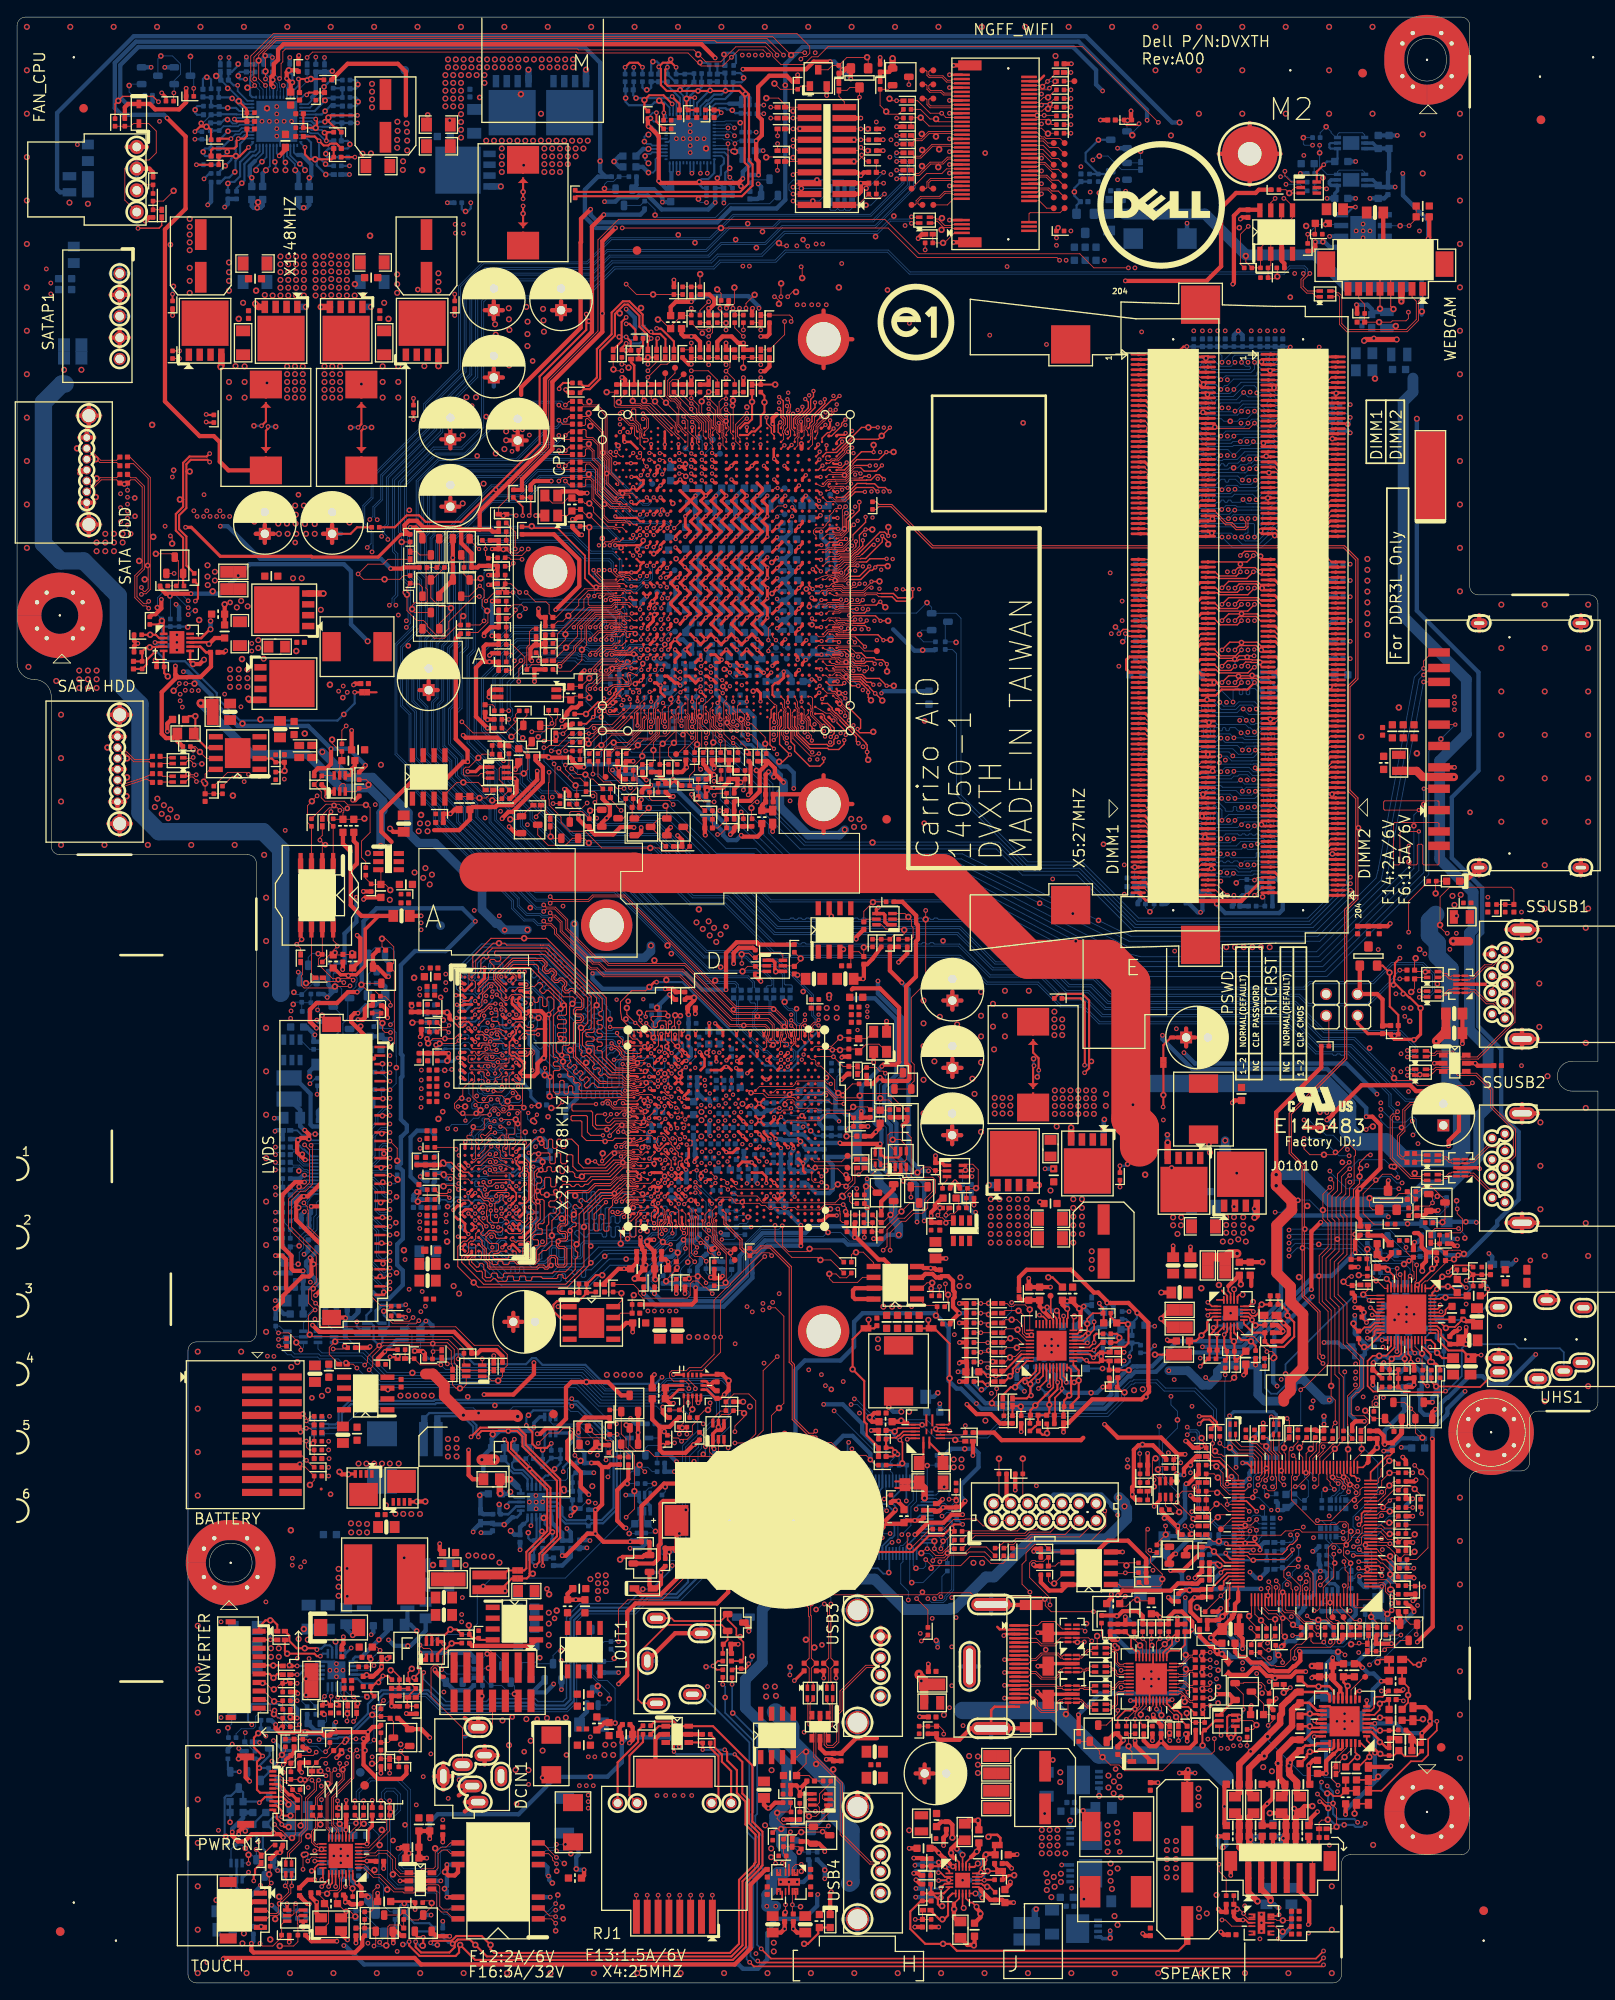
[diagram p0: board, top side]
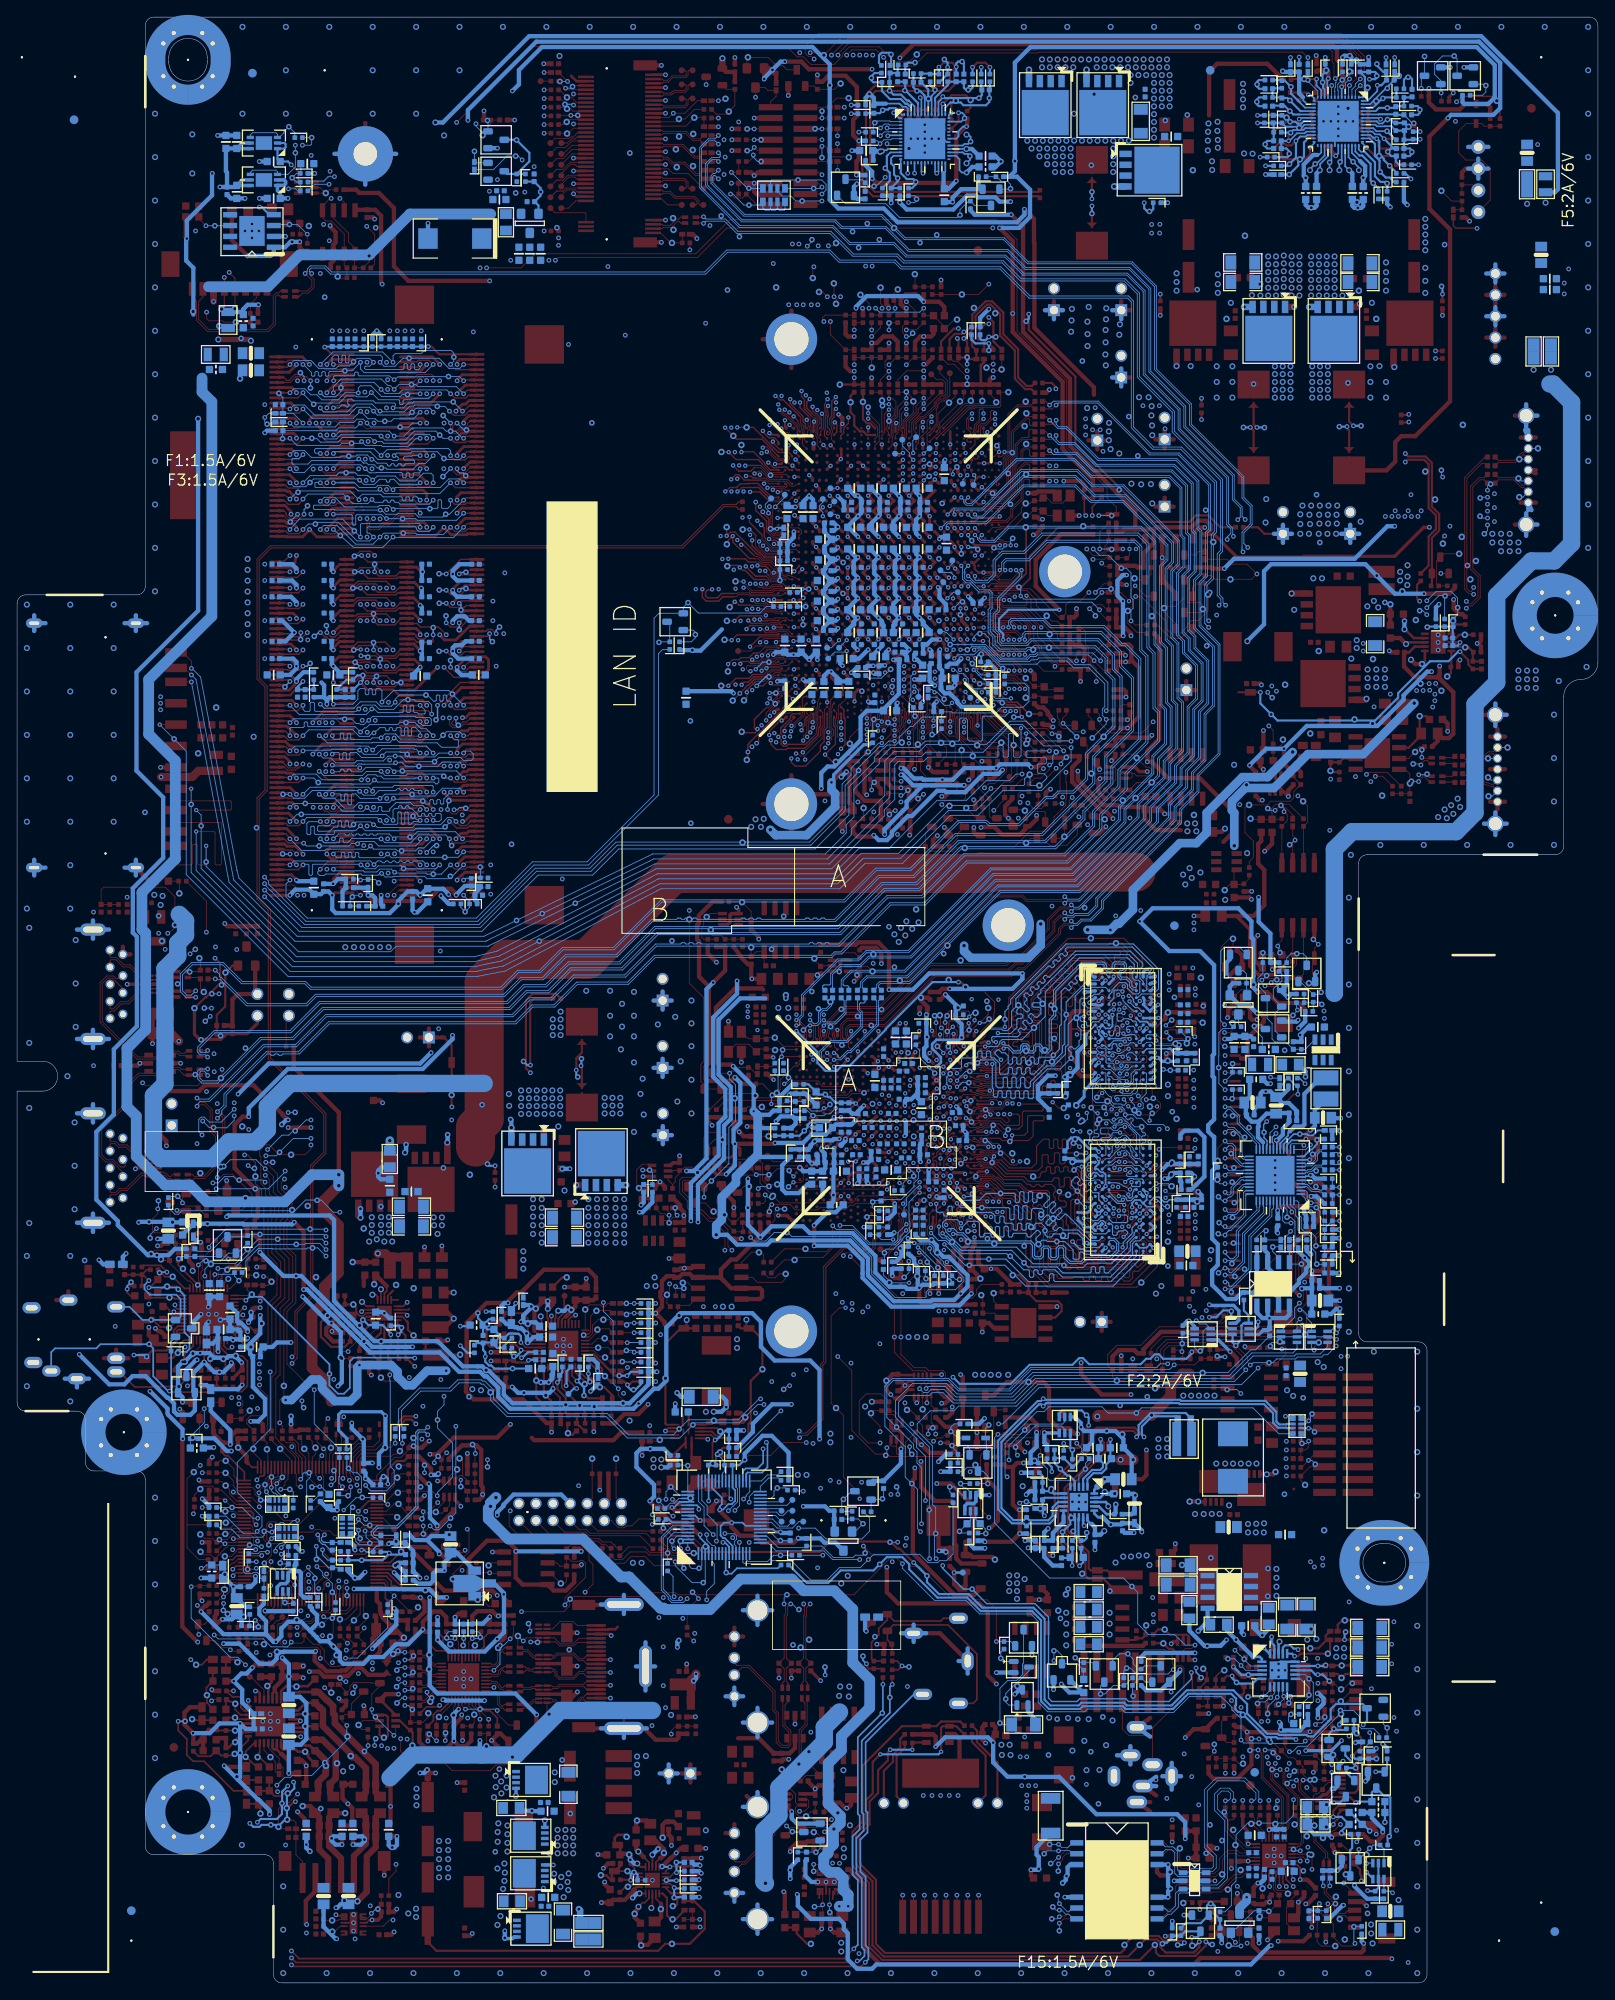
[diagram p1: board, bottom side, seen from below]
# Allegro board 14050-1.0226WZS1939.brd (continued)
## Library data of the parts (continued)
C78 C99 C150 C395 C562 C758-C761 C765-C770 C773 C775-C779 C782 C783 C785 C786 C793-C796 C798-C803 C805-C809 C813-C819 C823-C825 C827 C835 C1491 C1638 C1639 C1698 C1699 C1728 C1736 C1821 C1825 C1829 C1830 C1867 C1960 C4101 C4102 PC1 PC140 PC4803 PC4906 PC4909 PC4910 PC5009 PC5018 PC5204 PC5233 = C402H22: tolerance: 78.10523.5FLDL
C94 C1768 C1807 = C603H36: tolerance: 78.10422.2BL
C95 C105 C227 C315 C852 C1748 C1752 C1833 C1835 C1925 C1927 C6705 = C805H54: tolerance: 78.10623.51L
C104 C112 C144 C146 C154 C155 C283 C292 C296 C450 C592 C1770 C1771 C3367 C6706 PC5001 PC5011 PC5016 PC5247 PC5248 PC5430-PC5432 PC5434 = C805H50: tolerance: 78.10623.51LDL
C110 C192 C193 C208 C260 C1801 PC4602 PC5420 PC5435 = C603H36: tolerance: 78.10522.5BLDL
C126 PC126 = C402H22: tolerance: 78.22034.1FL
C130 = C402H22: tolerance: 78.10422.5FL
C190 PC17 PC18 PC49 PC58 PC4912 PC5012 PC5243 PC5246 PC5427-PC5429 = C603H36: tolerance: 78.10521.2BLDL
C198-C200 C210 = C603H36: tolerance: 78.27324.2BLDL
C222 C239 C243 C263 = C603H36: tolerance: 78.10324.2BL
C223 C224 C228 C229 C865 PC16 PC19 PC60 PC4704 PC4710 PC5411 = C603H36: tolerance: 78.22422.2BLDL
C225 C235 C247 C255 = C603H36: tolerance: 78.68421.5BL
C226 C236 C248 C256 C859 = C603H36: tolerance: 78.10234.1BLDL
C249 C857 C862 = C603H36: tolerance: 78.10424.2BL
C258 C545 C552 C597 PC20 PC51 PC62 PC4302 PC4402-PC4404 PC4703 PC4709 PC4713 PC4806 PC4903 PC4907 PC4908 PC5010 PC5019 PC5234 PC5236 PC5242 PC5403 = C603H35: tolerance: 78.10424.2BLDL
C262 PC9 PC14 = C402H22: tolerance: 78.10324.2FL
C291 C565 C772 C1824 = C805H54: tolerance: 78.22610.51LDL
C326 C330 C356 C1697 C1871 C1876 C1962 C1978 = C402H22: tolerance: 78.18134.1FLDL
C493 C509 C1953 C1956 C6703 = C603H38: tolerance: 78.10610.5BL
C521 C1796 C1797 = C603H36: tolerance: 78.10521.5BL
C524 PC4303 PC4611 PC4626 PC5417 = C402H22: tolerance: 78.22224.2FLDL
C525 C542 C1823 = C402H22: tolerance: 78.10491.4FL
C531 C589 C1756 = C402H22: tolerance: 78.10224.2FL
C548 = C402H22: tolerance: 78.22510.5FL
C752 = C402H22: tolerance: 78.47034.1FL
C753 C1726 C1846 C1958 PC34 PC48 PC5245 = C402H22: tolerance: 78.10423.2FL
C756 C757 C1800 = C402H22: tolerance: 78.12034.1FLDL
C762 = C402H22: tolerance: 78.12134.1FLDL
C812 C822 C1644-C1656 C1673 C1678-C1688 C1934-C1936 C1938 C1947-C1951 PC5205 PC5210-PC5212 = C603H40: tolerance: 78.22610.5BLDL
C836 C6707 C6723 C6725 = C402H20: tolerance: 78.10423.5FL
C839 = C402H22: tolerance: 78.68034.1FL
C872 C1755 = C402H22: tolerance: 78.68321.2FLDL
C1657-C1672 C1689-C1694 C1696 C1703 C1708 C1716 C1741 C1828 C1872-C1875 C1939-C1946 C1952 C1954 C1963-C1965 C1974 C6712 = C402H22: tolerance: 078.22423.05FD
C1700 C1831 = C402H22: tolerance: 78.10520.5FLDL
C1721 C1722 = C402H22: tolerance: 78.15124.2FL
C1773 C1774 = C402H22: tolerance: 78.10034.1FL
C1799 = C402H22: tolerance: 78.15034.1FLDL
C1847 = C402H22: tolerance: 078.82321.02FD
C1848 = C603H38: tolerance: 078.68421.05BD
C1849 = C402H22: tolerance: 78.82321.2FL
C1937 = C402H22: tolerance: 78.18134.1FL
C3131 = C1808H87: tolerance: 078.1013N.014D
C3455 PC4405 PC5217 PC5238 = C402H22: tolerance: 78.10422.5FLDL
C6718-C6720 = C603H36: tolerance: 78.10422.2BLDL
C6724 PC5423 PC5424 = C402H22: tolerance: 78.10322.2FLDL
C6726-C6729 = C402H22: tolerance: 78.4R774.1FLDL
CONVT1 = CI1410M1HRL-NH: tolerance: 20.F2266.010
CPU1 = BGA968M2937H74: tolerance: 071.FUSIN.000U
D1 D31 = SOD323AKH38: tolerance: 83.00355.D1F
D4 D24 = SOT-6H44: tolerance: 75.04223.07C
D7 D20 D34 = SOT23-2D4-312H44: tolerance: 75.00054.I7D
D16 = DO214AAAK-1121H97: tolerance: 83.P6SMB.KAG
D19 = SOT23-2D4-312H48: tolerance: 75.00099.F7D
D21 = SOD523AKH28: tolerance: 83.02015.0AF
D23 = SOT23-2D4-312H44: tolerance: 75.00054.T7D
D32 = D4724AKH44: tolerance: 83.3R010.C8M
D33 = SOD80CH36: tolerance: 83.R5003.C8F
DCIN1 = 2DC3115-000111F: tolerance: 022.10015.0311
DCIN2 = 88314-077N: tolerance: 20.F1498.007
DIMM1 = AS0A621-J4R6-7H-U: tolerance: 62.10024.S21
DIMM2 = AS0A626-J8R6-7H: tolerance: 62.10024.G01
F1 F3 F6 F13 F15 = POLYSW-2114H30: tolerance: 069.50001.0031
F2 F5 F12 F14 = POLYSW-2114H30: tolerance: 069.50003.0001
F16 = FUSE-1608H22: tolerance: 69.43001.441
FANC3 = HF1804H: tolerance: 021.D0086.0104
G5 PG4701-PG4704 PG5401 PG5402 = CON2C-U: tolerance: ZZ.CON2C.XXX
GPU1 = BGA631M23H82: tolerance: 71.SUNM2.M02
H1-H5 = HOLE237R158: tolerance: ZZ.0HOLE.011
H6 H9 = GEN8D5X8R5X4D5-8-F-A: tolerance: ZZ.00PAD.BV1
H7 H11 = GEN315R138-8-F-A-1: tolerance: ZZ.00PAD.BU1
H10 = GEN315R178-8-F-A-1: tolerance: ZZ.00PAD.BR1
HDD1 ODD1 = 15-02070-5A61-A: tolerance: 020.80244.0007
HDMI1 = SKT-HDMI22-150077: tolerance: 062.10012.0121
HDMI2 = LVDFH-02004-TP00: tolerance: 20.F2139.020
HDT1 = ASP-137098-05: tolerance: 20.F1722.020
HS6 = STF256R109H99: tolerance: 34.3NH01.001
L1 = L20125H42: tolerance: 68.00216.121
L2 = L3030-2709H41: tolerance: 68.2R21F.10E
L4 L5 L56 L57 L4102 L4103 = L125100-4P-1H36: tolerance: 68.12105.201
L10 L52 L53 = L603H38: tolerance: 68.00335.141
L15 = L402H22: tolerance: 68.00084.541
L16 L17 L19 = L603H38: tolerance: 68.00230.231
L20 L21 L47-L51 L54 L62 = L402H24: tolerance: 68.00213.031
L31-L34 = L20125H42: tolerance: 68.00216.111
L46 PR4814 PR4815 PR4927 PR4929-PR4933 PR5018-PR5021 PR5032 PR5290 R101 R183 R185 = 0R0805-PAD: tolerance: ZZ.R0805.ZZZ
L55 = L1608-UH38: tolerance: 68.00217.171
L60 = L603H38: tolerance: 68.00335.081
L61 = L8080-6522-1H166: tolerance: 068.33010.1041
L4101 = L402H22: tolerance: 68.00084.I21
LED2 LED3 = LED1608AKH30: tolerance: 83.01608.Q70
LOUT1 = JAC331-0140A8B-9H: tolerance: 22.10277.2M1
LPC1 = HL5507F: tolerance: 21.60964.207
LVDS1 = 50524-0300N-001: tolerance: 020.K0005.0030
MEM1-MEM4 = BGA96D075130H48: tolerance: 72.51G63.R0U
MEMCD1 = 156-5101902601: tolerance: 062.10002.0161
NGFF1 = 2199230-7: tolerance: 62.10043.K51
PC4 PC4911 PC4913 PC5203 = C402H22: tolerance: 78.22034.1FLDL
PC5 = C603H40: tolerance: 78.22422.2BL
PC8 = C402H22: tolerance: 78.33034.1FLDL
PC11 = C402H22: tolerance: 078.39124.02FD
PC13 PC56 PC4610 PC4613 PC4621 PC5415 = C402H22: tolerance: 78.33124.2FLDL
PC15 = C402H22: tolerance: 078.33322.02FD
PC24 PC61 PC63 PC64 PC4701 PC4702 PC4705 PC4707 PC4708 PC4711 PC4801 PC4808 PC4902 PC4904 PC5020-PC5022 PC5209 PC5214 PC5401 PC5402 PC5404 = C1206H71: tolerance: 78.10622.22LDL
PC50 PC52 = C805H58: tolerance: 78.10620.21LDL
PC59 = C603H36: tolerance: 78.10421.2BL
PC65 PC4915 PC4916 PC5017 PC5202 = C603H36: tolerance: 78.15224.2BLDL
PC68 = C402H22: tolerance: 78.27034.1FLDL
PC2127 PC4304 PC5237 = C402H22: tolerance: 78.47124.2FLDL
PC4408 = C805H58: tolerance: 078.10522.021D
PC4426 = C603H36: tolerance: 78.10522.5BL
PC4603 PC4624 PC5419 = C402H22: tolerance: 78.33224.2FLDL
PC4615 PC4617 PC5425 = C402H22: tolerance: 78.68124.2FLDL
PC4623 PC4628 PC5426 = C402H22: tolerance: 78.47321.2FLDL
PC4805 PC4917 PC4918 PC5013 = C402H22: tolerance: 78.18034.1FLDL
PC5014 = C603H36: tolerance: 78.33322.2BLDL
PC5239 = C402H22: tolerance: 78.22124.2FLDL
PC5421 = C603H36: tolerance: 78.22521.5BLDL
PC5422 = C402H22: tolerance: 78.10423.2FLDL
PD4401 = D1608-035030AKH28: tolerance: 83.1R003.N8F
PD4405 = SOD323AKH42: tolerance: 83.04148.D1H
PG3 PG4 = CON2C: tolerance: ZZ.CON2C.XX1
PG4801 PG4901-PG4908 PG5001 PG5211 PG5212 = GAP-CLOSE-PWR-3: tolerance: ZZ.CLOSE.001
PG5205 PG5210 = GAP-CLOSE-PWR: tolerance: ZZ.CON2d.XXX
PL1 PL4701 PL4702 PL5401 = L115100-2H158: tolerance: 68.R3610.10M
PL4301-PL4303 = L402H24: tolerance: 69.80007.021
PL4802 = L686647H119: tolerance: 68.1R51A.10F
PL4903 = L686647-127318H119: tolerance: 68.3R31A.10V
PL4904 PL5202 = L686647H119: tolerance: 68.2R21B.10J
PL5001 = L686647H119: tolerance: 68.R681A.10A
PL5003 = L7066-1830-UH119: tolerance: 68.5R610.10X
PQ4204 = SOT323CBE2D2H44: tolerance: 84.00124.H1K
PQ4205 = SOT323CBE2D2H44: tolerance: 84.00124.K1K
PQ4206 PQ4408 Q1229 = SOT23DGS2D4H44: tolerance: 84.2N702.J31
PQ4406 PQ5006 Q37 Q6701 Q9646 = SOT-363H44: tolerance: 84.2N702.A3F
PQ4409 = SOT23CBE2D4H44: tolerance: 84.T3906.A11
PQ5003 PQ5004 Q1 Q3 Q5 Q47 Q51 Q56 Q64 Q68 Q76 Q103-Q105 Q107 Q1212 Q1249 Q9648 Q9650 = SOT23DGS2D4H48: tolerance: 84.2N702.E31
PQ5005 = SOT-363H44: tolerance: 84.00512.03F
PR1 PR12 PR4455 PR4458 PR4462 PR4631 PR5247-PR5250 PR5261 PR5420 PR5422 PR5464 PR5466 PR5471 PR5476 PR8521 R14 R31 R77 R81 R110 R125 R131 R206 R354 R379 R413 R503 R618 R715 R716 R729 R1154 R1155 R1180 R1184 R1585 R1620-R1622 R1629 R1631 R1710 R1717 R1761 R1763 R1764 R1774 R1810 R1861 R1878 R1920 R1925 R1930 R1931 R1953 R1954 R1980 R1993-R1995 R1999 R2001 R2019 R2021 R2023 R2026 R2067 R2078 R2079 R4230 R6706 R79618 R79647-R79649 R79657 R79658 R79669 R79674 R79691 R79697-R79704 R79709-R79713 R79724 R79725 R80206-R80211 R80213 R80219 R80220 R80223 R80224 R80226 R80227 R80231 R80232 = R402H16: tolerance: 63.R0034.1DL
PR2 PR10 PR14 PR17 PR18 PR23 PR25 PR28-PR30 PR32 PR35 PR37 PR39 PR44 PR101 PR5274 PR5288 R744 R1160 = 0R0402-PAD: tolerance: ZZ.R0402.ZZZ
PR3 PR4 PR7 PR15 PR26 PR31 PR33 PR36 PR38 PR40 PR94 PR96 PR97 PR100 PR102-PR104 PR4210 PR5251 R93 R143 R178 R225 R287 R297 R312 R314 R366 R369 R370 R377 R380 R384 R406 R433 R510 R542 R545 R627 R635 R679 R777 R1179 R1584 R1586 R1604-R1610 R1614-R1616 R1618 R1619 R1628 R1630 R1632 R1650 R1664-R1666 R1704 R1720 R1729 R1730 R1732 R1837 R1863 R1864 R1894 R1917 R1998 R2000 R2002 R79692 R79693 = R402H16: tolerance: 63.10234.1DL
PR5 = R402H16: tolerance: 64.40215.6DL
PR6 = R402H16: tolerance: 64.19115.6DL
PR8 PR9 PR4412 R208 R210 R329 R1776 R1896 = R402H16: tolerance: 64.47025.6DL
PR11 PR24 PR4604 PR4606 PR4633 PR4642 R15 R22 R23 R35 R43 R51 R53 R56 R59 R60 R74 R99 R174 R205 R207 R222 R310 R372-R375 R383 R385 R399 R400 R502 R507 R515 R528 R529 R536 R568 R576 R638 R651 R666 R674 R707 R709 R723 R1165 R1166 R1199 R1203 R1209 R1611-R1613 R1647 R1653 R1654 R1668 R1697 R1698 R1709 R1711-R1714 R1718 R1719 R1739-R1741 R1744-R1748 R1762 R1842 R1857 R1858 R1901-R1904 R1912 R1916 R1981 R1984 R1985 R2017 R2053 R2054 R2080 R79633 R79634 R79639 R79640 R79686 R79708 R80225 = 0R0402-PAD-1: tolerance: ZZ.00PAD.M11
PR13 = R402H16: tolerance: 64.80615.6DL
PR16 = R402H16: tolerance: 64.12115.6DL
PR19 R511 = R402H16: tolerance: 64.12025.6DL
PR20 = R402H16: tolerance: 64.56205.6DL
PR21 = R402H16: tolerance: 64.18715.6DL
PR34 = R402H16: tolerance: 64.82R55.6DL
PR41 = R402H16: tolerance: 64.11025.6DL
PR42 = R402H16: tolerance: 64.26115.6DL
PR43 PR4701 PR4703 PR4812 PR5006 PR5404 PR5475 = R603H22: tolerance: 64.2R205.55L
PR45 = R603H22: tolerance: 64.36515.55L
PR47 PR95 = R402H16: tolerance: 64.1R005.6DL
PR51 = NTC-402H24-U: tolerance: 69.60013.131
PR57 PR62 PR77 PR4450 PR4603 PR4608 PR4615 PR4624 PR4632 PR4917 PR4922 PR5005 PR5206 PR5209 PR5223 PR5282 PR5286 PR5292 PR5295 PR5408 PR5419 PR5429 PR5463 R82 R266 R357 R397 R404 R644 R645 R650 R655 R658 R702 R1760 R1808 R1809 R1823 R1824 R1830 R1832 R1834 R1835 R1841 R79621 R79625 R79705 R79706 R79723 R80216 = R402H16: tolerance: 64.10025.6DL
PR60 = NTC-402H24-U: tolerance: 69.60013.141
PR78 = R402H16: tolerance: 64.69815.6DL
PR79 PR83 PR4612 PR4618 PR4685 PR5283 R5 R220 R284 R570 R571 R584 R585 R1202 R1686 R1735 = R402H14: tolerance: 64.10R05.6DL
PR98 R215 R300 R301 R344-R346 R356 R359 R367 R1182 R1193 R1601 = 0R0603-PAD-1-U: tolerance: ZZ.00PAD.M21
PR99 = R402H16: tolerance: 64.93115.6DL
PR114 PR4806 PR4902 PR4903 PR4911 PR4912 PR5034 PR5294 = R805H24: tolerance: 63.2R231.16L
PR190 PR225 PR4805 PR5431 R12 R41 R42 R124 R134 R137 R138 R152 R154 R159 R160 R163 R165 R175 R184 R213 R221 R281 R289 R294 R307 R308 R313 R316 R317 R334 R341 R350 R351 R364 R381 R382 R481-R483 R514 R517 R523 R524 R530 R531 R533 R582 R636 R637 R668 R675 R680 R682 R683 R717 R764 R774 R1167 R1178 R1183 R1185 R1186 R1188 R1194 R1634 R1635 R1659-R1663 R1670 R1672 R1674 R1679 R1683-R1685 R1687 R1688 R1700-R1703 R1705 R1707 R1716 R1724 R1725 R1728 R1731 R1733 R1734 R1736-R1738 R1749 R1753 R1754 R1757 R1759 R1783 R1785 R1819 R1825 R1826 R1829 R1840 R1845 R1849 R1868 R1870 R1872 R1875-R1877 R1880-R1882 R1885-R1887 R1915 R1926 R1932 R1933 R1935 R1986-R1988 R2010 R2012-R2014 R2055 R2056 R2061 R2062 R2064 R2077 R2091 R6702 R79635 R79637 R79638 R79650-R79654 R79659 R79663 R79664 R79670-R79673 R79676-R79681 R79687-R79690 R79694 R79714 R79727 R80212 R80217 R80218 R80221 R80222 R80230 R80233 = R402H16: tolerance: 63.10334.1DL
PR4214 = R1206H28: tolerance: 63.33232.11L
PR4413 R319 R79628 R79720 R79722 = R402H16: tolerance: 64.10035.6DL
PR4425 PR4426 PR8519 PR8520 = R402H16: tolerance: 63.33234.1DL
PR4427 PR4431 PR4901 PR5273 PR5275 PR5278 PR5281 PR5289 PR5297 R1 R26 R30 R33 R118 R119 R132 R144 R179 R181 R353 R360 R361 R501 R504 R512 R513 R657 R732 R733 R1074 R1079 R1164 R1780 R1781 R1852 R1874 R1914 R2018 R4702 R4706 R6703-R6705 R79662 R79665 R79668 = R402H16: tolerance: 63.10434.1DL
PR4433 R19 R172 R722 R1779 R1919 R79667 = R402H16: tolerance: 63.10534.1DL
PR4451 = R402H16: tolerance: 64.68035.6DL
PR4601 PR4616 PR4621 PR4636 PR4638 PR5413 PR5417 PR5424 R61 R78 R115 R120 R122 R557 R559 R586 R742 R1158 R1162 R1163 R1588 R1633 R1644 R1649 R1657 R1721 R1897 R1989 R2028 R2057-R2060 R2065 R2066 R79661 = R402H16: tolerance: 64.10015.6DL
PR4602 PR5418 = R402H16: tolerance: 64.2R005.6DL
PR4605 PR4629 PR5421 = R402H16: tolerance: 64.61925.6DL
PR4609 PR4614 PR4626 PR5411 = R402H16: tolerance: 64.27425.6DL
PR4610 = R402H16: tolerance: 64.54925.6DL
PR4611 PR4628 PR4643 PR5410 PR5416 = R402H14: tolerance: 63.10134.1DL
PR4613 PR4630 = NTC-402H22-U: tolerance: 69.60037.031
PR4619 PR4640 PR4802 PR5425 = R402H16: tolerance: 64.75025.6DL
PR4620 PR5426 R1126 = R402H16: tolerance: 64.16535.6DL
PR4622 PR4634 PR5407 = R402H16: tolerance: 64.49R95.6DL
PR4623 PR4645 PR5415 R76 = R402H16: tolerance: 64.82015.6DL
PR4625 = R402H16: tolerance: 64.41225.6DL
PR4627 = R402H16: tolerance: 64.28725.6DL
PR4635 PR5412 = R402H16: tolerance: 64.24025.6DL
PR4637 PR4639 PR5414 = NTC-402H22-U: tolerance: 69.60011.081
PR4641 PR5009 = R402H16: tolerance: 64.48725.6DL
PR4644 R79623 R79627 = R402H16: tolerance: 64.30035.6DL
PR4702 PR4704 PR5204 PR5401 = R1206H28: tolerance: 63.2R232.11L
PR4803 R1648 = R402H16: tolerance: 64.11825.6DL
PR4807 R20 R171 R1777 R1778 R1918 R79666 = R402H16: tolerance: 64.47035.6DL
PR4816 PR5268 = R402H16: tolerance: 64.33025.6DL
PR4914 = R402H16: tolerance: 64.66515.6DL
PR4918 PR5469 = R402H16: tolerance: 64.56225.6DL
PR4919 = R402H16: tolerance: 64.68025.6DL
PR4920 PR5468 = R402H16: tolerance: 64.11035.6DL
PR4921 R718 R762 R1658 R1690 R1691 R1727 R1817 R1853 R80215 = R402H16: tolerance: 64.15025.6DL
PR4924 = R402H16: tolerance: 64.24935.6DL
PR4925 = R402H16: tolerance: 64.19135.6DL
PR5002 = R402H16: tolerance: 64.5R105.6DL
PR5003 = R402H16: tolerance: 64.10525.6DL
PR5004 PR5291 PR5296 R276 = 0R0603-PAD: tolerance: ZZ.R0603.ZZZ
PR5007 = R402H16: tolerance: 64.62035.6DL
PR5023 = R402H16: tolerance: 64.40225.6DL
PR5201 R268 R1813 = R402H16: tolerance: 64.20025.6DL
PR5205 = R603H22: tolerance: 63.2R233.15L
PR5269 PR5276 = R3720H40: tolerance: 64.R0105.7FL
PR5270 = R402H16: tolerance: 64.30935.6DL
PR5272 = R402H16: tolerance: 64.49925.6DL
PR5277 = R402H16: tolerance: 64.7R505.6DL
PR5279 = R402H16: tolerance: 64.1R505.6DL
PR5284 = R805H24: tolerance: 64.20R05.16L
PR5285 = R402H16: tolerance: 63.47434.1DL
PR5287 = R402H16: tolerance: 63.33534.1DL
PR5293 = R402H16: tolerance: 64.88715.6DL
PR5298 = R402H16: tolerance: 64.12035.6DL
PR5402 = R402H16: tolerance: 64.34025.6DL
PR5409 = R402H16: tolerance: 64.39025.6DL
PR5423 = NTC-402H24-U: tolerance: 69.60028.041
PR5428 = R402H16: tolerance: 64.36025.6DL
PR5467 = R402H16: tolerance: 64.10235.6DL
PR5470 = R402H16: tolerance: 64.10735.6DL
PR5472 R1205 = R402H16: tolerance: 64.49915.6DL
PR5473 R689 = R402H16: tolerance: 64.64915.6DL
PT1 PT3 PT4 PT5007 = ECAP-100D6D3H355: tolerance: 09.8271N.A4L
PT2 = SE361416H237: tolerance: 79.47612.A0L
PT4701 PT4712 PT4901 PT5405 = SE361414H241: tolerance: 79.47612.3GL
PT4702-PT4704 PT4708 PT4709 PT4801 PT5401-PT5403 = ECAP-100D6D3H375: tolerance: 09.8271V.08L
PT4902 PT4903 = SE331721H237: tolerance: 79.22710.E0L
PU1 PU2 = PPAK-8P-5262H40: tolerance: 84.06552.037
PU3 PU5202 = PPAK-8P-5262H40: tolerance: 84.06508.037
PU4 = SOT23-2D8-312H58: tolerance: 74.02138.03B
PU5 = SOIC8-G3530H63: tolerance: 74.05337.031
PU7 = SOIC8-G3530H63: tolerance: 74.05912.03D
PU4403 PU4405 PU4902-PU4905 = PPAK-8P-3232H36: tolerance: 84.07410.A37
PU4601 PU5407 = LFCSP52J6-G4D8H40: tolerance: 074.81128.0073
PU4702 PU4802 PU5006 PU5207 PU5401 = PPAK-8P-5262H40: tolerance: 84.06520.037
PU4703-PU4706 PU4801 PU5007 PU5402 PU5403 = PPAK-8P-5262H40: tolerance: 084.06510.0037
PU4803 = DFN10G3-G265175H32: tolerance: 74.08237.B73
PU4901 = QFN20-G1D75H32: tolerance: 74.08243.073
PU5001 = QFN20-G1D75H32: tolerance: 74.08207.C73
PU5201 = QFN16J3H24: tolerance: 074.06220.0043
PU5204 PU5205 U110 = SOIC8H69: tolerance: 84.04407.G37
PU5206 = SOIC8-G3530H63: tolerance: 74.05930.B3D
PWRCN1 = 51530-01041-W01: tolerance: 20.K0642.010
Q4 Q7 Q18 Q65 Q95 Q97 Q123 Q1217 Q1226 Q4701 Q6702 = SOT-363H44: tolerance: 75.27002.F7C
Q10 Q22 Q31 Q38 Q45 Q48 Q52 Q100-Q102 Q128 Q1207 Q1208 Q1213 Q1214 Q1241 = SOT23CBE2D4H44: tolerance: 84.T3904.C11
Q12 Q13 Q36 Q63 Q6705 = SOT-363H44: tolerance: 84.M3904.B1F
Q14 = SOT23DGS2D4H35: tolerance: 84.3K329.031
Q24 Q46 Q57 = SOT23-2D4-312H46: tolerance: 75.05125.07D
Q28 Q1209 Q1240 Q1243-Q1245 Q1247 Q1248 = SOT23DGS2D4H44: tolerance: 84.27002.W31
Q43 U2 U6702 = SOIC8H69: tolerance: 84.04468.A37
Q44 Q77 Q1210 Q1211 Q9647 Q9649 = SOT23DGS2D8H50: tolerance: 84.03413.B31
Q50 = SOT-23-10H44: tolerance: 84.03904.L06
Q78 Q79 Q1227 Q1246 = SOT23DGS2D4H44: tolerance: 84.27002.Z31
Q1250 = SOIC8H69: tolerance: 084.04286.0037
Q6703 Q6704 = DFN6F2030-G1619H26: tolerance: 075.02016.007C
R8 = R603H22: tolerance: 63.33133.15L
R10 R378 R775 R1129 R80228 = R402H16: tolerance: 63.82234.1DL
R13 R776 R1195 R80229 = R402H16: tolerance: 64.39225.6DL
R24 R216 R305 R1595 R1784 R2022 R2025 R2029-R2032 R6701 R79655 R79707 = R603H22: tolerance: 63.00000.00L
R27 R79622 = R1206H26: tolerance: 64.R3305.41L
R32 R46 R47 R54 R57 R58 R69 R80 R133 R135 R139 R508 R526 R527 R535 R634 R731 R755 R1699 R1752 R1758 R1782 R1831 R1844 R1860 R1883 R80201 R80202 = R402H16: tolerance: 63.47234.1DL
R37 R79631 = 0R1206-PAD-1: tolerance: ZZ.R1206.ZZ1
R39 R123 R1645 R1646 R1934 = R402H16: tolerance: 63.22034.1DL
R45 R68 R111 R371 R484 R1888 R1889 = R402H14: tolerance: 64.10005.6DL
R65 R1708 R79643-R79646 R79656 = R805H24: tolerance: 63.R0031.16L
R71 R162 R223 R261 R262 R272 R391 R1204 R1669 R1673 R1675 R1676 R1843 R2083 R2084 = R402H16: tolerance: 63.22234.1DL
R73 R368 R639 R643 R656 = R402H16: tolerance: 63.20334.1DL
R107 = R402H16: tolerance: 64.15005.6DL
R113 R322 R407 R1879 = R603H22: tolerance: 64.10045.55L
R121 R1696 = R402H16: tolerance: 64.39R25.6DL
R202 R203 R230 R885 R886 R924 R928 R945 R946 R1905 R1910 R1911 R1921-R1924 = R402H16: tolerance: 64.21015.6DL
R209 R306 R309 R352 R743 R758 R1168-R1171 R1678 R1743 R1755 R1756 R1851 R1884 R79682-R79685 = R402H16: tolerance: 63.33034.1DL
R212 = R402H16: tolerance: 64.68R05.6DL
R267 = R402H16: tolerance: 64.51015.6DL
R299 R320 R870 R899 = R402H16: tolerance: 64.24305.6DL
R302 = R402H16: tolerance: 64.51115.6DL
R347 = R402H16: tolerance: 64.39015.6DL
R355 R365 = R603H22: tolerance: 64.10525.55L
R358 = R402H16: tolerance: 64.56015.6DL
R376 = R603H22: tolerance: 63.10033.15L
R388 R943 R1900 = R402H16: tolerance: 64.84515.6DL
R389 R79726 = R805H24: tolerance: 64.10025.16L
R394 R940 R1603 R1816 = R402H16: tolerance: 64.20015.6DL
R396 R403 R415 R419 = R603H22: tolerance: 64.3R305.55L
R398 R963 R1159 R1892 R1893 R1895 = R402H15: tolerance: 63.10334.L0L
R412 = R402H16: tolerance: 64.24915.6DL
R428 R429 R1891 = R402H16: tolerance: 63.47034.1DL
R495 R1617 R1623 = R402H16: tolerance: 63.30134.1DL
R558 R1161 = R402H16: tolerance: 64.16915.6DL
R617 R79721 = R402H16: tolerance: 63.33334.1DL
R724 R730 R735 R1751 = R603H22: tolerance: 64.16505.55L
R935 = R402H16: tolerance: 64.45315.6DL
R948 R1899 = R402H16: tolerance: 64.47515.6DL
R1200 R1890 R1906-R1909 = R402H16: tolerance: 64.40R25.6DL
R1201 = R402H16: tolerance: 64.12005.6DL
R1206 R1207 = R402H16: tolerance: 64.51R15.6DL
R1210 = R402H16: tolerance: 64.24905.6DL
R1211 = R402H16: tolerance: 64.49905.6DL
R1592 = R603H22: tolerance: 64.36R05.55L
R1593 R1594 R1596 R1598 R2085-R2090 = R402H16: tolerance: 64.47015.6DL
R1671 = R603H22: tolerance: 63.20634.15L
R1677 = R402H16: tolerance: 63.47334.1DL
R1767 R1846 = R603H22: tolerance: 63.15234.15L
R1833 R1838 = R402H16: tolerance: 64.17825.6DL
R1847 = R603H22: tolerance: 64.10035.L0L
R1848 = R603H22: tolerance: 63.10333.15L
R1850 = R603H22: tolerance: 64.56025.55L
R1867 R1869 R1871 R1873 R2004 R2008 R2063 = R402H16: tolerance: 63.20234.1DL
R2003 = R402H16: tolerance: 64.19605.6DL
R2081 = R603H22: tolerance: 64.18005.55L
R2082 = R402H16: tolerance: 64.43015.6DL
R4707 R4708 = R402H16: tolerance: 64.11015.6DL
R79612 = R603H22: tolerance: 64.75R05.55L
R79619 = R805H24: tolerance: 63.1R031.16L
R79630 = R805H24: tolerance: 63.20131.16L
R79675 = R402H16: tolerance: 063.10434.01DV
RJ1 = 23-01120-2A03-A: tolerance: 062.10032.0041
RN7 RN10 = ARES8-CN24-MUH20: tolerance: 66.10336.08L
RN8 RN9 = ARES2H18: tolerance: 66.10336.04L
RN12 = SMD-ARES8-1H26: tolerance: 66.10236.A8L
RN13 RN4301 = ARES8-CN24-UH20: tolerance: 66.33036.A8L
RN16 = ARES2H16: tolerance: 66.22236.04L
RT1-RT3 = NTC-402H22-U: tolerance: 69.60011.121
RV1 = TVS5436-1121H105: tolerance: 069.A0007.0001
SATAP1 = CI2505P1H00-LF-U: tolerance: 021.60197.0105
SPI1 = SOIC8-1H86: tolerance: 72.25640.D01
SPK1 = A1501WV0-6PS-5E: tolerance: 21.D0278.106
SPR1 = SPR10637H367: tolerance: 34.39S07.003
SRCON1 = SKT-SOIC8-092117H235: tolerance: 62.10089.001
SSUSB1 SSUSB2 = SKT-USB11-138165-1: tolerance: 022.10005.0391
TC1 = CT7343H75: tolerance: 77.23371.13L
TC7 TC8 = ECAP-100D6D3H237: tolerance: 09.1071D.A5L
TC21 = ECAP-100D6D3H355: tolerance: 09.8271N.A5L
TOUCH1 = 3703K-Q05N-11L: tolerance: 020.F0146.0005
TP6 TP8 TP9 TP24-TP26 TP28 TP37-TP39 TP62-TP84 TP149 TP150 TP155 TP158 TP159 TP163-TP165 TP174-TP184 TP186-TP190 TP192-TP196 TP198 TP199 TP203 TP204 TP208 TP210-TP215 TP4124-TP4130 = TPAD28: tolerance: ZZ.PAD28.XXX
TR1 TR3 TR4 TR10 TR14 = L125100-4P-1H28: tolerance: 68.01012.20B
TR9 TR12 = L125100-4P-1H37: tolerance: 68.01012.201
TR16-TR19 = L125100-4P-1H28: tolerance: 68.10129.201
U1 U42 U105 = SOT-6-1H50: tolerance: 84.06402.B3D
U3 U5 U31 U116 U117 = DFN10G2510H26: tolerance: 75.01045.073
U6 = QFN48J6-G465H40: tolerance: 71.03661.003
U7 = SOIC8H69: tolerance: 72.25106.001
U9 = QFN40-G3D5H32: tolerance: 74.62882.A73
U10-U12 = SOT-6H58: tolerance: 75.09904.07C
U16 = QFN32J4-G2D85H36: tolerance: 71.08111.U03
U21 = QFN32-G3D55H40: tolerance: 74.03131.013
U25 = SOIC8H69: tolerance: 72.24C64.R01
U26 = QFN48J6-G4D55H40: tolerance: 71.02136.003
U49 = SOIC8H69: tolerance: 72.25010.R01
U52 U54 = SON14J3020-G2610H34: tolerance: 74.22966.093
U55 = QFN20G3D5-G2D15H40: tolerance: 74.24727.A73
U109 = LQFP128H63: tolerance: 071.08739.000G
U118 = QFN40J5-G3D65H32: tolerance: 071.08407.0003
U119 = SOT-89-4541-3PH63: tolerance: 074.01117.0038
U120 = QFN20-G2D1H32: tolerance: 074.00554.0073
U178 = SOIC8H69: tolerance: 074.03702.0021
U4101 = LQFP64H63: tolerance: 071.00948.000G
U6701 = LGA16G3-1H40: tolerance: 074.01010.00B3
UHS1 = 2SJ3082-038111F: tolerance: 022.10002.0881
UR5-UR7 = R402H16: tolerance: 64.33005.6DL
USB3 USB4 = SKT-USB6-135063: tolerance: 022.10005.01E1
WEBCM1 = A1251WR0-8PS-5E: tolerance: 20.F1245.008
X1 = OSC-3225-4P-4H36: tolerance: 82.30026.281
X2 = SMD49-6914-0403H56: tolerance: 82.30001.G11
X4 = OSC-3225-4P-4H36: tolerance: 82.30020.G71
X5 = OSC-3225-4P-4H30: tolerance: 82.30034.641
XF1 XF2 = XFORM12A127097H91: tolerance: 68.68167.30D

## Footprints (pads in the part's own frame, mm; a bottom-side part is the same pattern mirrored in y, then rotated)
0R0402-PAD
  custom 0.14x0.14 smd: 1(0,0.445) 2(0,-0.445)
0R0402-PAD-1
  custom 0.14x0.14 smd: 1(0,0.445) 2(0,-0.445)
0R0603-PAD
  custom 0.216x0.216 smd: 1(0,0.851) 2(0,-0.673)
0R0603-PAD-1-U
  custom 0.216x0.216 smd: 1(0,0.762) 2(0,-0.762)
0R0805-PAD
  rect 1.397x1.562 smd: 1(0,0.965)
  rect 1.397x1.569 smd: 2(0,-0.965)
0R1206-PAD-1
  rect 1.651x2.057 smd: 1(0,1.397) 2(0,-1.397)
2DC3115-000111F
  oval 1.422x2.413 hole 0.711x1.702: 1(-1.1,1.46)
  oval 1.473x2.413 hole 0.762x1.702: 2(2.5,0) 5(4.375,0.7) 7(-4.375,0.7)
  oval 1.524x2.413 hole 0.813x1.702: 3(0,-1.13)
  oval 2.413x1.473 hole 1.702x0.762: 4(1.35,3.375) 6(1.35,-3.375)
2SJ3082-038111F
  round 0.254 hole 1.27 unplated: (0,0) (0,-6)
  oval 1.321x2.134 hole 0.61x1.422: 1(3.8,3.1) 2(-3.7,-4.5) 3(3.7,-6.8) 4(-2.7,-6.6) 5(-2.2,3.1) 6(-3.8,3.1) MS1(-4.6,-1.5) MS2(4.6,-2.5)
15-02070-5A61-A
  round 1.041 hole 0.762: 1(3.81,-0.25) 2(2.54,-0.25) 3(1.27,-0.25) 4(0,-0.25) 5(-1.27,-0.25) 6(-2.54,-0.25) 7(-3.81,-0.25)
  round 1.93 hole 1.524: 8(6.37,0) 9(-6.37,0)
23-01120-2A03-A
  rect 0.813x3.988 smd: 1(-4.445,13.3) 2(-3.175,13.3) 3(-1.905,13.3) 4(-0.635,13.3) 5(0.635,13.3) 6(1.905,13.3) 7(3.175,13.3) 8(4.445,13.3)
  round 1.321 hole 0.914: 9(-6.645,0) 10(-4.355,0) 11(4.355,0) 12(6.645,0)
  rect 8.992x3.404 smd: 13(0,-3.5)
156-5101902601
  round 0.254 hole 1.702 unplated: (-12.65,0) (12.65,0)
  rect 0.991x2.54 smd: 1(-7.57,8.245) 2(-5.07,8.245) 3(-2.57,8.245) 4(-0.07,8.245) 5(2.43,8.245) 6(4.93,8.245) 7(7.43,8.245) 8(9.055,8.245) 9(-10.07,8.245) 10(10.875,8.245) 11(-11.755,8.245)
  oval 1.118x1.93 hole 0.406x1.219: 12(-14.3,3.55) 13(14.3,3.55) 14(-14.3,-8.35) 15(14.3,-8.35)
3703K-Q05N-11L
  rect 0.61x1.549 smd: 1(-2,3.775) 2(-1,3.775) 3(0,3.775) 4(1,3.775) 5(2,3.775)
  rect 1.194x2.007 smd: 6(-3.3,0) 7(3.3,0)
50290-0100N-001
  rect 0.838x3.556 smd: 1A(-6.75,-3.9) 2A(-5.25,-3.9) 3A(-3.75,-3.9) 4A(-2.25,-3.9) 5A(-0.75,-3.9) 6A(0.75,-3.9) 7A(2.25,-3.9) 8A(3.75,-3.9) 9A(5.25,-3.9) 10A(6.75,-3.9)
  rect 0.838x2.642 smd: 1B(-6.75,0) 2B(-5.25,0) 3B(-3.75,0) 4B(-2.25,0) 5B(-0.75,0) 6B(0.75,0) 7B(2.25,0) 8B(3.75,0) 9B(5.25,0) 10B(6.75,0)
50524-0300N-001
  rect 0.305x1.295 smd: 1(-14.5,5.65) 2(-13.5,5.65) 3(-12.5,5.65) 4(-11.5,5.65) 5(-10.5,5.65) 6(-9.5,5.65) 7(-8.5,5.65) 8(-7.5,5.65) 9(-6.5,5.65) 10(-5.5,5.65) 11(-4.5,5.65) 12(-3.5,5.65) 13(-2.5,5.65) 14(-1.5,5.65) 15(-0.5,5.65) 16(0.5,5.65) 17(1.5,5.65) 18(2.5,5.65) 19(3.5,5.65) 20(4.5,5.65) 21(5.5,5.65) 22(6.5,5.65) 23(7.5,5.65) 24(8.5,5.65) 25(9.5,5.65) 26(10.5,5.65) 27(11.5,5.65) 28(12.5,5.65) 29(13.5,5.65) 30(14.5,5.65)
  rect 1.803x2.21 smd: 31(-17.15,0) 32(17.15,0)
51530-01041-W01
  rect 0.305x0.838 smd: 1(-2.25,3.175) 2(-1.75,3.175) 3(-1.25,3.175) 4(-0.75,3.175) 5(-0.25,3.175) 6(0.25,3.175) 7(0.75,3.175) 8(1.25,3.175) 9(1.75,3.175) 10(2.25,3.175)
  rect 0.813x2.007 smd: 11(-3.95,0) 12(3.95,0)
88314-077N
  rect 0.838x3.556 smd: 1(-4.5,-3.225) 2(-3,-3.225) 3(-1.5,-3.225) 4(0,-3.225) 5(1.5,-3.225) 6(3,-3.225) 7(4.5,-3.225)
  rect 0.838x2.642 smd: 8(-4.5,0.675) 9(-3,0.675) 10(-1.5,0.675) 11(0,0.675) 12(1.5,0.675) 13(3,0.675) 14(4.5,0.675)
2199230-7
  round 0.254 hole 1.6 unplated: (-10,0)
  round 0.254 hole 1.118 unplated: (10,0)
  rect 0.305x1.854 smd: 1(9.25,-5.423) 2(9,2.423) 3(8.75,-5.423) 4(8.5,2.423) 5(8.25,-5.423) 6(8,2.423) 7(7.75,-5.423) 16(5.5,2.423) 17(5.25,-5.423) 18(5,2.423) 19(4.75,-5.423) 20(4.5,2.423) 21(4.25,-5.423) 22(4,2.423) 23(3.75,-5.423) 24(3.5,2.423) 25(3.25,-5.423) 26(3,2.423) 27(2.75,-5.423) 28(2.5,2.423) 29(2.25,-5.423) 30(2,2.423) 31(1.75,-5.423) 32(1.5,2.423) 33(1.25,-5.423) 34(1,2.423) 35(0.75,-5.423) 36(0.5,2.423) 37(0.25,-5.423) 38(0,2.423) 39(-0.25,-5.423) 40(-0.5,2.423) 41(-0.75,-5.423) 42(-1,2.423) 43(-1.25,-5.423) 44(-1.5,2.423) 45(-1.75,-5.423) 46(-2,2.423) 47(-2.25,-5.423) 48(-2.5,2.423) 49(-2.75,-5.423) 50(-3,2.423) 51(-3.25,-5.423) 52(-3.5,2.423) 53(-3.75,-5.423) 54(-4,2.423) 55(-4.25,-5.423) 56(-4.5,2.423) 57(-4.75,-5.423) 58(-5,2.423) 59(-5.25,-5.423) 60(-5.5,2.423) 61(-5.75,-5.423) 62(-6,2.423) 63(-6.25,-5.423) 64(-6.5,2.423) 65(-6.75,-5.423) 66(-7,2.423) 67(-7.25,-5.423) 68(-7.5,2.423) 69(-7.75,-5.423) 70(-8,2.423) 71(-8.25,-5.423) 72(-8.5,2.423) 73(-8.75,-5.423) 74(-9,2.423) 75(-9.25,-5.423)
  rect 1.194x2.743 smd: 76(10.35,-4.5) 77(-10.35,-4.5)
A1251WR0-8PS-5E
  rect 0.813x1.6 smd: 1(-4.375,2.9) 2(-3.125,2.9) 3(-1.875,2.9) 4(-0.625,2.9) 5(0.625,2.9) 6(1.875,2.9) 7(3.125,2.9) 8(4.375,2.9)
  rect 2.108x2.997 smd: 9(-6.925,0) 10(6.925,0)
A1501WV0-6PS-5E
  rect 0.711x3.505 smd: 1(3.75,2) 2(2.25,2) 3(0.75,2) 4(-0.75,2) 5(-2.25,2) 6(-3.75,2)
  rect 1.499x2.311 smd: 7(5.8,0) 8(-5.8,0)
A2541WV0-1EX2PA-6T
  round 1.397 hole 0.991: 1(-1.27,0) 2(1.27,0)
AAA-BAT-034-K01
  round 0.254 hole 1.067 unplated: (-7.5,0)
  round 0.254 hole 1.372 unplated: (0,0)
  rect 2.794x3.607 smd: 1(6.2,0)
  rect 2.997x2.591 smd: 2(-15.1,0)
AFTE14P-75
  round 0.356 smd: 1(0,0)
ARES2H16
  rect 0.356x0.66 smd: 1(-0.325,-0.599) 2(0.325,-0.599) 3(0.325,0.599) 4(-0.325,0.599)
ARES2H18
  rect 0.356x0.66 smd: 1(-0.325,-0.599) 2(0.325,-0.599) 3(0.325,0.599) 4(-0.325,0.599)
ARES8-CN24-MUH20
  rect 0.61x0.66 smd: 1(-0.9,-0.486) 4(0.9,-0.486) 5(0.9,0.486) 8(-0.9,0.486)
  rect 0.305x0.66 smd: 2(-0.25,-0.486) 3(0.25,-0.486) 6(0.25,0.486) 7(-0.25,0.486)
ARES8-CN24-UH20
  rect 0.61x0.66 smd: 1(-0.9,-0.486) 4(0.9,-0.486) 5(0.9,0.486) 8(-0.9,0.486)
  rect 0.305x0.66 smd: 2(-0.25,-0.486) 3(0.25,-0.486) 6(0.25,0.486) 7(-0.25,0.486)
AS0A621-J4R6-7H-U
  round 0.254 hole 1.118 unplated: (-33.4,0)
  round 0.254 hole 1.6 unplated: (33.4,0)
  custom 0.114x0.114 smd: 1(31.65,4.1) 2(31.35,-4.1) 3(31.05,4.1) 4(30.751,-4.1) 5(30.45,4.1) 6(30.15,-4.1) 7(29.85,4.1) 8(29.55,-4.1) 9(29.251,4.1) 10(28.95,-4.1) 11(28.65,4.1) 12(28.35,-4.1) 13(28.051,4.1) 14(27.751,-4.1) 15(27.45,4.1) 16(27.15,-4.1) 17(26.851,4.1) 18(26.551,-4.1) 19(26.25,4.1) 20(25.95,-4.1) 21(25.65,4.1) 22(25.35,-4.1) 23(25.051,4.1) 24(24.75,-4.1) 25(24.45,4.1) 26(24.15,-4.1) 27(23.851,4.1) 28(23.55,-4.1) 29(23.25,4.1) 30(22.95,-4.1) 31(22.651,4.1) 32(22.351,-4.1) 33(22.05,4.1) 34(21.75,-4.1) 35(21.451,4.1) 36(21.151,-4.1) 37(20.85,4.1) 38(20.55,-4.1) 39(20.25,4.1) 40(19.95,-4.1) 41(19.65,4.1) 42(19.35,-4.1) 43(19.049,4.1) 44(18.749,-4.1) 45(18.45,4.1) 46(18.15,-4.1) 47(17.85,4.1) 48(17.549,-4.1) 49(17.25,4.1) 50(16.95,-4.1) 51(16.65,4.1) 52(16.349,-4.1) 53(16.049,4.1) 54(15.75,-4.1) 55(15.45,4.1) 56(15.15,-4.1) 57(14.849,4.1) 58(14.549,-4.1) 59(14.25,4.1) 60(13.95,-4.1) 61(13.649,4.1) 62(13.349,-4.1) 63(13.05,4.1) 64(12.75,-4.1) 65(12.45,4.1) 66(12.149,-4.1) 67(11.85,4.1) 68(11.55,-4.1) 69(11.25,4.1) 70(10.95,-4.1) 71(10.649,4.1) 72(10.349,-4.1) 73(7.65,4.1) 74(7.35,-4.1) 75(7.049,4.1) 76(6.749,-4.1) 77(6.45,4.1) 78(6.15,-4.1) 79(5.85,4.1) 80(5.549,-4.1) 81(5.25,4.1) 82(4.95,-4.1) 83(4.65,4.1) 84(4.349,-4.1) 85(4.05,4.1) 86(3.75,-4.1) 87(3.45,4.1) 88(3.15,-4.1) 89(2.849,4.1) 90(2.549,-4.1) 91(2.25,4.1) 92(1.95,-4.1) 93(1.649,4.1) 94(1.349,-4.1) 95(1.05,4.1) 96(0.75,-4.1) 97(0.45,4.1) 98(0.149,-4.1) 99(-0.15,4.1) 100(-0.45,-4.1) 101(-0.75,4.1) 102(-1.051,-4.1) 103(-1.351,4.1) 104(-1.65,-4.1) 105(-1.95,4.1) 106(-2.25,-4.1) 107(-2.551,4.1) 108(-2.851,-4.1) 109(-3.15,4.1) 110(-3.45,-4.1) 111(-3.751,4.1) 112(-4.051,-4.1) 113(-4.35,4.1) 114(-4.65,-4.1) 115(-4.95,4.1) 116(-5.251,-4.1) 117(-5.55,4.1) 118(-5.85,-4.1) 119(-6.15,4.1) 120(-6.451,-4.1) 121(-6.751,4.1) 122(-7.051,-4.1) 123(-7.35,4.1) 124(-7.65,-4.1) 125(-7.951,4.1) 126(-8.251,-4.1) 127(-8.55,4.1) 128(-8.85,-4.1) 129(-9.15,4.1) 130(-9.451,-4.1) 131(-9.75,4.1) 132(-10.05,-4.1) 133(-10.35,4.1) 134(-10.651,-4.1) 135(-10.95,4.1) 136(-11.25,-4.1) 137(-11.55,4.1) 138(-11.85,-4.1) 139(-12.151,4.1) 140(-12.451,-4.1) 141(-12.75,4.1) 142(-13.05,-4.1) 143(-13.351,4.1) 144(-13.651,-4.1) 145(-13.95,4.1) 146(-14.25,-4.1) 147(-14.55,4.1) 148(-14.851,-4.1) 149(-15.15,4.1) 150(-15.45,-4.1) 151(-15.75,4.1) 152(-16.051,-4.1) 153(-16.35,4.1) 154(-16.65,-4.1) 155(-16.95,4.1) 156(-17.25,-4.1) 157(-17.551,4.1) 158(-17.851,-4.1) 159(-18.15,4.1) 160(-18.45,-4.1) 161(-18.751,4.1) 162(-19.051,-4.1) 163(-19.35,4.1) 164(-19.65,-4.1) 165(-19.95,4.1) 166(-20.251,-4.1) 167(-20.55,4.1) 168(-20.85,-4.1) 169(-21.15,4.1) 170(-21.451,-4.1) 171(-21.751,4.1) 172(-22.051,-4.1) 173(-22.35,4.1) 174(-22.65,-4.1) 175(-22.951,4.1) 176(-23.251,-4.1) 177(-23.55,4.1) 178(-23.85,-4.1) 179(-24.151,4.1) 180(-24.451,-4.1) 181(-24.75,4.1) 182(-25.05,-4.1) 183(-25.35,4.1) 184(-25.651,-4.1) 185(-25.95,4.1) 186(-26.25,-4.1) 187(-26.55,4.1) 188(-26.851,-4.1) 189(-27.151,4.1) 190(-27.451,-4.1) 191(-27.75,4.1) 192(-28.05,-4.1) 193(-28.351,4.1) 194(-28.651,-4.1) 195(-28.95,4.1) 196(-29.25,-4.1) 197(-29.55,4.1) 198(-29.851,-4.1) 199(-30.15,4.1) 200(-30.45,-4.1) 201(-30.75,4.1) 202(-31.05,-4.1) 203(-31.349,4.1) 204(-31.649,-4.1)
  rect 4.496x4.597 smd: 205(32.8,12) 206(-32.8,12)
AS0A626-J8R6-7H
  round 0.254 hole 1.067 unplated: (-33.4,0)
  round 0.254 hole 1.6 unplated: (33.4,0)
  custom 0.114x0.114 smd: 1(31.65,4.1) 2(31.35,-4.1) 3(31.05,4.1) 4(30.75,-4.1) 5(30.45,4.1) 6(30.15,-4.1) 7(29.85,4.1) 8(29.55,-4.1) 9(29.25,4.1) 10(28.95,-4.1) 11(28.65,4.1) 12(28.35,-4.1) 13(28.05,4.1) 14(27.75,-4.1) 15(27.45,4.1) 16(27.15,-4.1) 17(26.85,4.1) 18(26.55,-4.1) 19(26.25,4.1) 20(25.95,-4.1) 21(25.65,4.1) 22(25.35,-4.1) 23(25.05,4.1) 24(24.75,-4.1) 25(24.45,4.1) 26(24.15,-4.1) 27(23.85,4.1) 28(23.55,-4.1) 29(23.25,4.1) 30(22.95,-4.1) 31(22.65,4.1) 32(22.35,-4.1) 33(22.05,4.1) 34(21.75,-4.1) 35(21.45,4.1) 36(21.15,-4.1) 37(20.85,4.1) 38(20.55,-4.1) 39(20.25,4.1) 40(19.95,-4.1) 41(19.65,4.1) 42(19.35,-4.1) 43(19.05,4.1) 44(18.75,-4.1) 45(18.45,4.1) 46(18.15,-4.1) 47(17.85,4.1) 48(17.55,-4.1) 49(17.25,4.1) 50(16.95,-4.1) 51(16.65,4.1) 52(16.35,-4.1) 53(16.05,4.1) 54(15.75,-4.1) 55(15.45,4.1) 56(15.15,-4.1) 57(14.85,4.1) 58(14.55,-4.1) 59(14.25,4.1) 60(13.95,-4.1) 61(13.65,4.1) 62(13.35,-4.1) 63(13.05,4.1) 64(12.75,-4.1) 65(12.45,4.1) 66(12.15,-4.1) 67(11.85,4.1) 68(11.55,-4.1) 69(11.25,4.1) 70(10.95,-4.1) 71(10.65,4.1) 72(10.35,-4.1) 73(7.65,4.1) 74(7.35,-4.1) 75(7.05,4.1) 76(6.75,-4.1) 77(6.45,4.1) 78(6.15,-4.1) 79(5.85,4.1) 80(5.55,-4.1) 81(5.25,4.1) 82(4.95,-4.1) 83(4.65,4.1) 84(4.35,-4.1) 85(4.05,4.1) 86(3.75,-4.1) 87(3.45,4.1) 88(3.15,-4.1) 89(2.85,4.1) 90(2.55,-4.1) 91(2.25,4.1) 92(1.95,-4.1) 93(1.65,4.1) 94(1.35,-4.1) 95(1.05,4.1) 96(0.75,-4.1) 97(0.45,4.1) 98(0.15,-4.1) 99(-0.15,4.1) 100(-0.45,-4.1) 101(-0.75,4.1) 102(-1.05,-4.1) 103(-1.35,4.1) 104(-1.65,-4.1) 105(-1.95,4.1) 106(-2.25,-4.1) 107(-2.55,4.1) 108(-2.85,-4.1) 109(-3.15,4.1) 110(-3.45,-4.1) 111(-3.75,4.1) 112(-4.05,-4.1) 113(-4.35,4.1) 114(-4.65,-4.1) 115(-4.95,4.1) 116(-5.25,-4.1) 117(-5.55,4.1) 118(-5.85,-4.1) 119(-6.15,4.1) 120(-6.45,-4.1) 121(-6.75,4.1) 122(-7.05,-4.1) 123(-7.35,4.1) 124(-7.65,-4.1) 125(-7.95,4.1) 126(-8.25,-4.1) 127(-8.55,4.1) 128(-8.85,-4.1) 129(-9.15,4.1) 130(-9.45,-4.1) 131(-9.75,4.1) 132(-10.05,-4.1) 133(-10.35,4.1) 134(-10.65,-4.1) 135(-10.95,4.1) 136(-11.25,-4.1) 137(-11.55,4.1) 138(-11.85,-4.1) 139(-12.15,4.1) 140(-12.45,-4.1) 141(-12.75,4.1) 142(-13.05,-4.1) 143(-13.35,4.1) 144(-13.65,-4.1) 145(-13.95,4.1) 146(-14.25,-4.1) 147(-14.55,4.1) 148(-14.85,-4.1) 149(-15.15,4.1) 150(-15.45,-4.1) 151(-15.75,4.1) 152(-16.05,-4.1) 153(-16.35,4.1) 154(-16.65,-4.1) 155(-16.95,4.1) 156(-17.25,-4.1) 157(-17.55,4.1) 158(-17.85,-4.1) 159(-18.15,4.1) 160(-18.45,-4.1) 161(-18.75,4.1) 162(-19.05,-4.1) 163(-19.35,4.1) 164(-19.65,-4.1) 165(-19.95,4.1) 166(-20.25,-4.1) 167(-20.55,4.1) 168(-20.85,-4.1) 169(-21.15,4.1) 170(-21.45,-4.1) 171(-21.75,4.1) 172(-22.05,-4.1) 173(-22.35,4.1) 174(-22.65,-4.1) 175(-22.95,4.1) 176(-23.25,-4.1) 177(-23.55,4.1) 178(-23.85,-4.1) 179(-24.15,4.1) 180(-24.45,-4.1) 181(-24.75,4.1) 182(-25.05,-4.1) 183(-25.35,4.1) 184(-25.65,-4.1) 185(-25.95,4.1) 186(-26.25,-4.1) 187(-26.55,4.1) 188(-26.85,-4.1) 189(-27.15,4.1) 190(-27.45,-4.1) 191(-27.75,4.1) 192(-28.05,-4.1) 193(-28.35,4.1) 194(-28.65,-4.1) 195(-28.95,4.1) 196(-29.25,-4.1) 197(-29.55,4.1) 198(-29.85,-4.1) 199(-30.15,4.1) 200(-30.45,-4.1) 201(-30.75,4.1) 202(-31.05,-4.1) 203(-31.35,4.1) 204(-31.65,-4.1)
  rect 4.496x4.597 smd: 205(-37.45,12) 206(37.45,12)
ASP-137098-05
  rect 0.737x2.794 smd: 1(-5.715,-2.035) 2(-5.715,2.035) 3(-4.445,-2.035) 4(-4.445,2.035) 5(-3.175,-2.035) 6(-3.175,2.035) 7(-1.905,-2.035) 8(-1.905,2.035) 9(-0.635,-2.035) 10(-0.635,2.035) 11(0.635,-2.035) 12(0.635,2.035) 13(1.905,-2.035) 14(1.905,2.035) 15(3.175,-2.035) 16(3.175,2.035) 17(4.445,-2.035) 18(4.445,2.035) 19(5.715,-2.035) 20(5.715,2.035)
BGA96D075130H48
  round 0.356 smd: A1(-3.2,6) A2(-2.4,6) A3(-1.6,6) A7(1.6,6) A8(2.4,6) A9(3.2,6) B1(-3.2,5.2) B2(-2.4,5.2) B3(-1.6,5.2) B7(1.6,5.2) B8(2.4,5.2) B9(3.2,5.2) C1(-3.2,4.4) C2(-2.4,4.4) C3(-1.6,4.4) C7(1.6,4.4) C8(2.4,4.4) C9(3.2,4.4) D1(-3.2,3.6) D2(-2.4,3.6) D3(-1.6,3.6) D7(1.6,3.6) D8(2.4,3.6) D9(3.2,3.6) E1(-3.2,2.8) E2(-2.4,2.8) E3(-1.6,2.8) E7(1.6,2.8) E8(2.4,2.8) E9(3.2,2.8) F1(-3.2,2) F2(-2.4,2) F3(-1.6,2) F7(1.6,2) F8(2.4,2) F9(3.2,2) G1(-3.2,1.2) G2(-2.4,1.2) G3(-1.6,1.2) G7(1.6,1.2) G8(2.4,1.2) G9(3.2,1.2) H1(-3.2,0.4) H2(-2.4,0.4) H3(-1.6,0.4) H7(1.6,0.4) H8(2.4,0.4) H9(3.2,0.4) J1(-3.2,-0.4) J2(-2.4,-0.4) J3(-1.6,-0.4) J7(1.6,-0.4) J8(2.4,-0.4) J9(3.2,-0.4) K1(-3.2,-1.2) K2(-2.4,-1.2) K3(-1.6,-1.2) K7(1.6,-1.2) K8(2.4,-1.2) K9(3.2,-1.2) L1(-3.2,-2) L2(-2.4,-2) L3(-1.6,-2) L7(1.6,-2) L8(2.4,-2) L9(3.2,-2) M1(-3.2,-2.8) M2(-2.4,-2.8) M3(-1.6,-2.8) M7(1.6,-2.8) M8(2.4,-2.8) M9(3.2,-2.8) N1(-3.2,-3.6) N2(-2.4,-3.6) N3(-1.6,-3.6) N7(1.6,-3.6) N8(2.4,-3.6) N9(3.2,-3.6) P1(-3.2,-4.4) P2(-2.4,-4.4) P3(-1.6,-4.4) P7(1.6,-4.4) P8(2.4,-4.4) P9(3.2,-4.4) R1(-3.2,-5.2) R2(-2.4,-5.2) R3(-1.6,-5.2) R7(1.6,-5.2) R8(2.4,-5.2) R9(3.2,-5.2) T1(-3.2,-6) T2(-2.4,-6) T3(-1.6,-6) T7(1.6,-6) T8(2.4,-6) T9(3.2,-6)
BGA631M23H82
  round 0.406 smd: A3(-10,10.8) A5(-9.2,10.8) A28(9.2,10.8) A30(10,10.8) A32(10.8,10.8) AH1(-10.8,-9.2) AH3(-10,-9.2) AH5(-9.2,-9.2) AH28(9.2,-9.2) AH30(10,-9.2) AH32(10.8,-9.2) AK1(-10.8,-10) AK3(-10,-10) AK5(-9.2,-10) AK28(9.2,-10) AK30(10,-10) AK32(10.8,-10) AM1(-10.8,-10.8) AM3(-10,-10.8) AM5(-9.2,-10.8) AM28(9.2,-10.8) AM30(10,-10.8) AM32(10.8,-10.8) C1(-10.8,10) C3(-10,10) C5(-9.2,10) C28(9.2,10) C30(10,10) C32(10.8,10) E1(-10.8,9.2) E3(-10,9.2) E5(-9.2,9.2) E28(9.2,9.2) E30(10,9.2) E32(10.8,9.2)
  round 0.356 smd: A7(-7.6,10.8) A9(-6,10.8) A11(-4.4,10.8) A13(-2.8,10.8) A15(-1.2,10.8) A17(0.4,10.8) A19(2,10.8) A21(3.6,10.8) A23(5.2,10.8) A25(6.8,10.8) A27(8.4,10.8) AA1(-10.8,-3.6) AA3(-10,-3.6) AA5(-9.2,-3.6) AA6(-8.4,-3.6) AA11(-4.4,-3.4) AA12(-3.4,-3.4) AA13(-2.4,-3.4) AA15(-1.4,-3.4) AA16(-0.4,-3.4) AA17(0.4,-3.4) AA18(1.4,-3.4) AA20(2.4,-3.4) AA21(3.4,-3.4) AA22(4.4,-3.4) AA27(8.4,-3.6) AA29(9.6,-3.6) AA31(10.4,-3.6) AB2(-10.4,-4.4) AB4(-9.6,-4.4) AB6(-8.4,-4.4) AB7(-7.6,-4.2) AB8(-6.8,-4.2) AB9(-6,-4.2) AB10(-5.2,-4.2) AB11(-4.4,-4.4) AB12(-3.4,-4.4) AB13(-2.4,-4.4) AB15(-1.4,-4.4) AB16(-0.4,-4.4) AB17(0.4,-4.4) AB18(1.4,-4.4) AB20(2.4,-4.4) AB21(3.4,-4.4) AB22(4.4,-4.4) AB23(5.2,-4.2) AB24(6,-4.2) AB25(6.8,-4.2) AB26(7.6,-4.2) AB27(8.4,-4.4) AB28(9.2,-4.4) AB30(10,-4.4) AB32(10.8,-4.4) AC1(-10.8,-5.2) AC3(-10,-5.2) AC5(-9.2,-5.2) AC6(-8.4,-5.2) AC7(-7.6,-5.2) AC8(-6.8,-5.2) AC9(-6,-5.2) AC10(-5.2,-5.2) AC11(-4.2,-5.2) AC13(-3,-5.2) AC14(-1.8,-5.2) AC16(-0.6,-5.2) AC17(0.6,-5.2) AC19(1.8,-5.2) AC20(3,-5.2) AC22(4.2,-5.2) AC23(5.2,-5.2) AC24(6,-5.2) AC25(6.8,-5.2) AC26(7.6,-5.2) AC27(8.4,-5.2) AC29(9.6,-5.2) AC31(10.4,-5.2) AD2(-10.4,-6) AD4(-9.6,-6) AD6(-8.4,-6) AD7(-7.6,-6) AD8(-6.8,-6) AD9(-6,-6) AD10(-5.2,-6) AD11(-4.2,-6) AD13(-3,-6) AD14(-1.8,-6) AD16(-0.6,-6) AD17(0.6,-6) AD19(1.8,-6) AD20(3,-6) AD22(4.2,-6) AD23(5.2,-6) AD24(6,-6) AD25(6.8,-6) AD26(7.6,-6) AD27(8.4,-6) AD28(9.2,-6) AD30(10,-6) AD32(10.8,-6) AE1(-10.8,-6.8) AE3(-10,-6.8) AE5(-9.2,-6.8) AE6(-8.4,-6.8) AE7(-7.6,-6.8) AE8(-6.8,-6.8) AE9(-6,-6.8) AE10(-5.2,-6.8) AE11(-4.2,-6.8) AE13(-3,-6.8) AE14(-1.8,-6.8) AE16(-0.6,-6.8) AE17(0.6,-6.8) AE19(1.8,-6.8) AE20(3,-6.8) AE22(4.2,-6.8) AE23(5.2,-6.8) AE24(6,-6.8) AE25(6.8,-6.8) AE26(7.6,-6.8) AE27(8.4,-6.8) AE29(9.6,-6.8) AE31(10.4,-6.8) AF2(-10.4,-7.6) AF4(-9.6,-7.6) AF6(-8.4,-7.6) AF7(-7.6,-7.6) AF8(-6.8,-7.6) AF9(-6,-7.6) AF10(-5.2,-7.6) AF11(-4.2,-7.6) AF13(-3,-7.6) AF14(-1.8,-7.6) AF16(-0.6,-7.6) AF17(0.6,-7.6) AF19(1.8,-7.6) AF20(3,-7.6) AF22(4.2,-7.6) AF23(5.2,-7.6) AF24(6,-7.6) AF25(6.8,-7.6) AF26(7.6,-7.6) AF27(8.4,-7.6) AF28(9.2,-7.6) AF30(10,-7.6) AF32(10.8,-7.6) AG1(-10.8,-8.4) AG3(-10,-8.4) AG5(-9.2,-8.4) AG6(-8.4,-8.4) AG7(-7.6,-8.4) AG8(-6.8,-8.4) AG9(-6,-8.4) AG10(-5.2,-8.4) AG11(-4.4,-8.4) AG12(-3.6,-8.4) AG13(-2.8,-8.4) AG14(-2,-8.4) AG15(-1.2,-8.4) AG16(-0.4,-8.4) AG17(0.4,-8.4) AG18(1.2,-8.4) AG19(2,-8.4) AG20(2.8,-8.4) AG21(3.6,-8.4) AG22(4.4,-8.4) AG23(5.2,-8.4) AG24(6,-8.4) AG25(6.8,-8.4) AG26(7.6,-8.4) AG27(8.4,-8.4) AG29(9.6,-8.4) AG31(10.4,-8.4) AH6(-8.4,-9.2) AH8(-6.8,-9.2) AH10(-5.2,-9.2) AH12(-3.6,-9.2) AH14(-2,-9.2) AH16(-0.4,-9.2) AH18(1.2,-9.2) AH20(2.8,-9.2) AH22(4.4,-9.2) AH24(6,-9.2) AH26(7.6,-9.2) AJ7(-7.6,-9.6) AJ9(-6,-9.6) AJ11(-4.4,-9.6) AJ13(-2.8,-9.6) AJ15(-1.2,-9.6) AJ17(0.4,-9.6) AJ19(2,-9.6) AJ21(3.6,-9.6) AJ23(5.2,-9.6) AJ25(6.8,-9.6) AJ27(8.4,-9.6) AK6(-8.4,-10) AK8(-6.8,-10) AK10(-5.2,-10) AK12(-3.6,-10) AK14(-2,-10) AK16(-0.4,-10) AK18(1.2,-10) AK20(2.8,-10) AK22(4.4,-10) AK24(6,-10) AK26(7.6,-10) AL7(-7.6,-10.4) AL9(-6,-10.4) AL11(-4.4,-10.4) AL13(-2.8,-10.4) AL15(-1.2,-10.4) AL17(0.4,-10.4) AL19(2,-10.4) AL21(3.6,-10.4) AL23(5.2,-10.4) AL25(6.8,-10.4) AL27(8.4,-10.4) AM6(-8.4,-10.8) AM8(-6.8,-10.8) AM10(-5.2,-10.8) AM12(-3.6,-10.8) AM14(-2,-10.8) AM16(-0.4,-10.8) AM18(1.2,-10.8) AM20(2.8,-10.8) AM22(4.4,-10.8) AM24(6,-10.8) AM26(7.6,-10.8) B6(-8.4,10.4) B8(-6.8,10.4) B10(-5.2,10.4) B12(-3.6,10.4) B14(-2,10.4) B16(-0.4,10.4) B18(1.2,10.4) B20(2.8,10.4) B22(4.4,10.4) B24(6,10.4) B26(7.6,10.4) C7(-7.6,10) C9(-6,10) C11(-4.4,10) C13(-2.8,10) C15(-1.2,10) C17(0.4,10) C19(2,10) C21(3.6,10) C23(5.2,10) C25(6.8,10) C27(8.4,10) D6(-8.4,9.6) D8(-6.8,9.6) D10(-5.2,9.6) D12(-3.6,9.6) D14(-2,9.6) D16(-0.4,9.6) D18(1.2,9.6) D20(2.8,9.6) D22(4.4,9.6) D24(6,9.6) D26(7.6,9.6) E7(-7.6,9.2) E9(-6,9.2) E11(-4.4,9.2) E13(-2.8,9.2) E15(-1.2,9.2) E17(0.4,9.2) E19(2,9.2) E21(3.6,9.2) E23(5.2,9.2) E25(6.8,9.2) E27(8.4,9.2) F2(-10.4,8.4) F4(-9.6,8.4) F6(-8.4,8.4) F7(-7.6,8.4) F8(-6.8,8.4) F9(-6,8.4) F10(-5.2,8.4) F11(-4.4,8.4) F12(-3.6,8.4) F13(-2.8,8.4) F14(-2,8.4) F15(-1.2,8.4) F16(-0.4,8.4) F17(0.4,8.4) F18(1.2,8.4) F19(2,8.4) F20(2.8,8.4) F21(3.6,8.4) F22(4.4,8.4) F23(5.2,8.4) F24(6,8.4) F25(6.8,8.4) F26(7.6,8.4) F27(8.4,8.4) F28(9.2,8.4) F30(10,8.4) F32(10.8,8.4) G1(-10.8,7.6) G3(-10,7.6) G5(-9.2,7.6) G6(-8.4,7.6) G7(-7.6,7.6) G8(-6.8,7.6) G9(-6,7.6) G10(-5.2,7.6) G11(-4.2,7.6) G13(-3,7.6) G14(-1.8,7.6) G16(-0.6,7.6) G17(0.6,7.6) G19(1.8,7.6) G20(3,7.6) G22(4.2,7.6) G23(5.2,7.6) G24(6,7.6) G25(6.8,7.6) G26(7.6,7.6) G27(8.4,7.6) G29(9.6,7.6) G31(10.4,7.6) H2(-10.4,6.8) H4(-9.6,6.8) H6(-8.4,6.8) H7(-7.6,6.8) H8(-6.8,6.8) H9(-6,6.8) H10(-5.2,6.8) H11(-4.2,6.8) H13(-3,6.8) H14(-1.8,6.8) H16(-0.6,6.8) H17(0.6,6.8) H19(1.8,6.8) H20(3,6.8) H22(4.2,6.8) H23(5.2,6.8) H24(6,6.8) H25(6.8,6.8) H26(7.6,6.8) H27(8.4,6.8) H28(9.2,6.8) H30(10,6.8) H32(10.8,6.8) J1(-10.8,6) J3(-10,6) J5(-9.2,6) J6(-8.4,6) J7(-7.6,6) J8(-6.8,6) J9(-6,6) J10(-5.2,6) J11(-4.2,6) J13(-3,6) J14(-1.8,6) J16(-0.6,6) J17(0.6,6) J19(1.8,6) J20(3,6) J22(4.2,6) J23(5.2,6) J24(6,6) J25(6.8,6) J26(7.6,6) J27(8.4,6) J29(9.6,6) J31(10.4,6) K2(-10.4,5.2) K4(-9.6,5.2) K6(-8.4,5.2) K7(-7.6,5.2) K8(-6.8,5.2) K9(-6,5.2) K10(-5.2,5.2) K11(-4.2,5.2) K13(-3,5.2) K14(-1.8,5.2) K16(-0.6,5.2) K17(0.6,5.2) K19(1.8,5.2) K20(3,5.2) K22(4.2,5.2) K23(5.2,5.2) K24(6,5.2) K25(6.8,5.2) K26(7.6,5.2) K27(8.4,5.2) K28(9.2,5.2) K30(10,5.2) K32(10.8,5.2) L1(-10.8,4.4) L3(-10,4.4) L5(-9.2,4.4) L6(-8.4,4.4) L7(-7.6,4.2) L8(-6.8,4.2) L9(-6,4.2) L10(-5.2,4.2) L11(-4.4,4.4) L12(-3.4,4.4) L13(-2.4,4.4) L15(-1.4,4.4) L16(-0.4,4.4) L17(0.4,4.4) L18(1.4,4.4) L20(2.4,4.4) L21(3.4,4.4) L22(4.4,4.4) L23(5.2,4.2) L24(6,4.2) L25(6.8,4.2) L26(7.6,4.2) L27(8.4,4.4) L29(9.6,4.4) L31(10.4,4.4) M2(-10.4,3.6) M4(-9.6,3.6) M6(-8.4,3.6) M11(-4.4,3.4) M12(-3.4,3.4) M13(-2.4,3.4) M15(-1.4,3.4) M16(-0.4,3.4) M17(0.4,3.4) M18(1.4,3.4) M20(2.4,3.4) M21(3.4,3.4) M22(4.4,3.4) M27(8.4,3.6) M28(9.2,3.6) M30(10,3.6) M32(10.8,3.6) N1(-10.8,2.8) N3(-10,2.8) N5(-9.2,2.8) N6(-8.4,2.8) N7(-7.6,3) N8(-6.8,3) N9(-6,3) N10(-5.2,3) N11(-4.4,2.4) N12(-3.4,2.4) N13(-2.4,2.4) N15(-1.4,2.4) N16(-0.4,2.4) N17(0.4,2.4) N18(1.4,2.4) N20(2.4,2.4) N21(3.4,2.4) N22(4.4,2.4) N23(5.2,3) N24(6,3) N25(6.8,3) N26(7.6,3) N27(8.4,2.8) N29(9.6,2.8) N31(10.4,2.8) P2(-10.4,2) P4(-9.6,2) P6(-8.4,2) P7(-7.6,1.8) P8(-6.8,1.8) P9(-6,1.8) P10(-5.2,1.8) P23(5.2,1.8) P24(6,1.8) P25(6.8,1.8) P26(7.6,1.8) P27(8.4,2) P28(9.2,2) P30(10,2) P32(10.8,2) R1(-10.8,1.2) R3(-10,1.2) R5(-9.2,1.2) R6(-8.4,1.2) R11(-4.4,1.4) R12(-3.4,1.4) R13(-2.4,1.4) R15(-1.4,1.4) R16(-0.4,1.4) R17(0.4,1.4) R18(1.4,1.4) R20(2.4,1.4) R21(3.4,1.4) R22(4.4,1.4) R27(8.4,1.2) R29(9.6,1.2) R31(10.4,1.2) T2(-10.4,0.4) T4(-9.6,0.4) T6(-8.4,0.4) T7(-7.6,0.6) T8(-6.8,0.6) T9(-6,0.6) T10(-5.2,0.6) T11(-4.4,0.4) T12(-3.4,0.4) T13(-2.4,0.4) T15(-1.4,0.4) T16(-0.4,0.4) T17(0.4,0.4) T18(1.4,0.4) T20(2.4,0.4) T21(3.4,0.4) T22(4.4,0.4) T23(5.2,0.6) T24(6,0.6) T25(6.8,0.6) T26(7.6,0.6) T27(8.4,0.4) T28(9.2,0.4) T30(10,0.4) T32(10.8,0.4) U1(-10.8,-0.4) U3(-10,-0.4) U5(-9.2,-0.4) U6(-8.4,-0.4) U7(-7.6,-0.6) U8(-6.8,-0.6) U9(-6,-0.6) U10(-5.2,-0.6) U11(-4.4,-0.4) U12(-3.4,-0.4) U13(-2.4,-0.4) U15(-1.4,-0.4) U16(-0.4,-0.4) U17(0.4,-0.4) U18(1.4,-0.4) U20(2.4,-0.4) U21(3.4,-0.4) U22(4.4,-0.4) U23(5.2,-0.6) U24(6,-0.6) U25(6.8,-0.6) U26(7.6,-0.6) U27(8.4,-0.4) U29(9.6,-0.4) U31(10.4,-0.4) V2(-10.4,-1.2) V4(-9.6,-1.2) V6(-8.4,-1.2) V11(-4.4,-1.4) V12(-3.4,-1.4) V13(-2.4,-1.4) V15(-1.4,-1.4) V16(-0.4,-1.4) V17(0.4,-1.4) V18(1.4,-1.4) V20(2.4,-1.4) V21(3.4,-1.4) V22(4.4,-1.4) V27(8.4,-1.2) V28(9.2,-1.2) V30(10,-1.2) V32(10.8,-1.2) W1(-10.8,-2) W3(-10,-2) W5(-9.2,-2) W6(-8.4,-2) W7(-7.6,-1.8) W8(-6.8,-1.8) W9(-6,-1.8) W10(-5.2,-1.8) W23(5.2,-1.8) W24(6,-1.8) W25(6.8,-1.8) W26(7.6,-1.8) W27(8.4,-2) W29(9.6,-2) W31(10.4,-2) Y2(-10.4,-2.8) Y4(-9.6,-2.8) Y6(-8.4,-2.8) Y7(-7.6,-3) Y8(-6.8,-3) Y9(-6,-3) Y10(-5.2,-3) Y11(-4.4,-2.4) Y12(-3.4,-2.4) Y13(-2.4,-2.4) Y15(-1.4,-2.4) Y16(-0.4,-2.4) Y17(0.4,-2.4) Y18(1.4,-2.4) Y20(2.4,-2.4) Y21(3.4,-2.4) Y22(4.4,-2.4) Y23(5.2,-3) Y24(6,-3) Y25(6.8,-3) Y26(7.6,-3) Y27(8.4,-2.8) Y28(9.2,-2.8) Y30(10,-2.8) Y32(10.8,-2.8)
BGA968M2937H74
  round 0.4 smd: A2(-12,16.9) A3(-11.1,16.9) A31(11.1,16.9) A32(12,16.9) AB5(-9.7,0) AB6(-8.9,0) AB7(-8.1,0) AB8(-7.3,0) AB9(-6.5,0) AB10(-5.4,0) AB12(-4.2,0) AB13(-3,0) AB15(-1.8,0) AB16(-0.6,0) AB18(0.6,0) AB19(1.8,0) AB21(3,0) AB22(4.2,0) AB24(5.4,0) AB25(6.5,0) AB26(7.3,0) AB27(8.1,0) AB28(8.9,0) AB29(9.7,0) AD5(-9.7,-1.2) AD6(-8.9,-1.2) AD7(-8.1,-1.2) AD8(-7.3,-1.2) AD9(-6.5,-1.2) AD10(-5.4,-1.2) AD12(-4.2,-1.2) AD13(-3,-1.2) AD15(-1.8,-1.2) AD16(-0.6,-1.2) AD18(0.6,-1.2) AD19(1.8,-1.2) AD21(3,-1.2) AD22(4.2,-1.2) AD24(5.4,-1.2) AD25(6.5,-1.2) AD26(7.3,-1.2) AD27(8.1,-1.2) AD28(8.9,-1.2) AD29(9.7,-1.2) AE5(-9.7,-2.4) AE6(-8.9,-2.4) AE7(-8.1,-2.4) AE8(-7.3,-2.4) AE9(-6.5,-2.4) AE10(-5.4,-2.4) AE12(-4.2,-2.4) AE13(-3,-2.4) AE15(-1.8,-2.4) AE16(-0.6,-2.4) AE18(0.6,-2.4) AE19(1.8,-2.4) AE21(3,-2.4) AE22(4.2,-2.4) AE24(5.4,-2.4) AE25(6.5,-2.4) AE26(7.3,-2.4) AE27(8.1,-2.4) AE28(8.9,-2.4) AE29(9.7,-2.4) AG5(-9.7,-3.6) AG6(-8.9,-3.6) AG7(-8.1,-3.6) AG8(-7.3,-3.6) AG9(-6.5,-3.6) AG10(-5.4,-3.6) AG12(-4.2,-3.6) AG13(-3,-3.6) AG15(-1.8,-3.6) AG16(-0.6,-3.6) AG18(0.6,-3.6) AG19(1.8,-3.6) AG21(3,-3.6) AG22(4.2,-3.6) AG24(5.4,-3.6) AG25(6.5,-3.6) AG26(7.3,-3.6) AG27(8.1,-3.6) AG28(8.9,-3.6) AG29(9.7,-3.6) AH5(-9.7,-4.8) AH6(-8.9,-4.8) AH7(-8.1,-4.8) AH8(-7.3,-4.8) AH9(-6.5,-4.8) AH10(-5.4,-4.8) AH12(-4.2,-4.8) AH13(-3,-4.8) AH15(-1.8,-4.8) AH16(-0.6,-4.8) AH18(0.6,-4.8) AH19(1.8,-4.8) AH21(3,-4.8) AH22(4.2,-4.8) AH24(5.4,-4.8) AH25(6.5,-4.8) AH26(7.3,-4.8) AH27(8.1,-4.8) AH28(8.9,-4.8) AH29(9.7,-4.8) AK5(-9.7,-6) AK6(-8.9,-6) AK7(-8.1,-6) AK8(-7.3,-6) AK9(-6.5,-6) AK10(-5.4,-6) AK12(-4.2,-6) AK13(-3,-6) AK15(-1.8,-6) AK16(-0.6,-6) AK18(0.6,-6) AK19(1.8,-6) AK21(3,-6) AK22(4.2,-6) AK24(5.4,-6) AK25(6.5,-6) AK26(7.3,-6) AK27(8.1,-6) AK28(8.9,-6) AK29(9.7,-6) AL5(-9.7,-7.2) AL6(-8.9,-7.2) AL7(-8.1,-7.2) AL8(-7.3,-7.2) AL9(-6.5,-7.2) AL10(-5.4,-7.2) AL12(-4.2,-7.2) AL13(-3,-7.2) AL15(-1.8,-7.2) AL16(-0.6,-7.2) AL18(0.6,-7.2) AL19(1.8,-7.2) AL21(3,-7.2) AL22(4.2,-7.2) AL24(5.4,-7.2) AL25(6.5,-7.2) AL26(7.3,-7.2) AL27(8.1,-7.2) AL28(8.9,-7.2) AL29(9.7,-7.2) AN5(-9.7,-8.4) AN6(-8.9,-8.4) AN7(-8.1,-8.4) AN8(-7.3,-8.4) AN9(-6.5,-8.4) AN10(-5.4,-8.4) AN12(-4.2,-8.4) AN13(-3,-8.4) AN15(-1.8,-8.4) AN16(-0.6,-8.4) AN18(0.6,-8.4) AN19(1.8,-8.4) AN21(3,-8.4) AN22(4.2,-8.4) AN24(5.4,-8.4) AN25(6.5,-8.4) AN26(7.3,-8.4) AN27(8.1,-8.4) AN28(8.9,-8.4) AN29(9.7,-8.4) AP5(-9.7,-9.6) AP6(-8.9,-9.6) AP7(-8.1,-9.6) AP8(-7.3,-9.6) AP9(-6.5,-9.6) AP10(-5.4,-9.6) AP12(-4.2,-9.6) AP13(-3,-9.6) AP15(-1.8,-9.6) AP16(-0.6,-9.6) AP18(0.6,-9.6) AP19(1.8,-9.6) AP21(3,-9.6) AP22(4.2,-9.6) AP24(5.4,-9.6) AP25(6.5,-9.6) AP26(7.3,-9.6) AP27(8.1,-9.6) AP28(8.9,-9.6) AP29(9.7,-9.6) AR5(-9.7,-10.8) AR6(-8.9,-10.8) AR7(-8.1,-10.8) AR8(-7.3,-10.8) AR9(-6,-10.5) AR11(-4.8,-10.5) AR12(-3.6,-10.5) AR14(-2.4,-10.5) AR15(-1.2,-10.5) AR17(0,-10.5) AR19(1.2,-10.5) AR20(2.4,-10.5) AR22(3.6,-10.5) AR23(4.8,-10.5) AR25(6,-10.5) AR26(7.3,-10.8) AR27(8.1,-10.8) AR28(8.9,-10.8) AR29(9.7,-10.8) AT9(-6,-11.3) AT11(-4.8,-11.3) AT12(-3.6,-11.3) AT14(-2.4,-11.3) AT15(-1.2,-11.3) AT17(0,-11.3) AT19(1.2,-11.3) AT20(2.4,-11.3) AT22(3.6,-11.3) AT23(4.8,-11.3) AT25(6,-11.3) AU5(-9.7,-12) AU6(-8.9,-12) AU7(-8.1,-12) AU8(-7.2,-12.1) AU9(-6,-12.1) AU11(-4.8,-12.1) AU12(-3.6,-12.1) AU14(-2.4,-12.1) AU15(-1.2,-12.1) AU17(0,-12.1) AU19(1.2,-12.1) AU20(2.4,-12.1) AU22(3.6,-12.1) AU23(4.8,-12.1) AU25(6,-12.1) AU26(7.2,-12.1) AU27(8.1,-12) AU28(8.9,-12) AU29(9.7,-12) AV5(-9.7,-13.2) AV7(-8.4,-12.9) AV8(-7.2,-12.9) AV9(-6,-12.9) AV11(-4.8,-12.9) AV12(-3.6,-12.9) AV14(-2.4,-12.9) AV15(-1.2,-12.9) AV17(0,-12.9) AV19(1.2,-12.9) AV20(2.4,-12.9) AV22(3.6,-12.9) AV23(4.8,-12.9) AV25(6,-12.9) AV26(7.2,-12.9) AV27(8.4,-12.9) AV29(9.7,-13.2) AW7(-8.4,-13.7) AW8(-7.2,-13.7) AW9(-6,-13.7) AW11(-4.8,-13.7) AW12(-3.6,-13.7) AW14(-2.4,-13.7) AW15(-1.2,-13.7) AW17(0,-13.7) AW19(1.2,-13.7) AW20(2.4,-13.7) AW22(3.6,-13.7) AW23(4.8,-13.7) AW25(6,-13.7) AW26(7.2,-13.7) AW27(8.4,-13.7) B1(-12.9,16) B2(-12,16) B32(12,16) B33(12.9,16) BA1(-12.9,-15.1) BA33(12.9,-15.1) BB1(-12.9,-16) BB2(-12,-16) BB32(12,-16) BB33(12.9,-16) BC2(-12,-16.9) BC3(-11.1,-16.9) BC31(11.1,-16.9) BC32(12,-16.9) C1(-12.9,15.1) C33(12.9,15.1) E7(-8.4,13.7) E8(-7.2,13.7) E9(-6,13.7) E11(-4.8,13.7) E12(-3.6,13.7) E14(-2.4,13.7) E15(-1.2,13.7) E17(0,13.7) E19(1.2,13.7) E20(2.4,13.7) E22(3.6,13.7) E23(4.8,13.7) E25(6,13.7) E26(7.2,13.7) E27(8.4,13.7) F5(-9.7,13.2) F7(-8.4,12.9) F8(-7.2,12.9) F9(-6,12.9) F11(-4.8,12.9) F12(-3.6,12.9) F14(-2.4,12.9) F15(-1.2,12.9) F17(0,12.9) F19(1.2,12.9) F20(2.4,12.9) F22(3.6,12.9) F23(4.8,12.9) F25(6,12.9) F26(7.2,12.9) F27(8.4,12.9) F29(9.7,13.2) G5(-9.7,12) G6(-8.9,12) G7(-8.1,12) G8(-7.2,12.1) G9(-6,12.1) G11(-4.8,12.1) G12(-3.6,12.1) G14(-2.4,12.1) G15(-1.2,12.1) G17(0,12.1) G19(1.2,12.1) G20(2.4,12.1) G22(3.6,12.1) G23(4.8,12.1) G25(6,12.1) G26(7.2,12.1) G27(8.1,12) G28(8.9,12) G29(9.7,12) H9(-6,11.3) H11(-4.8,11.3) H12(-3.6,11.3) H14(-2.4,11.3) H15(-1.2,11.3) H17(0,11.3) H19(1.2,11.3) H20(2.4,11.3) H22(3.6,11.3) H23(4.8,11.3) H25(6,11.3) J5(-9.7,10.8) J6(-8.9,10.8) J7(-8.1,10.8) J8(-7.3,10.8) J9(-6,10.5) J11(-4.8,10.5) J12(-3.6,10.5) J14(-2.4,10.5) J15(-1.2,10.5) J17(0,10.5) J19(1.2,10.5) J20(2.4,10.5) J22(3.6,10.5) J23(4.8,10.5) J25(6,10.5) J26(7.3,10.8) J27(8.1,10.8) J28(8.9,10.8) J29(9.7,10.8) K5(-9.7,9.6) K6(-8.9,9.6) K7(-8.1,9.6) K8(-7.3,9.6) K9(-6.5,9.6) K10(-5.4,9.6) K12(-4.2,9.6) K13(-3,9.6) K15(-1.8,9.6) K16(-0.6,9.6) K18(0.6,9.6) K19(1.8,9.6) K21(3,9.6) K22(4.2,9.6) K24(5.4,9.6) K25(6.5,9.6) K26(7.3,9.6) K27(8.1,9.6) K28(8.9,9.6) K29(9.7,9.6) L5(-9.7,8.4) L6(-8.9,8.4) L7(-8.1,8.4) L8(-7.3,8.4) L9(-6.5,8.4) L10(-5.4,8.4) L12(-4.2,8.4) L13(-3,8.4) L15(-1.8,8.4) L16(-0.6,8.4) L18(0.6,8.4) L19(1.8,8.4) L21(3,8.4) L22(4.2,8.4) L24(5.4,8.4) L25(6.5,8.4) L26(7.3,8.4) L27(8.1,8.4) L28(8.9,8.4) L29(9.7,8.4) N5(-9.7,7.2) N6(-8.9,7.2) N7(-8.1,7.2) N8(-7.3,7.2) N9(-6.5,7.2) N10(-5.4,7.2) N12(-4.2,7.2) N13(-3,7.2) N15(-1.8,7.2) N16(-0.6,7.2) N18(0.6,7.2) N19(1.8,7.2) N21(3,7.2) N22(4.2,7.2) N24(5.4,7.2) N25(6.5,7.2) N26(7.3,7.2) N27(8.1,7.2) N28(8.9,7.2) N29(9.7,7.2) P5(-9.7,6) P6(-8.9,6) P7(-8.1,6) P8(-7.3,6) P9(-6.5,6) P10(-5.4,6) P12(-4.2,6) P13(-3,6) P15(-1.8,6) P16(-0.6,6) P18(0.6,6) P19(1.8,6) P21(3,6) P22(4.2,6) P24(5.4,6) P25(6.5,6) P26(7.3,6) P27(8.1,6) P28(8.9,6) P29(9.7,6) T5(-9.7,4.8) T6(-8.9,4.8) T7(-8.1,4.8) T8(-7.3,4.8) T9(-6.5,4.8) T10(-5.4,4.8) T12(-4.2,4.8) T13(-3,4.8) T15(-1.8,4.8) T16(-0.6,4.8) T18(0.6,4.8) T19(1.8,4.8) T21(3,4.8) T22(4.2,4.8) T24(5.4,4.8) T25(6.5,4.8) T26(7.3,4.8) T27(8.1,4.8) T28(8.9,4.8) T29(9.7,4.8) U5(-9.7,3.6) U6(-8.9,3.6) U7(-8.1,3.6) U8(-7.3,3.6) U9(-6.5,3.6) U10(-5.4,3.6) U12(-4.2,3.6) U13(-3,3.6) U15(-1.8,3.6) U16(-0.6,3.6) U18(0.6,3.6) U19(1.8,3.6) U21(3,3.6) U22(4.2,3.6) U24(5.4,3.6) U25(6.5,3.6) U26(7.3,3.6) U27(8.1,3.6) U28(8.9,3.6) U29(9.7,3.6) W5(-9.7,2.4) W6(-8.9,2.4) W7(-8.1,2.4) W8(-7.3,2.4) W9(-6.5,2.4) W10(-5.4,2.4) W12(-4.2,2.4) W13(-3,2.4) W15(-1.8,2.4) W16(-0.6,2.4) W18(0.6,2.4) W19(1.8,2.4) W21(3,2.4) W22(4.2,2.4) W24(5.4,2.4) W25(6.5,2.4) W26(7.3,2.4) W27(8.1,2.4) W28(8.9,2.4) W29(9.7,2.4) Y5(-9.7,1.2) Y6(-8.9,1.2) Y7(-8.1,1.2) Y8(-7.3,1.2) Y9(-6.5,1.2) Y10(-5.4,1.2) Y12(-4.2,1.2) Y13(-3,1.2) Y15(-1.8,1.2) Y16(-0.6,1.2) Y18(0.6,1.2) Y19(1.8,1.2) Y21(3,1.2) Y22(4.2,1.2) Y24(5.4,1.2) Y25(6.5,1.2) Y26(7.3,1.2) Y27(8.1,1.2) Y28(8.9,1.2) Y29(9.7,1.2)
  round 0.3 smd: A4(-10.4,16.5) A5(-9.6,16.9) A6(-8.8,16.5) A7(-8,16.9) A8(-7.2,16.5) A9(-6.4,16.9) A10(-5.6,16.5) A11(-4.8,16.9) A12(-4,16.5) A13(-3.2,16.9) A14(-2.4,16.5) A15(-1.6,16.9) A16(-0.8,16.5) A17(0,16.9) A18(0.8,16.5) A19(1.6,16.9) A20(2.4,16.5) A21(3.2,16.9) A22(4,16.5) A23(4.8,16.9) A24(5.6,16.5) A25(6.4,16.9) A26(7.2,16.5) A27(8,16.9) A28(8.8,16.5) A29(9.6,16.9) A30(10.4,16.5) AA1(-12.9,0.8) AA2(-12.1,0.8) AA3(-11.3,0.8) AA4(-10.5,0.8) AA30(10.5,0.8) AA31(11.3,0.8) AA32(12.1,0.8) AA33(12.9,0.8) AB1(-12.5,0) AB2(-11.7,0) AB4(-10.5,0) AB30(10.5,0) AB32(11.7,0) AB33(12.5,0) AC1(-12.9,-0.8) AC2(-12.1,-0.8) AC3(-11.3,-0.8) AC4(-10.5,-0.8) AC30(10.5,-0.8) AC31(11.3,-0.8) AC32(12.1,-0.8) AC33(12.9,-0.8) AD1(-12.5,-1.6) AD2(-11.7,-1.6) AD4(-10.5,-1.6) AD30(10.5,-1.6) AD32(11.7,-1.6) AD33(12.5,-1.6) AE1(-12.9,-2.4) AE2(-12.1,-2.4) AE3(-11.3,-2.4) AE4(-10.5,-2.4) AE30(10.5,-2.4) AE31(11.3,-2.4) AE32(12.1,-2.4) AE33(12.9,-2.4) AF1(-12.5,-3.2) AF2(-11.7,-3.2) AF4(-10.5,-3.2) AF30(10.5,-3.2) AF32(11.7,-3.2) AF33(12.5,-3.2) AG1(-12.9,-4) AG2(-12.1,-4) AG3(-11.3,-4) AG4(-10.5,-4) AG30(10.5,-4) AG31(11.3,-4) AG32(12.1,-4) AG33(12.9,-4) AH1(-12.5,-4.8) AH2(-11.7,-4.8) AH4(-10.5,-4.8) AH30(10.5,-4.8) AH32(11.7,-4.8) AH33(12.5,-4.8) AJ1(-12.9,-5.6) AJ2(-12.1,-5.6) AJ3(-11.3,-5.6) AJ4(-10.5,-5.6) AJ30(10.5,-5.6) AJ31(11.3,-5.6) AJ32(12.1,-5.6) AJ33(12.9,-5.6) AK1(-12.5,-6.4) AK2(-11.7,-6.4) AK4(-10.5,-6.4) AK30(10.5,-6.4) AK32(11.7,-6.4) AK33(12.5,-6.4) AL1(-12.9,-7.2) AL2(-12.1,-7.2) AL3(-11.3,-7.2) AL4(-10.5,-7.2) AL30(10.5,-7.2) AL31(11.3,-7.2) AL32(12.1,-7.2) AL33(12.9,-7.2) AM1(-12.5,-8) AM2(-11.7,-8) AM4(-10.5,-8) AM30(10.5,-8) AM32(11.7,-8) AM33(12.5,-8) AN1(-12.9,-8.8) AN2(-12.1,-8.8) AN3(-11.3,-8.8) AN4(-10.5,-8.8) AN30(10.5,-8.8) AN31(11.3,-8.8) AN32(12.1,-8.8) AN33(12.9,-8.8) AP1(-12.5,-9.6) AP2(-11.7,-9.6) AP4(-10.5,-9.6) AP30(10.5,-9.6) AP32(11.7,-9.6) AP33(12.5,-9.6) AR1(-12.9,-10.4) AR2(-12.1,-10.4) AR3(-11.3,-10.4) AR4(-10.5,-10.4) AR30(10.5,-10.4) AR31(11.3,-10.4) AR32(12.1,-10.4) AR33(12.9,-10.4) AT1(-12.5,-11.2) AT2(-11.7,-11.2) AT4(-10.5,-11.2) AT30(10.5,-11.2) AT32(11.7,-11.2) AT33(12.5,-11.2) AU1(-12.9,-12) AU2(-12.1,-12) AU3(-11.3,-12) AU4(-10.5,-12) AU30(10.5,-12) AU31(11.3,-12) AU32(12.1,-12) AU33(12.9,-12) AV1(-12.5,-12.8) AV2(-11.7,-12.8) AV4(-10.5,-12.8) AV30(10.5,-12.8) AV32(11.7,-12.8) AV33(12.5,-12.8) AW1(-12.9,-13.6) AW2(-12.1,-13.6) AW3(-11.3,-13.6) AW4(-10.5,-13.6) AW30(10.5,-13.6) AW31(11.3,-13.6) AW32(12.1,-13.6) AW33(12.9,-13.6) AY1(-12.5,-14.4) AY2(-11.7,-14.4) AY4(-10.4,-14.5) AY5(-9.6,-14.5) AY6(-8.8,-14.5) AY7(-8,-14.5) AY8(-7.2,-14.5) AY9(-6.4,-14.5) AY10(-5.6,-14.5) AY11(-4.8,-14.5) AY12(-4,-14.5) AY13(-3.2,-14.5) AY14(-2.4,-14.5) AY15(-1.6,-14.5) AY16(-0.8,-14.5) AY17(0,-14.5) AY18(0.8,-14.5) AY19(1.6,-14.5) AY20(2.4,-14.5) AY21(3.2,-14.5) AY22(4,-14.5) AY23(4.8,-14.5) AY24(5.6,-14.5) AY25(6.4,-14.5) AY26(7.2,-14.5) AY27(8,-14.5) AY28(8.8,-14.5) AY29(9.6,-14.5) AY30(10.4,-14.5) AY32(11.7,-14.4) AY33(12.5,-14.4) B4(-10.4,15.7) B5(-9.6,16.1) B6(-8.8,15.7) B7(-8,16.1) B8(-7.2,15.7) B9(-6.4,16.1) B10(-5.6,15.7) B11(-4.8,16.1) B12(-4,15.7) B13(-3.2,16.1) B14(-2.4,15.7) B15(-1.6,16.1) B16(-0.8,15.7) B17(0,16.1) B18(0.8,15.7) B19(1.6,16.1) B20(2.4,15.7) B21(3.2,16.1) B22(4,15.7) B23(4.8,16.1) B24(5.6,15.7) B25(6.4,16.1) B26(7.2,15.7) B27(8,16.1) B28(8.8,15.7) B29(9.6,16.1) B30(10.4,15.7) BA3(-11.2,-15.3) BA5(-9.6,-15.3) BA7(-8,-15.3) BA9(-6.4,-15.3) BA11(-4.8,-15.3) BA13(-3.2,-15.3) BA15(-1.6,-15.3) BA17(0,-15.3) BA19(1.6,-15.3) BA21(3.2,-15.3) BA23(4.8,-15.3) BA25(6.4,-15.3) BA27(8,-15.3) BA29(9.6,-15.3) BA31(11.2,-15.3) BB4(-10.4,-15.7) BB5(-9.6,-16.1) BB6(-8.8,-15.7) BB7(-8,-16.1) BB8(-7.2,-15.7) BB9(-6.4,-16.1) BB10(-5.6,-15.7) BB11(-4.8,-16.1) BB12(-4,-15.7) BB13(-3.2,-16.1) BB14(-2.4,-15.7) BB15(-1.6,-16.1) BB16(-0.8,-15.7) BB17(0,-16.1) BB18(0.8,-15.7) BB19(1.6,-16.1) BB20(2.4,-15.7) BB21(3.2,-16.1) BB22(4,-15.7) BB23(4.8,-16.1) BB24(5.6,-15.7) BB25(6.4,-16.1) BB26(7.2,-15.7) BB27(8,-16.1) BB28(8.8,-15.7) BB29(9.6,-16.1) BB30(10.4,-15.7) BC4(-10.4,-16.5) BC5(-9.6,-16.9) BC6(-8.8,-16.5) BC7(-8,-16.9) BC8(-7.2,-16.5) BC9(-6.4,-16.9) BC10(-5.6,-16.5) BC11(-4.8,-16.9) BC12(-4,-16.5) BC13(-3.2,-16.9) BC14(-2.4,-16.5) BC15(-1.6,-16.9) BC16(-0.8,-16.5) BC17(0,-16.9) BC18(0.8,-16.5) BC19(1.6,-16.9) BC20(2.4,-16.5) BC21(3.2,-16.9) BC22(4,-16.5) BC23(4.8,-16.9) BC24(5.6,-16.5) BC25(6.4,-16.9) BC26(7.2,-16.5) BC27(8,-16.9) BC28(8.8,-16.5) BC29(9.6,-16.9) BC30(10.4,-16.5) C3(-11.2,15.3) C5(-9.6,15.3) C7(-8,15.3) C9(-6.4,15.3) C11(-4.8,15.3) C13(-3.2,15.3) C15(-1.6,15.3) C17(0,15.3) C19(1.6,15.3) C21(3.2,15.3) C23(4.8,15.3) C25(6.4,15.3) C27(8,15.3) C29(9.6,15.3) C31(11.2,15.3) D1(-12.5,14.4) D2(-11.7,14.4) D4(-10.4,14.5) D5(-9.6,14.5) D6(-8.8,14.5) D7(-8,14.5) D8(-7.2,14.5) D9(-6.4,14.5) D10(-5.6,14.5) D11(-4.8,14.5) D12(-4,14.5) D13(-3.2,14.5) D14(-2.4,14.5) D15(-1.6,14.5) D16(-0.8,14.5) D17(0,14.5) D18(0.8,14.5) D19(1.6,14.5) D20(2.4,14.5) D21(3.2,14.5) D22(4,14.5) D23(4.8,14.5) D24(5.6,14.5) D25(6.4,14.5) D26(7.2,14.5) D27(8,14.5) D28(8.8,14.5) D29(9.6,14.5) D30(10.4,14.5) D32(11.7,14.4) D33(12.5,14.4) E1(-12.9,13.6) E2(-12.1,13.6) E3(-11.3,13.6) E4(-10.5,13.6) E30(10.5,13.6) E31(11.3,13.6) E32(12.1,13.6) E33(12.9,13.6) F1(-12.5,12.8) F2(-11.7,12.8) F4(-10.5,12.8) F30(10.5,12.8) F32(11.7,12.8) F33(12.5,12.8) G1(-12.9,12) G2(-12.1,12) G3(-11.3,12) G4(-10.5,12) G30(10.5,12) G31(11.3,12) G32(12.1,12) G33(12.9,12) H1(-12.5,11.2) H2(-11.7,11.2) H4(-10.5,11.2) H30(10.5,11.2) H32(11.7,11.2) H33(12.5,11.2) J1(-12.9,10.4) J2(-12.1,10.4) J3(-11.3,10.4) J4(-10.5,10.4) J30(10.5,10.4) J31(11.3,10.4) J32(12.1,10.4) J33(12.9,10.4) K1(-12.5,9.6) K2(-11.7,9.6) K4(-10.5,9.6) K30(10.5,9.6) K32(11.7,9.6) K33(12.5,9.6) L1(-12.9,8.8) L2(-12.1,8.8) L3(-11.3,8.8) L4(-10.5,8.8) L30(10.5,8.8) L31(11.3,8.8) L32(12.1,8.8) L33(12.9,8.8) M1(-12.5,8) M2(-11.7,8) M4(-10.5,8) M30(10.5,8) M32(11.7,8) M33(12.5,8) N1(-12.9,7.2) N2(-12.1,7.2) N3(-11.3,7.2) N4(-10.5,7.2) N30(10.5,7.2) N31(11.3,7.2) N32(12.1,7.2) N33(12.9,7.2) P1(-12.5,6.4) P2(-11.7,6.4) P4(-10.5,6.4) P30(10.5,6.4) P32(11.7,6.4) P33(12.5,6.4) R1(-12.9,5.6) R2(-12.1,5.6) R3(-11.3,5.6) R4(-10.5,5.6) R30(10.5,5.6) R31(11.3,5.6) R32(12.1,5.6) R33(12.9,5.6) T1(-12.5,4.8) T2(-11.7,4.8) T4(-10.5,4.8) T30(10.5,4.8) T32(11.7,4.8) T33(12.5,4.8) U1(-12.9,4) U2(-12.1,4) U3(-11.3,4) U4(-10.5,4) U30(10.5,4) U31(11.3,4) U32(12.1,4) U33(12.9,4) V1(-12.5,3.2) V2(-11.7,3.2) V4(-10.5,3.2) V30(10.5,3.2) V32(11.7,3.2) V33(12.5,3.2) W1(-12.9,2.4) W2(-12.1,2.4) W3(-11.3,2.4) W4(-10.5,2.4) W30(10.5,2.4) W31(11.3,2.4) W32(12.1,2.4) W33(12.9,2.4) Y1(-12.5,1.6) Y2(-11.7,1.6) Y4(-10.5,1.6) Y30(10.5,1.6) Y32(11.7,1.6) Y33(12.5,1.6)
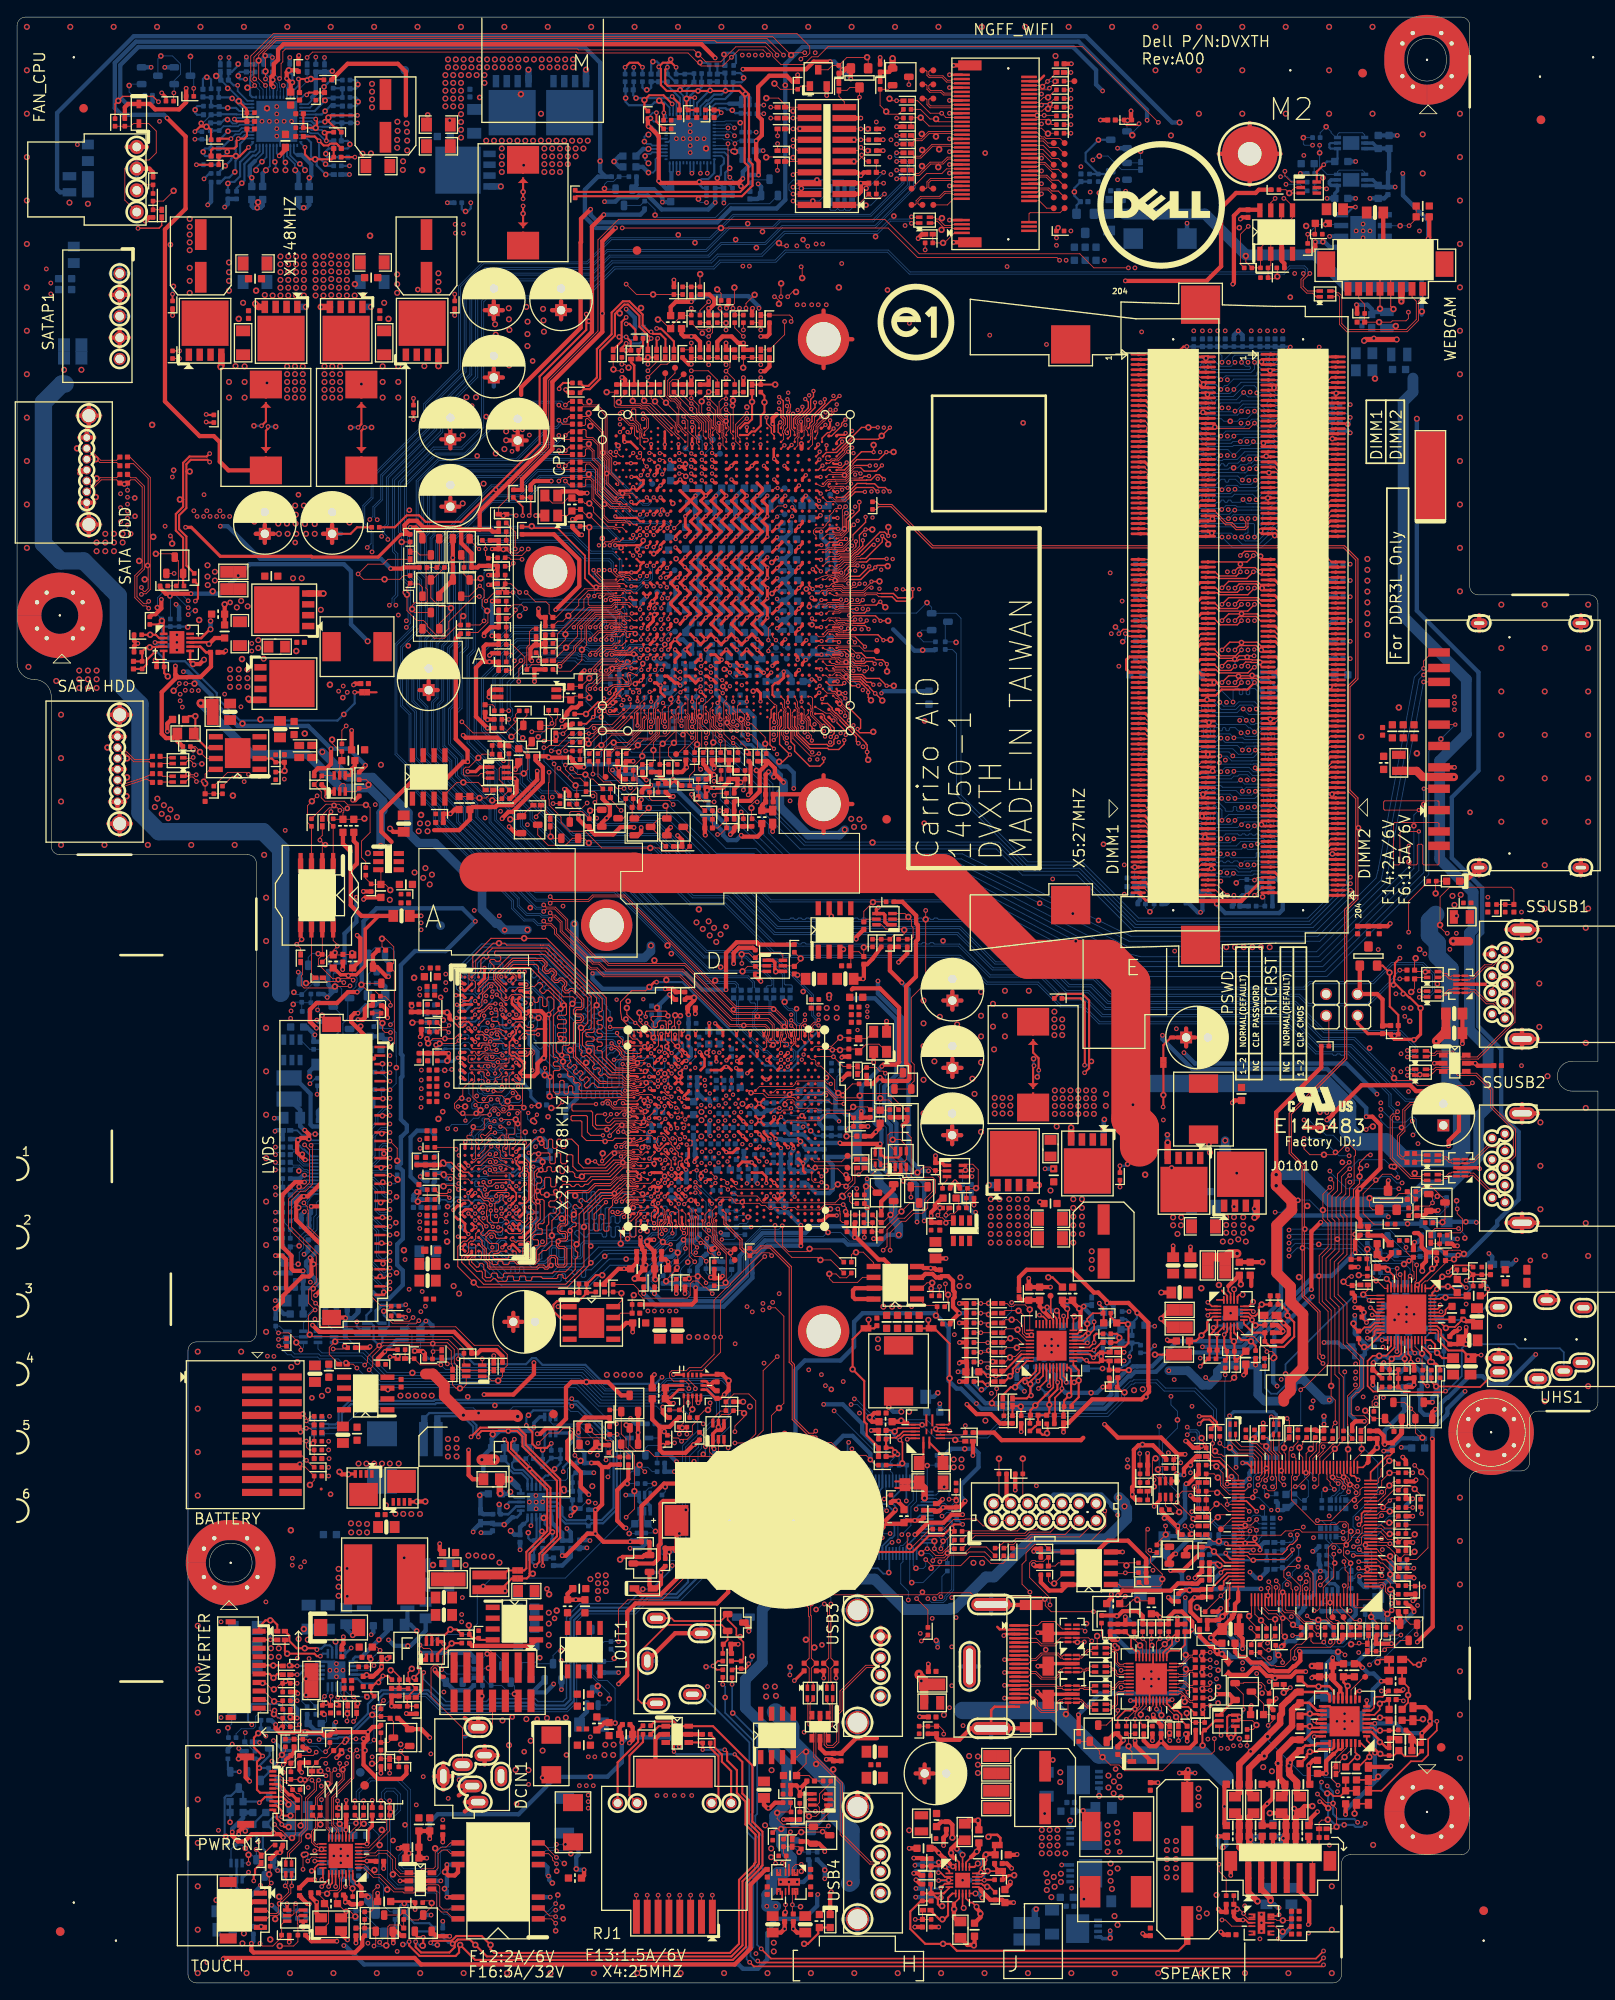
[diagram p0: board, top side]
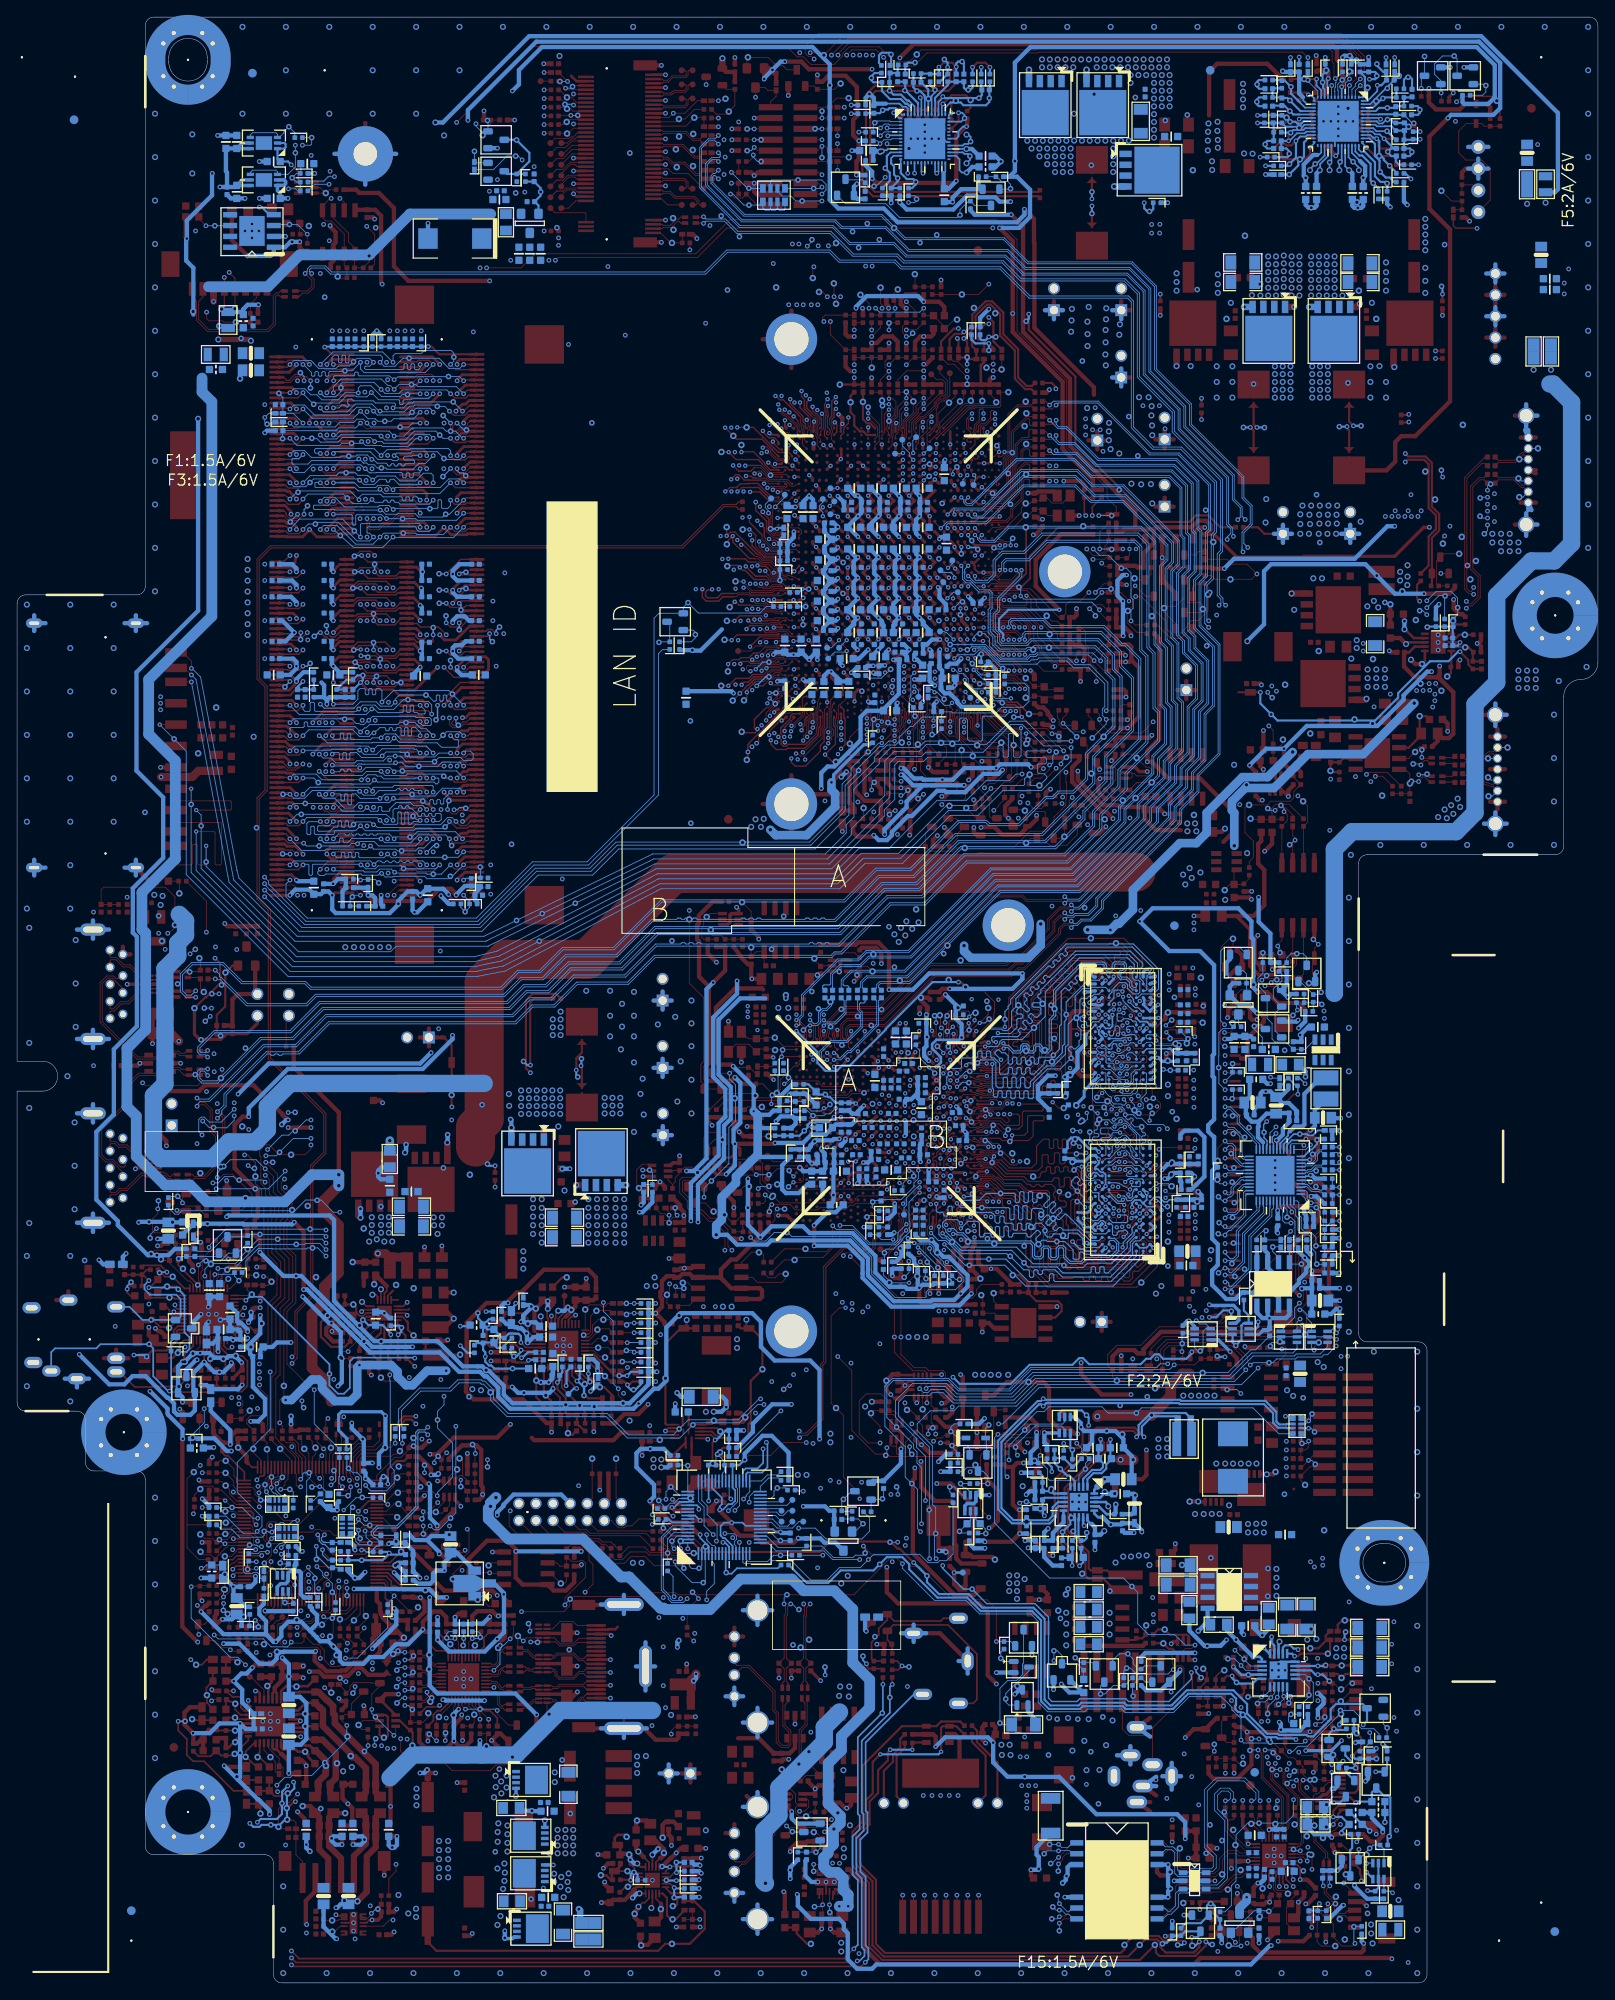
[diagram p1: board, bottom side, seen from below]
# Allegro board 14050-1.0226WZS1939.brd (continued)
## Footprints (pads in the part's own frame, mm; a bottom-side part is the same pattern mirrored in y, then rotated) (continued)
C402H20
  custom 0.152x0.152 smd: 1(0,0.445) 2(0,-0.445)
C402H22
  custom 0.152x0.152 smd: 1(0,0.445) 2(0,-0.445)
C603H35
  custom 0.216x0.216 smd: 1(0,0.762) 2(0,-0.762)
C603H36
  custom 0.216x0.216 smd: 1(0,0.762) 2(0,-0.762)
C603H38
  custom 0.216x0.216 smd: 1(0,0.762) 2(0,-0.762)
C603H40
  custom 0.216x0.216 smd: 1(0,0.762) 2(0,-0.762)
C805H50
  rect 1.397x1.143 smd: 1(0,0.965) 2(0,-0.965)
C805H54
  rect 1.397x1.143 smd: 1(0,0.965) 2(0,-0.965)
C805H58
  rect 1.397x1.143 smd: 1(0,0.965) 2(0,-0.965)
C1206H71
  rect 1.651x1.27 smd: 1(0,1.397) 2(0,-1.397)
C1206H75
  rect 1.651x1.27 smd: 1(0,1.397) 2(0,-1.397)
C1808H87
  rect 2.286x1.27 smd: 1(0,2.032) 2(0,-2.032)
CI1410M1HRL-NH
  rect 0.61x1.549 smd: 1(-4.5,3.325) 2(-3.5,3.325) 3(-2.5,3.325) 4(-1.5,3.325) 5(-0.5,3.325) 6(0.5,3.325) 7(1.5,3.325) 8(2.5,3.325) 9(3.5,3.325) 10(4.5,3.325)
  rect 0.61x1.194 smd: 11(-5.6,0) 12(5.6,0)
CI2505P1H00-LF-U
  round 1.422 hole 1.016: 1(-5,0) 2(-2.5,0) 3(0,0) 4(2.5,0) 5(5,0)
CON2C
  custom 0.171x0.171 smd: 1(0,0.533) 2(0,-0.533)
CON2C-U
  custom 0.171x0.171 smd: 1(0,0.533) 2(0,-0.533)
CT7343H75
  rect 2.413x2.286 smd: 1(0,3.15) 2(0,-3.15)
D1608-035030AKH28
  rect 0.559x0.991 smd: A(0,0.691) K(0,-0.691)
D4724AKH44
  rect 2.007x1.549 smd: A(0,2.221) K(0,-2.221)
DFN6F2030-G1619H26
  rect 0.406x0.838 smd: 1(0.65,1.589) 2(0,1.589) 3(-0.65,1.589) 4(-0.65,-1.589) 5(0,-1.589) 6(0.65,-1.589)
  rect 1.6x1.93 smd: 7(0,0)
DFN10G3-G265175H32
  rect 0.305x0.914 smd: 1(1,1.549) 2(0.5,1.549) 3(0,1.549) 4(-0.5,1.549) 5(-1,1.549) 6(-1,-1.549) 7(-0.5,-1.549) 8(0,-1.549) 9(0.5,-1.549) 10(1,-1.549)
  rect 2.642x1.753 smd: 11(0,0)
DFN10G2510H26
  rect 0.305x0.787 smd: 1(1,0.494) 5(-1,0.494) 6(-1,-0.494) 10(1,-0.494)
  rect 0.254x0.787 smd: 2(0.521,0.494) 4(-0.521,0.494) 7(-0.521,-0.494) 9(0.521,-0.494)
  rect 0.025x0.025 smd: 3(0,0.494)
  rect 0.406x1.753 smd: 8(0,-0.494)
DO214AAAK-1121H97
  rect 2.311x2.032 smd: A(0,2.322) K(0,-2.322)
ECAP-100D6D3H237
  rect 1.397x1.397 hole 0.991: 1(0,-1.27)
  round 1.397 hole 0.991: 2(0,1.27)
ECAP-100D6D3H355
  rect 1.397x1.397 hole 0.991: 1(0,-1.27)
  round 1.397 hole 0.991: 2(0,1.27)
ECAP-100D6D3H375
  rect 1.397x1.397 hole 0.991: 1(0,-1.27)
  round 1.397 hole 0.991: 2(0,1.27)
FUSE-1608H22
  custom 0.216x0.216 smd: 1(0,0.762) 2(0,-0.762)
GAP-CLOSE-PWR
  rect 0.66x0.762 smd: 1(-0.305,0) 2(0.305,0)
GAP-CLOSE-PWR-3
  rect 0.66x0.762 smd: 1(-0.305,0) 2(0.305,0)
GEN8D5X8R5X4D5-8-F-A
  round 0.254 hole 5.004x4.521 unplated: (0,0)
  round 0.864 hole 0.508: 1(3.136,1.664) 2(1.918,2.882) 3(-1.918,2.882) 4(-3.136,1.664) 5(-3.136,-1.664) 6(-1.918,-2.882) 7(1.918,-2.882) 8(3.136,-1.664)
GEN315R138-8-F-A-1
  round 0.254 hole 3.505 unplated: (0,0)
  round 0.864 hole 0.508: 1(2.667,1.54) 2(1.54,2.667) 3(-1.54,2.667) 4(-2.667,1.54) 5(-2.667,-1.54) 6(-1.54,-2.667) 7(1.54,-2.667) 8(2.667,-1.54)
GEN315R178-8-F-A-1
  round 0.254 hole 4.521 unplated: (0,0)
  round 0.864 hole 0.508: 1(2.882,1.664) 2(1.664,2.882) 3(-1.664,2.882) 4(-2.882,1.664) 5(-2.882,-1.664) 6(-1.664,-2.882) 7(1.664,-2.882) 8(2.882,-1.664)
HF1804H
  round 1.651 hole 1.016: 1(-3.81,0) 2(-1.27,0) 3(1.27,0) 4(3.81,0)
HL5507F
  round 0.254 hole 1.016 unplated: (5,0)
  round 1.321 hole 0.914: 1(-6,-1) 2(-6,1) 3(-4,-1) 4(-4,1) 5(-2,-1) 6(-2,1) 7(0,-1) 8(0,1) 9(2,-1) 10(2,1) 11(4,-1) 12(4,1) 13(6,-1) 14(6,1)
HOLE237R158
  round 6.02 hole 4.013: 1(0,0)
JAC331-0140A8B-9H
  oval 1.321x2.235 hole 0.61x1.524: 1(-4.95,2.1) 4(5,2.1) P(3.25,-3.15) Q(-3.9,-2.1)
  oval 2.235x1.422 hole 1.524x0.711: 5(0,3.17)
L402H22
  custom 0.14x0.14 smd: 1(0,0.445) 2(0,-0.445)
L402H24
  custom 0.14x0.14 smd: 1(0,0.445) 2(0,-0.445)
L603H38
  custom 0.216x0.216 smd: 1(0,0.762) 2(0,-0.762)
L1608-UH38
  custom 0.216x0.216 smd: 1(0,0.762) 2(0,-0.762)
L3030-2709H41
  rect 2.946x1.778 smd: 1(0,1.235) 2(0,-1.235)
L7066-1830-UH119
  rect 3.505x2.921 smd: 1(0,2.78) 2(0,-2.78)
L8080-6522-1H166
  rect 7.036x3.327 smd: 1(0,3.108) 2(0,-3.108)
L20125H42
  rect 1.397x1.143 smd: 1(0,0.965) 2(0,-0.965)
L115100-2H158
  rect 3.759x3.251 smd: 1(0,5.022) 2(0,-5.022)
L125100-4P-1H28
  rect 0.762x0.432 smd: 1(0.625,0.341) 2(-0.625,0.341) 3(-0.625,-0.341) 4(0.625,-0.341)
L125100-4P-1H36
  rect 0.762x0.432 smd: 1(0.625,0.341) 2(-0.625,0.341) 3(-0.625,-0.341) 4(0.625,-0.341)
L125100-4P-1H37
  rect 0.762x0.432 smd: 1(0.625,0.341) 2(-0.625,0.341) 3(-0.625,-0.341) 4(0.625,-0.341)
L686647-127318H119
  rect 3.683x2.413 smd: 1(0,2.986) 2(0,-2.986)
L686647H119
  rect 2.159x3.429 smd: 1(-3.111,0) 2(3.111,0)
LED1608AKH30
  custom 0.216x0.216 smd: A(0,0.762) K(0,-0.762)
LFCSP52J6-G4D8H40
  rect 0.203x0.356 smd: 1(2.4,2.812) 13(-2.4,2.812) 27(-2.4,-2.812) 39(2.4,-2.812)
  rect 0.203x0.381 smd: 2(2,2.812) 3(1.6,2.812) 4(1.2,2.812) 5(0.8,2.812) 6(0.4,2.812) 7(0,2.812) 8(-0.4,2.812) 9(-0.8,2.812) 10(-1.2,2.812) 11(-1.6,2.812) 12(-2,2.812) 28(-2,-2.812) 29(-1.6,-2.812) 30(-1.2,-2.812) 31(-0.8,-2.812) 32(-0.4,-2.812) 33(0,-2.812) 34(0.4,-2.812) 35(0.8,-2.812) 36(1.2,-2.812) 37(1.6,-2.812) 38(2,-2.812)
  rect 0.356x0.203 smd: 14(-2.812,2.4) 26(-2.812,-2.4) 40(2.812,-2.4) 52(2.812,2.4)
  rect 0.381x0.203 smd: 15(-2.812,2) 16(-2.812,1.6) 17(-2.812,1.2) 18(-2.812,0.8) 19(-2.812,0.4) 20(-2.812,0) 21(-2.812,-0.4) 22(-2.812,-0.8) 23(-2.812,-1.2) 24(-2.812,-1.6) 25(-2.812,-2) 41(2.812,-2) 42(2.812,-1.6) 43(2.812,-1.2) 44(2.812,-0.8) 45(2.812,-0.4) 46(2.812,0) 47(2.812,0.4) 48(2.812,0.8) 49(2.812,1.2) 50(2.812,1.6) 51(2.812,2)
  rect 4.801x4.801 smd: 53(0,0)
LGA16G3-1H40
  rect 0.305x0.559 smd: 1(1,1.221) 2(0.5,1.221) 3(0,1.221) 4(-0.5,1.221) 5(-1,1.221) 9(-1,-1.221) 10(-0.5,-1.221) 11(0,-1.221) 12(0.5,-1.221) 13(1,-1.221)
  rect 0.559x0.305 smd: 6(-1.221,0.5) 7(-1.221,0) 8(-1.221,-0.5) 14(1.221,-0.5) 15(1.221,0) 16(1.221,0.5)
LQFP64H63
  rect 0.203x1.524 smd: 1(3,4.242) 2(2.6,4.242) 3(2.2,4.242) 4(1.8,4.242) 5(1.4,4.242) 6(0.999,4.242) 7(0.599,4.242) 8(0.199,4.242) 9(-0.199,4.242) 10(-0.599,4.242) 11(-0.999,4.242) 12(-1.4,4.242) 13(-1.8,4.242) 14(-2.2,4.242) 15(-2.6,4.242) 16(-3,4.242) 33(-3,-4.242) 34(-2.6,-4.242) 35(-2.2,-4.242) 36(-1.8,-4.242) 37(-1.4,-4.242) 38(-0.999,-4.242) 39(-0.599,-4.242) 40(-0.199,-4.242) 41(0.199,-4.242) 42(0.599,-4.242) 43(0.999,-4.242) 44(1.4,-4.242) 45(1.8,-4.242) 46(2.2,-4.242) 47(2.6,-4.242) 48(3,-4.242)
  rect 1.524x0.203 smd: 17(-4.242,3) 18(-4.242,2.6) 19(-4.242,2.2) 20(-4.242,1.8) 21(-4.242,1.4) 22(-4.242,0.999) 23(-4.242,0.599) 24(-4.242,0.199) 25(-4.242,-0.199) 26(-4.242,-0.599) 27(-4.242,-0.999) 28(-4.242,-1.4) 29(-4.242,-1.8) 30(-4.242,-2.2) 31(-4.242,-2.6) 32(-4.242,-3) 49(4.242,-3) 50(4.242,-2.6) 51(4.242,-2.2) 52(4.242,-1.8) 53(4.242,-1.4) 54(4.242,-0.999) 55(4.242,-0.599) 56(4.242,-0.199) 57(4.242,0.199) 58(4.242,0.599) 59(4.242,0.999) 60(4.242,1.4) 61(4.242,1.8) 62(4.242,2.2) 63(4.242,2.6) 64(4.242,3)
LQFP128H63
  rect 0.203x1.524 smd: 1(6.2,7.747) 2(5.8,7.747) 3(5.4,7.747) 4(5,7.747) 5(4.6,7.747) 6(4.2,7.747) 7(3.8,7.747) 8(3.4,7.747) 9(3,7.747) 10(2.6,7.747) 11(2.2,7.747) 12(1.8,7.747) 13(1.4,7.747) 14(0.999,7.747) 15(0.599,7.747) 16(0.199,7.747) 17(-0.199,7.747) 18(-0.599,7.747) 19(-0.999,7.747) 20(-1.4,7.747) 21(-1.8,7.747) 22(-2.2,7.747) 23(-2.6,7.747) 24(-3,7.747) 25(-3.4,7.747) 26(-3.8,7.747) 27(-4.2,7.747) 28(-4.6,7.747) 29(-5,7.747) 30(-5.4,7.747) 31(-5.8,7.747) 32(-6.2,7.747) 65(-6.2,-7.747) 66(-5.8,-7.747) 67(-5.4,-7.747) 68(-5,-7.747) 69(-4.6,-7.747) 70(-4.2,-7.747) 71(-3.8,-7.747) 72(-3.4,-7.747) 73(-3,-7.747) 74(-2.6,-7.747) 75(-2.2,-7.747) 76(-1.8,-7.747) 77(-1.4,-7.747) 78(-0.999,-7.747) 79(-0.599,-7.747) 80(-0.199,-7.747) 81(0.199,-7.747) 82(0.599,-7.747) 83(0.999,-7.747) 84(1.4,-7.747) 85(1.8,-7.747) 86(2.2,-7.747) 87(2.6,-7.747) 88(3,-7.747) 89(3.4,-7.747) 90(3.8,-7.747) 91(4.2,-7.747) 92(4.6,-7.747) 93(5,-7.747) 94(5.4,-7.747) 95(5.8,-7.747) 96(6.2,-7.747)
  rect 1.524x0.203 smd: 33(-7.747,6.2) 34(-7.747,5.8) 35(-7.747,5.4) 36(-7.747,5) 37(-7.747,4.6) 38(-7.747,4.2) 39(-7.747,3.8) 40(-7.747,3.4) 41(-7.747,3) 42(-7.747,2.6) 43(-7.747,2.2) 44(-7.747,1.8) 45(-7.747,1.4) 46(-7.747,0.999) 47(-7.747,0.599) 48(-7.747,0.199) 49(-7.747,-0.199) 50(-7.747,-0.599) 51(-7.747,-0.999) 52(-7.747,-1.4) 53(-7.747,-1.8) 54(-7.747,-2.2) 55(-7.747,-2.6) 56(-7.747,-3) 57(-7.747,-3.4) 58(-7.747,-3.8) 59(-7.747,-4.2) 60(-7.747,-4.6) 61(-7.747,-5) 62(-7.747,-5.4) 63(-7.747,-5.8) 64(-7.747,-6.2) 97(7.747,-6.2) 98(7.747,-5.8) 99(7.747,-5.4) 100(7.747,-5) 101(7.747,-4.6) 102(7.747,-4.2) 103(7.747,-3.8) 104(7.747,-3.4) 105(7.747,-3) 106(7.747,-2.6) 107(7.747,-2.2) 108(7.747,-1.8) 109(7.747,-1.4) 110(7.747,-0.999) 111(7.747,-0.599) 112(7.747,-0.199) 113(7.747,0.199) 114(7.747,0.599) 115(7.747,0.999) 116(7.747,1.4) 117(7.747,1.8) 118(7.747,2.2) 119(7.747,2.6) 120(7.747,3) 121(7.747,3.4) 122(7.747,3.8) 123(7.747,4.2) 124(7.747,4.6) 125(7.747,5) 126(7.747,5.4) 127(7.747,5.8) 128(7.747,6.2)
LVDFH-02004-TP00
  rect 0.305x1.295 smd: 1(-4.75,-1.95) 2(-4.25,-1.95) 3(-3.75,-1.95) 4(-3.25,-1.95) 5(-2.75,-1.95) 6(-2.25,-1.95) 7(-1.75,-1.95) 8(-1.25,-1.95) 9(-0.75,-1.95) 10(-0.25,-1.95) 11(0.25,-1.95) 12(0.75,-1.95) 13(1.25,-1.95) 14(1.75,-1.95) 15(2.25,-1.95) 16(2.75,-1.95) 17(3.25,-1.95) 18(3.75,-1.95) 19(4.25,-1.95) 20(4.75,-1.95)
  rect 1.194x2.692 smd: 21(-7.15,0) 22(7.15,0)
  rect 2.261x1.346 smd: 23(3.9,1.975) 24(0,1.975) 25(-3.9,1.975)
NTC-402H22-U
  custom 0.14x0.14 smd: 1(0,0.445) 2(0,-0.445)
NTC-402H24-U
  custom 0.14x0.14 smd: 1(0,0.445) 2(0,-0.445)
OSC-3225-4P-4H30
  rect 1.397x1.067 smd: 1(-1.171,-0.756) 2(1.171,-0.756) 3(1.171,0.756) 4(-1.171,0.756)
OSC-3225-4P-4H36
  rect 1.397x1.067 smd: 1(-1.171,-0.756) 2(1.171,-0.756) 3(1.171,0.756) 4(-1.171,0.756)
POLYSW-2114H30
  rect 1.6x0.965 smd: 1(0,0.94) 2(0,-0.94)
PPAK-8P-3232H36
  rect 0.406x0.914 smd: 1(-0.975,-2.396) 2(-0.325,-2.396) 3(0.325,-2.396) 4(0.975,-2.396)
  rect 3.353x2.692 smd: 5(0,0)
  rect 0.025x0.025 smd: 6(0.65,0.838) 7(0,0.838) 8(-0.65,0.838)
PPAK-8P-5262H40
  rect 0.762x1.448 smd: 1(-1.905,-3.684) 2(-0.635,-3.684) 3(0.635,-3.684) 4(1.905,-3.684)
  rect 5.512x5.309 smd: 5(0,0)
  rect 0.025x0.025 smd: 6(0.635,2.146) 7(-0.635,2.146) 8(-1.905,2.146)
QFN16J3H24
  rect 0.254x1.422 smd: 1(0.525,1.297) 2(-0.175,1.297) 8(-0.525,-1.297) 9(0.175,-1.297)
  rect 1.092x0.203 smd: 3(-1.462,0.8) 4(-1.462,0.4) 5(-1.462,0) 6(-1.462,-0.4) 7(-1.462,-0.8) 10(1.462,-0.8) 11(1.462,-0.4) 12(1.462,0) 13(1.462,0.4) 14(1.462,0.8)
  rect 0.203x0.66 smd: 15(0.165,0) 16(-0.435,0)
QFN20-G1D75H32
  rect 0.203x0.914 smd: 1(0.8,1.551) 2(0.4,1.551) 3(0,1.551) 4(-0.4,1.551) 5(-0.8,1.551) 11(-0.8,-1.551) 12(-0.4,-1.551) 13(0,-1.551) 14(0.4,-1.551) 15(0.8,-1.551)
  rect 0.914x0.203 smd: 6(-1.551,0.8) 7(-1.551,0.4) 8(-1.551,0) 9(-1.551,-0.4) 10(-1.551,-0.8) 16(1.551,-0.8) 17(1.551,-0.4) 18(1.551,0) 19(1.551,0.4) 20(1.551,0.8)
  rect 1.753x1.753 smd: 21(0,0)
QFN20-G2D1H32
  rect 0.305x1.092 smd: 1(0.999,1.956) 5(-0.999,1.956) 11(-0.999,-1.956) 15(0.999,-1.956)
  rect 0.305x1.143 smd: 2(0.5,1.93) 3(0,1.93) 4(-0.5,1.93) 12(-0.5,-1.93) 13(0,-1.93) 14(0.5,-1.93)
  rect 1.092x0.305 smd: 6(-1.956,0.999) 10(-1.956,-0.999) 16(1.956,-0.999) 20(1.956,0.999)
  rect 1.143x0.305 smd: 7(-1.93,0.5) 8(-1.93,0) 9(-1.93,-0.5) 17(1.93,-0.5) 18(1.93,0) 19(1.93,0.5)
  rect 2.108x2.108 smd: 21(0,0)
QFN20G3D5-G2D15H40
  rect 0.305x0.914 smd: 1(1,1.801) 5(-1,1.801) 11(-1,-1.801) 15(1,-1.801)
  rect 0.305x0.965 smd: 2(0.5,1.775) 3(0,1.775) 4(-0.5,1.775) 12(-0.5,-1.775) 13(0,-1.775) 14(0.5,-1.775)
  rect 0.914x0.305 smd: 6(-1.801,1) 10(-1.801,-1) 16(1.801,-1) 20(1.801,1)
  rect 0.965x0.305 smd: 7(-1.775,0.5) 8(-1.775,0) 9(-1.775,-0.5) 17(1.775,-0.5) 18(1.775,0) 19(1.775,0.5)
  rect 2.159x2.159 smd: 21(0,0)
QFN32-G3D55H40
  rect 0.305x0.838 smd: 1(1.75,2.591) 8(-1.75,2.591) 17(-1.75,-2.591) 24(1.75,-2.591)
  rect 0.305x0.94 smd: 2(1.25,2.54) 3(0.751,2.54) 4(0.25,2.54) 5(-0.25,2.54) 6(-0.751,2.54) 7(-1.25,2.54) 18(-1.25,-2.54) 19(-0.751,-2.54) 20(-0.25,-2.54) 21(0.25,-2.54) 22(0.751,-2.54) 23(1.25,-2.54)
  rect 0.838x0.305 smd: 9(-2.591,1.75) 16(-2.591,-1.75) 25(2.591,-1.75) 32(2.591,1.75)
  rect 0.94x0.305 smd: 10(-2.54,1.25) 11(-2.54,0.751) 12(-2.54,0.25) 13(-2.54,-0.25) 14(-2.54,-0.751) 15(-2.54,-1.25) 26(2.54,-1.25) 27(2.54,-0.751) 28(2.54,-0.25) 29(2.54,0.25) 30(2.54,0.751) 31(2.54,1.25)
  rect 3.531x3.531 smd: 33(0,0)
QFN32J4-G2D85H36
  rect 0.203x0.864 smd: 1(1.4,2.085) 2(1,2.085) 3(0.6,2.085) 4(0.2,2.085) 5(-0.2,2.085) 6(-0.6,2.085) 7(-1,2.085) 8(-1.4,2.085) 17(-1.4,-2.085) 18(-1,-2.085) 19(-0.6,-2.085) 20(-0.2,-2.085) 21(0.2,-2.085) 22(0.6,-2.085) 23(1,-2.085) 24(1.4,-2.085)
  rect 0.864x0.203 smd: 9(-2.085,1.4) 10(-2.085,1) 11(-2.085,0.6) 12(-2.085,0.2) 13(-2.085,-0.2) 14(-2.085,-0.6) 15(-2.085,-1) 16(-2.085,-1.4) 25(2.085,-1.4) 26(2.085,-1) 27(2.085,-0.6) 28(2.085,-0.2) 29(2.085,0.2) 30(2.085,0.6) 31(2.085,1) 32(2.085,1.4)
  rect 2.845x2.845 smd: 33(0,0)
QFN40-G3D5H32
  rect 0.203x0.914 smd: 1(1.8,2.553) 10(-1.8,2.553) 21(-1.8,-2.553) 30(1.8,-2.553)
  rect 0.203x0.965 smd: 2(1.4,2.527) 3(1,2.527) 4(0.6,2.527) 5(0.2,2.527) 6(-0.2,2.527) 7(-0.6,2.527) 8(-1,2.527) 9(-1.4,2.527) 22(-1.4,-2.527) 23(-1,-2.527) 24(-0.6,-2.527) 25(-0.2,-2.527) 26(0.2,-2.527) 27(0.6,-2.527) 28(1,-2.527) 29(1.4,-2.527)
  rect 0.914x0.203 smd: 11(-2.553,1.8) 20(-2.553,-1.8) 31(2.553,-1.8) 40(2.553,1.8)
  rect 0.965x0.203 smd: 12(-2.527,1.4) 13(-2.527,1) 14(-2.527,0.6) 15(-2.527,0.2) 16(-2.527,-0.2) 17(-2.527,-0.6) 18(-2.527,-1) 19(-2.527,-1.4) 32(2.527,-1.4) 33(2.527,-1) 34(2.527,-0.6) 35(2.527,-0.2) 36(2.527,0.2) 37(2.527,0.6) 38(2.527,1) 39(2.527,1.4)
  rect 3.505x3.505 smd: 41(0,0)
QFN40J5-G3D65H32
  rect 0.203x0.94 smd: 1(1.8,2.538) 10(-1.8,2.538) 21(-1.8,-2.538) 30(1.8,-2.538)
  rect 0.203x0.965 smd: 2(1.4,2.526) 3(1,2.526) 4(0.6,2.526) 5(0.2,2.526) 6(-0.2,2.526) 7(-0.6,2.526) 8(-1,2.526) 9(-1.4,2.526) 22(-1.4,-2.526) 23(-1,-2.526) 24(-0.6,-2.526) 25(-0.2,-2.526) 26(0.2,-2.526) 27(0.6,-2.526) 28(1,-2.526) 29(1.4,-2.526)
  rect 0.94x0.203 smd: 11(-2.538,1.8) 20(-2.538,-1.8) 31(2.538,-1.8) 40(2.538,1.8)
  rect 0.965x0.203 smd: 12(-2.526,1.4) 13(-2.526,1) 14(-2.526,0.6) 15(-2.526,0.2) 16(-2.526,-0.2) 17(-2.526,-0.6) 18(-2.526,-1) 19(-2.526,-1.4) 32(2.526,-1.4) 33(2.526,-1) 34(2.526,-0.6) 35(2.526,-0.2) 36(2.526,0.2) 37(2.526,0.6) 38(2.526,1) 39(2.526,1.4)
  rect 3.658x3.658 smd: 41(0,0)
QFN48J6-G4D55H40
  rect 0.203x1.016 smd: 1(2.2,3) 2(1.8,3) 3(1.4,3) 4(1,3) 5(0.6,3) 6(0.2,3) 7(-0.2,3) 8(-0.6,3) 9(-1,3) 10(-1.4,3) 11(-1.8,3) 12(-2.2,3) 25(-2.2,-3) 26(-1.8,-3) 27(-1.4,-3) 28(-1,-3) 29(-0.6,-3) 30(-0.2,-3) 31(0.2,-3) 32(0.6,-3) 33(1,-3) 34(1.4,-3) 35(1.8,-3) 36(2.2,-3)
  rect 1.016x0.203 smd: 13(-3,2.2) 14(-3,1.8) 15(-3,1.4) 16(-3,1) 17(-3,0.6) 18(-3,0.2) 19(-3,-0.2) 20(-3,-0.6) 21(-3,-1) 22(-3,-1.4) 23(-3,-1.8) 24(-3,-2.2) 37(3,-2.2) 38(3,-1.8) 39(3,-1.4) 40(3,-1) 41(3,-0.6) 42(3,-0.2) 43(3,0.2) 44(3,0.6) 45(3,1) 46(3,1.4) 47(3,1.8) 48(3,2.2)
  rect 4.547x4.547 smd: 49(0,0)
QFN48J6-G465H40
  rect 0.203x0.965 smd: 1(2.2,3.025) 2(1.8,3.025) 3(1.4,3.025) 4(1,3.025) 5(0.6,3.025) 6(0.2,3.025) 7(-0.2,3.025) 8(-0.6,3.025) 9(-1,3.025) 10(-1.4,3.025) 11(-1.8,3.025) 12(-2.2,3.025) 25(-2.2,-3.025) 26(-1.8,-3.025) 27(-1.4,-3.025) 28(-1,-3.025) 29(-0.6,-3.025) 30(-0.2,-3.025) 31(0.2,-3.025) 32(0.6,-3.025) 33(1,-3.025) 34(1.4,-3.025) 35(1.8,-3.025) 36(2.2,-3.025)
  rect 0.965x0.203 smd: 13(-3.025,2.2) 14(-3.025,1.8) 15(-3.025,1.4) 16(-3.025,1) 17(-3.025,0.6) 18(-3.025,0.2) 19(-3.025,-0.2) 20(-3.025,-0.6) 21(-3.025,-1) 22(-3.025,-1.4) 23(-3.025,-1.8) 24(-3.025,-2.2) 37(3.025,-2.2) 38(3.025,-1.8) 39(3.025,-1.4) 40(3.025,-1) 41(3.025,-0.6) 42(3.025,-0.2) 43(3.025,0.2) 44(3.025,0.6) 45(3.025,1) 46(3.025,1.4) 47(3.025,1.8) 48(3.025,2.2)
  rect 4.648x4.648 smd: 49(0,0)
R402H14
  custom 0.14x0.14 smd: 1(0,0.445) 2(0,-0.445)
R402H15
  custom 0.14x0.14 smd: 1(0,0.445) 2(0,-0.445)
R402H16
  custom 0.14x0.14 smd: 1(0,0.445) 2(0,-0.445)
R603H22
  custom 0.216x0.216 smd: 1(0,0.762) 2(0,-0.762)
R805H24
  rect 1.397x1.143 smd: 1(0,0.965) 2(0,-0.965)
R1206H26
  rect 1.651x1.27 smd: 1(0,1.397) 2(0,-1.397)
R1206H28
  rect 1.651x1.27 smd: 1(0,1.397) 2(0,-1.397)
R3720H40
  rect 4.013x1.041 smd: 1(0,0.867) 2(0,-0.867)
SE331721H237
  rect 1.422x3.556 smd: 1(0,2.574) 2(0,-2.574)
SE361414H241
  rect 1.372x3.607 smd: 1(0,2.499) 2(0,-2.499)
SE361416H237
  rect 1.422x3.556 smd: 1(0,2.574) 2(0,-2.574)
SKT-HDMI22-150077
  rect 0.305x2.007 smd: 1(4.21,3.37) 2(3.71,3.37) 3(3.21,3.37) 4(2.71,3.37) 5(2.21,3.37) 6(1.71,3.37) 7(1.21,3.37) 8(0.71,3.37) 9(0.21,3.37) 10(-0.29,3.37) 11(-0.79,3.37) 12(-1.29,3.37) 13(-1.79,3.37) 14(-2.29,3.37) 15(-2.79,3.37) 16(-3.29,3.37) 17(-3.79,3.37) 18(-4.29,3.37) 19(-4.79,3.37)
  oval 4.928x1.524 hole 4.216x0.813: 20(0,-2.53)
  oval 1.524x4.674 hole 0.813x3.962: 21(-7.25,0) 22(7.25,0)
SKT-SOIC8-092117H235
  rect 0.508x1.702 smd: 1(1.905,4.1) 2(0.635,4.1) 3(-0.635,4.1) 4(-1.905,4.1) 5(-1.905,-4.1) 6(-0.635,-4.1) 7(0.635,-4.1) 8(1.905,-4.1)
SKT-USB6-135063
  round 1.346 hole 0.94: 1(3.5,-2.71) 2(1,-2.71) 3(-1,-2.71) 4(-3.5,-2.71)
  round 2.718 hole 2.311: 5(6.57,0) 6(-6.57,0)
SKT-USB11-138165-1
  round 1.067 hole 0.711: 1(3.5,3.5) 2(1,3.5) 3(-1,3.5) 4(-3.5,3.5) 5(-4,2) 6(-2,2) 7(0,2) 8(2,2) 9(4,2)
  oval 1.422x3.023 hole 0.711x2.311: 10(-6.4,0) 11(6.4,0)
SMD49-6914-0403H56
  rect 1.168x0.559 smd: 1(-3.38,-0.427) 2(3.38,-0.427) 3(3.38,0.427) 4(-3.38,0.427)
SMD-ARES8-1H26
  rect 0.686x1.016 smd: 1(-1.295,-0.787) 4(1.295,-0.787) 5(1.295,0.787) 8(-1.295,0.787)
  rect 0.508x1.016 smd: 2(-0.406,-0.787) 3(0.406,-0.787) 6(0.406,0.787) 7(-0.406,0.787)
SOD80CH36
  rect 0.762x1.168 smd: 1(0,1.067) 2(0,-1.067)
SOD323AKH38
  rect 0.559x1.016 smd: A(0,1.143) K(0,-1.143)
SOD323AKH42
  rect 0.559x1.016 smd: A(0,1.143) K(0,-1.143)
SOD523AKH28
  rect 0.559x1.016 smd: A(0,0.762) K(0,-0.762)
SOIC8-1H86
  rect 0.635x1.651 smd: 1(-1.905,-3.493) 2(-0.635,-3.493) 3(0.635,-3.493) 4(1.905,-3.493) 5(1.905,3.493) 6(0.635,3.493) 7(-0.635,3.493) 8(-1.905,3.493)
SOIC8-G3530H63
  rect 0.635x1.651 smd: 1(-1.905,-2.555) 2(-0.635,-2.555) 3(0.635,-2.555) 4(1.905,-2.555) 5(1.905,2.555) 6(0.635,2.555) 7(-0.635,2.555) 8(-1.905,2.555)
  rect 3.505x2.997 smd: 9(0,0)
SOIC8H69
  rect 0.635x1.651 smd: 1(-1.905,-2.54) 2(-0.635,-2.54) 3(0.635,-2.54) 4(1.905,-2.54) 5(1.905,2.54) 6(0.635,2.54) 7(-0.635,2.54) 8(-1.905,2.54)
SON14J3020-G2610H34
  rect 0.025x0.025 smd: 1(1.2,1.105) 6(-0.8,1.105) 9(-0.8,-1.105) 14(1.2,-1.105)
  custom 0.151x0.151 smd: 2(0.8,1.105) 7(-1.2,1.105) 8(-1.2,-1.105) 13(0.8,-1.105)
  rect 0.203x0.813 smd: 3(0.4,1.105) 4(0,1.105) 5(-0.4,1.105) 10(-0.4,-1.105) 11(0,-1.105) 12(0.4,-1.105)
  rect 2.591x0.889 smd: 15(0,0)
SOT23-2D4-312H44
  custom 0.191x0.191 smd: 1(-0.984,-0.953) 2(0.984,-0.953) 3(0,0.953)
SOT23-2D4-312H46
  custom 0.191x0.191 smd: 1(-0.984,-0.953) 2(0.984,-0.953) 3(0,0.953)
SOT23-2D4-312H48
  custom 0.191x0.191 smd: 1(-0.984,-0.953) 2(0.984,-0.953) 3(0,0.953)
SOT23-2D8-312H58
  custom 0.254x0.254 smd: 1(-1.016,-1.118) 2(1.016,-1.118) 3(0,1.118)
SOT23CBE2D4H44
  custom 0.191x0.191 smd: B(-0.984,-0.953) C(0,0.953) E(0.984,-0.953)
SOT23DGS2D4H35
  custom 0.191x0.191 smd: D(0,0.953) G(-0.984,-0.953) S(0.984,-0.953)
SOT23DGS2D4H44
  custom 0.191x0.191 smd: D(0,0.953) G(-0.984,-0.953) S(0.984,-0.953)
SOT23DGS2D4H48
  custom 0.191x0.191 smd: D(0,0.953) G(-0.984,-0.953) S(0.984,-0.953)
SOT23DGS2D8H50
  custom 0.254x0.254 smd: D(0,1.118) G(-1.016,-1.118) S(1.016,-1.118)
SOT323CBE2D2H44
  custom 0.152x0.152 smd: B(-0.65,-0.902) C(0,0.902) E(0.65,-0.902)
SOT-6-1H50
  rect 0.584x1.219 smd: 1(-0.95,-1.194) 2(0,-1.194) 3(0.95,-1.194) 4(0.95,1.194) 5(0,1.194) 6(-0.95,1.194)
SOT-6H44
  rect 0.584x1.016 smd: 1(-0.953,-1.346) 2(0,-1.346) 3(0.953,-1.346) 4(0.953,1.346) 5(0,1.346) 6(-0.953,1.346)
SOT-6H58
  rect 0.584x1.016 smd: 1(-0.953,-1.346) 2(0,-1.346) 3(0.953,-1.346) 4(0.953,1.346) 5(0,1.346) 6(-0.953,1.346)
SOT-23-10H44
  rect 0.762x1.143 smd: 1(-0.984,-0.953) 2(0.984,-0.953) 3(0,0.953)
SOT-89-4541-3PH63
  rect 0.991x1.499 smd: 1(-1.5,0) 3(1.5,0)
  custom 0.502x0.502 smd: 2(0,0)
SOT-363H44
  rect 0.406x1.016 smd: 1(-0.65,-0.94) 2(0,-0.94) 3(0.65,-0.94) 4(0.65,0.94) 5(0,0.94) 6(-0.65,0.94)
SPR10637H367
  rect 10.287x3.404 smd: 1(-2.146,0)
STF256R109H99
  round 6.502 hole 2.769: 1(0,0)
TPAD28
  round 0.711 smd: 1(0,0)
TVS5436-1121H105
  rect 2.337x2.007 smd: 1(0,2.299) 2(0,-2.299)
unnamed#2
  round 0.254 hole 3.505 unplated: (0,0)
XFORM12A127097H91
  rect 0.635x1.524 smd: 1(-4.445,-4.699) 2(-3.175,-4.699) 3(-1.905,-4.699) 4(1.905,-4.699) 5(3.175,-4.699) 6(4.445,-4.699) 7(4.445,4.699) 8(3.175,4.699) 9(1.905,4.699) 10(-1.905,4.699) 11(-3.175,4.699) 12(-4.445,4.699)

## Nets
0.775V_TRACK_GATE: Q6704.3 Q6704.4 R4707.2
3V_5V_POK: PC96.1 PR190.1 R31.2 R77.2 R1762.1
3V_VA: C483.1 C485.1 C493.1 C495.2 L21.2 U6.23 U6.25
19V_AMP_AVCC: C208.1 R376.2 U21.12
19V_AMP_PVCC: C543.1 C545.1 C551.1 C552.1 L10.2 R376.1 U21.13 U21.14 U21.27 U21.28
+1.5V_GPU_PG: PC151.1 PR225.2 PU7.7
+3VL: PG4904.2
+5VL: PG4901.2 PR4918.1
AGND: C134.2 C140.2 C144.2 C145.1 C146.2 C147.1 C154.2 C155.2 C157.2 C159.2 C160.2 C267.2 C268.2 C450.2 C483.2 C485.2 C493.2 C495.1 C1491.2 LOUT1.5 LOUT1.P Q28.S R215.2 R216.2 R221.2 R268.2 R281.2 R300.2 R301.2 R1182.2 R1193.2 U6.22 U6.28 U6.42 UHS1.5
AVCC33_2136: C292.1 C293.1 C298.1 L17.2 U26.5
AVCC_EC: C4102.1 L4101.2 R79721.1 R79723.1 U4101.52
DVCC33_2136: C283.1 C284.1 C289.1 C290.2 C291.1 L16.2 R54.1 R69.1 R1074.1 U26.18 U26.22
GND: AFTP1.1 BAT2.9B BAT2.10B BT1.2 BTRST1.1 C1.2 C2.2 C3.2 C6.2 C7.2 C9.2 C11.2 C14.1 C15.2 C20.2 C32.2 C33.2 C35.2 C36.2 C37.2 C38.2 C39.2 C40.2 C46.2 C48.2 C50.2 C52.2 C55.2 C57.2 C58.2 C60.2 C61.2 C65.1 C66.2 C67.2 C72.2 C73.1 C74.1 C75.2 C76.1 C77.2 C78.2 C84.2 C87.2 C88.2 C95.2 C99.2 C100.2 C101.2 C103.2 C104.2 C105.1 C106.2 C109.2 C110.2 C112.2 C121.1 C126.1 C127.2 C129.2 C131.2 C132.1 C163.2 C170.2 C186.2 C190.2 C194.2 C197.1 C202.2 C204.2 C207.1 C209.2 C213.2 C214.2 C216.2 C222.2 C225.2 C226.2 C227.2 C235.2 C236.2 C238.2 C239.2 C243.2 C247.2 C248.2 C255.2 C256.2 C258.2 C262.2 C263.2 C283.2 C284.2 C289.2 C290.1 C291.2 C292.2 C293.2 C295.2 C296.2 C297.2 C298.2 C299.1 C315.2 C316.1 C326.2 C330.2 C337.2 C353.2 C356.2 C392.2 C395.2 C474.2 C478.2 C486.2 C489.2 C500.2 C509.2 C514.2 C516.2 C521.2 C525.1 C529.2 C531.1 C540.2 C542.2 C543.2 C545.2 C548.1 C549.1 C550.1 C551.2 C552.2 C557.2 C559.2 C562.2 C565.2 C570.2 C572.2 C574.2 C579.2 C580.2 C582.2 C583.2 C584.2 C585.2 C587.2 C589.2 C591.2 C592.2 C593.2 C595.2 C597.2 C612.2 C616.2 C623.2 C627.2 C714.1 C721.1 C752.2 C753.2 C755.1 C756.2 C757.2 C758.2 C759.2 C760.2 C761.2 C762.2 C765.2 C766.2 C767.2 C768.2 C769.2 C770.2 C771.2 C772.2 C773.2 C774.2 C775.2 C776.2 C777.2 C778.2 C779.2 C780.2 C781.2 C782.2 C783.2 C784.2 C785.2 C786.2 C787.2 C788.2 C789.2 C790.2 C791.2 C792.2 C793.2 C794.2 C795.2 C796.2 C797.2 C798.2 C799.2 C800.2 C801.2 C802.2 C803.2 C804.2 C805.2 C806.2 C807.2 C808.2 C809.2 C810.2 C811.2 C812.2 C813.2 C814.2 C815.2 C816.2 C817.2 C818.2 C819.2 C820.2 C821.2 C822.2 C823.2 C824.2 C825.2 C826.2 C827.2 C828.2 C829.2 C830.2 C835.2 C839.2 C852.2 C853.2 C857.2 C859.2 C862.2 C863.2 C864.2 C865.1 C866.2 C869.2 C871.2 C872.2 C1608.2 C1609.1 C1615.2 C1616.2 C1617.2 C1638.2 C1639.2 C1644.2 C1645.2 C1646.2 C1647.2 C1648.2 C1649.2 C1650.2 C1651.2 C1652.2 C1653.2 C1654.2 C1655.2 C1656.2 C1657.2 C1658.2 C1659.2 C1660.2 C1661.2 C1662.2 C1663.2 C1664.2 C1665.2 C1666.2 C1667.2 C1668.2 C1669.2 C1670.2 C1671.2 C1672.2 C1673.2 C1674.2 C1677.2 C1678.2 C1679.2 C1680.2 C1681.2 C1682.2 C1683.2 C1684.2 C1685.2 C1686.2 C1687.2 C1688.2 C1689.2 C1690.2 C1691.2 C1692.2 C1693.2 C1694.2 C1695.2 C1696.2 C1697.2 C1698.2 C1699.2 C1700.2 C1701.2 C1702.2 C1703.2 C1704.2 C1705.2 C1706.2 C1707.2 C1708.2 C1714.2 C1715.2 C1716.2 C1721.1 C1722.1 C1723.2 C1724.2 C1725.2 C1726.2 C1727.1 C1728.2 C1729.2 C1730.2 C1731.1 C1732.2 C1733.1 C1734.2 C1735.2 C1736.2 C1737.1 C1738.2 C1739.2 C1741.2 C1742.2 C1743.2 C1744.2 C1745.2 C1746.1 C1747.2 C1748.1 C1752.1 C1753.1 C1754.1 C1755.2 C1756.2 C1758.1 C1760.2 C1764.1 C1768.1 C1769.2 C1770.2 C1771.2 C1773.2 C1774.2 C1796.2 C1797.2 C1798.2 C1799.2 C1800.2 C1801.2 C1802.2 C1803.2 C1804.2 C1806.2 C1807.2 C1820.1 C1821.2 C1823.2 C1824.2 C1826.1 C1827.2 C1828.2 C1829.2 C1830.2 C1831.2 C1832.2 C1833.2 C1834.2 C1835.2 C1836.2 C1837.2 C1846.2 C1847.2 C1848.2 C1849.1 C1850.2 C1851.2 C1852.2 C1853.2 C1854.2 C1855.1 C1856.2 C1857.2 C1858.2 C1859.2 C1860.2 C1861.2 C1864.1 C1867.2 C1868.2 C1869.2 C1870.1 C1871.2 C1872.2 C1873.2 C1874.2 C1875.2 C1876.2 C1877.2 C1925.2 C1926.2 C1927.2 C1928.2 C1929.2 C1930.2 C1934.2 C1935.2 C1936.2 C1937.2 C1938.2 C1939.2 C1940.2 C1941.2 C1942.2 C1943.2 C1944.2 C1945.2 C1946.2 C1947.2 C1948.2 C1949.2 C1950.2 C1951.2 C1952.2 C1953.2 C1954.2 C1956.2 C1957.2 C1958.2 C1959.2 C1960.2 C1961.2 C1962.2 C1963.2 C1964.2 C1965.2 C1966.2 C1967.2 C1968.2 C1969.2 C1970.2 C1971.2 C1972.2 C1973.2 C1974.2 C1975.2 C1976.2 C1977.2 C1978.2 C1979.1 C1980.1 C1981.1 C1982.1 C3131.2 C3366.2 C3367.2 C3376.1 C3377.2 C3378.2 C3379.2 C3380.1 C3381.1 C3382.2 C3383.2 C3452.2 C3453.2 C3454.2 C3459.2 C3460.2 C4101.1 C4102.2 C6701.2 C6702.2 C6703.2 C6704.1 C6705.2 C6706.2 C6707.2 C6708.2 C6710.2 C6711.2 C6712.2 C6714.2 C6715.2 C6716.2 C6717.2 C6718.2 C6719.2 C6720.2 C6721.2 C6722.1 C6723.2 C6724.1 C6726.2 C6727.2 C6728.2 C6729.2 CONVT1.10 CONVT1.11 CONVT1.12 CPU1.A8 CPU1.A12 CPU1.A16 CPU1.A20 CPU1.A24 CPU1.A28 CPU1.A32 CPU1.AB1 CPU1.AB2 CPU1.AB4 CPU1.AB10 CPU1.AB13 CPU1.AB16 CPU1.AB19 CPU1.AB22 CPU1.AD4 CPU1.AD9 CPU1.AD12 CPU1.AD15 CPU1.AD18 CPU1.AD21 CPU1.AD24 CPU1.AE10 CPU1.AE13 CPU1.AE16 CPU1.AE19 CPU1.AE22 CPU1.AF1 CPU1.AF4 CPU1.AG9 CPU1.AG12 CPU1.AG15 CPU1.AG18 CPU1.AG21 CPU1.AH4 CPU1.AH10 CPU1.AH13 CPU1.AH16 CPU1.AH19 CPU1.AH22 CPU1.AK1 CPU1.AK4 CPU1.AK12 CPU1.AK15 CPU1.AK18 CPU1.AK21 CPU1.AL10 CPU1.AL16 CPU1.AL19 CPU1.AL22 CPU1.AM4 CPU1.AN9 CPU1.AN10 CPU1.AN15 CPU1.AN18 CPU1.AN21 CPU1.AN25 CPU1.AN28 CPU1.AP1 CPU1.AP2 CPU1.AP4 CPU1.AP7 CPU1.AP22 CPU1.AP27 CPU1.AP30 CPU1.AP33 CPU1.AR6 CPU1.AR25 CPU1.AR28 CPU1.AT4 CPU1.AT19 CPU1.AT22 CPU1.AT30 CPU1.AU5 CPU1.AU8 CPU1.AU11 CPU1.AU14 CPU1.AU20 CPU1.AU23 CPU1.AU27 CPU1.AV4 CPU1.AV7 CPU1.AV9 CPU1.AV12 CPU1.AV15 CPU1.AV25 CPU1.AV30 CPU1.AV33 CPU1.AW22 CPU1.AY4 CPU1.AY6 CPU1.AY8 CPU1.AY10 CPU1.AY12 CPU1.AY14 CPU1.AY16 CPU1.AY20 CPU1.AY22 CPU1.AY24 CPU1.AY26 CPU1.AY28 CPU1.AY30 CPU1.B2 CPU1.B8 CPU1.B12 CPU1.B33 CPU1.BB1 CPU1.BB33 CPU1.BC4 CPU1.BC8 CPU1.BC12 CPU1.BC16 CPU1.BC20 CPU1.BC24 CPU1.BC28 CPU1.BC32 CPU1.C3 CPU1.D4 CPU1.D6 CPU1.D8 CPU1.D10 CPU1.D12 CPU1.D14 CPU1.D16 CPU1.D18 CPU1.D20 CPU1.D22 CPU1.D24 CPU1.D26 CPU1.D28 CPU1.D30 CPU1.F1 CPU1.F2 CPU1.F4 CPU1.F9 CPU1.F19 CPU1.F22 CPU1.F25 CPU1.F30 CPU1.F33 CPU1.G7 CPU1.G17 CPU1.G20 CPU1.G23 CPU1.G26 CPU1.H4 CPU1.H30 CPU1.J5 CPU1.J15 CPU1.J19 CPU1.J22 CPU1.J25 CPU1.J28 CPU1.K1 CPU1.K2 CPU1.K4 CPU1.K10 CPU1.K22 CPU1.K27 CPU1.K30 CPU1.K33 CPU1.L5 CPU1.L12 CPU1.L15 CPU1.L18 CPU1.L21 CPU1.L24 CPU1.L25 CPU1.L28 CPU1.M4 CPU1.M30 CPU1.N10 CPU1.N13 CPU1.N16 CPU1.N19 CPU1.N22 CPU1.N27 CPU1.P1 CPU1.P2 CPU1.P4 CPU1.P5 CPU1.P12 CPU1.P15 CPU1.P18 CPU1.P21 CPU1.P30 CPU1.P33 CPU1.T4 CPU1.T10 CPU1.T13 CPU1.T16 CPU1.T19 CPU1.T22 CPU1.T30 CPU1.U5 CPU1.U12 CPU1.U15 CPU1.U18 CPU1.U21 CPU1.U24 CPU1.V1 CPU1.V2 CPU1.V4 CPU1.W10 CPU1.W13 CPU1.W16 CPU1.W19 CPU1.W22 CPU1.Y4 CPU1.Y5 CPU1.Y12 CPU1.Y15 CPU1.Y18 CPU1.Y21 CPU1.Y24 D4.2 D16.A D19.1 D21.A D24.2 DCIN1.2 DCIN1.4 DCIN1.5 DCIN1.6 DCIN1.7 DCIN2.5 DCIN2.6 DCIN2.7 DCIN2.12 DCIN2.13 DCIN2.14 DIMM1.2 DIMM1.3 DIMM1.8 DIMM1.9 DIMM1.13 DIMM1.14 DIMM1.19 DIMM1.20 DIMM1.25 DIMM1.26 DIMM1.31 DIMM1.32 DIMM1.37 DIMM1.38 DIMM1.43 DIMM1.44 DIMM1.48 DIMM1.49 DIMM1.54 DIMM1.55 DIMM1.60 DIMM1.61 DIMM1.65 DIMM1.66 DIMM1.71 DIMM1.72 DIMM1.127 DIMM1.128 DIMM1.133 DIMM1.134 DIMM1.138 DIMM1.139 DIMM1.144 DIMM1.145 DIMM1.150 DIMM1.151 DIMM1.155 DIMM1.156 DIMM1.161 DIMM1.162 DIMM1.167 DIMM1.168 DIMM1.172 DIMM1.173 DIMM1.178 DIMM1.179 DIMM1.184 DIMM1.185 DIMM1.189 DIMM1.190 DIMM1.195 DIMM1.196 DIMM1.205 DIMM1.206 DIMM2.2 DIMM2.3 DIMM2.8 DIMM2.9 DIMM2.13 DIMM2.14 DIMM2.19 DIMM2.20 DIMM2.25 DIMM2.26 DIMM2.31 DIMM2.32 DIMM2.37 DIMM2.38 DIMM2.43 DIMM2.44 DIMM2.48 DIMM2.49 DIMM2.54 DIMM2.55 DIMM2.60 DIMM2.61 DIMM2.65 DIMM2.66 DIMM2.71 DIMM2.72 DIMM2.127 DIMM2.128 DIMM2.133 DIMM2.134 DIMM2.138 DIMM2.139 DIMM2.144 DIMM2.145 DIMM2.150 DIMM2.151 DIMM2.155 DIMM2.156 DIMM2.161 DIMM2.162 DIMM2.167 DIMM2.168 DIMM2.172 DIMM2.173 DIMM2.178 DIMM2.179 DIMM2.184 DIMM2.185 DIMM2.189 DIMM2.190 DIMM2.195 DIMM2.196 DIMM2.205 DIMM2.206 FANC3.1 GPU1.A3 GPU1.A30 GPU1.AA11 GPU1.AA13 GPU1.AA16 GPU1.AA27 GPU1.AB6 GPU1.AB10 GPU1.AB15 GPU1.AB24 GPU1.AB32 GPU1.AC9 GPU1.AC17 GPU1.AC24 GPU1.AC26 GPU1.AC27 GPU1.AD6 GPU1.AD8 GPU1.AD25 GPU1.AD32 GPU1.AE7 GPU1.AE14 GPU1.AE27 GPU1.AF32 GPU1.AG12 GPU1.AG27 GPU1.AH10 GPU1.AH28 GPU1.AH32 GPU1.B6 GPU1.B8 GPU1.B10 GPU1.B12 GPU1.B14 GPU1.B16 GPU1.B18 GPU1.B20 GPU1.B22 GPU1.B24 GPU1.B26 GPU1.C1 GPU1.C32 GPU1.E28 GPU1.F2 GPU1.F6 GPU1.F8 GPU1.F10 GPU1.F12 GPU1.F14 GPU1.F16 GPU1.F18 GPU1.F20 GPU1.F22 GPU1.F24 GPU1.F26 GPU1.G8 GPU1.G10 GPU1.G27 GPU1.G31 GPU1.H2 GPU1.H6 GPU1.H14 GPU1.H17 GPU1.H20 GPU1.J7 GPU1.J27 GPU1.J31 GPU1.K2 GPU1.K6 GPU1.K11 GPU1.K22 GPU1.K28 GPU1.K32 GPU1.L27 GPU1.M6 GPU1.M12 GPU1.M32 GPU1.N11 GPU1.N13 GPU1.N16 GPU1.N18 GPU1.N21 GPU1.N25 GPU1.N27 GPU1.P6 GPU1.P9 GPU1.P25 GPU1.P32 GPU1.R11 GPU1.R12 GPU1.R15 GPU1.R17 GPU1.R20 GPU1.R27 GPU1.T6 GPU1.T11 GPU1.T13 GPU1.T16 GPU1.T18 GPU1.T21 GPU1.T25 GPU1.T32 GPU1.U9 GPU1.U15 GPU1.U17 GPU1.U20 GPU1.U25 GPU1.U27 GPU1.V11 GPU1.V13 GPU1.V16 GPU1.V18 GPU1.V32 GPU1.W25 GPU1.W26 GPU1.W27 GPU1.Y10 GPU1.Y15 GPU1.Y17 GPU1.Y20 GPU1.Y25 GPU1.Y32 H1.1 H2.1 H3.1 H4.1 H5.1 H6.1 H6.2 H6.3 H6.4 H6.5 H6.6 H6.7 H6.8 H7.1 H7.2 H7.3 H7.4 H7.5 H7.6 H7.7 H7.8 H9.1 H9.2 H9.3 H9.4 H9.5 H9.6 H9.7 H9.8 H10.1 H10.2 H10.3 H10.4 H10.5 H10.6 H10.7 H10.8 H11.1 H11.2 H11.3 H11.4 H11.5 H11.6 H11.7 H11.8 HDD1.1 HDD1.4 HDD1.7 HDD1.8 HDD1.9 HDMI1.2 HDMI1.5 HDMI1.8 HDMI1.11 HDMI1.17 HDMI1.20 HDMI1.21 HDMI1.22 HDMI2.3 HDMI2.9 HDMI2.12 HDMI2.15 HDMI2.18 HDMI2.20 HDMI2.21 HDMI2.22 HDMI2.23 HDMI2.24 HDMI2.25 HDT1.3 HDT1.5 HDT1.7 HDT1.17 HS6.1 LED2.K LED3.K LPC1.12 LPC1.14 LVDS1.7 LVDS1.14 LVDS1.31 LVDS1.32 MEM1.A9 MEM1.B1 MEM1.B3 MEM1.B9 MEM1.D1 MEM1.D8 MEM1.E1 MEM1.E2 MEM1.E8 MEM1.F9 MEM1.G1 MEM1.G8 MEM1.G9 MEM1.J2 MEM1.J8 MEM1.M1 MEM1.M9 MEM1.P1 MEM1.P9 MEM1.T1 MEM1.T9 MEM2.A9 MEM2.B1 MEM2.B3 MEM2.B9 MEM2.D1 MEM2.D8 MEM2.E1 MEM2.E2 MEM2.E8 MEM2.F9 MEM2.G1 MEM2.G8 MEM2.G9 MEM2.J2 MEM2.J8 MEM2.M1 MEM2.M9 MEM2.P1 MEM2.P9 MEM2.T1 MEM2.T9 MEM3.A9 MEM3.B1 MEM3.B3 MEM3.B9 MEM3.D1 MEM3.D8 MEM3.E1 MEM3.E2 MEM3.E8 MEM3.F9 MEM3.G1 MEM3.G8 MEM3.G9 MEM3.J2 MEM3.J8 MEM3.M1 MEM3.M9 MEM3.P1 MEM3.P9 MEM3.T1 MEM3.T9 MEM4.A9 MEM4.B1 MEM4.B3 MEM4.B9 MEM4.D1 MEM4.D8 MEM4.E1 MEM4.E2 MEM4.E8 MEM4.F9 MEM4.G1 MEM4.G8 MEM4.G9 MEM4.J2 MEM4.J8 MEM4.M1 MEM4.M9 MEM4.P1 MEM4.P9 MEM4.T1 MEM4.T9 MEMCD1.3 MEMCD1.6 MEMCD1.12 MEMCD1.13 MEMCD1.14 MEMCD1.15 NGFF1.7 NGFF1.18 NGFF1.23 NGFF1.24 NGFF1.29 NGFF1.30 NGFF1.33 NGFF1.36 NGFF1.39 NGFF1.45 NGFF1.57 NGFF1.63 NGFF1.69 NGFF1.75 NGFF1.76 NGFF1.77 ODD1.1 ODD1.4 ODD1.7 ODD1.8 ODD1.9 PC12.2 PC17.2 PC18.2 PC24.2 PC34.2 PC48.2 PC49.2 PC50.2 PC51.2 PC52.2 PC61.2 PC62.2 PC63.2 PC64.2 PC65.2 PC73.2 PC96.2 PC126.1 PC151.2 PC2127.1 PC4301.2 PC4302.2 PC4303.2 PC4304.2 PC4305.2 PC4401.2 PC4405.2 PC4406.2 PC4407.2 PC4602.2 PC4606.2 PC4607.1 PC4608.2 PC4609.1 PC4614.2 PC4616.2 PC4619.1 PC4622.2 PC4701.2 PC4702.2 PC4703.2 PC4705.2 PC4706.2 PC4707.2 PC4708.2 PC4709.2 PC4711.2 PC4712.2 PC4713.2 PC4801.2 PC4802.2 PC4803.2 PC4804.2 PC4808.2 PC4901.2 PC4902.2 PC4903.2 PC4904.2 PC4905.2 PC4906.2 PC4909.2 PC4910.2 PC4912.2 PC4914.1 PC4915.2 PC4916.2 PC4917.2 PC4918.2 PC5001.2 PC5009.2 PC5011.2 PC5012.2 PC5014.2 PC5016.2 PC5017.2 PC5018.2 PC5019.2 PC5020.2 PC5021.2 PC5022.2 PC5202.2 PC5204.2 PC5205.2 PC5209.2 PC5210.2 PC5211.2 PC5212.2 PC5213.2 PC5214.2 PC5233.1 PC5237.2 PC5240.2 PC5241.2 PC5242.2 PC5243.2 PC5245.2 PC5246.2 PC5247.2 PC5248.2 PC5401.2 PC5402.2 PC5403.2 PC5404.2 PC5405.2 PC5413.2 PC5420.2 PC5421.2 PC5422.1 PC5423.1 PC5424.2 PC5427.2 PC5428.2 PC5429.2 PC5430.2 PC5431.2 PC5432.2 PC5433.2 PC5434.2 PC5435.2 PL4301.2 PL4302.2 PL4303.2 PQ4204.E PQ4206.S PQ4406.1 PQ4406.4 PQ4408.S PQ5003.S PQ5004.S PQ5005.1 PQ5005.4 PR2.2 PR3.2 PR7.2 PR26.2 PR29.1 PR31.2 PR33.2 PR36.2 PR38.2 PR40.2 PR77.2 PR4413.1 PR4433.2 PR4451.2 PR4603.2 PR4605.1 PR4610.1 PR4611.1 PR4613.1 PR4614.2 PR4627.2 PR4629.1 PR4630.1 PR4635.2 PR4802.1 PR4806.2 PR4807.2 PR4816.2 PR4917.2 PR4919.2 PR4920.2 PR4922.2 PR4924.2 PR4925.2 PR5009.2 PR5209.2 PR5223.2 PR5251.2 PR5274.1 PR5285.2 PR5292.1 PR5298.2 PR5402.2 PR5411.1 PR5412.2 PR5416.1 PR5419.2 PR5421.1 PR5423.1 PR5472.2 PSWD1.1 PT1.2 PT2.2 PT3.2 PT4.2 PT4701.2 PT4702.2 PT4703.2 PT4704.2 PT4708.2 PT4709.2 PT4712.2 PT4801.2 PT4901.2 PT4902.2 PT4903.2 PT5007.2 PT5401.2 PT5402.2 PT5403.2 PT5405.2 PU3.1 PU3.2 PU3.3 PU4.1 PU5.2 PU5.9 PU7.1 PU4405.1 PU4405.2 PU4405.3 PU4601.32 PU4601.53 PU4703.1 PU4703.2 PU4703.3 PU4704.1 PU4704.2 PU4704.3 PU4705.1 PU4705.2 PU4705.3 PU4706.1 PU4706.2 PU4706.3 PU4801.1 PU4801.2 PU4801.3 PU4803.11 PU4901.21 PU4903.1 PU4903.2 PU4903.3 PU4905.1 PU4905.2 PU4905.3 PU5001.1 PU5001.3 PU5001.14 PU5001.21 PU5007.1 PU5007.2 PU5007.3 PU5201.2 PU5201.5 PU5201.6 PU5201.14 PU5202.1 PU5202.2 PU5202.3 PU5206.1 PU5402.1 PU5402.2 PU5402.3 PU5403.1 PU5403.2 PU5403.3 PU5407.15 PU5407.17 PU5407.19 PU5407.20 PU5407.23 PU5407.24 PU5407.32 PU5407.53 PWRCN1.4 PWRCN1.11 PWRCN1.12 Q1.S Q3.S Q5.S Q10.E Q12.1 Q12.4 Q13.1 Q13.4 Q18.1 Q18.4 Q22.E Q24.3 Q31.E Q36.1 Q36.4 Q37.1 Q37.4 Q38.E Q45.E Q46.3 Q48.E Q50.2 Q51.S Q52.E Q57.3 Q63.1 Q64.S Q65.1 Q65.4 Q68.S Q76.S Q79.S Q97.1 Q97.4 Q100.E Q101.E Q102.E Q103.S Q104.S Q105.S Q107.S Q128.E Q1208.E Q1209.S Q1212.S Q1213.E Q1214.E Q1217.1 Q1217.4 Q1226.1 Q1226.4 Q1227.S Q1240.S Q1241.E Q1244.S Q1245.S Q1246.S Q1247.S Q1248.S Q1249.S Q4701.4 Q6701.1 Q6701.4 Q6702.1 Q6702.4 Q6705.1 Q6705.4 Q9648.S Q9650.S R1.2 R19.2 R27.2 R30.2 R33.2 R37.1 R73.1 R78.2 R107.2 R115.2 R122.2 R132.2 R144.2 R152.2 R154.2 R163.2 R172.2 R178.1 R181.2 R202.1 R210.2 R215.1 R216.1 R299.1 R300.1 R301.1 R320.1 R360.2 R368.2 R370.2 R394.2 R406.2 R412.1 R433.2 R501.2 R507.1 R511.2 R512.2 R513.2 R523.2 R533.2 R542.1 R545.2 R656.2 R666.2 R709.2 R722.2 R732.2 R762.2 R870.1 R886.1 R899.1 R924.1 R940.2 R946.1 R948.2 R963.2 R1079.2 R1158.1 R1179.1 R1182.1 R1193.1 R1201.1 R1205.2 R1206.2 R1207.2 R1209.2 R1210.1 R1592.2 R1603.2 R1604.2 R1605.2 R1606.2 R1607.2 R1608.2 R1609.2 R1619.2 R1623.1 R1629.2 R1631.2 R1635.2 R1644.1 R1648.2 R1649.2 R1658.1 R1660.2 R1663.2 R1670.2 R1685.2 R1688.2 R1690.1 R1691.1 R1700.1 R1702.2 R1703.2 R1705.2 R1707.2 R1709.2 R1724.2 R1727.2 R1729.2 R1779.2 R1781.2 R1782.2 R1817.2 R1819.2 R1834.2 R1848.2 R1850.2 R1853.2 R1867.2 R1869.2 R1871.2 R1873.2 R1880.2 R1881.2 R1882.2 R1886.2 R1888.2 R1889.2 R1894.2 R1897.2 R1899.2 R1905.1 R1911.1 R1914.2 R1917.1 R1919.2 R1921.1 R1923.1 R1988.1 R1999.2 R2001.2 R2003.2 R2004.2 R2008.2 R2056.2 R2058.2 R2060.2 R2062.2 R2063.2 R2082.2 R2085.2 R2086.2 R2089.2 R2090.2 R4706.2 R79622.2 R79647.1 R79648.1 R79650.2 R79651.2 R79652.2 R79653.2 R79654.2 R79659.2 R79664.1 R79665.1 R79667.2 R79668.2 R79677.2 R79678.1 R79679.1 R79680.1 R79681.1 R79705.2 R79720.2 R79722.2 R80215.2 R80218.2 R80225.2 R80227.1 RJ1.13 RV1.1 SATAP1.2 SATAP1.4 SPI1.4 SPK1.5 SPK1.7 SPK1.8 SPR1.1 SRCON1.4 SSUSB1.4 SSUSB1.7 SSUSB1.10 SSUSB1.11 SSUSB2.4 SSUSB2.7 SSUSB2.10 SSUSB2.11 TC1.2 TC7.2 TC8.2 TC21.2 TOUCH1.2 U3.3 U3.8 U5.3 U5.8 U6.49 U7.4 U9.22 U9.27 U10.2 U11.2 U12.2 U16.33 U21.8 U21.9 U21.10 U21.17 U21.20 U21.21 U21.24 U21.33 U25.1 U25.2 U25.4 U25.7 U26.6 U26.49 U31.3 U31.8 U49.4 U52.11 U52.15 U54.11 U54.15 U55.14 U55.21 U109.4 U109.35 U109.71 U116.3 U116.8 U117.3 U117.8 U118.8 U118.15 U118.35 U118.41 U120.20 U178.4 U4101.10 U4101.21 U4101.45 U4101.53 U6701.5 U6701.10 U6701.12 U6701.13 U6701.15 U6701.16 UHS1.MS1 UHS1.MS2 USB3.4 USB3.5 USB3.6 USB4.4 USB4.5 USB4.6 WEBCM1.6 WEBCM1.8 WEBCM1.9 WEBCM1.10 X1.2 X1.4 X2.2 X2.3 X4.2 X4.4 X5.2 X5.4
GND_AUD: C144.1 C145.2 U6.40
VBAT1: BT1.1 R1683.2 TP189.1
VBAT1_R: D23.1 D33.1 R1683.1 TP188.1
VBAT2: D33.2 R707.2
VBAT_SB_N: C871.1 PU4.2 R1721.2
VBAT_SIO: C1821.1 R707.1 U109.66
VCC: C20.1 C714.2 C1832.1 C1833.1 D31.A F5.1 F13.1 LPC1.8 PC5435.1 PR11.1 PR44.2 PR95.1 PU7.6 R101.2 R183.1 R185.1 R617.1 R1838.2 R1849.1 R2080.1 R6705.1 U1.1 U1.2 U1.5 U1.6 U52.13 U52.14
VCC3: C474.1 C478.1 C509.1 C516.1 C836.2 C1714.1 C1729.1 C1730.1 C1834.1 C1835.1 C1975.1 C1976.1 C3367.1 C3379.1 C3380.2 CPU1.AP19 CPU1.AP21 D1.K D19.2 DIMM1.199 DIMM2.199 F1.1 F6.2 L16.1 L17.1 L21.1 LPC1.4 PR4624.1 PR4632.1 PR5463.1 Q77.S R12.1 R24.1 R32.1 R41.1 R46.1 R47.1 R57.1 R58.1 R71.1 R134.1 R138.1 R143.1 R159.2 R160.1 R162.2 R165.1 R206.1 R213.1 R294.1 R308.2 R316.2 R334.2 R341.2 R350.2 R351.2 R366.1 R377.1 R381.2 R482.1 R508.1 R517.1 R524.1 R530.2 R634.2 R680.2 R689.2 R1126.2 R1129.2 R1183.2 R1593.1 R1594.1 R1596.1 R1598.1 R1634.1 R1650.1 R1657.2 R1659.1 R1661.1 R1662.1 R1673.2 R1674.2 R1684.1 R1687.1 R1699.1 R1701.1 R1716.2 R1749.2 R1757.1 R1776.1 R1829.2 R1837.2 R1845.2 R1846.1 R1860.1 R1868.1 R1870.1 R1872.1 R1926.2 R1986.2 R2025.2 R2026.1 R2055.1 R2061.1 R2077.1 R2087.1 R2088.1 R6701.1 R6703.1 R6704.1 R79655.2 R79672.2 R79676.2 R79694.2 R79714.2 RN7.5(B) RN7.6(B) RN7.7(B) RN7.8(B) U6.11 U25.3 U25.8 U52.8 U52.9 U118.11 U118.37 U119.3 U4101.4
VCC3_CAM: C1.1 C1770.1 C1771.1 F1.2 F3.2 R24.2 R1784.2 WEBCM1.3
VCC5_33_CT1: C1837.1 U52.12
VCC5_33_CT2: C1836.1 U52.10
VCC5_33_EN: C1831.1 R1878.1 U52.3 U52.5
VCC5_DDC_HDMI: C6721.1 D31.K R2083.1 R2084.1
VCC5_PANEL: C2.1 C3.1 C6.1 F2.2 LVDS1.2 LVDS1.3 Q9647.S R481.1 R1163.1 R80233.2
VCC5_USB: C227.1 C249.2 C1769.1 F12.1 F14.1 F15.1 Q43.1 Q43.2 Q43.3 R433.1 R1729.1 R1782.1
VCC_FAN: C48.1 F5.2 FANC3.2 R80.1 R101.1
VCC_VTT: PC5001.1 PC5016.1 PR5018.1 PR5019.1 PU5001.2 PU5001.20
VDD_095_FB_H: Q14.S R110.2 R1612.2
VDD_095_FB_H_CTL: PR83.2 Q14.D R110.1
VDD_095_FB_L: R1861.2 R80227.2
VDDC_CT: C779.1 C780.1 C781.1 GPU1.AA20 GPU1.AA21 GPU1.AB20 GPU1.AB21 L48.2
VDDCR_APU_FB_H: PR4604.2 PR4628.2 R1611.2
VDDCR_APU_FB_L: PR4606.2 PR4611.2 R528.2
VDDCR_CPU_SENSE: CPU1.G12 R1611.1
VDDCR_GFX_FB_H: PR5410.2 PR5420.2 R1953.2
VDDCR_GFX_FB_L: PR5416.2 PR5422.2 R1954.2
VDDCR_GFX_SENSE: CPU1.H11 R1953.1
VDDCR_NB_FB_H: PR4642.2 PR4643.2 R1613.2
VDDCR_NB_FB_L: PC4601.2 PC4605.2 PR4606.1 PU4601.52 R529.2
VDDCR_NB_SENSE: CPU1.J12 R1613.1
VDDGFX_EN: C1930.1 PU5407.9 Q1240.D R1986.1
VDDGFX_EN_1: Q1240.G Q1241.C R1987.1
VDDGFX_EN_2: Q1241.B R1988.2 R1989.2
VDDGFX_PD: CPU1.AD8 TP214.1
VDDGFX_PWROK: PR5466.1 PU5407.2
VDDNB: C326.1 C1653.1 C1654.1 C1655.1 C1656.1 C1665.1 C1666.1 C1667.1 C1668.1 C1669.1 C1670.1 C1671.1 C1672.1 CPU1.AL12 CPU1.AL13 CPU1.AL15 CPU1.AL18 CPU1.AL21 CPU1.AN13 CPU1.AN16 CPU1.AN19 CPU1.AN22 PC5427.1 PG4704.1 PL4702.2 PR4643.1 PT4703.1 PT4704.1 Q6703.1 Q6703.2 R79724.2 U178.3
VDDNB_TRACK_GATE: Q6703.3 Q6703.4 R4708.2
VDDP_SENSE: CPU1.AY18 R1612.1
VSS_MECH: GPU1.A32 GPU1.AM1 GPU1.AM32
VSS_SENSE: CPU1.H12 R528.1 R529.1 R1861.1 R1954.1 R80225.1
0D95V_S0: C94.2 C95.1 C101.1 C1695.1 C1696.1 C1697.1 C1704.1 C1705.1 C1706.1 C1707.1 C1708.1 CPU1.AE5 CPU1.AE6 CPU1.AU17 CPU1.AU19 CPU1.AV17 CPU1.AV19 CPU1.AW17 CPU1.AW19 R178.2 R527.2 R557.2 R558.1 R586.1 R1989.1 U2.1 U2.2 U2.3 U6702.5 U6702.6 U6702.7 U6702.8
0D95V_S0_EN: R174.2 U2.4
0D95V_S5: C1702.1 C1703.1 CPU1.AN12 CPU1.AP12 PC4802.1 PG4801.2 PL4802.2 PR83.1 PT4801.1 R559.2 U2.5 U2.6 U2.7 U2.8
0D95V_VGA_S0: C798.1 C799.1 C800.1 C801.1 C802.1 C803.1 C804.1 C6705.1 C6706.1 C6708.1 C6709.1 GPU1.L23 GPU1.L24 GPU1.L25 GPU1.L26 GPU1.M22 GPU1.N22 GPU1.N23 GPU1.N24 GPU1.R21 GPU1.R22 GPU1.T22 GPU1.U21 GPU1.U22 GPU1.V22 L51.1 L53.1 R1161.2 R1162.2 R79664.2 U6702.1 U6702.2 U6702.3
0P95V_MAIN_APU_M: Q52.B R527.1
1D5V_S3_PG_1: D20.1 R1774.1
1D5V_S5: PR5291.1 PR5296.1 R205.1 R1601.2 R79693.1
1D8V_S0: C315.1 C316.2 C1673.1 C1674.1 CPU1.AP16 CPU1.AP18 PU4601.6 PU5407.6 Q1210.S R495.1 R504.1 R542.2 R1610.2 R1617.1 R1628.2 R1630.2 R1632.2 R1698.1 R1720.2 R1998.2 R2000.2 R2002.2 R2022.2 R2023.1 R2028.1 R2031.2 R2032.2 U105.4
1D8V_S5: C1677.1 C1828.1 C1957.1 CPU1.AP10 CPU1.AR9 PC52.1 PC5205.1 PC5210.1 PC5211.1 PC5212.1 PC5213.1 PC5431.1 PC5432.1 PG5211.1 PG5212.1 PL5202.2 PR5290.1 PR5473.1 PU5.1 PU7.5 PU7.9 R1595.1 R1677.1 U42.1 U42.2 U42.5 U42.6 U105.1 U105.2 U105.5 U105.6
1D8V_VGA_S0: C794.1 C795.1 C796.1 C797.1 C852.1 C853.1 GPU1.AM30 L47.1 L48.1 L49.1 L50.1 L52.1 R388.2 R935.1 R943.2 R1211.2 R1900.2 R1917.2 U42.4
1D35V_S3: C46.1 C55.1 C60.1 C337.1 C353.1 C356.1 C392.1 C1678.1 C1679.1 C1680.1 C1681.1 C1682.1 C1683.1 C1684.1 C1685.1 C1686.1 C1687.1 C1688.1 C1689.1 C1690.1 C1691.1 C1692.1 C1693.1 C1694.1 C1723.1 C1725.1 C1871.1 C1872.1 C1873.1 C1874.1 C1875.1 C1876.1 C1961.1 C1962.1 C1963.1 C1964.1 C1965.1 C1966.1 C1967.1 C1968.1 C1969.1 C1970.1 C1972.1 C1973.1 C1974.1 C1978.1 CPU1.AB24 CPU1.AB27 CPU1.AB30 CPU1.AB33 CPU1.AD25 CPU1.AD28 CPU1.AD30 CPU1.AE24 CPU1.AE27 CPU1.AF30 CPU1.AF33 CPU1.AG25 CPU1.AG28 CPU1.AH24 CPU1.AH27 CPU1.AH30 CPU1.AK25 CPU1.AK28 CPU1.AK30 CPU1.AK33 CPU1.AL27 CPU1.AM30 CPU1.P25 CPU1.P28 CPU1.T24 CPU1.T27 CPU1.U25 CPU1.U28 CPU1.V30 CPU1.V33 CPU1.W24 CPU1.W27 CPU1.Y25 CPU1.Y28 CPU1.Y30 DIMM1.75 DIMM1.76 DIMM1.81 DIMM1.82 DIMM1.87 DIMM1.88 DIMM1.93 DIMM1.94 DIMM1.99 DIMM1.100 DIMM1.105 DIMM1.106 DIMM1.111 DIMM1.112 DIMM1.117 DIMM1.118 DIMM1.123 DIMM1.124 DIMM2.75 DIMM2.76 DIMM2.81 DIMM2.82 DIMM2.87 DIMM2.88 DIMM2.93 DIMM2.94 DIMM2.99 DIMM2.100 DIMM2.105 DIMM2.106 DIMM2.111 DIMM2.112 DIMM2.117 DIMM2.118 DIMM2.123 DIMM2.124 PC5012.1 PG5001.1 PL5001.2 PR5020.1 PR5021.1 PT5007.1 R120.1 R121.2 R1584.1 R1586.1 R1588.1 R1633.1 R1696.2 R2057.1 R2059.1
1D35V_VGA_S0: C186.1 C214.1 C216.1 C486.1 C489.1 C500.1 C514.1 C540.1 C557.1 C612.1 C616.1 C623.1 C627.1 C765.1 C766.1 C767.1 C768.1 C769.1 C770.1 C771.1 C772.1 C773.1 C774.1 C775.1 C776.1 C777.1 C778.1 C1851.1 C1852.1 C1853.1 C1856.1 C1857.1 C1858.1 C1859.1 C6710.1 C6711.1 C6717.1 GPU1.H13 GPU1.H16 GPU1.H19 GPU1.J9 GPU1.J10 GPU1.J23 GPU1.J24 GPU1.K9 GPU1.K10 GPU1.K23 GPU1.K24 GPU1.L11 GPU1.L12 GPU1.L13 GPU1.L20 GPU1.L21 GPU1.L22 MEM1.A1 MEM1.A8 MEM1.B2 MEM1.C1 MEM1.C9 MEM1.D2 MEM1.D9 MEM1.E9 MEM1.F1 MEM1.G7 MEM1.H2 MEM1.H9 MEM1.K2 MEM1.K8 MEM1.N1 MEM1.N9 MEM1.R1 MEM1.R9 MEM2.A1 MEM2.A8 MEM2.B2 MEM2.C1 MEM2.C9 MEM2.D2 MEM2.D9 MEM2.E9 MEM2.F1 MEM2.G7 MEM2.H2 MEM2.H9 MEM2.K2 MEM2.K8 MEM2.N1 MEM2.N9 MEM2.R1 MEM2.R9 MEM3.A1 MEM3.A8 MEM3.B2 MEM3.C1 MEM3.C9 MEM3.D2 MEM3.D9 MEM3.E9 MEM3.F1 MEM3.G7 MEM3.H2 MEM3.H9 MEM3.K2 MEM3.K8 MEM3.N1 MEM3.N9 MEM3.R1 MEM3.R9 MEM4.A1 MEM4.A8 MEM4.B2 MEM4.C1 MEM4.C9 MEM4.D2 MEM4.D9 MEM4.E9 MEM4.F1 MEM4.G7 MEM4.H2 MEM4.H9 MEM4.K2 MEM4.K8 MEM4.N1 MEM4.N9 MEM4.R1 MEM4.R9 PC5430.1 PC5434.1 PR79.2 PU7.3 PU7.4 R203.2 R230.2 R885.2 R928.2 R945.2 R1200.1 R1204.1 R1890.1 R1910.2 R1922.2 R1924.2 R79692.1 TC21.1
1P5_5930_EN: PC5245.1 PU5206.8 R31.1 R1930.2
1P5_5930_FB: PC5244.2 PR5292.2 PR5293.1 PU5206.2
1P5_5930_PG: PR5295.2 PU5206.7
1P5_5930_VCNTL: PC5243.1 PR5294.2 PU5206.6
1P5V_GUP_FB_M: PC68.2 PR77.1 PR78.2 PU7.2
1P5V_GUP_FB_M1: PC68.1 PR78.1 PR79.1
1P5V_LPS_APU: BTRST1.2 C1736.1 C1741.1 CPU1.AR17 R1185.2 R1721.1
1P5V_S3_PG: PR5005.2 PU5001.10 R1774.2
1P8V_PWR_PG: PR5206.2 PU5201.4 R1763.1 R1930.1
3D3V_AUX_EC: L4101.1 PR8519.1 PR8520.1 Q9649.D R79706.1 R79707.2 R80230.2 U4101.11 U4101.22 U4101.38 U4101.44 U4101.56
3D3V_RUN_FFS: C6701.1 C6702.1 C6703.1 R6701.2 U6701.1 U6701.7 U6701.8 U6701.14
3D3V_VGA_S0: C753.1 C782.1 C783.1 C784.1 GPU1.AA17 GPU1.AA18 GPU1.AB17 GPU1.AB18 PR4.1 PR6.1 PR15.1 PR19.1 PR94.1 PR96.1 PR97.1 PR100.1 PR102.1 PR103.1 PR104.1 PR225.1 PR5471.2 Q77.D Q123.2 Q123.5 R302.2 R398.2 R1159.2 R1167.1 R1883.1 R1885.1 R1887.1 R1892.2 R1893.2 R1895.2 R79727.2 RN16.3(B) RN16.4(B) U49.3 U49.7 U49.8
3P3_VGA_1P8_EN: C6723.1 PR5471.1 Q97.5
1117_ADJ: R1592.1 R2081.2 U119.1
62882_COMP_R: PC6.2 PR8.1
62882_FB_VSEN: PC11.1 PR20.2
62882_NTC_R: PR5.2 PR60.1
62883AGND: PC5.1 PC9.2 PC20.1 PC56.2 PC57.1 PC58.2 PC60.2 PR1.1 PR2.1 PR5.1 PR9.2 U9.40 U9.41
+VGA_CORE_PHASE1: PG3.1 PR47.2
A20GATE: CPU1.BC19 R350.1 R80231.2
AC_IN: PQ5004.D PQ5005.2 PR5281.2
AC_IN_KBC#: TP4124.1 U4101.29
AC_OK#: PQ5004.G PR4427.2 R80209.1 U55.5 U4101.37
AC_OK#_ECIO: R80209.2 U109.99
AC_PRES: CPU1.AG3 R582.1
AC_PROTECT: PQ4408.G PR5287.1 PR5289.2 PR5297.2 PR5298.1 U55.3
AD+_2: C260.2 PQ4205.C R1847.2 R1850.1 U110.4
AD+_G_1: PQ5005.5 PQ5005.6 PR5272.2
AD+_G_2: PR5272.1 PR5275.2 PU5204.4
AD+_TO_SYS: PG4907.1 PR5275.1 PR5276.1 PU5204.1 PU5204.2 PU5204.3 R79643.2 R79644.2 R79645.2 R79646.2 R79656.2
AD_IA: PR5288.2 R80216.1 U4101.48
AD_IA_HW1: PQ5006.2 R79637.1 U109.106 U4101.59
AD_IA_HW2: PQ5006.5 R79638.1 U109.107 U4101.60
AD_JK: C260.1 C262.1 C597.1 D16.K DCIN1.1 DCIN2.1 DCIN2.2 DCIN2.3 DCIN2.8 DCIN2.9 DCIN2.10 PQ4205.E PR4214.1 R1847.1 U110.1 U110.2 U110.3
AD_OFF: R2013.1 R80211.1 U4101.36
AD_OFF_ECIO: R80211.2 U109.97
AD_OFF_L: PQ4204.C PQ4205.B
ADAPTOR_PSID: D19.3 R1846.2 R1851.2 R80213.1 U109.119
ADAPTOR_PSID_R: Q47.S R1851.1
AGPIO3: CPU1.AL5 R2008.1 R2010.2
AGPIO8: CPU1.AJ4 R79650.1
AGPIO11: CPU1.AN5 R2063.1 R2064.2
AGPIO13: CPU1.AD5 R79673.1
AGPIO14: CPU1.AL8 TP198.1
AGPIO15: CPU1.AN8 TP199.1
AGPIO24: CPU1.AL9 R79671.1
AGPIO40: CPU1.AG8 R79651.1
AGPIO66: CPU1.AT15 R159.1
AGPIO84: CPU1.BC18 R79714.1
AGPIO88: CPU1.BC11 TP186.1
AGPIO89: CPU1.BB14 R79672.1
AMD_RST#: C752.1 GPU1.AL27 R1160.1
AMP_GND: C192.2 C193.2 C208.2 C531.2 R344.1 R346.1 R347.1 R355.2 R358.2 R365.2 R666.1 U21.4
AMP_SPKR_L: C199.1 R355.1 R356.2
AMP_SPKR_R: C210.1 R365.1 R367.2
APU_ALERT#: CPU1.B17 R1616.2
APU_DBRDY: CPU1.C13 HDT1.14
APU_DBREQ: HDT1.16 R1746.1
APU_DBREQ#: C1739.1 CPU1.A11 R1704.2 R1746.2
APU_DIS_1: C866.1 Q104.G R1185.1
APU_DIS_2: Q104.D Q105.G R1186.1
APU_DIS_3: Q105.D R1981.1
APU_LVDS_BL_ADJ: CPU1.F11 R502.2
APU_M_VREF_SUS: C1608.1 C1609.2 R115.1 R1588.2 R1912.1
APU_M_VREFDQ_SUS: C15.1 C1727.2 C1728.1 C1731.2 C1959.1 C1960.1 C1981.2 C1982.2 DIMM1.1 DIMM2.1 R78.1 R81.1 R1633.2 R1697.1 R2057.2 R2058.1
APU_PROCHOT#: CPU1.A15 PQ4408.D PR24.2 PR4455.1 PR5464.2 R1615.2 R80226.1 U4101.14
APU_PWNBTN_N: CPU1.AE1 R1653.2
APU_PWRGD: C1722.2 CPU1.C19 R495.2 R1720.1 R1744.2 R1904.1
APU_PWRGD_BUF: HDT1.10 R1744.1
APU_S5_MUX_CTRL: CPU1.AH8 R4230.1
APU_S5_MUX_CTRL_D: Q4701.2 Q4701.3 R4702.2
APU_S5_MUX_CTRL_R: PC5429.1 Q4701.5 R4230.2 R79674.2 R79675.2
APU_SATA_LED_N: CPU1.BB15 Q9646.4 R1754.1 R2077.2
APU_SIC: CPU1.B18 R93.2 U109.51
APU_SID: CPU1.C17 R1614.2 U109.50
APU_SPKR: CPU1.BA17 R208.1
APU_SVC: CPU1.D17 R1628.1 R1902.1
APU_SVD: CPU1.D19 R1630.1 R1903.1
APU_SVT: CPU1.C15 R1632.1 R1901.1
APU_TCK: CPU1.D13 HDT1.2 RN12.2(A)
APU_TDI: CPU1.H15 HDT1.6 RN12.1(A)
APU_TDO: CPU1.H14 HDT1.8
APU_TEST0: CPU1.AH6 R1658.2 R1664.2
APU_TEST1: CPU1.AK8 R1665.2 R1690.2
APU_TEST2: CPU1.AE3 R1666.2 R1691.2
APU_TEST4: CPU1.P24 TP176.1
APU_TEST5: CPU1.N24 TP177.1
APU_TEST6: CPU1.AN24 TP178.1
APU_TEST9: CPU1.AB8 TP179.1
APU_TEST10: CPU1.Y9 TP180.1
APU_TEST11: CPU1.B11 R1607.1
APU_TEST14: CPU1.B10 R1604.1
APU_TEST15: CPU1.D11 TP181.1
APU_TEST16: CPU1.A10 R1605.1
APU_TEST17: CPU1.C11 R1606.1
APU_TEST28_H: CPU1.A13 TP182.1
APU_TEST28_L: CPU1.B13 TP183.1
APU_TEST31: CPU1.P26 TP184.1
APU_TEST37: CPU1.A17 R545.1 R1610.1
APU_TEST410: CPU1.AK24 TP37.1
APU_TEST411: CPU1.AL24 TP175.1
APU_TMS: CPU1.G15 HDT1.4 RN12.3(A)
APU_TRST: C1870.2 CPU1.J14 R1743.2 RN12.4(A)
APU_VDD_33_18_SEL: R93.1 R1614.1 R1615.1 R1616.1 R2022.1 R2025.1
APU_VDDIO_AZ: C395.1 C1638.1 C1639.1 CPU1.AR19 R1595.2 R1601.1
APU_VRM_PWRGD: PR4624.2 PU4601.7
AUD_BEEP_C: C130.2 U6.2
AUD_BEEP_R: C130.1 R207.2 R208.2 R210.1
AUD_DMIC_CLK: C121.2 L54.2 WEBCM1.4
AUD_DMIC_CLK_R: R212.1 U6.12
AUD_DMIC_CLK_R_1: L54.1 R212.2
AUD_DMIC_DATA: C132.2 R222.1 WEBCM1.5
AUD_DMIC_DATA_R: R222.2 U6.13
AUD_DVDD: C127.1 C131.1 R205.2 R206.2 R79649.2 U6.7
AUD_GP3: R213.2 U6.3
AUD_LINK_BCLK: C126.2 R79684.1 U6.5
AUD_LINK_RST_N: C61.1 R314.1 R79682.1 U6.6
AUD_LINK_RST_N_2: Q63.4 Q63.6
AUD_LINK_RST_N_R: C170.1 Q31.B R314.2
AUD_LINK_SDIN: CPU1.AR8 R209.1 R79678.2
AUD_LINK_SDIN_1: R209.2 U6.8
AUD_LINK_SDO: C1780.2 Q56.D R618.2 R79685.1
AUD_LINK_SDO_1: C1780.1 Q56.G R617.2
AUD_LINK_SDO_N: Q56.S R618.1 U6.4
AUD_LINK_SYNC: R79683.1 U6.9
AUD_REGREF: C129.1 U6.10
AZ_BCLK_M: CPU1.AU6 R79681.2 R79684.2
AZ_RST_N_M: CPU1.AU9 R79682.2
AZ_SDIN1: CPU1.AP6 R79679.2
AZ_SDIN2: CPU1.AR5 R79680.2
AZ_SDOUT_M: CPU1.AR7 R79685.2
AZ_SYNC_M: CPU1.AT9 R79683.2
BAT_ALERT: BAT2.8B R79648.2
BAT_IN#: R2014.1 R80210.1 RN4301.4(A) U4101.5
BAT_IN#_1: BAT2.6B PC4304.1 PL4301.1 RN4301.5(B)
BAT_IN#_ECIO: R80210.2 U109.98
BATA_SCL_1: BAT2.4B PC4305.1 PL4302.1 RN4301.7(B)
BATA_SDA_1: BAT2.5B PC4301.1 PL4303.1 RN4301.6(B)
BATT_AMBER_LED#: R79710.2 U4101.9
BATT_AMBER_LED#_C: PWRCN1.10 R389.2 R79710.1
BATT_WHITE_LED#: R79711.2 U4101.58
BATT_WHITE_LED#_C: PWRCN1.8 Q38.C Q1214.C R79711.1 R79726.2
BIST_DISABLE: R531.2 R533.1 R536.1 U109.112
BIST_DISABLE_1: Q12.5 R536.2
BIST_EN: Q12.3 Q12.6 Q13.2 R524.2
BIST_EN_INV: Q13.3 Q13.6 R513.1 R517.2 R80232.2 U26.2
BIST_EN_SIO: R1826.1 R80232.1 U109.25
BIST_ENABLE: R515.1 U109.113
BIST_ENABLE_1: Q13.5 R514.2 R515.2 R523.1
BIST_PIN25: Q9650.G R682.2 U109.24
BKLT_ADJ: C33.1 C87.1 R133.2 R79621.2
BKLT_EN: C88.1 Q22.C R138.2 R139.2 R79625.2
BKLT_EN1: Q22.B R135.2
BOARD1: CPU1.BB9 R1661.2 R1663.1
BOARD2: CPU1.AW15 R152.1 R1662.2
BOARD3: CPU1.AU15 R1659.2 R1660.1
BOOT1_PHASE1: PC19.2 PR43.2
BQ24737_CSON_1: PC5236.2 PC5238.1 PG4908.1 PR5277.2
BQ24737_CSOP_1: PC5236.1 PG4906.1 PR5283.2
BQ24737_REGN: PC5233.2 PD4401.A PR5297.1 U55.16
BT+: BAT2.1B BAT2.2B BAT2.3B PC4302.1 PC4303.1 PC4401.1 PC5240.1 PC5241.1 PC5242.1 PG4908.2 PR5269.2 PU5205.5 PU5205.6 PU5205.7 PU5205.8
BT+_R: PG4906.2 PL5003.2 PR5269.1
BUFFER1_M4: Q51.G Q52.C R526.1
BUZZER_SPKR_R: C203.1 R207.1
C_GPP_TXN3: C41.1 CPU1.N3
C_GPP_TXP3: C42.1 CPU1.N4
CAGND: C4.1 C5.2 C8.2 C10.2 C43.2 C3455.2 C3456.2 C3457.2 C3458.2 R37.2 R61.2 R82.2 R79623.2 R79627.2 R79628.2 U120.15 U120.21
CASA0#: GPU1.G19 MEM1.K3 MEM3.K3
CASA1#: GPU1.G16 MEM2.K3 MEM4.K3
CBN: C150.2 U6.21
CBP: C150.1 U6.24
CFG: R1594.2 U118.23
CHG_AGND: PC4403.2 PC4404.2 PC4408.2 PC5232.2 PC5238.2 PC5239.2 PQ5006.1 PQ5006.4 PR4412.2 PR5268.2 PR5274.2 PR5468.2
CHG_ON#: PQ5003.G PR5273.2 R80207.1 U4101.17
CHG_ON#_ECIO: R80207.2 U109.101
CHG_SMB2_CLK: PR4425.2 R715.1 RN4301.2(A) U55.9 U4101.35
CHG_SMB2_DATA: PR4426.2 R716.1 RN4301.3(A) U55.8 U4101.34
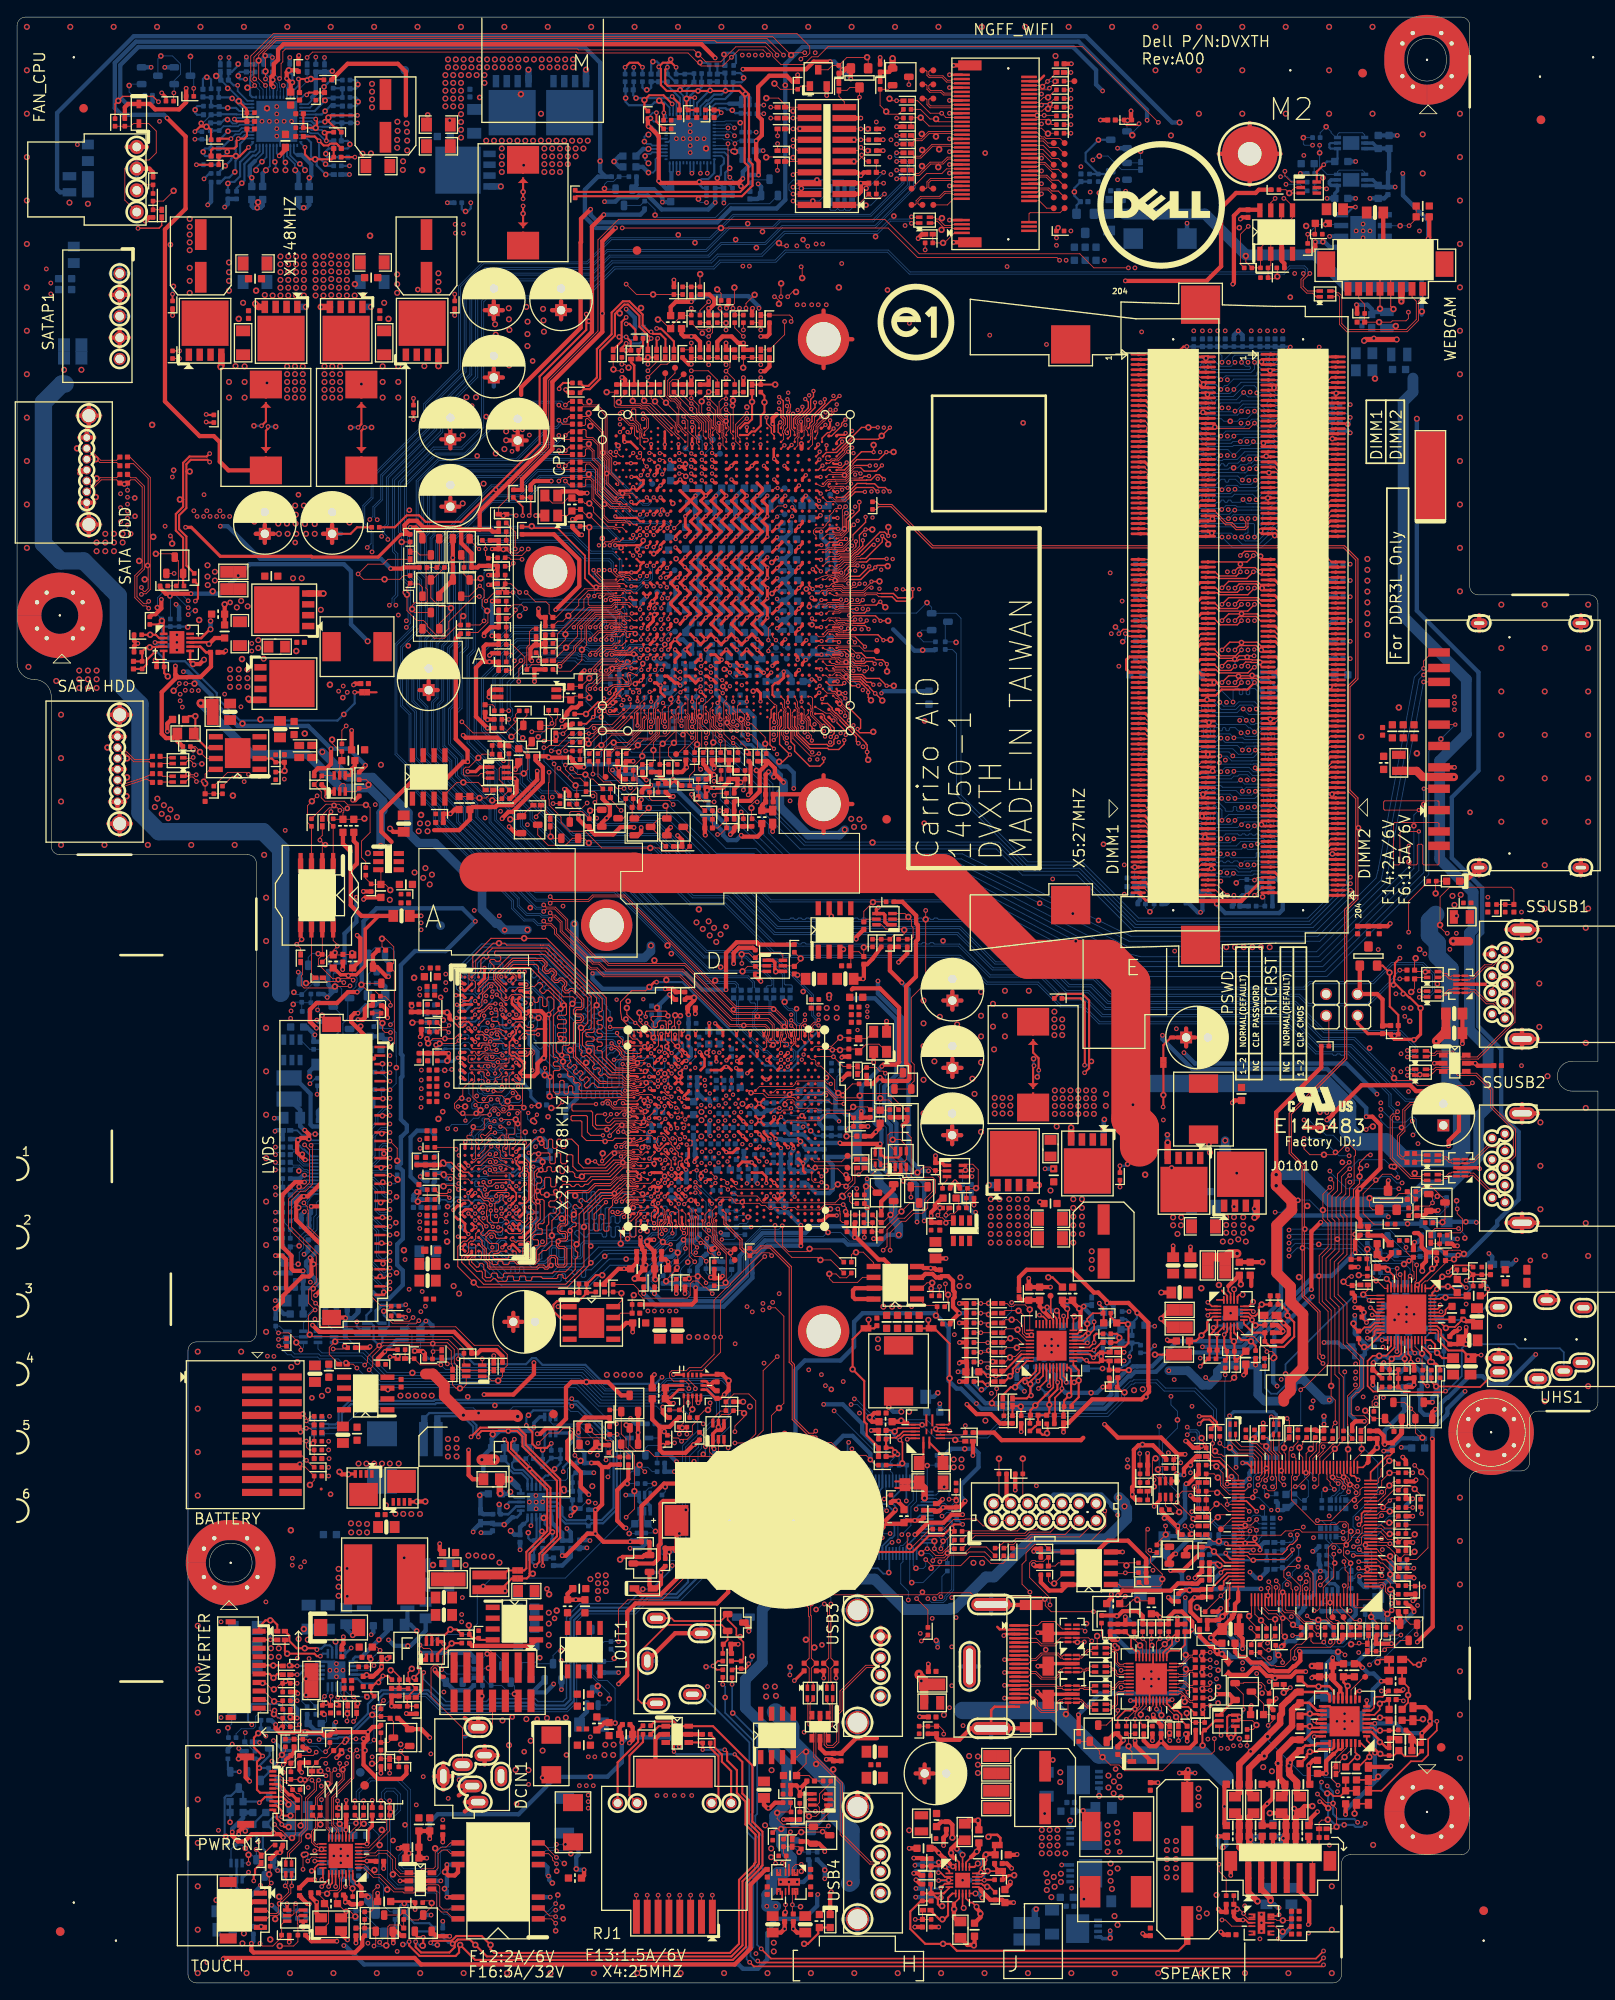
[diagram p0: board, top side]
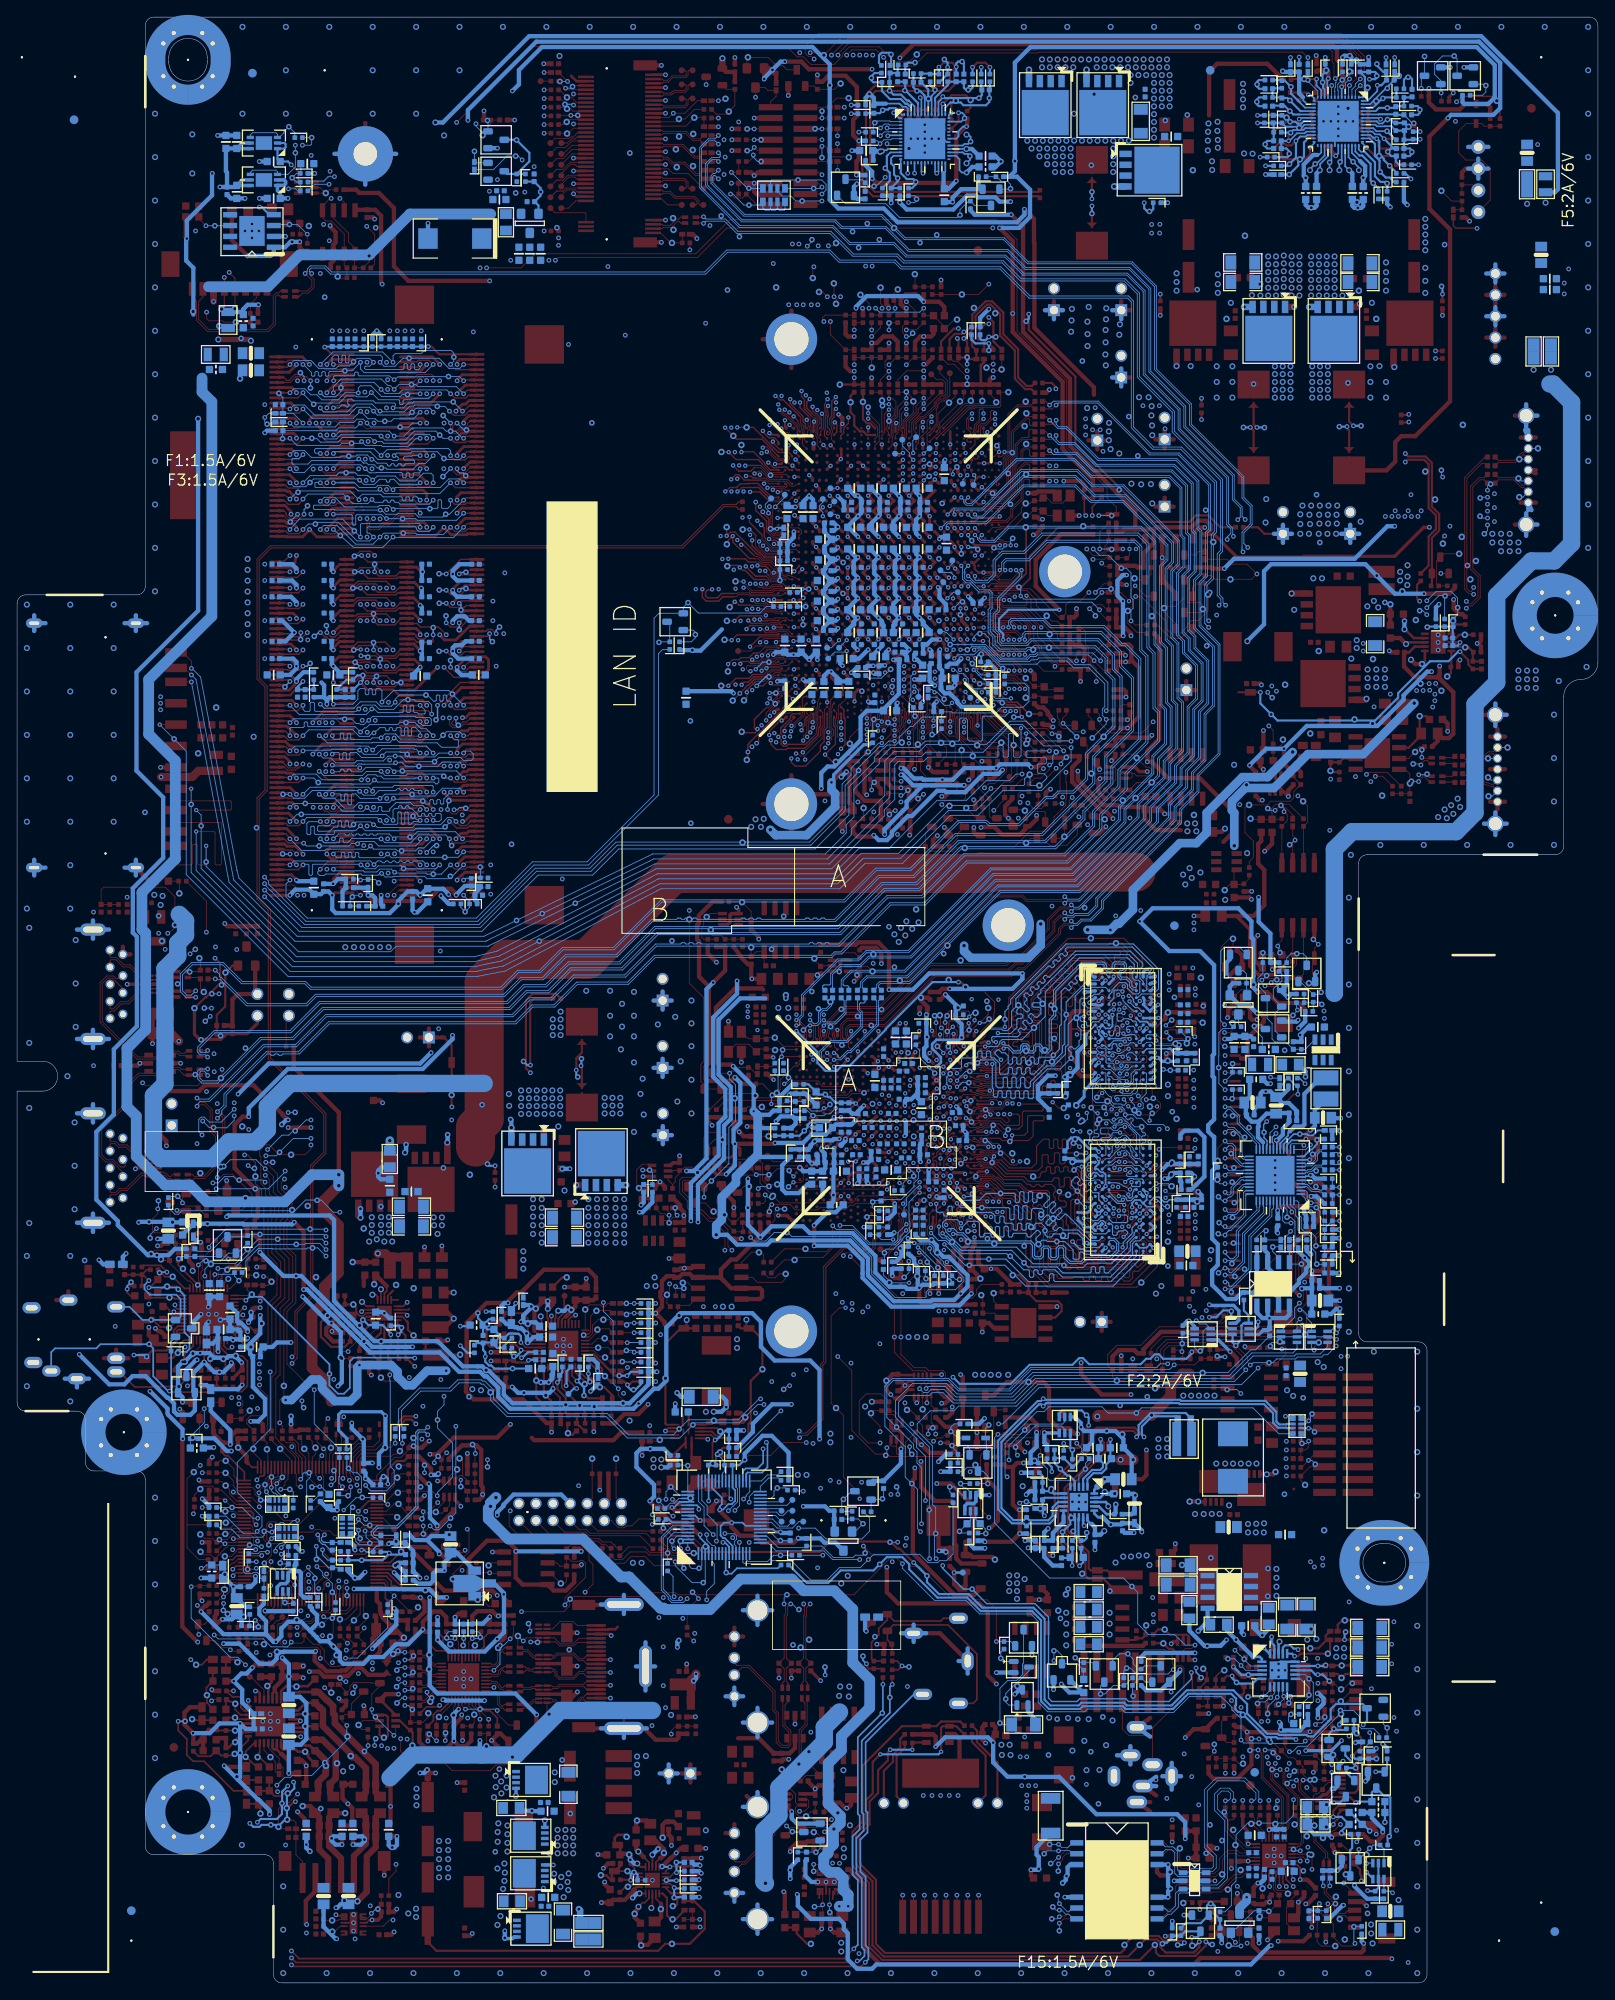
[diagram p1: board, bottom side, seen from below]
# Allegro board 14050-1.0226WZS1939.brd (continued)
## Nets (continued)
CK_48M_SIO: C1733.2 R310.2 R1645.1 R2067.2
CK_GLAN_DN: CPU1.U2 U16.16
CK_GLAN_DP: CPU1.U1 U16.15
CK_M_DDR0_A_DN: CPU1.AE32 DIMM1.103
CK_M_DDR0_A_DP: CPU1.AE33 DIMM1.101
CK_M_DDR0_B_DN: CPU1.AD33 DIMM2.103
CK_M_DDR0_B_DP: CPU1.AD32 DIMM2.101
CK_M_DDR1_A_DN: CPU1.AE31 DIMM1.104
CK_M_DDR1_A_DP: CPU1.AE30 DIMM1.102
CK_M_DDR1_B_DN: CPU1.AC32 DIMM2.104
CK_M_DDR1_B_DP: CPU1.AC33 DIMM2.102
CK_P_33M_EC: R79699.1 U4101.2
CK_P_33M_SIO: C1734.1 R1646.1 R1867.1 R1868.2 R1877.2 R79699.2 U109.44
CK_PCIEX1_WLAN_DN: CPU1.W3 R23.2
CK_PCIEX1_WLAN_DP: CPU1.W4 R22.2
CK_PE_100M_16PORT_DN: CPU1.U3 GPU1.AK32
CK_PE_100M_16PORT_DP: CPU1.U4 GPU1.AK30
CKEA0: GPU1.K20 MEM1.K9 MEM3.K9
CKEA1: GPU1.J17 MEM2.K9 MEM4.K9
CLINK_CLK_LAN: NGFF1.42 TP67.1
CLINK_DATA_LAN: NGFF1.40 TP66.1
CLINK_RST_LAN_N: NGFF1.38 TP65.1
CLK_48M_SIO_C: R310.1 U109.34
CLKA0: GPU1.H26 MEM1.J7 MEM3.J7 R1907.1
CLKA0#: GPU1.H25 MEM1.K7 MEM3.K7 R1906.1
CLKA1: GPU1.G9 MEM2.J7 MEM4.J7 R1909.1
CLKA1#: GPU1.H9 MEM2.K7 MEM4.K7 R1908.1
CLKTESTA: C764.1 GPU1.K8
CLKTESTA_C: C764.2 R1207.1
CLKTESTB: C763.1 GPU1.L7
CLKTESTB_C: C763.2 R1206.1
COMP_OUT1: R4708.1 R79725.1 U178.1 U178.6
COMP_OUT2: R4707.1 U178.7
COMPNB_R: PC4611.1 PR4623.2
CORETYPE: CPU1.K24 TP213.1
CPU_BST1_SW1: PC4704.1 PR4701.2
CPU_BST2_SW2: PC4710.1 PR4703.2
CPU_FAN_CTRL_SIO: R68.1 U109.6
CPU_FAN_TACH_SIO: R74.1 U109.5
CPU_VCORE: C330.1 C1644.1 C1645.1 C1646.1 C1647.1 C1648.1 C1649.1 C1650.1 C1651.1 C1652.1 C1657.1 C1658.1 C1659.1 C1660.1 C1661.1 C1662.1 C1663.1 C1664.1 CPU1.AB7 CPU1.AB9 CPU1.AB12 CPU1.AB15 CPU1.AB18 CPU1.AB21 CPU1.AD6 CPU1.AD10 CPU1.AD13 CPU1.AD16 CPU1.AD19 CPU1.AD22 CPU1.AE7 CPU1.AE12 CPU1.AE15 CPU1.AE18 CPU1.AE21 CPU1.AG6 CPU1.AG10 CPU1.AG13 CPU1.AG16 CPU1.AG19 CPU1.AG22 CPU1.AH7 CPU1.AH12 CPU1.AH15 CPU1.AH18 CPU1.AH21 CPU1.AK6 CPU1.AK9 CPU1.AK10 CPU1.AK13 CPU1.AK16 CPU1.AK19 CPU1.AK22 CPU1.AL7 CPU1.AN6 CPU1.U8 CPU1.W7 CPU1.W12 CPU1.W15 CPU1.W18 CPU1.W21 CPU1.Y8 CPU1.Y10 CPU1.Y13 CPU1.Y16 CPU1.Y19 CPU1.Y22 G5.1 PG4702.1 PL4701.2 PR4628.1 PT4702.1 PT4708.1 PT4709.1
CPVEE: C1491.1 U6.20
CSA0#_0: GPU1.H22 MEM1.L2 MEM3.L2
CSA1#_0: GPU1.G13 MEM2.L2 MEM4.L2
CTF_TRIP: C755.2 Q48.B R391.2
CTFB: Q48.C R354.2 R1920.2
D2_M: D23.2 R1672.1
DC_19V: C258.1 PC5235.2 PR4431.1 PR5270.1 PR5282.1 PR5284.1 PR5285.1 PU5204.5 PU5204.6 PU5204.7 PU5204.8 PU5205.4 R1848.1 R79643.1 R79644.1 R79645.1 R79646.1 R79656.1 U110.5 U110.6 U110.7 U110.8
DC_IN_D: PQ5005.3 PR5282.2
DCBATOUT: C32.1 C6718.1 C6719.1 C6720.1 F16.1 L10.1 PC24.1 PC61.1 PC62.1 PC63.1 PC64.1 PC4405.1 PC4406.1 PC4407.1 PC4701.1 PC4702.1 PC4703.1 PC4705.1 PC4707.1 PC4708.1 PC4709.1 PC4711.1 PC4903.1 PC5019.1 PC5020.1 PC5021.1 PC5022.1 PC5235.1 PC5401.1 PC5402.1 PC5403.1 PC5404.1 PG4905.1 PG5205.1 PG5210.1 PR101.1 PR4458.1 PR4616.1 PR4814.1 PR4815.1 PR4901.1 PR4927.1 PR4929.1 PR4930.1 PR4931.1 PR4932.1 PR4933.1 PR5007.1 PR5276.2 PR5424.1 PT2.1 PT4701.1 PT4712.1 PT5405.1 PU1.5 PU1.6 PU1.7 PU1.8 PU2.5 PU2.6 PU2.7 PU2.8 PU4403.5 PU4403.6 PU4403.7 PU4403.8 PU4702.5 PU4702.6 PU4702.7 PU4702.8 PU4901.11 PU5006.5 PU5006.6 PU5006.7 PU5006.8 PU5205.1 PU5205.2 PU5205.3 PU5207.5 PU5207.6 PU5207.7 PU5207.8 PU5401.5 PU5401.6 PU5401.7 PU5401.8 R20.1 R26.1 R171.1 R179.1 R657.1 R733.1 R1164.1 R1777.1 R1778.1 R1780.1 R1918.1 R4702.1 R79631.1 R79662.2 R79666.1
DCIN_EN: R2087.2 U118.13
DDCBUF: R1598.2 R2089.1 U118.14
DDR3_DRAMRST_N: CPU1.T33 R99.1 R2054.1
DDR3_DRAMRST_N_A_1: C1726.1 DIMM1.30 R99.2
DDR3_DRAMRST_N_B_1: C1958.1 DIMM2.30 R2054.2
DDR_VREF_S3: PR5032.1
DGPU_PWROK: PR6.2 PR14.2 PR5261.1
DGPU_PWROK_0D95V: C6707.1 Q6702.5 R79727.1
DGPU_PWROK_1D5V: PC5433.1 PR5261.2 PU7.8
DIFFNB_R: PC4610.1 PR4622.2
DIMM_APU_VREF: CPU1.T32 R1912.2
DIMM_DQ_APU_VREF_MA: CPU1.B19 R81.2
DIMM_DQ_APU_VREF_MB: CPU1.A19 R1697.2
DIMM_TMPIN2+: C231.2 R397.1 RT1.1 U109.86
DIMM_TMPIN2-: C231.1 R399.2 RT1.2
DIS_EN_0D95_RUN_R: Q6702.2 Q6702.3 R79662.1 R79665.2
DP0_AUXN: C305.1 CPU1.E8 R1074.2
DP0_AUXP: C304.1 CPU1.F8 R1079.1
DP0_HPD: CPU1.G8 R510.2 R512.1 R530.1
DP0_TXN0: C301.1 CPU1.E1
DP0_TXN1: C303.1 CPU1.E4
DP0_TXP0: C300.1 CPU1.E2
DP0_TXP1: C302.1 CPU1.E3
DP_2K_ZVSS: CPU1.A9 R1603.1
DP_150_ZVSS: CPU1.B9 R107.1
DP_AUXN: NGFF1.20 TP73.1
DP_AUXP: NGFF1.22 TP72.1
DP_HPD: NGFF1.31 TP78.1
DP_ML0N: NGFF1.32 TP69.1
DP_ML0P: NGFF1.34 TP68.1
DP_ML1N: NGFF1.26 TP71.1
DP_ML1P: NGFF1.28 TP70.1
DP_ML2N: NGFF1.25 TP76.1
DP_ML2P: NGFF1.27 TP77.1
DP_ML3N: NGFF1.19 TP74.1
DP_ML3P: NGFF1.21 TP75.1
DP_STEREOSYNC: CPU1.E11 R1618.1 R1619.1
DP_STEREOSYNC_PU: R1618.2 R2023.2 R2026.2
DPLL_PVDD: C827.1 C829.1 C830.1 GPU1.AF14 L52.2
DPLL_VDDC: C825.1 C826.1 C828.1 GPU1.AD14 L53.2
DPLVDS_AUXN: C305.2 U26.3
DPLVDS_AUXP: C304.2 U26.4
DPLVDS_BL_EN: R1985.2 R79686.1 U26.44
DPLVDS_EDIDCLK: C1827.1 R32.2 R35.2 U26.46
DPLVDS_EDIDCLK_C: R35.1 U25.6
DPLVDS_EDIDSDA: C7.1 R46.2 R1858.2 U26.45
DPLVDS_EDIDSDA_C: R1858.1 U25.5
DPLVDS_FWCLK: C9.1 R47.2 U26.48
DPLVDS_FWSDA: C11.1 R58.2 U26.47
DPLVDS_HPD: R510.1 U26.1
DPLVDS_ISPCLK: Q7.1 Q95.4 R69.2 U26.13
DPLVDS_ISPDAT: Q4.1 Q95.1 R54.2 U26.14
DPLVDS_PANEL_VCC: R39.2 U26.20
DPLVDS_PIN12: R511.1 U26.12
DPLVDS_PIN16: R507.2 U26.16
DPLVDS_PWMIN: R501.1 R502.1 R503.2 U26.21
DPLVDS_PWMOUT: R1984.2 U26.19
DQMA0: GPU1.E32 MEM3.E7
DQMA1: GPU1.E30 MEM3.D3
DQMA2: GPU1.A21 MEM1.D3
DQMA3: GPU1.C21 MEM1.E7
DQMA4: GPU1.E13 MEM4.E7
DQMA5: GPU1.D12 MEM2.D3
DQMA6: GPU1.E3 MEM2.E7
DQMA7: GPU1.F4 MEM4.D3
DRAM_RST: C839.1 GPU1.L10 R1202.1 R1205.1
DRAM_RST_R: C762.1 R1202.2 R1891.1
DRX0N: C301.2 U26.8
DRX0P: C300.2 U26.7
DRX1N: C303.2 U26.10
DRX1P: C302.2 U26.9
EAPD_DEPOP: R635.1 U6.14
EAPD_DEPOP_1: R634.1 R635.2 R636.1
EAPD_DEPOP_2: Q63.2 R636.2
EC_3P3_CTL: C6724.2 PR8521.2 Q9648.G
EC_3P3_CTL_2: C6725.1 Q9649.G R80229.2
EC_3P3_CTL_3: Q9648.D R80228.1 R80229.1
EC_A20GATE: R80231.1 U109.43
EC_EUP: R674.1 R675.1 U109.127
EC_EUP_EN: C542.1 Q1227.G R674.2 R1199.2
EC_HDMI_PD_N: Q1249.G R2091.2 U109.105
EC_IMS: R79691.2 U109.52
EC_LAN_DISABLE_N: R1194.1 R1840.1 U109.58
EC_PSID: R80213.2 U4101.12
EC_PWREN: PR8521.1 R702.2 R1834.1 U109.57
EC_SCI: R79709.1 U4101.15
EC_SMB2_CLK: PR8519.2 R80220.1 U4101.32
EC_SMB2_DATA: PR8520.2 R80219.1 U4101.33
EC_VCORF: C4101.2 U4101.20
ECIO_APU_PROCHOT#: R80226.2 U109.8
ECIO_IO_SMI_N: R80223.2 U109.9
ECIO_LPC_PME_N: R80224.1 U109.70
EGPIO67: CPU1.AT17 R79653.1
EGPIO70: CPU1.AT12 R79654.1
EGPIO119: CPU1.AW7 TP8.1
EGPIO131: CPU1.BB18 R79670.1
EGPIO132: CPU1.BB16 R79635.1
EGPIO145: CPU1.BB10 R79652.1
EQ: R1593.2 R2085.1 U118.17
EVAL_PE_L: CPU1.AR14 D34.1 D34.2
EVAL_PWREN: CPU1.BC13 PR5476.1
EVAL_PWRGD: CPU1.BC17 Q6705.6 R79694.1
EVAL_PWRGD_0D95: C6716.1 Q6705.5 R79692.2
EVAL_PWRGD_1D5: Q6705.2 Q6705.3 R79693.2
EXT_RST#: R79705.1 R79706.2 U4101.41
F_USB0N: C6729.1 CPU1.AR1 TR10.4
F_USB0P: C6728.1 CPU1.AR2 TR10.1
F_USB1N: C6726.1 CPU1.AR4 TR14.4
F_USB1P: C6727.1 CPU1.AR3 TR14.1
F_USB3N: CPU1.AN4 TR9.4
F_USB3P: CPU1.AN3 TR9.1
F_USB4N: CPU1.AM2 TR1.4
F_USB4P: CPU1.AM1 TR1.1
F_USB5N: CPU1.AL1 TR12.4
F_USB5P: CPU1.AL2 TR12.1
F_USB6N: CPU1.AL4 TR3.1
F_USB6P: CPU1.AL3 TR3.4
F_USB7N: CPU1.AJ2 TR4.1
F_USB7P: CPU1.AK2 TR4.4
FALL_INT2: Q6701.2 Q6701.3 R6703.2
FCH_0.775_S5: C1953.1 C1954.1 C1956.1 C6712.1 C6714.1 C6715.1 CPU1.AP13 CPU1.AR12 Q6703.5 Q6703.6 Q6704.5 Q6704.6
FCH_S5_POWER_COMP: Q4701.1 R4706.1 R79724.1 R79725.2 U178.2 U178.5
FFS_INT1: CPU1.AJ1 R6702.2 R79658.2 U109.110
FFS_INT1_C: R79658.1 U6701.11
FFS_INT2_APU: CPU1.AK5 R79657.2
FFS_INT2_C: Q6701.5 R6704.2 R6706.1 R79657.1 R79668.1 U6701.9
FFS_INT2_Q: Q6701.6 R6705.2 R6706.2 SATAP1.5
FP_RST_N: C1735.1 CPU1.AF2 R1679.1 R1920.1 R2004.1 R2012.2
FWH_ID0: LPC1.6 R1700.2
GFX_SVC: CPU1.B16 R1994.1 R1998.1
GFX_SVD: CPU1.A18 R1995.1 R2000.1
GFX_SVT: CPU1.B15 R1993.1 R2002.1
GFX_VCORE: C1934.1 C1935.1 C1936.1 C1937.1 C1938.1 C1939.1 C1940.1 C1941.1 C1942.1 C1943.1 C1944.1 C1945.1 C1946.1 C1947.1 C1948.1 C1949.1 C1950.1 C1951.1 C1952.1 CPU1.F12 CPU1.F15 CPU1.G11 CPU1.G14 CPU1.J8 CPU1.J9 CPU1.J11 CPU1.K7 CPU1.K12 CPU1.K13 CPU1.K15 CPU1.K16 CPU1.K19 CPU1.L8 CPU1.L13 CPU1.L16 CPU1.L19 CPU1.L22 CPU1.N7 CPU1.N12 CPU1.N15 CPU1.N18 CPU1.N21 CPU1.P8 CPU1.P13 CPU1.P16 CPU1.P19 CPU1.P22 CPU1.T7 CPU1.T12 CPU1.T15 CPU1.T18 CPU1.T21 CPU1.U13 CPU1.U16 CPU1.U19 CPU1.U22 PG5402.1 PL5401.2 PR5410.1 PT5401.1 PT5402.1 PT5403.1
GFX_VRM_PWRGD: PR5463.2 PU5407.7
GP11: R679.1 U109.31
GP24: R297.1 U109.20
GP26: R1188.1 U109.18
GP27: R1864.1 U109.17
GP32: R307.2 U109.14
GP33: R80222.1 U109.13
GP34: R80221.1 U109.12
GP63: R1863.1 U109.3
GPIO17_THERMAL_INT: GPU1.R6 R1884.2 R1887.2 R1896.2
GPIO19_CTF: GPU1.M2 R329.2 R1886.1
GPIO19_CTF_R: D7.3 R329.1 R391.1 R1894.1 R1896.1
GPIO_8_ROMSO: GPU1.P10 R1169.1
GPIO_9_ROMSI: GPU1.P4 R1171.2
GPIO_10_ROMSCK: GPU1.P2 R1170.2
GPIO_22_ROMCS#: GPU1.N8 R1168.1
GPIO_SVC: GPU1.AJ11 TP165.1
GPIO_SVD: GPU1.AK12 TP163.1
GPIO_SVT: GPU1.AL11 TP164.1
GPIO_VGA_03_DATA: Q123.4 R1165.1 RN16.2(A)
GPIO_VGA_03_DATA_R: GPU1.U8 R1165.2
GPIO_VGA_04_CLK: Q123.1 R1166.1 RN16.1(A)
GPIO_VGA_04_CLK_R: GPU1.U7 R1166.2
GPU_CLKA0_T: C1855.2 R1906.2 R1907.2
GPU_CLKA1_T: C207.2 R1908.2 R1909.2
GPU_DMINUS: C524.2 GPU1.T2 R651.2 RT2.2
GPU_DPLUS: C524.1 GPU1.T4 R658.1 RT2.1 U109.85
GPU_GPIO16: GPU1.M4 TP155.1
GPU_SCL: GPU1.R1 TP149.1
GPU_SDA: GPU1.R3 TP150.1
GPU_THERM_SHUTDOWN*: PR18.1 R354.1
GPU_THERMAL_INT: R1884.1 R1885.2 U109.28
GPU_VCC3_CTL: C1864.2 PR5476.2 Q76.G R1126.1
GPU_VCC3_CTL_2: C836.1 Q77.G R1195.2
GPU_VCC3_CTL_3: Q76.D R1129.1 R1195.1
GPU_VREFG: C1846.1 GPU1.AC16 R1210.2 R1211.1
GPU_WAKEB: GPU1.AJ27 R1883.2
GPU_XO_IN: GPU1.AC22 R1880.1
GPU_XO_IN2: GPU1.AB22 R1881.1
H_VID0: GPU1.T8 PR39.1 PR40.1 PR104.2
H_VID1: GPU1.N1 PR37.1 PR38.1 PR103.2
H_VID2: GPU1.P8 PR35.1 PR36.1 PR102.2
H_VID3: GPU1.AK10 PR32.1 PR33.1 PR100.2
H_VID4: GPU1.AM10 PR30.1 PR31.1 PR97.2
H_VID5: GPU1.T9 PR25.1 PR26.1 PR96.2
H_VID6: PR23.1 PR94.2 PR5251.1
HDMI1_CLK_APU: CPU1.F7 R79639.2
HDMI1_CLK_APU_SRC: R79639.1 U118.38
HDMI1_CLK_CON: HDMI1.15 HDMI2.5 R2083.2 U117.1 U117.10 U118.32
HDMI1_DATA_APU: CPU1.E7 R79640.2
HDMI1_DATA_APU_N0: C3371.1 CPU1.A3
HDMI1_DATA_APU_N1: C3372.1 CPU1.A4
HDMI1_DATA_APU_N2: C3373.1 CPU1.C5
HDMI1_DATA_APU_N3: C3374.1 CPU1.B5
HDMI1_DATA_APU_P0: C3368.1 CPU1.A2
HDMI1_DATA_APU_P1: C3370.1 CPU1.B4
HDMI1_DATA_APU_P2: C3369.1 CPU1.D5
HDMI1_DATA_APU_P3: C3375.1 CPU1.A5
HDMI1_DATA_APU_SRC: R79640.1 U118.39
HDMI1_DATA_CON: HDMI1.16 HDMI2.4 R2084.2 U117.2 U117.9 U118.33
HDMI1_DATA_CON_N0: HDMI1.3 HDMI2.17 TR16.2 U116.2 U116.9
HDMI1_DATA_CON_N1: HDMI1.6 HDMI2.14 TR17.2 U116.5 U116.6
HDMI1_DATA_CON_N2: HDMI1.9 HDMI2.11 TR18.2 U31.4 U31.7
HDMI1_DATA_CON_N3: HDMI1.12 HDMI2.8 TR19.2 U31.1 U31.10
HDMI1_DATA_CON_P0: HDMI1.1 HDMI2.19 TR16.3 U116.1 U116.10
HDMI1_DATA_CON_P1: HDMI1.4 HDMI2.16 TR17.3 U116.4 U116.7
HDMI1_DATA_CON_P2: HDMI1.7 HDMI2.13 TR18.3 U31.5 U31.6
HDMI1_DATA_CON_P3: HDMI1.10 HDMI2.10 TR19.3 U31.2 U31.9
HDMI1_DATA_IC_N0: C3371.2 U118.2
HDMI1_DATA_IC_N1: C3372.2 U118.5
HDMI1_DATA_IC_N2: C3373.2 U118.7
HDMI1_DATA_IC_N3: C3374.2 U118.10
HDMI1_DATA_IC_P0: C3368.2 U118.1
HDMI1_DATA_IC_P1: C3370.2 U118.4
HDMI1_DATA_IC_P2: C3369.2 U118.6
HDMI1_DATA_IC_P3: C3375.2 U118.9
HDMI1_DET_APU: CPU1.F5 U118.3
HDMI1_DET_CON: HDMI1.19 HDMI2.1 U117.4 U117.7 U118.28
HDMI_LANE0_IC_DN: TR16.1 U118.29
HDMI_LANE0_IC_DP: TR16.4 U118.30
HDMI_LANE1_IC_DN: TR17.1 U118.26
HDMI_LANE1_IC_DP: TR17.4 U118.27
HDMI_LANE2_IC_DN: TR18.1 U118.24
HDMI_LANE2_IC_DP: TR18.4 U118.25
HDMI_LANE3_IC_DN: TR19.1 U118.21
HDMI_LANE3_IC_DP: TR19.4 U118.22
HDT_C_M1: HDT1.11 R1702.1
HDT_C_M2: HDT1.13 R1703.1
HDT_C_M3: HDT1.15 R1705.1
HDT_PW_M3: Q50.1 R1701.2
HDT_PW_M4: Q50.3 Q1210.G R504.2
HDT_RST0: HDT1.18 R1747.1
HDT_RST1: HDT1.20 R1748.1
HDT_TRST: HDT1.9 R1743.1
HDT_VDDIO_SUS: HDT1.1 HDT1.19 Q1210.D R1698.2 R1704.1 RN12.5(B) RN12.6(B) RN12.7(B) RN12.8(B)
HM_VCCP: G5.2 R1832.1
HM_VCCP_R: C558.2 R1832.2 U109.95
HPOL_CON: C134.1 Q57.1 R220.2 R221.1 R223.2 R225.2 UHS1.1
HPOR_CON: C159.1 Q57.2 R262.2 R281.1 R284.2 R627.2 UHS1.2
HPOUT-JD: R267.1 UHS1.6
HPOUT-L: R220.1 U6.26
HPOUT-R: R284.1 U6.27
HSI_C_DN3: CPU1.P6 R1712.2
HSI_C_DP3: CPU1.P7 R1711.2
HSI_LAN_DN1: C1808.2 CPU1.T5
HSI_LAN_DN1_R: C1808.1 U16.18
HSI_LAN_DP1: C1805.2 CPU1.T6
HSI_LAN_DP1_R: C1805.1 U16.17
HSO_C_BLAN_DN1: C45.1 CPU1.R3
HSO_C_BLAN_DP1: C44.1 CPU1.R4
HSO_C_DN3: C41.2 R1714.2
HSO_C_DP3: C42.2 R1713.2
HSO_C_LAN_DN1: C45.2 U16.14
HSO_C_LAN_DP1: C44.2 U16.13
ICH_RSMRST_N_R: R374.2 U109.82
ILIM_R: PR4619.2 PR4620.1 PR4637.2
ILIMNB_R: PR4639.2 PR4640.2 PR4644.1
IMS: LVDS1.4 R79659.1 R79661.2 R79691.1
INIT_3V: LPC1.2 R1699.2
IO_SMI_N: CPU1.BB13 R313.2 R80223.1 U4101.13
ISEN1: R51.2 U120.17
ISEN2: R53.2 U120.16
ISEN3: R56.2 U120.14
ISEN4: R59.2 U120.13
ISET: R1596.2 R2086.1 U118.34
ISP_CLK1: Q7.3 Q7.6 R1860.2
ISP_DAT1: Q4.3 Q4.6 R57.2
ISW: C10.1 R79630.2 U120.19
ISW_1: Q1250.1 Q1250.2 Q1250.3 R27.1 R79622.1 R79630.1
JACK_PSID: DCIN1.3 DCIN2.4 DCIN2.11 L15.1
JDREF: R268.1 U6.35
JENK#: TP4125.1 U4101.28
JTAG_TCK_VGA: GPU1.L3 R963.1
JTAG_TDI_VGA: GPU1.L5 R1892.1
JTAG_TDO_VGA: GPU1.K4 R1895.1
JTAG_TMS_VGA: GPU1.L1 R398.1
JTAG_TRST#_VGA: GPU1.L6 R1893.1
KBCLK: RN10.3(A) U109.78
KBRST_N: CPU1.AY15 R1845.1 U109.42
KDAT: RN10.4(A) U109.77
LAD0_FWH0: CPU1.BB11 LPC1.5 R79703.2 RN7.4(A) U109.38
LAD0_FWH0_EC: R79703.1 U4101.62
LAD1_FWH1: CPU1.BA11 LPC1.7 R79702.2 RN7.3(A) U109.39
LAD1_FWH1_EC: R79702.1 U4101.63
LAD2_FWH2: CPU1.AY11 LPC1.9 R79701.2 RN7.2(A) U109.40
LAD2_FWH2_EC: R79701.1 U4101.64
LAD3_FWH3: CPU1.BA13 LPC1.11 R79700.2 RN7.1(A) U109.41
LAD3_FWH3_EC: R79700.1 U4101.1
LAN_DISABLE_N: CPU1.AH2 R774.1 R777.2 R1670.1
LAN_DISABLE_N_1: C591.1 Q102.B R774.2 R1180.1
LAN_DISABLE_N_2: Q101.B Q102.C R764.1 R1180.2
LAN_DISABLE_N_3: Q100.C Q101.C R775.2 R776.1
LAN_DISABLE_N_4: C593.1 PC140.2 Q44.G R776.2
LAN_DISABLE_V3: C863.1 Q100.B R1183.1 R1194.2
LAN_LEDACT_R#: RJ1.10 UR5.2
LAN_MDI0_C_DN: RJ1.2 XF1.2
LAN_MDI0_C_DP: RJ1.1 XF1.1
LAN_MDI0_DN: U10.3 U16.2 XF1.11
LAN_MDI0_DP: U10.4 U16.1 XF1.12
LAN_MDI1_C_DN: RJ1.6 XF1.6
LAN_MDI1_C_DP: RJ1.3 XF1.5
LAN_MDI1_DN: U10.1 U16.5 XF1.7
LAN_MDI1_DP: U10.6 U16.4 XF1.8
LAN_MDI2_C_DN: RJ1.5 XF2.5
LAN_MDI2_C_DP: RJ1.4 XF2.6
LAN_MDI2_DN: PR5250.2 U11.3 XF2.8
LAN_MDI2_DN_R: PR5250.1 U16.7
LAN_MDI2_DP: PR5249.2 U11.4 XF2.7
LAN_MDI2_DP_R: PR5249.1 U16.6
LAN_MDI3_C_DN: RJ1.8 XF2.1
LAN_MDI3_C_DP: RJ1.7 XF2.2
LAN_MDI3_DN: PR5248.2 U11.1 XF2.12
LAN_MDI3_DN_R: PR5248.1 U16.10
LAN_MDI3_DP: PR5247.2 U11.6 XF2.11
LAN_MDI3_DP_R: PR5247.1 U16.9
LAN_RSET: R412.2 U16.31
LAN_XTALI: C1800.1 R407.2 U16.28 X4.1
LAN_XTALO: C1799.1 R407.1 U16.29 X4.3
LANCLK_REQ_N: CPU1.BC15 R413.2 R1674.1
LANCLK_REQ_U_N: R413.1 U16.12
LDR: R65.2 U120.1
LDR_1: Q1250.4 R65.1
LDRQ#: CPU1.BA1 R316.1 R79704.2 U109.2
LDRQ#_EC: R79704.1 U4101.61
LDT_RST: C1721.2 CPU1.D15 R1617.2 R1745.2
LDT_RST#_BUF: HDT1.12 R1745.1
LED_5VSB: LED2.A R1767.2
LEDC_ISET: R82.1 U120.12
LFRAMEJ_FW4: CPU1.AV14 LPC1.13 R1871.1 R1872.2 R1875.2 R79698.2 U109.37
LFRAMEJ_FW4_EC: R79698.1 U4101.3
LINE2-VREFO: R261.1 R272.1 U6.29
LINEOUT-JD: LOUT1.Q R266.1
LINEOUT-L: R429.1 U6.19
LINEOUT-R: R428.1 U6.18
LINEOUT_C-L: L62.1 R429.2
LINEOUT_C-R: L20.1 R428.2
LINEOUT_CON-L: C268.1 L62.2 LOUT1.4 Q46.1
LINEOUT_CON-R: C267.1 L20.2 LOUT1.1 Q46.2
LINK_ACTIVITY_N: U12.4 U16.27 UR5.1
LINK_PWR: R79618.2 RJ1.9
LPC_CLK0_R: CPU1.AW14 R1646.2
LPC_CLK1: C66.1 LPC1.1 R123.1 R1869.1 R1870.2 R1876.2
LPC_CLK1_R: CPU1.AY13 R123.2
LPC_PD_N: CPU1.AE9 TP9.1
LPC_PME_N: R568.1 R1843.2 R79709.2 R80224.2
LPC_TPM: CPU1.AW12 TP187.1
LPF: C3455.1 U120.9
LVDS_BL_ADJ: R131.1 R132.1 R133.1 R134.2 R1984.1
LVDS_BL_EN_1: R79686.2 U109.54
LVDS_DET_A*: LVDS1.17 R482.2 U109.116
LVDS_DET_B*: Q103.D R483.2 U109.117
LVDS_DET_B_C*: C869.1 LVDS1.1 Q103.G
LVDS_PU_5: LVDS1.5 R1163.2
LVDS_PU_5_1: Q9647.D R484.1
LVDS_PU_5_2: Q9647.G Q9650.D R80233.1
LVDS_PU_6: LVDS1.6 R484.2
LVDS_PU_24: LVDS1.24 R481.2
LX: D32.A L61.2 Q1250.5 Q1250.6 Q1250.7 Q1250.8 R79619.1
M1_SMB_CLK: NGFF1.60 R14.2
M1_SMB_DATA: NGFF1.58 R1622.2
M_CAS_A_N: CPU1.AK32 DIMM1.115 DIMM2.115
M_DATA_A0: CPU1.A25 DIMM1.5 DIMM2.5
M_DATA_A1: CPU1.C25 DIMM1.7 DIMM2.7
M_DATA_A2: CPU1.C27 DIMM1.15 DIMM2.15
M_DATA_A3: CPU1.D27 DIMM1.17 DIMM2.17
M_DATA_A4: CPU1.B24 DIMM1.4 DIMM2.4
M_DATA_A5: CPU1.B25 DIMM1.6 DIMM2.6
M_DATA_A6: CPU1.B27 DIMM1.16 DIMM2.16
M_DATA_A7: CPU1.A27 DIMM1.18 DIMM2.18
M_DATA_A8: CPU1.A29 DIMM1.21 DIMM2.21
M_DATA_A9: CPU1.C29 DIMM1.23 DIMM2.23
M_DATA_A10: CPU1.B32 DIMM1.33 DIMM2.33
M_DATA_A11: CPU1.D32 DIMM1.35 DIMM2.35
M_DATA_A12: CPU1.B28 DIMM1.22 DIMM2.22
M_DATA_A13: CPU1.B29 DIMM1.24 DIMM2.24
M_DATA_A14: CPU1.A31 DIMM1.34 DIMM2.34
M_DATA_A15: CPU1.C31 DIMM1.36 DIMM2.36
M_DATA_A16: CPU1.E30 DIMM1.39 DIMM2.39
M_DATA_A17: CPU1.E31 DIMM1.41 DIMM2.41
M_DATA_A18: CPU1.G33 DIMM1.51 DIMM2.51
M_DATA_A19: CPU1.G32 DIMM1.53 DIMM2.53
M_DATA_A20: CPU1.C33 DIMM1.40 DIMM2.40
M_DATA_A21: CPU1.D33 DIMM1.42 DIMM2.42
M_DATA_A22: CPU1.G30 DIMM1.50 DIMM2.50
M_DATA_A23: CPU1.G31 DIMM1.52 DIMM2.52
M_DATA_A24: CPU1.J30 DIMM1.57 DIMM2.57
M_DATA_A25: CPU1.J31 DIMM1.59 DIMM2.59
M_DATA_A26: CPU1.L33 DIMM1.67 DIMM2.67
M_DATA_A27: CPU1.L32 DIMM1.69 DIMM2.69
M_DATA_A28: CPU1.H32 DIMM1.56 DIMM2.56
M_DATA_A29: CPU1.H33 DIMM1.58 DIMM2.58
M_DATA_A30: CPU1.L30 DIMM1.68 DIMM2.68
M_DATA_A31: CPU1.L31 DIMM1.70 DIMM2.70
M_DATA_A32: CPU1.AN31 DIMM1.129 DIMM2.129
M_DATA_A33: CPU1.AP32 DIMM1.131 DIMM2.131
M_DATA_A34: CPU1.AT32 DIMM1.141 DIMM2.141
M_DATA_A35: CPU1.AU32 DIMM1.143 DIMM2.143
M_DATA_A36: CPU1.AN33 DIMM1.130 DIMM2.130
M_DATA_A37: CPU1.AN32 DIMM1.132 DIMM2.132
M_DATA_A38: CPU1.AR31 DIMM1.140 DIMM2.140
M_DATA_A39: CPU1.AT33 DIMM1.142 DIMM2.142
M_DATA_A40: CPU1.AU30 DIMM1.147 DIMM2.147
M_DATA_A41: CPU1.AV32 DIMM1.149 DIMM2.149
M_DATA_A42: CPU1.BA33 DIMM1.157 DIMM2.157
M_DATA_A43: CPU1.AY32 DIMM1.159 DIMM2.159
M_DATA_A44: CPU1.AU33 DIMM1.146 DIMM2.146
M_DATA_A45: CPU1.AU31 DIMM1.148 DIMM2.148
M_DATA_A46: CPU1.AW31 DIMM1.158 DIMM2.158
M_DATA_A47: CPU1.AY33 DIMM1.160 DIMM2.160
M_DATA_A48: CPU1.BC31 DIMM1.163 DIMM2.163
M_DATA_A49: CPU1.BB30 DIMM1.165 DIMM2.165
M_DATA_A50: CPU1.BB28 DIMM1.175 DIMM2.175
M_DATA_A51: CPU1.AY27 DIMM1.177 DIMM2.177
M_DATA_A52: CPU1.BB32 DIMM1.164 DIMM2.164
M_DATA_A53: CPU1.BA31 DIMM1.166 DIMM2.166
M_DATA_A54: CPU1.BC29 DIMM1.174 DIMM2.174
M_DATA_A55: CPU1.BB29 DIMM1.176 DIMM2.176
M_DATA_A56: CPU1.BB27 DIMM1.181 DIMM2.181
M_DATA_A57: CPU1.BB26 DIMM1.183 DIMM2.183
M_DATA_A58: CPU1.BB24 DIMM1.191 DIMM2.191
M_DATA_A59: CPU1.AY23 DIMM1.193 DIMM2.193
M_DATA_A60: CPU1.BA27 DIMM1.180 DIMM2.180
M_DATA_A61: CPU1.BC27 DIMM1.182 DIMM2.182
M_DATA_A62: CPU1.BC25 DIMM1.192 DIMM2.192
M_DATA_A63: CPU1.BB25 DIMM1.194 DIMM2.194
M_DQS_A_DN0: CPU1.A26 DIMM1.10 DIMM2.10
M_DQS_A_DN1: CPU1.A30 DIMM1.27 DIMM2.27
M_DQS_A_DN2: CPU1.E32 DIMM1.45 DIMM2.45
M_DQS_A_DN3: CPU1.J32 DIMM1.62 DIMM2.62
M_DQS_A_DN4: CPU1.AR33 DIMM1.135 DIMM2.135
M_DQS_A_DN5: CPU1.AW33 DIMM1.152 DIMM2.152
M_DQS_A_DN6: CPU1.AY29 DIMM1.169 DIMM2.169
M_DQS_A_DN7: CPU1.AY25 DIMM1.186 DIMM2.186
M_DQS_A_DP0: CPU1.B26 DIMM1.12 DIMM2.12
M_DQS_A_DP1: CPU1.B30 DIMM1.29 DIMM2.29
M_DQS_A_DP2: CPU1.F32 DIMM1.47 DIMM2.47
M_DQS_A_DP3: CPU1.K32 DIMM1.64 DIMM2.64
M_DQS_A_DP4: CPU1.AR32 DIMM1.137 DIMM2.137
M_DQS_A_DP5: CPU1.AW32 DIMM1.154 DIMM2.154
M_DQS_A_DP6: CPU1.BA29 DIMM1.171 DIMM2.171
M_DQS_A_DP7: CPU1.BA25 DIMM1.188 DIMM2.188
M_MA_DM0: CPU1.D25 DIMM1.11 DIMM2.11
M_MA_DM1: CPU1.D29 DIMM1.28 DIMM2.28
M_MA_DM2: CPU1.E33 DIMM1.46 DIMM2.46
M_MA_DM3: CPU1.J33 DIMM1.63 DIMM2.63
M_MA_DM4: CPU1.AR30 DIMM1.136 DIMM2.136
M_MA_DM5: CPU1.AW30 DIMM1.153 DIMM2.153
M_MA_DM6: CPU1.BC30 DIMM1.170 DIMM2.170
M_MA_DM7: CPU1.BC26 DIMM1.187 DIMM2.187
M_MAA_A0: CPU1.AG31 DIMM1.98 DIMM2.98
M_MAA_A1: CPU1.AC30 DIMM1.97 DIMM2.97
M_MAA_A2: CPU1.AC31 DIMM1.96 DIMM2.96
M_MAA_A3: CPU1.AB32 DIMM1.95 DIMM2.95
M_MAA_A4: CPU1.AA32 DIMM1.92 DIMM2.92
M_MAA_A5: CPU1.AA33 DIMM1.91 DIMM2.91
M_MAA_A6: CPU1.AA31 DIMM1.90 DIMM2.90
M_MAA_A7: CPU1.Y33 DIMM1.86 DIMM2.86
M_MAA_A8: CPU1.AA30 DIMM1.89 DIMM2.89
M_MAA_A9: CPU1.W32 DIMM1.85 DIMM2.85
M_MAA_A10: CPU1.AG32 DIMM1.107 DIMM2.107
M_MAA_A11: CPU1.Y32 DIMM1.84 DIMM2.84
M_MAA_A12: CPU1.W33 DIMM1.83 DIMM2.83
M_MAA_A13: CPU1.AL31 DIMM1.119 DIMM2.119
M_MAA_A14: CPU1.W30 DIMM1.80 DIMM2.80
M_MAA_A15: CPU1.V32 DIMM1.78 DIMM2.78
M_ODT_A0: CPU1.AL30 DIMM1.116
M_ODT_A1: CPU1.AM32 DIMM1.120
M_ODT_B0: CPU1.AJ32 DIMM2.116
M_ODT_B1: CPU1.AM33 DIMM2.120
M_RAS_A_N: CPU1.AH33 DIMM1.110 DIMM2.110
M_SBS_A0: CPU1.AH32 DIMM1.109 DIMM2.109
M_SBS_A1: CPU1.AG33 DIMM1.108 DIMM2.108
M_SBS_A2: CPU1.W31 DIMM1.79 DIMM2.79
M_SCKE_A0: CPU1.U32 DIMM1.73 DIMM2.73
M_SCKE_A1: CPU1.U33 DIMM1.74 DIMM2.74
M_SCS_A_N0: CPU1.AJ33 DIMM1.114
M_SCS_A_N1: CPU1.AL32 DIMM1.121
M_SCS_B_N0: CPU1.AJ30 DIMM2.114
M_SCS_B_N1: CPU1.AL33 DIMM2.121
M_WE_A_N: CPU1.AJ31 DIMM1.113 DIMM2.113
MAA0: GPU1.K17 MEM1.N3 MEM2.N3 MEM3.N3 MEM4.N3
MAA1: GPU1.J20 MEM1.P7 MEM2.P7 MEM3.P7 MEM4.P7
MAA2: GPU1.H23 MEM1.P3 MEM2.P3 MEM3.P3 MEM4.P3
MAA3: GPU1.G23 MEM1.N2 MEM2.N2 MEM3.N2 MEM4.N2
MAA4: GPU1.G24 MEM1.P8 MEM2.P8 MEM3.P8 MEM4.P8
MAA5: GPU1.H24 MEM1.P2 MEM2.P2 MEM3.P2 MEM4.P2
MAA6: GPU1.J19 MEM1.R8 MEM2.R8 MEM3.R8 MEM4.R8
MAA7: GPU1.K19 MEM1.R2 MEM2.R2 MEM3.R2 MEM4.R2
MAA8: GPU1.J14 MEM1.T8 MEM2.T8 MEM3.T8 MEM4.T8
MAA9: GPU1.K14 MEM1.R3 MEM2.R3 MEM3.R3 MEM4.R3
MAA10: GPU1.J11 MEM1.L7 MEM2.L7 MEM3.L7 MEM4.L7
MAA11: GPU1.J13 MEM1.R7 MEM2.R7 MEM3.R7 MEM4.R7
MAA12: GPU1.H11 MEM1.N7 MEM2.N7 MEM3.N7 MEM4.N7
MAA13: GPU1.G20 MEM1.T3 MEM2.T3 MEM3.T3 MEM4.T3
MAA14: GPU1.G14 MEM1.T7 MEM2.T7 MEM3.T7 MEM4.T7
MAA_BA0: GPU1.J16 MEM1.M2 MEM2.M2 MEM3.M2 MEM4.M2
MAA_BA1: GPU1.L15 MEM1.N8 MEM2.N8 MEM3.N8 MEM4.N8
MAA_BA2: GPU1.G11 MEM1.M3 MEM2.M3 MEM3.M3 MEM4.M3
MCLK: RN10.1(A) U109.80
MCT_R: R79612.2 RV1.2 XF1.3 XF1.4 XF2.3 XF2.4
MCT_R_1: C3131.1 R79612.1
MDA0: GPU1.K27 MEM3.F8
MDA1: GPU1.J29 MEM3.F7
MDA2: GPU1.H30 MEM3.H3
MDA3: GPU1.H32 MEM3.E3
MDA4: GPU1.G29 MEM3.G2
MDA5: GPU1.F28 MEM3.F2
MDA6: GPU1.F32 MEM3.H8
MDA7: GPU1.F30 MEM3.H7
MDA8: GPU1.C30 MEM3.D7
MDA9: GPU1.F27 MEM3.C8
MDA10: GPU1.A28 MEM3.B8
MDA11: GPU1.C28 MEM3.A7
MDA12: GPU1.E27 MEM3.A3
MDA13: GPU1.G26 MEM3.A2
MDA14: GPU1.D26 MEM3.C2
MDA15: GPU1.F25 MEM3.C3
MDA16: GPU1.A25 MEM1.A2
MDA17: GPU1.C25 MEM1.C2
MDA18: GPU1.E25 MEM1.A3
MDA19: GPU1.D24 MEM1.C3
MDA20: GPU1.E23 MEM1.A7
MDA21: GPU1.F23 MEM1.D7
MDA22: GPU1.D22 MEM1.B8
MDA23: GPU1.F21 MEM1.C8
MDA24: GPU1.E21 MEM1.G2
MDA25: GPU1.D20 MEM1.E3
MDA26: GPU1.F19 MEM1.H3
MDA27: GPU1.A19 MEM1.F2
MDA28: GPU1.D18 MEM1.H8
MDA29: GPU1.F17 MEM1.H7
MDA30: GPU1.A17 MEM1.F7
MDA31: GPU1.C17 MEM1.F8
MDA32: GPU1.E17 MEM4.F8
MDA33: GPU1.D16 MEM4.H8
MDA34: GPU1.F15 MEM4.F7
MDA35: GPU1.A15 MEM4.H7
MDA36: GPU1.D14 MEM4.H3
MDA37: GPU1.F13 MEM4.G2
MDA38: GPU1.A13 MEM4.E3
MDA39: GPU1.C13 MEM4.F2
MDA40: GPU1.E11 MEM2.C3
MDA41: GPU1.A11 MEM2.A3
MDA42: GPU1.C11 MEM2.A2
MDA43: GPU1.F11 MEM2.C2
MDA44: GPU1.A9 MEM2.A7
MDA45: GPU1.C9 MEM2.B8
MDA46: GPU1.F9 MEM2.D7
MDA47: GPU1.D8 MEM2.C8
MDA48: GPU1.E7 MEM2.E3
MDA49: GPU1.A7 MEM2.H3
MDA50: GPU1.C7 MEM2.F2
MDA51: GPU1.F7 MEM2.G2
MDA52: GPU1.A5 MEM2.H8
MDA53: GPU1.E5 MEM2.F7
MDA54: GPU1.C3 MEM2.H7
MDA55: GPU1.E1 MEM2.F8
MDA56: GPU1.G7 MEM4.D7
MDA57: GPU1.G6 MEM4.C8
MDA58: GPU1.G1 MEM4.A2
MDA59: GPU1.G3 MEM4.A7
MDA60: GPU1.J6 MEM4.B8
MDA61: GPU1.J1 MEM4.C2
MDA62: GPU1.J3 MEM4.C3
MDA63: GPU1.J5 MEM4.A3
MDAT: RN10.2(A) U109.79
MEM_CALRP0: GPU1.K25 R1201.2
MEM_MA_EVENT_L: CPU1.AG30 DIMM1.198 DIMM2.198 Q1207.E R1584.2
MEM_MA_ZVDDIO: CPU1.AD29 R1696.1
MEM_MB_ZVDDIO: CPU1.AF32 R121.1
MEM_RST: MEM1.T2 MEM2.T2 MEM3.T2 MEM4.T2 R1204.2 R1891.2
MEM_VREFCA_SUS: C65.2 C1746.2 C1979.2 C1980.2 DIMM1.126 DIMM2.126 R120.2 R122.1 R2059.2 R2060.1
MIC2-L: C139.1 U6.47
MIC2-L-1: C139.2 R225.1
MIC2-R: C138.1 U6.48
MIC2-R-1: C138.2 R627.1
MIC2-VREFO-L: R223.1 U6.1
MIC2-VREFO-R: R262.1 U6.30
MIC-CAP: C154.1 U6.36
MINI_POWER_CTRL: R15.1 RN8.4(B) U109.55
MLPS_EN#: GPU1.R5 R1882.1
MODEL_ID_DET: R79722.1 R79723.2 U4101.50
MPCIE_DISABLE_N: R1620.1 RN8.3(B) U109.56
MPV18: C786.1 C790.1 C791.1 GPU1.L8 L50.2
MVREFDA: C760.1 GPU1.K26 R1888.1 R1890.2
MVREFSA: C761.1 GPU1.J26 R1200.2 R1889.1
NB_VRM_PWRGD: PR4632.2 PU4601.8 R79674.1
NGFF_ALERT#: CPU1.BB19 R1717.1 R1749.1
NGFF_ALERT_N: NGFF1.62 R1717.2
NGFF_BT_DISABLE: R1621.1 R1933.1 U109.125
NGFF_CLKREQ0_N: NGFF1.53 R1931.1
NGFF_CLKREQ0_NGFF#: Q1229.S R1931.2 R1932.2
NGFF_CLKREQ1_APU#: CPU1.BB17 Q1229.D
NGFF_CLKREQ1_N: NGFF1.68 R1925.2
NGFF_CLKREQ1_N_TP: R1925.1 TP208.1
NGFF_DETECT_PCIE: CPU1.BA19 R1155.2 R1926.1
NGFF_DETECT_PCIE_C: NGFF1.51 R1155.1 R1709.1
NGFF_DETECT_USB: R1154.2 R1935.2 U109.126
NGFF_DETECT_USB_C: NGFF1.1 R1154.1 R1209.1
NGFF_PCIE0_RXN: NGFF1.43 R1712.1
NGFF_PCIE0_RXP: NGFF1.41 R1711.1
NGFF_PCIE0_TXN: NGFF1.37 R1714.1
NGFF_PCIE0_TXP: NGFF1.35 R1713.1
NGFF_PCIE1_RXN: NGFF1.67 TP82.1
NGFF_PCIE1_RXP: NGFF1.65 TP81.1
NGFF_PCIE1_TXN: NGFF1.61 TP80.1
NGFF_PCIE1_TXP: NGFF1.59 TP79.1
NGFF_PEWAKE0_N: NGFF1.55 NGFF1.70 R1718.2 R1719.1
NGFF_POWER_CTRL_1: Q3.G R15.2
NGFF_POWER_CTRL_V2: C864.1 Q128.B R1716.1
NGFF_REFCLKN0: NGFF1.49 R23.1
NGFF_REFCLKN1: NGFF1.73 TP84.1
NGFF_REFCLKP0: NGFF1.47 R22.1
NGFF_REFCLKP1: NGFF1.71 TP83.1
NGFF_W_DISABLE1_N: NGFF1.56 R1620.2
NGFF_W_DISABLE2_N: NGFF1.54 R1621.2
ODTA0: GPU1.L18 MEM1.K1 MEM3.K1
ODTA1: GPU1.K16 MEM2.K1 MEM4.K1
OSD_BIST_N: R535.1 R744.2
OSD_BIST_N_1: Q12.2 R535.2
OSD_DN: C238.1 CPU1.AL6 R1755.1 R1758.1
OSD_DN_R: PWRCN1.2 R1755.2
OSD_MENU: C585.1 CPU1.AH1 R755.1 R758.1 R80206.1
OSD_MENU_R: PWRCN1.1 R758.2
OSD_MENU_SIO: R80206.2 U109.109
OSD_UP: C582.1 CPU1.AJ3 R742.2 R743.1 R744.1
OSD_UP_R: PWRCN1.3 R743.2
OZ554_ENA: C3458.1 R79625.1 R79627.1 U120.3
OZ554_PWM: C8.1 R79621.1 R79623.1 U120.5
OZ554_VIN: C3457.1 R5.2 U120.4
P_GFX_TXN0: C1811.1 CPU1.M1
P_GFX_TXN1: C1813.1 CPU1.L2
P_GFX_TXN2: C1814.1 CPU1.L3
P_GFX_TXN3: C122.1 CPU1.J2
P_GFX_TXP0: C1809.1 CPU1.M2
P_GFX_TXP1: C1810.1 CPU1.L1
P_GFX_TXP2: C1812.1 CPU1.L4
P_GFX_TXP3: C1815.1 CPU1.J1
P_RX_ZVDD: CPU1.U6 R557.1 R2003.1
P_TX_ZVDD: CPU1.U7 R558.2
PANEL_ON_1: R33.1 R39.1 R41.2 R42.1
PANEL_ON_2: Q10.B R42.2
PANEL_ON_3: C14.2 Q5.D R19.1 R20.2 U1.3
PANEL_ON_4: Q1.G Q5.G Q10.C R26.2 R30.1
PANEL_ON_5: Q1.D R8.1
PANEL_SEL1_CABLE: CONVT1.7 R1730.2 R1734.2
PANEL_SEL1_CABLE_EC: R1730.1 U109.102
PANEL_SEL2_CABLE: CONVT1.8 R287.2 R1731.2
PANEL_SEL2_CABLE_EC: R287.1 U109.103
PANEL_SEL3_CABLE: CONVT1.9 R1732.2 R1733.2
PANEL_SEL3_CABLE_EC: R1732.1 U109.104
PB_IN_N_1: C197.2 R379.2 R385.2 R79669.1 U109.72
PB_IN_N_2: R79669.2 U109.111
PB_IN_SW1: PWRCN1.6 R1756.1 R1760.2
PCB_VER_ID: R79720.1 R79721.2 U4101.49
PCH_AUD_RST_N: R289.1 R637.1 U109.19
PCH_AUD_RST_N_1: Q63.5 R637.2
PCH_CLK48_F: CPU1.BC10 R1645.2
PCH_SATA_LED_1: Q38.B Q1213.C R1759.2
PCH_SATA_LED_R: Q1213.B R1754.2
PCIE_CALR_RX: GPU1.AA22 R1162.1
PCIE_CALR_TX: GPU1.Y22 R1161.1
PCIE_RST#: NGFF1.52 NGFF1.66 RN13.1(A)
PCIE_RST_N: CPU1.AN7 R1678.2
PCIE_RST_N_A: C1738.1 R1678.1
PCIRST1#: R79690.1 RN13.6(B) U109.30
PCIRST3#: R79689.1 RN13.7(B) RN13.8(B) U109.81
PD4405_A: PD4405.A PQ4409.B
PD4405_K: PD4405.K PR4458.2
PD_N: Q1249.D U118.36
PEG_C_RXN0: C1840.1 GPU1.AG31
PEG_C_RXN1: C1842.1 GPU1.AF28
PEG_C_RXN2: C1844.1 GPU1.AF26
PEG_C_RXN3: C1845.1 GPU1.AD26
PEG_C_RXP0: C1838.1 GPU1.AH30
PEG_C_RXP1: C1839.1 GPU1.AG29
PEG_C_RXP2: C1841.1 GPU1.AF27
PEG_C_RXP3: C1843.1 GPU1.AD27
PEG_RXN0: C1840.2 CPU1.P9
PEG_RXN1: C1842.2 CPU1.N5
PEG_RXN2: C1844.2 CPU1.N8
PEG_RXN3: C1845.2 CPU1.L6
PEG_RXP0: C1838.2 CPU1.P10
PEG_RXP1: C1839.2 CPU1.N6
PEG_RXP2: C1841.2 CPU1.N9
PEG_RXP3: C1843.2 CPU1.L7
PEG_TXN0: C1811.2 GPU1.AE31
PEG_TXN1: C1813.2 GPU1.AD28
PEG_TXN2: C1814.2 GPU1.AC31
PEG_TXN3: C122.2 GPU1.AB28
PEG_TXP0: C1809.2 GPU1.AF30
PEG_TXP1: C1810.2 GPU1.AE29
PEG_TXP2: C1812.2 GPU1.AD30
PEG_TXP3: C1815.2 GPU1.AC29
PHASE1_R: PG4.1 PR45.2
PLTRST*_EC: R79697.1 U4101.6
PLTRST*_SIO: C76.2 R351.1 R352.1 U109.46
PLTRST_LAN_N: RN13.2(A) U16.19
PLTRST_N: C77.1 CPU1.BB12 LPC1.3 R352.2 R79697.2
PLTRST_SL_N: D7.1 D7.2 D34.3 R1159.1 R1160.2 RN13.3(A)
PM_DPRSLPVR: PR7.1 PR15.2 PR17.1
PME#_M: CPU1.AD7 R568.2
PORTC_SPK_L: R345.1 U6.43
PORTC_SPK_L_1: R345.2 R356.1
PORTC_SPK_R: R359.1 U6.44
PORTC_SPK_R_1: R359.2 R367.1
PQ4206_D: PQ4206.D PR4214.2
PQ4406_2: PQ4406.2 PR4462.2
PQ4406_3: PQ4406.3 PR4455.2
PQ4406_5: PC4426.1 PQ4406.5 PR4413.2
PQ4406_6: PC4426.2 PQ4406.6 PR4450.1
PQ4409_C: PQ4409.C PR4451.1 PR4462.1
PQ4409_E: PQ4409.E PR4431.2 PR4433.1
PRE: R2088.2 R2090.1 U118.16
PRW_VGA_CORE_RBIAS: PR9.1 U9.3
PS_0: C1847.1 GPU1.AC19 R388.1 R394.1
PS_1: C1849.2 GPU1.AD19 R943.1 R948.1
PS_2: C1850.1 GPU1.AE17 R1899.1 R1900.1
PS_3: C1848.1 GPU1.AE20 R935.2 R940.1
PSI#: PR3.1 PR4.2 PR10.2
PSID_D: L15.2 Q47.D R1852.1
PSID_D_1: Q45.B R1852.2 R1853.1
PSID_G: Q45.C Q47.G R1849.2
PW_CLEAR: CPU1.AE2 PSWD1.2 R184.1
PWR_1D8V_BOOT: PR5205.1 PU5201.10
PWR_1D8V_BOOT_A: PC5217.1 PR5205.2
PWR_1D8V_EN: PC34.1 PR57.2 PR62.2 PR5223.1 PU5201.13 R77.1
PWR_1D8V_FB: PC5203.2 PR5201.2 PR5209.1 PU5201.12
PWR_1D8V_FB_1: PC5203.1 PG5211.2 PR5201.1
PWR_1D8V_LX: PC5217.2 PL5202.1 PR5204.1 PU5201.8 PU5201.9 PU5201.15 PU5201.16
PWR_1D8V_SNB: PC5202.1 PR5204.2
PWR_1D8V_VCC: PC5204.1 PU5201.11
PWR_1D8V_VOUT: PG5212.2 PU5201.7
PWR_3D3V_BOOT2: PR4902.2 PU4901.7
PWR_3D3V_BOOT2_R: PC4907.2 PR4902.1
PWR_3D3V_ENTRIP2: PC4918.1 PR4924.1 PU4901.4
PWR_3D3V_FB: PC4911.2 PG4902.1 PR4914.1
PWR_3D3V_FB2: PC4911.1 PR4914.2 PR4917.1 PU4901.5
PWR_3D3V_LDO3: PC4914.2 PG4904.1 PU4901.15
PWR_3D3V_LGATE2: PU4901.10 PU4903.4
PWR_3D3V_PHASE2: PC4907.1 PL4903.2 PR4911.1 PU4901.9 PU4902.1 PU4902.2 PU4902.3 PU4903.5 PU4903.6 PU4903.7 PU4903.8
PWR_3D3V_SNB: PC4916.1 PR4911.2
PWR_3D3V_UGATE2: PU4901.8 PU4902.4
PWR_5V3V_EMN: PR4918.2 PR4920.1 PU4901.13
PWR_5V3V_ENLDO: PR4901.2 PU4901.12
PWR_5V3V_LDO5: PC4906.1 PG4901.1 PU4901.14
PWR_5V3V_PGOOD: PU4901.6 R1762.2
PWR_5V3V_TON: PR4919.1 PU4901.3
PWR_5V_BOOT1: PR4903.1 PU4901.19
PWR_5V_BOOT1_R: PC4908.1 PR4903.2
PWR_5V_BYP1: PC4912.1 PC4913.1 PG4903.2 PR4921.2 PU4901.20
PWR_5V_ENTRIP1: PC4917.1 PR4925.1 PU4901.2
PWR_5V_FB1: PC4913.2 PR4921.1 PR4922.1 PU4901.1
PWR_5V_LGATE1: PU4901.16 PU4905.4
PWR_5V_PHASE1: PC4908.2 PL4904.1 PR4912.1 PU4901.17 PU4904.1 PU4904.2 PU4904.3 PU4905.5 PU4905.6 PU4905.7 PU4905.8
PWR_5V_SNB: PC4915.1 PR4912.2
PWR_5V_UGATE1: PU4901.18 PU4904.4
PWR_CHG_ACDET: PC5232.1 PR4412.1 PR5270.2 U55.6
PWR_CHG_ACN: PC4402.1 PC4404.1 PG4905.2 U55.1
PWR_CHG_ACP: PC4402.2 PC4403.1 PG4907.2 U55.2
PWR_CHG_AD_OFF: PQ4206.G PR4210.1 R80230.1 U4101.19
PWR_CHG_AD_OFF_R: PQ4204.B PR4210.2
PWR_CHG_BTST: PR5279.1 U55.17
PWR_CHG_BTST_1: PC5234.1 PD4401.K PR5279.2
PWR_CHG_CMPIN: PR5287.2 PR5467.2 PR5468.1 PR5469.2 PR5470.1 U55.4
PWR_CHG_CMPIN_R: PQ5006.6 PR5470.2
PWR_CHG_CMPIN_RR: PQ5006.3 PR5469.1
PWR_CHG_HIDRV: PU4403.4 U55.18
PWR_CHG_ILIM: PQ5003.D PR5268.1 PR5278.2 U55.10
PWR_CHG_IOUT: PC5239.1 PR5288.1 PR5467.1 U55.7
PWR_CHG_LODRV: PC5237.1 PU4405.4 U55.15
PWR_CHG_NC: PR5286.1 U55.11
PWR_CHG_PHASE: PC5234.2 PL5003.1 PU4403.1 PU4403.2 PU4403.3 PU4405.5 PU4405.6 PU4405.7 PU4405.8 U55.19
PWR_CHG_SRN: PR5277.1 U55.12
PWR_CHG_SRP: PR5283.1 U55.13
PWR_CHG_VCC: PC4408.1 PR5284.2 U55.20
PWR_COMP_R: PC4626.1 PR4645.2
PWR_CPU_BST1: PR4701.1 PU4601.28
PWR_CPU_BST2: PR4703.1 PU4601.37
PWR_CPU_COMP: PC4626.2 PC4627.2 PU4601.48
PWR_CPU_COMPNB: PC4611.2 PC4612.2 PU4601.18
PWR_CPU_CSCOMP: PC4603.2 PC4615.2 PC4618.1 PR4601.2 PR4619.1 PR4626.2 PR4637.1 PU4601.45
PWR_CPU_CSCOMPNB: PC4613.1 PC4617.2 PC4624.2 PR4609.2 PR4638.2 PR4639.1 PR4640.1 PU4601.21
PWR_CPU_CSN1: PG4702.2 PR4618.2
PWR_CPU_CSN1NB: PG4704.2 PR4612.2
PWR_CPU_CSP1: PC4628.2 PR4615.1 PU4601.40
PWR_CPU_CSP1NB: PC4623.1 PR4608.1 PU4601.26
PWR_CPU_CSP2: PR4631.1 PU4601.41
PWR_CPU_CSP2NB: PR4633.1 PU4601.25
PWR_CPU_CSREF: PC4606.1 PC4628.1 PR4618.1 PU4601.42
PWR_CPU_CSREFNB: PC4622.1 PC4623.2 PR4612.1 PU4601.24
PWR_CPU_CSSUM: PC4615.1 PC4618.2 PR4620.2 PR4641.1 PU4601.43
PWR_CPU_CSSUMNB: PC4613.2 PC4617.1 PR4625.1 PR4644.2 PU4601.23
PWR_CPU_DIFF: PR4634.1 PR4636.1 PU4601.50
PWR_CPU_DIFFNB: PR4621.1 PR4622.1 PU4601.16
PWR_CPU_DROOP: PC4603.1 PR4601.1 PU4601.46
PWR_CPU_DROOPNB: PC4624.1 PR4638.1 PU4601.20
PWR_CPU_FB: PC4621.2 PC4627.1 PR4636.2 PR4645.1 PU4601.49
PWR_CPU_FBNB: PC4610.2 PC4612.1 PR4621.2 PR4623.1 PU4601.17
PWR_CPU_HG1: PU4601.29 PU5207.4
PWR_CPU_HG2: PU4601.36 PU4702.4
PWR_CPU_ILIM: PR4626.1 PU4601.44
PWR_CPU_ILIMNB: PR4609.1 PU4601.22
PWR_CPU_IOUT: PC4609.2 PR4614.1 PU4601.47
PWR_CPU_IOUTNB: PC4616.1 PR4627.1 PU4601.19
PWR_CPU_LG1: PU4601.31 PU4705.4 PU4706.4
PWR_CPU_LG2: PU4601.34 PU4703.4 PU4704.4
PWR_CPU_PHCONFIG: PR4635.1 PU4601.38
PWR_CPU_ROSC: PR4610.2 PU4601.11
PWR_CPU_SNBNB: PC4712.1 PR4704.2
PWR_CPU_SNBVDD1: PC4706.1 PR4702.2
PWR_CPU_SR: PR4603.1 PU4601.39
PWR_CPU_SW1: PC4704.2 PG4701.1 PL4701.1 PR4702.1 PU4601.30 PU4705.5 PU4705.6 PU4705.7 PU4705.8 PU4706.5 PU4706.6 PU4706.7 PU4706.8 PU5207.1 PU5207.2 PU5207.3
PWR_CPU_SW2: PC4710.2 PG4703.1 PL4702.1 PR4704.1 PU4601.35 PU4702.1 PU4702.2 PU4702.3 PU4703.5 PU4703.6 PU4703.7 PU4703.8 PU4704.5 PU4704.6 PU4704.7 PU4704.8
PWR_CPU_SWN1: PG4701.2 PR4615.2 PR4641.2
PWR_CPU_SWN1NB: PG4703.2 PR4608.2 PR4625.2
PWR_CPU_TEENSE: PC4607.2 PR4605.2 PR4613.2 PU4601.1
PWR_CPU_TSENSENB: PC4619.2 PR4629.2 PR4630.2 PU4601.14
PWR_CPU_VCC: PC4602.1 PR4602.2 PU4601.10
PWR_CPU_VDD: PC4601.1 PR4604.1 PU4601.51
PWR_CPU_VDDNB: PC4605.1 PR4642.1 PU4601.15
PWR_CPU_VRMP: PC4614.1 PR4616.2 PU4601.12
PWR_DCBATOUT_1D8V: PC5209.1 PC5214.1 PG5205.2 PG5210.2 PU5201.1
PWR_DCBATOUT_3V: PC4901.1 PC4902.1 PR4927.2 PR4929.2 PU4902.5 PU4902.6 PU4902.7 PU4902.8
PWR_DCBATOUT_5V: PC4904.1 PC4905.1 PR4930.2 PR4931.2 PR4932.2 PR4933.2 PT4901.1 PU4904.5 PU4904.6 PU4904.7 PU4904.8
PWR_DCBATOUT_VDDP: PC4713.1 PC4801.1 PC4808.1 PR4814.2 PR4815.2 PU4802.5 PU4802.6 PU4802.7 PU4802.8
PWR_DIFF_R: PC4621.1 PR4634.2
PWR_FCH_REF: PC51.1 PR5472.1 PR5473.2 PU5.3
PWR_FCH_S5: PC50.1 PC5428.1 PU5.4 Q4701.6 Q6704.1 Q6704.2
PWR_FCH_VCNTL: PC49.1 PR5475.2 PU5.6
PWR_GFX_BST1: PR5404.1 PU5407.28
PWR_GFX_BST1_SW1: PC5411.1 PR5404.2
PWR_GFX_COMP: PC5416.2 PC5417.2 PU5407.48
PWR_GFX_COMP_FB: PC5417.1 PR5415.2
PWR_GFX_CSCOMP: PC5414.1 PC5419.2 PC5425.2 PR5414.1 PR5417.2 PR5425.1 PR5428.2 PU5407.45
PWR_GFX_CSN1: PG5402.2 PR4685.2
PWR_GFX_CSP1: PC5426.1 PR5408.1 PU5407.40
PWR_GFX_CSP2: PR5429.1 PU5407.41
PWR_GFX_CSREF: PC5413.1 PC5426.2 PR4685.1 PU5407.42
PWR_GFX_CSSUM: PC5414.2 PC5425.1 PR5409.1 PR5426.2 PU5407.43
PWR_GFX_DIFF: PR5407.1 PR5413.1 PU5407.50
PWR_GFX_DIFF_R: PC5415.1 PR5407.2
PWR_GFX_DROOP: PC5419.1 PR5417.1 PU5407.46
PWR_GFX_FB: PC5415.2 PC5416.1 PR5413.2 PR5415.1 PU5407.49
PWR_GFX_HG1: PU5401.4 PU5407.29
PWR_GFX_ILIM: PR5428.1 PU5407.44
PWR_GFX_ILIM_R: PR5414.2 PR5425.2 PR5426.1
PWR_GFX_IOUT: PC5423.2 PR5402.1 PU5407.47
PWR_GFX_LG1: PU5402.4 PU5403.4 PU5407.31
PWR_GFX_PHCONFIG: PR5412.1 PU5407.38
PWR_GFX_ROSC: PR5411.2 PU5407.11
PWR_GFX_SNB1: PC5405.1 PR5401.2
PWR_GFX_SR: PR5419.1 PU5407.39
PWR_GFX_SW1: PC5411.2 PG5401.1 PL5401.1 PR5401.1 PU5401.1 PU5401.2 PU5401.3 PU5402.5 PU5402.6 PU5402.7 PU5402.8 PU5403.5 PU5403.6 PU5403.7 PU5403.8 PU5407.30
PWR_GFX_SWN1: PG5401.2 PR5408.2 PR5409.2
PWR_GFX_TSENSE: PC5422.2 PR5421.2 PR5423.2 PU5407.1
PWR_GFX_VCC: PC5420.1 PR5418.2 PU5407.10
PWR_GFX_VDD: PC5418.1 PR5420.1 PU5407.51
PWR_GFX_VR_HOT: PR5464.1 PU5407.13
PWR_GFX_VRMP: PC5424.1 PR5424.2 PU5407.12
PWR_GFX_VSS: PC5418.2 PR5422.1 PU5407.52
PWR_LED_YELLOW_C: PWRCN1.9 Q1212.D R1751.2 R1761.1
PWR_LED_YELLOW_C2: R724.2 R1751.1
PWR_VDDP_BOOT: PR4812.1 PU4803.10
PWR_VDDP_BOOT_R: PC4806.2 PR4812.2
PWR_VDDP_CS: PR4802.2 PU4803.2
PWR_VDDP_EN: PC48.1 PC4804.1 PU4803.3 R125.1 R1763.2 R1764.1
PWR_VDDP_FB: PC4805.2 PR4803.2 PR4816.1 PU4803.4
PWR_VDDP_FB_R: PC4805.1 PG4801.1 PR4803.1
PWR_VDDP_LGATE: PU4801.4 PU4803.6
PWR_VDDP_PG: PR4805.2 PU4803.1
PWR_VDDP_PHASE: PC4806.1 PC4807.1 PL4802.1 PU4801.5 PU4801.6 PU4801.7 PU4801.8 PU4802.1 PU4802.2 PU4802.3 PU4803.8
PWR_VDDP_RF: PR4807.1 PU4803.5
PWR_VDDP_SNB: PC4807.2 PR4806.1
PWR_VDDP_UGATE: PU4802.4 PU4803.9
PWR_VDDQ_BOOT: PR5006.1 PU5001.18
PWR_VDDQ_BOOT_L: PC5010.1 PR5006.2
PWR_VDDQ_CS: PC5003.2 PR5003.2 PU5001.13
PWR_VDDQ_EN: C1796.1 PU5001.8 R1808.2 R1810.2
PWR_VDDQ_FB: PC5013.2 PR5009.1 PR5023.2 PU5001.6
PWR_VDDQ_LGATE: PU5001.15 PU5007.4
PWR_VDDQ_PHASE: PC5010.2 PL5001.1 PR5034.1 PU5001.16 PU5006.1 PU5006.2 PU5006.3 PU5007.5 PU5007.6 PU5007.7 PU5007.8
PWR_VDDQ_SENSE: PC5013.1 PG5001.2 PR5023.1 PU5001.5
PWR_VDDQ_SNB: PC5017.1 PR5034.2
PWR_VDDQ_TON: PR5007.2 PU5001.9
PWR_VDDQ_UGATE: PU5001.17 PU5006.4
PWR_VDDQ_VDD: PC5003.1 PC5018.1 PR5002.1 PR5003.1 PU5001.11
PWR_VDDQ_VDDP: PC5009.1 PR5004.1 PU5001.12
PWR_VDDQ_VTTIN: PC5011.1 PR5020.2 PR5021.2 PU5001.19
PWR_VDDQ_VTTREF: PC5014.1 PR5032.2 PU5001.4
PWR_VGA_CORE_BOOT1: PR43.1 U9.19
PWR_VGA_CORE_COMP: PC4.2 PC6.1 PC7.2 PC8.1 PR1.2 PR13.2 U9.7
PWR_VGA_CORE_DPRSLPVR: PR17.2 U9.39
PWR_VGA_CORE_FB: PC8.2 PR8.2 PR20.1 PR21.1 U9.8
PWR_VGA_CORE_FB2: PC4.1 PC5.2 U9.9
PWR_VGA_CORE_IMON: PC59.2 PR98.1 PR99.2 U9.18
PWR_VGA_CORE_ISEN1: PR12.2 U9.11
PWR_VGA_CORE_ISEN2: PR11.2 PR12.1 U9.10
PWR_VGA_CORE_ISUM+: PC15.1 PC16.1 PR34.1 PR41.1 PR42.1 PR45.1 U9.15
PWR_VGA_CORE_ISUM-: PC14.1 PR16.2 U9.14
PWR_VGA_CORE_LGATE1A: PU3.4 PU5202.4 U9.23
PWR_VGA_CORE_LGATE1B: TP203.1 U9.24
PWR_VGA_CORE_NTC: PC9.1 PR60.2 U9.5
PWR_VGA_CORE_ON: PC12.1 PR18.2 PR19.2 U9.38
PWR_VGA_CORE_PGOOD: PR14.1 U9.1
PWR_VGA_CORE_PHASE1: PC19.1 PG4.2 PL1.1 PR114.1 PU1.1 PU1.2 PU1.3 PU2.1 PU2.2 PU2.3 PU3.5 PU3.6 PU3.7 PU3.8 PU5202.5 PU5202.6 PU5202.7 PU5202.8 U9.21
PWR_VGA_CORE_PSI#: PR10.1 U9.2
PWR_VGA_CORE_RTN: PC13.2 PC57.2 PC59.1 PR29.2 PR99.1 U9.13
PWR_VGA_CORE_SNB1: PC65.1 PR114.2
PWR_VGA_CORE_UGATE1: PU1.4 PU2.4 U9.20
PWR_VGA_CORE_VCCP: PC17.1 PC18.1 PR44.1 U9.25
PWR_VGA_CORE_VDD: PC58.1 PR95.2 PR98.2 U9.16
PWR_VGA_CORE_VID0: PR39.2 U9.31
PWR_VGA_CORE_VID1: PR37.2 U9.32
PWR_VGA_CORE_VID2: PR35.2 U9.33
PWR_VGA_CORE_VID3: PR32.2 U9.34
PWR_VGA_CORE_VID4: PR30.2 U9.35
PWR_VGA_CORE_VID5: PR25.2 U9.36
PWR_VGA_CORE_VID6: PR23.2 U9.37
PWR_VGA_CORE_VIN: PC60.1 PR101.2 U9.17
PWR_VGA_CORE_VSEN: PC11.2 PC13.1 PC56.1 PR21.2 PR28.2 U9.12
PWR_VGA_CORE_VSUM-: PC15.2 PC16.2 PC20.2 PR16.1 PR41.2 PR47.1 PR51.2
PWR_VGA_CORE_VW: PC7.1 PR13.1 U9.6
PWR_VTT_EN: C1797.1 PU5001.7 R1809.2 R1810.1
PWRBTN_N: C1760.1 R385.1 R1756.2 U4101.47
PWRCN_DET_N: C6722.2 PWRCN1.5 R1669.1 U109.124
PWRGD_3V: C194.1 R368.1 R369.1 R1668.1 R1857.2
PWRGD_3V_B_1: Q37.5 Q37.6 R380.2
PWRGD_3V_D: Q78.S Q1246.D
PWRGD_3V_G: Q1246.G R1668.2
PWRGD_3V_LL: Q37.3 R369.2
PWRGD_PS_L: C525.2 Q1226.2 R656.1 R657.2
PWRGD_PS_L1: Q1226.5 Q1226.6 R1831.2
PWRGD_PS_L2: Q1226.3 R1842.1
PWRGOOD_GPU: GPU1.N10 R1158.2
PWROK3_1: R309.2 U109.29
PWROK3_1_R: R309.1 R366.2 R1857.1
PWROK3_2: R373.1 U109.75
PWROK3_2_R: R373.2 R381.1 R384.1
PX_EN: GPU1.AB16 TP159.1
QSAN_0: GPU1.H27 MEM3.G3
QSAN_1: GPU1.A27 MEM3.B7
QSAN_2: GPU1.C23 MEM1.B7
QSAN_3: GPU1.C19 MEM1.G3
QSAN_4: GPU1.C15 MEM4.G3
QSAN_5: GPU1.E9 MEM2.B7
QSAN_6: GPU1.C5 MEM2.G3
QSAN_7: GPU1.H4 MEM4.B7
QSAP_0: GPU1.H28 MEM3.F3
QSAP_1: GPU1.C27 MEM3.C7
QSAP_2: GPU1.A23 MEM1.C7
QSAP_3: GPU1.E19 MEM1.F3
QSAP_4: GPU1.E15 MEM4.F3
QSAP_5: GPU1.D10 MEM2.C7
QSAP_6: GPU1.D6 MEM2.F3
QSAP_7: GPU1.G5 MEM4.C7
RASA0#: GPU1.G22 MEM1.J3 MEM3.J3
RASA1#: GPU1.G17 MEM2.J3 MEM4.J3
RDY#: TP4126.1 U4101.23
REMOTE1+: C211.2 R404.1 RT3.1 U109.87
REMOTE1-: C211.1 R400.2 RT3.2
REXT: R2082.1 U118.18
RING2: C157.1 Q24.2 R261.2 U6.31 UHS1.3
ROM_CS#: R1167.2 R1168.2 U49.1
ROM_RST#: CPU1.AW11 R1647.1
ROM_SI_D3: R1171.1 U49.5
ROM_SLK_D4: R1170.1 U49.6
ROM_SO_C4: R1169.2 U49.2
RSMRST*_R: Q37.2 R384.2
RSMRST_N: Q1247.G R374.1 R382.2
RSMRST_N_1: Q1247.D Q1248.G R2066.1
RSMRST_N_FCH: C78.1 CPU1.AE4 Q1248.D R1677.2
RSVD_AN30: CPU1.AN30 TP212.1
RSVD_U30: CPU1.U30 TP210.1
RSVD_U31: CPU1.U31 TP211.1
RT: R79628.1 U120.10
RTL_ISOLATE_N: Q36.6 R377.2 R1817.1 U16.20
RTL_ISOLATE_N_1: C1798.1 Q36.5 R406.1 R1816.2
RTL_ISOLATE_N_2: Q36.2 Q36.3 R378.2
RTN1: CONVT1.1 R51.1
RTN2: CONVT1.2 R53.1
RTN3: CONVT1.5 R56.1
RTN4: CONVT1.6 R59.1
RUN_0P95_EN1: Q18.2 Q18.3 R179.2 R181.1
RUN_0P95_EN2: Q18.6 R171.2 R172.1 R175.1
RUN_0P95_EN3: C1768.2 D20.3 Q18.5 R1776.2
RUN_0P95_EN4: C94.1 C857.1 R174.1 R175.2
RUN_EN1: Q65.2 Q65.3 R732.1 R733.2
RUN_EN2: Q65.6 R722.1 R1178.1 R1778.2
RUN_EN_1P8V: C862.1 R1178.2 R1179.2 U105.3
RUNPWR_R6: C865.2 Q65.5 R718.2
S0A3_GPIO: CPU1.AE8 R1724.1 R1813.1 R2021.2
S0A3_GPIO_G: Q1243.G R2021.1
S_LVDS_BL_EN: R135.1 R139.1 R143.2 R144.1 R1985.1
S_TXE0+: LVDS1.18 U26.31
S_TXE0-: LVDS1.19 U26.32
S_TXE1+: LVDS1.15 U26.29
S_TXE1-: LVDS1.16 U26.30
S_TXE2+: LVDS1.12 U26.27
S_TXE2-: LVDS1.13 U26.28
S_TXE3+: LVDS1.8 U26.23
S_TXE3-: LVDS1.9 U26.24
S_TXEC+: LVDS1.10 U26.25
S_TXEC-: LVDS1.11 U26.26
S_TXO0+: LVDS1.29 U26.41
S_TXO0-: LVDS1.30 U26.42
S_TXO1+: LVDS1.27 U26.39
S_TXO1-: LVDS1.28 U26.40
S_TXO2+: LVDS1.25 U26.37
S_TXO2-: LVDS1.26 U26.38
S_TXO3+: LVDS1.20 U26.33
S_TXO3-: LVDS1.21 U26.34
S_TXOC+: LVDS1.22 U26.35
S_TXOC-: LVDS1.23 U26.36
SA0_DIM1: DIMM1.197 R163.1 R165.2
SA0_DIM2: DIMM2.197 R2055.2 R2056.1
SA1_DIM1: DIMM1.201 R1634.2 R1635.1
SA1_DIM2: DIMM2.201 R2061.2 R2062.1
SATA__RXN0_C: C149.2 HDD1.5
SATA__RXN1_C: C118.2 ODD1.5
SATA__RXP0_C: C151.2 HDD1.6
SATA__RXP1_C: C119.2 ODD1.6
SATA__TXN0_C: C142.2 HDD1.3
SATA__TXN1_C: C115.2 ODD1.3
SATA__TXP0_C: C141.2 HDD1.2
SATA__TXP1_C: C114.2 ODD1.2
SATA_CALRN: CPU1.AW2 R586.2
SATA_CALRP: CPU1.AW1 R1644.2
SATA_LED_N_C_1: Q9646.3 Q9646.6 R80201.2
SATAHDR_RX_DN0: CPU1.AV1 L4103.4
SATAHDR_RX_DN0_EMI: C149.1 L4103.3
SATAHDR_RX_DN1: C118.1 CPU1.AW4
SATAHDR_RX_DP0: CPU1.AV2 L4103.1
SATAHDR_RX_DP0_EMI: C151.1 L4103.2
SATAHDR_RX_DP1: C119.1 CPU1.AW3
SATAHDR_TX_DN0: CPU1.AU4 L4102.1
SATAHDR_TX_DN0_EMI: C142.1 L4102.2
SATAHDR_TX_DN1: C115.1 CPU1.AY1
SATAHDR_TX_DP0: CPU1.AU3 L4102.4
SATAHDR_TX_DP0_EMI: C141.1 L4102.3
SATAHDR_TX_DP1: C114.1 CPU1.AY2
SB3V: C579.1 C595.1 C1615.1 C1617.1 C1701.1 C1715.1 C1716.1 C1925.1 CPU1.AP15 CPU1.AR15 F3.1 PC1.1 PC140.1 PR5005.1 PR5206.1 PR5475.1 Q44.S Q1211.S R10.1 R137.2 R184.2 R297.2 R305.2 R307.1 R312.2 R313.1 R364.1 R371.2 R378.1 R380.1 R382.1 R483.1 R514.1 R526.2 R531.1 R582.2 R679.2 R682.1 R683.1 R717.1 R731.1 R742.1 R755.2 R764.2 R775.1 R777.1 R1664.1 R1665.1 R1666.1 R1669.2 R1675.2 R1676.2 R1679.2 R1708.1 R1731.1 R1733.1 R1734.1 R1752.1 R1758.2 R1784.1 R1785.1 R1813.2 R1825.2 R1826.2 R1831.1 R1840.2 R1843.1 R1863.2 R1864.2 R1874.1 R1875.1 R1876.1 R1877.1 R1933.2 R1935.1 R1987.2 R2010.1 R2012.1 R2029.2 R2030.2 R2064.1 R2065.2 R2066.2 R2091.1 R6702.1 R79635.2 R79661.1 R79670.2 R79671.2 R79673.2 R79675.1 R79689.2 R79690.2 R80201.1 R80202.1 RN9.1(A) RN9.2(A) U54.8 U54.9
SB3V_EN: C1700.1 PR5431.2 R1980.2 R1981.2 U54.3 U54.5
SB5_33_CT1: C1929.1 U54.12
SB5_33_CT2: C1928.1 U54.10
SB5V: C103.1 C1926.1 C1927.1 PC4608.1 PC4803.1 PC5421.1 PR57.1 PR4602.1 PR4631.2 PR4633.2 PR5002.2 PR5004.2 PR5294.1 PR5295.1 PR5418.1 PR5429.2 PU4601.33 PU4803.7 PU5407.25 PU5407.26 PU5407.33 R118.2 R119.1 R125.2 R389.1 R724.1 R735.1 R1759.1 R1767.1 R1833.2 R79726.1 RN10.5(B) RN10.6(B) RN10.7(B) RN10.8(B) U54.13 U54.14 U178.8
SCALAR_SIO_PU: R276.2 R289.2 R305.1 R317.2 R1188.2 R1844.1 R2013.2 R2014.2 R79637.2 R79638.2 R80221.2 R80222.2 RN8.1(A) RN8.2(A)
SD_CD_BD: CPU1.BC2 MEMCD1.11
SD_CLK_BD: MEMCD1.5 R1735.2
SD_CLK_CH_C: CPU1.BB4 R1735.1
SD_CMD_BD: MEMCD1.2 R570.2
SD_CMD_CH_C: CPU1.AY5 R570.1 R1650.2
SD_DATA0_BD: MEMCD1.7 R585.2
SD_DATA0_CH_C: CPU1.BC3 R585.1
SD_DATA1_BD: MEMCD1.8 R584.2
SD_DATA1_CH_C: CPU1.BA3 R584.1
SD_DATA2_BD: MEMCD1.9 R1686.2
SD_DATA2_CH_C: CPU1.BC5 R1686.1
SD_DATA3_BD: MEMCD1.1 R571.2
SD_DATA3_CH_C: CPU1.BA5 R571.1
SD_LED_BD: CPU1.BB6 R111.1
SD_LED_BD_A: LED3.A R111.2
SD_PWRCTL_CH: CPU1.BB5 TP190.1
SD_WP_BD: CPU1.BB2 MEMCD1.10
SENSE_B: R266.2 R267.2 U6.33
SER_IRQ: CPU1.BC14 R680.1 U109.36
SIDE_USB3_RX2+: L5.3 SSUSB1.6 U3.2 U3.9
SIDE_USB3_RX2-: L5.2 SSUSB1.5 U3.1 U3.10
SIDE_USB3_RX3+: L57.3 SSUSB2.6 U5.2 U5.9
SIDE_USB3_RX3-: L57.2 SSUSB2.5 U5.1 U5.10
SIDE_USB3_TX2+: L4.3 SSUSB1.9 U3.5 U3.6
SIDE_USB3_TX2-: L4.2 SSUSB1.8 U3.4 U3.7
SIDE_USB3_TX3+: L56.3 SSUSB2.9 U5.5 U5.6
SIDE_USB3_TX3-: L56.2 SSUSB2.8 U5.4 U5.7
SIO_AGND: C558.1 C1816.1 C1817.1 C1818.1 C1825.2 R399.1 R400.1 R651.1 R709.1 R1830.2 R1835.2 R1841.2 U109.83 U109.84
SIO_AMD_SVID_EN: R308.1 U109.26
SIO_ATXPG: R294.2 R1842.2 U109.16
SIO_AVCC3: C562.1 C565.1 L60.1 U109.96
SIO_CE_N: R1823.1 U7.1 U109.27
SIO_CLK_DB: R79688.1 U109.48
SIO_COPEN#: R370.1 U109.65
SIO_DAT_DB: R79687.1 U109.49
SIO_DEBUG_RX: R341.1 TP25.1 U109.122
SIO_DEBUG_TX: R1829.1 TP26.1 U109.121
SIO_EUP_EN#: PR62.1 Q1227.D R668.1 R1199.1 R1764.2 R1980.1
SIO_GREEN: Q9646.2 Q9646.5 R80202.2 U109.23
SIO_GREEN_PWM: R723.1 U109.15
SIO_GREEN_PWM_C_1: Q1212.G Q9646.1 R723.2 R729.1 R1752.2
SIO_HDD_LED: R1753.1 R1757.2 U109.11
SIO_HDD_LED_1: Q1214.B R1753.2
SIO_HOLD#: R644.1 U7.7
SIO_INT#: R80208.1 R80212.1 U4101.39
SIO_INT_C: R80208.2 U109.100
SIO_LVDS_BL_ADJ: R131.2 R312.1 R503.1 U109.10
SIO_MAIN_VCC3: Q107.D R1837.1 U109.89
SIO_MEM_EVENT_L: R683.2 R1585.1 U109.53
SIO_MEM_EVENT_L_B: Q1207.B R1586.2
SIO_MEM_EVENT_L_C: Q1207.C R1585.2
SIO_PCIRSTIN#: R317.1 U109.128
SIO_PSON_N: Q107.G R1844.2 U109.73
SIO_PWNBTN_N: R375.2 R379.1 R1653.1
SIO_SCK: C1823.1 R306.2 R650.1 U7.6
SIO_SCK_R: R306.1 U109.22
SIO_SI: R655.1 U7.5 U109.21
SIO_SMB2_CLK: R715.2 R80220.2 U109.63
SIO_SMB2_DATA: R716.2 R80219.2 U109.62
SIO_SMCLK0: R60.2 R79633.2 RN9.4(B) U109.60
SIO_SMCLK0_D: Q95.3 R60.1
SIO_SMDAT0: R43.2 R79634.2 RN9.3(B) U109.61
SIO_SMDAT0_D: Q95.6 R43.1
SIO_SO: R645.1 U7.2 U109.45
SIO_VCORE: C548.2 C549.2 U109.33
SIO_VIN1: R80215.1 R80216.2 U109.94
SIO_VIN2: TP28.1 U109.93
SIO_VIN3: C1816.2 R1830.1 R1833.1 U109.92
SIO_VIN4: C1817.2 R689.1 R1835.1 U109.91
SIO_VIN5: C1818.2 R1838.1 R1841.1 U109.90
SIO_VREF: C1825.1 R397.2 R404.2 R658.2 U109.88
SIO_WP#: R1824.1 U7.3
SIO_WRST#: C190.1 R353.2 U109.47
SIO_YELLOW: Q68.G R731.2 R1761.2 U109.7
SKEW1: CPU1.AT14 R1687.2 R1688.1
SKEW2: CPU1.BB7 R154.1 R160.2
SKEW3: CPU1.BC7 R1684.2 R1685.1
SLEEVE: C160.1 Q24.1 Q28.D R272.2 U6.32 UHS1.4
SLEEVE_G: Q28.G Q31.C R319.2 R322.1
SLP_S3_N: R718.1 R1184.2 R1809.1 R1878.2 R2017.1 R2053.1 R2078.2 R79712.1 U109.68
SLP_S3_N_1: D20.2 R1184.1
SLP_S3_N_EC: R79712.2 U4101.30
SLP_S3_N_G: Q78.G R2053.2
SLP_S3_N_R: CPU1.AK7 Q1244.G R2078.1
SLP_S3_N_R3: TP215.1 U109.76
SLP_S3_N_R_1: Q1243.S Q1244.D R2019.1
SLP_S3_N_R_2: Q1243.D Q1245.G R2018.1 R2019.2
SLP_S3_N_R_3: Q1245.D R2017.2 R2065.1
SLP_S5_N: CPU1.AH5 Q1217.5 R372.2 R1808.1 R79713.1
SLP_S5_N_C: R372.1 U109.74
SLP_S5_N_EC: R79713.2 U4101.51
SMB0_CLK: CPU1.BA15 DIMM1.202 DIMM2.202 Q7.4 Q123.6 R162.1 U6701.4
SMB0_CVT_CLK: C3456.1 R79633.1 U120.6
SMB0_CVT_DATA: C43.1 R79634.1 U120.7
SMB0_DATA: CPU1.AY17 DIMM1.200 DIMM2.200 Q4.4 Q123.3 R1673.1 U6701.6
SMB1_CLK: CPU1.AG5 R14.1 R1675.1
SMB1_DATA: CPU1.AG4 R1622.1 R1676.1
SMBUS_ISP: C1877.1 Q4.2 Q4.5 Q7.2 Q7.5 R2079.2 R79676.1 R79677.1 U109.115
SMBUS_ISP_G: Q95.2 Q95.5 R2079.1 R2080.2
SMBUS_MS: R334.1 R80217.2 R80218.1 U109.123
SNB: C35.1 R79619.2
SPEED_100*_CON: RJ1.12 UR6.2
SPEED_100_N: U12.6 U16.26 UR6.1
SPEED_1000*_CON: RJ1.11 UR7.2
SPEED_1000_N: U12.1 U16.25 UR7.1
SPI_33_18_PU1: R1736.1 R1738.1 R2030.1 R2031.1
SPI_33_18_PU2: C1758.2 R1737.1 R2029.1 R2032.1 SPI1.8 SRCON1.8
SPI_CLK: CPU1.BC6 R1741.2
SPI_CLK_1: R1741.1 SPI1.6 SRCON1.6
SPI_CS0_N: CPU1.BB8 R1738.2 SPI1.1 SRCON1.1
SPI_DATAIN: CPU1.BA9 R1740.1
SPI_DATAOUT: CPU1.AY7 R1739.2
SPI_MISO_ROM_1: R1740.2 SPI1.2 SRCON1.2
SPI_MOSI_1: R1739.1 SPI1.5 SRCON1.5
SPI_WP#: R1647.2 R1736.2 SPI1.3 SRCON1.3
SPKR_DET: R1203.1 R1825.1 U109.59
SPKR_DET_C: PC2127.2 R1203.2 SPK1.6
SPKR_IN_L: C199.2 C203.2 U21.6
SPKR_IN_R: C210.2 U21.31
SPKR_L+_C: C226.1 L31.2 R396.1 SPK1.1
SPKR_L+_SNB: C222.1 R396.2
SPKR_L-_C: C236.1 L32.2 R403.1 SPK1.2
SPKR_L-_SNB: C239.1 R403.2
SPKR_OUT_L+: C224.2 C225.1 L31.1 U21.16
SPKR_OUT_L-: C228.2 C235.1 L32.1 U21.18
SPKR_OUT_R+: C223.2 C247.1 L33.1 U21.25
SPKR_OUT_R-: C229.2 C255.1 L34.1 U21.23
SPKR_R+_C: C248.1 L33.2 R415.1 SPK1.4
SPKR_R+_SNB: C243.1 R415.2
SPKR_R-_C: C256.1 L34.2 R419.1 SPK1.3
SPKR_R-_SNB: C263.1 R419.2
SPV10: C785.1 C787.1 C789.1 GPU1.H8 L51.2
SPV18: C788.1 C792.1 C793.1 GPU1.H7 L49.2
SST_HOLDJ_1: R576.2 R1737.2 SPI1.7 SRCON1.7
SST_HOLDJ_1_R: CPU1.BA7 R576.1
SSTCMP: R45.1 U120.11
SSTCMP_1: C5.1 R45.2
STATUS: R61.1 U120.8
SUS_LED_GREEN_C: PWRCN1.7 Q68.D R729.2 R730.2
SUS_LED_GREEN_C2: R730.1 R735.2
SUSCLK_32_APU: CPU1.AG7 R1934.2
SUSCLK_32_APU_C: R1710.1 R1873.1 R1874.2 R1934.1
SUSCLK_NGFF: NGFF1.50 R1710.2
SVC_VDD: PU4601.5 R1629.1 R1902.2
SVC_VDD_GFX: PU5407.5 R1994.2 R1999.1
SVD_VDD: PU4601.3 R1631.1 R1903.2
SVD_VDD_GFX: PU5407.3 R1995.2 R2001.1
SVT_VDD: PU4601.4 R1901.2
SVT_VDD_GFX: PU5407.4 R1993.2
SW_ON_N_SIO: R364.2 R375.1 U109.69
SWR_LX: L2.2 U26.17
SWR_V12: C295.1 C296.1 C297.1 C299.2 L2.1 U26.11 U26.15 U26.43
SYNC: TP24.1 U21.11
SYS_3VSB: R371.1 U109.67
SYS_FAN_TACH1_1: FANC3.3 R76.2 R80.2
SYS_FAN_TACH1_2: R73.2 R74.2 R76.1
SYS_PRES: BAT2.7B R79647.2
SYS_PWRGD: CPU1.BC9 Q79.D R124.2 R1657.1 R2028.2
SYS_PWRGD_G: Q78.D Q79.G R717.2
SYS_PWRGD_HV: Q14.G Q1209.D R119.2
SYS_PWRGD_HV_1: Q1208.C Q1209.G R118.1
SYS_PWRGD_HV_2: C67.1 Q1208.B R124.1
SYSTEM_FAN_PWM1_1: D1.A FANC3.4 R68.2 R71.2
T_DP_BLON: CPU1.G5 TP174.1
T_DP_DIGON: CPU1.G6 TP6.1
TCK: TP4130.1 U4101.27
TDI: TP4128.1 U4101.25
TDO: TP4127.1 U4101.24
TEMPIN0: CPU1.E15 TP192.1
TEMPIN1: CPU1.E14 TP193.1
TEMPIN2: CPU1.E12 TP194.1
TEMPINR: CPU1.F14 TP195.1
TEST18_M: CPU1.A14 R1608.1 R1748.2
TEST19_M: CPU1.B14 R1609.1 R1747.2
TESTEN: GPU1.K7 R302.1 R1897.1
TMS: TP4129.1 U4101.26
TP_DET: R1785.2 TOUCH1.1 U109.118
TP_GPU_CLKREQ#: GPU1.N7 TP158.1
TP_NGFF_COEX1: NGFF1.48 TP39.1
TP_NGFF_COEX2: NGFF1.46 TP38.1
TP_NGFF_COEX3: NGFF1.44 TP196.1
TP_NGFF_LED1: NGFF1.6 TP63.1
TP_NGFF_LED2: NGFF1.16 TP64.1
TP_NGFF_MLDIR: NGFF1.17 TP62.1
TPA3131_BSNL: C228.1 U21.19
TPA3131_BSNR: C229.1 U21.22
TPA3131_BSPL: C224.1 U21.15
TPA3131_BSPR: C223.1 U21.26
TPA3131_FAULT#: R383.2 U21.30
TPA3131_GAIN: R358.1 R361.2 U21.3
TPA3131_GVDD: C192.1 R357.2 R361.1 U21.2
TPA3131_LINN: C200.2 U21.5
TPA3131_LINN_1: C200.1 R346.2
TPA3131_MUTE: R360.1 R638.2 U21.7
TPA3131_PLIMIT: C193.1 R347.2 R357.1 U21.1
TPA3131_RINN: C198.2 U21.32
TPA3131_RINN_1: C198.1 R344.2
TPA3131_SD: Q63.3 Q64.G R638.1 R639.2
TPA3131_SD1#: C521.1 Q64.D R383.1 R643.2 U21.29
TSVDD: C758.1 C759.1 GPU1.AD17 L47.2
USB3_TX2_EMI_DN: C91.2 L4.1
USB3_TX2_EMI_DP: C1757.2 L4.4
USB3_TX3_EMI_DN: C113.2 L56.1
USB3_TX3_EMI_DP: C111.2 L56.4
USB30_RXN2: CPU1.Y7 L5.1
USB30_RXN3: CPU1.AB6 L57.1
USB30_RXP2: CPU1.Y6 L5.4
USB30_RXP3: CPU1.AB5 L57.4
USB30_TXN2: C91.1 CPU1.AC2
USB30_TXN3: C113.1 CPU1.AC3
USB30_TXP2: C1757.1 CPU1.AC1
USB30_TXP3: C111.1 CPU1.AC4
USB_COMP_M: CPU1.AP5 R1648.1
USB_EN: C249.1 C1764.2 Q43.4 R1783.2
USB_EN1: Q1217.2 Q1217.3 R1780.2 R1781.1
USB_EN2: Q1217.6 R1777.2 R1779.1 R1783.1
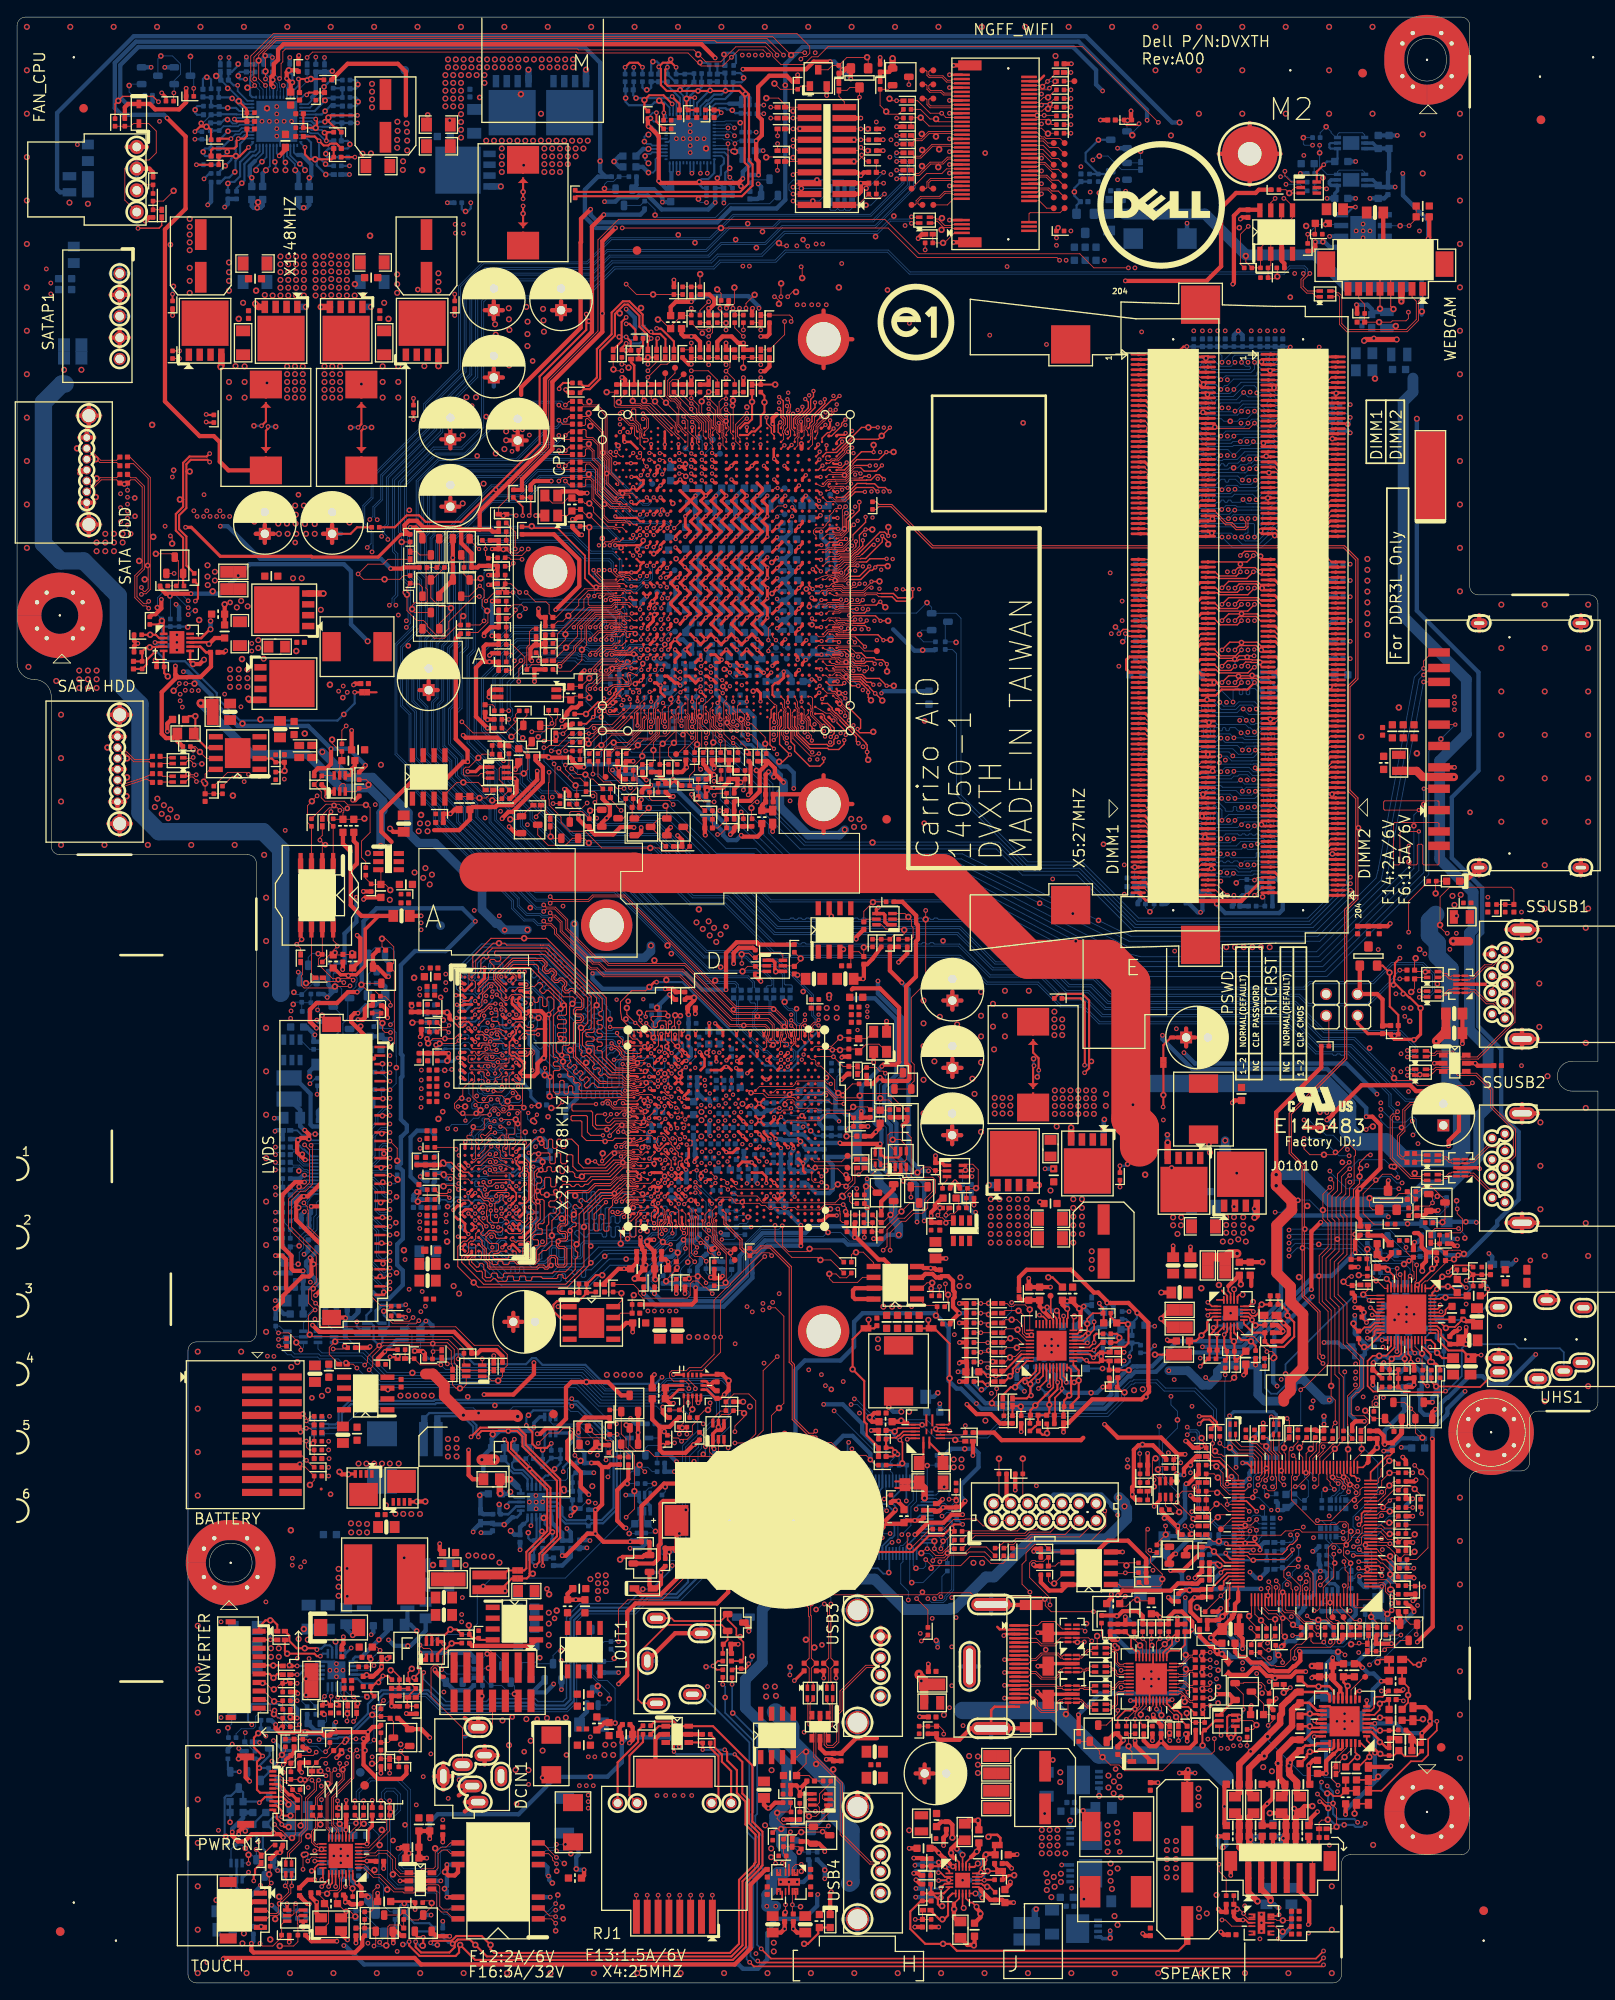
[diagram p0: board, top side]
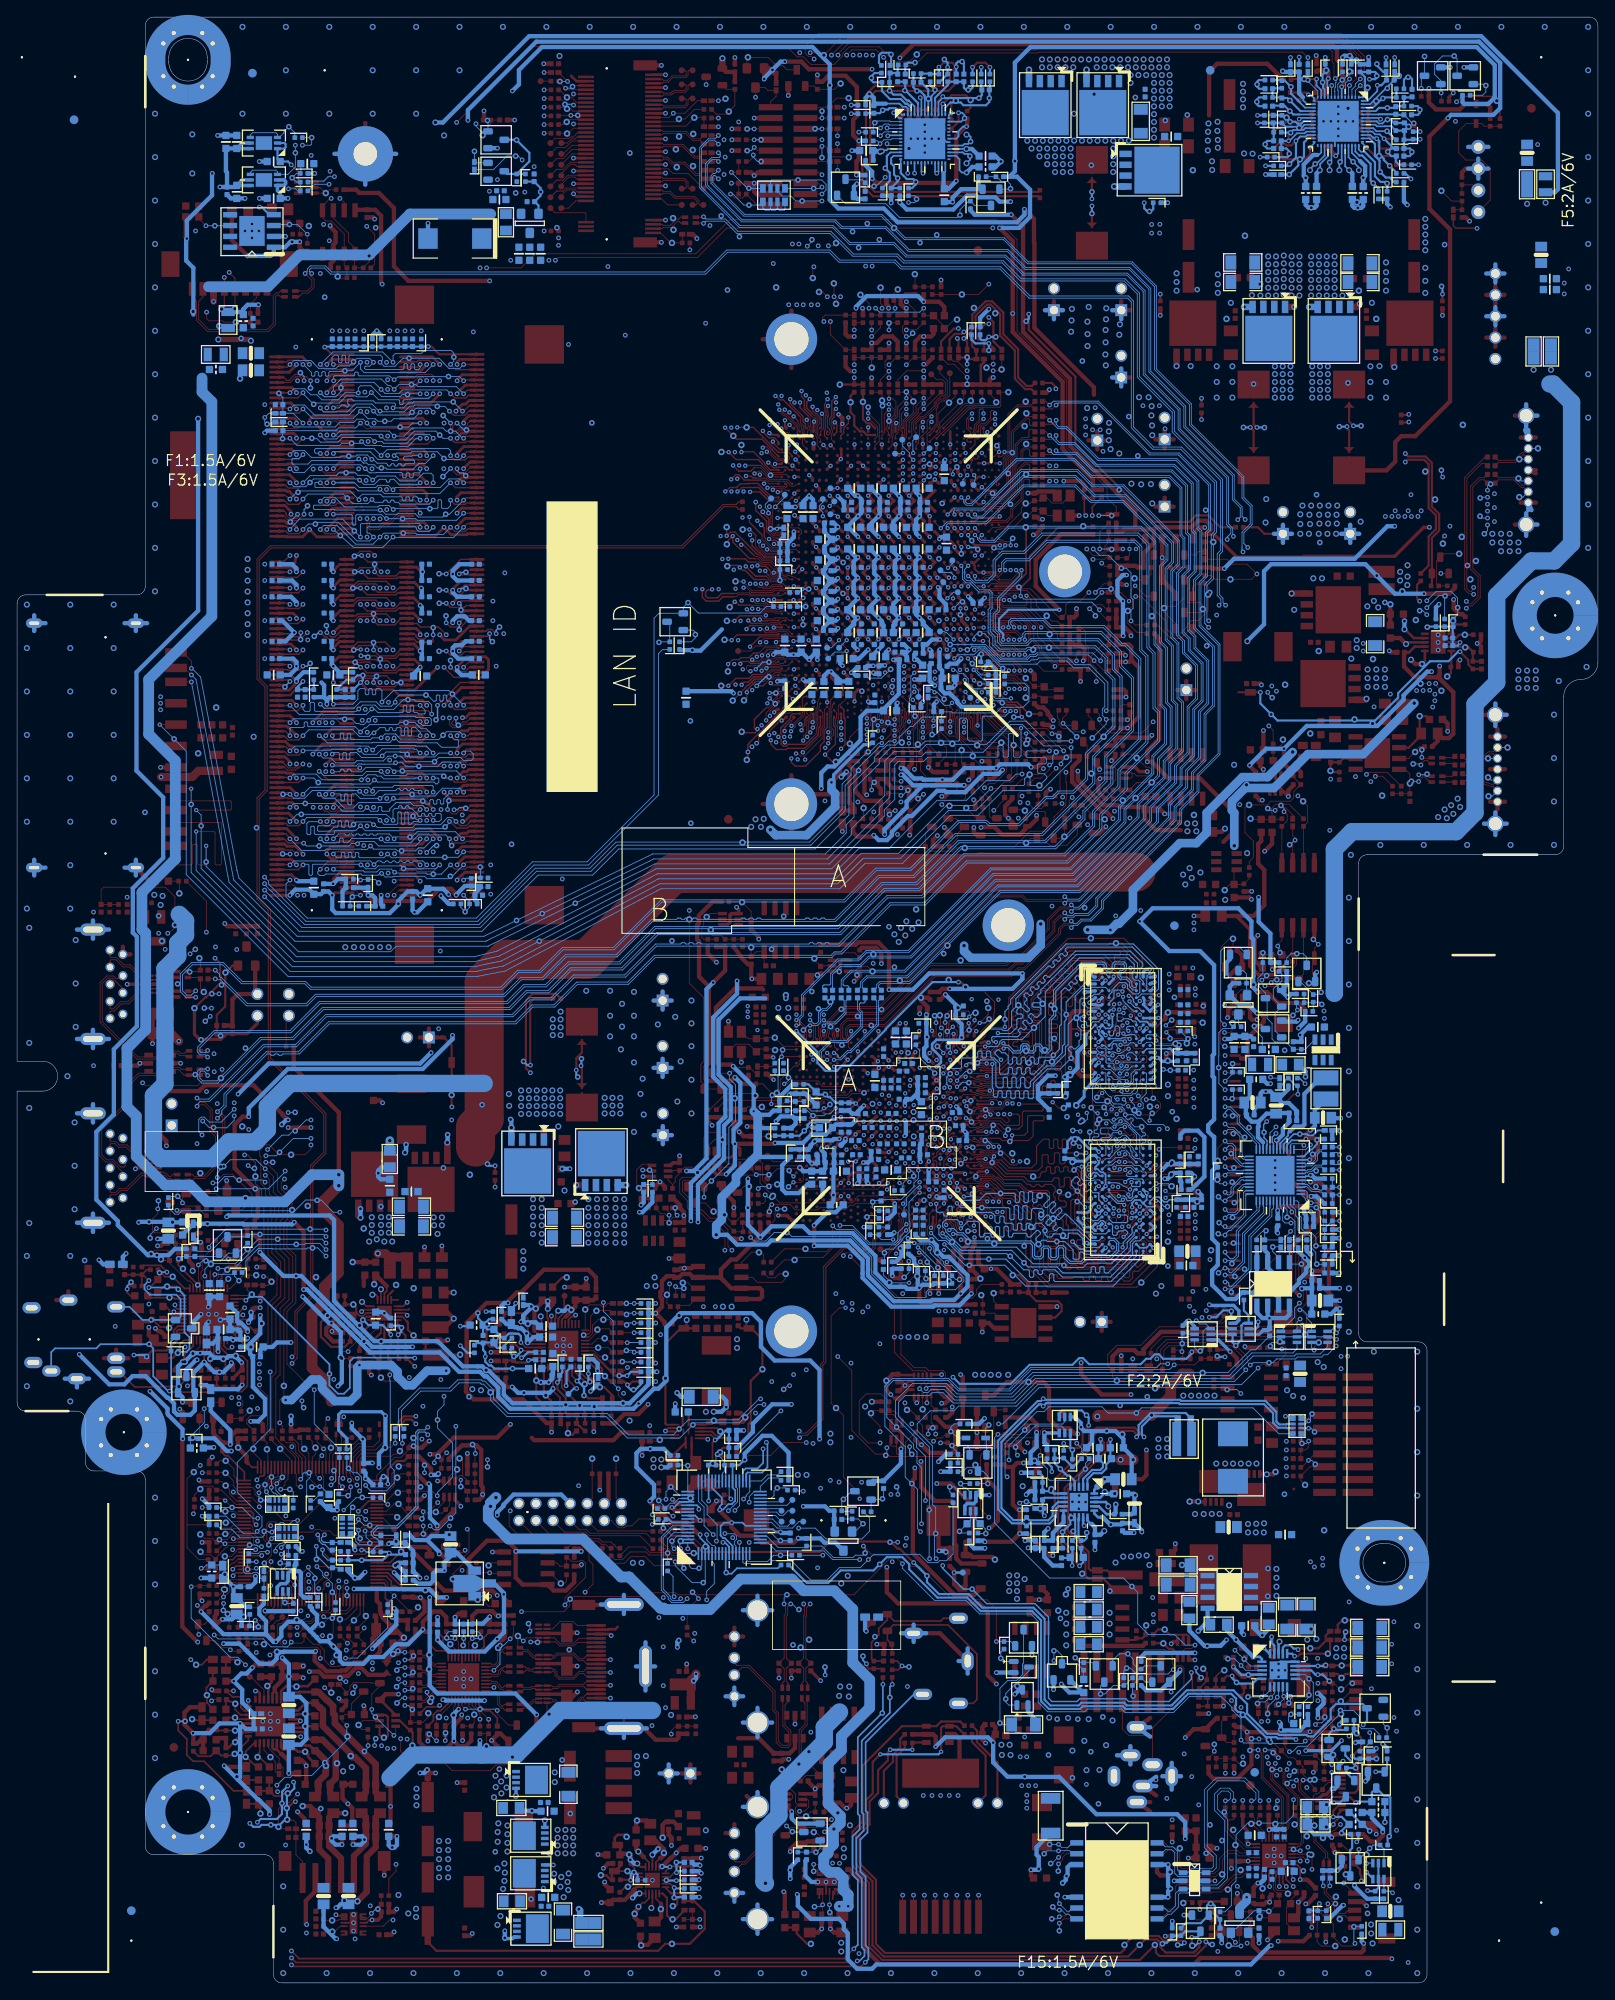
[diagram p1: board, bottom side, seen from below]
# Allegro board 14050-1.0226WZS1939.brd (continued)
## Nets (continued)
USB_PCH_DN3_NN: C1774.1 TOUCH1.4 TR9.3
USB_PCH_DN4_NN: TR1.3 WEBCM1.2
USB_PCH_DN5_NN: NGFF1.5 TR12.3
USB_PCH_DP3_PP: C1773.1 TOUCH1.3 TR9.2
USB_PCH_DP4_PP: TR1.2 WEBCM1.1
USB_PCH_DP5_PP: NGFF1.3 TR12.2
USBCLK_TP: CPU1.AP8 R2067.1
USBOC01*: C589.1 CPU1.AH9 R762.1 R1725.2
USBOC02*: C1756.1 CPU1.AG1 R1727.1 R1728.2
USBP0N_EXT: D24.6 TR10.3 USB3.2
USBP0P_EXT: D24.1 TR10.2 USB3.3
USBP1N_EXT: D24.3 TR14.3 USB4.2
USBP1P_EXT: D24.4 TR14.2 USB4.3
USBP6N_EXT: D4.1 SSUSB1.2 TR3.2
USBP6P_EXT: D4.6 SSUSB1.3 TR3.3
USBP7N_EXT: D4.3 SSUSB2.2 TR4.2
USBP7P_EXT: D4.4 SSUSB2.3 TR4.3
USBSS_CALRN: CPU1.AD2 R1649.1
USBSS_CALRP: CPU1.AD1 R559.1
USBVCC01: C1747.1 C1748.2 C1752.2 C1754.2 C1755.1 D24.5 F12.2 L55.2 R1725.1 TC7.1 USB3.1 USB4.1
USBVCC01_E: C872.1 L55.1
USBVCC23: C104.1 C105.2 C106.1 C1753.2 D4.5 F14.2 R1728.1 SSUSB1.1 SSUSB2.1 TC8.1
USBVCCTP: C592.1 F15.2 TOUCH1.5
V_0P675_S3: C1724.1 C1732.1 C1971.1 C1977.1 DIMM1.203 DIMM1.204 DIMM2.203 DIMM2.204 PR5018.2 PR5019.2
V_1P5_HDMI: C3366.1 C3376.2 C3377.1 C3378.1 C3381.2 C3382.1 C3383.1 R2081.1 R79649.1 U118.12 U118.19 U118.20 U118.31 U118.40 U119.2
V_1P05_LAN: C202.1 C204.1 C213.1 C570.1 C574.1 C580.1 C583.1 C584.1 C1801.1 U16.3 U16.8 U16.22 U16.24 U16.30
V_1P5_PWR: PC5244.1 PC5246.1 PC5248.1 PR5291.2 PR5293.2 PR5296.2 PU5206.3 PU5206.4
V_1P8_VDDIO: PC5247.1 PR5290.2 PU5206.5 PU5206.9
V_3_CARD_BD: C72.1 C73.2 C74.2 C75.1 F6.1 MEMCD1.4 R79655.1
V_3P0_BAT_VREG: C99.1 C100.1 C1737.2 D23.3 PU4.3 R322.2
V_3P3_A: C550.2 C1699.1 C1820.2 C1824.1 C1826.2 C1830.1 C6725.2 L60.2 PC4909.1 PG4902.2 PL4903.1 PR190.2 PR4425.1 PR4426.1 PR4427.1 PR4450.2 PR4805.1 PR5273.1 PR5278.1 PR5281.1 PR5286.2 PR5289.1 PR5431.1 PT4902.1 Q9649.S R276.1 R319.1 R353.1 R639.1 R643.1 R644.2 R645.2 R650.2 R655.2 R668.2 R675.2 R702.1 R1186.2 R1672.2 R1760.1 R1823.2 R1824.2 R2018.2 R79687.2 R79688.2 R79707.1 R80212.2 R80217.1 R80228.2 U7.8 U52.6 U52.7 U54.6 U54.7 U109.1 U109.32 U109.64
V_3P3_LAN: C84.1 C209.1 C572.1 C587.1 C1802.1 C1803.1 C1804.1 C1806.1 C1807.1 C3453.1 C3454.1 Q44.D R1816.1 R1819.1 R79618.1 U10.5 U11.5 U12.5 U16.11 U16.23 U16.32
V_3P3_PCIVAUX: C1742.1 C1743.1 C1744.1 C1745.1 NGFF1.2 NGFF1.4 NGFF1.72 NGFF1.74 Q1211.D Q1229.G R1.1 R1707.1 R1708.2 R1932.1 TC1.1
V_5_CODEC: C146.1 C147.2 C450.1 L19.1 U6.39
V_5_LCD1: L1.1 U1.4
V_5_LCD2: F2.1 L1.2 R8.2
V_5HDD: C109.1 C110.1 C112.1 R183.2 R185.2 SATAP1.1 SATAP1.3
V_5P0_A: C1698.1 C1829.1 D21.K L19.2 PC4910.1 PG4903.1 PL4904.2 PT4903.1 Q43.5 Q43.6 Q43.7 Q43.8 R79708.1 U52.1 U52.2 U52.4 U54.1 U54.2 U54.4
V_5P0_HDMI_CONN: C721.2 HDMI1.18 HDMI2.2 L46.1
V_5P0_HDMI_CONN_L: F13.2 L46.2
V_19_INV: C3459.1 C3460.1 F16.2 L61.1 R5.1 R79631.2
V_VCORE_EN: PU4601.9 Q51.D R508.2
VBYP_2: PU5201.3 R79708.2
VCORE_PWROK: PR5466.2 PU4601.2 R1623.2 R1904.2
VGA_1P8_EN1: Q97.2 Q97.3 R1164.2 R1914.1
VGA_1P8_EN2: Q97.6 R1915.1 R1918.2 R1919.1
VGA_1P8_EN3: R1916.2 U42.3
VGA_1P8_EN4: C859.1 R1915.2 R1916.1
VGA_CORE: C805.1 C806.1 C807.1 C808.1 C809.1 C810.1 C811.1 C812.1 C813.1 C814.1 C815.1 C816.1 C817.1 C818.1 C819.1 C820.1 C821.1 C822.1 C823.1 C824.1 GPU1.AA12 GPU1.AA15 GPU1.M11 GPU1.M13 GPU1.M15 GPU1.M16 GPU1.M17 GPU1.M18 GPU1.M20 GPU1.M21 GPU1.N12 GPU1.N15 GPU1.N17 GPU1.N20 GPU1.R13 GPU1.R16 GPU1.R18 GPU1.T12 GPU1.T15 GPU1.T17 GPU1.T20 GPU1.U11 GPU1.U13 GPU1.U16 GPU1.U18 GPU1.V15 GPU1.V17 GPU1.V20 GPU1.V21 GPU1.Y13 GPU1.Y16 GPU1.Y18 GPU1.Y21 PC73.1 PG3.2 PL1.2 PR28.1 PT1.1 PT3.1 PT4.1
VOUT_INV: C36.1 C37.1 C38.1 C39.1 C40.1 CONVT1.3 CONVT1.4 D32.K U120.18
VR_HOT: PR24.1 PU4601.13
VR_TT#: TP204.1 U9.4
VRAM1_VREFCA: C529.1 MEM3.M8 R885.1 R886.2
VRAM1_VREFDQ: C559.1 MEM3.H1 R924.2 R928.1
VRAM2_VREFCA: C163.1 MEM1.M8 R230.1 R1905.2
VRAM2_VREFDQ: C835.1 C1854.1 MEM1.H1 R202.2 R203.1
VRAM3_VREFCA: C1869.1 MEM4.M8 R1923.2 R1924.1
VRAM3_VREFDQ: C1867.1 C1868.1 MEM4.H1 R1921.2 R1922.1
VRAM4_VREFCA: C1861.1 MEM2.M8 R1910.1 R1911.2
VRAM4_VREFDQ: C1860.1 MEM2.H1 R945.1 R946.2
VRAM_0D95_EN_D: Q6702.6 R79663.1 R79666.2 R79667.1
VRAM_0D95_EN_SW: C6704.2 C6709.2 R79663.2 U6702.4
VRAM_ZQ1: MEM3.L8 R870.2
VRAM_ZQ2: MEM1.L8 R899.2
VRAM_ZQ3: MEM4.L8 R299.2
VRAM_ZQ4: MEM2.L8 R320.2
VREF: C4.2 U120.2
VREF_1: C140.1 U6.41
VREG_PCIAUX_PCH: Q3.D Q128.C R10.2 R13.1
VREG_PCIAUX_PCH_1: C1616.1 PC1.2 Q1211.G R13.2
VRP: C155.1 U6.38
VSUM_RC: PC14.2 PR34.2
VSUM_RR: PR42.2 PR51.1
WAKE_N: R137.1 R1654.1 R1718.1 R1719.2 U16.21
WAKE_N_APU: CPU1.AG2 R1654.2
WEA0#: GPU1.G25 MEM1.L3 MEM3.L3
WEA1#: GPU1.H10 MEM2.L3 MEM4.L3
WEBCAM_DET: PC126.2 R12.2 U109.114 WEBCM1.7
X32K_X1: C57.1 CPU1.AT1 R1671.1 X2.1
X32K_X2: C58.1 CPU1.AT2 R1671.2 X2.4
X48M_X1: C52.1 CPU1.T2 R113.1 X1.3
X48M_X2: C50.1 CPU1.T1 R113.2 X1.1
XRF_TDC2: C3452.1 XF1.9 XF1.10 XF2.9 XF2.10
XTALIN: C756.1 GPU1.AM28 R1879.1 X5.1
XTALOUT: C757.1 GPU1.AK28 R1879.2 X5.3

Pads without a net: BAT2 1A 2A 3A 4A 5A 6A 7A 8A 9A 10A; CPU1 A6 A7 A21 A22 A23 AA1 AA2 AA3 AA4 AB25 AB26 AB28 AB29 AD26 AD27 AE25 AE26 AE28 AE29 AG24 AG26 AG27 AG29 AH25 AH26 AH28 AH29 AK26 AK27 AK29 AL25 AL26 AL28 AL29 AN1 AN2 AN26 AN27 AN29 AP9 AP24 AP25 AP26 AP28 AP29 AR11 AR20 AR22 AR23 AR26 AR27 AR29 AT11 AT20 AT23 AT25 AU1 AU2 AU7 AU12 AU22 AU25 AU26 AU28 AU29 AV5 AV8 AV11 AV20 AV22 AV23 AV26 AV27 AV29 AW8 AW9 AW20 AW23 AW25 AW26 AW27 AY9 AY19 AY21 B1 B6 B7 B20 B21 B22 B23 BA21 BA23 BB20 BB21 BB22 BB23 BC21 BC22 BC23 C1 C7 C9 C21 C23 D1 D2 D7 D9 D21 D23 E9 E17 E19 E20 E22 E23 E25 E26 E27 F17 F20 F23 F26 F27 F29 G1 G2 G3 G4 G9 G19 G22 G25 G27 G28 G29 H1 H2 H9 H17 H19 H20 H22 H23 H25 J3 J4 J6 J7 J17 J20 J23 J26 J27 J29 K5 K6 K8 K9 K18 K21 K25 K26 K28 K29 L9 L10 L26 L27 L29 M32 M33 N1 N2 N25 N26 N28 N29 N30 N31 N32 N33 P27 P29 P32 R1 R2 R30 R31 R32 R33 T8 T9 T25 T26 T28 T29 U9 U10 U26 U27 U29 W1 W2 W5 W6 W8 W9 W25 W26 W28 W29 Y1 Y2 Y26 Y27 Y29; DIMM1 77 122 125; DIMM2 77 122 125; GPU1 AA1 AA3 AA5 AA6 AA29 AA31 AB2 AB4 AB7 AB8 AB9 AB11 AB12 AB13 AB23 AB25 AB26 AB27 AB30 AC1 AC3 AC5 AC6 AC7 AC8 AC10 AC11 AC13 AC14 AC20 AC23 AC25 AD2 AD4 AD7 AD9 AD10 AD11 AD13 AD16 AD20 AD22 AD23 AD24 AE1 AE3 AE5 AE6 AE8 AE9 AE10 AE11 AE13 AE16 AE19 AE22 AE23 AE24 AE25 AE26 AF2 AF4 AF6 AF7 AF8 AF9 AF10 AF11 AF13 AF16 AF17 AF19 AF20 AF22 AF23 AF24 AF25 AG1 AG3 AG5 AG6 AG7 AG8 AG9 AG10 AG11 AG13 AG14 AG15 AG16 AG17 AG18 AG19 AG20 AG21 AG22 AG23 AG24 AG25 AG26 AH1 AH3 AH5 AH6 AH8 AH12 AH14 AH16 AH18 AH20 AH22 AH24 AH26 AJ7 AJ9 AJ13 AJ15 AJ17 AJ19 AJ21 AJ23 AJ25 AK1 AK3 AK5 AK6 AK8 AK14 AK16 AK18 AK20 AK22 AK24 AK26 AL7 AL9 AL13 AL15 AL17 AL19 AL21 AL23 AL25 AM3 AM5 AM6 AM8 AM12 AM14 AM16 AM18 AM20 AM22 AM24 AM26 J8 J22 J25 K13 K30 L9 L16 L17 L29 L31 M27 M28 M30 N3 N5 N6 N9 N26 N29 N31 P7 P23 P24 P26 P27 P28 P30 R29 R31 T7 T10 T23 T24 T26 T27 T28 T30 U1 U3 U5 U6 U10 U12 U23 U24 U26 U29 U31 V2 V4 V6 V12 V27 V28 V30 W1 W3 W5 W6 W7 W8 W9 W10 W23 W24 W29 W31 Y2 Y4 Y6 Y7 Y8 Y9 Y11 Y12 Y23 Y24 Y26 Y27 Y28 Y30; HDMI1 13 14; HDMI2 6 7; LPC1 10; MEM1 J1 J9 L1 L9 M7; MEM2 J1 J9 L1 L9 M7; MEM3 J1 J9 L1 L9 M7; MEM4 J1 J9 L1 L9 M7; NGFF1 64; PU5 5 7 8; PU4601 27; PU5407 8 14 16 18 21 22 27 34 35 36 37; Q6703 7; Q6704 7; RN13 4 5; RN4301 1 8; TOUCH1 6 7; U6 15 16 17 34 37 45 46; U9 26 28 29 30; U12 3; U109 108 120; U117 5 6; U4101 7 8 16 18 31 40 42 43 46 54 55 57; U6701 2 3

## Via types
v1: diameter 0.762, hole 0.381, TOP to BOTTOM, 628 vias
v2: diameter 0.66, hole 0.33, TOP to BOTTOM, 952 vias
v3: diameter 0.559, hole 0.305, TOP to BOTTOM, 2669 vias
v4: diameter 0.508, hole 0.254, TOP to BOTTOM, 1170 vias
v5: diameter 0.711, hole 0.406, TOP to BOTTOM, 970 vias

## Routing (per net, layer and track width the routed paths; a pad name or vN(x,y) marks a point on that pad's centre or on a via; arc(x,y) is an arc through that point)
0.775V_TRACK_GATE: length 7.5
  BOTTOM w0.102: R4707.2 152.5,216.47 v2(153.2,217.17) 153.78,216.59 153.78,216.46 154.32,215.91 Q6704.3 154.53,216.28 154.72,216.48 157.44,216.48 157.71,216.22 Q6704.4
3V_5V_POK: length 245.5
  TOP w0.102: R1762.1 105.95,8.45 PC96.1 ; v3(27.08,141.4) 27.04,141.4 26.8,141.63 24.63,141.63 R31.2 ; PC96.1 PR190.1 ; PC96.1 v3(105.11,7.43)
  L3 w0.127: v3(37.15,82.21) 37.15,77.04 43.62,70.56 61.14,70.56 63.49,72.91 86.21,72.91 87.95,71.17 v3(94.13,71.17)
  L4 w0.127: v3(20.02,160.08) 20.02,159.39 20.7,158.72 20.7,154.06 23.28,151.48 23.28,150.05 26.1,147.23 26.1,142.38 v3(27.08,141.4) 27.29,141.6 31.18,141.6 37.37,135.41 37.37,134.55 37.37,134.24 37.37,134.24 37.37,122.61 38.62,121.36 38.62,118.39 37.64,117.41 37.64,116.71 39.03,115.32 39.03,106.57 39.75,105.86 39.75,85.89 37.56,83.7 37.56,82.62 v3(37.15,82.21) ; v3(105.11,7.43) 105.11,8.38 102.01,11.48 102.01,29.11 96.93,34.19 96.93,39.47 93.57,42.83 93.57,44.38 92.34,45.62 92.34,54.95 91.49,55.8 91.49,60.12 94.24,62.87 94.72,62.87 95.61,63.75 v3(95.61,66.93) 95.61,68.11 94.13,69.6 v3(94.13,71.17)
  BOTTOM w0.102: R77.2 100.43,61.98 100.43,62.14 95.64,66.93 v3(95.61,66.93) ; v3(20.02,160.08) 20.49,160.55 v2(20.86,160.55)
3V_VA: length 10.2
  TOP w0.203: U6.23 159.06,76.43 158.86,76.23 158.86,75.82 158.48,75.44 v3(158.02,75.44) ; v3(159.75,75.21) U6.25
  BOTTOM w0.254: C485.1 160.99,77.67 161.09,77.57 v2(161.2,77.57)
  BOTTOM w0.508: v3(158.02,75.44) 158.16,75.3 L21.2 ; C483.1 159.93,75.39 v3(159.75,75.21) 159.66,75.3 L21.2 ; C485.1 C493.1 159.15,76.45 C495.2 158.86,76.16 L21.2
19V_AMP_AVCC: length 4.2
  TOP w0.305: U21.12 155.6,34.64 v1(155.71,34.74) 155.66,34.74 155.23,35.18 R376.2
  TOP w0.508: C208.1 R376.2
19V_AMP_PVCC: length 31.3
  TOP w0.305: U21.28 155.1,27.49 154.91,27.29 154.6,27.29 ; 154.6,27.29 U21.27 ; 154.6,27.29 154.11,26.8 ; U21.14 154.6,33.89 154.85,34.14 155.1,33.89 U21.13
  TOP w0.508: L10.2 C545.1 153.96,35.43 154.85,34.54 154.85,34.14 ; L10.2 v3(153.96,38.05) ; L10.2 154.21,37.34 R376.1 ; 154.11,26.8 154.09,26.78 154.03,26.78 153.2,25.95 v3(153.2,24.51) 152.81,24.51 152.81,24.51 C552.1
  BOTTOM w0.508: v3(153.2,24.51) C551.1 151.81,27.86 151.15,28.52 151.15,32.73 151.9,33.48 C543.1 v2(153.2,35.86) 153.2,37.29 v3(153.96,38.05)
+1.5V_GPU_PG: length 4.6
  TOP w0.102: v1(72.17,80.47) 71.98,80.28 PR225.2 PC151.1 70.65,78.36 70.14,77.85 PU7.7
+3VL: length 2.5
  TOP w0.305: PG4904.2 115.07,16.18 115.07,16.97 114.71,17.32 113.88,17.32 113.67,17.12 v1(113.67,17.09)
+5VL: length 2.7
  TOP w0.305: PG4901.2 115.4,12.18 PR4918.1 115.53,12.06 116.03,12.57 116.66,12.57 v1(116.68,12.6)
AGND: length 52.3
  TOP w0.203: U6.22 158.99,76.83 158.36,76.2 v3(158.02,76.2) ; U6.28 161.59,73.98 v3(161.48,73.86) ; C140.2 167.57,79.15 167.16,78.73 167.16,78.31 166.86,78.02 166.44,78.02 166.43,78.03 U6.42
  TOP w0.508: v3(165.97,67.13) 165.62,66.78 165.62,66.03 Q28.S ; C268.2 83.54,38.61 C267.2 v3(84.39,39.62) ; UHS1.5 174.82,73.09 ; UHS1.5 173.4,74.11 ; UHS1.5 171.98,73.09 ; v3(168.82,76.58) 168.8,76.58 168.48,76.26 168.26,76.26 168.1,76.1 168.05,76.1 167.67,75.72 C147.1 ; LOUT1.5 77.01,40.91 LOUT1.P ; R281.2 163.25,69.72 v3(163.48,69.95) C157.2 163.42,70.74 C159.2 ; C160.2 v3(158.66,69.95) ; C1491.2 157.19,79 v3(156.55,79)
  BOTTOM w0.508: C485.2 159.24,78.36 159.24,77.43 C495.1 158.82,77.23 158.02,76.43 v3(158.02,76.2) ; 78.61,40.91 LOUT1.P ; LOUT1.P 81.55,40.91 ; LOUT1.P 80.08,39.89 ; LOUT1.P 80.08,41.93 ; v3(163.48,69.95) 162.82,69.95 R300.2 159.14,69.47 v3(158.66,69.95) ; 73.76,36.19 LOUT1.5 ; LOUT1.5 73.76,39.13 ; LOUT1.5 74.83,37.66 ; C450.2 v3(168.56,87.05) ; R1193.2 172.63,84.96 v3(172.25,85.34) ; R301.2 162.1,74.8 C483.2 ; C483.2 161.51,73.9 v3(161.48,73.86) ; C483.2 161.51,76.37 C493.2
  vias: v2(84.62,40.51) v3(80.81,34.67) v3(86.47,3.43) v3(169.58,79.43) v3(173.52,76.81)
AVCC33_2136: length 21.3
  TOP w0.508: v3(33.63,93.69) 32.54,93.69 31.02,92.18 31.02,86.16 32.11,85.06 32.11,83.57 32.37,83.31 v3(33.47,83.31)
  BOTTOM w0.203: U26.5 33.84,93.9 v3(33.63,93.69)
  BOTTOM w0.508: C298.1 33.48,81.27 C292.1 L17.2 ; C298.1 C293.1 v3(33.47,83.31) ; C298.1 34.6,81.28 v2(34.65,81.23)
AVCC_EC: length 18.7
  TOP w0.508: v3(110.95,56.39) 110.9,56.34 110.9,56.26 110.33,55.69 R79723.1 109.82,55.63 v3(108.36,55.63) 108.01,55.27 107.96,55.27 107.87,55.18 C4102.1 107.35,55.31 L4101.2
  BOTTOM w0.203: U4101.52 107.45,56.28 108.11,55.63 v3(108.36,55.63)
  BOTTOM w0.508: R79721.1 109.32,62.48 v2(110.9,62.48) 112.02,62.48 112.52,61.98 112.52,60.34 110.71,58.53 110.7,58.53 110.46,58.29 110.46,56.88 v3(110.95,56.39)
DVCC33_2136: length 72.3
  TOP w0.508: v3(37.63,98.59) 36.15,97.12 36.15,94.16 34.02,92.02 v3(33.56,92.02) 33.36,92.02 32.67,91.33 32.67,89.28 33.64,88.32 33.64,88.31 35.97,85.98 35.97,81.48 v3(34.93,80.44) ; v3(34.58,76.96) 35.36,76.17 51.14,76.17 53.18,74.13 R69.1 53.88,73.66 54.26,74.04 56.06,74.04 56.8,73.3 R54.1
  L3 w0.508: v3(34.58,76.96) 34.45,76.96 34.2,77.22 34.2,79.72 34.91,80.44 v3(34.93,80.44)
  BOTTOM w0.203: U26.18 37.58,98.54 v3(37.63,98.59) ; U26.22 39.18,98.34
  BOTTOM w0.508: 39.71,100.76 38.77,101.7 C291.1 37.57,101.78 C284.1 C290.2 36.14,100.69 36.86,99.96 36.86,99.26 37.52,98.6 37.62,98.6 v3(37.63,98.59) ; 39.71,100.76 40.52,100.76 41.12,101.36 C289.1 41.21,101.64 41.21,102.82 C283.1 40.75,103.63 L16.2 ; 39.71,100.76 39.71,100.2 39.78,100.13 39.78,98.95 39.18,98.34 ; R1074.1 32.04,91.19 32.37,91.52 32.43,91.52 32.94,92.02 v3(33.56,92.02)
GND: length 2441.3
  TOP w0.127: v4(59.52,95.79) 59.16,95.42 59.16,95.02 58.81,94.68 MEM2.M1
  TOP w0.203: v3(132.74,36.43) 132.74,37.01 132.94,37.21 U118.15 ; v3(139.35,78.11) 139.61,78.36 PU5001.3 ; U109.4 v3(157.11,47.58) ; v3(144.68,78.55) 144.46,78.76 PU5001.14 ; GPU1.B26 72.59,107.59 71.54,107.59 v4(71.53,107.58) ; GPU1.B14 71.59,98 71.41,97.82 v4(71.34,97.82) ; GPU1.B22 v4(71.17,104.4) ; v4(71.49,93.3) 71.6,93.2 GPU1.B8 ; U109.71 143.87,56.38 v3(145.07,55.18) ; GPU1.B20 71.02,102.8 v4(70.9,102.93) ; U52.11 v3(145.63,7.04) ; U9.22 v3(122.46,78.03) ; PU5001.1 139.82,79.16 v3(139.35,79.63) ; U118.8 133.74,36.57 v3(132.74,35.57) ; PU5201.14 104.34,63.72 104.22,63.6 v3(104.17,63.6) ; GPU1.H14 75.98,98.2 75.26,97.48 v4(75.08,97.48) ; v4(71.65,96.4) GPU1.B12 ; v3(119.64,78.13) 119.81,77.96 120.08,77.96 120.46,77.58 U9.27 ; U54.11 v3(90.33,11.81) ; U109.35 156.06,59.45 156.17,59.33 156.47,59.33 156.88,58.93 156.88,58.91 v3(156.94,58.85) ; U118.35 132.54,34.04 132.74,34.24 v3(132.74,34.71) ; PU5201.6 108.78,64.92 v3(109.13,64.57) 109.07,64.52 PU5201.5
  TOP w0.229: GPU1.B6 72.59,91.6 72.56,91.63 71.72,91.63 71.52,91.43 v4(71.46,91.43) ; v4(76.27,88.69) 76.27,89.53 GPU1.H2
  TOP w0.25: CPU1.AV33 95.58,152.28 v4(96.03,152.28) ; v4(90.2,149.82) CPU1.AY26 ; CPU1.V4 CPU1.V2 CPU1.V1 70.26,168.2 v4(69.99,168.2) ; CPU1.K30 93.69,174.6 94.02,174.27 94.02,174.27 v4(94.05,174.25) ; v4(71.9,176.2) CPU1.H4 72.9,175.8 CPU1.J5 ; v4(96.96,181.33) 96.96,181.23 96.86,181.13 96.03,181.13 CPU1.B33 ; v4(95.54,147.7) 95.4,147.7 95.39,147.71 CPU1.BC32 ; v4(94.09,153.68) 94.09,153.68 93.97,153.8 CPU1.AT30 ; CPU1.AP30 94.13,155.4 v4(94.13,155.4) ; v4(74.2,149.9) CPU1.AY6 ; v4(71.97,157) CPU1.AM4 ; CPU1.AD4 71.89,163.4 v4(71.89,163.41) ; v4(69.51,161.79) 69.52,161.8 CPU1.AF1 ; v4(93.88,150.95) 93.85,150.95 CPU1.AY30 ; v4(95.98,174.43) 95.67,174.43 CPU1.K33 ; CPU1.D30 93.7,179.8 93.7,179.94 v4(93.75,179.99) ; CPU1.T30 v4(94.1,169.8) ; v4(71.89,173.27) 71.89,173.21 72.1,173 CPU1.M4 72.9,173.4 CPU1.L5 ; CPU1.P5 72.9,171 CPU1.P4 CPU1.P2 CPU1.P1 70.19,171.4 v4(70.01,171.58) ; v4(85.55,147.96) 85.55,148.35 CPU1.BC20 ; CPU1.F9 76.7,177.9 v4(76.4,178.2) ; CPU1.F33 95.59,177.71 v4(96.3,177.71) ; CPU1.AF4 72.02,161.8 v4(71.77,162.05) ; v4(91.9,147.5) 91.8,147.6 91.8,148.46 91.8,148.47 CPU1.BC28 ; CPU1.AP33 v4(96.5,155.4) ; CPU1.Y5 72.93,165.83 72.93,165.43 CPU1.AB4 72.3,165 72.28,165.01 v4(71.9,165.01) 71.35,165.01 71.34,165 CPU1.AB2 71.26,165 71.23,165.03 70.53,165.03 CPU1.AB1 ; v4(71.9,158.58) 71.91,158.6 CPU1.AK4 ; v4(82.31,147.83) 82.2,147.94 CPU1.BC16 ; CPU1.K2 71.3,174.6 70.5,174.6 CPU1.K1 ; CPU1.AY28 v4(91.8,149.9) ; v4(81.97,149.76) 82.2,149.99 CPU1.AY16 ; CPU1.BC12 v4(79,147.6) ; CPU1.AK1 v4(69.6,158.6) ; v4(69.99,177.8) CPU1.F1 ; v4(90.64,179.93) 90.63,179.93 CPU1.D26 ; CPU1.AY20 v4(85.4,149.91) ; CPU1.A24 88.6,182.22 v4(88.42,182.4) ; CPU1.AY24 88.4,150.7 88.4,151.77 88.73,152.1 CPU1.AV25 ; CPU1.BC24 88.6,148.5 88.55,148.45 88.55,147.55 v4(88.6,147.5) ; CPU1.AV30 93.2,152.5 v4(92.99,152.5) ; v4(93.9,178.24) 93.5,177.84 CPU1.F30 ; CPU1.F4 v4(71.83,177.8) CPU1.F2 ; CPU1.AY12 v4(79,149.9) ; CPU1.AH4 71.98,160.2 71.96,160.22 v4(71.94,160.22) ; v4(75.8,147.6) 75.8,147.6 CPU1.BC8 ; v4(96.01,171.4) CPU1.P33 ; v4(72.6,149.96) 72.6,150.04 CPU1.AY4 ; CPU1.AP1 v4(69.6,155.4) ; CPU1.AT4 v4(71.9,153.8) ; CPU1.AY10 v4(77.4,149.9)
  TOP w0.254: CPU1.AY14 80.57,150.5 v4(80,151.06) ; CPU1.A16 82.2,182.42 v4(82.11,182.51) ; GPU1.A3 71.95,90 v4(71.64,89.69) ; CPU1.K2 71.7,174.6 v4(72.1,175) ; v4(71.51,106.11) 72.44,106.11 72.55,106 GPU1.B24 ; MEM1.G8 58.1,112.8 58.73,112.8 MEM1.G9 58.81,113 58.96,113.14 58.96,113.54 MEM1.F9 ; CPU1.AP1 CPU1.AP2 CPU1.AP4 ; GPU1.C1 73,88.63 v4(73.03,88.6) ; GPU1.A30 71.98,110 71.83,110.15 71.66,110.15 71.53,110.02 v4(71.32,110.02) ; GPU1.F2 74.6,89.77 75.01,90.18 75.01,90.57 74.77,90.81 74.68,90.81 v4(74.37,91.12) ; GPU1.B16 72.58,99.58 71.69,99.58 71.69,99.59 v4(71.58,99.59) ; v4(71.51,94.94) 72.46,94.94 GPU1.B10 ; CPU1.A28 91.8,181.54 91.8,182.6 v4(91.72,182.68) ; PU5201.2 108.36,61.62 PC5214.2 ; v4(71.69,101.39) 72.41,101.39 GPU1.B18 ; v4(95.14,182.82) 95.14,182.13 95,181.99 CPU1.A32 ; CPU1.Y5 72.9,166.2 CPU1.Y4 ; CPU1.BC4 v4(72.6,147.12) ; CPU1.A12 v4(79,182.01) ; R80227.1 21.17,163.59 21.17,161.98 v3(20.86,161.67) ; GPU1.K2 77.8,88.89 77.88,88.81 77.88,88.57 78.05,88.4 v4(78.05,88.34)
  TOP w0.305: CPU1.U5 72.9,168.2 CPU1.V4 ; R80225.2 71.85,189.62 72.22,189.25 72.22,187.06 R1603.2 ; v4(77,157.18) 76.5,156.68 CPU1.AN9 76.5,156.28 v4(76.2,155.98) ; v4(77,157.18) 77.6,157.78 CPU1.AL10 ; v4(77,157.18) 77.58,156.6 CPU1.AN10 ; v4(87.69,93.58) 87.69,94.31 GPU1.AB10 GPU1.Y10 ; GPU1.M12 79.28,96.28 v4(79.28,96.06) ; v4(58.41,88.41) 58.81,88.81 MEM2.E1 ; v4(58.41,88.41) 58.81,88.02 MEM2.D1 ; v4(58.41,88.41) 58.01,88.81 MEM2.E2 ; U6701.16 80.64,70.4 81.09,69.94 v3(81.09,69.9) U6701.15 ; NGFF1.45 v3(109.12,215.75) ; v3(43.03,73.86) 43.26,74.09 R533.2 ; v3(137.83,187.45) 138.63,186.65 DIMM1.14 ; v4(57.61,110.88) MEM1.J8 ; v4(58.41,90.02) MEM2.G1 ; CPU1.D10 77.4,179.96 77.4,179.96 v4(77.4,180.04) ; HDMI1.8 v3(115.56,36.32) ; GPU1.H17 76.2,100.58 76.52,100.26 v4(76.52,99.95) ; PWRCN1.4 30.63,23.25 31.11,22.77 v3(31.11,22.72) ; v4(51.48,114.44) 51.53,114.39 52.25,114.39 52.34,114.48 MEM1.E1 MEM1.E2 ; HDMI1.17 HDMI2.3 115.66,40.82 v3(115.48,40.64) ; CPU1.M30 93.81,172.69 v3(93.93,172.69) ; GPU1.AD8 89,93.2 v4(88.6,93.6) 88.2,94 GPU1.AC9 ; v4(75.3,151.8) 75.3,151 CPU1.AY8 ; GPU1.F12 75.16,96.4 v4(75.24,96.32) ; CPU1.D4 CPU1.C3 v4(71.1,180.3) ; v4(56.78,86.06) 57.15,86.42 MEM2.B3 ; CPU1.A8 CPU1.B8 v4(75.8,180.01) CPU1.D8 ; GPU1.P6 81,91.47 v4(81.31,91.16) ; HDMI1.11 HDMI2.9 v3(115.56,37.82) ; CPU1.D16 v4(82.2,180.01) ; v3(115.56,34.82) HDMI2.15 HDMI1.5 ; CPU1.J5 73.3,175.4 CPU1.K4 v4(72.1,175) ; MEM2.P9 52.41,96.01 v4(52.81,95.62) ; NGFF1.29 v3(109.12,211.75) ; v4(78.27,95.15) 77.8,95.62 77.8,95.64 ; v4(51.82,94.53) 51.93,94.42 MEM2.M9 ; CPU1.AV4 72.81,152.2 v4(73.01,152.4) 73.3,152.69 CPU1.AU5 ; U21.24 151.87,28.86 v3(151.81,28.8) ; U21.10 156.6,33.89 156.87,34.15 v3(157.1,34.15) ; GPU1.K32 77.8,111.26 v4(77.93,111.4) ; v4(80.57,93.71) 80.87,94 GPU1.P9 ; MEM2.J2 58.01,92.02 v4(57.62,91.62) ; HDMI1.22 113.99,31.92 114.39,32.32 HDMI2.20 ; CPU1.D12 v4(79,180.06) CPU1.B12 ; MEM2.P1 59.29,96.02 v4(59.52,95.79) ; MEM2.D8 53.23,88.02 v4(53.63,88.42) 53.24,88.82 MEM2.E8 ; GPU1.AH10 92,95 v4(92,95.88) ; v3(76.81,71.17) 77.98,71.17 U6701.5 ; v4(74.52,154.96) 74.9,155.34 CPU1.AP7 ; v4(87,180.01) CPU1.D22 ; CPU1.D24 88.55,179.45 88.55,178.35 v4(88.6,178.3) ; NGFF1.18 119.56,209 v3(119.88,209.32) ; NGFF1.23 v3(109.12,210.25) ; MEM2.F9 52.36,89.62 51.94,90.04 ; v3(38.87,104.29) 39.25,104.29 40.04,103.5 LVDS1.7 ; 51.94,90.04 v4(51.92,90.04) ; 51.94,90.04 51.97,90.04 52.36,90.42 MEM2.G9 52.51,90.52 53.11,90.52 MEM2.G8 ; v3(94.01,171.7) 93.71,171.4 CPU1.P30 ; U21.17 153.6,32.36 v3(155.35,30.61) ; U6701.13 80.03,68.18 v3(79.71,67.87) 79.53,68.05 U6701.12 ; GPU1.U25 83.22,107.18 v4(82.99,107.18) ; HDMI1.2 v3(115.56,33.32) ; NGFF1.69 v3(109.12,221.75) ; NGFF1.57 v3(109.12,218.75) ; MEM1.G1 51.77,112.88 51.76,112.9 v4(51.42,112.9) ; v4(74.2,180.04) CPU1.D6 ; CPU1.D14 v4(80.6,180.01) ; GPU1.N25 80.45,107.25 80.45,108.15 GPU1.N27 ; NGFF1.63 v3(109.12,220.25) ; v4(84.13,93.58) 84.02,93.58 GPU1.U9 ; U21.20 152.05,30.86 v3(151.85,30.66) 151.85,30.61 152.1,30.36 U21.21 ; MEM2.T1 58.79,97.62 58.41,97.24 v4(58.4,97.24) ; LVDS1.14 v3(43.63,96.5) ; Q64.S 142.47,33.1 Q63.1 ; CPU1.AR6 74.1,153.87 v4(73.85,153.62) ; CPU1.A20 v4(85.4,182.01) ; MEM2.A9 52.39,85.62 v4(52.01,86) 52.04,86.03 52.04,86.05 MEM2.B9 ; CPU1.D20 v4(85.4,180.01) ; U10.2 v3(44.81,11.94) ; U6701.10 v3(78.53,67.87) ; U21.8 v3(157.94,33.04) ; GPU1.C32 73,111.11 v4(72.75,111.36) ; C213.2 v3(41.56,21.36) ; CPU1.D18 v4(83.8,180.01) ; C3454.2 v3(38.51,21.36) ; NGFF1.33 v3(109.12,212.75) ; CPU1.T4 v4(72.9,170.2) ; CPU1.H30 v4(94.03,176.2) ; NGFF1.75 v3(109.12,223.25) ; MEM1.E8 57.9,114.59 57.9,115.1 58.01,115.21 MEM1.D8 ; v4(85.97,95.99) 86.36,95.6 GPU1.AA11 ; NGFF1.24 v3(119.88,210.5) ; NGFF1.39 v3(109.12,214.25) ; NGFF1.30 v3(119.88,212) ; NGFF1.36 v3(119.88,213.5) ; NGFF1.7 v3(109.12,206.25) ; GPU1.P25 GPU1.T25
  TOP w0.33: DIMM1.44 138.15,177.65 138.07,177.74 137.59,177.74 137.26,177.4 137.26,177.36 v3(137.07,177.16) ; DIMM2.54 153.55,174.65 153.43,174.52 153.17,174.52 152.31,173.66 v3(152.31,173.61) ; DIMM1.162 138.11,139.85 138.07,139.89 137.59,139.89 137.26,139.56 137.26,139.51 v3(137.07,139.32) ; v3(133.51,178.69) 133.51,178.94 132.7,179.75 DIMM1.37 ; DIMM2.134 153.06,148.25 152.5,147.68 152.5,147.64 v3(152.31,147.45) ; v3(137.83,130.81) 138.27,131.25 138.28,131.25 138.47,131.45 DIMM1.190 ; v3(137.83,137.29) 138.27,136.85 DIMM1.172 ; v3(148.75,135.89) 148.56,136.08 148.56,136.13 148.22,136.46 147.43,136.46 147.34,136.55 DIMM2.173 ; DIMM2.138 153.48,147.05 153.31,146.88 153.21,146.88 152.5,146.16 152.5,146.11 v3(152.31,145.92) ; v3(135.54,189.36) 135.54,189.4 136.39,190.25 DIMM1.2 ; DIMM1.189 132.62,131.75 133.51,130.86 v3(133.51,130.81) ; DIMM1.134 137.69,148.25 137.26,147.81 137.26,147.76 v3(137.07,147.57) 137.26,147.38 137.26,147.34 137.59,147 138.07,147 138.11,147.05 DIMM1.138 ; DIMM2.195 147.18,129.95 147.99,129.15 147.99,128.62 v3(148.01,128.6) ; v3(152.31,133.86) 152.38,133.98 153.45,135.05 DIMM2.178 ; DIMM2.172 153.22,136.85 152.5,136.13 152.5,136.08 v3(152.31,135.89) ; DIMM2.25 150.31,183.35 150.38,183.29 150.76,182.91 150.76,182.52 v3(150.78,182.5) ; v3(133.51,145.92) 133.51,145.97 132.98,146.49 132.3,146.49 132.05,146.75 DIMM1.139 ; v3(132.88,148.03) 132.53,148.03 132.08,148.47 132.03,148.55 DIMM1.133 ; v3(133.51,187.45) 133.51,187.55 132.91,188.15 DIMM1.9 ; DIMM1.26 138.09,183.05 138.07,183.07 137.59,183.07 137.26,182.74 137.26,182.69 v3(137.07,182.5) ; DIMM1.144 137.69,145.25 137.26,145.69 137.26,145.73 v3(137.07,145.92) ; DIMM2.72 153.49,169.25 153.43,169.19 151.6,169.19 150.97,169.82 150.97,169.86 v3(150.78,170.05) 149.92,169.19 147.63,169.19 147.27,169.55 DIMM2.71 ; DIMM1.49 132.24,176.15 132.3,176.09 132.99,176.09 133.32,175.75 133.32,175.7 v3(133.51,175.51) ; DIMM1.151 132.27,143.15 132.48,142.94 132.98,142.94 133.51,142.41 v3(133.51,142.37) ; DIMM2.8 153.17,188.45 152.5,189.12 152.5,189.17 v3(152.31,189.36) ; v3(148.75,170.05) 148.75,170.1 147.5,171.35 DIMM2.65 ; DIMM2.32 153.35,181.25 153.31,181.29 152.62,181.29 152.31,180.97 v3(152.31,180.72) ; DIMM1.155 132.14,141.95 132.37,141.72 132.8,141.72 133.51,141.02 v3(133.51,140.97) ; DIMM2.156 153.62,141.65 153.52,141.54 152.83,141.54 152.5,141.21 152.5,141.16 v3(152.31,140.97) ; v3(133.64,133.86) 133.64,133.9 133.05,134.49 132.77,134.49 132.74,134.52 132.37,134.52 132.14,134.75 DIMM1.179 ; DIMM1.32 138.11,181.25 138.07,181.29 137.59,181.29 137.55,181.25 137.47,181.25 137.07,180.85 v3(137.07,180.72) ; DIMM1.54 137.47,174.65 137.07,174.24 v3(137.07,173.48) ; DIMM2.14 152.85,186.65 152.31,186.1 v3(152.31,186.06) ; v3(137.07,175.51) 137.26,175.7 137.26,175.75 137.95,176.45 DIMM1.48 ; v3(152.31,144.15) 152.5,144.34 152.5,144.38 152.83,144.72 153.08,144.72 153.62,145.25 DIMM2.144 ; DIMM2.185 148.26,132.95 148.75,132.46 v3(148.75,132.08) 148.56,131.89 148.56,131.84 148.22,131.51 147.75,131.51 147.51,131.75 DIMM2.189 ; DIMM1.167 132.28,138.35 132.3,138.37 134.13,138.37 134.84,139.08 134.84,139.13 v3(135.03,139.32) ; v3(133.51,132.33) 133.32,132.52 133.32,132.57 132.94,132.95 DIMM1.185 ; v3(148.88,139.06) 148.88,139.11 147.84,140.15 DIMM2.161 ; v3(147.99,177.16) 147.2,177.95 DIMM2.43 ; v3(152.31,170.05) 152.31,170.35 152.7,170.75 153.39,170.75 153.69,171.05 DIMM2.66 ; DIMM2.31 147.63,181.55 147.75,181.67 149.27,181.67 149.52,181.93 149.55,181.93 149.88,182.26 149.88,182.28 149.99,182.4 149.99,182.47 v3(150.02,182.5) ; v3(133.51,185.93) 133.51,185.97 132.58,186.91 132.49,186.91 132.44,186.95 DIMM1.13 ; v3(150.4,143.76) 150.21,143.95 150.21,144 149.26,144.95 DIMM2.145 ; DIMM1.168 138.29,138.05 138.19,138.15 137.12,138.15 136.3,137.33 v3(136.3,137.29) ; v3(133.51,173.48) 133.54,173.51 133.54,173.86 133.05,174.35 DIMM1.55 ; v3(133.51,129.03) 133.32,129.22 133.32,129.27 132.99,129.6 132.94,129.6 132.6,129.95 132.39,129.95 132.39,129.95 DIMM1.195 ; v3(133.51,143.89) 133.51,144.32 132.88,144.95 DIMM1.145 ; DIMM1.66 138.45,171.05 138.28,170.88 137.38,170.88 137.07,170.56 v3(137.07,170.31) ; v3(137.07,178.69) 137.07,179.01 137.51,179.45 DIMM1.38 ; v3(148.75,186.06) 148.56,186.25 148.56,186.29 147.97,186.88 147.72,186.88 147.65,186.95 DIMM2.13 ; DIMM1.19 132.08,185.15 132.51,184.72 132.86,184.72 133.64,183.94 v3(133.64,183.9) ; v3(151.53,132.05) 151.72,132.24 151.72,132.32 152.4,132.99 153.43,132.99 153.68,133.25 DIMM2.184 ; v3(152.31,177.16) 152.5,177.36 152.5,177.4 152.83,177.74 153.31,177.74 153.39,177.65 DIMM2.44 ; v3(152.31,130.81) 152.5,131 152.5,131.05 152.9,131.45 DIMM2.190 ; v3(137.07,149.48) 137.19,149.61 137.19,149.65 137.59,150.05 138.07,150.05 138.07,150.05 DIMM1.128 ; DIMM2.2 151.63,190.25 150.97,189.59 150.97,189.55 v3(150.78,189.36) ; v3(132.75,182.5) 132.75,182.75 132.14,183.35 DIMM1.25 ; v3(148.88,145.92) 148.88,145.97 148.1,146.75 DIMM2.139 ; v3(132.88,135.89) 132.65,135.89 131.99,136.55 DIMM1.173 ; DIMM2.48 153.12,176.45 152.31,175.64 v3(152.31,175.51) ; DIMM2.196 152.88,129.65 152.5,129.27 152.5,129.22 v3(152.31,129.03) ; v3(144.89,142.16) 145.1,141.95 DIMM2.155 ; v3(148.75,175.51) 148.75,175.64 148.31,176.09 147.54,176.09 147.48,176.15 DIMM2.49 ; DIMM2.150 153.66,143.45 153.07,142.86 v3(153.07,142.62) ; DIMM2.60 153.66,172.85 152.94,172.13 v3(152.94,171.83) ; v3(133.51,170.31) 133.51,170.43 132.59,171.35 DIMM1.65 ; DIMM2.151 148.27,143.15 148.69,142.73 148.69,142.68 v3(148.88,142.49) ; v3(152.31,182.5) 152.31,182.83 152.55,183.07 153.31,183.07 153.33,183.05 DIMM2.26 ; v3(150.4,147.45) 150.21,147.64 150.21,147.68 149.15,148.74 147.52,148.74 147.33,148.55 DIMM2.133 ; v3(148.75,133.86) 148.75,134.37 148.37,134.75 DIMM2.179 ; DIMM2.162 153.04,139.85 152.5,139.3 152.5,139.26 v3(152.31,139.06) ; DIMM1.61 132.97,172.55 133.51,172 v3(133.51,171.96) ; DIMM1.127 132.69,150.35 133.51,149.53 v3(133.51,149.48) ; v3(148.75,149.61) 148.75,149.73 148.13,150.35 DIMM2.127 ; v3(148.75,184.28) 148.75,184.4 148,185.15 DIMM2.19 ; DIMM2.20 152.96,184.85 152.5,184.39 152.5,184.34 v3(152.31,184.15) ; DIMM2.61 147.57,172.55 147.63,172.49 148.14,172.49 148.75,171.88 v3(148.75,171.83) ; DIMM2.38 152.89,179.45 152.5,179.05 152.5,179.01 v3(152.31,178.82) ; DIMM1.3 133.2,189.95 133.51,189.64 v3(133.51,189.36) ; v3(152.31,137.54) 152.5,137.73 152.5,137.78 152.83,138.11 153.31,138.11 153.37,138.05 DIMM2.168 ; v3(137.83,128.91) 138.45,129.65 DIMM1.196 ; DIMM1.71 132.28,169.55 132.39,169.44 134.22,169.44 135.03,170.26 v3(135.03,170.31) 136.09,169.25 DIMM1.72 ; DIMM1.150 138.2,143.45 138.07,143.32 137.59,143.32 137.26,143.65 137.26,143.7 v3(137.07,143.89) ; DIMM2.55 147.8,174.35 148.56,173.59 148.56,173.55 v3(148.75,173.35) ; DIMM2.9 147.72,188.15 148.2,188.15 148.75,187.6 v3(148.75,187.45) ; DIMM1.60 138.47,172.85 137.83,172.21 v3(137.83,171.96) ; v3(137.07,189.36) 137.26,189.17 137.26,189.12 137.7,188.68 138.13,188.68 138.36,188.45 DIMM1.8 ; v3(148.75,178.95) 148.75,179.2 148.24,179.71 147.23,179.71 147.18,179.75 DIMM2.37 ; DIMM1.161 132.35,140.15 132.39,140.11 132.77,140.11 133.32,139.56 133.32,139.51 v3(133.51,139.32) ; v3(133.51,180.72) 133.51,180.77 132.95,181.33 132.39,181.33 132.17,181.55 DIMM1.31 ; DIMM1.178 136.69,135.05 135.73,134.09 135.73,134.05 v3(135.54,133.86) ; DIMM2.128 153.43,150.05 152.83,150.05 152.38,149.59 v3(152.31,149.48) ; v3(132.75,177.16) 132.75,177.19 131.98,177.95 DIMM1.43 ; v3(137.07,140.97) 137.26,141.16 137.26,141.21 137.59,141.54 138.46,141.54 138.56,141.65 DIMM1.156 ; DIMM2.3 148.2,189.95 148.75,189.4 v3(148.75,189.36) ; DIMM1.20 136.57,184.85 135.73,185.69 135.73,185.74 v3(135.54,185.93) ; v3(147.99,137.54) 147.99,137.9 147.54,138.35 DIMM2.167 ; DIMM1.184 137.63,133.25 137.26,133.62 137.26,133.67 v3(137.07,133.86)
  TOP w0.356: v4(87.72,92.05) 87.72,91.92 GPU1.AB6 ; GPU1.AA16 86.62,99.6 86.87,99.34 v4(86.87,99.28) 87.4,98.75 GPU1.AB15 ; CPU1.G20 85.6,177.1 v4(86,177.5) 86.4,177.9 CPU1.F22 ; v4(59.39,112.82) 59.33,112.88 MEM1.G9 ; v4(74.04,99.57) 74.11,99.57 74.13,99.6 GPU1.F16 ; GPU1.Y15 85.4,98.61 v4(84.94,99.06) 84.41,99.6 GPU1.V16 ; v4(84.15,107.04) 84.39,106.8 GPU1.W25 ; MEM2.J8 53.21,92.02 v4(53.61,92.42) ; CPU1.BB33 96.08,149 96.39,148.69 96.39,148.68 v4(96.4,148.67) ; CPU1.L25 89.5,173.6 v4(89.9,174) ; CPU1.AN21 86.64,155.96 v4(86.65,155.96) 86.65,155.95 CPU1.AP22 ; v4(83.6,175.9) 84,175.5 CPU1.J19 ; v4(51.94,105.94) 52.14,105.94 52.4,105.68 MEM1.T1 ; GPU1.T32 82.6,111.36 v4(81.69,112.27) ; v4(79.41,111.37) 79.4,111.36 GPU1.M32 ; MEM1.M1 51.89,108.88 v4(51.86,108.84) ; CPU1.AB10 77.6,164.77 77.31,164.47 v4(77.31,164.41) 77.11,164.41 CPU1.AD9 76.5,163.75 76.95,163.3 v4(77.22,163.3) 77.22,163.03 77.6,162.65 CPU1.AE10 76.5,161.5 CPU1.AG9 76.5,161.3 CPU1.AH10 ; GPU1.J31 v4(77,110.96) ; v4(89.72,153.42) 89.72,152.73 89.09,152.1 CPU1.AV25 ; v4(84.2,174) CPU1.L18 CPU1.N19 v4(84.2,171.6) CPU1.P18 CPU1.T19 v4(84.2,169.2) CPU1.U18 ; CPU1.AP27 91.35,155.15 v4(91.35,154.81) ; v4(87,149.94) CPU1.AY22 87,150.9 CPU1.AW22 ; v4(69.39,148.81) 69.92,148.81 CPU1.BB1 ; GPU1.G31 v4(75.4,111.03) ; CPU1.U24 v4(88.95,169.15) ; GPU1.T13 82.99,97.21 v4(82.99,97.21) 83.06,97.13 83.75,97.13 84.21,97.6 GPU1.V13 ; GPU1.W27 84.88,108.4 84.4,107.92 84.39,107.92 84.31,107.84 v4(84.26,107.84) 84.5,107.6 GPU1.W26 ; MEM1.P9 58.42,107.68 v4(58.4,107.68) ; CPU1.U21 v4(86.6,169.2) CPU1.T22 CPU1.P21 v4(86.6,171.6) CPU1.N22 CPU1.L21 v4(86.6,174) CPU1.K22 87.2,174.9 CPU1.J22 ; CPU1.AR25 88.8,154.5 v4(88.4,154.1) ; GPU1.P32 v4(81,112.29) ; GPU1.J7 77.36,92.04 77.36,92.03 v4(77.39,92) 77.4,92 GPU1.K6 ; GPU1.T6 82.29,91.29 v4(82.29,91.16) ; v4(79.89,108.89) 80.11,108.67 80.11,108.49 GPU1.N27 ; CPU1.J15 81.63,175.5 v4(81.33,175.8) ; CPU1.AK12 v4(79.4,159.73) CPU1.AH13 ; MEM2.T9 52.41,98.37 v4(52.46,98.42) ; v4(88.59,92.04) 88.59,92.01 GPU1.AD6 GPU1.AE7 ; v4(90.59,111.37) 90.6,111.36 GPU1.AF32 ; GPU1.AD32 v4(89,111.51) ; GPU1.Y32 v4(85.8,111.36) ; CPU1.AE16 CPU1.AD15 v4(81.8,164.4) CPU1.AB16 CPU1.Y15 v4(81.8,166.8) CPU1.W16 ; GPU1.V32 v4(84.2,111.36) ; CPU1.U15 v4(81.8,169.2) CPU1.T16 CPU1.P15 v4(81.8,171.6) CPU1.N16 CPU1.L15 v4(81.8,174) ; GPU1.E28 73.82,109.2 v4(74.22,109.61) ; CPU1.W13 v4(79.4,166.8) CPU1.Y12 CPU1.AB13 v4(79.4,164.4) CPU1.AD12 CPU1.AE13 ; v4(59.48,108.87) 59.46,108.88 MEM1.M9 ; v4(59.6,116.79) 59.51,116.88 MEM1.B9 ; CPU1.AK18 v4(84.2,159.73) CPU1.AH19 CPU1.AG18 v4(84.2,162) ; GPU1.AA13 86.65,97.6 v4(86.9,97.85) ; CPU1.AE22 CPU1.AD21 v4(86.6,164.4) CPU1.AB22 CPU1.Y21 v4(86.6,166.8) CPU1.W22 ; v4(75.16,101.15) 75.14,101.15 75.1,101.2 GPU1.F18 ; v4(92,95.88) 91.48,96.4 GPU1.AG12 ; v4(77.37,104.62) 77.79,104.2 GPU1.K22 ; CPU1.AV15 81.4,152.5 v4(81.2,152.5) 80.8,152.9 CPU1.AU14 ; v4(51.36,115.56) 52.14,115.56 MEM1.D1 ; CPU1.T10 77.07,169.27 v4(77.07,168.94) ; CPU1.K27 91.1,174.8 v4(91.5,175.2) ; CPU1.G26 v4(89.8,177.5) ; v4(74.09,92.91) 74.37,93.2 74.6,93.2 GPU1.F8 74.72,93.08 74.77,93.08 74.79,93.06 75.23,93.06 75.25,93.08 75.28,93.08 GPU1.G8 ; C6726.2 C6728.2 v3(94.39,35.66) ; MEM2.B1 59.65,86.42 v4(59.81,86.58) ; v4(85.91,102.65) 85.65,102.65 GPU1.Y20 ; CPU1.Y24 v4(88.95,166.75) ; CPU1.U12 v4(79.4,169.2) CPU1.T13 CPU1.P12 v4(79.4,171.6) CPU1.N13 CPU1.L12 v4(79.4,174) ; v4(74.06,94.64) 74.08,94.64 74.24,94.8 GPU1.F10 GPU1.G10 ; v4(76.54,102.54) 76.54,102.59 76.2,102.93 GPU1.H20 ; v4(54.7,118.75) 54.7,117.56 MEM1.B3 ; v4(87.38,153.29) 87.21,153.29 86.8,153.7 CPU1.AT22 ; MEM1.B1 52.23,116.88 52.13,116.98 52,116.98 v4(51.9,117.08) ; GPU1.F26 74.91,107.91 74.92,107.91 v4(75,107.99) 75.4,108.39 GPU1.G27 ; GPU1.V18 84.99,100.81 v4(84.99,100.79) 85.01,100.79 GPU1.Y17 ; v4(88.59,101.3) 88.59,100.99 GPU1.AC17 ; MEM1.T9 58.43,106.06 v4(58.43,106.09) ; GPU1.AB32 v4(87.4,111.36) ; CPU1.L24 v4(88.95,173.95) ; v4(81.84,107.8) 81.8,107.85 GPU1.R27 ; v4(80,152.5) 79.8,152.5 CPU1.AV12 78.6,152.9 CPU1.AU11 ; v4(74.05,104.65) 74.3,104.4 GPU1.F22 ; v4(74,106.02) 74.58,106.02 GPU1.F24 ; v4(51.92,107.65) 52.03,107.65 52.4,107.28 MEM1.P1 ; CPU1.F25 v4(88.6,178.3) ; CPU1.AN15 v4(80.6,156) ; CPU1.AU23 87.83,152.9 v4(88.25,153.31) ; CPU1.AR28 91.9,154.4 v4(92.3,154.8) ; v4(74.37,91.12) 74.38,91.13 74.38,91.38 GPU1.F6 ; CPU1.AL16 CPU1.AK15 v4(81.8,159.73) CPU1.AH16 CPU1.AG15 v4(81.8,162) ; v4(89.9,157.2) 89.5,156.8 CPU1.AN25 ; GPU1.AA27 v4(86.6,109) ; v4(86.6,162) CPU1.AG21 CPU1.AH22 v4(86.6,159.73) CPU1.AK21 CPU1.AL22 ; MEM1.E8 58.38,114.11 MEM1.F9 ; CPU1.AL19 84.2,158.4 ; v4(90.71,172.64) 90.71,172.59 CPU1.N27 ; v4(91.5,153.6) 91.1,153.2 CPU1.AU27 ; CPU1.G23 v4(87.4,177.5) ; CPU1.AN18 v4(84.23,155.97) ; v4(92.36,157.1) 91.9,156.64 CPU1.AN28 ; CPU1.AG12 v4(79.4,162) ; v4(92.3,174) 91.9,173.6 CPU1.L28 ; GPU1.AC27 87.82,108.02 87.81,108.02 v4(87.8,108.01) 87.82,107.98 87.82,107.98 GPU1.AC26 ; GPU1.AE27 v4(90.2,108.8) ; CPU1.AT19 84.6,153.3 v4(84.8,153.3) 85,153.3 CPU1.AU20 ; v4(92.3,176.4) 91.9,176 CPU1.J28 ; GPU1.K28 78.12,108.88 78.12,108.87 v4(78.19,108.8) 78.59,108.4 GPU1.L27 ; GPU1.U27 83.4,108.32 v4(83.01,107.93) ; MEM1.J2 53.21,111.28 v4(52.81,111.69) ; GPU1.V11 84.86,96.06 85.9,96.06 v4(85.97,95.99) ; C6729.2 v3(95.84,35.66) ; CPU1.J25 v4(88.6,175.9) ; GPU1.H6 76.51,91.29 76.51,91.21 v4(76.54,91.18) ; GPU1.AD25 v4(89.4,107.2) ; 77.8,95.64 GPU1.K11 ; v4(75.08,97.48) 75.06,97.5 74.94,97.5 74.6,97.85 GPU1.F14 ; v4(82.99,107.18) 82.78,107.18 GPU1.T25 ; GPU1.M6 79.4,91.37 v4(79.67,91.11) ; GPU1.J27 77,108.39 77.4,107.99 v4(77.4,107.98) ; GPU1.F20 74.73,102.8 75,102.53 v4(75.09,102.53) ; v4(58.76,118.32) 58.76,117.73 MEM1.A9 ; GPU1.Y25 85.83,106.8 v4(85.46,106.43) ; CPU1.G17 83.2,177.1 v4(83.6,177.5) 84,177.9 CPU1.F19 ; CPU1.AE19 CPU1.AD18 v4(84.2,164.4) CPU1.AB19 CPU1.Y18 v4(84.2,166.8) CPU1.W19 ; CPU1.W10 v4(77.05,167.95) ; v4(92.2,111.38) GPU1.AH32 ; GPU1.AC24 87.9,105.7 v4(87.7,105.7) 87.5,105.7 GPU1.AB24 ; v3(90.97,35.37) C6727.2 ; GPU1.AE14 90.23,97.77 v4(90.23,97.77)
  TOP w0.38: CPU1.AD24 v4(88.95,164.35) ; CPU1.K10 CPU1.L12 CPU1.N10 ; CPU1.AH13 CPU1.AG12 ; CPU1.G7 74.9,176.7 v4(74.6,176.4) ; v4(77.6,151.79) 77.6,151.8 77.3,152.1 CPU1.AV9 76.5,152.6 76.4,152.6 76.1,152.9 CPU1.AU8 ; CPU1.AV7 74.85,152.1 75.15,151.8 v4(75.3,151.8) ; 84.2,158.4 CPU1.AK18
  TOP w0.381: C238.2 31.76,26.33 31.62,26.33 31.41,26.12 31.41,25.79 v3(31.15,25.53) ; C6722.1 32.19,22.01 31.83,22.01 31.12,22.72 v3(31.11,22.72)
  TOP w0.406: Q36.1 v3(33.48,6.49) ; Q6702.1 101.88,123.81 101.56,124.13 101.56,124.94 101.39,125.11 Q6702.4 100.57,125.62 v3(100.79,125.85) ; v3(133.07,55.76) 133.07,55.82 133.75,56.5 Q37.4 ; Q6705.4 88.93,118.35 88.68,118.6 88.68,119.4 88.43,119.65 Q6705.1 ; v3(47.16,37.8) 47.64,37.8 PQ5005.1 ; U117.3 U117.8 120.74,40.89 HDMI2.25 ; v4(71.1,180.3) 71,180.4 CPU1.B2 ; v3(52.74,141.73) 53.67,141.73 54.19,142.26 Q18.1 ; v3(58.28,140.89) 58.21,140.95 Q18.4 ; Q65.4 38.95,141.27 39.15,141.48 v3(39.15,141.99) ; U5.8 U5.3 171.03,95.38 v3(171.15,95.25) ; v3(172.12,116.84) U3.3 U3.8 ; v3(36.23,138.82) 36.81,139.4 Q65.1 ; R1779.2 91.81,22.11 Q1217.4 ; Q37.1 v3(135.8,58.72) ; U116.3 U116.8 121.28,33.78 HDMI2.23 ; Q97.1 108.54,95.65 108.24,95.95 R1914.2 ; PQ5005.4 49.68,39.93 v3(49.93,39.67) ; U31.8 U31.3 120.95,37.36 HDMI2.24 ; Q6701.4 82.73,64.95 82.42,64.64 81.82,64.64 81.42,64.25 Q6701.1 81.42,62.63 v3(81.57,62.48) ; Q1217.1 94.95,20.65 v3(94.34,20.04) ; Q36.4 v3(31.61,9.26) ; v3(111.74,94.35) Q97.4
  TOP w0.508: C1831.2 C1829.2 140.9,8.31 v3(140.57,8.64) ; R545.2 v3(80.93,191.87) ; HDD1.7 11.75,146.69 ; HDD1.7 12.63,145.81 ; HDD1.7 10.87,145.81 ; 94.38,188.94 H1.1 ; H1.1 94.38,195.68 ; H1.1 97.75,192.31 ; R1709.2 v3(102.93,217.17) ; C248.2 151.38,18.63 151.38,19.23 v3(152.18,20.03) ; v3(80.55,134.29) 80.49,134.35 C1734.2 R1867.2 ; PC4803.2 24.24,155.68 v3(24.42,155.85) ; 180.42,79.89 UHS1.MS2 179,80.91 ; v4(66.39,153.54) 65.95,153.09 C57.2 ; ODD1.8 9.72,170.63 ; ODD1.8 7.08,170.63 ; ODD1.8 8.4,171.95 ; ODD1.8 8.4,169.31 ; ODD1.9 9.72,183.37 ; ODD1.9 8.4,184.69 ; ODD1.9 7.08,183.37 ; ODD1.9 8.4,182.05 ; H3.1 97.75,137.93 ; H3.1 94.38,134.56 ; H3.1 93.24,139.06 C1639.2 C1638.2 ; H3.1 94.38,141.3 ; v3(116.81,57.66) R1700.1 ; 10.87,142 HDD1.4 12.63,142 ; PR5285.2 42.24,73.07 v3(43.03,73.86) ; HS6.1 147.86,214 ; HS6.1 144.25,210.39 ; HS6.1 144.25,217.61 ; HS6.1 140.64,214 ; DCIN1.6 50.97,24.18 ; DCIN1.6 48.79,24.18 ; DCIN1.6 49.88,25.74 ; DCIN1.6 49.88,22.62 ; Q46.3 85.63,41.59 v3(85.63,41.15) ; v3(117.03,15.04) 116.97,14.99 PC4914.1 ; v3(108.43,16.08) R433.2 108.43,17.01 108.75,17.32 C872.2 ; X2.2 55.45,151.3 55.22,151.08 v3(55.22,150.45) X2.3 ; SSUSB2.11 177.99,101.74 ; SSUSB2.11 176.12,102.81 ; SSUSB2.11 176.12,100.67 ; v3(37.4,26.36) 37.94,26.9 C582.2 ; R2003.2 60.1,175.26 60.56,175.72 v3(62.52,175.72) ; R2063.2 55.1,147.83 v3(55.05,147.78) 54.77,148.06 C1738.2 ; PC5011.2 v3(137.32,86.11) ; v3(166.3,90.4) 166.23,90.33 Q76.S 164.64,89.78 C1864.1 ; C6719.2 68.74,30.45 68.46,30.18 68.44,30.18 R1850.2 ; U49.4 105.89,83.82 106.08,83.63 v3(106.92,83.63) 106.95,83.59 107.38,83.59 107.55,83.43 C753.2 ; ODD1.1 9.03,173.19 ; ODD1.1 7.27,173.19 ; ODD1.1 8.15,172.31 ; MEMCD1.12 171.1,131.4 ; MEMCD1.12 171.1,129.58 ; MEMCD1.12 169.52,128.91 LED3.K ; v3(151.11,6.83) 151.21,6.93 151.21,9.6 150.09,10.73 SPK1.5 ; D24.2 v3(93.97,30.28) ; C1764.1 92.43,23.53 v3(91.6,22.71) ; C864.2 v3(126.78,217.96) ; CPU1.D28 91.8,180.09 v4(91.78,180.11) ; v3(73.06,138.43) 72.87,138.24 C67.2 ; NGFF1.76 v3(109.59,203.65) ; PR5251.2 PR26.2 PR31.2 ; PR5251.2 111.16,72.58 111.16,71.63 PC12.2 111.16,71.37 111.16,70.42 PR7.2 v3(110.27,70.36) ; PR5251.2 110.4,72.64 v3(110.27,72.52) ; SSUSB1.10 176.12,111.51 ; SSUSB1.10 177.99,110.44 ; SSUSB1.10 176.12,109.37 ; v3(58.28,140.89) 58.45,140.72 58.45,139.31 57.7,138.56 R172.2 ; PC4903.2 116.24,11.56 v3(116.24,11.81) ; C227.2 87.41,20.83 87.79,20.45 v3(87.92,20.45) 88.08,20.45 88.71,21.08 R1781.2 ; v4(96.5,108.28) 96.6,108.37 C756.2 ; PC5001.2 v5(133.9,80.77) ; PU4.1 157.13,115.95 BTRST1.1 159.16,115.7 159.8,115.06 C1736.2 159.86,112.01 C871.2 ; 7.27,180.81 ODD1.7 ; ODD1.7 9.03,180.81 ; ODD1.7 8.15,181.69 ; C721.1 106.65,37.3 v3(106.64,37.31) ; PR4816.2 13.69,156.4 14,156.72 ; C1807.2 C1803.2 44.97,15.88 44.84,15.75 v3(44.58,15.75) ; v3(36.23,138.82) 36.23,138.82 36.23,139.53 35.66,140.1 R722.2 ; 14,156.72 13.69,157.04 PR4802.1 ; 14,156.72 v3(14.13,156.72) ; HDT1.3 98.46,209.3 98.75,209.59 98.75,210.57 ; 7.27,177 ODD1.4 7.28,176.62 ; MEMCD1.3 v3(168.21,142.22) ; v3(48.9,36.65) 48.9,36.5 49.59,35.81 49.94,35.81 ; C1768.1 58.71,142.49 58.33,142.11 v3(58.33,141.96) ; HDD1.8 13.32,135.63 ; HDD1.8 12,136.95 ; HDD1.8 10.68,135.63 ; HDD1.8 12,134.31 ; Q31.E 162.05,64.55 C170.2 162.02,64.26 C550.1 160.24,63.18 v3(160.05,62.99) 159.93,63.12 159.93,64 159.35,64.58 C548.1 C549.1 ; v3(160.69,123.95) 160.38,123.63 C100.2 C99.2 C1737.1 ; R80215.2 140.5,43.43 v3(140.88,43.81) ; C545.2 151.65,35.81 v3(151.52,35.69) ; v3(134.6,75.23) 134.73,75.11 PC5014.2 ; PR77.2 PC5433.2 68.74,81.92 70.37,83.55 v4(71.03,83.55) C787.2 72.51,84.24 C789.2 C785.2 ; v3(39.28,138.38) 39.54,138.38 R732.2 ; 52.39,21.16 DCIN1.5 52.39,20.06 ; R360.2 162.06,34.16 v3(162.21,34.32) ; R2082.2 C3378.2 ; C3378.2 129.68,41.97 C3383.2 C3366.2 ; C3378.2 v3(129.69,42.83) ; v3(48.29,28.7) 47.31,29.69 Q22.E 44.67,30.96 C88.2 ; Q1247.S v3(50.99,166.75) Q1248.S 49.4,162.56 Q1244.S ; Q1208.E 72.66,134.27 73.03,134.65 v3(73.03,135.18) ; v3(38.44,77.77) 38.36,77.85 LVDS1.32 ; v3(25.94,17.4) 25.94,17.73 26.75,18.54 PWRCN1.12 ; C126.1 163.41,86.06 163.43,86.09 163.43,86.56 v3(163.53,86.66) ; PQ4408.S v3(72.67,64.39) 72.68,64.4 72.68,65.76 72.67,65.77 PQ5003.S ; 98.75,210.57 v3(98.74,210.57) HDT1.5 ; 98.75,210.57 C1739.2 ; C755.1 v3(101.13,90.7) 101.13,91.41 102.59,92.87 Q48.E ; v3(54.64,157.61) 54.64,157.86 55.41,158.62 R2004.2 C1735.2 R1690.1 ; C1800.2 34.39,10.07 35.01,9.45 v3(35.06,9.45) 35.06,8.12 X4.4 ; v3(67.06,62.13) 67.79,62.86 PQ5004.S 67.87,62.93 PR5298.2 ; C6721.2 128.81,27.71 v3(129.47,28.37) 128.8,29.04 C3377.2 128.41,29.16 Q1249.S ; v5(43.64,135.05) 44.03,134.67 C95.2 ; C1925.2 89.39,5.89 v3(89.82,6.32) C1928.2 ; v3(131.73,5.78) 131.99,5.52 PC4909.2 ; v4(88.42,182.4) 88.42,183.06 v4(88.87,183.51) ; PC96.2 v3(105.06,6.54) ; C256.2 C236.2 145.77,18.48 145.77,20.43 v3(146.29,20.95) 146.91,21.58 146.91,23.18 C255.2 C235.2 ; C752.2 97.15,106.34 v4(96.47,105.67) ; R1899.2 v3(99.58,100.2) ; 183,129.58 MEMCD1.14 183,131.4 ; C1796.2 143.8,71.37 v3(143.54,71.12) ; v3(132.97,31.36) 132.97,31.05 133.88,30.13 C3380.1 ; C542.2 161.64,43.12 161.86,42.89 Q1227.S 161.64,41.97 161.07,42.54 v3(160.95,42.54) ; R2008.2 55.55,155.57 v3(55.29,155.32) ; v3(110.27,79.5) PR40.2 PR38.2 PR36.2 ; v3(78.9,187.86) C1721.1 R1608.2 R1609.2 ; C6706.2 v3(99,117.47) 99.09,117.56 C6704.1 99.47,119.19 100.11,119.82 R79667.2 ; v3(91.6,22.71) 91.19,23.11 C1769.2 R1782.2 ; v3(91.6,22.71) R1779.2 ; PR4922.2 105.7,12.57 105.44,12.83 v3(104.94,12.83) ; 12.82,214.81 FANC3.1 15.18,214.81 ; 176.12,122.17 SSUSB1.11 ; SSUSB1.11 176.12,124.31 ; SSUSB1.11 174.25,123.24 ; SSUSB1.11 177.99,123.24 ; HDT1.7 98.33,211.84 98.71,211.46 v3(98.74,211.46) 98.74,211.48 99.09,211.84 C1870.1 ; C579.2 v3(42.2,10.49) ; C793.2 C792.2 75.85,84.69 v4(76.19,84.34) 76.19,83.61 C788.2 ; R79668.2 76.12,66.15 75.56,66.71 v3(75.56,67.39) ; C859.2 108.24,91.82 107.41,91 107.41,90.61 106.97,90.17 v3(106.97,89.76) R1917.1 C853.2 ; R2086.2 v3(132.87,28.36) ; C131.2 160.83,85.24 v3(160.27,84.68) 159.7,84.68 C129.2 C127.2 ; v3(43.47,117.73) 43.25,117.73 42.12,118.86 Q103.S 41.64,120.24 C869.2 ; v4(55.15,163.58) 55.66,163.58 55.79,163.7 R1658.1 ; 12,196.43 SATAP1.2 ; SATAP1.2 13.07,197.5 ; SATAP1.2 12,198.57 ; SATAP1.2 10.93,197.5 ; R73.1 15.46,206.57 v3(15.02,206.12) ; v3(120.94,81.41) PC17.2 PC18.2 v3(118.4,82.42) ; C225.2 141.3,23.03 v3(141.3,20.65) 141.3,18.63 C226.2 ; PC5243.2 18.07,147.83 17.58,147.35 v3(17.58,146.43) ; 176.12,87.87 SSUSB2.10 ; SSUSB2.10 176.12,90.01 ; SSUSB2.10 177.99,88.94 ; SSUSB2.10 174.25,88.94 ; C562.2 142.98,42.81 C565.2 142.98,40.73 143.42,40.3 v3(143.42,39.12) ; R1919.2 v3(111.98,91.01) ; C6702.2 81.51,70.32 v3(81.09,69.9) 81.72,69.28 C6701.2 ; R1914.2 v3(107.48,96.77) ; C6703.2 74.33,70.92 v3(74.58,71.17) ; C61.2 68.55,138.49 69.04,138 69.05,138 69.38,137.68 69.38,136.65 v3(68.99,136.27) 68.42,135.7 Q79.S ; R1631.2 88.04,192.91 87.76,192.63 v3(87.03,192.63) ; C6707.2 98.2,122.36 v3(98.2,122.12) ; R1619.2 v3(76.87,199.24) ; v3(169.15,109.89) C104.2 C105.1 ; C315.2 v3(47.28,124.84) ; v3(76.49,135.2) 76.08,134.79 76.04,134.18 Q1209.S ; PR4917.2 105.7,11.56 v3(105.19,12.06) ; v3(99.96,64.64) PC5204.2 PR5209.2 ; C4102.2 107.79,56.07 v3(108.3,56.58) ; C1929.2 v3(90.84,6.32) 91.27,5.89 C1927.2 ; C1855.1 47.3,110.82 v3(47.17,110.7) ; R1691.1 C78.2 61.27,159.77 61.02,160.02 v3(61.02,160.78) ; Q1245.S 47.44,169.51 46.67,170.28 v3(46.01,170.28) ; R1209.2 105.9,204.6 105.44,204.14 v3(105.44,204.09) ; 183,158.17 MEMCD1.15 183,160 ; v3(50.63,5.46) 49.09,5.46 Q101.E ; v3(27.08,9.02) 27.57,9.5 TOUCH1.2 ; v3(60.55,152.27) R1670.2 R79650.2 ; R1207.2 v3(77.15,80.65) ; C6718.2 64.42,45.52 R1848.2 v3(65.39,44.83) C258.2 ; R1886.2 R1882.2 82.31,82.47 v4(82.56,82.71) ; v3(64.2,186.42) 64.56,186.06 PR4611.1 ; 52.39,31 DCIN1.7 53.95,31 ; v3(49.46,51.38) 49.46,50.67 C32.2 ; X5.2 v3(101.75,112.52) ; 10.93,192.5 SATAP1.4 ; SATAP1.4 13.07,192.5 ; SATAP1.4 12,193.57 ; SATAP1.4 12,191.43 ; U7.4 v3(129.37,50.42) ; PR36.2 PR33.2 PR31.2 ; PR36.2 v3(110.27,77.22) ; D4.2 v3(165.86,107.6) ; X4.2 37.91,5.79 v3(38.67,5.03) ; C101.2 R178.1 v3(50.71,136.78) 51.21,137.29 C857.2 ; v3(140.37,33.78) 141.86,33.78 Q64.S ; 99.61,21.86 USB4.5 98.35,22.31 ; v3(143.16,206.38) 143.35,206.57 C103.2 ; C862.2 40.77,127 v3(40.55,126.77) ; C760.2 v3(79.37,113.39) ; R762.2 C589.2 107.6,28.7 107.86,28.45 110.27,28.45 111.6,29.78 HDMI1.22 118.55,29.78 HDMI2.22 ; C574.2 v3(42.9,13.39) ; v3(156.55,79.76) 156.55,80.4 C132.1 ; v3(118.96,48.95) 119.13,48.77 C1823.2 ; R1702.2 v3(101.35,214.38) ; v3(71.66,28.07) 72.04,28.45 C1802.2 72.04,29.91 C1806.2 ; R210.2 167.93,86.49 168.18,86.23 v3(168.56,86.23) ; C1758.1 38.13,118.75 38.11,118.72 v3(38.11,118.57) ; v3(144.43,32.44) 144.43,32.41 144.36,32.33 C521.2 ; HDT1.17 v3(98.74,218.19) ; v3(72.09,142.94) R1685.2 71.22,142.88 R154.2 ; PR31.2 v3(110.29,74.93) ; R144.2 v3(42.58,24.54) ; v3(82.96,191.87) R2001.2 C1722.1 ; C77.2 78.27,142.31 v3(78.36,142.21) 77.82,141.67 R79652.2 R1663.2 ; v3(78.9,189.38) 78.62,189.38 77.88,190.12 R1629.2 ; R1894.2 100.25,87.06 v3(100.24,87.07) ; v3(27.21,23.6) 26.75,24.06 PWRCN1.11 ; v3(63.74,147.7) 64.02,147.98 64.02,148.12 R1644.1 64.36,148.68 64.9,149.22 65.5,149.22 C58.2 ; v3(132.3,61.95) C194.2 R368.2 ; C585.2 32.42,26.99 C238.2 ; R940.2 R1881.2 R1880.2 104.17,100.84 v3(103.67,100.33) ; PC5016.2 v3(135.29,86.23) ; v3(43.35,112.93) 43.26,113.02 43.26,113.87 42.79,114.34 R79659.2 ; v3(87.03,188.57) 87.51,188.57 88.04,189.1 R1623.1 ; C1799.2 38.41,10.07 v3(38.41,9.45) 38.81,9.45 39.05,9.21 R412.1 40.17,9.21 R1819.2 ; PR4613.1 v3(51.21,195.1) ; v3(64.06,139.66) 64.2,139.66 64.61,139.26 R79681.1 ; R1999.2 83.28,196.41 83.01,196.14 v3(83.01,195.94) ; v3(95.66,52.76) 97.11,52.76 BT1.2 ; 12,147.05 HDD1.9 ; HDD1.9 13.32,148.37 ; HDD1.9 10.68,148.37 ; HDD1.9 12,149.69 ; PR4807.2 16.33,154.61 v3(16.15,154.79) ; v3(40.52,127.71) 40.53,127.7 R1179.1 ; R1.2 v3(101,225.27) ; C1850.2 99.98,99.06 v3(100.49,99.57) 101,100.08 C1848.2 ; 171.1,160 MEMCD1.13 171.1,158.17 ; v3(34.2,9.25) 33.97,9.25 33.24,9.97 33.24,10.03 C572.2 ; C1742.2 v3(123.38,224.54) ; HDMI2.25 v3(119.46,40.97) ; C1747.2 C1754.1 95.35,26.16 v3(94.7,26.16) ; C197.1 137.83,56.52 v3(137.32,57.02) ; C3376.1 v3(136.93,28.3) ; v3(70.77,187.83) 70.9,187.83 71.15,187.58 R1604.2 ; Q1246.S 58.99,134.49 58.37,134.49 v3(57.59,135.28) ; v3(135.59,50.19) 135.38,50.19 134.84,49.65 Q107.S ; R1705.2 v3(101.35,216.92) ; v3(142.22,102.97) 142.5,103.25 PC5012.2 ; C1700.2 92.51,16.55 92.77,16.29 Q105.S 93.85,16.29 94.52,15.62 v3(94.52,15.37) ; v3(135.79,42.79) C3381.1 135.8,41.98 C3379.2 ; C852.2 v3(108.71,84.76) ; R107.2 R1604.2 ; R1604.2 R1603.2 R1606.2 R1605.2 R1607.2 ; v3(66.71,174.31) C52.2 65.71,174.31 65.52,174.5 63.75,174.5 X1.2 ; C1702.2 v3(39.15,146.53) ; X1.4 v3(60.69,171.68) ; C593.2 44.93,5.52 44.42,6.03 Q100.E 43.94,5.62 44.03,5.54 v3(44.03,4.67) ; v3(140.88,5.97) 141.21,5.64 C1830.2 ; 51.69,21.94 DCIN1.2 51.69,23.03 ; 74.71,25.27 74.71,28.57 75.22,29.08 U12.2 ; R79665.1 104.17,120.43 v3(103.16,119.42) ; v3(76.78,138.82) 76.77,138.81 76.42,138.81 R1871.2 ; R370.2 137.64,62.61 136.85,63.4 v3(136.75,63.4) ; C552.2 151.67,26.04 151.16,25.53 v3(151.16,25.4) 151.16,23.37 C247.2 ; PR29.1 v3(129.55,73.79) ; R1688.2 83.92,139.7 84.3,140.08 R1660.2 R152.2 83.28,140.53 82.58,139.83 v3(81.57,139.83) C66.2 R1869.2 ; PR3.2 v3(117.51,64.49) ; v3(39.15,141.99) 39.53,142.37 C865.1 ; R1817.2 v3(31.85,4.78) ; R1703.2 v3(101.35,215.65) ; v3(119.46,37.06) 119.52,37.06 119.53,37.07 HDMI2.24 ; R181.2 56.48,143.45 v3(56.93,143) ; PC4906.2 115.83,13.97 v3(116.39,13.41) ; PC4910.2 v3(133.51,23.43) ; v3(104.4,15.75) PC4912.2 ; C863.2 v3(39.66,4.67) ; HDMI2.21 114.05,44.22 HDMI1.21 ; PR4630.1 v3(18.19,195.1) ; R1592.2 133.36,43.18 v3(133.75,42.78) ; HDMI2.23 120.31,33.17 v3(119.43,34.05) ; R1873.2 R1724.2 R79651.2 v4(55.58,167.77) ; v3(39.38,151.86) 39.53,152.02 PC4802.2 ; SPK1.7 v3(142.04,12.58) ; NGFF1.77 v3(109.59,224.35) ; R132.2 44.18,32.36 44.15,32.38 v3(43.82,32.38) C87.2 C33.2 ; v3(64.99,171.25) 65.32,171.25 65.58,171.51 C50.2 ; 10.87,138.19 HDD1.1 ; HDD1.1 11.75,137.31 ; HDD1.1 12.63,138.19 ; PU7.1 v3(63.3,79.12) ; PC5009.2 147.51,76.96 148.12,76.35 148.12,76.28 v3(148.16,76.23) 148.12,76.23 147.96,76.07 PC5018.2 ; v3(95.28,10.67) 95.16,10.54 LED2.K ; Q50.2 v3(94.74,220.83) ; C121.1 v3(156.95,83.76) ; R1649.2 64.99,170.27 65.85,169.42 v3(66.07,169.42) ; v3(105.62,31.14) 105.65,31.11 C714.1 ; R1206.2 v3(78.16,80.65) ; X5.4 v3(100.24,107.71)
  L3 w0.508: 28.14,46.7 H9.4 ; H9.4 28.92,47.49 ; H9.4 28.14,48.27 ; H6.4 166.66,228.92 ; H6.4 165.88,228.14 ; H6.4 167.45,228.14 ; 7.08,170.63 ODD1.8 ; ODD1.8 9.72,170.63 ; ODD1.8 8.4,171.95 ; ODD1.8 8.4,169.31 ; 163.34,221.08 H6.8 ; H6.8 162.55,221.86 ; H6.8 164.12,221.86 ; 10.87,138.19 HDD1.1 ; HDD1.1 11.75,137.31 ; HDD1.1 12.63,138.19 ; H6.5 163.34,228.92 ; H6.5 164.12,228.14 ; H6.5 162.55,228.14 ; 26.92,45.48 H9.3 27.71,46.27 ; 173.43,61.15 H11.3 174.04,60.97 ; 8.4,182.05 ODD1.9 ; ODD1.9 7.08,183.37 ; ODD1.9 8.4,184.69 ; ODD1.9 9.72,183.37 ; 5.75,157.33 H7.3 ; H7.3 6.54,156.54 ; H7.3 7.33,157.33 ; 169.78,159.09 MEMCD1.13 ; MEMCD1.13 172.42,159.09 ; MEMCD1.13 171.1,158.17 ; MEMCD1.13 171.1,160 ; 162.12,222.29 H6.7 161.33,223.08 ; 52.39,29.9 DCIN1.7 52.39,29.36 ; 163.34,16.33 H10.2 162.73,16.51 ; HS6.1 144.25,215.94 ; HS6.1 142.31,214 ; HS6.1 146.19,214 ; HS6.1 144.25,212.06 ; 174.25,101.74 SSUSB2.11 ; SSUSB2.11 176.12,100.67 ; SSUSB2.11 177.99,101.74 ; SSUSB2.11 176.12,102.81 ; H9.8 21.86,51.6 ; H9.8 21.08,50.81 ; H9.8 21.86,50.03 ; 12,191.43 SATAP1.4 ; SATAP1.4 10.93,192.5 ; SATAP1.4 12,193.57 ; SATAP1.4 13.07,192.5 ; 48.79,24.18 DCIN1.6 ; DCIN1.6 50.97,24.18 ; DCIN1.6 49.88,22.62 ; DCIN1.6 49.88,25.74 ; 10.68,135.63 HDD1.8 ; HDD1.8 12,134.31 ; HDD1.8 12,136.95 ; MEMCD1.12 171.1,131.4 ; MEMCD1.12 171.1,129.58 ; MEMCD1.12 172.42,130.49 ; MEMCD1.12 169.78,130.49 ; H7.7 3.46,163.46 ; H7.7 4.25,162.67 ; H7.7 2.67,162.67 ; 174.25,123.24 SSUSB1.11 ; SSUSB1.11 176.12,122.17 ; SSUSB1.11 176.12,124.31 ; SSUSB1.11 177.99,123.24 ; H9.5 28.92,50.81 ; H9.5 28.14,51.6 ; H9.5 28.14,50.03 ; 8.15,172.31 ODD1.1 ; ODD1.1 7.27,173.19 ; ODD1.1 9.03,173.19 ; 51.69,24.12 DCIN1.2 51.69,23.03 ; 7.67,157.67 H7.4 7.67,159.25 ; 10.87,145.81 HDD1.7 11.08,146.48 ; v3(165.34,74.4) 165.34,76.33 164.32,77.34 v3(162.59,77.34) ; 168.67,21.66 H10.5 168.49,22.27 ; ODD1.7 8.15,181.69 ; ODD1.7 9.03,180.81 ; ODD1.7 7.27,180.81 ; v3(156.01,156.97) 155.86,157.12 v3(150.99,157.12) ; 12,196.43 SATAP1.2 ; SATAP1.2 13.07,197.5 ; SATAP1.2 12,198.57 ; SATAP1.2 10.93,197.5 ; 175.78,66.58 H11.5 175.96,65.97 ; 2.67,157.33 H7.2 ; H7.2 4.25,157.33 ; H7.2 3.46,156.54 ; 23.08,52.82 H9.7 22.29,52.03 ; 5.75,162.67 H7.6 ; H7.6 6.54,163.46 ; H7.6 7.33,162.67 ; 165.88,221.86 H6.1 ; H6.1 166.66,221.08 ; H6.1 167.45,221.86 ; 23.08,45.48 H9.2 22.29,46.27 ; 7.67,162.33 H7.5 7.67,160.75 ; 176.12,109.37 SSUSB1.10 ; SSUSB1.10 174.25,110.44 ; SSUSB1.10 176.12,111.51 ; SSUSB1.10 177.99,110.44 ; 183,129.58 MEMCD1.14 ; MEMCD1.14 183,131.4 ; MEMCD1.14 181.68,130.49 ; 168.67,226.92 H6.3 167.88,227.71 ; 161.33,226.92 H6.6 162.12,227.71 ; 167.88,222.29 H6.2 168.67,223.08 ; 166.06,16.51 H10.3 166.66,16.33 ; 181.68,159.09 MEMCD1.15 ; MEMCD1.15 183,160 ; MEMCD1.15 183,158.17 ; H7.8 2.33,162.33 ; H7.8 2.33,160.75 ; H7.8 1.54,161.54 ; 175.96,62.89 H11.4 175.78,63.5 ; H9.1 21.86,48.27 ; H9.1 21.86,46.7 ; H9.1 21.08,47.49 ; 12.63,142 HDD1.4 10.87,142 ; 170.96,60.97 H11.2 170.35,61.15 ; 9.03,177 ODD1.4 7.27,177 ; 168.67,18.34 H10.4 168.49,18.94 ; 2.33,157.67 H7.1 ; H7.1 2.33,159.25 ; H7.1 1.54,158.46 ; 26.92,52.82 H9.6 27.71,52.03 ; SSUSB2.10 177.99,88.94 ; SSUSB2.10 174.25,88.94 ; SSUSB2.10 176.12,87.87 ; SSUSB2.10 176.12,90.01
  L4 w0.254: v3(86.65,93.52) 86.24,93.12 86.24,91.75 87.31,90.68 88.71,90.68 91.28,88.11 101.58,88.11 102.9,86.79 110.6,86.79 118.65,78.74 118.65,76.96 116.44,74.75 116.44,69.17 117.09,68.52 127.73,68.52 129.01,69.8 129.01,73.25 v3(129.55,73.79)
  L4 w0.508: 5.75,157.33 H7.3 5.93,156.72 ; SSUSB2.11 177.99,101.74 ; SSUSB2.11 176.12,102.81 ; SSUSB2.11 176.12,100.67 ; SSUSB2.11 174.25,101.74 ; 168.67,226.92 H6.3 167.88,227.71 ; 144.25,212.06 HS6.1 ; HS6.1 144.25,215.94 ; HS6.1 146.19,214 ; HS6.1 142.31,214 ; 169.78,130.49 MEMCD1.12 ; MEMCD1.12 172.42,130.49 ; MEMCD1.12 171.1,131.4 ; MEMCD1.12 171.1,129.58 ; SSUSB2.10 177.99,88.94 ; SSUSB2.10 174.25,88.94 ; SSUSB2.10 176.12,87.87 ; SSUSB2.10 176.12,90.01 ; 8.15,172.31 ODD1.1 ; ODD1.1 9.03,173.19 ; ODD1.1 7.27,173.19 ; H6.5 164.12,228.14 ; H6.5 163.34,228.92 ; H6.5 162.55,228.14 ; 169.78,159.09 MEMCD1.13 ; MEMCD1.13 171.1,160 ; MEMCD1.13 172.42,159.09 ; MEMCD1.13 171.1,158.17 ; 173.43,61.15 H11.3 174.04,60.97 ; 5.75,162.67 H7.6 5.93,163.28 ; ODD1.8 8.4,171.95 ; ODD1.8 7.08,170.63 ; ODD1.8 9.72,170.63 ; ODD1.9 8.4,184.69 ; ODD1.9 9.72,183.37 ; ODD1.9 7.08,183.37 ; ODD1.9 8.4,182.05 ; H9.4 28.14,48.27 ; H9.4 28.92,47.49 ; H9.4 28.14,46.7 ; 183,129.58 MEMCD1.14 ; MEMCD1.14 183,131.4 ; MEMCD1.14 181.68,130.49 ; 52.39,29.36 DCIN1.7 52.39,29.9 ; DCIN1.6 49.88,25.74 ; DCIN1.6 48.79,24.18 ; DCIN1.6 50.97,24.18 ; DCIN1.6 49.88,22.62 ; v3(163.94,72.9) 163.94,73.08 165.25,74.4 v3(165.34,74.4) ; 168.67,18.34 H10.4 168.49,18.94 ; 176.12,122.17 SSUSB1.11 ; SSUSB1.11 177.99,123.24 ; SSUSB1.11 176.12,124.31 ; SSUSB1.11 174.25,123.24 ; ODD1.7 9.03,180.81 ; ODD1.7 7.27,180.81 ; ODD1.7 8.15,181.69 ; 2.67,157.33 H7.2 ; H7.2 3.46,156.54 ; H7.2 4.25,157.33 ; 175.78,66.58 H11.5 175.96,65.97 ; 163.34,16.33 H10.2 162.73,16.51 ; H7.1 2.33,159.25 ; H7.1 2.33,157.67 ; H7.1 1.54,158.46 ; 175.96,62.89 H11.4 175.78,63.5 ; 176.12,109.37 SSUSB1.10 ; SSUSB1.10 176.12,111.51 ; SSUSB1.10 177.99,110.44 ; SSUSB1.10 174.25,110.44 ; 27.71,46.27 H9.3 26.92,45.48 ; H7.8 2.33,162.33 ; H7.8 2.33,160.75 ; H7.8 1.54,161.54 ; H7.7 4.25,162.67 ; H7.7 2.67,162.67 ; H7.7 3.46,163.46 ; 162.12,222.29 H6.7 161.33,223.08 ; 165.88,221.86 H6.1 ; H6.1 166.66,221.08 ; H6.1 167.45,221.86 ; 21.08,50.81 H9.8 ; H9.8 21.86,51.6 ; H9.8 21.86,50.03 ; SATAP1.4 13.07,192.5 ; SATAP1.4 10.93,192.5 ; SATAP1.4 12,193.57 ; SATAP1.4 12,191.43 ; H9.5 28.92,50.81 ; H9.5 28.14,51.6 ; H9.5 28.14,50.03 ; 163.34,221.08 H6.8 ; H6.8 162.55,221.86 ; H6.8 164.12,221.86 ; SATAP1.2 12,198.57 ; SATAP1.2 10.93,197.5 ; SATAP1.2 13.07,197.5 ; SATAP1.2 12,196.43 ; 7.27,177 ODD1.4 9.03,177 ; 168.67,21.66 H10.5 168.49,22.27 ; 166.06,16.51 H10.3 166.66,16.33 ; H9.1 21.86,48.27 ; H9.1 21.86,46.7 ; H9.1 21.08,47.49 ; 26.92,52.82 H9.6 27.71,52.03 ; H6.4 167.45,228.14 ; H6.4 165.88,228.14 ; H6.4 166.66,228.92 ; MEMCD1.15 183,160 ; MEMCD1.15 183,158.17 ; MEMCD1.15 181.68,159.09 ; 170.96,60.97 H11.2 170.35,61.15 ; 23.08,45.48 H9.2 22.29,46.27 ; 161.33,226.92 H6.6 162.12,227.71 ; 167.88,222.29 H6.2 168.67,223.08 ; 22.29,52.03 H9.7 23.08,52.82 ; 51.69,23.03 DCIN1.2 51.69,21.94
  BOTTOM w0.127: v4(59.52,95.79) 59.53,95.79 59.54,95.79 60,95.32 60,94.53 59.58,94.11 59.13,94.11 MEM2.M1
  BOTTOM w0.203: PU5407.20 78.77,211.93 v3(78.97,211.73) 79.17,211.93 PU5407.19 ; PU5407.17 v3(79.97,211.73) ; PU4601.32 30.79,215.68 v3(30.39,216.08) ; U4101.53 105.45,55.88 105.21,55.65 v3(105.21,55.42) ; v3(33.63,94.51) 33.75,94.39 34.16,94.39 34.24,94.3 U26.6 ; v3(95.66,52.76) 96.22,52.76 96.55,53.08 U4101.21 ; MEM2.B9 52.81,86.03 53.12,86.03 53.13,86.01 53.6,86.01 MEM4.B3 ; MEM4.A9 59.95,85.62 60.18,85.85 60.61,85.85 v3(61.48,86.72) ; R79705.2 104.07,60.54 U4101.45 v3(104.07,56.39) ; PU5407.23 77.57,211.93 v3(77.37,211.73) 77.17,211.93 PU5407.24 ; v3(102.4,51.54) 102.18,51.54 101.67,51.03 U4101.10 ; v3(80.77,211.73) PU5407.15 ; PU5407.32 76.21,215.37 76.61,215.77 v3(77.15,215.77)
  BOTTOM w0.305: MEM2.M9 51.93,94.42 v4(51.82,94.53) ; v4(56.67,117.73) 56.67,117.46 57.21,116.91 MEM3.B3 ; U55.14 60.24,53.6 v3(60.13,53.49) ; v4(51.86,108.84) 51.89,108.88 MEM1.M1 ; v4(51.92,107.65) 52.29,107.28 MEM1.P1 ; v4(51.92,90.04) 51.97,90.04 52.36,90.42 MEM2.G9 ; C776.2 62.07,97.67 62.07,98.45 61.65,98.88 60.81,98.88 59.56,97.62 MEM2.T1 58.79,97.62 58.41,97.24 v4(58.4,97.24) ; v4(52.01,86) 52.01,86.02 MEM2.B9 ; v4(58.41,90.02) 58.81,89.62 MEM4.F9 ; v4(58.41,90.02) 58.01,90.41 MEM4.G8 ; v4(58.41,90.02) MEM2.G1 ; MEM2.P9 52.41,96.01 v4(52.81,95.62) ; MEM1.E8 58.12,114.38 58.71,114.38 MEM3.E1 ; U120.20 38.44,38.53 v3(39.1,39.19) ; v4(59.52,95.79) 59.29,96.02 MEM2.P1 ; v4(51.42,112.9) 51.72,112.9 51.73,112.88 MEM1.G1 MEM3.G8 ; MEM2.E8 53.24,88.82 v4(53.63,88.42) ; MEM4.D8 58.02,88.02 v4(58.41,88.41) 58.01,88.81 MEM2.E2 ; v4(51.48,114.44) 51.74,114.17 51.98,114.17 52.3,113.85 52.3,113.79 MEM3.F9 MEM1.E2 53.1,114.59 53.1,115.11 53.21,115.23 MEM3.D8 ; v4(57.62,91.62) 58.01,92.02 MEM2.J2 ; v4(51.94,105.94) 52.2,105.68 MEM1.T1 ; MEM1.G9 59.33,112.88 v4(59.39,112.82) ; MEM4.E1 52.36,88.82 52.01,88.47 v4(51.86,88.47) 52.3,88.02 MEM4.D1
  BOTTOM w0.356: MEM3.A9 52.04,117.68 51.94,117.78 v4(51.86,117.78) ; MEM3.D1 59.05,115.05 59.15,115.05 v4(59.5,114.69) 59.3,114.48 MEM3.E1 ; MEM1.B1 52.4,116.88 52.3,116.98 52,116.98 v4(51.9,117.08) ; MEM1.P9 58.42,107.68 v4(58.4,107.68) ; v4(59.48,108.87) 59.46,108.88 MEM1.M9 ; 39.15,76.38 39.65,75.88 Q12.4 ; v4(52.46,98.42) 52.41,98.37 MEM2.T9 ; v4(58.43,106.09) 58.43,106.06 MEM1.T9 58.82,105.68 58.84,105.66 58.9,105.66 59,105.56 59.01,105.56 59.42,105.16 59.42,105.08 60.13,104.37 60.13,103.67 C777.2 ; v4(59.6,116.79) 59.51,116.88 MEM1.B9 ; v4(59.81,86.58) 59.7,86.47 58.87,86.47 MEM2.B1 ; v4(52.81,111.69) 53.21,111.28 MEM1.J2 ; MEM2.J8 53.21,92.02 v4(53.61,92.42) ; v4(57.61,110.88) MEM1.J8
  BOTTOM w0.406: Q13.4 47.2,76.81 v3(47.84,77.44) ; Q13.1 44.41,75.24 v3(43.03,73.86) ; v3(45.47,79.35) 45.39,79.27 42.65,79.27 42.02,78.64 42.02,77.52 42.36,77.18 Q12.1 ; PQ4406.4 74.09,55.81 73.82,56.08 73.03,56.08 72.79,56.33 PQ4406.1 v3(71.23,57.07) ; v3(152.52,48.18) 153,48.18 153.26,47.93 Q1226.1 153.31,47.62 153.31,46.96 153.56,46.71 154.17,46.71 154.56,46.32 Q1226.4
  BOTTOM w0.508: 48.79,24.18 DCIN1.6 ; DCIN1.6 49.88,25.74 ; DCIN1.6 50.97,24.18 ; DCIN1.6 49.88,22.62 ; USB3.4 102.09,33.53 ; USB3.4 101.06,32.5 ; USB3.4 100.03,33.53 ; USB3.4 101.06,34.56 ; PC5427.2 v3(156.65,208.79) ; Q104.S 93.73,18.64 94.34,19.25 v3(94.34,20.04) ; HDMI1.20 111.46,39.85 ; HDMI1.20 110.34,37.03 ; HDMI1.20 112.58,37.03 ; HDMI1.20 111.46,34.21 ; C1707.2 90.58,152.91 90.08,153.42 v4(89.72,153.42) 88.93,152.63 C1695.2 C1704.2 ; C1951.2 85.08,174.88 v4(84.2,174) 84.04,173.84 C1945.2 C1937.2 84.04,171.76 v4(84.2,171.6) 85.12,170.68 C1936.2 85.12,170.12 v4(84.2,169.2) ; v3(30.18,99.64) 30.31,99.77 31.06,99.77 R507.1 R511.2 ; 148.75,150.11 149.07,150.43 ; 148.75,150.11 v3(148.75,149.61) ; 148.75,150.11 148.43,150.43 R122.2 C1746.1 C65.1 ; 149.07,150.43 149.07,151.83 149.39,152.15 ; 149.07,150.43 R2060.2 ; PC5237.2 v3(58.86,50.67) ; v5(109.61,60.33) 108.87,60.33 108.62,60.58 R79720.2 ; R1182.1 85.76,41.27 v3(85.63,41.15) ; R501.2 36.23,104.57 37.17,103.63 C291.2 ; C1977.2 138.72,125.48 v3(138.5,125.26) 138.17,125.26 C1971.2 ; C1680.2 90.52,168.08 C1689.2 90.52,167.32 C1681.2 ; C1680.2 89.19,168.91 v4(88.95,169.15) ; C1680.2 90.52,169.74 C356.2 C1694.2 ; 100.03,10.53 USB4.4 ; USB4.4 102.09,10.53 ; USB4.4 101.06,9.5 ; 12,134.31 HDD1.8 ; HDD1.8 12,136.95 ; HDD1.8 13.32,135.63 ; HDD1.8 10.68,135.63 ; PU5.2 v3(153.6,204.34) ; v3(86.65,93.52) 86.46,93.71 PC73.2 ; v4(88.95,164.35) 89.22,164.08 C1678.2 ; v4(92,100.18) 91.88,100.06 C784.2 ; R1923.1 47.69,93.82 v3(47.17,94.34) 47.59,94.76 C1869.2 ; C1797.2 142.15,78.49 v3(142.02,78.36) 141.45,77.79 PR5009.2 ; 183,129.58 MEMCD1.14 ; MEMCD1.14 181.68,130.49 ; MEMCD1.14 183,131.4 ; 8.15,181.69 ODD1.7 8.53,181.68 ; v4(77.22,163.3) 77.05,163.12 77.05,162.06 76.3,161.3 C330.2 ; v3(31.11,22.72) 31.1,22.73 30.81,22.73 30.48,23.06 Q38.E ; v3(54.29,52.68) 54.31,52.65 55.39,52.65 PC5233.1 ; C1828.2 75.87,154.35 75.07,154.35 74.52,154.9 v4(74.52,154.96) ; v3(30.23,81.28) C298.2 C293.2 ; R79678.1 R79680.1 R79679.1 70.45,153.67 R1648.2 71.34,154.36 v4(71.9,153.8) ; v4(85.4,149.91) 85.29,149.8 C1697.2 ; R79654.2 79.22,149.68 v4(79,149.9) ; C290.1 C284.2 35.25,102.02 36.17,102.95 36.96,102.95 C291.2 ; C812.2 79.6,103.52 C768.2 ; PR4919.2 v3(105.19,12.06) ; PR4433.2 PR4451.2 v3(76.92,59.82) ; C768.2 80.36,103.38 C798.2 81.08,103.19 81.08,103.07 81.1,103.05 v4(81.1,102.65) ; C768.2 C765.2 C766.2 ; USB4.6 98.35,9.17 ; USB4.6 100.07,7.46 ; USB4.6 98.35,5.74 ; USB4.6 96.64,7.46 ; v4(85.97,95.99) 85.4,95.99 C818.2 C819.2 ; v4(96.03,152.28) 95.97,152.34 C1708.2 ; 174.25,123.24 SSUSB1.11 ; SSUSB1.11 176.12,124.31 ; SSUSB1.11 176.12,122.17 ; SSUSB1.11 177.99,123.24 ; v3(95.66,52.76) 95.55,52.64 C4101.1 ; R394.2 C1847.2 ; C1847.2 94.05,101.16 94.27,101.38 95.64,101.38 v4(96.2,100.82) ; C1847.2 93.89,100.52 C759.2 C758.2 ; C1652.2 79.79,167.19 v4(79.4,166.8) 79.85,166.35 C1664.2 79.85,164.85 v4(79.4,164.4) 79.85,163.95 C1660.2 79.85,162.45 v4(79.4,162) 79.79,161.61 C1644.2 79.79,160.12 v4(79.4,159.73) 78.96,159.29 C326.2 78.27,158.31 C1656.2 ; v5(82.74,1.14) 82.71,1.17 ; v3(41.44,40.74) 41.69,41 C35.2 ; v3(38.44,77.77) 38.44,77.8 38.64,78 U25.2 ; v3(38.44,77.77) 39.25,77.77 39.91,78.44 U25.1 ; v3(38.44,77.77) 36.53,77.77 36.1,78.21 U25.4 ; v3(38.44,77.77) 38.41,77.75 C1877.2 38.63,76.38 39.15,76.38 ; C20.2 33.92,111.84 34.83,110.92 v3(34.86,110.92) 34.7,110.77 R19.2 C14.1 ; C1682.2 89.19,159.38 v4(88.93,159.64) ; C1682.2 90.65,160.21 C1692.2 90.65,160.85 C1679.2 ; C1682.2 90.65,158.56 C1693.2 ; v3(67.04,51.75) 67,51.79 65.86,51.79 PR5274.1 ; HDMI1.22 116.68,29.78 ; HDMI1.22 113.99,28.66 ; HDMI1.22 111.3,29.78 ; C1953.2 79.18,152.5 v4(80,152.5) ; v3(99.96,64.64) PC5204.2 PR5209.2 ; v3(91.3,11.81) 92.03,11.81 92.74,12.52 92.74,14.29 C866.2 ; v4(79.4,169.2) 79.79,169.59 C1934.2 79.79,171.21 v4(79.4,171.6) 79.34,171.66 C1943.2 C1952.2 79.34,173.94 v4(79.4,174) 79.79,174.39 C1947.2 ; C806.2 79.15,98.24 C807.2 79.34,98.04 C774.2 79.34,96.13 v4(79.28,96.06) ; C1826.1 157.64,46.35 157.11,46.89 v3(157.11,47.58) ; v3(32.9,118.26) 33.08,118.08 Q10.E ; C6715.2 C1956.2 v3(161.53,216.15) ; 15.18,214.81 FANC3.1 12.82,214.81 ; v3(30.23,87.12) R512.2 C9.2 ; 140.64,214 HS6.1 ; HS6.1 147.86,214 ; HS6.1 144.25,210.39 ; C1714.2 88.68,154.38 v4(88.4,154.1) ; v4(96.5,155.4) 96.2,155.7 C1684.2 94.86,155.4 v4(94.13,155.4) 93.55,155.4 C1685.2 93.2,155.7 v4(92.3,154.8) 92.3,154.87 C1683.2 91.35,155.57 v4(91.35,154.81) ; v3(162.59,77.34) 162.85,77.09 R301.1 ; MEMCD1.13 172.42,159.09 ; MEMCD1.13 171.1,158.17 ; MEMCD1.13 171.1,160 ; MEMCD1.13 169.78,159.09 ; C1678.2 90.65,164.91 C1690.2 90.41,165.47 90.41,165.68 89.7,166.39 C1681.2 ; C1678.2 89.82,163.85 90.41,163.27 90.41,163.06 C1691.2 90.65,162.5 C1679.2 ; v3(28.38,28.12) 28.35,28.12 28.28,28.19 C1760.2 ; v4(71.77,162.05) 72.23,161.59 C1696.2 ; v4(88.95,166.75) 89.2,166.5 C1681.2 ; 7.08,183.37 ODD1.9 ; ODD1.9 8.4,184.69 ; ODD1.9 8.4,182.05 ; C1976.2 142.4,126.17 v3(142.4,127.25) ; v4(84.8,153.3) 84.67,153.17 C1741.2 ; R963.2 82.52,83.57 R1897.2 82.61,82.76 v4(82.56,82.71) ; PC4918.2 v3(105.16,10.03) ; C291.2 38.31,104.29 v3(38.87,104.29) 39.25,104.29 39.45,104.09 C283.2 40.23,102.22 C289.2 ; v3(38.03,83.06) 38.64,83.67 U25.7 38.64,85.34 39,85.7 C1827.2 ; C778.2 65.52,103.48 65.52,103.73 ; SSUSB2.11 176.12,102.81 ; SSUSB2.11 176.12,100.67 ; SSUSB2.11 177.99,101.74 ; PR4413.1 73.57,51.41 73.01,50.85 v3(71.74,50.85) ; SSUSB1.10 177.99,110.44 ; SSUSB1.10 176.12,111.51 ; SSUSB1.10 174.25,110.44 ; SSUSB1.10 176.12,109.37 ; C1674.2 84.87,155.33 v4(84.23,155.97) 83.79,156.41 C1669.2 ; v4(77.39,92) 77.25,91.86 C769.2 ; PR4605.1 PC4607.1 v3(26.83,225.32) ; C395.2 86.72,153.9 87.33,153.29 ; 96.64,43.6 USB3.5 ; USB3.5 98.35,45.31 ; USB3.5 100.07,43.6 ; USB3.5 98.35,41.88 ; 174.25,88.94 SSUSB2.10 ; SSUSB2.10 176.12,90.01 ; SSUSB2.10 177.99,88.94 ; SSUSB2.10 176.12,87.87 ; 7.08,170.63 ODD1.8 ; ODD1.8 8.4,171.95 ; ODD1.8 8.4,169.31 ; C1732.2 148.02,128.59 v3(148.01,128.6) 148.01,128.6 147.44,129.16 R2056.2 C1975.2 146.91,127.76 R2062.2 ; MEMCD1.15 183,160 ; MEMCD1.15 181.68,159.09 ; MEMCD1.15 183,158.17 ; C781.2 C779.2 87.29,101.71 C821.2 86.61,101.95 v4(85.91,102.65) ; Q57.3 164.31,76.83 164.31,77.41 v3(163.48,78.23) ; 10.68,148.37 HDD1.9 ; HDD1.9 12,147.05 ; HDD1.9 12,149.69 ; USB3.6 100.07,30.46 ; USB3.6 98.35,28.74 ; USB3.6 96.64,30.46 ; USB3.6 98.35,32.17 ; v3(71.28,195.83) 72.3,194.82 PR5416.1 ; C6.2 40.61,110.74 C2.2 C3.2 42.63,110.74 42.93,110.44 v3(43.69,110.44) ; C1688.2 91.85,173.55 v4(92.3,174) 93,173.3 93,172.87 C1686.2 ; 51.69,24.12 DCIN1.2 51.69,23.03 ; v3(33.61,90.23) 33.27,89.88 C299.1 C295.2 ; TC1.2 v3(136.91,205.88) ; v4(88.93,161.93) 89.19,161.67 C1679.2 ; v4(82.35,87.79) 82.36,87.79 82.56,87.58 82.73,87.58 82.77,87.55 C762.2 ; C1705.2 92.77,152.27 v4(92.99,152.5) ; R1853.2 52.88,34.24 51.13,34.24 Q45.E 48.9,36.47 v3(48.9,36.65) ; C1733.1 77.72,149.58 v4(77.4,149.9) ; C1726.2 155.76,181.61 v3(156.01,181.36) ; Q51.S v3(17.28,224.12) ; R523.2 48.03,77.44 v3(47.84,77.44) ; R924.1 C559.2 65.17,104.08 65.52,103.73 ; U11.2 v3(49.59,11.94) ; v3(175.42,84.58) 174.91,84.07 R1193.1 ; R1210.1 C1846.2 92.44,96.32 v4(92,95.88) 91.42,95.88 C827.2 91.31,96.78 C829.2 ; v3(44.03,4.67) 44.03,5.32 C591.2 ; v4(81.11,100.92) 80.99,100.8 80.99,99.23 v4(81.13,99.09) ; R1988.1 72.49,210.34 Q1241.E 74.52,209.87 75.52,208.86 v3(75.52,208.36) 76.44,208.36 PC5421.2 ; PR4610.1 v3(31.91,225.27) ; R30.2 36.42,116.78 Q5.S 37,116.01 v3(36.29,115.31) 35.9,115.7 R33.2 ; 137.01,51.82 138.46,51.82 139.01,52.36 R709.2 ; 137.01,51.82 136.55,52.27 C3367.2 ; 137.01,51.82 135.62,50.42 135.62,50.22 v3(135.59,50.19) ; 108.75,23.46 TC7.2 ; TC7.2 109.8,24.51 ; TC7.2 108.75,25.57 ; TC7.2 107.69,24.51 ; v3(33.58,85.25) 33.67,85.25 34.07,85.65 C7.2 ; C767.2 73.88,99.42 v4(74.04,99.57) 74.29,99.82 C773.2 ; C1654.2 83.6,158.81 C1671.2 83.79,159.32 v4(84.2,159.73) 85.12,160.65 C1648.2 85.12,161.08 v4(84.2,162) 84.68,162.48 C1659.2 84.68,163.92 v4(84.2,164.4) 84.68,164.88 C1658.2 84.68,166.32 v4(84.2,166.8) 85.12,167.72 C1650.2 ; v4(90.99,91.98) 90.73,92.23 C830.2 ; v4(77.07,168.94) 76.84,169.16 C1646.2 ; C1940.2 C1942.2 88.23,173.23 v4(88.95,173.95) ; v3(63.7,34.32) D19.1 ; v3(117.89,69.22) 117.19,69.91 PR2.2 ; Q128.E v3(128.79,214.66) ; MEMCD1.12 171.1,131.4 ; MEMCD1.12 172.42,130.49 ; MEMCD1.12 171.1,129.58 ; R79677.2 151.42,45.09 151.8,45.47 151.8,47.98 152,48.18 v3(152.52,48.18) 152.52,48.28 152.51,48.29 152.51,48.88 C525.1 R656.2 ; v3(33.63,94.51) 33.49,94.51 33.09,94.11 R1079.2 ; R1635.2 134.46,126.24 134.59,126.37 134.64,126.4 135.4,127.16 v3(135.4,127.2) ; C1655.2 87.79,158.31 C1670.2 87.09,159.24 v4(86.6,159.73) 86.86,159.73 C1647.2 87.79,160.81 v4(86.6,162) 87.09,162.49 C1663.2 87.09,163.91 v4(86.6,164.4) 87.09,164.89 C1657.2 87.09,166.31 v4(86.6,166.8) 86.82,166.8 C1649.2 ; v3(129.69,42.83) 130.49,42.04 131.67,42.04 R2085.2 R2090.2 R2089.2 v3(133.75,42.78) ; v4(94.67,103.87) 94.51,104.03 C1849.1 R948.2 92.73,104.03 92.28,103.58 92.28,103.51 C780.2 ; R300.1 162.34,66.92 160.05,64.63 v3(160.05,62.99) ; 87.33,153.29 87.19,153.29 86.86,152.96 R79653.2 ; 87.33,153.29 v4(87.38,153.29) ; 52.39,29.9 DCIN1.7 52.39,28.81 ; UHS1.MS1 179.42,70.69 ; UHS1.MS1 178,69.67 ; UHS1.MS1 176.58,70.69 ; R1834.2 147.53,56.15 v3(147.53,55.32) 148.19,55.32 C190.2 148.81,55.63 C76.1 ; Q1212.S 29.97,13.66 v3(30.49,13.14) C1773.2 C1774.2 ; v3(162.62,79.07) 162.52,79.17 C478.2 C474.2 ; HDMI1.21 113.99,45.4 ; HDMI1.21 113.99,43.16 ; HDMI1.21 116.68,44.28 ; C1954.2 C1668.2 78.94,156.61 78.5,156.61 77.93,157.18 v4(77,157.18) ; 65.52,103.73 65.52,104.99 64.36,106.15 v4(63.48,106.15) ; v3(140.88,43.81) 140.62,43.56 140.62,41.91 v3(143.42,39.12) ; C1677.2 75.22,151.88 v4(75.3,151.8) 75.56,151.54 C1957.2 ; v3(35.09,112.65) 35.26,112.47 36.88,112.47 Q1.S ; PC5420.2 v3(87.31,214.38) ; v3(27.21,23.6) 26.93,23.88 Q68.S ; 7.77,172.32 ODD1.1 8.15,172.31 ; v3(93.93,172.69) 94.74,172.69 C1687.2 ; C1706.2 101.39,151.13 v4(101.15,150.89) ; v3(163.53,86.66) 163.84,86.66 164.37,87.2 D21.A ; C1930.2 86.66,208.72 Q1240.S 87.07,210.15 v3(86.72,210.49) ; C775.2 78.33,95.09 v4(78.27,95.15) ; C1821.2 144.03,58.97 v3(144.22,58.97) 144.23,58.98 144.23,59.68 C1820.1 ; PC4917.2 105.76,13.84 105.17,13.84 v3(105.08,13.75) ; C3381.1 v3(135.79,42.79) ; v3(43.47,117.73) 43.47,119.38 43.05,119.79 Q9650.S ; C296.2 31.15,101.17 v3(30.09,101.17) ; PR4635.2 PR4603.2 24.67,208.15 v3(24.29,207.77) ; C1667.2 81.19,156.59 v4(80.6,156) 80.9,155.7 C1666.2 80.87,155.19 C1716.2 ; C1665.2 87.09,156.4 v4(86.65,155.96) ; C6712.2 159.99,208.79 C6714.2 v3(158.33,208.79) ; C292.2 v3(30.21,79.83) ; v4(94.1,169.8) 94.1,169.14 C1608.2 C1609.1 R115.2 ; PQ4206.S v3(66.23,38.33) ; C1715.2 82.08,149.66 v4(81.97,149.76) ; PR4924.2 v3(105.19,11.05) ; C1653.2 82.46,158.81 C1672.2 82.27,159.26 v4(81.8,159.73) 82.46,160.38 C1645.2 82.46,161.34 v4(81.8,162) 82.27,162.47 C1661.2 82.27,163.93 v4(81.8,164.4) 82.27,164.87 C1662.2 82.27,166.33 v4(81.8,166.8) 82.46,167.46 C1651.2 ; v4(76.4,178.2) 76.49,178.11 C1950.2 ; v3(152.95,74.93) 154.59,74.93 155.11,74.41 C509.2 156.53,74.09 C516.2 ; v3(50.35,208.28) PR5423.1 ; PR4925.2 105.19,13.08 v3(104.94,12.83) ; C1703.2 78.21,154.17 78.21,152.35 77.65,151.79 v4(77.6,151.79) ; C1948.2 82.46,174.66 v4(81.8,174) 81.63,173.83 C1946.2 C1941.2 81.63,171.77 v4(81.8,171.6) 82.46,170.94 C1935.2 82.46,169.86 v4(81.8,169.2) ; R80218.2 158.72,42.53 C1824.2 159.85,42.54 v3(160.95,42.54) ; C1949.2 86.91,174 v4(86.6,174) 86.2,173.6 C1944.2 C1939.2 86.2,172 v4(86.6,171.6) 87.79,170.41 C1938.2 87.71,170.31 v4(86.6,169.2) ; v3(163.94,72.9) 164.04,72.9 165.18,71.75 Q24.3 ; Q9648.S 84.84,58.74 C6724.1 81.57,60.77 v3(81.57,62.48) ; PR5411.1 PC5424.2 v3(82.71,208.25) ; PQ4204.E v3(70.39,36.31) ; v3(111.98,91.01) 111.67,91.33 C6723.2 ; v3(31.15,25.53) 31.15,26.19 31.4,26.45 Q1213.E ; PC5202.2 v3(107.98,67.77) ; Q102.E v3(48.45,7.94) ; C770.2 74.67,102.11 v4(75.09,102.53) ; 100.07,20.6 USB4.5 98.35,22.31 ; C11.2 v3(30.23,83.06) ; v3(152.31,129.03) 152.18,128.91 C1724.2 ; R1205.2 82.99,89.45 82.29,90.15 v4(82.29,91.16) ; PC5428.2 v3(156.65,213.11) ; Q52.E v3(15.68,224.12) ; C863.2 v3(39.66,4.67) ; C297.2 37.57,88.46 37.57,87.83 v3(37.47,87.73)
  vias: v1(15.81,182.3) v1(23.3,223.11) v1(25.26,138.91) v1(26.32,154.89) v1(27.97,197.99) v1(28.48,147.83) v1(29.24,219.33) v1(32.04,52.96) v1(39.53,198.75) v1(45.27,85.72) v1(46.46,117.6) v1(58.96,220.98) v1(80.63,214.63) v1(89.82,114.78) v1(96.17,198.37) v1(100.11,133.43) v1(130.51,216.18) v1(144.43,88.27) v1(150.86,205.56) v1(158.91,187.71) v1(161.7,149.22) v2(17.94,203.38) v2(36.69,57.18) v2(46.18,114.3) v2(50.63,217.91) v2(71.51,114.86) v2(94.19,39.55) v2(113.29,214.1) v2(117.74,182.52) v2(119.69,91.36) v2(120.25,19.81) v2(120.38,38.99) v2(127.13,133.22) v2(142.43,90.83) v2(143.04,205.36) v2(149,197.23) v2(149.46,20.4) v2(156.98,135.15) v2(170.04,136.96) v2(177.1,84.53) v3(3.42,200.53) v3(3.94,198.88) v3(3.94,197.61) v3(7.06,215.09) v3(12.11,174.23) v3(12.11,172.61) v3(12.11,170.98) v3(18.7,157.73) v3(18.7,156.84) v3(18.7,155.96) v3(19.34,149.28) v3(19.68,151.24) v3(20.68,172.24) v3(22.21,172.24) v3(23.56,29.45) v3(23.56,17.85) v3(23.73,172.24) v3(23.87,42.25) v3(23.87,31.05) v3(24.14,39.62) v3(24.14,37.34) v3(24.29,150.79) v3(26.2,149.3) v3(27.47,156.72) v3(27.47,155.83) v3(28.37,141.14) v3(28.66,217.81) v3(29.12,44.58) v3(29.52,217.81) v3(30.39,219.53) v3(30.39,218.67) v3(30.39,217.81) v3(30.39,216.94) v3(31.25,217.81) v3(31.28,140.84) v3(31.38,134.85) v3(32.11,217.81) v3(32.8,37.97) v3(33.94,15.88) v3(34.17,37.95) v3(35.61,23.03) v3(36.12,25.68) v3(36.46,63.37) v3(36.46,62.36) v3(36.51,61.34) v3(36.46,60.33) v3(36.46,59.31) v3(36.56,66.29) v3(37.07,14.86) v3(37.6,24.31) v3(37.78,96.23) v3(37.78,95.36) v3(37.78,94.5) v3(37.78,93.64) v3(37.78,92.77) v3(37.88,15.67) v3(37.88,14.86) v3(37.88,14.05) v3(38.71,26.43) v3(38.69,14.86) v3(39.87,26.5) v3(44.62,160.04) v3(45.88,81.15) v3(47.12,116.34) v3(47.12,115.57) v3(47.12,98.65) v3(47.12,89.89) v3(47.12,89.05) v3(47.12,88.27) v3(47.12,87.12) v3(47.17,109.83) v3(47.17,97.64) v3(47.28,124.03) v3(47.28,123.22) v3(47.31,106.8) v3(47.3,105.63) v3(47.3,104.62) v3(47.3,103.52) v3(47.27,102.46) v3(47.4,118.75) v3(47.53,24.13) v3(48.42,26.8) v3(49.82,19.08) v3(49.94,34.04) v3(50.45,21.59) v3(51.26,205.76) v3(51.29,204.72) v3(51.72,23.75) v3(52.03,43.1) v3(52.03,42.24) v3(52.1,45.09) v3(52.23,205.74) v3(52.23,204.72) v3(53.5,125.48) v3(56.43,124.84) v3(59.95,56.26) v3(60.71,57.02) v3(60.74,56.26) v3(60.74,55.47) v3(61.5,56.29) v3(63.89,125.98) v3(65.8,23.08) v3(66.62,23.08) v3(66.85,26.45) v3(66.84,21.97) v3(66.84,21.21) v3(66.84,20.45) v3(67.09,28.78) v3(67.43,23.08) v3(67.61,26.45) v3(73.82,78.61) v3(74.58,78.61) v3(74.89,21.93) v3(75.47,78.61) v3(75.9,21.93) v3(76.36,78.61) v3(76.92,21.93) v3(77.12,78.61) v3(77.94,21.93) v3(77.96,215.77) v3(78.77,217.4) v3(78.77,216.59) v3(78.77,215.77) v3(78.77,214.96) v3(78.77,214.15) v3(78.95,21.93) v3(79.59,215.77) v3(80.4,215.77) v3(89.36,11.81) v3(99,144.63) v3(102.14,213.61) v3(102.27,215.65) v3(102.27,211.58) v3(103.28,79.12) v3(103.92,205.61) v3(104.43,194.18) v3(104.68,79.12) v3(110.65,12.01) v3(113.83,192.79) v3(115.86,200.81) v3(120.47,191.7) v3(121.19,129.16) v3(122.77,201.55) v3(123.32,204.98) v3(123.4,11.1) v3(124.49,212.5) v3(127.24,201.55) v3(127.92,164.97) v3(128.05,157.86) v3(128.79,210.98) v3(128.94,154.05) v3(129.32,161.67) v3(129.32,159.38) v3(129.57,130.81) v3(129.57,127.38) v3(129.73,209.63) v3(131.61,193.17) v3(131.87,35.57) v3(132.9,136.65) v3(133.6,35.57) v3(135.03,182.5) v3(135.06,177.16) v3(135.16,148.01) v3(135.39,137.29) v3(135.54,187.45) v3(136.3,132.33) v3(136.3,130.84) v3(137.07,185.93) v3(137.07,183.77) v3(137.07,136.02) v3(137.7,193.29) v3(138.72,193.29) v3(139.61,193.29) v3(140.37,37.47) v3(140.37,35.56) v3(140.5,193.29) v3(140.83,132.11) v3(141.38,193.29) v3(141.4,143.07) v3(141.54,149.83) v3(141.64,187.57) v3(141.64,186.44) v3(141.64,180.98) v3(141.64,178.72) v3(141.64,145.61) v3(141.64,141.74) v3(141.64,133.86) v3(141.58,129.86) v3(141.74,172.38) v3(141.74,138.58) v3(141.77,189.61) v3(141.77,184.28) v3(141.77,174.73) v3(141.77,169.16) v3(141.77,136.02) v3(142.4,132.11) v3(142.53,171.28) v3(143.09,147.72) v3(143.23,182.5) v3(143.29,137.54) v3(143.46,177.15) v3(143.92,180.35) v3(143.94,140.74) v3(144.05,183.83) v3(144.03,146.33) v3(144,130.81) v3(144.05,189.61) v3(144.05,169.16) v3(144.05,135.36) v3(144.15,175.79) v3(144.23,173.58) v3(144.15,144.25) v3(144.15,139.42) v3(144.3,186.13) v3(144.25,178.28) v3(144.25,149) v3(144.43,193.29) v3(144.43,133.08) v3(144.61,147.73) v3(144.81,137.59) v3(144.86,171.32) v3(145.03,177.15) v3(145.45,193.29) v3(145.63,8) v3(145.63,6.07) v3(146.34,193.29) v3(147.23,193.29) v3(148.12,193.29) v3(148.12,147.45) v3(148.46,203.84) v3(148.75,181.1) v3(148.75,130.3) v3(148.88,143.76) v3(148.88,141.73) v3(149.13,205.74) v3(149.89,187.45) v3(150.34,177.11) v3(150.35,137.54) v3(150.58,213.82) v3(150.62,171.84) v3(150.79,142.49) v3(151.14,5.84) v3(152.18,187.45) v3(152.38,191.39) v3(153.58,16.13) v3(154.47,30.61) v3(155.35,31.5) v3(155.35,29.72) v3(156.01,184.66) v3(156.01,165.99) v3(156.01,164.08) v3(156.01,162.18) v3(156.01,159.38) v3(156.01,154.94) v3(156.24,30.61) v3(156.7,204.98) v3(157.51,205.79) v3(157.51,204.98) v3(157.51,204.17) v3(158.33,204.98) v3(161.58,102.87) v3(161.68,78.23) v3(161.93,106.6) v3(161.96,108.71) v3(162.59,78.23) v3(162.83,104.29) v3(164.12,204.98) v3(168.21,150.48) v3(168.21,149.72) v3(168.21,148.96) v3(172.12,127.03) v3(176.06,125.29) v3(176.06,107.31) v4(68.09,168.2) v4(68.3,151.4) v4(68.72,165.3) v4(70.16,115.04) v4(70.55,182.35) v4(73.28,115.09) v4(81.08,101.88) v4(81.14,97.27) v4(81.08,95.89) v4(82.08,96) v4(82.92,102.91) v4(82.87,100.91) v4(83.04,99.09) v4(87.74,96.09) v4(87.94,97.49) v4(88.55,146.05) v4(88.93,143.76) v4(89.17,184.91) v4(90.08,146.33) v4(90.24,186.06) v4(90.43,144.51) v4(90.59,113.27) v4(91.35,184.02) v4(91.83,108.02) v4(92.04,108.62) v4(92.2,113.29) v4(92.54,145.79) v4(92.69,185.75) v4(92.77,143.13) v4(93.32,147.26) v4(93.65,143.15) v4(94.02,184.9) v4(94.55,145.82) v4(94.62,183.75) v4(95.15,145.15) v4(95.54,185.67) v4(95.92,184.68) v4(96.01,182.37) v4(96.17,145.16) v4(96.38,146.22) v4(96.93,182.27) v4(97.2,149.71) v4(97.59,175.42) v4(97.88,178.98) v4(97.87,153.52) v4(97.88,147.14) v4(98.08,176.47) v4(98.44,155.17) v4(98.35,111.49) v4(98.97,151.26) v4(99.5,114.28) v4(99.5,113.64) v4(99.5,113.01) v4(99.98,174.5) v4(100.07,153.69) v4(100.5,177.55) v4(100.72,175.99) v4(100.92,151.9) v4(101,179.1) v4(101.07,154.3) v4(101.43,181.97) v4(101.4,174.5) v5(1.14,228.86) v5(1.14,223.78) v5(1.14,218.7) v5(1.14,213.62) v5(1.14,208.54) v5(1.14,203.46) v5(1.14,198.38) v5(1.14,193.3) v5(1.14,188.22) v5(1.14,183.14) v5(1.14,178.06) v5(1.14,172.98) v5(1.14,167.9) v5(1.33,153.97) v5(4.58,152.32) v5(5.14,148.38) v5(5.14,143.3) v5(5.14,138.22) v5(5.14,133.14) v5(6.22,228.86) v5(10.22,133.14) v5(11.3,228.86) v5(15.3,133.14) v5(16.38,228.86) v5(20.2,206.39) v5(20.2,205.47) v5(20.2,204.56) v5(20.2,203.64) v5(20.2,202.73) v5(20.38,133.14) v5(21.14,73.86) v5(21.14,67.18) v5(21.14,62.1) v5(21.14,57.02) v5(21.14,41.78) v5(21.14,36.7) v5(21.14,31.62) v5(21.14,26.54) v5(21.14,21.46) v5(21.14,16.38) v5(21.14,11.3) v5(21.14,6.22) v5(21.14,1.14) v5(21.46,228.86) v5(23.32,9.69) v5(24.93,153.67) v5(24.93,152.65) v5(24.93,151.64) v5(25.46,133.14) v5(25.94,153.67) v5(25.94,152.65) v5(25.94,151.64) v5(26.22,73.86) v5(26.45,196.57) v5(26.54,228.86) v5(26.86,1.14) v5(26.96,153.67) v5(26.96,152.65) v5(26.96,151.64) v5(28.23,157.1) v5(28.23,156.18) v5(28.86,154.94) v5(28.91,131.98) v5(28.99,197.49) v5(29.14,126.97) v5(29.14,121.89) v5(29.14,116.81) v5(29.14,111.73) v5(29.14,106.65) v5(29.14,101.57) v5(29.14,96.49) v5(29.14,91.41) v5(29.14,86.33) v5(29.14,81.25) v5(29.14,76.17) v5(29.9,197.42) v5(30.82,201.99) v5(30.82,201.08) v5(30.82,200.17) v5(30.82,199.25) v5(30.82,198.34) v5(30.82,197.42) v5(31.62,228.86) v5(31.73,201.99) v5(31.73,201.08) v5(31.73,200.17) v5(31.73,199.25) v5(31.73,198.34) v5(31.73,197.42) v5(31.94,1.14) v5(32.09,72.06) v5(32.29,164.34) v5(32.65,201.99) v5(32.65,201.08) v5(32.65,200.17) v5(32.65,199.25) v5(32.65,198.34) v5(32.65,197.42) v5(32.8,72.64) v5(33.31,164.34) v5(33.56,201.99) v5(33.56,201.08) v5(33.56,200.17) v5(33.56,199.25) v5(33.56,198.34) v5(33.56,197.42) v5(34.93,201.99) v5(34.93,201.08) v5(34.93,200.17) v5(34.93,199.25) v5(34.93,198.34) v5(34.93,197.42) v5(35.85,201.99) v5(35.85,201.08) v5(35.85,200.17) v5(35.85,199.25) v5(35.85,198.34) v5(35.85,197.42) v5(36.7,228.86) v5(36.76,202.1) v5(36.76,201.18) v5(36.76,200.27) v5(36.76,199.35) v5(36.76,198.44) v5(36.76,197.47) v5(37.02,1.14) v5(37.68,201.99) v5(37.68,201.08) v5(37.68,200.17) v5(37.68,199.25) v5(37.68,198.34) v5(37.68,197.42) v5(38.59,201.99) v5(38.59,201.08) v5(38.59,200.17) v5(38.59,199.25) v5(38.59,198.34) v5(38.59,197.42) v5(39.5,197.42) v5(40.42,214.02) v5(40.49,197.46) v5(41.41,214.05) v5(41.54,222.19) v5(41.54,221.27) v5(41.54,220.36) v5(41.54,219.45) v5(41.78,228.86) v5(42.1,1.14) v5(42.96,196.57) v5(43.16,55.88) v5(44.27,54.88) v5(45.19,54.88) v5(46.13,54.86) v5(46.86,228.86) v5(47.15,54.86) v5(47.18,1.14) v5(50.12,223.22) v5(50.12,222.3) v5(50.12,221.39) v5(50.12,220.47) v5(50.12,219.56) v5(50.43,225.04) v5(50.43,224.13) v5(51.04,223.22) v5(51.04,222.3) v5(51.04,221.39) v5(51.04,220.47) v5(51.04,219.56) v5(51.34,225.04) v5(51.34,224.13) v5(51.94,228.86) v5(51.95,223.22) v5(51.95,222.3) v5(51.95,221.39) v5(51.95,220.47) v5(51.95,219.56) v5(51.95,218.64) v5(51.95,217.73) v5(51.95,216.81) v5(51.95,215.9) v5(52.26,225.04) v5(52.26,224.13) v5(52.26,1.14) v5(52.87,223.22) v5(53.17,225.04) v5(53.17,224.13) v5(53.78,223.22) v5(54.08,225.04) v5(54.08,224.13) v5(54.69,223.22) v5(54.69,222.3) v5(55,225.04) v5(55,224.13) v5(55.91,225.04) v5(55.91,224.13) v5(56.83,225.04) v5(56.83,224.13) v5(57.02,228.86) v5(57.34,1.14) v5(57.74,225.04) v5(57.74,224.13) v5(58.66,225.04) v5(58.66,224.13) v5(59.57,225.04) v5(60.49,225.04) v5(61.4,225.04) v5(61.4,224.13) v5(62.1,228.86) v5(62.31,225.04) v5(62.31,224.13) v5(62.42,1.14) v5(63.23,225.04) v5(63.23,224.13) v5(64.14,225.04) v5(64.14,224.13) v5(65.06,225.04) v5(65.06,224.13) v5(67.18,228.86) v5(67.5,1.14) v5(72.26,228.86) v5(72.58,1.14) v5(77.34,228.86) v5(77.66,1.14) v5(82.42,228.86) v5(87.5,228.86) v5(87.82,1.14) v5(92.58,228.86) v5(92.9,1.14) v5(97.66,228.86) v5(97.98,1.14) v5(101.38,79.12) v5(102.4,79.12) v5(102.74,228.86) v5(103.06,1.14) v5(107.82,228.86) v5(108.14,1.14) v5(109.61,61.24) v5(110.52,61.24) v5(110.52,60.33) v5(112.9,228.86) v5(113.22,1.14) v5(113.95,91.69) v5(113.95,90.68) v5(113.95,89.66) v5(113.95,88.65) v5(113.95,87.63) v5(113.95,86.61) v5(114.97,91.69) v5(114.97,90.68) v5(114.97,89.66) v5(114.97,88.65) v5(114.97,87.63) v5(114.97,86.61) v5(116.11,91.69) v5(116.11,90.68) v5(116.11,89.66) v5(116.11,88.65) v5(116.11,87.63) v5(116.11,86.61) v5(117.13,91.69) v5(117.13,90.68) v5(117.13,89.66) v5(117.13,88.65) v5(117.13,87.63) v5(117.13,86.61) v5(117.98,228.86) v5(118.14,91.69) v5(118.14,90.68) v5(118.14,89.66) v5(118.14,88.65) v5(118.14,87.63) v5(118.14,86.61) v5(118.3,1.14) v5(119.92,17.91) v5(119.92,16.99) v5(119.92,16.08) v5(119.92,15.16) v5(120.45,12.8) v5(120.51,10.87) v5(120.58,11.81) v5(120.84,17.91) v5(120.84,16.99) v5(120.84,16.08) v5(120.84,15.16) v5(120.94,92.71) v5(121.04,10.03) v5(121.32,12.4) v5(121.42,11.25) v5(121.75,17.91) v5(121.75,16.99) v5(121.75,16.08) v5(121.75,15.16) v5(122.16,12.78) v5(122.16,11.81) v5(122.66,15.16) v5(123.06,228.86) v5(123.38,1.14) v5(125.76,85.6) v5(125.76,84.58) v5(125.76,83.57) v5(128.14,228.86) v5(128.46,1.14) v5(133.22,228.86) v5(133.22,223.78) v5(133.54,1.14) v5(134.56,16.6) v5(134.56,15.54) v5(134.56,14.48) v5(134.56,13.42) v5(134.56,12.35) v5(135.03,216.15) v5(135.62,16.6) v5(135.62,15.54) v5(135.62,14.48) v5(135.62,13.42) v5(135.62,12.35) v5(138.3,228.86) v5(138.3,223.78) v5(138.3,218.7) v5(138.62,1.14) v5(141.1,86.74) v5(141.49,89.6) v5(141.49,88.68) v5(141.49,87.77) v5(142.02,86.74) v5(142.41,89.6) v5(142.41,88.68) v5(142.41,87.77) v5(142.91,87) v5(143.38,228.86) v5(143.38,223.78) v5(143.38,218.7) v5(143.49,89.59) v5(143.49,88.67) v5(143.49,87.76) v5(143.7,1.14) v5(143.8,86.74) v5(148.46,228.86) v5(148.46,218.7) v5(148.78,1.14) v5(153.54,228.86) v5(153.54,223.78) v5(153.54,218.7) v5(153.86,11.3) v5(153.86,6.22) v5(153.86,1.14) v5(158.62,228.86) v5(158.62,218.7) v5(158.7,16.14) v5(164.5,216.28) v5(164.5,211.71) v5(168.86,218.7) v5(168.86,213.62) v5(168.86,208.54) v5(168.86,203.46) v5(168.86,198.38) v5(168.86,193.3) v5(168.86,188.22) v5(168.86,183.14) v5(168.86,178.06) v5(168.86,172.98) v5(168.86,167.9) v5(168.86,162.82) v5(168.86,56.78) v5(168.86,51.7) v5(168.86,46.62) v5(168.86,41.54) v5(168.86,36.46) v5(168.86,31.38) v5(168.86,26.3) v5(173.7,161.26) v5(173.7,156.18) v5(173.7,151.1) v5(173.7,146.02) v5(173.7,140.94) v5(173.7,135.86) v5(178.14,122.01) v5(178.14,116.93) v5(178.14,111.85) v5(178.27,100.68) v5(178.27,95.6) v5(178.27,90.52) v5(178.78,161.26) v5(178.78,156.18) v5(178.78,151.1) v5(178.78,146.02) v5(178.78,140.94) v5(178.78,135.86) v5(178.78,130.78) v5(178.78,125.7) v5(178.78,85.06) v5(178.78,68.04) v5(179.11,106.09) v5(183.58,123.44) v5(183.58,109.98) v5(183.58,102.36) v5(183.58,88.9) v5(183.86,161.26) v5(183.86,156.18) v5(183.86,151.1) v5(183.86,146.02) v5(183.86,140.94) v5(183.86,135.86) v5(183.86,125.7) v5(183.86,85.06) v5(183.86,69.82)
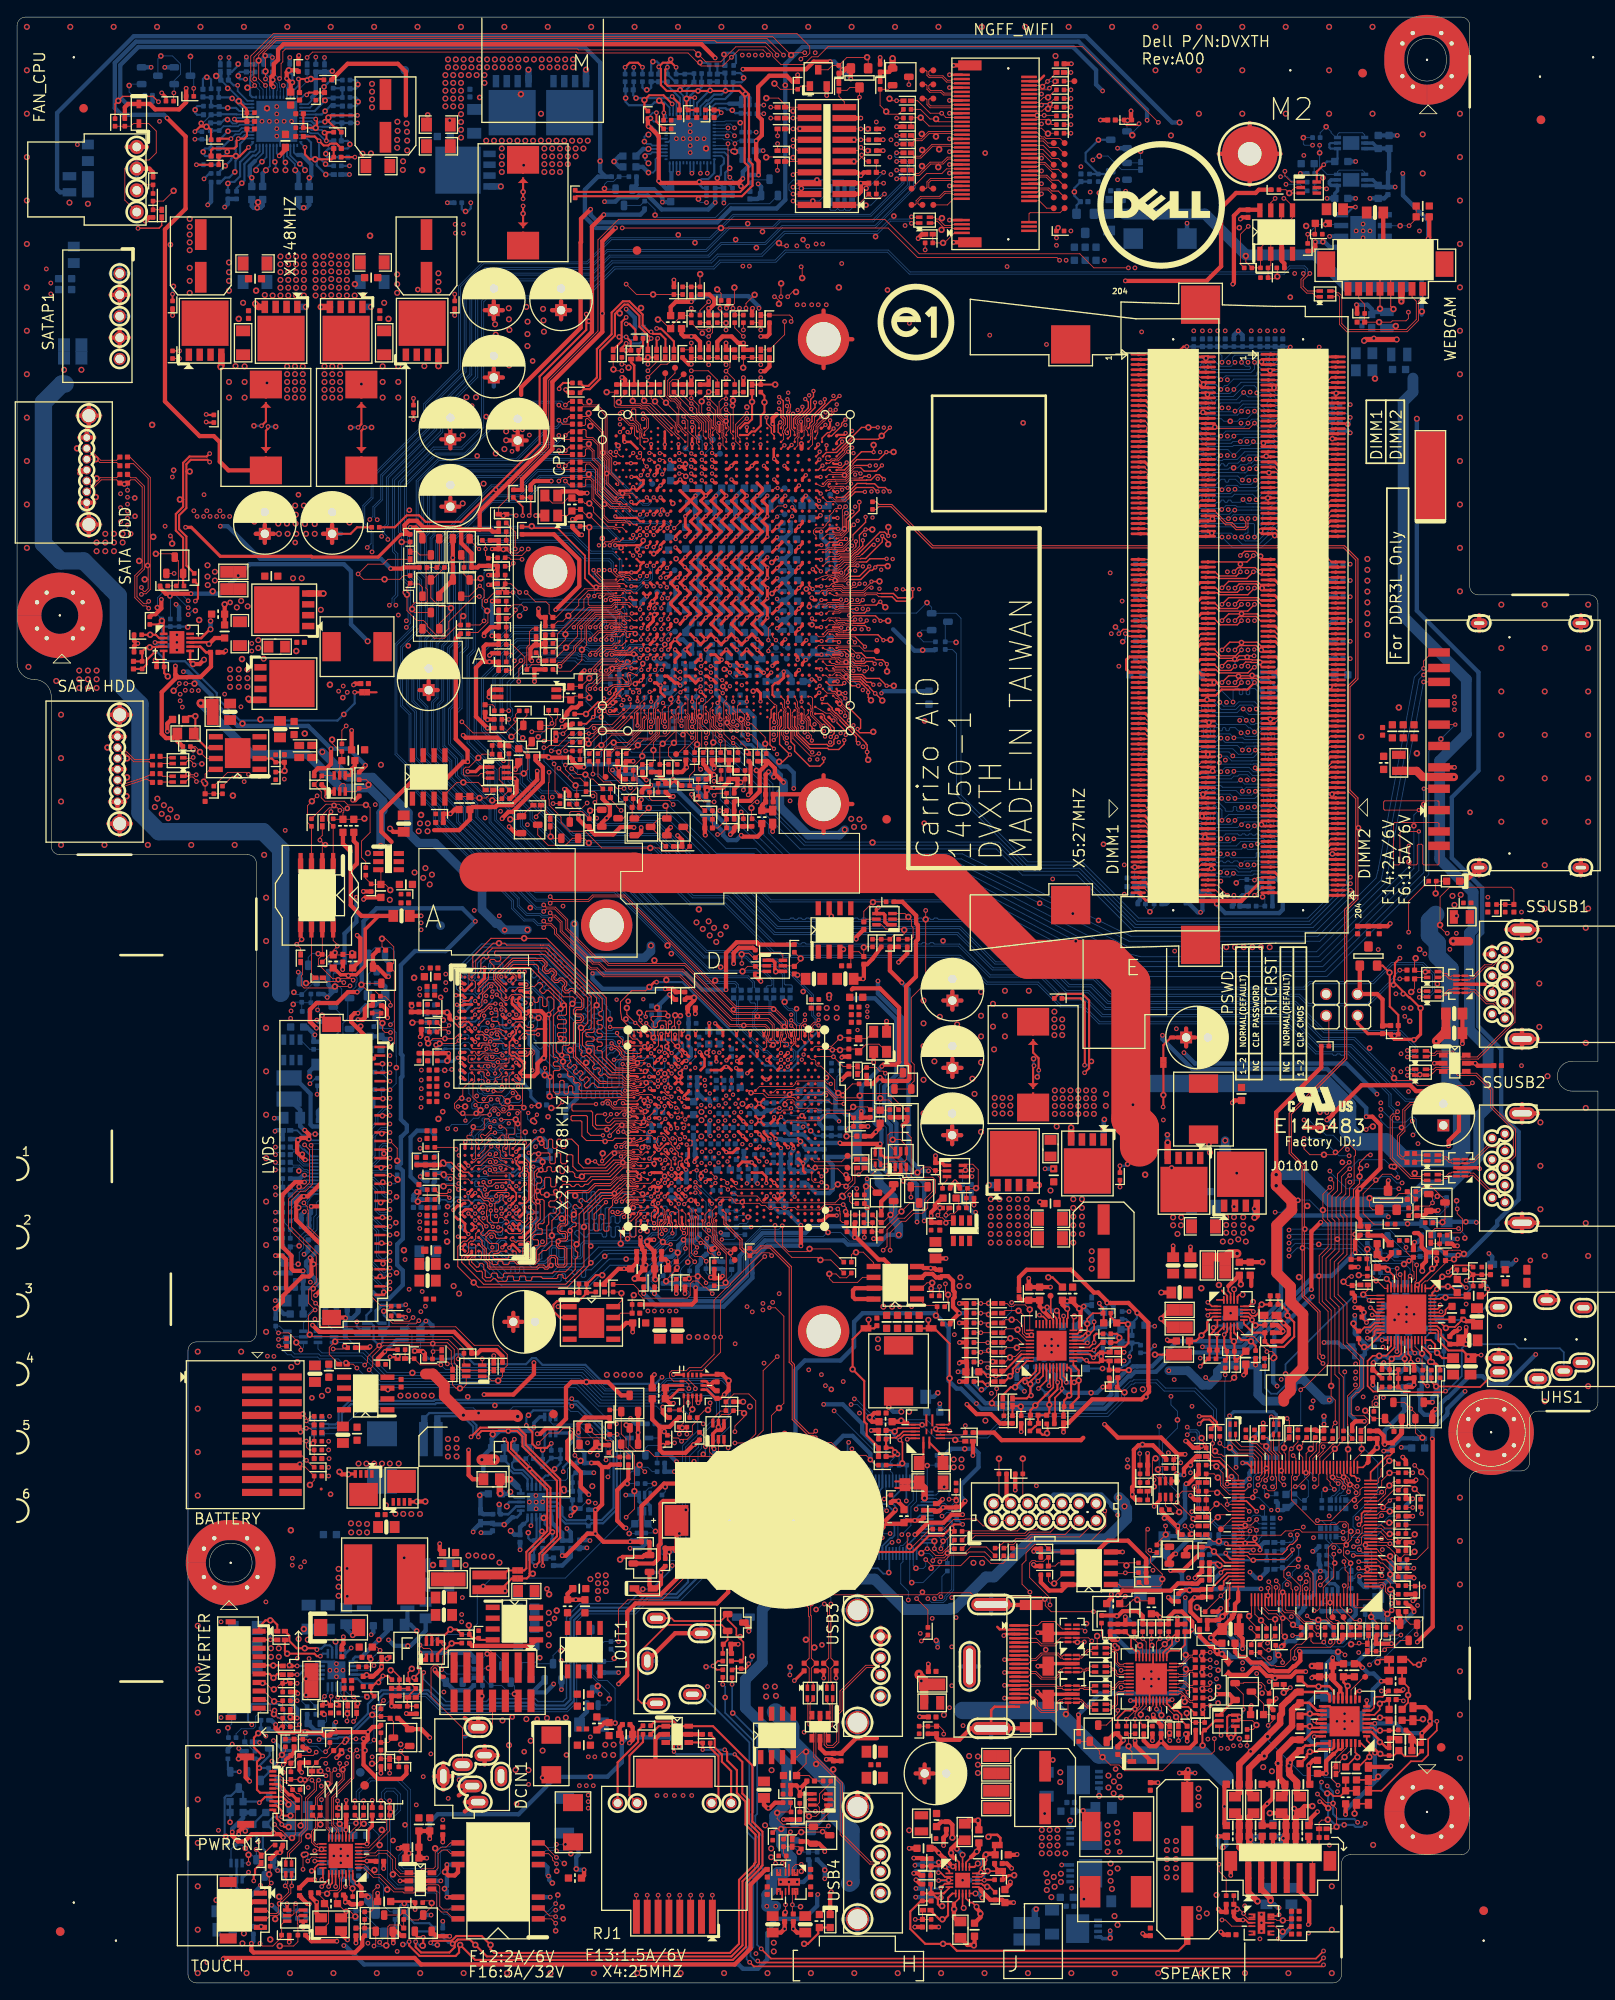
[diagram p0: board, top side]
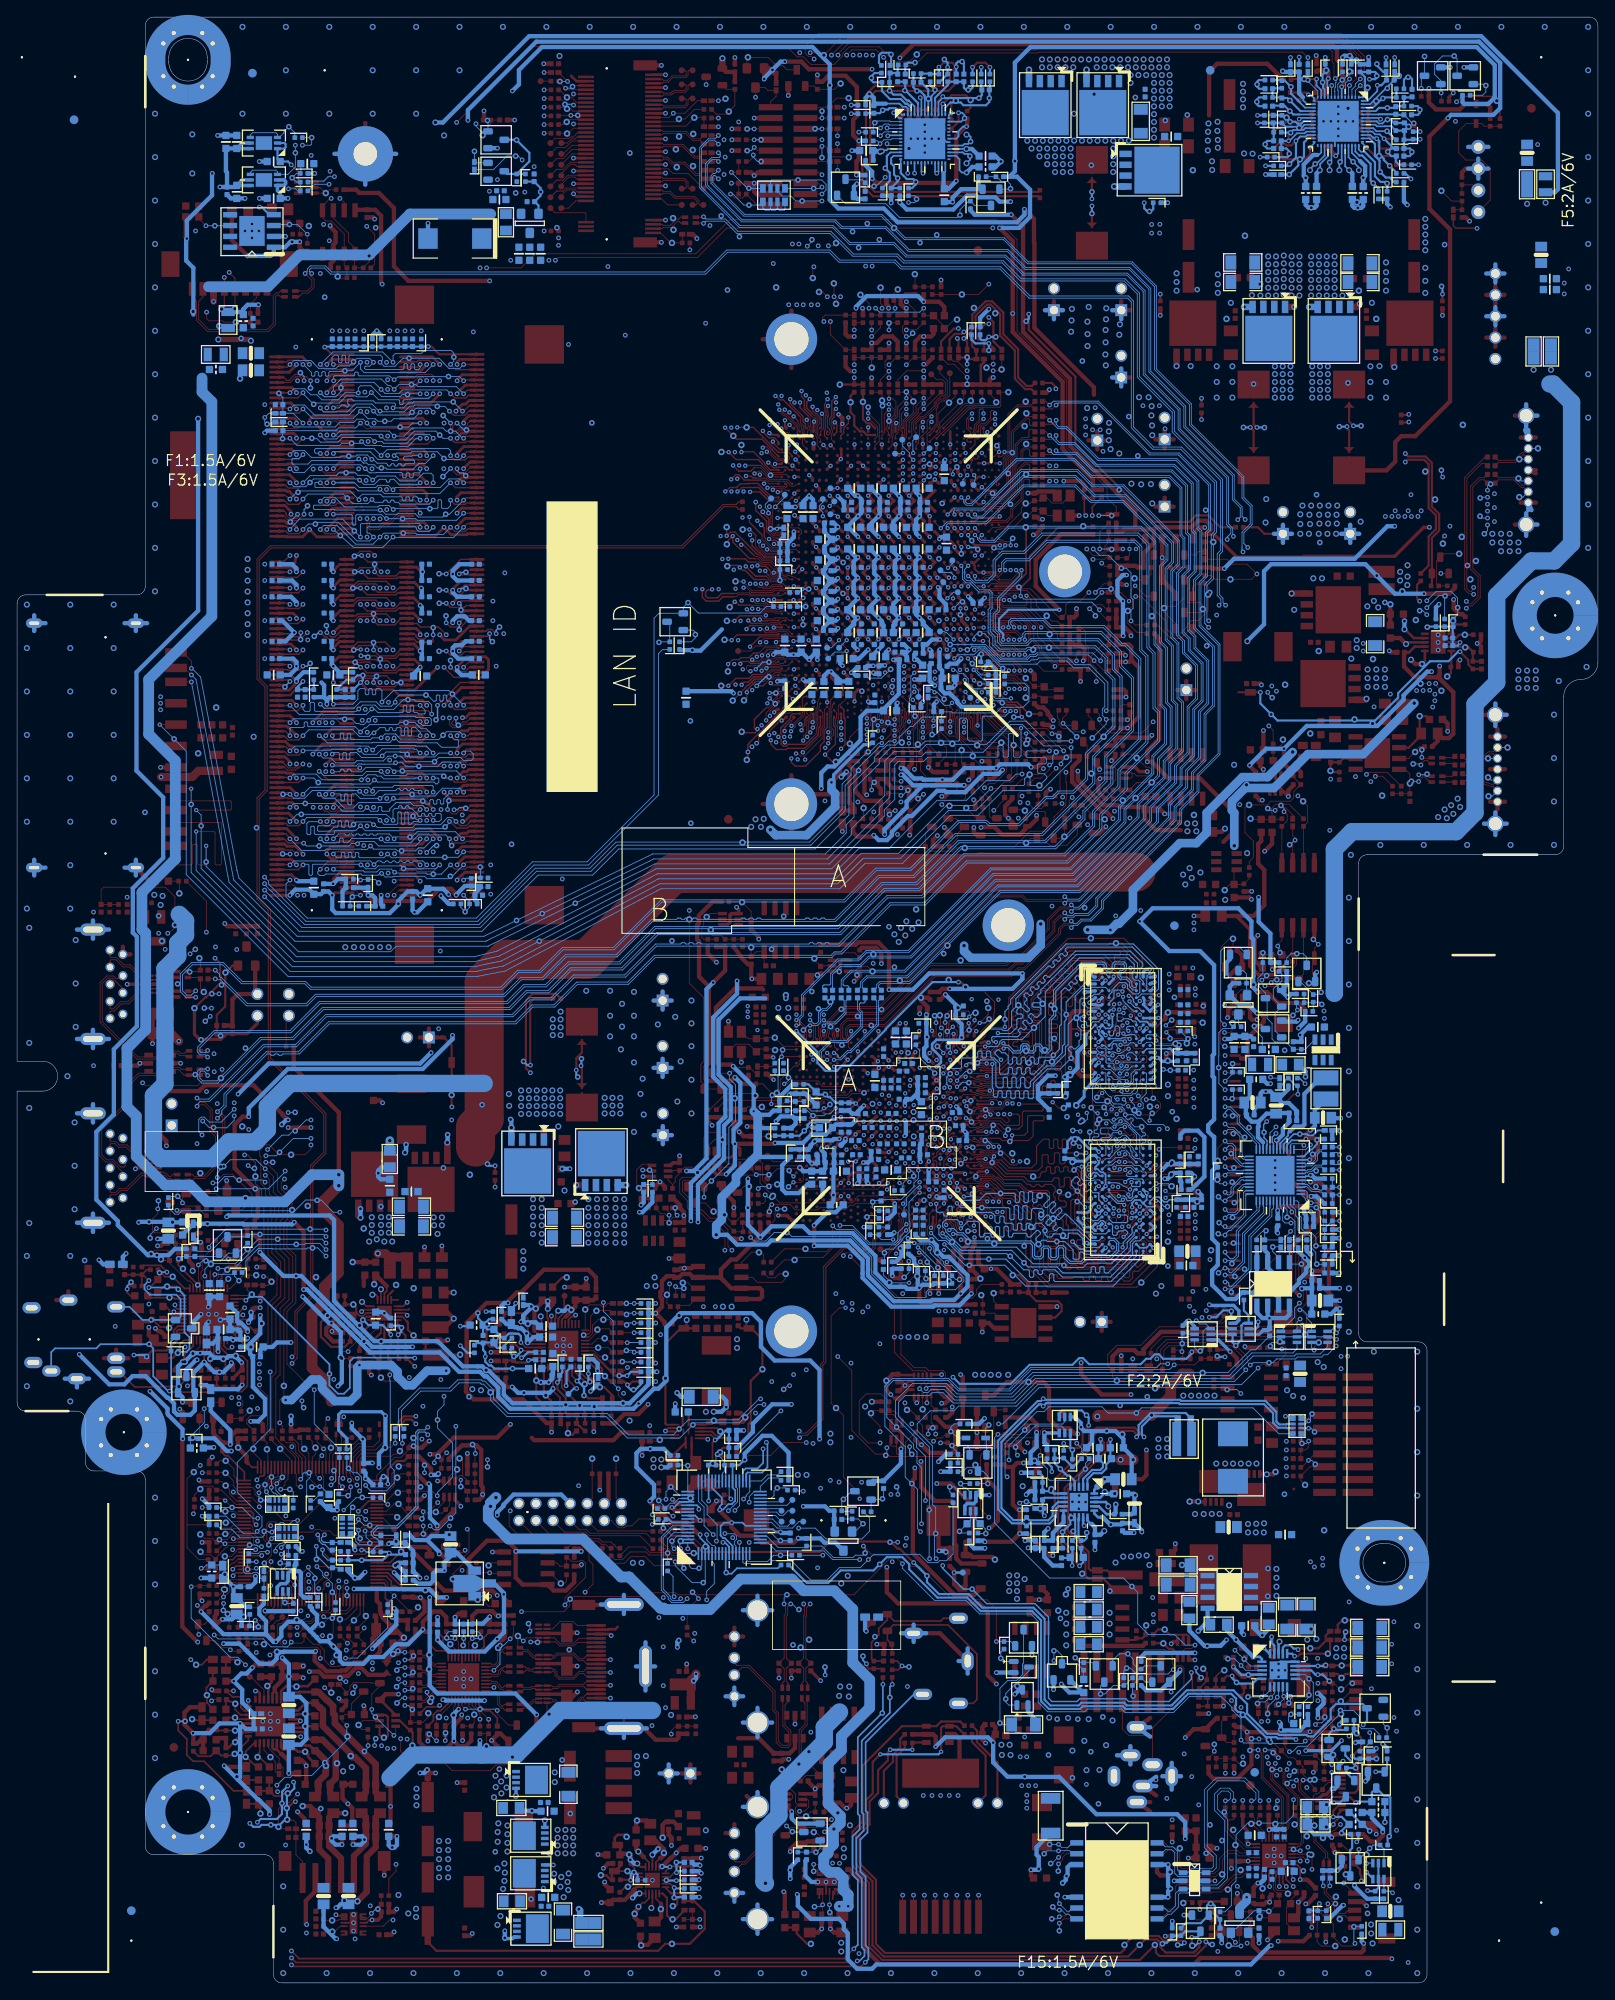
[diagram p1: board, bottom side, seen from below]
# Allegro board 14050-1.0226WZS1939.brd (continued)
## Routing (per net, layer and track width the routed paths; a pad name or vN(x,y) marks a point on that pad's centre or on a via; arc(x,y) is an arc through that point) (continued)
GND_AUD: length 6.2
  TOP w0.203: C145.2 168.63,77.09 168.61,77.09 168.26,76.75 167.33,76.75 v1(167.21,76.63) 167.2,76.63 166.59,77.23 U6.40
  TOP w0.508: C144.1 170.44,77.42 169.56,77.42 169.31,77.66 C145.2
VBAT1: length 7
  TOP w0.508: R1683.2 TP189.1 76.8,50.85 v3(77.11,50.55) 77.17,50.61 BT1.1
  BOTTOM w0.508: v3(77.11,50.55) 76.43,50.55 v2(76.31,50.42)
VBAT1_R: length 6.6
  TOP w0.508: D23.1 74.01,46.52 D33.1 74.84,46.15 75.34,46.66 v3(75.34,48.01) 75.34,48.25 R1683.1
  BOTTOM w0.305: TP188.1 v3(75.34,48.01)
VBAT2: length 82.7
  TOP w0.508: v3(79.94,60.26) 79.94,59.03 80.17,58.8 80.17,50.29 75.27,45.39 73.01,45.39 D33.2 ; v3(136.56,59.44) 136.56,60.17 137.98,61.59 R707.2
  L3 w0.508: v3(79.94,60.26) 94.34,60.26 95.79,58.8 107.27,58.8 108.14,57.94 111.51,57.94 113.28,59.7 134.39,59.7 134.65,59.44 v3(136.56,59.44)
  BOTTOM w0.508: v2(135.71,59.56) 135.84,59.44 v3(136.56,59.44)
VBAT_SB_N: length 9.4
  TOP w0.254: PU4.2 159.8,119.02 v1(160.61,118.21) 160.64,118.18 160.64,114.25 161.64,113.25 C871.1 R1721.2
VBAT_SIO: length 8.5
  TOP w0.203: v3(141.61,58.38) U109.66
  TOP w0.254: v3(141.61,58.38) 141.61,60.06 140.61,61.07 139.69,61.07 R707.1
  BOTTOM w0.254: C1821.1 142.46,59.03 142.26,59.23 v2(142.12,59.23) 141.82,59.23 141.61,59.03 v3(141.61,58.38)
VCC: length 810
  TOP w0.203: U52.13 147.54,7.84 v3(147.68,7.98)
  TOP w0.508: D31.A 130.83,27.82 v3(130.83,28.36) ; PU7.6 70.65,76.58 71.28,77.22 PC5435.1 v3(72.04,76.15) ; v3(122.46,64.44) PR11.1 122.5,65.51 123.05,65.51 125.81,68.28 131.58,68.28 132.47,69.16 132.47,69.77 132.39,69.85 132.39,77.22 130.06,79.55 v3(127.54,79.55) 127.54,79.76 126.53,80.77 126.02,80.77 123.35,83.44 118.14,83.44 117.25,82.55 PR44.2 ; R6705.1 v5(84.97,68) ; R1838.2 138.53,47.12 138.13,46.71 137.53,46.71 137.51,46.74 135.85,46.74 135.01,45.9 129.37,45.9 v3(128.81,45.34) ; v3(60.49,72.57) 60.49,71.25 58.07,68.83 v3(54.64,68.83) ; R2080.1 v3(55.79,73.38)
  L3 w0.508: v3(55.79,73.38) 56.6,72.57 v3(60.49,72.57) 62.66,74.74 70.63,74.74 v3(72.04,76.15) ; v3(59.86,23.23) 58.31,23.23 55.07,19.99 47.56,19.99 v3(46.72,20.83) ; v5(136.05,217.67) 136.05,212.01 149.28,198.78 149.28,196.37 162.64,183.01 v5(163.81,183.01) ; 54.52,67.21 54.52,68.71 v3(54.64,68.83)
  L3 w2.032: 76.1,65.91 74.84,65.91 72.3,68.45 67.91,68.45 65.37,65.91 64.1,65.91 61.94,68.07 57.46,68.07 56.6,67.21 41.36,67.21 35.63,72.94 35.63,73.64 32.8,76.47 32.8,77.32 32.01,78.11 32.01,111.15
  L4 w0.508: v3(122.46,64.44) 122.46,58.28 LPC1.8 ; v3(47.15,38.61) 47.04,38.61 46.29,37.86 46.29,21.26 v3(46.72,20.83) ; v3(59.86,23.23) 59.96,23.23 62.26,25.53 71.79,25.53 73.76,27.5 73.76,28.89 72.47,30.18 72.47,43.96 72.78,44.27 74.28,44.27 79.28,49.28 79.28,50.93 78.01,52.2 78.01,53.72 79.84,55.55 79.84,59.43 78.57,60.7 78.57,61.44 79.82,62.69 79.82,64.93 v3(80.3,65.41) ; v3(130.83,28.36) 130.83,29.91 131.49,30.57 131.49,31.12 130.24,32.37 130.03,32.37 129.64,32.76 129.64,34.08 129.86,34.3 129.86,34.84 128.01,36.69 128.01,43.65 128.81,44.45 v3(128.81,45.34) 128.81,46.35 128.04,47.12 128.04,50.03 128.81,50.79 v3(128.81,54.74)
  L4 w2.032: 147.67,10.77 148.39,11.49 148.39,22.73 ; 107.68,33.38 105.16,33.38 103.67,34.87 103.67,42.09 97.09,48.67 97.09,57.63 95.54,59.18
  BOTTOM w0.508: R617.1 166.52,85.89 167.27,85.14 v2(168.64,85.14) 169.69,85.14 173.21,88.66 173.21,89.13 173.77,89.69 175.72,91.65 175.72,99.57 173.68,101.61 173.68,101.61 173.68,109.23 170.98,111.94 170.98,122.4 171.46,122.89 171.46,128.07 167.9,131.62 167.9,138.71 171.03,141.83 171.03,153.34 163.81,160.55 v5(163.81,183.01) ; R1849.1 53.45,38.12 52.97,38.61 v3(47.15,38.61) ; PR95.1 128.3,79.22 127.97,79.55 v3(127.54,79.55) ; v3(147.68,8.79) 147.54,8.79 147.14,9.19 C1833.1 ; F5.1 5.04,209.5 4.68,209.85 4.68,218.79 13.66,227.77 125.07,227.77 135.17,217.67 v5(136.05,217.67) ; 130.72,26.67 130.83,26.79 v3(130.83,28.36) ; LPC1.8 121.32,57.13 126.9,57.13 128.07,55.96 128.07,55.79 128.81,55.05 v3(128.81,54.74)
  BOTTOM w2.032: 30.87,115.82 30.84,115.8 30.84,132.64 28.79,134.7 16.59,134.7 14.38,136.91 14.38,149.61 11.84,152.15 11.84,162.31 7.78,166.37 5.11,166.37 3.08,168.4 3.08,184.91 5.24,187.07 5.62,187.07 ; 110.65,31.88 121.42,31.88 126.63,26.67 138.69,26.67 141.36,24
  vias: v3(32.01,112.85) v3(32.06,113.72) v3(109.12,32.2) v5(5.49,188.73) v5(6.13,208.29) v5(7.53,188.73) v5(8.29,208.15) v5(85.76,67.44) v5(92.62,59.44) v5(93.63,59.44) v5(108.47,31.36) v5(145.83,25.25) v5(146.85,24.77)
VCC3: length 1289.4
  TOP w0.203: v5(160.28,82.37) 160.79,81.86 U6.11 ; U118.37 v3(133.34,32.03) ; U118.11 134.54,38.51 134.89,38.86 135.97,38.86 136.68,39.56 C3379.1
  TOP w0.33: DIMM1.199 132.12,128.75 v3(133.61,127.25) ; v3(143.92,127.25) 145.42,128.75 DIMM2.199
  TOP w0.356: CPU1.AP19 v4(85.4,156) CPU1.AP21
  TOP w0.508: R1674.2 R162.2 R79672.2 81.31,142.62 81.57,142.37 v3(81.57,142.11) ; R1674.2 R1673.2 ; R1674.2 83.28,143 R1662.1 R1659.1 ; R680.2 156.24,65.33 156.62,65.71 v3(157.66,65.71) ; R57.1 41.18,74.32 v3(41.31,74.45) ; R79694.2 86.12,121.11 84.48,121.11 83.85,120.49 v3(83.85,119.25) ; v3(91.35,223.24) R1701.1 90.75,222.44 90.05,223.14 88.03,223.14 86.72,221.83 86.72,218.42 87.16,217.99 87.16,216.18 v3(86.49,215.52) 86.49,213.39 86.77,213.11 v3(86.77,211.52) ; R1749.2 87.66,142.52 86.9,141.76 86.9,139.4 85.8,138.3 84.04,138.3 R1687.1 R159.2 R1868.1 ; R1749.2 87.85,142.94 88.68,142.11 88.68,141.48 v3(89.7,140.46) ; R1749.2 R1926.2 ; v3(133.88,28.31) 134.68,27.51 137.24,27.51 137.93,28.19 R634.2 ; v3(133.88,28.31) 133.27,27.7 132.51,27.7 131.85,28.36 R1596.1 ; v3(133.88,28.31) C3380.2 ; v3(156.75,196.34) 156.81,196.28 R12.1 ; R160.1 70.83,140.84 70.42,141.25 v3(70.42,142.14) 70.42,142.21 70.26,142.37 R1684.1 ; C3379.1 137.26,41.09 v3(137.51,41.35) 137.51,42.25 136.31,43.45 135.43,43.45 134.77,42.78 R2087.1 R1598.1 R2088.1 R1593.1 131.72,42.94 131.16,43.49 129.39,43.49 128.82,42.93 v3(128.68,42.93) 128.62,42.99 R1594.1 ; R213.1 166.09,85.47 165.01,85.47 164.88,85.6 ; v3(56.75,136.21) 56.84,136.3 56.84,136.34 57.5,137.01 58,137.01 61.53,140.53 61.53,142.21 60.68,143.07 R1776.1 62.04,143.51 62.19,143.36 64.76,143.36 R1650.1 64.99,142.91 65.21,142.69 65.56,142.34 65.59,142.34 65.69,142.24 v3(66.33,142.24) ; 41.03,29.34 v3(41.05,29.36) 41.64,29.95 42.36,29.95 R138.1 ; 41.03,29.34 41.03,28.5 40.55,28.02 40.55,25.53 42.2,23.88 44.98,23.88 45.56,24.46 R143.1 ; 41.03,29.34 36.93,29.34 R1757.1 36.55,28.96 35.97,28.96 35.64,29.29 34.09,29.29 33.99,29.39 v3(33.69,29.39) 32.47,29.39 32.4,29.31 30.72,29.31 30.26,29.77 v3(30.26,30.23) ; 75.2,65.06 76.36,65.06 77.45,66.15 R6704.1 ; 75.2,65.06 75.2,62.37 75.56,62.01 78.21,62.01 v3(79.16,62.96) 79.19,62.99 79.32,62.99 R6703.1 ; 75.2,65.06 74.33,65.94 R6701.1 ; v3(30.23,85.09) 31.02,85.09 31.48,84.63 31.48,81.2 31.71,80.98 ; 31.71,80.98 31.1,80.37 31.1,79.76 30.23,78.89 v3(30.18,78.89) ; 31.71,80.98 33.38,82.65 34.2,82.65 34.45,82.91 34.45,84.68 v3(34.3,84.84) ; R1716.2 130.36,218.05 v3(130.36,219.02) ; v3(19.78,221.67) R508.1 19.78,220.03 18.96,219.2 16.16,219.2 15.53,219.84 D1.K 12.99,219.84 12.61,219.46 R71.1 ; v3(163.48,43.43) 163.48,43.64 163.01,44.12 162.86,44.12 R316.2 ; v3(105.06,52.45) 105.19,52.45 106.59,53.85 108.41,53.85 109.34,54.78 v3(110.65,54.78) ; v3(163.71,58.85) 163.53,58.67 R308.2 ; v3(143.92,127.25) 143.26,126.59 137.01,126.59 135.69,127.91 134.87,127.91 134.78,128.01 134.23,128.01 133.84,127.62 133.84,127.49 v3(133.61,127.25) ; v3(70.39,34.98) 71.41,35.99 71.41,43.43 72.37,44.4 81.9,44.4 83.22,45.72 v3(83.22,48.64) ; R2025.2 76.49,196.09 77.1,196.7 v3(78.9,196.7) R2026.1 ; R366.1 130.92,56.52 130.51,56.92 v3(130.51,57.15) 130.51,57.65 130.49,57.68 130.49,57.99 130.69,58.19 130.69,62.36 131.23,62.9 132.93,62.9 134.46,61.36 R381.2 ; v3(154.72,39.9) 155.1,40.28 R1829.2 R341.2 R334.2 ; 163.48,87.73 163.96,87.73 164.37,87.33 164.37,86.11 164.88,85.6 ; R1870.1 77.79,140.12 77.55,140.12 76.89,140.78 v3(76.72,140.78) 76.72,140.64 76.41,140.34 R1872.1 75.85,140.4 75.85,140.59 75.22,141.22 R1661.1 R1657.2 ; R134.1 45.59,31.48 v3(45.55,31.52) ; 164.88,85.6 164.88,84.43 164.45,84 v5(164.45,83.31) ; v3(27.41,4.62) 27.41,3.81 27.67,3.56 39.56,3.56 40.39,4.39 40.39,5.25 R1183.2 ; v4(134.98,48.25) 135.05,48.25 135.06,48.26 136.46,48.26 138.3,50.1 R1837.2 ; v3(39.81,115.93) 38.72,115.93 37.44,114.65 35.04,114.65 34.27,113.88 34.27,112.47 v3(35.03,111.71) ; LPC1.4 115.79,56.58 R1699.1
  TOP w0.965: v3(168.15,141.09) 164.51,141.09 163.79,141.81 F6.2
  L3 w0.254: v3(89.7,140.46) 89.7,144.17 89.21,144.65 89.21,150.73 89.01,150.93 89.01,154.17 87.84,155.35 86.05,155.35 v4(85.4,156)
  L3 w0.508: v3(86.77,211.52) 87.43,210.86 87.43,206.78 86.82,206.17 86.82,200.33 86.14,199.64 86.14,196.79 86.82,196.11 v3(86.82,195.94) ; v5(157.32,145.8) 157.26,145.8 153.84,142.38 153.84,130.65 153.11,129.92 150.78,129.92 150.5,129.64 147.23,129.64 146.9,129.97 143.16,129.97 142.53,130.61 138.6,130.61 136.64,128.65 134.87,128.65 133.61,127.39 133.61,127.32 ; v3(38.31,105.21) 38.14,105.21 37.5,105.85 37.5,107.31 35.54,109.27 35.54,111.3 35.14,111.71 v3(35.03,111.71) ; v3(163.71,58.85) 159.41,58.85 157.06,56.49 155.86,56.49 154,54.64 v3(153.55,54.64) ; v3(79.16,62.96) 79.19,62.99 79.41,62.99 80.25,63.83 v3(87.41,63.83) ; v3(130.36,219.02) 130.36,217.25 130.82,216.79 v3(130.82,200.66) ; v3(157.66,65.71) 157.74,65.63 161.68,65.63 162.16,65.15 162.82,65.15 v3(162.85,65.12) ; v3(31.15,24.64) 31.38,24.87 31.42,24.87 31.91,25.35 31.91,27.94 33.36,29.39 v3(33.69,29.39) ; v3(93.4,225.84) 91.78,227.46 32.06,227.46 v3(29.88,225.27) 29.09,224.49 22.56,224.49 19.78,221.71 v3(19.78,221.67) ; v5(160.28,82.37) 158.22,82.37 156.82,80.97 156.82,80.42 157.21,80.04 157.21,78.73 156.82,78.34 156.78,78.34 v3(156.55,78.11) ; v3(130.51,57.15) 130.13,57.53 121.95,57.53 121.56,57.13 117.75,57.13 116.7,56.09 LPC1.4 115.24,57.13 113.76,57.13 111.41,54.78 v3(110.65,54.78) ; v3(105.06,52.45) 105.06,52.83 103.94,53.95 102.41,53.95 101.65,53.19 101.63,53.19 101.56,53.11 101.18,53.11 100.34,53.95 99.08,53.95 98.07,54.97 92.38,54.97 91.27,56.07 89.02,56.07 86.51,58.58 v3(86.16,58.58) ; v3(70.39,34.98) v3(62.79,34.98) 49,34.98 v3(45.55,31.52) 43.39,29.36 v3(41.05,29.36) ; 133.61,127.32 132.89,128.04 127.78,128.04 121.53,134.29 97.49,134.29 v5(96.86,134.92) ; 133.61,127.32 v3(133.61,127.25) ; v3(87.41,72.52) 87.41,72.77 86.7,73.48 63.25,73.48 60.91,71.13 43.86,71.13 41.31,73.69 v3(41.31,74.45) 40.55,74.45 37.78,77.22 v3(37.78,80.6) ; v3(53.63,124.21) 56.07,124.21 59.12,121.16 72.55,121.16 75.08,118.63 83.23,118.63 v3(83.85,119.25)
  L3 w1.016: v3(168.15,141.09) 168.05,141.09 167.29,141.84 167.29,182.62 164.82,185.1 163.06,185.1 158.66,189.51 158.66,194.44 v3(156.75,196.34)
  L4 w0.508: v3(30.23,90.17) 30.89,89.51 30.89,88.8 v3(30.23,88.14) 30.89,87.48 30.89,85.75 v3(30.23,85.09) ; 86.14,58.58 86.14,62.56 v3(87.41,63.83) v3(87.41,72.52) ; 86.14,58.58 85.12,57.57 85.12,50.55 v3(83.22,48.64) ; 86.14,58.58 v3(86.16,58.58) ; v3(56.75,136.21) 56.75,126.14 54.81,124.21 v3(53.63,124.21) ; v3(162.85,65.12) 162.87,65.1 162.87,63.5 162.87,60.17 162.67,59.97 162.67,59.42 163.32,58.77 163.63,58.77 v3(163.71,58.85) ; v3(130.51,57.15) 130.82,56.84 130.82,51.95 130.46,51.59 130.46,44.57 128.82,42.93 v3(128.68,42.93) ; v3(89.7,140.46) 88.25,140.46 86.6,142.11 v3(81.57,142.11) ; v3(27.41,4.62) 27.59,4.8 27.59,7.63 28.23,8.26 28.23,9.68 29.34,10.79 29.88,10.79 30.72,11.63 30.72,12.01 32.9,14.19 32.9,22.89 v3(31.15,24.64) ; v3(156.75,196.34) 154.38,198.71 154.31,198.71 153.68,199.34 143.16,199.34 142.95,199.56 141.55,199.56 141.34,199.34 132.13,199.34 v3(130.82,200.66) ; v3(153.55,54.64) 153.55,54.47 153.17,54.09 153.17,49.79 153.73,49.23 153.73,48.65 153.9,48.48 153.9,43.62 154.19,43.33 154.19,42.79 154.72,42.25 v3(154.72,39.9) ; v3(130.36,219.02) 122.12,227.26 94.83,227.26 v3(93.4,225.84) 93.4,225.3 v3(91.35,223.24) ; v4(134.98,48.25) 134.98,47.35 133.97,46.33 133.97,44.54 135.06,43.45 136.06,43.45 137.51,41.99 v3(137.51,41.35) 137.51,41.31 136.9,40.7 136.9,35.36 135.99,34.44 135.99,33.58 136.21,33.36 136.21,32.2 135.82,31.81 135.28,31.81 135.11,31.98 134.65,31.98 134.57,32.05 133.36,32.05 v3(133.34,32.03) ; v3(147.61,5.16) 147.76,5.16 148.22,5.61 148.43,5.61 150.49,7.67 150.49,16.49 162.89,28.89 162.89,32.71 162.9,32.72 162.9,40.31 162.82,40.39 162.82,41.15 162.88,41.21 162.88,42.84 v3(163.48,43.43)
  BOTTOM w0.203: U4101.4 104.07,51.08 105.06,52.07 v3(105.06,52.45)
  BOTTOM w0.381: R79714.2 85.1,145.1 85.33,144.87 85.92,144.87 89.44,141.35 89.44,140.72 v3(89.7,140.46)
  BOTTOM w0.508: R1846.1 60.28,33.98 ; 60.28,33.98 61.85,33.98 62.79,34.92 v3(62.79,34.98) ; 60.28,33.98 D19.2 ; v3(81.57,142.11) 81.24,142.11 80.05,140.92 79.11,140.92 78.97,140.78 v3(76.72,140.78) 75.49,140.78 74.12,142.14 v3(70.42,142.14) 69.98,142.57 66.66,142.57 v3(66.33,142.24) ; 40.5,80.6 40.69,80.78 R524.1 41.66,80.78 42.43,80.01 43.49,80.01 45.14,81.66 45.14,83.34 44.48,84 44.48,86.41 45.14,87.07 45.14,95 44.7,95.44 R482.1 44.91,95.87 44.91,98.98 44.97,98.98 45.61,99.63 45.61,100.35 45.25,100.71 45.24,100.71 44.91,101.03 44.91,105.89 45.09,106.07 45.09,108.51 44.92,108.69 44.92,119.08 46.56,120.73 50.15,120.73 v3(53.63,124.21) 52.1,125.73 42.07,125.73 40.55,124.21 40.55,122.3 40.32,122.08 40.32,117.81 40.34,117.79 40.34,116.46 v3(39.81,115.93) ; 40.5,80.6 v3(37.78,80.6) ; 40.5,80.6 39.91,81.19 U25.8 39.91,86.02 R32.1 ; C1975.1 143.99,128.14 R2055.1 v3(143.92,127.25) 143.42,127.25 143.1,126.94 C1976.1 R2061.1 ; L17.1 31.22,78.26 30.61,78.87 30.21,78.87 ; R79676.2 150.5,43.85 150.5,43.63 149.89,43.02 149.89,42.04 150.72,41.21 ; 30.21,78.87 v3(30.18,78.89) ; 30.21,78.87 30.26,78.82 R1860.1 ; R377.1 27.64,4.85 v3(27.41,4.62) ; v3(30.26,30.23) 29.75,30.73 R2077.1 ; v3(133.88,28.31) 133.88,31.49 v3(133.34,32.03) ; C509.1 157.73,73.58 C516.1 157.42,69.75 155.99,68.33 155.99,66.5 156.78,65.71 v3(157.66,65.71) ; C509.1 157.73,74.79 156.55,75.98 v3(156.55,78.11) ; C509.1 157.74,74.41 L21.1 ; v3(163.48,43.43) 160.85,40.81 155.89,40.81 ; 150.72,41.21 151.76,42.25 153.27,42.25 154.08,41.44 154.08,40.54 v3(154.72,39.9) 154.99,39.9 155.89,40.81 ; 150.72,41.21 149.92,40.41 149.92,40.37 149.53,39.98 148.6,39.98 v2(147.97,39.36) 147.23,38.61 147.23,37.72 146.84,37.34 144.48,37.34 143.69,38.13 142.15,38.13 140.72,39.55 140.7,39.55 140.62,39.62 139.24,39.62 v3(137.51,41.35) ; 155.89,40.81 155.87,40.82 155.87,42.33 156.65,43.1 156.65,43.82 156.12,44.36 R294.1 ; R1634.1 131.16,126.46 131.41,126.71 C1729.1 131.41,127.5 130.78,128.14 C1730.1 130.84,128.33 R165.1 132.6,128.33 133.61,127.32 v3(133.61,127.25) ; PR4624.1 28.86,225.3 v2(29.04,225.48) 29.67,225.48 v3(29.88,225.27) PR4632.1 ; PR5463.1 v3(86.49,215.52) ; C1714.1 86.46,154.94 v4(85.4,156) ; C1835.1 149.13,6.58 147.71,5.16 v3(147.61,5.16) ; R46.1 35.09,85.62 v3(34.3,84.84) 33.82,84.35 33.82,83.9 34.13,83.59 34.13,83.12 34.98,82.27 34.98,81.9 36.29,80.6 v3(37.78,80.6) ; v3(86.82,195.94) 86.82,196.11 85.57,197.36 79.56,197.36 v3(78.9,196.7) ; v3(38.31,105.21) 38.72,105.21 L16.1 ; R689.2 138.53,47.12 138.13,46.71 136.66,46.71 136.33,47.04 136.33,47.86 135.94,48.25 v4(134.98,48.25) 134.98,49.2 134.27,49.91 C3367.1 133.56,50.34 U119.3 ; v3(156.75,196.34) 158.02,196.34 158.53,195.83 R24.1 158.83,195.5 F1.1 ; v3(37.78,80.6) 37.37,80.19 U25.3 ; R41.1 34.26,112.48 v3(35.03,111.71) ; R530.2 v3(30.23,88.14) ; R58.1 R47.1 v3(30.23,85.09) ; R517.1 v3(30.23,90.17) ; R1986.2 v3(86.77,211.52)
  BOTTOM w1.016: v5(96.86,134.92) 96.22,134.28 92.6,134.28 89.26,137.62 89.26,139.14 89.7,139.57 v3(89.7,140.46)
  vias: v2(163.86,81.66)
VCC3_CAM: length 10
  TOP w0.61: v5(161.45,192.28) 157.77,192.28 157.64,192.15 v5(157.64,192.13)
  TOP w0.762: WEBCM1.3 v3(162,196.72)
  L3 w0.762: v3(162,196.72) 162,192.83 v5(161.45,192.28)
  vias: v2(158.78,192.41)
VCC5_33_CT1: length 2.5
  TOP w0.102: C1837.1 148.97,7.32 v1(148.13,7.32) 147.43,7.32 147.31,7.44 U52.12
VCC5_33_CT2: length 2.9
  TOP w0.102: C1836.1 148.93,6.6 148.32,5.99 v1(148.12,5.99) 147.84,5.99 147.19,6.64 U52.10
VCC5_33_EN: length 11.6
  TOP w0.102: R1878.1 C1831.1 142.48,9.19 v3(143.54,8.13) 143.54,8 144.11,7.44 U52.3 ; U52.5 142.14,6.64 141.41,7.37 v3(141,7.37)
  L3 w0.127: v3(141,7.37) 141.77,8.13 v3(143.54,8.13)
  BOTTOM w0.102: v3(143.54,8.13) 143.04,8.64 v2(142.78,8.64)
VCC5_DDC_HDMI: length 6.5
  TOP w0.102: R2084.1 R2083.1 130.08,28.89 v1(130.08,27.69) 130.08,27.43 130.46,27.05 D31.K 129.64,25.91 C6721.1
VCC5_PANEL: length 13.5
  TOP w0.508: 41.77,108.15 41.36,108.15 40.98,108.53 40.98,110.57 39.1,112.45 39.1,113.06 39.5,113.46 v3(39.89,113.46)
  BOTTOM w0.508: v3(39.89,113.46) 39.91,113.46 40.83,114.38 41.92,114.38 Q9647.S 43.09,116.59 42.71,116.97 R80233.2
  vias: v2(43.67,109.58) v3(43.63,108.5) v3(43.63,107.5)
VCC5_USB: length 210.9
  L3 w0.508: v3(44.48,3.68) 44.86,3.3 83.43,3.3 86.27,6.14 86.27,13.34 86.65,13.72 86.65,17.02 87.54,17.91 v5(87.54,18.44)
  L3 w2.032: 131.63,71.63 131.63,81.25 127.64,85.24 127.64,96.49 128.94,97.79 128.94,101.73
  L4 w1.27: v5(88.3,24.89) 88.96,24.23 88.96,19.86 v5(87.54,18.44) ; v5(26.37,4.62) 26.37,3.78 26.88,3.28 44.08,3.28 v3(44.48,3.68)
  L4 w2.032: v5(88.3,24.89) 88.3,30.73 86.11,32.92 86.11,35.29 87.41,36.59 87.41,45.59
  BOTTOM w2.032: 166.02,125.02 165.29,124.28 165.29,122.58 166.2,121.67 166.2,120.14 167.7,118.64 167.7,105.16 169.04,103.81 169.04,97.31 168.18,96.44 162.16,96.44 160.21,98.4 157.11,98.4 155.71,99.8 155.71,102.57 153.04,105.23 130.34,105.23
  vias: v2(130.58,102.75) v2(132.11,68.58) v2(168.44,124.84) v5(87.79,47.62) v5(88.55,46.74) v5(104.4,17.86) v5(111.92,49.15) v5(112.94,49.15) v5(127.45,104) v5(127.41,102.62) v5(130.72,69.34) v5(131.73,69.47) v5(167.98,127.18) v5(168.21,126.12) v5(168.94,127.3)
VCC_FAN: length 7.4
  TOP w0.508: R80.1 15.91,211.84 15.47,212.27 FANC3.2
  BOTTOM w0.508: FANC3.2 15.18,212.27 ; FANC3.2 14,211.09 ; FANC3.2 12.82,212.27 ; FANC3.2 14,213.45
VCC_VTT: length 2.2
  TOP w0.203: PU5001.20 140.39,79.91 ; 139.1,78.87 139.21,78.76 PU5001.2
  vias: v1(138.59,81.28)
VDD_095_FB_H: length 80.5
  TOP w0.254: R1612.2 70.75,192.06 70.75,194.33 v3(71.28,194.87) ; v1(19.06,173.56) 19.43,173.56 ; 19.43,173.56 19.43,172.72 18.58,171.86 18.58,169.93 19.43,169.07 Q14.S 19.43,163.54 R110.2 ; 19.43,173.56 19.43,177.85 20.17,178.59 22.2,178.59 v3(22.54,178.93)
  L3 w0.254: v3(22.54,178.93) 22.89,178.58 48.16,178.58 48.96,179.39 49.28,179.39 51.51,179.39 53.5,181.38 53.5,183.72 64.45,194.68 71.09,194.68 v3(71.28,194.87)
VDD_095_FB_H_CTL: length 7
  TOP w0.102: PR83.2 R110.1 18.87,163.68 18.87,166.39 Q14.D 18.06,167.21 v1(16.24,167.21)
VDD_095_FB_L: length 76.7
  TOP w0.254: 19.81,176.83 19.81,172.56 18.96,171.7 18.96,170.08 19.81,169.23 19.81,165.83 R80227.2 ; 19.81,176.83 v1(20.2,176.83) ; 19.81,176.83 19.81,177.69 20.33,178.21 22.27,178.21 v3(22.54,177.94) ; v3(71.28,194.11) 71.67,194.11 72.36,193.42 R1861.2
  L3 w0.254: v3(22.54,177.94) 22.79,178.2 48.31,178.2 49.12,179.01 51.67,179.01 53.88,181.22 53.88,183.57 64.61,194.3 71.09,194.3 v3(71.28,194.11)
VDDC_CT: length 9.9
  TOP w0.254: v4(86.86,102.88) 87.38,103.4 GPU1.AB21 ; v4(86.86,102.88) 87.34,102.4 GPU1.AB20 ; v4(86.86,102.88) 86.4,102.42 GPU1.AA20 ; v4(86.86,102.88) 86.4,103.34 GPU1.AA21
  BOTTOM w0.254: v4(86.86,102.88) 86.94,102.96 C779.1 C781.1 89.2,102.96 89.87,103.64 90.1,103.64 v2(90.4,103.94) 91.19,103.94 C780.1 92.39,105.14 L48.2
VDDCR_APU_FB_H: length 142.7
  TOP w0.254: 72.73,195.68 73.21,195.2 73.21,193.93 73.98,193.17 v3(74.2,193.17) 74.43,192.94 75.27,192.94 75.88,192.33 75.88,191.1 R1611.2 ; 72.73,195.68 71.66,196.75 70.9,196.75 69.58,195.43 69.58,192.9 67.85,191.17 67.85,187.83 66.87,186.85 66.23,186.85 PR4628.2 ; 72.73,195.68 v1(73.02,195.97)
  L3 w0.254: v3(94.27,203.45) 94.08,203.64 94.08,216.48 91.45,219.1 86.96,223.59 86.96,225.3 87.16,225.49 v3(87.16,225.55)
  L4 w0.254: v3(23.78,225.27) 24.1,225.59 24.1,226.22 25.9,228.02 85.58,228.02 86.95,226.64 86.95,225.75 v3(87.16,225.55) ; v3(74.2,193.17) 73.98,193.17 73.64,193.51 73.64,198.03 77.01,201.39 92.65,201.39 94.27,203.01 v3(94.27,203.45)
  BOTTOM w0.254: PR4604.2 v3(23.78,225.27)
VDDCR_APU_FB_L: length 140.4
  TOP w0.254: 70.28,195.59 71.06,196.37 71.5,196.37 72.83,195.04 72.83,193.78 v3(74.2,192.41) 73.82,192.02 R528.2 ; 70.28,195.59 69.96,195.27 69.96,192.74 68.23,191.01 68.23,187.68 67.02,186.47 66.29,186.47 PR4611.2 ; 70.28,195.59 v1(70.52,195.35)
  L3 w0.254: v3(93.51,203.45) 93.7,203.64 93.7,216.32 86.58,223.43 86.58,225.36 v3(86.39,225.55)
  L4 w0.254: v3(74.2,192.41) 73.26,193.35 73.26,198.18 76.85,201.78 92.49,201.78 93.51,202.79 v3(93.51,203.45) ; v3(86.39,225.55) 86.57,225.73 86.57,226.48 85.42,227.64 26.06,227.64 24.48,226.06 24.48,225.59 v3(24.8,225.27)
  BOTTOM w0.254: PR4606.2 v3(24.8,225.27)
VDDCR_CPU_SENSE: length 17.8
  TOP w0.102: v4(78.89,177.4) 79.19,177.1 CPU1.G12 ; R1611.1 75.41,189.74 74.94,189.74 v3(73.82,188.62)
  L4 w0.127: v4(78.89,177.4) 78.47,177.81 78.47,180.59 75.62,183.44 75.62,185.39 73.35,187.66 73.35,188.15 v3(73.82,188.62)
  BOTTOM w0.102: v2(78.22,177.69) 78.59,177.69 v4(78.89,177.4)
VDDCR_GFX_FB_H: length 55.2
  TOP w0.254: R1953.2 70.77,191.31 v3(71.28,191.82)
  L3 w0.254: v3(71.28,191.82) 71.09,192.01 70.25,192.01 69.99,191.76 69.99,191.06 70.42,190.63 86.87,190.63 87.66,191.42 87.66,196.42 87.34,196.74 87.34,197.83 88.07,198.56 88.07,211.12 87.84,211.35 87.84,216.47 86.85,217.46 86.85,219.18 v3(87.38,219.71)
  BOTTOM w0.254: v2(71.28,191.01) v3(71.28,191.82) 72.85,191.82 73.31,192.28 PR5410.2 ; PR5420.2 v3(87.38,219.71)
VDDCR_GFX_FB_L: length 55.7
  TOP w0.254: R1954.2 71.81,191.05 71.81,192.05 v3(71.28,192.58)
  L3 w0.254: v3(71.28,192.58) 71.09,192.39 70.09,192.39 69.61,191.91 69.61,190.9 70.26,190.25 87.03,190.25 88.04,191.26 88.04,196.58 87.72,196.9 87.72,197.67 88.45,198.4 88.45,211.28 88.22,211.51 88.22,216.62 87.23,217.61 87.23,218.54 v3(87.38,218.69)
  BOTTOM w0.254: PR5416.2 72.3,192.39 72.1,192.2 71.66,192.2 v3(71.28,192.58) v2(70.47,192.58) ; PR5422.2 v3(87.38,218.69)
VDDCR_GFX_SENSE: length 18.1
  TOP w0.102: v1(71.56,188.98) 71.53,188.98 71.13,189.38 v3(70.77,189.38) R1953.1 ; v4(77.5,176.59) 77.91,176.59 CPU1.H11
  L4 w0.127: v3(70.77,189.38) 72.07,188.09 72.07,186.92 72.39,186.6 72.6,186.39 73.29,185.7 73.29,185.49 74.67,184.11 74.67,183.22 76.22,181.68 76.22,179.08 76.82,178.48 76.82,177.28 v4(77.5,176.59)
VDDCR_NB_FB_H: length 149.5
  TOP w0.254: R1613.2 76.87,192.05 75.37,193.55 74.87,193.55 v3(74.85,193.57) ; v3(66.61,195.25) 66.61,193.41 61.15,187.95 61.15,180.09 57.38,176.33 57.38,176.33 51.99,170.94 47.8,170.94 47.04,171.7 45.6,171.7 44.2,170.31 PR4643.2
  L3 w0.254: v3(84.87,225.55) 84.87,225.33 85.58,224.62 85.58,203.78 85.14,203.34 85.14,201.06 v3(84.94,200.86) ; v3(66.61,195.25) 68.44,197.08 71.8,197.08 74.85,194.03 v3(74.85,193.57)
  L4 w0.254: v3(84.94,200.86) 84.78,200.71 77.35,200.71 77.04,200.71 75.32,198.99 75.32,194.04 v3(74.85,193.57) ; v3(35.97,225.27) 35.97,225.8 36.92,226.75 84.91,226.75 85.12,226.54 85.12,225.81 v3(84.87,225.55)
  BOTTOM w0.254: v2(66.91,194.41) 66.61,194.71 v3(66.61,195.25) ; PR4642.2 v3(35.97,225.27)
VDDCR_NB_FB_L: length 116.3
  TOP w0.254: v3(74.96,192.41) 74.84,192.28 R529.2
  L3 w0.254: v3(85.7,200.86) 85.52,201.04 85.52,203.18 85.96,203.63 85.96,224.77 85.63,225.1 v3(85.63,225.55) ; v3(25.81,222.02) 25.28,222.55 25.28,223.24 25.89,223.85 33.48,223.85 v3(34.96,225.32)
  L4 w0.254: v3(74.96,192.41) 75.7,193.14 75.7,198.83 77.2,200.33 85.16,200.33 v3(85.7,200.86) ; v3(85.63,225.55) 85.5,225.68 85.5,226.69 85.07,227.13 36.76,227.13 v3(34.96,225.32)
  BOTTOM w0.203: v3(25.81,222.02) 25.81,221.35 26.95,220.21 PU4601.52
  BOTTOM w0.254: v2(25.86,224.51) 25.86,224.33 25.12,223.58 PR4606.1 24.73,223.52 PC4601.2 25.34,222.02 v3(25.81,222.02) ; v3(34.96,225.32) PC4605.2
VDDCR_NB_SENSE: length 21.1
  TOP w0.102: R1613.1 76.07,189.38 75.34,189.38 v3(73.82,187.86) ; v4(78.89,175.8) 79.18,175.5 CPU1.J12
  L4 w0.127: v4(78.89,175.8) 79.42,176.33 79.42,180.29 77.95,181.76 77.62,181.76 76,183.38 76,185.67 v3(73.82,187.86)
  BOTTOM w0.102: v3(73.82,187.86) v2(73.82,187.05) ; v2(78.26,176.27) 78.4,176.27 78.87,175.8 v4(78.89,175.8)
VDDGFX_EN: length 12.2
  TOP w0.102: v3(83.2,215.19) 83.2,211.47 v3(83.41,211.25)
  BOTTOM w0.102: v3(83.2,215.19) 82.98,214.97 PU5407.9 ; v3(83.41,211.25) 84.45,210.21 v2(84.72,210.21) 85.34,210.21 R1986.1 ; C1930.1 R1986.1 ; R1986.1 86.09,210.96 87.97,210.96 Q1240.D
VDDGFX_EN_1: length 20.5
  BOTTOM w0.102: Q1241.C 72.93,207.96 R1987.1 73.65,208.47 74.66,207.47 v2(74.66,206.83) 74.94,206.55 81.72,206.55 83.33,208.17 88.07,208.17 Q1240.G
VDDGFX_EN_2: length 5.1
  BOTTOM w0.102: Q1241.B 68.8,209.87 v2(68.74,209.93) 68.74,210.44 69.07,210.77 69.8,210.77 70.36,211.33 R1989.2 R1988.2
VDDGFX_PD: length 1.5
  TOP w0.102: CPU1.AD8 75.7,163.75 76.03,163.42 v4(76.03,163.27)
  BOTTOM w0.102: TP214.1 76.56,163.8 v4(76.03,163.27)
VDDGFX_PWROK: length 4.3
  BOTTOM w0.102: PR5466.1 84.81,217.38 84.63,217.56 v2(84.63,217.64) 84.5,217.64 84.29,217.84 82.86,217.84 82.78,217.77 81.69,217.77 81.69,217.77 PU5407.2
VDDNB: length 269.4
  TOP w0.254: PT4703.1 39.02,169.54 39.78,170.31 PR4643.1
  TOP w0.356: CPU1.AN22 87.2,156.65 v4(86.65,157.2) 86.6,157.2 CPU1.AL21 v4(85.4,157.2) CPU1.AN19 v4(84.2,157.2) CPU1.AL18 v4(83,157.2) CPU1.AN16 v4(81.8,157.2) CPU1.AL15 v4(80.6,157.2) ; CPU1.AL12 v4(79.4,157.2) CPU1.AN13 v4(80.6,157.2) ; v4(80.6,157.2) CPU1.AL13
  TOP w0.508: PL4702.2 24.74,176.97 23.72,177.99 23.72,180.28 23.02,180.97 21.37,180.97 17.31,185.04 17.31,205.16 19.72,207.57 19.72,216.03 v3(17.56,218.19) ; 35.81,169.54 PT4703.1 ; PT4703.1 36.86,168.49 ; PT4703.1 36.86,170.6 ; 28.99,168.49 PT4704.1 ; PT4704.1 28.99,170.6 ; PT4704.1 27.93,169.54 ; PT4704.1 30.04,169.54 ; v3(148.37,205.61) 148.37,205.49 147.73,204.85 147.73,203.62 147.99,203.37 U178.3 147.99,201.49 148.31,201.17 R79724.2
  L4 w0.508: PT4703.1 36.86,170.6 ; PT4703.1 37.92,169.54 ; PT4703.1 35.81,169.54 ; 27.93,169.54 PT4704.1 ; PT4704.1 28.99,170.6 ; PT4704.1 30.04,169.54 ; v3(132.24,217.93) 132.24,216.3 140.22,208.32 142.35,206.2 144,204.54 147.3,204.54 v3(148.37,205.61) 148.37,205.91 150.96,208.5 153.01,208.5 v3(153.3,208.79)
  BOTTOM w0.406: PC5427.1 154.21,209.36 154.53,209.68 Q6703.1 154.51,210.31 153.76,210.31 153.58,210.5 153.58,210.76 153.76,210.95 Q6703.2
  BOTTOM w0.508: PT4703.1 36.86,170.6 ; PT4703.1 35.81,169.54 ; PT4703.1 37.92,169.54 ; PT4703.1 36.86,168.49 ; PT4704.1 30.04,169.54 ; PT4704.1 28.99,168.49 ; PT4704.1 28.99,170.6 ; PT4704.1 27.93,169.54 ; v3(132.24,217.93) 132.24,219.12 124.23,227.13 13.92,227.13 11.44,224.65 11.44,219.35 12.23,218.57 17.18,218.57 v3(17.56,218.19) ; PC5427.1 v3(153.3,208.79)
  vias: v2(32.55,168.53) v2(32.93,174.12) v5(27.77,170.97) v5(30.51,172.85) v5(30.59,171.78) v5(30.56,170.74) v5(30.64,169.54) v5(31.53,172.85) v5(31.61,171.78) v5(31.58,170.74) v5(31.66,169.54) v5(32.55,172.85) v5(32.62,171.78) v5(32.6,170.74) v5(32.67,169.54) v5(33.56,172.85) v5(33.69,170.69) v5(33.76,171.78) v5(33.82,169.54) v5(34.58,172.85) v5(34.83,171.83) v5(34.83,170.69) v5(34.83,169.54) v5(38.82,173.61) v5(38.9,170.87)
VDDNB_TRACK_GATE: length 29
  TOP w0.102: v3(144.08,205.52) 143.16,204.6 143.16,201.1 R4708.2
  L3 w0.127: v3(152.43,215.01) 152.27,215.01 151.8,215.48 150.59,215.48 146.72,211.61 146.72,208.15 v3(144.08,205.52)
  BOTTOM w0.102: v3(152.43,215.01) v2(152.43,214.12) 152.43,212.47 153.31,211.6 Q6703.3 154.53,211.9 154.72,212.09 157.45,212.09 157.71,211.84 Q6703.4
VDDP_SENSE: length 73
  TOP w0.102: CPU1.AY18 v4(83.8,149.9) ; v3(70.77,188.62) 69.94,188.62 v1(69.79,188.77) 69.76,188.81 R1612.1
  L3 w0.127: v3(70.77,188.62) 73.06,186.33 85.23,186.33 86.27,185.29 86.27,182.05 90.52,177.79 90.52,174.79 91.13,174.19 91.13,171.44 91.08,171.39 91.08,169.49 88.98,167.39 78.19,167.39 77.73,166.92 77.73,158.28 79.54,156.47 81.39,156.47 82.88,154.99 82.88,154.13 83.27,153.73 83.59,153.73 83.84,153.49 83.84,149.94 v4(83.8,149.9)
VSS_MECH: length 107.6
  TOP w0.127: GPU1.A32 72.2,111.3 70.76,112.73 70.61,113.74 70.61,114.77 71.92,116.08 73.55,116.08 v1(74,116.53)
  TOP w0.305: v1(74,116.53) 74,116.53 74.57,117.09 v3(74.84,117.09)
  TOP w0.356: GPU1.AM32 v4(93.8,111.38)
  TOP w0.406: GPU1.AM1 94.31,89.2 94.9,89.79 v4(95.92,89.79)
  L3 w0.254: v3(74.84,117.09) 75.86,118.12 86.86,118.12 88.04,116.94 100.46,116.94 v3(100.74,117.22)
  L4 w0.508: v4(95.92,89.79) 105.52,89.79 v3(106.15,89.15)
  BOTTOM w0.254: v3(74.84,117.09) 77.86,117.09 83.35,111.61 83.35,111.53 87.55,107.33 88.45,107.33 89.06,106.72 90.4,106.72 91.35,107.66 91.35,108.93 v4(93.8,111.38)
  BOTTOM w0.508: v3(106.15,89.15) 106.15,93.57 102.9,96.82 102.9,100.57 102.12,101.36 102.12,104.58 103.54,106 103.54,112.95 100.74,115.75 v3(100.74,117.22)
VSS_SENSE: length 22.7
  TOP w0.267: R528.1 73.63,189.99 R80225.1 R1954.1 73.25,191.52 R1861.1 ; R528.1 v3(73.82,189.38) ; R528.1 R529.1 ; v4(78.89,176.6) 79.19,176.3 CPU1.H12
  L4 w0.267: v4(78.89,176.6) 77.99,177.49 77.99,180.65 75.27,183.37 75.27,184.6 74.12,185.76 74.12,186.05 72.98,187.19 72.9,187.27 72.9,188.46 73.6,189.16 73.6,189.16 v3(73.82,189.38)
  BOTTOM w0.267: v3(73.82,189.38) v2(73.82,190.2)
0D95V_S0: length 239.3
  TOP w0.356: CPU1.AE5 v4(73.7,162.2) CPU1.AE6
  TOP w0.508: 48.8,134.87 51.72,134.87 52.99,136.14 C94.2 53.29,137.58 55.98,137.58 56.19,137.79 57.89,137.79 60.87,140.77 v3(60.87,141.78) ; v3(70.03,205.33) 68.49,203.79 v3(68.49,195.33) 68.49,193.17 62.64,187.32 62.64,179.47 59.09,175.91 R557.2 R558.1 ; v3(63.79,146.94) 63.99,146.94 64.24,147.19 64.87,147.19 R586.1
  L3 w0.457: v3(68.49,195.33) 69.63,196.47 71.54,196.47 71.92,196.1 71.92,193.84 71.49,193.42 70.26,193.42 69,192.17 69,188.7 73.27,184.43 73.83,184.43 77.54,180.72 85.53,180.72 86.42,179.83 86.42,179.31 90.13,175.6 90.13,174.63 90.74,174.02 90.74,173.68 90.44,173.38 89.66,173.38 89.32,173.04 89.32,172.01 90.08,171.25 90.08,169.42 89.19,168.53 88.71,168.53 87.95,167.78 77.85,167.78 77.34,167.27 77.34,165.54 76.64,164.85 76.64,162.84 77,162.48 77,160.05 ; 77,160.05 75.64,161.4 75.17,161.4 74.37,162.2 v4(73.7,162.2) ; 77,160.05 77,158.12 79.69,155.42 80.65,155.42 81.87,154.19 81.87,154 83.42,152.45 v4(83.42,151.71)
  L4 w0.508: v3(63.79,146.94) 63.63,146.79 63.3,146.79 62.49,145.97 61.41,145.97 60.87,145.43 v3(60.87,141.78)
  BOTTOM w0.508: C1696.1 73.12,161.62 v4(73.7,162.2) ; 68.87,211.33 68.23,211.96 v2(68.23,213.16) 68.23,224.66 66.4,226.5 14.18,226.5 12.07,224.38 12.07,220.6 12.83,219.84 15.64,219.84 15.84,220.04 R527.2 ; 68.87,211.33 67.98,211.33 66.45,209.8 66.45,206.63 67.75,205.33 v3(70.03,205.33) ; 68.87,211.33 R1989.1
  vias: v1(47.28,136.65) v1(79.79,125.6) v2(82.96,123.57) v2(86.14,151.13) v2(106.21,147.65) v2(106.15,135.69) v4(84.82,151.84) v5(47,134.75) v5(47.15,135.66) v5(48.04,134.75) v5(48.06,135.66) v5(79.51,124.08) v5(80.25,123.32) v5(80.93,124.21) v5(81.06,122.56) v5(81.57,123.44) v5(81.82,121.79) v5(82.33,122.68) v5(97.62,136.19) v5(97.95,135.25) v5(98.59,136.14) v5(99.09,135.25)
0D95V_S0_EN: length 6.2
  TOP w0.102: R174.2 53.94,140.46 v1(52.22,140.46) 51.47,140.46 50.07,139.06 50.07,138.56
0D95V_S5: length 121.7
  TOP w0.254: PG4801.2 42.07,151
  TOP w0.356: CPU1.AN12 v4(78.2,156) CPU1.AP12
  TOP w0.508: v4(63.03,160.66) 65.79,163.42 65.79,166.51 62.82,169.48 R559.2 ; PT4801.1 49.22,151.26 ; PT4801.1 47.11,151.26 ; PT4801.1 48.17,150.2 ; PT4801.1 48.17,152.31 ; v3(20.35,162.53) 17.41,162.53 16.73,163.21 PR83.1
  L3 w0.254: v4(69.6,157.15) 70.27,156.48 77.72,156.48 v4(78.2,156) 78.2,150.89 77.78,150.47 75.61,150.47 75.09,149.94 75.09,149.53 74.34,148.78 73.73,148.78 72.98,148.04 72.12,148.04 67.19,143.11 65.97,143.11 65.46,142.6 65.46,141.89 65.11,141.54 63.11,141.54 61.83,142.83 57.64,142.83 57.08,142.27 42.83,142.27 v5(42.58,142.52)
  BOTTOM w0.254: v4(69.6,157.15) 69.6,157.83 70.08,158.32 70.08,159.57 68.99,160.66 v4(63.03,160.66)
  BOTTOM w0.508: v5(41.03,156.97) 41.03,157 39.07,158.95 39.07,165.18 38.26,165.99 27.21,165.99 v2(25.88,164.66) 23.76,162.53 v3(20.35,162.53) ; v4(78.2,156) 78.01,155.81 C1703.1
0D95V_VGA_S0: length 76.9
  TOP w0.508: v3(91.73,86.23) v3(91.73,88.63) ; L51.1 v3(73.34,80.65)
  L4 w0.508: v3(105.32,89.03) 92.13,89.03 v3(91.73,88.63)
  BOTTOM w0.508: v3(91.73,86.23) 91.7,86.26 87.79,86.26 86.05,84.52 86.05,83.02 86.05,82.49 82.68,79.12 77.78,79.12 77.63,79.27 74.71,79.27 v3(73.34,80.65) ; v3(105.32,89.03) 105.32,93.4 102.27,96.44 102.27,100.31 101.48,101.09 101.48,104.85 102.9,106.27 102.9,112.69 100.4,115.19 97.44,115.19 ; L53.1 89.19,90.17 90.18,90.17 v3(91.73,88.63)
  vias: v1(95.03,115.57) v2(85.89,104.14) v2(95.03,115.19) v4(79.35,107.07) v4(80.47,105.64) v4(80.51,104.96) v4(81.07,104.07) v4(82.98,103.81) v4(83.79,103.92) v5(94.75,114.07) v5(94.75,112.93) v5(95.92,114.07) v5(95.92,112.93)
0P95V_MAIN_APU_M: length 4.3
  BOTTOM w0.102: R527.1 13.5,220.85 13.11,221.23 v2(13.11,222) 13.27,222.15 Q52.B
1D5V_S3_PG_1: length 5.5
  TOP w0.102: R1774.1 62.2,148.4 62.64,147.96 62.64,147.42 v3(62.59,147.37) 62.35,147.13 D20.1
  BOTTOM w0.102: v2(60.99,145.8) 62.57,147.37 v3(62.59,147.37)
1D5V_S5: length 197.4
  TOP w0.508: R79693.1 86.39,117.83 v3(87.05,117.18) ; v3(157.89,101.35) 158.61,101.35 159.55,100.41 159.55,95.33 156.84,92.63 156.84,89.64 157.2,89.28 R205.1 ; R1601.2 v3(88.43,134.72)
  L4 w0.508: 73.03,121.49 73.03,120.89 76.74,117.18 v3(87.05,117.18) 96.99,117.18 100.9,121.09 132.43,121.09 134.04,119.48 v3(134.04,110.87)
  L4 w1.016: 73.03,121.49 73.03,121.83 73.52,122.32 73.52,128 ; 73.52,128 77,131.48 85.19,131.48 v3(88.43,134.72) ; 73.52,128 61.34,128 60.49,127.15 60.49,123.98 v5(59.72,123.22)
  BOTTOM w0.508: v3(157.89,101.35) 157.89,102.36 153.32,106.93 137.53,106.93 134.04,110.42 v3(134.04,110.87)
  BOTTOM w1.016: 57.03,123.22 56.32,123.93 56.05,123.93 54.41,125.57 54.41,127.87 48.93,133.35 46.99,133.35 45.79,134.55 45.79,136.89 41.61,141.07 38.67,141.07 v5(35.72,144.02) ; 57.03,123.22 v5(59.72,123.22) ; 57.03,123.22 v2(57.06,123.19)
1D8V_S0: length 337.1
  TOP w0.356: CPU1.AP16 v4(83,156) CPU1.AP18
  TOP w0.406: R2032.2 37.07,118.75 37.85,117.96 39.71,117.96 40.75,119 40.75,123.27 42.32,124.84
  TOP w0.508: R1630.2 86.01,195.88 v3(86.06,195.94) ; R1998.2 R2002.2 v3(80.93,195.94) 81.1,195.94 81.59,196.42 81.59,196.97 81.02,197.55 R2023.1 ; C315.1 40.29,124.84 39.05,126.09 39.05,130.23 39.76,130.94 39.76,133.25 39.4,133.6 R2031.2 ; R2028.1 73.19,141.2 v3(73.64,140.74) ; v3(81.69,225.22) 80.09,226.82 31.17,226.82 30.54,226.19 30.54,225 30.04,224.5 30.04,223.3 29.75,223.01 29.75,222.08 v3(29.99,221.85) ; v3(84.95,223.9) 92.33,223.9 93.22,224.79 v3(95.16,224.79) ; R1610.2 81.95,192.02 82.56,192.63 83.62,192.63 84.39,191.87 v3(85,191.87) R495.1 R1720.2 ; v3(97.57,222.76) Q1210.S 97.04,224 96.49,223.46 R504.1 R1698.1 ; R2022.2 77.76,192.91 78.04,192.63 v3(78.9,192.63) 79.31,192.63 79.92,192.02 R1628.2 ; v3(80.93,187.81) R1632.2 R1617.1 ; R2000.2 v3(85,187.81)
  L3 w0.457: v3(85,187.81) 86.81,185.99 86.81,182.06 89.56,179.32 89.75,179.32 90.92,178.15 90.92,174.96 91.72,174.16 91.72,173.7 92.08,173.33 92.08,158.16 90.44,156.51 87.67,156.51 87.61,156.58 83.58,156.58 v4(83,156)
  L3 w0.508: v3(85,191.87) 85.17,191.87 86.06,192.77 v3(86.06,195.94) ; v3(80.93,187.81) 81.59,187.15 84.34,187.15 v3(85,187.81) ; v3(80.93,195.94) 81.1,195.94 83.37,198.2 83.37,208.77 82.54,209.6 82.54,215.52 v3(83.12,216.1) 82.54,216.68 82.54,217.3 84.95,219.71 v3(84.95,223.9)
  L3 w0.762: v3(90.46,138.3) 88.73,140.03 88.73,142.57 88.6,142.7 88.6,142.7 87.82,143.49 87.82,151.1 86.1,152.82 86.1,153.85 85,154.94 83.73,154.94 83,155.67 v4(83,156)
  L3 w1.016: v5(43.62,126.72) 49.03,126.72 49.63,127.32 55.25,127.32 58.07,124.5 58.07,123.47 59.44,122.1 63.41,122.1 v5(65.21,123.9)
  L4 w0.508: v3(85,191.87) v3(85,187.81) ; v3(90.46,138.3) 89.11,138.3 86.76,135.95 81.05,135.95 77.47,139.54 75.84,139.54 74.58,140.79 73.69,140.79 v3(73.64,140.74) ; v3(78.9,192.63) 79.07,192.63 80.93,194.49 v3(80.93,195.94) 81.59,195.28 81.59,188.47 v3(80.93,187.81) ; v3(84.95,223.9) 83.01,223.9 v3(81.69,225.22)
  L4 w1.016: v5(74.18,121.36) 74.66,121.84 74.66,126.31 78.68,130.34 85.66,130.34 90.46,135.14 v3(90.46,138.3)
  BOTTOM w0.203: v3(83.12,216.1) 83.05,216.17 PU5407.6 ; v3(29.99,221.85) PU4601.6
  BOTTOM w0.508: v3(95.16,224.79) 95.64,224.79 v2(96.6,223.82) 97.57,222.86 v3(97.57,222.76) ; v4(83,156) 83.35,155.66 C1674.1
  BOTTOM w1.016: v5(74.18,121.36) 74.18,120.7 73.41,119.94 66.66,119.94 65.21,121.39 v5(65.21,123.9)
1D8V_S5: length 403.5
  TOP w0.254: PC5213.1 100.3,76.58 PG5211.1 v5(99.65,77.6) ; PC5211.1 PG5212.1 106.66,77.55 v5(106.64,77.57)
  TOP w0.356: v4(77,156) CPU1.AP10 77,154.8 CPU1.AR9
  TOP w0.508: PR5473.1 151.48,202.63 151.93,203.07 v3(151.93,203.71) ; R1595.1 87.16,134.62 86.65,134.11 84.9,134.11 v3(84.74,134.27) ; R1677.1 51.34,157.29 51.34,145.54 52.71,144.17 52.71,142.9 v3(52.74,142.88) 52.2,142.88 50.3,140.97 46.61,140.97 42.63,136.99 42.63,134.7 43.82,133.5 ; PC52.1 159.88,203.91 v3(158.02,202.06)
  TOP w1.016: PR5290.1 21.55,149.68 v5(21.5,149.73)
  L3 w0.508: v4(70.75,149.5) 67.95,149.5 64.55,146.1 64.55,145.88 64.16,145.49 63.94,145.49 63.53,145.08 63.53,144.23 62.79,143.48 57.38,143.48 57.2,143.66 56.42,143.66 55.64,142.88 v3(52.74,142.88)
  L3 w2.032: 45.7,86.53 45.7,120.71 41.97,124.43 41.97,127.41 42.02,127.46 42.02,130.86
  L4 w0.508: v5(111.31,81.53) 111.69,81.53 115.48,77.74 115.48,68.88 116.73,67.63 131.14,67.63 133.79,70.28 133.79,76.54 134.63,77.38 134.63,78.35 133.17,79.81 133.17,98.72 134.91,100.46 134.91,100.47 135.03,100.6 135.03,107.32 v3(136.56,108.84) ; v4(70.75,149.5) 70.65,149.4 70.65,145.11 69.68,144.15 v3(69.68,141.91) ; v3(158.02,202.06) 158.02,201.05 161.31,197.76 162.43,197.76 165.44,194.76 165.44,136.98 166.17,136.25 166.17,114.43 166.17,111.94 164.5,110.26 164.5,105.81 164.01,105.32 161.74,105.32 160.43,104.01 159.16,104.01 v3(159.14,103.99)
  BOTTOM w0.508: v3(159.14,103.99) 155.56,107.57 137.83,107.57 v3(136.56,108.84) ; v4(77,156) 77.06,155.94 C1828.1 77.06,153.84 76.74,153.52 C1677.1 76.88,152.51 C1957.1 76.88,151.33 76.43,150.88 75.84,150.88 74.98,150.01 74.98,149.81 74.45,149.29 70.96,149.29 v4(70.75,149.5) ; v3(84.74,134.27) 84.17,133.71 83.2,133.71 82.63,134.27 82.63,134.64 80.73,136.54 80.26,136.54 77.32,139.48 76.45,139.48 76.29,139.32 74.05,139.32 71.92,141.45 70.14,141.45 v3(69.68,141.91) ; v3(158.02,202.06) 155.35,202.06 154.96,202.45 PU5.1 153.64,203.07 153,203.71 v2(152.81,203.71) v3(151.93,203.71)
  BOTTOM w1.016: v5(42.55,133.04) 42.55,136.91 42.83,137.19 42.83,138.24 41.27,139.8 37.9,139.8 33.94,143.76 27.47,143.76 v5(21.5,149.73)
  vias: v5(41.05,132.18) v5(51.09,81.53) v5(51.72,80.64) v5(78.65,75.56) v5(79.66,75.56) v5(80.68,75.56) v5(100.74,75.31) v5(100.74,74.3) v5(110.29,81.53) v5(110.4,82.55)
1D8V_VGA_S0: length 106.8
  TOP w0.508: 98.8,101.24 R1900.2 ; 98.8,101.24 99.81,101.24 R935.1 ; 98.8,101.24 v4(98.8,101.98) ; L49.1 74.61,80.67 v3(74.58,80.65) ; v3(101.2,107.24) 101.4,107.44 102.9,107.44 103.22,107.76 103.22,114.11 100.97,116.36 97.82,116.36 97.69,116.23
  BOTTOM w0.508: L50.1 79.88,87.44 79.29,86.86 78.01,86.86 78.01,86.86 78.01,86.92 v2(77.99,86.94) 77.96,86.91 77.96,86.86 77.38,86.28 77.38,85.73 76.6,84.95 75.94,84.95 73.77,82.78 73.77,81.46 v3(74.58,80.65) 75.32,79.91 77.89,79.91 78.05,79.76 82.41,79.76 85.42,82.76 85.42,84.77 87.52,86.87 96.74,86.87 97.22,86.39 100.74,86.39 101.89,87.53 v5(103.18,87.53) ; L48.1 94.29,105.14 95.78,103.65 R943.2 R388.2 96.48,102.06 96.96,101.57 98.27,101.57 98.33,101.51 ; 98.33,100.08 98.27,100.01 L47.1 ; 98.33,96.9 98.07,96.64 R1211.2 95.46,95.65 95.46,92.84 95.03,92.41 93.52,92.41 92.47,93.45 L52.1 ; v3(101.2,107.24) 98.8,104.84 v4(98.8,101.98)
  BOTTOM w1.016: v5(103.18,87.53) 103.18,88.65 102.53,89.3 102.53,91.94 100.87,93.6 100.87,94.36 98.33,96.9 98.33,101.51 v4(98.8,101.98)
1D35V_S3: length 284.9
  TOP w0.25: CPU1.AB33 96.4,165 96.4,165 v4(96.45,165) ; v4(96.45,158.57) 96.42,158.6 CPU1.AK33 ; v4(94.08,166.5) 94.02,166.5 93.92,166.6 CPU1.Y30 ; CPU1.V30 94.11,168.2 v4(94.13,168.22) ; CPU1.AF33 96.37,161.8 v4(96.42,161.85) ; v4(94.1,160.2) CPU1.AH30 ; CPU1.AM30 v4(94.14,157) ; v4(94.09,158.62) 94.06,158.6 CPU1.AK30 ; v4(96.43,168.35) 96.34,168.26 95.56,168.26 CPU1.V33 ; CPU1.AD30 v4(94.1,163.4) ; v4(93.12,165.4) 93.12,165.38 CPU1.AB30
  TOP w0.254: 135.03,110.62 134.15,109.73 PG5001.1
  TOP w0.33: DIMM1.124 138.47,151.25 v3(135.8,153.92) ; v3(152.31,155.96) 152.5,156.15 152.5,156.19 152.95,156.65 DIMM2.106 ; DIMM2.105 147.25,156.95 147.99,156.21 v3(147.99,155.96) ; v3(134.02,162.94) 134.02,163.07 132.94,164.15 DIMM1.81 ; DIMM2.87 147.18,162.35 147.99,161.55 v3(147.99,161.29) ; v3(134.02,164.85) 134.02,164.97 133.04,165.95 DIMM1.75 ; v3(152.31,163.19) 152.5,163.39 152.5,163.43 152.91,163.85 DIMM2.82 ; v3(152.3,159.64) 152.3,159.66 152.31,159.66 152.31,159.87 152.69,160.25 DIMM2.94 ; DIMM2.88 153.02,162.05 152.5,161.53 152.5,161.48 v3(152.31,161.29) ; DIMM2.124 153.16,151.25 152.5,151.91 152.5,151.96 v3(152.31,152.27) 152.5,152.46 152.5,152.51 153.04,153.05 DIMM2.118 ; DIMM2.81 147.18,164.15 147.99,163.35 v3(147.99,163.19) ; DIMM2.111 147.34,155.15 147.99,154.51 v3(147.99,154.05) 147.29,153.35 ; DIMM1.106 138.52,156.65 138.52,156.65 v3(137.83,155.83) ; DIMM1.118 138.62,153.05 137.83,153.84 v3(137.83,153.92) 137.83,154.18 138.5,154.85 DIMM1.112 ; v3(137.83,157.73) 137.83,157.99 138.29,158.45 DIMM1.100 ; v3(133.51,153.92) 133.51,153.97 132.33,155.15 DIMM1.111 130.16,155.15 129.83,154.81 129.83,153.67 130.15,153.35 DIMM1.117 ; 152.96,165.67 152.83,165.67 152.5,165.34 152.5,165.29 v3(152.31,165.1) ; 152.96,165.67 152.5,166.13 152.5,166.18 v3(152.31,167) ; 152.96,165.67 153.31,165.67 153.33,165.65 DIMM2.76 ; DIMM1.82 138.48,163.85 137.83,163.19 v3(137.7,163.19) ; v3(134.02,155.83) 134.02,155.88 132.94,156.95 DIMM1.105 ; DIMM1.99 132.03,158.75 133.66,157.13 134.98,157.13 135.35,157.5 135.35,157.54 v3(135.54,157.73) ; DIMM2.99 147.23,158.75 v3(147.99,157.99) ; DIMM1.93 132.65,160.55 134.02,159.18 v3(134.02,159.13) ; 147.29,153.35 DIMM2.117 ; 147.29,153.35 147.34,153.35 147.99,152.71 v3(147.99,152.15) 147.39,151.55 DIMM2.123 ; DIMM2.100 153.02,158.45 v3(152.56,157.99) ; v3(147.99,165.1) 147.99,165.23 147.26,165.95 DIMM2.75 ; DIMM1.88 138.59,162.05 137.83,161.29 v3(137.83,161.16) ; v3(147.99,159.38) 147.99,159.75 147.18,160.55 DIMM2.93 ; DIMM1.123 133.01,151.55 135.03,149.53 v3(135.03,149.48) ; v3(134.02,161.42) 134.02,161.46 133.4,162.08 132.34,162.08 132.07,162.35 DIMM1.87 ; DIMM1.94 138.62,160.25 137.96,159.59 137.96,159.51 v3(137.83,159.38) ; DIMM1.76 138.25,165.65 137.7,165.1 v3(137.55,165.1) ; DIMM2.112 153.06,154.85 152.5,154.29 152.5,154.24 v3(152.31,154.05)
  TOP w0.356: CPU1.AE27 91.1,162.8 v4(91.5,163.2) 91.9,163.6 CPU1.AD28 ; CPU1.AK25 89,158.5 v4(88.93,158.5) ; CPU1.W24 v4(88.95,167.95) 89.5,168.5 CPU1.U25 ; CPU1.AG25 89.5,161.3 v4(88.95,160.75) CPU1.AH24 ; CPU1.AH27 91.1,160.4 v4(91.5,160.8) 91.9,161.2 CPU1.AG28 ; CPU1.AB27 91.1,165.24 v4(91.47,165.61) 91.9,166.03 CPU1.Y28 ; CPU1.P28 91.9,170.8 v4(91.5,170.4) 91.1,170 CPU1.T27 ; CPU1.AD25 89.5,163.7 v4(88.95,163.15) CPU1.AE24 ; CPU1.U28 91.9,168.4 v4(91.5,168) 91.1,167.6 CPU1.W27 ; v3(93,162.05) 93.25,161.8 CPU1.AF30 ; CPU1.T24 v3(88.95,170.35) 89.5,170.9 CPU1.P25 ; CPU1.Y25 89.5,166.1 v4(88.95,165.55) CPU1.AB24 ; CPU1.AL27 91.1,158 v4(91.5,158.4) 91.9,158.8 CPU1.AK28
  TOP w0.508: PT5007.1 136.81,111.67 ; PT5007.1 137.87,110.62 ; PT5007.1 136.81,109.56 ; PT5007.1 135.76,110.62 ; 135.42,110.62 135.03,110.62
  TOP w1.016: PR5021.1 PR5020.1 141.46,84.91 141.89,85.34 v5(142.78,85.34)
  L3 w0.508: v3(152.31,167) 152.31,168.28 155.86,171.83 155.86,176.02 156.75,176.91 156.75,186.61 153.11,190.25 145.96,190.25 v3(142.91,193.29)
  L3 w1.016: v5(142.78,85.34) 141.89,85.34 141.74,85.19 132.9,85.19 131.22,86.87 131.22,96.39 133.05,98.22 133.05,99.87 v3(134.15,100.97)
  L4 w1.016: PT5007.1 136.81,110.49 133.21,106.88 133.21,101.9 v3(134.15,100.97)
  BOTTOM w0.508: C1692.1 89.17,160.53 v4(88.95,160.75) ; v3(147.99,159.38) 148.18,159.58 C1974.1 ; C1876.1 137.64,165.19 v3(137.55,165.1) 137.64,165.01 C1875.1 ; C1961.1 152.81,165.99 152.31,165.48 v3(152.31,165.1) ; C337.1 133.26,165.99 134.02,165.23 v3(134.02,164.85) 134.02,164.59 133.51,164.08 C353.1 ; v3(137.83,161.16) 137.64,160.97 C1872.1 ; 102.52,158.37 105.01,155.88 105.93,155.88 v2(105.98,155.93) 107.39,155.93 R1586.1 ; R1633.1 142.4,192.79 v3(142.91,193.29) 143.42,192.79 R2057.1 ; v3(147.99,161.29) 148.18,161.48 C1969.1 ; C1963.1 152.94,162.18 152.31,161.54 v3(152.31,161.29) ; v3(133.51,153.92) 133.51,153.54 133,153.03 C1725.1 ; v4(88.93,158.5) 89.19,158.24 C1693.1 ; v3(147.99,165.1) 148.18,165.29 C1967.1 ; v4(88.95,163.15) 89.29,162.81 C1691.1 ; C60.1 132.49,156.97 132.97,156.5 133.73,156.5 134.02,156.21 v3(134.02,155.83) 134.02,155.57 133.38,154.94 C1723.1 ; C46.1 132.11,159.38 132.62,159.89 133.51,159.89 134.02,159.38 v3(134.02,159.13) ; C1689.1 89.26,167.64 v4(88.95,167.95) ; v3(152.31,152.27) 152.31,152.53 151.48,153.35 R2059.1 ; v3(152.31,163.19) 152.31,163.58 152.81,164.08 C1962.1 ; C1978.1 148.18,154.24 v3(147.99,154.05) 147.23,153.29 C1973.1 146.91,153.35 R120.1 ; C1690.1 89.27,165.23 v4(88.95,165.55) ; C1964.1 153.58,156.97 v3(152.56,157.99) 153.96,159.38 C1966.1 ; C1694.1 89.42,170.81 v3(88.95,170.35) 89.37,169.93 C356.1 ; v3(147.99,163.19) 148.18,163.39 C1968.1 ; v3(134.02,162.94) 134.02,162.69 133.51,162.18 C392.1 ; v3(137.7,163.19) 137.64,163.13 C1874.1 ; C1871.1 137.64,155.64 v3(137.83,155.83) 137.64,156.02 C1873.1 ; v3(147.99,155.96) 148.18,156.15 C1970.1 ; C55.1 138.59,153.16 v3(137.83,153.92) ; C1965.1 152.69,154.94 152.31,154.56 v3(152.31,154.05) 152.31,153.8 153.07,153.03 C1972.1
  vias: v3(141.64,165.1) v3(141.77,163.19) v3(141.77,161.29) v3(141.77,159.38) v3(141.77,155.96) v3(141.77,154.05) v3(141.77,152.15) v3(143.92,167) v3(143.92,165.1) v3(144.05,163.19) v3(144.05,161.29) v3(144.05,159.38) v3(144.05,155.96) v3(144.05,154.05) v3(144.05,152.15) v3(144.81,159.38) v4(97.29,163.73) v4(97.34,156.87) v4(97.38,160) v4(97.7,168.15) v4(98.08,172.72) v4(98.08,165.23) v4(98.33,161.8) v4(98.37,171.07) v4(98.71,159.51) v4(98.84,158.37) v4(98.98,165.73) v4(98.97,160.78) v4(99.22,169.42) v4(99.22,163.7) v4(100.11,171.45) v4(100.21,161.72) v4(100.33,159.36) v4(100.62,157.1) v4(100.71,168.82) v4(100.92,163.12) v4(101.12,165.34) v4(102.47,166.59) v4(102.67,169.28) v4(102.9,163.07) v4(105.57,163.07) v5(141.51,121.18) v5(142.53,121.18) v5(143.54,121.18) v5(144.56,121.18) v5(145.58,121.18) v5(146.59,121.18) v5(158.02,166.6) v5(158.02,165.33) v5(158.02,164.06) v5(158.02,162.79) v5(158.02,161.52) v5(158.02,160.25) v5(158.02,158.98) v5(158.02,157.71)
1D35V_VGA_S0: length 188.5
  TOP w0.203: v4(58.42,96.39) 58.42,95.84 58.81,95.45 MEM2.N1 ; MEM1.H9 59.49,111.41 60.69,111.41 60.89,111.61 61.78,111.61 ; MEM1.D2 52.83,114.9 v4(51.99,114.9) ; MEM2.H2 58.28,91.48 58.41,91.61 58.41,92.43 MEM2.K2 ; MEM1.H2 53.2,112.08 52.82,112.47 52.59,112.47 52.58,112.47 52.25,112.47 52.24,112.47 52.1,112.47 51.91,112.27 v4(51.88,112.27) ; v4(58.41,111.68) 58.41,111.68 58.41,111.12 58.07,110.78 58.07,110.54 MEM1.K8 57.62,110.09 57.62,108.72 57.86,108.47 58.2,108.47 58.52,108.15 58.75,108.15 MEM1.N9
  TOP w0.305: MEM2.A1 MEM2.B2 58.01,86.42 57.61,86.02 v4(57.61,86.01) ; GPU1.L13 GPU1.L12 78.3,96.3 v4(78.3,96.12) 78.3,96.11 78.6,95.81 GPU1.L11 ; MEM2.H9 52.23,91.22 52.05,91.04 ; MEM2.C9 51.69,87.22 v4(51.6,87.31) ; v4(52.82,87.62) 52.41,88.02 MEM2.D9 MEM2.E9 51.9,89.33 51.6,89.33 51.27,89.66 ; MEM2.H2 58.01,91.21 v4(57.61,90.81) ; MEM2.D2 58,88.02 57.63,88.4 v4(57.63,88.43) ; MEM1.B2 MEM1.C1 52.28,116.08 51.96,116.4 v4(51.95,116.4) ; v4(57.61,93.22) 57.61,93.22 MEM2.K2 ; v4(52.5,84.77) 52.6,84.77 53.21,85.39 MEM2.A8 ; MEM1.E9 58.81,114.29 59.33,113.78 59.33,113.72 59.59,113.45 v4(59.59,113.45) ; v4(51.75,95.7) 51.94,95.7 MEM2.N9 ; v4(54.51,90.76) 54.33,90.76 54.01,90.44 MEM2.G7 ; MEM2.K8 52.81,92.42 v4(52.81,92.42) ; MEM1.H9 58.81,112.08 v4(58.41,111.68) ; MEM2.C1 59.18,87.22 v4(59.36,87.4) 59.74,87.78 59.74,87.78 60.14,88.18 60.14,88.53 v4(60.16,88.55) ; v4(58.42,96.39) 58.81,96.78 MEM2.R1
  TOP w0.356: MEM1.K8 58.42,110.08 v4(58.45,110.08) ; v4(59.22,106.1) 59.2,106.1 MEM1.R9 59.32,106.99 v4(59.32,107.67) 59.23,107.67 MEM1.N9 ; v4(77.4,94.41) 77.01,94.8 GPU1.J10 ; v4(77.4,94.41) 77.8,94.01 GPU1.K9 ; v4(77.4,94.41) 77.79,94.8 GPU1.K10 ; v4(77.4,94.41) 77,94.01 GPU1.J9 ; GPU1.K23 77.8,105.21 v4(77.41,105.6) ; GPU1.H16 75.87,99.73 v4(75.87,99.95) ; v4(59.36,90.75) 59.36,90.16 MEM2.F1 ; v4(76.58,101.38) 76.2,101.76 GPU1.H19 ; GPU1.H13 76.2,97.04 75.93,97.31 75.93,97.38 v4(75.88,97.43) ; GPU1.K24 77.8,105.99 v4(77.41,105.6) ; MEM1.G7 57.07,112.88 56.82,113.12 56.82,113.22 56.81,113.23 v4(56.81,113.27) ; v4(51.06,90.42) 51.56,90.93 51.94,90.93 52.05,91.04 ; v4(78.08,102.53) 78.12,102.53 78.25,102.4 GPU1.L20 ; v4(77.41,105.6) 77.01,105.2 GPU1.J23 ; v4(77.41,105.6) 77.01,106 GPU1.J24 ; GPU1.L22 78.6,104.3 78.09,103.79 v4(78.09,103.55) 78.18,103.55 78.32,103.4 GPU1.L21 ; MEM1.D9 58.81,115.28 v4(58.41,114.89) 58.81,114.49 MEM1.E9 ; MEM1.N1 52.35,108.08 52.21,108.23 51.62,108.23 v4(51.61,108.24) ; v4(57.62,117.28) 58.01,117.67 MEM1.A8 ; v4(60.06,115.89) 59.35,115.89 59.16,116.08 MEM1.C9 ; v4(51.78,113.65) 51.81,113.68 MEM1.F1 ; v4(53.61,110.08) MEM1.K2 ; MEM1.R1 52.12,106.77 51.91,106.77 51.89,106.79 v4(51.89,106.79)
  TOP w0.508: TC21.1 59.13,77.34 ; TC21.1 58.07,76.29 ; TC21.1 57.02,77.34 ; TC21.1 58.07,78.4 ; R79692.1 86.84,121.48 86.57,121.75 84.21,121.75 82.96,120.5 v3(82.96,116.2) ; R1890.1 R1200.1 76.73,116.31 v3(75.85,116.31) ; v4(59.22,106.1) 60.48,106.1 60.9,106.52 60.9,107.56 61.78,108.44 61.78,112.76 61.79,112.77 61.79,113.23 61.32,113.7 59.89,113.7 59.64,113.45 v4(59.59,113.45) ; 62.14,80.77 PR79.2
  L3 w0.508: v4(67.34,118.11) 67.14,118.31 66.5,118.31 v4(59.4,118.31) 59.4,118.23 59.39,118.22 59.39,118.06 58.93,117.61 57.95,117.61 v4(57.62,117.28) 58.23,116.67 58.23,115.07 v4(58.41,114.89) 58.67,115.15 58.67,115.15 59.36,115.84 60.01,115.84 v4(60.06,115.89)
  L4 w0.305: v4(57.61,90.81) 58.11,91.31 58.81,91.31 v4(59.36,90.75)
  BOTTOM w0.152: MEM4.E9 58.76,88.87 58.48,88.87 58.18,89.18 57.87,89.18 57.63,88.94 v4(57.63,88.43)
  BOTTOM w0.203: MEM4.H2 52.81,90.81 51.93,90.81 ; MEM4.H2 53.6,91.6 54.17,91.6 54.51,91.27 v4(54.51,90.76) ; MEM4.H2 52.81,91.63 52.81,92.18 v4(52.81,92.42) ; v4(57.61,93.22) 57.61,94.56 57.89,94.84 58.17,94.84 58.55,95.22 MEM2.N1 ; MEM1.K8 58.01,110.59 58.08,110.65 58.08,110.69 58.41,111.02 v4(58.41,111.68) ; MEM3.H2 57.61,111.67 57.06,111.67 56.81,111.92 56.81,113.23 56.81,113.23 v4(56.81,113.27) ; MEM3.G7 53.61,112.47 52.81,112.47 MEM3.H9
  BOTTOM w0.229: MEM2.N1 58.81,95.45 58.42,95.84 58.42,96.18 58.42,96.19 v4(58.42,96.39)
  BOTTOM w0.305: 59.23,88.41 59.22,88.41 MEM4.E9 ; 59.23,88.41 60.02,88.41 v4(60.16,88.55) 60.86,89.25 60.86,89.53 60.87,89.53 ; 59.23,88.41 58.84,88.02 MEM4.D9 ; v4(52.81,92.42) 52.81,92.42 MEM2.K8 ; 60.92,90.17 60.87,90.13 59.72,90.13 59.36,90.49 v4(59.36,90.75) 58.89,91.22 MEM4.H9 ; v4(51.61,108.24) 52.25,108.24 MEM1.N1 ; MEM2.C1 59.18,87.22 v4(59.36,87.4) ; v4(51.89,106.79) 52.2,106.48 MEM1.R1 ; v4(57.61,90.81) 57.57,90.81 57.21,90.45 MEM4.G7 ; v4(57.61,93.22) 58.01,92.82 MEM2.K2
  BOTTOM w0.356: v4(51.95,116.4) 51.98,116.4 52.03,116.35 52.05,116.35 52.32,116.08 MEM1.C1 ; v4(53.61,110.08) MEM1.K2 ; MEM3.D2 58.02,115.28 v4(58.41,114.89) ; v4(59.59,113.45) 59.59,113.45 59.59,113.49 59.41,113.68 MEM3.F1 ; v4(59.4,118.31) 59.4,118.09 58.99,117.68 MEM3.A1 ; MEM1.R9 58.84,106.48 v4(59.22,106.1) ; MEM3.E9 52.41,114.54 52.06,114.89 52,114.89 v4(51.99,114.9) 51.99,114.9 52.37,115.28 MEM3.D9 ; v4(51.88,112.27) 51.89,112.27 52.08,112.08 MEM3.H9 ; MEM1.K8 58.42,110.08 v4(58.45,110.08) ; v4(58.42,96.39) 58.81,96.78 MEM2.R1 59.39,96.82 60.06,96.14 61.07,96.14 61.39,96.46 C776.1 ; v4(59.32,107.67) 59.22,107.76 59.22,107.81 58.96,108.08 MEM1.N9 ; MEM3.H2 v4(58.41,111.68) ; v4(57.61,86.01) 58,85.62 MEM4.A8 ; v4(52.45,118.56) 52.49,118.6 52.89,118.6 53.21,118.27 MEM3.A8 ; v4(57.62,117.28) MEM3.B2 ; v4(60.06,115.89) 59.99,115.89 59.91,115.97 59.26,115.97 59.17,116.06 58.84,116.06 MEM1.C9
  BOTTOM w0.381: v4(51.61,108.24) 51.42,108.24 51,107.82 49.32,107.82 49.26,107.89 R230.2
  BOTTOM w0.508: 48.89,98.78 48.85,98.81 48.85,99.26 48.39,99.71 46.81,99.71 46.05,98.96 46.05,94.34 47.59,92.81 R1924.2 ; v3(82.96,116.2) 80.17,116.2 78.27,118.11 v4(67.34,118.11) 67.34,117.47 68.51,116.31 v3(75.85,116.31) ; R1204.1 v4(85.91,88.43)
  vias: v1(49.31,101.09) v1(50.33,86.74) v2(49.56,115.32) v2(49.81,101.93) v2(50.33,83.87) v2(62.14,101.35) v2(63.03,92.58) v2(72.8,94.36) v3(50.17,118.03) v3(50.17,117.04) v3(50.17,116.17) v3(50.2,89.87) v3(50.22,89.05) v3(50.19,87.83) v3(51.34,99.88) v4(51.71,96.82) v5(50.32,105.1) v5(50.32,103.75)
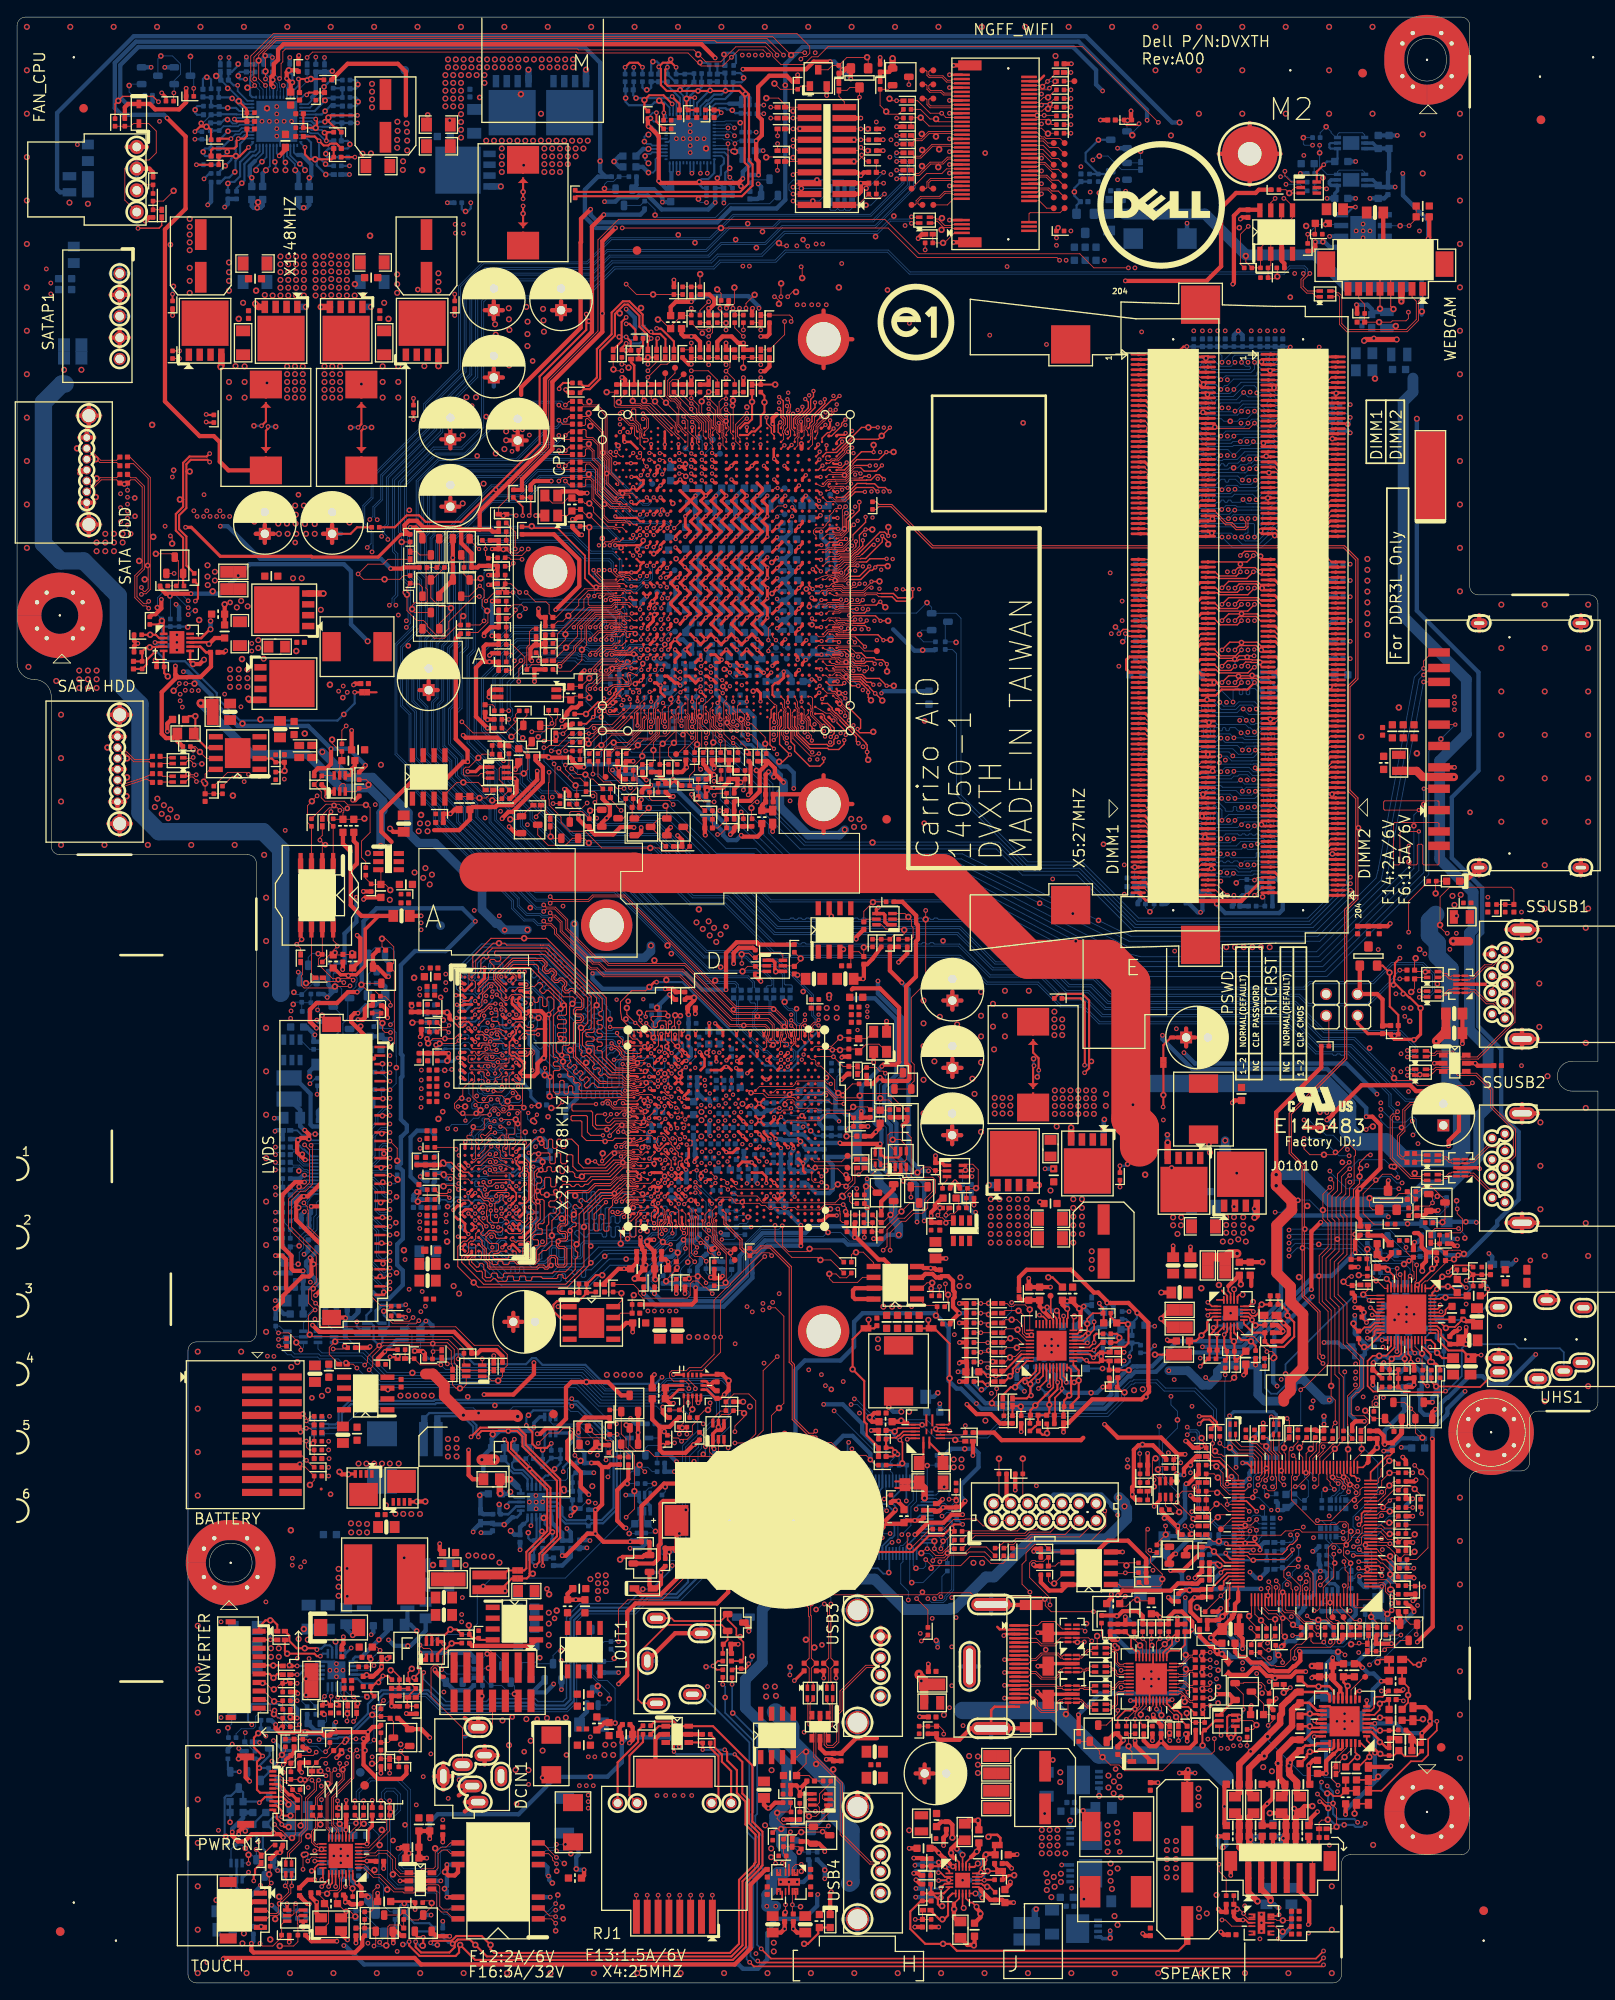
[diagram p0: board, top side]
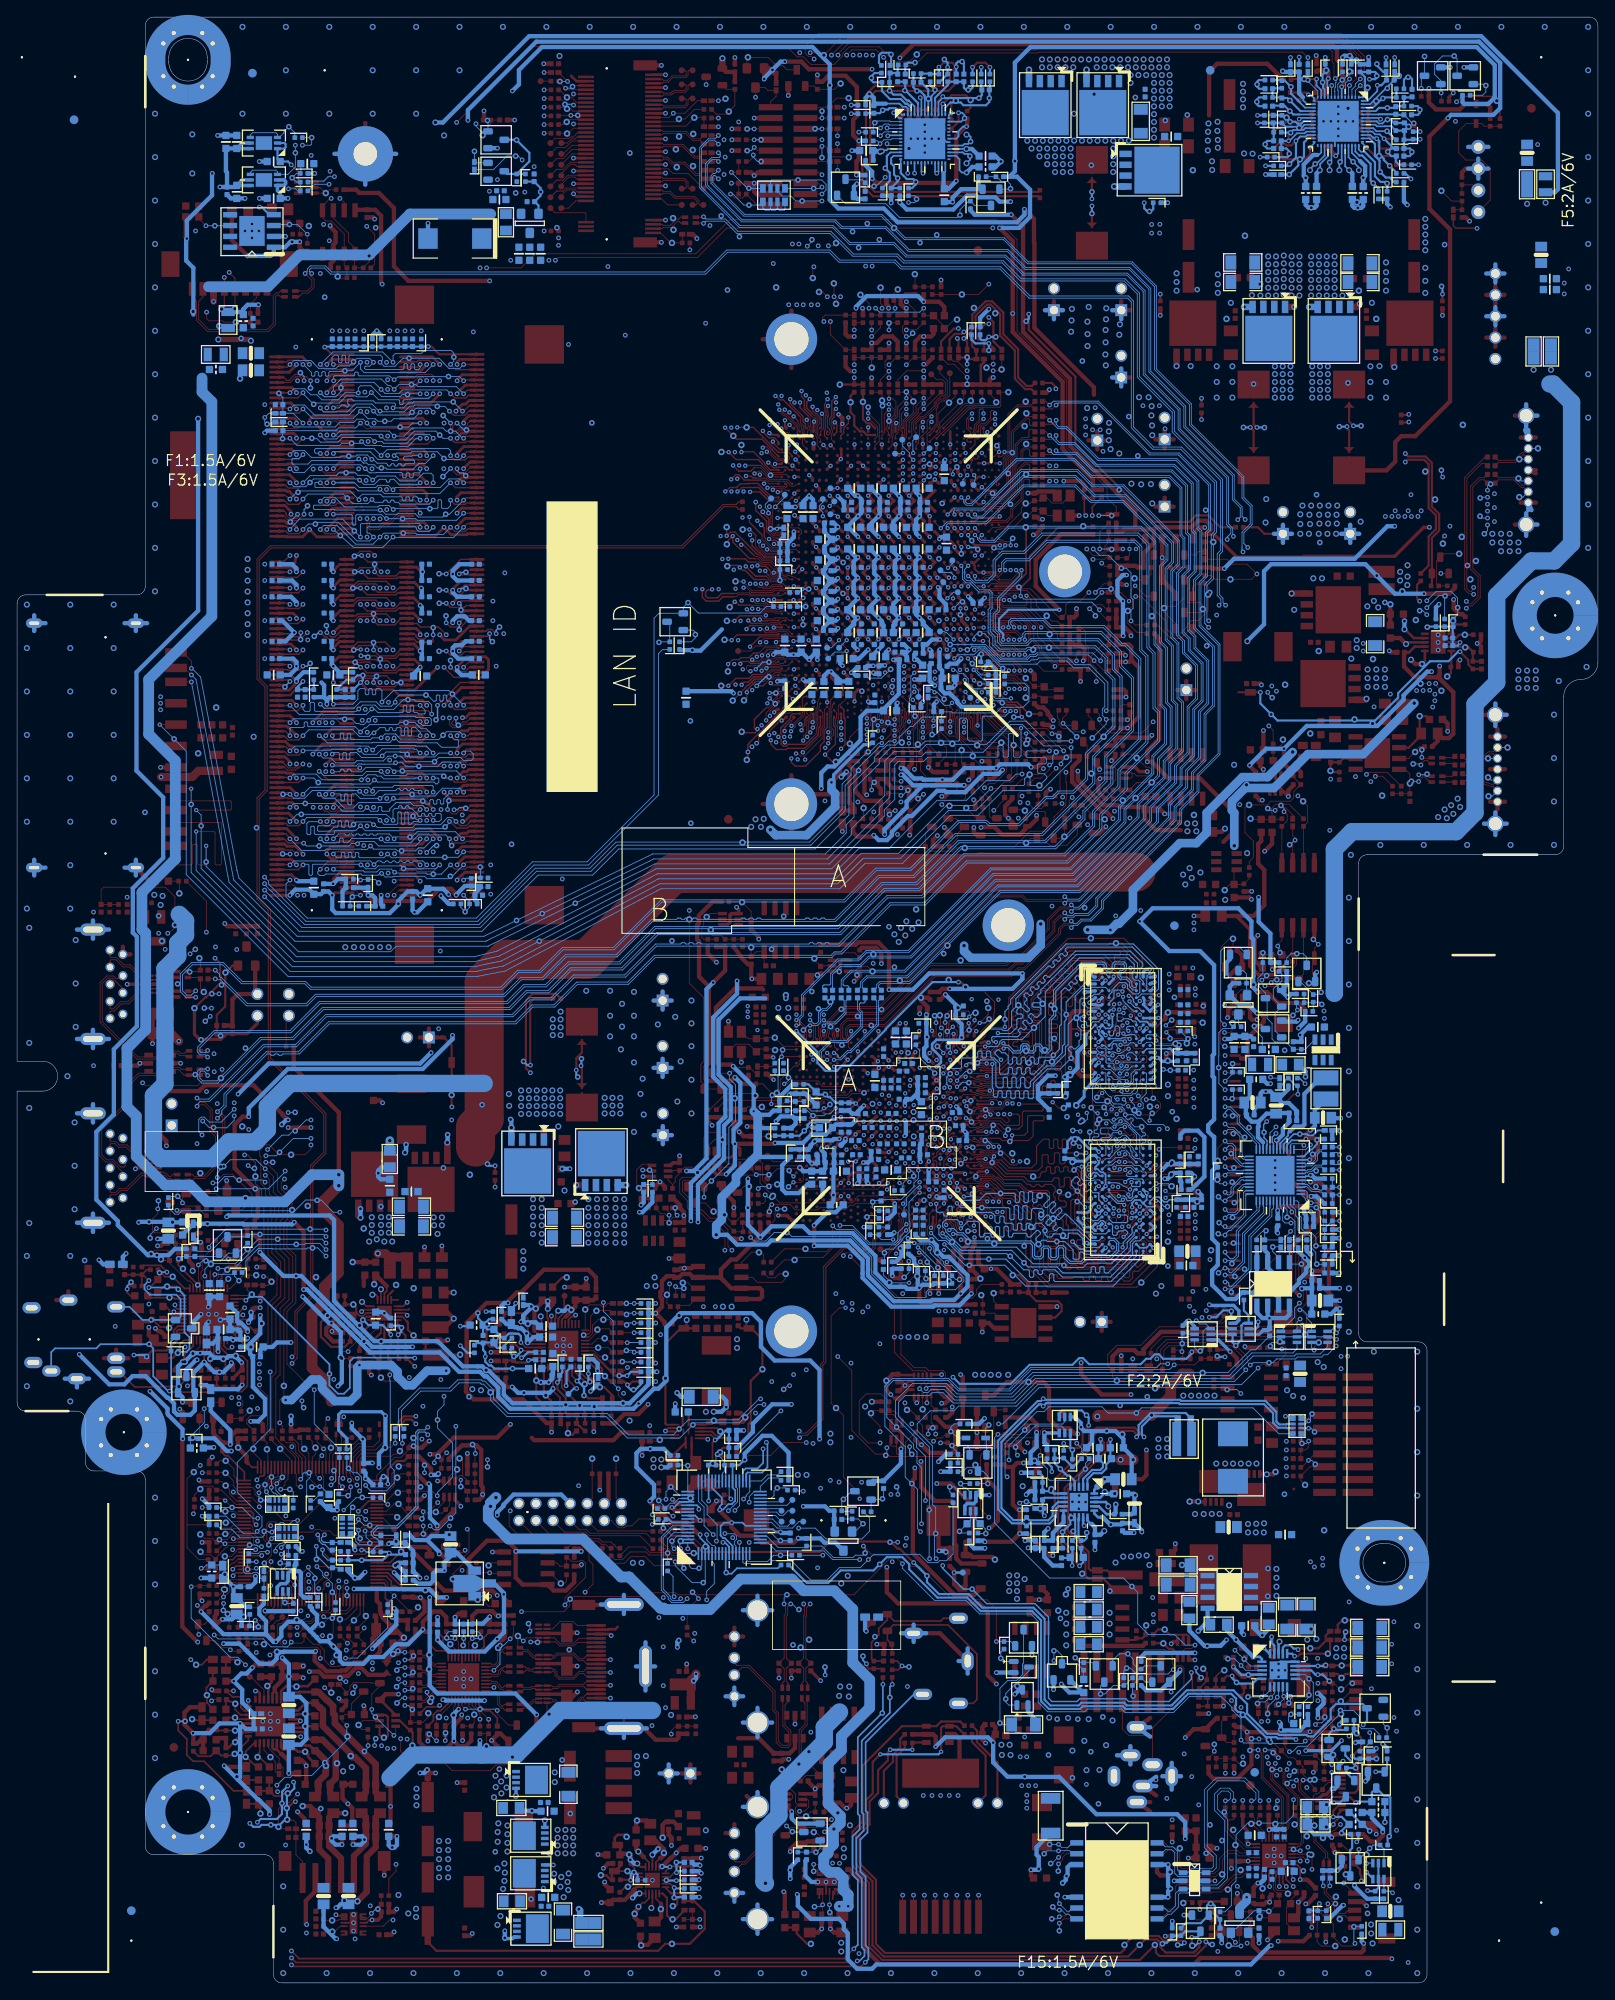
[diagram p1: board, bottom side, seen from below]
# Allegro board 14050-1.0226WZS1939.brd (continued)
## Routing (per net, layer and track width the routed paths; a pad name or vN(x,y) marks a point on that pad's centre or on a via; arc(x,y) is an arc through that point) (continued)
1P5_5930_EN: length 5.8
  TOP w0.102: R1930.2 R31.1 PC5245.1 v1(22,140.34) 22,141.43 22.56,141.99 PU5206.8
1P5_5930_FB: length 5.2
  TOP w0.254: PR5292.2 31.16,141.67 v1(31.3,141.81) 31.3,142.79 PC5244.2 PR5293.1 29.81,143.26 PU5206.2
1P5_5930_PG: length 3.6
  TOP w0.102: PU5206.7 22.16,143.26 v1(21.39,144.02) 21.39,144.12 20.86,144.65 PR5295.2
1P5_5930_VCNTL: length 6.8
  TOP w0.254: PU5206.6 22.13,144.53 20.68,145.97 PR5294.2 20.86,146.35 v1(20.86,148.21) 20.1,148.21 PC5243.1
1P5V_GUP_FB_M: length 11.8
  TOP w0.254: PC68.2 67.66,80.77 PR77.1 ; PC68.2 66.64,80.7 65.7,79.76 63.18,79.76 62.77,79.34 62.77,78.59 63.51,77.85 PU7.2 ; PC68.2 PR78.2 66.71,81.79 67.72,82.8 v1(68.49,82.8)
1P5V_GUP_FB_M1: length 2
  TOP w0.254: PR79.1 PC68.1 PR78.1
1P5V_LPS_APU: length 328.6
  TOP w0.254: v1(164.24,114.05) 162.99,115.3 162.89,115.3 161.15,117.04 161.15,117.75 161.25,117.85 161.25,119.3 v3(161.83,119.89)
  TOP w0.356: CPU1.AR17 83.1,154.5 v4(83.45,154.15)
  TOP w0.381: 156.88,113.16 156.88,112.27 158.08,111.06 C1736.1 160.69,111.06 R1721.1 160.75,110.81 161.16,110.4 163.65,110.4 164.24,111 v1(164.24,114.05)
  L3 w0.254: v3(161.83,119.89) 161.63,119.68 135.42,119.68 121.32,133.78 94.08,133.78 88.08,139.78 88.08,140.63 86.77,141.94 86.77,147.85 84.28,150.35 84.28,153.46 83.72,154.03 83.57,154.03 v4(83.45,154.15)
  L3 w0.508: v3(161.83,119.89) 163.23,119.89 164.5,121.16 166.78,121.16 v3(168.44,122.81)
  L4 w0.508: v3(168.44,122.81) 169.81,121.44 169.81,109.62 168.77,108.58 168.77,92.98 170.11,91.63 170.11,83.84 165.87,79.6 165.87,78.26 166,78.14 166,71.72 164.24,69.97 164.24,67.09 163.51,66.36 163.51,63.77 163.51,61.54 165.64,59.41 165.64,40.67 163.79,38.81 163.79,30.78 165.07,29.5 165.07,28.95 164.68,28.56 163.82,28.56 163.53,28.28 163.53,26.85 155.73,19.05 154.41,19.05 151.81,16.45 151.81,5.58 149.12,2.9 95.37,2.9 93.76,4.5 93.76,9.27 94.52,10.03 v3(94.52,12.19)
  BOTTOM w0.508: v3(94.52,12.19) v2(94.52,13.21) 94.52,13.53 R1185.2 ; v4(83.45,154.15) 84.04,154.15 C1741.1
1P5V_S3_PG: length 157.6
  TOP w0.102: R1774.2 63.25,148.73 63.25,148.01 63.05,147.81 63.05,147.18 62.64,146.77 62.1,146.77 61.7,146.38 v3(60.23,146.38) ; PU5001.10 142.82,76.67 143.85,75.64 144.68,75.64 144.71,75.61 144.75,75.61 145.08,75.28 145.08,75.23 146.26,74.04 v3(146.26,73.86) 146.9,73.86 147.12,73.63 v1(147.12,73.18) 147.01,73.06 PR5005.2
  L3 w0.127: v3(62.64,138.74) 62.9,138.48 65.79,138.48 66.64,139.33 68.16,139.33 68.55,138.93 71.75,138.93 74.78,135.9 74.78,134.09 76.19,132.69 76.33,132.54 80.89,127.98 82.52,127.98 87.9,122.59 117.54,122.59 118.31,121.83 119.17,121.83 133.03,107.97 145.73,107.97 148.79,104.9 148.79,101.37 149.38,100.79 149.38,96.61 150.29,95.7 150.29,75.86 148.29,73.86 v3(146.26,73.86)
  L4 w0.127: v3(60.23,146.38) 60.23,141.15 v3(62.64,138.74)
1P8V_PWR_PG: length 196.7
  TOP w0.102: R1930.1 25.19,141.17 v3(26.05,141.17) ; v3(110.97,65.2) PR5206.2 110.69,64.12 PU5201.4
  L3 w0.127: v3(98.59,66.67) 99.35,65.91 99.35,63.62 99.91,63.06 105.51,63.06 107.49,63.06 108.39,63.96 110.02,63.96 110.97,64.91 v3(110.97,65.2) ; v3(37.09,82.97) 37.09,82.96 36.68,82.55 36.68,78.01 36.74,77.95 36.74,76.91 43.47,70.18 61.3,70.18 63.65,72.53 86.05,72.53 86.98,71.6 88.09,70.48 96.55,70.48 v3(96.68,70.36)
  L4 w0.127: v3(98.59,66.67) 98.59,68.96 97.19,70.36 v3(96.68,70.36) ; v3(20.02,161.71) 19.55,161.24 19.55,159.32 20.31,158.56 20.31,153.9 22.9,151.32 22.9,149.89 25.72,147.07 25.72,141.5 v3(26.05,141.17) 26.64,141.17 27.52,140.3 31.78,140.3 36.99,135.09 36.99,134.4 36.99,121.13 37.26,120.86 37.26,116.54 38.65,115.14 38.65,106.29 38.78,106.16 38.78,105.01 38.16,104.39 38.16,102.44 39.37,101.23 39.37,86.05 37.09,83.77 37.09,82.97 v3(37.09,82.97)
  BOTTOM w0.102: v3(20.02,161.71) 18.95,162.78 17.16,162.78 16.42,162.05 16.42,160.92 v2(16.42,160.91) 16.42,160.08 R1763.1
3D3V_AUX_EC: length 55.9
  TOP w0.508: v3(102.78,55.37) 102.78,55.24 v3(101.38,53.85) ; v3(101.38,53.85) 101.51,53.72 103.67,53.72 R79707.2 104.05,54.1 v3(105.06,54.1) 105.76,54.1 L4101.1 ; v3(101.38,53.85) 101.38,53.31 100.39,52.32 98.69,52.32 97.87,51.51 94.11,51.51 v3(93.58,52.04)
  BOTTOM w0.203: U4101.44 103.67,57.91 102.52,56.77 102.52,56.01 102.78,55.75 v3(102.78,55.37) 102.4,55.37 101.75,56.02 101.35,56.02 100.96,56.41 100.96,57.63 101.27,57.94 U4101.38 101.27,60.53 R79706.1 ; U4101.11 101.27,51.13 102.18,52.04 102.37,52.04 102.67,52.35 102.67,53.44 102.27,53.85 v3(101.38,53.85) 100.11,53.85 99.74,53.48 U4101.22 ; U4101.56 105.64,54.68 v3(105.06,54.1)
  BOTTOM w0.254: v2(99.86,61.21) 100.49,60.58 R79706.1
  BOTTOM w0.508: PR8519.1 PR8520.1 94.71,62.04 96.68,64.01 97.77,64.01 99.86,61.92 v2(99.86,61.21) ; Q9649.D 89.24,51.51 90.51,51.51 91,52.01 R80230.2 93.54,52.01 v3(93.58,52.04)
3D3V_RUN_FFS: length 21.8
  TOP w0.305: U6701.1 81.83,71.12 C6702.1 ; R6701.2 75.95,68.45 76.46,68.45 77.41,69.4 U6701.8 ; U6701.14 80.72,69.4 81.73,68.39 C6701.1 82.32,68.39 v3(82.76,68.83) ; C6703.1 76.13,69.9 U6701.7
  TOP w0.508: v3(82.76,68.83) 83.27,69.34 v1(83.27,70.46) 82.57,71.16 82.57,71.21 C6702.1 ; v3(76.81,67.82) 76.39,67.82 R6701.2 C6703.1
  L3 w0.508: v3(76.81,67.82) 76.84,67.82 77.55,68.53 82.46,68.53 v3(82.76,68.83)
3D3V_VGA_S0: length 257.9
  TOP w0.254: GPU1.AB17 87.38,100.4 v4(86.88,100.9) ; RN16.3 101.49,96.57 103.13,96.57 103.41,96.85 Q123.5 ; GPU1.AA18 86.4,101.38 v4(86.88,100.9) ; GPU1.AA17 86.4,100.41 v4(86.88,100.9) ; v4(86.88,100.9) 87.39,101.4 GPU1.AB18
  TOP w0.356: RN16.3 101.07,98.1 v3(101,98.17) 100.43,97.61 100.42,97.61 RN16.4
  TOP w0.406: v3(102.01,94.61) 103.16,94.61 103.41,94.87 Q123.2
  TOP w0.508: 102.62,82.47 102.62,83.46 101.45,84.63 100.82,84.63 98.23,87.22 v3(98.01,87.22) R1885.1 98.01,88.9 R1887.1 ; 102.62,82.47 101.43,81.28 U49.7 98.08,81.28 97.82,81.03 97.82,80.26 98.08,80.01 U49.8 ; 102.62,82.47 102.7,82.55 U49.3 105.89,82.55 106.29,82.96 107.12,82.96 107.54,82.54 C753.1 108.19,82.69 108.96,82.69 109.53,82.12 109.53,81.01 109.71,80.83 109.71,80.2 109.53,80.02 109.53,79.1 v3(110.27,78.36) 109.19,77.28 R1167.1 ; v3(160.48,93.88) 160.43,93.83 Q77.D ; R1159.2 99.42,105.2 R1883.1 100.14,105.19 100.9,105.94 v3(101,105.94) 101.4,105.54 104.2,105.54 104.43,105.76 104.43,107.22 104.05,107.6 104.05,116.59 105.19,117.73 105.19,121.87 105.42,122.09 105.42,123.77 105.21,123.97 105.21,124.88 103.6,126.49 R79727.2 ; PR225.1 78.98,79.38 79.41,79.81 v3(79.41,81.33) ; v3(96.3,98.28) 96.41,98.17 v3(101,98.17) ; v3(111.16,67.69) 112.3,66.55 113.95,66.55 115.03,65.47 PR6.1 PR4.1
  L3 w0.508: v3(102.01,94.61) 101.48,94.08 v3(99.47,94.08)
  L4 w0.508: v3(112.17,90.17) 109.27,90.17 104.83,94.61 v3(102.01,94.61) ; v3(110.12,71.5) 110.4,71.5 111.16,70.74 v3(111.16,67.69) ; v3(160.48,93.88) v3(160.48,89.63)
  BOTTOM w0.508: PR5471.2 110.65,91.33 111.81,90.17 v3(112.17,90.17) ; PR19.1 PR94.1 PR96.1 PR97.1 PR100.1 PR102.1 PR103.1 ; PR19.1 v3(110.12,71.5) ; PR19.1 PR15.1 111.09,70.04 113.32,67.82 127.03,67.82 128.05,68.83 128.05,69.88 129.77,71.6 130.03,71.6 130.57,72.14 131.09,72.14 132.82,72.14 135.77,75.08 143.21,75.08 147.91,79.79 147.91,89.28 148.42,89.79 160.32,89.79 v3(160.48,89.63) ; R1895.2 R1892.2 R1893.2 77.8,81.69 79.05,81.69 v3(79.41,81.33) ; v3(102.01,94.61) 101,95.63 v3(101,98.17) 101.15,98.32 101.15,99.84 100.36,100.63 100.36,105.31 v3(101,105.94) ; PR103.1 v3(110.27,78.36) ; PR103.1 PR104.1 ; v3(96.3,98.28) 93.02,98.28 92.03,99.27 90.38,99.27 C784.1 89.22,100.42 C783.1 C782.1 87.36,100.42 v4(86.88,100.9) ; R302.2 80.46,85.06 80.39,85.06 80.02,84.69 80.02,84.19 79.6,83.77 R398.2 79.6,81.52 v3(79.41,81.33) ; v3(79.41,81.33) 79.54,81.2 80.86,81.2 81.1,81.45 82.89,81.45 84.55,83.11 84.55,85.05 87.23,87.73 92.24,87.73 93.02,88.52 96.72,88.52 v3(98.01,87.22) 99.47,88.68 v2(99.47,90.7) v3(99.47,94.08)
3P3_VGA_1P8_EN: length 4.8
  TOP w0.102: Q97.5 111.68,95 v3(111.79,95.11)
  BOTTOM w0.102: v3(111.79,95.11) v2(110.98,95.11) 110.65,94.78 PR5471.1 C6723.1
1117_ADJ: length 7.1
  TOP w0.102: v3(129.7,45.24) 129.04,44.58 R2081.2 129.34,44.07 129.83,44.07 130.59,44.83 v1(131.1,44.83) 131.22,44.7 R1592.1
  BOTTOM w0.102: v3(129.7,45.24) 129.7,45.24 U119.1
62882_COMP_R: length 2.4
  TOP w0.254: PR8.1 120.61,65.29 120.61,64.39 v1(120.53,64.31) 120.35,64.14 119.98,64.14 PC6.2
62882_FB_VSEN: length 2.2
  TOP w0.254: v1(129.6,69.09) 129.38,69.09 PR20.2 128.81,69.79 PC11.1
62882_NTC_R: length 32.9
  TOP w0.254: PR60.1 v3(129.07,93.12)
  L4 w0.254: v3(129.07,93.12) 129.09,93.09 129.09,80.42 128.3,79.63 128.3,74.72 125.46,71.88 120.6,71.88 119.99,71.27 v3(118.14,71.27)
  BOTTOM w0.254: v2(117.97,70.33) 118.14,70.51 v3(118.14,71.27) PR5.2
62883AGND: length 4.9
  TOP w0.203: v3(117.06,71.62) 118.19,72.75 U9.40
  BOTTOM w0.508: PR5.1 117.57,72.96 117.06,72.45 v3(117.06,71.62) 117,71.56 PR2.1
  vias: v2(118.7,75.8) v3(120.3,74.55) v3(121.06,75.31) v3(121.06,74.55) v3(121.06,73.79) v3(121.83,74.55)
+VGA_CORE_PHASE1: length 51.7
  TOP w0.254: PG3.1 118.91,108.84 119.54,108.2 119.54,106.81 v3(119.56,106.79)
  L4 w0.254: v3(119.56,106.79) 119.56,107.33 120.69,108.46 126.69,108.46 130.26,104.89 130.26,98.34 131.39,97.21 131.39,76.29 132.03,75.64 132.95,75.64 133.13,75.47 v3(133.13,74.55)
  BOTTOM w0.254: v2(119.39,105.99) 119.56,106.17 v3(119.56,106.79) ; PR47.2 132.3,73.72 v3(133.13,74.55)
A20GATE: length 181.9
  TOP w0.102: R350.1 158.78,88.77 157.53,90.03 157.53,92.34 159.8,94.61 160.82,94.61 161.2,94.23 v3(161.58,94.23) ; v4(85.55,146.69) 85.15,147.09 85.15,147.5 84.6,148.05 CPU1.BC19 ; v3(155.96,95.25) 155.91,95.25 155.01,94.35 155.01,92.52 154.37,91.87 154.37,89.66 154.71,89.32 154.71,85.6 153.66,84.56 153.66,80.13 154.71,79.09 154.71,71.37 155.2,70.88 155.2,64.6 R80231.2
  L3 w0.127: v4(85.55,146.69) 86.01,146.69 86.23,146.47 86.23,144.74 85.95,144.46 85.95,141.6 87.26,140.29 87.26,139.12 93.42,132.96 120.98,132.96 135.08,118.86 159.56,118.86 161.41,117.01 162.76,117.01 166.02,120.27 167.01,120.27 v3(167.67,120.93)
  L4 w0.127: v3(161.58,94.23) 162.03,94.69 162.03,98.08 162.85,98.89 162.85,99.42 163.49,100.06 163.49,100.33 163.79,100.63 163.79,100.64 163.94,100.79 163.94,101.63 164.57,102.26 164.57,103.84 167.15,106.42 167.15,110.45 167.96,111.25 167.96,119.86 167.67,120.14 v3(167.67,120.93)
  BOTTOM w0.102: v3(155.96,95.25) 157.03,96.32 160.03,96.32 v2(160.82,95.53) 161.58,94.77 v3(161.58,94.23)
AC_IN: length 48.3
  TOP w0.102: PQ5005.2 48.55,38.86 48.29,39.12 47.56,39.12 v3(47.15,39.52) ; v3(70.21,64.19) 69.36,64.19 PR5281.2 67.55,64.17 PQ5004.D
  BOTTOM w0.102: v3(70.21,64.19) 70.62,63.78 70.62,53.82 64.17,47.37 55.53,47.37 v2(54.54,46.38) 53.86,45.69 53.86,42.01 52.61,40.77 49.54,40.77 48.29,39.52 v3(47.15,39.52)
AC_IN_KBC#: length 2.6
  BOTTOM w0.102: U4101.29 95.77,56.28 TP4124.1
AC_OK#: length 124.4
  TOP w0.102: v3(146.34,39.75) 147.16,40.58 R80209.1 ; PQ5004.G 65.25,62.42 65.25,61.75 v3(65.28,61.72) 65.91,61.09 v1(65.95,61.09)
  L3 w0.127: v3(146.34,39.75) 146.21,39.62 144.03,39.62 142.3,41.35 138.57,41.35 137.35,40.13 136.56,40.13 135.91,40.78 127.31,40.78 126.47,40.78 124.71,42.53 110.1,42.53 v3(109.89,42.75) 109.27,43.37 102.36,43.37 100.04,45.69 96.7,45.69 95.68,46.71 90.14,46.71 86.53,50.32 80.44,50.32 72.59,58.17 69.5,58.17 68.68,58.99 68.68,59.7 68.02,60.35 66.31,60.35 65.28,61.39 v3(65.28,61.72)
  L4 w0.127: v3(101.76,55.24) 102.27,54.74 105.2,54.74 110.27,49.67 110.27,44.07 109.89,43.69 v3(109.89,42.75)
  BOTTOM w0.102: v3(101.76,55.24) 101.27,55.74 101.24,55.74 100.68,56.29 100.68,57.82 100.87,58.01 U4101.37 ; v3(65.28,61.72) 65.5,61.5 PR4427.2 65.11,60.83 64.42,60.15 64.42,59.05 64.17,58.8 61.88,58.8 61.74,58.66 U55.5
AC_OK#_ECIO: length 4.6
  TOP w0.102: R80209.2 v1(147.23,42.55) 146.46,42.55 145.25,43.75 U109.99
AC_PRES: length 12.1
  TOP w0.102: R582.1 64.17,157.16 v1(64.17,157.78) 64.17,158.22 66.87,160.92 69.59,160.92 69.97,161.3 70.23,161.3 70.23,161.29 70.77,161.29 70.77,161.3 71.03,161.3 71.03,161.29 71.41,161.29 CPU1.AG3
AC_PROTECT: length 22.2
  TOP w0.102: v3(60.99,63.13) 62.2,64.34 63.36,64.34 63.87,64.85 64.97,64.85 65.23,64.58 65.23,64.22 65.68,63.78 68.61,63.78 68.91,63.49 69.43,63.49 69.71,63.21 69.71,62.5 PR5298.1 69.76,61.53 PR5289.2 PR5297.2 71.53,61.85 70.7,62.68 PQ4408.G
  BOTTOM w0.102: v3(60.99,63.13) 60.41,62.54 60.41,62.16 60.1,61.85 60.05,61.85 PR5287.1 59.53,61.23 59.98,60.78 v2(59.98,60.12) 60.74,59.36 U55.3
AD+_2: length 1.1
  BOTTOM w0.508: v3(68.23,33.78) 67.71,34.3 PQ4205.C
  vias: v1(67.95,34.72)
AD+_G_1: length 6.2
  TOP w0.254: PQ5005.6 47.9,40.55 48.08,40.73 48.34,40.73 ; 48.34,40.73 50.08,40.73 v1(50.71,41.35) 51.46,41.35 PR5272.2 ; 48.34,40.73 48.55,40.53 PQ5005.5
AD+_G_2: length 4.1
  TOP w0.254: 55.66,40.13 54.2,40.13 PR5275.2 53.31,40.32 52.93,40.7 PR5272.1 52.93,41.77 v1(52.87,41.83)
AD+_TO_SYS: length 3.5
  TOP w0.254: PR5276.1 56.57,46 57.89,47.32 PG4907.1
  vias: v2(57.11,45.85) v5(57.14,43.31) v5(57.14,42.04) v5(57.14,40.77)
AD_IA: length 116.4
  L3 w0.127: v3(146.57,38) 146.28,38 146.05,38.23 143.56,38.23 140.95,40.84 138.78,40.84 137.35,39.41 122.47,39.41 122.26,39.62 118.77,39.62 116.37,42.02 107.72,42.02 v3(107.09,42.65) 106.94,42.8 102.22,42.8 99.83,45.19 96.49,45.19 95.47,46.21 88.79,46.21 88.78,46.19 88.3,46.19 85.47,49.02 85.12,49.02 84.35,49.78 80.26,49.78 76.09,53.95 70.87,53.95 68.68,56.13 v3(67.67,56.13)
  L4 w0.127: v3(107.09,42.65) 107.09,43.79 106.12,44.76 106.12,47.9 103.67,50.35 103.67,52.32 v3(103.54,52.45)
  BOTTOM w0.102: U4101.48 105.27,56.34 104.6,55.68 104.6,53.52 v3(103.54,52.45) ; v3(146.57,38) 145.18,38 141.64,41.54 R80216.1 ; v3(67.67,56.13) 67.5,56.3 v2(66.88,56.3) 66.64,56.3 PR5288.2
AD_IA_HW1: length 129.6
  TOP w0.102: v3(152.23,40.73) 152.05,40.91 152.04,40.91 151.42,41.53 R79637.1 150.94,42.07 150.56,42.07 149.32,43.31 148.37,43.31 148.06,43.62 U109.106
  L3 w0.127: v3(68.92,61.19) 71.06,61.19 74.63,57.62 86.17,57.62 88.42,55.37 90.98,55.37 92.09,54.27 97.67,54.27 99.35,52.59 99.35,51.56 v3(99.32,51.54) ; v3(106.59,44.96) 107.67,43.88 109.84,43.88 110.68,43.04 124.92,43.04 126.68,41.28 127.1,41.28 127.1,41.28 136.78,41.28 137.37,41.87 142.5,41.87 143.64,40.73 148.68,40.73 149.06,41.11 151.85,41.11 v3(152.23,40.73)
  L4 w0.127: v3(106.59,44.96) 106.59,48.15 105.61,49.13 105.61,52.57 105.26,52.92 102.64,52.92 102.51,53.05 101.97,53.05 101.7,52.77 101.7,52.32 101.72,52.29 101.72,51.9 101.45,51.63 101.04,51.63 100.66,52.01 100.27,52.01 99.8,51.54 v3(99.32,51.54)
  BOTTOM w0.102: U4101.59 108.29,53.48 109.61,52.16 109.61,45.96 108.8,45.15 108.8,44.9 108.39,44.5 107.04,44.5 v3(106.59,44.96) ; v3(68.92,61.19) 68.92,62.87 67.48,64.31 67.47,64.31 v2(67.08,64.69) 67.08,64.7 66.4,65.38 62.67,65.38 62.39,65.66 PQ5006.2
AD_IA_HW2: length 126.1
  TOP w0.102: R79638.1 v3(152.23,41.59) 151.53,42.3 150.65,42.3 149.42,43.54 148.62,43.54 148.46,43.7 U109.107
  L3 w0.127: v3(101.25,52.1) 100.87,52.48 99.82,52.48 97.77,54.52 92.19,54.52 91.09,55.63 88.52,55.63 86.28,57.87 74.74,57.87 70.86,61.75 v3(67.93,61.75) ; v3(107.35,44.96) 108.17,44.13 109.95,44.13 110.78,43.29 125.03,43.29 126.79,41.54 127,41.54 136.68,41.54 137.27,42.13 142.61,42.13 143.75,40.98 148.58,40.98 148.96,41.36 152,41.36 v3(152.23,41.59)
  L4 w0.127: v3(107.35,44.96) 106.84,45.47 106.84,48.26 105.86,49.24 105.86,50.82 105.91,50.87 105.91,52.75 105.41,53.26 102.66,53.26 102.62,53.3 101.69,53.3 101.25,52.87 v3(101.25,52.1)
  BOTTOM w0.102: v3(107.35,44.96) 107.58,44.73 108.3,44.73 108.57,45 108.57,45.24 109.38,46.06 109.38,52.07 108.37,53.08 U4101.60 ; v3(67.93,61.75) 68.1,61.92 68.1,62.63 v2(68.16,62.69) 68.16,62.87 65.87,65.15 62.77,65.15 62.39,64.77 PQ5006.5
AD_JK: length 60.9
  TOP w0.508: DCIN1.1 56.28,26.63 ; DCIN1.1 54.71,25.56 ; DCIN1.1 54.71,27.7
  TOP w1.27: v5(55.86,61.21) v1(54.39,61.21)
  L3 w0.508: DCIN1.1 56.28,26.63 ; DCIN1.1 54.71,27.7 ; DCIN1.1 54.71,25.56
  L3 w1.27: v5(55.86,61.21) 56.95,60.12 60.94,60.12 62.82,58.24 67.19,58.24 v5(67.32,58.12)
  L4 w0.508: DCIN1.1 56.28,26.63 ; DCIN1.1 54.71,25.56 ; DCIN1.1 54.71,27.7
  L4 w1.27: v5(67.32,58.12) 67.39,58.12 68.71,56.79 68.71,51.03 64.3,46.61 64.3,39.5 64.93,38.86 64.93,31.75 v5(64.22,31.04)
  BOTTOM w0.508: DCIN1.1 54.71,27.7 ; DCIN1.1 54.71,25.56 ; DCIN1.1 56.28,26.63 ; PQ4205.E 66.69,31.73 65.95,30.99
  vias: v2(57.95,31.11) v2(58.45,20.95) v2(59.34,27.05) v2(60.87,30.86) v2(61.5,24) v2(63.28,30.86) v2(64.3,26.67) v5(56.8,30.71) v5(57.56,27.81) v5(58.33,24.92) v5(59.6,30.86) v5(59.85,24.89) v5(60.1,28.32) v5(61.5,27.18) v5(62.01,30.99)
AD_OFF: length 90.2
  TOP w0.102: v3(144.38,41.53) 144.38,41.39 R80211.1 144.43,39.81 R2013.1 ; v3(73.46,59.81) 72.85,60.42 72.85,60.6 v1(72.85,60.6)
  L3 w0.127: v3(73.46,59.81) 74.38,58.89 82.12,58.89 82.92,59.69 86.93,59.69 89.47,57.15 91.72,57.15 92.44,56.43 98.2,56.43 99.35,55.28 v3(101,55.28) ; v3(109.38,45.09) 111.54,45.09 111.72,45.26 116.06,45.26 117.66,43.66 123.86,43.66 123.94,43.58 125.1,43.58 126.89,41.79 136.57,41.79 137.28,42.49 143.33,42.49 144.29,41.53 v3(144.38,41.53)
  L4 w0.127: v3(109.38,45.09) 109,45.47 109,50.58 105.94,53.63 102.71,53.63 101.06,55.28 v3(101,55.28)
  BOTTOM w0.102: v3(101,55.28) 100.45,55.82 100.45,58 100.47,58.01 U4101.36
AD_OFF_ECIO: length 3.9
  TOP w0.102: R80211.2 144.18,42.48 v1(144.18,42.93) 144.45,43.2 U109.97
AD_OFF_L: length 6.7
  BOTTOM w0.102: PQ4204.C 66.57,36.52 67.97,35.12 68.05,35.12 69.3,33.86 v2(69.3,33.22) 69.3,32.87 68.93,32.5 PQ4205.B
ADAPTOR_PSID: length 116.5
  TOP w0.102: R80213.1 106.52,40.7 v3(105.82,40.01) ; U109.119 153.25,42.75 153.74,42.27 153.8,42.27 154.03,42.04 154.38,42.04 154.54,41.87 154.54,40.37 154.21,40.04 154.21,39.76 153.71,39.27 149.88,39.27 149.51,38.9 v3(149.51,37.97)
  L3 w0.127: v3(149.51,37.97) 147.93,37.97 146.97,37.02 144.76,37.02 143.72,35.98 143.12,35.98 139.9,39.19 139.47,39.19 138.03,37.76 121.79,37.76 121.57,37.97 118.08,37.97 117.09,38.96 113.86,38.96 112.45,40.37 106.19,40.37 v3(105.82,40.01) 105.14,39.32 91.49,39.32 91.09,39.72 89.97,40.84 89.65,40.84 84.52,45.96 71.87,45.96 63.66,37.75 v3(63.66,37.72)
  BOTTOM w0.102: R1846.2 R1851.2 60.94,37.35 D19.3 62.72,38.31 63.27,38.86 v2(63.66,38.86) 63.66,38.85 v3(63.66,37.72)
ADAPTOR_PSID_R: length 2.8
  BOTTOM w0.102: v2(61.17,38.05) 60.6,37.47 R1851.1 59.13,37.47 Q47.S
AGPIO3: length 21
  TOP w0.102: R2010.2 R2008.1 57.84,155.57 58.07,155.35 58.07,154.81 v3(58.2,154.69) ; CPU1.AL5 73,157.5 v4(73,157.18)
  BOTTOM w0.102: v3(58.2,154.69) 59.12,155.61 65.67,155.61 65.87,155.41 66.48,155.41 66.9,154.99 69.77,154.99 71.2,156.42 71.2,157.27 71.79,157.86 v2(72.33,157.86) 72.66,157.86 73,157.53 v4(73,157.18)
AGPIO8: length 14.8
  TOP w0.102: R79650.1 62.91,153.47 64.8,153.47 66.1,154.76 v1(66.1,155.98) 66.65,156.54 66.65,158.77 67.79,159.91 70.31,159.91 70.32,159.9 70.68,159.9 70.69,159.91 71.11,159.91 71.12,159.9 71.66,159.9 71.79,159.77 72.15,159.4 CPU1.AJ4
AGPIO11: length 27.3
  TOP w0.102: v3(57.54,147.83) R2063.1 R2064.2 ; v4(73,155.98) 73.3,156.28 CPU1.AN5
  BOTTOM w0.102: v2(59.17,145.67) 57.54,147.3 v3(57.54,147.83) 58,148.29 58,149.03 57.71,149.32 57.71,152 59.58,153.87 61.36,153.87 62.15,154.67 65.28,154.67 65.66,154.29 69.97,154.29 71.86,156.18 72.8,156.18 v4(73,155.98)
AGPIO13: length 24.5
  TOP w0.102: CPU1.AD5 73.3,163.79 73.69,163.4 v4(73.7,163.4) ; v3(58.3,167.77) 58.3,169.76 R79673.1
  L3 w0.127: v4(73.7,163.4) 73.23,163.4 72.04,164.59 67.57,164.59 67.2,164.96 67.19,164.97 67.13,165.03 67.12,165.04 67.04,165.13 67.03,165.14 67.03,166.27 64.09,169.21 59.75,169.21 v3(58.3,167.77)
  BOTTOM w0.102: v2(56.9,167.72) 56.95,167.77 v3(58.3,167.77)
AGPIO14: length 2.7
  TOP w0.102: CPU1.AL8 75.7,157.48 v4(75.4,157.18)
  BOTTOM w0.102: v4(75.4,157.18) 76.21,157.99 76.37,157.99 76.49,158.12 TP198.1
AGPIO15: length 1.8
  TOP w0.102: v4(75.4,155.98) 75.7,156.28 CPU1.AN8
  BOTTOM w0.102: TP199.1 76.11,155.27 v4(75.4,155.98)
AGPIO24: length 21.8
  TOP w0.102: v4(76.2,157.18) 76.5,157.48 CPU1.AL9 ; R79671.1 57.82,153.54 58.45,154.17 58.96,154.69 v3(58.96,154.71)
  BOTTOM w0.102: v3(58.96,154.71) 59.63,155.38 65.57,155.38 65.77,155.18 66.42,155.18 66.81,154.79 69.86,154.79 71.66,156.59 v2(75.8,156.59) 76.2,156.99 v4(76.2,157.18)
AGPIO40: length 25.2
  TOP w0.102: R79651.1 57.25,167.7 57.94,167.01 59.07,167.01 v3(59.82,167.77) ; v4(75.4,160.82) 75.4,161.1 CPU1.AG8
  L3 w0.127: v3(59.82,167.77) 60.76,168.7 63.88,168.7 66.22,166.36 66.22,165.29 67.4,164.11 70.49,164.11 71.62,162.99 72.3,162.99 73.82,161.47 74.55,161.47 75.19,160.82 v4(75.4,160.82)
  BOTTOM w0.102: v2(74.37,161.59) 74.63,161.59 v4(75.4,160.82)
AGPIO66: length 21.4
  TOP w0.102: R159.1 v3(82.23,137.16) ; CPU1.AT15 81.45,154.05 v4(81.19,154.05)
  L3 w0.127: v4(81.19,154.05) 81.85,153.39 81.85,151.45 81.97,151.32 82.8,151.32 83,151.12 83,149.75 81.64,148.39 81.64,143.56 82.08,143.12 82.08,137.34 82.16,137.27 82.16,137.23 v3(82.23,137.16)
  BOTTOM w0.102: v2(82.91,136.7) 82.46,137.16 v3(82.23,137.16)
AGPIO84: length 3.9
  TOP w0.102: CPU1.BC18 v4(83.8,147.58)
  BOTTOM w0.102: R79714.1 84.87,147.7 v2(84.74,147.83) 84.05,147.83 v4(83.8,147.58)
AGPIO88: length 4.9
  TOP w0.102: CPU1.BC11 78.16,148.06 78.16,144.68 77.25,143.76 TP186.1
AGPIO89: length 5.8
  TOP w0.102: R79672.1 81.31,144.98 v1(81.47,145.14) 81.44,145.16 81.44,146.35 81.1,146.69 81.09,146.7 81.09,147.41 81.03,147.47 81.03,147.74 80.89,147.88 80.89,148.37 80.9,148.37 80.9,148.63 80.6,148.93 CPU1.BB14
AMD_RST#: length 6.3
  TOP w0.102: GPU1.AL27 95.49,108.4 v3(95.54,108.36) 96.66,107.23 C752.1 R1160.1
  BOTTOM w0.102: v2(95.41,109.16) 95.49,109.09 95.49,108.48 95.54,108.43 v3(95.54,108.36)
AMP_GND: length 49.4
  TOP w0.305: U21.4 v3(158.9,30.36)
  TOP w0.508: R358.2 163.23,28.89 C192.2 ; v3(157.46,36.88) 157.01,37.34 C208.2 ; R344.1 160.64,25.27 v3(160.76,25.4) ; v3(155.46,19.71) 155.48,19.73 R365.2 ; R355.2 v3(159.65,35.31) ; C192.2 163.48,28.45 163.93,28 R347.1 164.37,29.18 v3(164.41,29.22) 165.41,30.22 165.41,31.62 164.78,32.26 R346.1 ; C192.2 C193.2
  BOTTOM w0.508: v3(158.9,30.36) 161.32,30.36 162.45,29.22 v3(164.41,29.22) ; v3(158.9,30.36) 158.26,29.72 C531.2 157.32,29.84 R666.1 158.21,32.38 158.22,32.38 158.66,32.82 158.66,34.32 v3(159.65,35.31) 158.76,36.2 158.15,36.2 v3(157.46,36.88) ; v3(158.9,30.36) v2(158.9,26.91) 158.9,24.07 159.16,23.8 ; 159.16,23.8 156.84,21.48 156.77,21.48 155.46,20.17 v3(155.46,19.71) ; 159.16,23.8 v3(160.76,25.4)
AMP_SPKR_L: length 5.2
  TOP w0.203: R356.2 R355.1 162.85,34.54 162.85,33.76 162.78,33.69 v1(162.78,33.67) 162.78,32.79 162.46,32.47 162.46,32.38 C199.1
AMP_SPKR_R: length 5.1
  TOP w0.203: v1(153.32,22.18) 153.72,22.18 154.04,21.86 154.86,21.86 R365.1 ; R367.2 R365.1 ; R365.1 C210.1
APU_ALERT#: length 15.4
  TOP w0.102: R1616.2 83.98,193.65 v3(85,192.63) ; v4(82.96,183.44) 83.13,183.27 83.13,182.2 83.3,182.03 83.3,181.72 83,181.42 CPU1.B17
  L4 w0.127: v4(82.96,183.44) 84.46,184.94 84.46,192.1 v3(85,192.63)
  BOTTOM w0.102: v4(82.96,183.44) v2(82.96,182.73)
APU_DBRDY: length 54.6
  TOP w0.102: CPU1.C13 79.8,180.67 79.41,181.07 79.41,182.23 v4(79,182.64) ; v3(91.76,200.79) 91.88,200.67 v1(91.88,199.47) ; HDT1.14 v3(90.81,215.65)
  L3 w0.127: v3(90.81,215.65) 93,213.46 93,202.03 v3(91.76,200.79)
  L4 w0.127: v4(79,182.64) 79,183.29 77.76,184.53 77.76,186.06 76.14,187.67 76.14,196.4 79.35,199.61 85.47,199.61 86.65,200.79 v3(91.76,200.79)
APU_DBREQ: length 3.7
  TOP w0.102: HDT1.16 v3(90.81,216.92) R1746.1
  BOTTOM w0.102: v3(90.81,216.92) 91.49,216.92 91.52,216.94 v2(91.62,216.94)
APU_DBREQ#: length 75.7
  TOP w0.102: CPU1.A11 78.2,182.42 v4(77.98,182.64) ; R1704.2 C1739.1 v3(101.4,210.57) ; v1(89.16,203.56) 89.48,203.24 v3(90.06,203.24) ; R1746.2 v3(89,216.1)
  L3 w0.127: v3(101.4,210.57) 101.25,210.57 100.55,211.26 v3(100.55,217.73) ; v3(90.06,203.24) 90.06,207.7 89.83,207.93 89.83,215.27 v3(89,216.1)
  L4 w0.127: v3(89,216.1) 89.01,216.12 98.94,216.12 v3(100.55,217.73) ; v4(77.98,182.64) 77.24,183.38 77.24,185.85 75.34,187.75 75.34,190.16 72.26,193.25 72.26,198.17 76.56,202.47 89.29,202.47 v3(90.06,203.24)
APU_DIS_1: length 3.7
  BOTTOM w0.102: R1185.1 C866.1 91.54,15.3 v2(91.52,15.29) 91.4,15.42 91.35,15.42 91.03,15.74 Q104.G
APU_DIS_2: length 9.2
  TOP w0.102: v3(94.95,18.36) 94.78,18.19 93.26,18.19 Q105.G 93.13,18.2 89.61,18.2 v1(89.42,18.01) 88.84,18.01 R1186.1
  BOTTOM w0.102: Q104.D 94.22,17.65 v2(94.27,17.7) 94.29,17.7 v3(94.95,18.36)
APU_DIS_3: length 4.9
  TOP w0.102: Q105.D 94.72,17.64 v1(91.77,17.64) 91.52,17.64 R1981.1
APU_LVDS_BL_ADJ: length 158.8
  TOP w0.102: CPU1.F11 77.78,177.9 v4(77.5,178.18)
  L3 w0.127: v3(18.17,176.19) 18.3,176.31 18.88,176.31 19.85,177.29 48.03,177.29 49.31,178.56 51.85,178.56 54.49,181.19 54.49,183.54 60.26,189.32 67.55,189.32 71.87,185 72.83,184.04 73.42,184.04 76.22,181.24 76.22,179.46 v4(77.5,178.18)
  L4 w0.127: v3(38.31,105.97) 38.16,106.12 38.16,115.1 36.74,116.52 36.74,119.98 36.61,120.11 36.61,134.93 31.62,139.92 25.94,139.92 24.96,140.9 24.96,146.75 22.13,149.58 22.13,150.96 20.14,152.95 18.99,152.95 17.95,153.98 17.95,163.59 17.15,164.4 17.15,165.56 18.87,167.28 18.87,169.49 18.69,169.66 18.69,171.65 17.93,172.41 17.93,175.95 v3(18.17,176.19)
  BOTTOM w0.102: v3(18.17,176.19) 18.32,176.34 v2(18.32,176.99) ; R502.2 38.2,105.85 v3(38.31,105.97)
APU_M_VREF_SUS: length 5.4
  BOTTOM w0.254: v2(95.72,164.1) 95.72,164.59 95.73,164.6 R1588.2 R115.1 C1609.2 C1608.1 95.73,168.91 R1912.1
APU_M_VREFDQ_SUS: length 76
  TOP w0.254: R81.1 v1(88.72,187.01) ; R81.1 v3(87.03,187.81) ; R81.1 R1697.1 ; DIMM1.1 135.59,190.55 136.49,191.45 v3(136.89,191.45) ; v3(149,191.39) 148.17,190.55 DIMM2.1
  L3 w0.254: v3(87.03,187.81) 129.67,187.81 132.88,191.01 136.44,191.01 v3(136.89,191.45)
  BOTTOM w0.254: v3(136.89,191.45) R78.1 C1727.2 C1731.2 C1728.1 C15.1 R1633.2 R2057.2 R2058.1 C1981.2 C1982.2 C1959.1 C1960.1 148.94,191.45 v3(149,191.39)
APU_PROCHOT#: length 531.3
  TOP w0.102: R1615.2 79.73,193.42 80.91,193.42 v3(80.93,193.4) ; CPU1.A15 81.3,182 81.3,182.83 80.93,183.2 v4(80.93,183.51) ; v3(33.94,225.27) 34.58,225.91 65.46,225.91 65.56,225.81 78.52,225.81 80.04,224.28 82.58,224.28 v3(83.6,225.3) 84.47,226.16 87.3,226.16 v3(87.92,225.55) ; v3(88.96,73.28) 87.31,71.63 87.31,64.64 84.54,61.87 83.12,61.87 82.82,61.58 74.6,61.58 73.9,62.28 72.32,62.28 71.72,62.88 71.72,64.9 PQ4408.D
  L3 w0.127: v3(80.68,208.31) 81.88,209.51 81.88,218.95 84.15,221.21 84.15,224.75 v3(83.6,225.3) ; v3(88.96,73.28) 89.21,73.03 96.49,73.03 97.07,73.6 105.29,73.6 110.22,68.66 110.69,68.2 110.69,67.37 112.83,65.23 123.45,65.23 124.06,64.62 127.46,64.62 128.52,65.67 133.17,65.67 133.35,65.85 134.23,65.85 135.36,66.98 135.95,66.98 136.43,67.46 v3(137.5,67.46) ; v3(155.7,50.39) 154.99,49.68 153.91,49.68 153.89,49.7 153.89,49.7 153.56,50.03 150.01,50.03 149.67,49.68 148.56,49.68 147.9,49.02 142.64,49.02 142.09,48.48 140.65,48.48 140.01,47.84 137.54,47.84 v3(137.09,47.4) ; v3(93,196.34) 94.74,198.08 94.74,216.45 87.92,223.27 v3(87.92,225.55)
  L4 w0.127: v3(137.09,47.4) 137.12,47.4 137.8,48.08 137.8,52.27 138.05,52.52 138.05,52.55 138.72,53.22 138.72,64.14 137.83,65.02 137.83,66.24 137.5,66.57 v3(137.5,67.46) 140.23,70.19 140.23,71.55 147.39,78.72 147.39,88.9 148.24,89.75 148.24,97.42 147.39,98.27 147.39,106.38 147.39,106.38 147.39,107.14 149.53,109.28 149.53,122.24 153.84,126.54 153.84,130.83 154.49,131.48 154.49,191.33 151.55,194.27 106.07,194.27 104.47,195.87 94.5,195.87 94.23,196.15 94.23,196.54 93.95,196.81 93.47,196.81 v3(93,196.34) 93,196.26 92.36,195.62 88.17,195.62 86.37,197.42 80.63,197.42 80.21,197 80.21,195.73 78.18,193.7 78.18,191.48 79.92,189.74 ; v3(85.38,49.53) 86.94,51.1 86.94,62.16 89.31,64.53 89.31,72.92 v3(88.96,73.28) ; 79.92,189.74 79.92,192.38 v3(80.93,193.4) ; 79.92,189.74 79.92,185.72 80.21,185.43 80.21,184.24 v4(80.93,183.51)
  BOTTOM w0.102: R80226.1 156.79,50.23 156.56,50.46 155.77,50.46 v3(155.7,50.39) ; v3(33.94,225.27) PR24.2 ; PR4455.1 75.47,50.16 76.23,49.4 77.03,49.4 77.26,49.17 78.4,49.17 79.37,50.14 84.77,50.14 v3(85.38,49.53) 86.32,48.59 88.75,48.59 90.21,47.13 92.12,47.13 94.42,49.43 96.58,49.43 96.93,49.07 99.91,49.07 100.07,49.24 U4101.14 ; PR5464.2 79.95,209.11 79.74,208.89 v2(79.74,208.71) 79.74,208.51 79.94,208.31 v3(80.68,208.31)
APU_PWNBTN_N: length 14.6
  TOP w0.102: R1653.2 v3(58.05,162.69) ; CPU1.AE1 69.85,162.6 69.85,162.6 67.89,162.6 v4(67.55,162.26)
  BOTTOM w0.102: v2(67.76,163.3) 67.55,163.09 v4(67.55,162.26) 67.19,161.89 58.84,161.89 v3(58.05,162.69)
APU_PWRGD: length 40.7
  TOP w0.102: R1744.2 89,212.08 v3(88.98,212.06) ; CPU1.C19 84.6,180.67 84.3,180.97 84.3,181.28 84.31,181.29 84.31,181.77 84.3,181.77 84.3,182.03 85.29,183.02 v4(85.4,183.02) ; R495.2 85,189.11 84.97,189.08 v1(84.97,188.98) ; R495.2 C1722.2 ; R495.2 R1720.1 R1904.1 v3(87.03,189.33)
  L3 w0.127: v3(87.03,189.33) 88.81,191.11 88.81,196.44 88.16,197.09 88.16,197.48 89.1,198.41 89.1,207.58 89.07,207.61 89.07,211.75 88.98,211.84 v3(88.98,212.06)
  L4 w0.127: v4(85.4,183.02) 85.4,183.06 86.56,184.22 86.56,188.86 v3(87.03,189.33)
APU_PWRGD_BUF: length 5.5
  TOP w0.102: v1(87.66,213.59) 87.71,213.64 89.7,213.64 89.89,213.45 R1744.1 HDT1.10
APU_S5_MUX_CTRL: length 485.8
  TOP w0.102: v3(75.34,159.51) 75.7,159.87 CPU1.AH8 ; v3(161.02,106.88) 161.02,105.99 v1(161.15,105.87) 161.42,105.59 163.26,105.59 163.87,104.98 169.98,104.98 v3(170.31,105.31)
  L3 w0.127: v3(161.02,106.88) 161.02,105.46 162.36,104.12 162.36,104.1 162.64,103.82 162.64,99.39 155.79,92.53 155.79,89.13 155.05,88.39 155.05,80.44 155.01,80.4 155.01,75.8 155.05,75.76 155.05,75.46 155.61,74.9 155.61,74.45 157.13,72.92 157.13,72.21 157.5,71.84 157.5,71.07 158.15,70.42 158.85,70.42 160.37,68.9 160.37,67.91 160.15,67.69 159.66,67.69 159.23,67.27 158.84,67.27 158.42,67.69 155.71,67.69 153.22,70.18 149.03,70.18 148.61,69.76 148.06,69.76 147.65,69.35 147.16,69.35 146.75,69.76 144.52,69.76 143.45,68.69 136.02,68.69 135.48,68.16 134.84,68.16 133.68,66.99 132.88,66.99 132.7,66.81 124.69,66.81 124.5,67.01 114.8,67.01 111.37,70.43 110.86,70.43 110.46,70.83 109.75,70.83 104.21,76.36 104.21,80.21 102.97,81.45 93.82,81.45 89.28,76.91 73.88,76.91 72.92,77.87 71.16,77.87 69.78,76.49 61.93,76.49 61,75.57 44.89,75.57 40.11,80.34 40.11,106.65 36.88,109.89 36.88,115.42 35.59,116.7 35.59,131.98 29.02,138.56 17.77,138.56 15.39,140.94 15.39,151.76 12.45,154.7 12.45,164.58 15.8,167.93 25.02,167.93 27.25,165.7 38.27,165.7 39.96,164.02 59.02,164.02 61.02,162.01 61.53,162.01 61.59,161.96 65.95,161.96 66.45,161.46 68.36,161.46 68.88,160.93 72,160.93 72.68,160.26 73.27,160.26 73.38,160.15 74.71,160.15 v3(75.34,159.51)
  L4 w0.127: v3(170.31,105.31) 171.11,106.1 171.11,107.79 171.1,107.8 171.1,128.09 168.12,131.08 168.12,136.73 167.58,137.26 167.58,196.43 160.56,203.45 157.33,203.45 156.5,204.28 153.87,206.92 153.87,208.91 153.49,209.3 149.64,209.3 v3(148.5,210.44)
  BOTTOM w0.102: R4230.1 150.91,209.68 150.15,210.44 v3(148.5,210.44)
APU_S5_MUX_CTRL_D: length 4.3
  TOP w0.102: v1(148.88,209.41) 149.53,210.06 Q4701.2 ; v1(148.88,209.41) Q4701.3 ; v1(148.88,209.41) 148.48,209.8 R4702.2
APU_S5_MUX_CTRL_R: length 7.2
  TOP w0.102: Q4701.5 153.09,210.06 v3(153.25,209.91)
  BOTTOM w0.102: PC5429.1 151.8,211.77 R79675.2 152.31,211.71 v2(152.81,211.2) 152.31,210.69 R79674.2 R4230.2 152.18,209.68 152.41,209.91 v3(153.25,209.91)
APU_SATA_LED_N: length 352
  TOP w0.102: v4(82.31,146.56) 81.7,147.17 81.7,148.23 81.4,148.53 CPU1.BB15
  L3 w0.254: v3(91.85,63.12) 92.41,62.56 94.55,62.56 96.53,60.58 106.53,60.58 108.01,60.58 108.27,60.31 108.27,60.31 108.87,59.72 110.78,59.72 112.54,61.48 128.9,61.48 129.98,62.56 135.3,62.56 135.6,62.86 138.36,62.86 140.14,64.64 142.34,64.64 144.84,67.14 154.48,67.14 155.23,66.4 160.01,66.4 161.09,67.48 161.09,69.27 158.2,72.16 158.2,73.25 157.81,73.64 157.81,74.03 155.74,76.1 155.74,80.1 155.85,80.21 155.85,81.58 156.7,82.43 156.7,82.87 156.05,83.52 156.05,86.54 156.76,87.25 156.76,92.49 161.79,97.51 164.01,97.51 164.48,97.98 164.48,109.49 164.39,109.58 164.39,110.34 159.99,114.75 159.99,115.91 159.04,116.86 134.25,116.86 120.15,130.96 92.59,130.96 89.36,134.19 87.81,134.19 85.68,136.32 84.68,136.32 82.68,138.32 82.68,144.97 82.79,145.09 82.79,146.12 82.51,146.41 82.46,146.41 v4(82.31,146.56) ; v3(90.43,36.03) 88.01,36.03 82.72,30.73 67.88,30.73 65.71,32.91 48.9,32.91 43.32,27.33 41.68,27.33 37.6,23.25 36.95,23.25 36.08,22.38 34.55,22.38 v3(34.07,22.86) 34.07,21.4 33.69,21.02 33.69,20.68 31.5,18.5 31.5,18.32 31.19,18.01 30.67,18.01 30.45,17.78 28.1,17.78 27.08,16.76 27.08,15.11 27.8,14.39 27.8,13.67 v3(27.08,12.95)
  L4 w0.254: v3(34.07,22.86) 33.94,22.99 33.94,24.84 30.54,28.24 30.54,28.57 30.23,28.88 v3(29.12,28.88) ; v3(90.43,36.03) 90.43,37.07 90.1,37.4 90.1,48.38 87.92,50.56 87.92,58.68 91.85,62.61 v3(91.85,63.12)
  BOTTOM w0.254: v3(29.12,28.88) 28.54,29.45 R1754.1 R2077.2 ; Q9646.4 26.34,12.21 v3(27.08,12.95) ; v3(90.43,36.03) 90.43,36.93 v2(90.46,36.96)
APU_SIC: length 243.2
  TOP w0.102: R93.2 v3(85,193.4) ; v3(149.33,61.7) 149.66,61.38 U109.51 ; CPU1.B18 83.8,181.07 83.5,181.37 83.5,181.63 83.51,181.63 83.51,183.53 v4(82.96,184.07)
  L3 w0.127: v3(136.18,60.86) 136.75,60.86 136.81,60.92 140.69,60.92 142.59,62.83 148.12,62.83 148.94,62.01 149.02,62.01 v3(149.33,61.7)
  L4 w0.127: v4(82.96,184.07) 84.2,185.31 84.2,192.6 v3(85,193.4) 86.46,194.86 92.99,194.86 93.09,194.95 104.67,194.95 105.86,193.76 151.33,193.76 153.98,191.12 153.98,133.25 153.31,132.57 151.4,132.57 150.82,132 150.82,129.81 149.26,128.25 149.26,123.43 149.02,123.2 149.02,109.49 146.88,107.35 146.88,106.17 146.89,106.17 146.89,98.06 147.7,97.25 147.7,96.19 146.77,95.26 146.77,91.31 147.7,90.38 147.7,89.93 146.89,89.11 146.89,78.93 139.72,71.76 139.72,70.73 136.77,67.79 136.77,66.39 136.05,65.67 136.05,63.72 136.03,63.7 136.03,63.1 136.05,63.08 136.05,61.47 136.18,61.34 v3(136.18,60.86)
  BOTTOM w0.102: v3(136.18,60.86) 136.18,61.17 v2(135.72,61.62)
APU_SID: length 245
  TOP w0.102: CPU1.C17 83,180.67 82.7,180.97 82.7,181.28 82.71,181.29 82.71,181.77 82.7,181.77 82.7,182.23 82.72,182.26 82.72,182.76 82.15,183.34 82.15,184.99 82.51,185.34 v4(82.96,185.34) R1614.2 ; v3(149.59,59.03) 149.66,59.03 150.06,59.43 U109.50
  L3 w0.127: v3(137.32,59.69) 142.88,59.69 143.55,60.36 143.61,60.36 143.95,60.71 147.46,60.71 148.29,59.88 148.54,59.88 149.39,59.03 v3(149.59,59.03)
  L4 w0.127: v4(82.96,185.34) 83.94,186.32 83.94,193.01 86.05,195.11 92.89,195.11 92.98,195.21 104.78,195.21 105.97,194.02 151.44,194.02 154.24,191.22 154.24,131.85 153.73,131.35 151.42,131.35 151.07,131 151.07,129.71 149.51,128.14 149.51,123.33 149.28,123.09 149.28,109.39 147.14,107.25 147.14,106.28 147.14,106.28 147.14,98.17 147.99,97.32 147.99,89.86 147.14,89.01 147.14,78.82 139.97,71.66 139.97,70.62 137.03,67.68 137.03,66.28 136.3,65.56 136.3,63.61 136.28,63.59 136.28,63.2 137.32,62.16 v3(137.32,59.69)
  BOTTOM w0.102: v3(137.32,59.69) v2(137.32,60.58)
APU_SPKR: length 133.7
  TOP w0.102: CPU1.BA17 83.35,149.36 83.35,148.47 83.51,148.31 83.51,147.89 83.39,147.78 83.39,147.41 83.66,147.14 84.27,147.14 v4(84.28,147.13) ; R208.1 167.61,87.76 168.89,87.76 169.15,88.01 169.15,89.38 168.54,89.99 v3(168.54,90.56)
  L3 w0.102: v3(168.54,90.56) 166.61,92.49 166.61,94.21 165.36,95.45 165.36,109.55 165.06,109.86 165.06,112.6 162.39,115.27 161.5,115.27 161.17,115.27 160.9,115.54 160.9,116.29 159.42,117.77 134.63,117.77 120.53,131.87 92.97,131.87 88.59,136.26 87.09,136.26 83.96,139.39 83.96,144.08 84.36,144.48 84.36,144.53 84.49,144.66 84.49,144.77 84.69,144.97 84.69,146.72 v4(84.28,147.13)
  BOTTOM w0.102: v2(168.46,91.52) 168.46,90.64 v3(168.54,90.56)
APU_SVC: length 14.3
  TOP w0.102: R1902.1 R1628.1 80.08,190.18 v3(80.93,189.33) ; v4(80.93,185.42) 81.95,184.4 81.95,183.25 82.52,182.68 82.52,182.34 82.49,182.32 82.49,181.63 82.5,181.63 82.5,181.37 82.49,181.37 82.49,180.83 82.61,180.72 82.61,179.89 CPU1.D17
  L4 w0.127: v3(80.93,189.33) 80.42,188.82 80.42,185.93 v4(80.93,185.42)
  BOTTOM w0.102: v2(80.93,186.16) v4(80.93,185.42)
APU_SVD: length 18
  TOP w0.102: R1630.1 R1903.1 v3(87.03,193.4) ; v4(85.4,183.66) 84.09,182.35 84.09,181.69 84.1,181.68 84.1,181.37 84.09,181.37 84.09,180.89 84.1,180.88 84.1,180.37 84.6,179.87 CPU1.D19
  L4 w0.127: v4(85.4,183.66) 86.33,184.59 86.33,185.24 86.18,185.39 86.18,189.02 86.52,189.36 86.52,192.89 v3(87.03,193.4)
  BOTTOM w0.102: v4(85.4,183.66) 85.4,184.3 85.4,184.3 v2(85.4,184.37)
APU_SVT: length 7.7
  TOP w0.102: R1901.1 R1632.1 80.12,185.3 v1(80.12,185.04) 80.12,183.73 81.1,182.75 81.1,181.77 81.14,181.73 81.14,181.27 81.1,181.23 81.1,180.97 81.4,180.67 CPU1.C15
APU_TCK: length 56.1
  TOP w0.102: v4(77.98,183.28) 78.5,182.76 78.5,181.57 79.07,181 79.13,181 79.5,180.63 79.5,180.17 79.8,179.87 CPU1.D13 ; HDT1.2 91.27,208.03 v3(90.81,208.48)
  L3 w0.127: v3(91.25,203.24) 91.25,208.04 v3(90.81,208.48)
  L4 w0.127: v3(91.25,203.24) 90.23,202.22 76.66,202.22 72.51,198.07 72.51,193.35 75.6,190.27 75.6,187.86 77.5,185.96 77.5,183.76 v4(77.98,183.28)
  BOTTOM w0.102: RN12.2 96.02,209.63 95.46,209.07 94.44,209.07 93.86,208.48 v2(93.13,208.48) v3(90.81,208.48)
APU_TDI: length 59.4
  TOP w0.102: v3(90.81,210.11) 91.27,210.57 HDT1.6 ; CPU1.H15 81.63,176.3 v4(81.33,176.6)
  L3 w0.127: v3(92.06,196.34) 91.29,197.11 91.29,202.25 92.06,203.02 92.06,208.86 v3(90.81,210.11)
  L4 w0.127: v3(92.06,196.34) 91.59,196.81 88.06,196.81 86.69,198.18 79.72,198.18 77.41,195.88 77.41,188.2 79.41,186.2 79.41,185.51 79.7,185.21 79.7,181.5 81.02,180.18 81.02,179.83 80.91,179.73 80.91,177.02 v4(81.33,176.6)
  BOTTOM w0.102: RN12.1 v2(91.78,209.96) 90.96,209.96 v3(90.81,210.11)
APU_TDO: length 61.5
  TOP w0.102: v4(80.13,176.6) 80.43,176.3 CPU1.H14 ; HDT1.8 91.09,211.84 v3(90.81,211.56)
  L3 w0.127: v3(90.81,211.56) 91.09,211.56 92.53,210.12 v3(92.53,203.2)
  L4 w0.127: v4(80.13,176.6) 80.13,176.62 80.55,177.04 80.55,179.45 79.88,180.13 79.88,180.48 78.14,182.22 77.81,182.22 76.64,183.39 76.64,186.1 75.09,187.65 75.09,190.06 72,193.14 72,198.28 76.45,202.73 88.95,202.73 89.59,203.37 89.59,203.43 89.86,203.71 92.02,203.71 v3(92.53,203.2)
  BOTTOM w0.102: v2(91.98,203.96) 91.98,203.75 v3(92.53,203.2)
APU_TEST0: length 22.3
  TOP w0.102: v3(58.81,162.69) 57.79,163.7 R1658.2 R1664.2 ; CPU1.AH6 73.8,159.9 v4(73.8,159.6)
  L3 w0.127: v3(58.81,162.69) 59.86,161.63 61.37,161.63 61.43,161.58 65.79,161.58 66.29,161.08 68.22,161.08 68.66,160.63 70.94,160.63 71.76,159.8 72.11,159.8 72.33,160.02 73.18,160.02 73.6,159.6 v4(73.8,159.6)
  BOTTOM w0.102: v3(58.81,162.69) 58.35,163.14 57.02,163.14 v2(56.98,163.1)
APU_TEST1: length 22.5
  TOP w0.102: v3(59.49,160.78) 59.04,161.24 58.02,161.24 57.44,160.66 R1690.2 R1665.2 ; CPU1.AK8 75.4,158.7 v4(75.4,158.4)
  L3 w0.127: v4(75.4,158.4) 74.62,159.18 72.83,159.18 72.66,159.35 71.57,159.35 70.95,159.97 70.2,159.97 70.16,160.01 68.29,160.01 67.99,160.31 63.31,160.31 63.21,160.21 60.07,160.21 v3(59.49,160.78)
  BOTTOM w0.102: v3(59.49,160.78) 58.81,160.1 v2(58.81,159.94)
APU_TEST2: length 12.2
  TOP w0.102: CPU1.AE3 71.33,162.6 71.03,162.9 70.77,162.9 70.77,162.89 70.23,162.89 70.23,162.9 66.84,162.9 65.73,161.8 65.73,161.17 v1(64.51,159.95) 63.88,159.32 63.28,159.32 R1691.2 R1666.2
APU_TEST4: length 1.8
  TOP w0.102: CPU1.P24 v4(88.95,171.55)
  BOTTOM w0.102: TP176.1 89.23,171.83 v4(88.95,171.55)
APU_TEST5: length 2.5
  TOP w0.102: v4(89.9,172.8) 89,172.8 CPU1.N24
  BOTTOM w0.102: v4(89.9,172.8) 89.37,173.33 TP177.1
APU_TEST6: length 3.5
  TOP w0.102: v4(87.92,155.83) 87.92,156.12 CPU1.AN24
  BOTTOM w0.102: v4(87.92,155.83) 88.04,155.7 89.31,155.7 TP178.1
APU_TEST9: length 2.9
  TOP w0.102: CPU1.AB8 75.3,164.6 v4(75.3,164.4)
  BOTTOM w0.102: TP179.1 76.69,165.02 75.73,165.02 75.3,164.6 v4(75.3,164.4)
APU_TEST10: length 1.9
  TOP w0.102: v4(76.06,165.56) 76.5,166 CPU1.Y9
  BOTTOM w0.102: TP180.1 75.55,166.04 76.03,165.56 v4(76.06,165.56)
APU_TEST11: length 6.3
  TOP w0.102: CPU1.B11 77.69,181.61 77.69,181.81 77.23,182.27 77.23,183.59 76.39,184.43 76.39,184.45 75.95,184.89 v1(75.94,184.89) 75.9,184.92 75.9,184.94 75.52,185.32 75.5,185.32 75.22,185.6 R1607.1
APU_TEST14: length 10.3
  TOP w0.102: R1604.1 71.15,185.9 70.42,185.17 v1(70.42,184.94) 70.42,184.81 70.67,184.56 72.91,184.56 73.09,184.37 73.7,184.37 76.47,181.6 76.53,181.6 76.9,181.23 76.9,181.2 CPU1.B10
APU_TEST15: length 10.3
  TOP w0.102: TP181.1 75.85,185.73 76.5,185.08 76.85,185.08 77.25,184.68 77.25,184.33 77.44,184.14 77.44,182.35 77.9,181.89 77.9,181.77 78.27,181.4 78.33,181.4 78.5,181.23 78.5,179.8 CPU1.D11
APU_TEST16: length 6
  TOP w0.102: CPU1.A10 77.2,181.7 77.2,182.02 77.03,182.19 77.03,182.55 74.66,184.92 v1(74.66,185.04) 74.54,185.04 74.2,185.38 R1605.1
APU_TEST17: length 8.2
  TOP w0.102: R1606.1 73.19,185.32 v1(73.39,185.12) 73.73,184.77 74.15,184.77 77,181.93 77,181.48 77.27,181.2 77.33,181.2 78.2,180.33 CPU1.C11
APU_TEST28_H: length 9.4
  TOP w0.102: CPU1.A13 79.8,182.48 79.2,183.07 78.79,183.07 77.46,184.4 77.46,184.81 76.96,185.32 76.58,185.32 76.14,185.76 76.14,187.49 77,188.34 TP182.1
APU_TEST28_L: length 10.3
  TOP w0.102: TP183.1 77.38,187.58 76.7,187.58 76.37,187.25 76.37,185.85 76.55,185.67 76.89,185.67 77.67,184.9 77.67,184.52 78.91,183.28 79.29,183.28 80.1,182.46 80.1,181.72 79.8,181.42 CPU1.B13
APU_TEST31: length 3.1
  TOP w0.102: v4(90.7,171.6) 90.3,171.2 CPU1.P26
  BOTTOM w0.102: v4(90.7,171.6) 90.7,172.06 91.12,172.48 91.12,172.81 90.71,173.22 TP184.1
APU_TEST37: length 11.6
  TOP w0.102: CPU1.A17 82.93,181.97 82.93,182.85 82.36,183.42 82.36,184.1 v4(82.96,184.71) ; v3(82.96,189.33) 82.11,190.18 R1610.1 R545.1
  L4 w0.127: v3(82.96,189.33) 82.49,188.86 82.49,185.18 v4(82.96,184.71)
  BOTTOM w0.102: v2(83.73,184.53) 83.55,184.71 v4(82.96,184.71)
APU_TEST410: length 3.4
  TOP w0.102: v4(87.92,157.1) 87.92,158.52 CPU1.AK24
  BOTTOM w0.102: TP37.1 v4(87.92,157.1)
APU_TEST411: length 2.6
  TOP w0.102: CPU1.AL24 88.4,157.5 v4(88.81,157.1)
  BOTTOM w0.102: v4(88.81,157.1) 89.7,156.21 TP175.1
APU_TMS: length 60.3
  TOP w0.102: CPU1.G15 81.63,177.1 v4(81.33,177.4) ; HDT1.4 v3(90.81,209.3)
  L3 w0.127: v3(90.81,209.3) 91.73,208.38 91.73,203.05 91.03,202.36 91.03,196.6 v3(91.3,196.34)
  L4 w0.127: v3(91.3,196.34) 88.17,196.34 86.58,197.93 80.42,197.93 79.7,197.21 79.7,195.94 77.67,193.91 77.67,188.3 79.66,186.31 79.66,185.61 79.95,185.32 79.95,183.64 81.75,181.85 81.75,177.82 v4(81.33,177.4)
  BOTTOM w0.102: v3(90.81,209.3) 90.33,209.78 90.33,210.44 90.84,210.95 v2(93.61,210.95) 96.68,210.95 96.83,210.79 RN12.3
APU_TRST: length 75.4
  TOP w0.102: v4(80.13,175.8) 80.43,175.5 CPU1.J14 ; R1743.2 C1870.2 v3(101.4,211.84)
  L3 w0.127: v3(96.5,201.17) 96.5,203.28 102.01,208.79 102.01,211.17 101.8,211.39 101.8,211.44 v3(101.4,211.84)
  L4 w0.127: v3(96.5,201.17) 96.5,202.11 94.65,203.96 89.76,203.96 89.33,203.54 89.33,203.47 88.84,202.98 76.35,202.98 71.75,198.38 71.75,193.04 74.84,189.95 74.84,187.54 76.39,185.99 76.39,183.32 77.72,181.99 78.04,181.99 79.65,180.39 79.65,176.28 v4(80.13,175.8)
  BOTTOM w0.102: RN12.4 99.34,209.96 v2(99.36,209.97) 99.54,209.97 v3(101.4,211.84)
APU_VDD_33_18_SEL: length 23.6
  TOP w0.102: v3(78.9,195.94) R1615.1 78.84,195.07 R2022.1 76.49,193.8 R2025.1 76.39,193.55 75.33,194.61 v1(75,194.61) ; R93.1 R1616.1 83.98,195.38 v3(84.54,195.94) ; R1614.1 v3(82.96,187.81)
  L4 w0.127: v3(82.96,187.81) 83.69,188.53 83.69,194.63 84.54,195.48 v3(84.54,195.94)
  BOTTOM w0.102: v3(84.54,195.94) 84.08,195.48 79.36,195.48 v3(78.9,195.94)
APU_VDDIO_AZ: length 22.5
  TOP w0.356: v4(84.8,154.1) 84.57,154.1 84.2,154.47 CPU1.AR19
  TOP w0.508: R1601.1 R1595.2 87.16,137.67 87.26,137.78 87.26,137.83 C1638.1 C1639.1 87.6,141.36 v3(87.94,141.71)
  L3 w0.254: v3(87.94,141.71) 87.97,141.73 87.97,142.44 87.16,143.25 87.16,148.16 86.39,148.92 86.39,150.37 85.49,151.27 85.49,153.48 84.86,154.1 v4(84.8,154.1)
  BOTTOM w0.508: C395.1 85.49,154.1 v4(84.8,154.1) ; v2(88.55,141.1) v3(87.94,141.71)
APU_VRM_PWRGD: length 3.7
  BOTTOM w0.102: PR4624.2 29.23,223.22 29.26,223.22 29.82,222.66 v2(29.93,222.66) 30.44,222.14 30.44,221.44 30.39,221.39 PU4601.7
AUD_BEEP_C: length 5.6
  TOP w0.102: v1(168.16,84.66) 168.02,84.52 C130.2 167.17,84.25 165.04,82.13 164.79,82.13 164.39,81.73 U6.2
AUD_BEEP_R: length 5.9
  TOP w0.102: R208.2 R210.1 ; R210.1 166.47,86.11 C130.1 167.48,85.72 167.97,85.72 167.97,85.72 168.88,85.72 v1(169.31,85.29) ; R210.1 165.55,86.49 R207.2
AUD_DMIC_CLK: length 130.5
  TOP w0.127: v3(160.75,199.54) WEBCM1.4 160.75,196.15 v1(161.07,195.83) ; v3(158.38,96.88) 158.02,96.88 157.11,95.96 v1(157.11,94.36) 157.11,93.52 156.4,92.81 156.4,91.94 156.12,91.66 C121.2 156.18,84.71 L54.2
  L4 w0.127: v3(158.38,96.88) 159.98,98.48 159.98,100.08 159.12,100.93 159.12,103.17 159.52,103.57 160.62,103.57 160.81,103.76 163.08,103.76 164.94,105.62 164.94,110.08 166.62,111.76 166.62,136.43 166.1,136.95 166.1,196.12 162.68,199.54 v3(160.75,199.54)
AUD_DMIC_CLK_R: length 4
  TOP w0.127: v1(157.02,82.81) 157.02,82.8 157.91,82.8 R212.1 158.62,82.69 160.05,81.26 U6.12
AUD_DMIC_CLK_R_1: length 2.3
  TOP w0.127: v1(158.02,85.85) 157.96,85.79 L54.1 158.02,84.65 R212.2
AUD_DMIC_DATA: length 134.2
  TOP w0.127: v3(156.17,82.65) 155.84,82.65 v1(155.23,82.04) 155.67,81.6 C132.2 156.31,81.66 R222.1 ; v3(160.18,200.13) 159.5,199.45 WEBCM1.5 v1(159.5,195.88)
  L4 w0.127: v3(156.17,82.65) 156.12,82.7 156.12,84.92 155.86,85.17 155.86,85.77 156.56,86.47 156.56,87.16 159.75,90.35 159.75,94.28 161.27,95.8 161.27,97.67 161.27,98.4 162.09,99.21 162.09,99.74 162.44,100.09 162.44,100.36 162.66,100.58 162.66,102.98 165.2,105.52 165.2,109.97 166.87,111.65 166.87,136.54 166.57,136.84 166.57,196.01 162.45,200.13 v3(160.18,200.13)
AUD_DMIC_DATA_R: length 3.4
  TOP w0.127: R222.2 158.08,81.09 v1(157.54,80.54) 157.65,80.43 U6.13
AUD_DVDD: length 6.1
  TOP w0.203: U6.7 162.39,83.28
  TOP w0.508: R205.2 R79649.2 158.15,87.44 159.74,87.44 C127.1
  vias: v1(162.31,84.1)
AUD_GP3: length 4.2
  TOP w0.203: R213.2 166.15,84 165.72,83.57 v1(165.59,83.57) 165.59,83.44 163.99,81.84 U6.3
AUD_LINK_BCLK: length 135.9
  TOP w0.102: R79684.1 65.12,137.41 66.07,137.41 v3(66.71,138.05) ; v3(162.54,86.06) 162.54,85.55 163.19,84.9 C126.2 163.33,84.82 163.33,83.34 163.48,83.19 163.48,82.42 163.19,82.13 U6.5
  L3 w0.102: v3(148.85,88.09) 148.85,95.12 148.29,95.68 148.29,100.48 147.81,100.97 147.81,104.49 145.32,106.98 132.34,106.98 118.51,120.82 88.29,120.82 82.11,126.99 80.49,126.99 73.8,133.68 73.8,135.5 71.34,137.95 68.11,137.95 67.82,137.66 67.35,137.66 66.96,138.05 v3(66.71,138.05)
  BOTTOM w0.102: v3(148.85,88.09) 148.95,88.19 150.71,88.19 v2(150.72,88.19) 150.72,88.19 160.57,88.19 162.54,86.21 v3(162.54,86.06)
AUD_LINK_RST_N: length 148.6
  TOP w0.102: v3(163.02,82.7) 162.79,82.47 U6.6 ; R79682.1 C61.1 69.44,138.49 70.14,137.79 70.14,137.67 70.62,137.19 v3(70.7,137.19) ; R314.1 158.78,67.34 158.58,67.55 158.58,68.04 v3(159.04,68.5)
  L3 w0.102: v3(148.85,86.56) 148.01,87.4 148.01,94.84 147.68,95.18 147.68,100.23 147.2,100.71 147.2,104.24 145.06,106.37 132.09,106.37 118.25,120.21 88.03,120.21 81.86,126.38 80.23,126.38 70.7,135.92 v3(70.7,137.19)
  L4 w0.102: v3(163.02,82.7) 160.44,80.11 160.44,73.17 160.72,72.9 160.72,72.19 160.23,71.7 160.23,69.69 v3(159.04,68.5)
  BOTTOM w0.102: v3(163.02,82.7) 163.02,83.52 162.36,84.18 159.44,84.18 158.84,84.78 158.84,84.93 156.76,87.02 v2(154.51,87.02) 149.31,87.02 v3(148.85,86.56)
AUD_LINK_RST_N_2: length 5.5
  TOP w0.254: Q63.6 141.83,31.33 141.61,31.11 141.61,28.93 141.84,28.7 v1(142.07,28.7) 142.27,28.7 142.58,29.01 Q63.4
AUD_LINK_RST_N_R: length 4.7
  TOP w0.102: v1(157.77,66.95) 158.74,65.98 R314.2 158.83,66.03 Q31.B 161.13,64.98 C170.1
AUD_LINK_SDIN: length 150.8
  TOP w0.102: v4(75.45,153.62) 75.7,153.87 CPU1.AR8
  L3 w0.102: v3(148.85,85.04) 149.62,85.8 149.62,95.66 149.01,96.27 149.01,100.64 148.42,101.22 148.42,104.75 145.57,107.6 132.88,107.6 119.02,121.46 88.51,121.46 82.37,127.61 80.74,127.61 74.41,133.94 74.41,135.75 71.6,138.56 68.4,138.56 68.11,138.86 v3(67.39,138.86)
  L4 w0.102: v4(68.69,150.29) 68.69,150.09 69.79,148.98 69.79,145.07 68.61,143.89 68.61,140.08 v3(67.39,138.86)
  BOTTOM w0.102: v4(68.69,150.29) 70.49,150.29 71.2,151 R79678.2 71.75,151.41 73.03,151.41 73.69,152.07 73.69,152.61 74.3,153.22 74.82,153.22 75.23,153.62 v4(75.45,153.62) ; R209.1 158.23,83.55 158.23,84.48 156.78,85.93 155.15,85.93 155.1,85.88 151.12,85.88 151.01,85.99 v2(150.43,85.99) 149.81,85.99 v3(148.85,85.04)
AUD_LINK_SDIN_1: length 5.2
  TOP w0.102: U6.8 161.99,82.74 v3(161.86,82.88)
  BOTTOM w0.102: v2(159.04,82.16) 159.56,82.68 R209.2 159.76,82.91 161.83,82.91 v3(161.86,82.88)
AUD_LINK_SDO: length 134.8
  TOP w0.102: R79685.1 v3(62.72,137.99)
  L3 w0.102: v3(148.85,87.33) 148.34,87.83 148.34,95.02 147.99,95.38 147.99,100.35 147.5,100.84 147.5,104.37 145.19,106.68 132.22,106.68 118.38,120.51 88.16,120.51 81.98,126.69 80.36,126.69 73.49,133.56 73.49,135.37 71.22,137.64 68.74,137.64 68.45,137.35 66.28,137.35 65.64,137.99 v3(62.72,137.99)
  BOTTOM w0.102: C1780.2 163.9,85.6 162.35,85.6 160.66,87.29 Q56.D 158.17,87.29 R618.2 157.88,87.58 v2(156.58,87.58) 149.1,87.58 v3(148.85,87.33)
AUD_LINK_SDO_1: length 5
  BOTTOM w0.102: Q56.G 161.75,85 C1780.1 R617.2 165.83,85 v2(166.1,84.73)
AUD_LINK_SDO_N: length 9.6
  TOP w0.102: U6.4 163.59,82 163.76,82.17 163.76,83.97 v3(163.79,84)
  BOTTOM w0.102: v3(163.79,84) 163.3,84.48 v2(162.9,84.48) 162.9,84.48 161.17,84.48 160.27,85.38 Q56.S 159.19,85.38 R618.1
AUD_LINK_SYNC: length 134.2
  TOP w0.102: R79683.1 67.58,139.38 67.85,139.11 67.85,138.35 v3(67.62,138.12) ; v3(161.5,83.59) 161.4,83.49 161.4,82.63 161.6,82.43 161.6,81.59 161.59,81.59 U6.9
  L3 w0.102: v3(67.62,138.12) 67.84,138.12 67.98,138.26 71.47,138.26 74.1,135.62 74.1,133.81 80.61,127.3 82.24,127.3 88.41,121.13 118.64,121.13 132.47,107.29 145.45,107.29 148.12,104.62 148.12,101.09 148.6,100.61 148.6,96.01 149.31,95.3 149.31,86.26 v3(148.85,85.8)
  BOTTOM w0.102: v3(148.85,85.8) 149.58,86.53 151.24,86.53 151.36,86.41 v2(152.33,86.41) 152.34,86.41 156.78,86.41 159.59,83.59 v3(161.5,83.59)
AUD_REGREF: length 3.9
  TOP w0.203: U6.10 161.19,82.3 161.07,82.42 161.07,82.78 v1(160.41,83.44)
  TOP w0.508: v1(160.41,83.44) 160.15,83.69 C129.1
AZ_BCLK_M: length 21.8
  TOP w0.102: v3(63.41,142.11) 63.62,141.9 63.62,141.85 v1(65.36,140.11) 65.5,139.97 R79681.2 R79684.2 ; CPU1.AU6 v4(74.1,152.44)
  L3 w0.102: v3(63.41,142.11) 63.41,142.38 63.98,142.95 64.2,142.95 66.3,145.06 66.69,145.06 69.97,148.34 71.03,148.34 71.62,148.92 72.43,148.92 73.44,149.94 73.44,151.78 v4(74.1,152.44)
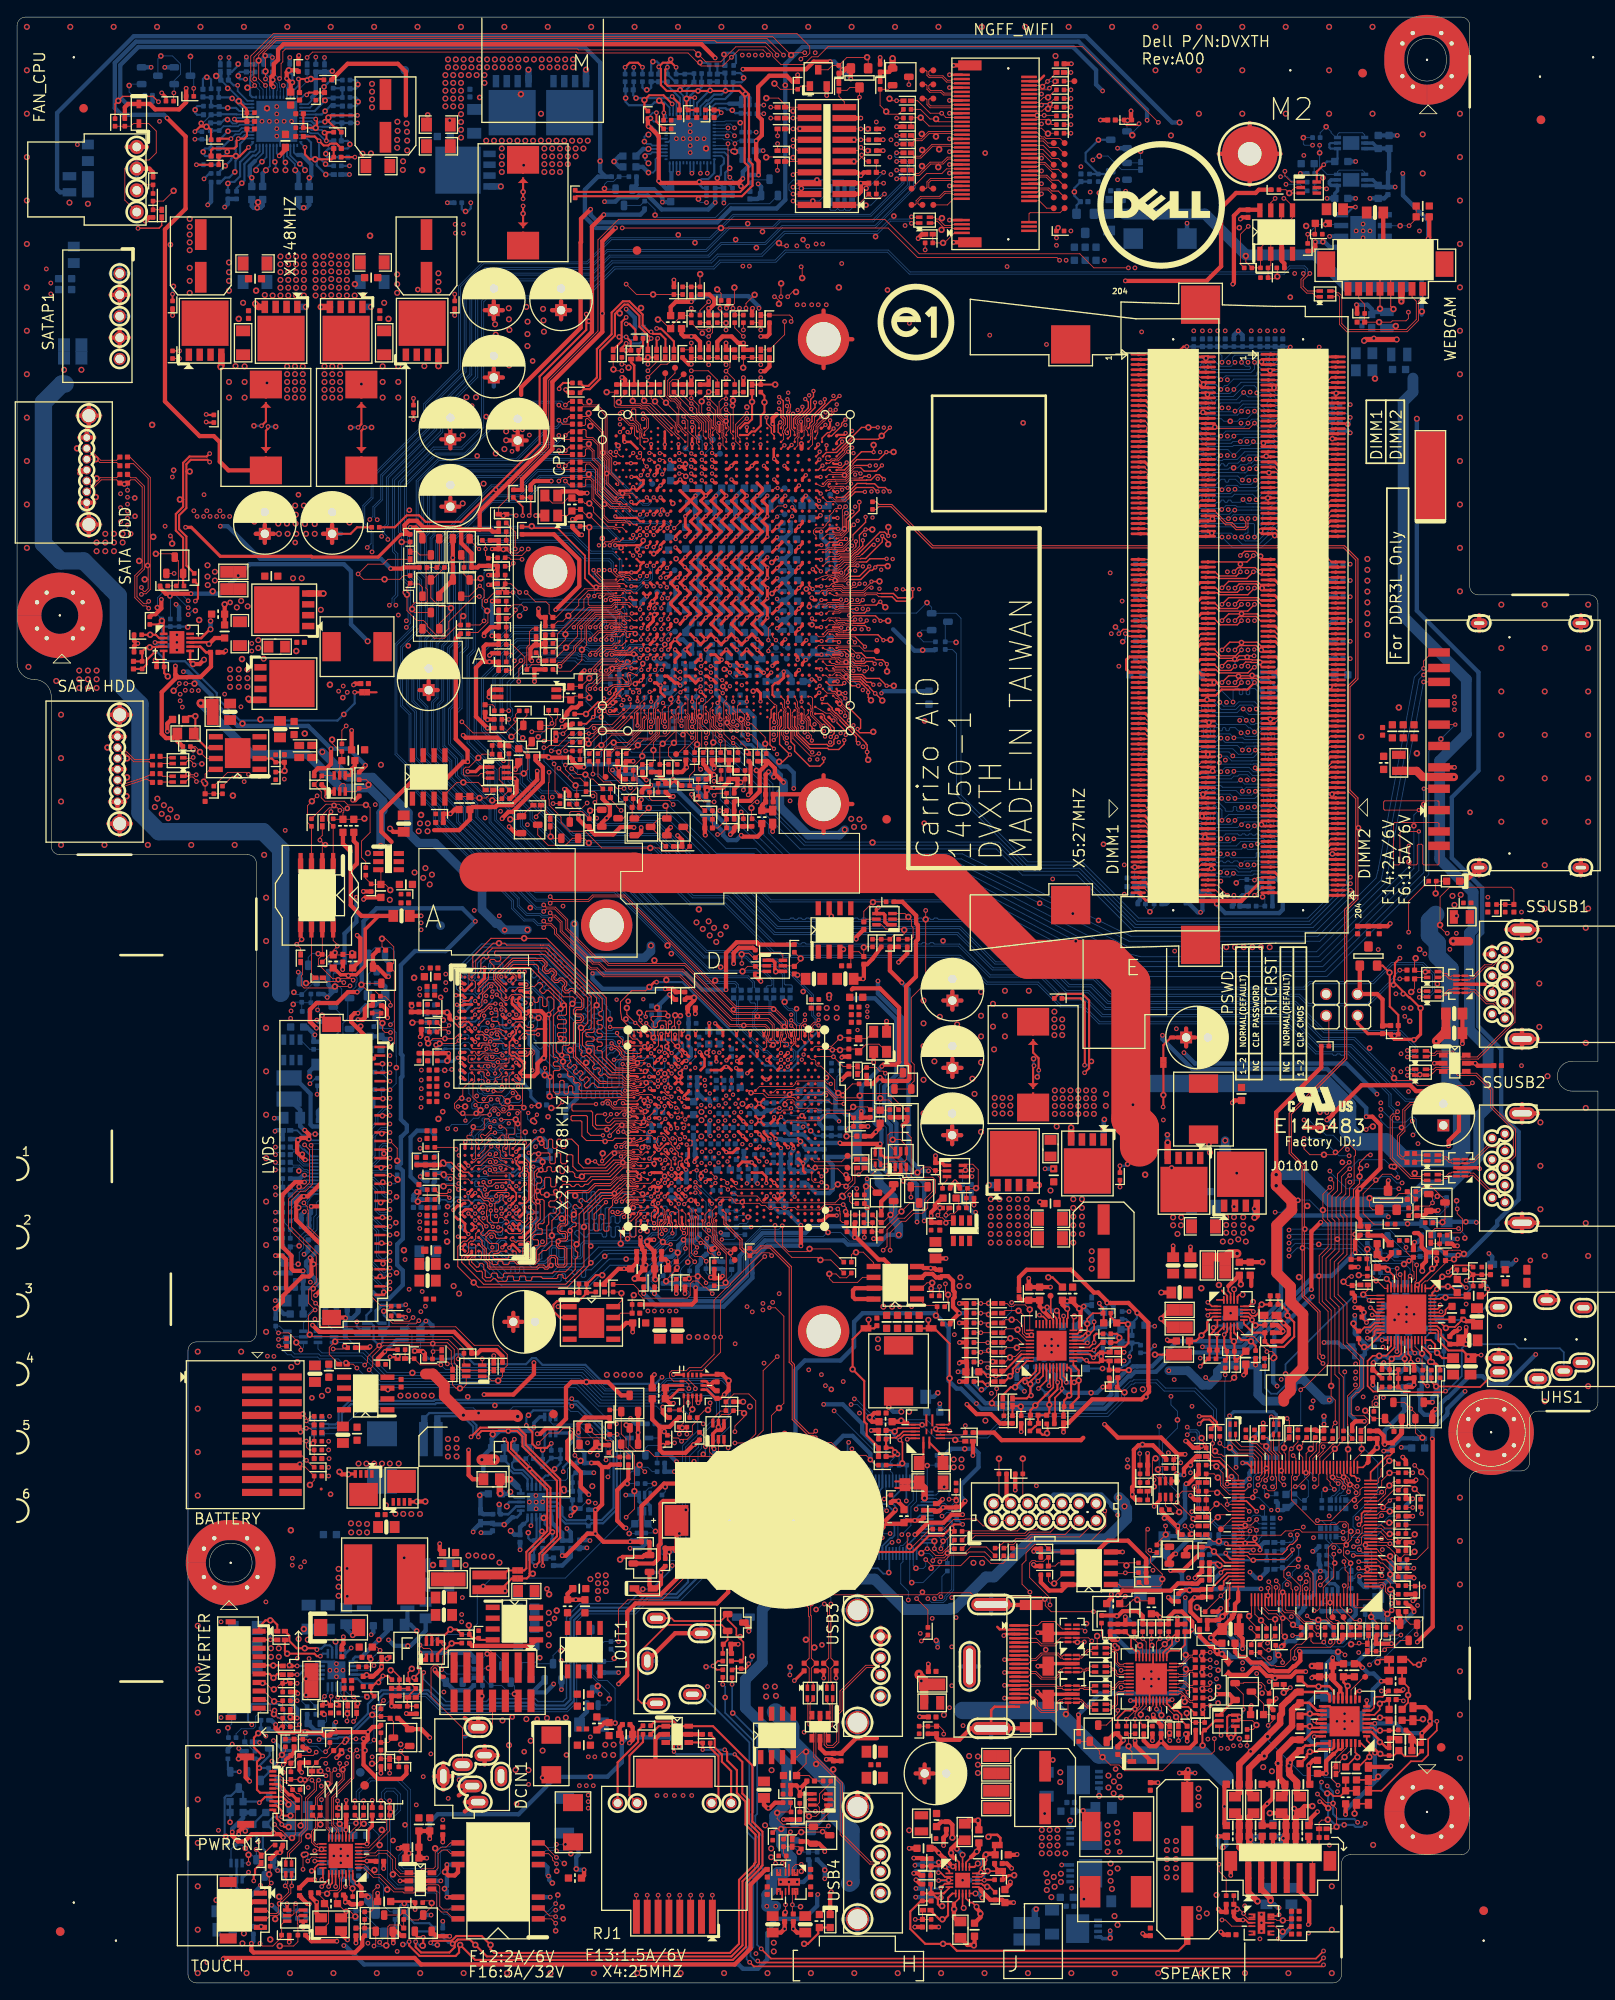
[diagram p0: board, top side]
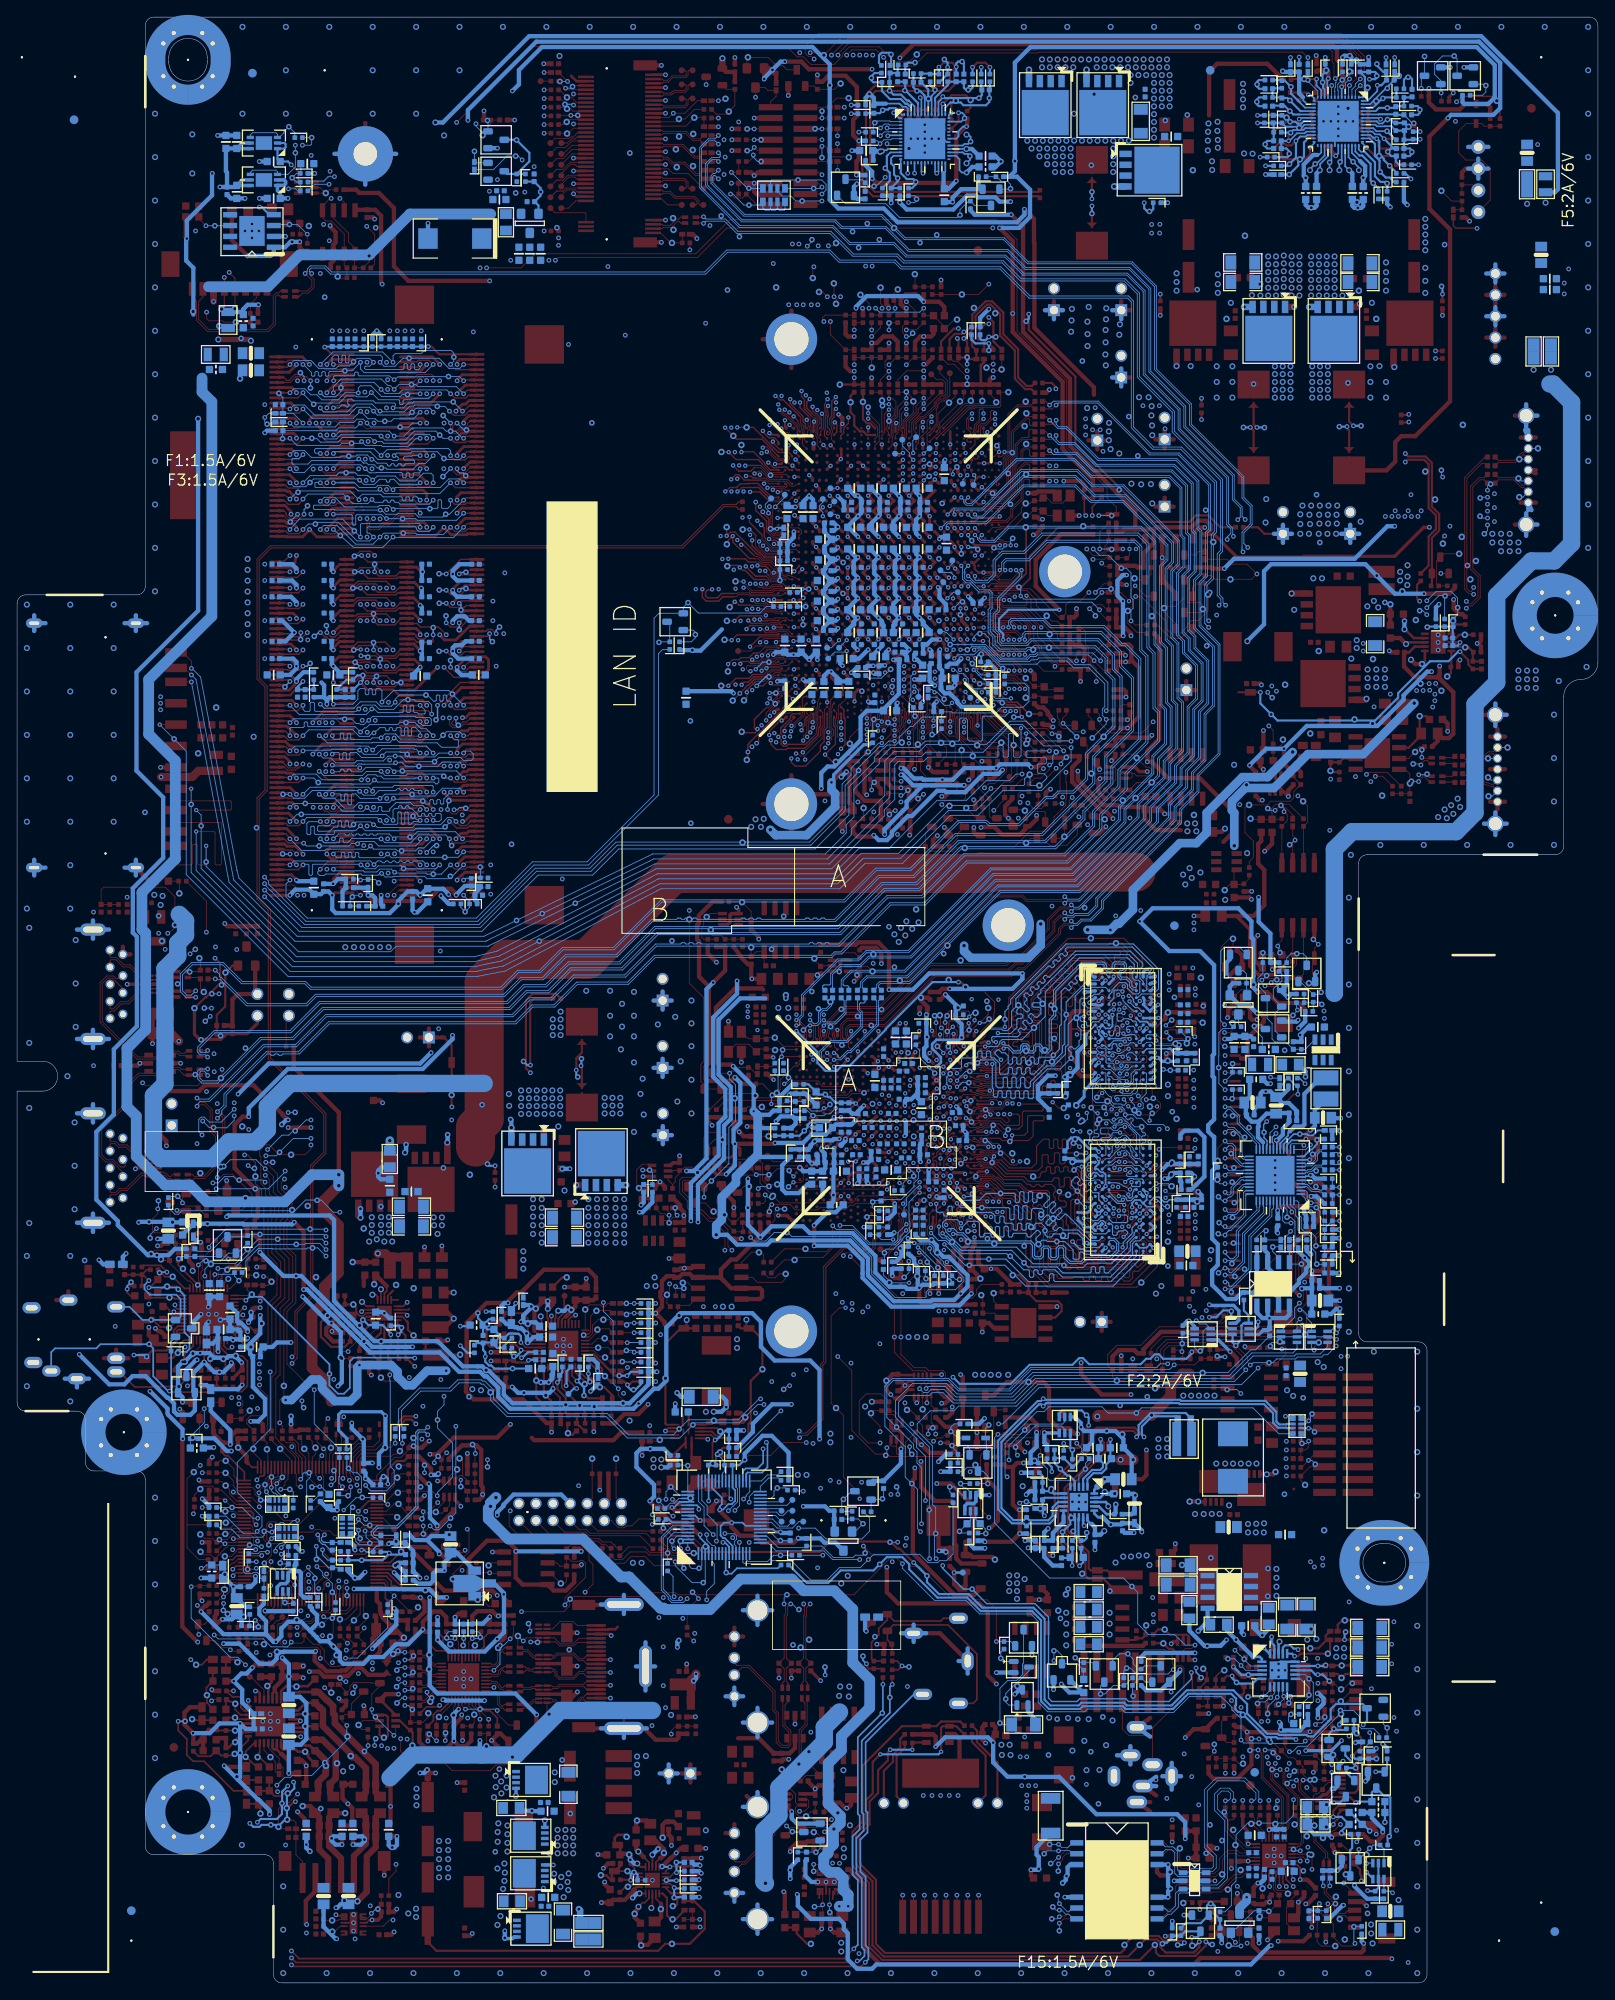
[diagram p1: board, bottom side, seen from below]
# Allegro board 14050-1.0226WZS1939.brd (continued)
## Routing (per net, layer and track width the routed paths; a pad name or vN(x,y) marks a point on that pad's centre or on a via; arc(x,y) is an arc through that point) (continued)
AZ_RST_N_M: length 23
  TOP w0.102: R79682.2 67.4,140.85 67.08,140.85 66.56,141.38 v1(66.5,141.38) 65.59,141.38 v3(64.89,142.07) ; CPU1.AU9 77.3,152.6 v4(77.6,152.6)
  L3 w0.102: v4(77.6,152.6) 77.35,152.6 74.81,150.06 74.81,149.65 74.22,149.06 73.61,149.06 72.87,148.32 71.85,148.32 71.45,147.92 70.3,147.92 66.76,144.38 66.76,144.37 65.88,143.49 65.81,143.49 65.08,142.76 65.08,142.69 64.93,142.54 64.93,142.11 v3(64.89,142.07)
AZ_SDIN1: length 4
  TOP w0.102: CPU1.AP6 74.1,155.34 v4(73.72,154.96)
  BOTTOM w0.102: R79679.2 72.17,153.03 72.65,153.51 72.65,153.79 v2(73.22,154.37) 73.72,154.86 v4(73.72,154.96)
AZ_SDIN2: length 4.1
  TOP w0.102: CPU1.AR5 73.05,153.95 v4(73.05,153.62)
  BOTTOM w0.102: v4(73.05,153.62) 72,152.57 71.89,152.57 R79680.2 71.37,151.99 v2(72.35,151.99)
AZ_SDOUT_M: length 23.4
  TOP w0.102: v4(74.65,153.62) 74.9,153.87 CPU1.AR7 ; R79685.2 62.95,139.46 62.95,142.52 v3(62.84,142.63)
  L3 w0.102: v4(74.65,153.62) 73.42,152.39 73.42,152.23 73.2,152.01 73.2,149.98 72.46,149.25 71.66,149.25 70.95,148.54 69.88,148.54 66.71,145.36 66.18,145.36 64.07,143.26 63.71,143.26 63.08,142.63 v3(62.84,142.63)
  BOTTOM w0.102: v2(62.22,143.39) 62.24,143.39 62.84,142.79 v3(62.84,142.63)
AZ_SYNC_M: length 24.7
  TOP w0.102: v4(77.6,153.4) 77.3,153.4 CPU1.AT9 ; R79683.2 65.89,140.97 65.18,140.97 64.17,141.98 v3(64.17,142.49)
  L3 w0.102: v3(64.17,142.49) 64.45,142.49 64.77,142.82 64.77,142.89 66.74,144.85 66.77,144.85 70.04,148.12 71.37,148.12 71.77,148.52 72.78,148.52 73.53,149.26 74.14,149.26 74.61,149.73 74.61,150.41 v4(77.6,153.4)
  BOTTOM w0.102: v2(63.39,144.02) 63.79,143.62 63.79,142.73 64.03,142.49 v3(64.17,142.49)
BAT_ALERT: length 4.5
  TOP w0.102: BAT2.8B 33.69,60.39 R79648.2 34.77,58.79 34.27,58.29 v1(34.27,58.27)
BAT_IN#: length 137.6
  TOP w0.102: v3(146.47,38.94) 146.07,38.94 R2014.1 146.21,40.32 R80210.1
  L3 w0.127: v3(69.15,59.21) 71.91,59.21 80.54,50.58 86.63,50.58 90.24,46.97 95.79,46.97 96.81,45.95 100.15,45.95 100.52,45.57 101.29,44.81 v3(104.3,44.81) 105.48,43.62 109.74,43.62 110.57,42.79 124.82,42.79 126.57,41.03 127.21,41.03 136.04,41.03 136.69,40.39 137.25,40.39 138.48,41.62 142.06,41.62 142.07,41.61 142.41,41.61 143.79,40.22 146.53,40.22 146.81,39.95 146.81,39.56 146.47,39.22 v3(146.47,38.94)
  BOTTOM w0.102: U4101.5 103.67,49.28 103.41,49.02 103.41,46.71 104.3,45.82 v3(104.3,44.81) ; v3(69.15,59.21) 69.38,59.44 69.38,63.12 65.64,66.85 64.8,66.85 64.24,67.41 58.05,67.41 57.31,66.67 v2(54.01,66.67) 53.4,67.28 40.38,67.28 37.34,64.25 RN4301.4
BAT_IN#_1: length 6.7
  TOP w0.102: BAT2.6B 33.85,63.39 v3(33.85,63.39) 33.85,62.7 34.2,62.36 PL4301.1 PC4304.1
  BOTTOM w0.102: v3(33.85,63.39) 34.13,63.12 v2(34.63,63.12) 34.73,63.21 RN4301.5
BAT_IN#_ECIO: length 3.9
  TOP w0.102: R80210.2 146.21,41.78 v1(145.58,42.42) 144.85,43.14 U109.98
BATA_SCL_1: length 6.5
  TOP w0.102: PC4305.1 PL4302.1 34.39,66.29 v3(33.85,65.76) 33.85,66.13 33.59,66.39 BAT2.4B
  BOTTOM w0.102: RN4301.7 34.21,65.4 v3(33.85,65.76) 33.64,65.97 33.64,66.38 v2(33.45,66.57)
BATA_SDA_1: length 5.7
  TOP w0.102: BAT2.5B 33.85,64.89 v3(33.85,64.89) 34.26,64.89 PC4301.1 PL4303.1
  BOTTOM w0.102: RN4301.6 33.86,64.9 v3(33.85,64.89) 33.59,64.89 v2(33.16,64.47)
BATT_AMBER_LED#: length 9.1
  BOTTOM w0.203: U4101.9 102.07,48.06 v2(102.01,48.01) 101.89,47.88 101.38,47.88 100.74,48.51 95.98,48.51 R79710.2
BATT_AMBER_LED#_C: length 95
  TOP w0.254: PWRCN1.10 30.39,19.79 30.39,19.25 30.97,18.67 v3(30.97,18.54) 31.27,18.24 v1(31.78,18.24)
  L3 w0.254: v3(30.97,18.54) 33.28,20.85 33.28,23.77 34.25,24.73 34.25,25.45 35.57,26.77 35.57,27.27 35.59,27.3 35.59,28.22 v3(35.34,28.47)
  BOTTOM w0.254: R79710.1 94.68,48.9 92.58,46.8 90.08,46.8 88.62,48.26 84.77,48.26 v2(84.06,48.97) 83.22,49.81 81.4,49.81 80.6,49.01 80.6,48.4 77.29,45.09 73.81,45.09 72.22,43.5 66.22,43.5 65.17,42.44 65.17,32.97 64.25,32.05 60.6,32.05 60.28,32.37 55.61,32.37 55.29,32.05 49.72,32.05 47.94,33.83 42.92,33.83 42.35,33.27 42.35,32.53 42.43,32.45 42.43,32.01 42.11,31.7 41.81,31.7 38.86,28.75 37.64,28.75 37.5,28.6 35.47,28.6 v3(35.34,28.47) ; R389.2 v3(30.97,18.54)
BATT_WHITE_LED#: length 3.8
  BOTTOM w0.203: U4101.58 108.36,53.88 108.71,54.23 R79711.2
  BOTTOM w0.254: v2(109.38,53.21) 109.38,53.91 R79711.2
BATT_WHITE_LED#_C: length 123.9
  TOP w0.254: v3(110.66,53.64) 109.66,53.64 108.34,52.32 106.71,52.32 104.81,50.42 91.09,50.42 89.87,51.64 82.79,51.64 81.95,50.8 81.69,50.8 v3(80.07,49.17) ; v3(30.89,21.08) 30.73,21.25 PWRCN1.8
  L4 w0.254: v3(27.47,30.2) 27.49,30.2 27.72,29.97 27.72,25.78 29.22,24.28 29.22,22 30.13,21.08 v3(30.89,21.08)
  BOTTOM w0.254: Q38.C 30.2,21.08 v3(30.89,21.08) 31.28,21.08 31.78,20.57 R79726.2 ; v3(27.47,30.2) 27.02,30.65 Q1214.C 27.53,32.64 30.64,32.64 31.28,32 31.28,30.86 31.53,30.61 33.28,28.85 33.94,28.85 34.09,29.01 37.33,29.01 37.48,29.15 38.69,29.15 41.05,31.51 41.05,32.64 42.65,34.24 48.11,34.24 49.89,32.46 55.12,32.46 55.44,32.78 60.45,32.78 60.77,32.46 64.08,32.46 64.76,33.14 64.76,42.61 66.06,43.9 72.05,43.9 73.64,45.49 77.12,45.49 78.52,46.89 v2(78.52,47.62) v3(80.07,49.17) ; v3(110.66,53.64) 110.07,54.23 R79711.1
BIST_DISABLE: length 137.9
  TOP w0.102: R533.1 R536.1 46.45,73.05 R531.2 47.19,72.31 v3(49.59,72.31) ; v3(150.85,46.94) 150.4,46.48 150.4,45.94 150.46,45.88 U109.112
  L3 w0.127: v3(79.15,53.72) 79.37,53.5 81.21,53.5 81.67,53.05 86.67,53.05 90.42,49.3 96.57,49.3 97.72,48.15 101.06,48.15 101.38,47.82 110.35,47.82 110.92,48.39 121.82,48.39 123.08,47.13 130.09,47.13 130.7,46.52 134.31,46.52 135.02,45.81 139.65,45.81 140.58,46.74 144.82,46.74 145.93,47.84 148.12,47.84 148.43,47.54 148.59,47.37 150.42,47.37 v3(150.85,46.94)
  BOTTOM w0.102: v3(49.59,72.31) 50.12,71.78 66.28,71.78 68.8,69.27 74.84,69.27 76.06,70.48 82.46,70.48 83.22,69.72 83.22,66.17 v2(82.08,65.02) 80.09,63.04 80.09,62.53 79.69,62.13 79.69,60.83 79.15,60.3 v3(79.15,53.72)
BIST_DISABLE_1: length 10.2
  TOP w0.254: v3(43.64,73.25) 43.7,73.2 44.37,73.2 R536.2
  L3 w0.254: v3(43.64,73.25) 43.42,73.03 42.86,73.03 41.94,73.95 41.94,74.71 39.76,76.9 v3(39.76,77.34)
  BOTTOM w0.254: v3(39.76,77.34) 39.76,76.78 40.01,76.53 Q12.5 ; v2(44.56,73.33) 44.43,73.33 44.36,73.25 v3(43.64,73.25)
BIST_EN: length 10.6
  BOTTOM w0.254: R524.2 41.44,78.66 40.88,78.11 Q12.6 41.46,77.18 41.73,76.9 41.71,76.89 41.71,75.23 v2(42.37,74.57) 42.76,74.96 Q12.3 43.96,75.88 43.98,75.9 Q13.2
BIST_EN_INV: length 246.2
  TOP w0.102: v3(164.37,54.89) 164.24,55.02 R80232.2 ; v3(33.56,91.26) 33.56,91.21 33.96,90.81 33.96,90.53 34.07,90.42 34.07,90.04 34.07,90.04 34.07,88.49 39.78,82.78 39.78,81.99 42.3,79.48 42.32,79.48 42.55,79.25 43.71,79.25 R513.1 43.34,78.73 43.34,77.76 43.91,77.19 46.72,77.19 v3(47.01,77.48)
  L3 w0.127: v3(41.55,26.44) 42.92,26.44 49.04,32.56 65.57,32.56 67.74,30.39 90.31,30.39 93.42,33.5 98.93,33.5 100.64,31.8 101.87,30.56 109.53,30.56 111.04,32.08 116.49,32.08 118.2,30.38 130.19,30.38 130.77,29.79 141.18,29.79 142.92,31.53 143.69,31.53 144.12,31.97 144.63,31.97 145.07,32.41 159.01,32.41 164.21,37.61 164.21,38.01 164.37,38.18 164.37,45.94 164.16,46.16 164.16,46.55 164.37,46.77 v3(164.37,54.89)
  L4 w0.127: v3(41.55,26.44) 41.55,26.45 40.77,27.23 40.77,28.75 40.78,28.97 40.58,29.17 40.58,29.56 40.77,29.75 40.77,30.81 40.14,31.45 40.14,33.86 39.26,34.73 39.26,38.01 39.62,38.37 39.62,40.45 39.26,40.81 39.26,41.11 38.77,41.61 38.77,49.31 37.96,50.12 37.96,51.34 37.64,51.65 37.64,54.15 37.57,54.21 34.83,56.96 34.83,63.86 35.72,64.74 36.23,64.74 39.53,68.05 39.53,68.43 40.56,69.46 40.56,69.47 41.32,70.23 41.95,70.23 45.02,73.29 45.02,73.53 47.01,75.53 v3(47.01,77.48)
  BOTTOM w0.102: v3(47.01,77.48) 46.62,77.09 45.86,77.09 Q13.3 45.9,76.55 46.21,76.24 46.21,74.17 46.44,73.94 v2(46.54,73.94) 46.82,73.94 47.2,74.32 Q13.6 ; R517.2 31.97,90.44 32.79,91.26 v3(33.56,91.26) 34.02,91.72 34.02,92.5 34.22,92.7 U26.2
BIST_EN_SIO: length 7.7
  TOP w0.102: R80232.1 164.24,57.1 v1(163.56,57.78) 163.23,58.12 162.16,58.12 161.71,57.66 R1826.1 161.08,57.66 160.03,56.62 159.4,55.98 U109.25
BIST_ENABLE: length 133
  TOP w0.102: R515.1 49.69,73.09 v3(50.35,72.43) ; U109.113 v3(150.85,46.13)
  L3 w0.127: v3(79.28,52.79) 80.26,52.79 80.72,53.25 81.11,53.25 81.56,52.79 86.56,52.79 90.31,49.04 96.46,49.04 97.61,47.89 100.95,47.89 101.27,47.57 110.46,47.57 111.02,48.13 121.72,48.13 122.97,46.88 129.98,46.88 130.59,46.27 134.2,46.27 134.91,45.55 139.76,45.55 140.69,46.48 145.01,46.48 146.04,47.51 148.09,47.51 148.48,47.12 149.86,47.12 150.36,46.62 v3(150.85,46.13)
  BOTTOM w0.102: v3(79.28,52.79) 79.64,53.15 79.64,57.76 v2(80.3,58.42) 81.06,59.18 81.06,62.74 83.45,65.13 83.45,69.82 82.55,70.71 75.97,70.71 74.75,69.49 68.89,69.49 66.38,72.01 51.62,72.01 51.19,72.44 50.55,72.44 50.54,72.43 v3(50.35,72.43)
BIST_ENABLE_1: length 5.6
  TOP w0.102: R515.2 48.84,74.03 v3(48.67,73.86) 48.61,73.8 R514.2
  BOTTOM w0.102: v3(48.67,73.86) 48.67,74.77 v2(48.64,74.8) 48.67,74.83 48.67,75.96 48.62,76.01 R523.1 48.1,76.01 47.99,75.9 Q13.5
BIST_PIN25: length 204.2
  TOP w0.102: U109.24 159.79,55.58 v4(160.64,56.43) 160.85,56.64 R682.2 ; v4(86.39,56.64) 86.39,57.28 88.3,59.18 88.3,66.4 v1(89.16,67.26) 89.73,67.83 89.73,78 88.74,78.99 v4(88.04,78.99)
  L3 w0.127: v4(88.04,78.99) 87.87,79.17 87.87,79.98 86.73,81.12 80.47,81.12 79.59,82.01 72.77,82.01 72.26,81.5 57.32,81.5 54.45,78.63 50.79,78.63 50.58,78.83 49.99,79.42 47.79,81.62 45.37,81.62 44.48,80.73 43.44,80.73 42.78,81.38 42.78,111.2 v3(43.7,112.12) ; v4(86.39,56.64) 86.39,56.61 90.27,52.73 94.46,52.73 95.36,51.84 97.65,51.84 99.01,50.47 105.29,50.47 106.09,51.27 110.37,51.27 110.97,51.87 121.19,51.87 121.92,51.14 132.75,51.14 133.23,50.66 139.61,50.66 140.8,51.85 141.71,51.85 141.94,51.61 146.67,51.61 147.29,52.22 148.13,52.22 148.8,52.9 150.31,52.9 150.33,52.87 153.67,52.87 154.96,51.57 155.02,51.51 155.74,51.51 156.5,52.27 157.01,52.27 158.53,53.79 158.53,54.32 v4(160.64,56.43)
  BOTTOM w0.102: v3(43.7,112.12) 44.15,112.57 44.15,120.73 43.72,121.16 41.91,121.16 Q9650.G
BKLT_ADJ: length 4.7
  TOP w0.165: v1(43.72,36.58) 43.98,36.58 44.75,35.8 R79621.2 44.71,35.45 C33.1 ; R133.2 45.75,34.46 C33.1 ; C33.1 C87.1
BKLT_EN: length 7.5
  TOP w0.102: v1(41.56,31.37) 41.75,31.18 R79625.2 43.44,31.18 C88.1 44.04,30.58 Q22.C 43.47,28.13 R139.2 R138.2
BKLT_EN1: length 3.2
  TOP w0.102: R135.2 44.89,26.96 v3(44.89,27.1) 45.51,27.72 Q22.B
  BOTTOM w0.102: v2(44.89,27.91) v3(44.89,27.1)
BOARD1: length 8.2
  TOP w0.102: CPU1.BB9 76.6,148.53 76.9,148.23 76.9,146.32 75.57,144.98 v1(75.55,144.98) 75.22,144.65 R1661.2 R1663.1
BOARD2: length 14.8
  TOP w0.102: CPU1.AW15 82.17,151.3 82.56,150.9 v4(82.58,150.9) ; v3(81.55,140.59) 82.14,140.59 R152.1 R1662.2
  L3 w0.127: v3(81.55,140.59) 81.1,141.04 81.1,144.54 81.39,144.83 81.39,148.46 82.58,149.66 v4(82.58,150.9)
  BOTTOM w0.102: v2(82.6,151.68) 82.58,151.66 v4(82.58,150.9)
BOARD3: length 18.7
  TOP w0.102: CPU1.AU15 81.82,152.9 82.3,152.43 v4(82.51,152.43) ; R1659.2 R1660.1 85.19,139.76 v3(85,139.57)
  L3 w0.127: v4(82.51,152.43) 82.51,151.94 83.23,151.21 83.23,149.52 84.7,148.04 85.13,147.61 85.13,144.79 84.93,144.58 84.93,144.24 84.53,143.84 84.53,140.04 v3(85,139.57)
  BOTTOM w0.102: v2(84.69,140.46) 85,140.16 v3(85,139.57)
BOOT1_PHASE1: length 2.1
  TOP w0.254: PC19.2 121.19,82.55 v1(120.68,82.55)
BQ24737_CSON_1: length 34.8
  TOP w0.254: 63.56,57.78 63.56,58.91 59.52,62.95 59.52,64.09 58.66,64.96 54.2,64.96 v3(53.12,63.88) ; 63.56,57.78 v1(63.96,57.78) ; 63.56,57.78 63.56,52.1 61.5,50.04 61.5,48.84 v3(61.53,48.82)
  BOTTOM w0.254: PC5236.2 61.5,50.04 PR5277.2 ; PC5236.2 61.82,49.72 PC5238.1 ; PC5236.2 61.53,49.56 v3(61.53,48.82) ; v3(53.12,63.88) 53.37,64.14 53.37,65.09 52.17,66.29 49.39,66.29 PG4908.1
BQ24737_CSOP_1: length 34.9
  TOP w0.254: v3(53.98,63.88) 53.98,64.21 54.36,64.58 55.66,64.58 ; v3(60.66,48.79) 61.12,49.25 61.12,50.2 63.18,52.25 63.18,58.75 59.14,62.79 59.14,63.94 58.5,64.58 55.66,64.58 ; v1(55.66,64.19) 55.66,64.58
  BOTTOM w0.254: v3(60.66,48.79) 60.23,49.23 PC5236.1 60.49,50.04 PR5283.2 ; v3(53.98,63.88) 53.75,64.11 53.75,65.25 52.33,66.67 48.24,66.67 PG4906.1
BQ24737_REGN: length 34.8
  TOP w0.508: PR5297.1 71.53,58.95 70.24,57.66 70.24,54.08 71.09,53.23 v3(71.25,53.23)
  L3 w0.508: v3(71.25,53.23) 67.4,53.23 65.51,51.33 54.7,51.33 53.37,52.66 v3(53.37,52.76)
  BOTTOM w0.305: 58.12,54.48 58.5,54.48 58.94,54.92 U55.16
  BOTTOM w0.508: 58.12,54.48 57.94,54.48 57.08,53.62 v2(57,53.62) 56.98,53.64 55.77,53.64 PC5233.2 54.24,53.78 PD4401.A 53.37,52.93 v3(53.37,52.76)
BT+:
  vias: v2(34.5,68.45) v5(35.67,68.68) v5(36.38,69.34) v5(50.42,63.63) v5(50.42,62.61) v5(50.42,61.59) v5(51.43,63.63) v5(51.43,62.61) v5(51.43,61.59)
BUFFER1_M4: length 9.8
  TOP w0.102: R526.1 18.31,221.09 v3(18.35,221.13)
  BOTTOM w0.102: Q52.C 16.48,225.11 v2(16.82,225.45) 18.19,225.45 19.13,224.5 19.13,223.32 18.38,222.57 Q51.G 18.38,221.17 v3(18.35,221.13)
BUZZER_SPKR_R: length 66.5
  TOP w0.102: v3(162.24,33) 162.23,33 162.09,33.15 C203.1 ; R207.1 165.44,87.79 165.92,88.27 v3(168.69,88.27)
  L4 w0.102: v3(162.24,33) 162.24,33.05 161.75,33.53 161.75,36.05 162.01,36.3 162.01,39.98 161.48,40.51 161.48,41.05 161.89,41.47 161.89,45.01 162.54,45.66 162.54,47.76 162.7,47.92 162.7,54.53 162.16,55.07 162.16,58.31 161.42,59.05 161.42,73.12 161.93,73.63 161.93,74.05 161.22,74.76 161.22,79.17 165.49,83.44 165.49,85.06 v3(168.69,88.27)
  BOTTOM w0.102: v2(169.43,87.14) 169.43,87.53 v3(168.69,88.27)
C_GPP_TXN3: length 10.6
  TOP w0.102: CPU1.N3 71.7,172.32 71.54,172.48 71.05,172.48 71.03,172.5 70.77,172.5 70.75,172.48 70.25,172.48 70.2,172.53 69.41,172.53 67.7,174.25 67.7,177 66.99,177.71 66.66,177.71 66.53,177.58 66.53,176.99 66.4,176.86 66.01,176.86 65.88,176.99 C41.1
C_GPP_TXP3: length 10.6
  TOP w0.102: C42.1 67.08,177.93 67.91,177.09 67.91,174.34 69.5,172.75 70.29,172.75 70.34,172.7 70.66,172.7 70.69,172.72 71.11,172.72 71.14,172.7 71.63,172.7 72.13,172.2 CPU1.N4
CAGND: length 7.6
  BOTTOM w0.305: U120.15 37.13,37.58 v3(37.37,37.34)
  BOTTOM w0.508: v3(37.29,30.51) 37.11,30.32 v2(37.11,29.61) 37.06,29.61 36.99,29.54 34.88,29.54 C5.2 33.94,30.48 R82.2
  vias: v3(36.61,36.58) v3(37.37,36.58) v3(37.37,35.81) v3(38.13,36.58)
CASA0#: length 44.7
  TOP w0.127: v4(54.8,110.44) 54.8,110.62 54.68,110.74 54.68,110.74 54.48,110.93 53.78,110.93 53.65,110.8 53.65,110.61 53.78,110.48 MEM1.K3 ; v1(62.51,102.37) 63.14,102.37 v4(63.81,103.04) ; v4(75.78,102.59) 75.78,102.18 GPU1.G19
  L3 w0.102: 73.67,103.36 73.79,103.36 73.97,103.55 74.31,103.55 74.78,103.08 75.3,103.08 v4(75.78,102.59)
  L3 w0.165: v4(63.81,103.04) 63.89,102.96 64.91,102.96 65.03,103.09 65.03,103.29 65.16,103.41 66.4,103.41 66.53,103.29 66.53,103.08 66.65,102.95 67.17,102.95 67.3,103.08 67.3,103.24 67.42,103.36 71.62,103.36 71.76,103.23 71.76,102.89 71.9,102.75 73,102.75 73.13,102.87 73.13,103.24 73.26,103.36 73.67,103.36
  L4 w0.165: v4(54.8,110.44) 54.95,110.59 55.67,110.59 55.74,110.52 56.65,110.52 57.53,109.64 58.65,109.64 58.89,109.89 60.84,109.89 62.62,108.11 62.62,105.8 62.74,105.67 63.94,105.67 64.06,105.54 64.06,105.14 63.94,105.01 62.74,105.01 62.62,104.88 62.62,104.48 62.74,104.35 63.96,104.35 64.09,104.22 64.09,103.82 63.96,103.69 62.74,103.69 62.62,103.56 62.62,101.76 62.74,101.63 63.68,101.63 63.81,101.76 v4(63.81,103.04)
  BOTTOM w0.127: MEM3.K3 55.79,110.48 55.69,110.58 54.94,110.58 v4(54.8,110.44)
CASA1#: length 43.4
  TOP w0.127: v4(77.37,95.25) 77.37,96.04 77.5,96.17 77.73,96.17 77.83,96.27 77.83,96.52 77.71,96.65 77.5,96.65 77.37,96.78 77.37,97.13 76.99,97.52 76.99,97.65 76.54,98.09 76.54,98.34 76.29,98.59 76.29,98.78 75.68,99.4 GPU1.G16 ; v4(54.95,92.24) 55.41,92.7 57.1,92.7 MEM2.K3
  L3 w0.165: v4(77.37,95.25) 77.37,95.5 76.88,95.99 76.22,95.99 76.1,95.86 76.1,95.12 75.84,94.87 75.04,94.87 74.48,95.43 72.85,95.43 72.55,95.73 68.85,95.73 68.66,95.54 67.54,95.54 67.19,95.88 62.17,95.88 61.91,96.14 61.91,96.53 61.39,97.05 61,97.05 60.67,97.38 v3(60.67,97.84)
  L4 w0.102: 55.9,93.49 55.9,93.75 56.06,93.91 59.76,93.91
  L4 w0.165: 59.76,93.91 60.9,93.91 61.25,94.25 61.25,95.66 60.62,96.29 60.62,96.91 60.75,97.04 61.09,97.04 61.22,97.16 61.22,97.71 61.09,97.84 v3(60.67,97.84) ; v4(54.95,92.24) 55.3,92.59 55.3,92.89 55.9,93.49
  BOTTOM w0.127: v3(60.67,97.84) 60.67,97.84 61.08,98.24 v2(61.38,98.24) ; MEM4.K3 54.06,92.87 54.23,92.87 54.33,92.77 54.33,92.62 54.48,92.48 54.48,92 54.63,91.84 54.84,91.84 54.95,91.95 v4(54.95,92.24)
CBN: length 4.1
  TOP w0.203: U6.21 158.9,77.23 158.38,76.71 157.68,76.71 157.24,76.26 C150.2
  TOP w0.305: v1(156.39,77.15) 156.4,77.15 156.4,76.81 156.94,76.26 C150.2
CBP: length 4.1
  TOP w0.203: U6.24 159.57,75.84 158.12,74.4 v1(157.64,74.4) 157.39,74.4 157.01,74.78 C150.1
CFG: length 7.7
  TOP w0.102: R1594.2 126.91,40.87 126.96,40.82 126.96,40.59 v3(127.29,40.26) ; U118.23 v3(129.2,36.57)
  BOTTOM w0.102: v3(129.2,36.57) 128.48,37.29 v2(128.48,39.47) 128.07,39.47 v3(127.29,40.26)
CHG_AGND: length 47.2
  TOP w0.508: v3(64.78,64.39) 64.78,63.75 64.4,63.37 64.4,61.34 65.97,59.77 65.97,58.06 v3(66.91,57.12)
  L3 w0.508: v3(64.78,64.39) 63.05,64.39 62.42,65.02 v3(60.49,65.02)
  L4 w0.508: v3(66.68,50.9) 66.63,50.9 66.38,51.16 66.38,52.03 66.94,52.59 66.94,57.1 v3(66.91,57.12)
  BOTTOM w0.406: PQ5006.1 61.17,66.22 60.49,65.53 v3(60.49,65.02) ; PQ5006.4 64.73,64.34 v3(64.78,64.39)
  BOTTOM w0.508: 59.01,64.57 59.19,64.39 59.19,63.27 PC4403.2 ; 59.01,64.57 v2(57.49,64.57) 56.45,64.57 55.53,63.65 PC4404.2 54.57,61.65 PC4408.2 ; 59.01,64.57 60.12,64.57 60.49,64.93 v3(60.49,65.02) ; PC5239.2 PC5232.2 ; PC5232.2 66.5,57.53 v3(66.91,57.12) ; PC5232.2 PR4412.2 ; PR5468.2 64.49,62.93 64.78,63.22 v3(64.78,64.39) ; PC5238.2 63.8,48.83 64.8,49.83 PR5268.2 PR5274.2 65.86,50.9 v3(66.68,50.9)
CHG_ON#: length 115
  TOP w0.102: v3(149.26,40.64) 150.21,40.64 R80207.1 ; v3(71.28,54.48) 72.25,55.45 v1(72.25,57.53) 72.25,61.69 71.26,62.68 71.26,63.68 70.7,64.23 PQ5003.G 70.5,67.04 PR5273.2
  L3 w0.127: v3(149.26,40.64) 149.09,40.47 148.67,40.47 146.66,38.47 146.16,38.47 146.03,38.61 144.69,38.61 142.2,41.1 138.68,41.1 137.24,39.66 127.22,39.66 126.82,40.06 126.82,40.07 124.61,42.28 108.14,42.28 107.3,43.12 102.26,43.12 99.94,45.44 96.6,45.44 95.58,46.46 90.03,46.46 87.19,49.31 86.62,49.31 v3(86.39,49.53) 85.85,50.07 80.33,50.07 75.92,54.48 v3(71.28,54.48)
  BOTTOM w0.102: v3(86.39,49.53) 89.56,49.53 90.57,50.55 96.17,50.55 97.11,51.48 U4101.17
CHG_ON#_ECIO: length 6.1
  TOP w0.102: U109.101 146.06,43.97 146.46,43.56 147.67,43.56 v1(149.32,41.91) 149.64,41.59 R80207.2
CHG_SMB2_CLK: length 148
  TOP w0.254: R715.1 140.04,65.14 140.04,65.43 139.55,65.91 138.84,65.91 v3(138.34,65.41)
  L3 w0.254: v3(64.91,68.35) 64.82,68.26 64.26,68.26 64.07,68.46 64.07,69.47 64.45,69.85 77.21,69.85 77.85,70.48 85.85,70.48 90.9,65.43 95.92,65.43 96.43,64.92 96.43,63.12 97.06,62.48 v3(97.7,62.48) 97.95,62.23 105.85,62.23 107.83,62.23 108.73,63.13 128.06,63.13 129.14,64.21 130.66,64.21 134.18,64.21 135.69,65.72 138.02,65.72 v3(138.34,65.41)
  BOTTOM w0.203: v3(97.7,62.48) 97.7,60.83 98.33,60.2 99.73,60.2 100.07,59.86 U4101.35
  BOTTOM w0.254: 52.74,68.22 48.9,68.22 48.77,68.1 38.92,68.1 37.63,66.8 37.63,65.68 37.28,65.34 36.46,65.34 36.4,65.4 RN4301.2 ; 52.74,68.22 v2(52.74,68.58) ; 52.74,68.22 64.78,68.22 v3(64.91,68.35) 65.19,68.07 65.57,68.07 70.19,63.46 70.19,55.39 68.57,53.77 67.22,53.77 66.9,53.45 PR4425.2 66.57,53.75 64.17,53.75 63.43,54.48 63.43,55.47 63.13,55.78 62.62,55.78 62.6,55.76 U55.9
CHG_SMB2_DATA: length 149.4
  TOP w0.254: v3(138.34,66.29) 138.34,66.29 139.71,66.29 140.42,65.59 140.42,65.17 R716.1
  L3 w0.254: v3(64.92,67.48) 64.52,67.88 64.1,67.88 63.69,68.3 63.69,69.63 64.29,70.23 77.05,70.23 77.69,70.87 86.01,70.87 87.66,69.21 91.06,65.81 96.08,65.81 96.81,65.08 96.81,63.63 97.19,63.25 v3(97.32,63.25) 97.82,63.25 98.46,62.61 105.69,62.61 107.67,62.61 108.57,63.51 127.9,63.51 128.98,64.59 130.82,64.59 134.02,64.59 135.54,66.1 138.15,66.1 v3(138.34,66.29)
  BOTTOM w0.203: v3(97.32,63.25) 97.19,63.12 97.19,60.33 97.8,59.72 99.52,59.72 99.67,59.56 U4101.34
  BOTTOM w0.254: v2(55.91,67.56) 55.91,67.84 ; 55.91,67.84 49.06,67.84 48.93,67.72 39.08,67.72 38.01,66.64 38.01,65.53 37.44,64.96 36.46,64.96 36.4,64.9 RN4301.3 ; 55.91,67.84 64.56,67.84 v3(64.92,67.48) 65.13,67.69 65.41,67.69 69.81,63.3 69.81,55.55 68.41,54.15 67.18,54.15 PR4426.2 66.52,54.13 64.33,54.13 63.81,54.64 63.81,55.63 63.18,56.26 U55.8
CK_48M_SIO: length 188
  TOP w0.102: R310.2 158.12,65.44 158.12,65.9 157.66,66.35 156.35,66.35 156.13,66.58 156.13,68.47 156.72,69.06 157,69.06 157.55,69.61 157.55,72.98 155.63,74.9 155.63,79.48 154.59,80.52 154.59,84.18 155.63,85.22 155.63,89.7 155.29,90.05 155.29,91.49 155.94,92.13 155.94,93 156.47,93.53 156.47,96.69 156.62,96.84 156.62,97.38 155.96,98.04 155.48,98.04 154.34,96.9 v1(152.94,96.9) 151.29,96.9 150.61,97.58 v3(150.61,98.04)
  L4 w0.127: v3(156.04,127.09) 156.04,125.93 154.87,124.76 154.87,120.68 151.52,117.34 151.52,107.64 150.28,106.4 150.28,102.24 149.74,101.7 149.74,98.92 v3(150.61,98.04)
  BOTTOM w0.102: 76.82,148.73 R1645.1 76.91,147.64 77.38,148.11 79.07,148.11 80.16,147.01 80.49,147.01 81.77,145.73 81.77,145.26 82.19,144.83 83.17,144.83 83.55,144.45 83.63,144.45 84.68,143.4 84.68,142.89 87.65,139.93 87.65,136.64 91.62,132.67 114.59,132.67 117.64,129.62 124.02,129.62 130.61,123.03 151.99,123.03 v3(156.04,127.09) ; 76.82,148.73 76.8,148.72 75.66,148.72 75.53,148.59 70.42,148.59 69.76,149.25 67.27,149.25 66.58,149.94 66.58,151.53 66.59,151.54 66.77,151.72 66.78,151.73 67.13,152.08 69.33,152.08 R2067.2 ; 76.82,148.73 C1733.2
CK_GLAN_DN: length 246.4
  TOP w0.102: CPU1.U2 70.51,168.61 69.77,168.61 v4(69.36,168.2) ; v3(37.75,25.68) 37.75,24.8 38.06,24.5 38.06,23.87 36.16,21.98 36.16,18.14 36.57,17.73 36.57,17.63 36.48,17.53 U16.16
  L3 w0.127: v4(69.36,168.2) 69.36,169 65.26,173.1 65.26,177.73 64.28,178.7 62.18,178.7 53.59,170.11 48.59,170.11 46.89,168.41 42.41,168.41 41.95,168.88 38.79,168.88 38.44,168.52 28.51,168.52 26.85,170.18 26.85,171.87 25.7,173.03 23.46,173.03 22.83,172.4 22.83,171.82 v3(22.59,171.58)
  L4 w0.127: v3(37.75,25.68) 37.87,25.8 37.87,27.75 33.32,32.3 33.32,38.32 34.77,39.76 34.77,43.82 35.4,44.46 35.4,50.3 35.1,50.6 35.1,53.1 31.18,57.02 31.18,65.54 39.71,74.07 39.71,76.09 41.89,78.28 41.89,120.8 44.96,123.86 44.96,154.92 40.59,159.29 40.59,160.67 34.92,166.34 26.41,166.34 22.59,170.16 v3(22.59,171.58)
  BOTTOM w0.102: v4(69.36,168.2) 69.36,168.11 69.71,167.77 70.54,167.77 v2(70.68,167.91)
CK_GLAN_DP: length 245.8
  TOP w0.102: v4(68.72,168.2) 68.72,168.51 68.82,168.61 69.46,168.61 69.68,168.82 69.92,168.82 CPU1.U1 ; v3(38.56,25.68) 38.56,25.48 38.39,25.3 38.09,25.3 37.97,25.17 37.97,24.89 38.27,24.59 38.27,23.78 36.38,21.89 36.38,18.23 36.79,17.82 36.79,17.63 36.88,17.53 U16.15
  L3 w0.127: v3(23.35,171.58) 23.1,171.83 23.1,172.29 23.57,172.76 25.59,172.76 26.58,171.76 26.58,170.07 28.4,168.25 38.55,168.25 38.9,168.61 41.84,168.61 42.3,168.15 47,168.15 48.7,169.85 53.7,169.85 62.29,178.44 64.17,178.44 64.99,177.61 64.99,172.99 69.09,168.89 69.09,168.57 v4(68.72,168.2)
  L4 w0.127: v3(38.56,25.68) 38.14,26.11 38.14,27.86 33.59,32.41 33.59,38.21 35.03,39.65 35.03,43.71 35.67,44.35 35.67,50.41 35.37,50.71 35.37,53.21 31.45,57.13 31.45,65.43 39.97,73.96 39.97,75.98 42.16,78.17 42.16,120.69 45.22,123.75 45.22,155.03 40.86,159.4 40.86,160.78 35.03,166.6 26.53,166.6 26.24,166.88 22.85,170.27 22.85,171.08 v3(23.35,171.58)
  BOTTOM w0.102: v4(68.72,168.2) 68.72,168.77 v2(68.49,169.01)
CK_M_DDR0_A_DN: length 65.9
  TOP w0.102: CPU1.AE32 95.68,162.3 95.91,162.3 95.93,162.28 99.24,162.28 99.37,162.42 100.6,162.42 100.84,162.18 101.13,162.18
  TOP w0.178: 101.13,162.18 102.39,162.18 102.9,161.67 104.35,161.67 104.81,162.13 v4(104.81,163.07) ; DIMM1.103 130.01,157.55 v3(129.7,157.86)
  L3 w0.178: v4(104.81,163.07) 104.81,162.69 105.58,161.91 105.83,161.91 106.69,162.77 107.19,162.77 107.58,162.38 107.58,161.87 106.73,161.02 106.73,160.77 106.94,160.55 107.19,160.55 107.92,161.28 108.43,161.28 108.82,160.89 108.82,160.38 108.09,159.65 108.09,159.4 108.69,158.8 109.54,158.8 109.72,158.98 109.72,160.98 110.08,161.34 110.69,161.34 111.04,160.98 111.04,158.98 111.22,158.8 111.58,158.8 111.75,158.98 111.75,160.98 112.11,161.34 112.72,161.34 113.07,160.98 113.07,158.98 113.25,158.8 113.95,158.8 114.16,159 114.16,161.87 114.51,162.23 115.12,162.23 115.48,161.87 115.48,158.98 115.65,158.8 116.14,158.8 116.31,158.98 116.31,160.04 116.67,160.4 117.21,160.4 117.64,159.97 117.64,158.98 117.81,158.8 120.34,158.8 120.79,159.25 121.49,159.25 121.94,158.8 122.37,158.8 122.82,159.25 123.52,159.25 123.97,158.8 124.41,158.8 124.86,159.25 125.59,159.25 126.22,158.62 126.63,158.62 127.25,159.25 128.01,159.25 128.9,158.36 129.2,158.36 v3(129.7,157.86)
  BOTTOM w0.178: v3(129.7,157.86) 129.7,157.24 129.39,156.93 v2(129.38,156.93)
CK_M_DDR0_A_DP: length 65.9
  TOP w0.102: CPU1.AE33 96.02,162.48 99.15,162.48 99.29,162.62 100.69,162.62 100.75,162.56 101.13,162.56
  TOP w0.178: v3(128.94,157.86) 129.43,158.36 129.91,158.36 130.11,158.15 DIMM1.101 ; v4(103.67,163.04) 103.74,162.97 104.2,162.97 104.43,162.74 104.43,162.29 104.19,162.05 103.06,162.05 102.55,162.56 101.13,162.56
  L3 w0.178: v3(128.94,157.86) 128.94,157.89 127.88,158.95 127.38,158.95 126.75,158.32 126.09,158.32 125.47,158.95 124.98,158.95 124.53,158.5 123.84,158.5 123.39,158.95 122.95,158.95 122.5,158.5 121.81,158.5 121.36,158.95 120.92,158.95 120.47,158.5 117.69,158.5 117.33,158.85 117.33,159.85 117.08,160.1 116.8,160.1 116.62,159.92 116.62,158.85 116.26,158.5 115.53,158.5 115.17,158.85 115.17,161.75 114.99,161.93 114.64,161.93 114.46,161.75 114.46,158.88 114.08,158.5 113.13,158.5 112.77,158.85 112.77,160.86 112.59,161.04 112.24,161.04 112.06,160.86 112.06,158.85 111.7,158.5 111.09,158.5 110.74,158.85 110.74,160.86 110.56,161.04 110.2,161.04 110.03,160.86 110.03,158.85 109.67,158.5 108.57,158.5 107.79,159.28 107.79,159.78 108.51,160.51 108.51,160.76 108.3,160.97 108.05,160.97 107.32,160.25 106.82,160.25 106.42,160.64 106.42,161.14 107.28,162 107.28,162.25 107.06,162.46 106.81,162.46 105.96,161.61 105.45,161.61 104.02,163.04 v4(103.67,163.04)
  BOTTOM w0.178: v2(128.54,158.65) 128.94,158.25 v3(128.94,157.86)
CK_M_DDR0_B_DN: length 65.4
  TOP w0.102: v4(98.59,163.7) 98.18,163.3 97.83,163.3 97.65,163.12 96.78,163.12 96.53,163.37 95.69,163.37 95.66,163.4 CPU1.AD33
  TOP w0.178: DIMM2.103 147.19,157.55 147.62,157.11 148.41,157.11 148.79,157.49 149.02,157.49 v3(149.51,157.99)
  L3 w0.178: v4(98.59,163.7) 99.45,164.57 102.9,164.57 103.36,165.02 115.02,165.02 115.53,164.52 116.2,164.52 116.7,165.02 117.36,165.02 117.89,164.49 117.89,164.24 117.71,164.06 117.71,163.56 118.14,163.12 118.64,163.12 118.82,163.31 119.07,163.31 119.33,163.05 119.33,162.8 119.14,162.62 119.14,162.12 119.58,161.69 120.08,161.69 120.26,161.87 120.51,161.87 121.51,160.87 129.9,160.87 131.13,159.64 136.44,159.64 137.72,158.36 138.74,158.36 139.53,157.57 147.28,157.57 147.66,157.19 148.71,157.19 v3(149.51,157.99)
  BOTTOM w0.178: v2(150.22,157.56) 150.15,157.56 149.72,157.99 v3(149.51,157.99)
CK_M_DDR0_B_DP: length 65
  TOP w0.102: v4(97.95,163.7) 97.57,163.32 96.86,163.32 96.61,163.57 95.77,163.57 95.64,163.7 95.36,163.7 95.05,163.4 CPU1.AD32
  TOP w0.178: DIMM2.101 147.13,158.15 147.78,157.49 148.25,157.49 v3(148.75,157.99)
  L3 w0.178: v3(148.75,157.99) 148.75,157.66 148.59,157.49 147.78,157.49 147.4,157.87 139.65,157.87 138.87,158.66 137.85,158.66 136.57,159.94 131.25,159.94 130.02,161.18 121.64,161.18 120.64,162.17 120.13,162.17 119.95,161.99 119.7,161.99 119.45,162.24 119.45,162.49 119.63,162.68 119.63,163.18 119.2,163.61 118.7,163.61 118.51,163.43 118.26,163.43 118.01,163.68 118.01,163.93 118.19,164.11 118.19,164.62 117.49,165.33 116.57,165.33 116.07,164.82 115.66,164.82 115.15,165.33 103.23,165.33 102.78,164.87 99.32,164.87 98.73,164.27 98.14,164.27 97.95,164.08 v4(97.95,163.7)
  BOTTOM w0.178: v3(148.75,157.99) 148.75,158.75 v2(148.8,158.8)
CK_M_DDR1_A_DN: length 65.5
  TOP w0.102: v4(99.98,163.25) 99.63,163.25 99.07,162.69 96.58,162.69 96.32,162.94 95.77,162.94 95.7,162.86 95.3,162.86 95.24,162.92 94.94,162.92 94.76,162.74 94.76,162.42 94.65,162.31 94.5,162.31 94.39,162.41 94.39,162.51 CPU1.AE31
  TOP w0.178: v3(136.3,157.73) 136.3,157 136.44,156.86 138.19,156.86 138.58,157.25 DIMM1.104
  L3 w0.178: v3(136.3,157.73) 136.3,158.06 136.04,158.33 131.07,158.33 129.5,159.91 118.63,159.91 117.97,160.57 117.97,161.08 118.29,161.4 118.29,161.58 117.97,161.9 117.79,161.9 117.13,161.24 116.69,161.24 116.19,161.74 116.19,162.18 116.86,162.85 116.86,163.03 116.54,163.35 116.36,163.35 116.03,163.02 115.52,163.02 114.48,164.06 113.82,164.06 113.65,163.88 113.65,162.36 113.29,162 112.68,162 112.32,162.36 112.32,163.88 112.15,164.06 111.79,164.06 111.61,163.88 111.61,162.36 111.26,162 110.65,162 110.29,162.36 110.29,163.88 110.11,164.06 109.76,164.06 109.58,163.88 109.58,162.36 109.23,162 108.62,162 108.26,162.36 108.26,163.88 108.08,164.06 107.35,164.06 106.82,163.53 106.21,163.53 105.68,164.06 103.75,164.06 103.3,163.6 100.34,163.6 v4(99.98,163.25)
  BOTTOM w0.178: v3(136.3,157.73) v2(136.3,158.57)
CK_M_DDR1_A_DP: length 65.8
  TOP w0.102: v4(99.98,163.96) 99.98,163.89 98.98,162.89 96.66,162.89 96.41,163.14 95.69,163.14 95.61,163.07 95.39,163.07 95.33,163.13 94.86,163.13 94.67,162.94 94.19,162.94 93.85,162.6 CPU1.AE30
  TOP w0.178: v3(137.07,157.73) 137.07,157.51 137.34,157.24 138.03,157.24 138.32,157.53 138.32,157.66 138.52,157.85 DIMM1.102 ; v1(100.92,163.98) 100.9,163.96 v4(99.98,163.96)
  L3 w0.178: v4(99.98,163.96) 100.03,163.91 103.17,163.91 103.63,164.36 105.81,164.36 106.34,163.83 106.69,163.83 107.23,164.36 108.21,164.36 108.57,164.01 108.57,162.48 108.74,162.31 109.1,162.31 109.28,162.48 109.28,164.01 109.63,164.36 110.24,164.36 110.6,164.01 110.6,162.48 110.77,162.31 111.13,162.31 111.31,162.48 111.31,164.01 111.66,164.36 112.27,164.36 112.63,164.01 112.63,162.48 112.81,162.31 113.16,162.31 113.34,162.48 113.34,164.01 113.7,164.36 114.61,164.36 115.65,163.32 115.9,163.32 116.23,163.65 116.67,163.65 117.17,163.15 117.17,162.72 116.5,162.05 116.5,161.87 116.82,161.55 117,161.55 117.66,162.2 118.09,162.2 118.59,161.7 118.59,161.27 118.27,160.95 118.27,160.7 118.76,160.21 129.62,160.21 131.2,158.64 136.16,158.64 v3(137.07,157.73)
CK_M_DDR1_B_DN: length 66.4
  TOP w0.102: 97.52,164.2 97.48,164.16 97.11,164.16 96.88,163.93 96.07,163.93 96.04,163.9 95.76,163.9 95.45,164.2 CPU1.AC32
  TOP w0.178: v1(101.89,165.76) 101.8,165.85 100.67,165.85 100.43,165.61 v4(100.43,165.61) 100.08,165.27 99.8,165.27 98.73,164.2 97.52,164.2 ; DIMM2.104 153.06,157.25 152.92,157.11 151.91,157.11 v3(151.04,157.99)
  L3 w0.178: v4(100.43,165.61) 100.63,165.81 102.78,165.81 102.96,165.98 117.84,165.98 121.65,162.18 122.65,162.18 123,161.83 123.75,161.83 124.1,162.18 124.58,162.18 124.92,161.83 125.68,161.83 126.02,162.18 129.95,162.18 131.53,160.6 136.84,160.6 137.32,160.12 137.47,159.97 137.56,159.88 138.58,159.88 139.93,158.53 150.49,158.53 v3(151.04,157.99)
CK_M_DDR1_B_DP: length 65.2
  TOP w0.102: 97.33,164.58 97.11,164.36 97.03,164.36 96.8,164.13 96.07,164.13 96,164.2 CPU1.AC33
  TOP w0.178: 97.33,164.58 98.57,164.58 v4(99.73,165.74) ; DIMM2.102 153.12,157.85 152.77,157.49 152.07,157.49 151.8,157.76 v3(151.8,157.99)
  L3 w0.178: v3(151.8,157.99) 151.8,158.42 151.63,158.58 150.87,158.58 150.62,158.84 140.05,158.84 138.7,160.19 137.75,160.19 137.69,160.19 137.54,160.34 136.97,160.91 131.65,160.91 130.08,162.48 125.89,162.48 125.55,162.14 125.05,162.14 124.7,162.48 123.97,162.48 123.62,162.14 123.12,162.14 122.78,162.48 121.78,162.48 117.97,166.29 102.83,166.29 102.66,166.12 100.11,166.12 v4(99.73,165.74)
  BOTTOM w0.178: v3(151.8,157.99) 151.8,157.2 v2(151.82,157.18)
CK_P_33M_EC: length 15.5
  TOP w0.102: v3(106.33,49.53) 107.04,48.82 110.43,48.82 111.49,49.89 113.15,49.89 113.95,49.09 115.38,49.09 116.27,49.97 R79699.1
  BOTTOM w0.102: U4101.2 104.87,48.84 v2(105.19,48.51) 105.23,48.48 106.04,48.48 106.33,48.77 v3(106.33,49.53)
CK_P_33M_SIO: length 185.2
  TOP w0.102: R1646.1 R1867.1 C1734.1 82.01,135.13 R1868.2 R1877.2 82.27,134.37 v3(81.97,134.37) ; v3(151.82,58.04) 152.13,58.04 152.33,58.24 152.33,59.51 152.45,59.63 U109.44 152.45,61.49 153.65,62.69 153.65,62.72 153.98,63.04 154.07,63.04 154.41,63.39 154.41,63.45 154.72,63.75 154.72,70.68 154.22,71.17 154.22,78.89 153.18,79.93 153.18,84.76 154.22,85.8 154.22,89.12 153.88,89.46 153.88,92.07 154.53,92.72 154.53,94.64 v3(155.9,96.01) ; v3(127.29,55.23) 127.41,55.11 127.41,53.47 125.69,51.74 118.88,51.74 118.01,50.86 R79699.2
  L3 w0.127: v3(127.29,55.23) 127.38,55.33 129.25,55.33 129.37,55.21 133.15,55.21 133.41,54.95 136.62,54.95 137.28,55.6 139.51,55.6 139.73,55.82 140.79,55.82 141.63,56.66 145.35,56.66 145.8,57.11 150.51,57.11 150.97,57.56 151.34,57.56 v3(151.82,58.04) ; v3(81.97,134.37) 81.97,134.2 83.17,133 85.3,133 86.72,131.57 88.28,131.57 91.51,128.34 118.1,128.34 120.15,126.29 121.12,126.29 133.16,114.24 148.05,114.24 151.08,111.22 151.08,108.63 156.71,103 156.71,96.82 v3(155.9,96.01)
  BOTTOM w0.102: v2(155.09,96.01) v3(155.9,96.01)
CK_PCIEX1_WLAN_DN: length 141.5
  TOP w0.102: v3(102.93,216.15) R23.2 ; CPU1.W3 v4(72.1,167)
  L3 w0.127: v4(72.1,167) 72.37,167.27 72.37,167.39 67.19,172.57 67.19,175.54 65.78,176.95 65.78,178.32 64.36,179.74 62.65,179.74 53.42,170.52 48.43,170.52 47.33,169.42 43.49,169.42 43.37,169.3 43.37,168.91 v3(43.39,168.88)
  BOTTOM w0.102: 86.52,203.39 82.44,203.39 80.98,201.93 69.4,201.93 67.29,199.82 55.13,199.82 53.21,197.9 53.21,188.15 49.12,184.06 49.12,181.74 43.44,176.07 43.44,170.61 42.96,170.13 42.96,169.6 43.39,169.16 v3(43.39,168.88) ; 86.52,203.39 87.59,203.39 89.58,205.38 100.48,205.38 105.11,210.02 105.11,214.76 104.12,215.75 103.33,215.75 v3(102.93,216.15) ; 86.52,203.39 v2(86.52,203.02)
CK_PCIEX1_WLAN_DP: length 141.5
  TOP w0.102: CPU1.W4 v4(72.9,167) ; v3(102.93,215.14) R22.2
  L3 w0.127: v4(72.9,167) 72.63,167.27 72.63,167.5 67.46,172.68 67.46,175.65 66.05,177.06 66.05,178.43 64.47,180.01 62.54,180.01 60.15,177.62 53.31,170.78 48.32,170.78 47.22,169.69 43.38,169.69 42.94,169.25 v3(42.66,169.25)
  BOTTOM w0.102: v3(42.66,169.25) 42.74,169.33 42.74,170.22 43.22,170.7 43.22,176.16 48.9,181.83 48.9,184.15 52.99,188.24 52.99,197.99 55.04,200.04 67.21,200.04 69.31,202.15 80.89,202.15 82.35,203.61 84.09,203.61 ; v2(84.09,203.96) 84.09,203.61 ; 84.09,203.61 87.5,203.61 89.49,205.6 100.39,205.6 104.9,210.11 104.9,214.67 104.03,215.54 103.33,215.54 v3(102.93,215.14)
CK_PE_100M_16PORT_DN: length 111.1
  TOP w0.102: v4(93.8,112.02) 93.64,112.18 93.34,112.18 92.86,111.7 92.86,110.94 GPU1.AK32 ; v4(72.1,169.4) 72.1,168.99 71.97,168.86 71.83,168.86 71.7,168.99 CPU1.U3
  BOTTOM w0.102: v4(93.8,112.02) 93.5,112.02 93.39,112.13 93.39,112.76 93,113.15 93,115.49 92.24,116.24 ; v2(91.99,115.99) 92.24,116.24 ; 92.24,116.24 88.9,119.59 86.54,119.59 85.55,120.58 80.63,120.58 70.98,130.23 61.69,130.23 55.9,136.02 55.9,137.56 51.98,141.48 51.98,143.46 50.49,144.94 50.49,149.04 51.02,149.57 51.02,155.95 51.74,156.66 51.74,168.73 52.7,169.68 53.44,170.43 69.02,170.43 70.68,168.78 72.16,168.78 72.39,169.01 72.39,169.11 v4(72.1,169.4)
CK_PE_100M_16PORT_DP: length 111.1
  TOP w0.102: v4(93.8,112.65) 93.54,112.39 93.25,112.39 92.64,111.79 92.64,110.36 GPU1.AK30 ; CPU1.U4 v4(72.9,169.4)
  BOTTOM w0.102: v2(91.34,117.91) 91.11,117.68 ; 91.11,117.68 88.99,119.8 86.63,119.8 85.64,120.79 80.72,120.79 71.07,130.44 61.78,130.44 56.11,136.11 56.11,137.65 52.19,141.57 52.19,143.54 50.71,145.03 50.71,148.95 51.24,149.48 51.24,155.86 51.96,156.57 51.96,168.64 52.79,169.47 53.53,170.21 68.93,170.21 70.59,168.56 72.25,168.56 72.61,168.92 72.61,169.11 v4(72.9,169.4) ; 91.11,117.68 93.21,115.58 93.21,113.24 v4(93.8,112.65)
CKEA0: length 54.9
  TOP w0.127: v4(51.83,110.87) 51.56,110.87 51.16,110.47 48.66,110.47 v1(48.11,109.93) ; v4(77.48,103.53) 77.48,103.32 GPU1.K20 ; MEM1.K9 58.81,110.68 59.22,111.09 59.63,111.09 59.77,110.94 60.95,110.94 v4(60.97,110.96)
  L3 w0.165: v4(51.83,110.87) 51.13,110.87 51.01,111 51.01,111.71 51.13,111.84 52.22,111.84 52.33,111.73 52.33,111.35 52.54,111.14 53.78,111.14 54.18,111.55 54.18,111.63 54.64,112.09 54.7,112.09 54.95,112.34 v4(55.07,112.34) 55.18,112.45 55.81,112.45 56.06,112.2 56.06,112.01 56.89,111.18 56.89,110.6 57.32,110.17 57.91,110.17 58.25,110.52 58.67,110.52 59.22,109.96 61.72,109.96 62.39,109.3 68.92,109.3 69.36,108.86 73.5,108.86 73.76,108.59 73.76,108.59 74.02,108.33 74.03,108.33 74.8,107.55 75.98,107.55 76.78,108.35 76.78,108.35 77.15,108.72 77.65,108.72 78.01,108.36 78.45,108.36 78.75,108.06 78.75,104.81 77.93,103.98 77.9,103.98 77.65,103.73 77.65,103.71 v4(77.48,103.53)
  L4 w0.165: v4(55.07,112.34) 55.18,112.45 55.81,112.45 55.81,112.45 56.07,112.45 56.92,111.59 57.88,111.59 58.25,111.23 59.72,111.23 60,110.94 60.71,110.94 60.73,110.96 v4(60.97,110.96)
  BOTTOM w0.127: MEM3.K9 52.77,110.48 52.87,110.57 52.87,110.8 52.74,110.93 51.89,110.93 v4(51.83,110.87)
CKEA1: length 47.5
  TOP w0.127: GPU1.J17 77,100.26 v4(77.26,100) ; v1(49.88,93.22) 49.98,93.32 51.18,93.32 v3(51.66,92.84) 51.67,92.82 MEM2.K9
  L3 w0.165: v4(77.26,100) 77.4,100 77.81,99.59 78.14,99.59 79.03,98.7 79.03,97.56 77.81,96.34 77.81,95.98 78.21,95.59 78.45,95.59 78.71,95.33 78.71,94.93 78.07,94.29 78.07,94.13 77.65,93.71 77.34,93.71 76.77,93.14 74.59,93.14 74.38,93.35 72.76,93.35 72.22,93.89 69.84,93.89 69.7,94.04 66.56,94.04 66.39,94.21 61.6,94.21 61.52,94.29 60.43,94.29 59.88,93.74 59.88,93.31 59.62,93.05 59.26,93.05 58.65,93.66 56.98,93.66 56.78,93.46 v4(56.78,93.18) 56.78,93.14 56.33,92.68 56.19,92.68 56,92.49 55.88,92.49 55.46,92.07 55.41,92.07 55.13,91.79 54.67,91.79 54.05,92.41 54.05,92.6 53.79,92.86 51.68,92.86 v3(51.66,92.84)
  L4 w0.165: v4(58.42,93.22) 58.59,93.39 58.92,93.39 59.08,93.23 59.08,92.94 58.77,92.63 56.96,92.63 56.86,92.53 56.86,92.37 56.73,92.24 56.55,92.24 56.29,92.5 56.29,92.65 56.59,92.94 56.59,92.99 v4(56.78,93.18)
  BOTTOM w0.127: v4(58.42,93.22) 58.71,93.22 58.81,93.12 MEM4.K9
CLINK_CLK_LAN: length 3.3
  TOP w0.102: TP67.1 121.07,214 120.06,215 NGFF1.42
CLINK_DATA_LAN: length 4.9
  TOP w0.102: TP66.1 121.85,213.46 121.1,213.46 120.06,214.5 NGFF1.40
CLINK_RST_LAN_N: length 3.4
  TOP w0.102: TP65.1 120.04,214 NGFF1.38
CLK_48M_SIO_C: length 3.8
  TOP w0.102: U109.34 156.46,61.15 157.36,62.05 v1(157.36,62.48) 157.36,63.59 R310.1
CLKA0: length 48.9
  TOP w0.127: v4(76.6,107.2) 76.6,107.2 GPU1.H26 ; MEM1.J7 56.66,111.52 56.4,111.63 55.88,111.63 55.68,111.6 55.58,111.59 v4(54.95,111.39) ; R1907.1 49.75,111.76 50.3,111.76 v4(50.57,112.03)
  L4 w0.152: v4(76.6,107.2) 76.42,107.2 76.24,107.38 74.98,107.38 73.25,109.11 73.25,109.18 63.08,119.35 55.91,119.35 52.85,116.29 52.85,112.71 53.24,112.32 53.95,112.32 54.75,111.52 54.82,111.52 v4(54.95,111.39) 54.78,111.23 52.6,111.23 52.17,111.65 50.94,111.65 v4(50.57,112.03)
  BOTTOM w0.127: v4(54.95,111.39) 55.16,111.6 55.16,111.75 55.01,111.9 54.89,111.9 54.86,111.93 54.38,111.93 54.21,111.76 54.21,111.48 MEM3.J7 ; v2(49.88,112.65) 49.94,112.65 v4(50.57,112.03)
CLKA0#: length 49.3
  TOP w0.127: v4(50.51,111.22) 50.22,111.51 49.4,111.51 R1906.1 ; v4(55.53,111.08) 55.69,111.08 56,111.38 56.34,111.38 57.21,110.51 MEM1.K7 ; v4(76.6,106.41) 76.58,106.41 76.2,106.79 GPU1.H25
  L4 w0.152: v4(76.6,106.41) 76.6,106.64 76.47,106.77 76.42,106.77 76.11,107.07 74.85,107.07 72.94,108.98 72.94,109.06 62.96,119.04 56.04,119.04 53.15,116.16 53.15,112.84 53.37,112.62 54.07,112.62 54.84,111.86 55.17,111.86 55.55,111.48 55.55,111.09 v4(55.53,111.08) 55.24,111.08 55.09,110.92 52.47,110.92 52.05,111.35 50.64,111.35 v4(50.51,111.22)
  BOTTOM w0.127: v2(50.07,110.49) 50.07,110.78 v4(50.51,111.22) ; v4(55.53,111.08) 55.32,110.86 55,110.86 54.95,110.91 54.8,110.91 54.74,110.98 54.28,110.98 54.01,110.71 MEM3.K7
CLKA1: length 49.7
  TOP w0.127: v4(55.43,91.01) 55.43,91.18 55.09,91.52 54.65,91.52 54.15,92.02 MEM2.J7 ; v4(50.6,91.86) 50.35,92.11 49.33,92.11 R1909.1 ; GPU1.G9 75.4,93.76 75.24,93.6 v4(75.01,93.6)
  L4 w0.152: v4(75.01,93.6) 75.21,93.6 75.44,93.83 75.44,94.2 74.49,95.15 74.49,96.56 74.34,96.72 74.34,98.09 72.31,100.12 66.19,100.12 65.85,100.45 65.85,100.87 65.73,100.99 65.37,100.99 65.25,100.87 65.25,100.45 64.91,100.12 64.36,100.12 64.03,100.45 64.03,100.66 63.87,100.82 63.57,100.82 62.87,100.12 62.6,100.12 61.94,99.46 61.94,98.84 62.53,98.26 62.53,97.65 62.22,97.34 61.97,97.34 61.81,97.19 61.81,96.89 61.97,96.74 62.23,96.74 62.56,96.4 62.56,95.85 62.23,95.52 61.97,95.52 61.81,95.36 61.81,95.06 61.97,94.91 62.23,94.91 62.56,94.58 62.56,93.67 61.1,92.22 59.16,92.22 59,92.05 57.37,92.05 56.62,91.29 55.86,91.29 55.77,91.2 55.62,91.2 v4(55.43,91.01) 55.06,91.39 52.66,91.39 52.08,91.97 50.71,91.97 v4(50.6,91.86)
  BOTTOM w0.127: v4(55.43,91.01) 55.61,91.19 56.25,91.19 57.08,92.02 MEM4.J7 ; v2(74.91,92.79) 75.01,92.88 v4(75.01,93.6)
CLKA1#: length 50.1
  TOP w0.127: v4(55.59,91.64) 55.2,91.79 55.14,91.81 54.76,91.81 54.72,91.82 54.5,92.05 54.34,92.49 MEM2.K7 ; GPU1.H9 76.2,93.99 v4(75.81,93.6) ; R1908.1 49.33,92.36 50.31,92.36 v4(50.61,92.67)
  L4 w0.152: v4(75.81,93.6) 75.75,93.65 75.75,94.32 74.8,95.27 74.8,96.69 74.64,96.84 74.64,98.22 72.43,100.42 66.31,100.42 66.16,100.58 66.16,100.99 65.85,101.3 65.25,101.3 64.94,100.99 64.94,100.58 64.79,100.42 64.48,100.42 64.33,100.58 64.33,100.79 64,101.12 63.44,101.12 62.74,100.42 62.48,100.42 61.64,99.58 61.64,98.72 62.22,98.13 62.22,97.78 62.1,97.65 61.84,97.65 61.51,97.32 61.51,96.76 61.84,96.43 62.1,96.43 62.25,96.28 62.25,95.97 62.1,95.82 61.84,95.82 61.51,95.49 61.51,94.93 61.84,94.6 62.1,94.6 62.25,94.45 62.25,93.8 60.98,92.52 59.04,92.52 58.87,92.35 57.25,92.35 56.49,91.6 55.63,91.6 v4(55.59,91.64) 55.54,91.69 52.79,91.69 52.21,92.27 51.01,92.27 v4(50.61,92.67)
  BOTTOM w0.127: v4(55.59,91.64) 55.77,91.46 56.14,91.46 57.21,92.53 MEM4.K7 ; v2(75.78,94.39) 75.81,94.36 v4(75.81,93.6)
CLKTESTA: length 10.4
  TOP w0.102: v4(77.45,92.8) 77.48,92.83 77.48,92.88 GPU1.K8 ; v4(76.54,85.75) 77.01,85.75 v1(77.32,85.44) 77.32,84.54 C764.1
  L3 w0.127: v4(77.45,92.8) 76.95,92.31 76.95,90.67 76.7,90.42 76.7,88.31 77.15,87.86 77.15,86.41 76.54,85.8 v4(76.54,85.75)
CLKTESTA_C: length 3.2
  TOP w0.102: C764.2 77.15,83.44 75.95,82.24 v1(75.95,82.1) 76.9,82.1 R1207.1
CLKTESTB: length 11.2
  TOP w0.102: GPU1.L7 79.32,92.4 v4(79.38,92.46)
  BOTTOM w0.102: C763.1 83.49,84.51 83.49,85.41 v2(83.5,85.42) 83.49,85.43 83.49,85.65 83.3,85.84 82.46,85.84 81.85,86.45 81.85,86.45 81.44,86.86 81.44,87 80.98,87.46 80.96,87.46 80.55,87.87 80.55,88.21 80.59,88.26 80.59,88.41 80.52,88.49 80.52,89.02 80.62,89.12 80.62,91.34 79.51,92.46 v4(79.38,92.46)
CLKTESTB_C: length 7.1
  TOP w0.102: R1206.1 78.5,82.68 v1(79.66,82.68) 80.04,82.68 80.62,82.1 v4(80.62,81.91)
  BOTTOM w0.102: C763.2 83.62,82.83 82.7,81.91 v4(80.62,81.91)
COMP_OUT1: length 10.5
  TOP w0.102: v1(143.8,202.06) 143.8,201.36 R4708.1 R79725.1 145.51,202.25 U178.1 145.45,202.95 146.21,203.71 146.21,204.72 147.99,206.5 U178.6
COMP_OUT2: length 13.2
  TOP w0.102: v3(147.23,208.79) 146.72,208.28 U178.7
  L3 w0.127: v3(151.61,215.01) 150.66,215.01 147.23,211.58 v3(147.23,208.79)
  BOTTOM w0.102: R4707.1 v2(150.53,215.9) 150.53,215.14 150.66,215.01 v3(151.61,215.01)
COMPNB_R: length 2.6
  BOTTOM w0.254: PR4623.2 39.66,220.6 39.91,220.34 v2(39.91,220.09) 39.91,219.81 39.68,219.58 PC4611.1
CORETYPE: length 1.6
  TOP w0.102: v4(89,174.9) 88.7,174.9 CPU1.K24
  BOTTOM w0.102: v4(89,174.9) 89.02,174.88 TP213.1
CPU_BST1_SW1: length 2.9
  BOTTOM w0.508: PR4701.2 34.2,208.03 33.87,207.7 v2(33.54,207.7) 33.15,207.7 32.93,207.92 PC4704.1
CPU_BST2_SW2: length 3
  BOTTOM w0.508: PR4703.2 27.47,207.9 27.69,207.68 v2(28.1,207.68) 28.49,207.68 28.74,207.92 PC4710.1
CPU_FAN_CTRL_SIO: length 314.4
  TOP w0.165: R68.1 11.46,219.84 v1(11.83,220.21) 12.35,220.73 15.91,220.73 v3(16.54,220.09) ; U109.6 157.14,48.38 v3(157.01,48.51)
  L3 w0.165: v3(157.01,48.51) 156.85,48.67 155.15,48.67 154.54,49.28 153.74,49.28 153.39,49.63 150.18,49.63 149.83,49.28 148.73,49.28 148.06,48.62 145.6,48.62 144.5,47.52 140.26,47.52 139.33,46.59 135.34,46.59 134.63,47.3 131.12,47.3 129.95,48.47 122.84,48.47 122.14,49.17 120.09,49.17 119.44,49.82 113.75,49.82 113.41,50.16 111.44,50.16 109.89,48.61 101.7,48.61 101.38,48.93 98.04,48.93 96.89,50.08 92.48,50.08 91.65,50.91 89.91,50.91 85.04,55.78 82.33,55.78 80.89,57.22 74.46,57.22 71.04,60.64 68.3,60.64 67.62,61.32 66.42,61.32 65.51,62.23 60.38,62.23 57.56,65.06 40.34,65.06 38.59,66.81 35.1,66.81 v3(30.06,71.86)
  L4 w0.165: v3(16.54,220.09) 16.02,219.56 16.02,205.49 14.57,204.04 14.57,183.5 17.15,180.92 17.15,172.09 17.91,171.32 17.91,170.19 17.36,169.64 17.36,166.34 16.75,165.72 16.75,164.23 17.55,163.43 17.55,153.66 17.92,153.29 17.92,149.05 22.39,144.58 22.39,139.93 24.9,137.41 30.59,137.41 33.43,134.56 33.43,122.57 33.97,122.03 33.97,118.96 34.15,118.78 34.15,108.15 35.65,106.65 35.65,98.46 35.69,98.41 35.69,91.01 36.31,90.4 36.31,89.99 35.72,89.4 35.71,89.4 32.92,86.61 32.92,77.36 32.3,76.74 32.3,74.27 32.3,73.78 31.31,72.79 30.38,71.86 v3(30.06,71.86)
CPU_FAN_TACH_SIO: length 306.9
  TOP w0.165: v3(159.72,47.64) 159.71,47.64 159.37,47.98 U109.5 ; v3(14.15,205.28) 14.17,205.31 16.62,205.31 16.92,205.61 R74.1
  L3 w0.165: v3(81.06,51.18) 81.26,50.98 82.15,50.98 83.06,51.89 86.19,51.89 90.7,47.37 95.95,47.37 96.97,46.35 100.31,46.35 100.71,45.95 111.03,45.95 111.66,46.59 121.08,46.59 122.78,44.89 127.31,44.89 128.04,44.16 131.2,44.16 131.4,43.96 139.79,43.96 140.55,44.72 144.2,44.72 144.51,44.42 148.87,44.42 149.64,45.19 157.28,45.19 v3(159.72,47.64) ; v3(80.55,62.74) 80.26,62.74 79.9,62.37 76.46,62.37 71.74,67.1 69.22,67.1 65.82,63.7 60.14,63.7 57.98,65.86 40.67,65.86 38.92,67.61 35.44,67.61 30.93,72.12 30.93,72.27 30.06,73.13 v3(30.06,73.3)
  L4 w0.165: v3(81.06,51.18) 80.44,51.8 80.44,62.63 v3(80.55,62.74) ; v3(14.15,205.28) 14.15,183.33 16.18,181.29 16.18,166.83 15.57,166.21 15.57,163.39 16.29,162.66 16.29,157.67 15.65,157.03 15.65,153.89 16.74,152.8 16.74,148.56 18.65,146.65 18.65,142.6 19.17,142.08 19.17,140.34 23.28,136.23 29.2,136.23 32.23,133.2 32.23,115.02 32.93,114.32 32.93,112.54 32.69,112.3 32.69,104.97 33.14,104.51 33.14,93.25 31.74,91.85 31.74,77.95 31.1,77.32 31.1,74.32 30.09,73.3 v3(30.06,73.3)
  BOTTOM w0.165: v3(80.55,62.74) 80.55,62.1 v2(80.3,61.85)
CPU_VCORE: length 445.2
  TOP w0.254: v3(63.44,186.51) 63.44,186.72 63.91,187.2 PR4628.1
  TOP w0.356: CPU1.Y8 75.7,166 75.22,165.52 v4(75.22,165.48) 75.18,165.48 74.9,165.2 CPU1.AB7 ; CPU1.W15 v4(80.6,166.8) CPU1.Y13 v4(80.6,165.6) CPU1.AB15 v4(80.6,164.4) CPU1.AD13 v4(80.6,163.2) CPU1.AE15 v4(80.6,162) CPU1.AG13 CPU1.AH15 v4(80.6,159.73) CPU1.AK13 ; CPU1.W21 v4(85.4,166.8) CPU1.Y19 v4(85.4,165.6) CPU1.AB21 v4(85.4,164.4) CPU1.AD19 v4(85.4,163.2) CPU1.AE21 v4(85.4,162) CPU1.AG19 CPU1.AH21 v4(85.4,159.73) CPU1.AK19 ; v4(87.8,166.8) CPU1.Y22 v4(87.8,165.6) v4(87.8,164.4) CPU1.AD22 v4(87.8,163.2) v4(87.8,162) CPU1.AG22 87.8,160.8 v4(87.8,159.73) CPU1.AK22 ; CPU1.U8 75.3,168.2 v4(75.3,168) 75.3,167.8 CPU1.W7 ; CPU1.AK10 v4(78.2,159.73) CPU1.AH12 CPU1.AG10 v4(78.2,162) CPU1.AE12 v4(78.15,163.25) CPU1.AD10 v4(78.2,164.4) CPU1.AB12 v4(78.15,165.65) CPU1.Y10 v4(78.2,166.8) CPU1.W12 ; CPU1.W18 v4(83,166.8) CPU1.Y16 v4(83,165.6) CPU1.AB18 v4(83,164.4) CPU1.AD16 v4(83,163.2) CPU1.AE18 v4(83,162) CPU1.AG16 CPU1.AH18 v4(83,159.73) CPU1.AK16 ; v4(75.95,164.41) 76,164.41 76.11,164.52 76.22,164.52 76.5,164.8 CPU1.AB9 ; CPU1.AD6 v4(74.5,163.4)
  TOP w0.38: CPU1.AH7 74.46,159.75 74.46,159.35 CPU1.AK6 73.8,158.7 v4(73.8,158.4) ; v4(76.2,158.4) 76.5,158.7 CPU1.AK9 ; CPU1.AL7 74.9,157.5 74.6,157.2 v4(74.6,157.18) 74.6,157.14 74.1,156.64 CPU1.AN6 ; CPU1.AE7 74.84,162.54 74.84,162.14 CPU1.AG6 74.1,161.12 73.95,160.97 v4(73.95,160.82)
  TOP w0.508: v3(150.81,36.42) 149.66,36.42 149.06,35.83 146.87,35.83 146.79,35.91 146.28,35.91 145.34,36.86 144.71,36.86 143.9,36.04 142.02,36.04 G5.1 ; 49.65,172.72 PT4702.1 ; PT4702.1 50.71,173.77 ; PT4702.1 51.76,172.72 ; PT4709.1 50.71,181.65 ; PT4709.1 50.71,179.54 ; PT4709.1 49.65,180.59 ; PT4709.1 51.76,180.59 ; 58.58,180.47 59.63,180.47 ; 58.58,180.47 58.58,179.41 ; 58.58,180.47 58.58,181.52 ; 58.58,180.47 57.53,180.47 ; v3(163.86,39.88) 165.67,41.68 165.67,63.6 v3(165.62,63.65) ; v3(67.11,207.52) 66,206.4 66,203.67 65.95,203.62 65.95,193.65 58.99,186.69 58.99,185.8
  L3 w0.254: v5(59.77,184.25) 61.25,184.25 63.44,186.44 v3(63.44,186.51)
  L3 w0.508: v3(163.86,39.88) 160.21,36.22 152.64,36.22 152.43,36.42 v3(150.81,36.42)
  L4 w0.508: v3(127.03,221.36) 127.03,220.61 139.77,207.87 141.9,205.75 143.93,203.71 147.4,203.71 148.18,204.5 149.26,204.5 150.02,205.26 153.81,205.26 156.19,202.88 160.32,202.88 167.01,196.19 167.01,137.02 167.55,136.49 167.55,130.84 170.44,127.94 170.44,109.88 170.44,109.36 169.4,108.31 169.4,93.24 171.43,91.21 171.43,77.34 169.48,75.39 169.48,69.24 v3(169.45,69.22) ; 50.71,171.67 PT4702.1 ; PT4702.1 50.71,173.77 ; PT4702.1 51.76,172.72 ; PT4702.1 49.65,172.72 ; 58.58,180.47 58.58,181.52 ; 58.58,180.47 58.58,179.41 ; 58.58,180.47 59.63,180.47 ; 58.58,180.47 57.53,180.47 ; 49.65,180.59 PT4709.1 ; PT4709.1 50.71,179.54 ; PT4709.1 50.71,181.65 ; PT4709.1 51.76,180.59
  BOTTOM w0.508: v3(67.11,207.52) 67.11,206.86 67.98,205.99 81.95,205.99 83.56,207.61 88.88,207.61 89.9,208.62 v2(89.9,222.02) 89.9,224.49 91.91,226.5 123.58,226.5 126.27,223.8 126.27,222.12 v3(127.03,221.36) ; v3(169.45,69.22) 169.42,69.22 167.39,67.19 167.39,66.64 167.33,66.48 165.64,64.79 165.64,63.68 v3(165.62,63.65)
  vias: v2(77.12,166.62) v2(77.12,159.38) v2(88.32,166.19) v2(88.35,162.56) v3(50.66,181.84) v3(51.32,184.53) v3(53.25,184.53) v3(57.92,179.2) v3(58.25,181.71) v3(58.83,184.3) v3(59.14,181.71) v3(59.95,183.01) v3(59.95,182.07) v3(59.95,181.1) v5(52.23,184.48) v5(52.18,182.22) v5(52.15,181.08) v5(52.15,173.1) v5(52.26,183.39) v5(52.31,175.36) v5(52.59,185.52) v5(53.45,175.34) v5(53.7,185.52) v5(54.59,175.41) v5(56.01,178.94) v5(57.03,179.45) v5(57.21,182.52) v5(57.23,181.53) v5(57.23,180.49)
CPVEE: length 4
  TOP w0.203: U6.20 158.21,77.63 157.92,77.34 v3(157.92,77.27) 157.39,77.8 C1491.1
  BOTTOM w0.508: v3(157.92,77.27) 157.92,77.43 157.61,77.74 157.61,78.44 v2(157.63,78.45)
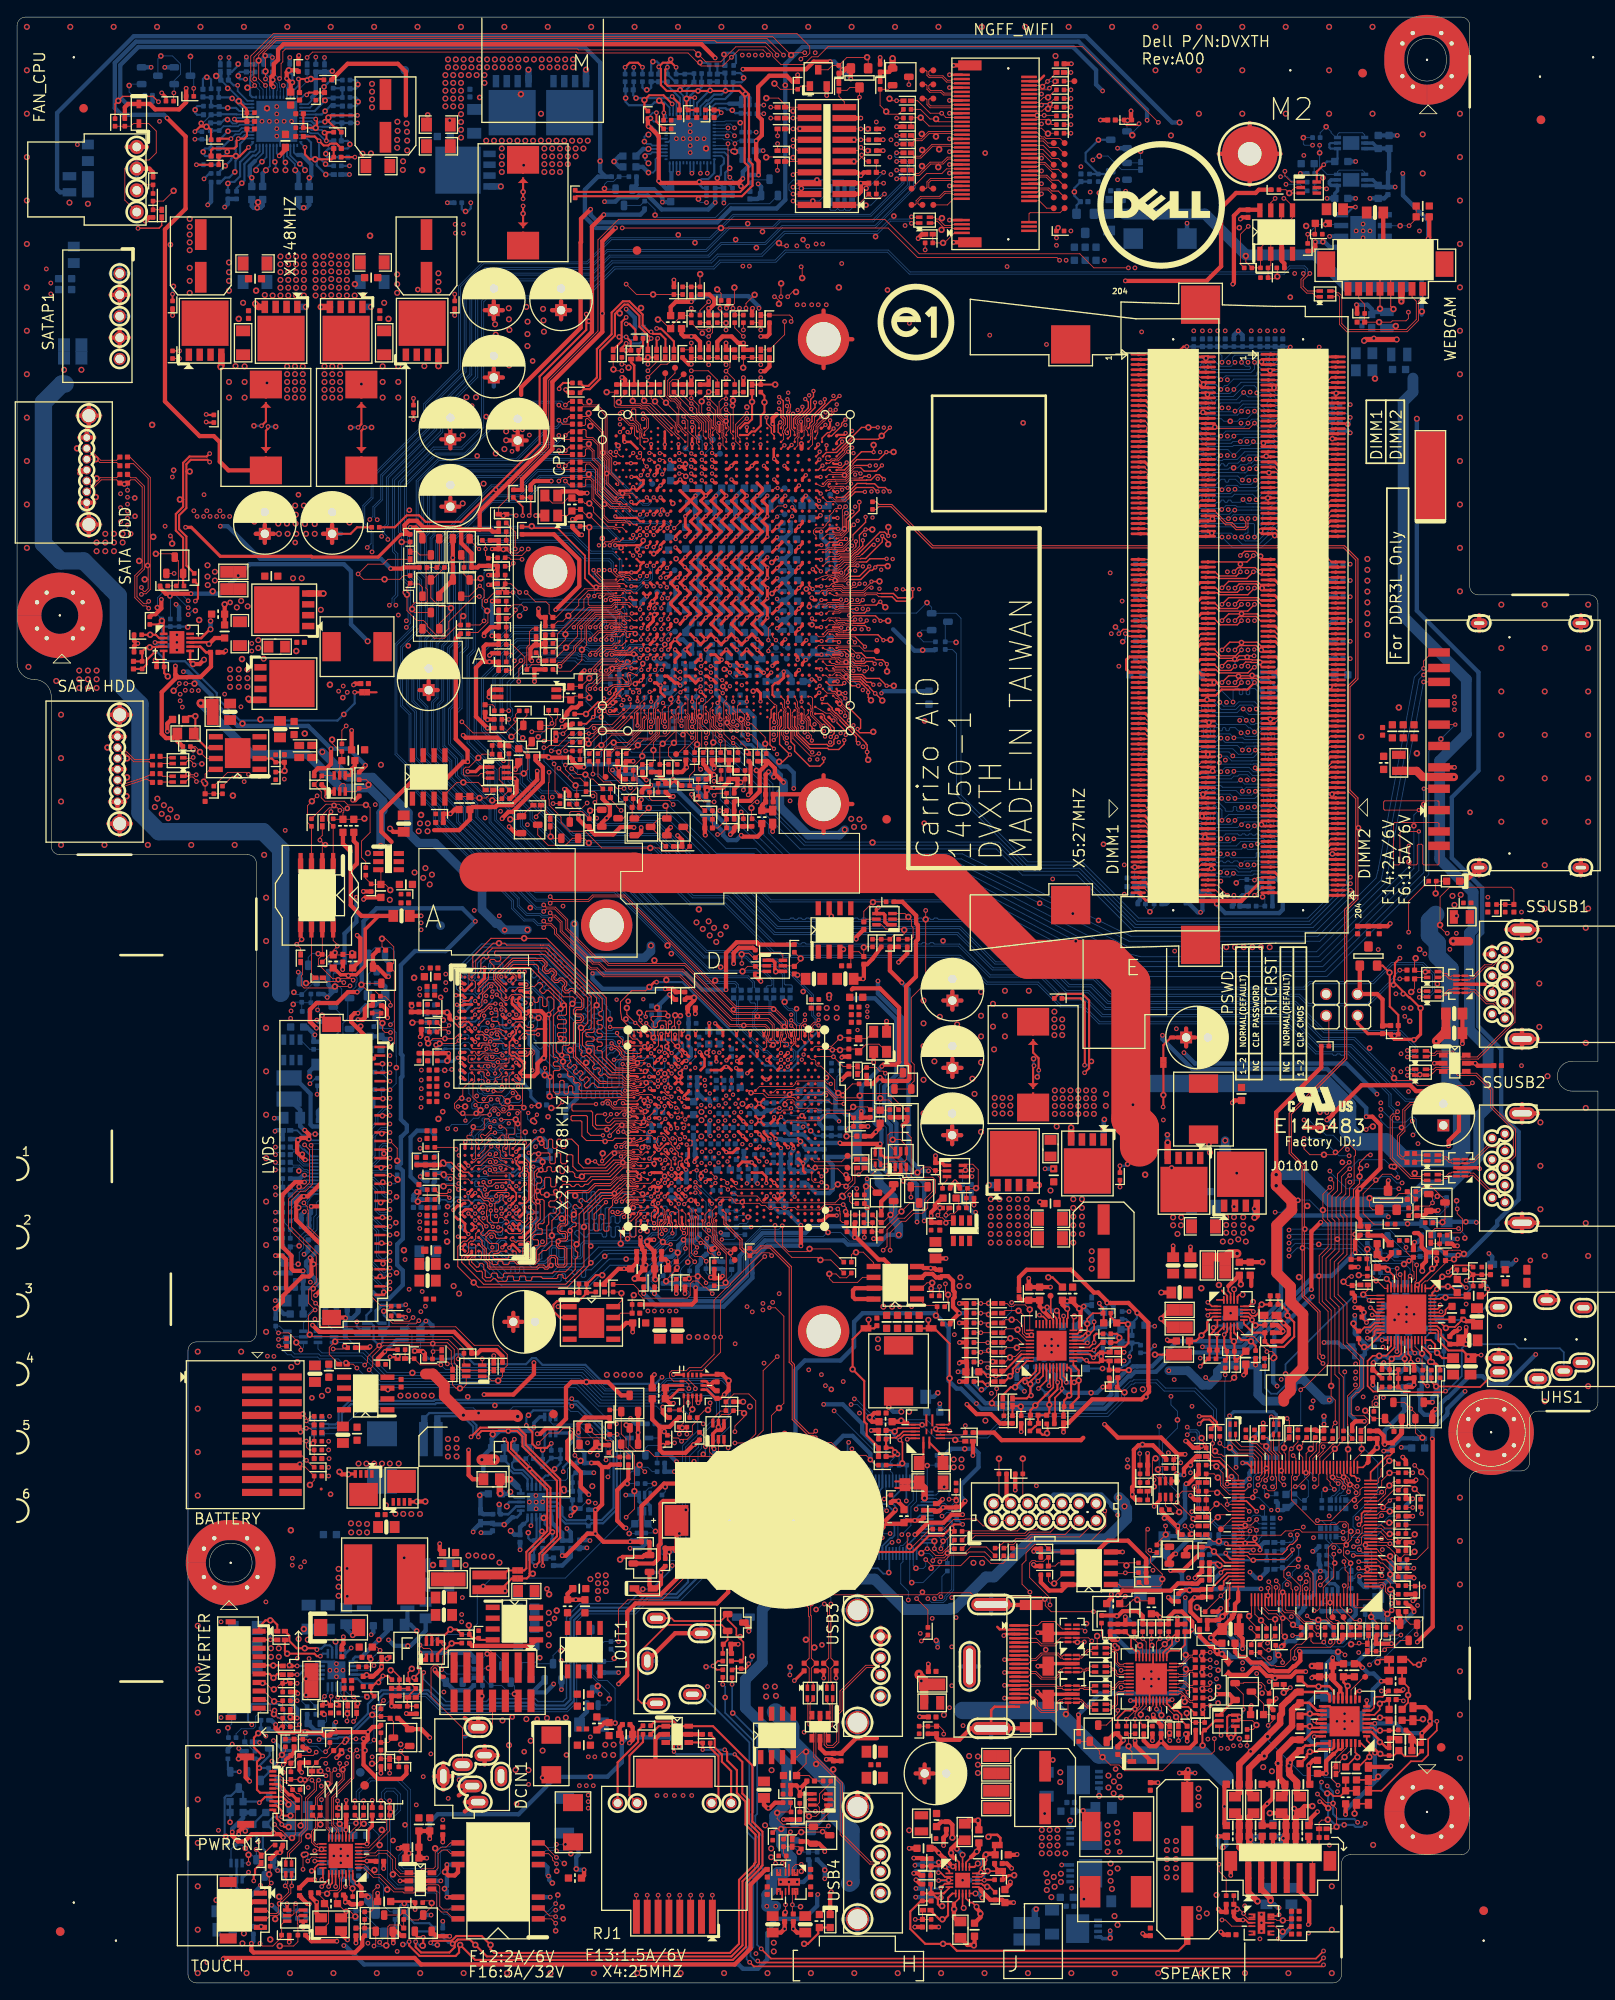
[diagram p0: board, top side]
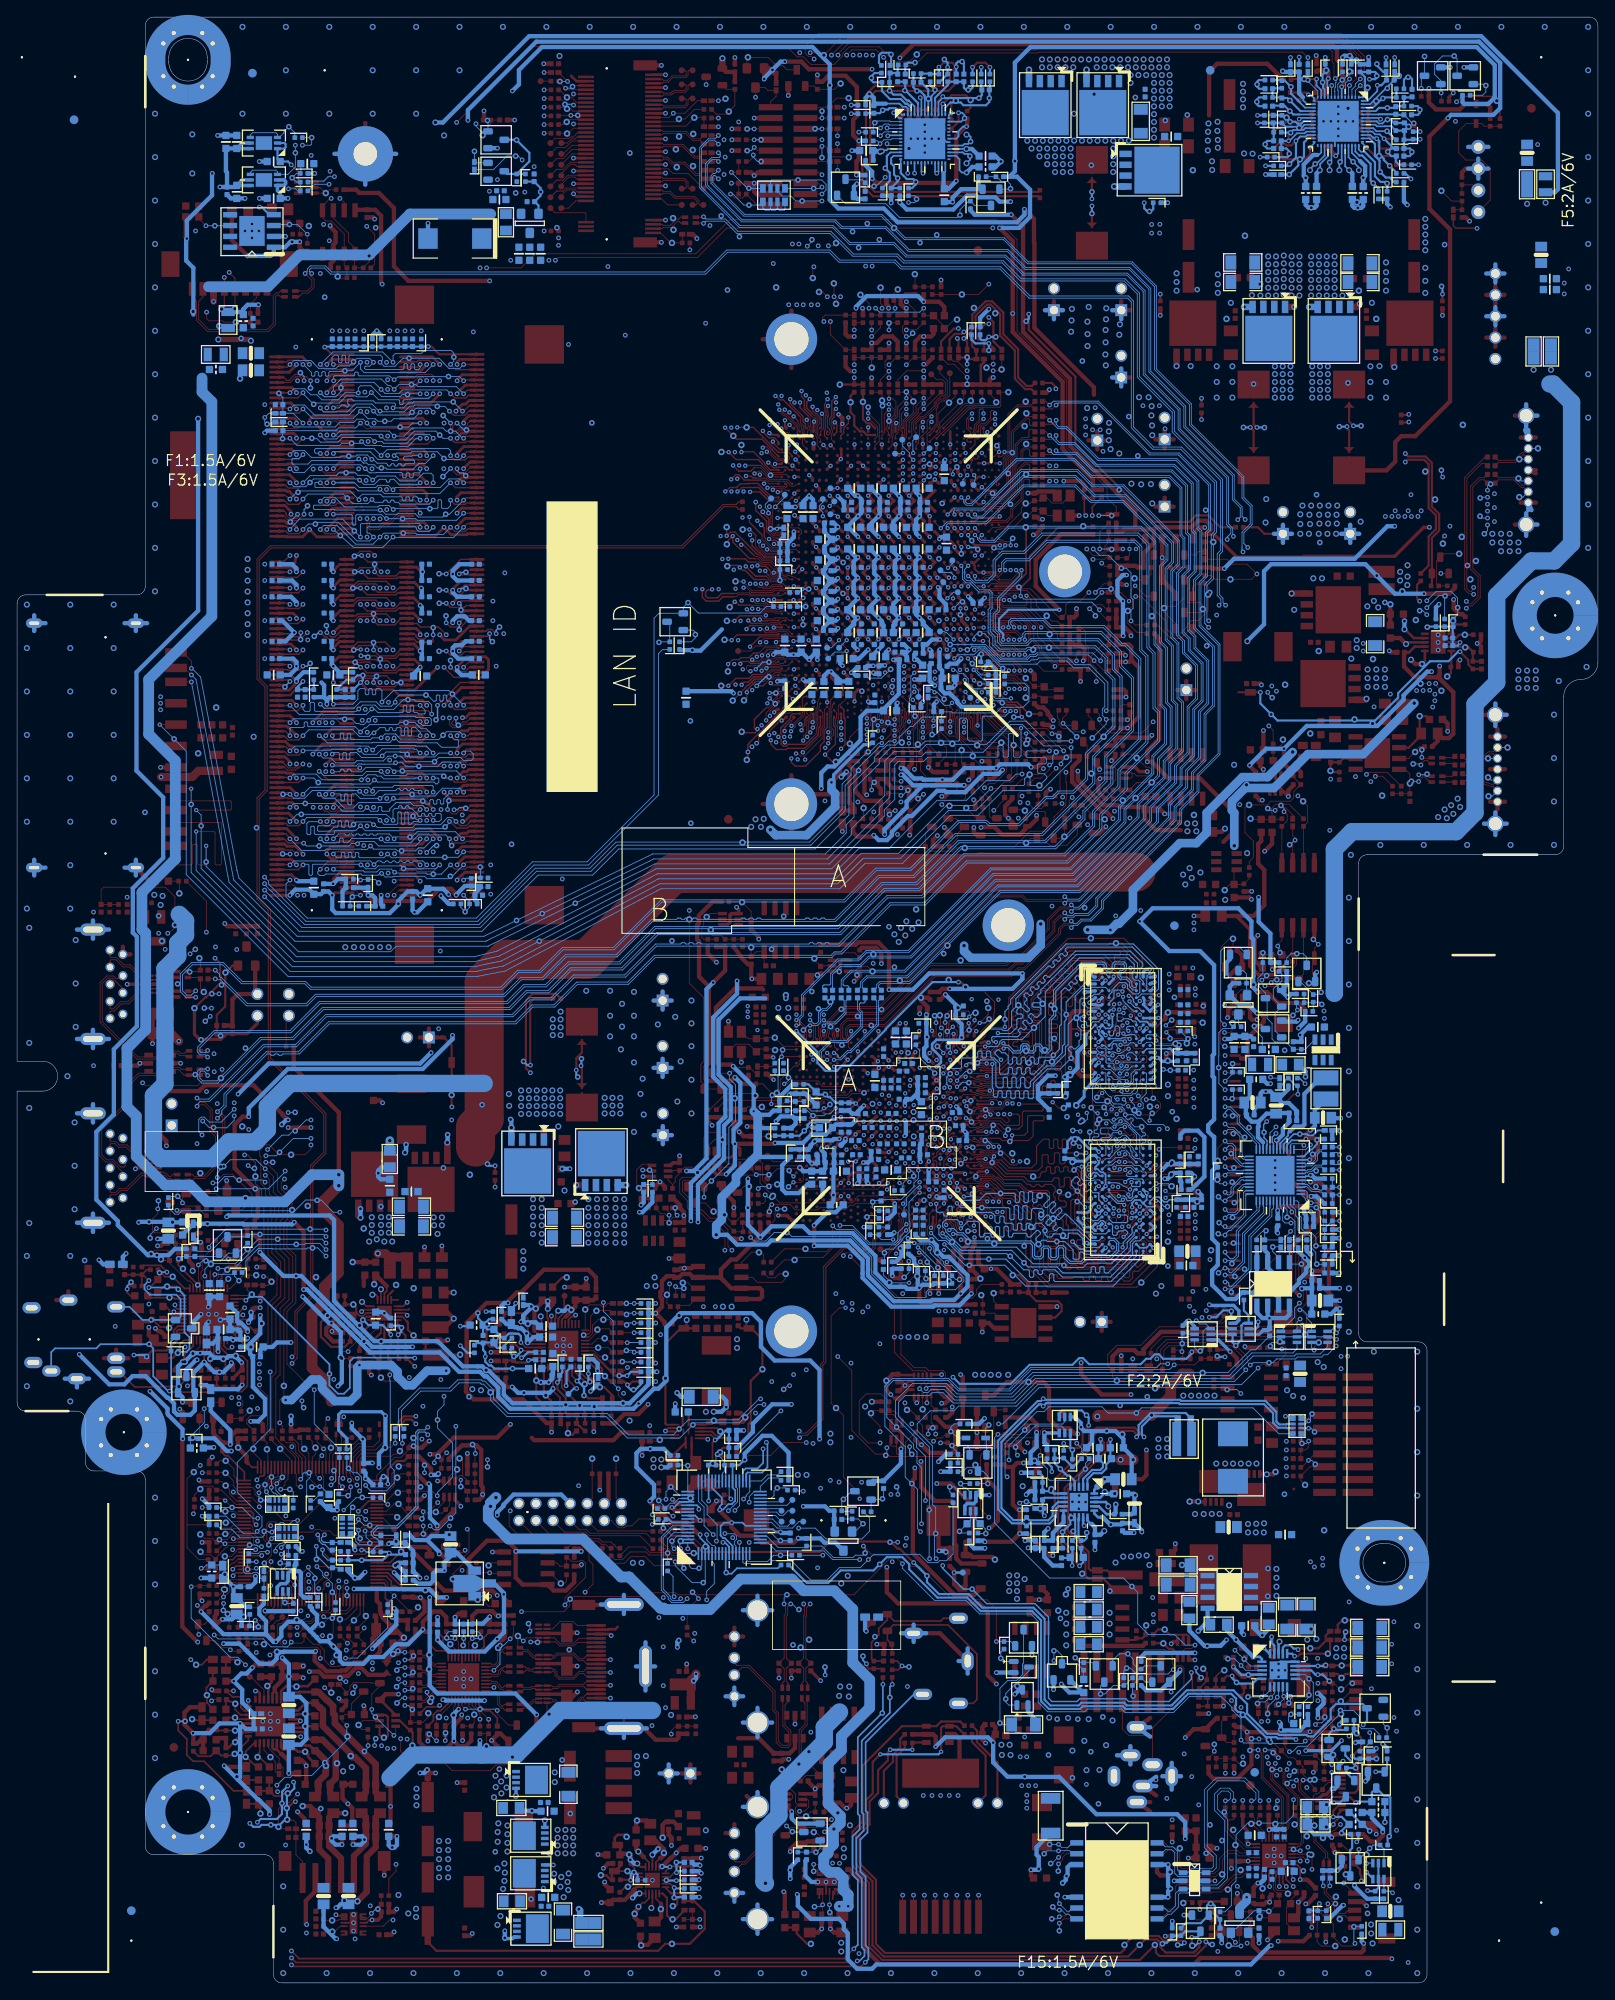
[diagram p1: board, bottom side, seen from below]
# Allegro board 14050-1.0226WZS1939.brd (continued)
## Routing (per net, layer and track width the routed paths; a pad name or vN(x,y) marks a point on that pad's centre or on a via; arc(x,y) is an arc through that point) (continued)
CSA0#_0: length 44.6
  TOP w0.127: v4(75.84,104.78) 75.84,104.4 76.04,104.2 GPU1.H22 ; v4(56.1,109.15) 55.49,109.15 55.36,109.28 55.36,109.61 55.24,109.74 54.49,109.74 54.38,109.62 54.38,109.44 54.25,109.31 53.34,109.31 53.21,109.43 MEM1.L2
  L3 w0.102: v4(75.84,104.78) 76.17,105.11 76.17,105.76 75.94,105.99 74.7,105.99 74.26,106.43 73.4,106.43 73.11,106.14
  L3 w0.165: 73.11,106.14 72.94,105.97 72.47,105.97 72.27,106.18 72.27,106.41 72.01,106.66 71,106.66 70.86,106.52 70.86,106.2 70.73,106.07 70.11,106.07 69.98,106.2 69.98,106.53 69.86,106.66 69.53,106.66 69.35,106.84 69.08,106.84 68.61,107.31 68.23,107.69 67.21,107.69 67.09,107.56 67.09,106.91 66.96,106.79 63.25,106.79 62.97,106.51 62.67,106.51 62.39,106.79 62.14,106.79 61.96,106.6 61.43,106.6 61.19,106.84 61.19,107.15 61.07,107.28 60.18,107.28 60.07,107.17 58.12,107.17 57.26,108.03 56.67,108.03 56.51,108.18 56.06,108.18 55.79,107.92 55.73,107.92 55.51,107.7 52.86,107.7 52.66,107.9 52.66,109.35 52.89,109.58 54.03,109.58 54.23,109.38 54.23,109.02 54.44,108.82 55.07,108.82 55.55,109.3 55.95,109.3 v4(56.1,109.15)
  BOTTOM w0.127: MEM3.L2 57.73,109.68 57.29,109.24 56.98,109.24 56.85,109.37 56.85,109.72 56.7,109.87 56.43,109.87 56.3,109.75 56.3,109.57 56.1,109.37 v4(56.1,109.15) ; v2(75.8,106.38) 76.21,105.97 76.21,105.15 v4(75.84,104.78)
CSA1#_0: length 43.7
  TOP w0.127: MEM2.L2 57.65,93.98 55.6,93.98 v4(55.32,93.7) ; v4(76.59,95.23) 76.54,95.27 76.54,96.2 76.09,96.66 76.06,96.66 75.71,97 GPU1.G13
  L3 w0.165: v4(76.59,95.23) 76.59,95.08 76.06,94.55 74.78,94.55 74.5,94.83 74.24,95.08 72.57,95.08 72.23,95.42 70.63,95.42 70.49,95.27 67.06,95.27 66.9,95.44 62.24,95.44 60.08,97.59 58.66,97.59 58.58,97.67 57.36,97.67 57.23,97.8 57.23,98.35 57.36,98.48 59.19,98.48 v3(59.4,98.28)
  L4 w0.102: v4(55.32,93.7) 55.74,94.12 58.71,94.12 58.97,94.38
  L4 w0.165: 58.97,94.38 58.97,95.89 59.33,96.26 60.2,96.26 60.33,96.38 60.33,97.43 60.14,97.62 60.14,97.69 60.14,97.69 60.14,98.58 60.04,98.68 59.81,98.68 v3(59.4,98.28)
  BOTTOM w0.127: MEM4.L2 53.21,93.92 53.34,94.05 54.32,94.05 54.4,94.13 54.76,94.13 54.82,94.07 54.96,94.07 v4(55.32,93.7) ; v2(59.47,99.55) 59.47,98.34 v3(59.4,98.28)
CTF_TRIP: length 4.6
  TOP w0.102: Q48.B 102.59,90.23 v1(102.22,89.87) 101.32,88.96 C755.2 101,88.96 R391.2
CTFB: length 3.8
  TOP w0.102: R354.2 R1920.2 99.16,93 v1(99.35,93.19) 99.4,93.24 99.89,93.24 Q48.C
D2_M: length 5.2
  TOP w0.508: v1(70.57,49.53) 70.87,49.83 73.21,49.83 73.43,50.06 D23.2 74.01,51.54 R1672.1
DC_19V: length 82.2
  TOP w0.508: v3(52.84,62.36) 52.84,59.41 53.32,58.93 PR5284.1 ; PU5204.5 60.04,39.43 53.25,39.43 PR5282.1
  TOP w1.27: 47.79,71.25 48.67,71.25 49.99,69.93 49.99,68.66 v1(52.23,66.42) 58.43,66.42 v5(58.58,66.27)
  L3 w0.508: v3(66.76,63.2) 67.17,62.79 70.45,62.79 72.25,60.99 v3(77.17,60.99)
  L4 w0.508: 65.82,59.44 66.07,59.69 v3(67.5,59.69) ; v3(66.76,63.2) 64.07,63.2 63.71,63.55 ; v5(58.58,66.27) 54.67,62.36 v3(52.84,62.36)
  L4 w1.27: v5(62.22,43.31) 62.22,46.72 65.16,49.66 65.16,52.24 65.82,52.9 65.82,59.44 63.71,61.54 63.71,63.55 61,66.27 v5(58.58,66.27)
  BOTTOM w0.508: v3(77.17,60.99) 76.31,61.85 PR4431.1 ; PR5270.1 v3(67.5,59.69)
  vias: v1(46.26,71.37) v1(62.26,45.47) v1(63.15,43.56) v2(62.01,46.1) v2(62.9,42.65) v5(62.22,42.04) v5(62.22,40.77) v5(62.22,39.5)
DC_IN_D: length 3.8
  TOP w0.254: PR5282.2 50.88,39.75 v1(50.86,39.73) 50.22,39.09 49.79,39.09 49.2,38.5 PQ5005.3
DCBATOUT: length 496.6
  TOP w0.203: PU4901.11 112.52,11.21 112.76,10.97
  TOP w0.254: 102.78,58.67 PG5205.1 PG5210.1 102.78,57.91 ; PR5276.2 56.91,47.73 57.44,48.26 PG4905.1
  TOP w0.508: R1164.1 109.19,93.15 v3(109.76,93.73) 110.33,93.15 R1918.1 ; R1778.1 34.77,141.67 35.21,142.11 36.23,142.11 36.74,142.62 v3(36.74,144.4) ; v3(89.7,19.11) R1780.1 R1777.1 ; v3(52.2,145.97) 52.48,145.69 56.17,145.69 56.48,145.38 R179.1 57.5,144.78 R171.1 ; v3(103.54,117.04) 102.14,118.44 R79666.1 R79662.2 ; 45.5,218.49 45.5,223.6 44.56,224.54 38.68,224.54 PR4616.1 ; PR5007.1 v3(144.94,72.29) ; R733.1 40.76,142.39 v3(40.76,142.47) ; R4702.1 145.32,209.8 144.94,209.42 142.65,209.42 140.9,207.67 140.9,200.84 139.2,199.14 v3(129.7,199.14) ; 112.76,10.97 112.76,10.94 112.87,10.82 112.87,10.73 113.89,9.72 PR4901.1 115.29,9.72 PC4903.1 v3(116.62,9.4)
  TOP w0.762: L10.1 v3(151.52,37.08)
  TOP w4.572: 131.35,97.79 131.35,100.08 130.34,101.09 130.34,117.09 127.67,119.76 118.27,119.76 108.24,129.79 72.4,129.79 72.23,129.96 54.05,129.96
  L3 w0.508: v5(22.31,163.55) 19.95,163.55 18.35,161.95 18.33,161.95 17.94,161.56 17.94,161.54 17.84,161.44 17.84,155.78 19.46,154.15 v3(19.46,153.42) ; 109.38,94.61 109.63,94.61 111.03,96.01 112.17,96.01 112.94,95.25 112.94,86.11 113.32,85.72 122.72,85.72 v5(123.6,86.61) ; 109.38,94.61 109,95 v3(106.66,95) ; 109.38,94.61 109.76,94.23 v3(109.76,93.73) ; v3(54.77,136.3) 54.77,137.25 54.14,137.88 41.94,137.88 v3(41.92,137.86) 40.72,136.66 40.72,133.2 39.71,132.18 v3(39.71,127.03) ; 89.7,23.39 v3(89.7,19.11)
  L4 w0.508: v3(41.92,137.86) 40.85,138.93 40.85,142.38 v3(40.76,142.47) ; v3(52.2,145.97) 52.2,145.45 54.07,143.57 54.07,137.66 54.77,136.97 v3(54.77,136.3) ; v3(151.62,50.5) 151.62,51.25 150.92,51.96 150.92,52.43 151.45,52.96 151.45,54.41 152.48,55.44 152.48,62.18 152.19,62.46 152.19,65.7 153.58,67.09 v3(153.58,68.2) ; v3(68.74,208.41) 66.2,208.41 62.26,204.47 53.75,204.47 v5(49.31,200.03) ; v3(129.7,199.14) 111.66,199.14 107.36,203.43 102.58,203.43 95.24,210.77 89.77,210.77 88.2,209.19 82.58,209.19 v3(81.69,208.31)
  L4 w0.762: v3(151.62,50.5) 151.7,50.42 151.7,45.82 150.05,44.17 150.05,39.95 151.04,38.96 151.04,37.57 v3(151.52,37.08)
  L4 w1.016: v5(135.8,87.63) 136.2,87.22 136.2,85.85 136.08,85.73 136.08,72.92 v3(134.78,71.63)
  BOTTOM w0.508: v3(151.62,50.5) 151.8,50.5 152,50.7 152.01,50.7 R657.1 ; v3(68.74,208.41) 70.01,208.41 70.52,208.91 72.55,208.91 72.75,209.12 73.82,209.12 75.44,207.5 80.89,207.5 v3(81.69,208.31) PR5424.1 ; v3(39.71,127.03) 39.71,124.16 38.32,122.77 R20.1 R26.1 ; v3(106.66,95) 105.8,95 104.33,96.47 104.33,116.26 v3(103.54,117.04) ; v3(71.79,66.04) 72.42,65.41 PR4458.1 ; v3(19.46,153.42) 19.97,153.42 22.74,150.65 22.74,150.13 25.8,147.07 34.07,147.07 v3(36.74,144.4) 38.83,144.4 v3(40.76,142.47)
  BOTTOM w1.016: v3(134.78,71.63) 137.02,71.63 138.72,69.93 139.48,69.93 140.47,70.92 140.47,71.52 141.23,72.29 v3(144.94,72.29) 145.19,72.03 145.19,68.86 145.98,68.07 147.81,68.07 149.31,69.57 149.31,70.21 149.7,70.59 150.51,70.59 152.9,68.2 v3(153.58,68.2)
  vias: v1(22.89,162.81) v1(28.2,208.33) v1(41.31,204.42) v1(47.4,212.09) v1(132.01,94.56) v2(15.27,165.84) v2(46.9,198.12) v2(48.06,218.55) v2(135.11,95.35) v5(7.27,153.54) v5(7.27,152.53) v5(7.27,151.51) v5(8.29,153.54) v5(8.29,152.53) v5(8.29,151.51) v5(9.3,168.53) v5(9.3,167.51) v5(9.3,153.54) v5(9.3,152.53) v5(9.3,151.51) v5(10.32,169.54) v5(10.32,168.53) v5(10.32,167.51) v5(11.34,169.54) v5(11.34,168.53) v5(11.34,167.51) v5(12.35,169.54) v5(12.35,168.53) v5(16.12,137.58) v5(16.42,138.56) v5(16.92,136.78) v5(17.18,137.79) v5(17.69,136.27) v5(17.94,137.29) v5(18.7,136.4) v5(20.2,200.66) v5(20.2,199.14) v5(20.2,197.73) v5(22.28,165.86) v5(22.28,164.54) v5(23.15,165.1) v5(23.15,164.08) v5(24.8,201.29) v5(24.8,200.15) v5(24.8,199.14) v5(24.8,197.99) v5(39.07,53.77) v5(39.1,52.7) v5(39.99,53.72) v5(40.04,52.7) v5(40.95,53.7) v5(40.95,52.7) v5(44.51,217.75) v5(44.53,216.69) v5(44.48,215.63) v5(44.48,214.72) v5(44.48,199.9) v5(44.48,198.75) v5(44.48,197.74) v5(44.86,68.71) v5(45.14,212.12) v5(45.17,213.13) v5(45.58,217.55) v5(45.63,216.59) v5(45.65,215.54) v5(45.65,214.4) v5(45.78,68.71) v5(46.52,129.92) v5(46.69,68.71) v5(47.53,129.29) v5(47.61,68.71) v5(47.79,130.43) v5(48.29,128.52) v5(48.55,129.67) v5(48.52,68.71) v5(49.31,199.01) v5(49.31,197.99) v5(52.48,48.9) v5(52.81,50) v5(53.73,50) v5(54.64,49.89) v5(55.56,49.89) v5(56.45,49.18) v5(67.09,47.24) v5(67.98,47.68) v5(67.98,46.76) v5(67.98,45.85) v5(67.98,44.93) v5(68.74,26.67) v5(68.84,27.86) v5(68.89,47.68) v5(68.89,46.76) v5(68.89,45.85) v5(69.02,71.15) v5(69.81,27.86) v5(69.76,26.67) v5(70.14,71.15) v5(71.05,71.15) v5(71.97,71.15) v5(72.88,71.15) v5(89.82,64.26) v5(89.82,63.25) v5(111.41,26.54) v5(112.44,26.49) v5(112.44,25.53) v5(112.44,24.56) v5(123.6,91.69) v5(123.6,90.68) v5(123.6,89.66) v5(123.6,88.65) v5(123.6,87.63) v5(124.62,91.69) v5(124.62,90.68) v5(124.62,89.66) v5(124.62,88.65) v5(124.62,87.63) v5(135.29,89.57) v5(135.29,88.65) v5(136.25,89.57) v5(136.2,88.65)
DCIN_EN: length 3.4
  TOP w0.102: R2087.2 134.77,40.07 134.45,39.75 134.43,39.75 v1(134.31,39.63) 133.74,39.06 U118.13
DDCBUF: length 5.8
  TOP w0.102: U118.14 133.34,39.88 v3(133.75,40.29) R1598.2
  BOTTOM w0.102: v3(133.75,40.29) 133.84,40.21 134.58,40.21 v2(134.73,40.36) 134.73,40.84 134.48,41.09 R1598.2
DDR3_DRAMRST_N: length 74.9
  TOP w0.102: CPU1.T33 95.58,169.72 96.25,169.72 96.58,170.05 96.58,172.34 v3(96.96,172.72)
  L3 w0.127: v3(156.01,183.16) 155.37,182.51 155.37,177.15 152.45,174.23 128.32,174.23 127.29,175.26 99.44,175.26 96.96,172.78 v3(96.96,172.72)
  BOTTOM w0.102: R99.1 155.04,182.37 v2(155.74,182.37) 155.76,182.37 156.01,182.63 v3(156.01,183.16) 155.53,183.64 R2054.1
DDR3_DRAMRST_N_A_1: length 17.1
  TOP w0.102: v3(144.81,182.5) 144.16,181.85 DIMM1.30
  BOTTOM w0.102: C1726.1 153.93,181.57 v2(153.93,180.67) ; C1726.1 147.7,181.61 147.37,181.94 145.38,181.94 v3(144.81,182.5) ; C1726.1 R99.2
DDR3_DRAMRST_N_B_1: length 8.7
  TOP w0.102: v3(151.54,182.5) 152.19,181.85 DIMM2.30
  BOTTOM w0.102: v3(151.54,182.5) 152.69,183.64 R2054.2 C1958.1 153.89,185.51 v2(154.37,185.98)
DDR_VREF_S3: length 1.9
  TOP w0.254: PR5032.1 v1(133.15,73.51)
DGPU_PWROK: length 69.4
  TOP w0.102: PR5261.1 72.13,81.72 72.7,81.15 72.7,80.64 73.23,80.11 78.42,80.11 78.77,80.47 78.77,81.79 79.1,82.12 79.65,82.12 80.36,81.41 80.6,81.41 v3(81.36,80.65) ; PR6.2 115.48,67.37 PR14.2 114.4,67.5 v1(114.08,67.82) 114.08,68.2 114.64,68.76 v3(114.64,69.52)
  L4 w0.127: v3(81.36,80.65) 81.57,80.65 85.47,84.54 100.83,84.54 101.52,85.23 110.76,85.23 v3(116.39,79.6)
  BOTTOM w0.102: v3(116.39,79.6) 116.39,78.59 115.25,77.45 115.25,70.13 v3(114.64,69.52)
DGPU_PWROK_0D95V: length 5.9
  TOP w0.102: R79727.1 100.21,126.49 v1(100.16,126.44) 99.09,125.37 C6707.1 99.41,124.46 Q6702.5
DGPU_PWROK_1D5V: length 4.2
  TOP w0.102: PC5433.1 PR5261.2 70.58,80.84 v1(70.72,80.7) 70.72,79.78 70.06,79.12 PU7.8
DIFFNB_R: length 2.6
  BOTTOM w0.254: PC4610.1 39.63,221.62 39.89,221.87 v2(39.89,222.12) 39.89,222.43 39.68,222.63 PR4622.2
DIMM_APU_VREF: length 3.2
  TOP w0.254: v4(96.08,170.13) 96.05,170.13 95.99,170.18 95.08,170.18 CPU1.T32
  BOTTOM w0.254: v2(96.83,170.13) v4(96.08,170.13) 95.97,170.24 R1912.2
DIMM_DQ_APU_VREF_MA: length 7.2
  TOP w0.254: R81.2 87.46,185.69 v1(87.46,184.94) 87.46,183.77 87.03,183.34 87.03,182.19 86.36,181.52 85.96,181.52 85.54,181.1 CPU1.B19
DIMM_DQ_APU_VREF_MB: length 5
  TOP w0.254: CPU1.A19 85.19,182.49 85.55,182.49 86.01,182.95 v1(86.01,184.99) R1697.2
DIMM_TMPIN2+: length 193.5
  TOP w0.127: U109.86 144.07,50.38 144.28,50.16 148.08,50.16 148.62,50.71 148.62,50.94 148.99,51.31 149.26,51.31 149.82,51.87 v3(149.82,52.43) ; v3(152.82,72.48) 152.71,72.59 152.71,72.61 152.23,73.09 152.23,78.47 150.39,80.31 150.39,82.58 ; v1(150.02,82.58) 150.39,82.58 ; 150.39,82.58 150.39,95.54 148.87,97.06 148.87,101.74 155.35,108.23 155.35,125.6 156.66,126.91 156.66,138.54 155.74,139.47 155.74,151.73 156.66,152.66 156.66,166.48 155.25,167.89 107.09,167.89 102.27,172.72 100.86,172.72 100.54,172.4 RT1.1
  L4 w0.127: v3(149.82,52.43) 149.28,52.96 149.28,53.57 149.97,54.25 149.97,56.43 150.31,56.78 150.31,59.55 150.71,59.95 150.71,66.35 150.99,66.62 150.99,71.04 152.45,72.5 152.8,72.5 v3(152.82,72.48)
  BOTTOM w0.127: R397.1 147.28,50.63 C231.2 148.32,50.63 148.99,51.31 149.26,51.31 149.64,51.69 149.64,52.25 v3(149.82,52.43)
DIMM_TMPIN2-: length 184.3
  TOP w0.127: 150.64,90.91 150.64,80.41 152.48,78.57 152.48,73.59 v3(152.82,73.24) ; 150.64,90.91 v1(150.99,90.91) ; 150.64,90.91 150.64,95.64 149.12,97.16 149.12,101.64 155.61,108.12 155.61,125.5 156.92,126.81 156.92,138.65 155.99,139.57 155.99,151.63 156.92,152.56 156.92,166.59 155.35,168.15 107.2,168.15 102.37,172.97 100.86,172.97 100.54,173.29 RT1.2
  L4 w0.127: v3(152.82,73.24) 150.73,71.15 150.73,66.73 150.46,66.46 150.46,60.06 150.06,59.66 150.06,56.88 149.71,56.53 149.71,54.36 149.03,53.67 v3(149.03,52.43)
  BOTTOM w0.127: R399.2 148.1,51.54 C231.1 148.85,51.52 148.89,51.56 149.15,51.56 149.39,51.79 149.39,52.07 v3(149.03,52.43)
DIS_EN_0D95_RUN_R: length 8.4
  TOP w0.102: v1(104.3,124.71) 103.9,125.11 Q6702.3 ; v1(104.3,124.71) 104.66,124.36 104.66,123.65 104.86,123.45 104.86,122.33 104.64,122.11 R79665.2 R79662.1 ; v1(104.3,124.71) 104.05,124.46 Q6702.2
DP0_AUXN: length 175
  TOP w0.102: CPU1.E8 75.52,178.98 v4(75.22,178.98)
  L3 w0.127: v3(12.92,174.64) 13.2,174.36 17.81,174.36 20.38,176.93 48.14,176.93 49.44,178.23 51.99,178.23 54.82,181.06 54.82,183.4 60,188.58 66.56,188.58 71.28,183.86 71.28,183.01 72.59,181.7 73.51,181.7 74.52,180.69 74.96,180.25 74.96,179.23 v4(75.22,178.98)
  L4 w0.127: v3(12.92,174.64) 13.19,174.36 13.63,174.36 15.41,172.59 15.41,167.1 14.08,165.77 14.08,162.26 14.92,161.42 14.92,153.58 15.26,153.25 16.01,152.49 16.01,148.25 17.11,147.15 17.11,141.36 22.98,135.5 28.9,135.5 31.49,132.9 31.49,104.81 32.41,103.89 32.41,93.6 31.33,92.51 30.54,92.51 v3(30.23,92.2)
  BOTTOM w0.102: v3(30.23,92.2) C305.1 R1074.2 ; v3(12.92,174.64) 12.92,175.12 12.68,175.37 v2(12.56,175.37)
DP0_AUXP: length 174.9
  TOP w0.102: CPU1.F8 75.8,178.1 75.67,178.23 75.25,178.23 v4(75.2,178.18)
  L3 w0.127: v3(12.92,173.82) 13.19,174.1 17.92,174.1 20.49,176.66 48.25,176.66 49.55,177.96 52.1,177.96 55.08,180.94 55.08,183.29 60.11,188.32 66.44,188.32 71.01,183.75 71.01,182.9 72.48,181.43 73.4,181.43 74.41,180.42 74.7,180.14 74.7,178.32 74.84,178.18 v4(75.2,178.18)
  L4 w0.127: v3(30.23,93.09) 30.54,92.78 31.22,92.78 32.14,93.71 32.14,103.78 31.23,104.7 31.23,132.79 28.79,135.23 22.87,135.23 16.85,141.25 16.85,147.04 15.74,148.14 15.74,152.38 14.65,153.47 14.65,161.31 13.81,162.15 13.81,165.88 15.14,167.21 15.14,172.48 13.52,174.1 13.19,174.1 v3(12.92,173.82)
  BOTTOM w0.102: v2(13.77,173.74) 13.69,173.82 v3(12.92,173.82) ; R1079.1 C304.1 v3(30.23,93.09)
DP0_HPD: length 176
  TOP w0.102: CPU1.G8 75.8,176.8 v4(75.5,176.5)
  L3 w0.127: v4(75.5,176.5) 75.37,176.5 74.96,176.91 68.74,176.91 67.81,177.84 67.81,180.55 66.92,181.43 66.92,181.78 64.66,184.04 62.76,184.04 60.89,182.17 60.89,181.31 55.81,176.23 50.27,176.23 48.67,174.62 21.5,174.62 18.41,171.54 16.71,171.54 10.54,165.37 10.54,148.19 13.16,145.58 13.16,136.36 15.62,133.89 29.46,133.89 30.39,132.97 30.39,117.05 30.7,116.73 30.7,89.62 v3(30.23,89.15)
  BOTTOM w0.102: v3(30.23,89.15) R510.2 31.97,88.27 R530.1 R512.1 ; v2(75.01,177.37) 75.04,177.37 75.5,176.91 v4(75.5,176.5)
DP0_TXN0: length 164.8
  TOP w0.102: v4(69.45,179.12) 69.45,178.92 69.77,178.6 CPU1.E1
  L3 w0.127: v4(69.45,179.12) 69.62,179.29 69.62,182.71 64.67,187.65 60.39,187.65 55.75,183.02 55.75,180.55 52.5,177.29 49.83,177.29 48.53,175.99 20.76,175.99 18.2,173.43 15.61,173.43 14.93,172.75 13.67,172.75 13.55,172.62 13.55,172.14 13.42,172.01 13.05,172.01 12.92,172.14 v3(12.92,172.2)
  L4 w0.127: v3(12.92,172.2) 13.19,172.47 13.55,172.47 14.47,171.54 14.47,167.48 13.14,166.15 13.14,154.03 15.07,152.11 15.07,147.87 16.18,146.76 16.18,140.97 22.59,134.56 28.51,134.56 30.56,132.51 30.56,104.22 31.44,103.35 31.44,96.05 30.86,95.47 30.58,95.47 30.23,95.81 v3(30.23,96.01)
  BOTTOM w0.102: v3(30.23,96.01) 30.23,95.89 30.36,95.76 30.96,95.76 31.08,95.89 C301.1 ; v4(69.45,179.12) 68.61,179.12 v2(68.54,179.04)
DP0_TXN1: length 163.8
  TOP w0.102: v4(72.9,179) 73.06,178.84 73.06,178.46 72.91,178.31 72.63,178.31 72.5,178.44 CPU1.E4
  L3 w0.127: v4(72.9,179) 72.12,178.22 69.08,178.22 68.47,178.83 68.47,182.91 64.4,186.98 60.66,186.98 56.42,182.74 56.42,180.27 52.77,176.63 50.11,176.63 48.81,175.32 21.04,175.32 18.48,172.76 15.89,172.76 13.99,170.86 13.21,170.86 v3(12.92,170.57)
  L4 w0.127: v3(12.92,170.57) 13.19,170.85 13.44,170.85 13.81,170.48 13.81,167.76 12.48,166.43 12.48,153.76 14.4,151.83 14.4,147.59 15.51,146.48 15.51,140.7 22.32,133.89 28.23,133.89 29.89,132.23 29.89,103.67 30.77,102.8 30.77,98.1 30.46,97.79 v3(30.23,97.79)
  BOTTOM w0.102: C303.1 v3(30.23,97.79) ; v2(13.29,169.54) 12.92,169.92 v3(12.92,170.57)
DP0_TXP0: length 164.8
  TOP w0.102: CPU1.E2 70.6,178.6 v4(70.08,179.12)
  L3 w0.127: v4(70.08,179.12) 69.88,179.31 69.88,182.82 64.78,187.92 60.28,187.92 55.49,183.13 55.49,180.66 52.39,177.56 49.72,177.56 48.42,176.26 20.65,176.26 18.09,173.7 15.5,173.7 14.82,173.01 v3(12.92,173.01)
  L4 w0.127: v3(30.23,95.12) 30.31,95.2 30.97,95.2 31.7,95.94 31.7,103.46 30.83,104.33 30.83,132.62 28.62,134.83 22.7,134.83 16.45,141.08 16.45,146.87 15.34,147.98 15.34,152.22 13.41,154.15 13.41,166.04 14.74,167.37 14.74,171.65 13.66,172.74 13.19,172.74 v3(12.92,173.01)
  BOTTOM w0.102: v4(70.08,179.12) 70.08,179.67 70.26,179.86 v2(70.34,179.86) ; C300.1 v3(30.23,95.12)
DP0_TXP1: length 163.6
  TOP w0.102: CPU1.E3 v4(72.1,179)
  L3 w0.127: v4(72.1,179) 72.1,179 72.1,178.58 72.01,178.49 69.19,178.49 68.74,178.94 68.74,183.02 64.51,187.25 60.55,187.25 56.15,182.85 56.15,180.38 52.66,176.89 50,176.89 48.7,175.59 20.93,175.59 18.37,173.03 15.78,173.03 13.88,171.13 13.18,171.13 v3(12.92,171.39)
  L4 w0.127: v3(30.23,96.9) 31.03,97.7 31.03,102.91 30.16,103.78 30.16,132.34 28.34,134.16 22.43,134.16 15.78,140.81 15.78,146.59 14.67,147.7 14.67,151.94 12.74,153.87 12.74,166.32 14.07,167.65 14.07,170.59 13.55,171.11 13.19,171.11 v3(12.92,171.39)
  BOTTOM w0.102: C302.1 30.83,97.16 30.49,97.16 v3(30.23,96.9) ; v3(12.92,171.39) 13.58,171.39 v2(13.8,171.6)
DP_2K_ZVSS: length 7
  TOP w0.102: R1603.1 72.04,185.99 v1(72.04,185.09) 72.37,184.76 72.99,184.76 73.18,184.57 73.93,184.57 CPU1.A9
DP_150_ZVSS: length 11
  TOP w0.102: v1(68.99,186.12) R107.1 69.88,185.86 69.88,184.51 70.04,184.35 72.82,184.35 73.01,184.16 73.57,184.16 76.6,181.13 CPU1.B9
DP_AUXN: length 3.5
  TOP w0.102: TP73.1 121.32,209.13 120.66,209.78 119.67,209.78 119.38,209.5 NGFF1.20
DP_AUXP: length 4.6
  TOP w0.102: NGFF1.22 120.75,210 121.1,209.65 121.85,209.65 TP72.1
DP_HPD: length 6.9
  TOP w0.102: TP78.1 106.46,211.71 108.24,211.71 108.78,212.25 NGFF1.31
DP_ML0N: length 3.7
  TOP w0.102: TP69.1 121.32,211.67 120.2,212.78 119.73,212.78 119.45,212.5 NGFF1.32
DP_ML0P: length 4.8
  TOP w0.102: TP68.1 121.85,212.19 121.1,212.19 120.29,213 NGFF1.34
DP_ML1N: length 3.6
  TOP w0.102: TP71.1 121.32,210.4 120.43,211.28 119.72,211.28 119.44,211 NGFF1.26
DP_ML1P: length 4.7
  TOP w0.102: TP70.1 121.85,210.92 121.1,210.92 120.52,211.5 NGFF1.28
DP_ML2N: length 5.2
  TOP w0.102: NGFF1.25 109.5,210.75 109.36,210.89 106.96,210.89 106.69,210.63 106.69,210.08 106.84,209.93 TP76.1
DP_ML2P: length 5.6
  TOP w0.102: NGFF1.27 109.5,211.25 109.36,211.11 106.87,211.11 106.48,210.72 106.48,210.06 106.35,209.93 TP77.1
DP_ML3N: length 6.5
  TOP w0.102: TP74.1 105.57,208.03 105.42,208.17 105.42,208.43 105.8,208.81 108.04,208.81 108.62,209.39 109.36,209.39 109.5,209.25 NGFF1.19
DP_ML3P: length 6.8
  TOP w0.102: NGFF1.21 109.5,209.75 109.36,209.61 108.53,209.61 107.95,209.03 105.71,209.03 105.21,208.52 105.21,208.15 105.08,208.03 TP75.1
DP_STEREOSYNC: length 30.8
  TOP w0.102: v4(77.49,178.99) 77.91,178.99 CPU1.E11 ; R1618.1 R1619.1 v1(74.43,197.55) 72.49,197.55 v3(71.28,198.75)
  L4 w0.127: v3(71.28,198.75) 70.63,198.11 70.63,190.38 72.45,188.57 72.45,187.08 72.66,186.87 73.67,185.86 73.67,185.43 74.9,184.2 74.9,183.32 76.78,181.44 76.78,179.7 v4(77.49,178.99)
DP_STEREOSYNC_PU: length 3.5
  TOP w0.102: R1618.2 R2026.2 R2023.2 79.92,199.9 v1(79.94,199.92)
DPLL_PVDD: length 6.5
  TOP w0.356: GPU1.AF14 90.86,97.94 v4(90.86,97.64)
  BOTTOM w0.508: v2(93.4,95.37) 93,94.98 L52.2 C830.1 90.42,95.29 C827.1 90.52,96.09 C829.1 90.52,97.1 90.84,97.41 90.84,97.62 v4(90.86,97.64)
DPLL_VDDC: length 7.5
  TOP w0.356: GPU1.AD14 89,98.06 v4(89.38,97.68)
  BOTTOM w0.508: L53.2 89.46,91.42 v2(89.46,92.18) C828.1 89.39,95.05 C825.1 C826.1 89.39,97.67 v4(89.38,97.68)
DPLVDS_AUXN: length 3.3
  BOTTOM w0.102: U26.3 34.32,93.1 34.23,93.19 34.08,93.19 33.49,92.6 32.7,92.6 32.63,92.54 32.31,92.54 C305.2
DPLVDS_AUXP: length 3.6
  BOTTOM w0.102: 33,92.82 32.61,92.82 32.55,92.75 32.31,92.75 C304.2 ; 33,92.82 33.41,92.82 33.99,93.41 34.23,93.41 34.33,93.5 U26.4 ; 33,92.82 v2(33,93.17)
DPLVDS_BL_EN: length 196
  TOP w0.102: v3(148.62,66.04) 148.88,65.79 R79686.1 ; R1985.2 v3(43.59,24.54)
  L3 w0.127: v3(70.14,65.41) 73.95,61.59 94.89,61.59 96.35,60.13 106.72,60.13 106.72,60.13 107.82,60.13 108.52,59.44 108.69,59.27 110.96,59.27 112.73,61.04 129.09,61.04 129.8,61.75 130.53,61.75 130.8,61.47 135.03,61.47 135.98,62.42 138.54,62.42 140.33,64.2 142.52,64.2 145.02,66.7 147.97,66.7 v3(148.62,66.04) ; v3(35.91,88.91) 35.5,88.5 35.5,77.56 35.59,77.48 35.59,76.23 37.46,74.36 37.46,73.04 39.41,71.09 39.66,71.09 v3(41.79,68.96)
  L4 w0.127: v3(43.59,24.54) 42.4,25.73 42.4,30.29 41.92,30.77 41.92,31.28 41.28,31.92 41.28,34.33 40.52,35.09 40.52,37.65 40.77,37.9 40.77,40.92 40.52,41.16 40.52,51.09 41.56,52.13 41.56,54.08 40.85,54.79 39.06,54.79 35.97,57.87 35.97,62.62 36.26,62.9 36.65,62.9 36.93,63.18 36.93,63.77 41.79,68.63 v3(41.79,68.96)
  BOTTOM w0.102: U26.44 37.18,90.89 37.09,90.8 37.09,90.63 36.89,90.43 36.89,89.18 36.62,88.91 v3(35.91,88.91) ; v3(70.14,65.41) 69.64,65.41 65.4,69.65 43.62,69.65 v2(43.39,69.42) 43.37,69.44 42.27,69.44 v3(41.79,68.96)
DPLVDS_EDIDCLK: length 10.5
  TOP w0.102: v3(35.97,87.93) 35.46,88.45 35.46,89.83 v3(35.82,90.2)
  BOTTOM w0.102: v3(35.97,87.93) 35.97,87.86 36.9,86.93 R35.2 C1827.1 39,87.86 v2(38.84,88.01) 39.18,88.01 39.94,87.25 R32.2 ; U26.46 36.38,90.93 35.82,90.37 v3(35.82,90.2)
DPLVDS_EDIDCLK_C: length 3
  BOTTOM w0.102: U25.6 37.37,84.89 38.06,85.57 v2(38.06,86.11) 38.03,86.13 37.21,86.13 R35.1
DPLVDS_EDIDSDA: length 7.8
  BOTTOM w0.102: C7.1 R46.2 R1858.2 35.83,87.2 35.59,87.2 35.46,87.34 35.46,89.1 35.94,89.59 v2(36.38,89.59) 36.38,90.43 36.73,90.78 36.73,90.95 36.78,91 U26.45
DPLVDS_EDIDSDA_C: length 3.2
  BOTTOM w0.102: v2(34.7,84.1) 35.87,84.1 U25.5 R1858.1
DPLVDS_FWCLK: length 9.1
  BOTTOM w0.102: U26.48 35.22,91.5 35.01,91.29 35.01,89.89 34.72,89.6 34.72,88.24 34.34,87.86 33.62,87.86 33,87.24 v2(33,86.23) 32.1,86.23 C9.1 R47.2
DPLVDS_FWSDA: length 11
  BOTTOM w0.102: U26.47 35.98,91.04 35.36,90.42 35.36,89.74 35.1,89.48 35.1,88.12 34.48,87.5 33.83,87.5 33.51,87.19 33.51,85.97 33.02,85.48 33.02,84.22 v2(32.9,84.1) 32.88,84.07 R58.2 C11.1
DPLVDS_HPD: length 4.8
  BOTTOM w0.102: R510.1 32.09,89.15 32.52,89.59 32.52,90.27 v2(32.96,90.71) 33.05,90.81 33.75,90.81 34.02,91.07 34.02,91.4 34.25,91.62 34.25,91.77 U26.1
DPLVDS_ISPCLK: length 52.5
  TOP w0.102: v3(33.65,98.05) 34.22,97.47 34.22,93.64 33.58,92.99 33.04,92.99 31.76,91.71 31.76,88.29 35.01,85.04 35.01,82.01 34.12,81.12 34.12,79.5 v3(34.88,78.74) 34.77,78.74 34.09,78.06 34.09,76 v1(34.25,75.84) 34.48,75.62 50.91,75.62 52.29,74.23 R69.2 52.29,72.54 Q95.4
  BOTTOM w0.102: U26.13 34.2,97.5 33.78,97.92 33.78,97.92 v3(33.65,98.05) ; v3(34.88,78.74) 34.58,78.74 34.04,78.21 34.04,77.75 33.51,77.22 Q7.1
DPLVDS_ISPDAT: length 59.9
  TOP w0.102: Q95.1 54.99,70.98 55.51,70.46 v1(56.3,70.46) 56.8,70.96 R54.2 57.36,72.25 57.36,73.53 56.29,74.6 53.51,74.6 51.34,76.77 35.62,76.77 35.34,77.05 35.34,79.12 v3(34.93,79.53) 34.48,79.98 34.48,80.98 35.36,81.86 35.36,85.19 32.11,88.44 32.11,91.56 33.18,92.63 33.76,92.63 34.58,93.45 34.58,97.82 v3(34.41,98)
  BOTTOM w0.102: U26.14 35.98,98.04 35.83,98.19 34.59,98.19 v3(34.41,98) ; Q4.1 36.43,76.94 35.49,77.88 35.49,78.97 v3(34.93,79.53)
DPLVDS_PANEL_VCC: length 20.1
  L3 w0.127: v3(35.16,113.84) 34.39,113.06 34.39,108.93 36.66,106.66 36.66,101.17 v3(37.68,100.15)
  BOTTOM w0.102: v2(35.69,113.21) 35.16,113.74 v3(35.16,113.84) 35.28,113.95 R39.2 ; U26.20 38.38,99.45 v3(37.68,100.15)
DPLVDS_PIN12: length 4
  BOTTOM w0.203: v2(32.88,98.63) 32.88,98.15 33.14,97.88 33.14,97.84 33.47,97.51 33.61,97.51 33.94,97.18 33.94,97.17 34.41,96.7 U26.12
  BOTTOM w0.508: v2(32.88,98.63) 32.77,98.73 R511.1
DPLVDS_PIN16: length 6.2
  BOTTOM w0.203: U26.16 36.78,98.13 35.59,99.31 v2(34.88,99.31) 34.07,99.31 33.99,99.24 33.96,99.24 33.88,99.16 33.36,99.16 32.77,99.75 R507.2
DPLVDS_PWMIN: length 12.6
  TOP w0.165: v3(38.76,100.78) 38.76,100.8 35.59,103.96 v3(35.11,103.96)
  BOTTOM w0.165: v3(35.11,103.96) 35.11,104.91 R503.2 35.34,104.97 R501.1 36.36,105.85 36.64,105.57 36.64,105.39 37.06,104.97 R502.1 ; v3(38.76,100.78) 39.12,100.42 39.12,99.56 v2(39.07,99.52) 39.07,98.89 38.71,98.53 38.71,98.07 38.78,98.01 U26.21
DPLVDS_PWMOUT: length 147.3
  TOP w0.165: R1984.2 47.45,34.2 47.45,36.2 v3(47.58,36.32)
  L3 w0.165: v3(37.68,99.39) 38.95,98.11 38.95,79.86 44.41,74.4 61.49,74.4 62.41,75.33 70.26,75.33 71.64,76.71 72.44,76.71 74.46,74.7 83.94,74.7 84.02,74.78 v3(84.03,74.78)
  L4 w0.165: v3(84.03,74.78) 84.02,74.78 80.61,71.36 80.61,67.87 78.9,66.17 78.9,63.8 77.98,62.88 77.98,54.95 76.62,53.59 76.62,48.88 v3(76.68,48.83)
  BOTTOM w0.165: v3(37.68,99.39) 38.12,98.95 38.12,98.39 37.98,98.25 U26.19 ; v3(76.68,48.83) 76.68,48.5 74.25,46.08 v2(73.24,46.08) 71.53,44.37 65.86,44.37 64.3,42.8 64.3,33.33 63.89,32.92 60.96,32.92 60.64,33.24 55.25,33.24 54.93,32.92 50.19,32.92 47.58,35.53 v3(47.58,36.32)
DQMA0: length 39.2
  TOP w0.127: GPU1.E32 73.47,111.13 73.47,111.28 72.43,112.32 v4(72.34,112.32) 71.36,113.31 v1(71.36,114.07)
  L3 w0.165: v4(54.9,115.49) 55.13,115.25 55.13,115.19 55.35,114.97 55.35,114.67 55.22,114.54 55.22,114.54 54.91,114.23 54.39,114.23 54.18,114.43 54.18,115.47 54.06,115.6 53.09,115.6 52.96,115.47 52.96,114.64 52.84,114.51 52.53,114.51 52.41,114.39 52.41,113.06 52.53,112.93 52.89,112.93 53.02,113.06 53.02,113.82 53.14,113.95 53.8,113.95 54.11,113.64 54.84,113.64 55.09,113.4 55.09,113.3 55.34,113.04 55.37,113.04 55.39,113.02 56,113.02 57.39,111.63 57.7,111.63 58.15,111.17 58.78,111.17 59.07,111.46 59.67,111.46 59.97,111.16 60.55,111.16 60.79,111.4 62.07,111.4 62.62,110.85 68.92,110.85 69.25,111.18 69.5,111.18 70.13,111.82 70.57,111.82 70.95,111.43 70.95,111.18 71.07,111.05 71.81,111.05 71.94,111.18 71.94,111.91 v4(72.34,112.32)
  BOTTOM w0.127: v4(54.9,115.49) 54.73,115.49 54.34,115.09 54.34,114.8 MEM3.E7 ; v2(71.25,112.77) 71.7,112.32 v4(72.34,112.32)
DQMA1: length 35.6
  TOP w0.127: GPU1.E30 73.43,109.63 71.79,109.63 v4(71.71,109.55)
  BOTTOM w0.127: v4(71.71,109.55) 70.31,109.55 70,109.87 70,110.11 69.73,110.37 67.39,110.37 v2(66.03,111.73) 64.67,113.09 64.67,115.93 60.67,119.93 55.03,119.93 54.26,119.16 54.26,118.47 54.44,118.28 54.44,117.59 54.16,117.32 53.76,117.32 53.61,117.16 53.61,115.89 53.79,115.71 54.38,115.71 55.05,116.39 55.05,116.78 55.31,117.03 56.02,117.03 56.86,116.18 56.86,115.92 57.21,115.57 MEM3.D3
DQMA2: length 36.1
  TOP w0.102: 57.59,115.17 57.37,114.95 57.08,114.95 56.72,115.31 56.72,115.68 56.39,116.01
  TOP w0.127: GPU1.A21 72.17,103.57 62.48,103.57 v1(62.32,103.73) 62.32,113.51 62.82,114.01 62.82,115.01 62.49,115.34 62.14,115.34 62.02,115.22 62.02,114.36 61.89,114.23 61.64,114.23 61.51,114.36 61.51,115.22 61.38,115.34 61.13,115.34 61,115.22 61,114.84 60.87,114.71 60.62,114.71 60.49,114.84 60.49,115.22 60.37,115.34 59.24,115.34 58.96,115.62 57.87,115.62 57.59,115.34 57.59,115.17 ; MEM1.D3 54.01,115.52 54.49,116 54.49,116.31 55.2,117.01 55.66,117.01 56.21,116.47 56.21,116.19 56.39,116.01
DQMA3: length 34.5
  TOP w0.127: GPU1.C21 72.58,103.18 71.28,103.18 71.11,103.34 70.4,103.34 v4(69.98,102.93) ; v4(56.13,115.62) 56.13,115.59 57.21,114.5 MEM1.E7
  L4 w0.165: v4(69.98,102.93) 69.98,103.36 69.82,103.53 69.61,103.53 69.45,103.69 69.45,104.02 69.61,104.19 70.45,104.19 70.62,104.35 70.62,104.72 70.45,104.88 69.56,104.88 69.4,105.05 69.4,105.47 69.53,105.59 69.88,105.59 69.98,105.69 69.98,106.1 69.4,106.68 69.24,106.68 67.72,108.2 67.72,109.97 67.56,110.14 67.27,110.14 67.03,109.89 66.85,109.89 66.56,110.18 66.56,110.36 67.13,110.93 67.13,111.16 66.9,111.4 66.66,111.4 66.12,110.85 65.94,110.85 65.62,111.17 65.62,111.35 66.01,111.74 66.01,112.34 62.02,116.33 61.45,116.33 61.06,116.72 60.43,116.72 60.04,116.33 59.44,116.33 59.1,116.67 58.55,116.67 58.21,116.33 56.38,116.33 56.13,116.07 v4(56.13,115.62)
DQMA4: length 35.5
  TOP w0.102: v4(70.67,96.7) 70.84,96.87 71.14,96.87 71.28,97.01 71.88,97.01 72.11,96.87 72.27,96.87 72.42,96.93 72.78,96.93 72.93,96.87 73.2,96.87 73.53,97.2 GPU1.E13
  L4 w0.165: v4(70.67,96.7) 69.98,96.7 69.69,96.99 67.17,96.99 66.58,96.4 66.58,89.84 62.19,85.45 58.96,85.45 58.76,85.65 58.76,86.35 58.63,86.48 58.21,86.48 58.08,86.35 58.08,85.67 57.86,85.45 56.77,85.45 56.35,85.87 56.35,86.46 v4(55.52,87.29)
  BOTTOM w0.127: v4(70.67,96.7) 70.9,96.48 v2(70.9,95.99) ; MEM4.E7 56.99,88.82 56.81,88.64 56.81,87.6 56.68,87.47 56.38,87.47 56.25,87.6 56.25,87.77 56.06,87.96 55.58,87.96 55.45,88.09 55.27,88.09 55.05,87.86 55.05,87.68 55.44,87.29 v4(55.52,87.29)
DQMA5: length 36.8
  TOP w0.102: 71.09,96.53 71.37,96.81 71.82,96.81 72.05,96.67 72.31,96.67 72.33,96.68 72.53,96.72 72.57,96.73 72.72,96.73 72.9,96.6 73.1,96.4 GPU1.D12
  TOP w0.127: 71.09,96.53 71.09,96.53 70.83,96.27 69.8,96.27 68.89,95.36 66.27,95.36 65.69,95.93 65.69,97.93 64.9,98.72 64.33,98.72 64.2,98.59 64.2,97.76 64.08,97.63 63.82,97.63 63.7,97.76 63.7,98.59 63.57,98.72 63.31,98.72 63.19,98.59 63.19,97.76 63.06,97.63 62.81,97.63 62.68,97.76 62.68,98.59 62.55,98.72 62.3,98.72 62.17,98.59 62.17,97.76 62.04,97.63 61.79,97.63 61.66,97.76 61.66,98.59 61.54,98.72 v1(61.19,98.72) 60.52,98.72 59.28,97.48 59.28,96.64 59.97,95.95 59.97,95.31 60.25,95.03 60.25,91.48 60.73,91 60.73,89.45 60.3,89.02 59.99,89.02 59.22,88.24 59.22,87.94 58.96,87.68 57.56,87.68 MEM2.D3
DQMA6: length 29.7
  TOP w0.127: GPU1.E3 73.8,89.99 v4(73.41,89.6) ; v4(56.31,88.4) 56.32,88.41 56.69,88.41 56.85,88.25 56.85,88.1 56.59,87.84 56.06,87.84 55.88,88.02 55.22,88.02 54.64,87.44 54.48,87.44 54.28,87.64 54.28,87.77 54.58,88.06 54.58,88.23 54.47,88.33 54.47,88.57 54.23,88.82 MEM2.E7
  L3 w0.165: v4(73.41,89.6) 72.94,89.13 72.12,89.13 72.11,89.13 69.61,89.13 69.45,88.96 69.45,88.55 69.28,88.38 68.95,88.38 68.79,88.55 68.79,88.96 68.62,89.13 68.23,89.13 68.06,88.96 68.06,87.84 67,86.77 66.38,86.77 66.21,86.61 66.21,86.42 66.05,86.25 65.72,86.25 65.55,86.42 65.55,86.61 65.39,86.77 65.05,86.77 64.89,86.61 64.89,86.42 64.72,86.25 64.39,86.25 64.23,86.42 64.23,86.61 64.06,86.77 63.73,86.77 63.57,86.61 63.57,86.42 63.4,86.25 63.07,86.25 62.91,86.42 62.91,86.61 62.74,86.77 62.36,86.77 62.13,86.54 62.13,86.37 61.97,86.2 60.05,86.2 59.99,86.14 59.62,86.14 59.37,86.4 59.37,86.67 58.54,87.5 56.92,87.5 56.31,88.12 v4(56.31,88.4)
DQMA7: length 31.9
  TOP w0.127: v4(74.55,88.88) 74.23,89.21 74.23,90.08 74.54,90.4 GPU1.F4
  BOTTOM w0.127: MEM4.D3 54.26,87.77 54.26,87.48 55.08,86.66 55.08,86.01 56.89,84.21 59.75,84.21 60.25,83.7 62.25,83.7 v2(62.49,83.94) 62.69,84.14 66.1,84.14 68.05,86.09 74.51,86.09 76.32,87.9 76.32,88.15 76.69,88.52 76.69,88.94 76.32,89.3 74.98,89.3 v4(74.55,88.88)
DRAM_RST: length 11.2
  TOP w0.102: GPU1.L10 79.07,95.07 v4(79.53,95.07)
  BOTTOM w0.102: v4(79.53,95.07) 79.53,94.12 80.04,93.6 80.04,93.15 81.54,91.65 83.71,91.65 C839.1 83.94,91.54 84.69,91.54 v2(84.87,91.37) 84.87,90.7 84.51,90.34 R1202.1 R1205.1
DRAM_RST_R: length 4.9
  BOTTOM w0.102: R1202.2 84.47,89.79 85.36,89.79 v2(85.54,89.61) 85.54,89.04 85.36,88.85 84.56,88.85 R1891.1 C762.1
DRX0N: length 3.3
  BOTTOM w0.102: U26.8 34.3,95.1 34.21,95.01 34.08,95.01 33.91,95.18 33.56,95.18 33.06,95.68 32.31,95.68 C301.2
DRX0P: length 3.6
  BOTTOM w0.102: U26.7 34.31,94.7 34.22,94.79 33.99,94.79 33.82,94.96 33.47,94.96 33.2,95.23 ; C300.2 32.31,95.46 32.97,95.46 33.2,95.23 ; v2(32.98,95) 33.2,95.23
DRX1N: length 4.4
  BOTTOM w0.102: v2(33.38,96.95) 33.04,96.95 ; 33.04,96.95 33.04,97.09 32.67,97.46 32.3,97.46 C303.2 ; 33.04,96.95 33.04,96.35 33.58,95.81 34.22,95.81 34.31,95.9 U26.10
DRX1P: length 4.1
  BOTTOM w0.102: U26.9 34.33,95.5 34.23,95.59 33.49,95.59 32.82,96.26 32.82,97 32.58,97.24 32.34,97.24 32.21,97.11 32.18,97.11 C302.2
EAPD_DEPOP: length 81.2
  TOP w0.203: v3(158.22,79.86) 158.4,80.03 U6.14 ; R635.1 137.07,32.29 136.39,32.29 136.37,32.31 135.72,32.31 135.56,32.47 v3(135.55,32.47)
  L4 w0.203: v3(138.46,73.1) 136.79,71.42 136.79,70.13 135.54,68.89 135.54,68.42 133.1,65.98 133.1,64.39 133.89,63.6 133.89,61.39 132.31,59.82 132.31,54.38 133.36,53.34 133.36,49.64 134.02,48.98 134.02,47.24 133.36,46.58 133.36,44.09 136.29,41.16 136.29,39.92 134.67,38.29 134.67,32.82 134.9,32.59 135.43,32.59 v3(135.55,32.47)
  BOTTOM w0.203: v3(138.46,73.1) 138.51,73.15 145.63,73.15 146.06,72.72 146.06,69.62 146.74,68.94 147.45,68.94 148.45,69.93 v2(148.45,71.25) 148.45,72.38 156.34,80.27 157.81,80.27 v3(158.22,79.86)
EAPD_DEPOP_1: length 3.9
  TOP w0.102: v1(136.88,31.56) 136.88,31.1 137.51,30.47 R634.1 R636.1 138.97,31.28 R635.2
EAPD_DEPOP_2: length 4.1
  TOP w0.254: v1(138.74,27.78) 138.72,27.8 138.72,29.32 R636.2 139.09,29.58 140.19,30.68 Q63.2
EC_3P3_CTL: length 4.1
  BOTTOM w0.102: PR8521.2 Q9648.G 83.82,56.55 v2(83.73,56.64) 83.6,56.77 C6724.2
EC_3P3_CTL_2: length 4.4
  BOTTOM w0.102: C6725.1 88.43,54.29 R80229.2 86.58,54.29 v2(86.01,53.72) 86.93,52.81 Q9649.G
EC_3P3_CTL_3: length 4.4
  BOTTOM w0.102: Q9648.D 87.35,57.53 v2(88.3,56.58) 88.49,56.39 R80228.1 88.43,55.18 R80229.1
EC_A20GATE: length 4.3
  TOP w0.102: R80231.1 155.23,63.5 v1(154.21,62.48) 152.85,61.13 U109.43
EC_EUP: length 6.2
  TOP w0.102: U109.127 156.46,44.05 156.62,43.89 157.94,43.89 158.46,43.38 v1(158.46,42.83) 159.16,42.13 R675.1 R674.1
EC_EUP_EN: length 13.9
  TOP w0.102: C542.1 162.53,42.48 163.04,41.97 Q1227.G 163.83,40.86 v3(163.74,40.77) ; v1(156.12,39.62) 156.93,39.62 v3(157.06,39.75) 157.21,39.75 157.27,39.69 R1199.2 158.15,39.81 R674.2
  L3 w0.127: v3(157.06,39.75) 157.67,39.75 157.73,39.69 159.86,39.69 160.33,40.16 163.13,40.16 v3(163.74,40.77)
EC_HDMI_PD_N: length 46.1
  TOP w0.102: v3(147.36,47.04) 147.36,46.99 147.78,46.56 147.78,46.09 147.66,45.96 U109.105 ; R2091.2 Q1249.G 126.65,27.15 126.65,26.8 v1(127.03,26.42) 127.95,25.5 128.96,25.5 129.63,24.83 134.08,24.83 136.05,26.8 139.8,26.8 140.11,27.11 v3(140.11,28.57)
  L4 w0.127: v3(140.11,28.57) 140.11,29.72 144.18,33.78 146.26,33.78 147.37,34.9 147.37,41.7 148.62,42.95 148.62,45.78 v3(147.36,47.04)
EC_IMS: length 29.2
  TOP w0.102: U109.52 149.26,59.41 149.13,59.28 149.13,56.5 151.99,53.64 154.41,53.64 154.72,53.95 155.52,53.95 155.79,53.68 155.79,51.91 155.26,51.38 153.89,51.38 153.44,50.93 153.44,47.49 v3(152.51,46.56) ; R79691.2 154.08,41.66 153.7,42.04 153.64,42.04 153.21,42.47 v1(152.28,42.47) 151.68,42.47 151.62,42.53 151.39,42.53 v4(150.96,42.95)
  L4 w0.127: v3(152.51,46.56) 152.51,45.54 150.96,43.99 v4(150.96,42.95)
EC_LAN_DISABLE_N: length 165.1
  TOP w0.102: R1840.1 145.58,63.05 145.92,63.05 v1(146.18,62.79) 146.34,62.63 146.34,62.29 146.86,61.78 U109.58 146.86,59.04 v3(146.87,59.03) ; v3(42.2,11.3) 41.64,10.74 41.64,8.59 41.37,8.32 R1194.1
  L3 w0.127: v3(42.2,11.3) 45.78,14.88 45.78,16.61 47.02,17.86 50.55,17.86 51.48,18.78 55.72,18.78 58.25,21.31 60.82,21.31 66.15,26.65 66.38,26.65 66.65,26.92 66.69,26.92 68.36,28.6 91.37,28.6 v3(92.11,29.34) ; v3(88.81,58.6) 88.88,58.6 90.08,57.4 91.82,57.4 92.55,56.68 93.73,56.68 94.13,57.09 104.39,57.09 107.34,54.14 109.34,54.14 110.49,55.28 111.28,55.28 113.58,57.58 115.86,57.58 116.25,57.19 117.17,57.19 117.56,57.58 121.37,57.58 121.77,57.98 130.59,57.98 131.84,56.73 134.54,56.73 135.54,55.73 136.22,55.73 136.95,56.45 138.05,56.45 139.12,57.53 144.2,57.53 144.72,58.05 144.72,59.22 145.19,59.69 146.28,59.69 146.87,59.1 v3(146.87,59.03)
  L4 w0.127: v3(92.11,29.34) 92.11,35.52 90.78,36.85 90.78,37.21 90.45,37.54 90.45,48.52 89.22,49.75 88.26,50.7 88.26,58.06 v3(88.81,58.6)
EC_PSID: length 17.8
  TOP w0.102: v3(105.27,44.96) 106.59,43.64 R80213.2
  L4 w0.127: v3(102.17,52.58) 101.98,52.39 101.98,51.78 101.93,51.73 101.93,50.77 105.19,47.51 105.19,45.03 v3(105.27,44.96)
  BOTTOM w0.102: U4101.12 100.87,51.12 101.06,51.32 101.06,51.64 100.79,51.91 100.79,52.28 101.06,52.55 102.14,52.55 v3(102.17,52.58) ; v3(105.27,44.96) 105.27,45.03 v2(105.95,45.72)
EC_PWREN: length 81
  TOP w0.102: R702.2 146.27,63.82 146.74,63.35 146.74,62.23 147.26,61.72 U109.57 147.26,59.29 147.38,59.17 147.38,57.85 147.11,57.58 146.42,57.58 v3(145.96,58.04)
  L3 w0.127: v3(93.54,53.2) 94.53,53.2 95.52,52.22 97.81,52.22 99.17,50.85 105.13,50.85 105.93,51.65 110.21,51.65 110.81,52.25 110.83,52.25 113.52,54.94 122.46,54.94 123.3,55.78 123.3,56.29 123.43,56.41 123.43,56.45 124.07,57.09 127.9,57.09 128.74,56.25 129.19,56.25 129.35,56.41 134.45,56.41 135.51,55.35 136.46,55.35 137.11,56 137.42,56 137.61,56.2 138.15,56.2 138.41,56.45 140.86,56.45 141.46,57.06 145.12,57.06 145.96,57.91 v3(145.96,58.04)
  BOTTOM w0.102: R1834.1 147.14,57 v2(146.27,57) 145.96,57.31 v3(145.96,58.04) ; v3(93.54,53.2) 91.59,53.2 90.33,51.94 86.14,51.94 85.25,52.83 85.25,54.42 PR8521.1
EC_SCI: length 6.5
  BOTTOM w0.102: U4101.15 99.67,49.53 99.44,49.3 97.19,49.3 96.45,50.04 v2(95.66,50.04) R79709.1
EC_SMB2_CLK: length 69.8
  L4 w0.127: v3(97.6,67.67) 96.46,66.54 96.46,61.99 99.3,59.15 99.3,56.26 v3(99.32,56.24)
  BOTTOM w0.102: v3(99.32,56.24) 99.31,56.25 99.31,56.91 98.74,57.48 U4101.32 98.03,58.09 97.04,59.08 95.88,59.08 PR8519.2 ; R80220.1 140.01,65.11 140.01,66.98 137.75,69.24 134.25,69.24 133.28,70.21 130.83,70.21 130.67,70.05 130.42,70.05 129.6,69.24 129.6,68.19 127.68,66.27 116.09,66.27 113.58,63.76 107.44,63.76 v2(105.91,65.29) 105.67,65.53 100.47,65.53 98.33,67.67 v3(97.6,67.67)
EC_SMB2_DATA: length 71.4
  L4 w0.127: v3(97.99,68.33) 98.08,68.24 98.08,67.49 96.85,66.26 96.85,62.15 99.68,59.31 99.68,56.94 99.98,56.64 v3(99.98,56.62)
  BOTTOM w0.102: v3(99.98,56.62) 99.98,56.64 99.67,56.96 99.67,57.06 99.27,57.46 U4101.33 97.9,58.72 97.19,59.44 95.98,59.44 PR8520.2 ; R80219.1 140.37,65.21 140.37,67.13 137.9,69.6 134.39,69.6 133.43,70.56 130.68,70.56 130.53,70.41 130.27,70.41 129.24,69.38 129.24,68.34 127.53,66.62 115.94,66.62 113.43,64.12 108.22,64.12 v2(107.52,64.81) 106.45,65.89 100.62,65.89 98.18,68.33 v3(97.99,68.33)
EC_VCORF: length 3.9
  BOTTOM w0.102: C4101.2 v2(95.66,51.75) 95.85,51.75 96.79,52.68 U4101.20
ECIO_APU_PROCHOT#: length 3.4
  TOP w0.102: v3(157.01,49.28) 157.1,49.18 U109.8
  BOTTOM w0.102: v2(158.02,48.39) 158.02,49.21 R80226.2 157.83,49.28 v3(157.01,49.28)
ECIO_IO_SMI_N: length 5
  TOP w0.102: R80223.2 161.58,46.48 160.69,47.37 v1(160.69,47.79) 160.69,48.26 159.82,49.12 159.59,49.12 159.14,49.58 U109.9
ECIO_LPC_PME_N: length 7.5
  TOP w0.102: U109.70 144.33,56.78 144.92,57.36 v3(144.92,57.55)
  BOTTOM w0.102: v3(144.92,57.55) 144.69,57.79 144.69,59.19 145.19,59.69 145.7,59.69 v2(146.21,60.2) 146.4,60.39 R80224.1
EGPIO67: length 4.2
  TOP w0.102: CPU1.AT17 83.04,153.7 v4(83.42,153.31)
  BOTTOM w0.102: R79653.1 85.39,152.65 83.85,152.65 83.42,153.09 v4(83.42,153.31) 83.14,153.31 v2(82.76,153.7)
EGPIO70: length 6.4
  TOP w0.102: v4(80,153.28) 79.58,153.7 CPU1.AT12
  BOTTOM w0.102: v4(80,153.28) 80.41,152.87 80.41,150.45 80.58,150.28 80.58,149.69 R79654.1 80.11,148.4 v2(79.92,148.21)
EGPIO119: length 1.6
  TOP w0.102: v4(74.02,151.05) 74.35,151.05 CPU1.AW7
  BOTTOM w0.102: v4(74.02,151.05) 74.02,150.95 TP8.1
EGPIO131: length 15.5
  TOP w0.102: R79670.1 85.94,136.28 v1(85.94,137.46) 85.94,137.82 86.29,138.18 v3(86.61,138.18) ; CPU1.BB18 83.8,148.95 84.1,148.64 84.1,148.36 84.09,148.35 84.09,147.89 84.74,147.25 84.74,146.08 85.4,145.41 v4(85.55,145.41)
  L3 w0.127: v4(85.55,145.41) 85.55,144.88 85.19,144.52 85.19,144.13 84.79,143.73 84.79,141.06 86.27,139.58 86.27,138.52 v3(86.61,138.18)
EGPIO132: length 15.4
  TOP w0.102: R79635.1 85,136.73 84.74,136.98 v3(84.74,137.01) ; v4(82.31,147.19) 81.91,147.6 81.91,148.31 81.9,148.32 81.9,149 CPU1.BB16
  L3 w0.127: v4(82.31,147.19) 83.09,146.42 83.09,144.97 83.02,144.9 83.02,138.73 v3(84.74,137.01)
  BOTTOM w0.102: v2(83.09,147.45) 82.83,147.19 v4(82.31,147.19)
EGPIO145: length 7.7
  TOP w0.102: CPU1.BB10 77.1,149 77.1,148.37 77.12,148.35 77.12,145.4 76.87,145.15 v1(76.87,145.08) 76.8,145.08 76.23,144.51 76.23,143.57 R79652.1
EQ: length 5.6
  TOP w0.102: U118.17 132.14,39.88 v3(131.72,40.29) R1593.2
  BOTTOM w0.102: R1593.2 131.04,41.09 130.79,40.84 v2(130.79,40.44) 130.93,40.29 v3(131.72,40.29)
EVAL_PE_L: length 80.3
  TOP w0.102: v4(80.04,154.05) 80.49,154.5 CPU1.AR14 ; D34.1 D34.2 104.65,105.19 104.99,105.53 104.99,107.45 104.65,107.79 104.65,115.28 106.33,116.97 v1(106.33,124.43) v3(106.33,125.48)
  L3 w0.127: v3(106.33,125.48) 105.85,125 89.82,125 84.28,130.54 81.69,130.54 78.67,133.56 78.67,134.63 77.93,135.38 77.93,135.5 74.86,138.57 74.86,143.93 76.87,145.94 76.87,147.41 77.8,148.34 78.03,148.34 79.42,149.73 79.42,153.43 v4(80.04,154.05)
EVAL_PWREN: length 191
  TOP w0.102: CPU1.BC13 79.8,147.95 79.81,147.94 79.81,146.83 80.12,146.52 80.12,144.58 79.74,144.2 79.74,142.24 v3(79.99,141.99)
  L4 w0.127: v3(79.99,141.99) 79.99,137.85 81.31,136.53 86.52,136.53 88.93,138.94 89.92,138.94 90.11,139.13 90.8,139.13 91.28,138.65 91.28,134.3 86.49,129.51 79.03,129.51 77.18,127.67 77.18,118.81 78.24,117.75 96.75,117.75 100.66,121.66 100.94,121.66 100.95,121.67 132.19,121.67 134.93,124.41 144.28,124.41 147.76,127.89 148.5,127.89 148.88,127.51 148.88,123.59 148.64,123.36 148.64,109.65 146.34,107.35 146.34,91.06 v3(147.23,90.17)
  BOTTOM w0.102: v3(147.23,90.17) 147.99,90.17 149.41,91.59 149.87,91.59 v2(149.89,91.57) 149.92,91.59 151.25,91.59 152.49,90.35 165.71,90.35 166.11,89.94 166.53,89.94 167.29,90.7 PR5476.1
EVAL_PWRGD: length 58.9
  TOP w0.102: CPU1.BC17 83,147.96 82.99,147.95 82.99,147.12 v4(83.57,146.53) ; v3(84.82,119.28) 84.82,120.33 v1(84.79,120.35) 84.84,120.42 85.66,120.42 86.13,119.95 R79694.1 86.96,120.52 89.31,120.52 89.62,120.22 Q6705.6
  L4 w0.127: v3(84.82,119.28) 83.67,118.13 78.4,118.13 77.57,118.97 77.57,127.51 79.18,129.13 86.65,129.13 91.66,134.14 91.66,139.7 91.04,140.32 90.7,140.32 86.02,145 85.38,145 84.63,145.75 84.31,145.75 84.22,145.83 84.22,145.87 83.98,146.11 83.94,146.11 83.57,146.48 v4(83.57,146.53)
EVAL_PWRGD_0D95: length 3.6
  TOP w0.102: R79692.2 90.98,120.59 v1(91.7,119.86) 91.7,119.67 C6716.1 90.9,119 Q6705.5
EVAL_PWRGD_1D5: length 4.7
  TOP w0.102: R79693.2 85.48,118.94 v1(84.89,118.35) ; R79693.2 86.46,119 Q6705.2 ; R79693.2 86.98,118.35 Q6705.3
EXT_RST#: length 4.9
  BOTTOM w0.102: R79705.1 103.22,61.66 v2(103.03,61.85) 102.2,61.02 R79706.2 102.2,59.88 102.47,59.62 U4101.41
F_USB0N: length 267
  TOP w0.102: v3(95.24,44.34) 95.08,44.19 95.08,43.13 95.24,42.98 95.24,38.01 C6729.1 95.24,36.79 95.24,35.28 95.45,35.06 TR10.4 ; CPU1.AR1 70.05,154.65 68.49,154.65 67.66,153.82 v4(67.66,153.54)
  L3 w0.102: v3(32.2,48.87) 32.2,42.74 36.96,37.97 44.74,37.97 47.05,40.28 52.62,40.28 55.02,37.88 63.14,37.88 71.68,46.42 84.71,46.42 88.58,42.54 94.46,42.54 94.97,43.05 94.97,44.07 v3(95.24,44.34) ; v3(19.08,150.77) 19.13,150.72 21.8,150.72 25.03,147.5 35.64,147.5 37.26,149.12 48.95,149.12 53.26,153.42 55.74,153.42 56.55,154.23 61.3,154.23 61.8,154.72 65.93,154.72 66.45,154.2 67,154.2 v4(67.66,153.54)
  L4 w0.102: v3(32.2,48.87) 32.68,49.35 32.68,51.85 28.43,56.1 28.43,66.2 35.86,73.63 35.86,84.63 38.24,87.01 38.24,90.88 37.07,92.04 37.07,98.98 37.03,99.02 37.03,113.92 35.6,115.35 35.53,115.42 35.53,119.35 35.35,119.53 35.35,122.6 34.93,123.02 34.93,135.01 31.16,138.79 25.47,138.79 23.83,140.43 23.83,145.48 20.03,149.28 20.03,149.87 19.21,150.7 19.16,150.7 v3(19.08,150.77)
  BOTTOM w0.102: v2(94.9,45.42) 95.24,45.09 v3(95.24,44.34)
F_USB0P: length 267.1
  TOP w0.102: TR10.1 94.77,35.06 94.98,35.28 94.98,36.81 C6728.1 94.98,37.99 94.98,42.87 94.83,43.02 94.83,43.98 v3(94.47,44.34) ; v4(67.03,153.54) 68.39,154.9 70.23,154.9 70.53,154.6 CPU1.AR2
  L3 w0.102: v4(67.03,153.54) 67.03,153.85 66.91,153.97 66.36,153.97 65.84,154.5 61.89,154.5 61.4,154 56.64,154 55.84,153.19 53.35,153.19 49.05,148.89 37.36,148.89 35.74,147.27 24.93,147.27 21.71,150.5 19.57,150.5 v3(19.08,150.01) ; v3(32.21,49.68) 32.67,49.23 32.67,48.56 32.43,48.32 32.43,42.83 37.06,38.2 44.64,38.2 46.95,40.51 52.71,40.51 55.11,38.11 63.05,38.11 71.58,46.65 84.8,46.65 88.68,42.77 94.37,42.77 94.74,43.14 94.74,44.07 v3(94.47,44.34)
  L4 w0.102: v3(19.08,150.01) 19.57,150.01 19.8,149.78 19.8,149.18 23.6,145.39 23.6,140.34 25.38,138.56 31.06,138.56 34.7,134.92 34.7,122.93 35.12,122.51 35.12,119.44 35.3,119.26 35.3,115.32 35.47,115.16 35.5,115.12 36.8,113.82 36.8,98.93 36.84,98.89 36.84,91.95 38.01,90.78 38.01,87.1 35.63,84.72 35.63,73.72 28.2,66.29 28.2,56.01 32.46,51.75 32.46,49.92 v3(32.21,49.68)
  BOTTOM w0.102: v2(93.51,43.69) 93.63,43.69 94.28,44.34 v3(94.47,44.34)
F_USB1N: length 265.4
  TOP w0.102: TR14.4 93.16,35.06 92.95,35.28 92.95,36.82 C6726.1 92.95,37.98 92.95,39.24 ; CPU1.AR4 72.13,154.6 71.83,154.3 71.33,154.3 71.08,154.04 70.68,154.04 70.63,154.1 70.37,154.1 70.28,154 69.39,154 v4(68.93,153.54) ; 92.95,39.24 92.95,42.95 92.87,43.03 92.87,44.26 v3(92.95,44.34) ; 92.95,39.24 v1(93.3,39.24)
  L3 w0.102: v4(68.93,153.54) 67.59,154.89 66.84,154.89 66.33,155.4 56.76,155.4 55.46,154.1 52.98,154.1 48.67,149.79 36.99,149.79 35.36,148.17 25.31,148.17 22.98,150.5 22.98,151.87 22.36,152.49 21.08,152.49 20.45,151.87 v3(20.45,151.21) ; v3(33.18,48.67) 33.18,42.91 36.93,39.17 38.29,39.17 38.9,39.78 42.53,39.78 43.42,38.89 44.7,38.89 46.77,40.96 52.9,40.96 55.3,38.56 62.87,38.56 71.4,47.09 84.99,47.09 88.86,43.22 92.58,43.22 92.95,43.59 v3(92.95,44.34)
  L4 w0.102: v3(20.45,151.21) 20.48,151.18 20.48,149.46 24.27,145.67 24.27,140.62 25.66,139.23 31.34,139.23 35.92,134.65 35.92,119.82 36,119.74 36,116.29 37.47,114.81 37.47,101.07 38.31,100.23 38.31,91.65 38.68,91.28 38.68,86.58 36.3,84.2 36.3,73.44 28.87,66.02 28.87,56.46 33.16,52.17 33.16,48.69 v3(33.18,48.67)
F_USB1P: length 265.4
  TOP w0.102: 92.7,40.16 92.7,37.99 C6727.1 92.7,36.81 92.7,35.28 92.48,35.06 TR14.1 ; 92.7,40.16 v1(92.31,40.16) ; 92.7,40.16 92.7,42.85 92.62,42.92 92.62,43.91 v3(92.19,44.34) ; CPU1.AR3 71.7,154.66 71.57,154.79 71.33,154.79 71.2,154.66 71.2,154.46 70.99,154.25 70.77,154.25 70.71,154.31 70.29,154.31 70.19,154.21 68.49,154.21 68.3,154.02 v4(68.3,153.54)
  L3 w0.102: v3(33.64,49.28) 33.7,49.21 33.7,48.39 33.41,48.09 33.41,43.01 37.02,39.4 38.19,39.4 38.8,40.01 42.63,40.01 43.52,39.12 44.6,39.12 46.67,41.19 52.99,41.19 55.39,38.79 62.77,38.79 71.31,47.32 85.08,47.32 88.96,43.45 92.48,43.45 92.72,43.68 92.72,43.81 v3(92.19,44.34) ; v3(21.22,151.21) 21.14,151.21 20.68,151.66 20.68,151.77 21.17,152.26 22.27,152.26 22.75,151.77 22.75,150.4 25.21,147.94 35.46,147.94 37.08,149.56 48.77,149.56 53.07,153.87 55.56,153.87 56.86,155.17 66.23,155.17 66.74,154.66 67.49,154.66 68.3,153.85 v4(68.3,153.54)
  L4 w0.102: v3(21.22,151.21) 20.71,150.7 20.71,149.55 24.5,145.76 24.5,140.71 25.75,139.46 31.44,139.46 36.15,134.74 36.15,119.92 36.23,119.84 36.23,116.38 37.7,114.91 37.7,101.16 38.54,100.32 38.54,91.74 38.91,91.37 38.91,86.49 36.53,84.11 36.53,73.35 29.1,65.92 29.1,56.55 33.39,52.27 33.39,49.38 33.49,49.28 v3(33.64,49.28)
F_USB3N: length 231.1
  TOP w0.102: CPU1.AN4 72.29,156.2 71.79,155.7 71.12,155.7 71.11,155.69 70.69,155.69 70.68,155.7 70.32,155.7 70.31,155.69 69.88,155.69 69.77,155.81 69.38,155.81 v4(68.97,155.4) ; TR9.4 32.12,14.44 31.88,14.68 31.88,15.13 33.26,16.51 33.26,17.27 34.02,18.03 34.02,21.52 35.03,22.53 35.03,23.46 v3(35.29,23.72) ; v3(18.98,152.03) 18.98,151.84 v1(18.32,151.18)
  L3 w0.102: v4(68.97,155.4) 67.62,156.75 62.05,156.75 61.9,156.9 52.99,156.9 49.82,160.07 45.3,160.07 44.87,159.64 44.87,152.78 42.55,150.47 36.71,150.47 35.09,148.84 25.59,148.84 23.66,150.78 23.66,152.15 22.64,153.16 20.57,153.16 19.88,152.47 19.42,152.47 v3(18.98,152.03)
  L4 w0.102: v3(18.98,152.03) 18.63,151.68 18.63,149.34 23.15,144.81 23.15,140.15 25.19,138.11 30.88,138.11 34.25,134.74 34.25,122.76 34.68,122.32 34.68,119.25 34.86,119.07 34.86,115.14 35.25,114.74 36.36,113.64 36.36,98.75 36.4,98.7 36.4,91.62 37.02,91 37.02,87.15 35.19,85.32 35.19,81.43 34.09,80.34 34.09,72.82 27.67,66.39 27.67,55.89 31.68,51.87 31.68,43.8 28.53,40.65 28.53,31.31 29.8,30.04 29.8,30.04 30.07,29.77 30.07,29.77 30.21,29.63 30.54,29.63 31.29,28.88 31.29,28.56 33.76,26.09 34.7,26.09 35.02,25.77 35.02,23.99 v3(35.29,23.72)
  BOTTOM w0.102: v3(35.29,23.72) 36,23.72 36.36,23.37 36.36,23.35 v2(36.38,23.33)
F_USB3P: length 230.6
  TOP w0.102: CPU1.AN3 71.41,155.91 71.03,155.91 71.03,155.9 70.77,155.9 70.77,155.91 70.23,155.91 70.23,155.9 69.97,155.9 69.86,156.01 68.94,156.01 v4(68.33,155.4) ; v3(19.74,152.02) 20.76,152.02 v1(20.76,152.01) ; TR9.1 31.44,14.47 31.63,14.66 31.63,15.24 33,16.61 33,17.38 33.76,18.14 33.76,21.63 34.77,22.64 34.77,23.43 34.5,23.7 v3(34.5,23.72)
  L3 w0.102: v3(19.74,152.02) 20.66,152.93 22.54,152.93 23.43,152.05 23.43,150.68 25.49,148.62 35.18,148.62 36.8,150.24 42.65,150.24 45.1,152.69 45.1,159.55 45.39,159.84 49.72,159.84 52.9,156.67 61.8,156.67 61.95,156.52 67.53,156.52 68.33,155.71 v4(68.33,155.4)
  L4 w0.102: v3(34.5,23.72) 34.5,23.75 34.79,24.04 34.79,25.67 34.61,25.86 33.66,25.86 31.06,28.46 31.06,28.78 30.44,29.4 30.12,29.4 29.98,29.54 29.97,29.54 29.57,29.94 29.57,29.95 28.3,31.22 28.3,31.41 28.3,31.41 28.3,40.74 31.45,43.89 31.45,51.78 27.44,55.79 27.44,66.48 33.87,72.91 33.87,80.43 34.96,81.53 34.96,85.41 36.79,87.24 36.79,90.91 36.17,91.52 36.17,98.61 36.13,98.65 36.13,113.54 35.16,114.52 34.63,115.04 34.63,118.98 34.45,119.16 34.45,122.23 34.02,122.66 34.02,134.65 30.78,137.89 25.1,137.89 22.92,140.06 22.92,144.72 18.4,149.25 18.4,152.1 18.79,152.49 19.27,152.49 v3(19.74,152.02)
  BOTTOM w0.102: v2(33.69,23.75) 33.69,23.75 33.71,23.72 v3(34.5,23.72)
F_USB4N: length 177.6
  TOP w0.102: CPU1.AM2 70.8,156.5 69.97,156.5 69.69,156.21 68.51,156.21 v4(67.7,155.4) ; TR1.4 151.03,197.95 150.5,198.48 150.5,199.22 v3(151.29,200)
  L3 w0.102: v3(45.55,159.36) 45.82,159.09 49.63,159.09 52.5,156.22 61.62,156.22 61.77,156.07 67.02,156.07 v4(67.7,155.4)
  BOTTOM w0.102: 45.76,162.69 45.76,159.56 v3(45.55,159.36) ; 45.76,162.69 v2(45.42,162.69) ; 45.76,162.69 45.76,163.5 45,164.27 45,169.35 44.64,169.71 44.64,175.62 48.71,179.69 51.98,179.69 54.35,182.06 54.35,196.79 54.93,197.37 66.46,197.37 69.88,200.79 81.45,200.79 82.24,201.57 88.7,201.57 89.87,202.74 101.96,202.74 104.53,200.18 148.19,200.18 148.9,200.89 150.69,200.89 151.04,200.54 151.04,200.26 v3(151.29,200)
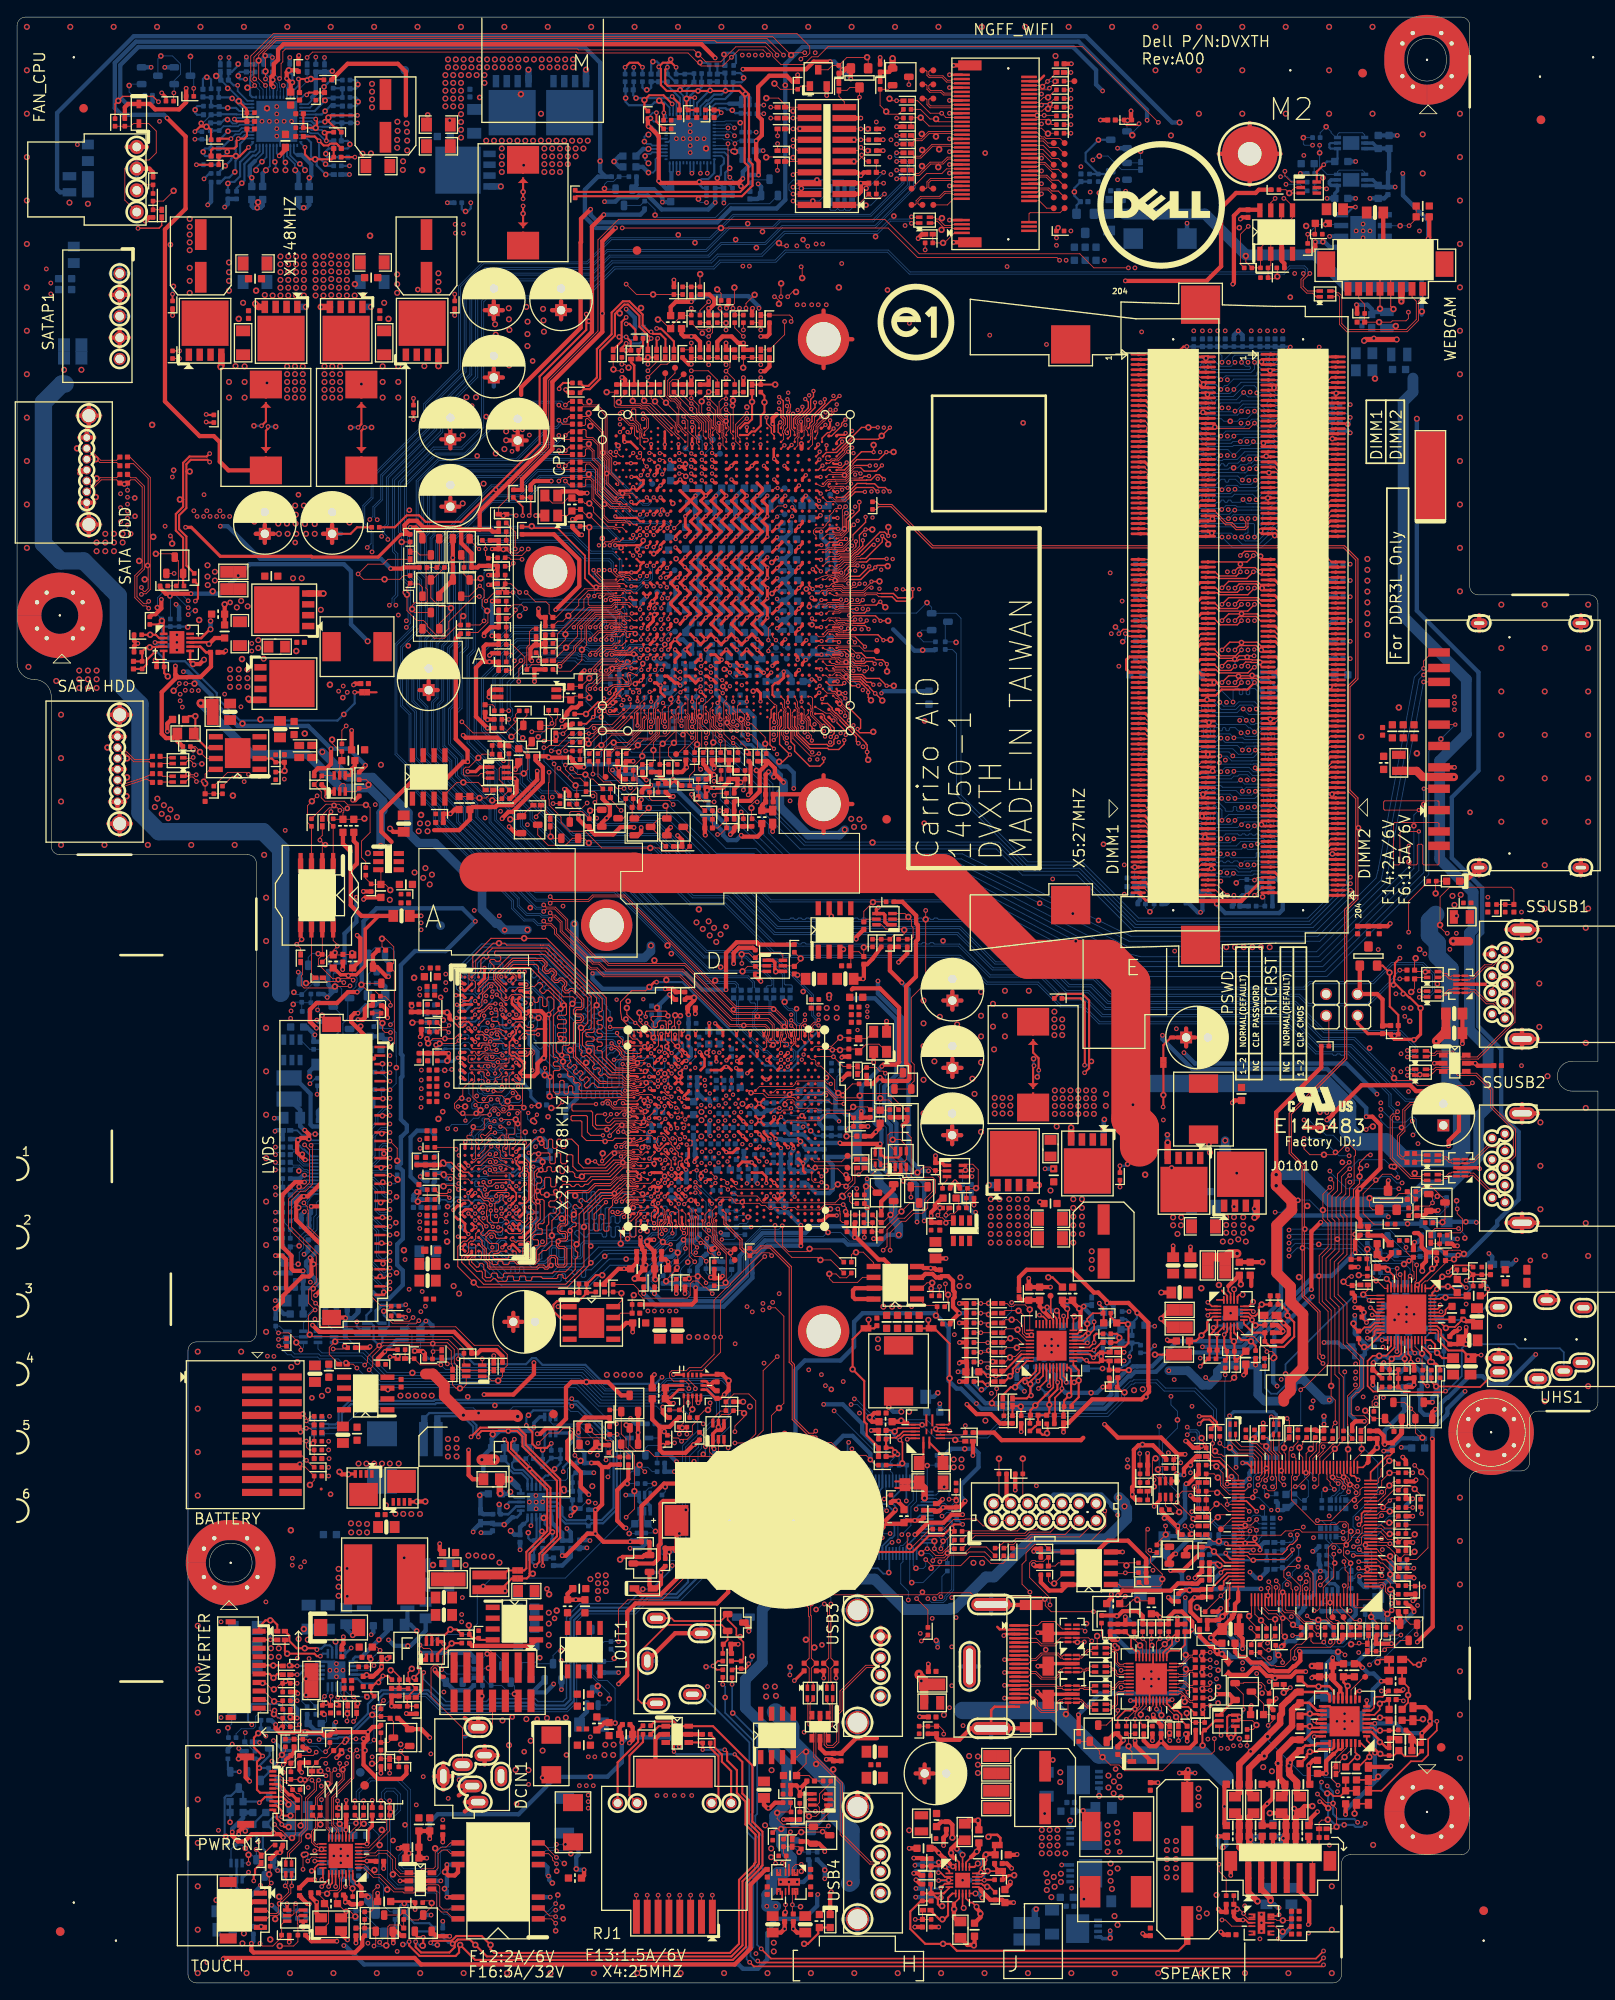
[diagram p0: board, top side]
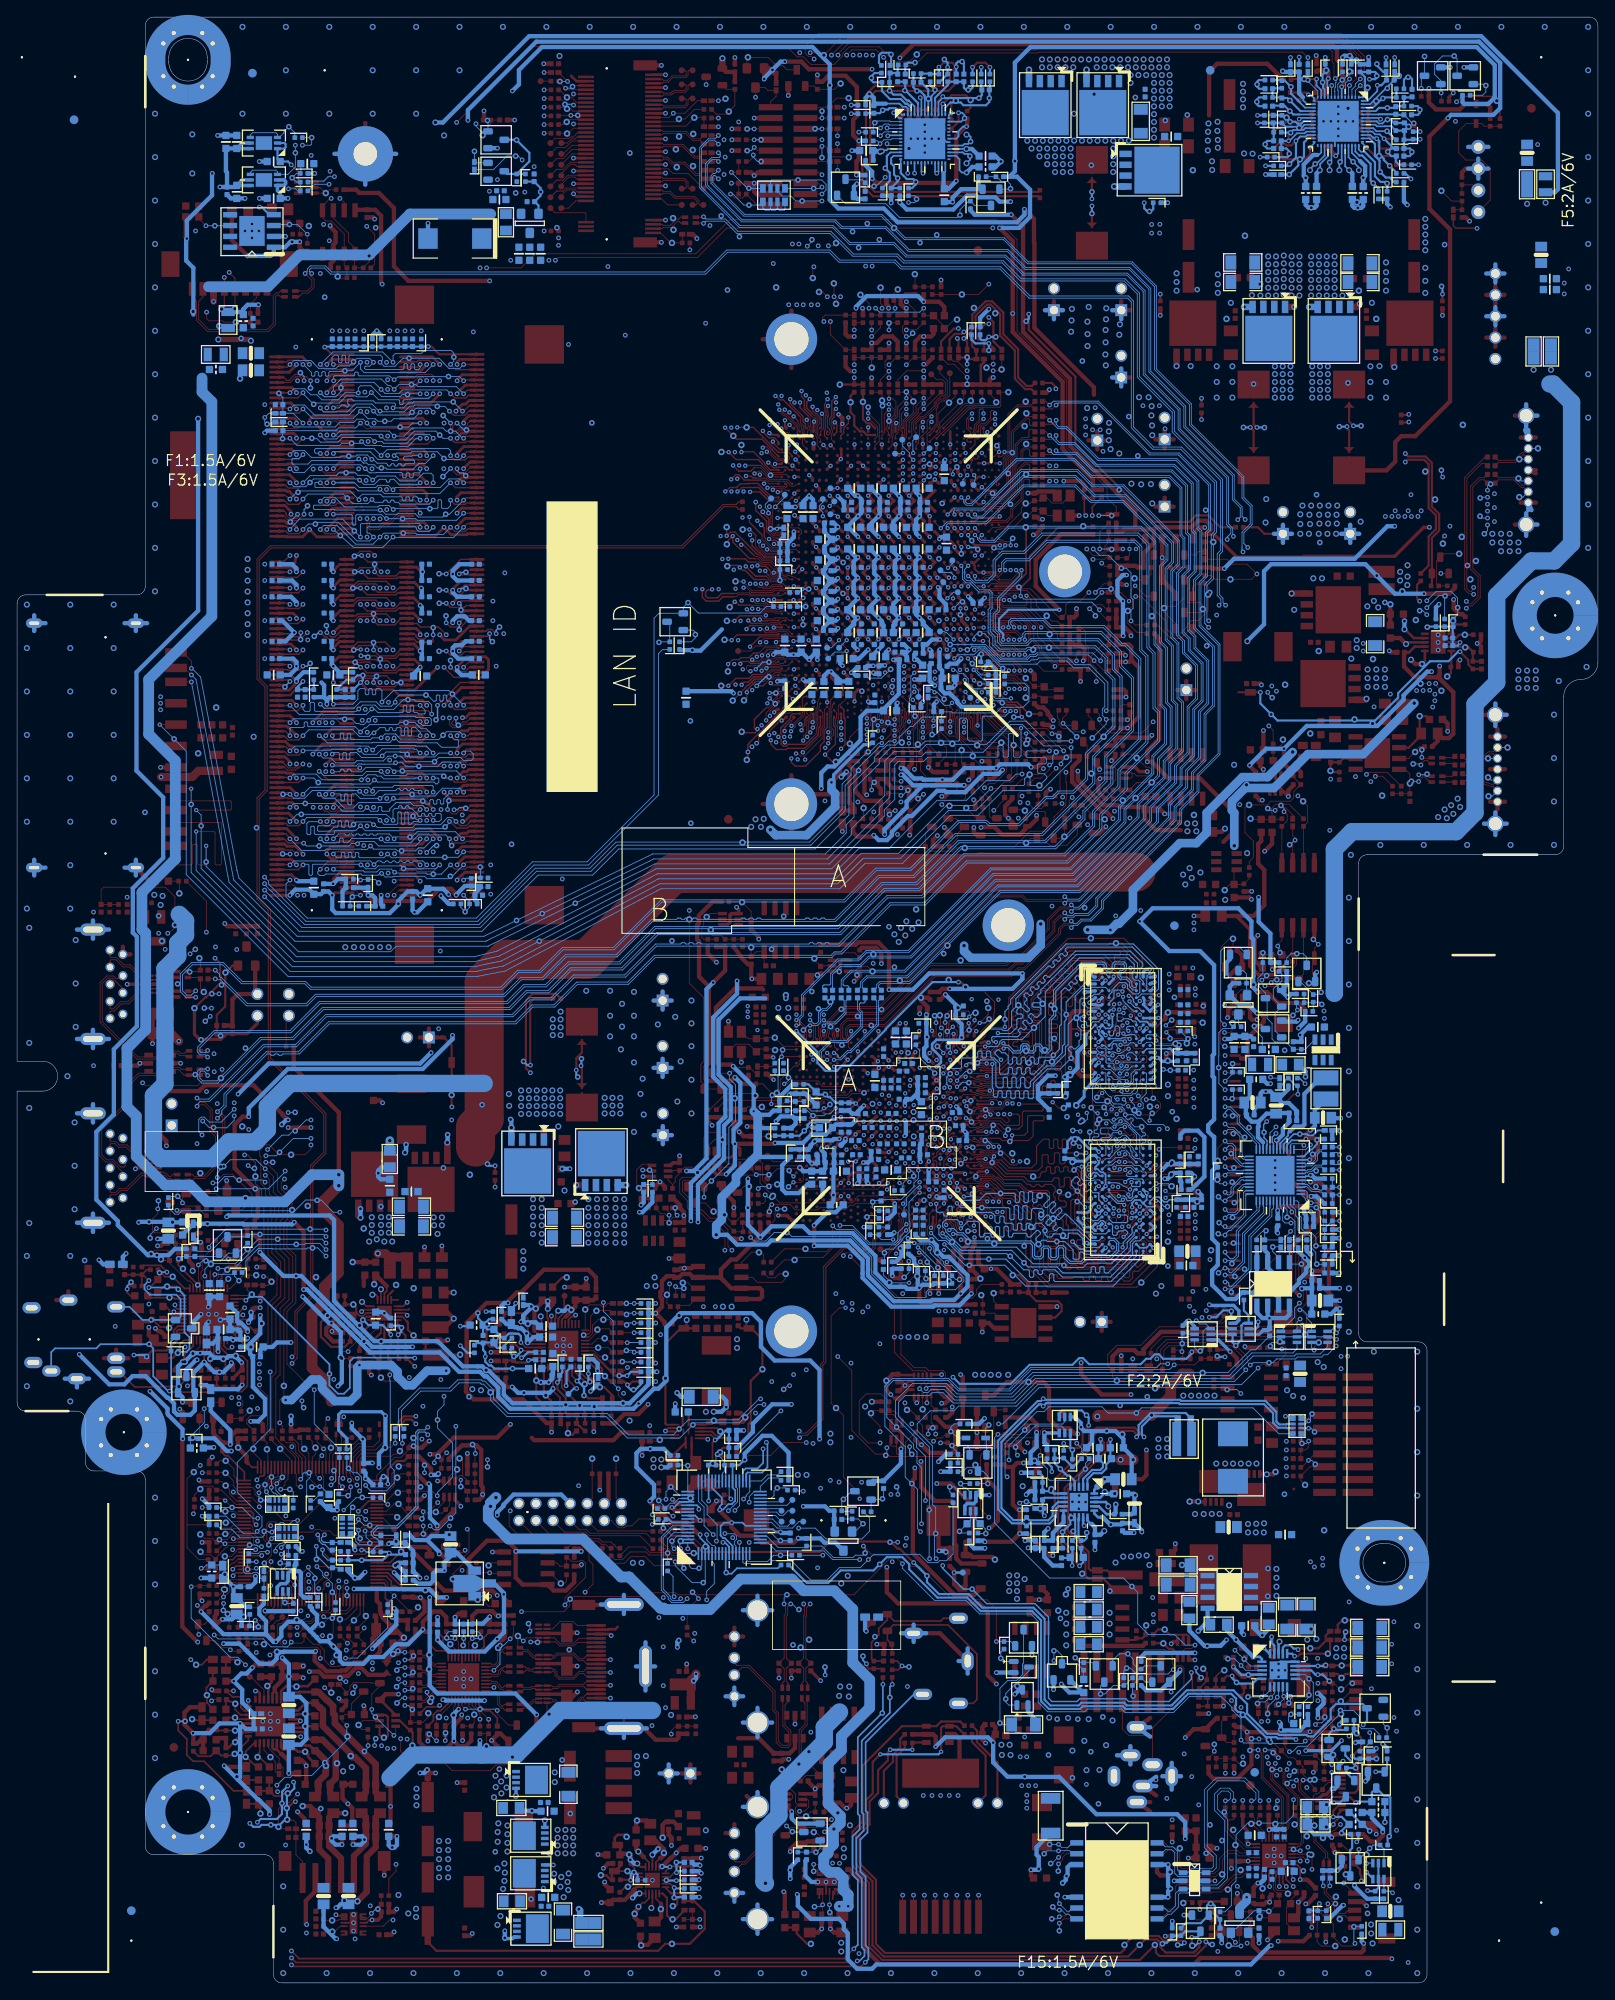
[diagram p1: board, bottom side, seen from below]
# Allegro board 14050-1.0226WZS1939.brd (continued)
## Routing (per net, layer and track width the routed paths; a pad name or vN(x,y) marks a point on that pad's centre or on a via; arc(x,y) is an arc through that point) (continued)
F_USB4P: length 177.6
  TOP w0.102: CPU1.AM1 70.5,156.88 70.38,156.76 69.87,156.76 69.58,156.47 68.41,156.47 67.75,155.81 67.19,155.81 67.06,155.68 v4(67.06,155.4) ; TR1.1 152.03,197.27 151.6,197.7 150.92,197.7 150.25,198.37 150.25,199.32 150.6,199.68 150.6,199.9 150.53,199.98 v3(150.53,200)
  L3 w0.102: v4(67.06,155.4) 67.06,155.71 66.93,155.85 61.67,155.85 61.53,155.99 52.41,155.99 49.54,158.86 45.82,158.86 v3(45.55,158.6)
  BOTTOM w0.102: v2(54.9,183.26) 54.6,183.26 ; 54.6,183.26 54.6,196.68 55.04,197.12 66.57,197.12 69.98,200.53 81.56,200.53 82.34,201.32 88.81,201.32 89.98,202.49 101.86,202.49 104.42,199.92 148.3,199.92 149.01,200.63 150.58,200.63 150.78,200.43 150.78,200.26 v3(150.53,200) ; 54.6,183.26 54.6,181.95 52.09,179.44 48.82,179.44 44.89,175.51 44.89,169.82 45.25,169.46 45.25,164.37 46.01,163.61 46.01,159.05 v3(45.55,158.6)
F_USB5N: length 125.9
  TOP w0.102: TR12.4 104.71,206.59 v3(104.67,206.63) ; CPU1.AL1 70.09,157.79 68.96,157.79 v4(68.33,157.15)
  L3 w0.102: v4(68.33,157.15) 68.33,157.47 68.24,157.56 66.89,157.56 66.55,157.22 64.33,157.22 64.14,157.41 58.08,157.41 57.28,158.2 52.52,158.2 51.24,159.48 50.21,160.52 44.24,160.52 v3(43.57,161.19)
  BOTTOM w0.102: 102.61,206.38 104.41,206.38 v3(104.67,206.63) ; 102.61,206.38 102.1,206.38 100.66,204.94 89.76,204.94 87.1,202.28 81.95,202.28 81.16,201.49 69.59,201.49 67.48,199.38 55.32,199.38 53.65,197.71 53.65,187.96 49.56,183.87 49.56,181.56 43.92,175.92 43.92,167.48 44.3,167.11 44.3,162.43 43.88,162 43.88,161.49 v3(43.57,161.19) ; 102.61,206.38 v2(102.61,206.73)
F_USB5P: length 125.9
  TOP w0.102: CPU1.AL2 70.6,157.5 69.83,157.5 69.75,157.58 69.12,157.58 68.97,157.43 v4(68.97,157.15) ; v3(104.67,205.87) 104.71,205.91 TR12.1
  L3 w0.102: v4(68.97,157.15) 68.97,157.25 68.43,157.79 66.8,157.79 66.45,157.44 64.43,157.44 64.23,157.63 58.17,157.63 57.38,158.43 52.61,158.43 51.4,159.65 50.3,160.74 44.34,160.74 44.26,160.82 44.26,161.12 v3(44.33,161.19)
  BOTTOM w0.102: 100.46,204.69 89.87,204.69 87.21,202.02 82.06,202.02 81.27,201.23 69.69,201.23 67.58,199.12 55.42,199.12 53.91,197.61 53.91,187.86 49.82,183.77 49.82,181.46 44.18,175.82 44.18,167.59 44.55,167.21 44.55,162.32 44.13,161.9 44.13,161.39 v3(44.33,161.19) ; 100.46,204.69 v2(100.46,204.32) ; 100.46,204.69 100.77,204.69 102.2,206.12 104.41,206.12 v3(104.67,205.87)
F_USB6N: length 158
  TOP w0.102: TR3.1 162.74,108.37 v3(162.7,108.33) ; CPU1.AL4 72.19,158.12 71.36,158.12 71.14,158.33 70.66,158.33 70.63,158.3 70.37,158.3 70.35,158.32 69.91,158.32 69.78,158.19 67.97,158.19 67.06,157.28 v4(67.06,157.15)
  BOTTOM w0.102: 163.25,110.12 161.94,111.43 153.04,111.43 149.64,114.83 127.7,114.83 125.73,116.8 123.17,116.8 120.5,119.46 114.53,119.46 110.39,123.6 88.99,123.6 83.85,128.74 79.78,128.74 74.88,133.65 64.75,133.65 57.71,140.68 57.71,143.5 54.59,146.62 54.59,152.62 56,154.04 56,155.68 58.19,157.86 66.94,157.86 67.06,157.74 v4(67.06,157.15) ; 163.25,110.12 163.86,109.5 163.86,108.86 163.59,108.58 162.96,108.58 v3(162.7,108.33) ; 163.25,110.12 v2(163.47,110.35)
F_USB6P: length 158
  TOP w0.102: TR3.4 162.74,109.05 v3(162.7,109.09) ; CPU1.AL3 71.71,157.79 71.71,157.53 71.58,157.4 71.4,157.4 71.27,157.53 71.27,157.91 71.06,158.12 70.74,158.12 70.71,158.09 70.29,158.09 70.27,158.12 69.99,158.12 69.86,157.99 68.13,157.99 67.58,157.44 67.58,157.27 v4(67.7,157.15)
  BOTTOM w0.102: 161.19,111.18 152.94,111.18 149.54,114.58 127.59,114.58 125.63,116.54 123.06,116.54 120.39,119.21 114.43,119.21 110.29,123.35 88.88,123.35 83.74,128.49 79.68,128.49 74.78,133.39 64.64,133.39 57.46,140.58 57.46,143.4 54.34,146.52 54.34,152.73 55.75,154.14 55.75,155.78 58.08,158.12 67.04,158.12 67.31,157.84 67.31,157.53 v4(67.7,157.15) ; 161.19,111.18 v2(161.19,110.82) ; 161.19,111.18 161.83,111.18 163.61,109.4 163.61,108.96 163.48,108.84 162.96,108.84 v3(162.7,109.09)
F_USB7N: length 162.8
  TOP w0.102: CPU1.AJ2 71.04,159.4 71.28,159.16 71.28,159 71.18,158.9 70.98,158.9 70.78,159.11 70.29,159.11 70.28,159.1 69.97,159.1 69.85,159.21 68.59,159.21 68.33,158.95 v4(68.33,158.6) ; TR4.1 163.62,106.25 163.49,106.38 162.83,106.38 162.7,106.25 v3(162.7,106.17)
  BOTTOM w0.102: v2(158.27,109.37) 158.03,109.12 ; 158.03,109.12 156.53,110.62 152.77,110.62 149.25,114.13 127.41,114.13 125.44,116.1 122.88,116.1 120.21,118.77 114.24,118.77 110.1,122.9 88.7,122.9 83.56,128.04 79.5,128.04 74.59,132.95 63.55,132.95 60.28,136.22 60.28,137.13 57.01,140.4 57.01,142.27 53.75,145.54 53.75,154.82 55.39,156.46 55.77,156.46 57.87,158.56 64.1,158.56 64.93,159.38 68.56,159.38 68.71,159.23 68.71,158.98 v4(68.33,158.6) ; 158.03,109.12 161.61,105.54 163.28,105.54 163.61,105.87 163.61,106.55 163.48,106.68 163.1,106.68 162.7,106.28 v3(162.7,106.17)
F_USB7P: length 162.7
  TOP w0.102: TR4.4 162.74,106.89 v3(162.7,106.93) ; v4(68.97,158.6) 69.37,159.01 69.77,159.01 69.88,158.89 70.37,158.89 70.37,158.9 70.63,158.9 70.93,158.6 CPU1.AK2
  BOTTOM w0.102: 163.86,106.27 163.86,106.66 163.59,106.93 v3(162.7,106.93) ; 163.86,106.27 v2(164.17,106.27) ; 163.86,106.27 163.86,105.76 163.38,105.28 161.51,105.28 156.43,110.36 152.66,110.36 149.14,113.88 127.3,113.88 125.34,115.84 122.77,115.84 120.1,118.51 114.14,118.51 110,122.65 88.6,122.65 83.45,127.79 79.39,127.79 74.49,132.69 63.45,132.69 60.03,136.11 60.03,137.02 56.76,140.29 56.76,142.17 53.49,145.43 53.49,154.92 55.28,156.71 55.67,156.71 57.77,158.81 64,158.81 64.82,159.64 68.66,159.64 68.97,159.34 v4(68.97,158.6)
FALL_INT2: length 8.7
  TOP w0.102: 82.73,63.1 82.73,62.91 82.61,62.79 82.15,62.79 82.08,62.87 ; 82.73,63.1 Q6701.3 ; 82.73,63.1 v3(83.22,62.61) ; 82.08,62.87 Q6701.2 ; 82.08,62.87 82.08,61.94 81.99,61.85 81.31,61.85 81.04,62.12 81.04,63.25 R6703.2
  BOTTOM w0.102: v3(83.22,62.61) 83.22,61.85 v2(83.35,61.72)
FCH_0.775_S5: length 247.6
  TOP w0.356: CPU1.AR12 79.72,154.82 v4(80,154.82) CPU1.AP13
  L3 w0.508: v3(161.27,210.12) 161.27,202.69 159.37,200.79 156.62,200.79 155.48,199.64 155.48,191.43 162.69,184.21 164.3,184.21 165.44,183.08 165.44,155.96 165.52,155.89 165.52,139.35 165.44,139.27 165.44,123.93 162.06,120.55 160.76,120.55 160.43,120.22 135.97,120.22 v3(135.47,120.73) ; v3(135.67,111.63) 131.71,111.63 119.88,123.46 118.98,123.46 118.22,124.22 88.58,124.22 83.19,129.61 81.82,129.61 77.96,133.47 77.96,134.54 77.36,135.14 77.36,135.24 77.03,135.6 74.28,138.34 74.28,138.71 72.98,140.01 72.98,142.22 73.15,142.39 73.15,143.04 75.09,144.97 75.3,144.97 76.41,146.08 76.41,147.88 78.39,149.86 78.39,150.15 79,150.76 79,153.87 79.95,154.82 v4(80,154.82)
  L4 w0.508: v3(135.67,111.63) 135.67,120.52 v3(135.47,120.73)
  BOTTOM w0.406: Q6703.6 159.28,210.3 C6714.1 158.66,210.95 Q6703.5 ; Q6704.6 159.28,214.62 C6715.1 158.66,215.26 Q6704.5
  BOTTOM w0.508: C6712.1 v3(161.27,210.12) ; C6712.1 159.48,210.12 C6714.1 ; C6712.1 160.43,211.84 160.56,211.96 C1956.1 C6715.1 ; C1953.1 79.67,154.82 v4(80,154.82) 80,155.43 C1954.1
FCH_S5_POWER_COMP: length 20
  TOP w0.102: R79724.1 147.48,200.6 v1(147.48,199.64) 147.23,199.39 146.53,199.39 R4706.1 R79725.2 146.72,200.98 U178.2 146.72,204.63 148.23,206.14 148.86,206.14 149.26,206.53 U178.5 149.26,207.9 148.37,208.79 v3(148.24,208.79) ; Q4701.1 149.12,210.71 148.37,211.46 v3(148.37,211.96)
  L3 w0.127: v3(148.37,211.96) 148.97,211.37 148.97,209.51 v3(148.24,208.79)
FFS_INT1: length 332.3
  TOP w0.102: CPU1.AJ1 69.95,159.4 69.94,159.41 68.51,159.41 v4(67.7,158.6) ; U109.110 149.66,45.97 149.71,46.02 v3(149.71,46.15) ; v3(81.1,67.87) 81.19,67.78 81.19,67.44 80.86,67.11 v1(80.86,67.04) 80.74,66.93 80.39,66.93 R79658.2 79.6,65.77 79.03,65.2 79.03,64.21 78.42,63.6 77.99,63.6 v3(77.76,63.37) 77.38,63.75 76.78,63.75 76.46,64.07 R6702.2
  L3 w0.127: v3(149.71,46.15) 149.69,46.13 149.65,46.13 148.6,45.07 145.78,45.07 144.62,46.23 140.79,46.23 139.18,44.62 133.95,44.62 133.6,44.96 130.64,44.96 129.62,45.99 122.6,45.99 121.35,47.24 111.67,47.24 111.39,47.24 110.83,46.68 100.9,46.68 100.58,47 97.25,47 96.23,48.02 90.97,48.02 86.46,52.54 81.44,52.54 v3(80.93,52.03) ; v3(85.42,79.12) 84.85,78.55 78.64,78.55 77.59,79.6 71.1,79.6 69.97,78.47 62.55,78.47 61.9,79.12 57.1,79.12 54.91,76.94 45.32,76.94 42.73,79.53 41.38,80.87 41.38,107.18 38.15,110.42 38.15,115.94 36.86,117.23 36.86,135.85 35.73,136.98 35.72,136.98 35.3,137.41 35.3,137.41 32.89,139.83 29.55,139.83 18.34,139.83 16.66,141.51 16.66,152.29 14.7,154.24 14.7,158.47 13.72,159.46 13.72,164.05 16.32,166.66 24.49,166.66 27.62,163.54 33.64,163.54 34.12,164.02 38.16,164.02 39.5,162.68 50.45,162.68 52.54,160.59 57.37,160.59 58.76,159.19 64.76,159.19 64.86,159.3 67,159.3 v4(67.7,158.6)
  L4 w0.127: v3(85.42,79.12) 83.35,77.04 83.35,75.44 77.66,69.75 77.66,65.7 77.03,65.07 77.03,64.02 77.55,63.5 77.63,63.5 v3(77.76,63.37) ; v3(81.1,67.87) 81.1,67.8 81.06,67.76 81.06,52.16 v3(80.93,52.03)
FFS_INT1_C: length 2.7
  TOP w0.102: U6701.11 v1(79.03,67.11) 79.03,67.01 78.71,66.69 R79658.1
FFS_INT2_APU: length 237.4
  TOP w0.102: CPU1.AK5 73.3,158.74 73.07,158.51 v4(73.04,158.51) ; v3(78.38,64.21) R79657.2
  L3 w0.127: v4(73.04,158.51) 72.81,158.51 72.47,158.17 71.36,158.17 69.97,159.55 64.76,159.55 64.66,159.45 58.87,159.45 57.47,160.85 52.64,160.85 50.55,162.94 39.6,162.94 38.27,164.27 34.02,164.27 33.53,163.79 27.72,163.79 24.6,166.92 16.22,166.92 13.46,164.16 13.46,155.12 16.4,152.18 16.4,141.37 18.19,139.57 28.91,139.57 28.91,139.57 29.44,139.57 29.44,139.57 32.78,139.57 35.05,137.31 35.05,137.3 35.62,136.73 35.63,136.73 36.61,135.75 36.61,117.12 37.89,115.84 37.89,110.31 41.13,107.07 41.13,80.77 45.21,76.68 55.02,76.68 57.2,78.87 61.79,78.87 62.44,78.22 70.07,78.22 71.2,79.35 77.48,79.35 78.54,78.3 85.82,78.3 v3(86.04,78.51)
  L4 w0.127: v3(78.38,64.21) 78.38,65.54 78.06,65.87 78.06,69.79 86.04,77.77 v3(86.04,78.51)
  BOTTOM w0.102: v2(77.85,64.95) 78.11,64.95 78.38,64.68 v3(78.38,64.21)
FFS_INT2_C: length 20
  TOP w0.102: R6704.2 77.62,67.04 78.01,66.65 78.01,65.54 R79657.1 77.49,64.27 77.5,64.26 v3(77.5,64.21) ; R6704.2 R79668.1 ; R6704.2 78.03,67.57 U6701.9 ; Q6701.5 82.08,66.12 82.46,66.5 83.38,66.5 R6706.1 84.77,66.95 v1(85.07,66.65) 85.07,66.22 84.01,65.15 v3(84.01,64.49)
  L3 w0.127: v3(77.5,64.21) 77.68,64.21 78.15,63.74 78.73,63.74 79.48,64.49 v3(84.01,64.49)
FFS_INT2_Q: length 208.5
  TOP w0.102: v3(84.01,63.17) 85.38,63.17 86.44,64.24 86.44,68.1 85.63,68.91 83.87,68.91 R6705.2 R6706.2 82.9,66.9 82.3,66.9 81.42,66.02 Q6701.6
  L3 w0.127: v3(29.29,73.33) 30.53,72.1 30.53,71.95 35.27,67.21 38.75,67.21 40.51,65.46 57.82,65.46 60.64,62.64 63.1,62.64 63.76,63.3 65.98,63.3 68.56,65.87 70.33,65.87 74.23,61.97 81.82,61.97 83.01,63.17 v3(84.01,63.17)
  L4 w0.127: v3(29.29,73.33) 29.29,74.17 29.93,74.8 29.93,76.71 30.89,77.67 30.89,84.9 31.34,85.34 31.34,92.01 32.74,93.42 32.74,104.35 32.29,104.8 32.29,112.47 32.53,112.71 32.53,114.01 31.83,114.71 31.83,133.03 29.03,135.83 23.12,135.83 18.77,140.18 18.77,141.92 18.25,142.44 18.25,146.48 16.34,148.39 16.34,152.63 15.25,153.72 15.25,157.2 15.89,157.84 15.89,162.5 15.17,163.22 15.17,166.38 15.78,167 15.78,181.13 13.75,183.16 13.75,188.25 SATAP1.5
FP_RST_N: length 243.3
  TOP w0.102: v3(58.33,160.66) 58.33,160.38 57.59,159.64 C1735.1 R2004.1 R2012.2 R1679.1 57.95,156.59 59.42,155.12 59.42,154.46 58.72,153.76 58.72,152.41 58.71,152.4 v3(58.71,152.27) ; R1920.1 v3(98.27,92.94) ; CPU1.AF2 71,162.1 70.32,162.1 70.31,162.09 69.78,162.09 69.68,162.2 69.28,162.2 v4(68.88,161.79)
  L3 w0.127: v3(98.27,92.94) 107.31,92.94 110.04,90.21 110.04,85.56 115.48,80.13 115.48,72.55 117.96,70.07 118.24,70.07 119.4,68.91 125.29,68.91 125.48,68.72 131.91,68.72 132.09,68.9 132.68,68.9 134.84,71.06 138.55,71.06 145.54,78.04 145.54,103.83 144.46,104.91 131.48,104.91 118.03,118.36 108.42,118.36 108.24,118.18 87.98,118.18 81.25,124.92 80.81,124.92 80.81,124.92 79.63,124.92 69.53,135.01 60.22,135.01 v3(59.72,135.51)
  L4 w0.127: v3(59.72,135.51) 59.38,135.85 59.38,144.23 54.39,149.22 54.39,152.18 54.9,152.69 58.28,152.69 v3(58.71,152.27)
  BOTTOM w0.102: v3(58.33,160.66) 59.21,161.54 68.62,161.54 v4(68.88,161.79) ; v2(97.01,93.19) 98.01,93.19 v3(98.27,92.94)
FWH_ID0: length 5.5
  TOP w0.102: LPC1.6 117.7,56.67 R1700.2 v1(117.7,61.34)
GFX_SVC: length 16.7
  TOP w0.102: v3(82.96,193.4) R1994.1 R1998.1 ; CPU1.B16 82.2,181.07 81.9,181.37 81.9,181.68 81.91,181.69 81.91,182.11 81.71,182.31 81.71,184.01 v4(80.93,184.78)
  L4 w0.127: v3(82.96,193.4) 82.24,192.67 82.24,186.09 v4(80.93,184.78)
  BOTTOM w0.102: v3(82.96,193.4) v2(82.96,194.21)
GFX_SVD: length 5.7
  TOP w0.102: R2000.1 R1995.1 83.78,185.92 v1(83.78,185.14) 83.78,184.53 83.8,184.51 83.8,182.51 83.8,182.51 CPU1.A18
GFX_SVT: length 16.5
  TOP w0.102: CPU1.B15 81.4,181.47 81.7,181.77 81.7,182.03 81.5,182.22 81.5,183.58 v4(80.93,184.15) ; R1993.1 R2002.1 81.39,193.79 81.39,193.09 v3(80.93,192.63)
  L4 w0.127: v4(80.93,184.15) 80.46,184.62 80.46,185.53 80.17,185.82 80.17,191.87 v3(80.93,192.63)
  BOTTOM w0.102: v2(80.2,193.01) 80.58,192.63 v3(80.93,192.63)
GFX_VCORE: length 66.3
  TOP w0.356: CPU1.K12 CPU1.K13 v4(80.6,174) ; CPU1.K7 74.9,174.8 v4(75.3,175.2) 75.7,175.6 CPU1.J8 ; CPU1.J9 77.2,175.5 v4(77.6,175.9) 78,175.5 CPU1.J11 ; v4(80.6,174) CPU1.K15 ; v4(80.6,174) CPU1.L13 CPU1.N15 v4(80.6,171.6) CPU1.P13 CPU1.T15 v4(80.6,169.2) CPU1.U13 ; CPU1.U22 v4(87.8,169.2) 87.8,170.4 CPU1.P22 v4(87.8,171.6) 87.8,172.8 CPU1.L22 v4(87.8,174) ; CPU1.N7 v4(74.5,171.8) ; CPU1.K16 v4(83,174) CPU1.L16 CPU1.N18 v4(83,171.6) CPU1.P16 CPU1.T18 v4(83,169.2) CPU1.U16 ; CPU1.N12 v4(78.2,171.6) 78.2,170.4 CPU1.T12 v4(78.2,169.2) ; CPU1.F15 81.63,177.9 v4(81.33,178.2) ; CPU1.P8 75.7,170.6 v4(75.3,170.2) CPU1.T7 ; CPU1.K19 v4(85.4,174) CPU1.L19 CPU1.N21 v4(85.4,171.6) CPU1.P19 CPU1.T21 v4(85.4,169.2) CPU1.U19 ; CPU1.G14 80.43,177.1 v4(80.13,177.4) ; CPU1.L8 v4(75.3,173.8)
  TOP w0.38: v4(77.5,177.39) 77.91,177.39 CPU1.G11 ; CPU1.F12 79.1,178.2 v4(78.89,178.2)
  TOP w0.508: 54.73,187.83 PT5401.1 ; PT5401.1 56.84,187.83 ; PT5401.1 55.79,188.89 ; PT5403.1 56.84,195.71 ; PT5403.1 55.79,196.76 ; PT5403.1 54.73,195.71 ; PT5403.1 55.79,194.65 ; PT5402.1 63.66,196.76 ; PT5402.1 62.61,195.71 ; PT5402.1 64.71,195.71 ; PT5402.1 63.66,194.65
  BOTTOM w0.508: 63.66,194.65 PT5402.1 ; PT5402.1 64.71,195.71 ; PT5402.1 62.61,195.71 ; 55.79,186.78 PT5401.1 ; PT5401.1 55.79,188.89 ; PT5401.1 56.84,187.83 ; 55.79,194.65 PT5403.1 56.84,195.71
  vias: v2(60.33,189.76) v2(76.74,173.1) v2(96.83,176.4) v2(101.86,198.07) v5(55.94,194.06) v5(56.01,192.84) v5(57.54,195.94) v5(57.56,194.64) v5(57.61,193.4) v5(57.61,191.95) v5(57.64,190.53) v5(57.59,189.26) v5(59.6,196.09) v5(59.74,194.37) v5(59.72,192.91) v5(59.72,191.52) v5(61.55,195.86) v5(61.6,194.51) v5(61.65,193.19)
GFX_VRM_PWRGD: length 4.5
  TOP w0.102: v3(84.01,215.19) v1(84.01,214.25)
  BOTTOM w0.102: PR5463.2 84.34,215.52 v3(84.01,215.19) 83.55,215.65 82.74,215.65 82.61,215.77 PU5407.7
GP11: length 5.2
  TOP w0.102: R679.1 161.28,61.09 v1(160.59,61.09) 159.62,60.12 159.62,59.3 159.34,59.03 159.34,58.6 159.12,58.38 U109.31
GP24: length 3.6
  TOP w0.102: R297.1 161.64,54.55 160.94,53.85 v1(160.58,53.85) 160.03,53.85 159.9,53.98 U109.20
GP26: length 3.5
  TOP w0.102: U109.18 159.63,53.18 160.28,52.53 v1(160.64,52.53) 160.65,52.51 161.58,52.51 R1188.1
GP27: length 6.1
  TOP w0.102: v1(163.56,52.48) 163.1,52.02 162.16,52.02 161.71,51.56 R1864.1 161.34,51.87 160.4,51.87 160.15,52.11 160.15,52.17 159.55,52.78 U109.17
GP32: length 4.5
  TOP w0.102: R307.2 160.8,51.38 v3(160.66,51.38) 160.53,51.52 159.51,51.52 159.45,51.58 U109.14
  BOTTOM w0.102: v3(160.66,51.38) 160.85,51.38 v2(161.32,51.86)
GP33: length 6.4
  TOP w0.102: v1(163.53,50.44) 163.18,50.09 162.33,50.09 R80222.1 161.77,49.72 161.4,50.09 161.3,50.09 161.2,50.19 161.2,50.29 160.56,50.93 160.47,50.93 160.22,51.18 U109.13
GP34: length 4.5
  TOP w0.102: U109.12 159.12,50.78 159.34,50.55 159.34,50.49 159.92,49.91 v1(160.69,49.91) 160.69,49.66 161.77,48.58 R80221.1
GP63: length 4.4
  TOP w0.102: U109.3 160.26,47.18 160.7,46.74 160.7,46.06 160.69,46.05 v1(160.69,46.02) 161.24,45.47 R1863.1
GPIO17_THERMAL_INT: length 20.7
  TOP w0.102: R1896.2 R1887.2 R1884.2 97.06,90.68 v3(96.68,91.06) 94.52,91.06 94.16,90.69 94.16,90.65 93.95,90.44 91.29,90.44 91,90.73 90.2,90.73 89.94,90.47 89.66,90.47 89.4,90.73 88.6,90.73 88.34,90.47 88.06,90.47 87.57,90.96 87.09,90.96 86.84,91.22 84.12,91.22 83.87,91.46 83.87,91.6 83.54,91.93 82.15,91.93 81.82,91.6 GPU1.R6
  BOTTOM w0.102: v2(96.96,90.25) 96.96,90.78 v3(96.68,91.06)
GPIO19_CTF: length 46.5
  TOP w0.102: GPU1.M2 79.4,87.03 79.84,86.59 80,86.59 v4(80.02,86.57) 80.04,86.55 80.23,86.55 80.36,86.42 80.46,86.42 80.8,86.08 80.8,85.61 81.12,85.3 81.34,85.3 81.59,85.04 R1886.1 ; R329.2 v3(99.16,87.22)
  BOTTOM w0.102: v3(99.16,87.22) 98.72,86.79 97.39,86.79 96.38,87.81 v2(94.9,87.81) 94.83,87.81 94.34,87.33 87.4,87.33 84.98,84.91 84.98,82.94 82.24,80.19 78.72,80.19 78.62,80.29 78.62,80.84 78.35,81.11 75.18,81.11 74.2,82.09 74.2,82.51 75.63,83.94 76.36,83.94 76.6,84.18 76.6,84.38 77.78,85.56 77.78,86.11 78.11,86.43 78.2,86.43 78.22,86.45 79.9,86.45 v4(80.02,86.57)
GPIO19_CTF_R: length 9
  TOP w0.102: D7.3 104.48,91.25 v1(103.49,90.26) 103.48,90.25 103.42,90.25 R1894.1 101.06,87.88 R329.1 100.05,88.39 100.11,88.46 R391.1 R1896.1
GPIO_8_ROMSO: length 43
  TOP w0.102: v4(81.74,94.21) 81.74,94.24 81.2,94.78 GPU1.P10 ; R1169.1 107.92,81.45 v3(107.95,81.48)
  L3 w0.127: v4(81.74,94.21) 82.31,94.78 94.31,94.78 94.79,94.31 94.79,93.4 92.63,91.24 92.63,88.55 95.99,85.19 106.99,85.19 107.86,84.33 107.86,81.66 107.95,81.57 v3(107.95,81.48)
  BOTTOM w0.102: v3(107.95,81.48) 107.75,81.28 107.25,81.28 107.23,81.26 v2(106.97,81.26)
GPIO_9_ROMSI: length 23.9
  TOP w0.102: v3(89.55,88.58) 89.59,88.54 89.59,86.25 90.27,85.56 92.43,85.56 v1(92.74,85.88) 95.19,85.88 R1171.2 ; GPU1.P4 80.53,89.93 80.53,89.86 80.5,89.83 80.5,89.37 80.53,89.34 80.53,89.05 80.4,88.92 80.4,88.58 80.63,88.35 80.65,88.35 v4(80.96,88.04)
  BOTTOM w0.102: v3(89.55,88.58) 89.1,88.14 87.06,88.14 85.29,86.36 82.22,86.36 81.94,86.65 81.93,86.65 81.64,86.94 81.64,87.36 v4(80.96,88.04)
GPIO_10_ROMSCK: length 22.3
  TOP w0.102: v3(88.7,88.63) 88.7,86.85 90.66,84.89 93.71,84.89 v1(94.01,84.58) 95.22,84.58 R1170.2 ; v4(80.93,88.76) 81,88.83 GPU1.P2
  BOTTOM w0.102: v3(88.7,88.63) 87.26,88.63 85.2,86.57 82.31,86.57 81.92,86.95 81.92,87.76 v4(80.93,88.76)
GPIO_22_ROMCS#: length 46.8
  TOP w0.102: v3(108.64,81.79) 108.64,80.87 108.95,80.57 v1(108.95,80.52) 108.95,79.51 R1168.1 ; GPU1.N8 79.86,93.2 v4(79.38,93.68)
  L3 w0.127: v4(79.38,93.68) 79.96,93.68 81.28,95.01 94.41,95.01 95.02,94.4 95.02,93.31 92.86,91.15 92.86,88.65 95.02,86.49 106.21,86.49 108.64,84.05 v3(108.64,81.79)
GPIO_SVC: length 5.2
  TOP w0.102: TP165.1 96.04,95.25 92.97,95.25 92.62,95.6 GPU1.AJ11
GPIO_SVD: length 4.6
  TOP w0.102: TP163.1 96.48,96.07 93.33,96.07 GPU1.AK12
GPIO_SVT: length 3.9
  TOP w0.102: GPU1.AL11 96.97,95.6 TP164.1
GPIO_VGA_03_DATA: length 9
  TOP w0.102: R1165.1 100.71,96.37 101.07,96.02 RN16.2 101.33,95.79 101.34,95.81 101.76,95.81 102.09,96.14 103.87,96.14 104.06,96.33 Q123.4 104.06,97.98 103.36,98.68 102.5,98.68 v1(102.47,98.65)
GPIO_VGA_03_DATA_R: length 17.4
  TOP w0.102: GPU1.U8 83.93,93.2 84.26,92.87 95.49,92.87 v1(96.05,93.43) 97.26,93.43 97.77,93.94 97.77,95.85 R1165.2
GPIO_VGA_04_CLK: length 7.9
  TOP w0.102: Q123.1 101.49,95.45 101.25,95.21 100.65,95.21 ; 100.65,95.21 99.95,94.51 98.54,94.51 v3(98.49,94.56) 99.18,95.25 R1166.1 ; 100.65,95.21 100.42,95.44 RN16.1
  BOTTOM w0.102: v2(97.01,94.56) v3(98.49,94.56)
GPIO_VGA_04_CLK_R: length 17.8
  TOP w0.102: GPU1.U7 83.99,92.4 84.32,92.07 86.6,92.07 86.93,91.74 86.93,91.6 87.26,91.27 95.73,91.27 v1(96.55,92.09) 98.05,93.59 98.05,95.12 R1166.2
GPU_CLKA0_T: length 3.2
  TOP w0.102: R1906.2 R1907.2 48.19,112.44 C1855.2 46.35,112.44 v1(46.26,112.34)
GPU_CLKA1_T: length 3.5
  TOP w0.102: C207.2 47.02,92.09 46.9,91.96 v1(46.9,91.41) 47.25,91.41 47.26,91.43 47.77,91.43 R1909.2 R1908.2
GPU_DMINUS: length 99.3
  TOP w0.127: v3(93.43,63.78) 93.15,64.06 92.57,64.06 90.71,65.91 90.71,72.26 90.36,72.62 90.36,83.72 90.16,83.91 88.09,85.98 87.13,85.98 86.55,85.39 86.08,85.39 RT2.2 85.31,85.52 85,85.52 84.59,85.93 84.59,86.89 82.71,88.77 82.71,89.49 GPU1.T2
  L3 w0.127: v3(93.43,63.78) 93.61,63.96 94.14,63.96 96.82,61.28 106.25,61.28 108.22,61.28 109.13,62.18 128.61,62.18 129.69,63.26 130.27,63.26 135.01,63.26 136.23,64.48 136.6,64.48 v3(136.94,64.14)
  BOTTOM w0.127: v3(136.94,64.14) 137.26,64.45 137.96,64.45 138.09,64.31 138.09,58.04 ; 138.09,58.04 138.09,55.59 138.78,54.9 140.46,53.23 142.77,53.23 143.29,52.7 143.29,52.53 143.12,52.36 C524.2 R651.2 ; 138.09,58.04 v2(137.78,58.04)
GPU_DPLUS: length 103.9
  TOP w0.127: U109.85 144.56,50.78 v3(144.69,50.65) ; v3(93.47,64.57) 93.21,64.31 92.67,64.31 90.97,66.02 90.97,72.37 90.61,72.72 90.61,83.82 88.2,86.23 87.03,86.23 86.44,85.65 86.08,85.65 RT2.1 85.69,85.97 85.5,85.78 85.1,85.78 84.84,86.03 84.84,87 82.96,88.88 82.96,90.04 GPU1.T4
  L3 w0.127: v3(136.94,65.02) 136.65,64.73 136.12,64.73 134.9,63.51 130.37,63.51 129.58,63.51 128.5,62.43 109.02,62.43 108.12,61.53 106.14,61.53 96.93,61.53 94.25,64.21 93.82,64.21 v3(93.47,64.57)
  BOTTOM w0.127: 138.35,62.81 138.35,55.69 140.56,53.48 142.87,53.48 143.54,52.81 143.54,52.42 143.23,52.11 143.06,52.11 C524.1 142.43,51.33 142.64,51.12 142.95,51.12 143.26,50.8 143.26,50.48 R658.1 144.15,50.42 144.38,50.65 v3(144.69,50.65) ; 138.35,62.81 138.35,64.42 138.06,64.71 137.26,64.71 v3(136.94,65.02) ; 138.35,62.81 v2(138.62,62.81)
GPU_GPIO16: length 5.4
  TOP w0.102: TP155.1 80.42,86.75 79.84,87.33 79.69,87.48 79.69,89.42 79.73,89.46 79.73,89.75 79.4,90.09 GPU1.M4
GPU_SCL: length 4.8
  TOP w0.102: GPU1.R1 81.8,87.59 81.92,87.47 81.92,86.96 83.02,85.86 83.98,85.86 TP149.1
GPU_SDA: length 6.6
  TOP w0.102: TP150.1 82.63,85.93 81.72,86.85 81.72,87.39 81.56,87.54 81.56,88.97 81.47,89.06 81.47,89.23 arc(81.49,89.32) 81.53,89.4 81.8,89.67 GPU1.R3
GPU_THERM_SHUTDOWN*: length 38.5
  TOP w0.102: R354.1 97.7,91.19 97.44,91.44 v3(97.44,92.2) ; PR18.1 113.98,71.6 v3(113.57,72.01)
  L3 w0.127: v3(113.57,72.01) 114.29,72.73 114.29,79.84 107.71,86.42 107.25,86.42 104.31,89.37 95.74,89.37 95.5,89.62 95.5,91.2 96.5,92.2 v3(97.44,92.2)
  BOTTOM w0.102: v2(96.68,91.92) 96.73,91.92 96.73,91.92 97.16,91.92 v3(97.44,92.2)
GPU_THERMAL_INT: length 100
  TOP w0.102: v3(96.05,90.55) 96.3,90.3 96.3,89.98 96.32,89.96 96.32,89.22 96.58,88.96 R1884.1 97.12,88.9 R1885.2 ; U109.28 159.45,57.18 v3(159.7,57.43)
  L3 w0.127: v3(96.05,90.55) 97.95,90.55 98.57,91.17 108,91.17 109.28,89.89 109.28,85.25 114.71,79.81 114.71,71.73 118.29,68.15 124.97,68.15 125.16,67.96 132.23,67.96 132.4,68.14 133,68.14 134.41,69.55 143.09,69.55 144.25,70.7 144.9,70.7 145.83,71.63 150.13,71.63 151.06,70.7 153.35,70.7 155.98,68.07 158.57,68.07 158.91,67.74 v3(159.04,67.74)
  L4 w0.127: v3(159.7,57.43) 159.7,58.51 158.69,59.51 158.69,61.12 159.04,61.46 v3(159.04,67.74)
  BOTTOM w0.102: v3(96.05,90.55) v2(95.18,90.55)
GPU_VCC3_CTL: length 6.8
  TOP w0.102: R1126.1 162.92,89.78 C1864.2 164.03,90.89 165.27,90.89 v3(165.65,91.26) 165.65,91.85 Q76.G
  BOTTOM w0.102: PR5476.2 167.18,91.99 166.24,91.99 v2(166.2,92.03) 165.65,91.47 v3(165.65,91.26)
GPU_VCC3_CTL_2: length 8.5
  TOP w0.102: R1195.2 162.82,92.57 C836.1 162.48,92.35 161.73,92.35 161.07,91.69 159.55,91.69 159.42,91.82 v1(158.28,91.82) 158.28,90.83 158.66,90.45 Q77.G
GPU_VCC3_CTL_3: length 8.2
  TOP w0.102: R1129.1 166.76,88.95 v1(166.81,89) 167.1,89.29 Q76.D 167.1,91.61 165.51,93.19 164.65,93.19 164.05,92.6 R1195.1
GPU_VREFG: length 7.2
  TOP w0.254: GPU1.AC16 88.77,98.83 v4(88.77,98.76)
  BOTTOM w0.508: v4(88.77,98.76) 88.8,98.73 89.41,98.73 89.57,98.58 91.55,98.58 v2(91.67,98.45) 92.14,97.99 92.14,97.83 C1846.1 R1210.2 R1211.1
GPU_WAKEB: length 9.1
  TOP w0.102: R1883.2 97.75,105.19 96.68,104.11 v1(96.1,104.11) 95.69,104.52 95.69,105.64 94.06,107.27 93.66,107.27 93.47,107.46 93.47,107.86 93.27,108.06 92.94,108.06 GPU1.AJ27
GPU_XO_IN: length 17.7
  TOP w0.102: GPU1.AC22 88.53,104.2 88.86,104.53 91.06,104.53 91.26,104.73 94.67,104.73 95.84,103.56 98.36,103.56 v1(98.61,103.81) 98.86,104.06 102.04,104.06 103.93,102.17 R1880.1
GPU_XO_IN2: length 17.2
  TOP w0.102: GPU1.AB22 87.93,103.87 90.82,103.87 90.89,103.93 94.16,103.93 94.5,104.27 94.84,104.27 95.86,103.25 100.77,103.25 v1(101.02,103.5) 101.23,103.3 102.03,103.3 R1881.1
H_VID0: length 41
  TOP w0.102: PR39.1 v3(112.78,79.5) PR40.1 ; GPU1.T8 82.81,93.2 v4(83.18,92.83)
  L3 w0.127: v3(112.78,79.5) 112.06,80.23 107.46,80.23 106.62,81.06 106.62,82.43 105.05,84 92.01,84 v4(83.18,92.83)
  BOTTOM w0.102: v2(113.7,79.5) v3(112.78,79.5) PR40.1
H_VID1: length 43.7
  TOP w0.102: PR38.1 v3(112.78,78.36) PR37.1 ; v4(82.13,85.32) 82.13,85.86 81.31,86.68 81.31,87.22 81.07,87.46 80.96,87.46 80.19,88.23 80.19,89 80.2,89.01 GPU1.N1
  L3 w0.127: v3(112.78,78.36) 112.31,78.83 110.26,78.83 109.37,79.72 107.25,79.72 106.12,80.85 106.12,82.22 104.84,83.49 91.8,83.49 89.44,85.85 82.66,85.85 v4(82.13,85.32)
  BOTTOM w0.102: PR38.1 v3(112.78,78.36) 113.53,78.36 v2(113.69,78.21)
H_VID2: length 45.1
  TOP w0.102: v4(81.72,93.59) 81.33,93.2 GPU1.P8 ; PR36.1 v3(112.78,77.22) PR35.1
  L3 w0.127: v4(81.72,93.59) 82.1,93.59 82.77,92.92 82.77,92.65 83.01,92.41 83.28,92.41 91.92,83.77 92.03,83.77 92.06,83.74 104.95,83.74 106.37,82.32 106.37,80.95 107.35,79.97 111.53,79.97 112.67,78.83 112.98,78.83 113.25,78.55 113.25,77.69 v3(112.78,77.22)
  BOTTOM w0.102: v2(113.67,76.99) 113.44,77.22 v3(112.78,77.22) PR36.1
H_VID3: length 42.5
  TOP w0.102: PR32.1 v3(112.78,76.07) PR33.1 ; v4(94.14,93.67) 93.26,93.67 93,93.93 GPU1.AK10
  L3 w0.127: v4(94.14,93.67) 92.17,91.7 92.17,87.82 95.49,84.51 105.27,84.51 107.13,82.64 107.13,81.27 107.67,80.73 112.58,80.73 113.76,79.55 113.76,77.05 v3(112.78,76.07)
  BOTTOM w0.102: v2(94.72,93.14) 94.2,93.67 v4(94.14,93.67) ; PR33.1 v3(112.78,76.07)
H_VID4: length 44.7
  TOP w0.102: PR31.1 113.57,74.93 v3(113.6,74.9) 113.62,74.93 PR30.1 ; GPU1.AM10 93.8,94.7 v4(94.14,94.36)
  L3 w0.127: v4(94.14,94.36) 94.56,93.94 94.56,93.5 92.4,91.34 92.4,87.91 95.48,84.84 106.76,84.84 107.39,84.21 107.39,81.38 107.77,80.99 112.68,80.99 114.02,79.65 114.02,76.16 113.6,75.74 v3(113.6,74.9)
  BOTTOM w0.102: PR31.1 113.57,74.93 v3(113.6,74.9) ; v4(94.14,94.36) 94.65,94.87 v2(94.65,95.05)
H_VID5: length 48.7
  TOP w0.102: PR25.1 v3(112.78,73.79) PR26.1 ; v4(83.11,93.58) 83.11,93.64 82.75,94 GPU1.T9
  L3 w0.127: v4(83.11,93.58) 92.44,84.25 105.16,84.25 106.88,82.53 106.88,81.17 107.56,80.48 112.47,80.48 113.51,79.44 113.51,77.28 112.98,76.75 112.79,76.75 112.31,76.27 112.31,74.26 v3(112.78,73.79)
  BOTTOM w0.102: v2(113.7,74) 113.68,74.02 113.01,74.02 v3(112.78,73.79) PR26.1
H_VID6: length 4.6
  TOP w0.102: PR23.1 v3(112.78,72.64) PR5251.1
  BOTTOM w0.102: v2(114.18,72.69) 114.13,72.65 112.79,72.65 v3(112.78,72.64) PR5251.1
HDMI1_CLK_APU: length 291
  TOP w0.102: CPU1.F7 74.3,178.2 v4(74,178.2) ; v3(134.9,28.35) 134.71,28.53 134.71,28.97 R79639.2
  L4 w0.127: v4(74,178.2) 74.27,178.2 74.46,178.39 74.46,179.7 74.62,179.87 74.62,180.63 74.2,181.05 74.2,183.58 70.76,187.03 70.44,187.03 69.97,187.5 69.97,198.58 76.02,204.63 96.41,204.63 101.12,199.91 104.07,199.91 109.05,194.94 151.82,194.94 155.16,191.6 155.16,131.21 154.5,130.55 154.5,126.27 150.2,121.96 150.2,109.01 148.06,106.87 148.06,98.55 148.91,97.7 148.91,89.48 148.06,88.62 148.06,78.44 147.43,77.82 147.43,76.26 142.43,71.26 142.43,63.02 139.43,60.02 139.43,52.99 138.72,52.28 138.72,42.61 138.8,42.53 138.8,40.38 138.72,40.3 138.72,32.17 v3(134.9,28.35)
  BOTTOM w0.102: v2(134.86,29.26) 134.9,29.22 v3(134.9,28.35)
HDMI1_CLK_APU_SRC: length 3.6
  TOP w0.102: U118.38 133.74,32.41 133.92,32.23 v1(133.92,31.32) 133.92,30.84 134.71,30.05 R79639.1
HDMI1_CLK_CON: length 24.7
  TOP w0.102: HDMI1.15 119.44,39.82 119.82,39.43 121.51,39.43 121.97,39.89 U117.10 U117.1 v3(124.9,39.89) ; U118.32 131.34,32.37 v3(129.82,30.85) R2083.2
  L4 w0.127: v3(129.82,30.85) 127.72,30.85 127.59,30.97 127.59,35.24 124.9,37.94 v3(124.9,39.89)
  BOTTOM w0.102: v2(124.09,39.85) 124.13,39.89 v3(124.9,39.89)
HDMI1_DATA_APU: length 291.1
  TOP w0.102: R79640.2 v3(135.91,28.34) ; v4(74,179) 74.3,179 CPU1.E7
  L4 w0.127: v3(135.91,28.34) 135.91,29 138.97,32.06 138.97,40.19 139.05,40.27 139.05,42.63 139.05,42.64 139.05,52.25 139.68,52.89 139.68,59.91 142.69,62.91 142.69,71.09 147.69,76.09 147.69,77.71 148.31,78.34 148.31,88.52 149.16,89.37 149.16,97.81 148.31,98.66 148.31,106.76 150.45,108.9 150.45,121.86 154.75,126.16 154.75,130.45 155.41,131.1 155.41,191.71 151.93,195.19 109.15,195.19 104.18,200.16 101.23,200.16 96.51,204.88 75.91,204.88 69.72,198.69 69.72,187.39 71.69,185.42 72.04,185.42 73.67,183.79 73.67,180.7 73.47,180.49 73.24,180.49 73.11,180.37 73.11,179.73 73.24,179.6 73.72,179.6 74,179.32 v4(74,179)
  BOTTOM w0.102: v3(135.91,28.34) 135.99,28.34 v2(136.76,29.11)
HDMI1_DATA_APU_N0: length 294.6
  TOP w0.102: CPU1.A3 71.9,181.36 71.77,181.23 71.58,181.23 71.45,181.36 v4(71.45,181.45) ; v3(139.62,33.35) C3371.1
  L4 w0.127: v3(139.62,33.35) 139.93,33.04 141.15,33.04 142.27,34.16 142.27,49.51 142.75,49.99 142.75,58.54 145.09,60.88 145.09,68.87 150.72,74.5 150.72,81.96 151.32,82.57 151.32,88.03 151.71,88.41 151.71,95.82 152.41,96.53 152.41,105.51 153.66,106.76 153.66,108.8 155.62,110.75 155.62,117.69 157.01,119.08 157.01,123.81 158.53,125.33 158.53,156.25 159.24,156.95 159.24,192.25 158.14,193.34 157.21,193.34 152.96,197.6 110.15,197.6 105.18,202.57 102.23,202.57 97.37,207.42 74.76,207.42 66.14,198.81 66.14,186.17 70.44,181.87 71.36,181.87 71.45,181.78 v4(71.45,181.45)
  BOTTOM w0.102: v3(139.62,33.35) 139.95,33.35 v2(140.55,32.75)
HDMI1_DATA_APU_N1: length 291.5
  TOP w0.102: CPU1.A4 72.47,181.63 72.47,182.14 72.14,182.47 71.7,182.47 71.08,183.09 71.08,183.82 70.96,183.95 70.68,183.95 70.55,183.82 v4(70.55,183.62) ; C3372.1 138.77,34.94 139,34.72 139.56,34.72 139.62,34.79 v3(139.62,35.13)
  L4 w0.127: v4(70.55,183.62) 70.18,183.25 70,183.25 69.99,183.26 67.35,185.9 67.35,199.07 75.03,206.75 97.1,206.75 101.95,201.9 104.9,201.9 109.87,196.93 152.65,196.93 156.9,192.67 157.87,192.67 158.57,191.97 158.57,157.23 157.86,156.52 157.86,125.61 156.34,124.08 156.34,119.36 154.95,117.97 154.95,111.03 152.99,109.07 152.99,107.03 151.75,105.79 151.75,96.81 151.04,96.1 151.04,88.68 150.66,88.3 150.66,82.85 150.05,82.24 150.05,74.78 144.42,69.15 144.42,61.16 142.08,58.82 142.08,50.26 141.58,49.76 141.58,34.99 141.11,34.52 140.19,34.52 140.06,34.65 140.06,35 139.94,35.13 v3(139.62,35.13)
  BOTTOM w0.102: v3(139.62,35.13) 140.12,35.13 v2(140.59,34.66)
HDMI1_DATA_APU_N2: length 286.8
  TOP w0.102: CPU1.C5 73.72,180.3 73.85,180.42 73.85,180.6 73.72,180.72 73.25,180.72 73.12,180.85 73.12,180.95 73.1,180.97 73.1,181.23 73.12,181.25 73.12,181.75 72.97,181.9 72.97,182.28 72.41,182.84 72.41,184.05 72.31,184.15 72,184.15 71.9,184.05 v4(71.9,183.62) ; v3(139.62,36.9) C3373.1
  L4 w0.127: v3(139.62,36.9) 139.93,36.59 140.38,36.59 140.91,37.12 140.91,42.29 140.14,43.06 140.14,51.83 140.75,52.44 140.75,59.47 143.76,62.47 143.76,69.43 149.38,75.05 149.38,82.52 149.99,83.12 149.99,88.58 150.37,88.96 150.37,96.38 151.08,97.09 151.08,106.07 152.32,107.31 152.32,109.35 154.28,111.31 154.28,118.25 155.67,119.63 155.67,124.36 156.91,125.6 156.91,129.17 156.48,129.6 156.48,153.71 157.18,154.41 157.18,185.1 156.48,185.8 156.48,192.15 152.37,196.26 109.59,196.26 104.62,201.23 101.67,201.23 96.82,206.09 75.31,206.09 68.02,198.79 68.02,187.25 71.64,183.62 v4(71.9,183.62)
  BOTTOM w0.102: v2(140.56,36.59) 140.24,36.9 v3(139.62,36.9)
HDMI1_DATA_APU_N3: length 284.5
  TOP w0.102: CPU1.B5 73.4,181.44 73.9,181.94 73.9,182.97 73.82,183.05 v4(73.25,183.62) ; v3(139.62,38.68) C3374.1
  L4 w0.127: v3(139.62,38.68) 139.93,38.37 140.06,38.37 140.24,38.55 140.24,42.01 139.45,42.8 139.45,52.08 140.09,52.72 140.09,59.74 143.09,62.75 143.09,69.77 145.83,72.51 145.83,72.51 148.71,75.4 148.71,82.79 149.32,83.4 149.32,88.86 149.7,89.24 149.7,89.79 149.56,89.93 149.56,90.31 149.7,90.45 149.7,90.83 149.56,90.97 149.56,91.35 149.7,91.49 149.7,91.87 149.56,92 149.56,92.38 149.7,92.52 149.7,93.76 149.56,93.9 149.56,94.28 149.7,94.42 149.7,94.8 149.56,94.93 149.56,95.32 149.7,95.45 149.7,95.83 149.56,95.97 149.56,96.35 149.7,96.49 149.7,97.83 148.71,98.82 148.71,106.6 150.85,108.74 150.85,119.95 151.16,120.26 153.2,120.26 153.32,120.38 153.32,120.64 153.2,120.76 151.16,120.76 150.85,121.07 150.85,121.69 155.16,125.99 155.16,130.28 155.81,130.93 155.81,153.99 156.51,154.69 156.51,184.83 155.81,185.53 155.81,191.87 152.09,195.59 109.32,195.59 104.34,200.57 101.4,200.57 96.54,205.42 75.59,205.42 69.31,199.14 69.31,187.23 72.12,184.42 72.92,183.62 v4(73.25,183.62)
  BOTTOM w0.102: v2(140.43,38.84) 140.27,38.68 v3(139.62,38.68)
HDMI1_DATA_APU_P0: length 294.5
  TOP w0.102: v3(139.62,32.46) C3368.1 ; CPU1.A2 v4(70.55,181.45)
  L4 w0.127: v3(139.62,32.46) 139.93,32.77 141.26,32.77 142.54,34.05 142.54,49.4 143.02,49.88 143.02,58.43 145.36,60.77 145.36,68.76 150.98,74.39 150.98,81.85 151.59,82.46 151.59,87.91 151.97,88.3 151.97,95.71 152.68,96.42 152.68,105.4 153.93,106.65 153.93,108.69 155.88,110.64 155.88,117.58 157.27,118.97 157.27,123.7 158.8,125.22 158.8,156.14 159.5,156.84 159.5,192.36 158.25,193.61 157.32,193.61 153.07,197.86 110.26,197.86 105.29,202.84 102.34,202.84 97.49,207.69 74.65,207.69 65.87,198.92 65.87,186.06 70.48,181.45 v4(70.55,181.45)
  BOTTOM w0.102: v2(138.74,31.98) 139.22,32.46 v3(139.62,32.46)
HDMI1_DATA_APU_P1: length 291.4
  TOP w0.102: v4(70.55,182.98) 70.88,182.98 70.93,182.93 71.61,182.25 72.05,182.25 72.25,182.05 72.25,181.05 CPU1.B4 ; v3(139.62,34.24) C3370.1
  L4 w0.127: v3(139.62,34.24) 139.64,34.25 141.22,34.25 141.84,34.88 141.84,49.65 142.35,50.15 142.35,58.71 144.69,61.05 144.69,69.04 150.32,74.67 150.32,82.13 150.92,82.74 150.92,88.19 151.3,88.57 151.3,95.99 152.01,96.7 152.01,105.68 153.26,106.92 153.26,108.96 155.22,110.92 155.22,117.86 156.6,119.25 156.6,123.97 158.13,125.5 158.13,156.41 158.83,157.12 158.83,192.08 157.98,192.94 157.01,192.94 156.83,193.12 152.76,197.2 109.98,197.2 105.01,202.17 102.06,202.17 97.21,207.02 74.92,207.02 67.08,199.18 67.08,185.79 69.65,183.22 69.8,183.08 69.89,182.98 v4(70.55,182.98)
  BOTTOM w0.102: v3(139.62,34.24) 138.9,34.24 v2(138.69,34.44)
HDMI1_DATA_APU_P2: length 286.9
  TOP w0.102: CPU1.D5 72.9,180 72.9,180.86 72.88,180.89 72.88,181.31 72.9,181.34 72.9,181.66 72.75,181.81 72.75,182.19 71.96,182.98 v4(71.9,182.98) ; v3(139.62,36.01) C3369.1
  L4 w0.127: v4(71.9,182.98) 67.75,187.14 67.75,198.9 75.2,206.35 96.93,206.35 101.78,201.5 104.73,201.5 109.71,196.53 152.48,196.53 156.75,192.26 156.75,185.91 157.29,185.37 157.44,185.22 157.44,154.3 156.75,153.6 156.75,129.71 157.18,129.28 157.18,125.49 155.94,124.25 155.94,119.52 154.55,118.14 154.55,111.2 152.59,109.24 152.59,107.2 151.35,105.95 151.35,96.98 150.64,96.27 150.64,88.85 150.26,88.47 150.26,83.01 149.65,82.41 149.65,74.94 144.02,69.32 144.02,62.36 141.02,59.36 141.02,52.33 140.41,51.72 140.41,43.17 141.18,42.4 141.18,37.01 140.49,36.33 139.93,36.33 v3(139.62,36.01)
  BOTTOM w0.102: v3(139.62,36.01) 139,36.01 v2(138.67,36.35)
HDMI1_DATA_APU_P3: length 284.8
  TOP w0.102: CPU1.A5 73.55,181.9 73.68,182.03 73.68,182.88 73.67,182.9 73.52,183.05 73.31,183.05 v4(73.25,182.98) ; v3(139.62,37.79) C3375.1
  L4 w0.127: v4(73.25,182.98) 73.18,182.98 71.97,184.2 71.93,184.23 69.05,187.12 69.05,199.25 75.48,205.68 96.65,205.68 101.51,200.83 104.45,200.83 109.43,195.86 152.2,195.86 156.08,191.98 156.08,185.64 156.78,184.94 156.78,154.58 156.08,153.88 156.08,130.82 155.42,130.17 155.42,125.88 151.12,121.58 151.12,121.18 151.27,121.03 153.31,121.03 153.59,120.75 153.59,120.27 153.31,119.99 151.27,119.99 151.12,119.84 151.12,108.63 148.98,106.49 148.98,98.93 149.97,97.95 149.97,89.13 149.59,88.75 149.59,83.29 148.98,82.68 148.98,75.29 145.94,72.25 143.36,69.66 143.36,62.64 140.35,59.63 140.35,52.61 139.72,51.97 139.72,42.91 140.51,42.12 140.51,38.44 140.17,38.1 139.93,38.1 v3(139.62,37.79)
  BOTTOM w0.102: v2(138.62,38.26) 139.08,37.79 v3(139.62,37.79)
HDMI1_DATA_APU_SRC: length 3.7
  TOP w0.102: U118.39 134.14,32.61 135.63,31.12 v1(135.63,31.12) 135.91,30.84 R79640.1
HDMI1_DATA_CON: length 24.8
  TOP w0.102: HDMI1.16 119.26,40.32 119.92,39.66 121.41,39.66 122.12,40.37 U117.9 U117.2 125.39,40.37 v3(125.76,40.01) ; U118.33 131.74,32.44 130.83,31.54 v3(130.83,30.85) R2084.2
  L4 w0.127: v3(130.83,30.85) 127.84,33.84 127.84,35.35 125.51,37.68 125.51,39.75 v3(125.76,40.01)
  BOTTOM w0.102: v2(126.37,40.56) 125.81,40.01 v3(125.76,40.01)
HDMI1_DATA_CON_N0: length 11.4
  TOP w0.102: TR16.2 126,32.61 125.76,32.38 125.34,32.38 124.58,33.13 124.37,33.13 124.24,33.26 U116.2 U116.9 122.44,33.26 122.31,33.13 121.99,33.13 121.57,32.71 121.57,32.02 121.41,31.86 119.92,31.86 119.41,32.37 119.41,33.01 118.99,33.43 118.71,33.43 118.32,33.82 HDMI1.3
HDMI1_DATA_CON_N1: length 9.3
  TOP w0.102: HDMI1.6 118.32,35.32 118.71,34.93 121.55,34.93 121.83,34.65 122.31,34.65 122.44,34.78 U116.6 U116.5 124.23,34.78 124.37,34.65 124.84,34.65 124.95,34.53 125.76,34.53 126,34.77 TR17.2
HDMI1_DATA_CON_N2: length 10.1
  TOP w0.102: TR18.2 125.62,37.05 125.39,36.82 125.12,36.82 125,36.71 124.64,36.71 124.51,36.84 U31.7 U31.4 122.44,36.84 122.31,36.71 122.12,36.71 121.83,36.41 121.83,36.07 121.52,35.76 119.92,35.76 119.25,36.43 118.71,36.43 118.32,36.82 HDMI1.9
HDMI1_DATA_CON_N3: length 11.4
  TOP w0.102: HDMI1.12 118.32,38.32 118.71,37.93 119.16,37.93 119.83,38.59 121.84,38.59 122.21,38.23 122.31,38.23 122.44,38.36 U31.1 U31.10 124.24,38.36 124.37,38.23 124.49,38.23 125.25,38.98 125.75,38.98 125.99,39.21 TR19.2 126.4,39.46 v1(126.4,40.59)
HDMI1_DATA_CON_P0: length 12.9
  TOP w0.102: U116.10 122.44,32.78 122.31,32.91 122.08,32.91 121.79,32.62 121.79,31.93 121.5,31.65 119.83,31.65 119.2,32.28 119.2,32.92 118.91,33.21 118.71,33.21 118.32,32.82 HDMI1.1 ; U116.10 122.98,31.69 v1(122.74,31.45) ; U116.10 U116.1 124.23,32.78 124.37,32.91 124.49,32.91 125.25,32.16 125.76,32.16 126,31.93 TR16.3
HDMI1_DATA_CON_P1: length 9.3
  TOP w0.102: HDMI1.4 118.32,34.32 118.71,34.71 121.46,34.71 121.74,34.43 122.31,34.43 122.44,34.3 U116.7 U116.4 124.23,34.3 124.37,34.43 124.75,34.43 124.86,34.32 125.7,34.32 125.94,34.09 TR17.3
HDMI1_DATA_CON_P2: length 10.1
  TOP w0.102: TR18.3 125.62,36.37 125.39,36.6 125.21,36.6 125.09,36.49 124.64,36.49 124.51,36.36 U31.6 U31.5 122.44,36.36 122.31,36.49 122.21,36.49 122.04,36.32 122.04,35.98 121.61,35.55 119.83,35.55 119.16,36.21 118.71,36.21 118.32,35.82 HDMI1.7
HDMI1_DATA_CON_P3: length 9.9
  TOP w0.102: HDMI1.10 118.32,37.32 118.71,37.71 119.25,37.71 119.92,38.38 121.75,38.38 122.12,38.01 122.31,38.01 122.44,37.88 U31.2 U31.9 124.23,37.88 124.37,38.01 124.58,38.01 125.34,38.76 125.76,38.76 126,38.53 TR19.3
HDMI1_DATA_IC_N0: length 3.2
  TOP w0.102: U118.2 135.9,34.17 136,34.08 136.26,34.08 137.33,33.01 137.55,33.01 C3371.2
HDMI1_DATA_IC_N1: length 3
  TOP w0.102: C3372.2 137.55,34.79 137.19,34.79 136.7,35.28 136,35.28 135.9,35.37 U118.5
HDMI1_DATA_IC_N2: length 3.4
  TOP w0.102: 137.07,36.42 137.22,36.57 137.55,36.57 C3373.2 ; 137.07,36.42 v1(136.79,36.7) ; 137.07,36.42 136.73,36.08 136,36.08 135.9,36.17 U118.7
HDMI1_DATA_IC_N3: length 3.6
  TOP w0.102: 137.01,38.13 136.16,37.28 136,37.28 135.9,37.37 U118.10 ; 137.01,38.13 137.23,38.34 137.55,38.34 C3374.2 ; 137.01,38.13 v1(136.76,38.38)
HDMI1_DATA_IC_P0: length 3.6
  TOP w0.102: 136.89,33.15 136.17,33.86 136,33.86 135.9,33.77 U118.1 ; 136.89,33.15 137.24,32.79 137.55,32.79 C3368.2 ; 136.89,33.15 v1(136.64,32.9)
HDMI1_DATA_IC_P1: length 3
  TOP w0.102: C3370.2 137.55,34.57 137.1,34.57 136.61,35.06 136,35.06 135.9,34.97 U118.4
HDMI1_DATA_IC_P2: length 3
  TOP w0.102: C3369.2 137.55,36.35 137.31,36.35 136.82,35.86 136,35.86 135.9,35.77 U118.6
HDMI1_DATA_IC_P3: length 3.2
  TOP w0.102: C3375.2 137.55,38.13 137.32,38.13 136.25,37.06 136,37.06 135.9,36.97 U118.9
HDMI1_DET_APU: length 285.4
  TOP w0.102: CPU1.F5 73.3,177.81 v4(73.69,177.42) ; U118.3 136.02,34.57 136.18,34.42 136.55,34.42 136.96,34.01 v3(137.03,34.01)
  L4 w0.127: v3(137.03,34.01) 138.09,35.07 138.09,40.14 138.47,40.52 138.47,42.39 138.38,42.47 138.38,52.41 139.1,53.13 139.1,68.19 141.85,70.95 141.85,71.15 147.1,76.4 147.1,77.96 147.73,78.58 147.73,88.76 148.58,89.61 148.58,97.56 147.73,98.41 147.73,106.52 147.73,107.01 149.87,109.15 149.87,122.1 154.17,126.4 154.17,130.69 154.82,131.34 154.82,191.46 151.68,194.6 108.91,194.6 103.93,199.58 100.99,199.58 96.27,204.29 76.16,204.29 70.3,198.44 70.3,187.64 70.58,187.36 70.89,187.36 74.44,183.81 74.44,182.51 74.85,182.11 74.85,179.52 74.76,179.43 74.76,178.37 74.17,177.78 74.05,177.78 v4(73.69,177.42)
  BOTTOM w0.102: v3(137.03,34.01) 137.03,33.75 136.63,33.35 v2(136.48,33.35)
HDMI1_DET_CON: length 19.1
  TOP w0.102: HDMI1.19 119.45,41.82 119.92,42.29 121.45,42.29 122.32,41.41 U117.7 U117.4 124.72,41.41 v3(124.99,41.15) ; U118.28 v3(129.2,34.57)
  L4 w0.127: v3(124.99,41.15) 125.89,41.15 126.65,40.39 126.65,37.11 v3(129.2,34.57)
  BOTTOM w0.102: v3(124.99,41.15) 124.99,41.87 v2(125.15,42.04)
HDMI_LANE0_IC_DN: length 4.3
  TOP w0.102: U118.29 129.57,34.17 129.48,34.08 128.85,34.08 128.56,33.78 128.56,32.67 128.27,32.38 128.17,32.38 127.93,32.61 TR16.1
HDMI_LANE0_IC_DP: length 4.3
  TOP w0.102: U118.30 129.57,33.77 129.48,33.86 128.94,33.86 128.77,33.69 128.77,32.58 128.36,32.16 128.17,32.16 127.93,31.93 TR16.4
HDMI_LANE1_IC_DN: length 3.3
  TOP w0.102: U118.26 129.57,35.37 129.48,35.28 128.95,35.28 128.43,34.76 128.43,34.67 128.29,34.53 128.17,34.53 127.93,34.77 TR17.1
HDMI_LANE1_IC_DP: length 3.3
  TOP w0.102: U118.27 129.57,34.97 129.48,35.06 129.04,35.06 128.65,34.67 128.65,34.58 128.38,34.32 128.17,34.32 127.93,34.09 TR17.4
HDMI_LANE2_IC_DN: length 3.4
  TOP w0.102: TR18.1 127.93,37.05 128.17,36.82 128.36,36.82 128.65,36.53 128.65,36.28 128.85,36.08 129.48,36.08 129.57,36.17 U118.24
HDMI_LANE2_IC_DP: length 3.4
  TOP w0.102: U118.25 129.57,35.77 129.48,35.86 128.76,35.86 128.43,36.19 128.43,36.44 128.27,36.6 128.17,36.6 127.93,36.37 TR18.4
HDMI_LANE3_IC_DN: length 4.6
  TOP w0.102: 128.43,38.91 128.36,38.98 128.17,38.98 127.93,39.21 TR19.1 ; 128.43,38.91 v1(128.71,39.19) ; 128.43,38.91 128.77,38.56 128.77,37.55 129.05,37.28 129.48,37.28 129.57,37.37 U118.21
HDMI_LANE3_IC_DP: length 4.2
  TOP w0.102: U118.22 129.57,36.97 129.48,37.06 128.96,37.06 128.56,37.47 128.56,38.47 128.27,38.76 128.17,38.76 127.93,38.53 TR19.4
HDT_C_M1: length 4.2
  TOP w0.102: HDT1.11 98.33,214.38 98.71,214.76 v3(98.74,214.76) 98.74,214.73 99.09,214.38 R1702.1
  BOTTOM w0.102: v2(99.55,214.38) 99.09,214.38 98.74,214.73 v3(98.74,214.76)
HDT_C_M2: length 3.7
  TOP w0.102: R1703.1 v3(98.74,215.65) HDT1.13
  BOTTOM w0.102: v3(98.74,215.65) v2(97.93,215.65)
HDT_C_M3: length 3.7
  TOP w0.102: R1705.1 v3(98.74,216.92) HDT1.15
  BOTTOM w0.102: v3(98.74,216.92) v2(99.55,216.92)
HDT_PW_M3: length 4.6
  TOP w0.102: v1(88.63,222.22) 88.65,222.22 89.33,221.55 R1701.2 91.73,221.93 Q50.1
HDT_PW_M4: length 7.7
  TOP w0.102: Q1210.G 99.6,225.17 v1(99.47,225.3) 99.45,225.27 97.1,225.27 R504.2 95.41,224.35 94.9,223.84 Q50.3
HDT_RST0: length 3.7
  TOP w0.102: R1747.1 v3(90.81,218.19) HDT1.18
  BOTTOM w0.102: v3(90.81,218.19) v2(90.81,219)
HDT_RST1: length 5.7
  TOP w0.102: HDT1.20 R1748.1 89.89,219.75 89.11,220.52 v1(87.68,220.52)
HDT_TRST: length 4.9
  TOP w0.102: v3(98.84,213.87) 98.84,213.61 ; 98.84,213.61 98.33,213.11 HDT1.9 ; 98.84,213.61 99.35,213.11 R1743.1
  BOTTOM w0.102: v3(98.84,213.87) 98.84,213.61 98.33,213.11 v2(97.93,213.11)
HDT_VDDIO_SUS: length 34.8
  TOP w0.102: HDT1.19 96.81,220.09 96.17,220.73 R1698.2 97.12,221.42 97.47,221.77 Q1210.D v3(98.59,220.62) ; HDT1.1 98.39,208.03 R1704.1 100.12,208.84 101.05,208.84 v3(101.51,209.3)
  L3 w0.127: v3(98.59,220.62) 99.66,219.54 99.66,211.14 v3(101.51,209.3)
  BOTTOM w0.102: 96.83,207.54 RN12.6 ; 96.83,207.54 96.98,207.39 97.44,207.39 97.72,207.67 RN12.5 98.1,208 v2(99.35,208) 99.93,208 101.23,209.3 v3(101.51,209.3) ; 96.83,207.54 96.68,207.39 96.25,207.39 96.02,207.62 ; RN12.7 96.02,207.62 ; 96.02,207.62 95.79,207.39 95.23,207.39 95.13,207.49 RN12.8
HM_VCCP: length 5.9
  TOP w0.508: R1832.1 138.4,40.58 139.63,39.34 139.9,39.34 140.28,38.96 140.28,38.69 140.5,38.48 v1(141,38.48) 141.77,37.72 G5.2
HM_VCCP_R: length 8.2
  TOP w0.203: 141.54,44.63 141.89,44.98 141.89,46.61 142.06,46.78 U109.95
  TOP w0.508: R1832.2 C558.2 140.26,42.42 140.32,42.48 140.69,42.48 v1(141.07,42.86) 141.54,43.33 141.54,44.63
HPOL_CON: length 22
  TOP w0.203: R225.2 170.4,82.85 R220.2 ; R220.2 R221.1 C134.1 ; R220.2 170.28,82.87 v3(169.58,82.17) ; R220.2 169.82,83.44 R223.2
  BOTTOM w0.203: UHS1.1 171.83,79.09 170.31,77.57 v2(169.31,77.57) 169.3,77.57 Q57.1 166.21,77.57 165.87,77.91 165.87,80.01 166.38,80.52 169.46,80.52 170.09,81.15 170.09,81.66 v3(169.58,82.17)
HPOR_CON: length 36.2
  TOP w0.203: R284.2 R281.1 ; R281.1 161.67,69.72 162.28,69.11 167.04,69.11 v3(167.17,69.24) ; R281.1 C159.1 R262.2
  BOTTOM w0.203: Q57.2 167.01,75.05 167.01,74.52 166.97,74.48 R627.2 166.97,69.43 v3(167.17,69.24) 167.32,69.24 169.07,70.99 169.07,74.24 v2(169.55,74.73) 175.25,74.73 175.72,74.25 180.55,74.25 181.01,73.79 181.01,71.6 UHS1.2
HPOUT-JD: length 9.3
  TOP w0.203: R267.1 165.51,70.33 v1(166.06,69.78) 168.69,69.78 168.75,69.72 171.23,69.72 173,71.49 UHS1.6
HPOUT-L: length 42.2
  TOP w0.203: v3(159.85,74.4) 160.08,74.17 160.43,74.17 160.79,74.53 U6.26 ; R220.1 170.2,83.95 168.2,83.95 167.47,83.22 v3(167.47,83.16)
  L3 w0.203: v3(167.47,83.16) 167.95,82.68 172.85,82.68 178.49,77.04 178.49,75.56 178.47,75.56 176.89,73.99 175.34,73.99 174.15,75.18 168.44,75.18 166.78,73.53 165.26,73.53 164.42,74.37 161.26,74.37 161.06,74.17 160.08,74.17 v3(159.85,74.4)
  BOTTOM w0.203: v3(167.47,83.16) 168.26,83.16 v2(168.33,83.08)
HPOUT-R: length 9.8
  TOP w0.203: U6.27 161.19,74.34 160.22,73.37 v1(159.41,73.37) 158.65,73.37 158.05,72.77 158.05,69.84 158.7,69.19 159.2,69.19 R284.1
HSI_C_DN3: length 141.8
  TOP w0.102: CPU1.P6 74.1,170.6 v4(73.7,170.2) ; v3(102.93,214.12) R1712.2
  L3 w0.127: v3(42.15,171.2) 41.89,171.45 41.89,172.24 42.6,172.95 48.04,172.95 49.07,173.98 54.6,173.98 61.63,181 61.63,181.86 63.06,183.3 64.36,183.3 67.32,180.34 67.32,177.58 70.43,174.46 70.43,173.21 72.82,170.81 73.51,170.81 73.7,170.62 v4(73.7,170.2)
  BOTTOM w0.102: v3(102.93,214.12) 102.85,214.12 102.73,214 102.73,213.68 102.84,213.56 103.73,213.56 104.45,212.84 104.45,210.29 100.21,206.04 89.31,206.04 88.52,205.26 87.23,205.26 ; v3(42.15,171.2) 41.85,171.49 41.85,172.6 42.78,173.53 42.78,176.34 48.46,182.02 48.46,184.39 52.55,188.48 52.55,198.17 54.86,200.48 67.02,200.48 69.13,202.59 80.7,202.59 83.37,205.26 87.23,205.26 ; v2(87.23,204.9) 87.23,205.26
HSI_C_DP3: length 141.9
  TOP w0.102: v4(74.5,170.2) 74.9,170.6 CPU1.P7 ; v3(102.93,213.11) R1711.2
  L3 w0.127: v3(41.28,171.22) 41.63,171.56 41.63,172.35 42.49,173.22 47.93,173.22 48.96,174.24 54.49,174.24 61.36,181.11 61.36,181.97 62.95,183.57 64.47,183.57 67.58,180.45 67.58,177.69 70.7,174.57 70.7,173.32 72.93,171.08 73.62,171.08 v4(74.5,170.2)
  BOTTOM w0.102: v3(41.28,171.22) 41.64,171.58 41.64,172.69 42.56,173.62 42.56,176.43 48.24,182.11 48.24,184.48 52.33,188.57 52.33,198.26 54.77,200.7 66.93,200.7 69.04,202.81 80.61,202.81 83.28,205.47 85.5,205.47 ; 85.5,205.47 88.43,205.47 89.22,206.26 100.12,206.26 104.24,210.38 104.24,212.75 103.64,213.35 103.17,213.35 v3(102.93,213.11) ; 85.5,205.47 v2(85.5,205.84)
HSI_LAN_DN1: length 247.7
  TOP w0.102: v4(73.7,169.4) CPU1.T5 ; C1808.2 34.91,20.85 34.91,21.69 36.64,23.41 36.64,24.71 v3(36.38,24.97)
  L3 w0.127: v4(73.7,169.4) 73.7,169.12 73.56,168.98 71.93,168.98 71.38,169.52 71.38,171.32 68.11,174.6 68.11,176.15 66.85,177.41 66.85,179.41 64.47,181.79 63.08,181.79 52.74,171.45 43.9,171.45 42.81,170.36 40.96,170.36 37.28,174.04 30.15,174.04 29.8,173.69 22.52,173.69 21.28,172.45 21.28,171.79 v3(21.06,171.58)
  L4 w0.127: v3(21.06,171.58) 21.31,171.33 21.31,170.49 26.14,165.67 34.65,165.67 39.92,160.39 39.92,159.02 44.29,154.65 44.29,124.14 41.23,121.08 41.23,79.92 38.9,77.6 38.9,74.2 30.51,65.82 30.51,56.65 34.43,52.73 34.43,50.33 34.73,50.03 34.73,44.88 32,42.15 32,32.55 36.62,27.93 36.62,25.21 v3(36.38,24.97)
  BOTTOM w0.102: v4(73.7,169.4) 73.7,169.19 v2(73.27,168.76)
HSI_LAN_DN1_R: length 5.5
  TOP w0.102: 34.47,17.17 34.47,16.43 34.79,16.11 34.94,15.95 35.11,15.95 35.2,15.86 U16.18 ; 34.47,17.17 34.47,17.72 34.91,18.17 34.91,19.28 C1808.1 ; 34.47,17.17 v1(34.07,17.17)
HSI_LAN_DP1: length 248.2
  TOP w0.102: v4(74.5,169.4) CPU1.T6 ; C1805.2 35.13,20.85 35.13,21.6 36.86,23.32 36.86,24.63 v3(37.19,24.97)
  L3 w0.127: v4(74.5,169.4) 73.81,168.71 71.82,168.71 71.2,169.33 71.12,169.41 71.12,171.21 67.84,174.49 67.84,176.04 66.58,177.3 66.58,179.3 64.36,181.52 63.19,181.52 52.85,171.18 44.01,171.18 42.92,170.09 40.85,170.09 37.17,173.78 30.26,173.78 29.91,173.43 22.64,173.43 21.55,172.34 21.55,171.86 v3(21.83,171.58)
  L4 w0.127: v3(21.83,171.58) 21.58,171.33 21.58,170.61 26.25,165.94 34.76,165.94 40.19,160.51 40.19,159.13 44.56,154.76 44.56,124.03 41.49,120.97 41.49,79.81 39.16,77.49 39.16,74.09 30.78,65.71 30.78,56.76 34.7,52.84 34.7,50.44 35,50.14 35,44.77 32.27,42.04 32.27,32.66 36.89,28.04 36.89,25.27 v3(37.19,24.97)
  BOTTOM w0.102: v2(38.13,24.96) 38.13,24.97 v3(37.19,24.97)
HSI_LAN_DP1_R: length 5.1
  TOP w0.102: 35.13,18.54 35.13,18.08 34.68,17.63 34.68,16.52 35.03,16.17 35.11,16.17 35.2,16.26 U16.17 ; 35.13,18.54 v1(35.49,18.54) ; 35.13,18.54 35.13,19.28 C1805.1
HSO_C_BLAN_DN1: length 10.6
  TOP w0.102: CPU1.R3 71.48,170.82 71.11,170.82 71.03,170.9 70.74,170.9 70.71,170.88 70.29,170.88 70.26,170.9 69.16,170.9 68.49,171.58 68.49,172.39 67.28,173.6 67.28,175.68 67.03,175.93 66.62,175.93 66.55,175.86 66.55,175.18 66.42,175.06 66.01,175.06 65.88,175.18 C45.1
HSO_C_BLAN_DP1: length 11
  TOP w0.102: v1(66.91,176.5) 66.91,176.15 ; 66.91,176.15 67.11,176.15 67.49,175.77 67.49,173.69 68.7,172.48 68.7,171.67 69.25,171.12 70.35,171.12 70.37,171.1 70.63,171.1 70.65,171.12 71.11,171.12 71.2,171.03 71.69,171.03 72.13,170.6 CPU1.R4 ; 66.91,176.15 C44.1
HSO_C_DN3: length 124.2
  TOP w0.102: C41.2 63.86,177.04 v3(63.4,177.5) ; v3(102.93,212.09) R1714.2
  L3 w0.127: v3(63.4,177.5) 63.2,177.7 62.59,177.7 54.01,169.11 49.01,169.11 47.31,167.41 41.99,167.41 41.98,167.43 v3(41.54,167.43)
  BOTTOM w0.102: v3(102.93,212.09) 103.33,211.69 103.56,211.69 103.79,211.46 103.79,210.57 99.93,206.71 83.88,206.71 81.14,203.96 79.33,203.96 ; 79.33,203.96 69.57,203.96 66.75,201.14 54.59,201.14 51.89,198.44 51.89,188.75 47.8,184.66 47.8,182.29 41.65,176.15 41.65,173.72 40.69,172.76 40.69,170.7 41.65,169.74 41.65,167.54 v3(41.54,167.43) ; 79.33,203.96 v2(79.33,203.61)
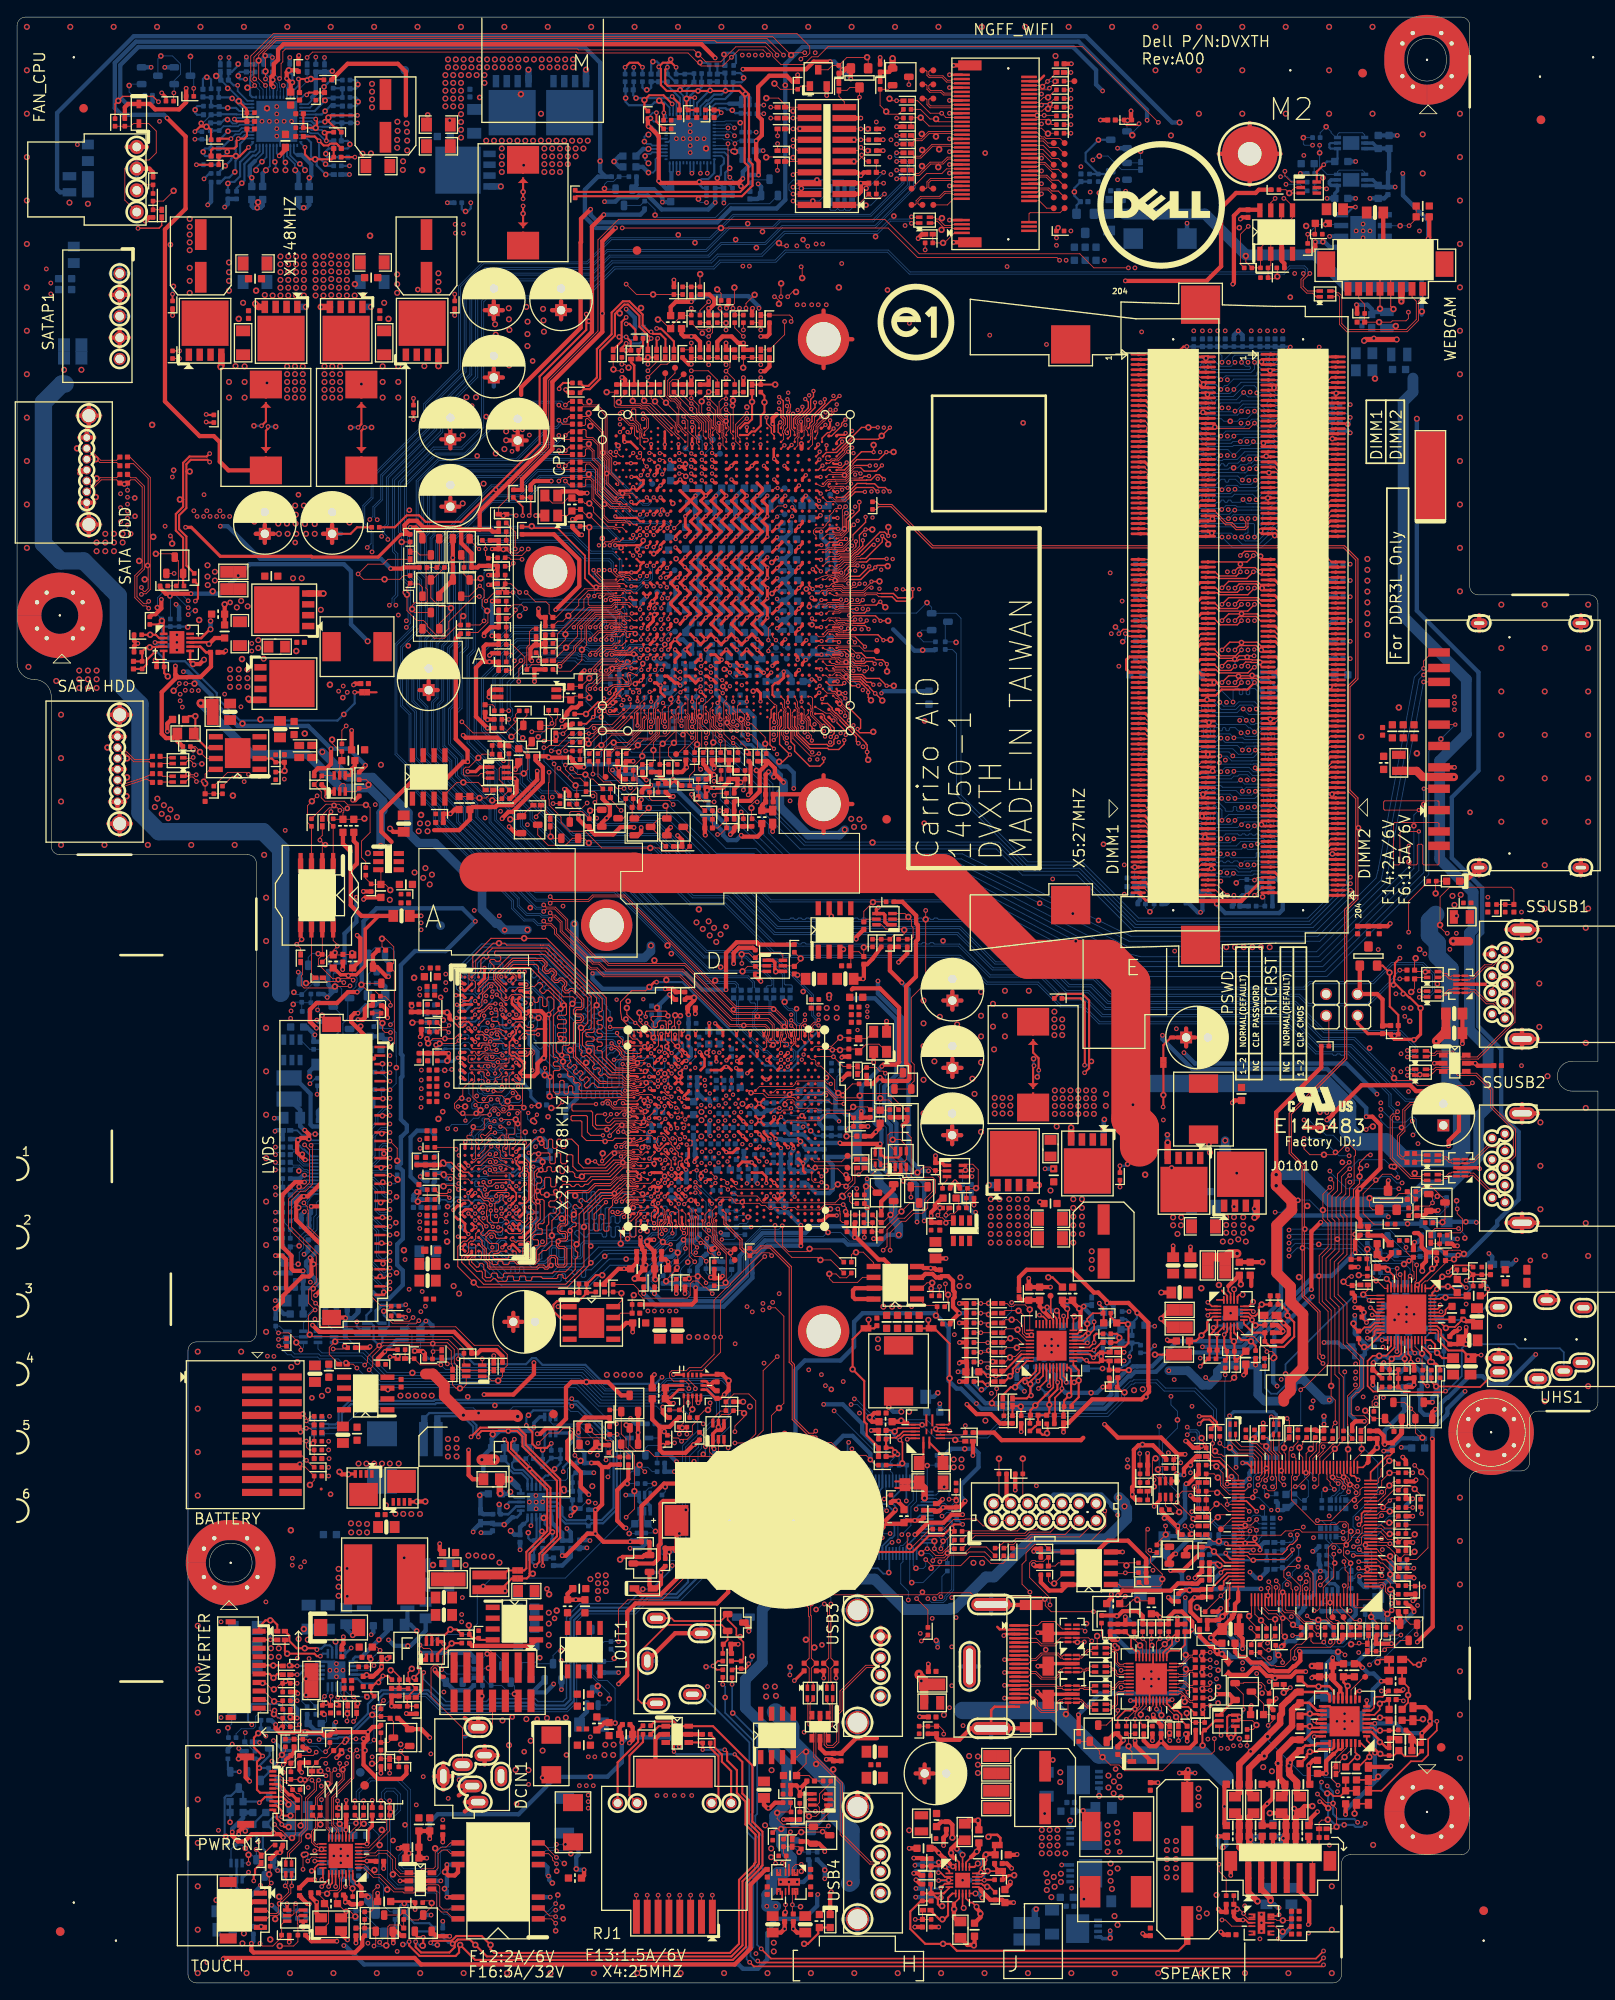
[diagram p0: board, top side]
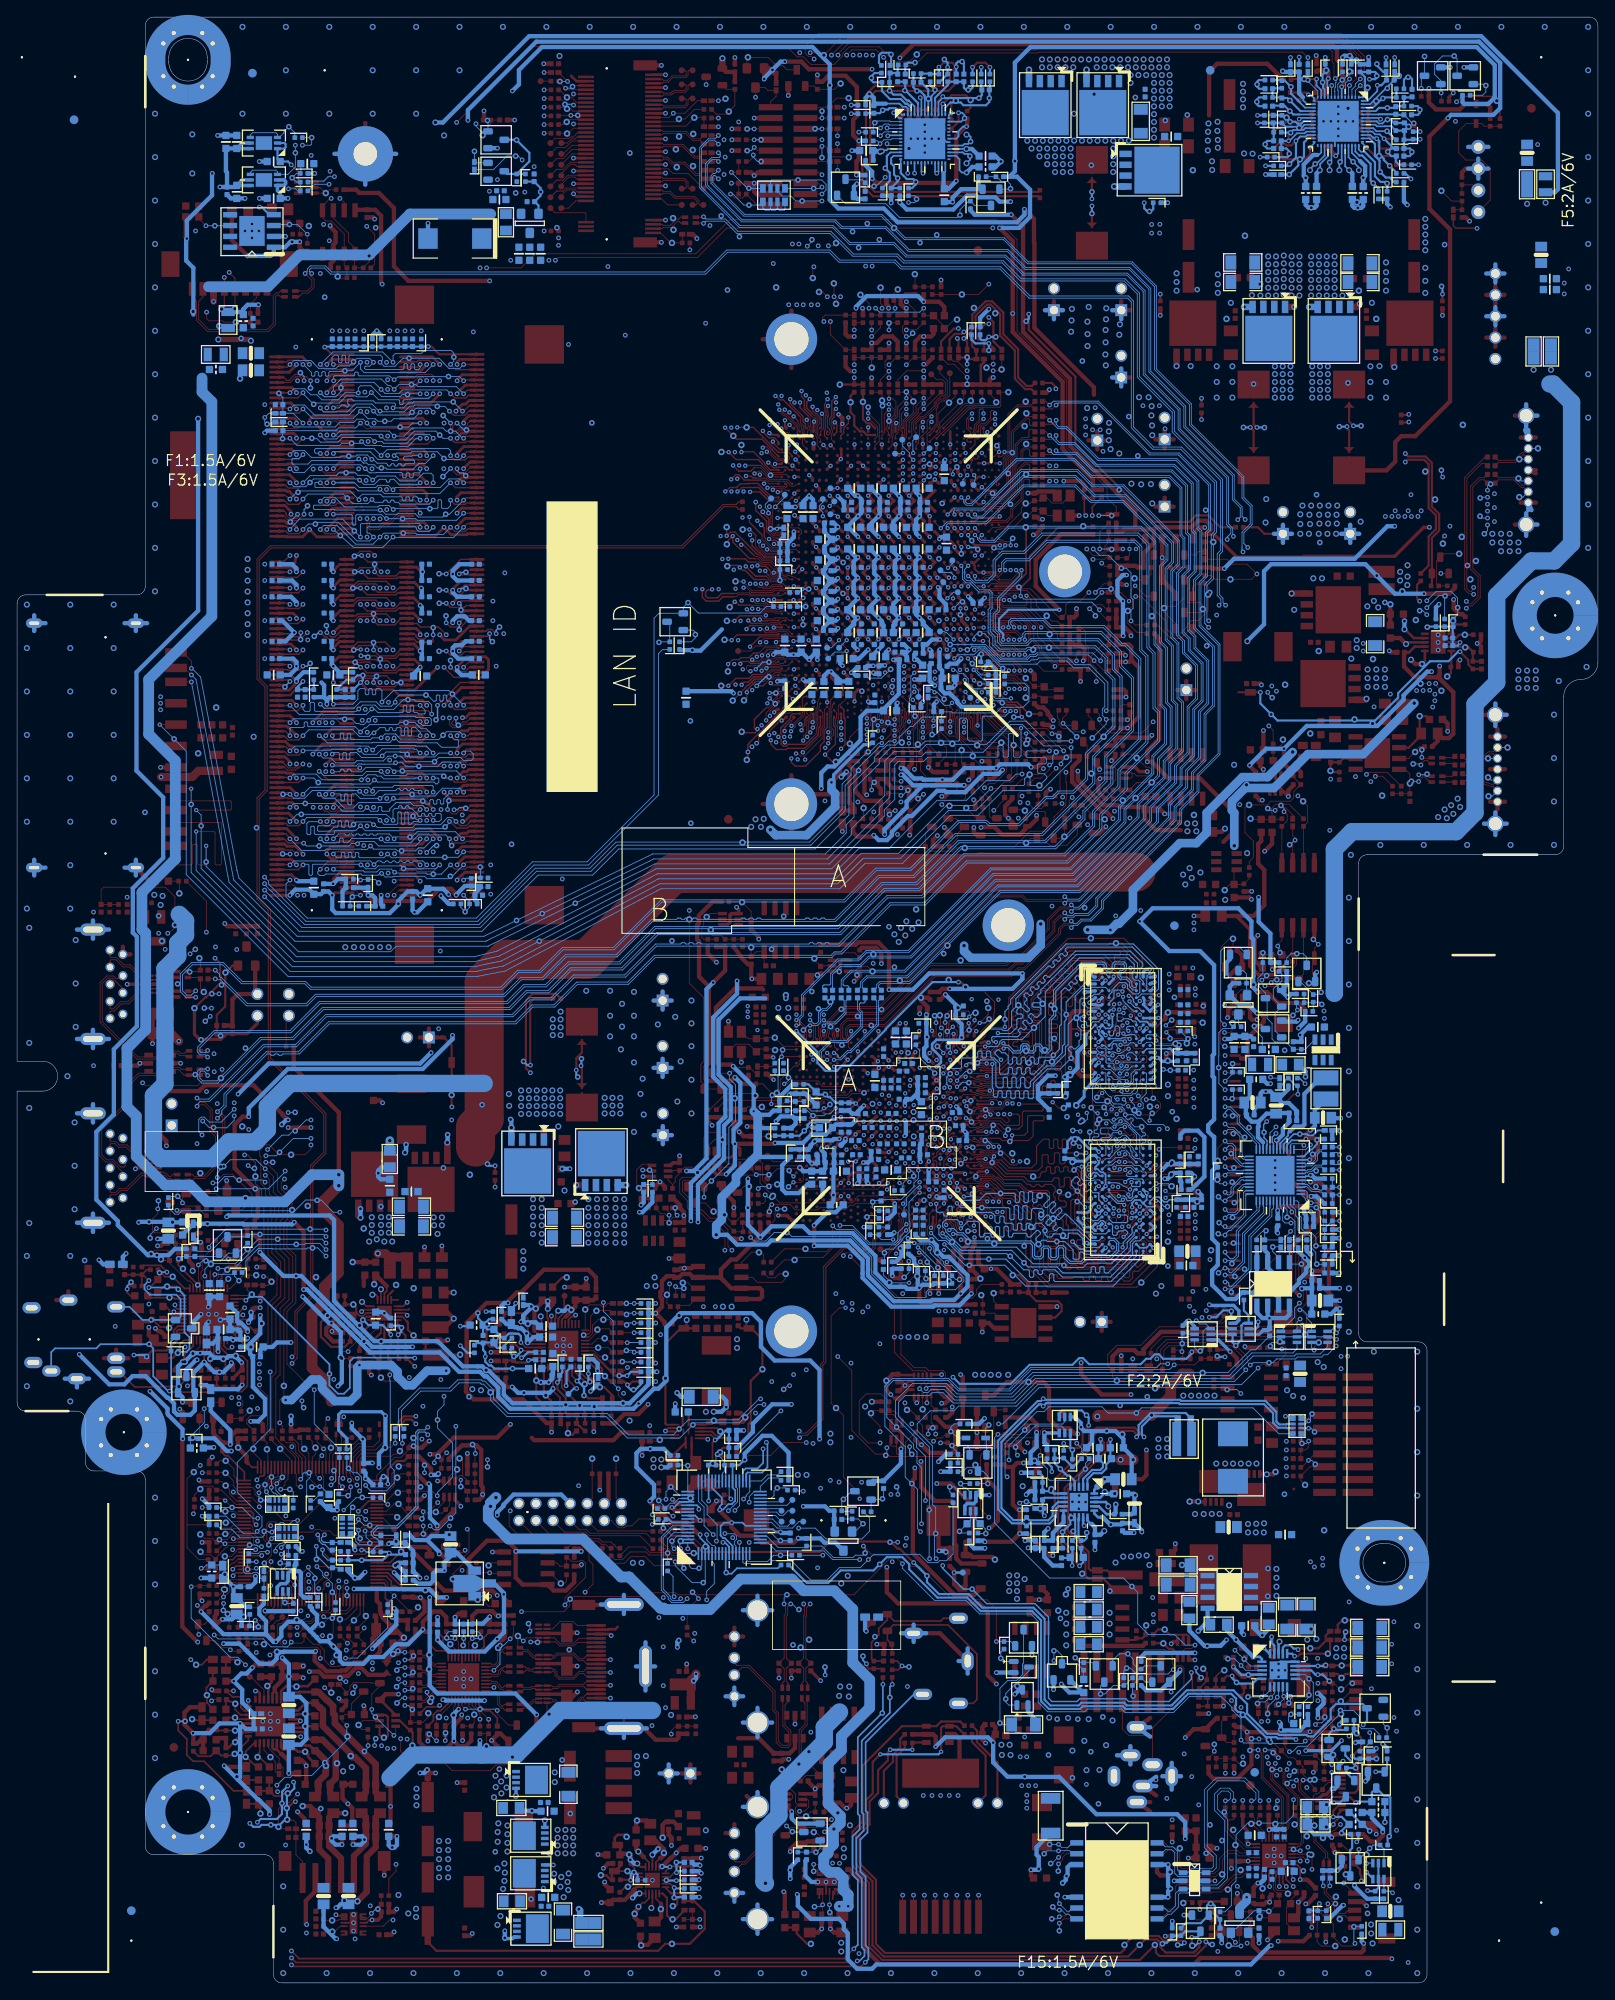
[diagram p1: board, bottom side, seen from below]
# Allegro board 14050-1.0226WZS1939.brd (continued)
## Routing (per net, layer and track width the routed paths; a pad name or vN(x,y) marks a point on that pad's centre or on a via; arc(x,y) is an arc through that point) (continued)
HSO_C_DP3: length 124.2
  TOP w0.102: v3(102.93,211.07) R1713.2 ; v3(64.16,177.5) 64.6,177.93 C42.2
  L3 w0.127: v3(40.98,167.94) 41.84,167.94 42.1,167.68 47.2,167.68 48.9,169.38 53.89,169.38 62.48,177.97 63.69,177.97 v3(64.16,177.5)
  BOTTOM w0.102: v3(40.98,167.94) 41.44,168.4 41.44,169.65 40.47,170.61 40.47,172.85 41.44,173.81 41.44,176.24 47.58,182.38 47.58,184.75 51.67,188.84 51.67,198.53 54.5,201.36 66.66,201.36 69.48,204.18 77.38,204.18 ; v3(102.93,211.07) 103.33,211.47 103.47,211.47 103.58,211.37 103.58,210.66 99.84,206.92 83.79,206.92 81.05,204.18 77.38,204.18 ; v2(77.38,204.52) 77.38,204.18
HSO_C_LAN_DN1: length 231.2
  TOP w0.102: v3(38.95,27.25) 39.19,27.01 39.19,24.07 36.82,21.71 36.82,18.43 37.37,17.88 37.37,17.63 37.28,17.53 U16.14 ; v3(64.16,175.72) 64.62,175.26 C45.2
  L3 w0.127: v3(64.16,175.72) 63.35,176.53 62.22,176.53 54.33,168.64 49.2,168.64 47.5,166.94 41.11,166.94 40.2,167.85 28.23,167.85 27.13,168.96 26.18,169.9 26.18,171.6 25.42,172.36 24.61,172.36 24.38,172.12 24.38,171.84 v3(24.11,171.58)
  L4 w0.127: v3(24.11,171.58) 24.26,171.43 24.26,169.44 26.69,167 35.22,167 41.26,160.97 41.26,159.57 45.63,155.2 45.63,123.59 42.56,120.52 42.56,77.93 40.38,75.75 40.38,73.59 37.21,70.42 37.21,69.2 36.13,68.13 34.71,68.13 31.85,65.26 31.85,57.29 35.77,53.37 35.77,50.88 36.07,50.58 36.07,38.12 34.09,36.14 34.09,32.54 38.95,27.69 v3(38.95,27.25)
  BOTTOM w0.102: v3(38.95,27.25) 38.34,27.25 v2(38.01,26.92)
HSO_C_LAN_DP1: length 231
  TOP w0.102: v3(39.76,27.25) 39.4,26.9 39.4,23.98 37.04,21.62 37.04,18.52 37.59,17.97 37.59,17.63 37.68,17.53 U16.13 ; C44.2 63.83,176.15 v3(63.4,175.72)
  L3 w0.127: v3(63.4,175.72) 63.4,176.03 63.16,176.26 62.33,176.26 54.44,168.37 49.31,168.37 47.61,166.67 41,166.67 40.09,167.59 28.12,167.59 26.94,168.77 25.92,169.79 25.92,171.49 25.31,172.09 24.72,172.09 24.64,172.01 24.64,171.81 v3(24.87,171.58)
  L4 w0.127: v3(24.87,171.58) 24.52,171.23 24.52,169.55 26.8,167.27 35.33,167.27 41.52,161.08 41.52,159.68 45.89,155.31 45.89,123.48 42.83,120.41 42.83,77.82 40.64,75.64 40.64,73.48 37.47,70.31 37.47,69.09 36.24,67.86 34.82,67.86 32.12,65.15 32.12,57.4 36.03,53.48 36.03,50.99 36.33,50.69 36.33,38.01 34.36,36.03 34.36,32.65 v3(39.76,27.25)
  BOTTOM w0.102: v2(40.72,27.2) 40.67,27.25 v3(39.76,27.25)
ICH_RSMRST_N_R: length 4.2
  TOP w0.102: U109.82 140.96,51.98 v1(140.65,51.66) 139.95,51.66 R374.2
ILIM_R: length 48.1
  TOP w0.254: PR4620.1 22.7,216.8 22.33,217.17 v1(22.16,217.17) 22.14,217.18 21.39,217.18 v3(20.81,216.6) ; PR4637.2 22.19,183.45 v3(22.13,183.51)
  L3 w0.254: v3(20.81,216.6) 21,216.41 22.98,216.41 23.99,215.4 23.99,211.57 21.66,209.25 19.79,209.25 17.5,206.95 17.5,185.48 19.59,183.39 22,183.39 v3(22.13,183.51)
  BOTTOM w0.254: PR4619.2 v3(20.81,216.6)
ILIMNB_R: length 52.2
  TOP w0.254: v3(39.83,218.5) 36.69,218.5 36.43,218.25 v1(36.43,218.24) 36.43,217.81 37.17,217.07 37.41,217.07 PR4644.1 ; PR4639.2 v3(46.39,185.39)
  L3 w0.254: v3(39.83,218.5) 37.75,216.42 37.75,211.24 38.56,210.44 41.36,210.44 44.54,207.26 51.75,200.06 51.75,189.14 48,185.39 v3(46.39,185.39)
  BOTTOM w0.254: PR4640.2 v3(39.83,218.5)
IMS: length 213.1
  TOP w0.102: R79661.2 42.58,113.47 R79659.1 42.4,113.25 42.4,112.65 v1(42.76,112.3) 42.76,111.51 43.06,111.2 v3(43.7,111.2) ; v3(153.68,39.88) 154.08,40.28 R79691.1 ; LVDS1.4 v3(43.63,106.5)
  L3 w0.127: v3(43.63,106.5) 44.1,106.03 44.1,85.45 44.66,84.89 44.66,84.32 45.15,83.83 46.48,83.83 51.05,79.26 52.27,79.26 55.33,82.32 68.99,82.32 70.87,84.2 73.19,84.2 73.92,83.47 85.65,83.47 88.98,80.14 89.39,80.14 91.73,82.47 104.78,82.47 105.35,81.9 105.35,80.53 106.93,78.96 108.47,78.96 108.72,78.7 109.68,77.74 v3(109.68,75.84) ; v3(140.89,27.45) 140.84,27.39 138.85,27.39 137.41,28.83 130.16,28.83 129.7,29.29 128.34,29.29 128.19,29.44 117.81,29.44 116.1,31.14 111.74,31.14 v3(110.7,30.1)
  L4 w0.127: v3(110.7,30.1) 110.7,33.68 110.13,34.25 110.13,41.77 110.94,42.58 110.95,42.58 111.37,43.01 111.37,43.61 111.29,43.7 111.29,53.36 113.43,55.5 113.43,56.45 113.95,56.97 113.95,67.61 111.64,69.93 111.64,74.25 110.04,75.84 v3(109.68,75.84) ; v3(43.7,111.2) 43.16,110.67 43.16,106.73 43.39,106.5 v3(43.63,106.5) ; v3(153.68,39.88) 153.68,39.78 153.83,39.62 153.83,38.59 153.49,38.24 153.49,37.85 153.83,37.51 153.83,37.08 147.63,30.89 143.7,30.89 140.89,28.09 v3(140.89,27.45)
INIT_3V: length 5.5
  TOP w0.102: v1(114.9,61.34) R1699.2 114.9,56.72 LPC1.2
IO_SMI_N: length 273.4
  TOP w0.102: CPU1.BB13 79.8,148.53 80.1,148.23 80.1,147.97 80.02,147.89 80.02,146.91 v4(80.63,146.3) ; v3(164.63,46.35) 164.56,46.42 R313.2 163.55,46.48 R80223.1
  L3 w0.127: v3(158.28,37.21) 157.85,37.63 157.85,38.48 157.2,39.13 156.14,39.13 155.83,39.43 153.9,39.43 153.87,39.41 152.72,39.41 152.57,39.56 149.15,39.56 146.87,37.27 144.65,37.27 143.61,36.23 143.22,36.23 140.01,39.45 139.36,39.45 137.93,38.01 121.89,38.01 121.68,38.23 118.19,38.23 117.2,39.22 113.97,39.22 112.56,40.63 105.96,40.63 v3(105.7,40.89) ; v3(155.98,93.69) 157.42,95.13 157.42,103.29 151.78,108.93 151.78,111.51 148.34,114.95 133.46,114.95 121.41,126.99 120.45,126.99 118.39,129.05 91.8,129.05 88.57,132.28 87.02,132.28 85.49,133.8 83.37,133.8 83,134.17 83,134.44 81.91,135.53 81.55,135.53 80.59,136.48 80.59,136.62 80.51,136.71 79.83,137.39 79.83,139.51 79.14,140.2 79.14,143.73 79.57,144.17 79.57,145 79.88,145.31 79.88,145.55 v4(80.63,146.3)
  L4 w0.127: v3(100.47,51.54) 100.47,51.2 100.87,50.8 101.54,50.8 104.8,47.54 104.8,44.76 105.7,43.86 v3(105.7,40.89) ; v3(162.09,93.6) 162.62,93.07 162.62,90.42 159.28,87.08 159.28,77.22 158.49,76.43 158.49,75.24 158.13,74.89 158.13,59.4 158.17,59.37 158.17,57.62 156.94,56.39 155.99,56.39 155.57,55.97 155.57,54.96 156.18,54.35 156.18,51.74 155.23,50.79 155.23,50.2 155.51,49.92 155.63,49.92 156.12,49.44 156.12,47.31 156.16,47.26 156.16,44.03 156.46,43.73 156.46,38.01 156.88,37.59 157.89,37.59 v3(158.28,37.21)
  BOTTOM w0.102: v3(164.63,46.35) 164.63,42.67 160.05,38.1 159.16,38.1 v3(158.28,37.21) ; v3(155.98,93.69) 156.23,93.93 v2(159.01,93.93) 159.27,93.93 159.67,94.34 160.71,94.34 161.45,93.6 v3(162.09,93.6) ; v3(100.47,51.54) U4101.13
ISEN1: length 7.8
  TOP w0.254: R51.2 31.86,40.63 31.86,40.01 32.71,39.15 v1(33.66,39.15) 34.92,39.15 v3(35.09,38.99)
  BOTTOM w0.254: U120.17 36.87,39.24 36.61,39.5 36,39.5 35.62,39.12 35.21,39.12 v3(35.09,38.99)
ISEN2: length 6.7
  TOP w0.254: R53.2 31.34,38.85 31.61,38.58 v1(31.61,38.52) 34.79,38.52 35.09,38.23 v3(35.49,38.23)
  BOTTOM w0.254: v3(35.49,38.23) 35.78,38.52 36.36,38.52 U120.16
ISEN3: length 4.4
  TOP w0.254: R56.2 v3(32.77,37.08)
  BOTTOM w0.254: U120.14 33.87,37.08 33.86,37.08 v3(32.77,37.08) 31.94,37.08 v2(31.86,37.16)
ISEN4: length 5.3
  TOP w0.254: R59.2 v3(32.77,36.07)
  BOTTOM w0.254: U120.13 34.41,36.58 34.41,36.57 33.55,36.57 33.05,36.07 v3(32.77,36.07) 32.19,36.07 v2(31.43,35.31)
ISET: length 4.4
  TOP w0.102: U118.34 132.14,32.38 131.5,31.75 v1(131.5,31.39) 131.5,30.39 R1596.2 R2086.1
ISP_CLK1: length 7.4
  TOP w0.102: v3(33.21,74.04) 33.21,74.4 v1(32.67,74.93) 32.67,75.18 31.81,76.05 v3(30.59,76.05)
  BOTTOM w0.102: Q7.3 33.51,74.35 v3(33.21,74.04) ; Q7.6 31.3,76.24 30.7,76.85 R1860.2 30.26,76.38 v3(30.59,76.05)
ISP_DAT1: length 10.8
  TOP w0.102: v3(36.99,74.17) 38.53,74.17 R57.2
  L3 w0.127: v3(34.86,77.67) 35.21,77.32 35.21,75.95 v3(36.99,74.17)
  BOTTOM w0.102: v3(36.99,74.17) 38.11,74.17 38.34,74.4 v2(38.34,74.5) 38.34,74.75 38.15,74.94 Q4.3 ; Q4.6 35.21,77.32 v3(34.86,77.67)
ISW: length 16.6
  TOP w0.508: C10.1 38.01,39.5 38.18,39.67 v3(38.18,40.49)
  L3 w0.508: v3(38.18,40.49) 39.1,41.4 42.2,41.4 v3(43.47,40.13)
  BOTTOM w0.254: v3(38.18,40.49) 38.18,39.78 37.87,39.46 U120.19
  BOTTOM w0.508: v3(43.47,40.13) 44.15,39.45 45.7,39.45 v2(45.73,39.42) 46.02,39.42 47.81,41.21 R79630.2
ISW_1:
  vias: v2(45.3,49.73)
JACK_PSID: length 38.4
  TOP w0.102: DCIN1.3 52.12,28.96 ; 52.12,28.96 52.12,29.82 48.45,33.5 48.45,36.84 48.71,37.11 49.23,37.11 v3(49.69,36.65) 49.69,37.21 49.82,37.34 49.82,38.23 50.25,38.66 50.4,38.66 50.75,39 55.21,39 55.64,38.57 DCIN2.4 ; 52.12,28.96 54.9,28.96 55.64,29.7 55.64,30.84 55.64,30.84 DCIN2.11
  BOTTOM w0.102: L15.1 55.48,36.5 v2(55.15,36.83) 54.7,36.83 54.01,36.14 50.3,36.14 49.79,36.65 v3(49.69,36.65)
JDREF: length 4.8
  TOP w0.203: U6.35 164.39,74.53 164.65,74.27 164.69,74.27 164.87,74.08
  TOP w0.254: 164.87,74.08 165.44,73.52 165.44,72.74 v1(165.37,72.67) 165.6,72.44 166.07,72.44 166.53,71.98 R268.1
JENK#: length 4
  BOTTOM w0.102: U4101.28 94.9,55.88 TP4125.1
JTAG_TCK_VGA: length 8.9
  TOP w0.102: v3(80.65,84.43) 80.09,84.99 79.32,84.99 78.93,85.38 78.93,89.27 GPU1.L3
  BOTTOM w0.102: v3(80.65,84.43) 80.65,83.6 R963.1 80.61,83.12 v2(81.19,82.55)
JTAG_TDI_VGA: length 9.7
  TOP w0.102: v4(79.57,86.05) 79.13,86.48 79.13,89.32 78.98,89.65 78.98,90.42 GPU1.L5
  BOTTOM w0.102: v4(79.57,86.05) 79.45,86.05 77.25,83.85 v2(77.25,83.69) 76.61,83.06 R1892.1
JTAG_TDO_VGA: length 10.2
  TOP w0.102: GPU1.K4 78.26,89.94 78.26,88.71 78.45,88.51 78.45,87.56 78.24,87.35 78.24,85.95 v3(78.21,85.93)
  BOTTOM w0.102: v2(74.71,82.3) 75.15,82.3 R1895.1 75.6,82.87 78.14,85.41 78.14,85.85 v3(78.21,85.93)
JTAG_TMS_VGA: length 7.4
  TOP w0.102: GPU1.L1 78.65,89.15 78.65,85.02 v3(79.3,84.37)
  BOTTOM w0.102: v2(78.65,82.4) 78.71,82.46 R398.1 78.71,83.78 v3(79.3,84.37)
JTAG_TRST#_VGA: length 10.9
  TOP w0.102: v4(78.07,91.11) 78.11,91.11 GPU1.L6
  L3 w0.127: v4(78.07,91.11) 77.56,90.6 77.56,87.42 78.87,86.11 78.87,86.01 v4(79.43,85.45)
  BOTTOM w0.102: R1893.1 77.63,83.36 77.76,83.48 77.76,83.59 v2(78.49,84.33) 78.52,84.35 78.52,84.71 79.2,85.39 79.37,85.39 v4(79.43,85.45)
KBCLK: length 5.3
  TOP w0.102: U109.78 144.42,53.58 v3(145.07,54.23)
  BOTTOM w0.102: v2(143.72,53.54) 144.38,53.54 v3(145.07,54.23) 145.07,53.98 145.33,53.72 RN10.3
KBRST_N: length 165
  TOP w0.102: v3(154.16,57.74) 154.16,57.76 153.66,58.26 153.66,58.59 153.3,58.95 153.3,59.51 153.25,59.55 U109.42 ; CPU1.AY15 80.76,149.86 80.68,149.86 80.3,149.48 80.3,148.32 80.31,148.31 80.31,147.89 80.22,147.8 80.22,147.29 81.03,146.47 81.03,146.08 v4(80.63,145.67)
  L3 w0.127: v4(80.63,145.67) 79.95,145 79.95,144.01 79.52,143.57 79.52,140.36 80.21,139.67 80.21,137.54 80.77,136.98 80.98,136.78 80.98,136.64 81.71,135.91 82.02,135.91 82.71,135.91 83.83,134.79 85.05,134.79 87.18,132.66 88.73,132.66 91.96,129.43 118.55,129.43 120.61,127.37 121.57,127.37 133.61,115.33 148.5,115.33 152.16,111.67 152.16,109.22 158.41,102.97 v3(159.59,102.97)
  L4 w0.127: v3(159.59,102.97) 160.43,102.13 160.43,95.5 159.37,94.44 159.37,90.51 156.18,87.32 156.18,86.79 155.48,86.09 155.48,85.01 155.7,84.8 155.7,82.31 156.47,81.53 156.47,80.89 155.7,80.12 155.7,79.8 155.7,77.75 156.18,77.27 156.18,71.56 155.1,70.48 155.1,64.51 154.73,64.14 154.73,59.58 154.11,58.95 154.11,57.81 154.16,57.76 v3(154.16,57.74)
  BOTTOM w0.102: R1845.1 152.69,57.45 152.98,57.74 v2(153.09,57.74) v3(154.16,57.74)
KDAT: length 4.9
  TOP w0.102: v3(144.2,54.24) 144.19,54.24 143.93,53.98 U109.77
  BOTTOM w0.102: v2(145.73,55.65) 145.73,55.55 145.98,55.3 RN10.4 145.8,54.37 145.45,54.72 144.69,54.72 v3(144.2,54.24)
LAD0_FWH0: length 210
  TOP w0.102: v4(79,145.69) 78.39,146.3 78.39,147.85 78.5,147.96 78.5,148.23 78.2,148.53 CPU1.BB11 ; U109.38 154.85,59.61 155.08,59.39 155.08,59.39 155.36,59.11 155.37,59.11 155.63,58.84 155.63,58.64 156.69,57.58 v3(156.69,57.35) ; LPC1.5 117.07,52.88 110.64,52.88 R79703.2
  L3 w0.127: v3(156.69,57.35) 156.65,57.35 156.29,56.99 155.66,56.99 154.14,55.47 151.34,55.47 150.71,54.84 146.41,54.84 145.32,53.75 140.59,53.75 139,52.15 133.92,52.15 132.48,53.59 130.05,53.59 129.34,52.87 127.86,52.87 127.31,52.33 122.41,52.33 121.49,53.24 119.13,53.24 LPC1.5 ; v4(79,145.69) 79,145.42 78.81,145.23 78.81,144.97 77.49,143.65 77.49,140.28 78.32,139.46 78.32,138.03 79.98,136.37 79.98,136.23 81.47,134.75 81.47,134.14 83.01,132.6 85.13,132.6 89.79,127.94 117.93,127.94 119.99,125.88 120.96,125.88 133,113.84 147.88,113.84 150.67,111.05 150.67,108.44 155.42,103.69 155.42,98.7 155.16,98.44 155.16,89.79 154.67,89.29 154.67,80.6 154.63,80.56 154.63,75.64 154.67,75.6 154.67,74.83 156.65,72.85 v3(156.65,72.43)
  L4 w0.127: v3(156.69,57.35) 156.34,57.7 156.34,59.73 156.4,59.78 156.4,68.96 157.12,69.68 157.12,71.96 v3(156.65,72.43)
  BOTTOM w0.102: RN7.4 v2(156.5,56.49) 156.69,56.69 v3(156.69,57.35)
LAD0_FWH0_EC: length 5.8
  TOP w0.102: v3(108.11,50.8) 108.11,51.24 R79703.1
  BOTTOM w0.102: U4101.62 107.77,52.28 v2(108.36,51.69) 108.36,51.05 v3(108.11,50.8)
LAD1_FWH1: length 212.2
  TOP w0.102: U109.39 154.45,59.28 154.58,59.16 154.92,59.16 155.35,58.72 155.35,58.52 155.74,58.14 155.74,57.54 v3(155.81,57.46) ; R79702.2 111.37,52.6 117.93,52.6 118.35,53.02 119.21,53.02 LPC1.7 ; v4(77.76,147.7) 77.76,147.7 77.76,149.26 CPU1.BA11
  L3 w0.127: LPC1.7 121.07,54.09 122.53,52.63 127.19,52.63 127.73,53.18 129.21,53.18 129.92,53.89 132.6,53.89 134.04,52.45 138.87,52.45 140.47,54.05 143.31,54.05 143.97,54.71 145.26,54.71 146.35,55.79 154.03,55.79 155.7,57.46 v3(155.81,57.46) ; v4(77.76,147.7) 77.19,147.13 77.19,145.72 75.24,143.77 75.24,138.74 78.29,135.69 78.31,135.67 78.31,135.53 79.05,134.79 79.05,133.72 81.85,130.92 84.44,130.92 89.98,125.38 102.55,125.38 103.12,125.95 117.55,125.95 119.29,124.21 120.26,124.21 132.3,112.17 147.19,112.17 149,110.36 149,107.75 153.75,103 153.75,99.39 152.85,98.5 152.85,92.37 153.72,91.5 153.72,80.95 153.72,80.94 153.72,75.26 153.75,75.22 153.75,73.79 155.99,71.56 155.99,70.6 v3(156.62,69.96)
  L4 w0.127: v3(156.62,69.96) 156.09,69.43 156.09,59.91 155.9,59.71 155.9,57.69 155.81,57.61 v3(155.81,57.46)
  BOTTOM w0.102: v2(155.99,58.29) 155.99,57.63 v3(155.81,57.46) 155.81,57.36 155.48,57.02 154.95,57.02 154.84,56.92 RN7.3
LAD1_FWH1_EC: length 6.2
  TOP w0.102: v1(107.35,51.69) v3(107.35,50.8) 107.86,50.29 108.25,50.29 109.7,51.74 R79702.1
  BOTTOM w0.102: v3(107.35,50.8) 107.5,50.95 107.5,51.79 107.41,51.88 U4101.63
LAD2_FWH2: length 210.5
  TOP w0.102: v4(79,146.33) 78.59,146.74 78.59,147.77 78.71,147.88 78.71,148.31 78.5,148.51 78.5,150.2 CPU1.AY11 ; R79701.2 112.11,52.32 118.05,52.32 118.47,52.74 120.93,52.74 LPC1.9 ; U109.40 154.05,59.28 154.46,58.88 154.8,58.88 155.07,58.6 155.07,58.39 155.25,58.22 v3(155.25,57.97)
  L3 w0.127: LPC1.9 123.43,52.94 127.06,52.94 127.61,53.48 129.08,53.48 129.8,54.2 132.73,54.2 132.99,53.94 139.27,53.94 140.15,54.81 143,54.81 143.83,55.65 145.77,55.65 146.22,56.1 153.38,56.1 v3(155.25,57.97) ; v4(79,146.33) 78.58,145.91 78.58,145.18 77.19,143.78 77.19,140.16 78.01,139.33 78.01,137.91 79.68,136.24 79.68,136.1 81.16,134.62 81.16,134.01 82.88,132.3 85,132.3 89.66,127.64 117.8,127.64 119.86,125.58 120.83,125.58 132.87,113.54 147.76,113.54 150.37,110.93 150.37,108.32 155.12,103.57 155.12,98.83 154.86,98.57 154.86,89.92 154.36,89.42 154.36,80.72 154.33,80.69 154.33,75.51 154.36,75.47 154.36,74.05 156.45,71.96 156.84,71.96 157.12,71.68 157.12,71.22 v3(156.62,70.72)
  L4 w0.127: v3(155.25,57.97) 155.59,58.32 155.59,59.84 155.79,60.04 155.79,69.89 v3(156.62,70.72)
  BOTTOM w0.102: v2(155.23,59.18) 155.23,57.99 v3(155.25,57.97) 155.25,57.58 154.97,57.3 154.78,57.3 154.34,56.87 RN7.2
LAD2_FWH2_EC: length 5.4
  TOP w0.102: v1(105.82,50.29) 105.82,50.29 106.33,50.8 v3(106.51,50.8) 106.7,50.8 107.49,50.01 108.36,50.01 109.15,50.8 R79701.1
  BOTTOM w0.102: U4101.64 v3(106.51,50.8)
LAD3_FWH3: length 207.7
  TOP w0.102: CPU1.BA13 79.8,149.74 v4(80.17,150.11) ; R79700.2 114.78,50.86 115.02,51.1 115.02,51.2 115.12,51.31 115.22,51.31 115.5,51.59 116.5,51.59 116.88,51.97 118.09,51.97 118.58,52.46 122.65,52.46 LPC1.11 ; U109.41 153.65,59.18 154.23,58.6 154.43,58.6 v3(154.61,58.42)
  L3 w0.127: v3(156.65,71.49) 156.51,71.63 156.35,71.63 154.06,73.92 154.06,75.35 154.02,75.38 154.02,80.81 154.03,80.82 154.03,91.62 153.16,92.49 153.16,94.18 153.51,94.53 153.82,94.53 154.1,94.8 154.1,98.88 154.36,99.14 154.36,103.25 149.61,108 149.61,110.61 147.44,112.78 132.55,112.78 120.51,124.82 119.55,124.82 117.49,126.88 89.35,126.88 84.69,131.53 82.1,131.53 79.66,133.97 79.66,135.04 78.92,135.79 78.92,135.92 77.25,137.59 77.25,139.02 75.86,140.4 75.86,143.54 78.12,145.8 78.12,146.41 78.4,146.69 78.4,147.6 80.17,149.36 v4(80.17,150.11) ; v3(154.61,58.42) 154.55,58.48 153.86,58.48 153.44,58.06 153.44,57.09 152.75,56.4 146.09,56.4 145.64,55.95 143.71,55.95 142.87,55.12 140.02,55.12 139.15,54.24 133.12,54.24 132.86,54.5 129.67,54.5 128.96,53.79 127.48,53.79 126.93,53.24 125.13,53.24 LPC1.11
  L4 w0.127: v3(154.61,58.42) 154.62,58.42 154.62,58.75 155.29,59.42 155.29,59.97 155.48,60.16 155.48,70.32 v3(156.65,71.49)
  BOTTOM w0.102: RN7.1 153.69,56.78 153.91,57 154.08,57 154.72,57.64 154.72,58.31 v3(154.61,58.42) 154.61,58.5 v2(153.96,59.16)
LAD3_FWH3_EC: length 11.9
  TOP w0.102: R79700.1 113.43,51 111.59,51 110.93,50.34 109.09,50.34 108.48,49.73 107.5,49.73 v3(107.17,49.4)
  BOTTOM w0.102: U4101.1 106.76,50.24 107.17,49.83 v3(107.17,49.4) 107.17,48.72 v2(106.97,48.51)
LAN_DISABLE_N: length 224.1
  TOP w0.102: CPU1.AH2 70.93,160.2 70.63,160.5 70.37,160.5 70.18,160.31 67.59,160.31 66.02,158.74 v4(66.02,158.6) 66.02,157.2 65.13,156.31 65.13,155.96 63.67,154.5 63.34,154.5 63.08,154.23 60.22,154.23 R1670.1 59.66,154.13 59.65,154.14 59.65,156.27 59.98,156.6 59.98,158.12 60.29,158.43 R777.2
  L3 w0.127: v4(66.02,158.6) 65.57,158.16 64.74,158.16 64.55,158.35 58.53,158.35 57.05,159.83 52.22,159.83 50.14,161.91 43.22,161.91 42.71,161.4 42.71,160.86 44.16,159.41 44.16,153.08 43.09,152.01 40.41,152.01 39.82,152.6 39.04,152.6 38.17,151.73 v3(38.17,151.73)
  L4 w0.127: v3(38.17,151.73) 38.17,149.13 37.79,148.76 37.79,139.33 38.51,138.6 38.51,135.99 38.26,135.73 38.26,134.5 38.26,134.19 38.26,133.87 38.26,123.29 40.64,120.91 40.64,81.78 37.52,78.66 37.52,73.69 29.7,65.87 29.7,56.6 33.85,52.46 33.85,50.08 34.11,49.82 34.11,45.37 31.4,42.66 31.4,29.41 31.75,29.07 31.75,28.74 33.95,26.54 34.89,26.54 35.55,25.88 35.55,24.14 36.08,23.62 36.08,21.89 v3(35.62,21.44)
  BOTTOM w0.102: v3(35.62,21.44) 35.62,19.61 36.53,18.69 v2(39.66,18.69) 40.98,18.69 42.35,17.32 42.35,11.91 42.9,11.37 42.9,9.06 43.63,8.32 R774.1
LAN_DISABLE_N_1: length 9.1
  BOTTOM w0.254: R1180.1 48.23,6.99 46.48,6.99 Q102.B 45.75,8.16 45.75,9.04 45.52,9.27 v2(45.32,9.27) 45.09,9.27 44.84,9.02 44.84,8.05 44.23,7.44 R774.2 C591.1
LAN_DISABLE_N_2: length 9.1
  TOP w0.254: Q101.B 46.55,5.68 46.9,5.33 v3(47.53,5.33) 47.53,4.4 v1(47.49,4.36)
  BOTTOM w0.254: v3(47.53,5.33) 46.9,5.33 46.52,5.71 Q102.C 48.29,6.03 R1180.2 R764.1 49.82,5.33 50.45,4.7 50.83,4.7 v2(50.96,4.57)
LAN_DISABLE_N_3: length 8.5
  TOP w0.102: Q100.C 44.86,7.94 R776.1 46.2,7.37 46.96,7.37 Q101.C 48.52,8.93 v1(48.52,9.35) 48.52,9.4 48.32,9.6 47.67,9.6 R775.2
LAN_DISABLE_N_4: length 13.3
  TOP w0.102: R776.2 C593.1 44.88,6.78 43.61,6.78 43.38,6.56 43.38,4.55 v1(43.21,4.38) 43.21,4.37 42.71,4.37 42.43,4.65 v3(42.43,4.75)
  BOTTOM w0.102: v3(42.43,4.75) 42.96,5.28 42.96,5.87 42.48,6.35 42.32,6.35 40.23,8.45 PC140.2 38.58,8.45 v2(38.51,8.38)
LAN_DISABLE_V3: length 6.7
  TOP w0.102: R1183.1 41.59,6.41 Q100.B 41.97,4.95 41.97,4.94 41.97,4.52 v3(41.77,4.32) ; R1183.1 C863.1 ; R1183.1 R1194.2
  BOTTOM w0.102: v2(43.16,4.39) 43.06,4.29 42.24,4.29 42.21,4.32 v3(41.77,4.32)
LAN_LEDACT_R#: length 7.8
  TOP w0.254: UR5.2 81.12,27.5 81.64,26.98 82.08,26.54 82.08,21.84 RJ1.10
LAN_MDI0_C_DN: length 27.9
  TOP w0.089: XF1.2 61.4,8.76 62.33,7.84 62.94,7.84 v3(63.03,7.75) ; RJ1.2 v3(80.1,10.27)
  L4 w0.102: v3(80.1,10.27) 80.32,10.27 80.69,9.89 80.69,7.72 79.09,6.12 66.73,6.12 65.45,7.4 63.37,7.4 v3(63.03,7.75)
  BOTTOM w0.089: v2(63.91,7.49) 63.28,7.49 v3(63.03,7.75)
LAN_MDI0_C_DP: length 27.8
  TOP w0.089: v3(63.03,6.99) 62.52,7.49 XF1.1 ; RJ1.1 v3(81.37,10.27)
  L4 w0.102: v3(63.03,6.99) 63.11,7.07 65.31,7.07 66.59,5.79 79.23,5.79 81.02,7.58 81.02,9.92 v3(81.37,10.27)
  BOTTOM w0.089: v3(63.03,6.99) v2(63.03,6.1)
LAN_MDI0_DN: length 16
  TOP w0.089: v1(41.82,13.21) 41.56,12.95 ; 41.56,12.95 41.82,12.7 42.52,12.7 44.23,10.99 U10.3 47.46,10.99 47.95,11.47 49.26,11.47 49.47,11.27 49.47,8.96 49.79,8.64 51.47,8.64 XF1.11 ; 41.56,12.95 40.66,13.86 U16.2
LAN_MDI0_DP: length 15.9
  TOP w0.089: XF1.12 51.09,7.49 50.29,8.29 49.65,8.29 49.12,8.82 49.12,10.67 48.81,10.99 U10.4 47.95,10.99 47.6,10.64 46.55,10.64 46.43,10.52 45.28,10.52 45.15,10.64 44.09,10.64 43.56,11.17 ; U16.1 40.57,13.46 41.67,12.36 42.38,12.36 43.56,11.17 ; 43.56,11.17 v1(43.31,10.92)
LAN_MDI1_C_DN: length 30.3
  TOP w0.089: v3(63.12,14.69) 62.14,15.67 62.14,15.75 61.5,16.38 XF1.6 ; RJ1.6 v3(75.02,10.27)
  L4 w0.102: v3(63.12,14.69) 63.34,14.47 64.77,14.47 65.64,13.6 65.64,8.9 67.23,7.32 76.35,7.32 77.02,7.98 77.02,9.23 76.43,9.81 75.47,9.81 v3(75.02,10.27)
  BOTTOM w0.089: v3(63.12,14.69) 63.2,14.69 63.91,13.97 v2(64.04,13.97)
LAN_MDI1_C_DP: length 29.9
  TOP w0.089: v3(63.12,13.92) 62.67,14.38 62.67,14.65 62.21,15.11 XF1.5 ; RJ1.3 v3(78.83,10.27)
  L4 w0.102: v3(78.83,10.27) 78.25,10.27 77.35,9.37 77.35,7.84 76.49,6.99 67.09,6.99 65.31,8.76 65.31,13.46 64.63,14.14 63.34,14.14 v3(63.12,13.92)
  BOTTOM w0.089: v2(63.15,13.08) 63.15,13.18 63.12,13.21 v3(63.12,13.92)
LAN_MDI1_DN: length 16.6
  TOP w0.089: 49.18,15.49 49.56,15.88 50.2,15.88 50.71,16.38 XF1.7 ; 49.18,15.49 v1(48.93,15.75) ; 49.18,15.49 48.93,15.24 48.93,13.59 48.69,13.35 47.42,13.35 46.84,12.77 45.98,12.77 U10.1 45.73,12.77 44.9,12.77 44.3,13.37 44.3,14.53 43.32,15.51 42.2,15.51 41.89,15.2 40.76,15.2 40.62,15.06 U16.5
LAN_MDI1_DP: length 16.5
  TOP w0.089: U16.4 40.7,14.66 40.9,14.86 42.03,14.86 42.34,15.17 43.18,15.17 43.96,14.39 43.96,13.23 44.23,12.95 ; XF1.8 50.74,15.11 50.33,15.53 49.71,15.53 49.27,15.1 49.27,13.45 48.84,13.01 48.67,13.01 U10.6 48.43,13.01 47.57,13.01 46.98,12.43 44.76,12.43 44.23,12.95 ; 44.23,12.95 v1(43.98,12.7)
LAN_MDI2_C_DN: length 24.5
  TOP w0.089: RJ1.5 v3(76.29,10.27)
  L3 w0.102: v3(63.03,9.27) 63.41,8.89 64.64,8.89 66.84,6.69 75.81,6.69 76.88,7.76 76.88,10.02 76.63,10.27 v3(76.29,10.27)
  BOTTOM w0.089: v2(63.28,10.29) 63.15,10.16 63.15,9.4 v3(63.03,9.27) 62.14,8.38 61.88,8.38 61.5,8.76 XF2.5
LAN_MDI2_C_DP: length 24.3
  TOP w0.089: RJ1.4 v3(77.56,10.27)
  L3 w0.102: v3(77.56,10.27) 77.21,9.92 77.21,7.62 75.95,6.36 66.7,6.36 64.5,8.56 63.08,8.56 v3(63.03,8.51)
  BOTTOM w0.089: XF2.6 61.37,7.49 61.92,8.04 62.28,8.04 62.75,8.51 v3(63.03,8.51) 63.41,8.51 v2(63.79,8.89)
LAN_MDI2_DN: length 25.6
  TOP w0.089: v3(42.58,21.31) PR5250.2
  BOTTOM w0.089: 43.69,16.66 43.69,12.33 44.57,11.45 47.53,11.45 47.99,10.99 U11.3 48.67,10.86 49.05,10.86 49.42,10.5 49.42,9.04 50.07,8.38 50.33,8.38 50.71,8.76 XF2.8 ; 43.69,16.66 v2(44,16.66) ; 43.69,16.66 43.69,19.02 44.86,20.19 44.86,22.1 44.18,22.79 43.14,22.79 42.66,22.31 42.66,21.39 v3(42.58,21.31)
LAN_MDI2_DN_R: length 6.8
  TOP w0.089: 42.95,17.64 41.11,15.8 40.6,15.8 40.55,15.86 U16.7 ; 42.95,17.64 43.25,17.94 43.25,18.97 43.15,19.08 42.68,19.08 42.58,19.18 PR5250.1 ; 42.95,17.64 v1(42.68,17.91)
LAN_MDI2_DP: length 25.6
  TOP w0.089: v3(43.59,21.31) PR5249.2
  BOTTOM w0.089: 43.95,19.76 43.35,19.16 43.35,12.19 44.43,11.11 45.73,11.11 U11.4 45.98,11.11 47.38,11.11 47.97,10.52 48.9,10.52 49.07,10.35 49.07,8.9 49.93,8.04 50.33,8.04 50.88,7.49 XF2.7 ; 43.95,19.76 v2(43.72,19.99) ; 43.95,19.76 44.52,20.34 44.52,21.96 44.03,22.44 43.28,22.44 43,22.17 43,21.58 43.27,21.31 v3(43.59,21.31)
LAN_MDI2_DP_R: length 6.8
  TOP w0.089: 42.17,16.38 43.59,17.8 PR5249.1 ; 42.17,16.38 41.25,15.46 U16.6 ; 42.17,16.38 v1(42.43,16.13)
LAN_MDI3_C_DN: length 24.3
  TOP w0.089: RJ1.8 v3(72.48,10.27)
  L3 w0.102: v3(63.12,16.21) 63.25,16.08 64.18,16.08 64.63,15.63 64.63,10.55 64.71,10.46 64.75,10.46 66.82,8.39 72.44,8.39 73.19,9.14 73.19,9.91 72.82,10.27 v3(72.48,10.27)
  BOTTOM w0.089: XF2.1 61.5,16.38 62.05,15.84 62.75,15.84 v3(63.12,16.21) v2(64.17,16.21)
LAN_MDI3_C_DP: length 25.1
  TOP w0.089: RJ1.7 v3(73.75,10.27)
  L3 w0.102: v3(73.75,10.27) 73.52,10.04 73.52,9.01 72.57,8.06 66.68,8.06 64.61,10.13 64.57,10.13 64.3,10.41 64.3,15.49 64.04,15.75 63.42,15.75 v3(63.12,15.45)
  BOTTOM w0.089: v2(64.8,15.11) 64.47,15.45 v3(63.12,15.45) 63.08,15.49 61.88,15.49 61.5,15.11 XF2.2
LAN_MDI3_DN: length 28.9
  TOP w0.089: PR5248.2 v3(39.53,21.31)
  BOTTOM w0.089: XF2.12 51.09,16.38 50.63,15.93 49.74,15.93 49.18,15.37 49.18,13.21 48.86,12.89 U11.1 47.99,12.89 47.53,13.35 45.25,13.35 45.01,13.59 45.01,14.77 45.63,15.39 ; v2(45.85,15.16) 45.63,15.39 ; 45.63,15.39 46.06,15.82 46.06,22.59 44.67,23.98 41.28,23.98 39.68,22.38 39.68,21.46 v3(39.53,21.31)
LAN_MDI3_DN_R: length 3.2
  TOP w0.089: PR5248.1 39.86,19.29 39.86,18.49 38.88,17.51 U16.10
LAN_MDI3_DP: length 28.9
  TOP w0.089: v3(40.55,21.31) PR5247.2
  BOTTOM w0.089: 45.71,18.49 45.71,15.96 44.67,14.92 44.67,13.45 45.1,13.01 45.73,13.01 U11.6 47.5,12.89 47.97,12.43 49.13,12.43 49.52,12.83 49.52,15.22 49.88,15.58 50.62,15.58 51.09,15.11 XF2.11 ; 45.71,18.49 v2(45.4,18.49) ; 45.71,18.49 45.71,22.45 44.53,23.64 41.43,23.64 40.03,22.24 40.03,21.53 40.24,21.31 v3(40.55,21.31)
LAN_MDI3_DP_R: length 3.6
  TOP w0.089: PR5247.1 40.2,19.28 40.2,18.62 ; 40.2,18.62 40.2,18.35 39.28,17.42 U16.9 ; 40.2,18.62 v1(40.57,18.62)
LAN_RSET: length 2.8
  TOP w0.102: U16.31 38.88,12.77 38.88,11.42 v1(39.25,11.05) 39.28,11.02 R412.2
LAN_XTALI: length 9.8
  TOP w0.102: X4.1 36.44,6.98 36.44,8.8 R407.2 35.97,9.68 35.28,10.38 C1800.1 36.18,10.54 v1(36.28,10.44) 36.28,10.46 36.61,10.79 37.45,10.79 37.74,11.08 37.74,12.21 37.68,12.26 U16.28
LAN_XTALO: length 8.3
  TOP w0.102: U16.29 38.08,12.26 37.96,12.15 37.96,10.94 C1799.1 37.31,9.46 R407.1 38.37,8.39 38.96,8.39 v1(39.58,7.77) 39.42,7.61 X4.3
LANCLK_REQ_N: length 320
  TOP w0.102: R1674.1 82.87,144.43 82.87,145.37 v4(82.31,145.92) 82.31,145.98 81.91,146.39 81.91,146.68 81.5,147.08 81.5,148 CPU1.BC15 ; R413.2 v3(37.5,21.31)
  L3 w0.127: v3(141.66,27.43) 141.64,27.43 141.13,27.94 140.72,27.94 140.43,27.65 138.95,27.65 137.52,29.08 130.27,29.08 129.66,29.69 129.34,29.69 129.19,29.54 128.44,29.54 128.29,29.69 117.91,29.69 116.21,31.39 111.33,31.39 109.81,29.88 101.59,29.88 99.13,32.33 93.22,32.33 90.59,29.71 67.46,29.71 65.29,31.88 49.51,31.88 46.4,28.77 46.4,25.9 42.86,22.35 38.54,22.35 v3(37.5,21.31) ; v4(82.31,145.92) 81.89,145.5 81.89,143.67 82.34,143.23 82.34,138.17 84.53,135.98 85.54,135.98 87.67,133.85 89.22,133.85 92.45,130.61 119.04,130.61 121.1,128.56 122.06,128.56 134.1,116.51 148.99,116.51 150.8,114.7 159.55,114.7 160.16,114.09 160.16,105.76 161.68,104.24 162.26,103.66 162.26,99.93 v3(157.96,95.63)
  L4 w0.127: v3(157.96,95.63) 157.96,90.18 155.42,87.63 155.42,87.11 154.55,86.24 154.55,71.81 154.05,71.31 154.05,66.93 153.41,66.3 153.41,59.87 152.92,59.38 152.92,56.28 154.05,55.16 154.05,54.34 153.61,53.91 153.61,49.97 154.17,49.41 154.17,48.84 154.4,48.61 154.4,43.74 154.63,43.51 154.63,42.97 155.19,42.41 155.19,39.24 154.43,38.48 154.43,37.27 146.56,29.4 142.57,29.4 141.66,28.49 141.66,27.43 v3(141.66,27.43)
  BOTTOM w0.102: v2(157.22,95.3) 157.56,95.3 157.89,95.63 v3(157.96,95.63) ; v2(37.68,20.45) 37.68,21.13 v3(37.5,21.31)
LANCLK_REQ_U_N: length 2.9
  TOP w0.102: R413.1 37.5,18.9 37.75,18.64 v1(37.75,18.6) 37.8,18.6 38.02,18.37 38.02,17.72 38.08,17.66 U16.12
LDR: length 6.5
  BOTTOM w0.305: U120.1 39.33,37.9 39.58,38.15 40.34,38.15
  BOTTOM w0.508: R65.2 43.42,41.22 v2(42.35,40.16) 40.34,38.15
LDR_1: length 3.8
  BOTTOM w0.508: v2(46.77,41.17) 46.03,41.91 R65.1 45.68,42.24 Q1250.4
LDRQ#: length 245.9
  TOP w0.102: R316.1 161.64,44.51 161.25,44.91 161.09,44.91 v3(160.84,45.16) 160.75,45.16 160.13,45.79 160.13,46.16 160.15,46.19 160.15,46.57 159.89,46.84 159.43,46.84 159.37,46.78 U109.2 ; CPU1.BA1 69.45,149.25 68.59,149.25 68.13,148.79 v4(68.12,148.79)
  L3 w0.127: v3(160.84,45.16) 157.81,45.16 157.45,44.79 149.81,44.79 148.98,43.97 142.63,43.97 142.27,44.32 140.72,44.32 139.96,43.56 130.89,43.56 130.69,43.76 127.87,43.76 127.15,44.49 122.61,44.49 120.91,46.19 111.83,46.19 111.19,45.55 108.48,45.55 v3(108.11,45.19) ; v3(159.9,68.48) 159.06,69.32 155.81,69.32 153.12,72.01 151.04,72.01 150.51,72.54 146.57,72.54 145.42,73.69 145.42,75.68 146.75,77.01 146.75,104.23 144.93,106.05 131.96,106.05 118.12,119.89 87.9,119.89 81.72,126.06 80.1,126.06 69.42,136.74 68.3,136.74 v3(67.83,136.27)
  L4 w0.127: v3(160.84,45.16) 160.84,45.21 162.07,46.44 162.07,54.27 161.53,54.81 161.53,58.05 160.8,58.79 160.8,63.26 159.9,64.16 v3(159.9,68.48) ; v3(67.83,136.27) 67.57,136.27 66.07,137.77 66.07,138.3 68.12,140.35 v4(68.12,148.79)
  BOTTOM w0.102: v3(160.84,45.16) 160.84,45.16 v2(160.84,46.05) ; R79704.2 108.24,47.56 108.24,45.31 v3(108.11,45.19)
LDRQ#_EC: length 5.5
  BOTTOM w0.102: U4101.61 108.13,52.68 108.87,51.94 v2(108.87,50.29) R79704.1
LDT_RST: length 53.7
  TOP w0.102: v1(89.16,196.45) 89.21,196.5 89.21,196.8 88.72,197.28 v3(88.63,197.28) ; R1617.2 C1721.2 v4(78.9,185.42) 79.79,184.53 79.79,183.77 80.89,182.66 80.89,181.69 80.9,181.68 80.9,181.37 80.89,181.37 80.89,180.83 81.1,180.63 81.1,180.17 81.4,179.87 CPU1.D15 ; R1745.2 v3(89,215.19)
  L3 w0.127: v3(89,215.19) 89.45,214.73 89.45,207.77 89.48,207.74 89.48,198.12 v3(88.63,197.28)
  L4 w0.127: v3(88.63,197.28) 87.35,198.56 79.56,198.56 77.03,196.03 77.03,188.04 78.9,186.17 v4(78.9,185.42)
LDT_RST#_BUF: length 4.6
  TOP w0.102: R1745.1 90.39,214.88 v3(90.81,214.88) 91.32,214.38 HDT1.12
  BOTTOM w0.102: v3(90.81,214.88) v2(90.81,213.56)
LED_5VSB: length 4.2
  TOP w0.254: LED2.A R1767.2 93.76,6.35 93.76,5.79 92.54,4.57 v1(92.11,4.57)
LEDC_ISET: length 5.6
  BOTTOM w0.102: R82.1 33.31,32.96 33.31,35.13 33.76,35.59 v2(33.82,35.59) 33.82,35.64 34.25,36.08 U120.12
LFRAMEJ_FW4: length 222.2
  TOP w0.102: R79698.2 115.69,50.86 116.14,51.31 116.62,51.31 117,51.69 118.21,51.69 118.7,52.18 124.37,52.18 LPC1.13 ; CPU1.AV14 81,151.7 v4(81.2,151.7) ; v3(76.78,137.87) 76.32,138.33 74.3,138.33 74.01,138.62 R1875.2 R1871.1 R1872.2 ; v3(156.81,58.1) 156.56,58.1 155.91,58.75 155.91,58.96 155.48,59.39 155.48,59.39 155.25,59.61 U109.37
  L3 w0.127: v3(156.81,58.1) 156.56,58.1 155.71,58.95 153.9,58.95 153.13,58.18 153.13,57.21 152.63,56.71 145.97,56.71 145.52,56.26 143.58,56.26 142.75,55.42 139.9,55.42 139.02,54.55 133.24,54.55 132.98,54.81 129.54,54.81 128.83,54.09 LPC1.13 ; v3(153.63,95) 153.63,98.84 154.05,99.27 154.05,103.12 149.3,107.87 149.3,110.48 147.31,112.47 132.43,112.47 120.39,124.51 119.42,124.51 117.36,126.57 89.22,126.57 84.56,131.23 81.98,131.23 79.36,133.85 79.36,134.92 78.61,135.66 78.61,135.8 78.51,135.9 76.78,137.63 v3(76.78,137.87) 75.54,139.11 75.54,143.65 77.47,145.57 77.47,146.17 78.18,146.87 78.18,147.69 79.75,149.27 79.75,150.29 80.11,150.65 80.17,150.65 81.2,151.67 v4(81.2,151.7)
  L4 w0.127: v3(161.7,92.91) 162.06,92.56 162.06,90.3 157.16,85.39 157.16,84.22 157.42,83.95 157.42,83.56 157.16,83.29 157.16,75.64 157.73,75.07 157.73,69.43 157.01,68.71 157.01,67.73 157.34,67.4 157.34,67.01 156.7,66.38 156.7,59.75 157.41,59.05 157.41,58.66 157.13,58.38 157.1,58.38 v3(156.81,58.1)
  BOTTOM w0.102: v3(153.63,95) 153.63,94.89 155.61,92.91 v2(157.13,92.91) v3(161.7,92.91)
LFRAMEJ_FW4_EC: length 16.6
  TOP w0.102: v3(107.98,49.28) 108.16,49.45 108.6,49.45 109.21,50.06 111.04,50.06 111.4,50.42 113.25,50.42 114.14,49.53 115.03,49.53 R79698.1
  BOTTOM w0.102: U4101.3 104.47,47.06 v2(104.7,46.83) 106.01,46.83 107.98,48.81 v3(107.98,49.28)
LINE2-VREFO: length 5.3
  TOP w0.203: U6.29 161.99,73.62 161.69,73.32 161.18,73.32 v1(160.87,73) 160.62,72.76 R261.1 R272.1
LINEOUT-JD: length 182.5
  TOP w0.203: v3(165.06,69.85) 164.9,69.85 164.5,70.26 R266.1 ; v3(152.89,2.11) 152.71,1.93 86.22,1.93 v3(85.73,2.41)
  L3 w0.203: v3(165.06,69.85) 165.06,69.29 166.91,67.44 166.91,35.06 158.59,26.74 158.59,18.29 158.15,17.84 153.13,17.84 152.16,16.87 152.16,4.86 151.93,4.63 151.93,3.07 v3(152.89,2.11)
  BOTTOM w0.203: LOUT1.Q 80.06,33.76 85.7,28.13 85.7,20.16 85.48,19.94 85.48,17.6 86.32,16.77 86.32,13.03 85.7,12.41 85.7,4.36 85.38,4.04 85.38,2.77 v3(85.73,2.41)
LINEOUT-L: length 190.4
  TOP w0.203: R429.1 v3(83.68,34.92) ; v3(158.58,78.15) 158.69,78.03 U6.19 ; v3(152.89,3.73) 152,2.84 88.22,2.84 v3(87.08,3.99)
  L3 w0.203: v3(158.58,78.15) 158.58,77.97 159.24,77.31 159.24,74.29 159.87,73.66 160.87,73.66 163.51,71.02 165.26,71.02 166.1,70.17 166.1,69.54 167.83,67.82 167.83,34.68 159.51,26.36 159.51,17.91 158.53,16.93 153.66,16.93 153.07,16.34 153.07,3.91 v3(152.89,3.73)
  BOTTOM w0.203: v3(87.08,3.99) 86.61,4.46 86.61,12.03 87.23,12.65 87.23,17.14 86.39,17.98 86.39,19.56 86.61,19.78 86.61,28.74 83.78,31.57 v2(83.75,31.57) 83.68,31.65 v3(83.68,34.92)
LINEOUT-R: length 195
  TOP w0.203: R428.1 v3(82.58,34.92) ; v3(152.89,2.92) 152.36,2.39 86.85,2.39 v3(86.67,2.57) ; U6.18 159.04,78.43 158.48,78.99 v3(158.38,78.99)
  L3 w0.203: v3(152.89,2.92) 152.38,3.43 152.38,4.45 152.61,4.67 152.61,16.53 153.47,17.39 158.34,17.39 159.05,18.1 159.05,26.55 167.37,34.87 167.37,67.63 165.65,69.35 165.65,69.98 165.07,70.56 163.32,70.56 160.68,73.2 159.68,73.2 158.78,74.1 158.78,77.12 158.21,77.7 158.19,77.7 157.89,78 157.89,78.51 v3(158.38,78.99)
  BOTTOM w0.203: v3(86.67,2.57) 86.42,2.57 85.83,3.15 85.83,3.85 86.15,4.17 86.15,12.22 86.77,12.84 86.77,16.96 85.94,17.79 85.94,19.75 86.15,19.97 86.15,28.32 82.86,31.61 v2(82.86,33.4) 82.86,34.65 v3(82.58,34.92)
LINEOUT_C-L: length 3.4
  TOP w0.203: v3(85.61,37.34) 85.56,37.29 85.56,37.04 85.29,36.77 L62.1 83.83,36.77 R429.2
  BOTTOM w0.203: v3(85.61,37.34) 86.01,37.74 v2(86.01,38.23)
LINEOUT_C-R: length 3.6
  TOP w0.203: R428.2 81.88,36.64 v3(81.44,37.08) 82.01,37.66 L20.1
  BOTTOM w0.203: v3(81.44,37.08) 81.34,36.98 v2(80.63,36.98)
LINEOUT_CON-L: length 16.3
  TOP w0.203: C268.1 L62.2 85,37.91 85,39.88 84.17,40.7 84.17,41.47 83.15,42.48 Q46.1 82.35,42.34 76.91,42.34 76.59,42.66 LOUT1.4
LINEOUT_CON-R: length 22.7
  TOP w0.203: L20.2 82.58,39.56 C267.1 83.15,40.13 Q46.2 82.45,41.88 76.06,41.88 72.68,38.51 72.68,33.15 73.11,32.71 LOUT1.1
LINK_ACTIVITY_N: length 87.3
  TOP w0.203: U16.27 v3(37.28,11.28)
  TOP w0.254: v4(80.23,27.28) UR5.1 80.17,28.13 U12.4 ; v3(48.4,4.7) 48.42,4.7 48.65,4.93 50.85,4.93 51.41,5.49 54.36,5.49 v1(55.41,4.45) 55.41,3.94 55.84,3.51 83.42,3.51 84.49,4.57 84.49,12.06 86.25,13.83 86.25,13.93 86.42,14.1 86.42,17.35 85.24,18.54 85.24,21.22 84.23,22.23 84.23,24.89 83.09,26.04 83.09,27 v3(82.81,27.28)
  L4 w0.254: v3(37.28,11.28) 38.32,12.32 39.95,12.32 40.67,11.59 40.67,11.12 40.17,10.61 40.17,9.59 45.46,4.29 47.7,4.29 48.11,4.7 48.39,4.7 v3(48.4,4.7)
  BOTTOM w0.254: v2(49.18,4.45) 48.65,4.45 v3(48.4,4.7) ; v3(82.81,27.28) v4(80.23,27.28)
LINK_PWR: length 9.1
  TOP w0.254: RJ1.9 83.56,24.8 82.48,25.88 82.48,26.71 81.64,27.55 81.64,28.56 R79618.2
LPC_CLK0_R: length 17.9
  TOP w0.102: v4(81.2,151.06) 80.97,151.3 CPU1.AW14 ; R1646.2 80.45,137.16 78.93,138.69 v3(78.93,139.06)
  L3 w0.127: v3(78.93,139.06) 78.93,139.42 77.89,140.45 77.89,143.49 79.04,144.63 79.04,145.14 79.42,145.52 79.42,147.59 81.2,149.37 v4(81.2,151.06)
  BOTTOM w0.102: v3(78.93,139.06) 79,139.06 79.51,138.56 v2(79.56,138.56)
LPC_CLK1: length 203.3
  TOP w0.102: v1(158.66,100.2) 158.24,100.2 v3(157.89,99.85) ; v3(81.57,138.18) 80.36,138.18 R1869.1 C66.1 ; R123.1 79.28,141.83 78.71,141.26 R1870.2 78.96,139.83 C66.1 ; C66.1 R1876.2
  L3 w0.127: LPC1.1 115.91,52.46 121.17,52.46 122.08,51.54 127.64,51.54 128.18,52.09 132.37,52.09 133.4,51.06 139.45,51.06 140.63,52.25 143.66,52.25 143.9,52.01 146.51,52.01 147.12,52.62 147.96,52.62 148.67,53.34 v3(150.53,53.34) ; v3(157.89,99.85) 158.66,99.85 161.04,102.23 161.04,104.32 159.76,105.6 159.76,113.93 159.38,114.3 150.64,114.3 148.82,116.11 133.94,116.11 121.9,128.15 120.93,128.15 118.87,130.21 92.28,130.21 89.05,133.44 87.5,133.44 85.37,135.57 84.15,135.57 83.04,136.69 82.03,136.69 81.76,136.97 81.76,137.1 81.68,137.18 81.57,137.29 v3(81.57,138.18)
  L4 w0.127: v3(157.89,99.85) 157.75,99.71 157.75,98.56 157.09,97.91 157.09,90.23 154.76,87.9 154.76,87.38 153.9,86.51 153.9,72.09 152.69,70.88 152.69,67.43 151.35,66.09 151.35,59.69 150.95,59.29 150.95,56.51 150.6,56.16 150.6,53.41 v3(150.53,53.34)
LPC_CLK1_R: length 6.9
  TOP w0.102: R123.2 79.28,144.53 79.59,144.83 v1(79.59,144.91) 79.59,144.96 79.61,144.98 79.61,146.74 79.61,147.85 79.5,147.96 79.5,148.23 79.51,148.23 79.51,148.77 79.5,148.77 79.5,150.2 CPU1.AY13
LPC_PD_N: length 2.3
  TOP w0.102: v4(76.13,162) 76.5,162.37 CPU1.AE9
  BOTTOM w0.102: TP9.1 75.42,162.71 v4(76.13,162)
LPC_PME_N: length 356.3
  TOP w0.102: v3(153.63,93.09) 152.81,92.28 v1(152.81,90.42) 152.81,89.4 153.42,88.79 153.42,86.13 152.38,85.09 152.38,79.6 153.42,78.56 153.42,72.43 150.67,69.68 150.51,69.68 v3(150.22,69.39) ; R568.1 56.36,172.66 57.44,173.75 57.44,174.88 62.21,179.65 62.21,187.5 67.98,193.27 67.98,203.94 70.37,206.33 101.55,206.33 105.57,202.31 124.37,202.31 126.02,200.66 v3(130.06,200.66)
  L3 w0.127: v3(149.51,200) 149.73,199.79 149.73,196.55 162.51,183.77 164.12,183.77 164.99,182.89 164.99,155.78 165.07,155.7 165.07,139.54 164.84,139.31 164.84,124.26 v3(161.79,121.21) ; v3(146.92,58.04) 147.5,58.62 147.5,59.58 147.14,59.94 144.48,59.94 144.04,59.5 143.83,59.5 143.25,58.93 138.01,58.93 136.96,57.87 132.31,57.87 131.05,59.13 113.51,59.13 111.75,57.37 107.9,57.37 107.03,58.23 91.79,58.23 91.22,58.8 v3(89.82,58.8)
  L4 w0.127: v3(153.63,93.09) 154.26,93.72 154.26,99.21 155.65,100.6 155.65,104.57 156.61,105.53 156.61,107.57 161.68,112.63 161.68,114.14 162.21,114.68 162.21,116.86 162.36,117.01 162.36,120.63 v3(161.79,121.21) ; v3(149.51,200) 132.14,200 131.01,201.13 130.53,201.13 v3(130.06,200.66) ; v3(89.82,58.8) 89.82,58.55 88.81,57.53 88.81,51.94 v3(90.71,50.04)
  BOTTOM w0.102: v3(146.92,58.04) 147.33,58.45 147.33,59.22 147.29,59.26 R80224.2 R1843.2 150.22,65.42 v3(150.22,69.39) ; R79709.2 v3(90.71,50.04)
LPC_TPM: length 2.2
  TOP w0.102: v4(80,151.7) 79.6,151.3 CPU1.AW12
  BOTTOM w0.102: v4(80,151.7) 79.51,151.21 TP187.1
LPF: length 3.4
  TOP w0.102: C3455.1 36.69,33.45 v3(36.76,33.53)
  BOTTOM w0.102: v2(37.38,32.59) 36.76,33.21 v3(36.76,33.53) 36.87,33.64 U120.9
LVDS_BL_ADJ: length 6.4
  TOP w0.165: v1(46.19,36.75) 45.77,36.33 R131.1 45.77,35.33 R133.1 46.1,33.89 46.1,33.89 45.77,33.56 R1984.1 45.66,33.3 R132.1 45.68,32.37 R134.2
LVDS_BL_EN_1: length 3.8
  TOP w0.102: R79686.2 148.27,63.21 v1(148.27,62.61) 148.27,62.05 148.46,61.86 U109.54
LVDS_DET_A*: length 175.1
  TOP w0.102: v3(152.51,47.42) 152.05,46.97 U109.116 ; v3(43.63,93.5) LVDS1.17
  L3 w0.127: v3(43.63,93.5) 43.16,93.03 43.16,85.31 43.44,85.03 43.77,85.03 44.33,84.47 44.33,84.29 45.05,83.58 46.37,83.58 50.95,79.01 52.37,79.01 55.43,82.07 70.65,82.07 71.82,83.24 85.48,83.24 88.43,80.29 v3(88.43,79.63) ; v3(81.95,51.56) 82.67,52.29 86.35,52.29 90.87,47.77 96.12,47.77 97.14,46.75 100.48,46.75 100.8,46.43 110.93,46.43 111.5,46.99 112.07,46.99 121.24,46.99 122.92,45.31 127.45,45.31 128.2,44.56 131.36,44.56 131.57,44.36 139.28,44.36 140.9,45.97 144.52,45.97 145.67,44.82 148.7,44.82 149.48,45.59 151.58,45.59 151.75,45.76 151.75,46.66 v3(152.51,47.42)
  L4 w0.127: v3(88.43,79.63) 88.86,79.2 88.86,77.43 84.42,73 84.42,67.3 84.48,67.25 84.48,62.74 83.37,61.63 83.37,55.79 82.32,54.74 82.32,52.18 81.95,51.82 v3(81.95,51.56)
  BOTTOM w0.102: v2(82.84,51.56) v3(81.95,51.56) ; R482.2 44.48,93.73 44.26,93.5 v3(43.63,93.5)
LVDS_DET_B*: length 207.3
  TOP w0.102: v3(151.79,43.54) 152.15,43.54 152.45,43.84 U109.117 ; v3(43.7,114.38) 43.7,114.81 43.06,115.44 R483.2 41.72,116.24 40.84,116.24 v1(40.29,116.79) 40.46,116.95 Q103.D
  L3 w0.127: v3(82.58,49.28) 84.5,49.28 85.01,48.76 85.37,48.76 88.22,45.91 95.41,45.91 96.53,44.79 96.53,42.7 97.49,41.73 99.42,41.73 99.98,42.29 106.15,42.29 106.67,41.77 116.26,41.77 118.66,39.37 122.15,39.37 122.37,39.15 137.45,39.15 138.89,40.59 140.84,40.59 143.49,37.93 143.61,37.93 144.02,37.53 146.76,37.53 149.24,40.01 152.18,40.01 153.36,41.19 153.36,41.87 151.79,43.44 v3(151.79,43.54) ; v3(89.19,80.64) 86.14,83.7 74.32,83.7 73.57,84.45 70.62,84.45 68.74,82.58 55.22,82.58 52.16,79.51 51.16,79.51 46.59,84.09 45.26,84.09 44.91,84.43 44.91,85.12 44.43,85.6 44.43,113.91 43.96,114.38 v3(43.7,114.38)
  L4 w0.127: v3(82.58,49.28) 82.84,49.28 84.42,50.86 84.42,55.08 83.63,55.88 83.63,61.11 86.55,64.03 86.55,72.67 89.19,75.31 v3(89.19,80.64)
LVDS_DET_B_C*: length 16.9
  TOP w0.102: LVDS1.1 43.75,109.5 44.15,109.91 44.15,118.32 Q103.G 44.08,119.32 44.08,121.22 43.12,122.17 v1(42.71,122.17) 42.71,121.25 C869.1
LVDS_PU_5: length 3.6
  TOP w0.102: LVDS1.5 v3(43.63,105.5)
  BOTTOM w0.102: v2(42.76,107.54) 42.77,107.53 R1163.2 42.77,106.36 v3(43.63,105.5)
LVDS_PU_5_1: length 1.6
  BOTTOM w0.102: R484.1 42.07,112.2 Q9647.D
LVDS_PU_5_2: length 3.6
  BOTTOM w0.102: Q9650.D 41.5,118.43 41.12,118.05 R80233.1 41.12,115.61 Q9647.G
LVDS_PU_6: length 10.2
  TOP w0.102: LVDS1.6 v3(43.63,104.5)
  BOTTOM w0.102: R484.2 42.87,111.66 43.89,111.66 44.36,111.19 44.36,108.45 44.38,108.43 v2(44.38,107.09) 44.38,107.04 44.36,107.01 44.36,105.23 v3(43.63,104.5)
LVDS_PU_24: length 20.8
  TOP w0.102: v3(43.63,86.5) LVDS1.24
  L4 w0.127: v3(43.63,86.5) 43.41,86.5 43.16,86.74 43.16,87.69 43.16,87.7 43.16,87.97 43.16,87.97 43.16,103.03 v3(43.63,103.5)
  BOTTOM w0.102: R481.2 42.63,104.38 42.63,103.63 v2(42.81,103.45) 42.91,103.35 43.48,103.35 v3(43.63,103.5)
LX:
  vias: v2(38.62,48.49) v2(38.64,45.24) v5(37.63,48.44) v5(37.63,47.4) v5(37.63,46.35) v5(37.63,45.29)
M1_SMB_CLK: length 4.7
  TOP w0.102: R14.2 121.42,220.47 120.84,219.89 120.06,219.89 v3(119.88,219.71) 119.87,219.71 119.67,219.5 NGFF1.60
  BOTTOM w0.102: v2(120.89,219.79) 119.96,219.79 v3(119.88,219.71)
M1_SMB_DATA: length 3.4
  TOP w0.102: R1622.2 120.94,219.46 120.75,219.27 v1(120.64,219.27) 120.21,219.27 119.95,219 NGFF1.58
M_CAS_A_N: length 72.5
  TOP w0.102: 98.33,158.81 98.33,158.81 97.78,158.81 97.72,158.87 96.74,158.87 96.63,158.98 96.22,158.98 96.14,158.89 95.64,158.89 95.64,158.9 95,158.9 CPU1.AK32
  TOP w0.165: DIMM1.115 132.03,153.95 132.55,153.44 133.78,153.44 v3(134.27,153.92) ; v3(143.29,154.05) 143.78,154.54 144.39,154.54 144.44,154.49 145.19,154.49 145.73,153.95 DIMM2.115 ; v4(99.64,158.4) 99.23,158.81 98.33,158.81
  L3 w0.216: v3(143.29,154.05) 142.35,153.12 140.03,153.12 140.02,153.12 139.68,153.12 138.71,152.14 117.5,152.14 116.93,152.71 116.93,153.2 116.7,153.44 116.27,153.44 116.06,153.23 116.06,152.35 115.84,152.14 115.41,152.14 115.19,152.35 115.19,153.23 114.98,153.44 107.87,153.44 107.74,153.57 102.87,158.43 99.68,158.43 v4(99.64,158.4)
  L4 w0.216: v3(143.29,154.05) 142.77,153.54 140.79,153.54 139.89,154.44 134.82,154.44 134.31,153.92 v3(134.27,153.92)
  BOTTOM w0.165: v3(134.27,153.92) v2(134.27,154.74)
M_DATA_A0: length 91
  TOP w0.102: 89.69,182.88 89.72,182.85 89.72,182.42 89.4,182.1 CPU1.A25
  TOP w0.165: v3(132.75,189.36) 132.74,189.35 DIMM1.5 ; 89.69,182.88 89.39,183.18 89.39,183.95 v4(89.17,184.17) ; v3(147.99,189.36) 147.98,189.35 DIMM2.5
  L4 w0.216: v4(89.17,184.17) 88.7,184.64 88.7,185.9 91.39,188.59 96.5,188.59 97.77,189.87 98.26,189.87 98.48,189.66 98.48,189.28 98.7,189.06 99.13,189.06 99.34,189.28 99.34,189.66 99.56,189.87 99.99,189.87 100.21,189.66 100.21,189.28 100.42,189.06 100.86,189.06 101.07,189.28 101.07,189.66 101.29,189.87 101.72,189.87 101.93,189.66 101.93,189.28 102.15,189.06 102.58,189.06 102.8,189.28 102.8,189.66 103.01,189.87 139.02,189.87 139.24,189.66 139.24,188.66 139.46,188.44 139.89,188.44 140.1,188.66 140.1,189.66 140.32,189.87 140.54,189.87 140.79,190.13 142.01,190.13 v3(142.53,189.61)
  BOTTOM w0.102: v3(147.99,189.36) 148.14,189.51 148.14,190.17 147.87,190.44 147.49,190.44 147.39,190.34 147.39,189.66 147.29,189.56 147.08,189.56 146.98,189.66 146.98,190.34 146.88,190.44 146.68,190.44 146.58,190.34 146.58,189.66 146.47,189.56 146.27,189.56 146.17,189.66 146.17,190.34 146.07,190.44 142.5,190.44 142.25,190.2 142.25,189.89 v3(142.53,189.61) 142.07,189.15 140.77,189.15 139.84,190.08 v2(139.13,190.08) 135.62,190.08 135.05,189.51 135.05,189.49 134.46,188.9 133.21,188.9 v3(132.75,189.36)
M_DATA_A1: length 92.1
  TOP w0.102: 89.86,183.09 89.92,183.03 89.92,182.33 89.7,182.11 89.7,181.77 89.57,181.64 89.57,181.36 89.7,181.23 89.7,180.6 CPU1.C25
  TOP w0.165: v3(149.51,189.36) 148.91,188.75 DIMM2.7 ; v4(89.19,185.55) 89.66,185.07 89.66,183.29 89.86,183.09 ; v3(134.27,189.36) 133.67,188.75 DIMM1.7
  L4 w0.216: v3(141,189.61) 141.77,188.85 143.4,188.85 143.62,188.63 143.62,188.31 143.4,188.09 140.66,188.09 140.5,187.93 138.46,187.93 137.55,188.84 132.53,188.84 132,189.38 103.69,189.38 102.88,188.57 97.17,188.57 96.7,188.1 91.59,188.1 89.19,185.7 v4(89.19,185.55)
  BOTTOM w0.102: v3(149.51,189.36) 148.05,190.82 142.21,190.82 v3(141,189.61) 141,190.37 140.75,190.63 137.7,190.63 137.35,190.98 134.2,190.98 133.89,190.68 v2(133.89,190.21) 133.89,189.74 v3(134.27,189.36)
M_DATA_A2: length 90.1
  TOP w0.102: 91.91,183.59 91.67,183.35 91.53,183.35 91.11,182.93 91.11,182.42 91.3,182.24 91.3,181.75 91.29,181.74 91.29,181.25 91.3,181.24 91.3,180.95 91,180.65 CPU1.C27
  TOP w0.165: v3(132.75,185.93) 132.33,186.35 DIMM1.15 ; DIMM2.15 147.69,186.35 v3(147.99,186.06) ; v4(92.24,185.31) 92.59,184.95 92.59,184.27 91.91,183.59
  L4 w0.216: v4(92.24,185.31) 93.11,184.44 94.43,184.44 95.13,185.14 97,185.14 97.26,185.41 106.13,185.41 106.35,185.63 106.35,186.01 106.56,186.23 106.99,186.23 107.21,186.01 107.21,185.63 107.43,185.41 107.86,185.41 108.07,185.63 108.07,186.01 108.29,186.23 108.72,186.23 108.94,186.01 108.94,185.63 109.15,185.41 109.58,185.41 109.8,185.63 109.8,186.01 110.02,186.23 110.45,186.23 110.66,186.01 110.66,185.63 110.88,185.41 111.31,185.41 111.53,185.63 111.53,186.01 111.74,186.23 112.18,186.23 112.39,186.01 112.39,185.63 112.61,185.41 113.04,185.41 113.25,185.63 113.25,186.01 113.47,186.23 113.9,186.23 114.12,186.01 114.12,185.63 114.33,185.41 114.77,185.41 114.98,185.63 114.98,186.01 115.2,186.23 115.63,186.23 115.85,186.01 115.85,185.63 116.06,185.41 116.49,185.41 116.71,185.63 116.71,186.01 116.93,186.23 117.36,186.23 117.57,186.01 117.57,185.63 117.79,185.41 118.22,185.41 118.44,185.63 118.44,186.01 118.65,186.23 119.08,186.23 119.3,186.01 119.3,185.63 119.52,185.41 119.95,185.41 120.16,185.63 120.16,186.01 120.38,186.23 120.81,186.23 121.03,186.01 121.03,185.63 121.24,185.41 121.67,185.41 121.89,185.63 121.89,186.01 122.11,186.23 122.54,186.23 122.75,186.01 122.75,185.63 122.97,185.41 123.4,185.41 123.62,185.63 123.62,186.01 123.83,186.23 124.27,186.23 124.48,186.01 124.48,185.63 124.7,185.41 125.13,185.41 125.35,185.63 125.35,186.01 125.56,186.23 130.49,186.23 131.3,185.41 139.85,185.41 v3(140.88,186.44)
  BOTTOM w0.102: v3(147.99,186.06) 147.99,186.74 147.08,187.65 142.37,187.65 141.61,186.89 141.33,186.89 v3(140.88,186.44) 140.3,187.01 v2(138.84,187.01) 138.33,187.01 138.08,186.76 133.58,186.76 v3(132.75,185.93)
M_DATA_A3: length 91.7
  TOP w0.102: 92.03,183.34 91.78,183.08 91.56,183.08 91.32,182.85 91.32,182.51 91.51,182.32 91.51,181.65 91.5,181.64 91.5,181.35 91.51,181.35 91.51,180.86 91.37,180.72 91.37,179.87 CPU1.D27
  TOP w0.165: v4(93.2,186.26) 93.2,185.6 92.87,185.27 92.87,184.17 92.03,183.34 ; v3(134.27,185.93) 133.78,185.44 132.48,185.44 132.17,185.75 DIMM1.17 ; v3(149.51,186.06) 149.02,185.57 147.79,185.57 147.6,185.75 DIMM2.17
  L4 w0.216: v3(142.4,186.44) 141.89,186.95 140.66,186.95 140.16,186.45 132.31,186.45 132.3,186.45 131.9,186.45 131.63,186.72 130.25,186.72 130.03,186.94 130.03,187.32 129.81,187.53 129.38,187.53 129.17,187.32 129.17,186.94 128.95,186.72 128.52,186.72 128.3,186.94 128.3,187.32 128.09,187.53 127.66,187.53 127.44,187.32 127.44,186.94 127.22,186.72 126.79,186.72 126.58,186.94 126.58,187.32 126.36,187.53 125.93,187.53 125.71,187.32 125.71,186.94 125.5,186.72 125.06,186.72 124.85,186.94 124.85,187.32 124.63,187.53 124.2,187.53 123.98,187.32 123.98,186.94 123.77,186.72 123.34,186.72 123.12,186.94 123.12,187.32 122.91,187.53 122.47,187.53 122.26,187.32 122.26,186.94 122.04,186.72 105.57,186.72 105.35,186.5 105.35,186.19 105.14,185.98 104.7,185.98 104.49,186.19 104.49,186.5 104.27,186.72 103.84,186.72 103.62,186.5 103.62,186.19 103.41,185.98 102.98,185.98 102.76,186.19 102.76,186.5 102.55,186.72 102.11,186.72 101.9,186.5 101.9,186.19 101.68,185.98 101.25,185.98 101.03,186.19 101.03,186.5 100.82,186.72 100.39,186.72 100.17,186.5 100.17,186.19 99.95,185.98 99.52,185.98 99.31,186.19 99.31,186.5 99.09,186.72 97.93,186.72 97.47,186.25 96.62,186.25 96.62,186.26 v4(93.2,186.26)
  BOTTOM w0.102: v3(134.27,185.93) 134.73,186.39 139.9,186.39 140.31,185.98 141.94,185.98 v3(142.4,186.44) 143.24,187.27 146.92,187.27 147.1,187.1 v2(147.1,186.64) 147.1,186.18 147.68,185.6 149.05,185.6 v3(149.51,186.06)
M_DATA_A4: length 92.3
  TOP w0.165: v3(151.54,189.36) 152.03,189.85 153.27,189.85 153.47,189.65 DIMM2.4 ; CPU1.B24 88.6,181.03 88.27,181.36 88.27,181.92 87.71,182.47 v4(87.71,183.16) ; DIMM1.4 138.23,189.65 138.03,189.85 136.79,189.85 v3(136.3,189.36)
  L4 w0.216: v3(144.81,189.61) 144.78,189.61 143.28,191.11 140.38,191.11 140.13,190.85 97.37,190.85 96.09,189.58 90.98,189.58 87.72,186.31 87.72,183.16 v4(87.71,183.16)
  BOTTOM w0.102: v3(136.3,189.36) 137.26,188.4 144.38,188.4 144.81,188.83 v3(144.81,189.61) 145.8,188.62 v2(146.64,188.62) 146.74,188.52 148.42,188.52 148.52,188.42 148.52,188.09 148.62,187.99 148.83,187.99 148.93,188.09 148.93,188.42 149.03,188.52 149.23,188.52 149.34,188.42 149.34,188.09 149.44,187.99 149.64,187.99 149.74,188.09 149.74,188.42 149.84,188.52 150.05,188.52 150.15,188.42 150.15,188.09 150.25,187.99 150.45,187.99 150.55,188.09 150.55,188.42 151.49,189.36 v3(151.54,189.36)
M_DATA_A5: length 91
  TOP w0.165: v4(89.31,182.58) 89.07,182.34 89.07,181.43 CPU1.B25 ; DIMM2.6 153.37,189.05 v3(153.07,189.36) ; v3(137.83,189.36) 138.14,189.05 DIMM1.6
  L4 w0.216: v4(89.31,182.58) 88.86,182.13 88.86,181.58 88.68,181.41 88.14,181.41 87.96,181.58 87.96,182.59 88.21,182.84 88.21,186.1 91.19,189.08 96.29,189.08 97.57,190.36 140.33,190.36 140.59,190.62 142.28,190.62 v3(143.29,189.61)
  BOTTOM w0.102: v3(137.83,189.36) 137.83,188.98 138.03,188.78 138.4,188.78 138.5,188.88 138.5,189.34 138.61,189.44 138.81,189.44 138.91,189.34 138.91,188.88 139.01,188.78 139.21,188.78 139.32,188.88 139.32,189.34 139.42,189.44 139.62,189.44 139.72,189.34 139.72,188.88 139.82,188.78 144.23,188.78 144.33,188.88 144.33,189.05 144.23,189.15 143.75,189.15 v3(143.29,189.61) 143.75,190.07 145.23,190.07 v2(145.63,189.67) 146.12,189.18 147.4,189.18 147.68,188.9 149.7,188.9 150.32,189.52 150.32,189.55 150.59,189.81 152.61,189.81 v3(153.07,189.36)
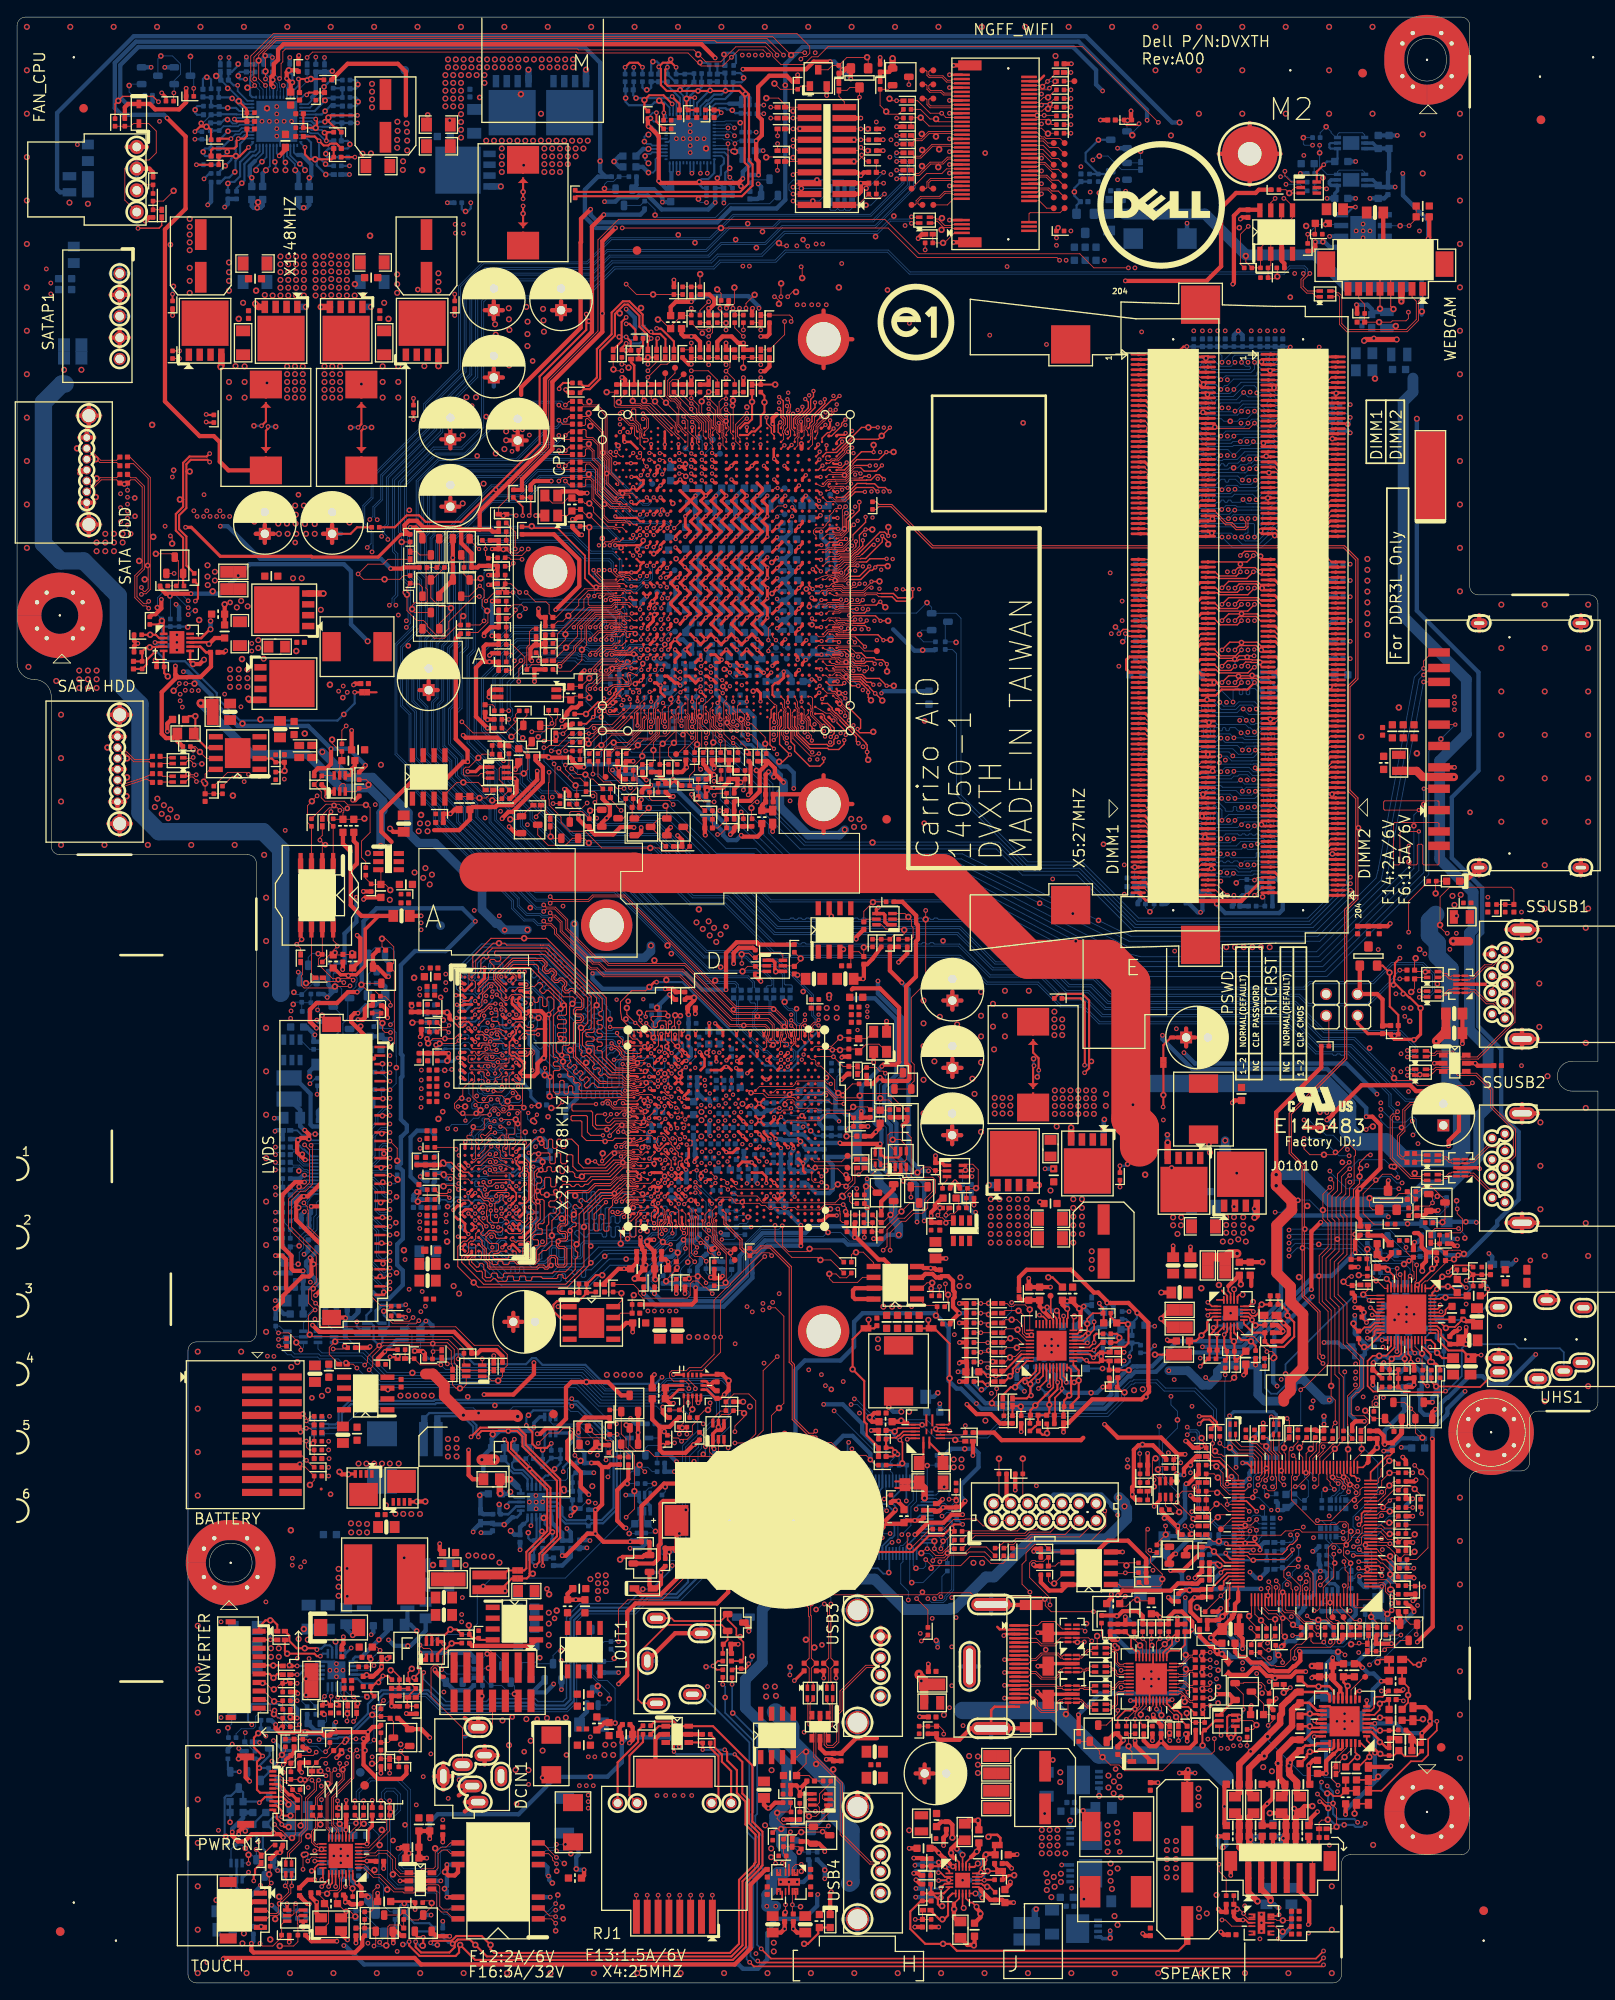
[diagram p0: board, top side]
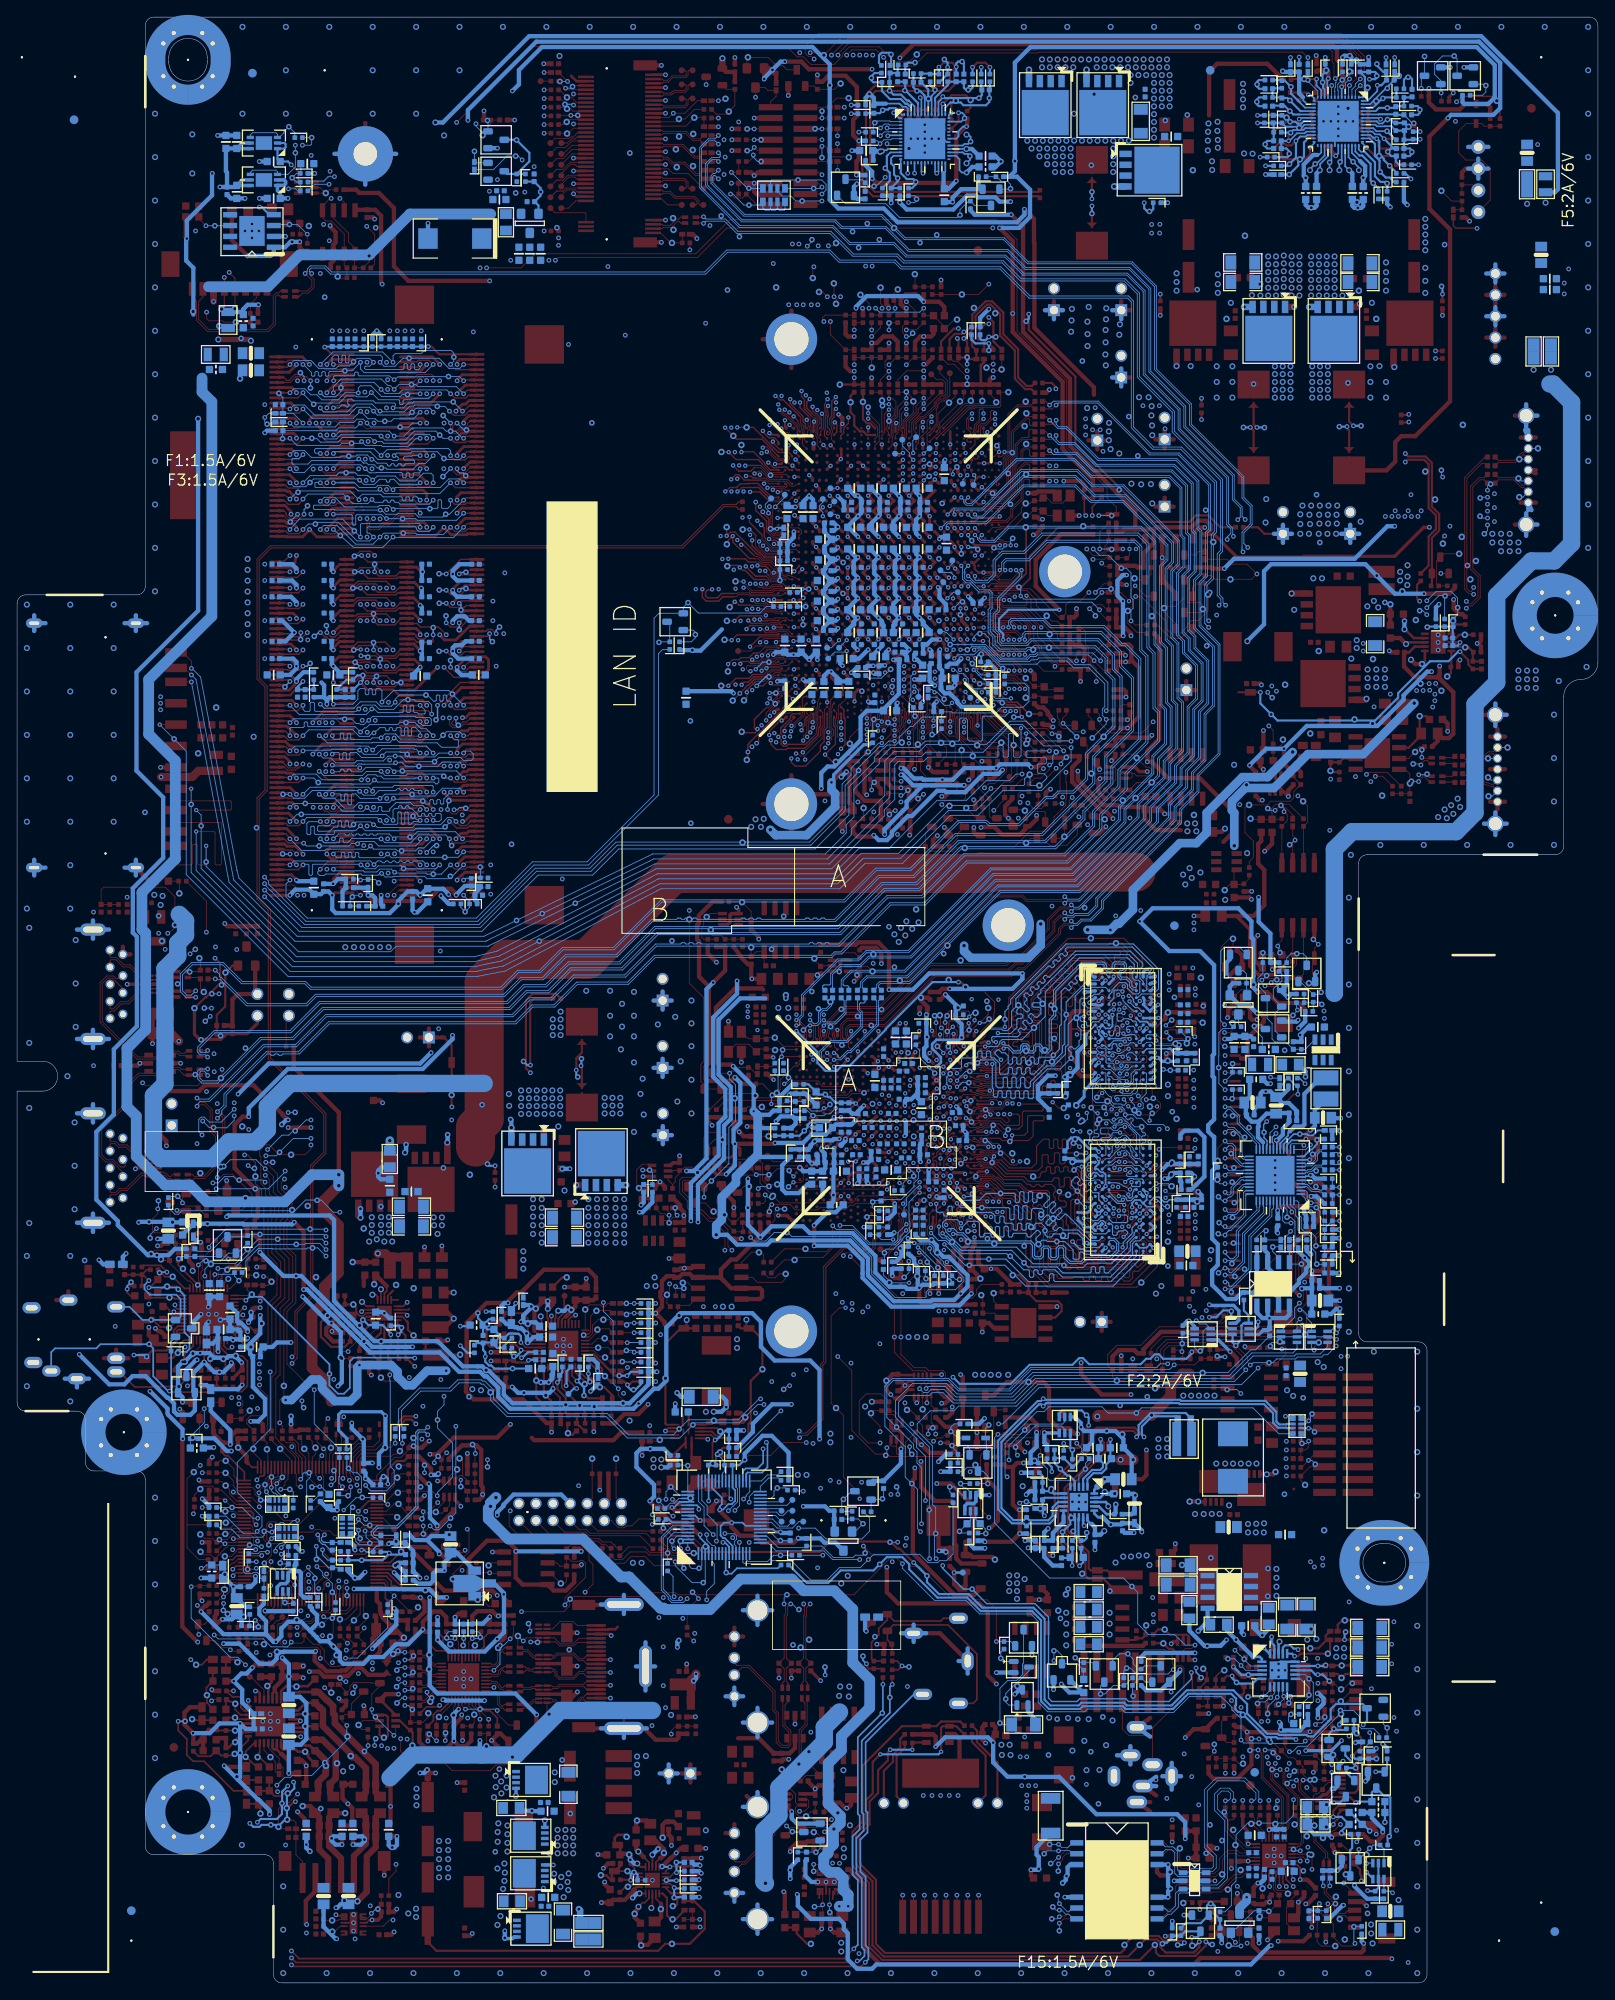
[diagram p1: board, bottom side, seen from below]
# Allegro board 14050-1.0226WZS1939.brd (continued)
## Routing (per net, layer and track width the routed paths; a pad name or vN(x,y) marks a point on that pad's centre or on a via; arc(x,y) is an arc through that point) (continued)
M_DATA_A6: length 89.6
  TOP w0.102: v4(90.81,183.59) 90.64,183.43 90.64,181.83 91,181.47 CPU1.B27
  TOP w0.165: v3(153.07,186.06) 153.07,186.05 DIMM2.16 ; v3(137.83,185.93) 137.95,186.05 DIMM1.16
  L4 w0.216: v3(145.07,186.03) 146.76,186.03 146.97,186.25 146.97,187.29 146.76,187.5 146.27,187.5 146.05,187.72 146.05,188.35 145.83,188.57 145.4,188.57 145.19,188.35 145.19,187.72 144.97,187.5 142.9,187.5 142.68,187.29 142.68,186.88 142.91,186.65 142.91,186.22 142.68,185.99 142.68,185.58 142.37,185.28 140.59,185.28 140.23,184.92 132.39,184.92 99.4,184.92 99.23,185.1 97.69,185.1 95.96,183.36 94.87,183.36 94.32,182.81 93.93,182.81 92.74,184 92.74,184.22 92.09,184.87 91.53,184.87 90.88,184.22 90.88,183.66 v4(90.81,183.59)
  BOTTOM w0.102: v3(137.83,185.93) 139.21,185.93 139.3,185.83 v2(139.31,185.83) 139.92,185.83 140.15,185.6 142.33,185.6 143.59,186.87 144.81,186.87 145.07,186.61 v3(145.07,186.03) 145.09,186.06 146.62,186.06 147.45,185.22 149.33,185.22 149.91,185.81 150.63,185.81 151.33,186.51 152.61,186.51 v3(153.07,186.06)
M_DATA_A7: length 92.1
  TOP w0.165: CPU1.A27 90.88,182.02 90.88,183.03 91.44,183.58 91.53,183.58 91.9,183.96 v4(91.9,184.4) ; v3(151.54,186.06) 152.15,185.45 DIMM2.18 ; DIMM1.18 138.04,185.45 138.03,185.44 136.79,185.44 v3(136.3,185.93)
  L4 w0.216: v4(91.9,184.4) 91.81,184.31 91.81,183.83 90.97,182.99 90.97,181.72 91.18,181.51 94.87,181.51 95.09,181.72 95.09,182.11 95.86,182.88 96.17,182.88 98.07,184.78 99.05,184.78 99.4,184.43 131.79,184.43 131.79,184.43 132.19,184.43 132.6,184.43 132.6,184.43 140.43,184.43 140.79,184.79 141.98,184.79 142.26,184.51 146.07,184.51 146.29,184.72 146.29,185.15 146.07,185.37 143.82,185.37 143.54,185.65 v3(143.54,186.08)
  BOTTOM w0.102: v3(151.54,186.06) 151.54,185.95 v2(150.29,184.7) 150.15,184.85 147.3,184.85 146.46,185.68 145.37,185.68 145.26,185.57 144.05,185.57 v3(143.54,186.08) 142.69,185.23 140.34,185.23 140.23,185.13 140.23,184.76 140.13,184.66 139.93,184.66 139.83,184.76 139.83,185.13 139.73,185.23 138.91,185.23 138.78,185.35 136.88,185.35 v3(136.3,185.93)
M_DATA_A8: length 81.1
  TOP w0.165: DIMM2.21 147.59,184.55 v3(147.99,184.28) ; DIMM1.21 132.07,184.55 132.72,183.9 v3(132.88,183.9) ; CPU1.A29 92.76,182.06 92.76,182.43 93.03,182.7 93.03,183.29 94.52,184.78 v4(94.52,185.29)
  L3 w0.216: v4(94.52,185.29) 94.52,185.35 95.34,186.17 104.26,186.17 104.47,185.95 104.47,185.2 104.69,184.99 105.12,184.99 105.34,185.2 105.34,185.95 105.55,186.17 105.98,186.17 106.2,185.95 106.2,185.2 106.42,184.99 106.85,184.99 107.06,185.2 107.06,185.95 107.28,186.17 107.71,186.17 107.93,185.95 107.93,185.2 108.14,184.99 108.57,184.99 108.79,185.2 108.79,185.95 109.01,186.17 109.44,186.17 109.65,185.95 109.65,185.2 109.87,184.99 110.3,184.99 110.52,185.2 110.52,185.95 110.73,186.17 131.78,186.17 132.56,185.39 139.3,185.39 140.41,184.28 v3(141,184.28)
  BOTTOM w0.102: v3(132.88,183.9) v2(133.96,184.98) 138.63,184.98 138.75,184.85 139.2,184.85 139.78,184.28 v3(141,184.28) 140.71,184.57 140.71,184.71 140.85,184.85 143.07,184.85 143.32,185.11 145.64,185.11 145.84,185.31 146.2,185.31 146.31,185.19 146.31,184.81 146.16,184.66 146.16,184.52 146.3,184.37 146.44,184.37 146.69,184.61 147,184.61 147.33,184.28 v3(147.99,184.28)
M_DATA_A9: length 81.5
  TOP w0.102: CPU1.C29 92.87,180.57 92.87,180.92 92.9,180.95 92.9,181.24 92.89,181.25 92.89,181.75 92.99,181.85 92.99,182.22 93.33,182.56 93.33,183.21 93.38,183.26
  TOP w0.165: DIMM1.23 132.07,183.95 132.62,183.41 133.91,183.41 v3(134.4,183.9) ; v4(96.25,185.68) 96.2,185.68 95.74,185.22 95.34,185.22 93.38,183.26 ; v3(149.51,184.28) 149.11,183.77 147.68,183.77 147.5,183.95 DIMM2.23
  L3 w0.216: v3(142.53,183.9) 142.26,183.76 140.23,183.76 139.1,184.9 131.74,184.9 130.97,185.68 116.33,185.68 115.21,184.56 114.77,184.56 114.56,184.77 114.56,185.46 114.34,185.68 113.91,185.68 113.69,185.46 113.69,184.77 113.48,184.56 113.05,184.56 112.83,184.77 112.83,184.91 112.48,185.27 111.72,185.27 110.8,184.35 104.2,184.35 103.33,185.22 97.21,185.22 96.91,185.52 96.4,185.52 v4(96.25,185.68)
  BOTTOM w0.102: v3(149.51,184.28) 149.16,183.82 146.32,183.82 145.41,184.73 143.48,184.73 142.64,183.9 v3(142.53,183.9) 142.45,183.82 139.7,183.82 139.05,184.48 138.6,184.48 138.47,184.6 135.97,184.6 v2(135.82,184.45) 134.96,184.45 v3(134.4,183.9)
M_DATA_A10: length 79.1
  TOP w0.165: v3(132.75,180.72) 132.52,180.95 DIMM1.33 ; DIMM2.33 147.76,180.95 v3(147.99,181.1) ; v4(96.93,182.91) 96.5,182.47 96.5,182.18 95.31,181 CPU1.B32
  L3 w0.216: v3(140.88,180.97) 140.41,180.97 139.52,181.86 131.87,181.86 131.15,182.58 120.04,182.58 119.83,182.37 119.83,182.09 119.61,181.87 119.18,181.87 118.72,182.33 114.48,182.33 114.26,182.12 114.26,181.39 114.05,181.18 113.61,181.18 113.4,181.39 113.4,182.12 113.18,182.33 112.75,182.33 112.53,182.12 112.53,181.39 112.32,181.18 111.89,181.18 111.67,181.39 111.67,182.12 111.45,182.33 111.02,182.33 110.81,182.12 110.81,181.39 110.59,181.18 110.16,181.18 109.94,181.39 109.94,182.12 109.73,182.33 109.3,182.33 109.08,182.12 109.08,181.39 108.86,181.18 108.43,181.18 108.22,181.39 108.22,182.12 108,182.33 107.57,182.33 107.35,182.12 107.35,181.39 107.14,181.18 106.71,181.18 106.49,181.39 106.49,182.12 106.27,182.33 105.84,182.33 105.63,182.12 105.63,181.39 105.41,181.18 104.98,181.18 104.76,181.39 104.76,182.12 104.55,182.33 102.93,182.33 102.51,182.75 97.09,182.75 v4(96.93,182.91)
  BOTTOM w0.102: v3(132.75,180.72) 132.86,180.72 133.69,181.55 v2(134.27,181.55) 134.78,181.55 135.16,181.93 138.75,181.93 139.71,180.97 v3(140.88,180.97) 141.46,181.56 147.22,181.56 147.67,181.1 v3(147.99,181.1)
M_DATA_A11: length 80.8
  TOP w0.165: DIMM1.35 132.43,180.35 132.55,180.23 133.78,180.23 v3(134.27,180.72) ; v4(94.72,179.91) 94.7,179.88 CPU1.D32 ; v3(149.51,181.1) 148.76,180.35 DIMM2.35
  L3 w0.216: v4(94.72,179.91) 94.14,180.49 94.14,182.48 94.95,183.29 95.74,183.29 96.47,182.56 96.47,182.08 96.74,181.81 97.29,181.81 97.53,182.05 98.41,182.05 99.04,181.41 102.47,181.41 103.27,180.62 114.75,180.62 114.97,180.84 114.97,181.24 115.18,181.46 115.62,181.46 115.83,181.24 115.83,180.84 116.05,180.62 116.7,180.62 117.46,181.38 120.83,181.38 121.05,181.6 121.05,181.88 121.27,182.09 121.7,182.09 121.91,181.88 121.91,181.6 122.13,181.38 122.56,181.38 122.78,181.6 122.78,181.88 122.99,182.09 123.42,182.09 123.64,181.88 123.64,181.6 123.86,181.38 131.65,181.38 131.66,181.37 139.31,181.37 140.23,180.46 141.85,180.46 142.37,180.97 v3(142.4,180.97)
  BOTTOM w0.102: v3(149.51,181.1) 149.05,180.64 147.6,180.64 147.06,181.18 142.78,181.18 v3(142.4,180.97) 141.94,180.52 139.56,180.52 138.52,181.55 135.99,181.55 v2(135.54,181.1) 135.16,180.72 v3(134.27,180.72)
M_DATA_A12: length 80.5
  TOP w0.102: 92.41,183.34 92.18,183.11 92.18,182.22 92.09,182.13 92.09,181.65 92.1,181.64 92.1,181 CPU1.B28
  TOP w0.165: v4(93.38,184.91) 93.38,184.3 92.41,183.34 ; v3(153.07,184.15) 153.17,184.25 DIMM2.22 ; DIMM1.22 138.17,184.25 138.03,184.38 136.79,184.38 v3(136.3,183.77)
  L3 w0.216: v4(93.38,184.91) 93.38,184.91 95.12,186.66 132.12,186.66 132.34,186.44 138.94,186.44 140.46,184.92 142.56,184.92 v3(143.29,183.9)
  BOTTOM w0.102: v3(136.3,183.77) 136.66,184.23 138.31,184.23 v2(138.78,183.76) 139.1,183.44 142.83,183.44 v3(143.29,183.9) 143.75,184.35 145.26,184.35 146.17,183.44 150.19,183.44 151.35,184.61 152.61,184.61 v3(153.07,184.15)
M_DATA_A13: length 78.8
  TOP w0.102: CPU1.B29 92.6,181.1 92.48,181.57 92.3,181.75 92.3,182.03 92.44,182.17 92.44,182.73 v4(92.59,182.88)
  TOP w0.165: DIMM2.24 152.04,183.65 v3(151.54,184.15) ; v3(137.83,183.77) 138.07,183.65 DIMM1.24
  L3 w0.216: v4(92.59,182.88) 92.59,184.82 94.92,187.15 132.33,187.15 132.54,186.93 139.14,186.93 140.66,185.41 143.55,185.41 v3(144.81,183.9)
  BOTTOM w0.102: v3(151.54,184.15) 150.46,183.07 145.64,183.07 v3(144.81,183.9) 143.92,183 143.1,183 143.05,182.96 143.04,182.96 142.8,182.71 v2(141.97,182.71) 141.23,182.71 140.94,183 138.6,183 v3(137.83,183.77)
M_DATA_A14: length 78
  TOP w0.165: v4(94.6,182.29) 94.21,181.9 CPU1.A31 ; v3(137.83,180.72) 137.9,180.65 DIMM1.34 ; DIMM2.34 153.14,180.65 v3(153.07,180.72)
  L3 w0.216: v3(144.69,180.34) 143.83,179.48 131.94,179.48 131.07,178.61 130.58,178.61 130.37,178.83 130.37,179.34 130.15,179.55 129.72,179.55 129.5,179.34 129.5,178.83 129.29,178.61 128.85,178.61 128.64,178.83 128.64,179.34 128.42,179.55 127.99,179.55 127.77,179.34 127.77,178.83 127.56,178.61 127.13,178.61 126.91,178.83 126.91,179.34 126.7,179.55 126.26,179.55 126.05,179.34 126.05,178.83 125.83,178.61 125.24,178.61 125.03,178.83 125.03,179 124.81,179.21 124.38,179.21 124.16,179 124.16,178.83 123.95,178.61 99.4,178.61 97.85,180.16 97.03,180.16 96.69,179.82 96.41,179.82 96.36,179.88 94.6,181.63 v4(94.6,182.29)
  BOTTOM w0.102: v3(137.83,180.72) 138.29,180.72 139.24,179.77 142.25,179.77 142.37,179.88 143.35,179.88 143.36,179.89 144.24,179.89 v3(144.69,180.34) 144.89,180.14 v2(145.85,180.14) 147,180.14 147.24,179.89 152.24,179.89 v3(153.07,180.72)
M_DATA_A15: length 80.8
  TOP w0.165: v4(95.55,181.86) 95.08,181.38 94.84,181.38 94.2,180.74 CPU1.C31 ; v3(151.54,180.72) 152.21,180.05 DIMM2.36 ; DIMM1.36 136.97,180.05 v3(136.3,180.72)
  L3 w0.216: v3(143.16,180.34) 142.79,179.97 132.25,179.97 131.66,180.57 125.92,180.57 125.05,179.71 124.56,179.71 124.35,179.92 124.35,180.38 124.13,180.59 123.7,180.59 123.48,180.38 123.48,179.92 123.27,179.71 122.83,179.71 122.62,179.92 122.62,180.38 122.4,180.59 121.97,180.59 121.75,180.38 121.75,179.92 121.54,179.71 121.11,179.71 120.89,179.92 120.89,180.38 120.68,180.59 120.24,180.59 120.03,180.38 120.03,179.92 119.81,179.71 119.38,179.71 119.16,179.92 119.16,180.38 118.95,180.59 118.52,180.59 118.3,180.38 118.3,179.92 118.08,179.71 117.42,179.71 116.99,180.13 116.55,180.13 116.13,179.71 115.69,179.71 115.26,180.13 114.82,180.13 114.4,179.71 103.49,179.71 102.27,180.92 98.09,180.92 97.82,180.66 96.97,180.66 95.77,181.86 v4(95.55,181.86)
  BOTTOM w0.102: v3(151.54,180.72) v2(150.5,180.72) 149.95,180.72 149.49,180.27 147.44,180.27 146.91,180.81 143.63,180.81 v3(143.16,180.34) 142.3,180.34 142.1,180.14 139.4,180.14 138.36,181.18 136.76,181.18 v3(136.3,180.72)
M_DATA_A16: length 77.3
  TOP w0.165: v3(132.75,178.69) 132.41,179.15 DIMM1.39 ; v4(93.93,179.15) 93.93,179.02 CPU1.E30 ; DIMM2.39 147.78,179.15 v3(147.99,178.94)
  L4 w0.216: v3(140.88,178.69) 140.88,178.79 140.44,179.23 140.26,179.23 139.3,180.18 132.52,180.18 130.8,181.91 125.11,181.91 124.06,182.96 123.52,182.96 123.3,182.75 123.3,182.12 123.08,181.91 122.65,181.91 122.44,182.12 122.44,182.75 122.22,182.96 121.79,182.96 121.57,182.75 121.57,182.12 121.36,181.91 120.92,181.91 120.71,182.12 120.71,182.75 120.49,182.96 120.06,182.96 119.85,182.75 119.85,182.12 119.63,181.91 119.2,181.91 118.98,182.12 118.98,182.75 118.77,182.96 99.67,182.96 98.2,181.5 98.2,181.34 96.07,179.2 93.97,179.2 v4(93.93,179.15)
  BOTTOM w0.102: v3(132.75,178.69) 133.21,178.23 134.91,178.23 135.03,178.36 v2(135.04,178.36) 135.04,178.36 135.82,179.15 138.8,179.15 138.95,178.99 140.57,178.99 v3(140.88,178.69) 140.75,178.56 140.5,178.56 140.39,178.46 140.39,178.23 140.5,178.13 141.05,178.13 141.16,178.23 142.76,178.23 143.66,179.14 147.79,179.14 v3(147.99,178.94)
M_DATA_A17: length 80.5
  TOP w0.165: CPU1.E31 94.3,178.66 94.71,179.07 95.9,179.07 98.83,182 v1(99.63,182) v4(100.72,182) ; v3(134.27,178.69) 133.78,178.2 132.55,178.2 132.2,178.55 DIMM1.41 ; v3(149.51,178.94) 149.02,178.45 147.79,178.45 147.69,178.55 DIMM2.41
  L4 w0.216: v3(142.4,178.69) 141.89,178.17 140.61,178.17 139.1,179.69 132.32,179.69 130.59,181.42 118.28,181.42 118.06,181.63 118.06,182.26 117.84,182.47 117.41,182.47 117.2,182.26 117.2,181.63 116.98,181.42 116.55,181.42 116.33,181.63 116.33,182.26 116.12,182.47 115.69,182.47 115.47,182.26 115.47,181.63 115.25,181.42 114.82,181.42 114.61,181.63 114.61,182.26 114.39,182.47 101.2,182.47 v4(100.72,182)
  BOTTOM w0.102: v3(149.51,178.94) 149.54,178.97 150.05,178.97 150.2,179.12 150.2,179.37 150.06,179.52 143.52,179.52 143.51,179.51 143.22,179.51 v3(142.4,178.69) 141.7,179.39 139.09,179.39 138.96,179.52 134.53,179.52 134.27,179.27 v3(134.27,178.69)
M_DATA_A18: length 78.3
  TOP w0.165: DIMM1.51 132.71,175.55 v3(132.75,175.51) ; DIMM2.51 147.95,175.55 v3(147.99,175.51) ; CPU1.G33 95.91,177.01 96.83,177.01 97.52,177.7 97.52,177.85 98.81,179.15 100.19,179.15 100.23,179.1 v4(100.24,179.1) v1(100.24,179.94)
  L4 w0.216: v3(141,174.7) 140.7,175 132.53,175 129.04,178.5 128.55,178.5 128.33,178.28 128.33,177.67 128.12,177.45 127.68,177.45 127.47,177.67 127.47,178.28 127.25,178.5 126.82,178.5 126.61,178.28 126.61,177.67 126.39,177.45 125.96,177.45 125.74,177.67 125.74,178.28 125.53,178.5 125.09,178.5 124.88,178.28 124.88,177.67 124.66,177.45 124.23,177.45 124.01,177.67 124.01,178.28 123.8,178.5 123.37,178.5 123.15,178.28 123.15,177.67 122.93,177.45 122.5,177.45 122.29,177.67 122.29,178.28 122.07,178.5 121.64,178.5 121.42,178.28 121.42,177.67 121.21,177.45 120.78,177.45 120.56,177.67 120.56,178.28 120.34,178.5 119.91,178.5 119.7,178.28 119.7,177.67 119.48,177.45 119.05,177.45 118.83,177.67 118.83,178.28 118.62,178.5 107.37,178.5 106.28,179.59 101.93,179.59 101.93,179.59 101.52,179.59 101.52,179.59 100.73,179.59 100.25,179.1 v4(100.24,179.1)
  BOTTOM w0.102: v3(147.99,175.51) 145.5,175.51 144.94,174.95 143.03,174.95 142.77,175.21 141.58,175.21 141.07,174.7 v3(141,174.7) 140.73,174.97 135.46,174.97 134.46,175.97 133.21,175.97 v3(132.75,175.51)
M_DATA_A19: length 81.5
  TOP w0.102: 97.83,177.79 97.83,177.68 96.85,176.7 95.75,176.7 95.74,176.71 95.39,176.71 CPU1.G32
  TOP w0.165: DIMM1.53 133.71,174.95 v3(134.27,175.51) ; 97.83,177.79 98.28,178.23 100.86,178.23 v4(101.73,179.1) 102.55,179.1 v1(102.57,179.12) ; v3(149.51,175.51) 148.95,174.95 DIMM2.53
  L4 w0.216: v3(142.53,174.76) 141.96,174.19 138.65,174.19 138.32,174.51 132.33,174.51 129.88,176.96 118.19,176.96 117.97,177.18 117.97,177.79 117.76,178.01 117.32,178.01 117.11,177.79 117.11,177.18 116.89,176.96 116.46,176.96 116.24,177.18 116.24,177.79 116.03,178.01 115.6,178.01 115.38,177.79 115.38,177.18 115.17,176.96 114.73,176.96 114.52,177.18 114.52,177.79 114.3,178.01 113.74,178.01 113.52,177.79 113.52,177.18 113.3,176.96 112.87,176.96 112.66,177.18 112.66,177.79 112.44,178.01 107.17,178.01 106.08,179.1 101.73,179.1 v4(101.73,179.1)
  BOTTOM w0.102: v3(149.51,175.51) 149.56,175.56 150.05,175.56 150.15,175.46 150.15,175.05 150.05,174.95 145.49,174.95 145.1,174.57 142.72,174.57 v3(142.53,174.76) 142.01,174.24 135.54,174.24 v3(134.27,175.51)
M_DATA_A20: length 79.8
  TOP w0.165: v3(137.83,178.69) 137.99,178.85 DIMM1.40 ; CPU1.C33 95.9,180.31 96.37,180.78 97.03,180.78 97.72,181.47 v4(97.72,181.58) ; v3(153.07,178.82) 153.1,178.85 DIMM2.40
  L4 w0.216: v4(97.72,181.58) 97.72,181.71 99.46,183.45 124.88,183.45 125.1,183.24 125.1,182.61 125.32,182.4 125.75,182.4 125.96,182.61 125.96,183.24 126.18,183.45 126.61,183.45 126.83,183.24 126.83,182.61 127.04,182.4 127.47,182.4 127.69,182.61 127.69,183.24 127.91,183.45 128.34,183.45 128.55,183.24 128.55,182.61 128.77,182.4 129.2,182.4 129.42,182.61 129.42,183.24 129.63,183.45 130.37,183.45 132.34,181.48 132.75,181.48 132.75,181.48 138.69,181.48 140.46,179.72 142.1,179.72 143.49,178.32 v3(143.49,178.25)
  BOTTOM w0.102: v3(137.83,178.69) 138.72,178.69 138.8,178.62 139.62,178.62 139.76,178.48 139.76,178.28 139.66,178.18 138.59,178.18 138.49,178.07 138.49,177.85 138.59,177.75 139.53,177.75 139.63,177.65 139.63,177.58 139.73,177.47 139.93,177.47 140.03,177.58 140.03,177.65 140.14,177.75 140.34,177.75 140.44,177.65 140.44,177.58 140.54,177.47 140.74,177.47 140.85,177.58 140.85,177.65 140.95,177.75 141.15,177.75 141.25,177.65 141.25,177.58 141.35,177.47 141.56,177.47 141.66,177.58 141.66,177.65 141.82,177.81 142.86,177.81 143.31,178.25 v3(143.49,178.25) 144,178.77 145.21,178.77 145.34,178.63 v2(146.18,178.63) 147.08,178.63 147.23,178.49 150.57,178.49 151.35,179.27 152.61,179.27 v3(153.07,178.82)
M_DATA_A21: length 81.2
  TOP w0.165: v4(96.55,180.34) 96.55,180.21 95.74,179.4 CPU1.D33 ; DIMM2.42 152.11,178.25 v3(151.54,178.82) ; v3(136.3,178.69) 136.79,178.2 138.03,178.2 138.08,178.25 DIMM1.42
  L4 w0.216: v4(96.55,180.34) 96.55,181.08 96.5,181.14 96.5,181.52 96.77,181.79 97.11,181.79 99.26,183.94 130.58,183.94 132.55,181.97 138.9,181.97 140.66,180.21 142.57,180.21 142.95,179.83 143.5,179.83 v3(145.02,178.31)
  BOTTOM w0.102: v3(151.54,178.82) 151.57,178.82 152.03,178.36 152.74,178.36 152.84,178.26 152.84,177.8 152.74,177.7 150.96,177.7 150.55,178.11 145.21,178.11 v3(145.02,178.31) 144.95,178.31 144.47,177.83 144.44,177.83 144.44,177.82 144.09,177.82 143.88,177.62 143.21,177.62 142.85,177.26 142.37,177.26 v2(142.37,177.26) 142.36,177.26 141.88,177.26 141.72,177.1 138.66,177.1 137.99,177.77 137.22,177.77 v3(136.3,178.69)
M_DATA_A22: length 78.1
  TOP w0.165: v3(137.83,175.51) 138.16,175.85 DIMM1.50 ; v3(153.07,175.51) 153.53,175.85 DIMM2.50 ; v4(94.26,177.52) 93.74,177 CPU1.G30
  L4 w0.216: v4(94.26,177.52) 94.53,177.52 94.75,177.31 94.75,176.42 94.97,176.2 95.47,176.2 95.69,176.42 95.69,178.17 95.91,178.38 97.92,178.38 98.06,178.52 98.07,178.52 98.34,178.79 98.34,178.81 98.59,179.05 98.59,179.29 99.86,180.57 101.12,180.57 101.12,180.57 102.34,180.57 102.34,180.57 106.69,180.57 107.78,179.48 129.45,179.48 132.28,176.64 133.78,176.64 133.79,176.65 141.66,176.65 141.76,176.56 144.18,176.56 v3(144.91,175.82)
  BOTTOM w0.102: v3(153.07,175.51) 152.61,175.06 151.21,175.06 v2(150.72,175.55) 150.3,175.97 145.14,175.97 144.99,175.82 v3(144.91,175.82) 144.43,175.33 143.19,175.33 142.59,175.93 141.89,175.93 141.79,175.82 141.79,175.69 141.69,175.59 141.48,175.59 141.38,175.69 141.38,175.82 141.28,175.93 140.9,175.93 140.33,175.35 138,175.35 v3(137.83,175.51)
M_DATA_A23: length 80.2
  TOP w0.165: CPU1.G31 94.63,177 94.96,177.33 96.05,177.33 96.11,177.28 96.48,177.28 97.08,177.88 v4(97.08,177.88) ; v3(151.54,175.51) 152.03,174.9 153.27,174.9 153.62,175.25 DIMM2.52 ; v3(136.3,175.51) 136.79,175.03 138.03,175.03 138.25,175.25 DIMM1.52
  L4 w0.216: v4(97.08,177.88) 96.81,177.61 96.81,176.47 97.02,176.25 97.4,176.25 97.61,176.47 97.61,177.09 98.66,178.13 98.66,178.67 100.07,180.08 101.32,180.08 101.32,180.08 102.13,180.08 102.13,180.08 106.48,180.08 107.58,178.99 129.24,178.99 132.08,176.15 133.98,176.15 133.99,176.16 138.42,176.16 138.74,175.83 143.39,175.83 v3(143.39,175.84)
  BOTTOM w0.102: v3(151.54,175.51) 150.71,176.35 147.65,176.35 147.31,176.69 v2(146.5,176.69) 145.43,176.69 145.13,176.39 144.01,176.39 143.93,176.31 143.87,176.31 143.4,175.84 v3(143.39,175.84) 143.32,175.84 142.86,176.3 140.75,176.3 140.17,175.72 138.36,175.72 137.45,176.63 136.56,176.63 136.3,176.38 v3(136.3,175.51)
M_DATA_A24: length 82.9
  TOP w0.102: CPU1.J30 94.14,175.1 94.43,175.1 94.63,175.31 94.63,175.36 94.97,175.7 95.26,175.7 95.27,175.69 95.75,175.69 95.77,175.71 97.02,175.71 97.37,176.06 98.55,176.06 98.59,176.09
  TOP w0.165: DIMM1.57 132.48,173.75 v3(132.75,173.48) ; v4(99.7,176.3) 99.68,176.28 99.1,176.28 98.92,176.09 98.59,176.09 ; v3(147.99,173.35) 147.72,173.75 DIMM2.57
  L4 w0.216: v3(142.5,172.32) 142.04,171.86 141.35,171.86 140.94,171.44 132.37,171.44 130.75,173.06 130.22,173.06 130.01,172.84 130.01,171.65 129.79,171.43 129.36,171.43 129.14,171.65 129.14,172.84 128.93,173.06 128.5,173.06 128.28,172.84 128.28,171.65 128.06,171.43 127.63,171.43 127.42,171.65 127.42,172.84 127.2,173.06 106.32,173.06 102.86,176.52 99.92,176.52 v4(99.7,176.3)
  BOTTOM w0.102: v3(132.75,173.48) 134.41,171.82 134.82,171.82 v2(134.84,171.84) 135.18,171.5 138.02,171.5 138.42,171.9 140.39,171.9 140.46,171.83 141.86,171.83 142.18,172.16 142.19,172.16 142.36,172.32 v3(142.5,172.32) 144.49,172.32 147.87,172.32 147.94,172.39 150.22,172.39 150.32,172.49 150.32,172.8 150.22,172.9 148.56,172.9 148.1,173.35 v3(147.99,173.35)
M_DATA_A25: length 83.8
  TOP w0.102: CPU1.J31 94.35,175.4 94.86,175.91 95.34,175.91 95.35,175.9 95.67,175.9 95.7,175.92 96.94,175.92 97.89,176.87 98.32,176.87 98.59,176.6 v4(98.7,176.6)
  TOP w0.165: v3(134.27,173.48) 133.78,172.99 132.55,172.99 132.39,173.15 DIMM1.59 ; v3(149.51,173.35) 149.02,172.87 147.79,172.87 147.5,173.15 DIMM2.59
  L4 w0.216: v3(140.98,172.39) 140.94,172.36 138.16,172.36 138.04,172.47 132.03,172.47 130.78,173.72 117.7,173.72 117.48,173.94 117.48,174.85 117.27,175.06 116.84,175.06 116.62,174.85 116.62,173.94 116.41,173.72 115.97,173.72 115.76,173.94 115.76,174.85 115.54,175.06 115.11,175.06 114.89,174.85 114.89,173.94 114.68,173.72 114.25,173.72 114.03,173.94 114.03,174.85 113.81,175.06 113.38,175.06 113.17,174.85 113.17,173.94 112.95,173.72 112.52,173.72 112.3,173.94 112.3,174.85 112.09,175.06 111.66,175.06 111.44,174.85 111.44,173.94 111.22,173.72 110.71,173.72 109.37,175.06 105.02,175.06 103.07,177.01 99.11,177.01 v4(98.7,176.6)
  BOTTOM w0.102: v3(134.27,173.48) 134.27,172.85 134.6,172.52 135.24,172.52 135.34,172.62 135.34,173.43 135.44,173.53 135.64,173.53 135.75,173.43 135.75,172.62 135.85,172.52 136.63,172.52 136.66,172.48 v2(136.69,172.48) 136.73,172.52 140.82,172.52 140.95,172.39 v3(140.98,172.39) 141.01,172.39 141.48,172.85 142.62,172.85 142.77,172.7 144.64,172.7 146.68,172.7 147.8,173.81 149.05,173.81 v3(149.51,173.35)
M_DATA_A26: length 81.8
  TOP w0.165: DIMM1.67 132.31,170.75 v3(132.75,170.31) ; v4(102.12,174.5) 101.99,174.62 101.93,174.62 101.6,174.96 100.85,174.96 100.85,174.96 100.8,174.96 100.36,175.4 99.4,175.4 99.37,175.44 98.32,175.44 96.68,173.8 CPU1.L33 ; DIMM2.67 147.54,170.75 v3(147.99,170.05)
  L4 w0.216: v4(102.12,174.5) 102.27,174.5 105.56,171.21 113.18,171.21 113.4,170.99 113.4,169.18 113.61,168.97 114.05,168.97 114.26,169.18 114.26,170.99 114.48,171.21 114.91,171.21 115.13,170.99 115.13,169.18 115.34,168.97 116.1,168.97 116.31,169.18 116.31,170.17 116.53,170.39 116.96,170.39 117.18,170.17 117.18,169.18 117.39,168.97 119.75,168.97 119.97,169.18 119.97,169.37 120.19,169.58 120.62,169.58 120.83,169.37 120.83,169.18 121.05,168.97 121.48,168.97 121.7,169.18 121.7,169.37 121.91,169.58 122.35,169.58 122.56,169.37 122.56,169.18 122.78,168.97 123.21,168.97 123.43,169.18 123.43,169.37 123.64,169.58 124.07,169.58 124.29,169.37 124.29,169.18 124.5,168.97 124.94,168.97 125.15,169.18 125.15,169.37 125.37,169.58 125.8,169.58 126.02,169.37 126.02,169.18 126.23,168.97 126.66,168.97 126.88,169.18 126.88,169.37 127.1,169.58 127.53,169.58 127.74,169.37 127.74,169.18 127.96,168.97 128.39,168.97 128.61,169.18 128.61,169.37 128.82,169.58 129.25,169.58 129.47,169.37 129.47,169.18 129.69,168.97 130.12,168.97 130.33,169.18 130.33,169.37 130.55,169.58 130.98,169.58 131.2,169.37 131.2,169.18 131.41,168.97 140.81,168.97 v3(141,169.16)
  BOTTOM w0.102: v3(132.75,170.31) 133.96,169.1 140.94,169.1 v3(141,169.16) 142.21,167.95 145.64,167.95 145.76,168.08 v2(147.17,169.33) v3(147.99,170.05)
M_DATA_A27: length 83.4
  TOP w0.102: CPU1.L32 95.44,173.8 95.75,173.5 96.75,173.5 97.06,173.8
  TOP w0.165: DIMM1.69 132.21,170.15 132.55,169.82 133.78,169.82 v3(134.27,170.31) ; 97.06,173.8 98.22,174.96 100.17,174.96 100.61,174.52 100.67,174.52 v4(100.69,174.5) ; DIMM2.69 147.2,170.15 147.79,169.56 148.95,169.56 149.24,169.85 v3(149.51,170.05)
  L4 w0.216: v4(100.69,174.5) 101.18,174.01 101.91,174.01 102.07,174.01 105.36,170.72 106.86,170.72 109.1,168.48 109.73,168.48 109.94,168.69 109.94,170.5 110.16,170.72 110.59,170.72 110.8,170.5 110.8,168.69 111.02,168.48 111.45,168.48 111.67,168.69 111.67,170.5 111.88,170.72 112.32,170.72 112.53,170.5 112.53,168.69 112.75,168.48 132.43,168.48 141.84,168.48 v3(142.53,169.16)
  BOTTOM w0.102: v3(149.51,170.05) 149.15,170.51 147.54,170.51 145.37,168.33 143.36,168.33 v3(142.53,169.16) 142.07,169.62 v2(139.81,169.62) 138.37,169.62 138.22,169.47 135.11,169.47 v3(134.27,170.31)
M_DATA_A28: length 81.5
  TOP w0.102: CPU1.H32 95,176.5 95.64,176.5 95.65,176.49 96.93,176.49 97.98,177.55 98.2,177.55
  TOP w0.165: DIMM2.56 153.64,174.05 v3(153.07,173.61) ; 98.2,177.55 99.75,177.55 v4(99.79,177.51) ; DIMM1.56 138.4,174.05 v3(137.83,173.48)
  L4 w0.216: v3(144.99,173.53) 144.97,173.55 144.97,173.58 144.44,174.1 142.94,174.1 142.54,173.7 138.38,173.7 138.05,174.02 131.87,174.02 129.85,176.04 129.19,176.04 128.97,175.83 128.97,174.92 128.75,174.7 128.32,174.7 128.11,174.92 128.11,175.83 127.89,176.04 127.46,176.04 127.24,175.83 127.24,174.92 127.03,174.7 126.6,174.7 126.38,174.92 126.38,175.83 126.16,176.04 125.73,176.04 125.52,175.83 125.52,174.92 125.3,174.7 124.87,174.7 124.65,174.92 124.65,175.83 124.44,176.04 105.42,176.04 103.43,178.04 100.29,178.04 99.93,177.67 99.93,177.66 v4(99.79,177.51)
  BOTTOM w0.102: v3(137.83,173.48) 138.21,173.87 138.59,173.87 138.69,173.77 138.69,173.51 138.79,173.41 139,173.41 139.1,173.51 139.1,173.77 139.2,173.87 139.4,173.87 139.5,173.77 139.5,173.51 139.61,173.41 139.81,173.41 139.91,173.51 139.91,173.77 140.01,173.87 142.17,173.87 142.48,174.18 144.6,174.18 144.99,173.79 v3(144.99,173.53) 146.02,174.56 151.96,174.56 v2(152.12,174.4) 152.28,174.4 v3(153.07,173.61)
M_DATA_A29: length 82.2
  TOP w0.102: CPU1.H33 96.93,176.2 98,177.28 98.72,177.28
  TOP w0.165: v3(151.54,173.61) 152.03,172.99 153.27,172.99 153.73,173.45 DIMM2.58 ; v3(136.3,173.48) 136.79,172.99 138.03,172.99 138.49,173.45 DIMM1.58 ; v4(101.21,177.55) 100.55,176.89 100.35,176.89 100.34,176.89 99.12,176.89 98.72,177.28
  L4 w0.216: v4(101.21,177.55) 103.23,177.55 105.22,175.55 118.28,175.55 118.5,175.34 118.5,174.43 118.71,174.21 119.27,174.21 119.48,174.43 119.48,175.34 119.7,175.55 120.13,175.55 120.35,175.34 120.35,174.43 120.56,174.21 121,174.21 121.21,174.43 121.21,175.34 121.43,175.55 121.86,175.55 122.08,175.34 122.08,174.43 122.29,174.21 122.72,174.21 122.94,174.43 122.94,175.34 123.16,175.55 123.59,175.55 123.8,175.34 123.8,174.43 124.02,174.21 130.98,174.21 132.23,172.97 142.88,172.97 v3(143.47,173.56)
  BOTTOM w0.102: v3(136.3,173.48) 136.76,173.02 140.19,173.02 140.39,173.23 140.77,173.23 140.87,173.33 140.87,173.39 140.97,173.49 141.18,173.49 141.28,173.39 141.28,173.33 141.38,173.23 141.58,173.23 141.68,173.33 141.68,173.39 141.79,173.49 141.99,173.49 142.09,173.39 142.09,173.33 142.19,173.23 143.14,173.23 v3(143.47,173.56) 143.95,173.07 144.8,173.07 145.7,173.07 v2(146.36,173.73) 146.82,174.19 150.96,174.19 v3(151.54,173.61)
M_DATA_A30: length 81
  TOP w0.165: v3(153.07,170.05) 153.39,170.38 153.54,170.38 153.62,170.45 DIMM2.68 ; CPU1.L30 93.5,173.76 v4(93.86,173.41) ; DIMM1.68 137.97,170.45 v3(137.83,170.31)
  L4 w0.216: v3(144.81,169.16) 144.3,168.65 143.47,168.65 142.31,167.5 132.84,167.5 132.43,167.5 132.03,167.5 104.39,167.5 103.61,168.27 103.61,171.07 102.93,171.76 102.62,171.76 101.91,171.05 101.6,171.05 101.3,171.36 101.3,171.66 102.01,172.37 102.01,172.68 101.66,173.03 100.02,173.03 99.11,173.94 99.11,173.95 99.1,173.96 94.41,173.96 v4(93.86,173.41)
  BOTTOM w0.102: v3(153.07,170.05) 152.31,170.89 151.97,171.26 146.91,171.26 v2(145.54,169.89) v3(144.81,169.16) 144.81,170.64 144.71,170.74 137.93,170.74 137.83,170.64 v3(137.83,170.31)
M_DATA_A31: length 83.6
  TOP w0.102: 97.28,173.65 96.93,173.29 95.65,173.29 95.61,173.33 94.77,173.33 CPU1.L31
  TOP w0.165: v3(151.54,170.05) 152.03,169.56 153.27,169.56 153.56,169.85 DIMM2.70 ; v4(99.22,174.45) 98.08,174.45 97.28,173.65 ; v3(136.3,170.31) 136.79,169.82 138.03,169.82 138.06,169.85 DIMM1.70
  L4 w0.216: v4(99.22,174.45) 99.29,174.45 100.23,173.52 101.71,173.52 101.86,173.52 104.1,171.28 104.1,168.47 104.59,167.99 105.89,167.99 106.11,168.2 106.11,169.48 106.32,169.7 106.76,169.7 106.97,169.48 106.97,168.2 107.19,167.99 132.23,167.99 132.63,167.99 142.11,167.99 v3(143.29,169.16)
  BOTTOM w0.102: v3(136.3,170.31) 136.76,169.85 138.02,169.85 138.29,170.12 138.29,170.26 138.39,170.36 143.95,170.36 144.05,170.26 144.05,169.72 143.95,169.62 143.75,169.62 v3(143.29,169.16) 143.75,168.71 145.21,168.71 147.39,170.89 149.9,170.89 v2(150.1,170.69) 150.91,170.69 v3(151.54,170.05)
M_DATA_A32: length 82.7
  TOP w0.102: CPU1.AN31 94.54,156.06 95.23,155.8 95.54,155.8 95.64,155.69 96.19,155.69 96.3,155.81 96.78,155.81 96.81,155.77
  TOP w0.165: DIMM2.129 147.84,149.75 v3(147.99,149.61) ; v3(132.75,149.48) 132.48,149.75 DIMM1.129 ; v4(97.13,155.31) 97.13,155.45 96.81,155.77
  L4 w0.216: v3(142.3,149.86) 141.41,150.75 140.53,150.75 138.62,152.66 137.45,152.66 137.37,152.74 129.13,152.74 127.38,154.49 126.89,154.49 126.67,154.71 126.67,155.08 126.46,155.3 126.02,155.3 125.81,155.08 125.81,154.71 125.59,154.49 125.16,154.49 124.95,154.71 124.95,155.08 124.73,155.3 124.3,155.3 124.08,155.08 124.08,154.71 123.87,154.49 123.43,154.49 123.22,154.71 123.22,155.08 123,155.3 122.57,155.3 122.35,155.08 122.35,154.71 122.14,154.49 121.71,154.49 121.49,154.71 121.49,155.08 121.27,155.3 120.84,155.3 120.63,155.08 120.63,154.71 120.41,154.49 119.98,154.49 119.76,154.71 119.76,155.08 119.55,155.3 119.12,155.3 118.9,155.08 118.9,154.71 118.68,154.49 118.25,154.49 118.04,154.71 118.04,155.08 117.82,155.3 117.39,155.3 117.17,155.08 117.17,154.71 116.96,154.49 104.5,154.49 103.18,155.81 102.37,155.81 97.63,155.81 v4(97.13,155.31)
  BOTTOM w0.102: v3(132.75,149.48) v2(134.06,150.79) 134.49,151.22 140.94,151.22 v3(142.3,149.86) 142.3,151.18 142.55,151.43 142.93,151.43 143.03,151.33 143.03,150.83 143.13,150.72 143.33,150.72 143.44,150.83 143.44,151.33 143.54,151.43 143.74,151.43 143.84,151.33 143.84,150.83 143.94,150.72 144.15,150.72 144.25,150.83 144.25,151.33 144.35,151.43 144.86,151.43 145.12,151.18 145.12,150.2 145.71,149.61 v3(147.99,149.61)
M_DATA_A33: length 83
  TOP w0.102: CPU1.AP32 95.05,155.4 95.35,155.1 95.64,155.1 95.65,155.11 96.19,155.11 96.4,154.9 97.88,154.9 98.14,154.64
  TOP w0.165: v3(149.51,149.61) 149.02,149.12 147.79,149.12 147.75,149.15 DIMM2.131 ; DIMM1.131 132.39,149.15 132.55,148.99 133.78,148.99 v3(134.27,149.48) ; v4(98.97,154.81) 98.8,154.64 98.14,154.64
  L4 w0.216: v4(98.97,154.81) 99.47,155.32 102.57,155.32 102.98,155.32 104.29,154 110.36,154 110.57,153.78 110.57,153.33 110.79,153.12 111.22,153.12 111.44,153.33 111.44,153.78 111.65,154 112.09,154 112.3,153.78 112.3,153.33 112.52,153.12 112.95,153.12 113.17,153.33 113.17,153.78 113.38,154 113.81,154 114.03,153.78 114.03,153.33 114.24,153.12 114.68,153.12 114.89,153.33 114.89,153.78 115.11,154 115.54,154 115.76,153.78 115.76,153.33 115.97,153.12 116.4,153.12 116.62,153.33 116.62,153.78 116.84,154 117.27,154 117.48,153.78 117.48,153.33 117.7,153.12 118.13,153.12 118.35,153.33 118.35,153.78 118.56,154 118.99,154 119.21,153.78 119.21,153.33 119.43,153.12 119.86,153.12 120.07,153.33 120.07,153.78 120.29,154 127.18,154 128.92,152.25 137.17,152.25 137.25,152.17 138.41,152.17 v3(140.75,149.83)
  BOTTOM w0.102: v3(134.27,149.48) 134.25,149.5 134.25,149.89 134.32,149.96 134.62,149.96 134.72,150.06 134.72,150.58 134.82,150.68 135.03,150.68 135.13,150.58 135.13,150.06 135.23,149.96 135.43,149.96 135.53,150.06 135.53,150.58 135.64,150.68 135.84,150.68 135.94,150.58 135.94,150.06 136.04,149.96 136.25,149.96 136.97,150.68 v2(137.15,150.68) 140.26,150.68 140.75,150.19 v3(140.75,149.83) 141.21,149.38 142.46,149.38 142.97,149.88 144.85,149.88 145.58,149.15 149.05,149.15 v3(149.51,149.61)
M_DATA_A34: length 82
  TOP w0.102: 97.82,152.81 97.58,152.81 97.21,153.19 96.93,153.19 96.61,153.51 95.65,153.51 95.64,153.5 95,153.5 CPU1.AT32
  TOP w0.165: 97.82,152.81 98.8,152.81 99.12,152.49 99.12,152.49 99.43,152.19 99.9,152.19 v4(100.21,151.89) ; v3(148.12,145.92) 147.89,146.15 DIMM2.141 ; v3(132.75,145.92) 132.23,145.92 132,146.15 DIMM1.141
  L4 w0.216: v3(142.4,145.67) 141.89,146.18 138.3,146.18 138.04,146.44 136.09,146.44 136.07,146.42 134.51,146.42 134.49,146.44 131.66,146.44 130.83,147.27 119.99,147.27 119.78,147.05 119.78,146.63 119.56,146.42 119.13,146.42 118.91,146.63 118.91,147.05 118.7,147.27 118.27,147.27 118.05,147.05 118.05,146.63 117.83,146.42 117.4,146.42 117.19,146.63 117.19,147.05 116.97,147.27 116.54,147.27 116.32,147.05 116.32,146.63 116.11,146.42 115.68,146.42 115.46,146.63 115.46,147.05 115.24,147.27 114.81,147.27 114.6,147.05 114.6,146.63 114.38,146.42 113.95,146.42 113.73,146.63 113.73,147.05 113.52,147.27 113.08,147.27 112.87,147.05 112.87,146.63 112.65,146.42 112.22,146.42 112.01,146.63 112.01,147.05 111.79,147.27 111.36,147.27 111.14,147.05 111.14,146.63 110.93,146.42 110.49,146.42 110.28,146.63 110.28,147.05 110.06,147.27 109.42,147.27 109.2,147.05 109.2,146.63 108.99,146.42 106.35,146.42 101.38,151.38 100.71,151.38 v4(100.21,151.89)
  BOTTOM w0.102: v3(132.75,145.92) 133.21,146.38 134.75,146.38 v2(135.15,145.98) 135.67,145.47 138.02,145.47 138.07,145.52 140.12,145.52 140.42,145.82 140.42,145.83 140.69,146.1 140.7,146.1 140.72,146.13 141.94,146.13 v3(142.4,145.67) 143.44,145.67 143.64,145.47 144.56,145.47 144.57,145.47 145.86,145.47 145.96,145.57 145.96,146.1 146.06,146.2 146.27,146.2 146.37,146.1 146.37,145.57 146.46,145.47 146.68,145.47 146.77,145.57 146.77,146.13 146.88,146.23 147.08,146.23 147.18,146.13 147.18,145.57 147.28,145.47 147.89,145.47 148.12,145.69 v3(148.12,145.92)
M_DATA_A35: length 83.7
  TOP w0.102: 97.95,152.55 97.56,152.55 97.15,152.96 96.65,152.96 96.31,153.3 95.75,153.3 95.45,153 CPU1.AU32
  TOP w0.165: 97.95,152.55 98.69,152.55 99.01,152.22 99.01,152.22 99.42,151.82 99.53,151.82 99.79,151.57 99.79,151.51 v3(100.42,150.87) 101.2,150.09 101.2,150.09 v1(101.25,150.04) ; v3(134.27,145.92) 133.78,145.43 132.55,145.43 132.43,145.55 DIMM1.143 ; DIMM2.143 147.8,145.55 147.91,145.43 149.15,145.43 v3(149.64,145.92)
  L4 w0.216: v3(100.42,150.87) 100.89,150.4 100.95,150.4 101.67,150.4 106.14,145.93 120.5,145.93 120.72,146.14 120.72,146.56 120.93,146.78 121.36,146.78 121.58,146.56 121.58,146.14 121.79,145.93 122.23,145.93 122.44,146.14 122.44,146.56 122.66,146.78 123.09,146.78 123.31,146.56 123.31,146.14 123.52,145.93 123.95,145.93 124.17,146.14 124.17,146.56 124.39,146.78 124.82,146.78 125.03,146.56 125.03,146.14 125.25,145.93 125.68,145.93 125.9,146.14 125.9,146.56 126.11,146.78 126.54,146.78 126.76,146.56 126.76,146.14 126.98,145.93 127.41,145.93 127.62,146.14 127.62,146.56 127.84,146.78 128.27,146.78 128.49,146.56 128.49,146.14 128.7,145.93 129.14,145.93 129.35,146.14 129.35,146.56 129.57,146.78 130,146.78 130.21,146.56 130.21,146.14 130.43,145.93 132.02,145.93 132.53,145.41 138.04,145.41 138.32,145.69 140.83,145.69 v3(140.88,145.64)
  BOTTOM w0.102: v3(134.27,145.92) 133.81,145.47 133.46,145.47 133.36,145.36 133.36,144.68 133.46,144.58 135.34,144.58 135.85,145.09 137.86,145.09 138.17,145.09 138.23,145.15 140.28,145.15 140.77,145.64 v3(140.88,145.64) 141.37,145.15 143.41,145.15 143.47,145.09 144.71,145.09 144.71,145.09 148.7,145.09 149.52,145.92 v3(149.64,145.92)
M_DATA_A36: length 83.1
  TOP w0.102: 98.16,155.6 97.55,156.21 96.06,156.21 96.05,156.2 CPU1.AN33
  TOP w0.165: 98.16,155.6 98.8,155.6 99.36,155.05 100.28,155.05 100.51,154.81 101.28,154.81 v4(101.78,154.31) 101.78,153.47 v1(101.81,153.44) ; v3(137.83,149.48) 137.86,149.45 DIMM1.130 ; v3(153.07,149.48) 153.22,149.45 DIMM2.130
  L4 w0.216: v3(143.49,149.05) 143.27,148.83 139.21,148.83 136.76,151.27 128.92,151.27 128.52,151.27 127.65,152.14 118.74,152.14 118.53,151.93 118.53,151.49 118.32,151.27 117.88,151.27 117.67,151.49 117.67,151.93 117.46,152.14 117.01,152.14 116.8,151.93 116.8,151.49 116.59,151.27 116.16,151.27 115.94,151.49 115.94,151.93 115.73,152.14 115.29,152.14 115.08,151.93 115.08,151.49 114.86,151.27 114.43,151.27 114.21,151.49 114.21,151.93 114.01,152.14 113.56,152.14 113.35,151.93 113.35,151.49 113.13,151.27 112.7,151.27 112.49,151.49 112.49,151.93 112.28,152.14 111.83,152.14 111.62,151.93 111.62,151.49 111.41,151.27 110.98,151.27 110.76,151.49 110.76,151.93 110.55,152.14 110.1,152.14 109.9,151.93 109.9,151.49 109.68,151.27 109.25,151.27 109.03,151.49 109.03,151.93 108.82,152.14 104.77,152.14 102.6,154.31 v4(101.78,154.31)
  BOTTOM w0.102: v3(137.83,149.48) 137.24,148.89 137.24,148.56 137.35,148.46 138.01,148.46 138.17,148.63 138.49,148.63 138.59,148.73 138.59,149.38 138.69,149.48 138.9,149.48 139,149.38 139,148.73 139.1,148.63 139.3,148.63 139.41,148.73 139.41,149.38 139.51,149.48 139.71,149.48 139.81,149.38 139.81,148.73 139.91,148.63 142.77,148.63 143.2,149.05 143.49,149.05 v3(143.49,149.05) 144.15,148.4 151.99,148.4 v3(153.07,149.48)
M_DATA_A37: length 83.6
  TOP w0.102: CPU1.AN32 95.44,156.2 95.75,155.9 96.03,155.9 96.15,156.01 97.13,156.01 97.19,155.96
  TOP w0.165: v3(151.54,149.48) 152.17,148.85 DIMM2.132 ; DIMM1.132 136.88,148.85 v3(136.48,148.45) ; v4(97.82,155.32) 97.19,155.96
  L4 w0.216: v4(97.82,155.32) 97.82,155.13 98.6,154.35 99.16,154.35 99.64,154.83 102.77,154.83 104.97,152.63 120.96,152.63 121.17,152.84 121.17,153.28 121.39,153.49 121.82,153.49 122.04,153.28 122.04,152.84 122.25,152.63 122.69,152.63 122.9,152.84 122.9,153.28 123.12,153.49 123.55,153.49 123.76,153.28 123.76,152.84 123.98,152.63 124.41,152.63 124.63,152.84 124.63,153.28 124.84,153.49 125.28,153.49 125.49,153.28 125.49,152.84 125.71,152.63 127.85,152.63 128.72,151.76 136.97,151.76 139.41,149.32 142.72,149.32 142.97,149.56 144.5,149.56 v3(145.02,149.05)
  BOTTOM w0.102: v3(151.54,149.48) 151.54,149 151.32,148.77 150.81,148.77 150.71,148.87 150.71,149.73 150.6,149.83 150.3,149.83 150.2,149.73 150.2,148.87 150.1,148.77 145.31,148.77 145.03,149.05 v3(145.02,149.05) 144.56,149.51 143.12,149.51 142.62,149 140.92,149 139.78,150.14 v2(139.26,150.14) 138.52,150.14 138.32,149.94 136.88,149.94 136.48,149.54 v3(136.48,148.45)
M_DATA_A38: length 82.6
  TOP w0.102: 95.81,153.96 95.77,153.96 95.59,154.14 94.76,154.14 CPU1.AR31
  TOP w0.165: 95.81,153.96 97.16,153.96 v4(97.31,153.82) ; v3(136.3,145.92) 136.83,146.45 DIMM1.140 ; DIMM2.140 153.6,146.45 v3(153.07,145.92)
  L4 w0.216: v3(144.81,146.35) 143.99,147.17 139.44,147.17 138.52,148.09 136.85,148.09 136.69,147.94 135.88,147.94 135.41,147.47 132.63,147.47 130.77,149.33 123.79,149.33 123.58,149.11 123.58,148.46 123.36,148.25 122.93,148.25 122.71,148.46 122.71,149.11 122.5,149.33 121.94,149.33 121.72,149.11 121.72,148.46 121.51,148.25 105.98,148.25 101.83,152.39 98.34,152.39 97.31,153.43 v4(97.31,153.82)
  BOTTOM w0.102: 144.81,146.36 145.42,146.96 145.53,146.96 145.55,146.98 150.91,146.98 150.99,147.07 150.99,147.43 151.09,147.53 151.3,147.53 151.4,147.43 151.4,146.99 151.5,146.89 152.97,146.89 153.07,146.79 v3(153.07,145.92) ; 144.81,146.36 144.33,146.84 144.15,146.84 143.75,147.24 140.42,147.24 140.21,147.46 v2(139.49,147.46) 138.43,147.46 138.22,147.24 138.21,147.24 137.71,146.74 137.12,146.74 v3(136.3,145.92) ; 144.81,146.36 v3(144.81,146.35)
M_DATA_A39: length 83.7
  TOP w0.102: 97.82,153.08 97.65,153.08 97.34,153.39 97.02,153.39 96.7,153.71 95.59,153.71 CPU1.AT33
  TOP w0.165: v3(151.54,145.92) 152.03,145.43 153.27,145.43 153.69,145.85 DIMM2.142 ; v3(137.83,145.92) 137.9,145.85 DIMM1.142 ; 97.82,153.08 98.91,153.08 99.36,152.63 100.9,152.63 v4(101.76,151.76) v1(102.6,151.76)
  L4 w0.216: v4(101.76,151.76) 101.77,151.76 105.78,147.76 107.32,147.76 107.53,147.54 107.53,147.12 107.75,146.91 108.18,146.91 108.4,147.12 108.4,147.54 108.61,147.76 124.16,147.76 124.37,147.97 124.37,148.55 124.59,148.77 125.02,148.77 125.23,148.55 125.23,147.97 125.45,147.76 125.88,147.76 126.1,147.97 126.1,148.55 126.31,148.77 126.75,148.77 126.96,148.55 126.96,147.97 127.18,147.76 127.61,147.76 127.83,147.97 127.83,148.55 128.04,148.77 128.47,148.77 128.69,148.55 128.69,147.97 128.91,147.76 129.34,147.76 129.55,147.97 129.55,148.55 129.77,148.77 130.2,148.77 130.42,148.55 130.42,147.97 130.63,147.76 131.6,147.76 132.43,146.93 138.99,146.93 139.24,146.68 142.81,146.68 v3(143.24,146.25)
  BOTTOM w0.102: v3(137.83,145.92) 137.83,146.33 138.37,146.87 138.74,146.87 138.84,146.77 138.84,146 138.95,145.9 139.15,145.9 139.25,146 139.25,146.77 139.35,146.87 139.56,146.87 139.66,146.77 139.66,146.02 139.76,145.92 139.96,145.92 140.06,146.02 140.06,146.77 140.16,146.87 140.54,146.87 140.64,146.77 140.64,146.6 140.74,146.5 140.95,146.5 141.05,146.6 141.05,146.77 141.15,146.87 141.35,146.87 141.46,146.77 141.46,146.6 141.56,146.5 141.76,146.5 141.86,146.6 141.86,146.77 141.96,146.87 142.55,146.87 142.91,146.5 142.99,146.5 v3(143.24,146.25) 143.4,146.25 143.81,145.85 144.95,145.85 145.71,146.61 150.86,146.61 v3(151.54,145.92)
M_DATA_A40: length 85.6
  TOP w0.165: v4(93.93,152.58) 93.92,152.58 CPU1.AU30 ; DIMM2.147 149.05,144.35 v3(149.64,143.76) ; DIMM1.147 132.42,144.35 132.73,144.04 v3(132.75,143.89)
  L4 w0.216: v4(93.93,152.58) 94.95,151.56 96.6,151.56 96.78,151.56 96.95,151.56 99.46,149.06 99.46,148.98 100,148.44 100.85,148.44 106.94,142.36 124.73,142.36 124.94,142.58 124.94,143.23 125.16,143.45 125.59,143.45 125.8,143.23 125.8,142.58 126.02,142.36 126.45,142.36 126.67,142.58 126.67,143.23 126.88,143.45 127.32,143.45 127.53,143.23 127.53,142.58 127.75,142.36 128.18,142.36 128.4,142.58 128.4,143.23 128.61,143.45 129.04,143.45 129.26,143.23 129.26,142.58 129.48,142.36 129.91,142.36 130.12,142.58 130.12,143.23 130.34,143.45 130.77,143.45 130.99,143.23 130.99,142.58 131.2,142.36 131.73,142.36 132.25,142.89 138.99,142.89 139.51,143.41 140.62,143.41 v3(140.75,143.54)
  BOTTOM w0.102: v3(132.75,143.89) 132.52,144.12 131.94,144.12 131.63,143.81 131.63,143.23 131.83,143.03 132.75,143.03 133.1,143.38 135.63,143.38 136.13,142.88 v2(136.15,142.88) 139.47,142.88 140.12,143.54 v3(140.75,143.54) 140.76,143.53 141.59,143.53 142.15,142.97 144.51,142.97 144.54,143 145.23,143 145.48,142.75 147.72,142.75 148.28,143.31 149.18,143.31 v3(149.64,143.76)
M_DATA_A41: length 83
  TOP w0.165: v4(96.8,152.08) 96.56,151.84 95.06,151.84 CPU1.AV32 ; v3(148.12,143.76) 148.1,143.75 DIMM2.149 ; v3(134.27,143.89) 134.2,143.89 133.71,143.4 132.55,143.4 132.2,143.75 DIMM1.149
  L4 w0.216: v4(96.8,152.08) 97.01,151.88 97.04,151.88 97.26,151.88 100.2,148.93 101.06,148.93 107.14,142.85 116.94,142.85 117.15,143.07 117.15,143.72 117.37,143.94 117.94,143.94 118.16,143.72 118.16,143.07 118.37,142.85 118.81,142.85 119.02,143.07 119.02,143.72 119.24,143.94 119.67,143.94 119.89,143.72 119.89,143.07 120.1,142.85 120.53,142.85 120.75,143.07 120.75,143.72 120.97,143.94 121.4,143.94 121.61,143.72 121.61,143.07 121.83,142.85 122.26,142.85 122.48,143.07 122.48,143.72 122.69,143.94 123.12,143.94 123.34,143.72 123.34,143.07 123.56,142.85 123.99,142.85 124.2,143.07 124.2,143.72 124.42,143.94 131.41,143.94 131.97,143.38 138.78,143.38 139.48,144.08 141.94,144.08 142.27,143.75 v3(142.27,143.56)
  BOTTOM w0.102: v3(148.12,143.76) 148.12,143.87 148.01,143.97 147.38,143.97 147.28,143.87 147.28,143.23 147.18,143.12 146.98,143.12 146.88,143.23 146.88,143.87 146.77,143.97 146.57,143.97 146.47,143.87 146.47,143.23 146.37,143.12 146.16,143.12 146.06,143.23 146.06,143.87 145.96,143.97 145.28,143.97 144.69,143.37 142.46,143.37 v3(142.27,143.56) 141.82,144.02 140.14,144.02 140.08,143.96 139.58,143.96 v2(139.36,143.74) 139.05,143.43 136.11,143.43 135.66,143.89 v3(134.27,143.89)
M_DATA_A42: length 82.2
  TOP w0.102: CPU1.BA33 95.9,149.75 96.9,148.75 v4(96.9,148.24)
  TOP w0.165: DIMM2.157 147.73,141.35 148.12,141.73 v3(148.12,141.73) ; DIMM1.157 132.37,141.35 v3(132.75,140.97)
  L4 w0.216: v4(96.9,148.24) 97.48,148.24 98.82,146.9 98.82,146.75 99.98,145.6 100.01,145.6 106.8,138.8 108.38,138.8 108.6,138.59 108.6,138.2 108.82,137.99 109.25,137.99 109.46,138.2 109.46,138.59 109.68,138.8 110.11,138.8 110.33,138.59 110.33,138.2 110.54,137.99 110.98,137.99 111.19,138.2 111.19,138.59 111.41,138.8 111.84,138.8 112.05,138.59 112.05,138.2 112.27,137.99 112.7,137.99 112.92,138.2 112.92,138.59 113.13,138.8 113.57,138.8 113.78,138.59 113.78,138.2 114,137.99 114.43,137.99 114.65,138.2 114.65,138.59 114.86,138.8 115.29,138.8 115.51,138.59 115.51,138.2 115.72,137.99 116.16,137.99 116.37,138.2 116.37,138.59 116.59,138.8 123.6,138.8 123.81,139.02 123.81,139.26 124.03,139.48 124.46,139.48 124.67,139.26 124.67,139.02 124.89,138.8 125.32,138.8 125.54,139.02 125.54,139.26 125.75,139.48 126.19,139.48 126.4,139.26 126.4,139.02 126.62,138.8 127.05,138.8 127.27,139.02 127.27,139.26 127.48,139.48 127.91,139.48 128.13,139.26 128.13,139.02 128.35,138.8 128.78,138.8 128.99,139.02 128.99,139.26 129.21,139.48 129.64,139.48 129.86,139.26 129.86,139.02 130.07,138.8 130.5,138.8 130.72,139.02 130.72,139.26 130.94,139.48 131.37,139.48 131.58,139.26 131.58,139.02 131.8,138.8 138.99,138.8 140.98,140.79 140.98,141.6 v3(140.88,141.71)
  BOTTOM w0.102: v3(148.12,141.73) 148.06,141.73 148.04,141.71 147.25,141.71 147.15,141.81 147.15,141.89 147.05,142 146.85,142 146.74,141.89 146.74,141.81 146.64,141.71 146.44,141.71 146.34,141.81 146.34,141.89 146.24,142 146.03,142 145.93,141.89 145.93,141.81 145.83,141.71 144.69,141.71 144.18,142.22 141.39,142.22 v3(140.88,141.71) 140.78,141.8 v2(139.91,141.8) 133.58,141.8 v3(132.75,140.97)
M_DATA_A43: length 83.2
  TOP w0.165: v3(149.64,141.76) 148.63,140.75 DIMM2.159 ; DIMM1.159 132.28,140.75 132.55,140.48 133.78,140.48 v3(134.27,140.97) ; v4(94.21,150.22) 94.6,150.6 CPU1.AY32
  L4 w0.216: v4(94.21,150.22) 95.02,150.22 96.11,149.13 96.59,149.13 96.98,148.74 97.46,148.74 99.76,146.44 99.86,146.44 107,139.29 112.11,139.29 112.33,139.51 112.33,139.75 112.54,139.97 112.98,139.97 113.19,139.75 113.19,139.51 113.41,139.29 113.84,139.29 114.06,139.51 114.06,139.75 114.27,139.97 114.7,139.97 114.92,139.75 114.92,139.51 115.13,139.29 115.57,139.29 115.78,139.51 115.78,139.75 116,139.97 116.43,139.97 116.65,139.75 116.65,139.51 116.86,139.29 117.29,139.29 117.51,139.51 117.51,139.75 117.73,139.97 118.16,139.97 118.37,139.75 118.37,139.51 118.59,139.29 119.02,139.29 119.24,139.51 119.24,139.75 119.45,139.97 119.88,139.97 120.1,139.75 120.1,139.51 120.32,139.29 120.75,139.29 120.96,139.51 120.96,139.75 121.18,139.97 121.61,139.97 121.83,139.75 121.83,139.51 122.04,139.29 122.48,139.29 122.69,139.51 122.69,139.75 122.91,139.97 138.24,139.97 140.53,142.25 141.42,142.25 141.42,142.25 141.85,142.25 142.34,141.76 v3(142.4,141.76)
  BOTTOM w0.102: v3(149.64,141.76) 149.61,141.76 149.13,141.27 144.59,141.27 144.13,141.73 142.43,141.73 v3(142.4,141.76) 142.37,141.73 142.37,141.7 141.92,141.25 139.51,141.25 139.34,141.43 135.31,141.43 v2(135.07,141.18) 134.86,140.97 v3(134.27,140.97)
M_DATA_A44: length 85.7
  TOP w0.102: CPU1.AU33 96.31,153 96.55,152.76 97.04,152.76 97.52,152.27 97.7,152.27
  TOP w0.165: DIMM1.146 137.06,144.65 v3(136.3,143.89) ; 97.7,152.27 98.59,152.27 98.9,151.96 98.9,151.96 99.6,151.26 v4(99.6,151) 99.6,150.39 v1(99.93,150.06) ; DIMM2.146 153.57,144.65 v3(153.07,144.15)
  L4 w0.216: v3(143.39,144.25) 143.9,144.76 144.4,144.76 144.58,144.95 144.58,145.34 144.38,145.54 143.21,145.54 142.73,145.06 138.38,145.06 138.24,144.92 115.87,144.92 115.65,144.7 115.65,144.16 115.44,143.94 115.01,143.94 114.79,144.16 114.79,144.7 114.57,144.92 114.14,144.92 113.93,144.7 113.93,144.16 113.71,143.94 113.28,143.94 113.06,144.16 113.06,144.7 112.85,144.92 112.41,144.92 112.2,144.7 112.2,144.16 111.98,143.94 111.55,143.94 111.34,144.16 111.34,144.7 111.12,144.92 110.69,144.92 110.47,144.7 110.47,144.16 110.26,143.94 109.82,143.94 109.61,144.16 109.61,144.7 109.39,144.92 108.96,144.92 108.74,144.7 108.74,144.16 108.53,143.94 108.1,143.94 107.88,144.16 107.88,144.7 107.66,144.92 106.46,144.92 101.46,149.91 100.65,149.91 99.6,150.96 v4(99.6,151)
  BOTTOM w0.102: v3(153.07,144.15) 152.51,144.7 148.34,144.7 148.33,144.72 144.86,144.72 144.85,144.7 143.91,144.7 143.45,144.25 v3(143.39,144.25) 143.33,144.25 142.81,144.77 138.39,144.77 138.33,144.71 137.13,144.71 v3(136.3,143.89)
M_DATA_A45: length 84
  TOP w0.102: CPU1.AU31 94.65,153 94.95,152.7 96.3,152.7 96.45,152.55 96.91,152.55 97.44,152.02
  TOP w0.165: v3(98.45,151.75) 97.71,151.75 97.44,152.02 ; DIMM1.148 137.99,144.05 v3(137.83,143.89) ; v3(151.54,144.15) 152.03,143.66 153.27,143.66 153.66,144.05 DIMM2.148
  L4 w0.216: v3(144.91,144.25) 144.99,144.17 147.26,144.17 147.48,143.95 147.48,142.99 147.26,142.77 144.14,142.77 142.34,144.57 138.58,144.57 138.45,144.43 117.05,144.43 115.96,143.34 107.34,143.34 101.26,149.42 100.45,149.42 99.25,150.62 98.96,150.62 98.46,151.13 98.46,151.74 v3(98.45,151.75)
  BOTTOM w0.102: v3(151.54,144.15) 151.47,144.22 148.29,144.22 148.17,144.34 145.02,144.34 144.92,144.25 v3(144.91,144.25) 144.42,143.75 142.92,143.75 142.27,144.39 138.54,144.39 138.48,144.34 138.27,144.34 v3(137.83,143.89)
  BOTTOM w0.165: v3(98.45,151.75) 97.4,152.81 v2(97.01,152.81)
M_DATA_A46: length 84.7
  TOP w0.102: 97.34,149.2 97.03,149.2 96.52,149.71 96.52,150.07 96.12,150.47 96.06,150.47 95.63,150.9 94.8,150.9 CPU1.AW31
  TOP w0.165: DIMM1.158 137.91,141.05 v3(137.83,140.97) ; DIMM2.158 153.15,141.05 v3(153.07,140.97) ; v1(100.2,146.38) 100.15,146.38 100.05,146.27 98.62,146.27 98.36,146.54 v4(98.36,146.71) 98.61,146.71 98.71,146.81 98.71,147.83 97.34,149.2
  L4 w0.216: v3(144.71,140.77) 144.64,140.77 144.15,141.26 142.97,141.26 142.72,141.01 141.9,141.01 139.2,138.31 122.83,138.31 122.61,138.1 122.61,137.71 122.39,137.5 121.96,137.5 121.75,137.71 121.75,138.1 121.53,138.31 121.1,138.31 120.88,138.1 120.88,137.71 120.67,137.5 120.24,137.5 120.02,137.71 120.02,138.1 119.8,138.31 119.37,138.31 119.16,138.1 119.16,137.71 118.94,137.5 118.51,137.5 118.29,137.71 118.29,138.1 118.08,138.31 117.65,138.31 117.43,138.1 117.43,137.71 117.21,137.5 107.42,137.5 99.8,145.11 99.77,145.11 98.36,146.52 v4(98.36,146.71)
  BOTTOM w0.102: v3(137.83,140.97) 138.39,140.97 138.48,140.87 142.07,140.87 142.4,141.2 142.86,141.2 143.01,141.36 143.98,141.36 144.13,141.2 144.56,140.77 v3(144.71,140.77) 149.32,140.77 149.98,141.43 152.61,141.43 v3(153.07,140.97)
M_DATA_A47: length 84.9
  TOP w0.102: CPU1.AY33 95.83,150.27 96.03,150.27 96.31,149.98 96.31,149.63 97.34,148.6 v4(97.34,147.73)
  TOP w0.165: v3(151.54,140.97) 152.06,140.45 DIMM2.160 ; v3(136.3,140.97) 136.82,140.45 DIMM1.160
  L4 w0.216: v3(143.18,140.74) 142.93,140.49 142.14,140.49 139.47,137.82 132.8,137.82 131.99,137.01 131.34,137.01 131.12,137.22 131.12,137.61 130.9,137.82 130.47,137.82 130.26,137.61 130.26,137.22 130.04,137.01 129.61,137.01 129.39,137.22 129.39,137.61 129.18,137.82 128.75,137.82 128.53,137.61 128.53,137.22 128.31,137.01 127.88,137.01 127.67,137.22 127.67,137.61 127.45,137.82 127.02,137.82 126.8,137.61 126.8,137.22 126.59,137.01 126.15,137.01 125.94,137.22 125.94,137.61 125.72,137.82 125.29,137.82 125.07,137.61 125.07,137.22 124.86,137.01 107.21,137.01 99.49,144.73 99.49,144.88 97.41,146.95 97.41,147.65 v4(97.34,147.73)
  BOTTOM w0.102: v3(151.54,140.97) 150.28,140.97 v2(149.76,140.45) 149.6,140.29 145.84,140.29 145.82,140.27 143.66,140.27 v3(143.18,140.74) 143.07,140.74 142.82,140.5 136.21,140.5 136,140.28 135.85,140.28 135.64,140.49 135.64,140.87 135.75,140.97 v3(136.3,140.97)
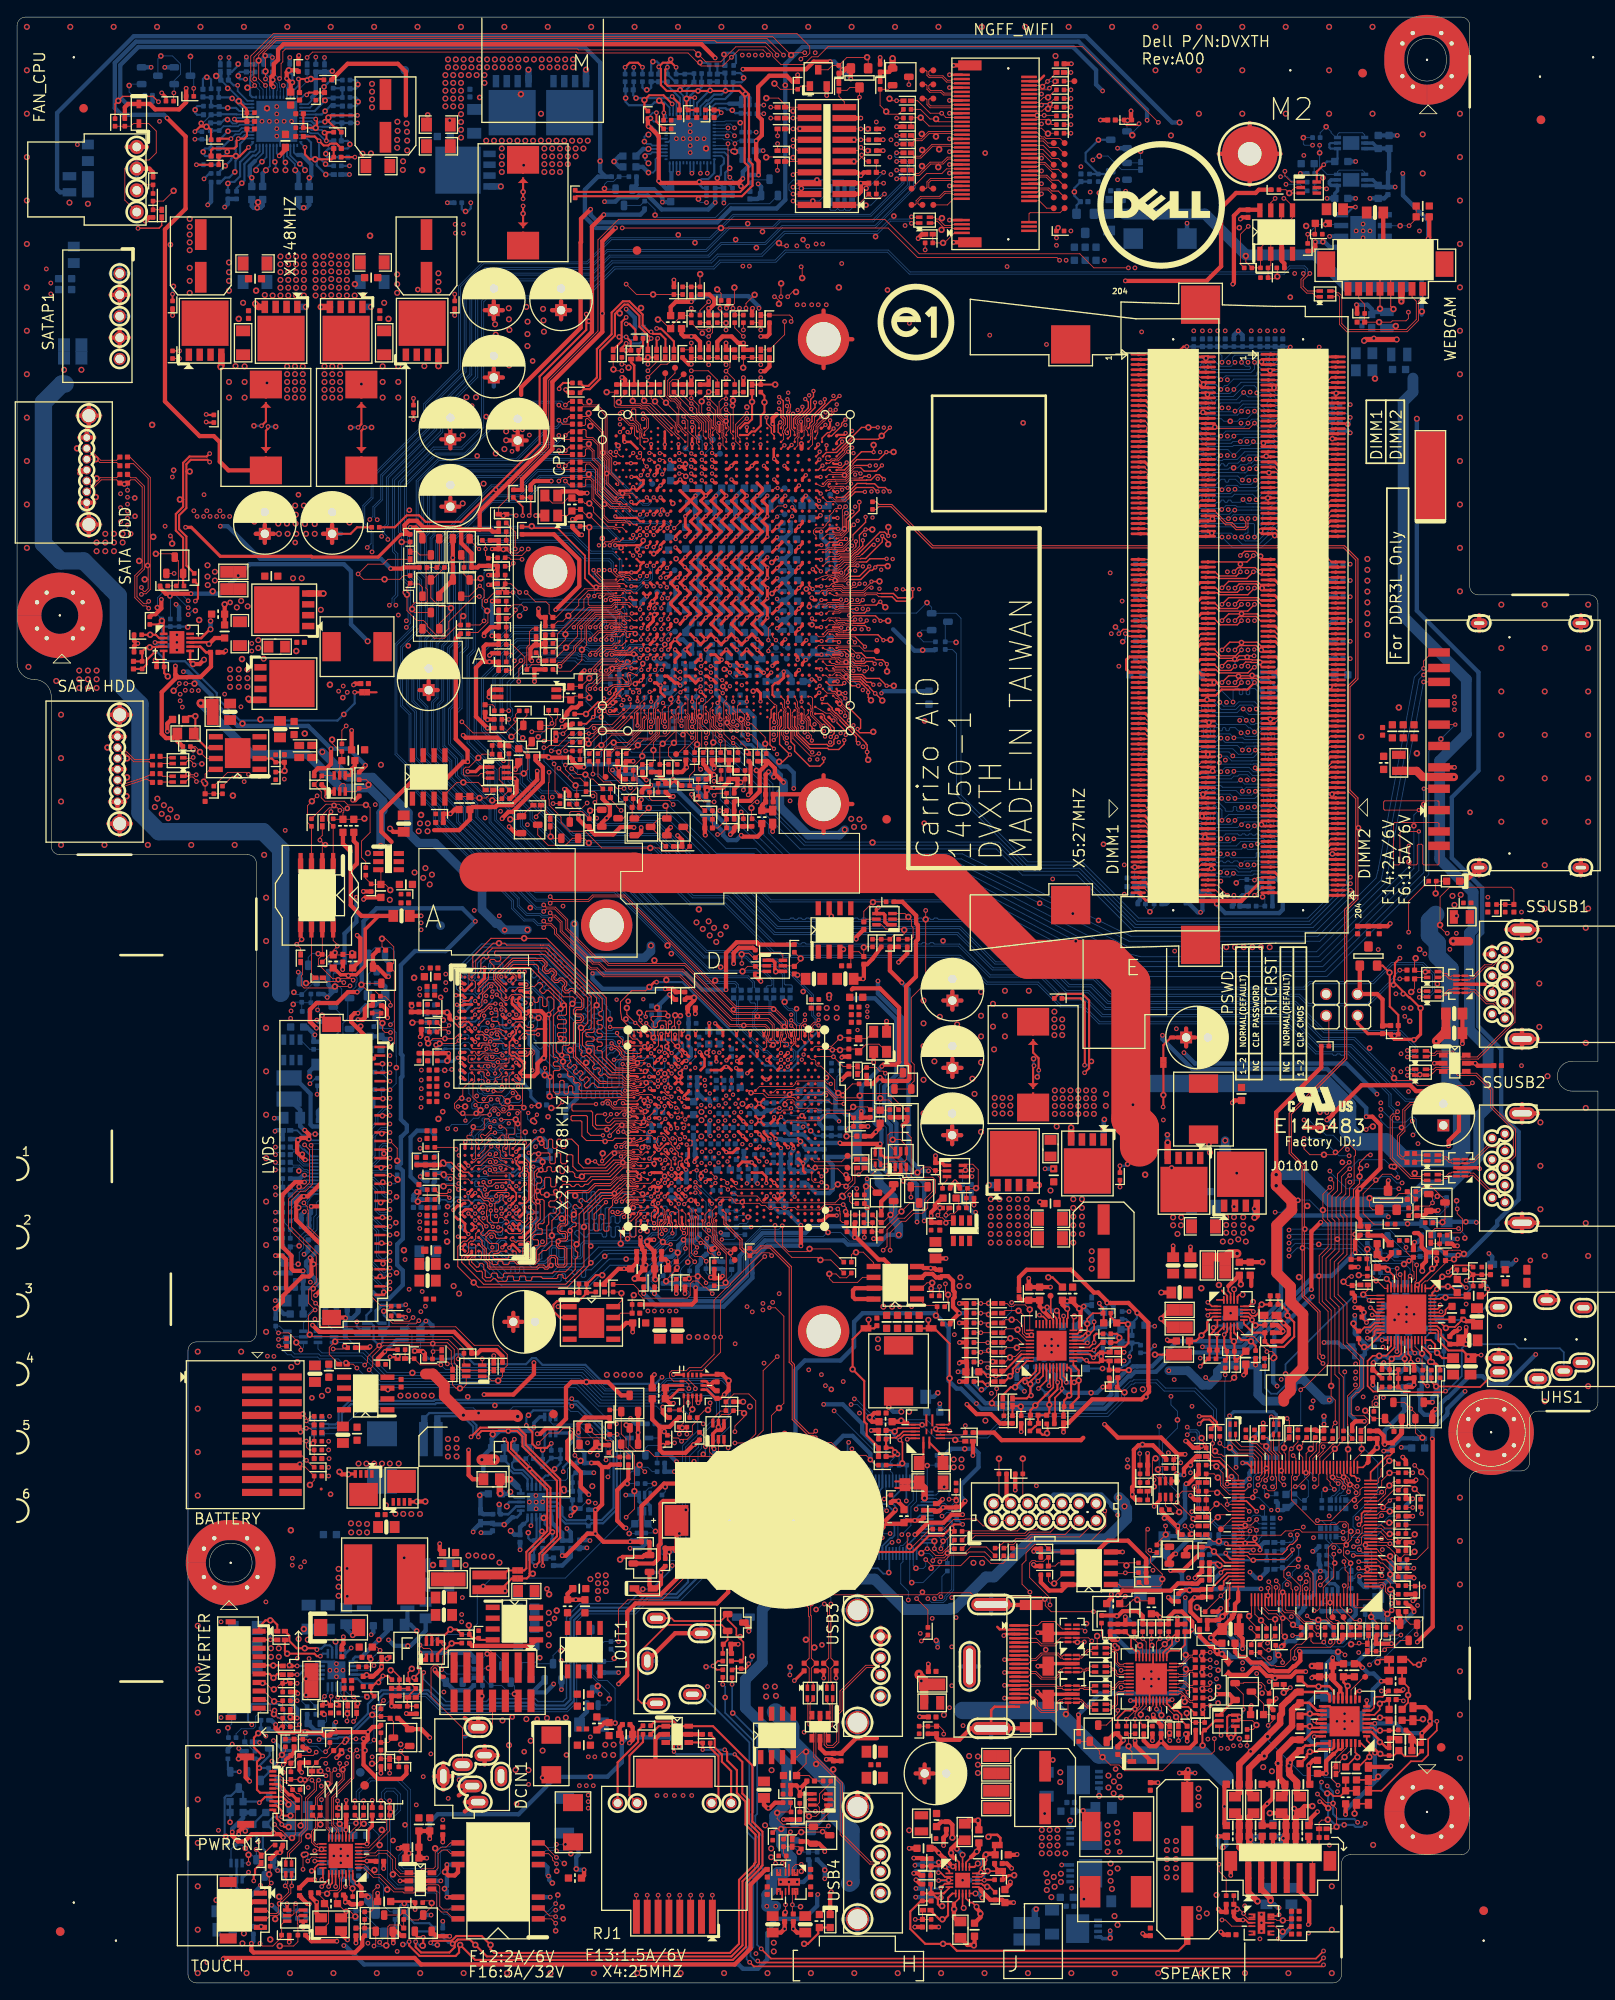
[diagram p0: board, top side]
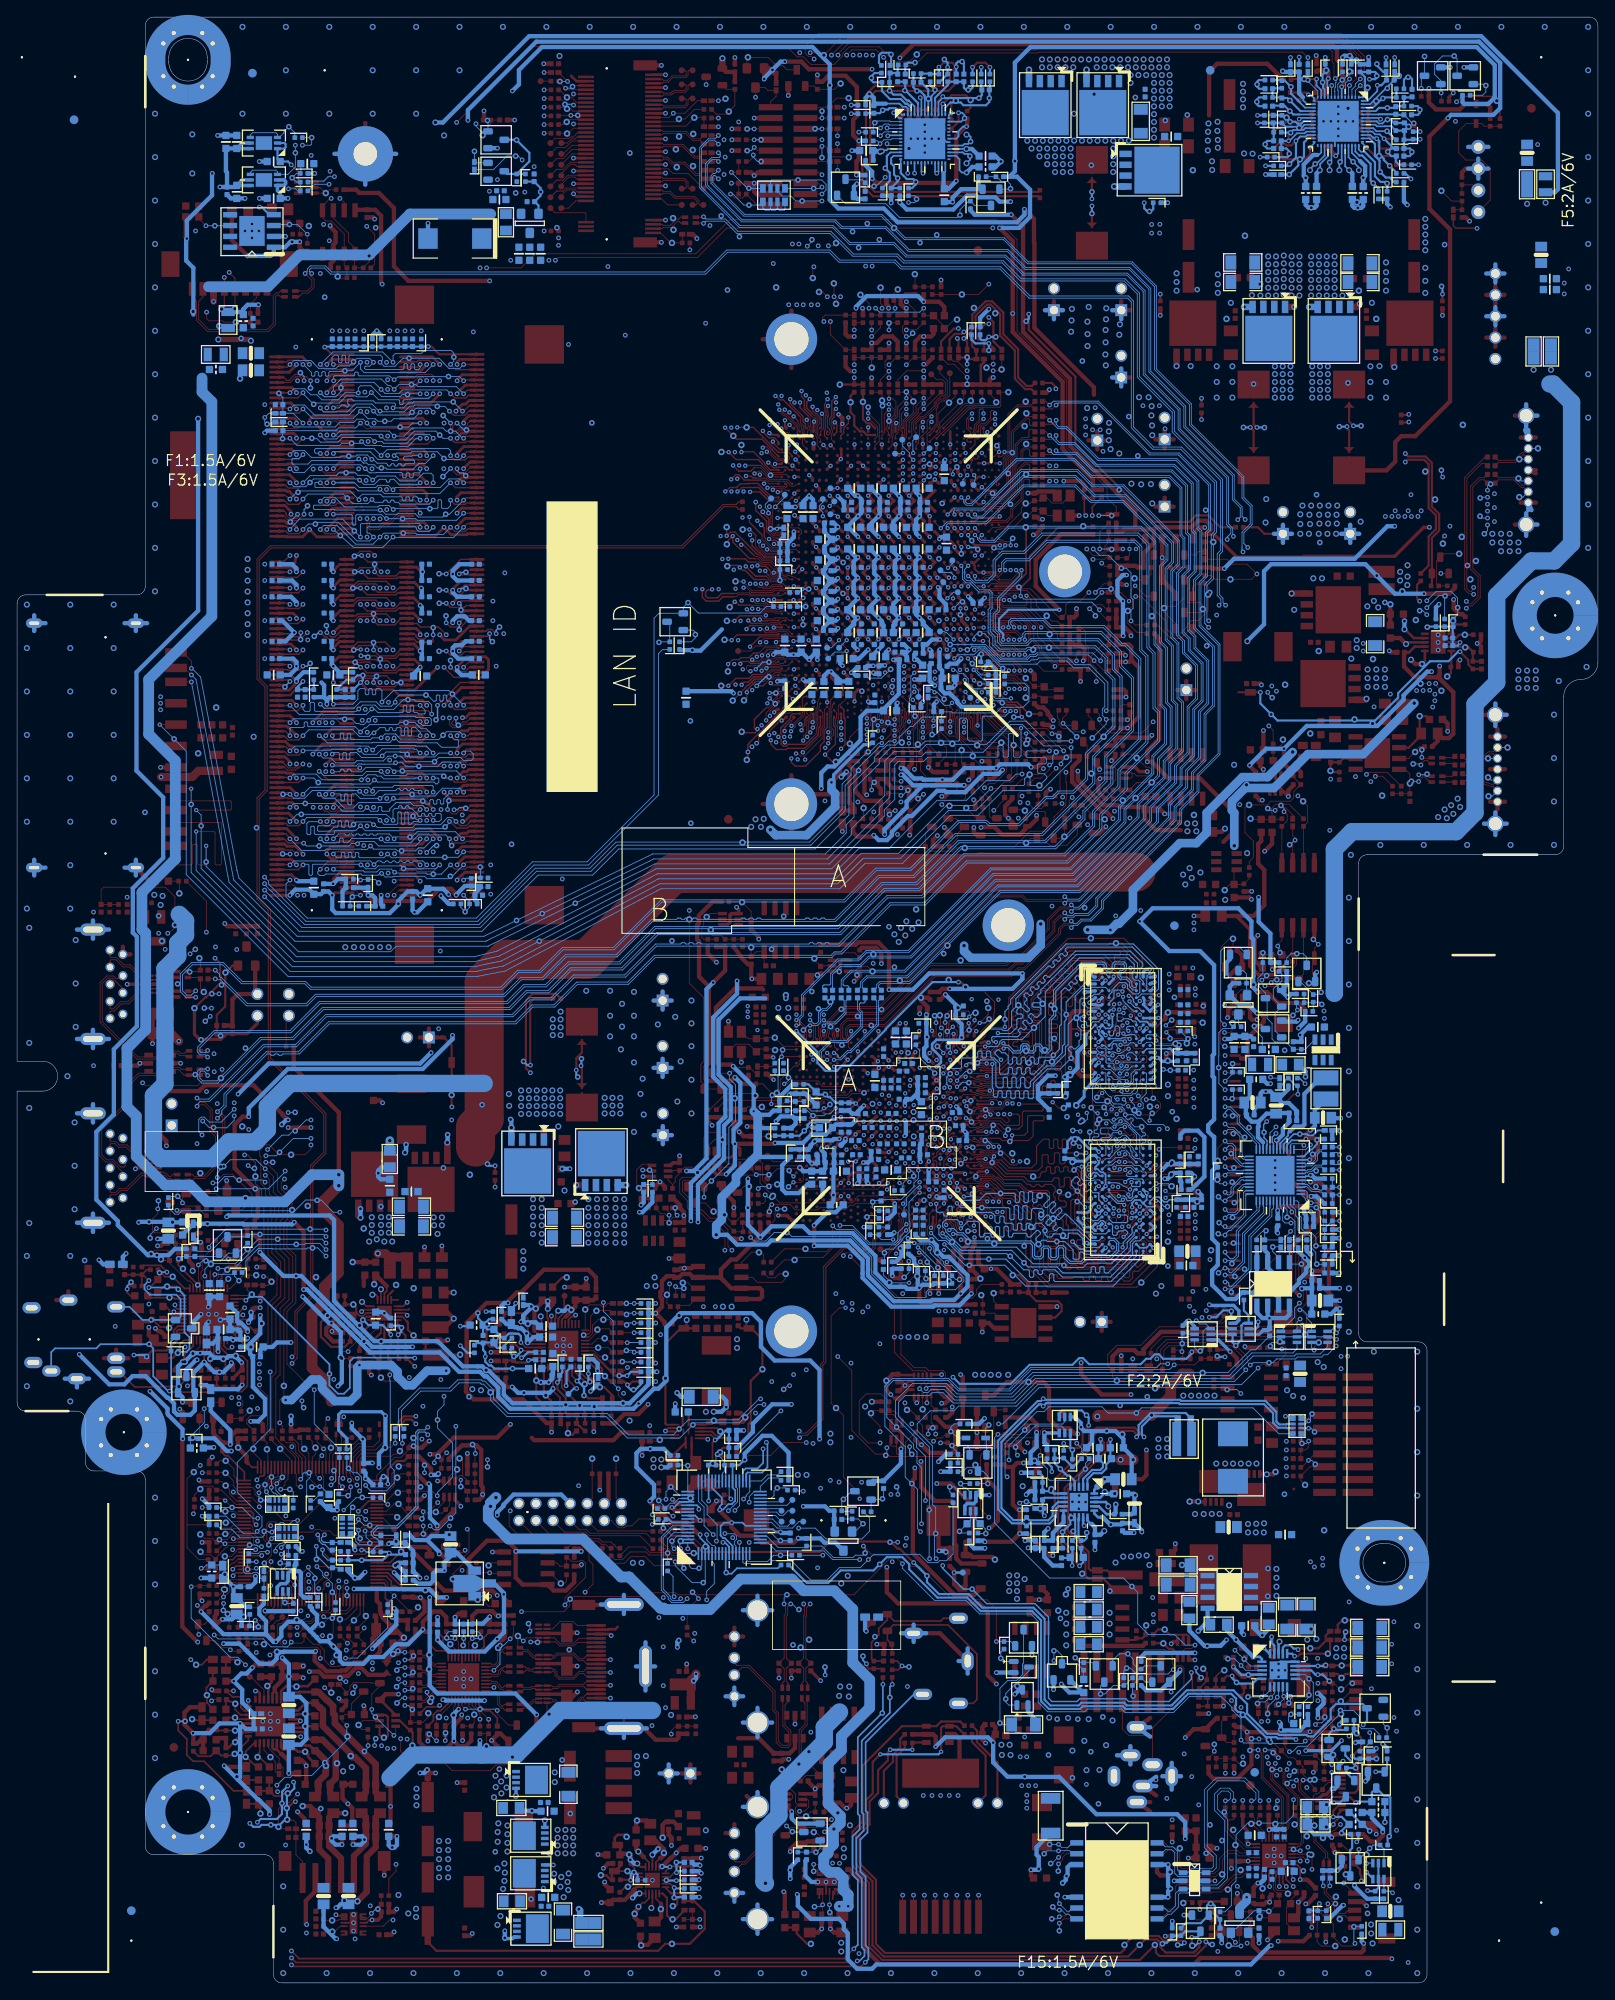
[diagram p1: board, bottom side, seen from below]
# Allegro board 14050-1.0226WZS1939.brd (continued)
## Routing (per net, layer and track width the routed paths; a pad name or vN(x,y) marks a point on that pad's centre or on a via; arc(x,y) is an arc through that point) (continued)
M_DATA_A48: length 92.2
  TOP w0.165: v4(95.19,146.47) 95.19,146.88 94.1,147.97 CPU1.BC31 ; DIMM1.163 132.52,139.55 v3(132.75,139.32) ; v3(148.12,139.06) 147.63,139.55 DIMM2.163
  L3 w0.216: v3(142.53,138.59) 142.52,138.59 141.89,139.22 139.7,139.22 138.96,139.97 132.07,139.97 129.36,142.67 124.03,142.67 123.82,142.46 123.82,141.55 123.6,141.33 123.17,141.33 122.95,141.55 122.95,142.46 122.74,142.67 122.31,142.67 122.09,142.46 122.09,141.55 121.87,141.33 121.44,141.33 121.23,141.55 121.23,142.46 121.01,142.67 120.58,142.67 120.36,142.46 120.36,141.55 120.15,141.33 119.71,141.33 119.5,141.55 119.5,142.46 119.28,142.67 118.85,142.67 118.64,142.46 118.64,141.55 118.42,141.33 117.99,141.33 117.77,141.55 117.77,142.46 117.56,142.67 117.12,142.67 116.91,142.46 116.91,141.55 116.69,141.33 116.26,141.33 116.04,141.55 116.04,142.46 115.83,142.67 115.4,142.67 115.18,142.46 115.18,141.55 114.96,141.33 114.53,141.33 114.32,141.55 114.32,142.46 114.1,142.67 113.56,142.67 113.34,142.46 113.34,141.55 113.13,141.33 100.74,141.33 97.84,144.23 97.84,145.8 96.96,146.69 95.41,146.69 95.2,146.47 v4(95.19,146.47)
  BOTTOM w0.102: v3(148.12,139.06) 148.06,139.12 147.2,139.12 147.1,139.01 147.1,138.4 147,138.3 146.8,138.3 146.69,138.4 146.69,139.01 146.59,139.12 146.39,139.12 146.29,139.01 146.29,137.95 146.19,137.85 145.98,137.85 145.88,137.95 145.88,139.01 145.78,139.12 145.37,139.12 144.84,138.59 v3(142.53,138.59) 142.45,138.59 141.95,139.09 138.82,139.09 v2(138.78,139.04) 138.59,138.86 136.11,138.86 135.85,139.13 135.85,139.15 135.22,139.78 133.21,139.78 v3(132.75,139.32)
M_DATA_A49: length 95.3
  TOP w0.102: CPU1.BB30 94.02,148.94 94.67,148.55 95.14,148.55 95.59,148.11 95.7,148.11 95.94,147.87 95.94,147.45
  TOP w0.165: DIMM2.165 147.47,138.95 147.84,138.58 149.15,138.58 v3(149.64,139.06) ; v3(134.27,139.32) 133.95,138.83 132.29,138.83 132.17,138.95 DIMM1.165 ; v4(96.98,146.01) 96.93,146.05 96.93,146.45 95.94,147.45
  L3 w0.216: v4(96.98,146.01) 97.35,145.64 97.35,144.03 100.53,140.84 102.38,140.84 102.6,140.63 102.6,139.2 102.81,138.99 103.25,138.99 103.46,139.2 103.46,140.63 103.68,140.84 104.11,140.84 104.33,140.63 104.33,139.2 104.54,138.99 104.97,138.99 105.19,139.2 105.19,140.63 105.41,140.84 105.84,140.84 106.05,140.63 106.05,139.2 106.27,138.99 106.7,138.99 106.92,139.2 106.92,140.63 107.13,140.84 124.48,140.84 124.69,141.06 124.69,141.9 124.91,142.11 125.34,142.11 125.56,141.9 125.56,141.06 125.77,140.84 126.2,140.84 126.42,141.06 126.42,141.9 126.64,142.11 127.07,142.11 127.28,141.9 127.28,141.06 127.5,140.84 127.93,140.84 128.15,141.06 128.15,141.9 128.36,142.11 128.79,142.11 129.01,141.9 129.01,141.06 129.23,140.84 130.5,140.84 132.53,138.8 138.69,138.8 138.91,138.59 v3(140.96,138.59)
  BOTTOM w0.102: v3(149.64,139.06) 149.52,139.06 149.07,138.61 147.84,138.61 147.34,138.11 147.34,138.08 146.71,137.46 145.67,137.46 145.02,138.11 141.45,138.11 v3(140.96,138.59) 140.86,138.49 137.73,138.49 v2(137.52,138.28) 137.17,137.92 136.79,137.92 136.69,138.02 136.69,138.35 136.59,138.46 136.39,138.46 136.28,138.35 136.28,138.02 136.18,137.92 135.98,137.92 135.88,138.02 135.88,138.35 135.78,138.46 135.57,138.46 135.47,138.35 135.47,138.02 135.37,137.92 135.17,137.92 135.06,138.02 135.06,138.53 v3(134.27,139.32)
M_DATA_A50: length 95
  TOP w0.102: CPU1.BB28 92.1,149 92.1,148.36 92.09,148.35 92.09,147.88 92.36,147.62 92.36,146.49 v4(92.17,146.3)
  TOP w0.165: v3(147.99,135.89) 147.93,135.95 DIMM2.175 ; v3(133.64,135.89) 133.15,135.4 132.44,135.4 131.89,135.95 DIMM1.175
  L3 w0.216: v4(92.17,146.3) 91.79,145.92 91.79,142.73 92.39,142.13 94.99,142.13 101.42,135.71 123.15,135.71 123.37,135.49 123.37,134.61 123.58,134.4 124.01,134.4 124.23,134.61 124.23,135.49 124.44,135.71 124.88,135.71 125.09,135.49 125.09,134.61 125.31,134.4 125.74,134.4 125.96,134.61 125.96,135.49 126.17,135.71 126.66,135.71 126.88,135.49 126.88,135.09 127.09,134.87 127.53,134.87 127.74,135.09 127.74,135.49 127.96,135.71 130.88,135.71 132.19,134.4 139.84,134.4 140.31,134.86 142.64,134.86 v3(143.29,135.51)
  BOTTOM w0.102: v3(133.64,135.89) 134.09,136.35 134.63,136.35 134.99,135.99 134.99,135.96 135.44,135.51 138.41,135.51 138.74,135.18 142.84,135.18 143.09,135.43 143.15,135.5 v3(143.29,135.51) 143.62,135.84 145.32,135.84 v2(145.62,135.53) 145.93,135.22 146.11,135.22 146.21,135.33 146.21,135.85 146.31,135.96 146.51,135.96 146.62,135.85 146.62,135.33 146.72,135.22 146.92,135.22 147.02,135.33 147.02,135.85 147.12,135.96 147.33,135.96 147.43,135.85 147.43,135.33 147.53,135.22 147.93,135.22 148.41,134.75 149.74,134.75 149.84,134.85 149.84,135.28 149.74,135.38 148.5,135.38 v3(147.99,135.89)
M_DATA_A51: length 96.3
  TOP w0.102: v4(91.88,146.87) 91.5,147.25 91.5,147.88 91.51,147.89 91.51,148.31 91.5,148.32 91.5,148.64 91.51,148.65 91.51,149.14 91.33,149.33 91.33,149.87 CPU1.AY27
  TOP w0.165: DIMM2.177 148.97,135.35 v3(149.51,135.89) ; DIMM1.177 132.07,135.35 132.31,135.11 133.55,135.11 134.33,135.89 v3(134.4,135.89)
  L3 w0.216: v4(91.88,146.87) 91.3,146.29 91.3,142.52 92.18,141.64 94.79,141.64 101.21,135.22 121.54,135.22 122.85,133.9 131.93,133.9 132.49,133.34 139.63,133.34 140.66,134.37 143.8,134.37 v3(144.81,135.38)
  BOTTOM w0.102: v3(149.51,135.89) 149.54,135.86 150.88,135.86 151.09,135.66 151.09,134.47 150.99,134.37 150.73,134.37 150.63,134.47 150.63,135.23 150.53,135.33 150.3,135.33 150.22,135.25 150.22,134.49 150.1,134.37 147.98,134.37 147.87,134.47 147.87,134.75 147.77,134.85 145.35,134.85 v3(144.81,135.38) 144.24,134.81 138.59,134.81 138.33,135.07 135.09,135.07 v2(134.91,135.25) 134.89,135.25 134.4,135.75 v3(134.4,135.89)
M_DATA_A52: length 92.9
  TOP w0.102: 96.3,147.7 96.3,147.8 95.79,148.31 95.69,148.31 CPU1.BB32
  TOP w0.165: 96.3,147.7 98.2,145.8 98.2,145.29 98.45,145.04 v3(98.45,145.04) ; DIMM2.164 153.25,139.25 v3(153.07,139.06) ; v3(137.83,139.32) 137.9,139.25 DIMM1.164
  L3 w0.216: v3(144.91,139.42) 144.4,138.91 143.18,138.91 142.37,139.71 139.91,139.71 139.16,140.46 132.53,140.46 129.51,143.48 112.09,143.48 111.88,143.26 111.88,142.04 111.66,141.82 111.23,141.82 111.01,142.04 111.01,143.26 110.8,143.48 110.37,143.48 110.15,143.26 110.15,142.04 109.94,141.82 109.5,141.82 109.29,142.04 109.29,143.26 109.07,143.48 108.64,143.48 108.42,143.26 108.42,142.04 108.21,141.82 107.78,141.82 107.56,142.04 107.56,143.26 107.34,143.48 106.91,143.48 106.7,143.26 106.7,142.04 106.48,141.82 106.05,141.82 105.83,142.04 105.83,143.26 105.62,143.48 105.19,143.48 104.97,143.26 104.97,142.04 104.75,141.82 104.32,141.82 104.11,142.04 104.11,143.26 103.89,143.48 103.46,143.48 103.24,143.26 103.24,142.04 103.03,141.82 102.59,141.82 102.38,142.04 102.38,143.26 102.16,143.48 99.29,143.48 98.45,144.31 v3(98.45,145.04)
  BOTTOM w0.102: v2(153.88,139.06) v3(153.07,139.06) 152.61,138.61 151.35,138.61 150.45,139.52 149.83,139.52 149.83,139.52 149.45,139.52 149.44,139.52 149.07,139.52 149.07,139.52 148.69,139.52 148.68,139.52 148.31,139.52 148.3,139.52 147.93,139.52 147.92,139.52 145.01,139.52 v3(144.91,139.42) 144.46,138.96 143.2,138.96 142.65,139.52 140.69,139.52 140.59,139.62 140.59,139.63 140.49,139.73 140.29,139.73 140.19,139.63 140.19,139.62 140.09,139.52 139.88,139.52 139.78,139.62 139.78,139.63 139.68,139.73 139.48,139.73 139.37,139.63 139.37,139.62 139.27,139.52 139.07,139.52 138.97,139.62 138.97,139.63 138.87,139.73 138.66,139.73 138.56,139.63 138.56,139.62 138.46,139.52 138.03,139.52 v3(137.83,139.32)
M_DATA_A53: length 93.8
  TOP w0.165: v3(151.54,139.06) 152.03,138.58 153.27,138.58 153.34,138.65 DIMM2.166 ; v1(99.6,143.1) 99.47,143.23 v3(99.47,144.02) 99.47,144.41 99.49,144.43 99.49,144.83 99.35,144.97 99.35,145.05 96.99,147.41 96.99,147.44 95.88,148.55 95.81,148.55 95.38,148.97 95.38,149.16 94.84,149.7 CPU1.BA31 ; DIMM1.166 136.97,138.65 v3(136.3,139.32)
  L3 w0.216: v3(143.39,139.42) 143.39,139.6 142.79,140.2 140.11,140.2 138.68,141.63 136,141.63 135.65,141.28 134.69,141.28 134.34,141.63 132.6,141.63 130.21,144.02 129.72,144.02 129.5,144.23 129.5,145.28 129.29,145.49 128.85,145.49 128.64,145.28 128.64,144.23 128.42,144.02 127.99,144.02 127.77,144.23 127.77,145.28 127.56,145.49 127.13,145.49 126.91,145.28 126.91,144.23 126.7,144.02 126.26,144.02 126.05,144.23 126.05,145.28 125.83,145.49 125.4,145.49 125.18,145.28 125.18,144.23 124.97,144.02 124.54,144.02 124.32,144.23 124.32,145.28 124.1,145.49 123.67,145.49 123.46,145.28 123.46,144.23 123.24,144.02 122.81,144.02 122.59,144.23 122.59,145.28 122.38,145.49 121.95,145.49 121.73,145.28 121.73,144.23 121.51,144.02 121.08,144.02 120.87,144.23 120.87,145.28 120.65,145.49 120.22,145.49 120,145.28 120,144.23 119.79,144.02 v3(99.47,144.02)
  BOTTOM w0.102: v3(136.3,139.32) 136.3,140 136.41,140.11 140.85,140.11 141.06,139.89 143.29,139.89 143.39,139.79 v3(143.39,139.42) 143.86,139.89 147.76,139.89 147.77,139.9 149.98,139.9 149.99,139.89 150.72,139.89 v3(151.54,139.06)
M_DATA_A54: length 95.6
  TOP w0.165: v4(93.2,146.56) 93.05,146.71 93.05,146.92 92.81,147.15 92.81,147.79 92.81,147.79 92.81,147.81 92.62,148.01 92.62,148.08 CPU1.BC29 ; v3(136.3,136.02) 136.79,136.51 138.03,136.51 138.29,136.25 DIMM1.174 ; DIMM2.174 153.43,136.25 v3(153.07,135.89)
  L3 w0.216: v3(141,136.02) 140.07,136.02 139.43,135.38 132.59,135.38 129.49,138.48 123.69,138.48 123.48,138.26 123.48,136.9 123.26,136.69 122.83,136.69 122.61,136.9 122.61,138.26 122.4,138.48 121.97,138.48 121.75,138.26 121.75,136.9 121.53,136.69 121.1,136.69 120.89,136.9 120.89,138.26 120.67,138.48 120.24,138.48 120.02,138.26 120.02,136.9 119.81,136.69 119.37,136.69 119.16,136.9 119.16,138.26 118.94,138.48 118.51,138.48 118.3,138.26 118.3,136.9 118.08,136.69 101.82,136.69 93.53,144.98 93.53,145.49 93.2,145.82 v4(93.2,146.56)
  BOTTOM w0.102: v3(153.07,135.89) 152.23,136.72 v2(151.75,136.72) 147.06,136.72 147.04,136.71 141.82,136.71 v3(141,136.02) 141,137.21 140.83,137.39 140.45,137.39 140.35,137.49 140.35,137.62 140.25,137.72 140.04,137.72 139.94,137.62 139.94,137.49 139.84,137.39 139.64,137.39 139.53,137.49 139.53,137.62 139.43,137.72 139.23,137.72 139.13,137.62 139.13,137.49 139.03,137.39 138.79,137.39 138.09,136.68 138.09,136.58 137.99,136.47 137.78,136.47 137.68,136.58 137.68,136.73 137.58,136.83 137.38,136.83 137.27,136.73 137.27,136.58 137.17,136.47 136.97,136.47 136.87,136.58 136.87,136.73 136.77,136.83 136.56,136.83 136.46,136.73 136.46,136.58 136.36,136.47 136.16,136.47 136.06,136.58 136.06,136.73 135.95,136.83 135.49,136.83 135.36,136.7 135.36,136.12 135.59,135.89 136.18,135.89 v3(136.3,136.02)
M_DATA_A55: length 95.6
  TOP w0.102: CPU1.BB29 92.6,148.55 92.3,148.25 92.3,147.97 92.58,147.69 92.58,146.32 92.95,145.95 92.95,145.42 v4(93.01,145.36)
  TOP w0.165: DIMM1.176 138.2,135.65 v3(137.83,136.02) ; DIMM2.176 153.52,135.65 153.27,135.4 152.03,135.4 v3(151.54,135.89)
  L3 w0.216: v3(142.53,136.02) 141.86,135.35 140.1,135.35 139.64,134.89 132.39,134.89 131.08,136.2 129.31,136.2 129.09,136.41 129.09,137.75 128.88,137.96 128.45,137.96 128.23,137.75 128.23,136.41 128.02,136.2 127.58,136.2 127.37,136.41 127.37,137.75 127.15,137.96 126.72,137.96 126.5,137.75 126.5,136.41 126.29,136.2 125.86,136.2 125.64,136.41 125.64,137.75 125.42,137.96 124.99,137.96 124.78,137.75 124.78,136.41 124.56,136.2 121.94,136.2 101.62,136.2 95.19,142.62 92.59,142.62 92.28,142.93 92.28,144.63 v4(93.01,145.36)
  BOTTOM w0.102: v2(138.67,136.51) 138.26,136.1 137.91,136.1 v3(137.83,136.02) 137.96,135.89 138.59,135.89 138.92,135.56 139.12,135.56 139.23,135.66 139.23,136.88 139.33,136.98 139.53,136.98 139.63,136.88 139.63,135.66 139.73,135.56 139.94,135.56 140.04,135.66 140.04,136.91 140.14,137.01 140.34,137.01 140.44,136.91 140.44,135.66 140.55,135.56 142.07,135.56 v3(142.53,136.02) 142.84,136.33 147.2,136.33 147.21,136.35 151.09,136.35 v3(151.54,135.89)
M_DATA_A56: length 91.3
  TOP w0.102: CPU1.BB27 90.71,148.61 90.71,148.26 90.7,148.25 90.7,146.99 91,146.69 91,145.94 92.94,143.99 93.04,143.99 v4(93.05,143.98)
  TOP w0.165: DIMM1.181 132.58,134.15 v3(132.88,133.86) ; DIMM2.181 147.7,134.15 v3(147.99,133.86)
  L4 w0.216: v4(93.05,143.98) 93.39,144.32 96.83,144.32 106.06,135.09 107.81,135.09 108.02,134.88 108.02,133.57 108.24,133.35 108.67,133.35 108.89,133.57 108.89,134.88 109.1,135.09 109.53,135.09 109.75,134.88 109.75,133.57 109.97,133.35 110.4,133.35 110.61,133.57 110.61,134.88 110.83,135.09 111.26,135.09 111.48,134.88 111.48,133.57 111.69,133.35 112.12,133.35 112.34,133.57 112.34,134.88 112.56,135.09 112.99,135.09 113.2,134.88 113.2,133.57 113.42,133.35 113.85,133.35 114.07,133.57 114.07,134.88 114.28,135.09 115.23,135.09 115.93,134.4 138.55,134.4 138.77,134.18 138.77,134.05 138.98,133.83 139.42,133.83 139.63,134.05 139.63,134.18 139.85,134.4 140.34,134.4 v3(140.88,133.86)
  BOTTOM w0.102: v3(132.88,133.86) 133.71,134.69 138.17,134.69 138.78,134.08 139.01,134.08 v2(139.01,134.08) 139.02,134.08 140.65,134.08 v3(140.88,133.86) 141.45,134.43 142.85,134.43 142.99,134.29 143.25,134.29 143.4,134.43 143.66,134.43 143.8,134.29 144.06,134.29 144.21,134.43 144.47,134.43 144.62,134.29 144.88,134.29 145.02,134.43 145.28,134.43 145.43,134.29 145.69,134.29 145.84,134.43 146.1,134.43 146.24,134.29 146.5,134.29 146.65,134.43 147.38,134.43 147.82,133.99 147.86,133.99 v3(147.99,133.86)
M_DATA_A57: length 93.8
  TOP w0.102: CPU1.BB26 90.5,149 90.5,148.36 90.49,148.35 90.49,146.9 90.79,146.6 90.79,145.61 92.84,143.56 92.86,143.56 92.87,143.55 93.33,143.55 93.55,143.76 93.77,143.76 v4(93.84,143.83)
  TOP w0.165: DIMM1.183 132.49,133.55 132.67,133.37 133.91,133.37 v3(134.4,133.86) ; v3(149.51,133.86) 149.02,133.37 147.79,133.37 147.6,133.55 DIMM2.183
  L4 w0.216: v4(93.84,143.83) 96.63,143.83 107.62,132.84 115.25,132.84 115.47,133.06 115.47,133.72 115.65,133.9 116.14,133.9 116.33,133.72 116.33,133.06 116.54,132.84 116.98,132.84 117.19,133.06 117.19,133.72 117.38,133.9 117.87,133.9 118.06,133.72 118.06,133.06 118.27,132.84 118.7,132.84 118.92,133.06 118.92,133.72 119.11,133.9 119.6,133.9 119.78,133.72 119.78,133.06 120,132.84 120.43,132.84 120.65,133.06 120.65,133.72 120.83,133.9 121.32,133.9 121.51,133.72 121.51,133.06 121.73,132.84 122.16,132.84 122.37,133.06 122.37,133.72 122.56,133.9 131.48,133.9 132.04,133.34 141.89,133.34 v3(142.4,133.86)
  BOTTOM w0.102: v3(149.51,133.86) 149.05,133.4 147.34,133.4 147.24,133.5 147.24,133.83 147.14,133.93 146.94,133.93 146.84,133.83 146.84,133.5 146.73,133.4 146.32,133.4 145.81,133.91 144.77,133.91 144.77,133.91 144.08,133.91 144.08,133.91 142.45,133.91 v3(142.4,133.86) 141.94,133.4 138.93,133.4 138.02,134.32 134.86,134.32 v3(134.4,133.86) 134.4,133.32 v2(134.15,133.07)
M_DATA_A58: length 93.4
  TOP w0.165: v3(149.51,130.3) 148.68,131.13 147.6,131.13 147.58,131.15 DIMM2.191 ; v3(132.75,130.81) 132.41,131.15 DIMM1.191 ; CPU1.BB24 88.24,148.94 88.24,148.03 88.11,147.9 88.11,144.85 v4(88.57,144.4)
  L4 w0.216: v4(88.57,144.4) 88.44,144.27 88.44,143.55 91.54,140.46 91.71,140.37 94.02,140.37 94.02,140.37 95.39,140.37 107.87,127.9 142.56,127.9 143.09,128.42 143.09,129.07 v3(142.34,129.81)
  BOTTOM w0.102: v3(149.51,130.3) 149.82,130 149.82,129.79 149.59,129.57 149.08,129.57 148.91,129.74 144.75,129.74 144.62,129.6 142.77,129.6 142.56,129.81 v3(142.34,129.81) 141.93,129.4 141.03,129.4 140.96,129.47 137.3,129.47 137.02,129.19 134.58,129.19 v2(134.3,129.47) 134.08,129.47 133.71,129.84 133.71,129.85 v3(132.75,130.81)
M_DATA_A59: length 90.9
  TOP w0.102: CPU1.AY23 87.8,150.43 88.63,149.6 88.73,149.6 88.9,149.43 88.9,148.37 88.89,148.37 88.89,147.78 89.01,147.67 89.01,147.27 v4(88.55,146.81)
  TOP w0.165: DIMM1.193 132.32,130.55 132.55,130.32 133.78,130.32 v3(134.27,130.81) ; v3(147.99,130.3) 147.74,130.55 DIMM2.193
  L4 w0.216: v4(88.55,146.81) 88.09,146.35 88.09,145.22 88.36,144.95 88.67,144.95 89.46,144.17 89.46,143.23 91.83,140.86 93.81,140.86 93.82,140.86 95.6,140.86 108.07,128.39 127.09,128.39 127.3,128.61 127.3,129.1 127.52,129.32 127.95,129.32 128.17,129.1 128.17,128.61 128.38,128.39 128.81,128.39 129.03,128.61 129.03,129.1 129.25,129.32 129.68,129.32 129.89,129.1 129.89,128.61 130.11,128.39 130.54,128.39 130.76,128.61 130.76,129.1 130.97,129.32 131.4,129.32 131.62,129.1 131.62,128.61 131.84,128.39 139.27,128.39 v3(140.83,129.95)
  BOTTOM w0.102: v3(147.99,130.3) 147.8,130.11 144.48,130.11 144.35,129.98 142.92,129.98 142.59,130.31 141.19,130.31 v3(140.83,129.95) 140.73,129.85 137.14,129.85 137.02,129.72 v2(136.3,129.72) 135.36,129.72 v3(134.27,130.81)
M_DATA_A60: length 92.9
  TOP w0.102: CPU1.BA27 91.12,149.58 91.12,149.22 91.3,149.04 91.3,148.75 91.29,148.74 91.29,148.23 91.3,148.23 91.3,147.97 91.29,147.97 91.29,147.06 91.47,146.88 91.47,146.18 91.92,145.73
  TOP w0.165: v4(95.91,145.79) 95.59,145.47 95.59,144.96 95.34,144.71 94.97,144.71 94.77,144.91 92.74,144.91 91.92,145.73 ; v3(153.07,133.86) 153.53,134.45 DIMM2.180 ; DIMM1.180 136.9,134.45 v3(136.3,133.86)
  L4 w0.216: v4(95.91,145.79) 95.92,145.79 95.92,146.41 96.19,146.69 96.96,146.69 97.65,145.99 97.65,145.11 106.69,136.08 131.15,136.08 131.85,135.38 142.3,135.38 142.96,134.72 145.88,134.72 146.12,134.48 146.12,134.18 145.83,133.88 144.5,133.88 143.91,133.29 143.91,133.29 v3(143.64,133.02)
  BOTTOM w0.102: v3(153.07,133.86) 151.71,132.5 151.34,132.5 151.34,132.49 148.98,132.49 148.83,132.65 144.71,132.65 144.68,132.62 144.04,132.62 v3(143.64,133.02) 143.27,132.65 140.69,132.65 140.48,132.45 140.01,132.45 v2(140,132.45) 140,132.45 138.36,132.45 138.02,132.79 137.37,132.79 v3(136.3,133.86)
M_DATA_A61: length 90.8
  TOP w0.165: DIMM1.182 137.84,133.85 v3(137.83,133.86) ; v4(96.8,145.4) 96.79,145.38 96.79,144.94 96.16,144.31 94.99,144.31 94.85,144.45 92.82,144.45 91.23,146.04 91.23,146.79 91,147.02 CPU1.BC27 ; v3(151.47,133.35) 151.49,133.37 153.27,133.37 153.75,133.85 DIMM2.182
  L4 w0.216: v3(145.16,133.27) 145.07,133.18 145.07,132.99 144.58,132.51 143.43,132.51 143.13,132.81 143.13,133.86 142.1,134.89 131.64,134.89 130.94,135.59 130.45,135.59 130.24,135.37 130.24,135.1 130.02,134.89 129.59,134.89 129.37,135.1 129.37,135.37 129.16,135.59 128.73,135.59 128.51,135.37 128.51,135.1 128.3,134.89 127.86,134.89 127.65,135.1 127.65,135.37 127.43,135.59 127,135.59 126.78,135.37 126.78,135.1 126.57,134.89 126.14,134.89 125.92,135.1 125.92,135.37 125.7,135.59 125.27,135.59 125.06,135.37 125.06,135.1 124.84,134.89 124.41,134.89 124.19,135.1 124.19,135.37 123.98,135.59 123.55,135.59 123.33,135.37 123.33,135.1 123.11,134.89 122.68,134.89 122.47,135.1 122.47,135.37 122.25,135.59 121.82,135.59 121.6,135.37 121.6,135.1 121.39,134.89 120.95,134.89 120.74,135.1 120.74,135.37 120.52,135.59 120.09,135.59 119.88,135.37 119.88,135.1 119.66,134.89 119.23,134.89 119.01,135.1 119.01,135.37 118.8,135.59 118.36,135.59 118.15,135.37 118.15,135.1 117.93,134.89 117.5,134.89 117.28,135.1 117.28,135.37 117.07,135.59 106.49,135.59 96.81,145.26 96.81,145.39 v4(96.8,145.4)
  BOTTOM w0.102: v3(137.83,133.86) 137.83,133.55 138.36,133.02 142.68,133.02 143.19,133.53 144.24,133.53 144.24,133.53 144.62,133.53 144.62,133.53 144.88,133.53 145.14,133.27 v3(145.16,133.27) 145.2,133.27 145.24,133.32 145.87,133.32 146.17,133.02 149.65,133.02 v2(149.65,133.03) 149.65,133.02 151.14,133.02 v3(151.47,133.35)
M_DATA_A62: length 94.3
  TOP w0.165: DIMM1.192 138.56,130.85 138.03,130.32 137.55,130.32 v3(137.07,130.81) ; CPU1.BC25 89.4,147.98 89.44,147.94 89.44,147.08 89.23,146.87 89.23,144.92 v4(90.44,143.71) 89.6,142.88 v1(89.19,142.88) ; v3(153.07,130.81) 153.11,130.85 DIMM2.192
  L4 w0.216: v3(143.24,130.84) 143.21,130.84 143.1,130.95 139.94,130.95 139.29,130.3 128.7,130.3 128.49,130.51 128.49,130.78 128.27,130.99 127.84,130.99 127.62,130.78 127.62,130.51 127.41,130.3 126.97,130.3 126.76,130.51 126.76,130.78 126.54,130.99 126.11,130.99 125.89,130.78 125.89,130.51 125.68,130.3 125.25,130.3 125.03,130.51 125.03,130.78 124.82,130.99 124.38,130.99 124.17,130.78 124.17,130.51 123.95,130.3 123.52,130.3 123.3,130.51 123.3,130.78 123.09,130.99 122.66,130.99 122.44,130.78 122.44,130.51 122.22,130.3 121.79,130.3 121.58,130.51 121.58,130.78 121.36,130.99 120.93,130.99 120.71,130.78 120.71,130.51 120.5,130.3 120.07,130.3 119.85,130.51 119.85,130.78 119.63,130.99 119.2,130.99 118.99,130.78 118.99,130.51 118.77,130.3 118.34,130.3 118.12,130.51 118.12,130.78 117.91,130.99 117.47,130.99 117.26,130.78 117.26,130.51 117.04,130.3 116.61,130.3 116.4,130.51 116.4,130.78 116.18,130.99 115.75,130.99 115.53,130.78 115.53,130.51 115.32,130.3 107.55,130.3 96,141.85 93.41,141.85 93.41,141.84 92.24,141.84 90.44,143.64 v4(90.44,143.71)
  BOTTOM w0.102: v3(153.07,130.81) 152.61,131.27 143.67,131.27 v3(143.24,130.84) 142.81,131.27 142.44,131.27 142.23,131.06 142.03,131.06 141.83,131.27 141.62,131.27 141.42,131.06 141.22,131.06 141.01,131.27 140.81,131.27 140.61,131.06 140.4,131.06 140.2,131.27 140,131.27 139.79,131.06 139.59,131.06 139.39,131.27 139.18,131.27 138.98,131.06 138.78,131.06 138.57,131.27 137.52,131.27 v3(137.07,130.81)
M_DATA_A63: length 94.3
  TOP w0.102: CPU1.BB25 89.11,148.61 89.11,148.29 89.1,148.28 89.1,147.96 89.21,147.84 89.21,147.18 89,146.97 89,145.86 v4(88.55,145.41)
  TOP w0.165: v3(135.54,130.81) 136.32,130.03 138.15,130.03 138.37,130.25 DIMM1.194 ; DIMM2.194 152.1,130.25 v3(151.54,130.81)
  L4 w0.216: v4(88.55,145.41) 88.87,145.41 89.95,144.34 89.95,143.44 92.03,141.35 93.61,141.35 93.61,141.36 95.8,141.36 107.35,129.81 139.49,129.81 140.15,130.46 142.89,130.46 143.06,130.3 144.25,130.3 v3(144.76,130.81)
  BOTTOM w0.102: v3(135.54,130.81) 136,130.35 139.73,130.35 139.76,130.38 v2(139.77,130.38) 139.77,130.39 140.07,130.69 142.74,130.69 143.08,130.35 144.19,130.35 144.6,130.76 144.71,130.76 v3(144.76,130.81) 144.83,130.88 150.34,130.88 150.45,130.78 150.45,129.69 150.55,129.59 150.75,129.59 150.85,129.69 150.85,130.78 150.95,130.88 151.47,130.88 v3(151.54,130.81)
M_DQS_A_DN0: length 77.9
  TOP w0.102: 89.92,181.76 89.92,181.68 89.85,181.61 89.85,181.37 89.93,181.29 89.93,181.23 90.03,181.13 90.17,181.13 90.27,181.23 90.27,181.43 CPU1.A26
  TOP w0.127: v3(136.3,187.48) 136.3,188.01 136.48,188.19 138.12,188.19 138.45,187.85 DIMM1.10 ; v3(150.66,187.45) 151.14,187.93 151.54,187.93 151.78,188.18 152.48,188.18 153.15,187.5 153.45,187.5 153.8,187.85 DIMM2.10 ; v4(90.1,184.51) 90.21,184.4 90.21,183.94 90.08,183.81 90.08,183.32 90.16,183.24 90.16,182 89.92,181.76
  L3 w0.152: v3(150.66,187.45) 150.17,186.97 147.68,186.97 146.16,188.49 137.68,188.49 137.17,187.99 136.81,187.99 v3(136.3,187.48)
  L4 w0.152: v3(136.3,187.48) 136.3,187.81 136.1,188.01 132.19,188.01 131.65,188.55 104.03,188.55 103.22,187.74 97.51,187.74 97.05,187.27 92.75,187.27 90.52,185.05 90.52,184.93 v4(90.1,184.51)
  BOTTOM w0.127: v2(150.67,186.61) 150.66,186.62 v3(150.66,187.45)
M_DQS_A_DN1: length 73.7
  TOP w0.102: v4(95.17,184.07) 95.38,183.85 95.38,183.72 95.22,183.55 95.01,183.55 94.33,182.87 94.25,182.87 93.5,182.12 93.5,181.6 CPU1.A30
  TOP w0.127: v3(133.51,182.5) 133.61,182.5 134.03,182.08 134.03,181.73 133.86,181.56 133.59,181.56 133.21,181.94 132.64,181.94 132.28,182.3 132.28,182.46 131.99,182.75 DIMM1.27 ; v3(149.26,182.5) 149.16,182.5 148.69,182.97 147.53,182.97 147.31,182.75 DIMM2.27
  L3 w0.152: v4(95.17,184.07) 95.61,183.63 95.98,183.63 96.16,183.81 102.87,183.81 103.8,182.88 117.61,182.88 117.84,183.11 133.61,183.11 133.76,182.96 133.76,182.65 133.61,182.5 v3(133.51,182.5)
  L4 w0.152: v3(149.26,182.5) 150.32,183.57 150.32,184.61 149.87,185.06 147.58,185.06 145.8,183.29 135.16,183.29 135.03,183.41 134.02,183.41 133.69,183.08 133.69,182.68 v3(133.51,182.5)
  BOTTOM w0.127: v3(133.51,182.5) 132.71,181.7 v2(132.41,181.7)
M_DQS_A_DN2: length 67.9
  TOP w0.102: v4(97.73,179.63) 97.62,179.74 97.28,179.74 97.1,179.55 97.1,179.55 96.86,179.31 96.86,179.12 96.02,178.28 95.73,178.28 95.71,178.31 95.29,178.31 95.12,178.13 94.75,178.13 94.65,178.23 94.65,178.56 94.75,178.66 95.04,178.66 CPU1.E32
  TOP w0.127: DIMM2.45 147.14,177.35 147.79,176.7 148.68,176.7 148.82,176.84 148.82,177.09 v3(148.75,177.16) ; DIMM1.45 131.9,177.35 132.55,176.7 133.42,176.7 133.61,176.89 133.61,177.07 v3(133.51,177.16)
  L3 w0.152: v3(148.75,177.16) 148.24,176.65 141.72,176.65 140.42,177.95 134.63,177.95 134.37,177.7 134.04,177.7 v3(133.51,177.16)
  L4 w0.152: v3(133.51,177.16) 133.56,177.16 133.9,177.5 133.9,177.72 133.71,177.9 132.09,177.9 129.89,180.09 107.97,180.09 106.93,181.13 99.02,181.13 97.73,179.85 v4(97.73,179.63)
  BOTTOM w0.127: v2(132.5,176.35) 132.8,176.64 133.19,176.64 133.51,176.96 v3(133.51,177.16)
M_DQS_A_DN3: length 75.9
  TOP w0.102: v4(97.19,174.93) 96.9,174.93 96.72,175.11 96.38,175.11 96.36,175.08 95.77,175.08 95.74,175.11 95.22,175.11 95.11,175 95.01,175 94.91,175.1 94.91,175.3 95.01,175.4 CPU1.J32
  TOP w0.127: DIMM2.62 153.8,172.25 153.51,171.96 153.51,171.73 153.14,171.36 152.25,171.36 152.09,171.52 152.09,171.74 v3(152.18,171.83) ; DIMM1.62 140.13,172.25 141.53,170.85 142.19,170.85 142.76,170.28 143.62,170.28 143.8,170.46 143.8,170.91 143.39,171.32 v3(143.29,171.32)
  L3 w0.152: v3(152.18,171.83) 152.18,170.99 151.72,170.54 146.9,170.54 146.21,169.85 143.8,169.85 143.29,170.36 v3(143.29,171.32)
  L4 w0.152: v4(97.19,174.93) 97.32,174.8 97.93,174.8 98.49,175.36 102.58,175.36 105.9,172.04 106,172.04 116.92,172.04 118.54,170.41 131.96,170.41 132.57,169.8 140.46,169.8 140.96,170.3 143.64,170.3 143.75,170.41 143.75,170.87 v3(143.29,171.32)
  BOTTOM w0.127: v3(152.18,171.83) 152.91,171.1 152.91,171.06 v2(153.03,170.93)
M_DQS_A_DN4: length 72.9
  TOP w0.102: v4(99.17,153.47) 99.42,153.47 99.64,153.69 99.64,154.01 99.52,154.13 99.35,154.13 99.3,154.08 98.75,154.08 98.69,154.14 97.86,154.14 97.57,154.43 96.25,154.43 96.24,154.44 96.06,154.44 CPU1.AR33
  TOP w0.127: v3(149.64,147.45) 149.38,147.7 149.38,147.98 148.99,148.37 147.79,148.37 147.37,147.95 DIMM2.135 ; DIMM1.135 132,147.95 132.42,147.53 132.85,147.53 133.26,147.12 133.91,147.12 134.15,147.35 134.15,147.48 133.64,147.98 v3(133.64,147.98)
  L3 w0.152: v3(133.64,147.98) 133.66,147.95 133.66,146.81 134.02,146.46 138.03,146.46 139.78,148.21 144.05,148.21 144.05,148.21 145.91,148.21 147.62,146.49 147.71,146.41 149.16,146.41 149.54,146.79 149.54,147.35 v3(149.64,147.45)
  L4 w0.152: v4(99.17,153.47) 99.21,153.47 99.75,152.92 102.05,152.92 105.11,149.86 116.17,149.86 116.32,149.71 116.32,149.1 116.65,148.77 117.21,148.77 117.54,149.1 117.54,149.71 117.69,149.86 131.25,149.86 132.42,148.69 133.99,148.69 134.09,148.59 134.09,148.44 133.65,147.99 133.64,147.99 v3(133.64,147.98)
  BOTTOM w0.127: v2(133.37,147.15) 133.64,147.42 v3(133.64,147.98)
M_DQS_A_DN5: length 73
  TOP w0.127: DIMM2.152 153.96,142.85 153.54,142.43 153.54,142.43 153.26,142.15 152.53,142.15 152.35,142.33 152.31,142.38 v3(152.31,142.62) ; DIMM1.152 138.64,142.85 138.37,142.58 135.48,142.58 135.17,142.9 134.37,142.9 134.27,142.8 v3(134.27,142.37) ; v4(96.93,150.92) 96.89,150.96 96.25,150.96 95.96,151.26 95.9,151.32 CPU1.AW33
  L3 w0.152: v3(152.31,142.62) 151.65,143.28 144.61,143.28 142.5,141.17 140.32,141.17 139.03,142.46 138.08,143.41 135.64,143.41 135.09,142.85 134.75,142.85 v3(134.27,142.37)
  L4 w0.152: v4(96.93,150.92) 97.03,150.92 99.17,148.78 99.17,148.53 99.78,147.92 100.35,147.92 106.44,141.83 134.12,141.83 134.27,141.99 v3(134.27,142.37)
  BOTTOM w0.127: v4(96.93,150.92) v2(96.2,150.92)
M_DQS_A_DN6: length 79
  TOP w0.102: CPU1.AY29 92.89,150.5 93.1,150.29 93.1,149.17 93.13,149.15 93.13,148.67 93.07,148.62 93.07,148.37 v4(94.37,147.08)
  TOP w0.127: DIMM2.169 147.11,137.75 147.79,137.07 148.28,137.07 v3(148.75,137.54) ; DIMM1.169 131.93,137.75 132.28,137.4 133.35,137.4 133.49,137.26 v3(133.87,137.26)
  L3 w0.152: v4(94.37,147.08) 93.81,146.52 93.81,145.44 102.04,137.21 114.31,137.21 114.64,137.54 114.64,139.02 114.8,139.17 115.1,139.17 115.25,139.02 115.25,137.54 115.58,137.21 116.14,137.21 116.47,137.54 116.47,138.39 117.26,139.17 129.75,139.17 131.48,137.44 133.69,137.44 v3(133.87,137.26)
  L4 w0.152: v3(148.75,137.54) 148.85,137.64 148.85,138.05 148.62,138.28 143.33,138.28 141.55,136.5 134.98,136.5 134.68,136.8 134.32,136.8 v3(133.87,137.26)
  BOTTOM w0.127: v2(132.5,137.43) 132.6,137.53 133.21,137.53 133.48,137.26 v3(133.87,137.26)
M_DQS_A_DN7: length 81.7
  TOP w0.102: CPU1.AY25 89.79,150.11 89.79,149.28 89.97,149.1 89.97,148.73 89.87,148.63 89.87,148.37 89.95,148.3 89.95,146.8 89.67,146.52 89.67,146.1 90.08,145.69 v4(90.08,145.67)
  TOP w0.127: v3(137.07,132.26) 137.61,132.8 138.02,132.8 138.18,132.65 DIMM1.186 ; v3(152.3,132.08) 152.76,132.54 153.63,132.54 153.73,132.65 DIMM2.186
  L3 w0.152: v3(152.3,132.08) 151.81,132.56 146.79,132.56 146.41,132.18 143.01,132.18 142.6,132.59 140.06,132.59 139.29,131.83 138.03,131.83 138.03,131.82 137.63,131.82 137.19,132.26 v3(137.07,132.26)
  L4 w0.152: v4(90.08,145.67) 90.31,145.67 91.27,144.7 91.27,143.98 92.58,142.68 93.06,142.68 93.06,142.68 96.35,142.68 107.2,131.83 136.66,131.83 137.07,132.23 v3(137.07,132.26)
  BOTTOM w0.127: v3(137.07,132.26) 136.25,133.07 v2(135.91,133.07)
M_DQS_A_DP0: length 77.2
  TOP w0.127: v3(151.42,187.45) 151.89,187.92 152.37,187.92 153.05,187.25 DIMM2.12 ; v4(90.15,185.29) 90.39,185.06 90.39,184.81 90.52,184.68 90.52,184.33 90.46,184.28 90.46,183.84 90.33,183.7 90.33,183.43 90.42,183.34 90.42,181.73 90.52,181.63 90.52,181.02 CPU1.B26 ; DIMM1.12 138.69,187.25 138.01,187.93 137.55,187.93 137.09,187.48 v3(137.07,187.48)
  L3 w0.152: v3(151.42,187.45) 150.93,186.97 150.6,186.97 150.3,186.66 147.56,186.66 146.03,188.19 137.8,188.19 137.09,187.48 v3(137.07,187.48)
  L4 w0.152: v4(90.15,185.29) 90.33,185.29 92.62,187.58 96.92,187.58 97.38,188.04 103.1,188.04 103.91,188.85 131.78,188.85 132.32,188.32 136.23,188.32 v3(137.07,187.48)
  BOTTOM w0.127: v2(151.85,188.39) 151.42,187.96 v3(151.42,187.45)
M_DQS_A_DP1: length 73.5
  TOP w0.102: CPU1.B30 93.71,181.34 93.71,182.03 94.34,182.67 94.41,182.67 95.09,183.35 95.3,183.35 95.59,183.63 95.59,183.84 v4(95.8,184.06)
  TOP w0.127: DIMM2.29 147.08,182.15 147.43,182.5 147.43,182.51 147.64,182.71 148.28,182.71 v3(148.5,182.5) ; v3(134.27,182.5) 134.27,182.19 134.28,182.18 134.28,181.62 133.97,181.31 133.48,181.31 133.1,181.69 132.54,181.69 132.07,182.15 DIMM1.29
  L3 w0.152: v4(95.8,184.06) 95.98,184.06 96.04,184.11 103,184.11 103.93,183.18 117.48,183.18 117.71,183.41 133.74,183.41 134.07,183.08 134.07,182.7 v3(134.27,182.5)
  L4 w0.152: v3(134.27,182.5) 133.99,182.78 133.99,182.96 134.15,183.11 134.91,183.11 135.03,182.98 145.93,182.98 147.71,184.76 149.74,184.76 150.02,184.48 150.02,183.69 149.46,183.13 148.22,183.13 148.06,182.98 148.06,182.77 148.33,182.5 v3(148.5,182.5)
  BOTTOM w0.127: v2(135.14,183.38) 134.27,182.51 v3(134.27,182.5)
M_DQS_A_DP2: length 68.3
  TOP w0.102: CPU1.F32 95.05,177.8 95.18,177.93 95.2,177.93 95.37,178.1 95.63,178.1 95.65,178.08 96.1,178.08 97.17,179.15 v4(97.26,179.15)
  TOP w0.127: v3(149.51,177.16) 148.79,176.44 147.69,176.44 147.38,176.75 DIMM2.47 ; DIMM1.47 132.14,176.75 132.45,176.44 133.52,176.44 v3(134.27,177.19)
  L3 w0.152: v3(134.27,177.19) 134.3,177.19 134.75,177.65 140.29,177.65 141.59,176.35 148.37,176.35 148.7,176.68 149.03,176.68 v3(149.51,177.16)
  L4 w0.152: v3(134.27,177.19) 134.2,177.26 134.2,177.84 133.84,178.21 132.21,178.21 130.02,180.4 108.09,180.4 107.05,181.44 98.89,181.44 97.26,179.81 v4(97.26,179.15)
  BOTTOM w0.127: v3(134.27,177.19) 134.27,177.13 v2(135.16,176.24)
M_DQS_A_DP3: length 75.6
  TOP w0.102: CPU1.K32 95,174.6 95.31,174.9 95.64,174.9 95.66,174.88 96.38,174.88 v4(96.55,174.7)
  TOP w0.127: v3(151.42,171.83) 152.14,171.11 153.24,171.11 153.78,171.65 DIMM2.64 ; v3(144.05,171.32) 144.05,170.36 143.72,170.03 142.65,170.03 142.08,170.6 141.42,170.6 140.37,171.65 DIMM1.64
  L3 w0.152: v3(144.05,171.32) 143.59,170.87 143.59,170.48 143.92,170.15 146.08,170.15 146.77,170.84 151.59,170.84 151.87,171.12 151.87,171.37 v3(151.42,171.83)
  L4 w0.152: v4(96.55,174.7) 96.76,174.5 98.05,174.5 98.61,175.06 102.46,175.06 105.78,171.74 116.79,171.74 118.42,170.11 131.83,170.11 132.45,169.49 140.59,169.49 141.09,170 143.77,170 144.05,170.28 v3(144.05,171.32)
  BOTTOM w0.127: v2(151.02,172.83) 151.02,172.77 151.42,172.37 v3(151.42,171.83)
M_DQS_A_DP4: length 73.7
  TOP w0.102: CPU1.AR32 95.33,154.37 95.68,154.37 95.82,154.23 97.48,154.23 97.77,153.94 98.32,153.94 98.35,153.91 98.46,153.8 v4(98.56,153.7)
  TOP w0.127: DIMM2.137 147.13,147.35 147.9,148.12 148.89,148.12 149.13,147.88 149.13,147.7 v3(148.88,147.45) ; v3(134.4,148.01) 134.4,147.24 134.02,146.86 133.15,146.86 132.74,147.27 132.17,147.27 132.15,147.3 132.06,147.35 DIMM1.137
  L3 w0.152: v3(148.88,147.45) 149.23,147.09 149.23,146.91 149.03,146.71 147.84,146.71 146.51,148.03 146.03,148.51 139.66,148.51 137.9,146.76 134.14,146.76 133.97,146.94 133.97,147.19 134.12,147.35 134.65,147.35 134.81,147.5 134.81,147.68 134.48,148.01 v3(134.4,148.01)
  L4 w0.152: v4(98.56,153.7) 98.76,153.9 99.35,153.9 99.62,153.64 99.62,153.49 99.87,153.23 102.17,153.23 105.24,150.16 116.3,150.16 116.63,149.83 116.63,149.23 116.78,149.08 117.08,149.08 117.24,149.23 117.24,149.83 117.57,150.16 131.38,150.16 132.55,149 134.12,149 134.4,148.72 v3(134.4,148.01)
  BOTTOM w0.127: v4(98.56,153.7) 97.72,154.53 v2(97.01,154.53)
M_DQS_A_DP5: length 72.2
  TOP w0.127: v4(96.93,150.29) 96.51,150.71 96.15,150.71 95.94,150.92 95.74,151.12 95.38,151.12 CPU1.AW32 ; DIMM1.154 138.54,142.25 138.46,142.33 135.07,142.33 v3(135.03,142.37) ; DIMM2.154 153.72,142.25 153.37,141.9 152.43,141.9 152.18,142.15 152.01,142.15 v3(151.54,142.62)
  L3 w0.152: v3(151.54,142.62) 151.19,142.98 144.73,142.98 142.63,140.87 140.19,140.87 138.9,142.16 137.95,143.1 135.77,143.1 v3(135.03,142.37)
  L4 w0.152: v3(135.03,142.37) 135.03,142.32 134.25,141.53 106.31,141.53 100.23,147.61 99.65,147.61 98.86,148.4 98.86,148.66 97.23,150.29 v4(96.93,150.29)
  BOTTOM w0.127: v2(96.27,149.66) 96.9,150.29 v4(96.93,150.29)
M_DQS_A_DP6: length 79.3
  TOP w0.102: CPU1.BA29 92.89,149.41 92.89,149.09 92.92,149.06 92.92,148.78 92.92,148.78 92.92,148.75 92.87,148.7 92.87,148.29 93.96,147.2 93.96,146.91 94.2,146.67 94.21,146.67 v4(94.43,146.45)
  TOP w0.127: v3(134.63,137.29) 134.12,136.78 133.61,136.78 133.24,137.15 DIMM1.171 ; DIMM2.171 147.35,137.15 147.69,136.82 148.39,136.82 148.64,137.07 148.97,137.07 149.44,137.54 v3(149.51,137.54)
  L3 w0.152: v3(134.63,137.29) 134.17,137.74 131.61,137.74 129.88,139.47 117.13,139.47 116.17,138.51 116.17,137.67 116.02,137.52 115.71,137.52 115.56,137.67 115.56,139.14 115.23,139.47 114.67,139.47 114.34,139.14 114.34,137.67 114.19,137.52 102.17,137.52 94.12,145.57 94.12,146.05 94.43,146.36 v4(94.43,146.45)
  L4 w0.152: v3(134.63,137.29) 135.11,136.8 141.43,136.8 143.2,138.58 148.75,138.58 149.16,138.18 149.16,137.9 v3(149.51,137.54)
  BOTTOM w0.127: v3(134.63,137.29) 134.63,137.81 134.61,137.83 134.61,138.18 v2(134.48,138.31)
M_DQS_A_DP7: length 79.7
  TOP w0.102: CPU1.BA25 89.59,149.51 89.59,149.19 89.77,149.01 89.77,148.82 89.67,148.72 89.67,148.29 89.74,148.21 89.74,146.89 89.47,146.61 89.47,146.02 89.67,145.81 89.67,145.5 90.08,145.09 v4(90.08,145.03)
  TOP w0.127: v3(137.83,132.3) 137.86,132.3 138.11,132.05 DIMM1.188 ; v3(153.06,132.07) 153.08,132.05 DIMM2.188
  L3 w0.152: v3(137.83,132.3) 138,132.13 139.17,132.13 139.93,132.89 142.73,132.89 143.13,132.49 146.29,132.49 146.67,132.87 151.94,132.87 152.23,132.58 152.55,132.58 v3(153.06,132.07)
  L4 w0.152: v3(137.83,132.3) 137.3,131.78 137.04,131.78 136.79,131.52 107.07,131.52 96.22,142.37 93.19,142.37 93.19,142.37 92.45,142.37 90.97,143.86 90.97,144.58 90.51,145.03 v4(90.08,145.03)
  BOTTOM w0.127: v3(153.06,132.07) 153.82,132.07 153.85,132.1 v2(153.93,132.1)
M_MA_DM0: length 88
  TOP w0.165: DIMM2.11 147.86,187.55 v3(147.96,187.45) ; CPU1.D25 89.4,179.5 v4(89.8,179.9) ; v3(132.75,187.45) 132.65,187.55 DIMM1.11
  L4 w0.216: v3(140.88,187.58) 140.74,187.44 140.46,187.44 139.96,186.94 132.1,186.94 131.02,188.02 121.46,188.02 120.64,187.21 120.15,187.21 119.94,187.43 119.94,187.81 119.72,188.02 119.29,188.02 119.08,187.81 119.08,187.43 118.86,187.21 118.43,187.21 118.21,187.43 118.21,187.81 118,188.02 117.56,188.02 117.35,187.81 117.35,187.43 117.13,187.21 116.7,187.21 116.48,187.43 116.48,187.81 116.27,188.02 115.84,188.02 115.62,187.81 115.62,187.43 115.4,187.21 114.97,187.21 114.76,187.43 114.76,187.81 114.54,188.02 114.11,188.02 113.89,187.81 113.89,187.43 113.68,187.21 113.25,187.21 113.03,187.43 113.03,187.81 112.81,188.02 112.38,188.02 112.17,187.81 112.17,187.43 111.95,187.21 111.52,187.21 111.3,187.43 111.3,187.81 111.09,188.02 110.66,188.02 110.44,187.81 110.44,187.43 110.22,187.21 109.79,187.21 109.58,187.43 109.58,187.81 109.36,188.02 108.93,188.02 108.71,187.81 108.71,187.43 108.5,187.21 108.06,187.21 107.85,187.43 107.85,187.81 107.63,188.02 107.2,188.02 106.98,187.81 106.98,187.43 106.77,187.21 106.34,187.21 106.12,187.43 106.12,187.81 105.91,188.02 105.47,188.02 105.26,187.81 105.26,187.43 105.04,187.21 97.73,187.21 97.26,186.75 96.83,186.75 96.83,186.75 92.96,186.75 90.56,184.34 90.56,184.05 90.33,183.82 90.33,181.97 89.8,181.43 v4(89.8,179.9)
  BOTTOM w0.102: v3(147.96,187.45) 147.96,187.92 147.86,188.03 145.59,188.03 145.49,188.13 145.49,188.37 145.39,188.47 145.19,188.47 145.08,188.37 145.08,188.13 144.98,188.03 141.45,188.03 v3(140.88,187.58) 140.42,187.91 137.6,187.91 137.57,187.93 134.52,187.93 v2(134.51,187.94) 134.5,187.93 133.23,187.93 v3(132.75,187.45)
M_MA_DM1: length 79.5
  TOP w0.102: CPU1.D29 93.1,180 93.1,180.83 93.11,180.83 93.11,181.35 93.1,181.35 93.1,181.66 93.2,181.76 93.2,182.12 93.62,182.54 93.62,182.77
  TOP w0.165: DIMM1.28 137.88,182.45 v3(137.83,182.5) ; v3(153.07,182.5) 153.12,182.45 DIMM2.28 ; v4(94.13,183.28) 93.62,182.77
  L3 w0.216: v3(144.05,182.5) 143.4,183.15 140.16,183.15 138.89,184.41 131.54,184.41 130.76,185.19 121.07,185.19 120.86,184.97 120.86,184.24 120.64,184.02 120.21,184.02 119.99,184.24 119.99,184.97 119.78,185.19 118.86,185.19 118.64,184.97 118.64,184.19 118.42,183.97 116.54,183.97 116.42,183.85 104.01,183.85 103.22,184.64 96.75,184.64 96.25,185.14 95.35,185.14 94.14,183.93 94.14,183.29 v4(94.13,183.28)
  BOTTOM w0.102: v3(153.07,182.5) 152.61,182.04 147.77,182.04 147.25,182.57 145.61,182.57 145.22,182.96 144.51,182.96 v3(144.05,182.5) 143.59,182.04 v2(140.17,182.04) 139.17,182.04 138.72,182.5 v3(137.83,182.5)
M_MA_DM2: length 78.3
  TOP w0.165: v3(153.07,177.16) 153.18,177.05 DIMM2.46 ; v4(102.14,181.97) v1(101.18,181.01) 100.79,180.62 97.83,180.62 96.62,179.41 96.62,179.32 CPU1.E33 ; DIMM1.46 137.94,177.05 v3(137.83,177.16)
  L4 w0.216: v4(102.14,181.97) 107.27,181.97 108.31,180.93 109.09,180.93 109.3,181.14 109.3,181.77 109.52,181.98 109.95,181.98 110.17,181.77 110.17,181.14 110.38,180.93 110.82,180.93 111.03,181.14 111.03,181.77 111.25,181.98 111.68,181.98 111.9,181.77 111.9,181.14 112.11,180.93 112.54,180.93 112.76,181.14 112.76,181.77 112.97,181.98 113.41,181.98 113.62,181.77 113.62,181.14 113.84,180.93 130.39,180.93 132.11,179.2 138.89,179.2 140.41,177.68 143.74,177.68 v3(144.25,177.17)
  BOTTOM w0.102: v3(137.83,177.16) 137.83,176.78 137.93,176.68 138.55,176.68 138.65,176.58 138.65,176.2 138.75,176.1 138.96,176.1 139.06,176.2 139.06,176.58 139.16,176.68 139.36,176.68 139.47,176.58 139.47,176.2 139.57,176.1 139.77,176.1 139.87,176.2 139.87,176.58 140,176.71 142.98,176.71 142.99,176.68 143.68,176.68 143.68,176.68 143.77,176.68 144,176.91 144,176.98 144.19,177.16 144.25,177.16 v3(144.25,177.17) 144.31,177.17 144.59,177.45 144.63,177.45 144.8,177.62 150.48,177.62 151.39,176.71 152.61,176.71 v3(153.07,177.16)
M_MA_DM3: length 81.7
  TOP w0.102: CPU1.J33 97,175.4 97.42,175.82 97.97,175.82
  TOP w0.165: 97.97,175.82 99.4,175.82 99.42,175.84 99.92,175.84 100.53,176.45 100.91,176.45 101.19,176.18 101.36,176.01 101.36,175.99 v4(101.43,175.92) ; DIMM2.63 147.87,171.95 v3(147.99,171.83) ; v3(132.75,171.96) 132.74,171.95 DIMM1.63
  L4 w0.216: v3(141.77,171.32) 141.38,170.94 126.55,170.94 126.34,171.16 126.34,172.35 126.12,172.57 125.69,172.57 125.47,172.35 125.47,171.16 125.26,170.94 124.83,170.94 124.61,171.16 124.61,172.35 124.4,172.57 123.96,172.57 123.75,172.35 123.75,171.16 123.53,170.94 123.1,170.94 122.88,171.16 122.88,172.35 122.67,172.57 122.24,172.57 122.02,172.35 122.02,171.16 121.8,170.94 121.37,170.94 121.16,171.16 121.16,172.35 120.94,172.57 120.51,172.57 120.29,172.35 120.29,171.16 120.08,170.94 119.25,170.94 119.03,171.16 119.03,172.35 118.82,172.57 106.12,172.57 102.75,175.94 102.17,175.94 102.15,175.92 v4(101.43,175.92)
  BOTTOM w0.102: v3(132.75,171.96) 133.58,171.12 138.17,171.12 138.37,171.32 139.87,171.32 v2(139.89,171.3) 139.91,171.32 v3(141.77,171.32) 141.9,171.46 142.01,171.46 142.34,171.78 145.27,171.78 145.37,171.68 145.37,170.66 145.47,170.56 145.68,170.56 145.78,170.66 145.78,171.68 145.88,171.78 147.94,171.78 v3(147.99,171.83)
M_MA_DM4: length 82.1
  TOP w0.102: 97.77,154.64 96.35,154.64 96.08,154.9 95.75,154.9 95.74,154.89 95.25,154.89 95.24,154.9 93.8,154.9 CPU1.AR30
  TOP w0.165: v3(137.83,147.57) 137.9,147.65 DIMM1.136 ; DIMM2.136 153.27,147.65 v3(153.07,147.45) ; 97.77,154.64 98.03,154.38 98.79,154.38 98.79,154.37 99.15,154.37 99.39,154.61 100.1,154.61 100.36,154.34 v4(100.36,154.34)
  L4 w0.216: v4(100.36,154.34) 100.49,154.21 100.49,154.19 100.87,153.81 102.4,153.81 105.43,150.78 119.25,150.78 119.47,151 119.47,151.35 119.68,151.56 120.11,151.56 120.33,151.35 120.33,151 120.55,150.78 120.98,150.78 121.19,151 121.19,151.35 121.41,151.56 121.84,151.56 122.06,151.35 122.06,151 122.27,150.78 122.71,150.78 122.92,151 122.92,151.35 123.14,151.56 123.57,151.56 123.79,151.35 123.79,151 124,150.78 124.43,150.78 124.65,151 124.65,151.35 124.86,151.56 125.3,151.56 125.51,151.35 125.51,151 125.73,150.78 126.16,150.78 126.38,151 126.38,151.35 126.59,151.56 127.02,151.56 127.24,151.35 127.24,151 127.46,150.78 128.31,150.78 129.13,150.78 129.13,150.78 135.22,150.78 136.55,149.45 136.55,149.27 136.85,148.96 138.38,148.96 139.02,148.32 143.3,148.32 143.8,147.83 143.8,147.78 v3(143.85,147.73)
  BOTTOM w0.102: v3(137.83,147.57) 137.83,147.39 137.55,147.12 136.63,147.12 136.53,147.22 136.53,147.85 136.73,148.06 138.31,148.06 138.44,148.18 143.39,148.18 v3(143.85,147.73) 143.91,147.73 144.42,147.21 144.8,147.21 144.92,147.34 145.32,147.34 145.85,147.87 146.65,147.87 v2(146.67,147.85) 146.73,147.9 152.61,147.9 v3(153.07,147.45)
M_MA_DM5: length 81.7
  TOP w0.165: v3(148.12,142.49) 148.06,142.55 DIMM2.153 ; v3(132.75,142.37) 132.55,142.55 DIMM1.153 ; v4(93.93,151.76) 93.57,151.4 CPU1.AW30
  L4 w0.216: v4(93.93,151.76) 96.24,149.45 96.72,149.45 97.12,149.05 97.59,149.05 99.56,147.08 99.91,147.08 105.99,141 107.17,141 107.38,140.79 107.38,140.23 107.6,140.02 108.03,140.02 108.25,140.23 108.25,140.79 108.46,141 108.89,141 109.11,140.79 109.11,140.23 109.33,140.02 109.76,140.02 109.97,140.23 109.97,140.79 110.19,141 110.62,141 110.84,140.79 110.84,140.23 111.05,140.02 111.49,140.02 111.7,140.23 111.7,140.79 111.92,141 117.67,141 117.89,140.79 117.89,140.67 118.1,140.46 118.54,140.46 118.75,140.67 118.75,140.79 118.97,141 119.4,141 119.62,140.79 119.62,140.67 119.83,140.46 120.26,140.46 120.48,140.67 120.48,140.79 120.69,141 121.13,141 121.34,140.79 121.34,140.67 121.56,140.46 121.99,140.46 122.21,140.67 122.21,140.79 122.42,141 122.85,141 123.07,140.79 123.07,140.67 123.29,140.46 123.72,140.46 123.93,140.67 123.93,140.79 124.15,141 124.58,141 124.8,140.79 124.8,140.67 125.01,140.46 125.44,140.46 125.66,140.67 125.66,140.79 125.88,141 126.31,141 126.52,140.79 126.52,140.67 126.74,140.46 127.17,140.46 127.39,140.67 127.39,140.79 127.6,141 128.04,141 128.25,140.79 128.25,140.67 128.47,140.46 128.9,140.46 129.12,140.67 129.12,140.79 129.33,141 129.76,141 129.98,140.79 129.98,140.67 130.19,140.46 130.63,140.46 130.84,140.67 130.84,140.79 131.06,141 131.49,141 131.71,140.79 131.71,140.67 131.92,140.46 138.04,140.46 138.34,140.76 138.34,140.78 140.3,142.74 140.67,142.74 v3(140.7,142.77)
  BOTTOM w0.102: v3(132.75,142.37) 133.21,142.82 135.27,142.82 135.75,142.34 v2(137.98,142.34) 139.49,142.34 139.91,142.77 v3(140.7,142.77) 140.88,142.59 144.33,142.59 144.34,142.59 144.66,142.59 144.7,142.62 145.08,142.62 145.33,142.37 147.88,142.37 148,142.49 v3(148.12,142.49)
M_MA_DM6: length 93
  TOP w0.165: v3(153.07,137.54) 153.16,137.45 DIMM2.170 ; v3(137.07,137.29) 137.55,137.78 138.03,137.78 138.36,137.45 DIMM1.170 ; v4(95.22,145.78) 95.62,146.18 95.62,146.82 94.48,147.96 94.48,148.26 94.24,148.5 CPU1.BC30
  L3 w0.216: v4(95.22,145.78) 95.62,145.38 95.62,145.06 102.63,138.05 107.04,138.05 108.24,139.24 108.24,139.98 108.45,140.19 108.88,140.19 109.1,139.98 109.1,138.26 109.32,138.05 109.75,138.05 109.96,138.26 109.96,139.98 110.18,140.19 110.61,140.19 110.83,139.98 110.83,138.26 111.04,138.05 111.48,138.05 111.69,138.26 111.69,139.98 111.91,140.19 112.34,140.19 112.56,139.98 112.56,138.26 112.77,138.05 113.2,138.05 113.42,138.26 113.42,139.29 114.32,140.19 130.41,140.19 131.62,138.98 131.63,138.98 132.3,138.31 138.25,138.31 138.65,137.92 142.49,137.92 142.5,137.93 142.77,137.93 142.98,138.14 143.45,138.14 v3(144.05,137.54)
  BOTTOM w0.102: v3(153.07,137.54) 152.61,138 v2(151.27,138) 147.8,138 146.88,137.08 144.51,137.08 v3(144.05,137.54) 143.59,137.08 142.83,137.08 142.73,137.19 142.73,137.54 142.63,137.64 142.43,137.64 142.32,137.54 142.32,137.19 142.22,137.08 141.48,137.08 141.38,137.19 141.38,137.37 140.65,138.1 138.97,138.1 138.62,137.74 137.52,137.74 v3(137.07,137.29)
M_MA_DM7: length 92.4
  TOP w0.165: v3(132.75,132.33) 132.73,132.35 DIMM1.187 ; v3(147.99,132.08) 147.72,132.35 DIMM2.187 ; CPU1.BC26 90.2,146.87 90.56,146.51 90.56,145.21 90.99,144.78 90.99,144.12 92.74,142.37 93.95,142.37 94.39,142.81 v4(94.39,143.26)
  L4 w0.216: v3(141.64,132.08) 140.86,132.85 132.4,132.85 131.9,132.35 131.25,132.35 131.03,132.57 131.03,133.23 130.85,133.41 130.36,133.41 130.17,133.23 130.17,132.57 129.95,132.35 129.52,132.35 129.31,132.57 129.31,133.23 129.12,133.41 128.63,133.41 128.44,133.23 128.44,132.57 128.23,132.35 127.8,132.35 127.58,132.57 127.58,133.23 127.39,133.41 126.9,133.41 126.72,133.23 126.72,132.57 126.5,132.35 126.07,132.35 125.85,132.57 125.85,133.23 125.67,133.41 125.18,133.41 124.99,133.23 124.99,132.57 124.77,132.35 124.34,132.35 124.12,132.57 124.12,133.23 123.94,133.41 123.45,133.41 123.26,133.23 123.26,132.57 123.05,132.35 107.42,132.35 96.55,143.22 94.43,143.22 v4(94.39,143.26)
  BOTTOM w0.102: v3(147.99,132.08) 147.56,131.65 147.15,131.65 147.05,131.75 147.05,132.17 146.94,132.27 146.74,132.27 146.64,132.17 146.64,131.75 146.54,131.65 146.33,131.65 146.23,131.75 146.23,132.17 146.13,132.27 145.93,132.27 145.83,132.17 145.83,131.75 145.73,131.65 145.52,131.65 145.42,131.75 145.42,132.17 145.32,132.27 145.12,132.27 145.01,132.17 145.01,131.75 144.91,131.65 142.07,131.65 v3(141.64,132.08) 141.2,131.64 140.65,131.64 140.6,131.7 v2(134.95,131.7) 133.38,131.7 v3(132.75,132.33)
M_MAA_A0: length 82.2
  TOP w0.102: 97.17,161.27 97.14,161.24 96.12,161.24 96.06,161.3 95.78,161.3 95.77,161.29 95.25,161.29 95.24,161.3 94.96,161.3 94.66,161 CPU1.AG31
  TOP w0.165: v3(134.78,157.73) 135.69,158.64 137.78,158.64 138.18,159.05 DIMM1.98 ; v3(151.54,159.56) 151.62,159.56 152.13,159.05 DIMM2.98 ; v4(97.7,161.8) 97.17,161.27
  L3 w0.216: v4(144.79,156.01) 144.76,156.03 144.76,156.08 143.95,156.89 127.92,156.89 127.17,157.64 108.47,157.64 108.26,157.85 108.23,157.85 103.73,162.34 101.73,162.34 101.69,162.38 101.44,162.63 100.59,162.63 100.59,162.63 99.83,162.63 99.83,162.63 98.51,162.63 97.87,161.99 97.87,161.97 v4(97.7,161.8)
  L4 w0.216: v3(134.78,157.73) 135.57,156.95 143.85,156.95 v4(144.79,156.01) 147.28,158.5 150.48,158.5 v3(151.54,159.56)
  BOTTOM w0.165: v4(144.79,156.01) 145.55,156.01 v2(145.6,155.96)
M_MAA_A1: length 71.5
  TOP w0.102: CPU1.AC30 94.23,164.56 94.77,164.69 94.87,164.71 94.87,164.72 95.33,164.72 95.35,164.7 95.64,164.7 95.66,164.72 96.12,164.72 96.25,164.59 96.62,164.59 96.86,164.83 96.86,165.2
  TOP w0.165: DIMM2.97 145.54,159.35 145.02,159.87 143.02,159.87 v3(142.53,159.38) ; v3(134.78,159.13) 134.29,158.64 133.05,158.64 132.34,159.35 DIMM1.97 ; 96.86,165.2 96.86,165.24 97.36,165.75 98.26,165.75 v4(98.35,165.84)
  L3 w0.216: v3(142.53,159.38) 141.59,160.32 140.12,160.32 138.18,162.26 137.23,162.26 137.13,162.35 131.76,162.35 130.5,163.62 127.93,163.62 127.3,164.25 126.87,164.68 121.28,164.68 118.45,167.5 101.95,167.5 101.28,166.84 99.35,166.84 v4(98.35,165.84)
  L4 w0.216: v3(134.78,159.13) 135.29,158.62 141.76,158.62 v3(142.53,159.38)
  BOTTOM w0.165: v3(134.78,159.13) 134.78,159.92 v2(134.81,159.94)
M_MAA_A2: length 72.1
  TOP w0.102: 97.07,164.71 96.72,164.36 96.17,164.36 96.02,164.52 95.76,164.52 95.7,164.45 95.3,164.45 95.23,164.52 94.95,164.52 94.63,164.2 CPU1.AC31
  TOP w0.165: v4(97.44,165.21) 97.44,165.08 97.07,164.71 ; DIMM2.96 153.33,159.65 153.27,159.59 v3(153.09,159.59) ; DIMM1.96 140.07,159.65 140.51,159.2 140.51,159.18 140.8,158.9 142.8,158.9 v3(143.29,159.38)
  L3 w0.216: v3(143.29,159.38) 143.29,159.51 142.06,160.74 140.3,160.74 138.36,162.68 137.4,162.68 136.63,163.46 131.25,163.46 130.67,164.04 128.1,164.04 127,165.14 121.64,165.14 118.85,167.93 101.77,167.93 101.11,167.26 99.12,167.26 97.44,165.58 v4(97.44,165.21)
  L4 w0.216: v3(153.09,159.59) 153.07,159.61 153.07,160.07 152.84,160.3 144.2,160.3 v3(143.29,159.38)
  BOTTOM w0.165: v3(143.29,159.38) v2(143.29,160.2)
M_MAA_A3: length 72.8
  TOP w0.102: CPU1.AB32 95,165.3 95.64,165.3 95.64,165.29 96.13,165.29 96.27,165.43 96.5,165.43 97.05,165.98 97.92,165.98 98.18,166.25 98.59,166.25
  TOP w0.165: v4(101.76,166.62) 99.79,166.62 99.42,166.25 98.59,166.25 ; DIMM1.95 132.44,159.95 v3(133.26,159.13) ; v3(141,159.38) 141.78,160.17 145.14,160.17 145.35,159.95 DIMM2.95
  L3 w0.216: v4(101.76,166.62) 102.22,167.08 102.83,167.08 102.94,166.96 118.25,166.96 120.96,164.25 121.51,164.25 121.73,164.04 121.73,163.49 121.95,163.27 122.38,163.27 122.59,163.49 122.59,164.04 122.81,164.25 123.24,164.25 123.46,164.04 123.46,163.39 123.67,163.17 124.1,163.17 124.32,163.39 124.32,164.04 124.54,164.25 124.97,164.25 125.18,164.04 125.18,163.39 125.4,163.17 125.83,163.17 126.05,163.39 126.05,164.04 126.26,164.25 126.69,164.25 126.91,164.04 126.91,163.41 127.13,163.19 130.32,163.19 131.59,161.93 136.96,161.93 137.05,161.84 138.01,161.84 139.95,159.9 140.49,159.9 v3(141,159.38)
  L4 w0.216: v3(133.26,159.13) 134.02,159.9 140.49,159.9 v3(141,159.38)
  BOTTOM w0.165: v2(133.26,158.32) v3(133.26,159.13)
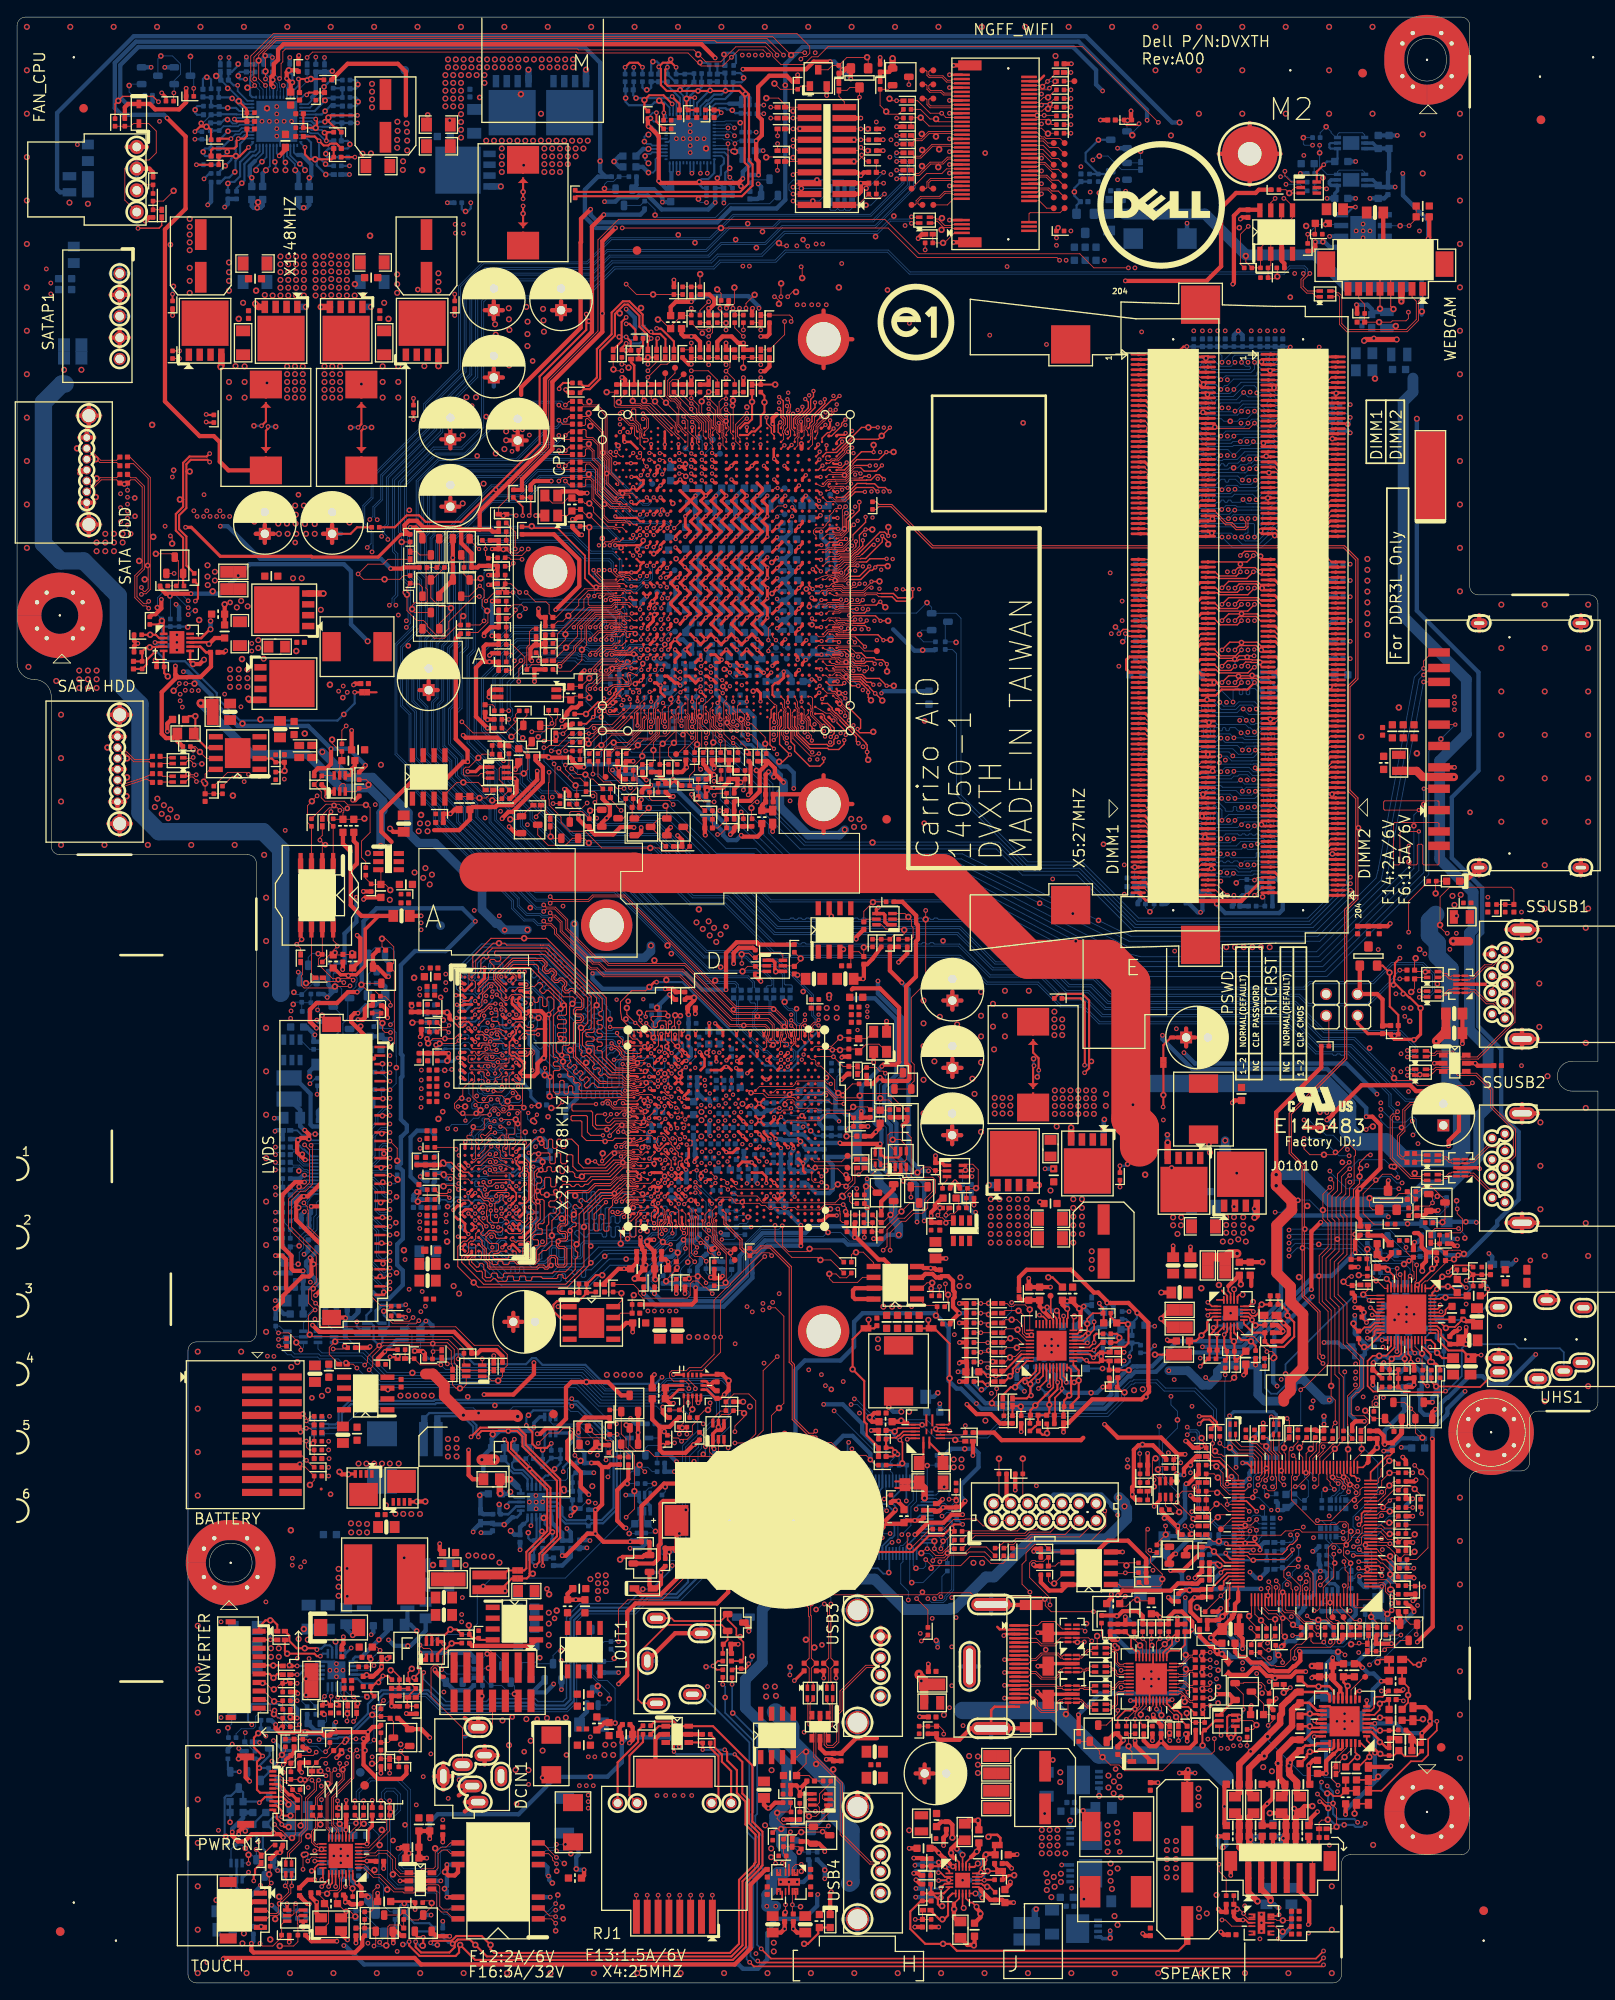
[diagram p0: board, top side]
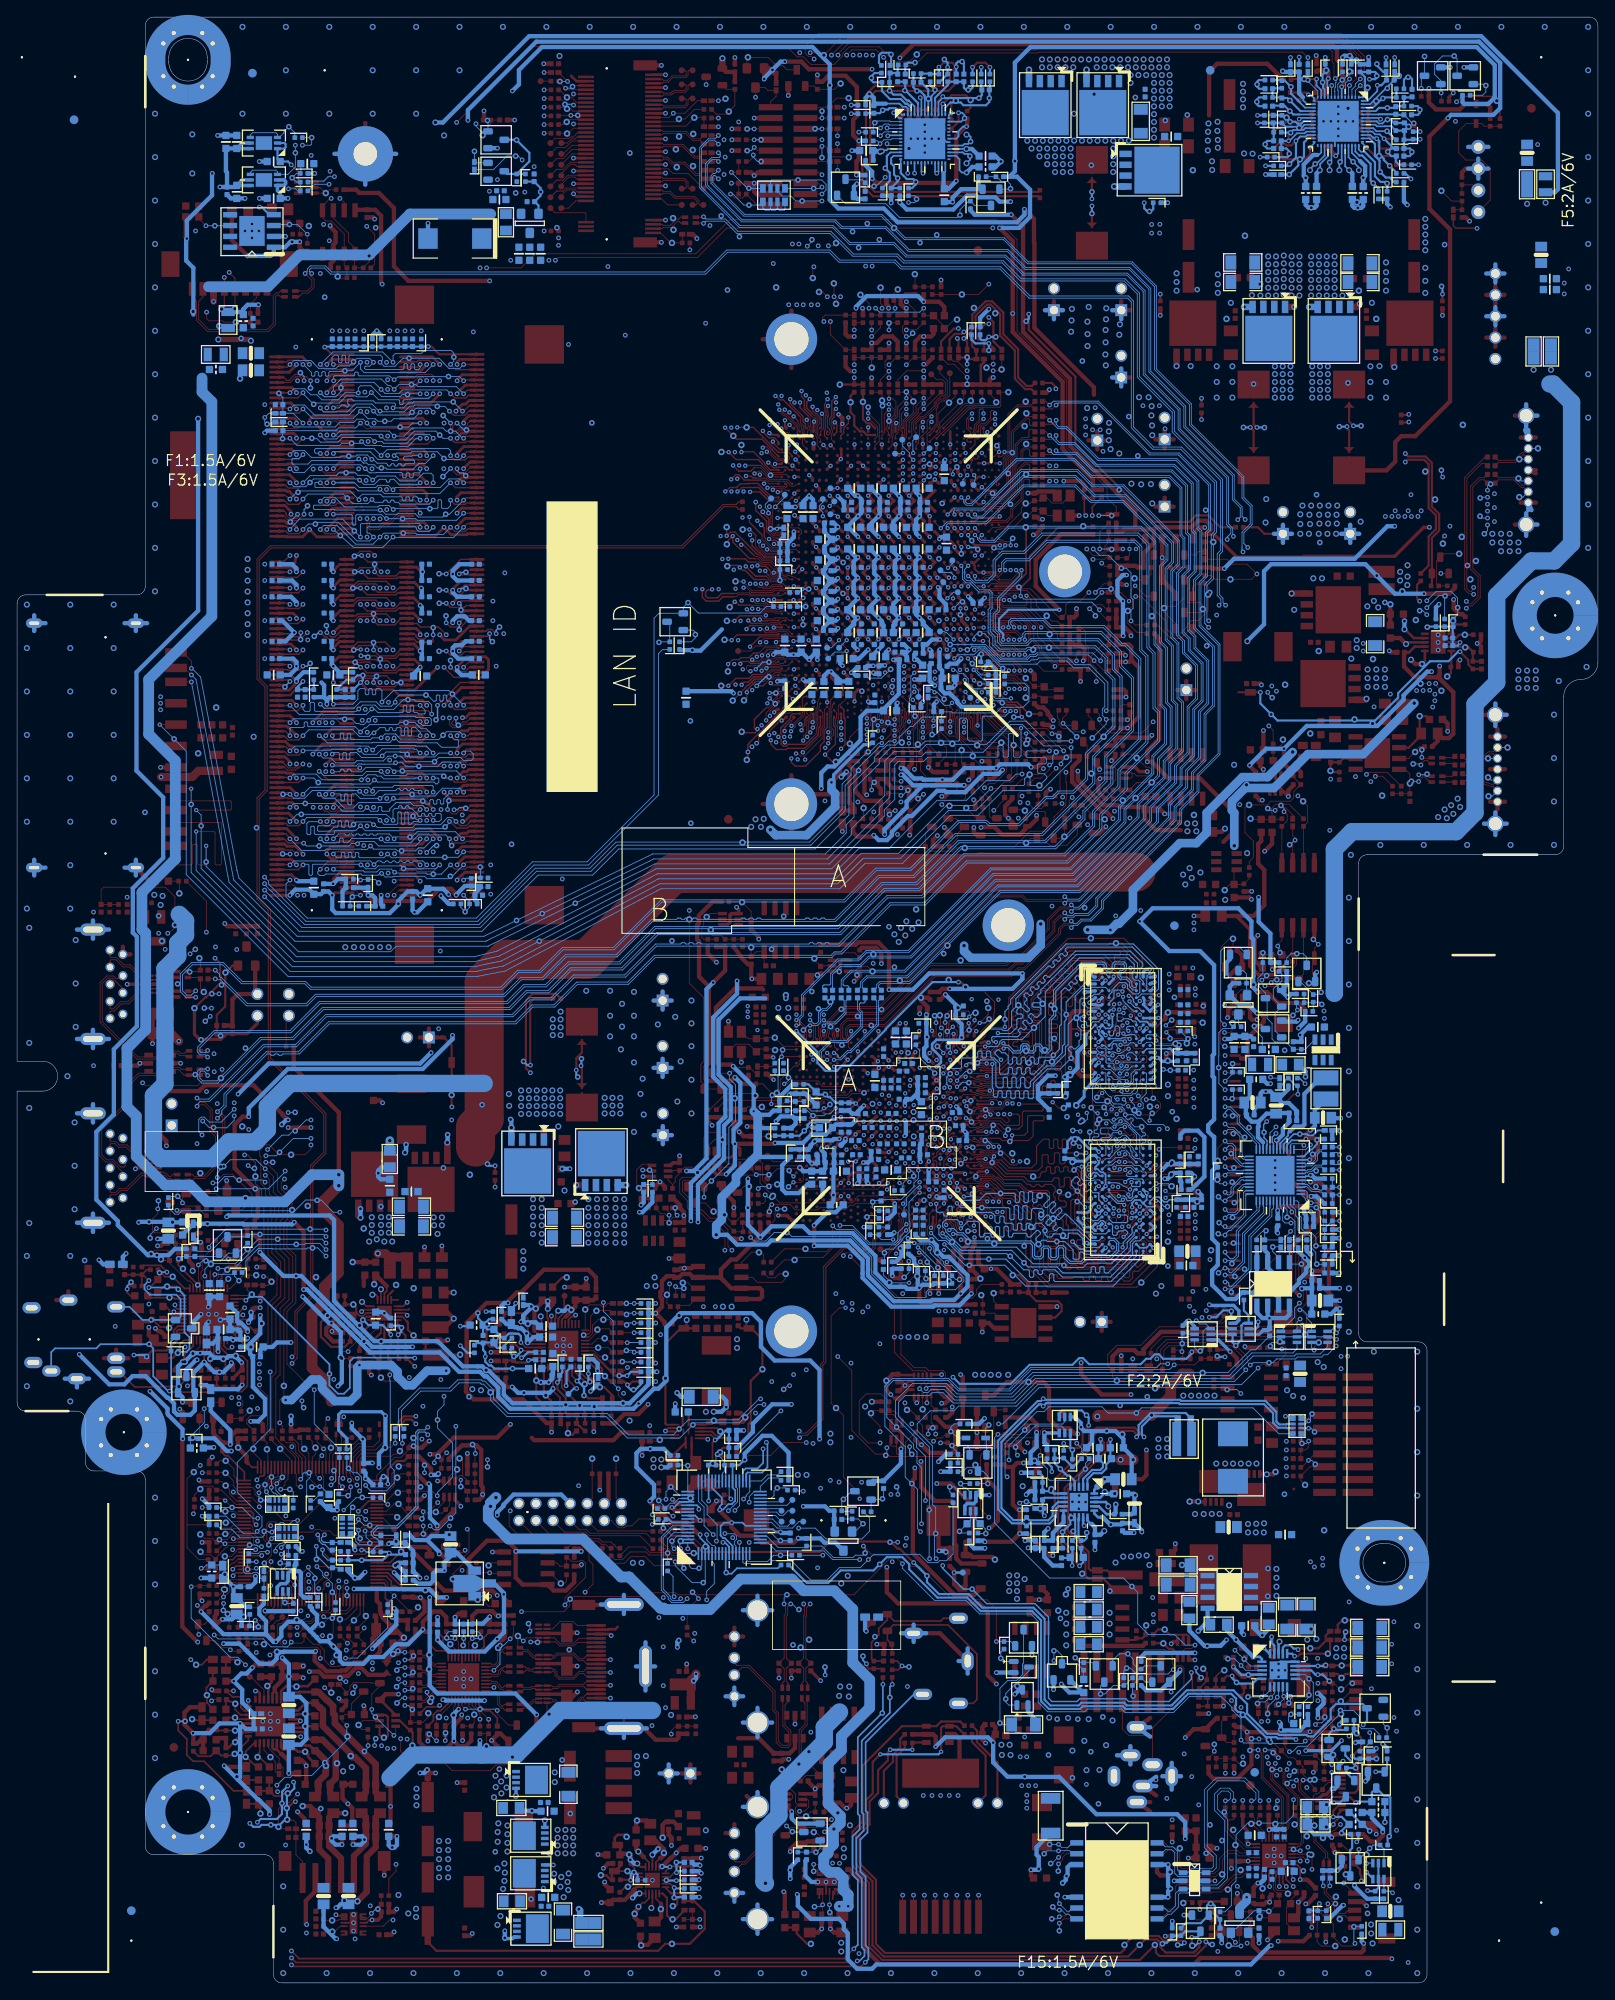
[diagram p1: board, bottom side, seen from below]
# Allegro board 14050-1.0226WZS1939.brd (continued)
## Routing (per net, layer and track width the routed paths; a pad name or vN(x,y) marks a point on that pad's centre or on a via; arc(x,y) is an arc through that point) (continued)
M_MAA_A4: length 73.4
  TOP w0.102: 98.71,166.62 98.27,166.62 97.84,166.19 96.81,166.19 96.33,165.71 96.25,165.71 96.03,165.5 95.74,165.5 95.44,165.8 CPU1.AA32
  TOP w0.165: DIMM2.92 153.32,160.85 153.27,160.8 152.03,160.8 v3(151.54,161.29) ; DIMM1.92 140.34,160.85 140.68,160.51 144.03,160.51 v3(144.81,161.29) ; 98.71,166.62 98.75,166.65 99.3,166.65 101.25,168.6 v4(101.25,169.28) 101.94,168.59 v1(101.94,168.33)
  L3 w0.216: v4(101.25,169.28) 101.38,169.41 101.38,169.42 102.16,170.2 107.18,170.2 109.88,170.2 110.47,169.61 119.71,169.61 122.49,166.83 128.58,166.83 129.63,165.78 137.72,165.78 140.86,162.65 143.46,162.65 v3(144.81,161.29)
  L4 w0.216: v3(144.81,161.29) 145.33,161.8 151.03,161.8 151.16,161.67 v3(151.54,161.29)
M_MAA_A5: length 71.2
  TOP w0.102: 98.84,167.13 98.59,166.88 98.25,166.88 97.75,166.39 96.7,166.39 96.25,165.94 96.04,165.94 CPU1.AA33
  TOP w0.165: v4(100.25,168.26) 100.02,168.26 98.89,167.13 98.84,167.13 ; v3(142.53,161.29) 143.02,161.78 145.09,161.78 145.71,161.15 DIMM2.91 ; v3(134.78,161.42) 134.29,160.93 132.67,160.93 132.45,161.15 DIMM1.91
  L3 w0.216: v4(100.25,168.26) 100.91,168.26 101.42,168.77 103.31,168.77 103.52,168.99 103.52,169.14 103.74,169.35 104.17,169.35 104.39,169.14 104.39,168.99 104.6,168.77 105.03,168.77 105.25,168.99 105.25,169.14 105.47,169.35 105.9,169.35 106.11,169.14 106.11,168.99 106.33,168.77 106.76,168.77 106.98,168.99 106.98,169.14 107.19,169.35 107.62,169.35 107.84,169.14 107.84,168.99 108.06,168.77 108.49,168.77 108.7,168.99 108.7,169.14 108.92,169.35 109.35,169.35 109.57,169.14 109.57,168.99 109.78,168.77 119.16,168.77 119.36,168.77 122.14,165.98 128.23,165.98 129.34,164.88 131.02,164.88 131.6,164.3 136.98,164.3 137.11,164.16 138.11,164.16 140.47,161.8 142.01,161.8 v3(142.53,161.29)
  L4 w0.216: v3(142.53,161.29) 142.49,161.29 141.98,161.8 137.74,161.8 136.84,160.9 135.29,160.9 v3(134.78,161.42)
  BOTTOM w0.165: v3(134.78,161.42) v2(135.59,161.42)
M_MAA_A6: length 72
  TOP w0.102: CPU1.AA31 94.34,165.8 94.82,166.28 96.24,166.28 96.54,166.59 97.67,166.59 98.19,167.12 98.36,167.12
  TOP w0.165: DIMM2.90 153.23,161.45 v3(153.07,161.29) ; 98.36,167.12 100.98,169.74 101.53,169.74 v4(101.96,169.31) 101.96,170.33 v1(101.96,170.33) ; v3(143.29,161.29) 142.8,160.8 140.8,160.8 140.15,161.45 DIMM1.90
  L3 w0.216: v3(143.29,161.29) 142.35,162.23 140.65,162.23 138.29,164.59 137.29,164.59 136.51,165.36 129.45,165.36 128.41,166.41 122.32,166.41 119.53,169.19 110.29,169.19 109.71,169.77 102.43,169.77 v4(101.96,169.31)
  L4 w0.216: v3(143.29,161.29) 144.23,162.23 152.13,162.23 v3(153.07,161.29)
M_MAA_A7: length 73.8
  TOP w0.165: v4(98.98,168.78) 98.98,168.14 98.19,167.35 98.1,167.35 97.57,166.83 96.42,166.83 96.19,166.6 CPU1.Y33 ; DIMM2.86 152.09,162.65 v3(151.54,163.19) ; DIMM1.86 140.44,162.65 140.68,162.41 144.03,162.41 v3(144.81,163.19)
  L3 w0.216: v4(98.98,168.78) 98.76,169 98.76,170.16 99.16,170.56 99.91,170.56 101.23,171.88 122.45,171.88 125.82,168.51 129.28,168.51 130.33,167.47 138.46,167.47 141.34,164.59 143.42,164.59 v3(144.81,163.19)
  L4 w0.216: v3(144.81,163.19) 145.33,163.71 151.03,163.71 v3(151.54,163.19)
  BOTTOM w0.165: v3(144.81,163.19) v2(145.7,163.19)
M_MAA_A8: length 73.4
  TOP w0.165: CPU1.AA30 93.5,165.72 v4(94.07,165.16) ; DIMM1.89 132.14,161.75 132.18,161.7 132.97,161.7 v3(133.26,161.42) ; v3(141,161.29) 141.78,162.07 145.21,162.07 145.53,161.75 DIMM2.89
  L3 w0.216: v3(141,161.29) 140.39,161.29 137.94,163.74 136.94,163.74 136.8,163.88 131.43,163.88 130.85,164.46 129.16,164.46 128.06,165.56 121.97,165.56 119.18,168.35 107.58,168.35 101.6,168.35 101.35,168.1 100.93,167.68 98.85,167.68 98.35,167.18 96.36,167.18 96.14,166.97 96.14,166.13 95.93,165.91 95.49,165.91 95.28,166.13 95.28,166.97 95.06,167.18 93.76,167.18 93.35,166.78 93.35,165.87 v4(94.07,165.16)
  L4 w0.216: v3(141,161.29) 140.19,160.48 134.19,160.48 134.02,160.65 v3(133.26,161.42)
  BOTTOM w0.165: v3(133.26,161.42) 133.05,161.21 v2(133.05,160.63)
M_MAA_A9: length 70.8
  TOP w0.102: CPU1.W32 95.45,167.4 95.75,167.1 96.03,167.1 96.21,167.27 97.39,167.27 98.16,168.04
  TOP w0.165: DIMM2.85 145.57,162.95 145.3,163.21 145.3,163.4 145.02,163.68 143.02,163.68 v3(142.53,163.19) ; DIMM1.85 132.56,162.95 133.05,162.45 134.29,162.45 v3(134.78,162.94) ; v4(98.16,168.65) 98.16,168.04
  L3 w0.216: v4(98.16,168.65) 98.49,168.32 99.17,168.32 99.6,168.75 99.6,169 101.64,171.04 121.96,171.04 125.33,167.67 128.93,167.67 129.98,166.63 138.11,166.63 140.99,163.74 141.98,163.74 v3(142.53,163.19)
  L4 w0.216: v3(134.78,162.94) 135.29,162.43 141.76,162.43 v3(142.53,163.19)
  BOTTOM w0.165: v2(135.59,162.97) 135.57,162.94 v3(134.78,162.94)
M_MAA_A10: length 71.4
  TOP w0.102: 99.27,161.21 99.24,161.19 98.64,161.19 98.6,161.15 97.66,161.15 97.35,160.83 96.19,160.83 96.06,160.7 95.75,160.7 95.45,161 CPU1.AG32
  TOP w0.165: DIMM1.107 132.74,156.35 v3(133.26,155.83) ; v1(101.61,160.96) 101.59,160.96 101.02,161.53 v4(101.02,161.59) 100.9,161.47 100.79,161.47 100.54,161.21 99.27,161.21 ; DIMM2.107 145.64,156.35 145.13,156.86 141.91,156.86 v3(141,155.96)
  L3 w0.216: v3(141,155.96) 138.68,155.96 138.04,155.31 133.04,155.31 132.38,155.98 119.1,155.98 118.89,156.2 118.89,156.49 118.67,156.71 118.24,156.71 118.02,156.49 118.02,156.2 117.81,155.98 117.38,155.98 117.16,156.2 117.16,156.49 116.95,156.71 116.51,156.71 116.3,156.49 116.3,156.2 116.08,155.98 115.65,155.98 115.43,156.2 115.43,156.49 115.22,156.71 114.79,156.71 114.57,156.49 114.57,156.2 114.35,155.98 113.92,155.98 113.71,156.2 113.71,156.49 113.49,156.71 113.06,156.71 112.84,156.49 112.84,156.2 112.63,155.98 112.2,155.98 111.98,156.2 111.98,156.49 111.76,156.71 111.33,156.71 111.12,156.49 111.12,156.2 110.9,155.98 108.9,155.98 103.38,161.5 101.12,161.5 v4(101.02,161.59)
  L4 w0.216: v3(141,155.96) 140.36,155.31 133.77,155.31 v3(133.26,155.83)
M_MAA_A11: length 72
  TOP w0.102: CPU1.Y32 95,166.9 95.64,166.9 95.64,166.89 96.13,166.89 96.31,167.07 97.48,167.07 98,167.59 98.09,167.59 98.57,168.07 98.57,169.04
  TOP w0.165: DIMM2.84 153.12,163.25 v3(153.07,163.19) ; DIMM1.84 140.26,163.25 140.8,162.71 142.8,162.71 v3(143.29,163.19) ; v1(100.08,170.05) v4(99.3,170.05) 99.23,170.05 98.57,169.39 98.57,169.04
  L3 w0.216: v4(99.3,170.05) 99.99,170.05 101.41,171.46 122.27,171.46 125.64,168.09 129.11,168.09 130.15,167.05 138.28,167.05 141.16,164.16 142.32,164.16 v3(143.29,163.19)
  L4 w0.216: v3(153.07,163.19) 152.13,164.13 144.23,164.13 v3(143.29,163.19)
M_MAA_A12: length 72.8
  TOP w0.165: CPU1.W33 96.01,167.51 96.78,167.51 96.99,167.72 v4(97.23,167.72) ; DIMM1.83 132.65,163.55 v3(133.26,162.94) ; DIMM2.83 145.56,163.55 145.14,163.98 141.78,163.98 141.03,163.23 v3(141,163.23)
  L3 w0.216: v3(141,163.23) 140.91,163.23 137.93,166.2 129.8,166.2 128.76,167.25 122.95,167.25 121.59,168.61 121.59,168.91 122.38,169.7 122.38,170.01 122.08,170.31 121.77,170.31 120.98,169.52 120.68,169.52 119.59,170.62 119.12,170.62 118.91,170.4 118.91,170.25 118.69,170.03 118.26,170.03 118.04,170.25 118.04,170.4 117.83,170.62 117.39,170.62 117.18,170.4 117.18,170.25 116.96,170.03 116.53,170.03 116.32,170.25 116.32,170.4 116.1,170.62 115.67,170.62 115.45,170.4 115.45,170.25 115.24,170.03 114.8,170.03 114.59,170.25 114.59,170.4 114.37,170.62 113.94,170.62 113.72,170.4 113.72,170.25 113.51,170.03 113.08,170.03 112.86,170.25 112.86,170.4 112.64,170.62 112.21,170.62 112,170.4 112,170.25 111.78,170.03 111.35,170.03 111.13,170.25 111.13,170.4 110.92,170.62 107.7,170.62 107.7,170.62 107.35,170.62 107,170.62 107,170.62 101.82,170.62 99.92,168.72 99.92,168.62 99.3,168 98.21,168 97.89,167.69 97.27,167.69 v4(97.23,167.72)
  L4 w0.216: v3(133.26,162.94) 134.02,163.71 140.49,163.71 140.97,163.23 v3(141,163.23)
  BOTTOM w0.165: v3(133.26,162.94) 133.05,163.14 v2(132.47,163.14)
M_MAA_A13: length 70.4
  TOP w0.102: 96.71,158.21 96.66,158.17 96.27,158.17 96.13,158.31 95.67,158.31 95.67,158.3 95.38,158.3 95.37,158.31 94.81,158.31 CPU1.AL31
  TOP w0.165: DIMM1.119 133.86,152.75 v3(135.03,153.92) ; DIMM2.119 145.31,152.75 145.14,152.93 141.78,152.93 v3(141,152.15) ; v4(97.25,158.47) 96.99,158.21 96.71,158.21
  L3 w0.216: v4(97.25,158.47) 98.23,157.48 100.02,157.48 100.13,157.59 101.67,157.59 102.12,157.14 102.97,157.14 106.56,153.55 106.56,153.55 107.52,152.6 112.04,152.6 112.25,152.38 112.25,151.51 112.47,151.29 112.9,151.29 113.12,151.51 113.12,152.38 113.33,152.6 113.75,152.6 115.06,151.29 131.26,151.29 131.27,151.3 139.15,151.3 140,152.15 v3(141,152.15)
  L4 w0.216: v3(141,152.15) 139.74,153.41 135.58,153.41 135.07,153.92 v3(135.03,153.92)
  BOTTOM w0.165: v3(141,152.15) v2(140.09,152.15)
M_MAA_A14: length 75.2
  TOP w0.102: 97.45,169.04 97.45,168.8 96.59,167.94 95.72,167.94 95.67,167.9 95.35,167.9 95.34,167.91 94.86,167.91 94.68,167.73 93.83,167.73 CPU1.W30
  TOP w0.165: v3(97.91,170.6) 97.55,170.25 97.55,169.14 97.45,169.04 ; DIMM1.80 140.42,164.45 140.55,164.32 143.9,164.32 v3(144.69,165.1) ; DIMM2.80 152.19,164.45 v3(151.54,165.1)
  L3 w0.216: v3(97.91,170.6) 97.91,171.38 99.68,173.15 123.07,173.15 126.44,169.78 129.81,169.78 130.85,168.73 138.98,168.73 141.26,166.46 143.33,166.46 v3(144.69,165.1)
  L4 w0.216: v3(144.69,165.1) 145.2,165.61 151.03,165.61 v3(151.54,165.1)
  BOTTOM w0.165: v3(144.69,165.1) v2(145.5,165.1)
M_MAA_A15: length 71.3
  TOP w0.165: v3(143.16,165.1) 142.67,164.61 140.67,164.61 140.23,165.05 DIMM1.78 ; CPU1.V32 95.07,168.57 96.01,168.57 96.23,168.79 96.86,168.79 v4(97.01,168.93) ; v3(153.07,165.1) 153.12,165.05 DIMM2.78
  L3 w0.216: v4(97.01,168.93) 98.83,170.76 98.83,171.72 99.84,172.73 122.89,172.73 126.26,169.36 129.63,169.36 130.68,168.31 138.81,168.31 141.08,166.04 142.23,166.04 v3(143.16,165.1)
  L4 w0.216: v3(153.07,165.1) 152.13,166.04 144.1,166.04 v3(143.16,165.1)
  BOTTOM w0.165: v3(143.16,165.1) v2(143.16,165.99)
M_ODT_A0: length 62.5
  TOP w0.102: CPU1.AL30 93.8,157.5 94.43,157.5 94.8,157.87 94.8,157.93 94.97,158.1 95.26,158.1 95.27,158.09 95.77,158.09 95.78,158.1 96.03,158.1 96.17,157.96 96.7,157.96 96.71,157.97 97.37,157.97 97.39,157.99
  TOP w0.165: DIMM1.116 140.3,153.65 140.68,153.27 144.03,153.27 144.69,153.93 v3(144.8,153.93) ; v4(98.04,158.4) 97.8,158.4 97.39,157.99
  L3 w0.216: v4(98.04,158.4) 98.54,157.91 99.37,157.91 99.85,157.91 99.95,158.01 102.7,158.01 106.98,153.73 107.69,153.02 113.93,153.02 115.24,151.71 131.08,151.71 131.09,151.72 138.98,151.72 139.95,152.69 143.46,152.69 144.69,153.93 v3(144.8,153.93)
  BOTTOM w0.165: v3(144.8,153.93) 145.36,154.48 145.42,154.48 v2(145.45,154.51)
M_ODT_A1: length 58.7
  TOP w0.102: CPU1.AM32 95,157.3 95.64,157.3 95.65,157.29 97.61,157.29 v4(98.05,156.84)
  TOP w0.165: DIMM1.120 140.19,152.45 140.51,152.13 140.51,151.95 140.8,151.66 142.8,151.66 v3(143.29,152.15)
  L3 w0.216: v4(98.05,156.84) 98.32,157.12 99.54,157.12 99.6,157.06 99.81,157.06 100.58,156.3 102.62,156.3 105.72,153.2 108.24,150.69 108.98,149.94 110.37,149.94 110.37,149.95 117.81,149.95 117.81,149.94 118.05,149.94 118.05,149.95 118.25,149.95 118.75,150.45 119.43,150.45 119.94,149.95 120.39,149.95 120.89,150.45 131.61,150.45 131.62,150.46 139.5,150.46 140.26,151.21 142.33,151.21 143.26,152.15 v3(143.29,152.15)
  BOTTOM w0.165: v3(143.29,152.15) 143.29,152.53 v2(142.93,152.88)
M_ODT_B0: length 64.6
  TOP w0.102: 97.89,159.07 96.91,159.07 96.81,159.18 96.12,159.18 96.03,159.1 95.75,159.1 95.44,159.4 CPU1.AJ32
  TOP w0.165: DIMM2.116 153.36,153.65 153.27,153.56 152.03,153.56 v3(151.54,154.05) ; 97.89,159.07 97.9,159.07 99.1,159.07 v4(99.43,159.4)
  L3 w0.216: v3(151.54,154.05) 151.03,154.57 139.34,154.57 138.18,153.41 127.62,153.41 126.32,154.71 108.39,154.71 103.26,159.83 103.04,159.83 103.02,159.85 99.88,159.85 v4(99.43,159.4)
  BOTTOM w0.165: v2(150.71,154.38) 150.73,154.38 151.06,154.05 v3(151.54,154.05)
M_ODT_B1: length 65.8
  TOP w0.165: CPU1.AM33 96.06,157 v4(96.19,156.88) ; DIMM2.120 153.37,152.45 v3(153.07,152.27)
  L3 w0.216: v4(96.19,156.88) 96.19,156.49 96.77,155.91 98.79,155.91 99.68,155.02 102.03,155.02 109.06,147.98 131.4,147.98 131.96,148.54 135.42,148.54 135.84,148.96 138.04,148.96 138.66,149.58 139.77,149.58 140.58,150.39 142.65,150.39 142.66,150.4 143.24,150.98 145.02,150.98 145.42,151.38 152.18,151.38 v3(153.07,152.27)
  BOTTOM w0.165: v3(153.07,152.27) 153.6,151.74 153.6,151.69 v2(153.65,151.64)
M_RAS_A_N: length 69.4
  TOP w0.102: 97.83,160.27 97.7,160.41 96.42,160.41 96.28,160.27 95.57,160.27 CPU1.AH33
  TOP w0.165: v3(151.54,155.96) 152.05,155.45 DIMM2.110 ; v4(99.6,160.71) 99.17,160.27 97.83,160.27 ; DIMM1.110 140.26,155.45 140.73,154.98 142.72,154.98 143.02,155.27 v3(144.76,155.27)
  L3 w0.216: v4(99.6,160.71) 99.64,160.66 99.65,160.66 103.03,160.66 108.56,155.13 126.67,155.13 127.23,154.57 132.27,154.57 132.37,154.47 138.39,154.47 138.93,155.01 143.87,155.01 144.13,155.27 v3(144.76,155.27)
  L4 w0.216: v3(144.76,155.27) 150.86,155.27 v3(151.54,155.96)
  BOTTOM w0.165: v3(144.76,155.27) 144.13,155.27 143.97,155.12 v2(143.95,155.12)
M_SBS_A0: length 70.6
  TOP w0.102: 97.61,160.74 97.49,160.62 96.29,160.62 96.16,160.49 95.64,160.49 95.64,160.5 95,160.5 CPU1.AH32
  TOP w0.165: DIMM2.109 145.71,155.75 144.99,156.47 143.04,156.47 v3(142.53,155.96) ; v3(134.78,155.83) 134.29,155.34 133.05,155.34 132.64,155.75 DIMM1.109 ; v4(98.27,160.74) 97.61,160.74
  L3 w0.216: v4(98.27,160.74) 98.77,161.25 100,161.25 100.17,161.08 103.21,161.08 108.74,155.55 126.97,155.55 127.19,155.33 127.19,155.2 127.4,154.99 127.83,154.99 128.05,155.2 128.05,155.33 128.27,155.55 128.7,155.55 128.91,155.33 128.91,155.2 129.13,154.99 129.56,154.99 129.78,155.2 129.78,155.33 129.99,155.55 130.43,155.55 130.64,155.33 130.64,155.2 130.86,154.99 131.29,154.99 131.5,155.2 131.5,155.33 131.72,155.55 132.21,155.55 132.87,154.89 138.22,154.89 138.76,155.44 142.01,155.44 v3(142.53,155.96)
  L4 w0.216: v3(142.53,155.96) 142.01,156.47 135.42,156.47 v3(134.78,155.83)
  BOTTOM w0.165: v2(135.62,155.8) 135.59,155.83 v3(134.78,155.83)
M_SBS_A1: length 72.2
  TOP w0.102: CPU1.AG33 96.06,161 96.09,161.04 97.26,161.04 97.6,161.38 98.54,161.38 98.59,161.42
  TOP w0.165: v3(153.07,155.96) 153.16,156.05 DIMM2.108 ; v4(98.97,161.8) 98.59,161.42 ; DIMM1.108 140.07,156.05 140.85,155.27 142.6,155.27 v3(143.29,155.96)
  L3 w0.216: v3(143.29,155.96) 142.78,156.46 142.75,156.46 142.74,156.47 126.84,156.47 126.62,156.69 126.62,157 126.41,157.22 125.98,157.22 125.76,157 125.76,156.69 125.54,156.47 125.11,156.47 124.9,156.69 124.9,157 124.68,157.22 124.25,157.22 124.03,157 124.03,156.69 123.82,156.47 123.38,156.47 123.17,156.69 123.17,157 122.95,157.22 122.52,157.22 122.3,157 122.3,156.69 122.09,156.47 121.66,156.47 121.44,156.69 121.44,157 121.23,157.22 120.79,157.22 120.58,157 120.58,156.69 120.36,156.47 119.94,156.47 119.19,157.22 108.29,157.22 108.11,157.4 108.08,157.4 103.56,161.92 101.55,161.92 101.27,162.21 100.42,162.21 100.41,162.21 100.01,162.21 100.01,162.21 99.38,162.21 v4(98.97,161.8)
  L4 w0.216: v3(153.07,155.96) 151.87,154.76 144.49,154.76 v3(143.29,155.96)
  BOTTOM w0.165: v2(143.29,156.82) v3(143.29,155.96)
M_SBS_A2: length 71
  TOP w0.102: 97.82,169.42 97.82,168.88 96.68,167.74 95.81,167.74 95.77,167.69 95.25,167.69 95.24,167.7 94.96,167.7 94.66,167.4 CPU1.W31
  TOP w0.165: v3(133.26,164.85) 133.16,164.75 DIMM1.79 ; v3(142.4,165.1) 142.89,165.59 144.89,165.59 145.73,164.75 DIMM2.79 ; v4(99.3,171.52) 99.3,170.9 97.82,169.42
  L3 w0.216: v3(142.4,165.1) 141.89,165.61 140.91,165.61 138.63,167.89 130.5,167.89 129.46,168.94 125.99,168.94 122.62,172.3 100.08,172.3 v4(99.3,171.52)
  L4 w0.216: v3(133.26,164.85) 133.77,164.33 141.63,164.33 v3(142.4,165.1)
  BOTTOM w0.165: v2(132.47,165.05) 132.49,165.02 133.08,165.02 v3(133.26,164.85)
M_SCKE_A0: length 71.8
  TOP w0.102: 97.02,170.18 97.02,169.87 96.47,169.32 96.42,169.32 96.42,169.32 95.76,169.32 95.45,169 CPU1.U32
  TOP w0.165: v3(134.78,164.85) 133.08,166.55 DIMM1.73 ; v3(97.73,172.12) 97.73,171.99 97.02,171.28 97.02,170.18 ; DIMM2.73 145.83,166.55 144.89,167.49 143.65,167.49 v3(143.16,167)
  L3 w0.216: v3(143.16,167) 141.31,167 139.16,169.16 131.03,169.16 129.98,170.2 126.61,170.2 123.24,173.57 99.58,173.57 98.13,172.12 v3(97.73,172.12)
  L4 w0.216: v3(143.16,167) 141.77,165.61 135.55,165.61 v3(134.78,164.85)
  BOTTOM w0.165: v3(134.78,164.85) 135.59,164.85 v2(135.62,164.87)
M_SCKE_A1: length 72.1
  TOP w0.102: CPU1.U33 96.08,169 96.15,169.06 96.5,169.06 97.29,169.85 97.29,170.18
  TOP w0.165: DIMM2.74 153.82,166.25 v3(153.07,167) ; v3(98.56,173.26) 98.56,172.29 97.29,171.02 97.29,170.18 ; v3(144.69,167) 143.93,166.25 DIMM1.74
  L3 w0.216: v3(144.69,167) 144.17,167.52 141.39,167.52 139.33,169.58 131.2,169.58 130.1,170.68 126.84,170.68 123.53,173.99 99.29,173.99 v3(98.56,173.26)
  L4 w0.216: v3(153.07,167) 152.55,166.49 145.2,166.49 v3(144.69,167)
  BOTTOM w0.165: v3(144.69,167) 145.45,167 v2(145.52,166.93)
M_SCS_A_N0: length 58.5
  TOP w0.102: CPU1.AJ33 96.23,159.4 96.25,159.38 97.16,159.38 97.19,159.35
  TOP w0.165: v4(98.08,159.51) 97.92,159.35 97.19,159.35 ; v3(142.53,154.05) 142.04,153.56 140.8,153.56 140.11,154.25 DIMM1.114
  L3 w0.216: v4(98.08,159.51) 98.08,159.49 98.68,158.88 99.85,158.88 99.86,158.87 102.8,158.87 102.82,158.86 103.05,158.86 108.04,153.86 117.04,153.86 117.36,153.54 117.36,152.88 117.67,152.57 118.21,152.57 118.42,152.78 118.42,153.45 118.64,153.67 119.07,153.67 119.29,153.45 119.29,152.78 119.5,152.57 119.93,152.57 120.15,152.78 120.15,153.45 120.37,153.67 120.8,153.67 121.01,153.45 121.01,152.78 121.23,152.57 138.53,152.57 139.5,153.54 140.2,153.54 142.01,153.54 v3(142.53,154.05)
  BOTTOM w0.165: v3(142.53,154.05) 142.53,154.86 v2(142.5,154.89)
M_SCS_A_N1: length 64.8
  TOP w0.102: CPU1.AL32 95.45,157.8 95.76,157.49 98.06,157.49 98.1,157.46
  TOP w0.165: v4(99.22,156.34) 98.1,157.46 ; DIMM1.121 133.13,152.15 v3(135.8,149.48)
  L3 w0.216: v3(135.8,149.48) 135.76,149.48 135.25,148.96 131.15,148.96 130.93,149.18 130.93,149.3 130.72,149.52 130.29,149.52 130.07,149.3 130.07,148.64 129.89,148.46 129.39,148.46 129.21,148.64 129.21,149.3 128.99,149.52 128.56,149.52 128.34,149.3 128.34,148.64 128.17,148.46 127.66,148.46 127.48,148.64 127.48,149.3 127.26,149.52 126.83,149.52 126.62,149.3 126.62,148.54 126.48,148.4 125.89,148.4 125.75,148.54 125.75,149.3 125.54,149.52 125.11,149.52 124.89,149.3 124.89,148.54 124.75,148.4 124.16,148.4 124.03,148.54 124.03,149.3 123.81,149.52 123.38,149.52 123.16,149.3 123.16,148.58 122.98,148.4 122.48,148.4 122.3,148.58 122.3,149.3 122.08,149.52 121.47,149.52 120.41,148.46 119.98,148.46 119.76,148.67 119.76,148.75 119.55,148.96 119.11,148.96 118.9,148.75 118.9,148.67 118.68,148.46 118.25,148.46 118.03,148.67 118.03,148.75 117.82,148.96 117.39,148.96 117.17,148.75 117.17,148.67 116.96,148.46 116.52,148.46 116.31,148.67 116.31,148.75 116.09,148.96 115.66,148.96 115.44,148.75 115.44,148.67 115.23,148.46 114.8,148.46 114.58,148.67 114.58,148.75 114.36,148.96 113.93,148.96 113.72,148.75 113.72,148.67 113.5,148.46 113.07,148.46 112.85,148.67 112.85,148.75 112.64,148.96 112.21,148.96 111.99,148.75 111.99,148.67 111.77,148.46 111.34,148.46 111.13,148.67 111.13,148.75 110.91,148.96 110.48,148.96 110.26,148.75 110.26,148.67 110.05,148.46 109.61,148.46 109.4,148.67 109.4,148.75 109.18,148.96 108.68,148.96 102.18,155.46 100.1,155.46 v4(99.22,156.34)
  BOTTOM w0.165: v2(135.97,147.78) 135.8,147.96 v3(135.8,149.48)
M_SCS_B_N0: length 69.5
  TOP w0.165: v4(93.02,159.64) 93.26,159.4 CPU1.AJ30 ; v3(153.07,154.05) 153.27,154.25 DIMM2.114
  L3 w0.216: v4(93.02,159.64) 94.08,159.64 96.68,157.04 96.68,156.88 97.17,156.38 98.61,156.38 99.03,156.8 99.41,156.8 100.33,155.88 102.44,155.88 105.3,153.03 108.8,149.52 108.8,149.52 117.63,149.52 119.38,149.52 119.38,149.52 120.63,149.52 121.13,150.03 131.78,150.03 131.79,150.04 139.68,150.04 140.43,150.79 142.5,150.79 143.08,151.36 144.79,151.36 146.67,153.24 152.26,153.24 v3(153.07,154.05)
  BOTTOM w0.165: v4(93.02,159.64) v2(93.02,158.9)
M_SCS_B_N1: length 63.3
  TOP w0.165: v3(142.53,152.15) 143.02,152.63 145.02,152.63 145.5,152.15 DIMM2.121 ; CPU1.AL33 95.97,157.73 100.75,157.73 v4(101.38,157.1) 102.17,157.1 v1(102.22,157.15)
  L3 w0.216: v4(101.38,157.1) 101.57,157.1 101.94,156.72 102.79,156.72 106.14,153.38 107.37,152.14 108.17,152.14 108.38,151.93 108.38,151.23 108.56,151.05 109.07,151.05 109.25,151.23 109.25,151.93 109.46,152.14 109.9,152.14 110.11,151.93 110.11,150.57 110.29,150.39 110.8,150.39 110.97,150.57 110.97,151.93 111.19,152.14 111.58,152.14 111.83,151.89 111.83,150.71 112.18,150.37 113.28,150.37 113.5,150.58 113.5,151.28 113.67,151.46 114.18,151.46 114.36,151.28 114.36,150.58 114.58,150.37 116.35,150.37 116.56,150.58 116.56,150.66 116.78,150.87 117.21,150.87 117.43,150.66 117.43,150.58 117.64,150.37 118.07,150.37 118.29,150.58 118.29,150.66 118.5,150.87 131.43,150.87 131.44,150.88 139.33,150.88 140.08,151.63 140.68,151.63 142.01,151.63 v3(142.53,152.15)
M_WE_A_N: length 71.5
  TOP w0.102: 97.87,159.92 97.54,159.59 96.35,159.59 96.24,159.7 95.76,159.7 95.75,159.69 95.27,159.69 95.26,159.7 94.95,159.7 94.65,159.4 CPU1.AJ31
  TOP w0.165: DIMM1.113 132.12,154.55 v3(132.75,153.92) ; v1(101.94,159.36) v4(101.05,159.36) 100.46,159.95 97.9,159.95 97.87,159.92 ; v3(141,154.05) 141.64,154.69 142.85,154.69 142.99,154.83 144.51,154.83 144.56,154.78 145.34,154.78 145.57,154.55 DIMM2.113
  L3 w0.216: v4(101.05,159.36) 103.14,159.36 108.21,154.28 121.21,154.28 122.51,152.99 122.93,152.99 123.15,153.2 123.15,153.94 123.36,154.15 123.79,154.15 124.01,153.94 124.01,153.2 124.23,152.99 124.66,152.99 124.87,153.2 124.87,153.94 125.09,154.15 125.52,154.15 125.74,153.94 125.74,153.2 125.95,152.99 138.36,152.99 139.42,154.05 v3(141,154.05)
  L4 w0.216: v3(141,154.05) 140.19,154.86 133.68,154.86 v3(132.75,153.92)
MAA0: length 56.9
  TOP w0.102: v1(61.04,102.66) 60.29,102.66 v4(60.2,102.57) ; v4(56.58,95.37) 56.58,95.09 56.69,94.99 56.98,94.99 MEM2.N3 ; MEM1.N3 54.2,108.08 54.67,108.55 55.42,108.55 v4(55.61,108.36) ; v4(77.99,100.03) 78.14,100.03 78.26,100.15 78.26,100.47 78.14,100.6 GPU1.K17
  L3 w0.127: v4(77.99,100.03) 77.99,100.15 77.65,100.49 76.79,100.49 76.66,100.61 76.21,100.61 76.08,100.49 75.47,100.49 75.24,100.72 74.83,100.72 74.71,100.84 74.38,100.84 74.25,100.72 73.82,100.72 73.5,101.03 73.5,101.4 73.37,101.53 73.12,101.53 72.99,101.4 72.99,101.03 72.85,100.89 71.6,100.89 71.38,101.11 68.73,101.11 68.31,101.53 66.69,101.53 66.56,101.4 66.56,100.99 66.43,100.87 66.18,100.87 66.05,100.99 66.05,101.6 65.92,101.73 65.67,101.73 65.54,101.6 65.54,100.99 65.42,100.87 65.16,100.87 65.04,100.99 65.04,101.58 64.91,101.71 64.65,101.71 64.53,101.58 64.53,100.99 64.4,100.87 64.15,100.87 64.02,100.99 64.02,101.55 63.89,101.68 63.64,101.68 63.51,101.55 63.51,100.99 63.38,100.87 63.13,100.87 63,100.99 63,101.38 62.88,101.51 61.98,101.51 61.57,101.92 61.57,102.52 61.45,102.65 61.09,102.65 60.97,102.52 60.97,102.14 60.84,102.01 60.2,102.01 60.08,102.14 60.08,102.44 v4(60.2,102.57)
  L4 w0.127: v4(56.58,95.37) 56.46,95.49 56.46,96.2 57.59,97.33 57.59,98.14 59.83,100.38 60.14,100.38 60.42,100.66 60.42,101.28 60.23,101.47 60.23,102.01 60.36,102.14 60.64,102.14 60.77,102.27 60.77,102.44 60.64,102.57 v4(60.2,102.57) 60.23,102.59 60.23,105.45 60.71,105.94 60.71,106.95 60.45,107.21 57.56,107.21 56.67,108.09 56.63,108.09 56.36,108.36 v4(55.61,108.36)
  BOTTOM w0.102: v4(55.61,108.36) 55.76,108.51 56.1,108.51 56.76,107.85 56.98,107.85 MEM3.N3 ; MEM4.N3 54.13,95.22 54.53,95.62 56.33,95.62 v4(56.58,95.37)
MAA1: length 51
  TOP w0.102: MEM1.P7 56.32,107.28 55.94,106.9 v4(55.94,106.4) ; GPU1.J20 76.67,103 76.2,103.47 76.19,103.47 76.15,103.51 v4(75.75,103.51) ; v4(55.33,96.95) 55.12,96.95 54.2,96.02 MEM2.P7
  L3 w0.127: v3(52.86,103.34) 52.62,103.11 52.62,102.5 52.85,102.28 54.07,102.28 55.02,103.23 55.02,103.58 55.23,103.79 55.29,103.79 55.3,103.79 55.64,103.79 55.65,103.79 57.58,103.79 57.71,103.66 59.28,103.66 59.66,104.03 64.62,104.03 64.76,104.17 70.68,104.17 70.86,103.98 71.34,103.98 71.35,103.99 74.51,103.99 74.55,103.95 75.3,103.95 v4(75.75,103.51)
  L4 w0.127: v4(55.33,96.95) 54.14,98.14 54.14,101.6 52.86,102.88 v3(52.86,103.34) 52.44,103.76 52.44,105.33 53.05,105.94 53.05,106.32 53.66,106.93 54.07,106.93 54.17,107.03 54.17,107.31 54.27,107.41 54.62,107.41 54.72,107.31 54.72,107.07 54.97,106.83 55.22,106.83 55.64,106.4 v4(55.94,106.4)
  BOTTOM w0.102: v2(52.04,103.5) 52.19,103.34 v3(52.86,103.34) ; v4(55.94,106.4) 55.8,106.4 55.38,106.82 55.08,106.82 55.08,106.82 54.97,106.82 54.51,107.28 MEM3.P7 ; v4(55.33,96.95) 55.7,96.58 56.42,96.58 56.98,96.02 MEM4.P7
MAA2: length 56
  TOP w0.102: GPU1.H23 76.48,104.92 v4(76.48,104.73) ; MEM1.P3 54.25,107.05 54.47,107.05 54.58,107.15 54.58,107.33 54.67,107.43 54.96,107.43 v4(55.14,107.24) ; MEM2.P3 57.05,96.18 56.63,96.18 56.24,96.58 55.91,96.58 55.82,96.67 55.82,96.82 v4(56.04,97.03)
  L3 w0.127: v4(58.01,104.12) 58.24,103.89 58.98,103.89 59.39,104.3 59.39,104.91 59.52,105.03 59.82,105.03 59.95,104.91 59.95,104.45 60.08,104.32 60.33,104.32 60.46,104.45 60.46,104.92 60.58,105.04 60.84,105.04 60.97,104.92 60.97,104.46 61.09,104.33 61.43,104.33 61.52,104.42 61.52,104.92 61.65,105.04 61.87,105.04 62,104.92 62,104.69 62.24,104.45 64.57,104.45 64.62,104.5 64.98,104.5 65.11,104.63 65.11,105.09 65.24,105.22 65.49,105.22 65.62,105.09 65.62,104.63 65.74,104.5 66,104.5 66.12,104.63 66.12,105.09 66.25,105.22 66.51,105.22 66.63,105.09 66.63,104.63 66.76,104.5 67.01,104.5 67.14,104.63 67.14,105.09 67.27,105.22 67.52,105.22 67.65,105.09 67.65,104.63 67.78,104.5 68.03,104.5 68.16,104.63 68.16,105.09 68.28,105.22 68.54,105.22 68.66,105.09 68.66,104.63 68.79,104.5 70.51,104.5 70.85,104.84 71.56,104.84 71.68,104.71 71.68,104.45 71.81,104.32 72.34,104.32 72.47,104.45 72.47,104.71 72.6,104.84 73.26,104.84 73.39,104.71 73.39,104.36 73.51,104.23 74.47,104.23 74.48,104.22 74.61,104.22 74.65,104.18 75.62,104.18 75.81,103.99 76.3,103.99 76.61,104.31 76.61,104.6 v4(76.48,104.73)
  L4 w0.127: v4(56.04,97.03) 56.82,97.82 56.82,98.43 58.99,100.6 58.99,102.9 58.01,103.88 v4(58.01,104.12) 57.68,104.12 57.42,104.37 57.42,104.9 57.55,105.02 57.87,105.02 58,105.15 58,105.47 57.87,105.6 56.36,105.6 56.18,105.78 56.18,106.03 56.31,106.16 57.08,106.16 57.21,106.29 57.21,106.52 56.9,106.82 55.56,106.82 v4(55.14,107.24)
  BOTTOM w0.102: v4(56.04,97.03) 55.72,97.35 55.16,97.35 54.81,97 54.81,96.82 MEM4.P3 ; v4(58.01,104.12) 58.28,103.85 58.41,103.85 v2(58.64,103.62) ; v4(55.14,107.24) 55.26,107.24 55.68,106.83 56.67,106.83 57.12,107.28 MEM3.P3
MAA3: length 61.1
  TOP w0.102: GPU1.G23 75.05,104.85 v4(75,104.85) ; v4(55.77,107.34) 55.46,107.65 52.91,107.65 52.79,107.78 52.79,108.42 52.91,108.55 53.5,108.55 53.63,108.42 53.63,108.21 53.5,108.08 MEM1.N2 ; v4(55.35,96.05) 55.86,95.68 56.19,95.68 56.48,95.78 56.8,95.78 MEM2.N2
  L3 w0.127: v4(58.65,104.89) 58.52,104.76 58.05,104.76 57.92,104.89 57.92,105.06 57.79,105.19 56.98,105.19 56.6,105.57 56.6,106.23 56.73,106.35 57.89,106.35 58.01,106.23 58.01,105.69 58.14,105.57 59.64,105.57 59.76,105.69 59.76,105.82 59.89,105.95 60.15,105.95 60.27,105.82 60.27,105.69 60.4,105.57 60.65,105.57 60.78,105.69 60.78,105.82 60.91,105.95 61.16,105.95 61.29,105.82 61.29,105.69 61.42,105.57 62.4,105.57 62.7,105.27 64.13,105.27 64.5,105.63 64.5,105.83 64.62,105.95 67.55,105.95 67.95,106.35 68.39,106.35 68.74,106 69.19,106 69.81,105.39 71.91,105.39 71.96,105.34 74.51,105.34 v4(75,104.85)
  L4 w0.127: v4(55.35,96.05) 55.84,96.54 56.13,96.54 57.05,97.45 57.05,98.24 59.22,100.41 59.22,103 58.65,103.57 v4(58.65,104.89) 58.34,104.89 58.23,105 58.23,105.5 58.34,105.61 59.52,105.61 59.64,105.74 59.64,106.45 59.42,106.67 57.38,106.67 56.74,107.31 55.8,107.31 v4(55.77,107.34)
  BOTTOM w0.102: v4(75,104.85) 74.89,104.85 74.41,105.33 v2(73.61,105.33) ; MEM4.N2 53.64,95.64 54.2,95.64 54.6,96.05 v4(55.35,96.05) ; MEM3.N2 58.23,108.08 58.24,108.08 58.36,108.08 58.48,108.21 58.48,108.22 58.63,108.36 58.63,108.58 58.53,108.68 58.28,108.68 58.15,108.55 57.84,108.55 57.56,108.26 57.56,107.92 57.59,107.89 57.59,107.74 57.46,107.61 56.76,107.61 56.63,107.49 56.63,107.13 56.53,107.03 55.9,107.03 55.77,107.16 v4(55.77,107.34)
MAA4: length 55.8
  TOP w0.102: v4(55.49,97.87) 55.49,97.76 54.17,96.45 53.9,96.45 53.48,96.02 MEM2.P8 ; MEM1.P8 58.16,107.14 58.16,106.95 58.06,106.85 57.04,106.85 56.83,107.06 56.64,107.06 56.44,106.86 56.44,106.72 56.73,106.42 56.73,106.3 56.38,105.94 56.08,105.94 55.96,105.82 55.96,105.68 55.96,105.68 55.96,105.41 v4(56.01,105.36) ; v4(75,105.55) 75.01,105.56 75.01,105.61 GPU1.G24
  L3 w0.127: v4(75,105.55) 74.88,105.67 74.24,105.67 74.17,105.6 73.82,105.6 73.76,105.67 69.93,105.67 69.19,106.41 68.91,106.41 68.05,107.26 67.64,107.26 67.51,107.14 67.51,106.74 67.51,106.74 67.51,106.49 67.39,106.36 64.2,106.36 64.09,106.25 64.09,105.8 63.96,105.67 62.74,105.67 62.62,105.8 62.62,105.96 62.49,106.08 62.4,106.18 59.92,106.18 59.8,106.3 59.8,106.46 59.67,106.58 56.49,106.58 56.37,106.46 56.37,106.05 56.24,105.92 55.36,105.92 55.34,105.91 53.91,105.91 53.78,105.78 v3(53.78,103.77)
  L4 w0.127: v4(55.49,97.87) 54.6,98.76 54.6,102.33 54.54,102.39 54.54,102.39 53.78,103.16 v3(53.78,103.77) 53.78,105.52 54.4,106.14 54.7,106.14 54.93,105.91 54.94,105.91 54.95,105.91 55.3,105.91 55.38,105.99 55.85,105.99 55.95,105.88 55.95,105.41 v4(56.01,105.36)
  BOTTOM w0.102: MEM4.P8 57.61,96.43 57.14,96.43 56.54,97.03 56.54,97.11 56.17,97.47 56.09,97.47 55.69,97.87 v4(55.49,97.87) ; v2(73.52,106.65) 73.97,106.65 75,105.63 v4(75,105.55) ; v4(56.01,105.36) 55.8,105.15 55.42,105.15 55.35,105.08 54.97,105.08 54.74,105.32 54.74,105.35 54.63,105.46 54.63,106.34 54.13,106.83 53.67,106.83 MEM3.P8
MAA5: length 56.9
  TOP w0.102: v4(75.77,105.59) 75.79,105.59 GPU1.H24 ; v4(55.12,106.32) 55.12,106.64 54.94,106.83 53.07,106.83 52.98,106.93 52.98,107.04 MEM1.P2 ; v4(56.26,97.88) 56.4,97.74 56.4,97.5 56.55,97.35 56.55,96.67 56.75,96.47 57.85,96.47 58.01,96.31 MEM2.P2 ; v4(53.65,102.7) 54.24,102.11 v1(54.24,102.11)
  L3 w0.127: v4(53.65,102.7) 54.18,103.23 54.18,103.58 54.67,104.07 54.67,104.64 54.92,104.89 56.08,104.89 56.56,104.41 56.91,104.41 57.25,104.75 57.63,104.75 57.85,104.54 58.19,104.54 58.3,104.42 58.77,104.42 59.1,104.75 59.1,105.1 59.29,105.29 61.98,105.29 62.41,104.86 64.3,104.86 64.99,105.55 67.72,105.55 67.87,105.69 69.1,105.69 69.73,105.07 74.23,105.07 74.47,104.82 74.47,104.78 74.83,104.43 75.17,104.43 75.42,104.67 75.42,105.24 v4(75.77,105.59)
  L4 w0.127: v4(55.12,106.32) 54.93,106.52 53.86,106.52 53.45,106.1 53.45,105.4 53.32,105.28 52.9,105.28 52.77,105.15 52.77,104.92 52.9,104.79 53.32,104.79 53.45,104.67 53.45,104.46 53.32,104.34 52.9,104.34 52.77,104.21 52.77,104.01 52.9,103.88 53.2,103.88 53.32,103.75 53.32,102.82 53.45,102.7 v4(53.65,102.7) 54.37,101.97 54.37,98.67 55.07,97.97 55.07,97.7 55.32,97.45 55.66,97.45 55.67,97.46 55.79,97.46 56.21,97.88 v4(56.26,97.88)
  BOTTOM w0.102: v4(56.26,97.88) 55.86,98.28 55.32,98.28 54.68,97.64 54.68,97.34 54.51,97.17 54.51,96.85 54.11,96.45 53.64,96.45 MEM4.P2 ; v4(55.12,106.32) 55.47,105.98 56.16,105.98 57.04,106.86 57.6,106.86 MEM3.P2
MAA6: length 65.3
  TOP w0.102: v4(54.6,103.4) 54.61,103.42 54.77,103.42 55.16,103.81 56.74,103.81 v1(57.39,103.15) 57.92,103.68 58.46,103.68 58.59,103.81 58.59,104.08 58.42,104.26 58.42,104.29 58.18,104.52 57.91,104.52 57.59,104.85 57.59,106.05 MEM1.R8 ; GPU1.J19 77.09,101.71 77.34,101.71 77.47,101.83 77.47,102.26 77.34,102.38 v4(77.12,102.38) ; MEM2.R8 53.21,96.46 53.34,96.33 53.5,96.33 53.64,96.47 53.64,97.94 53.83,98.13 53.83,98.28 53.65,98.46 53.65,98.63 53.77,98.74 53.94,98.74 54.12,98.56 54.26,98.56 54.4,98.71 54.4,98.85 54.25,99 54.25,99.17 54.37,99.29 54.53,99.29 54.68,99.14 54.84,99.14 55.48,99.78 55.48,100.04 v4(55.37,100.15)
  L3 w0.127: v4(55.86,102.08) 55.83,102.08 55.7,102.2 55.7,102.58 55.83,102.7 56.49,102.7 56.88,103.1 59.56,103.1 59.79,103.34 60.83,103.34 60.83,103.33 61.05,103.11 61.45,103.11 61.67,103.34 61.93,103.34 62.06,103.21 62.06,102.11 62.19,101.98 62.48,101.98 62.61,102.11 62.61,103.24 62.74,103.37 63.24,103.37 63.37,103.24 63.37,102.66 63.49,102.54 65.32,102.54 65.46,102.67 65.46,102.93 65.59,103.05 65.97,103.05 66.1,102.93 66.1,102.73 66.3,102.53 67.33,102.53 67.49,102.37 73.46,102.37 73.74,102.09 74.07,102.09 74.3,102.32 74.58,102.32 74.81,102.09 75.25,102.09 75.55,101.78 75.94,101.78 76.25,102.09 76.89,102.09 77.12,102.32 v4(77.12,102.38)
  L4 w0.127: v4(55.37,100.15) 55.37,101.01 55.86,101.49 v4(55.86,102.08) 55.86,102.27 55.13,103 55.01,103 54.61,103.4 v4(54.6,103.4)
  BOTTOM w0.102: v4(54.6,103.4) 54.58,103.38 54.58,103.06 54.25,102.73 54.25,102.43 54.09,102.27 54.09,102.25 53.34,102.25 53.21,102.38 53.21,102.89 53.47,103.14 53.47,103.44 52.87,104.05 52.87,104.52 52.73,104.66 51.85,104.66 51.72,104.79 51.72,105.09 51.85,105.22 52.72,105.22 52.82,105.32 52.82,106.38 52.92,106.48 MEM3.R8 ; MEM4.R8 57.67,96.82 57.57,96.92 57.57,98.18 57.84,98.44 58.02,98.44 58.15,98.57 58.15,98.78 58.02,98.9 57.22,98.9 57.09,99.03 57.09,99.21 57.22,99.33 58.07,99.33 58.2,99.46 58.2,99.9 58.07,100.03 57.03,100.03 56.72,99.72 56.27,99.72 55.9,100.09 55.43,100.09 v4(55.37,100.15)
MAA7: length 61.6
  TOP w0.102: v4(55.47,103.38) 55.09,103 53.95,103 53.35,103.59 53.35,105.33 53.54,105.52 53.54,106.15 MEM1.R2 ; v4(77.36,101.22) 77.81,101.22 77.93,101.35 77.93,101.67 77.81,101.8 GPU1.K19 ; MEM2.R2 57.75,96.82 57.65,96.92 57.65,98.12 57.75,98.22 58.23,98.22 58.33,98.32 58.33,98.65 58.23,98.75 57.62,98.75 57.52,98.85 57.52,99.18 57.62,99.28 58.16,99.28 58.26,99.38 58.26,100.92 v1(58.35,101.02) 56.71,101.02 56.7,101 v4(56.65,101)
  L3 w0.127: v4(56.92,102.2) 56.92,102.77 57.02,102.87 57.29,102.87 57.54,102.63 57.82,102.63 58.07,102.87 59.79,102.87 59.9,102.99 60.69,102.99 60.81,102.87 61.68,102.87 61.8,102.75 61.8,102.61 61.8,102.01 62.08,101.74 62.72,101.74 62.85,101.86 62.85,102.06 62.98,102.18 63.43,102.18 63.64,101.97 64,101.97 64.21,102.18 64.65,102.18 64.8,102.04 65.33,102.04 65.69,102.4 65.88,102.4 66.41,101.87 66.62,101.87 66.94,102.2 67.18,102.2 67.52,101.86 68.41,101.86 68.69,102.14 70.32,102.14 70.51,101.95 70.75,101.95 70.94,102.14 72.03,102.14 72.16,102.01 72.16,101.24 72.27,101.12 72.55,101.12 72.66,101.24 72.66,102.01 72.79,102.14 73.23,102.14 73.52,101.85 74.17,101.85 74.3,101.72 74.3,101.43 74.44,101.29 74.68,101.29 74.81,101.41 74.81,101.66 74.94,101.78 75.2,101.78 75.47,101.52 76,101.52 76.29,101.8 77.09,101.8 77.25,101.96 77.61,101.96 77.9,101.68 77.9,101.35 77.77,101.22 v4(77.36,101.22)
  L4 w0.127: v4(55.47,103.38) 55.64,103.38 56.05,103.78 56.39,103.78 56.92,103.26 v4(56.92,102.2) 56.98,102.2 57.1,102.08 57.1,101.13 56.98,101 56.66,101 v4(56.65,101)
  BOTTOM w0.102: v4(56.65,101) 56.5,101 56.46,101.04 56.32,101.04 56.13,101.23 55.69,101.23 55.22,100.76 55.12,100.76 54.76,100.4 54.76,100.3 53.61,99.14 53.61,97.21 MEM4.R2 ; MEM3.R2 57.67,106.48 57.57,106.38 57.57,105.31 57.67,105.2 58.08,105.2 58.18,105.1 58.18,104.75 58.08,104.65 57.97,104.65 57.61,104.29 57.61,104.17 57.16,103.73 57.04,103.73 56.94,103.63 56.94,103.14 56.63,102.84 55.79,102.84 55.66,102.71 55.43,102.71 55.22,102.91 55.22,103.07 55.47,103.32 v4(55.47,103.38)
MAA8: length 61.2
  TOP w0.102: MEM2.T8 53.21,98.65 53.11,98.75 52.75,98.75 52.64,98.85 52.64,99.08 52.75,99.18 53.11,99.18 53.21,99.28 53.21,99.69 53.34,99.82 54.55,99.82 54.68,99.94 54.68,101.01 54.78,101.11 55.16,101.11 55.26,101.01 55.26,100.87 55.4,100.74 55.78,100.74 v4(55.86,100.82) ; v4(76.71,98.81) 77.04,98.81 77.17,98.68 77.17,98.33 77.04,98.2 GPU1.J14 ; MEM1.T8 58.36,105.33 58.85,105.33 59.15,105.03 59.15,102.84 58.96,102.65 57.68,102.65 57.63,102.6 57.16,102.6 57.09,102.67 56.74,102.67 56.49,102.92 56.49,103.1 v4(56.22,103.37)
  L3 w0.127: v4(56.32,101.64) 56.44,101.76 56.95,101.76 57.07,101.64 57.07,101.1 57.17,101.01 57.63,101.01 57.75,101.13 57.75,101.23 58.14,101.61 58.14,102.01 58.3,102.17 58.83,102.17 58.97,102.03 58.97,101.41 58.85,101.29 58.5,101.29 58.27,101.06 58.27,100.71 58.4,100.58 60.94,100.58 62.09,99.43 62.47,99.43 62.75,99.16 63.27,99.16 63.55,99.43 64.15,99.43 64.25,99.33 67.09,99.33 67.22,99.2 67.22,98.68 67.35,98.56 67.69,98.56 67.83,98.7 67.83,99.59 67.96,99.72 69.77,99.72 69.9,99.59 69.9,99.15 70.02,99.02 71.67,99.02 72.08,99.43 72.54,99.43 73.5,98.47 74.4,98.47 74.59,98.28 76.56,98.28 76.71,98.44 v4(76.71,98.81)
  L4 w0.127: v4(55.86,100.82) 56.14,100.82 56.23,100.92 56.23,101.56 v4(56.32,101.64) 56.32,102.21 56.22,102.31 v4(56.22,103.37)
  BOTTOM w0.102: MEM3.T8 53.45,105.68 53.57,105.55 53.57,105.25 53.45,105.13 52.98,105.13 52.86,105.01 52.86,104.84 52.98,104.72 53.72,104.72 53.9,104.54 53.9,104.27 54.14,104.02 54.42,104.02 54.63,103.81 56.42,103.81 56.55,103.68 56.55,103.49 56.42,103.37 v4(56.22,103.37) ; v4(55.86,100.82) 55.93,100.82 56.16,100.59 56.86,100.59 56.93,100.66 56.93,100.66 57.25,100.98 58.14,100.98 v2(58.59,100.53) 58.59,99.9 58.69,99.8 58.86,99.8 58.96,99.69 58.96,99.49 58.86,99.39 58.52,99.39 58.4,99.27 58.4,99.1 58.52,98.98 59.02,98.98 59.14,98.86 59.14,98.7 59.02,98.58 58.69,98.58 58.59,98.48 58.59,98.19 MEM4.T8
MAA9: length 53.1
  TOP w0.102: v4(55.14,105.49) 55.14,105.64 54.87,105.92 54.85,105.92 54.65,106.12 54.65,106.51 54.55,106.61 54.15,106.61 MEM1.R3 ; GPU1.K14 77.5,98.2 77.39,98.09 v4(77.39,97.77) ; v4(56.44,98.69) 56.44,98.94 56.71,99.21 56.99,99.21 57.09,99.1 57.09,97.99 56.82,97.72 56.82,97.35 56.93,97.25 57.11,97.25 57.21,97.15 MEM2.R3
  L3 w0.127: v4(58.56,101.75) 58.53,101.73 58.53,101.69 58.36,101.52 58.36,101.47 58.02,101.13 58.02,100.47 58.15,100.35 60.85,100.35 61.99,99.2 62.38,99.2 62.66,98.93 62.99,98.93 63.12,98.8 63.12,98.37 63.24,98.24 63.52,98.24 63.64,98.37 63.64,99.06 63.77,99.19 64.02,99.19 64.15,99.06 64.15,98.46 64.27,98.33 64.53,98.33 64.66,98.46 64.66,98.88 64.77,99 65.04,99 65.16,98.88 65.16,98.46 65.29,98.33 65.54,98.33 65.67,98.46 65.67,98.86 65.81,99 66.71,99 66.89,98.82 66.89,98.55 67.21,98.23 67.68,98.23 67.68,98.23 67.87,98.23 67.96,98.32 67.96,98.51 68.22,98.76 68.42,98.76 68.55,98.64 68.55,98.29 68.67,98.16 68.93,98.16 69.05,98.29 69.05,98.52 69.18,98.65 69.55,98.65 69.7,98.8 71.9,98.8 72.01,98.91 72.01,99.04 72.16,99.19 72.46,99.19 72.72,98.93 72.72,98.62 72.8,98.54 73.11,98.54 73.41,98.24 74.31,98.24 74.5,98.05 74.99,98.05 75.14,97.9 75.51,97.9 75.66,98.05 75.96,98.05 76.11,97.9 76.56,97.9 76.75,98.09 77.07,98.09 v4(77.39,97.77)
  L4 w0.127: v4(55.14,105.49) 55.29,105.49 55.83,104.94 56.25,104.94 56.57,105.25 56.91,105.25 57.16,105.01 57.16,104.31 58.51,102.96 58.51,101.79 v4(58.56,101.75) 58.56,100.78 56.46,98.69 v4(56.44,98.69)
  BOTTOM w0.102: v4(58.56,101.75) 58.67,101.75 58.77,101.85 58.85,101.85 59.31,102.31 v2(59.31,102.41) ; v4(56.44,98.69) 56.32,98.69 56.12,98.9 55.92,98.9 55.63,99.18 55.29,99.18 55.2,99.09 55.17,99.09 54.93,98.85 54.93,98.82 54.72,98.61 54.72,97.98 54.4,97.66 54.4,97.46 54.01,97.08 MEM4.R3 ; v4(55.14,105.49) 55.35,105.69 55.77,105.69 55.84,105.77 56.18,105.77 56.25,105.69 56.66,105.69 56.99,106.02 57.26,106.02 57.37,106.14 57.37,106.37 57.26,106.48 MEM3.R3
MAA10: length 59.7
  TOP w0.102: v4(55.86,109.75) 56.03,109.92 56.94,109.92 57.18,109.68 MEM1.L7 ; v4(54.75,92.84) 54.75,93.07 54.58,93.24 54.11,93.24 54.01,93.34 MEM2.L7 ; v4(76.94,96.46) 77,96.4 GPU1.J11
  L3 w0.127: v4(76.94,96.46) 76.94,96.6 76.81,96.73 75.43,96.73 75.41,96.74 74.3,96.74 74.17,96.87 73.5,96.87 72.98,97.39 66.43,97.39 66.11,97.06 63.45,97.06 62.54,97.97 62.21,97.97 61.62,98.55 61.62,98.86 61.04,99.43 60.77,99.43 v4(60.58,99.62)
  L4 w0.127: v4(55.86,109.75) 56.39,109.75 57.39,108.75 57.62,108.75 57.75,108.63 57.75,108.54 57.88,108.41 61.22,108.41 61.35,108.28 61.35,102.1 61.48,101.97 61.98,101.97 62.11,101.85 62.11,100.8 61.63,100.32 61.63,100.05 61.2,99.62 v4(60.58,99.62) 60.12,99.16 59.64,99.16 58.86,98.38 58.86,97.03 58.63,96.81 58.25,96.81 58.25,96.8 58.01,96.8 57.33,96.13 57.33,94.85 57.03,94.55 55.1,94.55 54.83,94.27 53.27,94.27 53.14,94.15 53.14,93.87 53.27,93.74 53.95,93.74 54.06,93.64 54.06,93.42 53.95,93.32 53.15,93.32 53.05,93.22 53.05,92.94 53.15,92.84 53.43,92.84 53.44,92.84 53.78,92.84 53.79,92.84 v4(54.75,92.84)
  BOTTOM w0.102: v4(54.75,92.84) 55.75,93.41 56.02,93.51 56.39,93.62 MEM4.L7 ; v2(61.45,99.72) 60.66,99.72 60.58,99.65 v4(60.58,99.62) ; MEM3.L7 54.33,109.99 54.72,109.99 55,109.71 55.82,109.71 v4(55.86,109.75)
MAA11: length 52.4
  TOP w0.102: v4(76.57,97.47) 76.57,97.18 76.75,97 GPU1.J13 ; v4(56.74,104.83) 56.77,104.86 56.77,105.95 56.89,106.08 57.25,106.08 57.38,106.21 57.38,106.35 57.25,106.48 MEM1.R7 ; MEM2.R7 54.76,97.57 54.76,98.08 55.34,98.66 v4(55.34,98.68)
  L3 w0.127: v4(76.57,97.47) 76.57,97.06 76.47,96.96 75.52,96.96 75.43,97.05 74.75,97.05 74.63,97.18 74.63,97.39 74.5,97.52 74.3,97.52 74.17,97.39 74.17,97.21 74.06,97.1 73.61,97.1 73.48,97.22 73.48,97.71 72.9,98.29 72.55,98.29 72.42,98.16 72.42,97.75 72.3,97.62 72.04,97.62 71.92,97.75 71.92,98.42 71.79,98.55 71.26,98.55 70.93,98.23 70.6,98.23 70.28,98.55 69.89,98.55 69.78,98.44 69.78,98.19 69.78,98.13 69.59,97.93 69.53,97.93 69.52,97.93 68.94,97.93 68.66,97.66 68.21,97.66 67.96,97.91 67.96,97.93 67.48,97.93 67.28,97.73 66.64,97.73 66.52,97.86 66.52,98.15 66.52,98.15 66.52,98.53 66.39,98.66 66.16,98.66 66.06,98.57 66.06,97.53 65.94,97.4 65.68,97.4 65.56,97.53 65.56,97.87 65.43,98 65.18,98 65.05,97.87 65.05,97.53 64.92,97.41 64.67,97.41 64.54,97.53 64.54,97.84 64.41,97.97 64.16,97.97 64.03,97.84 64.03,97.44 63.91,97.31 63.65,97.31 63.52,97.44 63.52,97.87 63.4,98 63.09,98 62.71,98.37 62.43,98.37 60.76,100.04 60.41,100.04 60.17,99.8 60.17,99.62 60.04,99.5 59.77,99.5 59.64,99.62 59.64,99.95 59.51,100.08 59.24,100.08 59.11,99.95 59.11,99.62 58.99,99.5 58.71,99.5 58.58,99.62 58.58,99.9 58.45,100.03 58.18,100.03 58.05,99.9 58.05,99.69 57.92,99.56 57.63,99.56 57.29,99.89 57.29,100.32 v4(57.54,100.57)
  L4 w0.127: v4(56.74,104.83) 56.74,104.13 57.98,102.89 57.98,101.01 v4(57.54,100.57) 57.54,100.09 56.56,99.11 56.15,99.11 55.92,98.87 55.92,98.57 55.79,98.45 55.46,98.45 55.34,98.57 v4(55.34,98.68)
  BOTTOM w0.102: v4(56.74,104.83) 56.41,104.83 56.29,104.95 55.51,104.95 55.43,104.88 54.89,104.88 54.35,105.42 54.35,106.15 MEM3.R7 ; MEM4.R7 56.84,97.19 56.84,97.87 56.43,98.28 56.23,98.28 56.15,98.36 56.08,98.36 55.8,98.64 55.6,98.64 55.56,98.68 55.34,98.68 v4(55.34,98.68)
MAA12: length 55
  TOP w0.102: v4(55.95,95.19) 55.89,95.19 55.52,95.57 54.89,95.57 54.54,95.22 MEM2.N7 ; v4(75.66,95.3) 76.15,95.8 GPU1.H11 ; v4(54.92,108.14) 55.15,107.91 55.8,107.91 56.08,108.19 56.42,108.19 56.53,108.07 56.94,108.07 56.94,108.08 MEM1.N7
  L3 w0.127: v4(75.66,95.3) 75.11,95.3 74.68,95.74 73.34,95.74 73.09,95.98 71.48,95.98 71.29,96.17 70.3,96.17 69.87,96.6 66.83,96.6 66.48,96.25 62.86,96.25 61.95,97.16 61.81,97.16 61.12,97.85 61.12,98.02 60.86,98.28 60.68,98.28 60.15,98.81 57.33,98.81 56.88,99.26 56.43,99.26 56.33,99.16 56.2,99.16 56.1,99.06 55.75,99.06 55.61,99.2 55.28,99.2 55.16,99.07 53.9,99.07 52.46,100.5 v4(52.46,100.89)
  L4 w0.127: v4(54.92,108.14) 54.55,108.14 52.66,106.25 52.66,106.07 52.21,105.63 52.21,101.67 52.46,101.42 v4(52.46,100.89) 53.78,100.89 53.91,100.76 53.91,100.21 53.78,100.08 53.23,100.08 53.1,99.95 53.1,99.7 53.23,99.57 53.78,99.57 53.91,99.44 53.91,98.05 54.84,97.11 54.84,95.74 54.97,95.61 55.52,95.61 55.94,95.19 v4(55.95,95.19)
  BOTTOM w0.102: v4(54.92,108.14) 55.19,108.41 55.19,108.58 54.89,108.87 54.5,108.87 54.01,108.39 MEM3.N7 ; v2(52.16,101.74) 52.46,101.43 v4(52.46,100.89) ; v4(55.95,95.19) 55.95,95.18 56.19,94.94 56.94,94.94 MEM4.N7
MAA13: length 54.1
  TOP w0.102: v4(56.57,100.19) 56.65,100.19 56.71,100.13 56.96,100.13 57.31,99.78 57.31,98.61 57.4,98.52 57.4,97.81 MEM2.T3 ; MEM1.T3 54.53,105.68 54.66,105.55 54.66,105.21 54.53,105.08 54.39,105.08 54.26,104.95 54.26,104.6 54.39,104.47 v4(55.09,104.47) ; v4(75.12,103.48) 75.12,103.28 GPU1.G20
  L3 w0.127: v4(75.12,103.48) 74.7,103.48 74.42,103.76 71.45,103.76 71.43,103.75 70.71,103.75 70.62,103.84 65,103.84 64.79,103.62 59.73,103.62 59.53,103.42 56.88,103.42 56.4,102.94 55.66,102.94 55.44,102.72 55.44,102.36 54.87,101.78 54.87,101.3 55.04,101.13 55.33,101.13 55.43,101.03 55.43,100.72 55.33,100.61 54.39,100.61 53.45,101.55 53.45,101.78 53.6,101.93 54.16,101.93 54.79,102.56 v4(54.96,102.56)
  L4 w0.127: v4(55.09,104.47) 55.29,104.47 55.48,104.65 55.48,104.91 55.35,105.04 54.2,105.04 54.07,104.91 54.07,104.61 54.2,104.49 54.43,104.49 54.55,104.36 54.55,103.95 54.18,103.58 54.18,103.08 54.7,102.56 v4(54.96,102.56) 54.96,102.51 54.85,102.41 54.85,100.06 55.18,99.73 55.57,99.73 56.03,100.19 v4(56.57,100.19)
  BOTTOM w0.102: v4(54.96,102.56) 54.14,101.74 v2(53.72,101.74) ; MEM3.T3 57.21,104.75 57.15,104.69 57.15,104.67 56.91,104.43 56.56,104.43 56.35,104.64 56.32,104.64 56.3,104.65 56.03,104.65 55.93,104.75 55.59,104.75 55.46,104.61 55.23,104.61 v4(55.09,104.47) ; MEM4.T3 54.01,99.25 54.97,100.2 54.97,100.32 55.2,100.55 55.54,100.55 55.7,100.39 56.36,100.39 v4(56.57,100.19)
MAA14: length 49.8
  TOP w0.102: GPU1.G14 75.4,98.1 75.21,97.91 75.07,97.91 74.95,98.03 74.95,98.17 74.79,98.33 74.79,98.47 74.95,98.63 74.95,98.93 75.07,99.06 75.59,99.06 75.71,98.94 v4(75.71,98.7) ; v4(55.76,104.34) 56.04,104.34 56.15,104.23 56.73,104.23 57.21,104.71 MEM1.T7 ; v4(55.92,99.48) 55.81,99.36 55.38,99.36 54.01,97.99 MEM2.T7
  L3 w0.127: v4(57.56,101.65) 57.46,101.65 57.34,101.78 57.34,102.29 57.45,102.4 57.92,102.4 58.16,102.64 58.53,102.64 58.53,102.64 58.75,102.43 59.02,102.43 59.24,102.64 59.58,102.64 59.71,102.52 59.71,102.28 59.4,101.97 59.33,101.97 59.2,101.84 59.2,101.32 59.07,101.18 59.07,100.94 59.2,100.81 59.56,100.81 59.76,101.01 60.25,101.01 60.44,100.81 60.84,100.81 61.03,100.81 61.15,100.7 61.54,100.7 61.76,100.47 61.76,100.08 62.18,99.66 62.57,99.66 62.85,99.39 63.16,99.39 63.54,99.76 64.15,99.76 64.25,99.66 67.44,99.66 67.67,99.9 67.67,100.41 67.77,100.51 68.09,100.51 68.19,100.41 68.19,100.19 68.32,100.06 68.54,100.06 69.45,100.06 69.45,100.06 70.17,100.06 70.17,100.06 70.61,100.06 70.85,100.3 71.21,100.3 71.38,100.13 71.88,100.13 72.02,99.98 72.02,99.78 72.14,99.66 72.4,99.66 72.51,99.78 72.51,100 72.64,100.13 73.01,100.13 73.13,100 73.13,99.16 73.44,98.86 73.71,98.86 73.87,98.7 74.1,98.7 74.26,98.86 74.47,98.86 74.59,98.73 74.59,98.64 74.72,98.51 75.05,98.51 75.17,98.63 75.17,98.86 75.31,99 75.59,99 75.71,98.87 v4(75.71,98.7)
  L4 w0.127: v4(55.76,104.34) 56.16,104.34 57.56,102.94 v4(57.56,101.65) 57.61,101.65 57.74,101.52 57.74,101.11 57.61,100.99 57.28,100.99 56.99,100.7 56.99,99.86 56.48,99.35 56.05,99.35 v4(55.92,99.48)
  BOTTOM w0.102: v4(57.56,101.65) 57.56,102.2 v2(57.79,102.44) ; MEM3.T7 54.01,104.75 54.52,104.25 54.52,104.24 54.72,104.04 55.63,104.04 55.76,104.17 v4(55.76,104.34) ; MEM4.T7 57.22,97.62 57.35,97.75 57.35,98.47 56.87,98.94 56.87,99.35 56.75,99.48 v4(55.92,99.48)
MAA_BA0: length 60.2
  TOP w0.102: v4(56.8,108.51) 56.8,108.72 56.67,108.84 56.47,108.84 56.37,108.74 55.93,108.74 55.89,108.78 54.6,108.78 54.12,108.53 53.97,108.53 53.88,108.55 53.88,108.55 53.68,108.74 53.68,108.87 53.56,109 53.33,109 MEM1.M2 ; v4(55.32,95.11) 55.66,94.77 56.13,94.77 56.13,94.77 57.67,94.77 MEM2.M2 ; v1(60.37,100.88) 60.37,101.11 v4(60.84,101.58) ; GPU1.J16 77,99.31 v4(77.59,98.72)
  L3 w0.127: v4(77.59,98.72) 77.63,98.72 77.74,98.83 77.74,99.3 77.54,99.5 75.72,99.5 75.45,99.77 75.45,100.18 75.25,100.39 74.62,100.39 74.5,100.27 74.5,100.14 74.38,100.02 73.77,100.02 73.64,100.14 73.64,100.46 73.51,100.59 71.57,100.59 71.28,100.88 70.68,100.88 70.55,100.75 70.55,100.64 70.42,100.52 70.17,100.52 70.04,100.64 70.04,100.75 69.91,100.88 69.66,100.88 69.53,100.75 69.53,100.64 69.41,100.52 69.15,100.52 69.03,100.64 69.03,100.75 68.9,100.88 68.63,100.88 68.34,101.18 67.06,101.18 66.93,101.05 66.93,100.44 66.81,100.32 64.25,100.32 64.24,100.32 62.77,100.32 62.65,100.44 62.65,101.06 62.48,101.23 61.69,101.23 61.49,101.43 61.49,101.68 61.34,101.83 60.98,101.83 60.84,101.69 v4(60.84,101.58)
  L4 w0.127: v4(55.32,95.11) 55.66,94.78 56.58,94.78 57.01,95.21 57.01,96.18 57.98,97.15 57.98,97.7 58.11,97.83 58.5,97.83 58.63,97.95 58.63,98.47 59.41,99.25 59.41,99.26 60.2,100.04 60.48,100.04 60.75,100.31 60.75,100.88 60.88,101 61.3,101 61.43,101.13 61.43,101.45 61.3,101.58 v4(60.84,101.58) 60.84,101.97 61,102.13 61,106.98 59.88,108.1 57.22,108.1 v4(56.8,108.51)
  BOTTOM w0.102: v4(55.32,95.11) 55.32,95.28 55.19,95.41 54.67,95.41 54.13,94.87 53.88,94.87 53.75,95 53.47,95 53.34,94.87 52.99,94.87 52.86,94.74 52.86,94.55 52.99,94.42 MEM4.M2 ; MEM3.M2 58.36,108.88 58.48,109.01 58.48,109.02 58.68,109.21 58.68,109.35 58.5,109.53 58.33,109.53 58.15,109.35 57.7,109.35 57.56,109.21 57.56,108.56 57.44,108.43 56.88,108.43 v4(56.8,108.51)
MAA_BA1: length 57.5
  TOP w0.102: MEM1.N8 57.88,108.21 57.67,108.21 57.56,108.11 57.56,107.73 57.45,107.61 57.08,107.61 56.99,107.52 56.39,107.52 56.27,107.65 v4(56.27,107.74) ; v4(56.02,96.08) 55.97,96.08 55.58,96.47 55.12,96.47 54.3,95.65 53.64,95.65 MEM2.N8 ; v4(78.36,98.08) 78.36,98.02 78.46,97.93 78.9,97.93 79,98.03 79,98.06 79,98.06 79,98.44 79,98.44 79,98.5 78.9,98.6 GPU1.L15
  L3 w0.127: v4(78.36,98.08) 78.36,97.59 78.24,97.46 77.95,97.46 77.81,97.6 77.81,97.95 77.56,98.19 77.29,98.19 77.17,98.32 77.17,99.06 76.99,99.24 75.34,99.24 75.21,99.37 75.21,99.95 75.09,100.08 74.83,100.08 74.71,99.95 74.71,99.24 74.55,99.09 73.57,99.09 73.38,99.28 73.38,100.23 73.26,100.36 71.47,100.36 71.29,100.54 70.77,100.54 70.52,100.29 70.07,100.29 70.07,100.29 69.54,100.29 69.54,100.29 68.63,100.29 68.5,100.42 68.5,100.68 68.35,100.84 67.43,100.84 67.3,100.71 67.3,100.28 67.01,99.99 62.6,99.99 61.52,101.07 60.61,101.07 60.41,101.27 60.05,101.27 59.82,101.51 v4(59.82,101.79)
  L4 w0.127: v4(56.02,96.08) 57.36,97.42 57.36,98.23 59.48,100.36 59.48,100.5 59.61,100.63 60.06,100.63 60.18,100.75 60.18,101.02 60.06,101.14 59.57,101.14 59.44,101.26 59.44,101.67 59.57,101.79 v4(59.82,101.79) 59.78,101.82 59.78,104.57 59.87,104.66 59.87,106.54 59.44,106.98 57.46,106.98 56.7,107.74 v4(56.27,107.74)
  BOTTOM w0.102: MEM3.N8 53.56,107.74 55.53,107.74 55.54,107.74 56,107.74 56.01,107.74 v4(56.27,107.74) ; v4(59.82,101.79) 59.75,101.72 59.75,101.07 60.08,100.73 v2(60.56,100.73) ; MEM4.N8 57.55,95.68 56.87,95.68 56.47,96.08 v4(56.02,96.08)
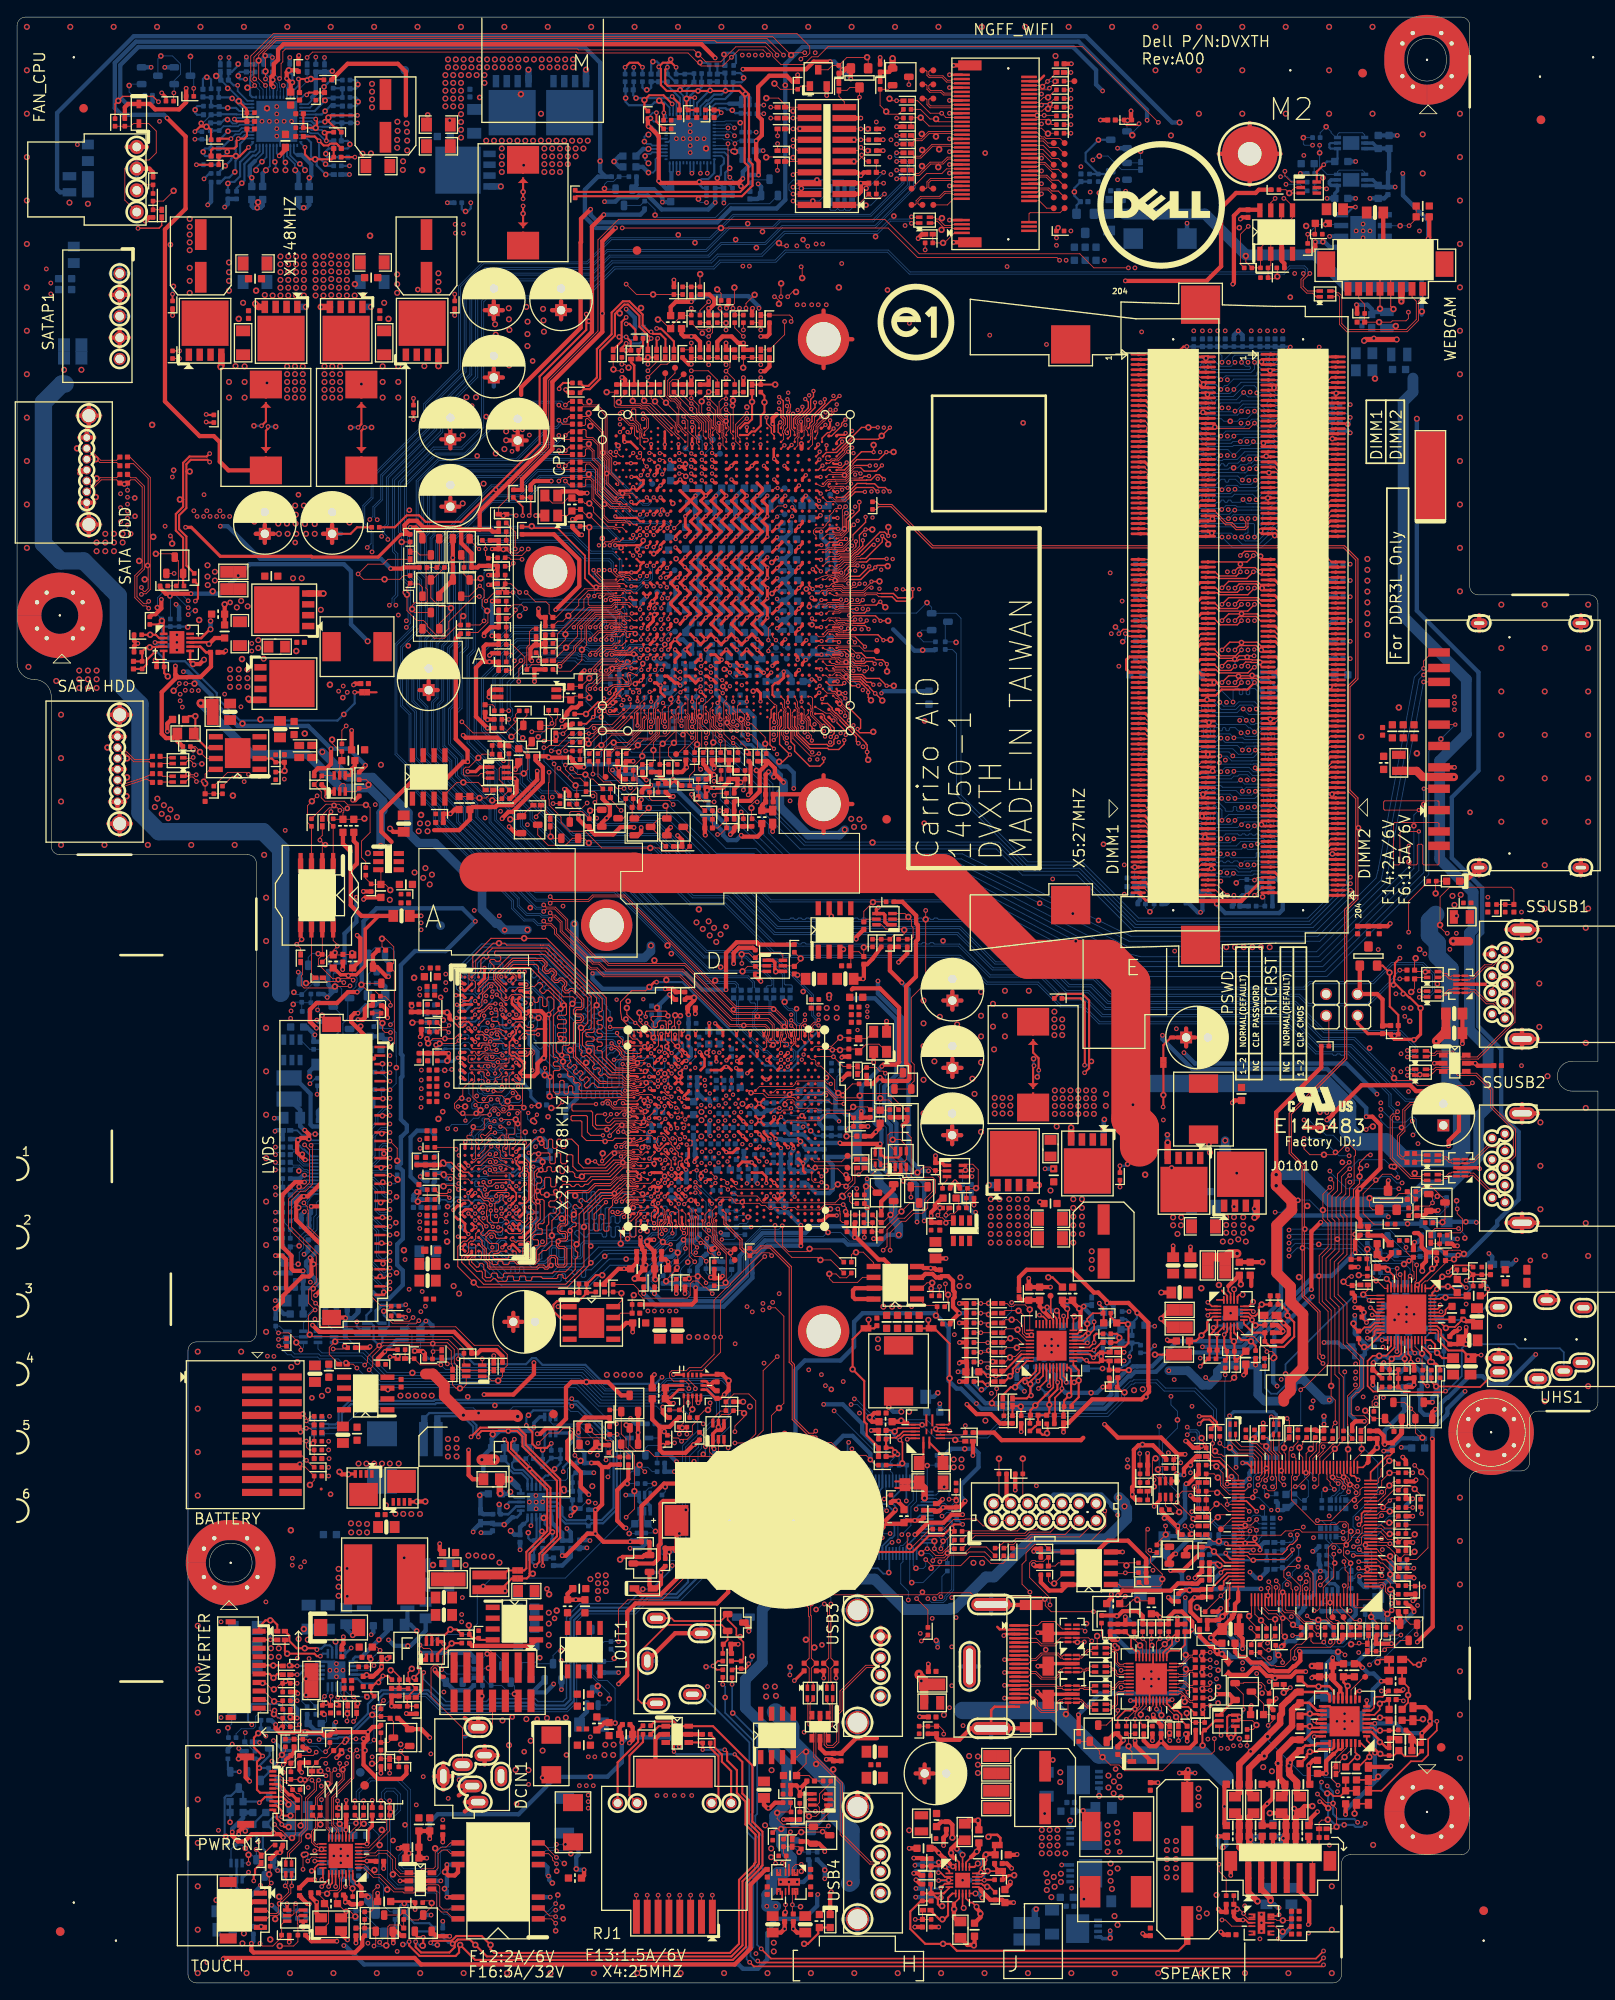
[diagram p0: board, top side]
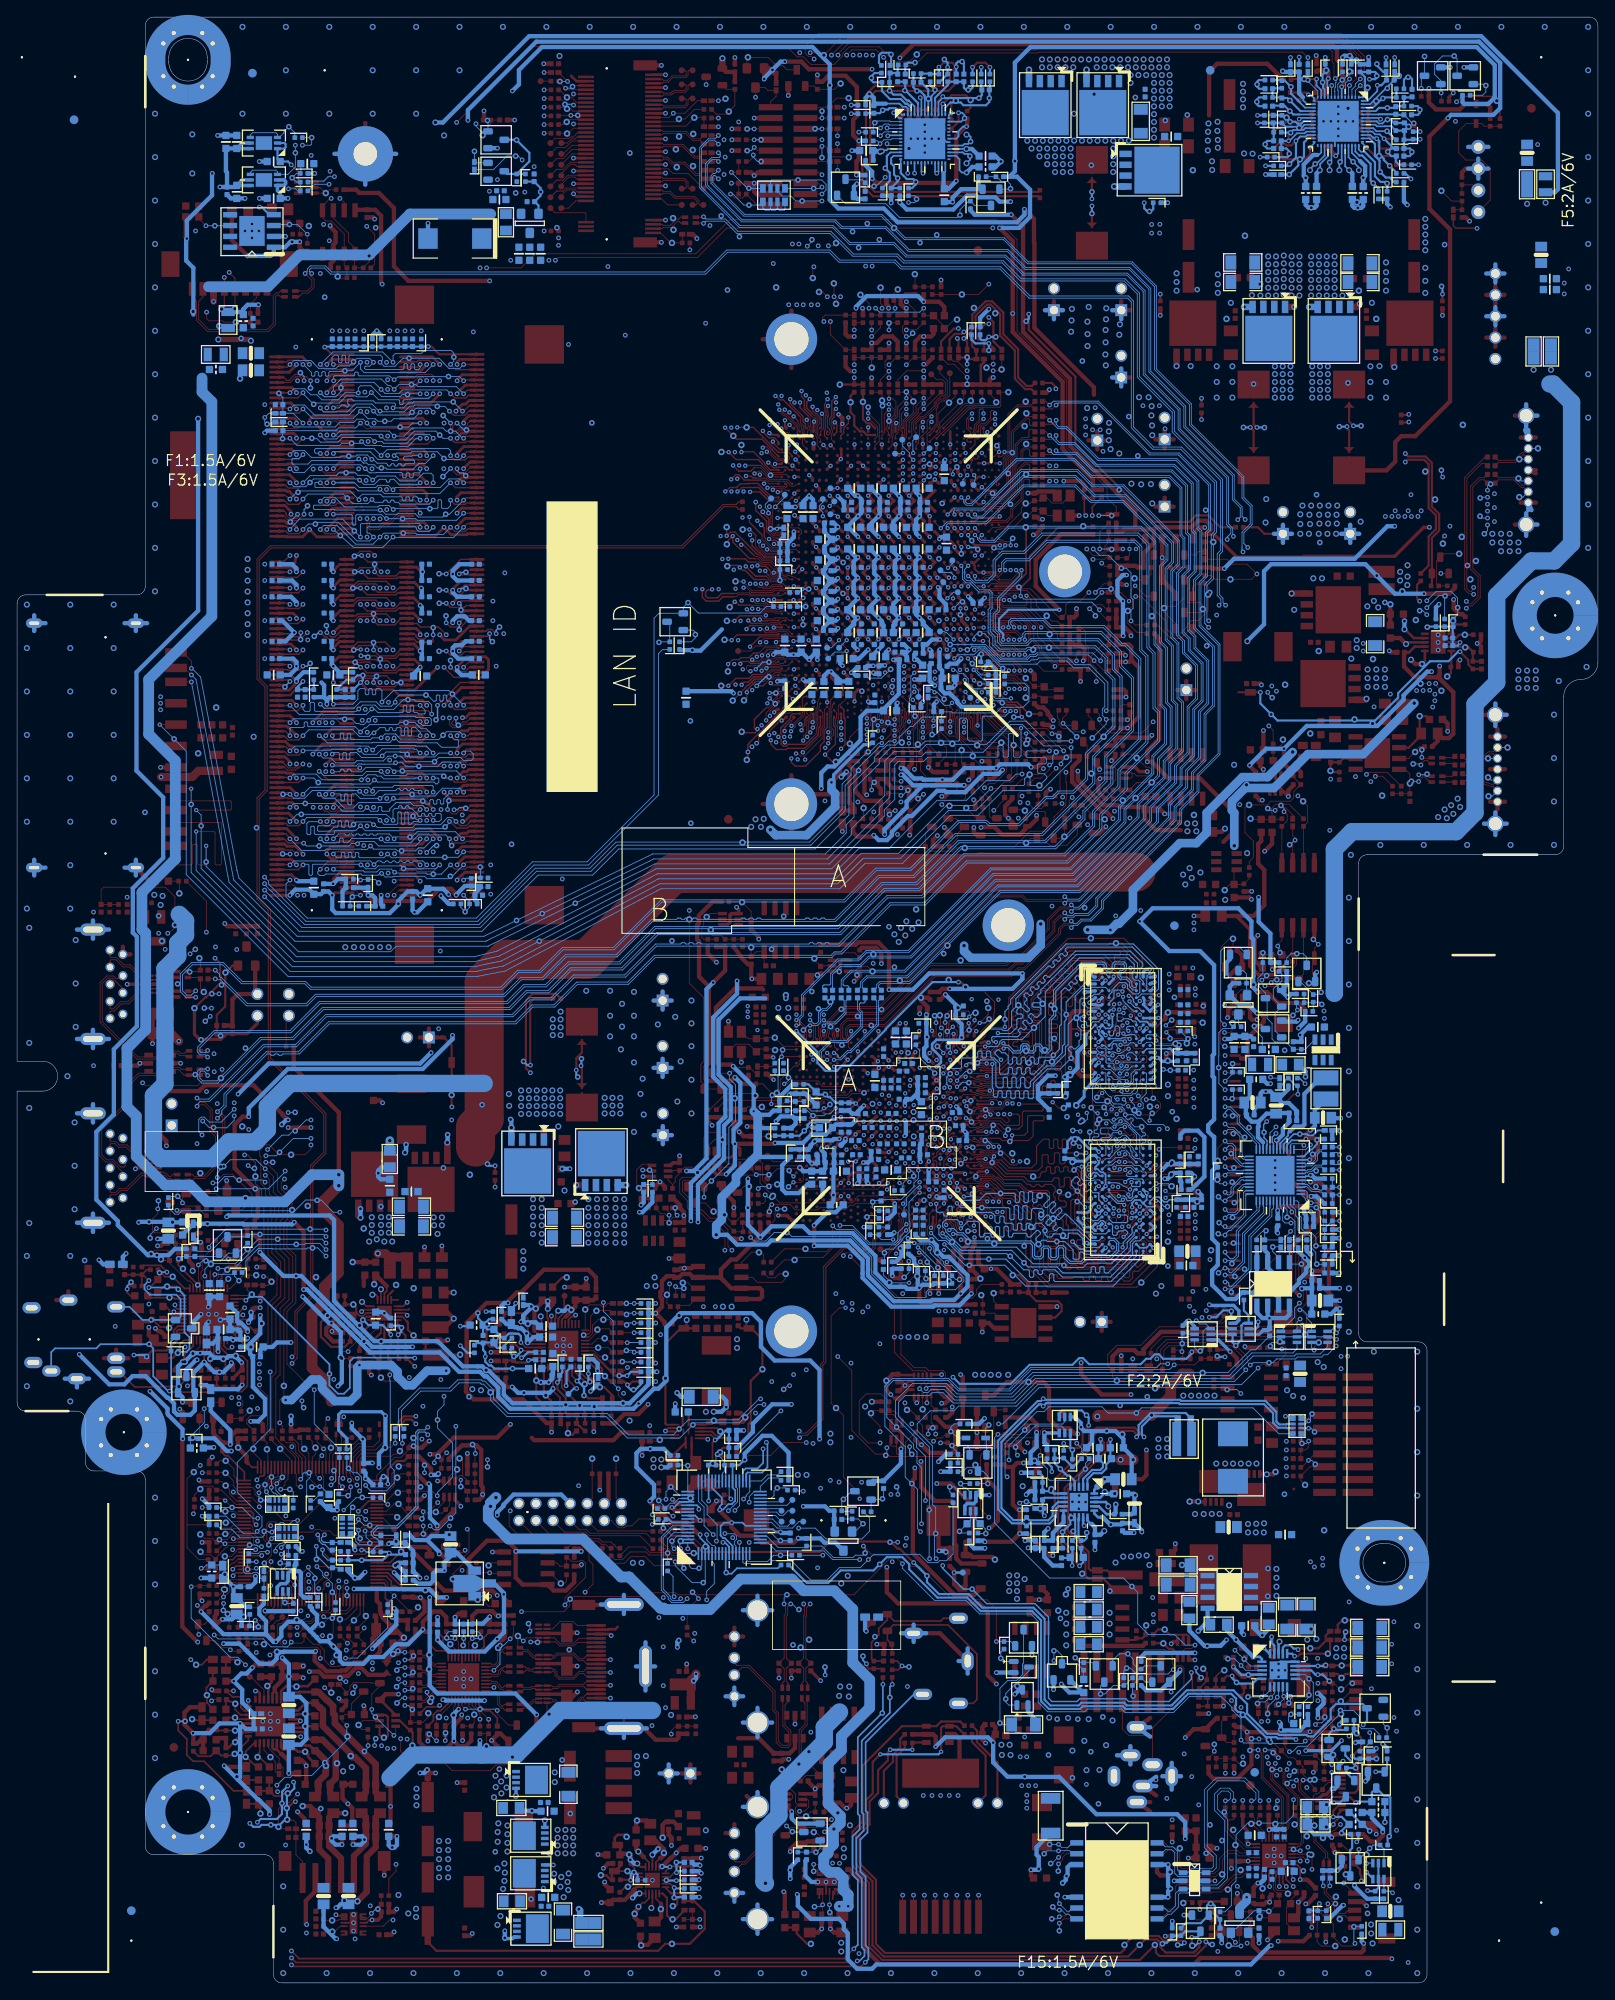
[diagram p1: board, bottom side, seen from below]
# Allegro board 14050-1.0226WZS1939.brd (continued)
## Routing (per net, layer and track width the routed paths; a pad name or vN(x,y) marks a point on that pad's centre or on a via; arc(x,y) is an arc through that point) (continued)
MAA_BA2: length 56.2
  TOP w0.102: MEM2.M3 55.16,94.42 v4(54.75,94.83) ; v4(75.87,96.28) 75.4,95.81 GPU1.G11 ; v1(52.43,102.54) v4(51.59,102.54) ; v4(54.92,109.29) 54.92,109.15 54.78,109 54.14,109 MEM1.M3
  L3 w0.127: v4(51.59,102.54) 51.92,102.54 54.43,100.03 54.9,100.03 55.2,99.73 55.2,99.73 55.26,99.67 55.52,99.67 55.75,99.9 56.1,99.9 56.49,99.5 56.62,99.5 56.63,99.49 56.97,99.49 57.2,99.27 57.28,99.19 60.41,99.19 62.04,97.56 62.38,97.56 63.29,96.65 66.27,96.65 66.63,97.01 69.81,97.01 69.94,97.14 72.69,97.14 73.82,96.02 74.73,96.02 74.85,95.89 75.48,95.89 v4(75.87,96.28)
  L4 w0.127: v4(54.75,94.83) 54.57,94.83 51.93,97.47 51.93,100.63 51.59,100.96 v4(51.59,102.54) 51.52,102.62 51.52,106.12 51.76,106.36 52.41,106.36 53.98,107.93 53.98,108.11 53.68,108.4 53.68,108.58 53.86,108.76 54.04,108.76 54.34,108.47 54.52,108.47 54.92,108.87 v4(54.92,109.29)
  BOTTOM w0.102: MEM3.M3 56.82,108.93 56.69,108.92 56.62,108.9 56.45,108.83 56.2,108.73 56.12,108.72 56,108.72 55.96,108.74 55.77,108.84 v4(54.92,109.29) ; MEM4.M3 54.08,94.36 55.03,94.36 55.16,94.48 55.16,94.67 55,94.83 v4(54.75,94.83)
MCLK: length 6.1
  TOP w0.102: U109.80 144.17,52.78 v3(144.28,52.88)
  BOTTOM w0.102: RN10.1 145.36,51.95 145.36,51.68 144.95,51.27 143.91,51.27 143.75,51.44 v2(143.72,51.44) 143.72,51.72 144.17,52.16 144.17,52.77 v3(144.28,52.88)
MCT_R: length 4.7
  BOTTOM w0.508: v2(62.64,11.68) 62.26,12.06 62.26,12.43 v3(62.19,12.5) 62.06,12.63 62.06,13.54 61.76,13.84 XF1.4 ; v3(62.39,10.03) 60.99,10.03
MCT_R_1: length 7
  TOP w0.508: v3(66.35,13.23) 66.35,12.57 R79612.1
  BOTTOM w0.508: C3131.1 65.69,15.88 65.69,15 65.44,14.74 v2(65.44,13.34) 65.54,13.23 v3(66.35,13.23)
MDA0: length 39.2
  TOP w0.127: GPU1.K27 77.8,108.6 77.78,108.62 77.78,108.74 77.46,109.06 v3(77.46,112.35)
  L3 w0.165: v4(54.81,114.85) 54.81,114.95 54.46,115.31 54.46,115.73 54.15,116.04 54.15,119.11 54.93,119.89 71.3,119.89 77.46,113.74 v3(77.46,112.35)
  BOTTOM w0.127: v2(77.63,113.16) 77.46,112.98 v3(77.46,112.35) ; MEM3.F8 53.39,113.68 53.85,114.14 54.19,114.14 54.81,114.76 v4(54.81,114.85)
MDA1: length 38.6
  TOP w0.127: GPU1.J29 77,109.75 76.58,110.17 76.58,111.49 v3(76.83,111.74) 76.94,111.85 76.94,113.14 v1(77.02,113.21)
  L3 w0.165: v3(76.83,111.74) 76.93,111.83 76.93,113.63 71.29,119.27 70.52,119.27 70.35,119.11 70.35,118.65 70.23,118.52 69.82,118.52 69.69,118.65 69.69,119.11 69.38,119.42 57.54,119.42 57.22,119.11 57.22,118.86 57.06,118.7 56.73,118.7 56.56,118.86 56.56,119.11 56.4,119.27 55.62,119.27 55.43,119.08 55.43,118.44 54.87,117.89 54.87,116.13 55.33,115.67 55.33,115.61 v4(55.57,115.37)
  BOTTOM w0.127: v4(55.57,115.37) 55.57,114.91 54.34,113.68 MEM3.F7
MDA2: length 38.5
  TOP w0.127: v4(73.57,113.04) 73.54,113.07 73.54,113.57 73.67,113.69 74.89,113.69 ; v1(74.89,114.1) 74.89,113.69 ; 74.89,113.69 75.93,113.69 76.05,113.57 76.05,113.2 75.93,113.07 74.33,113.07 74.2,112.95 74.2,112.69 74.45,112.44 74.45,111.92 74.58,111.79 74.81,111.79 74.94,111.92 74.94,112.32 75.18,112.57 75.85,112.57 75.95,112.46 75.95,112.19 75.95,112.19 75.95,112.15 75.98,112.12 75.98,111.21 75.86,111.09 75.86,110.34 GPU1.H30
  L3 w0.165: v4(57.62,112.48) 57.62,112.57 57.75,112.69 58.24,112.69 58.36,112.82 58.73,112.82 58.86,112.69 58.86,112.37 58.98,112.25 59.66,112.25 60.05,112.64 61.08,112.64 61.17,112.73 61.85,112.73 62.01,112.89 62.01,113.58 62.18,113.75 62.51,113.75 62.67,113.58 62.67,112.89 62.84,112.73 63.17,112.73 63.33,112.89 63.33,113.58 63.5,113.75 63.83,113.75 63.99,113.58 63.99,112.89 64.16,112.73 64.49,112.73 64.65,112.89 64.65,113.58 64.82,113.75 65.15,113.75 65.31,113.58 65.31,112.89 65.48,112.73 65.81,112.73 65.97,112.89 65.97,113.58 66.14,113.75 66.47,113.75 66.64,113.58 66.64,112.89 66.8,112.73 67.13,112.73 67.3,112.89 67.3,113.58 67.46,113.75 67.79,113.75 67.96,113.58 67.96,112.89 68.12,112.73 68.56,112.73 68.97,113.13 73.48,113.13 v4(73.57,113.04)
  BOTTOM w0.127: v4(73.57,113.04) 73.15,113.46 v2(72.88,113.46) ; v4(57.62,112.48) 57.22,112.08 MEM3.H3
MDA3: length 37.6
  TOP w0.127: v3(76.4,112.37) 76.36,112.37 76.23,112.25 76.23,110.83 GPU1.H32
  L3 w0.165: v3(76.4,112.37) 76.4,113.53 71.79,118.14 69.66,118.14 68.85,118.95 58.63,118.95 57.85,118.17 56.2,118.17 55.86,117.84 55.58,117.84 55.45,117.71 55.45,117.33 55.58,117.2 56.11,117.2 56.38,116.93 56.99,116.93 57.59,116.34 57.59,115.09 57.46,114.96 57.05,114.96 56.7,115.32 56.7,116.06 56.57,116.18 55.76,116.18 55.63,116.06 v4(55.63,116)
  BOTTOM w0.127: v4(55.63,116) 55.63,116.03 55.76,116.16 56.52,116.16 56.64,116.04 56.64,115.25 57.21,114.67 MEM3.E3 ; v3(76.4,112.37) 76.4,112.92 v2(76.16,113.15)
MDA4: length 37.8
  TOP w0.127: v1(61.03,112.9) 60.33,112.9 v4(60.14,113.09) ; GPU1.G29 75.52,109.48 75.52,109.12 75.37,108.97 v4(75.14,108.97)
  L3 w0.165: v4(60.14,113.09) 60.92,113.09 61.96,114.13 63.74,114.13 63.9,114.29 63.9,114.42 64.07,114.58 64.4,114.58 64.56,114.42 64.56,114.29 64.73,114.13 65.06,114.13 65.22,114.29 65.22,114.42 65.39,114.58 65.72,114.58 65.88,114.42 65.88,114.29 66.05,114.13 66.38,114.13 66.54,114.29 66.54,114.42 66.71,114.58 67.04,114.58 67.2,114.42 67.2,114.29 67.37,114.13 67.95,114.13 68.51,113.57 68.79,113.57 69.02,113.8 69.02,116.11 69.14,116.23 69.55,116.23 69.68,116.11 69.68,113.87 69.8,113.74 70.52,113.74 70.64,113.87 70.64,116.11 70.77,116.23 71.34,116.23 71.73,115.84 71.73,115.61 71.35,115.22 71.35,114.71 71.48,114.58 71.65,114.58 71.86,114.38 71.86,113.87 71.99,113.74 73.74,113.74 74.09,113.4 74.09,113.31 74.22,113.18 74.22,110.39 74.78,109.83 75.37,109.83 75.57,109.63 75.57,109.4 v4(75.14,108.97)
  BOTTOM w0.127: v4(60.14,113.09) 60.46,113.09 60.58,112.96 60.58,112.63 60.46,112.5 59.97,112.5 59.85,112.37 59.85,112.09 59.72,111.97 59.39,111.97 59.26,112.09 59.26,112.33 59.14,112.46 58.44,112.46 MEM3.G2
MDA5: length 37.5
  TOP w0.127: v4(75.49,111.87) 74.98,111.35 74.98,110.86 75.06,110.78 75.06,109.66 GPU1.F28
  L3 w0.165: v4(75.49,111.87) 75.49,113.89 71.63,117.76 67.85,117.76 67.68,117.59 67.68,117.26 67.52,117.1 67.19,117.1 67.02,117.26 67.02,117.59 66.85,117.76 66.52,117.76 66.36,117.59 66.36,116.67 66.24,116.55 65.83,116.55 65.7,116.67 65.7,117.59 65.53,117.76 65.2,117.76 65.04,117.59 65.04,116.67 64.92,116.55 64.59,116.55 64.5,116.55 64.38,116.67 64.38,117.59 64.21,117.76 63.88,117.76 63.72,117.59 63.72,116.08 63.57,115.94 63.15,115.94 63.06,116.03 63.06,117.59 62.89,117.76 60.15,117.76 60,117.61 60,117.27 60.5,116.77 60.5,114.97 60.16,114.64 v4(60.16,114.53)
  BOTTOM w0.127: v4(75.49,111.87) 76.05,111.31 v2(76.14,111.31) ; MEM3.F2 58.4,114.06 59.69,114.06 v4(60.16,114.53)
MDA6: length 36.8
  TOP w0.127: GPU1.F32 74.6,111.32 v4(73.63,112.29)
  L3 w0.165: v4(73.63,112.29) 73.63,110.67 73.5,110.55 73.04,110.55 72.88,110.38 72.88,110.05 73.04,109.88 73.5,109.88 73.63,109.76 73.63,109.48 73.5,109.35 72.4,109.35 72.27,109.48 72.27,110.44 72.14,110.57 69.19,110.57 69.07,110.44 69.07,109.86 68.94,109.73 67.94,109.73 67.78,109.9 67.78,110.29 67.65,110.42 67.25,110.42 67.12,110.29 67.12,109.9 66.95,109.73 66.62,109.73 66.46,109.9 66.46,110.29 66.33,110.42 65.93,110.42 65.8,110.29 65.8,109.9 65.63,109.73 65.3,109.73 65.14,109.9 65.14,110.32 65.01,110.44 64.6,110.44 64.48,110.32 64.48,109.9 64.31,109.73 63.98,109.73 63.82,109.9 63.82,110.27 63.69,110.39 63.28,110.39 63.16,110.27 63.16,109.9 62.99,109.73 62.66,109.73 62.5,109.9 62.5,110.41 62.33,110.57 61.35,110.57 61.17,110.39 60,110.39 59.87,110.52 59.87,110.85 59.7,111.02 59.2,111.02 58.96,110.79 58.14,110.79 57.79,110.44 57.43,110.44 57.18,110.7 57.18,111.36 56.33,112.2 56.33,112.31 55.88,112.75 55.28,112.75 55.25,112.78 54.89,112.78 54.84,112.73 54.15,112.73 53.61,112.18 v4(53.61,111.67)
  BOTTOM w0.127: v2(73.59,111.48) 73.59,112.25 v4(73.63,112.29) ; v4(53.61,111.67) 53.61,111.69 MEM3.H8
MDA7: length 37.4
  TOP w0.127: v1(72.83,113.52) 72.83,112.76 v4(72.95,112.63) 72.95,112.37 74.19,111.13 74.19,110.41 GPU1.F30
  L3 w0.165: v4(72.95,112.63) 72.95,112.68 72.83,112.81 71.61,112.81 71.48,112.68 71.48,112.32 71.35,112.2 70.95,112.2 70.82,112.32 70.82,112.63 70.69,112.76 70.29,112.76 70.06,112.53 69.7,112.53 69.48,112.75 69.17,112.75 68.86,112.45 68.86,111.51 68.59,111.23 68.11,111.23 67.94,111.4 67.94,112.2 67.82,112.32 67.41,112.32 67.28,112.2 67.28,111.4 67.12,111.23 66.79,111.23 66.62,111.4 66.62,112.22 66.5,112.35 66.09,112.35 65.96,112.22 65.96,111.4 65.8,111.23 65.47,111.23 65.3,111.4 65.3,112.22 65.17,112.35 64.77,112.35 64.64,112.22 64.64,111.4 64.48,111.23 64.15,111.23 63.98,111.4 63.98,112.22 63.85,112.35 63.45,112.35 63.32,112.22 63.32,111.4 63.16,111.23 62.92,111.23 62.16,111.99 60.94,111.99 60.45,111.5 60.08,111.5 59.7,111.89 58.82,111.89 58.59,112.12 58.23,112.12 58.16,112.05 57.41,112.05 57.13,112.33 57.13,112.6 56.93,112.81 56.65,112.81 56.01,113.45 55.56,113.45 v4(55.53,113.48)
  BOTTOM w0.127: MEM3.H7 54.01,112.41 54.13,112.52 54.43,112.52 54.64,112.73 54.82,112.73 54.9,112.81 55.53,112.81 55.78,112.55 56.14,112.55 56.27,112.68 56.27,113.31 56.14,113.44 55.56,113.44 v4(55.53,113.48)
MDA8: length 34.6
  TOP w0.127: v4(69.4,111.84) 69.48,111.76 71.02,111.76 71.71,111.07 71.71,110.77 72.05,110.43 72.57,110.43 GPU1.C30
  BOTTOM w0.127: v4(69.4,111.84) v2(69.4,112.75) 69.4,113.65 69.03,114.02 69.03,114.25 68.72,114.56 68.72,115.08 62.88,120.93 62.88,120.96 62.84,120.96 62.25,121.56 54.36,121.56 51.42,118.61 51.42,116.31 52.02,115.71 53.4,115.71 53.83,115.28 MEM3.D7
MDA9: length 36.4
  TOP w0.127: GPU1.F27 74.57,108.4 v4(74.2,108.77)
  BOTTOM w0.127: v4(74.2,108.77) v2(73.44,109.53) 71.37,111.6 69.77,111.6 69.59,111.42 69.09,111.42 68.62,111.9 68.62,113.69 68.12,114.19 68.12,115.16 64.31,118.97 64.13,118.97 63.96,118.8 63.78,118.8 63.6,118.98 63.6,119.16 63.77,119.33 63.77,119.51 63.59,119.69 63.41,119.69 63.25,119.53 63.07,119.53 62.89,119.71 62.89,119.89 63.05,120.05 63.05,120.23 62.87,120.41 62.69,120.41 62.43,120.15 62.25,120.15 62.08,120.33 62.08,120.51 62.33,120.77 62.33,120.95 62.09,121.19 54.49,121.19 52,118.7 52,118.34 52.32,118.02 52.56,118.02 52.76,117.82 52.76,117.58 52.8,117.55 52.8,116.21 52.92,116.08 MEM3.C8
MDA10: length 35.2
  TOP w0.127: GPU1.A28 72.08,109.08 71.59,109.08 70.87,109.8 70.87,110.31 70.21,110.97 70.21,111.13 v4(70.21,111.13)
  BOTTOM w0.127: v4(70.21,111.13) 70.16,111.08 68.71,111.08 68,111.79 68,112.72 67.88,112.84 67.44,112.84 67.32,112.97 67.32,113.23 67.44,113.35 67.88,113.35 68,113.48 68,113.82 67.64,114.18 67.46,114.18 66.91,113.62 66.73,113.62 66.55,113.8 66.55,113.98 67.1,114.54 67.1,114.74 66.86,114.99 66.86,115.17 67.15,115.46 67.15,115.64 66.97,115.82 66.79,115.82 66.5,115.53 66.32,115.53 66.14,115.71 66.14,115.89 66.43,116.18 66.43,116.36 66.25,116.54 66.07,116.54 65.78,116.25 65.6,116.25 65.42,116.43 65.42,116.61 65.61,116.79 65.61,116.97 65.43,117.15 65.25,117.15 65.06,116.96 64.88,116.96 64.7,117.14 64.7,117.32 64.89,117.51 64.89,117.69 64.71,117.87 64.53,117.87 64.35,117.68 64.17,117.68 61.13,120.72 54.7,120.72 53.27,119.29 53.27,118.97 53.59,118.65 53.59,117.55 53.21,117.17 MEM3.B8
MDA11: length 35
  TOP w0.127: GPU1.C28 73,108.87 72.87,108.74 72.34,108.74 72.34,108.74 72.06,108.74 72.06,108.74 71.3,108.74 70.46,109.58 70.46,109.94 70.45,109.95 v4(70.45,110.08)
  BOTTOM w0.127: v4(70.45,110.08) 70.74,110.08 70.95,110.29 70.95,110.59 70.82,110.72 70.39,110.72 67.89,110.72 67.63,110.98 67.63,111.16 67.81,111.35 67.81,111.5 67.6,111.71 67.45,111.71 67.27,111.52 67.09,111.52 66.91,111.7 66.91,111.88 67.29,112.27 67.29,112.45 67.11,112.63 66.93,112.63 66.55,112.24 66.37,112.24 66.19,112.42 66.19,112.6 66.61,113.03 66.61,113.21 66.43,113.39 66.25,113.39 65.83,112.96 65.65,112.96 65.19,113.42 65.19,114.05 65.32,114.17 66.07,114.17 66.2,114.3 66.2,114.56 66.07,114.68 65.32,114.68 65.19,114.81 65.19,115.06 65.32,115.19 65.41,115.19 65.54,115.32 65.54,115.57 65.41,115.7 65.32,115.7 65.19,115.83 65.19,116.17 61.05,120.31 54.88,120.31 53.88,119.32 53.88,117.81 MEM3.A7
MDA12: length 36
  TOP w0.102: v4(69.85,108.01) 70.81,108.01 70.82,107.99 71.71,107.99 71.78,107.93 71.92,107.93 71.99,107.9 72.08,107.87 72.22,107.87 72.3,107.87 72.43,107.91 72.46,107.93 73.33,107.93 GPU1.E27
  BOTTOM w0.127: v4(69.85,108.01) 70.56,108.72 70.56,108.9 70.29,109.17 70.11,109.17 69.75,108.82 69.37,108.82 69.02,108.46 69.02,107.62 68.89,107.5 68.63,107.5 68.51,107.62 68.51,108.18 68.38,108.31 68.13,108.31 68,108.18 68,107.62 67.87,107.5 67.62,107.5 67.49,107.62 67.49,108.18 67.36,108.31 67.11,108.31 66.98,108.18 66.98,107.62 66.86,107.5 66.6,107.5 66.48,107.62 66.48,108.18 66.35,108.31 66.09,108.31 65.97,108.18 65.97,107.62 65.84,107.5 65.59,107.5 65.46,107.62 65.46,108.18 65.33,108.31 63.86,108.31 63.73,108.44 v2(63.73,108.54) 63,109.27 63,111.94 62.8,112.13 62.8,116.02 62.43,116.39 62.25,116.39 62.01,116.15 61.83,116.15 61.65,116.33 61.65,116.51 61.89,116.75 61.89,116.93 61.71,117.11 61.53,117.11 61.3,116.87 61.12,116.87 60.94,117.05 60.94,117.23 61.17,117.47 61.17,117.65 61,117.83 60.82,117.83 60.58,117.59 60.4,117.59 60.22,117.77 60.22,117.95 60.46,118.19 60.46,118.37 60.09,118.73 58.27,118.73 MEM3.A3
MDA13: length 36.2
  TOP w0.127: v4(75.79,108) 75.79,107.98 75.42,107.6 GPU1.G26
  BOTTOM w0.127: MEM3.A2 58.38,117.31 59.67,117.31 62.22,114.76 v2(62.22,113.3) 62.22,112.7 62.45,112.47 62.45,109.82 62.66,109.61 62.66,108.85 63.61,107.9 64.67,107.9 64.81,107.76 64.81,107.51 65.99,106.33 66.33,106.33 66.46,106.46 66.46,106.96 66.59,107.09 66.84,107.09 66.97,106.96 66.97,106.46 67.1,106.33 67.35,106.33 67.48,106.46 67.48,106.99 67.6,107.12 67.86,107.12 67.98,106.99 67.98,106.46 68.11,106.33 68.37,106.33 68.49,106.46 68.49,106.99 68.62,107.12 68.87,107.12 69,106.99 69,106.46 69.13,106.33 69.9,106.33 70.03,106.46 70.03,107.59 70.66,108.23 70.93,108.23 71.06,108.35 71.06,108.89 71.18,109.02 71.44,109.02 71.57,108.89 71.57,108.35 71.69,108.23 71.95,108.23 72.07,108.35 72.07,108.89 72.2,109.02 72.45,109.02 72.58,108.89 72.58,108.35 72.71,108.23 74.35,108.23 74.48,108.1 74.48,107.12 74.61,106.99 75.67,106.99 75.79,107.12 v4(75.79,108)
MDA14: length 36
  TOP w0.102: v4(70.87,107.5) 71.02,107.5 71.35,107.17 71.78,107.17 71.82,107.22 71.94,107.33 72.25,107.33 72.42,107.3 72.46,107.3 72.55,107.27 73.07,107.27 GPU1.D26
  BOTTOM w0.127: v4(70.87,107.5) 70.87,104.7 70.75,104.57 70.75,103.79 70.62,103.66 70.35,103.66 70.22,103.79 70.22,104.25 70.1,104.37 69.84,104.37 69.72,104.25 69.72,103.71 69.59,103.59 69.35,103.59 69.21,103.73 69.21,104.25 69.08,104.37 68.83,104.37 68.7,104.25 68.7,103.59 68.57,103.46 68.32,103.46 68.19,103.59 68.19,104.25 68.06,104.37 67.81,104.37 67.68,104.25 67.68,103.59 67.56,103.46 67.3,103.46 67.18,103.59 67.18,104.25 67.05,104.37 66.79,104.37 66.67,104.25 66.67,103.59 66.54,103.46 66.2,103.46 66.07,103.59 66.07,105.28 64.41,106.94 62.91,106.94 v2(61.65,108.2) 61.65,108.82 61.97,109.14 61.97,109.32 61.76,109.54 61.58,109.54 61.32,109.28 61.14,109.28 60.72,109.7 60.72,110.22 60.51,110.43 60.51,111.54 60.89,111.92 60.89,113.21 60.63,113.47 60.63,115 60.46,115.16 59.81,115.16 59.53,115.45 59.2,115.45 58.97,115.67 58.42,115.67 MEM3.C2
MDA15: length 36
  TOP w0.127: v4(73.92,107.37) 74.03,107.37 GPU1.F25
  BOTTOM w0.127: MEM3.C3 57.62,116.49 59.26,116.49 59.41,116.33 60.3,116.33 61.18,115.46 61.18,115.03 61.18,115.03 61.18,115.03 61.18,113.01 61.99,112.2 61.99,109.79 62.32,109.47 62.32,108.66 63.7,107.28 64.55,107.28 66.41,105.42 66.41,104.91 66.59,104.73 66.93,104.73 67.06,104.86 67.06,105.82 67.19,105.95 67.44,105.95 67.57,105.82 67.57,104.86 67.7,104.73 67.95,104.73 68.08,104.86 68.08,105.85 68.2,105.97 68.46,105.97 68.59,105.85 68.59,104.86 68.71,104.73 68.97,104.73 69.09,104.86 69.09,105.85 69.22,105.97 69.47,105.97 69.6,105.85 69.6,104.86 69.73,104.73 70.19,104.73 70.45,105 70.45,107.67 70.78,108 72.23,108 72.58,107.65 v2(72.6,107.65) 73.7,107.65 73.92,107.43 v4(73.92,107.37)
MDA16: length 35.9
  TOP w0.102: MEM1.A2 53.67,118.14 53.67,119.6
  TOP w0.127: 53.67,119.6 55.72,121.65 v1(56.4,121.65) 57.08,121.65 57.31,121.42 61.27,121.42 61.55,121.42 61.55,121.42 62.18,121.42 68.48,115.12 68.48,113.77 68.35,113.64 68.2,113.64 68.08,113.51 68.08,113.26 68.2,113.13 68.35,113.13 68.48,113 68.48,112.75 68.35,112.62 68,112.62 67.87,112.5 67.87,112.24 68,112.11 68.35,112.11 68.48,111.99 68.48,111.73 68.35,111.61 68,111.61 67.87,111.48 67.87,111.23 68,111.1 68.35,111.1 68.48,110.97 68.48,110.72 68.35,110.59 68,110.59 67.87,110.46 67.87,110.21 68,110.08 68.35,110.08 68.48,109.96 68.48,109.7 68.35,109.57 68,109.57 67.87,109.45 67.87,109.19 68,109.07 68.35,109.07 68.48,108.94 68.48,108.25 69.93,106.8 70.8,106.8 70.87,106.73 71.96,106.73 71.97,106.73 72.13,106.73 GPU1.A25
MDA17: length 36.1
  TOP w0.102: 53.34,118.6 53.09,118.34 53.02,118.34 52.89,118.22 52.89,117.82 52.88,117.82 52.88,117.54 52.89,117.54 52.89,117.45 53.02,117.33 53.4,117.33 53.65,117.08 53.65,116.51 MEM1.C2 ; 71.56,106.96 71.85,106.96 71.96,107.07 72.02,107.13 72.23,107.13 72.38,107.1 72.41,107.1 72.81,106.99 GPU1.C25
  TOP w0.127: 71.56,106.96 70.98,106.96 70.9,107.04 70.18,107.04 69.65,107.56 69.65,107.56 68.95,108.27 68.95,115.24 61.97,122.22 59.35,122.22 v1(59.34,122.22) 59.33,122.22 55.46,122.22 53.33,120.08 53.33,119.46 53.34,119.45 53.34,118.6
MDA18: length 36.6
  TOP w0.102: GPU1.E25 73.73,106.8 73.32,106.39 71.79,106.39 71.67,106.51 71.34,106.51 71.33,106.5 70.41,106.5
  TOP w0.127: MEM1.A3 54.01,118.19 54.14,118.32 54.18,118.32 54.28,118.42 54.28,119.72 54.51,119.96 54.69,119.96 54.84,119.81 55.02,119.81 55.2,119.99 55.2,120.17 55.05,120.32 55.05,120.5 55.63,121.07 61.41,121.07 61.97,121.07 67.82,115.22 v1(67.82,114.39) 67.53,114.1 67.53,111.32 67.4,111.19 66.71,111.19 66.58,111.07 66.58,110.81 66.71,110.68 67.4,110.68 67.53,110.56 67.53,110.3 67.4,110.18 66.71,110.18 66.58,110.05 66.58,109.8 66.71,109.67 67.4,109.67 67.53,109.54 67.53,108.59 68.83,107.29 68.87,107.29 69.66,106.51 70.41,106.51 70.41,106.5
MDA19: length 36.6
  TOP w0.102: 71.33,105.67 71.65,105.67 71.75,105.77 72.33,105.77 72.38,105.74 72.46,105.7 72.58,105.66 72.72,105.68 72.8,105.74 72.93,105.79 73,105.86 73.31,106 GPU1.D24
  TOP w0.127: MEM1.C3 54.01,116.35 55.17,117.5 55.17,118.16 55.81,118.8 55.81,118.98 55.31,119.47 55.31,119.62 55.43,119.74 55.86,119.74 56.07,119.53 56.41,119.53 56.59,119.71 56.59,120.04 56.47,120.17 56.01,120.17 55.89,120.3 55.89,120.6 56.01,120.73 61.83,120.73 67.19,115.37 67.19,111.74 66.98,111.53 66.56,111.53 66.16,111.13 66.16,109.73 66.85,109.03 v1(66.92,109.03) 66.92,108.71 69.4,106.24 70.77,106.24 71.33,105.67
MDA20: length 36.3
  TOP w0.102: GPU1.E23 73.35,104.75 72.52,104.75 72.47,104.71 72.4,104.67 72.39,104.67 71.92,104.67 71.78,104.81 70.23,104.81
  TOP w0.127: 70.23,104.81 69.62,104.81 69.58,104.77 67.98,104.77 67.47,105.27 67.29,105.27 66.74,104.72 66.56,104.72 66.38,104.9 66.38,105.08 66.93,105.63 66.93,105.81 66.76,105.99 66.58,105.99 66.2,105.62 66.02,105.62 65.84,105.8 65.84,105.97 66.22,106.35 66.22,106.53 66.04,106.71 65.86,106.71 65.48,106.33 65.3,106.33 65.12,106.51 65.12,106.69 65.5,107.07 65.5,107.25 65.32,107.43 65.14,107.43 64.76,107.05 64.58,107.05 64.41,107.23 64.41,107.41 64.78,107.79 64.78,107.97 64.65,108.1 64.65,108.45 64.52,108.58 63.96,108.58 63.81,108.73 63.81,109.54 63.96,109.69 64.52,109.69 64.65,109.82 64.65,113.65 64.65,114.22 v1(64.99,114.56) 65.33,114.9 65.33,115.09 65.05,115.37 63.92,115.37 61.02,118.28 61.02,118.93 60.78,119.16 58.07,119.16 57.11,118.2 57.11,117.79 MEM1.A7
MDA21: length 36.9
  TOP w0.102: MEM1.D7 57.21,115.61 56.92,115.91 56.92,115.91 56.7,116.13 ; GPU1.F23 74.27,105.53 72.98,105.53 arc(72.83,105.5) 72.7,105.41 72.47,105.41 72.38,105.51 72.31,105.55 71.81,105.55 71.68,105.42 71.23,105.42 70.77,105.87 70.16,105.87
  TOP w0.127: 70.16,105.87 70.14,105.89 69.26,105.89 68.81,106.34 68.63,106.34 68.42,106.14 68.26,106.14 68.06,106.33 68.06,106.5 68.27,106.7 68.27,106.88 68.09,107.06 67.91,107.06 67.7,106.86 67.54,106.86 67.35,107.05 67.35,107.22 67.55,107.42 67.55,107.6 66.65,108.5 66.47,108.5 66.36,108.38 66.18,108.38 66,108.56 66,108.74 66.11,108.86 66.11,109.04 65.82,109.33 65.82,111.6 v1(65.98,111.76) 66.1,111.88 66.37,111.88 66.78,112.3 66.78,115.29 61.74,120.33 57.78,120.33 55.77,118.32 55.77,117.76 55.77,117.76 55.77,117.36 56.57,116.56 56.57,116.26 56.7,116.13
MDA22: length 37.1
  TOP w0.102: 70.62,104.37 71,103.99 71.33,103.99 71.35,104.01 71.85,104.01 71.98,104.13 72.15,104.13 72.36,104.13 72.54,104.06 72.66,104.06 72.79,104.11 72.85,104.17 73.17,104.17 GPU1.D22
  TOP w0.127: 70.62,104.37 65.94,104.37 65.78,104.54 65.78,104.87 65.89,104.98 65.89,105.16 65.71,105.34 65.53,105.34 65.48,105.29 65.3,105.29 65.12,105.47 65.12,105.65 65.17,105.7 65.17,105.88 64.99,106.06 64.81,106.06 64.77,106.01 64.59,106.01 64.41,106.19 64.41,106.37 64.45,106.42 64.45,106.6 63.89,107.17 v1(63.89,107.79) 63.89,108.16 63.1,108.95 63.1,109.91 63.31,110.13 64.14,110.13 64.27,110.25 64.27,110.55 64.14,110.67 63.37,110.67 63.24,110.8 63.24,111.06 63.37,111.18 64.17,111.18 64.29,111.31 64.29,111.56 64.17,111.69 63.37,111.69 63.24,111.82 63.24,112.07 63.37,112.2 64.17,112.2 64.29,112.33 64.29,112.58 64.17,112.71 63.37,112.71 63.24,112.83 63.24,113.09 63.37,113.21 64.17,113.21 64.29,113.34 64.29,114.51 60,118.8 58.03,118.8 57.65,118.42 57.65,118.17 57.77,118.05 58.17,118.05 58.39,117.82 58.39,117.32 58.01,116.94 MEM1.B8
MDA23: length 37.7
  TOP w0.102: 70.74,103.87 70.81,103.79 71.42,103.79 71.43,103.8 71.94,103.8 72.06,103.93 72.32,103.93 arc(72.4,103.87) 72.5,103.85 72.7,103.85 arc(72.74,103.86) 72.77,103.86 arc(72.83,103.89) 72.88,103.93 74.27,103.93 GPU1.F21
  TOP w0.127: 70.74,103.87 70.56,104.04 69.55,104.04 69.54,104.03 65.16,104.03 65.03,104.16 65.03,104.83 64.9,104.96 64.65,104.96 64.52,104.83 64.52,104.16 64.39,104.03 64.14,104.03 64.01,104.16 64.01,105.47 63.89,105.59 63.63,105.59 63.51,105.47 63.51,104.16 63.38,104.03 63.04,104.03 62.76,104.31 62.76,106.62 62.88,106.75 63.42,106.75 63.54,106.88 63.54,107.15 63.43,107.26 62.88,107.26 62.76,107.39 62.76,107.64 62.88,107.77 63.18,107.77 63.3,107.89 63.3,108.15 63.18,108.28 62.88,108.28 62.76,108.4 62.76,113.14 v1(63.59,113.97) 63.59,114.72 62.18,116.14 62,116.14 61.64,115.78 61.46,115.78 61.18,116.06 61.18,116.24 61.5,116.57 61.5,116.75 61.21,117.05 61.03,117.05 60.55,116.57 60.1,116.57 59.91,116.37 59.43,116.37 59.34,116.46 58.66,116.46 58.28,116.08 MEM1.C8
MDA24: length 35.1
  TOP w0.127: v4(74.14,103.14) 73.8,103.48 GPU1.E21 ; v4(53.61,113.29) 53.21,112.89 MEM1.G2
  L4 w0.165: v4(53.61,113.29) 54.06,113.73 54.06,115.88 54.65,116.47 54.65,116.76 56.33,118.45 58.01,118.45 58.58,117.88 59.21,117.88 59.22,117.87 62.53,117.87 68.56,111.84 68.56,111.41 69.11,110.86 69.11,109.14 69.41,108.84 70.89,108.84 72.14,107.59 72.14,106.77 73.51,105.39 73.51,103.77 v4(74.14,103.14)
  BOTTOM w0.127: v4(74.14,103.14) 73.47,103.14 v2(73.39,103.23)
MDA25: length 35.3
  TOP w0.127: v4(73.91,102.58) 73.69,102.8 GPU1.D20 ; v4(53.61,114.88) MEM1.E3
  L4 w0.165: v4(73.91,102.58) 74.33,102.58 74.63,102.87 74.63,104.02 74.53,104.12 74.53,106.11 71.21,109.43 70.43,109.43 70.01,109.85 70.01,110.51 68.94,111.59 68.94,112.17 68.28,112.84 64.39,116.73 62.36,118.75 58.95,118.75 58.95,118.75 58.58,118.75 58.58,118.75 56.26,118.75 53.61,116.1 v4(53.61,114.88)
  BOTTOM w0.127: v4(73.91,102.58) 73.49,102.15 v2(73.49,101.96)
MDA26: length 36.5
  TOP w0.127: GPU1.F19 73.96,101.36 v4(73.96,101.17) ; v4(54.66,113.16) 54.66,112.73 MEM1.H3
  L4 w0.165: v4(73.96,101.17) 72.93,102.2 72.93,103.89 71.07,105.75 71.07,106.09 68.61,108.55 68.61,110.82 68.18,111.25 68.18,111.54 62.16,117.56 58.13,117.56 57.51,118.18 56.44,118.18 55.05,116.79 55.05,116.29 54.46,115.7 54.46,115.11 54.37,115.03 54.37,114.66 54.66,114.37 v4(54.66,113.16)
  BOTTOM w0.127: v2(73.31,100.74) 73.75,101.17 v4(73.96,101.17)
MDA27: length 34.9
  TOP w0.127: MEM1.F2 53.58,114.04 54.09,114.04 54.39,114.35 54.39,115.02 54.48,115.1 54.48,115.66 55.4,116.59 55.48,116.59 v4(55.49,116.6) ; v4(70.18,101.64) 70.19,101.65 70.44,101.65 70.81,102.02 71.16,102.02 71.16,102.02 72.18,102.02 GPU1.A19
  L4 w0.165: v4(70.18,101.64) 70.19,101.65 70.33,101.65 70.9,102.21 72.24,102.21 72.42,102.39 72.42,102.75 72.22,102.95 71.94,102.95 71.73,103.15 71.73,104.5 70.58,105.66 70.58,105.88 68.13,108.34 68.13,110.76 67.49,111.4 67.49,111.54 61.8,117.23 58.27,117.23 57.88,116.84 55.73,116.84 v4(55.49,116.6)
MDA28: length 35.9
  TOP w0.102: v4(71.07,101.59) 71.29,101.81 71.92,101.81 72.06,101.67 73.22,101.67 73.4,101.49 GPU1.D18
  TOP w0.127: v4(60.27,111.94) 60.12,111.79 59.74,111.79 59.09,112.44 58.38,112.44 MEM1.H8
  L4 w0.165: v4(71.07,101.59) 70.69,101.2 69.6,101.2 69.32,100.93 66.93,100.93 66.06,101.79 64.36,101.79 64.19,101.95 64.19,102.3 64.36,102.46 65.88,102.46 66.05,102.63 66.05,102.96 65.88,103.12 64.58,103.12 64.45,103.26 64.45,103.64 64.58,103.78 65.88,103.78 66.05,103.95 66.05,104.28 65.88,104.45 64.64,104.45 64.47,104.61 64.47,104.94 64.64,105.11 65.45,105.11 65.61,105.27 65.61,105.65 65.09,106.17 64.86,106.17 64.56,105.87 64.32,105.87 64.09,106.1 64.09,106.33 64.39,106.64 64.39,106.87 64.16,107.11 63.93,107.11 63.47,106.65 63.24,106.65 63,106.88 63,107.12 63.46,107.57 63.46,107.81 61.41,109.85 61.41,111.14 60.97,111.59 60.62,111.59 v4(60.27,111.94)
  BOTTOM w0.127: v4(71.07,101.59) 71.07,101.6 v2(71.66,102.18)
MDA29: length 36.4
  TOP w0.102: v4(69.49,101.64) 68.88,101.03 68.88,100.85 69.09,100.64 69.27,100.64 69.8,101.17 71.28,101.17 71.52,100.93 72.33,100.93 72.35,100.92 72.43,100.91 72.43,100.9 72.45,100.9 72.45,100.89 72.46,100.89 72.52,100.87 73.69,100.87 73.83,100.73 74.27,100.73 GPU1.F17
  TOP w0.127: v4(56.01,113.88) 56.27,113.63 56.27,113.12 56.14,112.99 55.63,112.99 55.5,112.87 55.5,112.62 55.63,112.49 56.24,112.49 56.37,112.36 56.37,112.21 56.5,112.08 MEM1.H7
  L4 w0.165: v4(69.49,101.64) 69.49,101.64 69.04,101.19 68.45,101.19 68.28,101.36 68.28,101.79 68.12,101.96 67.79,101.96 67.62,101.79 67.62,101.49 67.46,101.33 67.07,101.33 66.52,101.88 66.52,102.85 66.72,103.05 66.72,103.52 66.52,103.73 66.52,104.17 66.72,104.37 66.72,104.84 66.52,105.05 66.52,105.43 63,108.94 63,109.83 62.77,110.07 62.53,110.07 62.28,109.82 62.05,109.82 61.86,110.01 61.86,111.09 61.86,111.28 60.76,112.38 60.08,112.38 59.55,111.84 58.94,111.84 58.58,112.2 58.07,112.2 57.92,112.05 57.03,112.05 56.83,112.25 56.83,112.58 56.56,112.84 56.23,112.84 56.01,113.06 v4(56.01,113.88)
MDA30: length 34.8
  TOP w0.102: 70.31,100.51 72.09,100.51 GPU1.A17
  TOP w0.127: v4(67.75,102.82) 65.05,102.82 64.93,102.7 64.93,102.14 65.05,102.01 67.19,102.01 67.35,101.85 67.35,100.32 67.68,99.99 67.68,99.99 67.79,99.89 69.49,99.89 70.11,100.51 70.31,100.51 ; v4(56.62,114.49) 56.81,114.31 56.85,114.31 57.21,113.94 MEM1.F7
  L4 w0.165: v4(56.62,114.49) 56.62,114.5 57.12,114.5 57.2,114.42 57.57,114.42 57.74,114.26 57.74,113.88 57.9,113.72 58.23,113.72 58.4,113.88 58.4,114.26 58.56,114.42 59.15,114.42 59.68,113.89 60.35,113.89 60.75,114.29 60.98,114.29 61.27,114 61.27,113.77 61.08,113.58 61.08,113.2 63.17,111.11 63.77,111.11 66.34,108.54 66.34,107.75 68.15,105.94 68.15,103.22 v4(67.75,102.82)
MDA31: length 34.9
  TOP w0.102: GPU1.C17 72.86,100.54 72.7,100.54 72.37,100.69 72.35,100.71 72.3,100.72 72.28,100.73 71.35,100.73 71.24,100.85 69.95,100.85
  TOP w0.127: 69.95,100.85 69.44,100.33 67.82,100.33 67.7,100.46 67.7,101.48 67.86,101.64 v4(68.81,101.64) ; MEM1.F8 v4(58.41,113.28)
  L4 w0.165: v4(68.81,101.64) 68.79,101.67 68.79,102.09 68.52,102.36 67.55,102.36 67.19,102.73 67.19,103.54 67.35,103.71 67.61,103.71 67.77,103.87 67.77,104.21 67.61,104.37 67.35,104.37 67.19,104.53 67.19,104.86 67.35,105.03 67.61,105.03 67.77,105.19 67.77,105.79 67.5,106.05 67.24,106.05 67.03,105.84 66.79,105.84 66.42,106.21 66.42,106.45 66.65,106.68 66.65,106.86 66.36,107.16 66.13,107.16 65.91,106.94 65.67,106.94 65.44,107.17 65.44,107.41 65.95,107.92 65.95,108.15 65.72,108.38 65.48,108.38 64.97,107.88 64.74,107.88 64.51,108.11 64.51,108.34 65.14,108.98 65.14,109.2 64.9,109.45 64.68,109.45 64.04,108.81 63.81,108.81 63.57,109.04 63.57,109.28 64.18,109.89 64.18,110.12 63.92,110.38 63.67,110.38 63.51,110.22 63.18,110.22 62.87,110.52 62.44,110.52 62.24,110.72 62.24,111.48 61.07,112.65 59.84,112.65 59.51,112.32 59.03,112.32 58.41,112.94 v4(58.41,113.28)
MDA32: length 36.1
  TOP w0.102: GPU1.E17 73.48,100.08 73.15,100.08 73.14,100.07 72.88,100.07 72.85,100.08 72.84,100.1 72.69,100.13 72.68,100.13 72.41,100.13 72.38,100.12 72.38,100.12 72.28,100.07 72.07,100.07 72,100.14 72,100.14 71.85,100.28 71.37,100.28 71.35,100.26 70.44,100.26 69.35,99.17 v3(69.35,99.12)
  L4 w0.165: v3(69.35,99.12) 68.93,98.7 65.47,98.7 65.2,98.43 65.2,98.2 65.44,97.96 65.44,97.72 65.21,97.49 64.97,97.49 64.73,97.73 64.5,97.73 64.05,97.29 64.05,96.86 64.22,96.7 64.71,96.7 64.88,96.53 64.88,96.2 64.71,96.04 64.22,96.04 64.05,95.87 64.05,95.54 64.22,95.38 64.72,95.38 64.89,95.22 64.89,94.88 64.72,94.72 64.22,94.72 64.05,94.55 64.05,94.22 64.22,94.06 64.7,94.06 64.86,93.89 64.86,93.56 64.7,93.4 64.22,93.4 64.05,93.23 64.05,92.94 63.78,92.67 63.78,92.44 64.54,91.68 64.54,91.45 64.3,91.22 64.07,91.22 63.31,91.97 63.08,91.97 62.85,91.74 62.85,91.51 63.6,90.75 63.6,90.52 63.36,90.29 63.13,90.29 62.38,91.04 62.15,91.04 61.91,90.81 61.91,90.57 62.64,89.85 62.64,89.61 62.41,89.38 62.17,89.38 61.43,90.12 61.19,90.12 60.54,89.47 v4(60.16,89.47)
  BOTTOM w0.127: v4(60.16,89.47) 59.42,89.47 59.15,89.19 58.57,89.19 58.14,89.62 MEM4.F8 ; v3(69.35,99.12) 69.35,99.52 v2(69.02,99.85)
MDA33: length 35.1
  TOP w0.102: GPU1.D16 72.98,99.8 72.78,99.89 72.65,99.93 72.47,99.93 72.34,99.87 72.3,99.86 71.99,99.86 71.79,100.06 70.58,100.06 70.35,99.82 v4(70.35,99.56)
  L4 w0.165: v4(70.35,99.56) 70.28,99.63 64.43,99.63 64.26,99.46 64.26,98.88 64.07,98.69 63.85,98.69 62.98,99.55 62.75,99.55 62.51,99.31 62.51,99.08 63.05,98.54 63.05,93.27 61.54,91.76 60.99,91.76 60.83,91.6 60.83,91.38 60.66,91.22 60.33,91.22 60.16,91.38 60.16,91.6 60,91.76 v3(59.35,91.76)
  BOTTOM w0.127: MEM4.H8 58.41,91.62 58.41,92.36 58.51,92.45 59.08,92.45 59.41,92.78 59.59,92.78 59.78,92.58 59.96,92.58 60.14,92.76 60.14,92.94 59.95,93.14 59.95,93.32 60.12,93.5 60.3,93.5 60.5,93.3 60.68,93.3 60.86,93.48 60.86,93.66 60.66,93.86 60.66,94.04 60.93,94.31 61.11,94.31 61.59,93.83 61.59,93.31 v2(60.91,92.64) 60.13,91.85 60.13,91.47 60,91.34 59.48,91.34 59.35,91.47 v3(59.35,91.76)
MDA34: length 36.6
  TOP w0.102: GPU1.F15 74.27,99.13 71.42,99.13
  TOP w0.127: v4(70.96,99.59) 71.42,99.13
  L4 w0.165: v4(70.96,99.59) 70.78,99.42 70.78,99.38 69.7,98.29 66.55,98.29 65.27,97 65.27,93.17 64.95,92.85 64.66,92.85 64.5,92.69 64.5,92.35 64.66,92.18 65.1,92.18 65.27,92.02 65.27,91.64 62.25,88.63 62.02,88.63 61.3,89.35 61.06,89.35 60.83,89.11 60.83,88.88 61.55,88.16 61.55,87.93 61.11,87.48 60.01,87.48 58.25,89.24 57.24,89.24 56.93,89.55 56.22,89.55 v4(56.05,89.72)
  BOTTOM w0.127: v4(56.05,89.72) 55.93,89.84 55.21,89.84 55.04,89.67 55.04,89.08 55.16,88.96 56.79,88.96 57.21,89.38 MEM4.F7 ; v2(70.77,100.36) 70.96,100.18 v4(70.96,99.59)
MDA35: length 36.4
  TOP w0.127: v4(68.56,99.17) 67.12,99.17 66.74,99.55 66.74,101.35 66.62,101.48 64.95,101.48 64.83,101.35 64.83,100.99 64.95,100.87 65.97,100.87 66.1,100.74 66.1,99.09 66.63,98.56 69.7,98.56 69.97,98.83 71.81,98.83 71.84,98.8 GPU1.A15
  L4 w0.165: v4(68.56,99.17) 68.51,99.22 65.3,99.22 63.52,97.44 63.52,93.07 60.35,89.9 59.41,89.9 59.09,89.58 57.43,89.58 57.14,89.86 57.14,90.17 56.69,90.62 v4(56.65,90.62)
  BOTTOM w0.127: v4(68.56,99.17) 68.56,98.71 v2(68.82,98.45) ; v4(56.65,90.62) 56.65,90.68 57.2,91.22 MEM4.H7
MDA36: length 35.6
  TOP w0.127: v4(73.9,97.75) 73.65,98 GPU1.D14
  L4 w0.165: v4(73.9,97.75) 72.38,97.75 70.9,96.27 69.83,96.27 69.49,96.61 67.47,96.61 67.16,96.29 67.16,89.71 62.42,84.98 56.87,84.98 56.08,85.76 56.08,86.23 55.8,86.51 55.68,86.51 54.64,87.55 54.64,88.17 54.07,88.75 54.07,89.91 54.05,89.93 54.05,90.38 v4(53.61,90.82)
  BOTTOM w0.127: v4(53.61,90.82) MEM4.H3 ; v4(73.9,97.75) v2(73.16,97.75)
MDA37: length 35.3
  TOP w0.127: GPU1.F13 74.6,97.05 v4(74,96.45)
  L4 w0.165: v4(74,96.45) 73.02,95.47 73.02,92.27 70.39,89.64 69.6,89.64 63.52,83.56 56.79,83.56 53.25,87.1 53.25,87.43 53.25,87.43 53.25,87.8 52.73,88.32 52.73,89.13 v4(53.61,90.01)
  BOTTOM w0.127: v2(74.56,95.86) 74,96.42 v4(74,96.45) ; v4(53.61,90.01) 53.21,90.41 MEM4.G2
MDA38: length 35
  TOP w0.102: 70.13,97.11 70.5,97.11 70.5,97.11 71.04,97.11 71.14,97.21 71.98,97.21 72,97.2
  TOP w0.127: v1(66.8,96.12) 67.64,96.12 v4(67.64,96.12) 68.06,95.7 68.73,95.7 70.13,97.11 ; 72,97.2 GPU1.A13
  L4 w0.165: v4(67.64,96.12) 67.64,95.16 67.81,95 68.29,95 68.42,94.87 68.42,94.46 68.29,94.34 67.81,94.34 67.64,94.17 67.64,93.84 67.81,93.67 68.33,93.67 68.46,93.55 68.46,93.14 68.33,93.01 67.81,93.01 67.64,92.85 67.64,92.52 67.81,92.35 68.33,92.35 68.46,92.23 68.46,91.82 68.33,91.69 67.81,91.69 67.64,91.53 67.64,89.52 62.62,84.51 56.75,84.51 55.62,85.64 v4(55.62,86.07)
  BOTTOM w0.127: MEM4.E3 54.51,88.33 54.51,87.68 55.56,86.63 55.56,86.13 v4(55.62,86.07)
MDA39: length 35.2
  TOP w0.102: GPU1.C13 72.67,97.53 72.06,97.53 71.95,97.42 70.9,97.42 70.81,97.33 69.68,97.33
  TOP w0.127: v1(68.53,97.06) 68.46,96.98 v4(68.46,96.14) 68.49,96.14 69.68,97.33
  L4 w0.165: v4(68.46,96.14) 69.58,95.03 69.58,91.14 68.38,89.95 68.38,89.3 63.11,84.03 56.85,84.03 53.71,87.17 53.71,87.73 53.2,88.24 53.2,88.79 v4(53.62,89.22)
  BOTTOM w0.127: v4(53.62,89.22) MEM4.F2
MDA40: length 36.8
  TOP w0.127: MEM2.C3 57.12,87.12 56.1,87.12 55.98,87.25 55.98,87.53 55.76,87.74 55.33,87.74 54.87,87.28 54.87,86.96 55.32,86.51 56.21,86.51 56.34,86.38 56.34,85.8 56.16,85.62 55.51,85.62 55.23,85.34 55.23,84.79 55.59,84.43 55.59,84.17 55.72,84.04 56.14,84.04 56.26,84.17 56.26,84.34 56.37,84.45 56.74,84.45 56.85,84.34 56.85,84.17 56.97,84.04 57.45,84.04 57.57,84.17 57.57,84.3 57.7,84.43 58.15,84.43 58.5,84.07 60.62,84.07 61.08,84.53 61.08,85.23 61.53,85.69 61.91,85.69 62.59,86.37 v1(62.59,87.45) 62.59,89.18 63.52,90.11 63.52,90.86 63.71,91.06 63.71,91.37 63.52,91.57 63.52,91.88 63.71,92.07 63.71,92.39 63.52,92.58 63.52,93.03 63.92,93.43 64.68,93.43 64.8,93.31 64.8,93.3 64.93,93.17 65.18,93.17 65.31,93.3 65.31,93.31 65.44,93.43 65.69,93.43 65.82,93.31 65.82,93.3 65.95,93.17 66.2,93.17 66.33,93.3 66.33,93.31 66.45,93.43 66.8,93.43 67.35,93.98 69.55,93.98 70.92,95.36 71.95,95.36 72.05,95.26 73.46,95.26 GPU1.E11
MDA41: length 36.4
  TOP w0.102: GPU1.A11 72.19,95.59 72.03,95.59 72.01,95.57 70.63,95.57 70.62,95.56
  TOP w0.127: MEM2.A3 57.21,85.61 56.56,85.61 56.44,85.48 56.44,85.48 56.31,85.35 55.84,85.35 55.71,85.22 55.71,84.86 55.84,84.73 57.4,84.73 57.53,84.86 57.53,85.11 57.66,85.24 57.99,85.24 58.12,85.11 58.12,84.79 58.6,84.3 58.98,84.3 59.15,84.48 59.15,84.53 59.33,84.71 59.69,84.71 59.87,84.53 59.87,84.48 60.04,84.3 60.52,84.3 60.8,84.58 60.8,85.74 61.28,86.22 61.69,86.22 61.99,86.52 61.99,88.55 62.22,88.78 62.22,89.02 62.22,89.02 62.22,89.89 62.38,90.06 62.94,90.06 63.1,90.21 63.1,90.6 62.92,90.78 62.38,90.78 62.23,90.93 62.23,91.31 62.41,91.49 62.92,91.49 63.1,91.67 63.1,92.02 62.92,92.2 v1(61.99,92.2) 61.38,92.2 61.26,92.33 61.26,92.78 61.38,92.91 61.61,92.91 61.74,93.04 61.74,94.13 61.87,94.25 62.32,94.25 62.45,94.13 62.45,93.26 62.58,93.13 62.92,93.13 63.05,93.26 63.05,94.06 63.18,94.18 63.62,94.18 63.74,94.06 63.74,93.9 63.86,93.78 66.61,93.78 67.16,94.33 69.39,94.33 70.62,95.56
MDA42: length 36.2
  TOP w0.102: 70.31,95.76 70.34,95.79 71.92,95.79 72.06,95.93 72.31,95.93 72.36,95.91 72.67,95.6 GPU1.C11
  TOP w0.127: 70.31,95.76 69.22,94.67 66.42,94.67 v1(66.1,94.35) 65.97,94.23 65.42,94.23 65.26,94.39 65.26,94.67 65.02,94.91 64.68,94.91 64.55,95.03 64.55,95.37 64.42,95.5 64.17,95.5 64.04,95.37 64.04,94.82 63.92,94.69 63.66,94.69 63.53,94.82 63.53,95.37 63.41,95.5 63.15,95.5 63.03,95.37 63.03,95.03 62.9,94.91 62.65,94.91 62.52,95.03 62.52,95.37 62.39,95.5 62.14,95.5 62.01,95.37 62.01,95.04 61.88,94.91 61.04,94.91 60.81,94.69 60.81,94.38 60.91,94.28 61.23,94.28 61.37,94.14 61.37,93.72 61.23,93.57 60.92,93.57 60.81,93.46 60.81,91.87 61.01,91.67 61.51,91.67 61.68,91.5 61.68,89 61.51,88.83 61.08,88.83 60.98,88.72 60.98,88.34 61.08,88.24 61.37,88.24 61.45,88.16 61.45,87.65 61.37,87.57 60.57,87.57 60.27,87.28 60.27,87.13 60.46,86.95 60.9,86.95 61.01,86.84 61.01,86.38 60.9,86.27 60.64,86.27 60.52,86.15 60.52,84.85 60.42,84.75 60.11,84.75 59.89,84.97 59.89,85.94 59.77,86.05 59.3,86.05 59.18,85.94 59.18,84.96 58.92,84.69 58.67,84.69 58.41,84.96 58.41,85.49 58.28,85.62 MEM2.A2
MDA43: length 36.9
  TOP w0.102: GPU1.F11 74.22,95.98 72.61,95.98 72.51,96.07 72.44,96.1 72.43,96.1 72.41,96.11 72.34,96.13 71.96,96.13 71.82,95.99 71.13,95.99 71.12,96.01 70.35,96.01
  TOP w0.127: MEM2.C2 57.83,87.22 57.71,87.1 57.71,86.96 57.85,86.81 58.14,86.81 58.3,86.66 58.45,86.66 58.6,86.81 59.41,86.81 60.7,88.1 60.7,88.84 61.22,89.37 61.22,91.07 60.53,91.75 60.53,94.86 60.96,95.29 61.25,95.29 61.49,95.53 v1(61.49,96.06) 61.49,96.37 61.33,96.53 60.88,96.53 60.75,96.39 60.75,96.23 60.62,96.11 60.24,96.11 60.11,96.23 60.11,96.74 60.48,97.11 62.22,97.11 62.35,96.98 62.35,95.97 62.47,95.84 62.86,95.84 62.98,95.97 62.98,97 63.11,97.12 63.5,97.12 63.62,97 63.62,96 63.78,95.84 64.17,95.84 64.33,96 64.33,96.77 64.46,96.89 64.91,96.89 65.04,96.77 65.04,95.53 65.55,95.01 69.06,95.01 70.05,96.01 70.35,96.01
MDA44: length 35.8
  TOP w0.102: 70.25,93.62 70.5,93.87 70.69,93.87 70.94,94.12 72.08,94.12 GPU1.A9
  TOP w0.127: 70.25,93.62 69.84,93.21 69.84,93.19 69.47,92.82 68.08,92.82 66.67,91.41 66.49,91.41 66.14,91.77 65.96,91.77 65.78,91.59 65.78,91.41 66.13,91.05 66.13,90.87 65.95,90.69 65.77,90.69 65.42,91.05 65.24,91.05 65.06,90.87 65.06,90.69 65.41,90.34 65.41,90.16 v1(65.16,89.9) 64.9,89.64 64.9,89.12 65.03,88.99 65.3,88.99 65.43,88.87 65.43,88.61 65.3,88.48 65.03,88.48 64.9,88.36 64.9,83.93 64.18,83.21 62.84,83.21 62.68,83.05 57.05,83.05 56.92,82.92 56.92,82.62 56.8,82.49 56.34,82.49 56.21,82.62 56.21,82.92 56.08,83.05 55.63,83.05 55.5,82.92 55.5,82.67 55.35,82.52 54.92,82.52 54.79,82.64 54.79,83.31 54.62,83.48 54.62,84.01 54.43,84.19 54.19,84.19 54.09,84.09 54.09,83.89 53.94,83.74 53.78,83.74 53.19,84.34 53.19,84.53 53.34,84.69 54.22,84.69 54.35,84.82 54.35,85.49 54.22,85.62 MEM2.A7
MDA45: length 36.2
  TOP w0.102: GPU1.C9 72.75,93.75 72.44,93.75 72.42,93.75 72.3,93.67 72.06,93.67 71.82,93.91 71.12,93.91 70.67,93.46 70.58,93.46 70.36,93.25
  TOP w0.127: 70.36,93.25 69.59,92.47 68.29,92.47 65.77,89.95 65.77,86.72 v1(65.47,86.43) 65.32,86.27 65.32,85.72 65.45,85.59 65.48,85.59 65.61,85.47 65.61,84.93 65.48,84.81 65.45,84.81 65.32,84.68 65.32,83.48 64.25,82.42 64.01,82.42 63.88,82.54 63.88,82.75 63.77,82.86 63.39,82.86 63.27,82.75 63.27,82.54 63.15,82.42 61.52,82.42 61.32,82.62 60.35,82.62 60.22,82.49 60.22,82.4 60.22,82.29 60.1,82.16 59.63,82.16 59.51,82.28 59.51,82.6 59.41,82.7 58.91,82.7 58.8,82.6 58.8,82.29 58.68,82.16 58.2,82.16 58.09,82.28 58.09,82.6 57.98,82.7 57.49,82.7 57.38,82.6 57.38,82.29 57.18,82.09 56.26,82.09 55.94,82.41 55.73,82.41 55.43,82.11 54.84,82.11 54.45,82.5 54.45,83.15 54.32,83.28 54.14,83.28 54.11,83.25 53.79,83.25 52.91,84.13 52.91,84.6 53.24,84.93 53.55,84.93 53.67,85.06 53.67,85.48 53.67,85.48 53.67,86.29 53.67,86.29 53.55,86.42 MEM2.B8
MDA46: length 37.3
  TOP w0.102: GPU1.F9 74.15,93.55 72.54,93.55 72.46,93.52 72.35,93.47 71.98,93.47 71.73,93.71 71.32,93.71 70.58,92.97
  TOP w0.127: MEM2.D7 53.68,87.68 53.68,87.37 53.67,87.36 53.67,87.07 53.38,86.78 53.06,86.78 52.85,86.56 52.85,85.51 52.56,85.22 52.3,85.22 52.04,84.95 52.04,84.31 54.6,81.74 64.2,81.74 66.34,83.88 v1(66.34,88.45) 66.34,90.01 68.46,92.13 69.59,92.13 70.43,92.97 70.58,92.97
MDA47: length 35.8
  TOP w0.102: 70.77,92.77 70.9,92.9 71.98,92.9 72.02,92.91 72.02,92.92 72.09,92.93 72.39,92.93 72.43,92.91 72.52,92.87 73.07,92.87 GPU1.D8
  TOP w0.127: 70.77,92.77 70.06,92.05 69.84,92.05 69.58,91.79 68.62,91.79 66.93,90.1 66.93,83.95 64.38,81.4 53.98,81.4 v1(53.43,81.94) 51.57,83.81 51.57,86.16 52.2,86.78 52.62,86.78 53.06,87.22 MEM2.C8
MDA48: length 31.1
  TOP w0.127: v4(70.78,91.41) 70.84,91.41 71.06,91.63 71.06,91.63 71.37,91.94 73.34,91.94 GPU1.E7 ; MEM2.E3 57.41,88.82 57.53,88.95 57.53,89.1 57.36,89.28 57.07,89.28 56.78,89.57 56.5,89.57 56.34,89.42 56.34,89.05 56.22,88.93 55.76,88.93 55.4,89.29 55.4,90.33 v4(55.44,90.37)
  L3 w0.165: v4(70.78,91.41) 70.78,91.78 70.93,91.93 72.08,91.93 72.21,92.05 72.21,92.34 72.08,92.47 70.91,92.47 70.78,92.6 70.78,92.84 70.52,93.11 62.18,93.11 62.05,92.98 62.05,92.14 61.92,92.02 61.5,92.02 61.37,92.14 61.37,93 61.24,93.13 60.86,93.13 60.74,93 60.74,92.62 60.61,92.5 57.28,92.5 56.86,92.08 56.86,91.73 56.63,91.5 56.26,91.5 55.95,91.18 55.95,90.87 v4(55.44,90.37)
MDA49: length 29.6
  TOP w0.127: v4(56.08,90.36) 55.91,90.52 55.91,91.19 56.09,91.37 56.34,91.37 56.49,91.51 56.49,92.14 56.6,92.24 56.76,92.24 56.87,92.14 56.87,91.56 MEM2.H3 ; GPU1.A7 72.03,92.23 71.15,92.23 70.75,91.83 70.54,91.83 v4(70.11,91.41)
  L3 w0.165: v4(56.08,90.36) 56.21,90.49 56.21,91.07 56.37,91.23 56.66,91.23 56.8,91.09 56.97,90.92 57.11,90.92 57.33,91.15 57.33,91.28 57.18,91.44 57.18,91.46 57.13,91.51 57.13,91.97 57.39,92.23 59.71,92.23 59.83,92.1 59.83,91.79 59.96,91.66 62.27,91.66 62.4,91.79 62.4,92.47 62.56,92.64 62.94,92.64 63.11,92.47 63.11,91.81 63.27,91.65 63.6,91.65 63.77,91.81 63.77,92.47 63.94,92.64 64.27,92.64 64.43,92.47 64.43,91.81 64.6,91.65 64.93,91.65 65.09,91.81 65.09,92.47 65.26,92.64 65.59,92.64 65.75,92.47 65.75,91.81 65.92,91.65 66.25,91.65 66.41,91.81 66.41,92.47 66.58,92.64 69.94,92.64 70.11,92.47 v4(70.11,91.41)
MDA50: length 32.4
  TOP w0.102: 71.87,92.54 72.03,92.7 72.13,92.73 72.29,92.73 72.35,92.72 GPU1.C7
  TOP w0.127: MEM2.F2 58.41,89.22 58.9,89.22 59.15,88.97 59.44,88.97 59.69,89.22 59.69,89.81 59.82,89.93 60.38,89.93 60.5,90.05 60.5,90.28 v4(60.03,90.76) ; v4(68.92,91.34) 67.52,89.95 67.52,88.12 67.65,87.99 67.98,87.99 68.1,88.12 68.1,89.81 68.23,89.93 68.53,89.93 68.66,89.81 68.66,88.09 68.79,87.96 69.13,87.96 69.26,88.09 69.26,90.53 69.69,90.96 69.69,91.58 69.94,91.83 70.17,91.83 70.88,92.54 71.87,92.54
  L3 w0.165: v4(60.03,90.76) 60.61,90.76 61.62,89.76 66.02,89.76 67.61,91.34 v4(68.92,91.34)
  BOTTOM w0.127: v4(60.03,90.76) 60.69,91.41 v2(60.94,91.41)
MDA51: length 31.5
  TOP w0.127: GPU1.F7 74.6,92.4 v4(74.2,92) ; MEM2.G2 58.2,90.42 58.42,90.63 v4(58.42,90.8)
  L3 w0.165: v4(74.2,92) 73.72,92 73.55,91.84 73.55,90.7 73.39,90.53 73.04,90.53 72.88,90.7 72.88,91.55 72.71,91.71 72.36,91.71 72.19,91.55 72.19,90.4 72.03,90.24 71.52,90.24 71.36,90.4 71.36,90.8 71.19,90.97 69.93,90.97 69.59,91.31 69.59,91.93 69.37,92.14 68.71,92.14 68.38,91.81 67.96,91.81 67.62,92.16 67.12,92.16 66.97,92 66.97,91.43 66.72,91.18 66.16,91.18 65.99,91.01 65.99,90.45 65.83,90.29 65.5,90.29 65.33,90.45 65.33,91.01 65.17,91.18 64.84,91.18 64.67,91.01 64.67,90.43 64.51,90.26 64.18,90.26 64.01,90.43 64.01,91.01 63.85,91.18 63.52,91.18 63.35,91.01 63.35,90.47 63.19,90.3 62.86,90.3 62.69,90.47 62.69,91.01 62.53,91.18 62.2,91.18 62.03,91.01 62.03,90.71 61.87,90.54 61.54,90.54 61.37,90.71 61.37,91.01 61.21,91.18 60.22,91.18 60.2,91.21 58.94,91.21 58.82,91.33 58.82,91.87 58.72,91.96 58.19,91.96 58.07,91.84 58.07,90.93 58.19,90.8 v4(58.42,90.8)
  BOTTOM w0.127: v4(74.2,92) 73.52,92 v2(73.2,92.32)
MDA52: length 30.5
  TOP w0.127: v4(71.02,89.62) 71.06,89.65 71.06,89.78 72.08,90.8 GPU1.A5 ; v4(51.72,91.5) 51.81,91.58 52.85,91.58 MEM2.H8
  L3 w0.165: v4(51.72,91.5) 52.96,91.5 53.13,91.66 53.13,91.81 53.29,91.98 53.78,91.98 53.94,91.81 53.94,91.43 54.11,91.27 54.64,91.27 54.99,90.91 54.99,89.71 55.55,89.15 56.19,89.15 57.5,87.84 58.77,87.84 58.95,88.02 58.95,88.25 59.07,88.38 59.59,88.38 59.72,88.25 59.72,87.94 60.48,87.18 62.01,87.18 62.07,87.24 66.81,87.24 67.47,87.91 67.47,89.39 68.04,89.95 69.14,89.95 69.47,89.62 v4(71.02,89.62)
  BOTTOM w0.127: v4(51.72,91.5) 51.42,91.5 50.76,90.83 v2(50.38,90.83)
MDA53: length 31.6
  TOP w0.127: v4(54.92,88.51) 54.92,88.52 54.01,89.43 MEM2.F7 ; v1(70.65,86.49) 70.65,87.88 v4(71.06,88.29) 71.06,88.62 71.57,89.13 71.85,89.13 72.61,89.89 72.61,90.13 72.87,90.39 73.39,90.39 GPU1.E5
  L3 w0.165: v4(54.92,88.51) 54.92,88.62 54.79,88.74 54.3,88.74 54.17,88.62 54.17,87.89 54.33,87.73 54.87,87.73 54.99,87.6 54.99,87.28 54.87,87.15 53.97,87.15 53.8,86.99 53.8,86.67 53.97,86.5 56.14,86.5 56.52,86.89 57.92,86.89 59.54,85.26 68.03,85.26 v4(71.06,88.29)
MDA54: length 29.8
  TOP w0.127: v4(55.67,88.46) 55.01,89.12 55.01,89.65 54.94,89.72 54.94,90.35 55,90.4 55,90.95 54.73,91.22 MEM2.H7 ; GPU1.C3 73,89.87 72.43,89.3 72.43,87.44 72.26,87.28 71.89,87.28 71.72,87.44 v4(71.72,88.69)
  L3 w0.165: v4(71.72,88.69) 71.61,88.8 70.9,88.8 69.73,87.64 69.5,87.64 69.22,87.91 68.99,87.91 68.76,87.68 68.76,87.44 69.03,87.17 69.03,86.94 68.8,86.7 68.56,86.7 68.2,87.07 67.97,87.07 67.73,86.83 67.73,86.6 68.1,86.24 68.1,86 67.83,85.73 59.6,85.73 58.11,87.23 56.69,87.23 55.67,88.24 v4(55.67,88.46)
MDA55: length 29.8
  TOP w0.127: v4(72.94,87.96) 72.99,87.96 73.8,88.77 GPU1.E1 ; v4(52.81,90.01) 53.21,89.62 MEM2.F8
  L3 w0.165: v4(52.81,90.01) 52.81,88.24 53.25,87.8 53.25,86.08 54.04,85.29 55.46,85.29 56.06,85.88 56.06,85.99 56.68,86.62 57.67,86.62 59.51,84.78 68.27,84.78 71.45,87.96 v4(72.94,87.96)
  BOTTOM w0.127: v4(72.94,87.96) 72.94,87.97 v2(73.73,87.97)
MDA56: length 33.2
  TOP w0.127: v4(75.01,92) 75.4,92.39 GPU1.G7
  BOTTOM w0.127: MEM4.D7 57.6,87.64 58.97,87.64 59.18,87.85 60.12,87.85 62.2,89.93 62.38,89.93 63,89.32 63.18,89.32 63.36,89.49 63.36,89.67 62.74,90.29 62.74,90.47 62.92,90.65 63.1,90.65 63.69,90.06 63.87,90.06 64.05,90.24 64.05,90.42 63.46,91.01 63.46,91.19 63.64,91.37 63.82,91.37 64.47,90.72 64.65,90.72 64.83,90.9 64.83,91.08 64.18,91.73 64.18,91.91 64.65,92.37 65.46,92.37 65.64,92.19 65.64,91.43 65.77,91.3 66.02,91.3 66.15,91.43 66.15,92.47 66.28,92.6 66.53,92.6 66.66,92.47 66.66,91.43 66.78,91.3 67.04,91.3 67.16,91.43 67.16,92.45 67.29,92.57 67.55,92.57 67.67,92.45 67.67,91.43 67.8,91.3 68.05,91.3 68.18,91.43 68.18,92.25 68.31,92.37 v2(69.91,92.37) 71.59,92.37 72.41,91.56 74.57,91.56 v4(75.01,92)
MDA57: length 32.4
  TOP w0.127: GPU1.G6 75.02,91.22 v4(75.02,91.22)
  BOTTOM w0.127: MEM4.C8 58.38,86.85 59.43,86.85 60.07,87.5 60.25,87.5 60.84,88.08 62.58,88.08 62.89,88.39 63.07,88.39 63.41,88.04 63.59,88.04 63.77,88.22 63.77,88.4 63.42,88.75 63.42,88.93 63.6,89.11 63.78,89.11 64.23,88.66 64.41,88.66 64.59,88.84 64.59,89.02 64.14,89.46 64.14,89.64 64.32,89.82 64.5,89.82 65.07,89.25 65.25,89.25 65.43,89.43 65.43,89.61 64.86,90.18 64.86,90.36 65.11,90.61 66.12,90.61 66.29,90.44 66.29,89.43 66.41,89.3 66.67,89.3 66.79,89.43 66.79,90.81 66.92,90.94 67.18,90.94 67.3,90.81 67.3,89.43 67.43,89.3 67.68,89.3 67.81,89.43 67.81,90.83 67.94,90.96 68.19,90.96 68.32,90.83 68.32,89.43 68.45,89.3 68.7,89.3 68.83,89.43 68.83,90.57 68.95,90.7 v2(72.1,90.7) 74.54,90.7 74.99,91.15 74.99,91.19 v4(75.02,91.22)
MDA58: length 31.2
  TOP w0.127: GPU1.G1 75.2,89 75.2,88.61 75.03,88.44 75.03,87.23 v1(75.57,86.69) 75.85,86.42 v4(76.48,86.42)
  BOTTOM w0.127: v4(76.48,86.42) 74.03,83.96 v2(73.57,83.96) 69.39,83.96 66.95,81.52 56.73,81.52 53.66,84.6 53.66,84.91 53.21,85.35 MEM4.A2
MDA59: length 31.7
  TOP w0.127: GPU1.G3 74.97,89.57 74.97,88.71 74.56,88.29 v4(74.56,88.27)
  BOTTOM w0.127: v4(74.56,88.27) 73.72,89.11 72.6,89.11 72.37,88.88 72.37,87.42 72.24,87.29 71.98,87.29 71.85,87.42 71.85,87.59 71.73,87.7 71.16,87.7 71.03,87.58 71.03,87.39 70.9,87.27 70.65,87.27 70.52,87.39 70.52,88.38 70.39,88.51 70.14,88.51 70.01,88.38 70.01,87.39 69.89,87.27 69.63,87.27 69.5,87.39 69.5,88.4 69.38,88.52 69.12,88.52 69,88.4 69,87.39 68.87,87.27 68.62,87.27 68.49,87.39 68.49,87.58 68.36,87.7 66.94,87.7 66.81,87.58 66.81,87.39 66.68,87.27 66.43,87.27 66.3,87.39 66.3,87.4 65.66,88.04 65.48,88.04 65.25,87.81 65.25,87.63 65.77,87.11 65.77,86.93 65.49,86.64 65.31,86.64 65.05,86.9 64.6,86.9 64.44,86.74 v2(63.32,86.74) 62.39,86.74 61.41,85.76 61.41,84.78 61.29,84.66 60.81,84.66 60.69,84.78 60.69,85.4 60.59,85.51 60.33,85.51 60.08,85.25 57.58,85.25 MEM4.A7
MDA60: length 33.9
  TOP w0.127: GPU1.J6 77,91.56 77.41,91.15 v4(77.43,91.15)
  BOTTOM w0.127: v4(77.43,91.15) 77.43,90.32 77.26,90.15 76.7,90.15 76.57,90.02 76.57,89.86 76.45,89.73 76.19,89.73 76.07,89.86 76.07,90.76 75.94,90.89 75.68,90.89 75.56,90.76 75.56,89.84 75.43,89.72 75.18,89.72 75.05,89.84 75.05,90.11 74.92,90.24 74.67,90.24 74.54,90.11 74.54,89.82 74.41,89.69 74.16,89.69 74.03,89.82 74.03,90.02 73.91,90.15 70.96,90.15 70.57,89.75 70.57,89.1 70.35,88.88 70.12,88.88 70,89.01 70,89.59 69.87,89.72 69.62,89.72 69.49,89.59 69.49,89.01 69.36,88.88 68.56,88.88 68.43,88.75 68.43,88.19 68.3,88.07 68.05,88.07 67.92,88.19 67.92,88.75 67.8,88.88 67.54,88.88 67.42,88.75 67.42,88.19 67.29,88.07 67.03,88.07 66.91,88.19 66.91,88.75 66.78,88.88 66.53,88.88 66.4,88.75 66.4,88.31 66.27,88.18 66.02,88.18 65.89,88.31 65.89,88.75 65.76,88.88 65.14,88.88 64.71,88.44 v2(64.71,88.02) 64.71,87.54 64.44,87.27 63.94,87.27 63.81,87.4 63.81,87.5 63.68,87.62 63.02,87.62 62.89,87.5 62.89,87.22 62.76,87.09 62.11,87.09 61.99,87.22 61.99,87.62 61.89,87.72 60.93,87.72 60.28,87.08 60.28,86.43 59.91,86.05 58.38,86.05 MEM4.B8
MDA61: length 32.6
  TOP w0.127: GPU1.J1 77.12,89.08 v4(77.12,88.49)
  BOTTOM w0.127: MEM4.C2 53.62,86.81 54.13,86.81 54.47,86.48 54.47,85.17 57.04,82.59 59.03,82.59 59.04,82.61 59.05,82.59 62.68,82.59 63.52,83.43 64.88,83.43 65.01,83.3 65.01,83.02 65.14,82.9 65.39,82.9 65.52,83.02 65.52,83.3 65.64,83.43 65.9,83.43 66.03,83.3 66.03,82.68 66.15,82.55 66.41,82.55 66.53,82.68 66.53,83.3 66.66,83.43 67.18,83.43 v2(68.77,85.02) 68.89,85.02 69.19,85.32 74.45,85.32 76.28,87.15 76.73,87.15 77.12,87.54 v4(77.12,88.49)
MDA62: length 32.5
  TOP w0.127: GPU1.J3 77,90.04 76.79,90.25 76.54,90.25 76.38,90.1 76.38,89.91 76.55,89.74 76.55,89.01 76.7,88.87 v4(76.7,87.71)
  BOTTOM w0.127: v4(76.7,87.71) 76.37,87.38 76.19,87.38 74.51,85.7 68.61,85.7 v2(67.16,84.25) 66.68,83.77 63.31,83.77 62.6,83.07 59.43,83.07 59.31,83.2 59.31,83.67 59.18,83.8 58.92,83.8 58.8,83.67 58.8,83.2 58.67,83.07 58.42,83.07 58.29,83.2 58.29,83.66 58.16,83.79 57.91,83.79 57.78,83.66 57.78,83.2 57.65,83.07 57.31,83.07 54.73,85.66 54.73,86.67 54.17,87.22 MEM4.C3
MDA63: length 33.2
  TOP w0.127: v4(78.05,87.73) 77.96,87.81 77.96,87.81 77.63,88.14 77.63,88.41 77.59,88.44 77.59,88.65 77.43,88.81 77.43,90.37 GPU1.J5
  BOTTOM w0.127: v4(78.05,87.73) 77.18,86.87 76.33,86.87 74.15,84.69 v2(71.27,84.69) 69.3,84.69 69.11,84.5 69.09,84.5 66.65,82.06 64.31,82.06 64.18,82.19 64.18,82.85 64.06,82.97 63.8,82.97 63.67,82.85 63.67,82.19 63.55,82.06 56.99,82.06 54.01,85.03 MEM4.A3
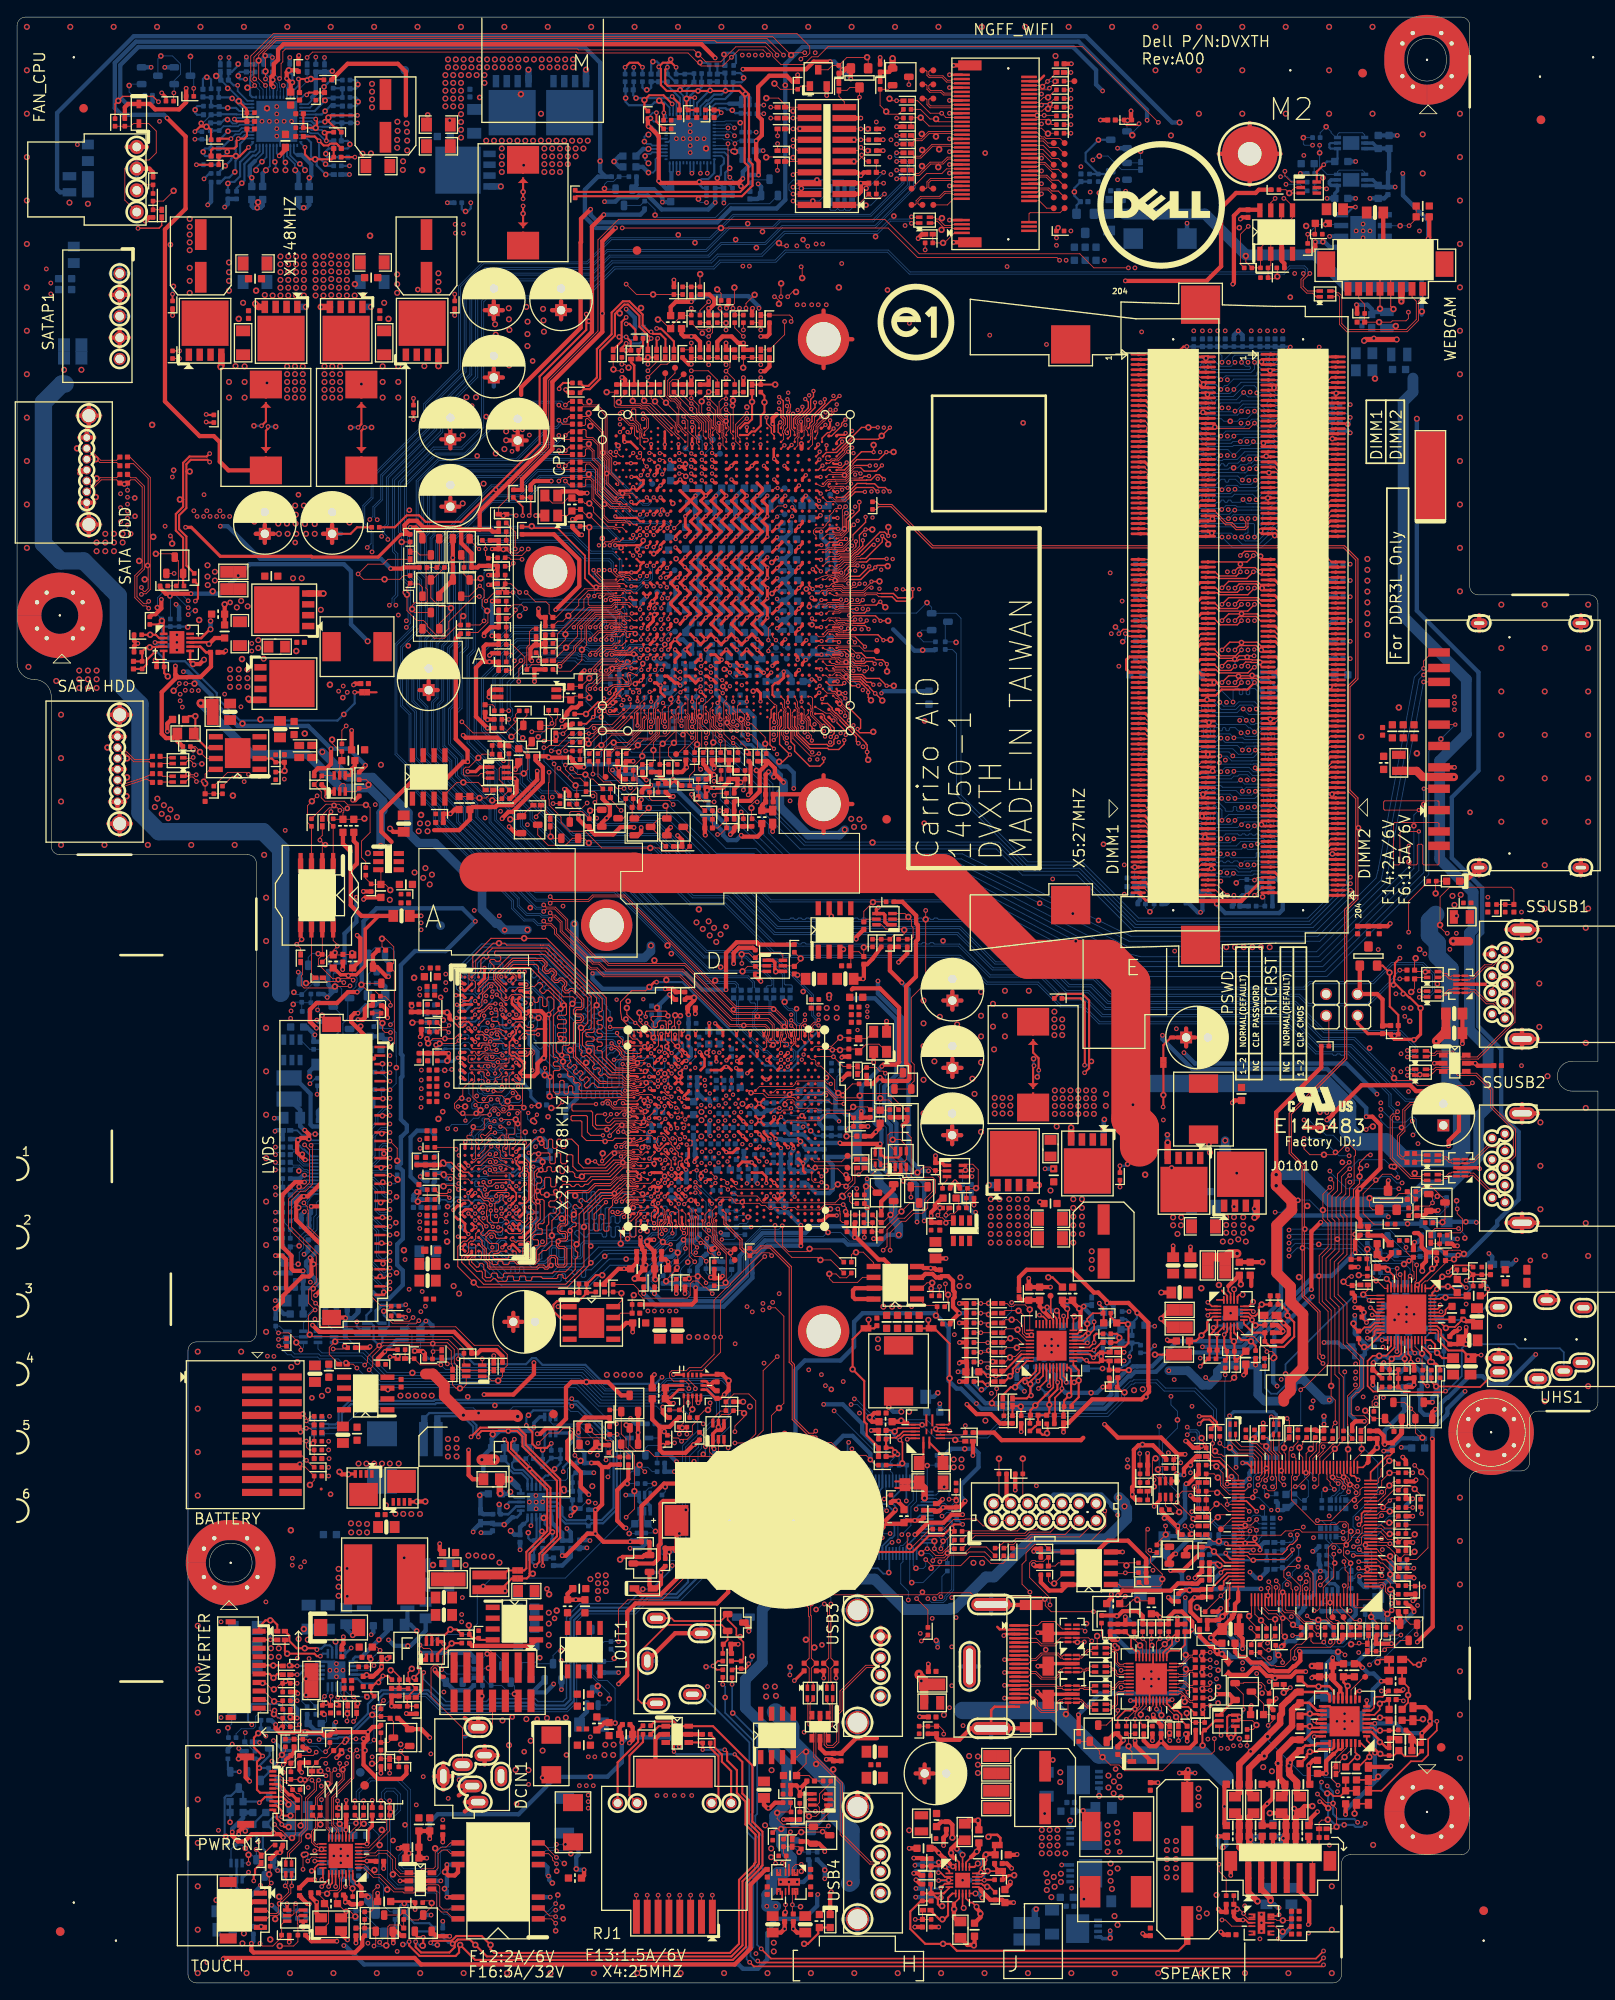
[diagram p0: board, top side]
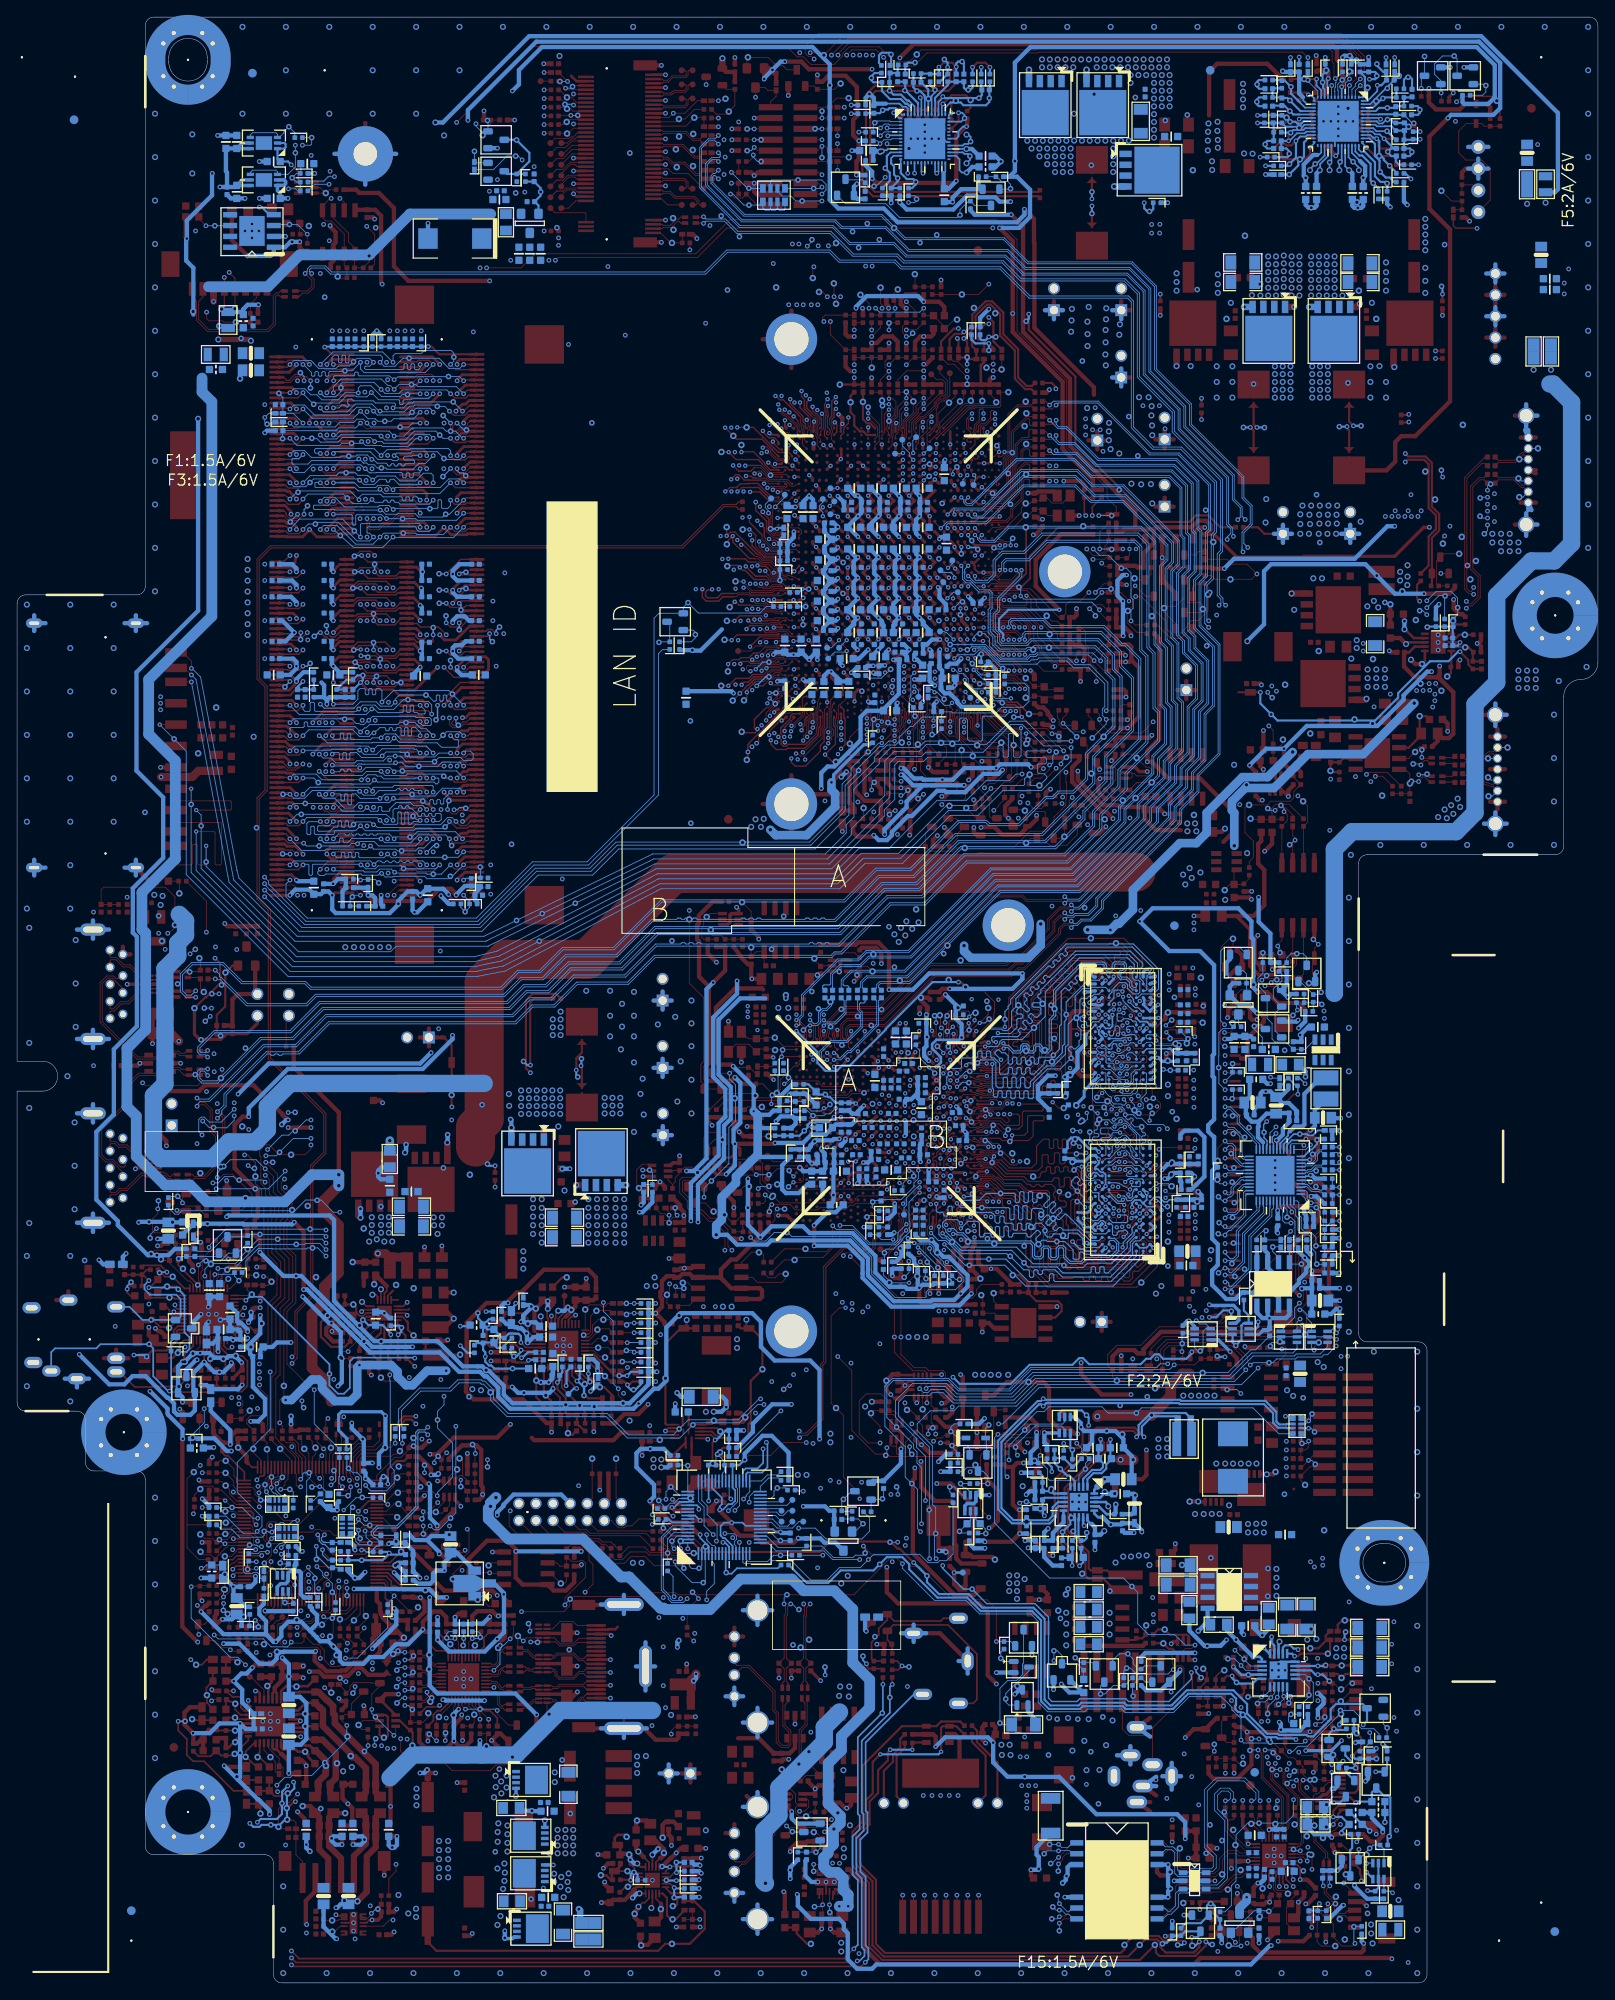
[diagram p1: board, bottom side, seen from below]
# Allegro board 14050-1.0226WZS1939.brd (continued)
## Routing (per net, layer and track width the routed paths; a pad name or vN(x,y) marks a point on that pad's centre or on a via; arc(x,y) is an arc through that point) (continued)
MDAT: length 4.4
  TOP w0.102: U109.79 143.89,53.18 144.05,53.34 144.66,53.34 v3(145.04,52.96)
  BOTTOM w0.102: RN10.2 145.3,53.22 v3(145.04,52.96) 145.04,52.43 144.86,52.24 v2(144.86,51.99)
MEM_CALRP0: length 4.8
  TOP w0.102: v4(78.27,107.13) 78.13,107.13 GPU1.K25
  BOTTOM w0.102: v2(77.61,106.43) 78.27,107.09 v4(78.27,107.13) 79.38,108.25 79.38,109.11 79.81,109.55 R1201.2
MEM_MA_EVENT_L: length 109.8
  TOP w0.102: v4(97.06,161.8) 96.71,161.44 96.22,161.44 96.16,161.51 95.67,161.51 95.67,161.5 95.35,161.5 95.34,161.51 94.86,161.51 94.68,161.33 93.83,161.33 CPU1.AG30 ; v3(140.88,128.91) 140.73,129.05 DIMM1.198 ; v3(153.07,129.03) 153.09,129.05 DIMM2.198
  L3 w0.127: v3(140.88,128.91) 143.54,128.91 143.92,128.52 146.04,128.52 146.44,128.13 152.16,128.13 v3(153.07,129.03)
  BOTTOM w0.102: v3(153.07,129.03) 153.53,128.57 153.53,127.06 151.05,124.59 131.25,124.59 124.67,131.17 118.29,131.17 110.46,138.99 110.46,159.67 109.89,160.24 Q1207.E 107.03,160.95 v2(106.48,161.49) 105.27,160.27 98.08,160.27 97.32,161.04 R1584.2 96.49,161.23 v4(97.06,161.8)
MEM_MA_ZVDDIO: length 2.4
  TOP w0.203: v4(93.11,163.08) 92.7,163.49 CPU1.AD29
  BOTTOM w0.203: R1696.1 93.5,162.69 v4(93.11,163.08) v2(92.36,163.08)
MEM_MB_ZVDDIO: length 2.5
  TOP w0.203: v4(94.13,161.8) 94.13,161.8 94.7,161.8 CPU1.AF32
  BOTTOM w0.203: v2(92.72,161.04) R121.1 93.7,161.37 v4(94.13,161.8)
MEM_RST: length 94.8
  TOP w0.102: MEM1.T2 52.16,104.63 52.16,103.87 51.19,102.9 51.19,102.37 52.01,101.55 54.53,101.55 54.56,101.58 v3(55.31,101.58) 55.31,102.1 55.69,102.48 56.06,102.48 56.75,101.8 57.08,101.8 57.44,102.16 58.72,102.16 58.96,101.92 58.96,98.57 MEM2.T2
  L3 w0.127: v3(50.38,99.94) 48.04,99.94 47.79,99.69 47.79,87.5 51.69,83.6 68.35,83.6 69.69,84.94 80.54,84.94 82.44,86.84 82.44,86.94 v4(82.48,86.97)
  BOTTOM w0.102: v3(50.38,99.94) 50.89,100.44 52.69,100.44 53.42,101.17 53.99,101.17 54.4,101.58 v3(55.31,101.58) ; v3(55.31,101.58) 55.45,101.72 55.45,102.25 55.69,102.48 56.03,102.48 56.05,102.46 56.59,102.46 56.75,102.61 56.77,102.61 57.12,102.96 57.65,102.96 57.69,102.99 58.74,102.99 59.15,103.41 59.15,104.83 59.09,104.89 59.09,105.02 58.88,105.23 58.87,105.23 58.77,105.33 58.65,105.33 58.3,105.68 MEM3.T2 ; v3(55.31,101.58) 55.31,101.25 55.04,100.98 54.89,100.98 54.69,101.19 54.52,101.19 54.4,101.07 54.4,100.9 54.61,100.69 54.61,100.55 54.22,100.16 v2(53.39,100.16) 53.39,99.6 53.29,99.5 53.08,99.5 52.96,99.38 52.96,99.22 53.08,99.1 53.29,99.1 53.39,99 53.39,98.79 53.29,98.69 53.03,98.69 52.91,98.57 52.91,98.4 53.03,98.28 53.29,98.28 53.39,98.18 53.39,97.79 MEM4.T2 ; v4(82.48,86.97) 83.88,86.97 84.13,87.23 84.13,87.55 R1891.2 R1204.2
MEM_VREFCA_SUS: length 28.1
  TOP w0.254: v3(144.81,152.15) 143.99,151.32 140.96,151.32 140.29,150.65 DIMM1.126 ; DIMM2.126 153.04,150.65 v3(151.54,152.27)
  L4 w0.254: v3(144.81,152.15) 145.35,152.68 151.14,152.68 v3(151.54,152.27)
  BOTTOM w0.254: v3(151.54,152.27) 152.18,151.64 C1979.2 C1980.2 R2060.1 R2059.2 ; C65.2 145.64,151.32 v3(144.81,152.15) 144.53,152.43 v2(144.53,152.98) 145.18,152.98 R120.2 146.46,152.46 R122.1 C1746.2
MIC2-L: length 4.3
  TOP w0.203: C139.1 169.48,80.16 167.19,80.16 v1(167.17,80.19) 167.14,80.16 166.66,80.16 166.53,80.03 U6.47
MIC2-L-1: length 3.4
  TOP w0.203: C139.2 171.74,80.39 172.12,80.77 v3(172.12,81.18) 171.76,81.53 R225.1
  BOTTOM w0.203: v2(171.66,81.99) 172.12,81.53 v3(172.12,81.18)
MIC2-R: length 3.8
  TOP w0.203: C138.1 167.85,81.46 167.47,81.46 v1(167.45,81.48) 166.35,81.48 165.62,80.75 U6.48
MIC2-R-1: length 13.9
  TOP w0.203: C138.2 169.48,81.36 v3(169.58,81.36)
  BOTTOM w0.203: v3(169.58,81.36) 166.35,81.36 v2(166.14,81.15) 166.14,81.14 165.41,80.42 165.41,76.12 164.83,75.54 164.83,74.19 165.18,73.84 166.01,73.84 R627.1
MIC2-VREFO-L: length 4.6
  TOP w0.203: R223.1 167.69,82.63 166.91,82.63 166.91,82.62 v1(166.79,82.62) 166.72,82.55 166.71,82.55 165.42,81.26 U6.1
MIC2-VREFO-R: length 3.5
  TOP w0.203: R262.1 162.39,71.89 v1(162.39,73.03) U6.30
MIC-CAP: length 4.6
  TOP w0.203: 165.95,74.67 165.95,74.7 165.44,75.21 U6.36
  TOP w0.254: C154.1 166.8,73.1 v1(166.19,73.71) 165.95,73.95 165.95,74.67
MINI_POWER_CTRL: length 198.7
  TOP w0.102: v3(148.19,59.03) 148.06,59.17 U109.55 148.06,61.76 147.68,62.13 RN8.4
  L4 w0.127: v3(125.89,213.28) 131.13,213.28 142.92,201.49 154.3,201.49 162.76,193.04 162.76,188.4 161.81,187.45 161.81,155.88 161.1,155.18 161.1,125.1 161.8,124.4 161.8,122.33 162.87,121.26 162.87,116.8 162.72,116.65 162.72,114.43 162.72,114.43 162.72,113.79 162.49,113.56 162.21,113.56 161.93,113.29 161.93,112.53 156.87,107.47 156.87,105.43 155.91,104.47 155.91,100.5 154.51,99.1 154.51,89.73 152.44,87.66 152.44,76.73 151.77,76.06 151.77,74.07 148.83,71.12 148.83,68.47 148.15,67.79 148.15,60.03 148.19,59.99 v3(148.19,59.03)
  BOTTOM w0.102: R15.1 129.26,212.15 127.67,213.74 v2(126.65,213.74) 126.35,213.74 v3(125.89,213.28)
MLPS_EN#: length 11.3
  TOP w0.102: R1882.1 82.56,81.58 v1(82.92,81.93) 82.99,82 82.99,85.29 82.43,85.85 81.51,86.76 81.51,87.3 81.36,87.46 81.36,88.88 81.27,88.98 81.27,89.29 arc(81.29,89.4) 81.35,89.5 81.35,90.35 GPU1.R5
MODEL_ID_DET: length 5.9
  TOP w0.102: v3(109.06,56.58) R79723.2 R79722.1
  BOTTOM w0.102: v3(109.06,56.58) 109.06,57.47 v2(108.49,58.04) 107.53,57.08 U4101.50
MPCIE_DISABLE_N: length 202.4
  TOP w0.102: R1620.1 v3(123.32,218.44) ; RN8.3 147.03,62.33 147.66,61.7 U109.56 147.66,58.8 148.19,58.27 v3(148.27,58.27)
  L4 w0.127: v3(123.32,218.44) 124.54,217.22 128,217.22 143.22,202 154.51,202 163.38,193.13 163.38,188.3 162.32,187.24 162.32,155.67 161.61,154.97 161.61,125.31 162.31,124.62 162.31,122.55 163.38,121.47 163.38,116.59 163.23,116.44 163.23,113.11 157.64,107.52 157.64,105.84 156.54,104.74 156.54,102.34 156.23,102.03 156.23,100.47 154.95,99.18 154.95,93.08 154.76,92.89 154.76,89.62 152.69,87.55 152.69,76.63 152.02,75.95 152.02,73.96 149.09,71.03 149.09,65.85 148.66,65.41 148.66,58.74 148.27,58.34 v3(148.27,58.27)
  BOTTOM w0.102: v3(148.27,58.27) 148.19,58.27 147.73,58.72 147.73,59.74 v2(147.93,59.94)
MPV18: length 0.7
  TOP w0.381: GPU1.L8 78.71,93.2 78.33,92.82 v4(78.25,92.82)
  vias: v2(78.87,91.57)
MVREFDA: length 9.9
  TOP w0.356: v4(78.31,107.88) 78.29,107.9 78.1,107.9 GPU1.K26
  TOP w0.508: R1890.2 78.39,115.27 v1(79.23,115.27) 79.23,114.97 78.48,114.22 C760.1 78.48,113.39 v3(78.58,113.28)
  BOTTOM w0.508: v4(78.31,107.88) 78.85,108.41 78.85,109.33 78.58,109.59 78.58,110.6 v2(78.52,110.67) 78.58,110.73 R1888.1 v3(78.58,113.28)
MVREFSA: length 14.4
  TOP w0.356: GPU1.J26 77,107.59 77.35,107.24 v4(77.4,107.19)
  TOP w0.508: R1200.2 76.95,115.05 v3(76.36,115.64)
  BOTTOM w0.305: v2(74.47,110.61) 74.74,110.34 77.41,110.34 77.92,109.83 77.92,109.33 76.89,108.3 76.89,107.7 v4(77.4,107.19)
  BOTTOM w0.508: v2(74.47,110.61) 74.47,112.16 75.15,112.85 R1889.1 C761.1 75.15,114.43 v3(76.36,115.64)
NB_VRM_PWRGD: length 139.5
  TOP w0.102: v3(30.72,222.81) 30.89,222.99 30.89,224.56 31.1,224.77 31.1,225.96 31.4,226.26 65.61,226.26 65.71,226.16 79.2,226.16 79.71,225.65 v1(79.71,225.63) 79.74,225.63 80.6,224.76 82.35,224.76 84.11,226.52 87.6,226.52 88.43,225.69 88.43,225.41 89.38,224.46 92.1,224.46 92.99,225.35 93.71,225.35 94.9,226.54 124.7,226.54 v3(133.56,217.68)
  L4 w0.127: v3(133.56,217.68) 133.56,215.79 140.27,209.08 145.61,209.08 v3(147.86,211.33)
  BOTTOM w0.102: PU4601.8 30.79,221.28 30.8,221.3 30.8,221.7 30.7,221.81 30.7,222.28 30.65,222.33 30.65,222.74 v3(30.72,222.81) 30.65,222.81 PR4632.2 ; R79674.1 150.85,210.82 149.13,210.82 148.62,211.33 v3(147.86,211.33)
NGFF_ALERT#: length 230.3
  TOP w0.102: CPU1.BB19 85.1,148.4 85.1,148.37 85.15,148.33 85.15,147.79 85.55,147.38 v4(85.55,147.32) 85.96,147.32 87.55,145.73 v1(87.55,144.98) 87.66,144.87 R1749.1 ; R1717.1 v3(123.32,221.49)
  L3 w0.127: v4(85.55,147.32) 86.01,147.32 86.46,146.88 86.46,141.81 87.76,140.5 87.76,139.33 93.63,133.46 121.19,133.46 135.29,119.36 163.72,119.36 v3(164.75,120.4)
  L4 w0.127: v3(164.75,120.4) 164.65,120.5 164.65,123.35 162.37,125.63 162.37,154.53 163.08,155.23 163.08,186.92 164.14,187.98 164.14,193.45 159.22,198.37 159,198.59 154.83,202.76 143.54,202.76 124.81,221.49 v3(123.32,221.49)
  BOTTOM w0.102: v2(164.14,120.93) 164.22,120.93 v3(164.75,120.4)
NGFF_ALERT_N: length 3.8
  TOP w0.102: R1717.2 121.52,221.49 120.65,220.62 v1(120.65,220.61) 120.12,220.61 119.52,220 NGFF1.62
NGFF_BT_DISABLE: length 317.8
  TOP w0.102: R1933.1 85.63,144.22 84.16,145.69 v4(83.8,145.69) ; R1621.1 v3(123.32,217.42) ; v3(155.28,49.3) 155.35,49.22 155.35,48.88 155.42,48.82 155.42,48.32 155.76,47.98 155.76,46.68 155.77,46.67 155.77,46.29 155.66,46.18 U109.125
  L3 w0.127: v3(155.28,49.3) 155.37,49.3 155.48,49.4 156.47,49.4 156.81,49.75 157.2,49.75 157.39,49.56 157.97,49.56 159.31,50.89 159.31,50.89 159.58,51.17 159.58,51.17 161.39,52.97 161.39,56.05 163.72,58.38 164.23,58.38 165.13,59.28 165.13,62.99 163.74,64.39 163.74,67.44 161.45,69.72 161.45,70.13 159.2,72.38 159.2,72.79 158.93,73.06 158.87,73.06 158.15,73.79 158.15,74.17 156.08,76.24 156.08,79.96 156.19,80.07 156.19,81.28 157.56,82.65 157.56,82.98 157.42,83.12 157.42,83.95 157.11,84.27 157.11,92.34 161.92,97.16 164.22,97.16 164.9,97.84 164.9,109.55 164.74,109.72 164.74,110.75 v3(162.4,113.09) 160.33,115.16 160.33,116.06 159.19,117.2 134.39,117.2 120.29,131.3 92.74,131.3 88.35,135.69 86.85,135.69 83.38,139.15 83.38,145.28 v4(83.8,145.69)
  L4 w0.127: v3(162.4,113.09) 162.98,113.67 162.98,116.54 163.12,116.69 163.12,121.37 162.05,122.44 162.05,124.51 161.36,125.2 161.36,155.07 162.06,155.78 162.06,187.34 163.12,188.4 163.12,193.03 154.41,201.74 143.03,201.74 128.13,216.64 124.11,216.64 v3(123.32,217.42)
  BOTTOM w0.102: v3(162.4,113.09) 162.84,112.65 162.85,112.65 v2(162.97,112.52)
NGFF_CLKREQ0_N: length 6.6
  TOP w0.102: NGFF1.53 107.87,217.75 v1(107.55,218.08) 106.84,218.08 105.72,219.2 R1931.1
NGFF_CLKREQ0_NGFF#: length 6.9
  TOP w0.102: Q1229.S 101.98,221.55 R1932.2 101,219.66 v1(101.71,218.95) 101.71,218.92 101.99,218.64 103.17,218.64 R1931.2
NGFF_CLKREQ1_APU#: length 252.7
  TOP w0.102: v4(84.26,146.5) 84.25,146.51 84.25,146.58 83.9,146.94 83.54,146.94 83.19,147.29 83.19,147.86 83.3,147.97 83.3,148.23 83,148.53 CPU1.BB17 ; Q1229.D v3(104.36,222.1)
  L3 w0.127: v4(84.26,146.5) 84.26,145.91 84.22,145.87 84.22,144.79 83.64,144.21 83.64,139.26 86.96,135.94 88.45,135.94 92.84,131.55 120.39,131.55 134.49,117.45 159.29,117.45 160.58,116.16 160.58,115.4 161.93,114.05 v3(162.25,114.05)
  L4 w0.127: v3(104.36,222.1) 104.36,221.92 108.1,218.19 116.55,218.19 118.64,216.1 122.1,216.1 136.96,201.24 154.2,201.24 162.5,192.93 162.5,188.5 161.55,187.55 161.55,155.99 160.85,155.28 160.85,124.99 161.54,124.3 161.54,122.23 162.62,121.16 162.62,116.9 162.47,116.75 162.47,114.27 v3(162.25,114.05)
  BOTTOM w0.102: v3(162.25,114.05) v2(163.09,114.05)
NGFF_CLKREQ1_N: length 4.5
  TOP w0.102: R1925.2 v3(120.82,221.68) 120.63,221.5 NGFF1.68
  BOTTOM w0.102: v2(120,221.87) 120.18,221.68 v3(120.82,221.68)
NGFF_CLKREQ1_N_TP: length 1.2
  TOP w0.102: R1925.1 TP208.1
NGFF_DETECT_PCIE: length 248.7
  TOP w0.102: R1155.2 v3(102.93,218.19) ; CPU1.BA19 84.3,149.4 84.3,148.74 84.31,148.73 84.31,148.27 84.3,148.26 84.3,147.97 84.94,147.33 84.94,146.66 v4(85.55,146.05) 85.96,146.05 86.65,145.36 R1926.1
  L3 w0.127: v3(161.36,115.73) 161.36,116.29 159.37,118.29 159.31,118.35 134.86,118.35 120.77,132.45 93.21,132.45 86.75,138.91 86.75,139.45 85.04,141.16 85.04,143.63 85.44,144.03 85.44,144.41 86,144.97 86,145.86 85.81,146.05 v4(85.55,146.05)
  L4 w0.127: v3(102.93,218.19) 105.38,218.19 106.14,217.42 116.24,217.42 119.69,213.97 121.8,213.97 124.28,211.5 125.62,211.5 136.64,200.47 153.88,200.47 160.79,193.56 160.79,156.3 160.09,155.6 160.09,121.99 160.78,121.29 160.78,117.29 161.36,116.72 v3(161.36,115.73)
  BOTTOM w0.102: v3(161.36,115.73) 161.45,115.73 v2(162.21,115.73)
NGFF_DETECT_PCIE_C: length 7.4
  TOP w0.102: R1709.1 R1155.1 104.67,218.24 v1(105.75,218.24) 106.73,217.25 NGFF1.51
NGFF_DETECT_USB: length 221.5
  TOP w0.102: U109.126 156.06,49.18 155.24,50 155.24,50.97 156.14,51.87 156.14,52.1 156.88,52.83 v3(156.9,52.83) ; R1154.2 v3(106.27,202.77)
  L3 w0.127: v3(155.38,71.49) 153.42,73.45 153.42,75.12 153.41,75.13 153.41,81.06 153.42,81.07 153.42,85.24 152.09,86.57 152.09,100.64 v3(153.28,101.83)
  L4 w0.127: v3(153.28,101.83) 153.37,101.92 153.37,105.52 154.33,106.48 154.33,108.52 158.72,112.91 158.72,124.58 159.2,125.06 159.2,155.97 159.9,156.67 159.9,192.52 158.42,194.01 157.49,194.01 153.23,198.26 110.77,198.26 v3(106.27,202.77)
  BOTTOM w0.102: R1935.2 160.56,54.61 158.55,52.6 157.13,52.6 v3(156.9,52.83) 156.34,53.39 156.34,54.51 159.24,57.41 159.24,60.91 155.38,64.77 v3(155.38,71.49) ; v2(152.47,101.86) 152.56,101.86 152.59,101.83 v3(153.28,101.83)
NGFF_DETECT_USB_C: length 4.9
  TOP w0.102: NGFF1.1 109.69,204.75 108.52,203.58 v1(108.36,203.58) R1154.1 R1209.1
NGFF_PCIE0_RXN: length 7.1
  TOP w0.102: 106.17,214.21 107.06,215.11 109.36,215.11 109.5,215.25 NGFF1.43 ; 106.17,214.21 105.68,213.72 105.02,213.72 R1712.1 ; 106.17,214.21 v1(105.92,214.45)
NGFF_PCIE0_RXP: length 7.1
  TOP w0.102: R1711.1 105.02,213.51 105.77,213.51 107.15,214.89 107.91,214.89 ; v1(107.91,214.53) 107.91,214.89 ; 107.91,214.89 109.36,214.89 109.5,214.75 NGFF1.41
NGFF_PCIE0_TXN: length 7.3
  TOP w0.102: 106.14,212.33 105.51,211.69 105.02,211.69 R1714.1 ; 106.14,212.33 v1(105.9,212.57) ; 106.14,212.33 106.84,213.03 108.28,213.03 108.86,213.61 109.36,213.61 109.5,213.75 NGFF1.37
NGFF_PCIE0_TXP: length 7.3
  TOP w0.102: 107.81,212.81 108.37,212.81 108.95,213.39 109.36,213.39 109.5,213.25 NGFF1.35 ; 107.81,212.81 v1(107.81,212.45) ; 107.81,212.81 106.93,212.81 105.6,211.47 105.02,211.47 R1713.1
NGFF_PCIE1_RXN: length 5.1
  TOP w0.102: NGFF1.67 109.5,221.25 109.36,221.11 108.49,221.11 108.18,221.42 106.91,221.42 106.69,221.63 106.69,221.98 106.84,222.12 TP82.1
NGFF_PCIE1_RXP: length 5.5
  TOP w0.102: TP81.1 106.35,222.12 106.48,222 106.48,221.54 106.75,221.27 106.82,221.21 108.09,221.21 108.4,220.89 109.36,220.89 109.5,220.75 NGFF1.65
NGFF_PCIE1_TXN: length 5.1
  TOP w0.102: TP80.1 106.82,220.47 106.69,220.34 106.69,219.84 106.93,219.61 109.36,219.61 109.5,219.75 NGFF1.61
NGFF_PCIE1_TXP: length 5.5
  TOP w0.102: TP79.1 106.35,220.47 106.48,220.34 106.48,219.75 106.84,219.39 109.36,219.39 109.5,219.25 NGFF1.59
NGFF_PEWAKE0_N: length 31.3
  TOP w0.102: NGFF1.70 120.12,222 v3(120.59,222.47) R1718.2 ; R1719.1 105.39,220.22 106.85,218.75 v3(108.2,218.75) 108.7,218.25 NGFF1.55
  L4 w0.127: v3(120.59,222.47) 120.59,223.62 119.03,225.17 109.63,225.17 108.2,223.74 v3(108.2,218.75)
  BOTTOM w0.102: v2(121.47,222.47) v3(120.59,222.47)
NGFF_POWER_CTRL_1: length 2.9
  BOTTOM w0.102: v2(131.48,214.3) R15.2 131.38,212.95 Q3.G
NGFF_POWER_CTRL_V2: length 6.6
  TOP w0.102: C864.1 R1716.1 129.56,217.56 129.8,217.32 131.1,217.32 v3(131.3,217.53)
  BOTTOM w0.102: v3(131.3,217.53) 131.3,217.25 130.68,216.63 Q128.B 129.89,217.84 v2(129.95,217.91)
NGFF_REFCLKN0: length 6.9
  TOP w0.102: R23.1 105.02,215.75 105.8,215.75 106.13,216.08 ; NGFF1.49 109.5,216.75 109.36,216.61 106.66,216.61 106.13,216.08 ; v1(105.87,216.33) 106.13,216.08
NGFF_REFCLKN1: length 5.2
  TOP w0.102: TP84.1 106.84,223.77 106.69,223.63 106.69,223.27 106.83,223.13 108.35,223.13 108.87,222.61 109.36,222.61 109.5,222.75 NGFF1.73
NGFF_REFCLKP0: length 6.9
  TOP w0.102: v1(107.54,216.03) 107.54,216.39 ; 107.54,216.39 106.75,216.39 105.89,215.54 105.02,215.54 R22.1 ; 107.54,216.39 109.36,216.39 109.5,216.25 NGFF1.47
NGFF_REFCLKP1: length 5.5
  TOP w0.102: TP83.1 106.35,223.77 106.48,223.65 106.48,223.18 106.74,222.91 108.26,222.91 108.78,222.39 109.36,222.39 109.5,222.25 NGFF1.71
NGFF_W_DISABLE1_N: length 4.1
  TOP w0.102: NGFF1.56 v3(120.2,218.5) 121.58,218.5 R1620.2
  BOTTOM w0.102: v3(120.2,218.5) v2(119.39,218.5)
NGFF_W_DISABLE2_N: length 3.5
  TOP w0.102: R1621.2 121.1,217.42 120.79,217.73 v1(120.68,217.73) 120.68,217.77 120.45,218 NGFF1.54
ODTA0: length 46.7
  TOP w0.102: v1(49.44,109.9) 51.33,109.9 v4(51.68,110.26) 51.89,110.47 52,110.47 52.02,110.48 MEM1.K1 ; GPU1.L18 78.57,101.4 v4(78.19,101.02)
  L3 w0.127: v4(51.68,110.26) 52.04,110.26 52.66,110.87 53.86,110.87 54.53,111.54 54.53,111.57 54.86,111.9 55.25,111.9 55.37,112.01 v4(55.62,112.01) 55.71,112.01 56.65,111.08 56.65,110.5 57.49,109.66 61.43,109.66 62.21,108.88 68.74,108.88 69.18,108.43 73.52,108.43 74.68,107.27 76.08,107.27 76.42,107.62 76.45,107.62 76.98,108.15 76.98,108.15 77.23,108.4 77.57,108.4 77.85,108.13 77.85,106.96 77.91,106.89 77.91,104.57 77.54,104.2 77.48,104.2 77.01,103.73 77.01,103.22 77.63,102.6 77.63,102.32 78.19,101.75 v4(78.19,101.02)
  L4 w0.127: v4(55.62,112.01) 55.88,112.01 57.45,110.45 57.97,110.45 58.11,110.58 v4(59.38,110.58)
  BOTTOM w0.102: MEM3.K1 59.27,110.48 v4(59.38,110.58)
ODTA1: length 46.4
  TOP w0.102: v4(59.44,93.49) 58.81,92.86 MEM2.K1 ; v4(78.16,98.94) 77.8,99.3 GPU1.K16
  L3 w0.127: v3(51.69,93.53) 54,93.53 54.26,93.27 55.06,93.27 55.21,93.12 v4(56.15,93.12) 56.15,93.48 56.02,93.6 56.01,93.6 55.81,93.81 55.81,94.09 55.91,94.19 56.47,94.19 56.66,93.99 57.03,93.99 57.16,94.12 57.16,94.39 57.28,94.52 57.54,94.52 57.66,94.39 57.66,94.12 57.79,93.99 58.04,93.99 58.17,94.12 58.17,94.39 58.3,94.52 58.55,94.52 58.68,94.39 58.68,94.12 58.81,93.99 59.58,93.99 59.97,94.38 59.97,94.85 60.1,94.98 60.9,94.98 61.25,94.63 66.56,94.63 66.73,94.47 69.57,94.47 69.63,94.52 70.53,94.52 70.91,94.14 72.65,94.14 73.14,93.65 74.4,93.65 74.78,94.04 76.42,94.04 76.43,94.03 77.05,94.03 77.12,93.96 77.55,93.96 77.82,94.23 77.82,94.58 77.79,94.61 77.79,95.43 77.27,95.95 77.27,96.16 77.5,96.39 77.5,96.68 77.37,96.8 77.19,96.8 76.99,97.01 76.99,97.21 77.12,97.34 77.56,97.34 77.78,97.12 78.24,97.12 78.78,97.66 78.78,98.32 v4(78.16,98.94)
  L4 w0.127: v4(59.44,93.49) 59.29,93.64 56.35,93.64 56.15,93.44 v4(56.15,93.12)
  BOTTOM w0.102: MEM4.K1 52.39,92.82 v3(51.69,93.53) 50.96,93.53 50.94,93.5 50.24,93.5 v2(49.94,93.2)
OSD_BIST_N: length 70
  TOP w0.102: v3(36.14,24.25) 35.62,24.77 R744.2 ; v3(46.34,77.85) 46.32,77.85 45.89,77.42 44.18,77.42 43.78,77.81 R535.1
  L4 w0.127: v3(36.14,24.25) 36.55,23.84 37.87,23.84 40.34,26.31 40.34,29.05 40.33,29.06 40.33,29.66 40.34,29.67 40.34,30.71 39.89,31.16 39.89,33.75 39.01,34.63 39.01,37.12 38.56,37.57 38.56,39.56 39.03,40.03 39.03,40.67 38.51,41.19 38.51,49.2 37.7,50.02 37.7,51.23 37.38,51.55 37.38,54.04 34.58,56.85 34.58,63.96 36.25,65.63 36.72,65.63 39.28,68.19 39.28,68.55 41.21,70.48 41.57,70.48 45.83,74.74 45.83,77.36 46.32,77.85 v3(46.34,77.85)
  BOTTOM w0.102: v2(35.53,24.78) 36.06,24.25 v3(36.14,24.25)
OSD_BIST_N_1: length 6.7
  TOP w0.254: v3(45.47,77.88) 45.44,77.88 45.26,78.05 R535.2
  BOTTOM w0.254: Q12.2 43.19,76.53 43.52,76.86 43.52,77.52 42.91,78.13 v2(42.91,78.59) 43,78.68 43.85,78.68 44.66,77.88 v3(45.47,77.88)
OSD_DN: length 190.5
  TOP w0.102: R1755.1 C238.1 32.16,25.72 R1758.1 34.64,26.61 35,26.96 35,26.99 v3(35,27) ; CPU1.AL6 73.8,157.5 v4(73.8,157.18)
  L3 w0.127: v4(73.8,157.18) 73.08,157.9 70.1,157.9 69.82,158.18 66.23,158.18 66.2,158.16 65.93,158.16 65.68,157.9 64.63,157.9 64.44,158.09 58.43,158.09 57.63,158.89 52.8,158.89 50.03,161.66 43.33,161.66 42.96,161.29 42.96,160.96 44.41,159.51 44.41,152.97 43.15,151.7 40.36,151.7 39.71,152.35 39.15,152.35 38.64,151.84 v3(38.64,151)
  L4 w0.127: v3(38.64,151) 38.64,149.25 38.04,148.65 38.04,139.43 38.77,138.71 38.77,134.65 38.53,134.41 38.53,124.75 40.89,122.39 40.89,81.25 37.83,78.18 37.83,73.64 30.18,65.99 30.18,56.51 34.1,52.59 34.1,50.19 34.36,49.93 34.36,45.22 31.67,42.53 31.67,30.68 33.48,28.87 34.35,28.87 34.87,28.34 34.87,28.28 35,28.15 35,27.01 v3(35,27)
  BOTTOM w0.102: v2(38.12,150.38) 38.14,150.38 38.64,150.88 v3(38.64,151)
OSD_DN_R: length 3.5
  TOP w0.102: PWRCN1.2 30.77,24.25 31.34,23.69 31.91,23.69 R1755.2 33.14,23.81 v1(33.17,23.79)
OSD_MENU: length 302.1
  TOP w0.102: R758.1 C585.1 R755.1 33.88,28.51 34.09,28.3 v3(34.25,28.3) ; v3(81.39,49.05) 82.08,49.73 82.77,49.73 84.49,48.02 84.49,48.01 87.08,45.42 107.69,45.42 107.92,45.64 111.6,45.64 112.03,45.22 119.88,45.22 120.33,44.78 120.33,44.13 121.03,43.43 v3(125.97,43.43) ; v3(63.53,154.04) 65.36,155.86 65.36,156.22 66.45,157.31 66.45,158.85 67.71,160.11 70.41,160.11 CPU1.AH1
  L3 w0.127: v3(149.13,42.85) 148.83,43.15 144.29,43.15 143.88,42.75 136.87,42.75 136.18,42.06 127.34,42.06 v3(125.97,43.43)
  L4 w0.127: v3(41.77,28.42) 41.97,28.63 41.97,30.18 41.54,30.61 41.54,31.13 40.9,31.76 40.9,34.17 40.14,34.94 40.14,37.81 40.38,38.05 40.38,40.76 40.14,41.01 40.14,50.86 38.46,52.53 38.46,54.84 35.59,57.71 35.59,63.54 36.04,63.98 36.54,63.98 40.29,67.73 40.29,68.11 41.32,69.14 41.32,69.16 41.63,69.47 42.27,69.47 48.88,76.08 48.88,79.52 48.21,80.19 47.35,80.19 46.9,80.64 46.9,82.62 45.88,83.63 45.88,120.23 48.18,122.53 48.18,125.37 51.94,129.13 51.94,141.47 51.73,141.67 51.73,146.17 52.04,146.48 52.19,146.48 54.01,148.3 54.01,152.34 54.74,153.07 62.57,153.07 v3(63.53,154.04)
  BOTTOM w0.102: v3(149.13,42.85) 148.95,42.67 v2(148.12,42.67) 147.73,43.05 R80206.1 ; v3(34.25,28.3) 34.53,28.02 38.2,28.02 v2(38.34,28.16) 38.37,28.16 38.46,28.07 41.44,28.07 41.77,28.4 v3(41.77,28.42) 41.77,30.94 42.2,31.37 42.25,31.37 42.83,31.95 42.83,32.26 44.08,33.5 47.81,33.5 49.66,31.64 55.35,31.64 55.75,32.04 59.72,32.04 60.04,31.72 64.39,31.72 65.5,32.83 65.5,42.3 66.36,43.17 72.36,43.17 73.95,44.75 77.64,44.75 79.49,46.61 79.49,46.61 81.39,48.5 v3(81.39,49.05)
OSD_MENU_R: length 3.5
  TOP w0.102: PWRCN1.1 29.93,25.07 30.51,25.65 30.51,26.2 v1(30.99,26.68) 31.4,27.09 R758.2
OSD_MENU_SIO: length 11
  TOP w0.102: v3(149.92,48.72) 148.74,48.72 148.24,48.22 148.24,47.5 148.68,47.06 148.82,47.06 149.09,46.79 149.09,46.13 149.26,45.96 U109.109
  BOTTOM w0.102: v3(149.92,48.72) 149.24,48.04 149.24,47.65 148.97,47.39 148.77,47.39 148.12,46.74 v2(148.12,45.72) 147.73,45.34 R80206.2
OSD_UP: length 241.8
  TOP w0.102: v4(67.06,158.6) 68.16,159.7 70.23,159.7 70.23,159.69 70.77,159.69 70.77,159.7 71.03,159.7 71.33,159.4 CPU1.AJ3 ; v3(39.66,28.55) 38.62,28.55 v1(38.51,28.45) 38.32,28.45 C582.1 36.23,26.35 35.59,26.35 R742.2 34.51,25.27 R744.1 34.51,24.39 34.04,23.91 34.04,23.72 33.12,22.8 R743.1
  L3 w0.127: v4(67.06,158.6) 66.62,159.04 64.97,159.04 64.87,158.94 58.66,158.94 57.26,160.34 52.43,160.34 50.34,162.43 39.39,162.43 38.06,163.77 34.23,163.77 33.74,163.28 27.51,163.28 24.39,166.41 17.02,166.41 14.02,163.41 14.02,159.51 14.96,158.57 14.96,154.35 16.91,152.39 16.91,141.72 18.55,140.08 28.7,140.08 28.7,140.08 32.99,140.08 37.35,135.73 37.35,122.1 37.94,121.51 37.94,121.12 37.3,120.48 37.3,117.14 38.4,116.05 38.4,110.52 41.64,107.29 41.64,81.08 44.05,78.66 v3(45.83,78.66)
  L4 w0.127: v3(39.66,28.55) 39.86,28.75 39.86,30.75 38.76,31.86 38.76,36.96 38.26,37.45 38.26,39.65 38.78,40.17 38.78,40.57 38.26,41.09 38.26,49.1 37.45,49.91 37.45,51.13 37.13,51.44 37.13,53.94 34.21,56.86 34.21,60.13 33.4,60.94 33.4,61.33 33.67,61.61 33.67,61.61 34,61.93 34,62.58 33.38,63.2 33.38,63.59 33.66,63.86 34.12,63.86 35.42,65.16 35.42,65.81 36.37,66.76 37.08,66.76 42.1,71.78 42.1,73.76 43.64,75.31 43.64,77.09 45.22,78.66 v3(45.83,78.66)
  BOTTOM w0.102: v2(40.55,28.57) 40.52,28.55 v3(39.66,28.55)
OSD_UP_R: length 7.8
  TOP w0.102: PWRCN1.3 30.95,23.75 31.24,23.46 31.57,23.46 32.23,22.8 R743.2 32.29,22.61 32.75,22.15 33,22.15 33.32,21.83 33.32,18.55 v1(33.18,18.41)
OZ554_ENA: length 12.4
  TOP w0.102: v3(42.88,33.05) 42.58,32.74 R79625.1 ; C3458.1 41.24,37.66 v3(41.77,37.13) 41.61,36.98 R79627.1
  L4 w0.127: v3(42.88,33.05) 42.73,33.2 42.73,35.18 41.77,36.14 v3(41.77,37.13)
  BOTTOM w0.102: U120.3 41.21,36.58 v3(41.77,37.13) 41.77,37.16 42.53,37.92 v2(43.3,37.92)
OZ554_PWM: length 8.7
  TOP w0.254: R79623.1 41.44,33.9 41.44,34.63 C8.1 41.56,34.67 v3(42.81,35.92) 43.43,35.92 R79621.1
  BOTTOM w0.254: v3(42.81,35.92) 42.78,35.89 42.78,35.64 v2(42.3,35.16) 42.17,35.03 40.39,35.03 39.84,35.58 U120.5
OZ554_VIN: length 6.7
  TOP w0.508: R5.2 42.67,37 v3(42.65,36.98) 42.65,36.8 42.06,36.21 42.03,36.21 41.69,35.86 C3457.1
  BOTTOM w0.305: U120.4 40.72,36.08 40.75,36.04 v2(40.9,36.04) 41.71,36.04 v3(42.65,36.98)
P_GFX_TXN0: length 10.3
  TOP w0.102: CPU1.M1 70.42,173.08 69.69,173.08 68.11,174.66 68.11,177.47 67.3,178.28 67.3,179.18 67,179.49 66.63,179.49 66.5,179.36 66.5,178.74 66.38,178.61 66.01,178.61 65.88,178.74 C1811.1
P_GFX_TXN1: length 10.7
  TOP w0.102: C1813.1 67.29,180.59 67.98,179.91 67.98,178.52 68.53,177.96 68.53,174.94 69.97,173.5 70.23,173.5 70.53,173.8 CPU1.L2
P_GFX_TXN2: length 14.1
  TOP w0.102: C1814.1 65.88,182.35 66.01,182.22 66.4,182.22 66.53,182.35 66.53,182.92 66.66,183.05 66.77,183.05 67.04,182.78 67.38,182.44 ; v1(67.09,182.14) 67.38,182.44 ; 67.38,182.44 68.4,181.42 68.4,178.69 68.95,178.14 68.95,175.38 70.1,174.23 70.1,174.23 70.25,174.08 70.71,174.08 70.74,174.1 71.03,174.1 71.05,174.08 71.59,174.08 71.7,173.98 CPU1.L3
P_GFX_TXN3: length 13.1
  TOP w0.102: CPU1.J2 70.87,175.4 69.59,176.68 69.59,178.4 69.04,178.95 69.04,183.51 67.93,184.63 66.96,184.63 ; v1(66.96,185.01) 66.96,184.63 ; 66.96,184.63 66.3,184.63 C122.1
P_GFX_TXP0: length 10.7
  TOP w0.102: v1(66.91,180.06) 66.91,179.71 ; 66.91,179.71 C1809.1 ; 66.91,179.71 67.09,179.71 67.52,179.27 67.52,178.37 68.33,177.56 68.33,174.75 69.78,173.29 70.31,173.29 70.32,173.3 70.63,173.3 70.93,173 CPU1.M2
P_GFX_TXP1: length 10.6
  TOP w0.102: CPU1.L1 69.98,173.8 68.75,175.03 68.75,178.05 68.19,178.61 68.19,180 67.38,180.81 66.71,180.81 66.58,180.94 66.58,181.64 66.45,181.76 66.16,181.76 C1810.1
P_GFX_TXP2: length 14.2
  TOP w0.102: v1(66.89,183.64) 66.89,183.24 ; 66.89,183.24 66.86,183.26 C1812.1 ; 66.89,183.24 68.61,181.51 68.61,178.78 69.17,178.23 69.17,175.47 70.32,174.32 70.32,174.32 70.34,174.3 70.63,174.3 70.65,174.32 71.11,174.32 71.14,174.3 72,174.3 CPU1.L4
P_GFX_TXP3: length 12.7
  TOP w0.102: C1815.1 66.14,184.41 67.84,184.41 68.82,183.42 68.82,178.86 69.37,178.31 69.37,176.59 70.42,175.55 70.42,175.29 70.34,175.21 70.2,175.21 70.1,175.31 CPU1.J1
P_RX_ZVDD: length 23.1
  TOP w0.203: v4(73.7,168) 74.1,168.4 CPU1.U6 ; v3(59.93,171.68) 60.1,171.85 R2003.1 R557.1
  L3 w0.203: v4(73.7,168) 73.7,167.15 73.09,166.54 69.05,166.54 67.55,168.05 67.55,169.54 66.49,170.6 61.01,170.6 v3(59.93,171.68)
  BOTTOM w0.203: v2(72.58,167.72) 72.8,167.94 73.64,167.94 v4(73.7,168)
P_TX_ZVDD: length 23.5
  TOP w0.203: v4(74.5,168) 74.9,168.4 CPU1.U7 ; R558.2 59.17,172.7 v3(59.17,171.68)
  L3 w0.203: v3(59.17,171.68) 59.17,171.61 60.77,170.01 66.35,170.01 67.24,169.12 67.24,167.92 68.92,166.24 73.22,166.24 74.5,167.52 v4(74.5,168)
  BOTTOM w0.203: v4(74.5,168) v2(74.5,167.21)
PANEL_ON_1: length 4.3
  BOTTOM w0.102: R41.2 33.31,113.73 R42.1 ; v2(32.32,114.49) 32.57,114.74 R42.1 ; R42.1 33.37,114.68 R39.1 R33.1
PANEL_ON_2: length 3.4
  BOTTOM w0.102: Q10.B 34.83,117.16 R42.2 32.68,115.63 32.42,115.9 v2(32.39,115.9)
PANEL_ON_3: length 17
  BOTTOM w0.102: v2(39.21,120.52) R20.2 39.21,118.13 39.78,117.56 39.78,117.13 39.66,117.01 39.66,116.56 38.91,115.81 Q5.D 38.7,115.01 38.7,112.84 38.13,112.27 38.13,110.44 37.78,110.08 37.71,110.08 37.55,110.08 37.53,110.06 36.48,110.06 C14.2 R19.1 34.26,109.23 33.13,110.36 U1.3
PANEL_ON_4: length 15
  BOTTOM w0.102: Q1.G 37.78,111.4 37.78,113.46 Q5.G 37.99,115.21 37.99,116.3 37.53,116.76 37.47,116.76 36.99,117.24 36.99,118.05 R30.1 37.31,118.49 R26.2 36.42,119.93 35.92,120.42 v2(35.24,120.42) 34.5,120.42 34.07,119.99 Q10.C
PANEL_ON_5: length 4.7
  BOTTOM w0.102: R8.1 39.28,110.64 40.22,111.58 v2(40.22,111.94) 40.06,112.09 39.39,112.09 Q1.D
PANEL_SEL1_CABLE: length 4.4
  TOP w0.102: CONVT1.7 29.02,35.15 29.83,34.34 v1(30.06,34.34) 30.18,34.34 30.89,35.05 R1730.2 R1734.2
PANEL_SEL1_CABLE_EC: length 143.7
  TOP w0.102: v3(146.39,46.18) 146.46,46.11 U109.102 ; R1730.1 v3(32.77,35.05)
  L3 w0.127: v3(145.06,36.2) 143.83,34.96 143.37,34.96 140.02,31.61 139.27,31.61 138.77,32.11 138.77,35.93 137.59,37.1 131.42,37.1 130.03,35.71 118.6,35.71 115.98,38.33 113.6,38.33 112.2,39.73 110.75,39.73 109.78,38.75 102.76,38.75 102.58,38.94 91.33,38.94 89.81,40.46 89.49,40.46 84.36,45.58 72.03,45.58 64.13,37.68 64.13,37.52 63.85,37.25 63.47,37.25 63.29,37.43 54.83,37.43 54.34,37.92 47.95,37.92 47.35,37.33 45.56,37.33 43.47,35.23 32.95,35.23 v3(32.77,35.05)
  L4 w0.127: v3(145.06,36.2) 145.06,41.01 147.48,43.42 147.48,44.85 146.48,45.85 146.48,46.09 v3(146.39,46.18)
  BOTTOM w0.102: v2(146.39,45.31) v3(146.39,46.18)
PANEL_SEL2_CABLE: length 4.3
  TOP w0.102: R1731.2 R287.2 31.01,32.94 v1(30.08,32.94) 28.88,34.15 CONVT1.8
PANEL_SEL2_CABLE_EC: length 148.2
  TOP w0.102: R287.1 v3(32.77,33.02) ; U109.103 146.86,46.44 146.48,46.82 v3(146.48,46.93)
  L3 w0.127: v3(146.52,35.25) 145.36,35.25 144.28,34.16 143.71,34.16 140.35,30.81 138.21,30.81 135.38,33.64 130.9,33.64 130.66,33.88 128.65,33.88 127.76,32.99 119.52,32.99 117.13,35.39 113.97,35.39 112.49,33.92 110.9,33.92 109.57,35.24 109.19,35.24 109.1,35.16 93.98,35.16 90.45,38.68 89.48,39.66 89.16,39.66 84.03,44.78 72.36,44.78 67.51,39.93 67.51,37.77 66.05,36.31 63.27,36.31 62.96,36.63 54.5,36.63 54,37.12 48.44,37.12 48.05,36.73 48.05,36.13 46.09,34.16 35.49,34.16 34.35,33.02 v3(32.77,33.02)
  L4 w0.127: v3(146.52,35.25) 146.52,35.4 145.44,36.48 145.44,40.85 147.86,43.27 147.86,45 146.86,46.01 146.86,46.56 v3(146.48,46.93)
  BOTTOM w0.102: v3(146.52,35.25) 146.79,35.25 147.2,35.66 v2(147.22,35.66)
PANEL_SEL3_CABLE: length 5.1
  TOP w0.102: R1732.2 R1733.2 30.51,30.99 v1(30.06,31.45) 29.6,31.9 29.6,32.59 29.04,33.15 CONVT1.9
PANEL_SEL3_CABLE_EC: length 149
  TOP w0.102: R1732.1 32.8,29.97 v3(33.05,30.23) ; v3(147.33,46.28) 147.26,46.21 U109.104
  L3 w0.127: v3(145.45,34.67) 144.56,33.78 143.86,33.78 140.51,30.43 134.68,30.43 134.31,30.79 134.31,32.26 133.69,32.88 131.81,32.88 131.43,32.5 128.56,32.5 128.28,32.22 119.07,32.22 117.32,33.97 113.62,33.97 112.81,33.15 109.81,33.15 108.57,34.39 93.67,34.39 89.16,38.89 88.84,38.89 83.71,44.02 72.67,44.02 68.27,39.61 68.27,37.45 66.37,35.55 48.77,35.55 46.44,33.22 45.78,33.22 42.53,29.97 34.13,29.97 33.97,30.14 33.14,30.14 v3(33.05,30.23)
  L4 w0.127: v3(145.45,34.67) 146.61,34.67 146.99,35.05 146.99,35.47 145.83,36.64 145.83,40.69 148.24,43.11 148.24,45.37 v3(147.33,46.28)
  BOTTOM w0.102: v3(145.45,34.67) 145.45,34.19 145.7,33.93 v2(145.7,33.9) ; v3(33.05,30.23) 33,30.23 32.8,30.43 32.32,30.43 31.96,30.78 v2(31.96,31.11)
PB_IN_N_1: length 7.9
  TOP w0.102: R385.2 C197.2 R379.2 140.27,57.53 v1(140.44,57.35) 140.8,57.35 141.61,56.54 v3(141.61,55.98) U109.72
  BOTTOM w0.102: R79669.1 141.67,55.98 v3(141.61,55.98)
PB_IN_N_2: length 16
  TOP w0.102: U109.111 150.06,45.72 150.17,45.83 150.17,46.46 v3(148.78,47.84)
  L4 w0.127: v3(148.78,47.84) 146.77,49.85 v4(146.77,55.32)
  BOTTOM w0.102: R79669.2 143.36,56.78 144.58,56.78 v2(144.61,56.8) 144.63,56.78 145.32,56.78 146.77,55.33 v4(146.77,55.32)
PB_IN_SW1: length 12.5
  TOP w0.254: PWRCN1.6 28.43,22.25 28.07,22.61 28.07,25.88 v3(28.74,26.54) 27.72,27.56 27.72,28.7 v1(28.23,29.21)
  BOTTOM w0.254: v2(25.92,26.23) R1760.2 R1756.1 28.42,26.23 v3(28.74,26.54)
PCB_VER_ID: length 5.4
  BOTTOM w0.102: U4101.49 v2(106.51,60.53) 106.56,60.58 R79720.1 R79721.2
PCH_AUD_RST_N: length 42.7
  TOP w0.102: v3(156.87,51.69) 156.87,52.11 157.4,52.65 157.4,53.35 157.64,53.58 U109.19 159.67,53.58 160.03,53.21 161.26,53.21 R289.1 ; R637.1 143.95,27.8 v3(143.92,27.77)
  L4 w0.102: v3(156.87,51.69) 157.61,50.94 157.61,44.14 157.94,43.81 157.94,43.78 158.4,43.32 158.4,39.79 158.31,39.69 158.31,38.26 158.77,37.8 158.77,36.88 153.87,31.98 150.91,31.98 146.7,27.77 v3(143.92,27.77)
  BOTTOM w0.102: v3(143.92,27.77) 143.92,27.52 v2(144.36,27.08)
PCH_AUD_RST_N_1: length 4.1
  TOP w0.102: Q63.5 144.56,30.68 145.04,30.2 v1(145.04,30.18) 145.04,30.05 144.65,29.65 R637.2
PCH_CLK48_F: length 4.1
  TOP w0.102: v4(77.76,147.07) 77.35,147.47 77.35,147.87 77.4,147.92 CPU1.BC10
  BOTTOM w0.102: R1645.2 77.52,146.05 v2(77.92,146.05) 77.92,146.9 v4(77.76,147.07)
PCH_SATA_LED_1: length 5.7
  BOTTOM w0.254: Q1213.C 29.56,26.61 28.35,25.41 v2(28.35,25.15) R1759.2 29.43,24.61 Q38.B
PCH_SATA_LED_R: length 3.1
  BOTTOM w0.254: R1754.2 29.56,29.59 30.77,29.59 v2(30.89,29.72) 31.47,29.15 Q1213.B
PCIE_CALR_RX: length 11.6
  TOP w0.102: v4(95.23,105.19) 94.85,105.19 94.5,105.53 91.26,105.53 91.07,105.34 91.07,105.2 90.74,104.87 86.87,104.87 GPU1.AA22
  BOTTOM w0.102: v4(95.23,105.19) 95.15,105.19 94.72,105.62 v2(94.72,105.92) 94.72,106.14 R1162.1
PCIE_CALR_TX: length 16.3
  TOP w0.102: v4(96.73,102.84) 95.33,102.84 94.91,103.27 91.26,103.27 90.95,103.59 87.76,103.59 87.28,104.07 86.26,104.07 85.93,104.4 GPU1.Y22
  BOTTOM w0.102: v4(96.73,102.84) 96.73,102.85 96.73,103.76 v2(96.63,103.86) 95.94,104.55 95.94,106.02 96.32,106.41 R1161.1
PCIE_RST#: length 216.4
  TOP w0.102: NGFF1.52 v3(119.88,217.5) ; NGFF1.66 v3(119.88,221)
  L3 w0.127: v3(119.88,217.5) 119.36,218.02 119.36,220.48 v3(119.88,221)
  L4 w0.127: v3(119.88,221) 120.88,221 121.84,221.96 124.88,221.96 143.69,203.14 155.12,203.14 161.07,197.19 162.19,197.19 164.77,194.61 164.77,156.03 163.6,154.85 163.6,133.48 165.6,131.48 165.6,113.27 159.6,107.26 159.6,105.58 158.53,104.52 158.53,100.81 159.27,100.08 159.27,98.7 157.88,97.31 157.88,96.44 158.43,95.88 158.43,90.11 155.8,87.47 155.8,86.95 154.93,86.08 154.93,71.66 154.72,71.44 154.72,66.66 153.79,65.73 153.79,59.71 153.31,59.23 153.31,56.44 154.43,55.31 154.43,52.44 154.87,52 155.2,52 v3(155.22,51.98)
  BOTTOM w0.102: v2(155.55,51.24) 155.55,51.65 v3(155.22,51.98) 154.98,52.22 RN13.1
PCIE_RST_N: length 24.5
  TOP w0.102: R1678.2 v3(57.54,148.84) ; v4(74.6,155.98) 74.9,156.28 CPU1.AN7
  BOTTOM w0.102: v4(74.6,155.98) v2(73.79,155.98) 73.64,155.98 73.24,156.39 71.78,156.39 69.98,154.59 66.51,154.59 66.28,154.82 65.63,154.82 65.43,155.02 62,155.02 61.21,154.23 59.44,154.23 57.35,152.15 57.35,149.03 v3(57.54,148.84)
PCIE_RST_N_A: length 1.7
  TOP w0.102: R1678.1 55.85,149.35 55.66,149.54 C1738.1
PCIRST1#: length 20.2
  TOP w0.102: U109.30 157.45,57.98 157.15,57.68 157.15,57.16 156.88,56.89 156.6,56.89 153.78,54.08 152.2,54.08 v3(152.18,54.1)
  L3 w0.127: v3(152.18,54.1) 152.6,53.68 154.85,53.68 155.53,54.36 v3(156.83,54.36)
  BOTTOM w0.102: RN13.6 153.2,53.59 152.69,54.1 v3(152.18,54.1) ; v3(156.83,54.36) 157.4,54.36 158.67,55.63 v2(159.85,55.63) R79690.1
PCIRST3#: length 23.2
  TOP w0.102: U109.81 147.92,52.38 148.42,52.88 149.39,52.88 149.56,53.05 150.07,53.05 150.38,52.74 v3(155.18,52.74)
  BOTTOM w0.102: RN13.7 153.7,53.72 153.83,53.85 154.21,53.85 154.35,53.71 RN13.8 154.72,53.19 155.16,52.74 v3(155.18,52.74) 155.57,52.74 155.66,52.83 v2(156.09,52.83) 156.09,52.35 156.29,52.15 158.96,52.15 159.9,53.09 161.13,53.09 R79689.1
PD4405_A: length 3.7
  BOTTOM w0.102: v2(71.28,65.28) 71.66,64.9 PD4405.A 71.57,63.66 PQ4409.B
PD4405_K: length 3.8
  BOTTOM w0.102: PD4405.K 74.96,63.75 v2(75.73,64.52) 75.73,65.02 75.34,65.41 PR4458.2
PD_N: length 8.2
  TOP w0.102: Q1249.D 127.48,30.16 128.81,31.5 v3(128.81,31.88) ; U118.36 132.94,32.44 v3(132.53,32.03)
  BOTTOM w0.102: v3(132.53,32.03) v2(130.82,32.03) 128.96,32.03 v3(128.81,31.88)
PEG_C_RXN0: length 8
  TOP w0.102: v4(92.2,112.65) 91.58,112.03 91.58,110.58 GPU1.AG31
  BOTTOM w0.102: 90.99,113.75 90.76,113.98 90.34,113.98 89.9,114.43 89.9,114.69 C1840.1 ; 90.99,113.75 v2(91.22,113.98) ; 90.99,113.75 91.21,113.53 91.21,112.48 91.46,112.24 91.78,112.24 v4(92.2,112.65)
PEG_C_RXN1: length 8.6
  TOP w0.102: v4(90.59,112) 91,111.6 91,110.92 90.86,110.55 90.86,110.21 90.93,110.12 90.93,109.93 90.93,109.93 90.93,109.86 90.6,109.53 GPU1.AF28
  BOTTOM w0.102: C1842.1 88,114.92 88,113.4 89.19,112.21 89.79,112.21 ; 89.79,112.21 v2(89.79,111.88) ; 89.79,112.21 90.38,112.21 v4(90.59,112)
PEG_C_RXN2: length 12.5
  TOP w0.102: GPU1.AF26 v4(90.2,107.2)
  BOTTOM w0.102: C1844.1 86.65,113.85 86.31,113.51 86.31,113.08 ; v4(90.2,107.2) 91.07,108.07 91.07,109.02 89.82,110.26 87.92,110.26 86.31,111.87 86.31,113.08 ; v2(86.64,113.08) 86.31,113.08
PEG_C_RXN3: length 11.1
  TOP w0.102: GPU1.AD26 v4(89.4,108)
  BOTTOM w0.102: v2(83.84,113.89) 84.19,113.89 ; 84.19,113.89 84.19,112.09 87.36,108.92 87.42,108.85 87.73,108.85 88.59,108 v4(89.4,108) ; 84.19,113.89 84.19,114.92 C1845.1
PEG_C_RXP0: length 8.6
  TOP w0.102: v4(92.2,112.02) 92.16,112.06 91.91,112.06 91.79,111.94 91.79,110.41 GPU1.AH30
  BOTTOM w0.102: v2(92.98,111.48) 92.45,112.02 v4(92.2,112.02) 91.37,112.02 91,112.39 91,113.44 90.67,113.77 90.25,113.77 89.68,114.34 89.68,115.14 C1838.1
PEG_C_RXP1: length 8.7
  TOP w0.102: v4(90.59,112.64) 91.2,112.03 91.2,110.88 91.06,110.51 91.06,110.28 91.13,110.18 91.13,109.69 91.22,109.6 GPU1.AG29
  BOTTOM w0.102: C1839.1 88.22,114.92 88.22,113.92 ; v2(88.54,113.92) 88.22,113.92 ; 88.22,113.92 88.22,113.49 89.28,112.43 90.38,112.43 v4(90.59,112.64)
PEG_C_RXP2: length 12.5
  TOP w0.102: GPU1.AF27 v4(90.2,108)
  BOTTOM w0.102: v2(88.48,109.73) 88.48,110.05 ; 88.48,110.05 87.83,110.05 86.09,111.78 86.09,113.6 86.43,113.94 86.43,114.53 86.3,114.66 85.89,114.66 85.76,114.78 C1841.1 ; 88.48,110.05 89.73,110.05 90.85,108.93 90.85,108.16 90.63,107.93 90.27,107.93 v4(90.2,108)
PEG_C_RXP3: length 11.1
  TOP w0.102: GPU1.AD27 v4(89.4,108.8)
  BOTTOM w0.102: 84.8,111.78 87.51,109.07 87.82,109.07 88.68,108.22 88.81,108.22 88.93,108.34 88.93,108.53 89.2,108.8 v4(89.4,108.8) ; 84.8,111.78 84.41,112.18 84.41,114.92 C1843.1 ; 84.8,111.78 v2(85.04,112.02)
PEG_RXN0: length 112.1
  TOP w0.102: v4(76.1,170.2) 76.5,170.6 CPU1.P9
  BOTTOM w0.102: v2(68.75,173) 69.01,173.26 ; 69.01,173.26 71.53,170.73 76.06,170.73 76.23,170.56 76.23,170.33 v4(76.1,170.2) ; 69.01,173.26 67.22,175.04 61.19,175.04 59.38,173.23 55.61,173.23 52.51,170.13 51.3,168.91 51.3,168.91 50.53,168.15 50.53,166.56 51.3,165.8 51.3,156.85 50.58,156.13 50.58,149.76 50.05,149.23 50.05,144.75 51.53,143.27 51.53,141.29 55.45,137.37 55.45,135.83 61.5,129.78 70.79,129.78 80.44,120.13 85.36,120.13 86.35,119.14 88.71,119.14 89.78,118.07 89.78,116.89 89.91,116.76 90.58,116.76 90.71,116.64 90.71,116.27 90.58,116.14 C1840.2
PEG_RXN1: length 108.5
  TOP w0.102: CPU1.N5 v4(72.9,171.8)
  BOTTOM w0.102: 86.71,118.27 81.07,118.27 70.43,128.91 61.14,128.91 53.7,136.35 53.7,137.89 50.66,140.93 50.66,142.91 49.17,144.39 49.17,149.59 49.7,150.12 49.7,156.49 50.42,157.21 50.42,165.44 49.66,166.2 49.66,168.52 50.42,169.28 55.25,174.1 58.85,174.1 59.78,175.03 61.13,176.38 67.31,176.38 72.07,171.61 72.71,171.61 v4(72.9,171.8) ; 86.71,118.27 v2(86.71,117.92) ; 86.71,118.27 87.33,118.27 88.34,117.26 88.34,116.79 88.21,116.66 87.79,116.66 87.66,116.54 C1842.2
PEG_RXN2: length 111
  TOP w0.102: v4(75.3,171.8) 75.3,172.45 75.42,172.57 75.58,172.57 75.7,172.45 CPU1.N8
  BOTTOM w0.102: v4(75.3,171.8) 75.4,171.9 75.4,172.19 75.26,172.33 71.95,172.33 67.45,176.83 60.95,176.83 59.59,175.48 59.18,175.06 56.03,175.06 ; C1844.2 86.31,116.48 86.31,117.1 85.59,117.82 80.89,117.82 70.25,128.46 60.96,128.46 53.21,136.21 53.21,137.75 50.21,140.75 50.21,142.72 48.73,144.21 48.73,149.77 49.26,150.3 49.26,156.68 49.97,157.39 49.97,165.25 49.21,166.01 49.21,168.7 55.57,175.06 56.03,175.06 ; v2(56.03,174.7) 56.03,175.06
PEG_RXN3: length 113.8
  TOP w0.102: CPU1.L6 v4(73.7,173.8)
  BOTTOM w0.102: v4(73.7,173.8) 73.99,173.51 73.99,173.27 73.82,173.1 73.31,173.1 68.04,178.37 61.25,178.37 60.26,177.39 59.23,176.35 50.1,176.35 48.69,174.94 48.69,169.42 48.34,169.07 48.34,165.65 49.1,164.89 49.1,157.76 48.38,157.04 48.38,155.69 46.87,154.18 46.87,150.21 47.85,149.23 47.85,143.84 49.34,142.36 49.34,140.38 52.23,137.49 52.23,135.94 60.59,127.58 69.88,127.58 76.8,120.67 ; 76.8,120.67 80.52,116.94 83.96,116.94 84.19,116.71 84.19,116.48 C1845.2 ; 76.8,120.67 v2(76.56,120.43)
PEG_RXP0: length 112.1
  TOP w0.102: CPU1.P10 77.6,170.9 v4(76.9,170.2)
  BOTTOM w0.102: 89.01,118.55 88.62,118.93 86.26,118.93 85.27,119.92 80.35,119.92 70.7,129.57 61.41,129.57 55.24,135.74 55.24,137.28 51.32,141.2 51.32,143.18 49.83,144.66 49.83,149.32 50.36,149.85 50.36,156.22 51.08,156.94 51.08,165.71 50.32,166.47 50.32,168.24 51.08,169 55.52,173.44 59.29,173.44 61.1,175.26 67.31,175.26 71.62,170.95 76.15,170.95 v4(76.9,170.2) ; 89.01,118.55 v2(88.78,118.32) ; 89.01,118.55 89.57,117.98 C1838.2
PEG_RXP1: length 108.6
  TOP w0.102: CPU1.N6 v4(73.7,171.8)
  BOTTOM w0.102: 82.33,118.48 81.16,118.48 70.52,129.12 61.23,129.12 53.91,136.44 53.91,137.98 50.87,141.02 50.87,143 49.39,144.48 49.39,149.5 49.92,150.03 49.92,156.4 50.63,157.12 50.63,165.53 49.87,166.29 49.87,168.43 50.63,169.19 55.34,173.89 58.94,173.89 59.87,174.82 61.21,176.16 67.22,176.16 71.98,171.39 73.29,171.39 v4(73.7,171.8) ; 82.33,118.48 87.42,118.48 88.55,117.35 C1839.2 ; 82.33,118.48 v2(82.33,118.85)
PEG_RXP2: length 111
  TOP w0.102: CPU1.N9 v4(76.1,171.8)
  BOTTOM w0.102: C1841.2 86.09,116.48 86.09,117.01 85.5,117.61 80.8,117.61 70.16,128.24 60.87,128.24 52.99,136.12 52.99,137.66 50,140.66 50,142.63 48.51,144.12 48.51,149.86 49.04,150.39 49.04,156.77 49.76,157.48 49.76,165.16 49,165.92 49,168.79 55.48,175.27 59.09,175.27 59.5,175.69 59.51,175.69 60.86,177.05 67.54,177.05 70.57,174.02 ; v4(76.1,171.8) 75.35,172.55 72.04,172.55 70.57,174.02 ; 70.57,174.02 v2(70.84,174.29)
PEG_RXP3: length 113.8
  TOP w0.102: CPU1.L7 v4(74.5,173.8)
  BOTTOM w0.102: 69.26,176.85 67.95,178.16 61.34,178.16 60.48,177.3 59.32,176.14 50.19,176.14 48.9,174.85 48.9,169.33 48.55,168.98 48.55,165.74 49.31,164.98 49.31,157.67 48.6,156.95 48.6,155.6 47.09,154.09 47.09,150.3 48.07,149.32 48.07,143.93 49.55,142.45 49.55,140.47 52.45,137.58 52.45,136.03 60.68,127.8 69.97,127.8 80.61,117.16 84.05,117.16 84.41,116.8 84.41,116.48 C1843.2 ; 69.26,176.85 v2(69,176.6) ; 69.26,176.85 73.22,172.89 73.91,172.89 74.21,173.18 74.21,173.51 v4(74.5,173.8)
PEG_TXN0: length 113.4
  TOP w0.102: GPU1.AE31 90.05,110.65 90.05,110.96 89.94,111.08 89.94,112.48 88.4,114.02 84.08,114.02 76.42,121.68 ; v1(76.12,121.38) 76.42,121.68 ; 76.42,121.68 71.03,127.06 67.43,127.06 66.9,126.54 62.61,126.54 v3(62.39,126.33) ; C1811.2 63.51,178.82 63.4,178.92 v3(63.4,179.27)
  BOTTOM w0.102: v3(63.4,179.27) 63.16,179.03 60.98,179.03 59.6,177.66 58.96,177.01 49.82,177.01 48.03,175.22 48.03,169.7 47.68,169.35 47.68,165.38 48.44,164.62 48.44,158.03 47.72,157.31 47.72,155.96 46.21,154.45 46.21,149.94 47.19,148.96 47.19,143.57 48.68,142.09 48.68,140.11 51.45,137.34 51.45,135.8 60.66,126.58 62.14,126.58 v3(62.39,126.33)
PEG_TXN1: length 116.5
  TOP w0.102: GPU1.AD28 89.33,109.53 89.33,110.11 89.26,110.21 89.26,110.55 89.4,110.92 89.4,110.92 89.4,111.18 89.41,111.19 89.41,112.02 88.11,113.32 83.84,113.32 78.11,119.05 69.16,119.05 68.35,119.86 67.63,119.86 64.22,123.28 64.22,124.33 62.9,125.65 61.92,125.65 v3(61.63,125.36) ; v3(63.4,181.05) 63.86,180.59 C1813.2
  BOTTOM w0.102: v3(61.63,125.36) 61.35,125.63 60.67,125.63 60.28,126.02 ; 60.28,126.02 v2(60.06,125.8) ; 60.28,126.02 50.03,136.28 50.03,137.82 48.01,139.84 48.01,141.81 46.53,143.3 46.53,148.69 45.55,149.67 45.55,154.73 47.06,156.24 47.06,157.59 47.78,158.3 47.78,164.34 47.02,165.1 47.02,169.62 47.37,169.97 47.37,175.49 49.55,177.67 58.68,177.67 58.94,177.93 61.22,180.21 63.02,180.21 63.4,180.59 v3(63.4,181.05)
PEG_TXN2: length 117
  TOP w0.102: v3(63.4,182.83) 63.86,182.37 C1814.2 ; GPU1.AC31 88.38,110.58 88.38,112.06 87.82,112.62 83.6,112.62 77.84,118.39 68.88,118.39 68.07,119.2 67.36,119.2 63.56,123 63.56,124.05 62.9,124.71 62.67,124.71 v3(62.39,124.43)
  BOTTOM w0.102: v2(53.85,178.66) 53.85,178.33 ; 53.85,178.33 58.41,178.33 62.14,182.07 63.1,182.07 63.4,182.37 v3(63.4,182.83) ; 53.85,178.33 49.27,178.33 46.71,175.76 46.71,170.24 46.36,169.89 46.36,164.83 47.12,164.07 47.12,158.58 44.89,156.35 44.89,149.39 45.87,148.41 45.87,143.02 47.35,141.54 47.35,139.56 49.37,137.54 49.37,136 58.54,126.83 58.54,125.96 59.6,124.9 61.13,124.9 61.35,124.69 62.14,124.69 v3(62.39,124.43)
PEG_TXN3: length 120.1
  TOP w0.102: C122.2 64.6,185.04 v3(64.16,184.61) ; v1(75.98,117.35) 75.98,117.73 ; 75.98,117.73 68.61,117.73 67.8,118.54 67.09,118.54 62.9,122.73 62.9,123.25 62.39,123.76 61.92,123.76 v3(61.63,123.47) ; 75.98,117.73 77.56,117.73 83.37,111.92 87.51,111.92 87.85,111.58 87.85,111.15 87.8,110.92 87.66,110.55 87.66,110.21 87.73,110.12 87.73,109.53 GPU1.AB28
  BOTTOM w0.102: v3(61.63,123.47) 61.35,123.74 60.9,123.74 60.4,124.24 59.32,124.24 57.88,125.69 57.88,126.56 48.71,135.73 48.71,137.27 46.69,139.29 46.69,141.26 44.23,143.73 44.23,156.63 46.46,158.85 46.46,163.79 45.7,164.56 45.7,169.64 45.33,170 45.33,175.33 49,178.99 52.39,178.99 58.46,185.06 63.71,185.06 v3(64.16,184.61)
PEG_TXP0: length 113.4
  TOP w0.102: GPU1.AF30 90.6,110.33 90.27,110.66 90.27,111.05 90.16,111.17 90.16,112.57 88.49,114.24 84.16,114.24 81.41,116.99 ; 81.41,116.99 71.12,127.28 67.34,127.28 66.81,126.76 62.72,126.76 v3(62.39,127.09) ; 81.41,116.99 v1(81.7,117.28) ; v3(64.16,179.27) 64.6,179.71 C1809.2
  BOTTOM w0.102: v3(62.39,127.09) 62.1,126.8 60.75,126.8 51.66,135.89 51.66,137.43 48.89,140.2 48.89,142.18 47.41,143.66 47.41,149.05 46.43,150.03 46.43,154.36 47.94,155.87 47.94,157.23 48.65,157.94 48.65,164.71 47.89,165.47 47.89,169.26 48.24,169.61 48.24,175.13 49.91,176.8 59.05,176.8 59.82,177.57 61.07,178.82 63.71,178.82 v3(64.16,179.27)
PEG_TXP1: length 116.5
  TOP w0.102: v3(64.16,181.05) 64.6,181.48 C1810.2 ; v3(61.63,126.12) 61.88,125.87 62.99,125.87 64.43,124.42 64.43,123.37 67.72,120.08 68.43,120.08 69.25,119.27 74.58,119.27 ; 74.58,119.27 78.2,119.27 83.93,113.54 88.2,113.54 89.62,112.11 89.62,111.02 89.6,110.88 89.46,110.51 89.46,110.28 89.54,110.18 89.66,110.06 90.18,110.06 90.27,109.96 90.27,109.65 90.14,109.52 89.88,109.52 GPU1.AE29 ; 74.58,119.27 v1(74.58,119.63)
  BOTTOM w0.102: v3(61.63,126.12) 61.35,125.85 60.76,125.85 50.25,136.37 50.25,137.91 48.23,139.93 48.23,141.9 46.75,143.39 46.75,148.78 45.77,149.76 45.77,154.64 47.28,156.15 47.28,157.5 47.99,158.22 47.99,164.43 47.23,165.19 47.23,169.53 47.58,169.88 47.58,175.4 49.64,177.46 58.77,177.46 59.16,177.84 61.31,180 63.11,180 v3(64.16,181.05)
PEG_TXP2: length 117
  TOP w0.102: v3(62.39,125.2) 62.66,124.93 62.99,124.93 63.77,124.14 63.77,123.09 67.45,119.42 68.16,119.42 68.97,118.61 77.93,118.61 83.69,112.84 87.91,112.84 88.59,112.15 88.59,110.41 GPU1.AD30 ; v3(64.16,182.83) 64.6,183.26 C1812.2
  BOTTOM w0.102: 45.53,156.69 45.11,156.26 45.11,149.48 46.09,148.5 46.09,143.11 47.57,141.63 47.57,139.65 49.59,137.63 49.59,136.09 58.76,126.92 58.76,126.05 59.69,125.12 61.22,125.12 61.44,124.9 62.1,124.9 v3(62.39,125.2) ; 45.53,156.69 47.33,158.49 47.33,164.16 46.57,164.92 46.57,169.8 46.92,170.15 46.92,175.68 49.36,178.12 58.5,178.12 62.23,181.85 63.19,181.85 v3(64.16,182.83) ; 45.53,156.69 v2(45.78,156.44)
PEG_TXP3: length 120
  TOP w0.102: v3(63.4,184.61) 63.86,184.15 C1815.2 ; GPU1.AC29 88.53,109.6 88.65,109.73 88.65,109.93 88.53,110.06 88.03,110.06 87.86,110.28 87.86,110.51 88,110.88 88.07,111.15 88.07,111.67 87.6,112.14 83.46,112.14 77.65,117.94 68.7,117.94 67.89,118.76 67.18,118.76 63.11,122.82 63.11,123.34 62.48,123.98 61.88,123.98 v3(61.63,124.23)
  BOTTOM w0.102: v3(63.4,184.61) 63.16,184.85 58.55,184.85 52.48,178.78 49.09,178.78 45.55,175.24 45.55,172.31 ; v2(45.91,172.31) 45.55,172.31 ; 45.55,172.31 45.55,170.09 45.91,169.73 45.91,164.64 46.67,163.88 46.67,158.76 44.44,156.54 44.44,143.82 46.91,141.35 46.91,139.38 48.93,137.36 48.93,135.82 58.1,126.65 58.1,125.77 59.41,124.46 60.49,124.46 60.99,123.96 61.35,123.96 v3(61.63,124.23)
PHASE1_R: length 49.6
  TOP w0.254: PG4.1 118.91,107.21 v3(119.01,107.31)
  L4 w0.254: v3(119.01,107.31) 120.53,108.84 126.85,108.84 130.64,105.05 130.64,98.5 131.77,97.37 131.77,76.45 132.19,76.02 132.95,76.02 133.13,76.2 v3(133.13,76.83)
  BOTTOM w0.254: PR45.2 132.11,76.83 v3(133.13,76.83) ; v3(119.01,107.31) 118.96,107.37 v2(118.96,108.13)
PLTRST*_EC: length 7.9
  TOP w0.102: v3(104.3,52.45) 104.17,52.32 104.17,51.31 v1(104.43,51.05) 104.81,51.05 106.84,53.09 R79697.1
  BOTTOM w0.102: U4101.6 103.27,51.04 103.41,51.18 103.67,51.18 104.3,51.82 v3(104.3,52.45)
PLTRST*_SIO: length 12.9
  TOP w0.102: R352.1 153.46,63.2 152.66,63.2 152.39,62.93 152.39,62.11 151.65,61.37 U109.46 151.65,59.09 v3(151.82,58.93)
  BOTTOM w0.102: C76.2 150.27,56.45 R351.1 151.11,56.91 151.11,58.75 150.66,59.21 150.66,59.52 v2(150.83,59.69) 151.41,59.69 151.57,59.54 151.57,59.18 v3(151.82,58.93)
PLTRST_LAN_N: length 151.9
  TOP w0.102: v3(34.83,15.46) U16.19
  L3 w0.127: v3(34.83,15.46) 37.84,18.47 50.62,18.47 51.32,19.16 55.56,19.16 58.09,21.69 60.66,21.69 66,27.03 66.22,27.03 66.49,27.3 66.53,27.3 68.23,29.01 90.79,29.01 91.74,29.96 92.78,29.96 94.18,28.56 117.22,28.56 117.45,28.79 127.93,28.79 129.28,27.44 137.82,27.44 138.69,26.58 142.21,26.58 143.16,27.53 v3(143.16,27.77)
  L4 w0.127: v3(143.16,27.77) 144.15,28.76 146.82,28.76 155.74,37.68 155.74,38.04 156.08,38.38 156.08,42.78 155.52,43.34 155.52,43.73 155.78,43.99 155.78,47.1 155.74,47.15 155.74,48.17 154.81,49.1 154.81,50.47 v3(154.76,50.52)
  BOTTOM w0.102: v2(35.63,15.62) 35.46,15.46 v3(34.83,15.46) ; v3(154.76,50.52) 154.76,50.9 154.25,51.41 154.03,51.41 153.7,51.74 RN13.2 ; v2(143.03,28.58) 143.03,28.47 143.16,28.35 v3(143.16,27.77)
PLTRST_N: length 216.9
  TOP w0.102: CPU1.BB12 79.29,149.01 79.29,148.69 79.3,148.68 79.3,148.32 79.29,148.31 79.29,147.88 79.41,147.77 79.41,147.37 v4(79,146.96) 79.41,146.56 79.41,146.56 79.41,145.52 78.27,144.38 C77.1 ; LPC1.3 115.46,54.09 114.62,53.25 113.93,53.25 113.72,53.47 113.06,53.47 112.25,54.28 110.94,54.28 110.88,54.22 109.57,54.22 108.44,53.09 R79697.2 ; R352.2 153.96,65.15 154.26,65.45 154.26,65.53 v3(154.26,65.53) 154.26,68.18 153.78,68.67 v1(153.78,69.85) 153.78,78.71 152.74,79.75 152.74,84.94 153.78,85.99 153.78,88.94 153.57,89.15 153.37,89.34 153.37,92.19 154.08,92.9 154.08,93.67 v3(153.7,94.06)
  L3 w0.127: v3(155.33,53.49) 155.2,53.49 155.01,53.3 152.31,53.3 151.81,53.81 148.58,53.81 147.79,53.03 146.95,53.03 146.34,52.41 144.06,52.41 143.42,53.06 140.88,53.06 139.28,51.46 133.57,51.46 132.54,52.49 128.02,52.49 127.47,51.95 122.25,51.95 121.33,52.86 117.51,52.86 LPC1.3 ; v4(79,146.96) 78.35,146.32 78.35,145.49 76.25,143.38 76.25,140.56 77.63,139.17 77.63,137.75 79.3,136.08 79.3,135.95 80.04,135.2 80.04,134.13 82.26,131.92 84.85,131.92 89.5,127.26 117.64,127.26 119.7,125.2 120.67,125.2 132.71,113.16 147.6,113.16 149.99,110.77 149.99,108.16 154.74,103.41 154.74,98.98 154.48,98.72 154.48,94.64 153.94,94.11 153.75,94.11 v3(153.7,94.06)
  L4 w0.127: v3(155.33,53.49) 154.81,54.01 154.81,55.47 153.69,56.59 153.69,59.07 154.26,59.64 v3(154.26,65.53)
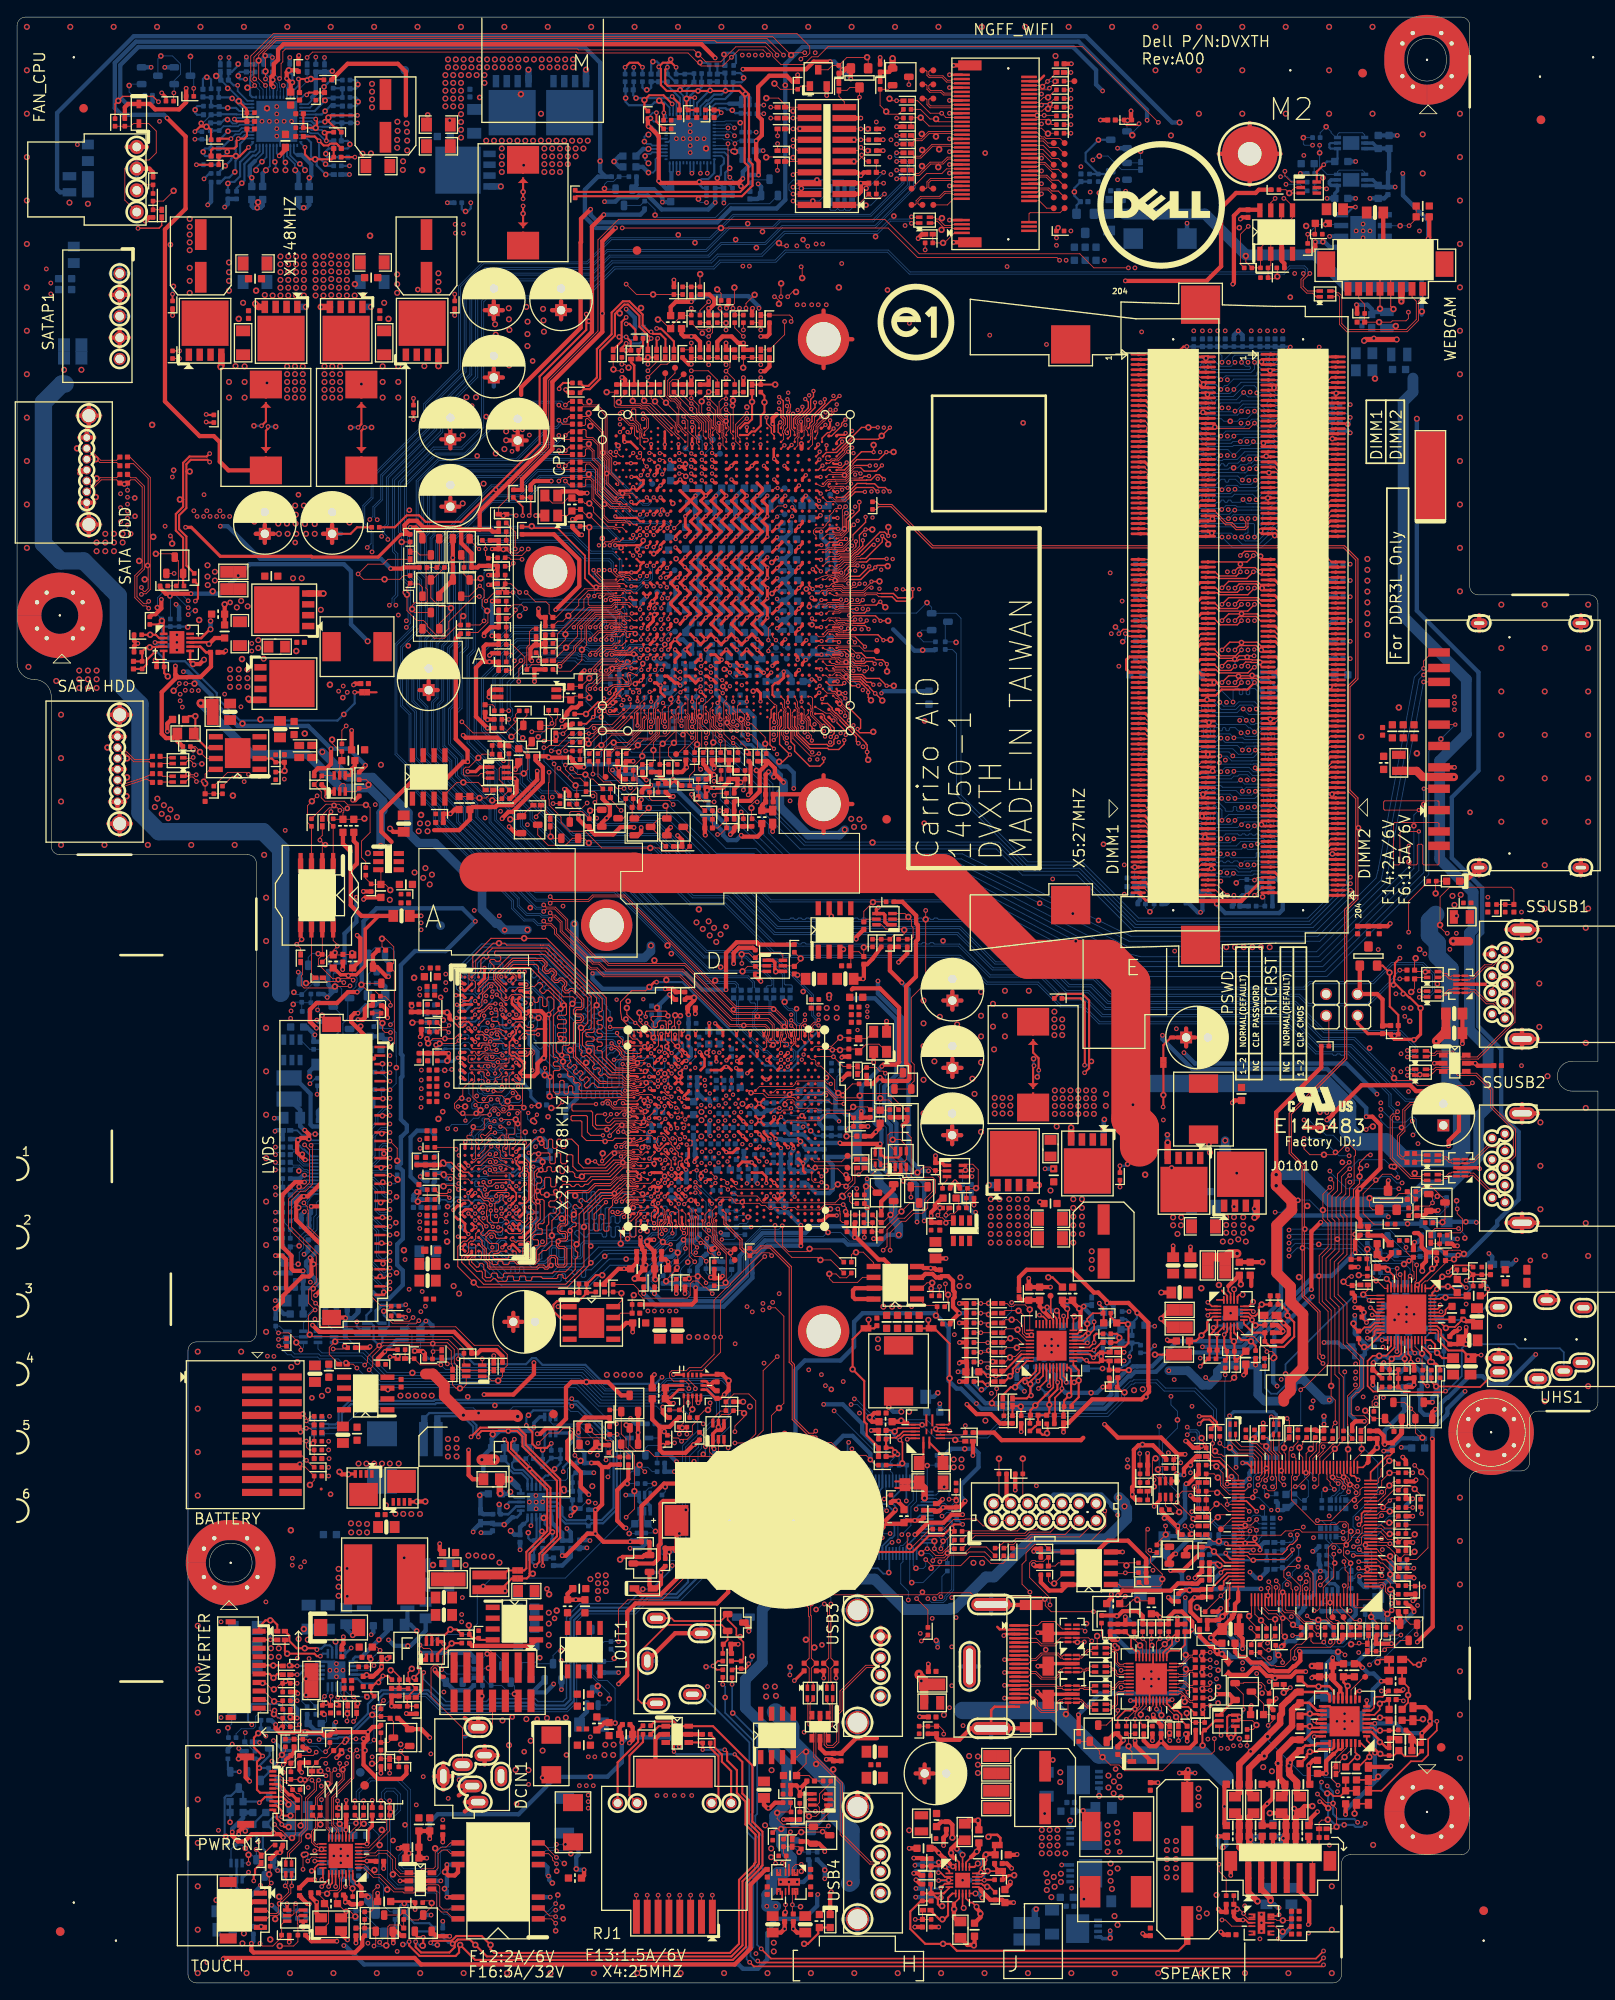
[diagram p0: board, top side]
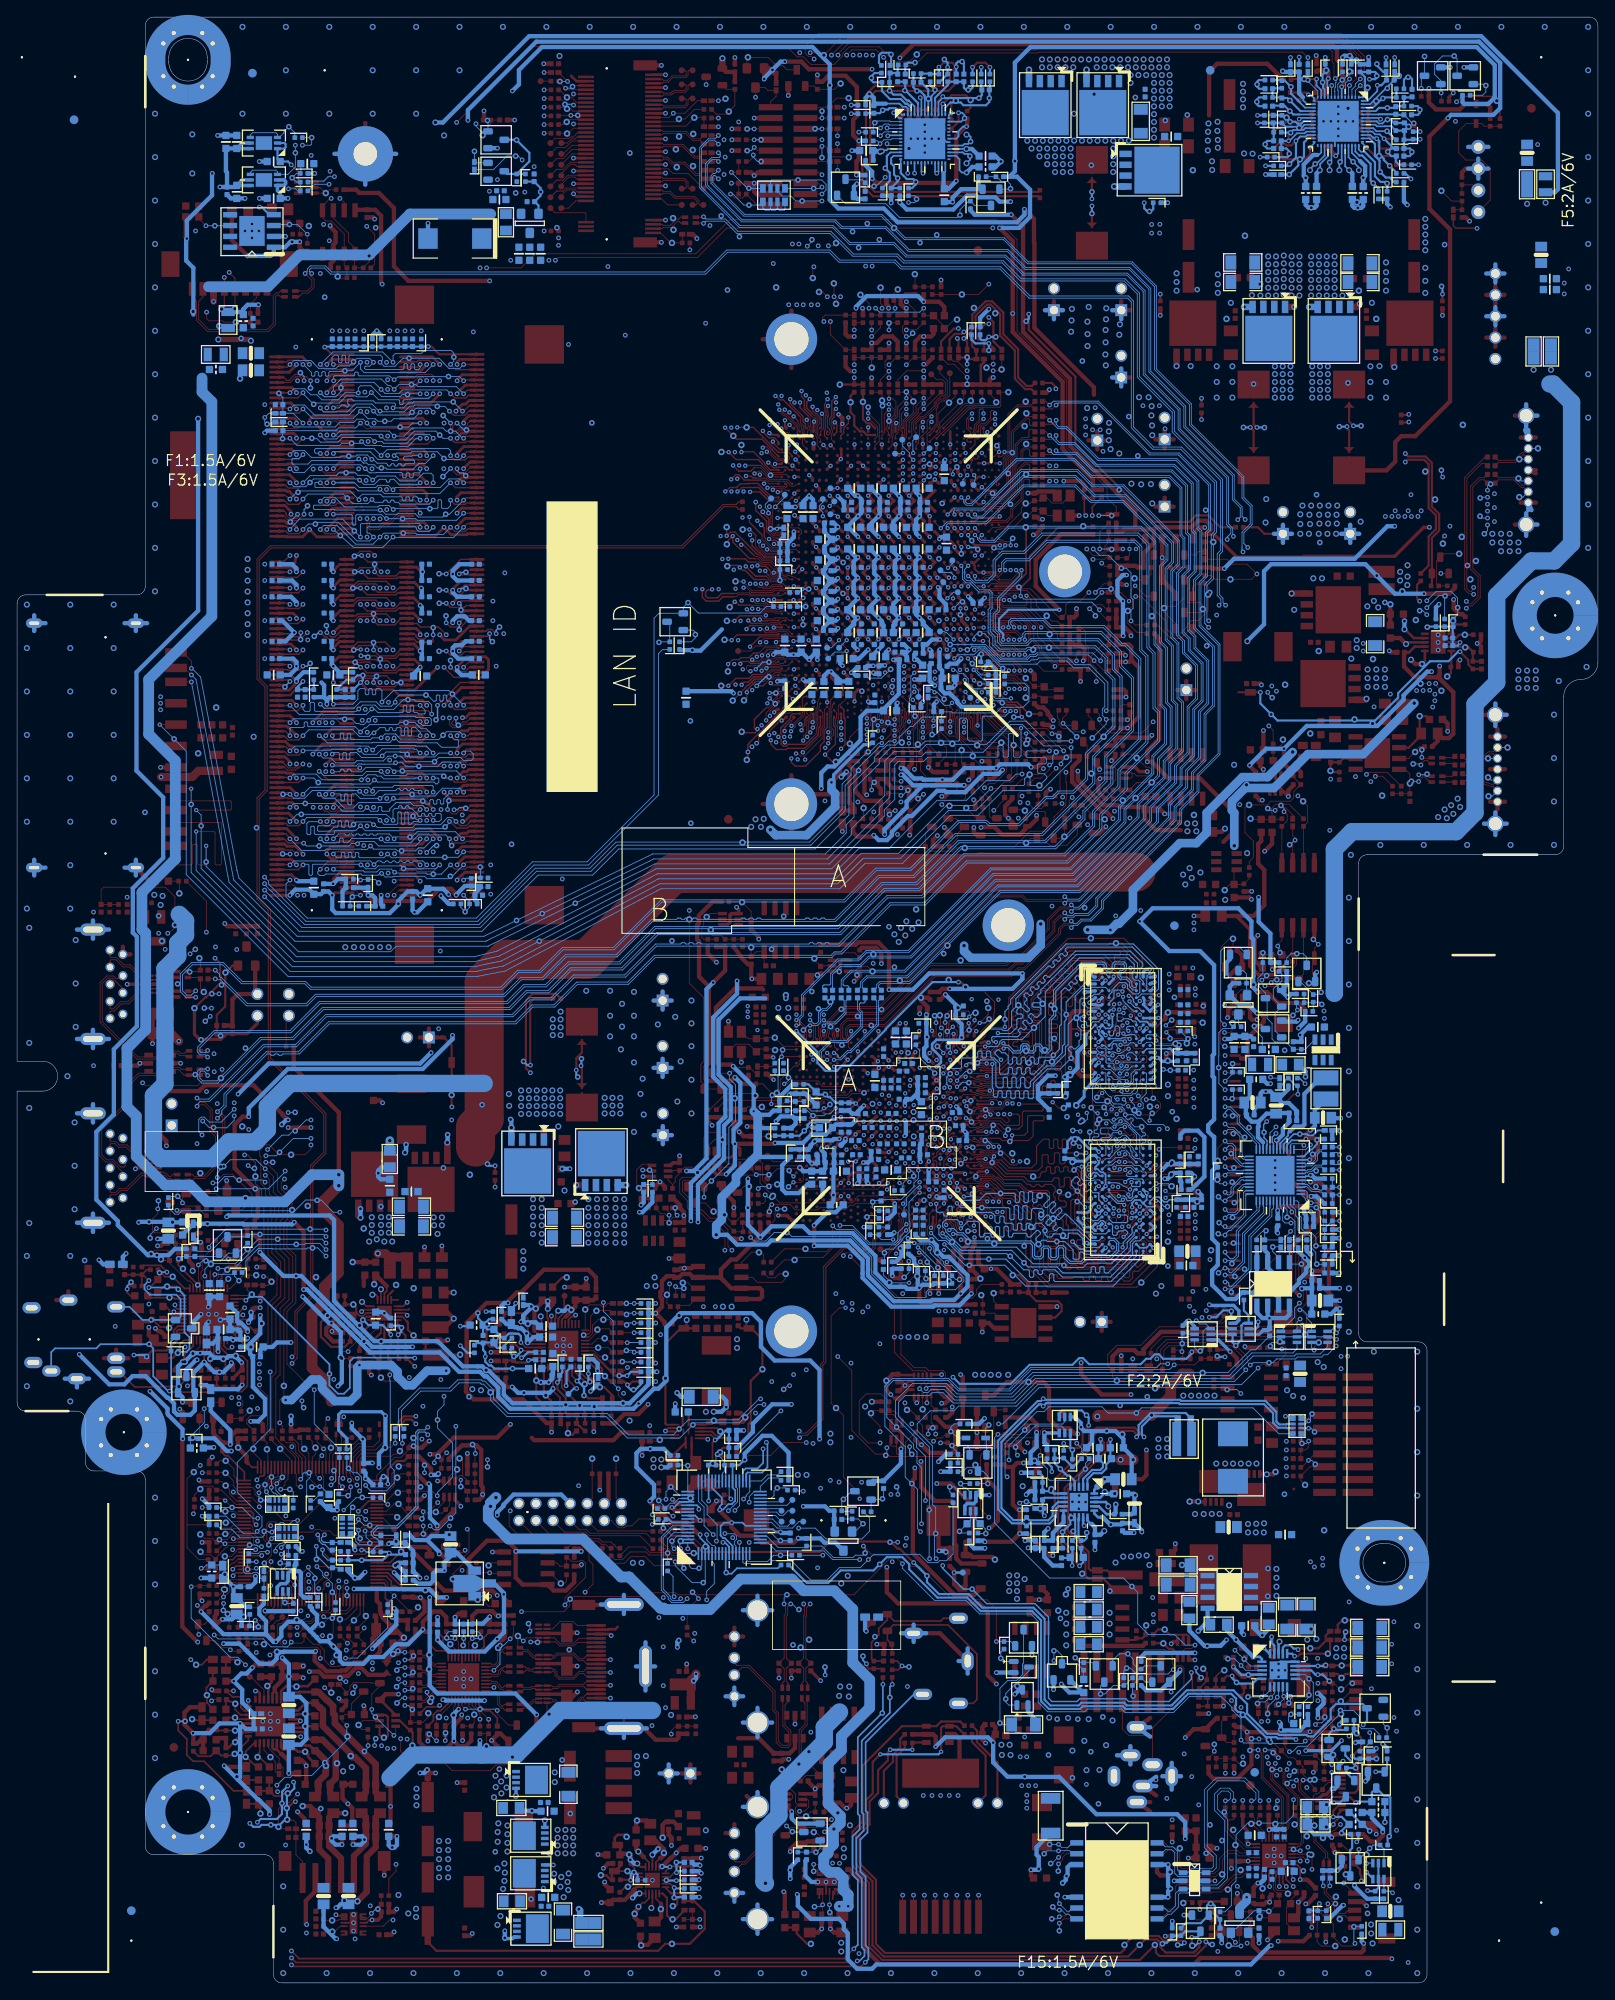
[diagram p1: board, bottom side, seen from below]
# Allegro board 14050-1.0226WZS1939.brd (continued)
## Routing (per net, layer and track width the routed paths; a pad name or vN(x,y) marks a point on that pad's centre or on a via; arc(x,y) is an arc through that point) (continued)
PLTRST_SL_N: length 121.6
  TOP w0.102: D7.1 D7.2 104.6,93.14 v3(104.6,91.92) ; R1160.2 98.49,106.34 99.26,107.1 R1159.1 100.55,107.1 100.97,106.68 101.36,106.68 v3(101.61,106.43) 103.6,106.43 D34.3
  L3 w0.127: v3(157.53,68.57) 157.26,68.83 155.76,68.83 153,71.59 150.92,71.59 150.35,72.16 145.77,72.16 145.19,71.59 143.35,71.59 141.68,69.93 134.25,69.93 132.84,68.52 132.25,68.52 132.07,68.34 125.32,68.34 125.13,68.53 119.24,68.53 118.08,69.68 117.37,69.68 117.15,69.91 115.1,71.96 115.1,79.97 109.66,85.4 109.66,90.05 107.79,91.92 v3(104.6,91.92)
  L4 w0.127: v3(157.53,68.57) 157.53,67.75 157.72,67.56 157.72,66.86 157.19,66.33 157.19,59.8 157.79,59.21 157.79,57.78 156.78,56.77 155.74,56.77 155.19,56.22 155.19,54.81 155.8,54.2 155.8,51.9 155.41,51.51 154.67,51.51 v3(154.08,50.93)
  BOTTOM w0.102: RN13.3 153.2,51.84 153.53,51.51 153.54,51.51 154.12,50.93 v3(154.08,50.93) ; v3(101.61,106.43) 101.61,105.77 100.92,105.08 100.92,100.86 101.71,100.07 101.71,95.86 v2(103.74,93.83) 104.6,92.96 v3(104.6,91.92)
PM_DPRSLPVR: length 5.2
  TOP w0.254: PR17.1 113.95,70.36 v3(113.57,69.98) 113.37,69.98 112.99,70.36 PR7.1
  BOTTOM w0.254: PR7.1 111.98,70.05 112.63,69.4 v2(112.86,69.4) 113.18,69.4 113.57,69.8 v3(113.57,69.98)
PME#_M: length 24.4
  TOP w0.102: CPU1.AD7 v4(75.3,163.4) ; R568.2 58.25,171.83 v3(58.41,171.68)
  L3 w0.127: v4(75.3,163.4) 74.88,163.82 74.88,165 74.66,165.23 73.44,165.23 72.69,165.97 68.81,165.97 65.32,169.47 60.54,169.47 58.41,171.6 v3(58.41,171.68)
  BOTTOM w0.102: v2(56.9,171.68) v3(58.41,171.68)
PORTC_SPK_L: length 47.2
  TOP w0.203: v3(164.68,37.82) 164.65,37.82 v1(164.05,37.22) 163.39,37.22 162.77,37.85 R345.1 ; U6.43 166.56,78.43 v3(166.65,78.52)
  L4 w0.203: v3(166.65,78.52) 166.73,78.44 166.73,71.46 167.85,70.34 167.85,65.96 166.53,64.64 166.53,38.81 165.54,37.82 v3(164.68,37.82)
PORTC_SPK_L_1: length 2.8
  TOP w0.203: R356.1 R345.2 159.53,37.85 v1(159.21,37.52)
PORTC_SPK_R: length 65.7
  TOP w0.203: v3(166.15,30.61) 166.15,29.54 165.13,28.52 165.13,26.67 164.4,25.93 163.13,25.93 159.67,22.48 R359.1 ; U6.44 166.24,78.83 166.53,79.12 v3(166.53,79.32)
  L4 w0.203: v3(166.53,79.32) 166.68,79.32 167.32,78.68 167.32,71.7 168.44,70.59 168.44,65.66 167.11,64.34 167.11,31.57 v3(166.15,30.61)
  BOTTOM w0.203: v2(165.34,30.61) v3(166.15,30.61)
PORTC_SPK_R_1: length 2.6
  TOP w0.203: R359.2 R367.1 156.52,20.73 v1(156.52,19.81)
PQ4206_D: length 14.1
  BOTTOM w0.102: PR4214.2 69.81,30.23 v2(69.98,30.4) 69.98,34.47 69.07,35.38 68.03,35.38 67.33,36.08 67.33,37.33 67.22,37.44 PQ4206.D
PQ4406_2: length 3
  BOTTOM w0.102: PQ4406.2 73.44,57.4 73.95,57.91 74.2,57.91 74.58,58.29 v2(74.58,58.42) PR4462.2
PQ4406_3: length 3.3
  BOTTOM w0.102: PQ4406.3 74.38,57.07 75.34,58.04 v2(75.85,58.04) 75.85,57.47 PR4455.2
PQ4406_5: length 4.1
  BOTTOM w0.102: PR4413.2 74.52,52.64 v2(74.71,52.83) PC4426.1 73.44,54.1 PQ4406.5
PQ4406_6: length 4
  BOTTOM w0.102: PR4450.1 72.49,52.58 v2(71.64,52.58) 71.64,52.96 71.71,53.04 71.71,53.14 PC4426.2 72.79,54.21 PQ4406.6
PQ4409_C: length 6.2
  BOTTOM w0.102: PR4451.1 74.33,59.82 73.82,60.33 72.99,60.33 PQ4409.C 71.98,59.88 71.41,59.31 v2(71.41,58.42) PR4462.1
PQ4409_E: length 5.3
  BOTTOM w0.102: PQ4409.E 73.53,62.58 73.82,62.87 v2(75.6,62.87) 75.6,62.74 74.9,62.04 PR4431.2 PR4433.1
PRE: length 4.7
  TOP w0.102: U118.16 132.54,40.09 v3(132.74,40.29) R2088.2
  BOTTOM w0.102: R2088.2 v3(132.74,40.29) 132.74,39.56 v2(132.81,39.48)
PRW_VGA_CORE_RBIAS: length 5.7
  TOP w0.203: U9.3 120.06,71.03 119.49,70.45 119.49,70.42 v3(119.48,70.41)
  BOTTOM w0.254: PR9.1 119.16,70.73 v3(119.48,70.41) 119.39,70.41 118.66,69.68 v2(118.66,68.72)
PS_0: length 7.5
  TOP w0.102: GPU1.AC19 88.74,102.34 v4(89.21,102.34)
  BOTTOM w0.102: v4(89.21,102.34) 89.87,101.68 90.37,101.68 90.58,101.47 v2(91.86,101.47) 91.91,101.47 92.49,102.04 R394.1 C1847.1 94.87,102.04 R388.1
PS_1: length 7.8
  TOP w0.102: GPU1.AD19 89.33,101.8 89.66,102.13 90.35,102.13 90.56,102.34 v4(90.58,102.34)
  BOTTOM w0.102: v2(89.87,102.77) 90.3,102.34 v4(90.58,102.34) 90.91,102.01 92.04,102.01 92.92,102.89 R948.1 C1849.2 94.82,103.14 R943.1
PS_2: length 12.9
  TOP w0.102: GPU1.AE17 90.13,100.93 91.2,100.93 91.26,100.87 93.94,100.87 94.79,101.73 97.38,101.73 R1900.1 R1899.1 97.32,100.2 97.06,99.95 v1(97.06,99.06) C1850.1
PS_3: length 13.5
  TOP w0.102: R940.1 102.08,102.11 C1848.1 100.93,102.17 R935.2 99.54,102.49 v1(97.84,102.49) 97.46,102.11 93.76,102.11 93.54,102.33 91.4,102.33 90.93,102.8 90.93,103.14 90.74,103.33 90.14,103.33 89.81,103 GPU1.AE20
PSI#: length 3.2
  TOP w0.254: PR3.1 117.51,67.39 v1(117.46,67.44) 117.39,67.5 PR10.2 PR4.2
PSID_D: length 6.1
  BOTTOM w0.102: Q47.D 58.2,34.76 v2(58.2,33.81) 57.69,33.81 56.69,34.81 L15.2 55.35,34.81 R1852.1
PSID_D_1: length 4.2
  BOTTOM w0.102: v2(54.39,33.55) 54.47,33.63 R1852.2 53.58,35.7 R1853.1 52.94,35.19 Q45.B
PSID_G: length 7.8
  BOTTOM w0.102: Q47.G 56.78,37.74 56.02,38.5 v2(55.01,38.5) 54.39,37.88 54.39,37.34 53.76,36.71 R1849.2 53.07,37.09 Q45.C
PW_CLEAR: length 361.1
  TOP w0.102: CPU1.AE2 70.61,162.31 70.23,162.31 70.23,162.3 69.87,162.3 69.76,162.4 68.85,162.4 68.63,162.18 v4(68.24,162.18) ; R184.1 153.51,112.84 153.2,113.16
  L3 w0.127: v3(156.87,67.21) 155.65,67.21 154.07,68.8 144.09,68.8 143.61,68.31 136.17,68.31 135.64,67.78 135.08,67.78 133.92,66.61 133.04,66.61 132.86,66.43 124.53,66.43 124.34,66.62 114.64,66.62 111.76,69.51 110.46,69.51 103.83,76.13 103.83,80.05 102.81,81.06 93.97,81.06 89.44,76.53 73.72,76.53 72.77,77.49 71.32,77.49 69.94,76.11 62.09,76.11 61.16,75.18 44.73,75.18 39.73,80.19 39.73,106.5 36.49,109.73 36.49,114.41 35.21,115.7 35.21,131.83 28.86,138.18 17.61,138.18 15,140.79 15,151.6 12.06,154.54 12.06,164.74 15.64,168.31 25.18,168.31 27.38,166.11 39.38,166.11 40.86,164.63 54.3,164.63 54.83,165.16 55.77,165.16 56.49,164.44 59.14,164.44 61.18,162.39 61.69,162.39 61.74,162.34 66.17,162.34 66.67,161.84 67.9,161.84 v4(68.24,162.18) ; 153.2,113.16 153.83,112.52 153.83,110.96 160.64,104.15 160.64,102.49 v3(159.6,101.45)
  L4 w0.127: v3(163.28,100.84) 162.69,100.25 162.69,99.99 162.34,99.63 162.34,99.1 161.53,98.29 161.53,97.78 161.53,95.67 160.01,94.15 160.01,90.25 156.81,87.05 156.81,86.36 156.12,85.67 156.12,85.28 156.76,84.63 156.76,84.23 156.48,83.95 156.48,83.56 156.85,83.19 156.85,80.73 156.08,79.96 156.08,77.91 156.61,77.38 156.61,74.44 157.42,73.63 157.42,69.56 156.7,68.84 156.7,67.37 v3(156.87,67.21)
  BOTTOM w0.102: v3(159.6,101.45) 159.6,100.91 160.46,100.05 161.98,100.05 v2(162.01,100.08) 162.52,100.08 v3(163.28,100.84)
PWR_1D8V_BOOT: length 3
  TOP w0.203: PU5201.10 104.39,65.32 104.17,65.53
  TOP w0.508: PR5205.1 103.28,65.66 103.41,65.79 v1(103.46,65.79) 103.51,65.79 103.77,65.53 104.17,65.53
PWR_1D8V_BOOT_A: length 2.7
  TOP w0.508: PR5205.2 100.06,65.66 99.78,65.94 v1(99.78,66.17) 99.8,66.17 100.31,66.67 PC5217.1
PWR_1D8V_EN: length 12.1
  TOP w0.203: PR62.2 103.39,60.58 v1(103.59,60.78) 103.61,60.81 103.61,63.22 v3(103.31,63.53) 103.31,63.65 103.77,64.12 PU5201.13
  BOTTOM w0.254: R77.1 PR57.2 PR5223.1 PC34.1 102.04,64.64 103.16,63.53 v3(103.31,63.53)
PWR_1D8V_FB: length 7.6
  TOP w0.203: PR5209.1 101.85,63.78 102.84,63.78 103.1,64.03 103.22,64.03 103.71,64.52 PU5201.12
  TOP w0.254: PC5203.2 102.5,61.59 102.73,61.82 v1(102.73,62.08) 102.73,62.28 102.4,62.61 PR5201.2 PR5209.1
PWR_1D8V_FB_1: length 16.8
  TOP w0.254: PR5201.1 100.81,62.67 99.42,64.06 99.42,65.4 99.14,65.68 99.14,70.43 v1(97.78,71.79) 97.78,75.32 PG5211.2
  TOP w0.508: PR5201.1 PC5203.1
PWR_1D8V_LX: length 4.2
  BOTTOM w0.508: v5(103.48,66.83) 102.55,66.83 v2(102.01,67.36) 102.01,68.12 102.47,68.58 PR5204.1
  vias: v5(104.39,66.83)
PWR_1D8V_SNB: length 1.6
  BOTTOM w0.508: v2(107.75,69.04) 107.3,68.58 PR5204.2
PWR_1D8V_VCC: length 3.6
  TOP w0.203: PU5201.11 103.11,64.92 v1(102.71,64.52) 102.58,64.64 PC5204.1
PWR_1D8V_VOUT: length 13.1
  TOP w0.203: PU5201.7 109,65.32
  TOP w0.254: PG5212.2 107.35,76.58 109.13,74.8 v1(109.13,70.74) 109.13,65.44 109,65.32
PWR_3D3V_BOOT2: length 4.1
  TOP w0.203: 109.63,9.27 110.25,9.89 PU4901.7 ; 109.63,8.61 v1(109.66,8.64)
  TOP w0.508: 109.63,9.27 109.63,8.61 ; v1(109.66,8.64) 109.66,8.48 109.63,8.46 109.63,7.7 110.14,7.19 PR4902.2
PWR_3D3V_BOOT2_R: length 3
  TOP w0.508: PC4907.2 112.05,4.47 v1(111.97,4.39) 111.92,4.45 111.21,4.45 PR4902.1
PWR_3D3V_ENTRIP2: length 4.8
  TOP w0.203: PU4901.4 108.57,11.61 v3(108.11,11.15)
  BOTTOM w0.254: PC4918.1 108.06,10.03 v2(108.11,9.98) 108.11,11.15 v3(108.11,11.15) 108.01,11.05 PR4924.1
PWR_3D3V_FB: length 38.9
  TOP w0.254: PG4902.1 135.92,3.76 109.98,3.76 109.16,4.57 v1(108.36,4.57) 106.28,4.57 104.53,6.32 104.53,8.36 105.76,9.59 PR4914.1 PC4911.2
PWR_3D3V_FB2: length 6.8
  TOP w0.203: PU4901.5 109.1,11.12 108.62,10.64
  TOP w0.254: 108.62,10.64 108.45,10.48 107.08,10.48 ; 107.08,10.48 107.75,9.8 107.75,9.2 107.96,8.99 v1(108.26,8.99) ; 107.08,10.48 PC4911.1 ; PC4911.1 106.97,11.49 PR4917.1 ; PC4911.1 PR4914.2
PWR_3D3V_LDO3: length 5.2
  TOP w0.203: 113.19,13.89 112.75,13.45 112.75,12.99 112.57,12.81 PU4901.15
  TOP w0.305: PG4904.1 114.41,15.04
  TOP w0.508: 113.19,13.89 113.19,14.83 v1(113.37,15.01) 113.47,15.11 114.33,15.11 PC4914.2
PWR_3D3V_LGATE2: length 14.2
  TOP w0.203: PU4901.10 v5(112.16,10.46)
  L3 w0.762: v5(112.16,10.46) 116.39,10.46 119.73,13.8 v3(122.25,13.8)
  BOTTOM w0.406: PU4903.4 v3(122.25,13.8)
  BOTTOM w0.508: v5(112.16,10.46) 112.45,10.46 v2(112.96,9.96)
PWR_3D3V_PHASE2: length 21.6
  TOP w0.203: v5(112.28,8.91) 111.79,9.4 111.54,9.4 111.05,9.89 PU4901.9
  TOP w0.508: PC4907.1 112.73,7.67 v1(112.73,8.09) 112.73,8.28 112.28,8.73 v5(112.28,8.91)
  L3 w0.762: v5(128.43,7.82) 125.33,7.82 124.87,7.37 113.83,7.37 112.3,8.89 112.3,8.91 v5(112.28,8.91)
  vias: v5(127.92,12.9) v5(127.97,13.97) v5(127.97,11.94) v5(128.13,11) v5(128.79,13.39) v5(128.79,6.78)
PWR_3D3V_SNB:
  vias: v2(124.85,9.8)
PWR_3D3V_UGATE2: length 23.8
  TOP w0.203: v5(110.78,8.76) 110.65,8.89 PU4901.8
  L3 w0.762: v5(110.78,8.76) 110.78,7.37 112.56,5.59 127.67,5.59 127.92,5.84 v3(127.92,6.1)
  BOTTOM w0.406: PU4902.4 126.83,5.37 127.02,5.18 127.92,5.18
  BOTTOM w0.508: v3(127.92,6.1) v2(127.92,5.26) 127.92,5.18 127.92,5.18
PWR_5V3V_EMN: length 4.6
  TOP w0.203: v3(113.19,12.01) PU4901.13
  TOP w0.254: PR4918.2 113.24,12.06 v3(113.19,12.01)
  BOTTOM w0.254: v3(113.19,12.01) 113.19,12.75 113.01,12.93 v2(112.81,12.93) 112.64,12.93 112.39,12.68 PR4920.1
PWR_5V3V_ENLDO: length 2.7
  TOP w0.203: PU4901.12 112.87,11.61 113.08,11.4 113.37,11.4 v1(113.52,11.25) 113.81,11.25 PR4901.2
PWR_5V3V_LDO5: length 3.9
  TOP w0.203: PU4901.14 112.87,12.41 113.54,13.08 v1(113.57,13.08) PG4901.1
  TOP w0.305: PC4906.1 114.4,13.69 114.79,13.3 PG4901.1
PWR_5V3V_PGOOD: length 5.9
  TOP w0.203: PU4901.6 109.45,10.46
  TOP w0.254: R1762.2 106.93,8.48 106.93,8.45 107.93,7.44 v1(108.29,7.44) 108.49,7.44 108.95,7.9 108.95,9.96 109.45,10.46
PWR_5V3V_TON: length 3.4
  TOP w0.203: v3(107.84,11.97) 107.89,11.97 107.93,12.01 PU4901.3
  BOTTOM w0.254: v2(109.02,12.01) 108.98,11.97 v3(107.84,11.97) 107,11.97 PR4919.1
PWR_5V_BOOT1: length 4.6
  TOP w0.203: 109.76,14.61 110.25,14.12 PU4901.19
  TOP w0.508: 109.76,14.61 109.66,14.61 109.3,14.96 v1(109.3,15.21) 109.3,15.67 110.32,16.69 PR4903.1
PWR_5V_BOOT1_R: length 2.8
  TOP w0.508: PC4908.1 112.56,18.9 v1(112.45,19) 111.29,19 PR4903.2
PWR_5V_BYP1: length 87.4
  TOP w0.203: 109.16,13.97 109.16,13.84 109.44,13.57 PU4901.20
  TOP w0.254: v3(137.85,24.56) PG4903.2
  TOP w0.508: v3(104.94,14.61) 105.89,14.61 PR4921.2 PC4913.1 ; 109.16,13.97 108.52,14.61 108.46,14.61 v3(107.86,15.21) 107.86,15.24 107.35,15.75 PC4912.1 ; PG4903.2 v3(136.02,24.56)
  L3 w0.254: v3(104.94,14.61) 104.94,14.73 107.48,17.27 107.48,20.07 109.19,21.78 111.61,21.78 117.79,27.97 127.59,27.97 128.94,26.62 135.8,26.62 v3(137.85,24.56)
  L3 w0.508: v3(136.02,24.56) 134.68,25.91 128.68,25.91 127.26,27.33 118.17,27.33 111.92,21.08 109.63,21.08 108.24,19.68 108.24,17.02 107.6,16.38 107.6,15.46 v3(107.86,15.21)
  BOTTOM w0.508: v2(137.02,24.93) 137.38,24.56 v3(137.85,24.56)
PWR_5V_ENTRIP1: length 4.6
  TOP w0.203: PU4901.2 108.57,12.41 108.08,12.9 v3(107.83,12.9)
  BOTTOM w0.254: PR4925.1 107.65,13.08 v3(107.83,12.9) 107.83,14.07 v2(107.86,14.1) PC4917.1
PWR_5V_FB1: length 5.7
  TOP w0.203: PU4901.1 109.1,13.08 108.79,13.39
  TOP w0.254: PC4913.2 PR4921.1 ; PC4913.2 106.9,13.59 PR4922.1 ; PC4913.2 108.5,13.65 108.59,13.57 v3(108.6,13.57) 108.79,13.39
  BOTTOM w0.254: v3(108.6,13.57) 109.44,13.57 109.48,13.62 v2(109.52,13.62)
PWR_5V_LGATE1: length 16.3
  TOP w0.254: v5(112.43,13.97) 112.02,13.57 PU4901.16
  L4 w0.762: v5(123.24,19.01) 119.12,19.01 117.66,17.55 117.66,16.92 114.84,14.1 112.56,14.1 v5(112.43,13.97)
  BOTTOM w0.406: PU4905.4 v5(123.24,19.01)
  BOTTOM w0.508: v5(112.43,13.97) 112.76,13.97 113.24,14.45 v2(113.24,14.4)
PWR_5V_PHASE1: length 23.4
  TOP w0.203: 111.67,14.73 111.05,14.1 PU4901.17
  TOP w0.508: 111.67,14.73 111.67,14.74 v5(112.3,15.37) 112.56,15.62 PC4908.2
  L3 w0.762: v5(112.3,15.37) 115.54,18.61 115.55,18.61 117.65,20.7 124.67,20.7 125.2,20.17 127.62,20.17 129.17,21.72 v5(129.19,21.72)
  vias: v2(128.56,25.02) v2(129.04,15.34) v5(127.62,18.41) v5(127.62,17.4) v5(127.62,16.38) v5(127.62,15.37) v5(127.72,24.26) v5(127.72,22.86) v5(128.33,22.17) v5(128.35,23.57) v5(128.68,18.67) v5(128.76,17.65) v5(128.76,16.51) v5(129.01,24.23) v5(128.99,22.91)
PWR_5V_SNB: length 2.7
  BOTTOM w0.508: PC4915.1 124.7,20.09 v2(124.75,20.14) 125.86,20.14 PR4912.2
PWR_5V_UGATE1: length 23.1
  TOP w0.203: PU4901.18 v5(110.65,14.99)
  L3 w0.762: v5(110.65,14.99) 110.65,16.13 116.75,22.23 126.3,22.23 v5(126.64,21.88)
  BOTTOM w0.406: v5(126.64,21.88) 126.61,21.91 PU4904.4
  BOTTOM w0.508: v5(110.65,14.99) 110.65,15.01 v2(109.99,15.67)
PWR_CHG_ACDET: length 4.9
  BOTTOM w0.254: PR5270.2 64.99,59.31 PR4412.1 PC5232.1 64.04,57.53 v2(64.02,57.56) 63.72,57.26 U55.6
PWR_CHG_ACN: length 26.7
  TOP w0.254: PG4905.2 59.34,48.26 59.6,48.51 59.6,50.42 62.03,52.86 62.03,54.41 ; v3(57.06,63.58) 57.44,63.2 57.44,62.33 62.03,57.73 62.03,54.41 ; 62.03,54.41 v1(61.63,54.41)
  BOTTOM w0.254: U55.1 59.74,58.94 59.04,59.63 58.08,59.63 57.54,60.17 57.54,60.66 56.93,61.26 PC4402.1 57.06,61.47 PC4404.1 v3(57.06,63.58)
PWR_CHG_ACP: length 28.1
  TOP w0.254: 59.98,47.88 59.98,50.27 62.42,52.7 62.42,57.89 57.82,62.49 57.82,63.22 v3(58.2,63.6) ; 59.98,47.88 59.98,47.65 59.65,47.32 58.89,47.32 PG4907.2 ; 59.98,47.88 v1(60.36,47.88)
  BOTTOM w0.254: v3(58.2,63.6) 58.2,62.74 PC4403.1 58.45,62.48 PC4402.2 57.92,60.81 57.92,60.33 58.23,60.02 59.2,60.02 60.25,58.97 60.25,58.18 U55.2
PWR_CHG_AD_OFF: length 39.4
  TOP w0.102: v3(85.96,51.1) 84.87,50.01 81.67,50.01 80.37,48.72 79.39,48.72 75.5,44.83 71.48,44.83 70.39,43.74 v3(70.39,39.94)
  BOTTOM w0.102: PQ4206.G 68.71,39.94 PR4210.1 v3(70.39,39.94) ; U4101.19 97.27,52.28 95.92,50.93 92.81,50.93 R80230.1 90.82,51.12 89.49,49.78 87.16,49.78 86.9,50.04 86.01,50.04 v2(85.76,50.29) 85.76,50.9 v3(85.96,51.1)
PWR_CHG_AD_OFF_R: length 3
  BOTTOM w0.102: PR4210.2 69.88,38.67 v2(69.88,37.97) 69.88,37.8 69.7,37.61 PQ4204.B
PWR_CHG_BTST: length 4
  BOTTOM w0.305: U55.17 58.41,55.76 57.49,54.84 PR5279.1
  BOTTOM w0.508: v2(56.42,55.98) 56.45,55.96 56.45,54.98 PR5279.1
PWR_CHG_BTST_1: length 4.6
  BOTTOM w0.508: PC5234.1 54.31,57.23 v2(54.14,57.05) 54.24,56.95 PD4401.K 54.57,54.84 PR5279.2
PWR_CHG_CMPIN: length 9.5
  BOTTOM w0.254: U55.4 61.24,58.74 61.86,59.36 62.14,59.36 v2(62.9,60.13) 63.6,60.82 PR5467.2 ; PR5287.2 61.37,60.39 PR5470.1 PR5469.2 63.53,61.4 PR5467.2 ; PR5467.2 PR5468.1
PWR_CHG_CMPIN_R: length 3.2
  BOTTOM w0.254: PR5470.2 v2(61.5,62.36) 61.74,62.6 PQ5006.6
PWR_CHG_CMPIN_RR: length 11.2
  TOP w0.254: v3(59.6,65.23) 59.6,65.16 60.3,64.45 60.3,63.06 60.77,62.6 61.99,62.6 v3(62.52,63.12)
  BOTTOM w0.254: v3(59.6,65.23) 59.6,66.17 v2(59.85,66.42) 60.41,66.98 62.7,66.98 63.04,66.64 PQ5006.3 ; PR5469.1 v3(62.52,63.12)
PWR_CHG_HIDRV: length 24.1
  TOP w0.406: PU4403.4 38.8,59.55 v5(38.76,59.5)
  TOP w0.508: v1(37.73,59.79) 37.73,59.77 37.99,59.5 v5(38.76,59.5)
  L3 w1.016: v5(57.31,55.75) 55.76,55.75 53.22,58.29 39.97,58.29 v5(38.76,59.5)
  BOTTOM w0.305: U55.18 57.59,56.26 57.31,55.98 v5(57.31,55.75)
PWR_CHG_ILIM: length 35.7
  TOP w0.508: v3(60.87,64.23) 61.22,64.23 61.88,64.9 63.13,64.9 64.24,66 64.24,69.66 64.88,70.31 v1(66.63,70.31) 69.15,70.31 70.71,68.75 PQ5003.D
  L4 w0.508: v3(64.35,53.16) 63.15,54.36 63.15,58.04 60.33,60.86 60.33,63.4 60.87,63.94 v3(60.87,64.23)
  BOTTOM w0.305: U55.10 62.54,54.64
  BOTTOM w0.508: 62.54,54.64 62.54,53.88 63.79,52.63 PR5278.2 PR5268.1 64.8,52.7 v3(64.35,53.16)
PWR_CHG_IOUT: length 12.9
  TOP w0.254: v1(65.26,55.5) 65.26,55.14 v3(64.78,54.66)
  L4 w0.254: v3(64.78,54.66) 64.8,54.69 64.8,58.93 v3(63.91,59.82)
  BOTTOM w0.254: v3(63.91,59.82) 63.91,60.35 64.49,60.92 PR5467.1 ; U55.7 64.75,56.76 PC5239.1 64.99,55.55 PR5288.1 64.94,54.83 v3(64.78,54.66)
PWR_CHG_LODRV: length 18
  TOP w0.406: v5(46.78,56.32) 46.73,56.28 PU4405.4
  TOP w0.508: v1(47.77,56.32) v5(46.78,56.32)
  L3 w1.016: v5(46.78,56.32) 51.99,56.32 55.43,52.88 v5(57.77,52.88)
  BOTTOM w0.305: U55.15 59.74,54.09 59.34,53.7
  BOTTOM w0.508: v5(57.77,52.88) 58.21,52.44 PC5237.1 58.86,53.31 59.24,53.7 59.34,53.7
PWR_CHG_NC: length 3.1
  BOTTOM w0.254: U55.11 61.74,53.67 v2(62.65,52.76) 62.65,52.37 62.64,52.36 PR5286.1
PWR_CHG_PHASE: length 17.2
  L3 w1.016: v5(57.72,57.45) 57.56,57.45 57.54,57.48 56.78,57.48 55.62,58.64 55.21,58.64 53.9,59.94 45.48,59.94 v5(44.66,60.76)
  BOTTOM w0.305: v5(57.72,57.45) 57.72,57.3 58.26,56.76 U55.19
  BOTTOM w0.508: v5(57.72,57.45) 57.49,57.23 PC5234.2
  vias: v5(39.96,60.76) v5(40.88,60.76) v5(41.79,60.76) v5(42.71,60.76) v5(43.62,60.76)
PWR_CHG_SRN: length 3.2
  BOTTOM w0.254: 61.17,52.83 61.17,52.08 PR5277.1 ; 61.17,52.83 v2(61.42,52.83) ; 61.17,52.83 61.17,54.42 U55.12
PWR_CHG_SRP: length 4.3
  BOTTOM w0.254: v2(59.82,52.68) 59.82,52.04 60.12,51.75 PR5283.1 60.79,52.06 60.79,54.26 60.74,54.32 U55.13
PWR_CHG_VCC: length 6.3
  TOP w0.762: v1(56.55,57.25) 56.5,57.3 PR5284.2 v3(57.71,58.93)
  BOTTOM w0.305: U55.20 58.94,57.7 58.57,58.06
  BOTTOM w0.762: PR5284.2 v3(57.71,58.93) 58.57,58.06
PWR_COMP_R: length 2.7
  BOTTOM w0.254: PR4645.2 21.09,219.58 20.84,219.33 v2(20.84,219.15) 20.84,218.8 21.06,218.57 PC4626.1
PWR_CPU_BST1: length 6.1
  BOTTOM w0.203: 32.85,213.87 32.79,213.93 32.61,213.93 32.39,214.15 PU4601.28
  BOTTOM w0.508: 32.85,213.87 33.31,213.87 34.42,212.75 34.42,211.43 v2(34.2,211.2) PR4701.1
PWR_CPU_BST2: length 5.5
  BOTTOM w0.203: PU4601.37 28.79,214.11 27.85,213.17
  BOTTOM w0.508: 27.85,213.17 27.24,212.56 27.24,211.44 v2(27.46,211.21) 27.47,211.21 PR4703.1
PWR_CPU_COMP: length 6.5
  BOTTOM w0.127: v2(21.55,217.58) 21.71,217.58 PC4626.2
  BOTTOM w0.203: 25.65,218.63 25.68,218.61 PU4601.48
  BOTTOM w0.254: 25.65,218.63 PC4627.2 23.59,218.57 PC4626.2
PWR_CPU_COMPNB: length 5.3
  BOTTOM w0.203: PU4601.18 34.95,218.61
  BOTTOM w0.254: PC4611.2 38.01,219.65 PC4612.2 36.7,219.65 36.05,219 v2(36.05,219) 35.65,218.61 34.95,218.61
PWR_CPU_CSCOMP: length 55.6
  TOP w0.254: PR4637.1 22.19,182.56 v3(22.13,182.63)
  L3 w0.254: v3(22.13,182.63) 21.88,182.88 19.38,182.88 16.99,185.27 16.99,185.69 16.99,207.16 20.02,210.19 21.88,210.19 23.4,211.71 23.4,215.26 22.77,215.9 21,215.9 v3(20.81,215.71)
  BOTTOM w0.203: PU4601.45 26.05,217.4 25.86,217.22 24.93,217.22 24.92,217.23 24.16,217.23 PR4601.2
  BOTTOM w0.254: PR4601.2 PC4603.2 22.64,215.71 PR4626.2 ; PR4626.2 PC4615.2 22,214.63 21.78,214.4 v2(21.78,214.22) 21.78,214 22.03,213.74 PC4618.1 ; PR4626.2 21.69,215.65 PR4619.1 v3(20.81,215.71)
PWR_CPU_CSCOMPNB: length 57.8
  TOP w0.254: PR4639.1 v3(46.39,182.91)
  L3 w0.254: v3(39.83,217.61) 39.66,217.61 38.26,216.21 38.26,211.46 38.77,210.95 41.57,210.95 44.9,207.62 52.26,200.27 52.26,188.76 47.17,183.67 47.17,183.66 46.41,182.91 v3(46.39,182.91)
  BOTTOM w0.203: 35.74,217.17 34.58,217.17 34.34,217.4 PU4601.21
  BOTTOM w0.254: PC4617.2 38.69,214.63 38.95,214.88 v2(38.95,215.11) 38.95,215.26 38.69,215.52 PC4613.1 PR4609.2 37.94,217.55 PC4624.2 ; PC4624.2 PR4640.1 v3(39.83,217.61) ; PC4624.2 PR4638.2 36.55,217.17 35.74,217.17
PWR_CPU_CSN1: length 62.9
  TOP w0.254: v3(40.67,181.99) 40.29,181.61 PG4702.2
  L3 w0.254: v3(21.88,211.07) 21.75,211.2 20.04,211.2 16.23,207.39 16.23,184.47 18.83,181.86 23.53,181.86 25.69,184.02 39.82,184.02 40.48,183.36 40.48,182.18 v3(40.67,181.99)
  BOTTOM w0.254: v3(21.88,211.07) 22.51,211.71 PR4618.2 ; v3(40.67,181.99) v2(41.49,181.99)
PWR_CPU_CSN1NB: length 64.5
  TOP w0.254: PG4704.2 29.12,181.61 29.36,181.86 v3(29.36,182.09)
  L3 w0.254: v3(29.36,182.09) 29.39,182.06 29.39,181.59 30.26,180.72 47.58,180.72 48.91,182.06 48.91,184.6 52.76,188.45 52.76,200.48 41.72,211.52 40.64,212.6 v3(38.9,212.6)
  BOTTOM w0.254: v3(29.36,182.09) 29.51,182.09 29.52,182.08 v2(30.26,182.08) ; v3(38.9,212.6) PR4612.2
PWR_CPU_CSP1: length 5.8
  TOP w0.254: v3(27.08,214.76) 26.04,213.72 25.64,213.72 v1(25.61,213.74) PC4628.2 PR4615.1
  BOTTOM w0.203: v3(27.08,214.76) 27.57,215.25 PU4601.40
PWR_CPU_CSP1NB: length 6.4
  TOP w0.254: PC4623.1 PR4608.1 36.8,213.36 v1(34.88,213.36) 34.27,213.36 33.69,213.94 v3(33.69,214.76)
  BOTTOM w0.203: v3(33.69,214.76) 33.2,215.25 PU4601.26
PWR_CPU_CSP2: length 7.7
  BOTTOM w0.203: PU4601.41 26.74,215.81 26.32,215.39
  BOTTOM w0.254: PR4631.1 23.83,210.69 24.37,211.23 24.82,211.23 v2(25.48,211.89) 25.56,211.96 25.56,213.22 26.09,213.75 26.09,215.16 26.32,215.39
PWR_CPU_CSP2NB: length 6.8
  BOTTOM w0.203: PU4601.25 33.92,215.81 34.18,215.54
  BOTTOM w0.254: 34.18,215.54 34.4,215.32 34.4,213.68 35.06,213.02 35.06,212.65 v2(36.13,211.58) PR4633.1
PWR_CPU_CSREF: length 13.7
  TOP w0.254: PC4606.1 26.89,216.09 26.58,215.77 v3(25.89,215.77) 25.69,215.57 25.69,214.88 25.43,214.63 22.89,214.63 22.7,214.44 PC4628.1
  BOTTOM w0.203: v3(25.89,215.77) 26.02,215.9 26.32,215.9 26.63,216.21 PU4601.42
  BOTTOM w0.254: PR4618.1 23.59,211.82 v2(24.37,212.6) 25.05,213.28 25.05,213.43 25.59,213.96 25.59,215.47 v3(25.89,215.77)
PWR_CPU_CSREFNB: length 11.7
  TOP w0.254: PC4623.2 37.6,214.97 37.6,214.98 37.39,215.19 36.63,215.19 36.42,214.99 35.87,214.99 v3(35.34,215.52) 34.83,216.03 PC4622.1
  BOTTOM w0.203: v3(35.34,215.52) 34.83,216.03 34.2,216.03 34.02,216.21 PU4601.24
  BOTTOM w0.254: v3(35.34,215.52) 35.34,213.56 v2(36.1,212.8) 36.3,212.6 PR4612.1
PWR_CPU_CSSUM: length 10.2
  TOP w0.254: v3(25.03,215.77) 23.72,215.77 PR4620.2
  BOTTOM w0.203: PU4601.43 26.39,216.61 26.07,216.28 25.53,216.28 v3(25.03,215.77)
  BOTTOM w0.254: 23.88,214.63 v3(25.03,215.77) ; 23.88,214.63 PC4615.1 ; 23.88,214.63 24.21,214.63 v2(24.59,214.25) 24.59,214.17 24.16,213.74 PC4618.2 23.66,213.68 23.66,213.11 23.27,212.72 PR4641.1
PWR_CPU_CSSUMNB: length 10.3
  TOP w0.254: PR4644.2 36.36,216.53 36.2,216.38 v3(36.2,215.52)
  BOTTOM w0.203: v3(36.2,215.52) 36.1,215.52 35.21,216.41 34.32,216.41 34.13,216.61 PU4601.23
  BOTTOM w0.254: PR4625.1 36.33,213.61 36.13,213.82 v2(36.13,214.02) 36.13,214.3 36.46,214.63 PC4617.1 PC4613.2 v3(36.2,215.52)
PWR_CPU_DIFF: length 5.5
  BOTTOM w0.203: 26.04,219.68 26.32,219.4 PU4601.50
  BOTTOM w0.254: PR4634.1 PR4636.1 25.05,220.6 v2(25.17,220.48) 25.24,220.48 26.04,219.68
PWR_CPU_DIFFNB: length 6.7
  BOTTOM w0.203: 34.89,220.03 34.27,219.4 PU4601.16
  BOTTOM w0.254: 34.89,220.03 35.92,221.06 v2(35.92,221.84) 36.65,222.57 PR4621.1 37.05,222.63 PR4622.1
PWR_CPU_DROOP: length 5.4
  BOTTOM w0.203: PU4601.46 25.9,217.81 25.64,217.55 25.22,217.55 24.76,218.01 v2(24.62,218.01)
  BOTTOM w0.254: PC4603.1 PR4601.1 23.86,217.61 24.26,218.01 v2(24.62,218.01)
PWR_CPU_DROOPNB: length 5.3
  BOTTOM w0.203: PU4601.20 34.46,217.81
  BOTTOM w0.254: PC4624.1 PR4638.1 36.8,218.5 36.05,217.75 v2(36.02,217.75) 35.39,217.75 35.17,217.54 34.73,217.54 34.46,217.81
PWR_CPU_FB: length 7.1
  BOTTOM w0.203: 25.81,219.2 26,219 PU4601.49
  BOTTOM w0.254: PC4621.2 21.81,220.6 PR4636.2 PR4645.1 23.59,219.58 PC4627.1 23.79,219.38 v2(24.65,219.38) 25.62,219.38 25.81,219.2
PWR_CPU_FBNB: length 7.7
  BOTTOM w0.203: PU4601.17 34.63,219
  BOTTOM w0.254: 34.63,219 34.81,219 v2(36.05,220.24) 36.34,220.54 PC4612.1 37.05,220.6 PR4623.1 PC4610.2 38.01,221.68 PR4621.2
PWR_CPU_HG1: length 36.2
  TOP w0.762: 49.31,190.5 v5(49.31,189.17)
  L3 w1.016: v5(33.69,212.09) 33.69,211.46 38.69,206.45 41.74,206.45 47.79,200.41 47.79,191.37 49.31,189.85 49.31,189.17 v5(49.31,189.17)
  BOTTOM w0.203: PU4601.29 31.99,213.79 32.95,212.82 v2(33.09,212.82) 33.69,212.23 v5(33.69,212.09)
PWR_CPU_HG2: length 31.4
  TOP w0.762: PU4702.4 23.91,189.26 23.83,189.18 v5(23.83,189.05)
  L3 w1.016: v5(23.83,189.05) 21.75,191.13 21.75,202.95 25.81,207.01 25.81,209.93 v5(27.97,212.09)
  BOTTOM w0.203: PU4601.36 29.19,213.61 v2(28.66,213.08) 27.97,212.39 v5(27.97,212.09)
PWR_CPU_ILIM: length 4.5
  BOTTOM w0.203: v2(24.68,216.65) 25.93,216.65 26.28,217 PU4601.44
  BOTTOM w0.254: PR4626.1 23.68,215.65 v2(24.68,216.65)
PWR_CPU_ILIMNB: length 4.1
  BOTTOM w0.203: PU4601.22 34.23,217 34.45,216.79 35.66,216.79 v2(35.97,216.48) 37,216.48 PR4609.1
PWR_CPU_IOUT: length 6.5
  TOP w0.254: v1(25.94,220.17) 26.83,219.28 26.83,219.2 26.89,219.14 PR4614.1 PC4609.2 25.69,217.81 v3(25.43,218.06)
  BOTTOM w0.203: v3(25.43,218.06) 25.58,218.21 PU4601.47
PWR_CPU_IOUTNB: length 6
  TOP w0.254: PC4616.1 PR4627.1 v1(34.95,217.04) 35.09,217.18 35.09,217.93 v3(34.95,218.07)
  BOTTOM w0.203: PU4601.19 34.81,218.21 v3(34.95,218.07)
PWR_CPU_LG1: length 32.1
  TOP w0.762: PU4705.4 36.61,196.09 v5(35.54,196.09)
  L4 w1.016: v5(31.4,212.09) 31.4,209.42 37.5,203.33 39.15,203.33 41.49,200.99 41.49,196.16 v5(41.41,196.09) 41.41,196.09 v5(35.54,196.09)
  BOTTOM w0.203: v5(31.4,212.09) v2(31.4,213) 31.19,213.22 PU4601.31
  BOTTOM w0.762: PU4706.4 v5(41.41,196.09)
PWR_CPU_LG2: length 28
  TOP w0.762: PU4704.4 28.25,196.09 v5(27.87,196.47)
  L4 w1.016: v5(33.79,196.09) 28.25,196.09 v5(27.87,196.47) 27.87,204.62 29.31,206.06 29.31,208.98 30.26,209.93 v5(30.26,212.09)
  BOTTOM w0.203: PU4601.34 29.99,213.24 v2(30.17,213.06) 30.26,212.97 v5(30.26,212.09)
  BOTTOM w0.762: PU4703.4 v5(33.79,196.09)
PWR_CPU_PHCONFIG: length 6.7
  BOTTOM w0.203: 27.91,213.8 27.92,213.8 28.39,214.27 PU4601.38
  BOTTOM w0.254: PR4635.1 25.69,209.96 v2(26.3,210.57) 26.6,210.87 26.6,212.82 27.58,213.8 27.91,213.8
PWR_CPU_ROSC: length 3.2
  BOTTOM w0.203: PU4601.11 31.99,221.56 32.16,221.74
  BOTTOM w0.254: PR4610.2 32.22,223.27 v2(32.22,222.36) 32.16,222.3 32.16,221.74
PWR_CPU_SNBNB:
  vias: v1(25.94,194.69)
PWR_CPU_SNBVDD1:
  vias: v1(43.47,194.69)
PWR_CPU_SR: length 7.3
  BOTTOM w0.203: PU4601.39 27.99,214.52 27.72,214.25 27.31,214.25 27.28,214.22
  BOTTOM w0.254: PR4603.1 v2(24.67,210.54) 24.85,210.72 25.43,210.72 26.09,211.38 26.09,213.03 27.28,214.22
PWR_CPU_SW1: length 36.5
  L3 w1.016: v5(32.55,212.09) 32.55,210.06 37.8,204.8 41.06,204.8 46.13,199.72 46.13,190.69 v5(47.66,189.17)
  BOTTOM w0.203: v5(32.55,212.09) 32.51,212.13 32.51,212.81 31.59,213.72 PU4601.30
  BOTTOM w0.508: PC4704.2 32.93,211.71 v5(32.55,212.09)
  vias: v2(40.29,187.07) v5(35.97,189.14) v5(35.97,188.23) v5(35.97,187.31) v5(35.97,186.4) v5(35.97,185.48) v5(36.89,189.14) v5(36.89,188.23) v5(36.89,187.31) v5(36.89,186.4) v5(36.89,185.48) v5(37.8,189.14) v5(37.8,188.23) v5(37.8,187.31) v5(37.8,186.4) v5(37.8,185.48) v5(42.78,189.14) v5(42.78,187.31) v5(42.78,185.48) v5(44.61,189.14) v5(44.61,187.31) v5(44.61,185.48)
PWR_CPU_SW2: length 31.3
  L3 w1.016: v5(29.12,212.09) 29.12,210.69 27.47,209.04 27.47,206.12 23.4,202.06 23.4,192.15 25.56,189.99 v5(25.56,189.17)
  BOTTOM w0.203: PU4601.35 29.59,212.56 v5(29.12,212.09)
  BOTTOM w0.508: PC4710.2 28.74,211.71 v5(29.12,212.09)
  vias: v2(29.24,187.2) v5(24.8,187.31) v5(24.8,185.48) v5(26.63,189.14) v5(26.63,187.31) v5(26.63,185.48) v5(31.61,189.14) v5(31.61,188.23) v5(31.61,187.31) v5(31.61,186.4) v5(31.61,185.48) v5(32.52,189.14) v5(32.52,188.23) v5(32.52,187.31) v5(32.52,186.4) v5(32.52,185.48) v5(33.43,189.14) v5(33.43,188.23) v5(33.43,187.31) v5(33.43,186.4) v5(33.43,185.48)
PWR_CPU_SWN1: length 64.6
  TOP w0.254: v3(39.91,181.99) 40.29,182.37 PG4701.2 ; PR4615.2 v3(20.99,212.72)
  L3 w0.254: v3(20.99,212.72) 20.99,212.69 15.84,207.55 15.84,184.31 18.67,181.48 23.69,181.48 25.85,183.64 39.66,183.64 40.1,183.2 40.1,182.18 v3(39.91,181.99)
  BOTTOM w0.254: v3(20.99,212.72) PR4641.2 ; v3(39.91,181.99) 39.05,181.99 v2(39.03,181.97)
PWR_CPU_SWN1NB: length 67.6
  TOP w0.254: PR4608.2 v3(39.53,213.61) ; PG4703.2 29.12,182.69 v3(28.61,182.18)
  L3 w0.254: v3(39.53,213.61) 40.17,212.98 40.8,212.98 53.14,200.63 53.14,188.29 49.3,184.44 49.3,181.9 47.73,180.34 30.1,180.34 28.61,181.83 v3(28.61,182.18)
  BOTTOM w0.254: v3(39.53,213.61) PR4625.2 ; v3(28.61,182.18) v2(27.72,182.18)
PWR_CPU_TEENSE: length 51.5
  TOP w0.254: PR4613.2 v3(51.21,197.59)
  L3 w0.254: v3(51.21,197.59) 51.21,199.87 49.09,202 44.18,206.9 41.15,209.93 38.35,209.93 37.24,211.03 37.24,222.5 36.41,223.34 27.34,223.34 v3(26.73,222.73)
  BOTTOM w0.203: PU4601.1 27.53,220.62 27.52,220.62
  BOTTOM w0.254: 27.52,220.62 27.27,220.88 27.27,223.01 PR4605.2 PC4607.2 26.08,223.58 25.88,223.38 v2(25.88,223.13) 25.88,222.92 26.07,222.73 v3(26.73,222.73)
PWR_CPU_TSENSENB: length 40.5
  TOP w0.254: PR4630.2 v3(18.19,197.59) ; PC4619.2 PR4629.2 34.16,221.17 v3(33.89,220.9)
  L3 w0.254: v3(18.19,197.59) 18.19,206.63 20.2,208.64 21.76,208.64 24.49,211.36 24.49,219.53 25.86,220.9 v3(33.89,220.9)
  BOTTOM w0.203: PU4601.14 33.2,220.49 33.61,220.9 v3(33.89,220.9)
  BOTTOM w0.254: v3(18.19,197.59) 18.19,198.39 v2(18.3,198.5)
PWR_CPU_VCC: length 6.3
  TOP w0.508: PC4602.1 32.01,222.35 v3(31.55,222.81) 31.55,223.53 v1(31.8,223.77) 32.79,223.77 PR4602.2
  BOTTOM w0.203: PU4601.10 31.59,221.71 31.66,221.79 31.66,222.7 v3(31.55,222.81)
PWR_CPU_VDD: length 6
  BOTTOM w0.203: PU4601.51 26.67,219.8 24.89,221.59 24.72,221.59 v2(24.65,221.67) 24.49,221.82 24.49,221.98 PC4601.1
  BOTTOM w0.508: PC4601.1 23.78,222.69 PR4604.1
PWR_CPU_VDDNB: length 7
  BOTTOM w0.203: 34.51,220.61 34.48,220.58 34.48,220.24 34.04,219.8 PU4601.15
  BOTTOM w0.508: 34.51,220.61 34.96,221.06 PC4605.1 PR4642.1 36.8,223.58 v2(36.89,223.67)
PWR_CPU_VRMP: length 7
  TOP w0.254: PC4614.1 33.05,222.63 v3(32.93,222.76) v1(34.37,222.76) 35.81,222.76 PR4616.2
  BOTTOM w0.203: PU4601.12 32.39,221.46 32.93,222 v3(32.93,222.76)
PWR_DCBATOUT_1D8V: length 8.4
  TOP w0.254: PU5201.1 106.06,61.32 PC5214.1 ; 105.44,58.67 PG5205.2 PG5210.2 104.94,57.91 PC5209.1 105.44,58.67
  TOP w0.762: PC5209.1 106.2,57.92 v1(106.2,56.72)
PWR_DCBATOUT_3V: length 1.7
  BOTTOM w0.762: PR4929.2 119.11,8.48 v2(119.26,8.64)
PWR_DCBATOUT_5V:
  vias: v2(121.22,26.09) v5(122.08,24.64) v5(122.08,23.5)
PWR_DCBATOUT_VDDP:
  vias: v2(24.93,161.51) v5(25.71,160.93) v5(26.22,161.7) v5(26.98,161.06)
PWR_DIFF_R: length 3.4
  BOTTOM w0.254: PR4634.2 22.7,222.68 22.42,222.96 v2(22.21,222.96) 21.95,222.96 21.75,222.76 PC4621.1
PWR_FCH_REF: length 7.6
  TOP w0.102: PR5473.2 v3(151.04,204.6) PR5472.1 151.93,204.66 PC51.1
  BOTTOM w0.102: v3(151.04,204.6) 152.18,205.74 v2(153.12,205.74) 154.83,205.74 PU5.3
PWR_FCH_S5: length 18.4
  TOP w0.254: v3(152.92,212.72) 152.1,211.91 Q4701.6 ; PC50.1 155.43,207.77 v3(156.62,207.77)
  L3 w0.254: v3(156.62,207.77) 154.96,209.44 154.96,211.44 153.68,212.72 v3(152.92,212.72)
  BOTTOM w0.254: Q6704.2 153.7,215.26 153.58,215.14 153.58,214.76 153.72,214.62 Q6704.1 154.53,213.42 PC5428.1 153.3,213.11 v3(152.92,212.72) ; PU5.4 155.48,206.88 156.37,207.77 v3(156.62,207.77)
PWR_FCH_VCNTL: length 5.5
  TOP w0.102: PC49.1 PR5475.2 163.74,206.43 v3(162.9,205.59)
  BOTTOM w0.102: PU5.6 160.92,205.61 160.94,205.59 v2(161.86,205.59) v3(162.9,205.59)
PWR_GFX_BST1: length 5.4
  BOTTOM w0.203: v2(73.89,211.8) 74.42,211.8 74.71,212.09 74.71,213.36 75.12,213.77 PU5407.28
  BOTTOM w0.508: v2(73.89,211.8) 73.22,212.47 PR5404.1
PWR_GFX_BST1_SW1: length 2.6
  BOTTOM w0.508: PR5404.2 70.49,212.47 v2(69.86,213.11) 70.49,213.74 PC5411.1
PWR_GFX_COMP: length 5.4
  BOTTOM w0.203: PU5407.48 79.57,219.86
  BOTTOM w0.254: 79.57,219.86 79.57,219.95 81.03,221.41 v2(81.11,221.41) 81.06,221.46 PC5417.2 PC5416.2
PWR_GFX_COMP_FB: length 2.3
  BOTTOM w0.254: PC5417.1 81.06,224.35 PR5415.2 80.74,224.66 79.94,224.66 v2(79.92,224.69)
PWR_GFX_CSCOMP: length 57.8
  TOP w0.254: v3(77.12,224.13) 76.59,224.66 75.57,224.66 v3(75.09,224.18) 75.34,223.93 75.34,222.04 76.02,221.36 84.51,221.36 85.15,220.73 85.15,212.98 85.57,212.56 85.57,210.5 84.62,209.55 65.5,209.55 PR5414.1
  BOTTOM w0.203: 78.37,221.04 PU5407.45
  BOTTOM w0.254: 78.37,221.04 78.37,221.53 PC5419.2 PR5417.2 78.2,223.39 PR5428.2 PR5425.1 v3(77.12,224.13) ; PC5414.1 v3(75.09,224.18) 75.09,224.59 74.89,224.79 74.41,224.79 v2(74.41,224.79) 74.4,224.79 74.2,224.59 PC5425.2
PWR_GFX_CSN1: length 59.6
  TOP w0.254: PG5402.2 v3(59.22,207.9)
  L3 w0.254: v3(59.22,207.9) 58.99,208.13 56.17,208.13 54.67,206.63 49.02,206.63 47.79,207.87 47.79,224.44 49.51,226.16 70.89,226.16 71.85,225.2 71.85,224.45 v3(72.17,224.13)
  BOTTOM w0.254: v2(59.22,207.01) v3(59.22,207.9) ; v3(72.17,224.13) PR4685.2
PWR_GFX_CSP1: length 8.9
  BOTTOM w0.203: 75.77,220.01 76.37,219.41 PU5407.40
  BOTTOM w0.254: PR5408.1 71.15,221.55 PC5426.1 v2(71.22,220.52) 71.22,220.08 71.61,219.68 74.25,219.68 74.58,220.01 75.77,220.01
PWR_GFX_CSP2: length 6.7
  TOP w0.254: v3(76.67,219.84) 75.65,220.85 73.97,220.85 v1(73.41,220.29) 73.41,219.42 PR5429.1
  BOTTOM w0.203: PU5407.41 76.77,219.73 v3(76.67,219.84)
PWR_GFX_CSREF: length 10.6
  TOP w0.254: PC5413.1 77.5,219.86 v3(76.67,220.7)
  BOTTOM w0.203: v3(76.67,220.7) 76.67,220.56 77.17,220.05 PU5407.42
  BOTTOM w0.254: v3(76.67,220.7) 76.49,220.52 v2(72.44,220.52) 72.11,220.85 PC5426.2 72.17,221.55 PR4685.1
PWR_GFX_CSSUM: length 9
  BOTTOM w0.203: PU5407.43 77.57,220.17
  BOTTOM w0.254: PR5409.1 73.19,221.74 73.44,221.49 v2(73.69,221.49) 73.95,221.49 74.2,221.74 PC5425.1 PC5414.2 PR5426.2 76.11,222.01 77.57,220.55 77.57,220.17
PWR_GFX_DIFF: length 9.2
  BOTTOM w0.203: PU5407.50 80.37,219.41 80.59,219.62
  BOTTOM w0.254: PR5407.1 84.65,223.46 85.02,223.09 v2(85.02,222.88) 85.02,222.61 84.79,222.38 PR5413.1 83.79,221.35 82.85,220.41 81.58,220.41 81.03,219.87 80.83,219.87 80.59,219.62
PWR_GFX_DIFF_R: length 4.2
  BOTTOM w0.254: PC5415.1 82.72,224.46 v2(82.72,225.63) 82.92,225.83 83.82,225.83 84.13,225.52 84.13,224.62 PR5407.2
PWR_GFX_DROOP: length 5.6
  BOTTOM w0.203: PU5407.46 78.77,220.76 78.81,220.8 78.81,220.83
  BOTTOM w0.254: 78.81,220.83 78.81,220.83 79.34,221.36 v2(79.69,221.36) 80.11,221.78 PC5419.1 PR5417.1
PWR_GFX_FB: length 8.8
  BOTTOM w0.203: PU5407.49 79.97,219.55 80.61,220.18
  BOTTOM w0.254: 80.61,220.18 80.67,220.25 80.88,220.25 81.56,220.93 82.44,220.93 v2(82.9,221.39) PR5413.2 82.9,223.39 PC5415.2 82.08,223.46 PC5416.1 81.95,224.35 PR5415.1
PWR_GFX_HG1: length 35
  L3 w1.016: v5(73.89,212.9) 71.66,212.9 71.64,212.92 71.46,212.92 67.34,217.04 55,217.04 53.91,215.95 53.91,211.3 55.02,210.19 v5(56.61,210.19)
  BOTTOM w0.203: v5(73.89,212.9) 73.49,213.3 v2(73.49,213.74) 73.74,213.99 74.13,213.99 74.32,214.17 PU5407.29
  BOTTOM w0.762: PU5401.4 v5(56.61,210.19)
PWR_GFX_ILIM: length 4.2
  BOTTOM w0.203: PU5407.44 77.97,220.79 77.58,221.18 v2(77.58,221.49)
  BOTTOM w0.254: v2(77.58,221.49) 78.14,222.05 PR5428.1
PWR_GFX_ILIM_R: length 47.8
  TOP w0.254: PR5414.2 65.5,209.04 84.83,209.04 86.08,210.29 86.08,212.77 85.66,213.19 85.66,220.94 84.62,221.97 76.13,221.97 75.85,222.25 75.85,223.88 v3(76.11,224.13)
  BOTTOM w0.254: PR5425.2 77,222.44 PR5426.1 v3(76.11,224.13) 76.11,224.66 v2(76.49,225.04)
PWR_GFX_IOUT: length 5.5
  TOP w0.254: PC5423.2 PR5402.1 78.34,219.32 v1(78.34,220.45) 78.47,220.57 v3(79.31,220.57)
  BOTTOM w0.203: v3(79.31,220.57) 79.17,220.44 PU5407.47
PWR_GFX_LG1: length 28.7
  L3 w1.016: 63.22,223.14 60.55,223.14 v5(59.85,223.84) ; 63.22,223.14 65.88,223.14 v5(66.58,223.84) ; 63.22,223.14 63.22,220.92 63.79,220.34 68.71,220.34 72.8,216.25 v5(73.89,216.25)
  BOTTOM w0.203: v5(73.89,216.25) 73.67,216.25 73.41,216 v2(73.41,215.44) 73.7,215.16 74.13,215.16 74.32,214.97 PU5407.31
  BOTTOM w0.762: v5(66.58,223.84) PU5402.4 ; PU5403.4 v5(59.85,223.84)
PWR_GFX_PHCONFIG: length 5.4
  TOP w0.254: v3(74.82,218.81) 74.82,217.76 PR5412.1
  BOTTOM w0.203: v3(74.82,218.81) 74.39,218.81 74.12,218.54 v2(74.12,218.16) 74.51,217.77 PU5407.38
PWR_GFX_ROSC: length 6.2
  BOTTOM w0.203: 83.09,213.87 82.79,214.17 PU5407.11
  BOTTOM w0.254: PR5411.2 82.88,210.84 82.88,211.8 v2(83.4,212.32) 83.22,212.5 83.22,213.74 83.09,213.87
PWR_GFX_SNB1:
  vias: v2(54.14,220.6)
PWR_GFX_SR: length 3.3
  TOP w0.254: PR5419.1 75.66,218.79 v3(75.68,218.81) 75.68,219.77 75.23,220.22 v1(75.14,220.22)
  BOTTOM w0.203: PU5407.39 75.96,218.53 v3(75.68,218.81)
PWR_GFX_SW1: length 18.2
  L3 w1.016: v5(73.89,214.57) 72.15,214.57 68.02,218.69 v5(61.31,218.69)
  BOTTOM w0.203: v5(73.89,214.57) PU5407.30
  BOTTOM w0.508: v5(73.89,214.57) 73.26,214.57 PC5411.2
  vias: v2(59.28,212.67) v5(54.9,215.54) v5(55.81,215.54) v5(56.73,215.54) v5(56.73,214.62) v5(56.73,213.71) v5(56.73,212.79) v5(56.73,211.88) v5(57.64,215.54) v5(58.55,215.54) v5(59.47,215.54) v5(60.38,215.54) v5(61.3,215.56) v5(61.7,214.62) v5(61.7,213.71) v5(61.7,212.79) v5(61.7,211.88) v5(62.21,215.54) v5(62.62,214.62) v5(62.62,213.71) v5(62.62,212.79) v5(62.62,211.88) v5(63.13,215.54) v5(63.53,214.62) v5(63.53,213.71) v5(63.53,212.79) v5(63.53,211.88) v5(64.04,215.54) v5(64.45,214.62) v5(64.45,213.71) v5(64.45,212.79) v5(64.96,215.54) v5(65.36,214.62) v5(65.36,213.71) v5(65.87,215.54) v5(66.28,214.62) v5(66.78,215.54)
PWR_GFX_SWN1: length 60.8
  TOP w0.254: PG5401.2 v3(59.22,208.74) ; v3(71.15,224.13) 71.69,224.66 72.65,224.66 v3(73.19,224.13)
  L3 w0.254: v3(59.22,208.74) 58.99,208.51 56.01,208.51 54.52,207.01 49.18,207.01 48.17,208.03 48.17,224.28 49.67,225.78 70.73,225.78 71.47,225.04 71.47,224.45 v3(71.15,224.13)
  BOTTOM w0.254: v2(59.22,209.55) v3(59.22,208.74) ; PR5408.2 v3(71.15,224.13) ; v3(73.19,224.13) PR5409.2
PWR_GFX_TSENSE: length 68.9
  TOP w0.254: PR5421.2 PC5422.2 82.07,219.14 v3(82.41,218.81)
  L4 w0.254: v3(53.09,208.28) 52.56,207.75 49.33,207.75 47.15,209.93 47.15,224.79 48.6,226.24 78.72,226.24 82.46,222.5 82.46,218.86 v3(82.41,218.81)
  BOTTOM w0.203: v3(82.41,218.81) 81.77,218.17 PU5407.1
  BOTTOM w0.254: v3(53.09,208.28) 53.09,207.62 52.74,207.26 v2(52.48,207.26) 52.31,207.26 52.04,207.53 PR5423.2
PWR_GFX_VCC: length 4.6
  BOTTOM w0.203: PU5407.10 83.1,214.57 83.24,214.43 83.66,214.43 v2(83.78,214.31)
  BOTTOM w0.508: v2(83.78,214.31) 84.45,214.31 84.51,214.38 PC5420.1 84.81,214.31 PR5418.2
PWR_GFX_VDD: length 8.1
  BOTTOM w0.203: 83.35,219.87 81.73,219.87 81.36,219.51 80.98,219.51 80.77,219.31 PU5407.51
  BOTTOM w0.508: PR5420.1 85.69,220.55 85.25,220.99 v2(85.25,221.01) 85.2,221.01 84.74,220.55 PC5418.1 84.51,219.87 83.35,219.87
PWR_GFX_VR_HOT: length 5.1
  BOTTOM w0.203: PU5407.13 81.59,212.79
  BOTTOM w0.254: 81.59,212.79 81.59,211.75 80.88,211.05 80.12,211.05 79.84,210.77 v2(79.84,210.72) 79.84,210.41 80.26,209.99 PR5464.1
PWR_GFX_VRMP: length 6.4
  BOTTOM w0.203: 82.71,213.23 82.71,213.49 82.42,213.77 PU5407.12
  BOTTOM w0.254: PR5424.2 PC5424.1 81.95,210.76 v2(81.95,211.15) 82.37,211.57 82.37,212.54 82.71,212.88 82.71,213.23
PWR_GFX_VSS: length 5.1
  BOTTOM w0.203: PU5407.52 81.46,218.59 81.95,219.07 81.95,219.11
  BOTTOM w0.254: PR5422.1 85.63,218.76 PC5418.2 84.04,218.76 v2(83.7,219.1) 83.61,219.19 83.06,219.19 82.91,219.34 82.18,219.34 81.95,219.11
PWR_LED_YELLOW_C: length 13
  TOP w0.254: PWRCN1.9 30.36,20.75 30.97,20.14 v3(30.97,19.42) 31.11,19.56 31.99,19.56 v1(32,19.56)
  BOTTOM w0.254: Q1212.D 28.99,15.54 28.76,15.77 28.76,17.23 R1761.1 29.88,17.4 v2(30.01,17.53) 30.01,17.78 29.24,18.54 R1751.2 29.99,19.42 v3(30.97,19.42)
PWR_LED_YELLOW_C2: length 3.3
  BOTTOM w0.254: v2(26.7,17.78) 27.47,18.54 R1751.1 28.99,19.94 R724.2
PWR_VDDP_BOOT:
  vias: v1(21.31,159.46)
PWR_VDDP_BOOT_R: length 2.4
  TOP w0.508: v1(24.29,161.29) PR4812.2 PC4806.2
PWR_VDDP_CS: length 2.7
  TOP w0.254: PU4803.2 16.63,157.35 16.24,157.73 v1(15.58,157.73) PR4802.2
PWR_VDDP_EN: length 7.4
  TOP w0.254: PU4803.3 16.18,156.84 16.16,156.83 v3(16.14,156.83)
  BOTTOM w0.254: v3(16.14,156.83) 16.16,156.81 16.16,156.7 16.4,156.46 PC4804.1 PC48.1 16.99,158.62 R1763.2 R1764.1 R125.1 19.91,158.69 v2(19.97,158.62)
PWR_VDDP_FB: length 5
  TOP w0.254: PC4805.2 PR4803.2 14.64,155.64 PR4816.1 15.13,156.26 v1(15.53,156.26) 15.56,156.3 16.53,156.3 16.58,156.34 PU4803.4
PWR_VDDP_FB_R: length 33.7
  TOP w0.254: PG4801.1 v3(39.5,151) ; PC4805.1 PR4803.1 15.17,154.27 15.17,154.78 v3(16.14,155.75)
  BOTTOM w0.254: v3(39.5,151) 39.5,149.71 38.23,148.44 v2(38.23,148.41) 38.21,148.41 37.5,147.7 26.07,147.7 23.38,150.39 23.38,150.91 20.24,154.05 20.23,154.05 19.64,154.64 17.48,154.64 16.37,155.75 v3(16.14,155.75)
PWR_VDDP_LGATE: length 15.6
  TOP w0.305: PU4803.6 20.25,154.58 20.53,154.31 v1(20.58,154.31)
  TOP w0.508: v1(20.58,154.31) 21.37,154.31 v5(21.88,154.81)
  TOP w0.762: PU4801.4 27.21,150.11 v5(27.08,150.24)
  L3 w1.016: v5(21.88,154.81) 27.47,154.81 28.18,154.09 28.18,151.34 v5(27.08,150.24)
PWR_VDDP_PG: length 3.2
  TOP w0.254: PR4805.2 16.53,158.94 v1(16.95,159.36) 17.15,159.16 PU4803.1
PWR_VDDP_PHASE: length 19.2
  TOP w0.305: PU4803.8 22.26,156.84 v5(22.45,156.65)
  TOP w0.508: PC4806.1 23.16,157.35 v5(22.45,156.65)
  L3 w1.016: v5(22.45,156.65) 23.54,156.65 25,158.12 33,158.12 v5(35.54,160.66)
  vias: v1(36.61,151.89)
PWR_VDDP_RF: length 3.2
  TOP w0.254: PU4803.5 17.15,154.04 PR4807.1 17.22,153.25 17.61,152.86 v1(17.64,152.86)
PWR_VDDP_SNB:
  vias: v1(32.67,155.83)
PWR_VDDP_UGATE: length 20.5
  TOP w0.305: PU4803.9 21.54,157.35 22.56,158.37 v5(22.64,158.37)
  TOP w0.762: PU4802.4 v5(35.85,162.56)
  L3 w1.016: v5(22.64,158.37) 24.04,159.77 31.93,159.77 34.73,162.56 v5(35.85,162.56)
  BOTTOM w0.508: v5(22.64,158.37) v2(22.64,159.34)
PWR_VDDQ_BOOT: length 4.7
  TOP w0.203: PU5001.18 142.02,80.67 141.74,80.95 141.74,81.52
  TOP w0.508: 141.74,81.52 142.46,82.25 142.48,82.25 PR5006.1 143.16,82.68 143.16,81.79 v1(143.21,81.74)
PWR_VDDQ_BOOT_L: length 2.7
  TOP w0.508: PR5006.2 PC5010.1 145.71,84.33 v1(145.72,84.34)
PWR_VDDQ_CS: length 5.1
  TOP w0.203: 145.03,78.14 144.92,78.04 144.47,78.04 144.15,78.36 PU5001.13
  TOP w0.254: 145.03,78.14 145.32,78.44 145.32,79.04 v1(145.65,79.38) PR5003.2 PC5003.2
PWR_VDDQ_EN: length 5.8
  TOP w0.203: PU5001.8 142.02,76.06
  TOP w0.254: 142.02,76.06 142.02,75.44 v1(142.4,75.06) 142.4,74.83 142.46,74.77 R1810.2 142.46,73.03 R1808.2 142.72,72.83 C1796.1
PWR_VDDQ_FB: length 6.5
  TOP w0.203: PU5001.6 141.22,76.8 140.5,76.07 140.5,75.92 v3(140.41,75.83)
  TOP w0.254: PR5023.2 140.43,73.15 PC5013.2 140.43,75.81 v3(140.41,75.83)
  BOTTOM w0.254: v3(140.41,75.83) 140.04,76.2 140.04,76.63 v2(140.01,76.66) 140.25,76.9 PR5009.1
PWR_VDDQ_LGATE: length 13.8
  TOP w0.203: v5(144.64,79.68) 144.11,79.16 PU5001.15
  TOP w0.762: PU5007.4 145.07,89.79 v5(144.81,89.53)
  L4 w0.762: v5(144.64,79.68) 144.74,79.78 144.74,89.46 v5(144.81,89.53)
  BOTTOM w0.508: v2(144.82,90.57) 144.82,90.34 144.81,90.34 v5(144.81,89.53)
PWR_VDDQ_PHASE: length 22.8
  TOP w0.203: v5(143.42,80.52) 143.02,80.52 142.82,80.31 PU5001.16
  TOP w0.508: PC5010.2 144.43,82.68 144.43,81.53
  L4 w0.762: v5(139.61,97.16) 139.61,97.12 140.11,96.61 140.11,85.47 143.42,82.17 v5(143.42,80.52)
  BOTTOM w0.508: v2(139.48,98.08) 139.48,97.28 v5(139.61,97.16)
  BOTTOM w1.016: PR5034.1 v5(141.38,98.55)
PWR_VDDQ_SENSE: length 46.8
  TOP w0.203: 140.01,76.23 140.01,76.27 140.47,76.73 PU5001.5
  TOP w0.254: PG5001.2 v1(134.15,103.89) 134.15,102.51 v3(134.12,102.49) ; v3(138.46,72.14) 139.35,73.03 PR5023.1 139.54,73.15 PC5013.1 139.54,75.76 140.01,76.23
  L3 w0.254: v3(134.12,102.49) 134.12,102.46 131.86,100.2 131.86,98.68 130,96.82 130,85.67 134.65,81.03 134.65,77.98 137.68,74.96 137.68,72.92 v3(138.46,72.14)
PWR_VDDQ_SNB: length 3.7
  BOTTOM w0.508: PC5017.1 142.45,94.03 142.73,94.31 v2(142.73,94.74) 142.73,95.05 142.35,95.43 PR5034.2
PWR_VDDQ_TON: length 4.4
  TOP w0.203: PU5001.9 142.42,76.07
  TOP w0.254: 142.42,76.07 143.28,75.21 144.25,75.21 v1(144.41,75.06) 144.94,74.52 PR5007.2
PWR_VDDQ_UGATE: length 24.4
  TOP w0.203: PU5001.17 v5(142.42,81.15)
  TOP w0.762: PU5006.4 v5(134.65,98.32)
  L4 w0.762: v5(134.65,98.32) 138.46,94.51 138.46,84.98 142.29,81.15 v5(142.42,81.15)
  BOTTOM w0.508: v5(134.65,98.32) 134.62,98.36 134.62,99.24 v2(134.62,99.24)
PWR_VDDQ_VDD: length 14.3
  TOP w0.203: PU5001.11 143.57,77.14 143.82,76.89
  TOP w0.254: PC5003.1 PR5003.1 147.9,79.38 148.67,78.6 v1(148.67,78.08) 149.45,77.3 149.45,75.61 148.27,74.42 146.65,74.42 PR5002.1 PC5018.1 144.64,76.07 143.82,76.89
PWR_VDDQ_VDDP: length 4.2
  TOP w0.203: 144.35,77.68 144.08,77.96 PU5001.12
  TOP w0.254: 144.35,77.68 144.35,77.5 v1(144.91,76.94) 144.94,76.96 PC5009.1 146.02,77.95 PR5004.1
PWR_VDDQ_VTTIN: length 1.4
  TOP w0.203: PU5001.19 141.62,80.39 141.38,80.63
  TOP w0.254: 141,81.01 141.38,80.63
  vias: v1(140.65,81.66)
PWR_VDDQ_VTTREF: length 6.7
  TOP w0.203: PU5001.4 139.92,77.96 139.4,77.44
  TOP w0.254: PR5032.2 137.19,73.76 PC5014.1 137.96,75.11 v1(138.61,75.75) 138.61,75.77 139.27,76.43 139.27,77.26 139.33,77.35 139.34,77.38 139.4,77.44
PWR_VGA_CORE_BOOT1: length 5
  TOP w0.203: U9.19 124.1,75.95 124.45,76.31
  TOP w0.508: 124.45,76.31 124.45,76.71 124.39,76.77 124.39,77.4 124.45,77.47 124.45,78.73 v1(124.29,78.89) 123.53,79.65 PR43.1
PWR_VGA_CORE_COMP: length 11.6
  TOP w0.203: v3(121.77,70.26) 121.75,70.28 121.75,70.31 121.66,70.39 U9.7
  TOP w0.254: PR13.2 118.58,64.58 119.13,65.13 119.2,65.13 PC6.1 119.48,65.53 PC7.2 PC8.1 120.8,66.73 v1(120.8,67.64) 120.8,68.48 121.75,69.43 121.75,70.23 v3(121.77,70.26)
  BOTTOM w0.254: PR1.2 121.19,71.44 121.51,71.12 PC4.2 121.51,70.55 121.75,70.31 121.75,70.28 v3(121.77,70.26)
PWR_VGA_CORE_DPRSLPVR: length 4.7
  TOP w0.203: U9.39 117.83,73.15
  TOP w0.254: 117.83,73.15 116.53,71.84 116.53,71.31 v1(116.21,70.99) 115.58,70.36 PR17.2
PWR_VGA_CORE_FB: length 14.3
  TOP w0.203: U9.8 122.06,70.71 122.28,70.49 v3(122.28,69.55) 122.28,69.28 121.47,68.47 121.47,66.51 PC8.2
  TOP w0.508: PR8.2 PC8.2 ; v3(127.06,69.72) PR20.1 127.86,70.74 PR21.1
  BOTTOM w0.508: v3(127.06,69.72) 126.38,69.04 v2(125.69,69.04) 122.71,69.04 122.28,69.47 v3(122.28,69.55)
PWR_VGA_CORE_FB2: length 4.9
  TOP w0.203: v3(122.79,70.26) 122.79,70.67 122.46,70.99 U9.9
  BOTTOM w0.508: v2(123.7,70.26) v3(122.79,70.26) 122.79,70.29 122.4,70.68 PC4.1 122.4,71.12 122.33,71.18 122.31,71.23 PC5.2
PWR_VGA_CORE_IMON: length 9.2
  TOP w0.203: PR99.2 125.89,78.36 125.23,77.7 v1(125.23,77.11) 125.23,76.22 124.71,75.7 124.61,75.7 124.47,75.55 U9.18
  TOP w0.254: v3(126.65,79.52) 126.65,79.38 127.1,78.93 PR99.2 127.16,78.3 PC59.2
  BOTTOM w0.254: v3(126.65,79.52) 126.65,79.38 127.16,78.87 PR98.1
PWR_VGA_CORE_ISEN1: length 5.9
  TOP w0.203: U9.11 123.62,72.28
  TOP w0.254: 123.62,72.28 124.24,71.65 v1(124.24,70.48) 124.24,68.53 123.41,67.7 PR12.2
PWR_VGA_CORE_ISEN2: length 6.4
  TOP w0.203: 123.35,71.75 123.11,72 U9.10
  TOP w0.254: 123.35,71.75 123.35,68.96 v1(123.13,68.74) 122.52,68.14 PR12.1 122.46,67.37 PR11.2
PWR_VGA_CORE_ISUM+: length 15.1
  TOP w0.203: U9.15 125.48,74.35 126.02,74.89 126.02,74.9 v3(126.04,74.93)
  TOP w0.254: PR34.1 126.27,75.95 126.04,75.72 v3(126.04,74.93)
  BOTTOM w0.254: PR42.1 129.76,77.66 PR45.1 ; v2(131.08,78.38) 131.06,78.36 131.06,77.78 130.46,77.18 PR45.1 ; PR45.1 PC15.1 ; PR45.1 129.95,76.45 PC16.1 128.18,75.44 PR41.1 127.45,75.97 126.65,75.97 126.62,75.95 126.32,75.95 126.04,75.67 v3(126.04,74.93)
PWR_VGA_CORE_ISUM-: length 6.4
  TOP w0.203: v3(126.02,74.04) 125.93,73.95 U9.14
  TOP w0.254: PC14.1 126.91,74.93 v3(126.02,74.04)
  BOTTOM w0.254: v3(126.02,74.04) 126.02,73.84 126.56,73.3 v2(126.87,73.3) 126.89,73.3 127.26,73.67 127.26,74.13 PR16.2
PWR_VGA_CORE_LGATE1A: length 26.7
  TOP w0.203: v5(121.67,78.64) 121.96,78.36 121.96,77.82 122.06,77.71 U9.23
  TOP w0.762: PU3.4 v5(119.57,93.34)
  L4 w1.016: v5(113.72,93.34) v5(119.57,93.34) 119.87,93.04 119.87,80.06 121.29,78.64 v5(121.67,78.64)
  BOTTOM w0.508: v2(120.54,79.04) 120.95,78.64 v5(121.67,78.64)
  BOTTOM w0.762: PU5202.4 v5(113.72,93.34)
PWR_VGA_CORE_LGATE1B: length 3.6
  TOP w0.203: U9.24 121.66,77.64 121.63,77.68 121.63,77.79 120.97,78.44 120.97,80.36 TP203.1
PWR_VGA_CORE_NTC: length 39.1
  TOP w0.203: U9.5 120.86,70.16 120.75,70.05 v3(120.75,69.88)
  TOP w0.254: PR60.2 v3(129.07,95.61)
  L4 w0.254: v3(120.75,69.88) 120.43,70.2 120.43,70.99 120.81,71.37 125.67,71.37 128.81,74.51 128.81,79.42 129.6,80.21 129.6,95.07 v3(129.07,95.61)
  BOTTOM w0.254: PC9.1 120.68,71.56 120.68,70.02 120.75,69.95 v3(120.75,69.88) ; v2(129.96,95.81) 129.75,95.61 v3(129.07,95.61)
PWR_VGA_CORE_ON: length 10.1
  TOP w0.203: 117.52,73.55 U9.38
  TOP w0.254: PC12.1 113.04,71.5 113.49,71.04 v3(113.62,71.04) 115.02,71.04 115.29,71.31 PR18.2 115.57,71.6 117.52,73.55
  BOTTOM w0.254: PR19.2 113.16,71.5 v3(113.62,71.04) v2(114.54,71.04)
PWR_VGA_CORE_PGOOD: length 5.9
  TOP w0.203: U9.1 119.26,71.61 118.42,70.76 117.81,70.76
  TOP w0.254: 117.81,70.76 116.8,69.75 v1(116.8,69.7) 116.29,69.7 115.35,68.76 PR14.1
PWR_VGA_CORE_PHASE1: length 25.9
  TOP w0.203: U9.21 122.86,77.71 122.97,77.82 122.97,78.74 122.89,78.82 v5(122.89,78.87)
  TOP w0.508: PC19.1 122.33,79.38 122.84,78.87 v5(122.89,78.87)
  L4 w1.016: v5(122.89,78.87) 122.84,78.92 122.84,79.5 121.93,80.42 121.93,93.12 121.66,93.39 v5(121.66,100.2)
  BOTTOM w0.508: v5(122.89,78.87) 122.89,79.65 122.89,79.65 v2(122.89,79.76)
  vias: v5(114.41,103.56) v5(114.41,102.64) v5(114.41,101.73) v5(115.32,103.56) v5(115.32,102.64) v5(115.32,101.73) v5(116.24,103.56) v5(116.24,102.64) v5(116.24,101.73) v5(121.45,104.42) v5(121.45,103.5) v5(121.45,102.59) v5(121.45,101.68) v5(122.36,104.42) v5(122.36,103.5) v5(122.36,102.59) v5(122.36,101.68) v5(123.27,104.42) v5(123.27,103.5) v5(123.27,102.59) v5(123.27,101.68) v5(124.19,104.42) v5(124.19,103.5) v5(124.19,102.59) v5(124.19,101.68) v5(125.1,104.42) v5(125.1,103.5) v5(125.1,102.59) v5(125.1,101.68) v5(126.02,104.42) v5(126.02,103.5) v5(126.02,102.59) v5(126.02,101.68)
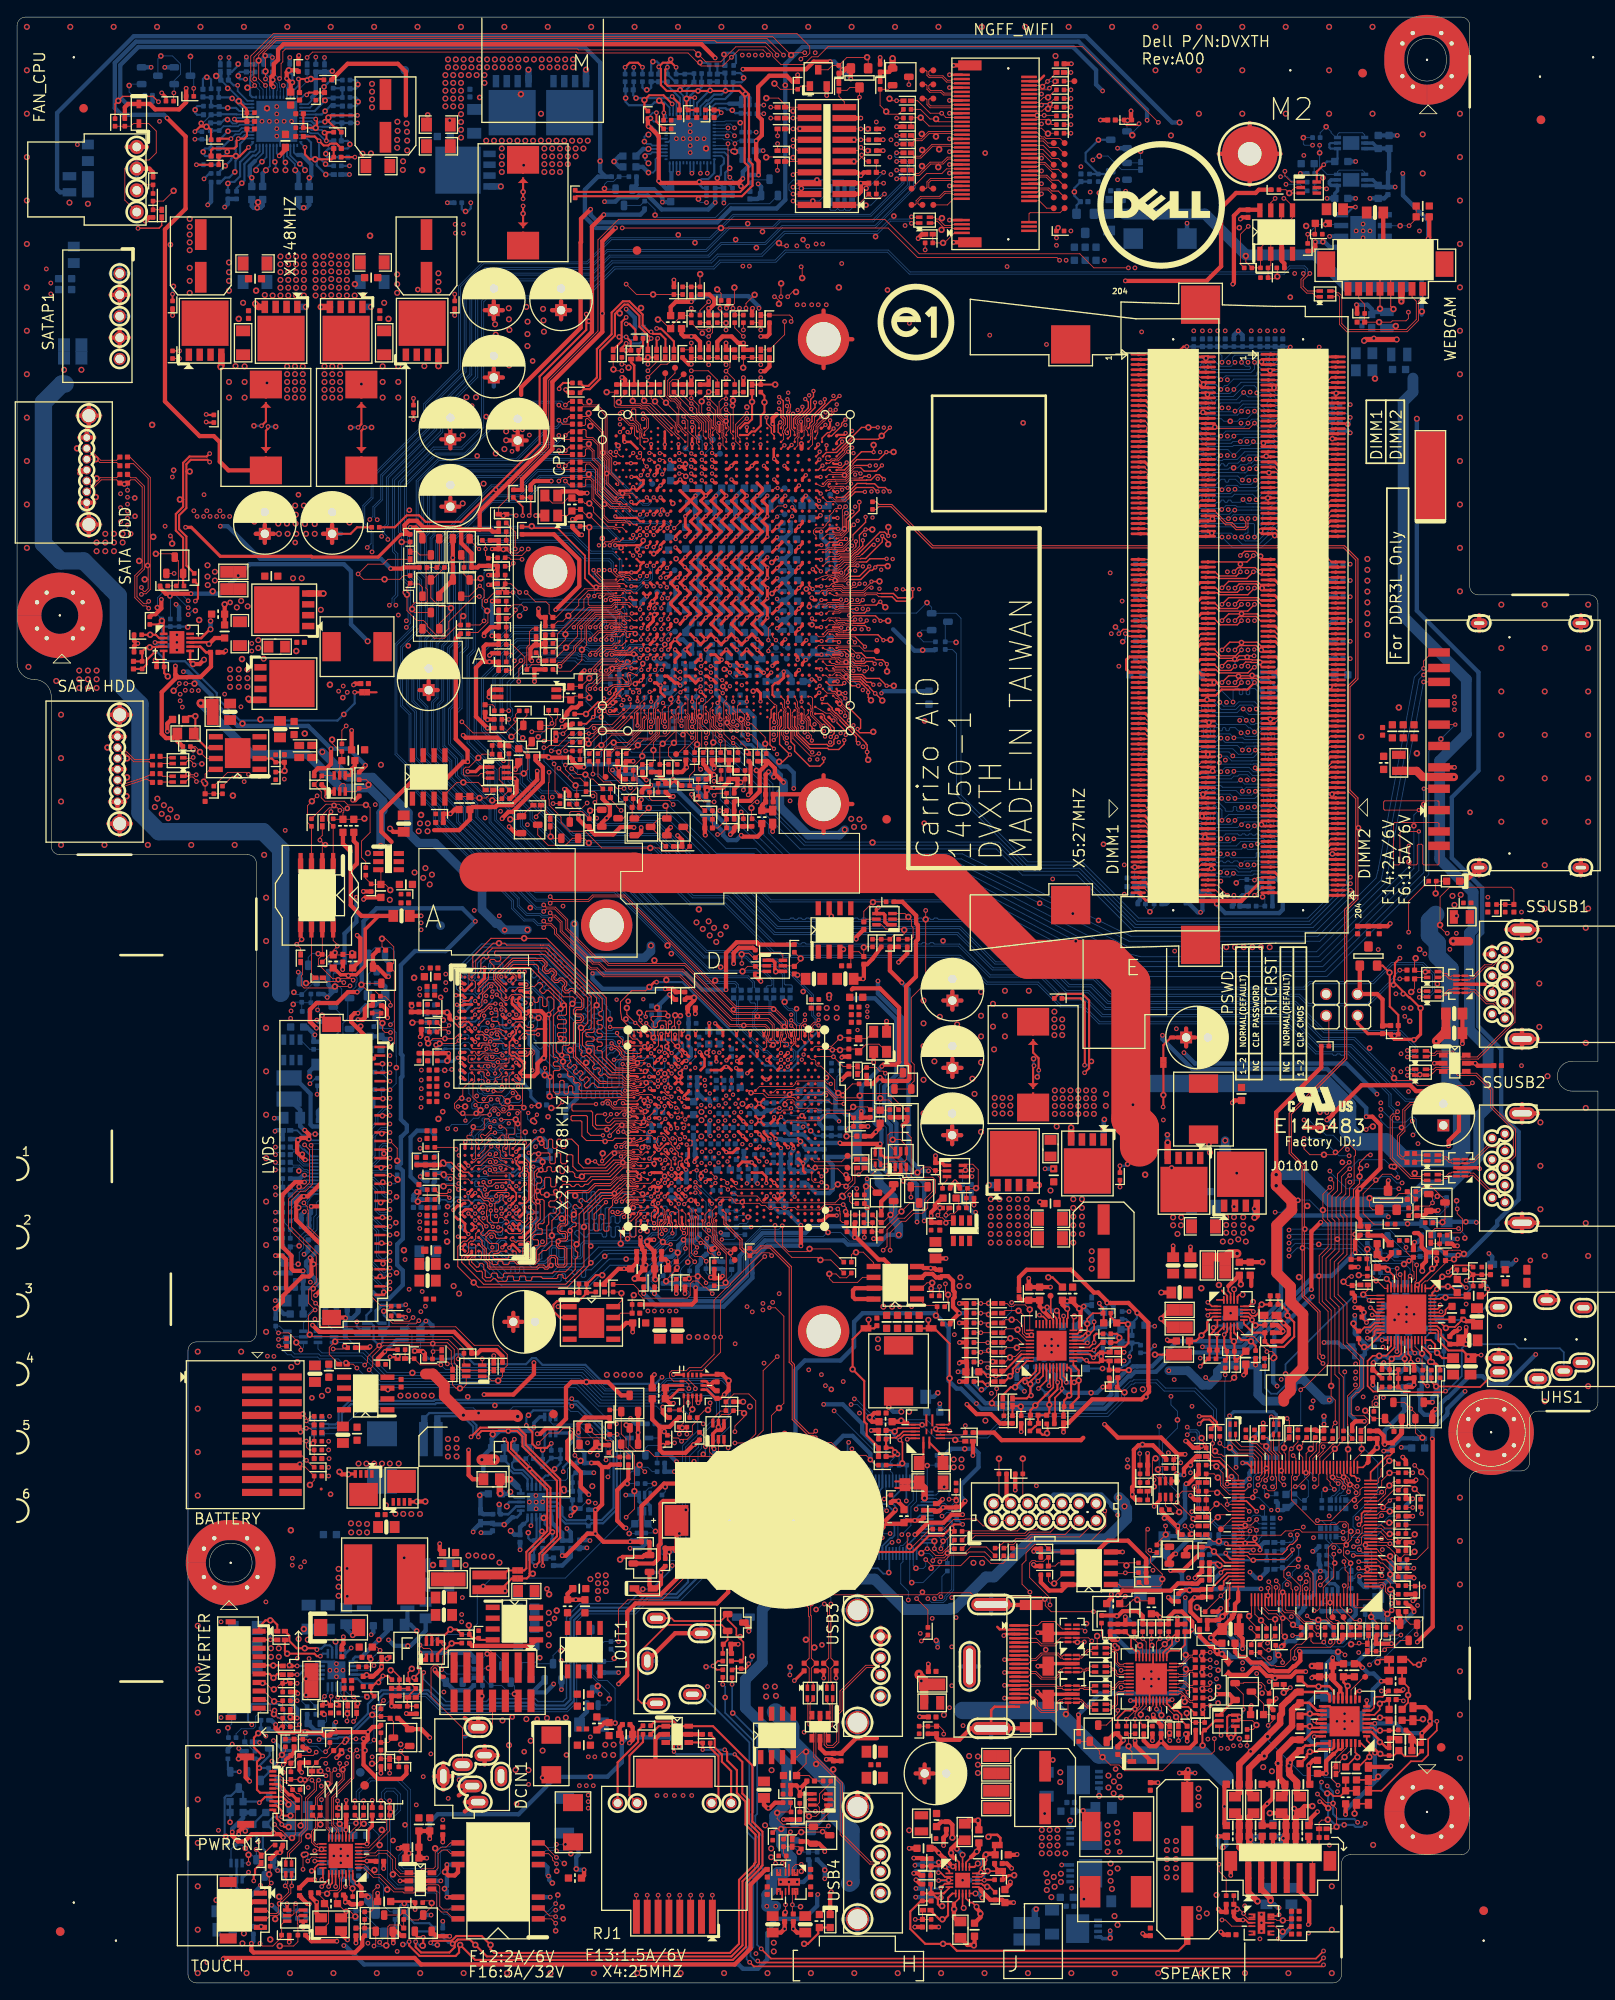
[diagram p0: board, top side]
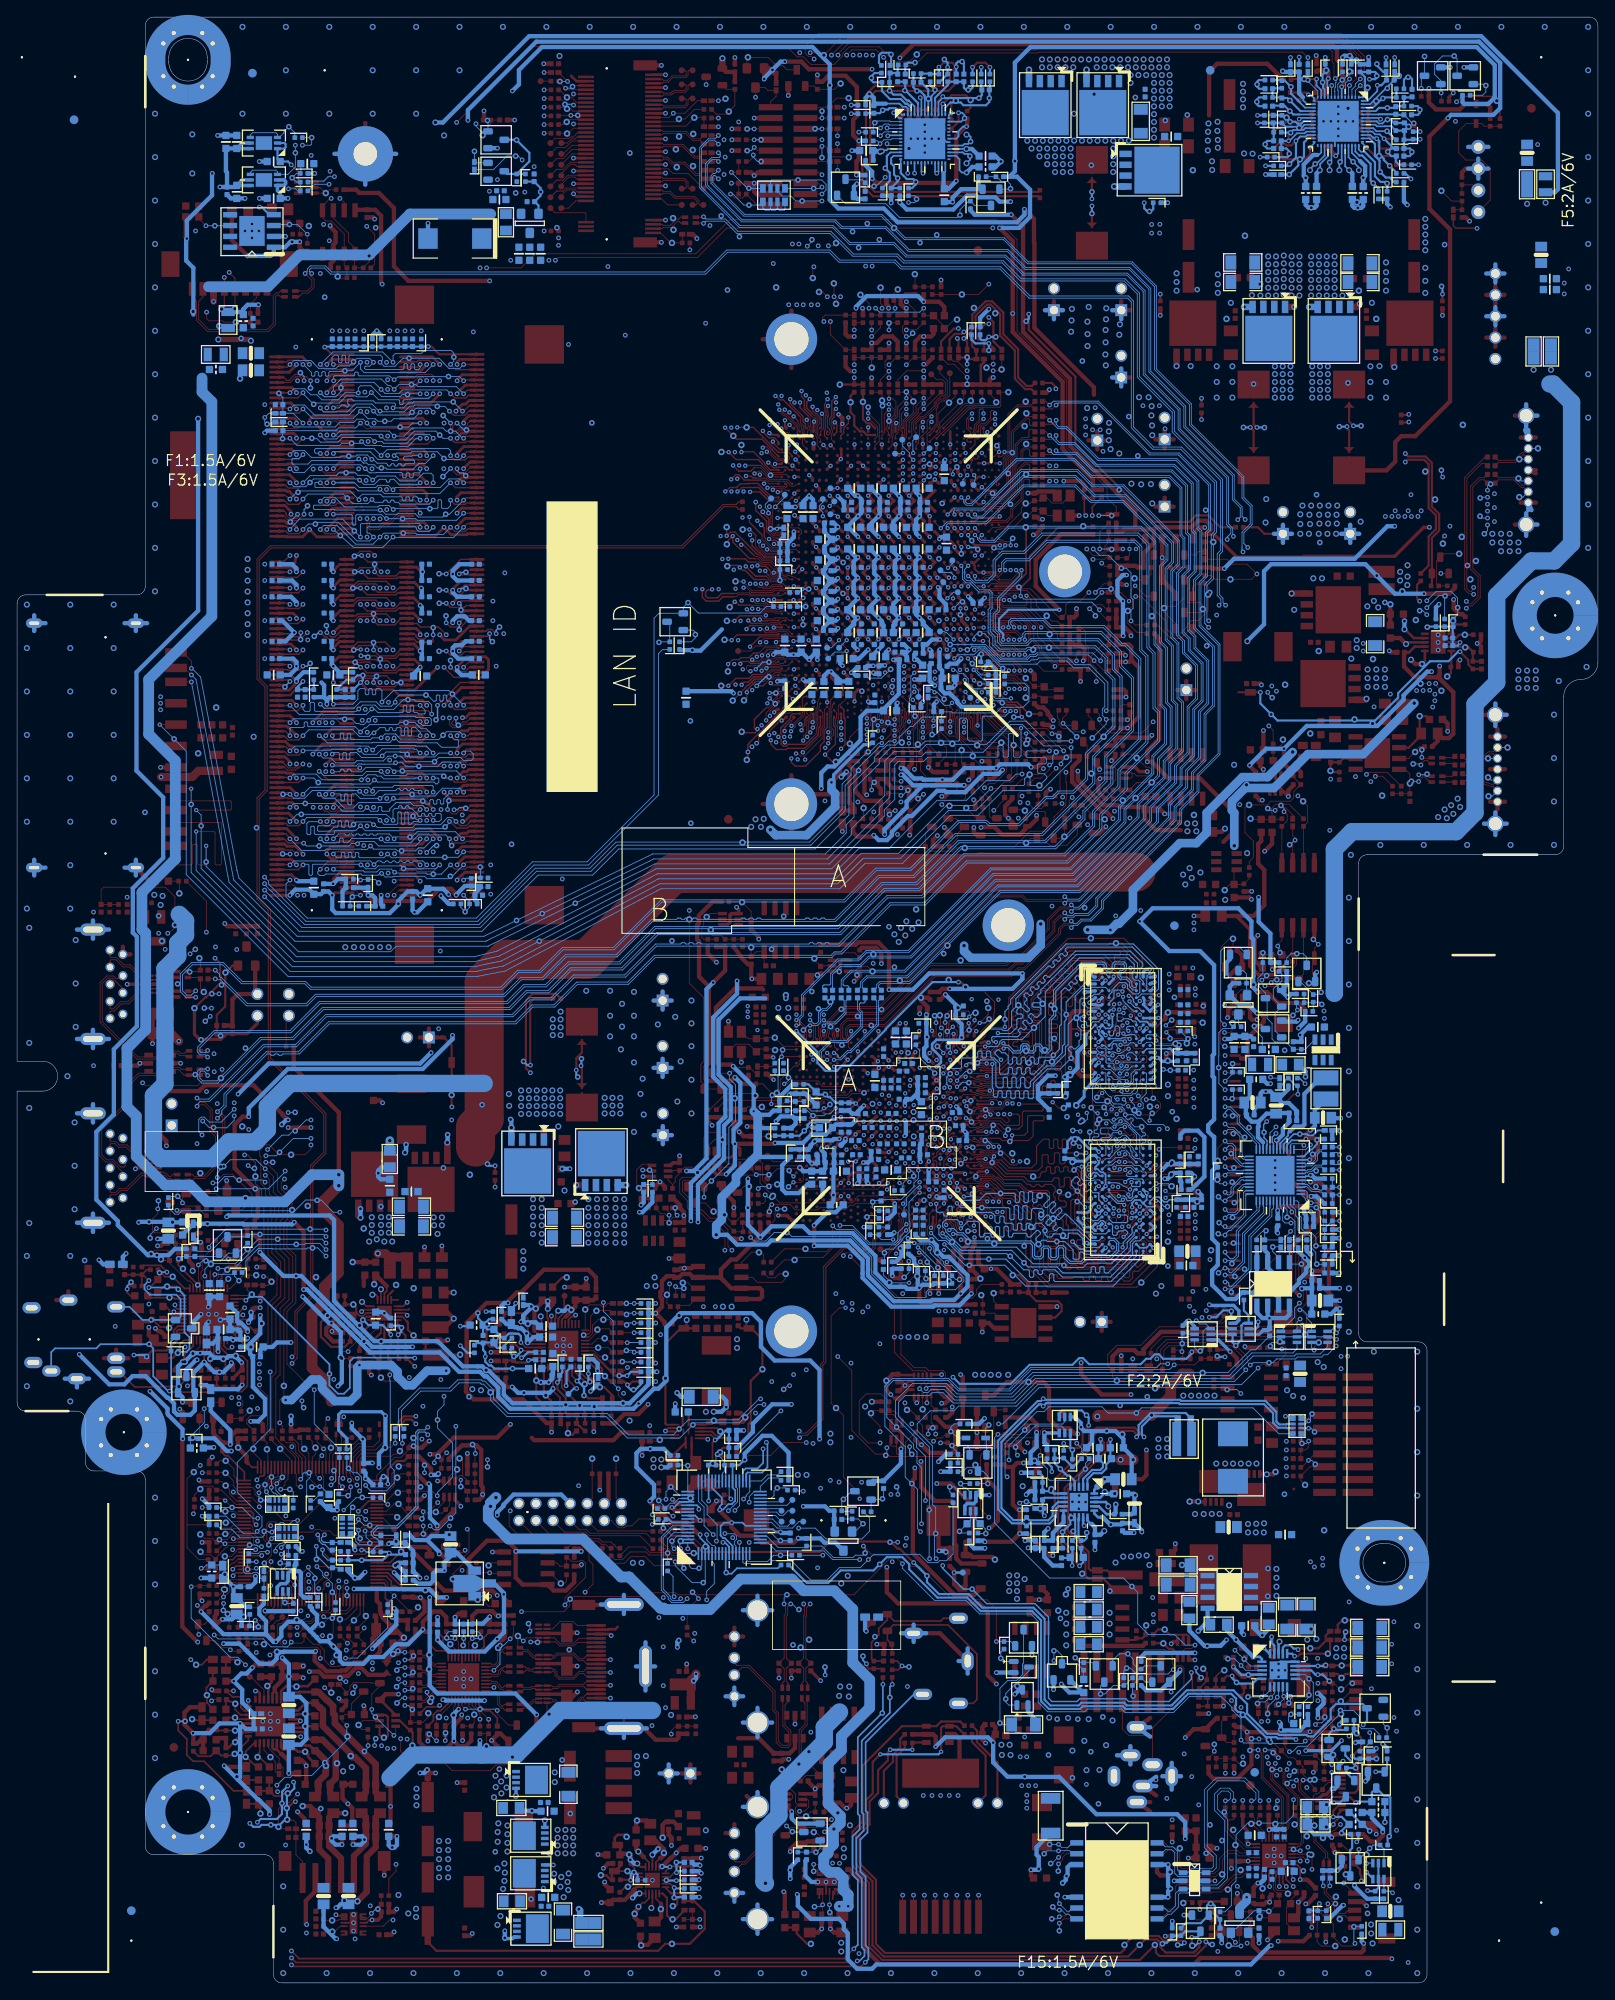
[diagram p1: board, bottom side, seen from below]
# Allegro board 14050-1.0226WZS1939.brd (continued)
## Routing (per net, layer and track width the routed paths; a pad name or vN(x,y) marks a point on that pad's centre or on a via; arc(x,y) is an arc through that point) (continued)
PWR_VGA_CORE_PSI#: length 5.9
  TOP w0.203: 118.71,70.48 119.66,71.44 U9.2
  TOP w0.254: 118.71,70.48 118.57,70.35 v1(118.57,70.05) 118.57,68.81 118.16,68.39 PR10.1
PWR_VGA_CORE_RTN: length 14.5
  TOP w0.203: U9.13 125.56,73.55 v3(125.97,73.14)
  TOP w0.254: PR99.1 127.99,77.91 PC59.1 129.85,77.22 v1(130,77.06) 130.06,77.01 130.06,74.86 129.62,74.42 128.48,74.42 128.43,74.37 128.22,74.37 128.02,74.17 128.02,73.95 PR29.2 127.8,73.72 PC13.2 126.55,73.72 v3(125.97,73.14)
  BOTTOM w0.254: v3(125.97,73.14) 125.94,73.17 125.84,73.17 125.22,73.79 PC57.2
PWR_VGA_CORE_SNB1: length 0.9
  BOTTOM w0.508: v2(121.22,95.25) v3(120.3,95.25)
PWR_VGA_CORE_UGATE1: length 32.3
  TOP w0.203: U9.20 123.62,77.86 123.73,77.98 v5(123.72,77.98)
  TOP w0.762: PU1.4 v5(123.35,100.06)
  L4 w1.016: 125.26,100.01 125.26,92.56 125.61,92.2 125.61,87.1 124.49,85.98 124.49,78.75 v5(123.72,77.98) ; 125.26,100.01 127.11,100.01 v5(127.16,100.06) ; 125.26,100.01 123.4,100.01 v5(123.35,100.06)
  BOTTOM w0.508: v5(127.16,100.06) 127.16,100.94 v2(127.24,101.02)
  BOTTOM w0.762: v5(127.16,100.06) PU2.4
PWR_VGA_CORE_VCCP: length 6.1
  TOP w0.203: 120.78,77.95 120.9,77.95 121.26,77.58 U9.25
  TOP w0.508: 120.78,77.95 120.15,78.58 v1(120.15,78.74) 120.07,78.74 119.67,79.15 PC17.1 PC18.1 117.57,79.88 PR44.1
PWR_VGA_CORE_VDD: length 8.2
  TOP w0.203: v3(125.26,74.88) 125.26,74.8 125.2,74.75 U9.16
  BOTTOM w0.508: PR95.2 127.73,77.09 PR98.2 126.78,76.71 126.49,76.71 126.36,76.58 125.96,76.58 v2(125.38,76) 125.33,75.95 125.33,74.96 v3(125.26,74.88) 124.57,75.56 PC58.1
PWR_VGA_CORE_VID0: length 6.1
  TOP w0.102: PR39.2 115.85,79.5 116.2,79.15 116.58,79.15 116.76,79.32 117.98,79.32 v1(118.51,78.79) U9.31
PWR_VGA_CORE_VID1: length 5.7
  TOP w0.102: 117.15,78.59 117.07,78.66 115.59,78.66 PR37.2 ; 117.15,78.59 v1(117.2,78.64) ; 117.15,78.59 117.3,78.59 117.88,78.02 117.88,76.16 118.08,75.95 U9.32
PWR_VGA_CORE_VID2: length 4.8
  TOP w0.102: U9.33 118.08,75.55 117.65,75.98 117.65,76.95 117,77.59 v1(116.39,77.59) 115.66,77.59 PR35.2
PWR_VGA_CORE_VID3: length 4.2
  TOP w0.102: U9.34 118.1,75.15 117.09,76.16 v1(117.09,76.43) 116.99,76.53 115.74,76.53 PR32.2
PWR_VGA_CORE_VID4: length 3.7
  TOP w0.102: PR30.2 115.6,74.93 116.09,75.42 116.24,75.42 v1(116.24,75.42) 117.04,75.42 117.71,74.75 U9.35
PWR_VGA_CORE_VID5: length 3.5
  TOP w0.102: PR25.2 115.82,74.32 v1(117,74.32) 117.07,74.32 117.09,74.35 U9.36
PWR_VGA_CORE_VID6: length 3.8
  TOP w0.102: PR23.2 115.65,72.64 v1(116.19,73.18) 116.29,73.28 116.81,73.28 117.49,73.95 U9.37
PWR_VGA_CORE_VIN: length 9.6
  TOP w0.203: U9.17 124.74,75.15 126.04,76.45 v3(126.04,77.34)
  BOTTOM w0.508: PC60.1 124.32,77.29 125.69,77.29 125.74,77.34 v3(126.04,77.34) 125.76,77.62 125.76,78.08 124.82,79.02 v2(124.82,79.15) 124.99,79.31 PR101.2
PWR_VGA_CORE_VSEN: length 8.9
  TOP w0.203: U9.12 124.62,73.15 124.92,72.85 v3(125.15,72.85)
  TOP w0.254: v1(130.11,71.69) PC11.2 PR21.2 127.8,72.71 PR28.2 127.8,72.83 PC13.1 126.65,72.58 125.42,72.58 v3(125.15,72.85)
  BOTTOM w0.254: v3(125.15,72.85) 125.1,72.9 PC56.1
PWR_VGA_CORE_VSUM-: length 63.7
  TOP w0.254: PR51.2 121.91,115.72 124.68,115.72 125.46,114.94 125.46,107.02 v3(124.92,106.49)
  L4 w0.254: v3(130.21,73.28) 130.21,77.6 129.57,78.23 129.57,78.87 130.37,79.67 130.37,96.27 129.24,97.4 129.24,103.84 126.4,106.68 125.12,106.68 v3(124.92,106.49)
  BOTTOM w0.254: PC15.2 130.46,74.04 130.21,73.79 v3(130.21,73.28) 130.21,72.68 129.77,72.24 129.51,72.24 129.16,71.88 v2(127.02,71.88) PC20.2 ; PC15.2 130.4,74.93 PC16.2 129.19,74.68 128.81,74.3 PR16.1 127.99,74.55 PR41.2 ; PC15.2 131.22,74.87 PR47.1
PWR_VGA_CORE_VW: length 7.7
  TOP w0.203: U9.6 121.26,69.67 120.52,68.92
  TOP w0.254: 120.52,68.92 v1(119.16,67.56) 118.59,66.99 PC7.1 118.52,66.36 PR13.1
PWR_VTT_EN: length 8.4
  TOP w0.203: PU5001.7 141.62,76.19 v3(141.27,75.84)
  TOP w0.254: v3(141.27,75.84) 141.27,74.36 141.49,74.14 141.49,74 R1810.1 141.57,73.03 R1809.2
  BOTTOM w0.254: v2(144.54,77.57) 144.48,77.57 143.88,76.96 C1797.1 142.23,76.96 141.27,76 v3(141.27,75.84)
PWRBTN_N: length 183.1
  TOP w0.102: R385.1 137.83,55.5 137.47,55.14 v3(137.47,55.13)
  L3 w0.127: v3(134.78,30.99) 134.78,32.33 133.85,33.26 130.74,33.26 130.5,33.5 128.81,33.5 127.92,32.61 119.32,32.61 117.58,34.35 113.47,34.35 112.65,33.53 110.62,33.53 v3(109.38,34.77) 93.82,34.77 90.19,38.41 89.32,39.27 89,39.27 83.87,44.4 72.52,44.4 67.89,39.77 67.89,37.61 66.21,35.93 48.61,35.93 46.37,33.69 41.78,33.69 40.03,31.94 30.38,31.94 27.72,29.29 v3(26.7,29.29)
  L4 w0.127: v3(103.16,51.69) 103.16,50.32 105.74,47.74 105.74,44.61 106.55,43.79 106.55,38.32 109.38,35.48 v3(109.38,34.77) ; v3(137.47,55.13) 137.94,54.66 137.94,53.02 137.28,52.36 137.28,49.12 136.47,48.31 136.47,46.41 137.28,45.59 137.28,43.03 138.08,42.23 138.08,40.67 137.71,40.3 137.71,35.36 136.56,34.21 136.56,33.82 136.78,33.59 136.78,31.86 136.06,31.14 134.93,31.14 v3(134.78,30.99)
  BOTTOM w0.102: v3(103.16,51.69) 103.08,51.77 103.08,53.64 104.25,54.81 104.25,55.84 104.87,56.45 U4101.47 ; R1756.2 27.72,27.11 C1760.1 26.64,29.22 v3(26.7,29.29) ; v2(137.62,54.31) 137.47,54.46 v3(137.47,55.13)
PWRCN_DET_N: length 341.4
  TOP w0.102: v1(154.59,38.73) 155.04,38.73 v3(155.4,38.37) ; v3(30.13,18.54) 30.84,17.83 30.98,17.83 31.84,16.98 32.16,16.98 v1(32.18,16.96) 32.56,17.34 32.56,20.24 C6722.2 32.8,20.61 31.93,21.47 31.84,21.47 31.05,22.27 30.92,22.27 30.44,22.75 PWRCN1.5 ; v4(80.63,145.03) 80.63,144.28 R1669.1 ; v3(155.31,46.48) 155.25,46.42 U109.124
  L3 w0.127: v3(159.6,102.21) 160.38,103 160.38,104.04 159.52,104.9 157.02,104.9 156.44,105.48 152.54,109.38 152.54,111.83 148.66,115.71 133.77,115.71 121.73,127.75 120.76,127.75 118.7,129.81 92.12,129.81 88.89,133.04 87.33,133.04 85.2,135.17 83.98,135.17 82.87,136.29 81.87,136.29 81.36,136.8 81.36,136.93 81.04,137.25 80.59,137.7 80.59,145 v4(80.63,145.03) ; v3(155.31,46.48) 155.31,46.54 155.61,46.84 157.74,46.84 158.78,47.88 158.78,49.71 v3(159.78,50.7) ; v3(30.13,18.54) 30.13,22.95 32.42,25.23 32.42,27.14 34.3,29.02 40.41,29.02 40.53,28.89 44.04,28.89 48.65,33.5 65.96,33.5 68.13,31.33 82.47,31.33 88.29,37.15 90.37,37.15 93.51,34.01 99.3,34.01 100.64,32.67 101.42,32.67 101.44,32.69 117.97,32.69 118.82,31.84 124.91,31.84 125.34,31.41 129.01,31.41 129.17,31.57 131.04,31.57 131.97,32.5 133.53,32.5 133.93,32.1 133.93,30.64 134.52,30.05 140.67,30.05 144.02,33.4 145.74,33.4 146.12,33.78 147.2,33.78 151.94,38.52 155.25,38.52 v3(155.4,38.37)
  L4 w0.127: v3(155.31,46.48) 155.3,46.47 155.3,44.11 155.14,43.89 155.14,43.18 155.7,42.62 155.7,38.66 v3(155.4,38.37) ; v3(159.78,50.7) 160.17,51.09 160.17,53.09 159.69,53.56 159.24,53.56 158.59,54.21 158.59,55.13 158.66,55.19 158.66,59.05 158.42,59.29 158.42,59.47 158.39,59.51 158.39,68.82 159.29,69.72 159.29,72.7 158.83,73.16 158.83,76.41 159.55,77.12 159.55,86.99 163.77,91.22 163.77,96.28 163.2,96.85 163.2,98.53 163.36,98.68 v3(163.36,99.21)
  BOTTOM w0.102: v3(163.36,99.21) 163.74,99.59 163.74,101.03 163.47,101.3 163.09,101.3 162.51,100.71 161.12,100.71 159.62,102.21 v3(159.6,102.21)
PWRGD_3V: length 157.2
  TOP w0.102: R1668.1 61.31,137.1 60.74,136.53 v3(60.74,136.42) ; R1857.2 R369.1 R368.1 C194.1 131.41,61.86 131.38,61.9 v3(131.38,61.94)
  L3 w0.127: v3(60.74,136.42) 61.77,135.39 69.69,135.39 79.78,125.3 81.41,125.3 88.14,118.56 108.08,118.56 108.26,118.75 118.18,118.75 131.64,105.29 144.61,105.29 145.92,103.98 145.92,77.65 140.04,71.77 140.04,70.66 139.69,70.32 135.68,70.32 v3(135.42,70.59)
  L4 w0.127: v3(131.38,61.94) 131.38,67.06 134.73,70.41 135.24,70.41 v3(135.42,70.59)
  BOTTOM w0.102: v3(131.38,61.94) 131.38,62.56 131.71,62.89 v2(131.71,62.99)
PWRGD_3V_B_1: length 5.2
  TOP w0.102: Q37.5 134.4,55.82 R380.2 135.25,54.97 135.82,54.97 135.95,55.09 v1(136,55.09) 136,55.3 135.05,56.25 Q37.6
PWRGD_3V_D: length 8.2
  TOP w0.102: Q1246.D 60.93,134.33 62.16,133.1 64.17,133.1 64.99,133.92 Q78.S 66.37,133.92 v1(66.91,133.38)
PWRGD_3V_G: length 3.4
  TOP w0.102: v1(57.72,136.14) 58.68,136.14 Q1246.G 60.33,137.79 R1668.2
PWRGD_3V_LL: length 4.5
  TOP w0.102: 132.86,59.33 132.3,58.77 R369.2 ; 132.86,59.33 132.89,59.36 133.21,59.36 133.75,58.82 Q37.3 ; 132.86,59.33 132.86,61.11 133.12,61.37 v1(133.23,61.37)
PWRGD_PS_L: length 5.1
  BOTTOM w0.102: R657.2 153.26,51.05 R656.1 153.57,50.03 154.21,49.39 v2(154.21,49.12) 154.11,49.02 C525.2 153.91,48.37 Q1226.2
PWRGD_PS_L1: length 4.1
  BOTTOM w0.102: Q1226.6 153.26,45.27 152.69,44.7 R1831.2 153.54,44.39 v2(153.65,44.5) 153.91,44.75 Q1226.5
PWRGD_PS_L2: length 3.2
  BOTTOM w0.102: Q1226.3 154.56,48.05 155.07,48.56 155.53,48.56 v2(156.07,49.1) 156.07,49.07 156.12,49.02 R1842.1
PWRGOOD_GPU: length 4.2
  TOP w0.102: GPU1.N10 80.23,95.03 v4(80.6,95.03)
  BOTTOM w0.102: R1158.2 81.43,93.11 81.32,93.22 81.32,93.57 80.7,94.19 80.27,94.19 v2(80.07,94.39) 80.07,94.77 80.32,95.03 v4(80.6,95.03)
PWROK3_1: length 4.5
  TOP w0.102: R309.2 160.63,59.69 v1(160.61,59.66) 159.7,58.76 159.7,58.16 159.12,57.58 U109.29
PWROK3_1_R: length 36.9
  TOP w0.102: R309.1 v3(163.33,59.69) ; R366.2 R1857.1 133.08,58.31 v4(133.08,58.85)
  L3 w0.127: v4(133.08,58.85) 133.68,58.25 135.99,58.25 136.6,58.86 136.62,58.86 137.26,58.86 137.71,59.31 143.04,59.31 143.71,59.98 143.77,59.98 144.11,60.33 147.3,60.33 148.13,59.5 148.39,59.5 148.66,59.22 148.66,59.01 149.12,58.55 150.73,58.55 151.75,59.56 163.2,59.56 v3(163.33,59.69)
  BOTTOM w0.102: v2(133.08,58.06) v4(133.08,58.85)
PWROK3_2: length 4.3
  TOP w0.102: R373.1 139.4,53.47 140.42,54.48 v1(140.52,54.48) 140.52,54.58 140.71,54.78 U109.75
PWROK3_2_R: length 14.4
  TOP w0.102: v3(134.73,62.03) 135.35,61.4 R381.1 R384.1 ; R373.2 v3(137.47,53.47)
  L4 w0.127: v3(134.73,62.03) 134.73,62 134.65,61.93 134.65,54.86 135.58,53.94 137,53.94 v3(137.47,53.47)
  BOTTOM w0.102: v3(137.47,53.47) v2(137.47,52.53)
PX_EN: length 2.1
  TOP w0.305: GPU1.AB16 87.4,99.45 88.06,98.79 v4(88.06,98.76)
  BOTTOM w0.508: v4(88.06,98.76) 88.07,98.76 88.07,98.53 TP159.1
QSAN_0: length 37.5
  TOP w0.127: GPU1.H27 76.2,108.65 76.04,108.81 v4(75.8,108.81)
  L3 w0.152: v4(75.8,108.81) 76.1,109.11 76.1,109.76 76.4,110.05 76.4,110.23 76.13,110.49 75.95,110.49 75.72,110.27 74.96,110.27 74.57,110.65 74.57,113.6 73.92,114.25 72.68,114.25 72.14,114.79 72.14,115.32 72.42,115.6 72.42,115.84 71.3,116.96 68.84,116.96 68.33,116.45 68.33,115.58 67.9,115.14 67.13,115.14 66.8,115.47 66.8,115.6 66.64,115.75 66.34,115.75 66.19,115.6 66.19,115.47 65.86,115.14 65.3,115.14 64.97,115.47 64.97,115.6 64.82,115.75 64.51,115.75 64.36,115.6 64.36,115.47 64.03,115.14 63.54,115.14 63.04,114.63 62.43,114.63 62.12,114.94 62.12,116.82 62,116.95 61.52,116.95 61.4,116.82 61.4,114.26 61.29,114.15 61.29,114.12 60.88,113.71 59.95,113.71 59.86,113.8 59.85,113.8 59.74,113.91 57.35,113.91 57.19,113.75 57.19,113.55 57.46,113.28 v4(57.62,113.28)
  BOTTOM w0.127: MEM3.G3 57.21,113.14 57.35,113.28 v4(57.62,113.28) ; v2(76.04,109.56) 75.8,109.32 v4(75.8,108.81)
QSAN_1: length 35.1
  TOP w0.102: 70.75,108.79 70.75,108.68 71.04,108.4 GPU1.A27
  TOP w0.127: 70.75,108.79 70.75,108.96 70.13,109.58 69.93,109.58 v4(69.58,109.94)
  BOTTOM w0.127: v4(69.58,109.94) 69.35,109.71 68.99,109.71 68.33,109.05 67.7,109.05 67.57,109.17 67.57,109.61 67.3,109.88 66.83,109.88 66.56,109.61 66.56,109.17 66.43,109.05 66.18,109.05 66.05,109.17 66.05,109.58 65.77,109.86 65.31,109.86 65.03,109.58 65.03,109.17 64.91,109.05 64.45,109.05 64.22,109.28 64.22,112.75 63.71,113.26 63.71,114.39 ; 63.71,114.39 v2(63.99,114.39) ; 63.71,114.39 63.71,116.15 60.42,119.43 57.78,119.43 57.53,119.18 57.53,118.82 57.33,118.62 57.05,118.62 56.85,118.82 56.85,119.19 56.59,119.46 55.44,119.46 55.17,119.18 55.17,118.53 55.49,118.21 55.78,118.21 55.91,118.09 55.91,117.82 55.76,117.67 55.09,117.67 54.54,117.13 54.54,116.65 54.33,116.44 54.12,116.44 54.01,116.55 MEM3.B7
QSAN_2: length 36
  TOP w0.102: GPU1.C23 73,105.05 72.9,104.96 72.44,104.96 72.35,104.88 72.34,104.87 72.06,104.87 71.92,105.01 71.03,105.01 70.83,105.21 68.81,105.21 68.79,105.23
  TOP w0.127: MEM1.B7 57.2,116.9 56.92,116.9 56.25,117.56 56.25,117.91 56.5,118.15 56.61,118.15 58.08,119.62 61.45,119.62 61.77,119.3 61.77,119.12 61.49,118.84 61.49,118.45 61.82,118.12 62.21,118.12 62.49,118.4 62.67,118.4 62.85,118.22 62.85,118.04 62.57,117.76 62.57,117.37 62.9,117.04 63.29,117.04 63.57,117.32 63.75,117.32 64.07,116.99 64.07,116.81 63.81,116.55 63.81,116.16 64.14,115.83 64.53,115.83 64.79,116.1 64.97,116.1 66.07,115 66.07,114.25 65.94,114.12 65.38,114.12 65.11,113.84 65.11,113.38 65.38,113.1 65.89,113.1 66.02,112.98 66.02,112.72 65.89,112.6 65.38,112.6 65.11,112.32 65.11,109.15 ; 65.11,109.15 65.11,108.28 68.16,105.23 68.79,105.23 ; 65.11,109.15 v1(64.72,109.15)
QSAN_3: length 35
  TOP w0.102: v4(69.12,102.9) 69.78,102.24 71.09,102.24 71.97,102.24 72.06,102.33 72.32,102.33 arc(72.39,102.28) 72.47,102.27 72.72,102.27 72.99,102 GPU1.C19
  TOP w0.127: v4(55.4,114.1) 55.17,114.1 54.67,113.6 54.48,113.6 54.21,113.34 54.21,113.08 MEM1.G3
  L4 w0.152: v4(69.12,102.9) 68.94,103.08 68.94,106.27 67.14,108.08 67.14,108.87 65.1,110.9 65.1,111.53 65.31,111.73 65.31,112.22 64.93,112.6 64.45,112.6 63.88,112.03 63.65,112.03 63.45,112.23 63.45,112.46 64.09,113.1 64.09,113.57 63.69,113.96 63.23,113.96 62.46,113.2 62.23,113.2 62.03,113.39 62.03,113.63 62.8,114.4 62.8,114.86 62.4,115.26 61.93,115.26 61.65,114.98 61.44,114.98 61.02,115.4 59.84,115.4 59.4,115.83 57.58,115.83 56.98,115.23 56.33,115.23 56.29,115.19 56,115.19 55.75,114.94 55.74,114.94 55.64,114.84 55.5,114.84 55.28,114.61 55.28,114.23 v4(55.4,114.1)
QSAN_4: length 35.3
  TOP w0.102: GPU1.C15 72.75,98.68 72.52,98.57 72.32,98.47 71.09,98.47 70.83,98.21 70.17,98.21 70.09,98.14 70.09,97.84 v4(70.09,97.84)
  L4 w0.152: v4(70.09,97.84) 70.04,97.79 66.75,97.79 65.76,96.79 65.76,90.14 65.41,89.8 65.2,89.8 64.92,90.08 64.43,90.08 64.05,89.71 64.05,89.22 64.34,88.94 64.34,88.72 64.12,88.51 63.9,88.51 63.67,88.74 63.18,88.74 62.8,88.37 62.8,87.88 63.04,87.64 63.04,87.43 62.17,86.56 61.97,86.56 61.56,86.14 59.52,86.14 59.35,86.32 59.35,86.8 58.71,87.44 57.99,87.44 57.66,87.1 57.66,86.91 57.56,86.81 57.21,86.81 57.11,86.92 57.11,88.8 56.65,89.25 55.87,89.25 55.35,89.78 54.9,89.78 54.57,90.11 v4(54.49,90.11)
  BOTTOM w0.127: v2(69.91,97.08) 70.09,97.26 v4(70.09,97.84) ; v4(54.49,90.11) 54.12,90.11 54.01,90.22 MEM4.G3
QSAN_5: length 36.7
  TOP w0.102: GPU1.E9 73.08,94.33 72.89,94.33 72.87,94.32 72.82,94.3 72.67,94.27 72.52,94.27 72.31,94.33 71.76,94.33 70.87,94.33 70.61,94.07 70.25,94.07 69.45,93.27 69.4,93.27
  TOP w0.127: v1(65.31,92.1) 65.31,92.46 ; 65.31,92.46 64.55,92.46 64.42,92.33 64.42,88.83 64.16,88.56 63.68,88.56 63.53,88.42 63.53,88.02 63.62,87.93 64.18,87.93 64.42,87.7 64.42,87.02 64.21,86.81 63.48,86.81 63.37,86.7 63.37,86.28 63.47,86.18 64.06,86.18 64.34,85.9 64.34,84.01 64.07,83.74 63.26,83.74 63.01,83.99 63.01,84.7 62.84,84.87 62.54,84.87 62.37,84.7 62.37,83.78 62.09,83.5 61.76,83.5 61.53,83.74 61.14,83.74 60.9,83.5 55.29,83.5 55.07,83.72 55.07,84.2 54.65,84.62 54.65,85.78 54.17,86.27 MEM2.B7 ; 65.31,92.46 66.87,92.46 67.69,93.27 69.4,93.27
QSAN_6: length 29.7
  TOP w0.102: GPU1.C5 72.73,91.07 72.5,91.07 72.27,91.16 72.05,91.16 70.92,90.02 70.76,90.02 70.53,89.79 70.08,89.79 v4(69.68,90.2)
  TOP w0.127: MEM2.G3 56.79,89.99 56.7,89.99 v4(56.7,89.99)
  L3 w0.152: v4(56.7,89.99) 56.82,89.86 56.82,89.24 57.19,88.87 59.42,88.87 59.72,89.17 59.72,89.89 59.85,90.01 60.56,90.01 60.69,89.89 60.69,87.88 60.99,87.57 61.6,87.57 61.9,87.88 61.9,88.82 62.03,88.95 62.39,88.95 62.51,88.82 62.51,88.06 62.82,87.75 63.35,87.75 63.66,88.06 63.66,88.82 63.78,88.95 64.04,88.95 64.16,88.82 64.16,88.06 64.47,87.75 64.95,87.75 65.26,88.06 65.26,88.82 65.38,88.95 65.64,88.95 65.76,88.82 65.76,88.06 66.07,87.75 66.56,87.75 66.87,88.06 66.87,89.48 67.87,90.48 69.4,90.48 v4(69.68,90.2)
QSAN_7: length 32.4
  TOP w0.102: GPU1.H4 76.05,90.4 75.94,90.29 75.94,89.87 75.89,89.75 75.87,89.72 75.84,89.68 75.84,89.59 75.93,89.39 75.93,88.96 75.85,88.87 75.79,88.81 75.79,88.81 75.62,88.65 75.62,88.44 75.52,88.34 75.52,88.23 75.66,88.09 v4(75.9,88.09)
  BOTTOM w0.127: v4(75.9,88.09) 75.72,88.27 75.39,88.27 74.89,87.77 74.28,87.77 73.32,86.81 71.44,86.81 ; 71.44,86.81 66.34,86.81 65.92,86.39 65.92,85.09 65.79,84.97 65.27,84.97 65.15,85.09 65.15,85.94 64.87,86.21 64.3,86.21 64.03,85.94 64.03,84.99 63.9,84.87 63.52,84.87 63.39,84.99 63.39,85.98 63.12,86.25 62.55,86.25 62.28,85.98 62.28,84.97 61.74,84.43 60.46,84.43 60.01,84.89 57.17,84.89 56.33,85.73 56.33,86.54 56.66,86.87 57.07,86.87 57.21,86.73 MEM4.B7 ; 71.44,86.81 v2(71.44,87.08)
QSAP_0: length 37.8
  TOP w0.127: GPU1.H28 76.2,109.19 v4(76.6,108.79)
  L3 w0.152: v4(76.6,108.79) 76.41,108.98 76.41,109.63 76.7,109.92 76.7,110.36 76.26,110.8 75.82,110.8 75.6,110.57 75.09,110.57 74.88,110.78 74.88,113.73 74.05,114.56 72.8,114.56 72.45,114.91 72.45,115.19 72.73,115.47 72.73,115.97 71.43,117.27 68.71,117.27 68.03,116.58 68.03,115.7 67.77,115.45 67.25,115.45 67.1,115.6 67.1,115.73 66.77,116.06 66.21,116.06 65.88,115.73 65.88,115.6 65.73,115.45 65.43,115.45 65.27,115.6 65.27,115.73 64.94,116.06 64.38,116.06 64.05,115.73 64.05,115.6 63.9,115.45 63.42,115.45 62.91,114.94 62.55,114.94 62.43,115.07 62.43,116.95 62.12,117.25 61.4,117.25 61.09,116.95 61.09,114.39 60.98,114.28 60.98,114.25 60.75,114.02 60.07,114.02 59.98,114.1 59.98,114.1 59.86,114.22 57.23,114.22 56.89,113.89 v4(56.67,113.89)
  BOTTOM w0.127: MEM3.F3 57.06,113.83 v4(56.67,113.89) ; v4(76.6,108.79) 76.6,108.88 77.3,109.58 v2(77.31,109.58)
QSAP_1: length 35.5
  TOP w0.102: GPU1.C27 72.67,108.4 72.43,108.16 72.34,108.1 72.27,108.07 72.21,108.07 72.12,108.07 72.07,108.09 72.01,108.11 71.93,108.2 70.95,108.2 70.5,108.65
  TOP w0.127: 70.5,108.65 70.5,108.86 70.03,109.33 v4(69.55,109.33)
  BOTTOM w0.127: v4(69.55,109.33) 69.43,109.45 69.09,109.45 68.43,108.79 67.59,108.79 67.32,109.07 67.32,109.5 67.19,109.63 66.94,109.63 66.81,109.5 66.81,109.07 66.54,108.79 66.07,108.79 65.8,109.07 65.8,109.48 65.67,109.61 65.41,109.61 65.29,109.48 65.29,109.07 65.01,108.79 64.34,108.79 63.96,109.17 63.96,110.51 ; v2(63.61,110.51) 63.96,110.51 ; 63.96,110.51 63.96,112.64 63.45,113.15 63.45,116.04 60.32,119.18 57.89,119.18 57.79,119.08 57.79,118.71 57.44,118.36 56.94,118.36 56.59,118.71 56.59,119.09 56.48,119.2 55.55,119.2 55.43,119.08 55.43,118.64 55.6,118.47 55.89,118.47 56.16,118.19 56.16,117.72 55.87,117.42 55.2,117.42 54.8,117.02 54.8,116.55 54.44,116.19 54.12,116.19 MEM3.C7
QSAP_2: length 36.1
  TOP w0.102: 68.79,105.49 68.8,105.49 68.84,105.45 68.88,105.45 68.91,105.41 70.92,105.41 71.12,105.21 72.01,105.21 72.02,105.2 GPU1.A23
  TOP w0.127: v1(66.59,107.66) 66.34,107.41 ; 66.34,107.41 68.26,105.49 68.79,105.49 ; 66.34,107.41 65.36,108.39 65.36,112.21 65.49,112.34 66,112.34 66.27,112.62 66.27,113.08 66,113.36 65.49,113.36 65.36,113.48 65.36,113.74 65.49,113.87 66.05,113.87 66.32,114.14 66.32,115.1 65.08,116.35 64.69,116.35 64.42,116.09 64.24,116.09 64.06,116.27 64.06,116.45 64.33,116.71 64.33,117.1 63.85,117.57 63.46,117.57 63.19,117.3 63.01,117.3 62.83,117.48 62.83,117.66 63.1,117.93 63.1,118.32 62.77,118.65 62.38,118.65 62.11,118.37 61.93,118.37 61.75,118.56 61.75,118.74 62.02,119.01 62.02,119.4 61.55,119.87 57.97,119.87 56.5,118.41 56.39,118.41 56,118.01 56,117.45 57.21,116.24 MEM1.C7
QSAP_3: length 35.3
  TOP w0.102: 69.34,103.27 69.54,103.07 69.54,102.77 69.86,102.44 71.01,102.44 71.01,102.44 71.89,102.44 71.98,102.53 72.4,102.53 72.43,102.5 72.51,102.47 73,102.47 73.47,102 GPU1.E19
  TOP w0.127: 69.34,103.27 69.29,103.32 68.92,103.32 68.67,103.07 68.67,103.07 v4(68.51,102.9) ; v4(55.98,114.57) 55.93,114.52 55.23,114.52 54.57,113.86 54.37,113.86 54.19,113.68 MEM1.F3
  L4 w0.152: v4(55.98,114.57) 56.29,114.88 56.43,114.88 56.47,114.93 57.1,114.93 57.7,115.52 59.28,115.52 59.71,115.09 60.89,115.09 61.31,114.67 61.78,114.67 62.06,114.95 62.27,114.95 62.49,114.74 62.49,114.52 61.72,113.75 61.72,113.27 62.1,112.89 62.59,112.89 63.35,113.66 63.57,113.66 63.78,113.44 63.78,113.23 63.14,112.59 63.14,112.1 63.52,111.72 64.01,111.72 64.57,112.29 64.81,112.29 65,112.09 65,111.86 64.8,111.65 64.8,110.78 66.83,108.74 66.83,107.95 68.64,106.15 68.64,103.03 v4(68.51,102.9)
QSAP_4: length 36.2
  TOP w0.102: v4(70.71,97.81) 71.17,98.27 72.36,98.27 72.58,98.37 72.87,98.41 73.16,98.49 GPU1.E15
  L4 w0.152: v4(54.6,89.47) 55.22,89.47 55.75,88.95 56.53,88.95 56.8,88.67 56.8,86.79 57.09,86.51 57.69,86.51 57.96,86.78 57.96,86.97 58.12,87.13 58.59,87.13 59.04,86.67 59.04,86.19 59.39,85.84 61.68,85.84 62.09,86.25 62.3,86.25 63.35,87.3 63.35,87.77 63.11,88.01 63.11,88.24 63.31,88.44 63.54,88.44 63.78,88.2 64.25,88.2 64.64,88.59 64.64,89.06 64.36,89.35 64.36,89.58 64.56,89.78 64.79,89.78 65.07,89.49 65.54,89.49 66.06,90.01 66.06,96.66 66.88,97.48 69.6,97.48 69.68,97.4 70.31,97.4 v4(70.71,97.81)
  BOTTOM w0.127: v2(71.71,98.55) 71.46,98.55 v4(70.71,97.81) ; v4(54.6,89.47) 54.45,89.62 MEM4.F3
QSAP_5: length 36.9
  TOP w0.102: 69.4,93.53 69.42,93.53 70.16,94.27 70.53,94.27 70.79,94.53 71.68,94.53 72.34,94.53 72.55,94.47 72.64,94.47 72.77,94.5 73.07,94.8 GPU1.D10
  TOP w0.127: 64.17,89.44 64.17,88.93 64.06,88.82 63.57,88.82 63.28,88.53 63.28,87.91 63.52,87.68 64.08,87.68 64.16,87.59 64.16,87.12 64.1,87.07 63.38,87.07 63.11,86.8 63.11,86.17 63.36,85.92 63.96,85.92 64.09,85.79 64.09,84.12 63.96,83.99 63.37,83.99 63.26,84.1 63.26,84.81 62.95,85.12 62.43,85.12 62.12,84.81 62.12,83.89 61.99,83.76 61.87,83.76 61.63,83.99 61.03,83.99 60.8,83.76 55.39,83.76 55.33,83.82 55.33,84.3 54.9,84.73 54.9,85.89 54.41,86.38 54.41,86.82 MEM2.C7 ; 64.17,89.44 64.17,92.44 64.44,92.71 66.77,92.71 67.58,93.53 69.4,93.53 ; 64.17,89.44 v1(63.76,89.44)
QSAP_6: length 29.7
  TOP w0.102: v4(70.29,90.2) 70.31,90.23 70.83,90.23 71.97,91.36 72.31,91.36 72.54,91.27 73.25,91.27 73.4,91.42 GPU1.D6
  TOP w0.127: v4(57.61,90.02) 57.21,89.62 MEM2.F3
  L3 w0.152: v4(70.29,90.2) 70.11,90.38 70.11,90.38 69.7,90.78 67.74,90.78 66.56,89.6 66.56,88.18 66.43,88.06 66.2,88.06 66.07,88.18 66.07,88.94 65.76,89.25 65.26,89.25 64.95,88.94 64.95,88.18 64.82,88.06 64.6,88.06 64.47,88.18 64.47,88.94 64.16,89.25 63.66,89.25 63.35,88.94 63.35,88.18 63.22,88.06 62.94,88.06 62.82,88.18 62.82,88.94 62.51,89.25 61.9,89.25 61.6,88.94 61.6,88.01 61.47,87.88 61.12,87.88 60.99,88.01 60.99,90.01 60.69,90.32 59.72,90.32 59.42,90.01 59.42,89.3 59.29,89.17 57.32,89.17 57.13,89.36 57.13,89.77 57.38,90.02 v4(57.61,90.02)
QSAP_7: length 32.9
  TOP w0.102: GPU1.G5 75.73,90.47 75.73,89.91 75.71,89.85 75.68,89.81 75.63,89.75 75.63,89.54 75.73,89.34 75.73,89.04 75.65,88.96 75.42,88.73 75.42,88.52 75.32,88.42 75.32,88.15 75.45,88.02 v4(75.45,87.62)
  BOTTOM w0.127: v2(67.14,86.21) 67.14,86.56 ; 67.14,86.56 73.43,86.56 74.38,87.51 74.99,87.51 75.11,87.62 v4(75.45,87.62) ; 67.14,86.56 66.44,86.56 66.17,86.28 66.17,84.99 65.9,84.71 65.17,84.71 64.89,84.99 64.89,85.83 64.77,85.96 64.41,85.96 64.28,85.83 64.28,84.89 64.01,84.61 63.42,84.61 63.14,84.89 63.14,85.87 63.01,86 62.66,86 62.53,85.87 62.53,84.87 61.84,84.18 60.36,84.18 59.9,84.63 57.06,84.63 56.07,85.62 56.07,86.64 56.55,87.13 57.12,87.13 MEM4.C7
RASA0#: length 41.2
  TOP w0.127: v4(56.17,110.96) 56.48,110.65 56.48,110.5 56.35,110.37 55.76,110.37 55.47,110.65 55.36,110.65 55.04,110.97 54.77,110.97 54.46,111.28 MEM1.J3 ; v4(76.59,103.69) 76.42,103.86 76.06,103.86 75.71,104.2 GPU1.G22
  L3 w0.165: v4(56.17,110.96) 56.17,110.63 57.43,109.37 58.02,109.37 58.15,109.24 58.15,108.72 58.27,108.59 58.78,108.59 58.91,108.72 58.91,109.24 59.03,109.37 60.56,109.37 60.69,109.24 60.69,108.41 60.56,108.28 60.15,108.28 60.03,108.16 60.03,107.68 60.15,107.55 61.21,107.55 61.33,107.68 61.33,108.56 61.46,108.69 61.73,108.69 61.97,108.45 62.24,108.45 62.4,108.28 62.4,107.74 62.57,107.57 63.05,107.57 63.21,107.74 63.21,108.28 63.38,108.45 68.55,108.45 69.42,107.57 69.67,107.57 69.67,107.57 70.18,107.57 70.67,108.06 71.89,108.06 72.01,107.93 72.01,107.65 72.14,107.52 72.7,107.52 72.83,107.65 72.83,107.93 72.95,108.06 73.35,108.06 73.48,107.93 73.48,107.19 73.74,106.93 74.1,106.93 74.1,106.93 75.33,106.93 76.92,105.34 76.92,104.02 v4(76.59,103.69)
  BOTTOM w0.127: MEM3.J3 57.19,111.25 57.19,110.94 57.06,110.81 56.81,110.81 56.68,110.94 56.68,111.28 56.51,111.46 56.51,111.83 56.38,111.96 56.17,111.96 55.96,111.75 55.96,111.17 v4(56.17,110.96)
RASA1#: length 42.4
  TOP w0.127: MEM2.J3 57.47,92.02 57.57,92.12 57.57,92.37 57.47,92.47 56.22,92.47 56.07,92.33 v4(56.07,92.06) ; GPU1.G17 75.88,101.07 v4(75.88,101.1)
  L3 w0.165: v4(56.07,92.06) 56.27,92.06 56.98,92.76 59.92,92.76 60.73,93.58 70.52,93.58 71.3,92.8 73.36,92.8 73.68,92.47 76.48,92.47 77.41,93.4 77.71,93.4 78.54,94.23 78.54,94.39 78.97,94.82 78.97,95.56 78.84,95.69 78.84,96.54 78.97,96.67 79.35,96.67 79.48,96.8 79.48,99.34 79.35,99.47 79.01,99.47 78.85,99.64 78.85,99.97 79.01,100.13 79.35,100.13 79.48,100.26 79.48,100.82 79.35,100.94 78.74,100.94 78.37,100.58 78.01,100.58 77.81,100.78 77.13,100.78 76.97,100.95 76.05,100.95 75.9,101.1 v4(75.88,101.1)
  BOTTOM w0.127: MEM4.J3 54.13,92.02 54.63,91.52 55.05,91.52 55.17,91.65 55.17,91.81 55.42,92.05 55.43,92.05 55.44,92.07 56.06,92.07 v4(56.07,92.06)
RDY#: length 5.6
  BOTTOM w0.102: U4101.23 96.72,53.88 96.05,53.21 94.27,53.21 93.51,53.98 TP4126.1
REMOTE1+: length 288.3
  TOP w0.127: U109.87 143.93,49.98 144.38,49.53 148.34,49.53 149.26,50.44 v3(149.26,50.67) ; RT3.1 v3(19.01,190.06)
  L3 w0.127: v3(149.26,50.67) 149.21,50.72 147.58,50.72 146.77,49.91 142.27,49.91 141.82,49.47 140.38,49.47 139.65,48.73 133.37,48.73 133.19,48.91 130.44,48.91 129.67,49.68 122.63,49.68 122.49,49.82 120.44,49.82 119.29,50.98 111.34,50.98 110.36,50 106.08,50 105.66,49.58 98.64,49.58 98.15,50.07 97.28,50.95 92.54,50.95 91.92,51.56 90.18,51.56 85.31,56.43 82.64,56.43 v3(81.92,57.15) ; v3(87.28,79.5) 87.03,79.25 86.7,79.25 85.94,80.01 79.82,80.01 78.46,81.37 73.03,81.37 72.48,80.82 57.54,80.82 54.58,77.86 49.1,77.86 v3(47.79,79.17)
  L4 w0.127: v3(47.79,79.17) 46.87,79.17 44.58,81.46 44.58,120.91 46.78,123.11 46.78,125.73 49.57,128.52 49.57,145.9 47.28,148.2 47.28,155.18 42.41,160.05 42.41,161.45 35.7,168.16 27.82,168.16 25.92,170.07 25.92,172.36 25.25,173.02 20.98,173.02 20.61,173.4 20.61,183.24 18.19,185.65 18.19,190.27 18.37,190.45 18.62,190.45 v3(19.01,190.06) ; v3(87.28,79.5) 87.16,79.38 87.16,79.35 86.67,78.87 86.67,76.51 81.77,71.6 81.77,66.37 82.27,65.87 82.27,57.49 v3(81.92,57.15)
  BOTTOM w0.127: v3(81.92,57.15) 81.92,57.15 81.92,57.89 v2(82.08,58.04) ; R404.1 148.08,49.45 C211.2 148.64,49.47 149.26,50.09 v3(149.26,50.67)
REMOTE1-: length 282.1
  TOP w0.127: RT3.2 v3(19.01,190.94)
  L3 w0.127: v3(47.25,78.54) 48.06,78.54 48.99,77.6 54.68,77.6 57.65,80.57 72.59,80.57 73.14,81.12 78.36,81.12 79.72,79.76 85.83,79.76 86.85,78.74 v3(87.28,78.74) ; v3(149.98,51.08) 149.66,51.08 149.6,51.14 148.94,51.14 148.77,50.98 147.48,50.98 146.67,50.16 142.16,50.16 141.72,49.72 140.28,49.72 139.54,48.98 133.47,48.98 133.29,49.16 130.55,49.16 129.78,49.93 122.74,49.93 122.59,50.08 120.55,50.08 119.39,51.23 111.23,51.23 110.25,50.25 105.97,50.25 105.55,49.83 98.75,49.83 97.38,51.2 92.64,51.2 92.03,51.82 90.29,51.82 85.42,56.69 83.2,56.69 v3(82.74,57.15)
  L4 w0.127: v3(87.28,78.74) 87.05,78.74 86.93,78.61 86.93,76.4 82.02,71.5 82.02,66.47 82.52,65.98 82.52,57.37 v3(82.74,57.15) ; v3(47.25,78.54) 47.15,78.54 44.68,81 44.33,81.36 44.33,121.02 46.53,123.21 46.53,125.84 49.32,128.62 49.32,145.8 47.02,148.09 47.02,155.08 42.16,159.94 42.16,161.34 35.59,167.91 27.71,167.91 25.66,169.96 25.66,172.25 25.14,172.77 20.87,172.77 20.35,173.29 20.35,183.13 17.94,185.55 17.94,190.37 18.27,190.7 18.76,190.7 v3(19.01,190.94)
  BOTTOM w0.127: v3(149.98,51.08) 149.98,50.03 149.74,49.78 ; R400.2 147.33,48.58 C211.1 148.53,48.58 149.74,49.78 ; 149.74,49.78 v2(149.97,49.56)
REXT: length 3.4
  TOP w0.102: R2082.1 130.71,40.23 131.42,39.51 v1(131.42,39.49) 131.74,39.17 U118.18
RING2: length 41.4
  TOP w0.203: U6.31 162.79,73.59 163.1,73.28 v3(163.1,72.64)
  TOP w0.508: C157.1 163.48,72.26 v3(163.1,72.64) ; R261.2 159.74,72.33 159.93,72.52 v3(159.93,72.57)
  L3 w0.508: UHS1.3 183.3,78.41 183.25,78.35 183.18,78.25 183.16,78.18 178.51,73.53 v3(177.72,73.53)
  BOTTOM w0.508: v3(177.72,73.53) 174.22,70.03 172.44,70.03 171.48,70.99 169.96,70.99 167.42,68.45 167.29,68.45 166.63,67.79 166.63,66.86 166.25,66.47 164.7,66.47 164.2,66.97 Q24.2 164.37,69.22 164.37,71.37 v3(163.1,72.64) 161.91,71.45 v2(161.32,71.45) 160.85,71.45 159.93,72.38 v3(159.93,72.57)
ROM_CS#: length 5.1
  TOP w0.102: R1167.2 108.3,77.3 v1(107.53,78.08) 107.67,78.22 R1168.2 107.51,79.27 106.33,79.27 105.6,80.01 U49.1
ROM_RST#: length 3
  TOP w0.102: v4(77.63,151) 77.93,151.3 CPU1.AW11
  BOTTOM w0.102: R1647.1 77.95,151.32 v4(77.63,151) 77.32,151 v2(76.51,150.2)
ROM_SI_D3: length 4.5
  TOP w0.102: R1171.1 97.63,85.18 97.92,85.47 v1(98.18,85.47) 98.2,85.5 99.02,85.5 100.24,84.28 U49.5
ROM_SLK_D4: length 9.2
  TOP w0.102: R1170.1 97.07,82.5 96.3,82.5 95.84,82.96 v1(95.05,82.96) 95.05,82.4 95.49,81.97 98.36,81.97 98.94,82.55 U49.6
ROM_SO_C4: length 3.7
  TOP w0.102: U49.2 105.85,81.28 106.48,81.92 v1(107.09,81.92) 107.2,81.81 107.2,80.56 R1169.2
RSMRST*_R: length 3.1
  TOP w0.102: R384.2 134.26,60.4 133.84,60.4 v1(133.51,60.07) 133.51,59.82 133.76,59.56 134.09,59.56 134.4,59.26 Q37.2
RSMRST_N: length 290.2
  TOP w0.102: v4(54.06,167.77) 54.01,167.77 52.96,168.81 Q1247.G ; R374.1 R382.2 137.26,52.87 v3(136.66,53.47)
  L3 w0.127: v3(21.88,174.12) 21.7,174.12 18.74,171.16 16.87,171.16 10.92,165.21 10.92,154.07 13.61,151.38 13.61,136.44 15.69,134.37 29.85,134.37 33.41,130.81 33.41,108.81 35.74,106.48 35.74,90.94 36.44,90.24 36.44,85.61 35.92,85.08 35.92,77.69 35.97,77.63 35.97,76.39 39.25,73.11 39.25,71.79 39.57,71.47 40.22,71.47 42.27,69.42 61.62,69.42 63.96,71.77 85.73,71.77 86.44,71.06 88.29,69.22 98.84,69.22 99.17,69.55 99.17,72.35 99.78,72.96 104.99,72.96 110.05,67.89 110.05,67.11 113.19,63.97 127.72,63.97 128.78,65.04 133.56,65.04 v3(133.65,65.13)
  L4 w0.127: v4(54.06,167.77) 54,167.77 53.98,167.75 50.79,167.75 48.5,170.04 48.5,173.1 45.52,176.07 27.89,176.07 25.94,174.12 v3(21.88,174.12)
  BOTTOM w0.102: v3(136.66,53.47) 136.2,53.01 135.63,53.01 v2(134.27,54.38) 133.65,54.99 v3(133.65,65.13)
RSMRST_N_1: length 4.7
  TOP w0.102: Q1247.D 52.29,166.75 R2066.1 52.29,164.81 Q1248.G 54.05,164.15 v1(54.24,164.34)
RSMRST_N_FCH: length 32.5
  TOP w0.102: R1677.2 52.93,157.99 53.92,157.99 55.1,159.17 55.1,160.44 v1(55.02,160.53) 54.44,161.1 54.44,161.85 54.66,162.07 54.66,162.96 v4(54.15,163.46) 52.93,162.24 Q1248.D ; v3(59.57,162.69) 60.66,161.59 61.89,161.59 62.26,161.23 62.26,160.21 C78.1 63.08,159.77 66.42,163.11 70.31,163.11 70.32,163.1 70.68,163.1 70.69,163.11 71.11,163.11 71.31,162.9 71.83,162.9 72.13,162.6 CPU1.AE4
  L3 w0.127: v3(59.57,162.69) 59.1,163.16 55.79,163.16 55.77,163.13 54.45,163.13 54.15,163.43 v4(54.15,163.46)
RSVD_AN30: length 7.5
  TOP w0.102: TP212.1 99.15,155.83 98.57,156.42 96.11,156.42 96.03,156.5 93.8,156.5 CPU1.AN30
RSVD_U30: length 7.7
  TOP w0.102: CPU1.U30 93.5,169.3 93.2,169.61 93.2,169.93 93.5,170.23 94.36,170.23 94.68,170.55 94.68,170.67 95.05,171.04 95.05,171.65 95.55,172.15 95.55,172.27 95.77,172.5 96.08,172.5 v3(96.27,172.69)
  BOTTOM w0.102: TP210.1 95.16,173.81 v3(96.27,172.69)
RSVD_U31: length 7.2
  TOP w0.102: v3(97.06,171.97) 96.78,171.7 96.78,169.92 96.38,169.52 96.34,169.52 96.33,169.52 95.68,169.52 95.65,169.49 94.8,169.49 94.3,169 CPU1.U31
  BOTTOM w0.102: TP211.1 97.44,173 97.44,172.59 97.06,172.21 v3(97.06,171.97)
RT: length 3.3
  TOP w0.102: v3(35.97,33.53) 35.72,33.27 R79628.1
  BOTTOM w0.102: U120.10 36.37,33.93 v3(35.97,33.53) 35.97,32.94 v2(36.17,32.74)
RTL_ISOLATE_N: length 24.6
  TOP w0.102: v3(28.43,4.62) 28.74,4.32 29.93,4.32 30.96,5.35 R1817.1 30.96,6.85 31.34,7.22 Q36.6 ; U16.20 35.18,15.06 35.17,15.07 35.09,15.07 35.02,15 34.64,15 34.57,15.07 33.64,15.07 v1(33.56,14.99) 33.46,14.89 v3(33.46,13.28)
  L4 w0.127: v3(28.43,4.62) 30.72,6.92 33.25,6.92 33.46,7.13 v3(33.46,13.28)
  BOTTOM w0.102: v3(28.43,4.62) 28.56,4.75 v2(28.56,6.58) 28.52,6.62 R377.2
RTL_ISOLATE_N_1: length 6.5
  TOP w0.102: Q36.5 32.16,7.87 32.41,8.12 32.41,9.08 v3(32.6,9.27)
  BOTTOM w0.102: v3(32.6,9.27) 32.8,9.07 R406.1 ; R406.1 R1816.2 31.42,8.8 31.42,8.8 30.95,9.27 v2(30.72,9.27) ; R406.1 33.79,8.45 C1798.1
RTL_ISOLATE_N_2: length 7.5
  TOP w0.102: Q36.2 32.93,7.87 32.8,7.75 ; Q36.3 32.94,8.52 32.67,8.26 32.67,7.87 32.8,7.75 ; v1(30.74,4.32) 32.37,4.32 32.86,4.81 R378.2 32.86,6.88 32.8,6.95 32.8,7.75
RTN1: length 3.9
  TOP w0.254: CONVT1.1 28.33,41.68 29.07,42.42 v1(29.62,42.42) 29.93,42.42 30.45,41.9 R51.1
RTN2: length 3.1
  TOP w0.254: R53.1 29.67,40.13 v3(29.65,40.15) CONVT1.2
  BOTTOM w0.254: v3(29.65,40.15) 29.65,40.95 v2(29.54,41.06)
RTN3: length 2.8
  TOP w0.254: R56.1 31.02,37.15 30,37.15 v1(29.98,37.13) 29.96,37.15 28.33,37.15 CONVT1.5
RTN4: length 3.2
  TOP w0.254: CONVT1.6 29.54,36.15 v1(30.01,35.69) 30.47,36.15 31,36.15 R59.1
RUN_0P95_EN1: length 10.4
  TOP w0.102: 54.52,141.5 54.26,141.5 53.98,141.22 52.41,141.22 52.23,141.4 52.23,141.99 52.48,142.24 52.89,142.24 53.77,143.12 53.77,143.12 v1(53.98,143.33) 54.41,143.76 R181.1 R179.2 ; 54.52,141.5 54.52,141.07 54.63,140.95 Q18.3 ; 54.52,141.5 54.62,141.6 Q18.2
RUN_0P95_EN2: length 8.2
  TOP w0.102: R171.2 57.56,142.59 Q18.6 56.56,142.26 56.42,142.11 56.42,140.78 R175.1 56.74,138.68 R172.1 56.54,138.35 v1(55.61,138.35)
RUN_0P95_EN3: length 7.7
  TOP w0.102: C1768.2 58.9,144.4 R1776.2 ; Q18.5 57.87,141.6 58.01,141.46 59.26,141.46 v1(59.3,141.5) 59.79,141.99 R1776.2 ; R1776.2 59.79,144.78 D20.3
RUN_0P95_EN4: length 5.5
  TOP w0.102: R175.2 R174.1 55.72,139.46 54.89,138.63 v1(54.11,138.63) 53.17,138.63 C94.1 C857.1
RUN_EN1: length 7
  TOP w0.102: Q65.2 37.75,140.08 38.01,140.34 38.26,140.34 38.4,140.19 Q65.3 39.67,139.4 R732.1 40.93,139.76 41.13,139.97 v1(41.13,140.18) 41.13,140.51 40.86,140.78 R733.2
RUN_EN2: length 18.6
  TOP w0.102: Q65.6 35.71,141.27 R1778.2 35.66,141.1 R722.1 35.1,139.88 35.1,139.87 35.59,139.38 35.59,138.66 36,138.26 38.28,138.26 38.72,137.82 v1(40.83,137.82) 41,137.82 41.31,137.52 41.31,134.59 40.32,133.6 40.32,131.68 40.8,131.2 R1178.1
RUN_EN_1P8V: length 5.7
  TOP w0.102: C862.1 42.58,129.94 U105.3 ; C862.1 41.5,128.52 R1179.2 40.8,129.22 R1178.2 ; C862.1 43.09,128.52 43.67,127.94 v1(43.67,127.86)
RUNPWR_R6: length 4.9
  TOP w0.102: v1(36.86,145.47) 36.86,145.03 37.82,144.08 R718.2 C865.2 37.75,142.75 Q65.5
S0A3_GPIO: length 38.7
  TOP w0.102: R1813.1 R1724.1 57.25,168.56 57.69,168.12 57.69,167.58 57.98,167.29 58.59,167.29 v3(59.06,167.77) ; R2021.2 54.16,158.88 v3(54.64,159.36) ; CPU1.AE8 75.42,162.32 75.42,162.04 v4(75.47,161.99)
  L3 w0.127: v3(59.06,167.77) 60.25,168.96 63.98,168.96 66.71,166.23 66.71,165.13 67.5,164.34 71.59,164.34 73.24,162.69 74.77,162.69 v4(75.47,161.99)
  BOTTOM w0.102: v3(59.06,167.77) 58.33,167.03 57.28,167.03 v2(55.77,165.52) 55.19,165.52 54.64,164.97 54.64,162.1 54.39,161.85 54.39,160.84 54.64,160.59 v3(54.64,159.36)
S0A3_GPIO_G: length 6.7
  TOP w0.102: v1(52.2,159.92) 51.91,159.63 R2021.1 51.56,158.88 50.01,157.33 48.8,157.33 47.7,158.43 Q1243.G
S_LVDS_BL_EN: length 5.4
  TOP w0.102: R139.1 R144.1 ; R144.1 42.01,25.65 v1(41.54,25.65) ; R144.1 R1985.1 43.66,26.29 R135.1 R143.2
S_TXE0+: length 5.8
  TOP w0.102: LVDS1.18 v3(43.63,92.5)
  BOTTOM w0.102: v2(42.81,93.7) 42.56,93.46 ; 42.56,93.46 41.79,94.23 41.53,94.23 41.46,94.3 U26.31 ; 42.56,93.46 42.93,93.09 42.93,92.35 43.09,92.2 43.33,92.2 v3(43.63,92.5)
S_TXE0-: length 6.5
  TOP w0.102: LVDS1.19 v3(43.63,91.5)
  BOTTOM w0.102: U26.32 41.46,93.9 41.53,93.97 41.69,93.97 42.68,92.98 42.68,92.25 42.98,91.95 43.18,91.95 v3(43.63,91.5) 43.93,91.5 v2(44.41,91.97)
S_TXE1+: length 4.6
  TOP w0.102: LVDS1.15 v3(43.63,95.5)
  BOTTOM w0.102: v3(43.63,95.5) 43.16,95.03 42.6,95.03 ; 42.6,95.03 41.53,95.03 41.46,95.1 U26.29 ; 42.6,95.03 v2(42.6,95.38)
S_TXE1-: length 5.3
  TOP w0.102: LVDS1.16 v3(43.63,94.5) 43.99,94.5 44.51,93.98 v1(44.53,93.98)
  BOTTOM w0.102: U26.30 41.46,94.7 41.53,94.77 43.36,94.77 v3(43.63,94.5)
S_TXE2+: length 8.6
  TOP w0.102: v1(44.48,96.19) 44.48,97.65 v3(43.63,98.5) LVDS1.12
  BOTTOM w0.102: v3(43.63,98.5) 43.33,98.19 42.75,98.19 42.38,97.82 42.38,96.57 41.64,95.83 41.53,95.83 41.46,95.9 U26.27
S_TXE2-: length 6.3
  TOP w0.102: LVDS1.13 v3(43.63,97.5)
  BOTTOM w0.102: 42.63,97.03 42.63,96.46 41.74,95.57 41.53,95.57 41.46,95.5 U26.28 ; 42.63,97.03 42.63,97.71 42.86,97.94 43.19,97.94 v3(43.63,97.5) ; 42.63,97.03 v2(42.93,97.03)
S_TXE3+: length 8.6
  TOP w0.102: LVDS1.8 v3(43.63,102.5)
  BOTTOM w0.102: 41.08,99.82 40.22,98.96 40.22,98.77 39.58,98.13 U26.23 ; 41.08,99.82 41.97,100.71 41.97,101.47 42.98,102.49 43.62,102.49 v3(43.63,102.5) ; 41.08,99.82 v2(40.83,100.08)
S_TXE3-: length 8.6
  TOP w0.102: LVDS1.9 v3(43.63,101.5)
  BOTTOM w0.102: v3(43.63,101.5) 43.63,101.85 43.25,102.23 43.09,102.23 42.53,101.67 ; 42.53,101.67 v2(42.76,101.45) ; 42.53,101.67 42.22,101.37 42.22,100.61 40.47,98.86 40.47,98.66 39.98,98.17 U26.24
S_TXEC+: length 7.3
  TOP w0.102: LVDS1.10 v3(43.63,100.5)
  BOTTOM w0.102: v3(43.63,100.5) 43.23,100.1 42.59,100.1 41.64,99.15 41.64,98.93 ; v2(41.33,98.93) 41.64,98.93 ; 41.64,98.93 41.64,96.87 41.4,96.63 41.31,96.63 41.24,96.7 U26.25
S_TXEC-: length 7.3
  TOP w0.102: LVDS1.11 v3(43.63,99.5)
  BOTTOM w0.102: 42.45,99.6 42.7,99.85 43.28,99.85 v3(43.63,99.5) ; 42.45,99.6 41.9,99.05 41.9,96.77 41.51,96.38 41.31,96.38 41.24,96.3 U26.26 ; 42.45,99.6 v2(42.68,99.36)
S_TXO0+: length 14.9
  TOP w0.102: LVDS1.29 43.29,81.5 43.63,81.84 v3(43.63,82.01)
  BOTTOM w0.102: v3(43.63,82.01) 43.31,82.01 43.19,81.88 43.19,81.58 43.06,81.45 42.93,81.45 41.11,83.27 ; U26.41 38.38,90.67 38.41,90.64 38.41,89.82 40.85,87.38 40.85,83.53 41.11,83.27 ; 41.11,83.27 v2(41.36,83.52)
S_TXO0-: length 15
  TOP w0.102: v3(43.63,81.2) 42.93,80.5 LVDS1.30
  BOTTOM w0.102: 42.91,81.2 v3(43.63,81.2) ; 42.91,81.2 42.83,81.2 40.6,83.43 40.6,87.27 38.16,89.71 38.16,90.45 37.98,90.64 U26.42 ; 42.91,81.2 v2(42.91,80.82)
S_TXO1+: length 13.4
  TOP w0.102: v3(43.63,83.64) 43.49,83.5 LVDS1.27
  BOTTOM w0.102: U26.39 39.18,90.88 39.1,90.81 39.1,90.17 41.59,87.69 41.59,84.4 42.91,83.08 43.06,83.08 43.19,83.2 43.19,83.51 43.31,83.64 v3(43.63,83.64) 43.78,83.64 44.34,83.07 v2(44.4,83.07)
S_TXO1-: length 12.8
  TOP w0.102: v3(43.63,82.82) 43.38,82.82 43.06,82.5 LVDS1.28
  BOTTOM w0.102: v2(42.48,82.65) 42.73,82.9 ; 42.73,82.9 41.33,84.29 41.33,87.58 38.85,90.06 38.85,90.74 38.78,90.82 U26.40 ; 42.73,82.9 42.8,82.82 v3(43.63,82.82)
S_TXO2+: length 10.8
  TOP w0.102: LVDS1.25 v3(43.63,85.5)
  BOTTOM w0.102: v2(42.65,86.56) 42.32,86.56 ; 42.32,86.56 42.32,85.12 42.69,84.75 43.05,84.75 43.63,85.33 v3(43.63,85.5) ; 42.32,86.56 42.32,87.99 39.9,90.41 39.9,90.74 39.98,90.82 U26.37
S_TXO2-: length 10.8
  TOP w0.102: LVDS1.26 v3(43.63,84.5)
  BOTTOM w0.102: U26.38 39.58,90.82 39.65,90.74 39.65,90.31 42.07,87.89 42.07,85.01 42.58,84.5 42.83,84.5 ; 42.83,84.5 v2(42.83,84.15) ; 42.83,84.5 v3(43.63,84.5)
S_TXO3+: length 7.3
  TOP w0.102: LVDS1.20 v3(43.63,90.5)
  BOTTOM w0.102: U26.33 41.23,93.5 41.31,93.43 41.54,93.43 42.2,92.77 42.2,91.29 ; v2(42.55,91.29) 42.2,91.29 ; 42.2,91.29 42.2,90.42 42.45,90.17 43.3,90.17 v3(43.63,90.5)
S_TXO3-: length 7.3
  TOP w0.102: LVDS1.21 v3(43.63,89.5)
  BOTTOM w0.102: v2(42.76,89.56) 42.76,89.92 ; 42.76,89.92 42.35,89.92 41.94,90.32 41.94,92.66 41.44,93.17 41.31,93.17 41.24,93.1 U26.34 ; 42.76,89.92 43.22,89.92 v3(43.63,89.5)
S_TXOC+: length 8.3
  TOP w0.102: LVDS1.22 v3(43.63,88.5)
  BOTTOM w0.102: v2(44.33,88.95) 43.88,88.5 v3(43.63,88.5) 43.43,88.3 43.06,88.3 41.46,89.9 41.46,92.48 41.24,92.7 U26.35
S_TXOC-: length 8.3
  TOP w0.102: LVDS1.23 v3(43.63,87.5)
  BOTTOM w0.102: v2(44.43,87.64) 44.36,87.64 44.21,87.5 v3(43.63,87.5) 43.63,87.59 43.18,88.04 42.96,88.04 41.21,89.79 41.21,92.12 41.03,92.3 U26.36
SA0_DIM1: length 5
  TOP w0.102: DIMM1.197 132.43,129.35 v3(132.75,129.03)
  BOTTOM w0.102: v2(130.8,130.55) 130.8,130.24 130.78,130.22 R163.1 131.8,129.29 R165.2 132.56,129.22 v3(132.75,129.03)
SA0_DIM2: length 4.9
  TOP w0.102: v3(144.81,129.03) 145.13,129.35 DIMM2.197
  BOTTOM w0.102: v2(142.68,128.7) 143.08,129.1 R2055.2 144.75,129.1 v3(144.81,129.03) 144.94,129.16 R2056.1
SA1_DIM1: length 5.5
  TOP w0.102: DIMM1.201 131.85,128.15 v3(132.75,127.25)
  BOTTOM w0.102: R1635.1 133.07,125.82 v2(132.57,125.32) 132.05,125.84 R1634.2 132.05,126.56 v3(132.75,127.25)
SA1_DIM2: length 5.2
  TOP w0.102: DIMM2.201 145.71,128.15 v3(144.81,127.25)
  BOTTOM w0.102: R2061.2 R2062.1 146.02,126.81 v2(145.76,127.07) 145.58,127.25 v3(144.81,127.25)
SATA__RXN0_C: length 5.9
  TOP w0.102: C149.2 15.46,142.88 13.64,142.88 12.74,143.78 12.26,143.78 HDD1.5
  BOTTOM w0.102: HDD1.5 v1(12.86,143.27)
SATA__RXN1_C: length 5.7
  TOP w0.102: ODD1.5 8.66,178.78 8.8,178.78 9.69,177.89 11.65,177.89 C118.2
  BOTTOM w0.102: ODD1.5 v1(9.2,178.27)
SATA__RXP0_C: length 6
  TOP w0.102: C151.2 15.46,143.13 13.75,143.13 12.85,144.03 12.26,144.03 HDD1.6
  BOTTOM w0.102: HDD1.6 v1(10.57,144.54)
SATA__RXP1_C: length 5.8
  TOP w0.102: ODD1.6 8.66,179.03 8.9,179.03 9.79,178.14 11.65,178.14 C119.2
  BOTTOM w0.102: ODD1.6 v1(7.02,179.54)
SATA__TXN0_C: length 5.8
  TOP w0.102: HDD1.3 12.26,140.22 12.36,140.22 14.4,140.89 15.01,141.09 C142.2
  BOTTOM w0.102: HDD1.3 12.48,140.73 12.8,141.05 v1(12.86,141.05)
SATA__TXN1_C: length 5.9
  TOP w0.102: C115.2 11.65,176.11 9.75,176.11 8.86,175.22 8.66,175.22 ODD1.3
  BOTTOM w0.102: ODD1.3 9.01,175.73 v1(9.3,176.02)
SATA__TXP0_C: length 5.9
  TOP w0.102: C141.2 15.18,140.84 15.07,140.84 12.42,139.98 12.4,139.97 12.26,139.97 HDD1.2
  BOTTOM w0.102: v1(12.8,138.84) 12.37,138.84 HDD1.2
SATA__TXP1_C: length 5.9
  TOP w0.102: C114.2 11.65,175.86 9.85,175.86 8.96,174.97 8.66,174.97 ODD1.2
  BOTTOM w0.102: v1(9.2,173.84) 8.77,173.84 ODD1.2
SATA_CALRN: length 8.2
  TOP w0.203: R586.2 66.63,147.32 v4(67.42,148.11) 67.62,148.31 67.62,148.97 68.18,149.53 69.16,149.53 70.15,150.52 70.15,150.75 70.8,151.4 CPU1.AW2
  BOTTOM w0.203: v4(67.42,148.11) v2(68.36,148.11)
SATA_CALRP: length 6.3
  TOP w0.203: CPU1.AW1 70.1,151.13 69.84,150.87 69.84,150.68 68.99,149.83 67.95,149.83 v1(66.58,148.46) R1644.2
SATA_LED_N_C_1: length 9
  TOP w0.127: v3(27.08,13.97) v1(27.08,14.99)
  L3 w0.127: v3(24.04,10.54) 24.04,10.92 v3(27.08,13.97)
  BOTTOM w0.127: v3(24.04,10.54) 24.23,10.73 R80201.2 25.04,10.75 Q9646.6 ; Q9646.3 27.03,14.02 v3(27.08,13.97)
SATAHDR_RX_DN0: length 55.4
  TOP w0.102: L4103.4 19.63,142.66 19.99,143.02 20.3,143.02 20.72,142.6 v3(20.72,142.49) ; v4(67.66,151.4) 67.66,151.68 68.41,152.43 70.43,152.43 70.5,152.36 CPU1.AV1
  L3 w0.102: v4(67.66,151.4) 67.4,151.13 arc(67.35,151.09) 67.29,151.05 arc(67.14,150.98) 66.98,150.96 arc(66.88,150.91) 66.79,150.84 66.71,150.76 arc(66.48,150.58) 66.21,150.46 arc(66.18,150.45) 66.15,150.44 arc(66.01,150.42) 65.86,150.41 arc(65.41,150.25) 65.03,149.96 64.75,149.69 arc(64.6,149.56) 64.44,149.46 arc(64.14,149.34) 63.81,149.3 56.7,149.3 arc(55.64,149.16) 54.67,148.74 arc(54.27,148.47) 53.92,148.15 52.87,147.1 arc(52.4,146.72) 51.88,146.44 arc(51.32,146.27) 50.73,146.22 47.41,146.22 47.19,146.19 46.17,146.09 46.17,146.09 27.17,144.17 27.17,144.17 26.97,144.15 26.32,143.99 26.15,143.95 26.08,143.93 26.03,143.92 22.9,143.15 21.36,143.15 arc(21.16,143.11) 20.99,143 20.89,142.91 arc(20.77,142.72) v3(20.72,142.49)
  BOTTOM w0.102: v2(21.62,142.62) 20.85,142.62 v3(20.72,142.49)
SATAHDR_RX_DN0_EMI: length 1.5
  TOP w0.102: C149.1 16.9,142.66 L4103.3
SATAHDR_RX_DN1: length 94.1
  TOP w0.102: C118.1 13.16,177.75 13.62,177.75 15.34,176.03 15.34,164.21 ; CPU1.AW4 72.86,151.4 72.96,151.31 72.96,151.15 v4(72.79,150.99) ; 15.34,164.21 15.34,163.14 14.98,162.78 14.87,162.78 14.55,163.11 v3(14.55,163.27) ; 15.34,164.21 v1(14.93,164.21)
  L3 w0.102: v4(72.79,150.99) 72.61,151.16 72.61,151.85 71.35,153.11 66.18,153.11 65.74,153.56 56.83,153.56 56.02,152.75 53.53,152.75 49.23,148.45 37.54,148.45 35.92,146.82 20.84,146.82 19.84,147.82 18.44,149.22 18.44,153.51 17.26,154.69 17.26,160.83 15.11,162.98 14.84,162.98 v3(14.55,163.27)
SATAHDR_RX_DP0: length 55.4
  TOP w0.102: L4103.1 19.52,143.27 20.5,143.27 v3(20.61,143.38) ; v4(67.03,151.4) 68.31,152.68 70.82,152.68 CPU1.AV2
  L3 w0.102: v4(67.03,151.4) 66.67,151.04 66.55,150.92 arc(66.36,150.77) 66.14,150.68 arc(66.12,150.67) 66.1,150.66 arc(65.97,150.64) 65.84,150.64 arc(65.79,150.63) 65.73,150.61 arc(65.27,150.43) 64.87,150.13 64.76,150.03 64.59,149.85 arc(64.23,149.61) 63.81,149.53 56.7,149.53 arc(55.58,149.38) 54.55,148.93 arc(54.13,148.65) 53.76,148.31 52.81,147.37 52.7,147.26 arc(52.28,146.91) 51.79,146.65 arc(51.27,146.5) 50.73,146.44 47.39,146.44 47.17,146.42 46.4,146.34 26.93,144.38 26.19,144.2 25.89,144.12 22.88,143.38 v3(20.61,143.38)
  BOTTOM w0.102: v3(20.61,143.38) v2(20.61,144.27)
SATAHDR_RX_DP0_EMI: length 1.5
  TOP w0.102: L4103.2 16.9,143.34 C151.1
SATAHDR_RX_DP1: length 94
  TOP w0.102: v3(14.55,162.46) 14.62,162.53 15.09,162.53 15.59,163.03 15.59,169.19 ; v1(15.93,169.19) 15.59,169.19 ; 15.59,169.19 15.59,176.14 13.2,178.52 C119.1 ; CPU1.AW3 v4(72.1,151)
  L3 w0.102: v3(14.55,162.46) 14.84,162.75 15.02,162.75 17.03,160.74 17.03,154.6 18.22,153.41 18.22,149.13 19.68,147.66 20.75,146.6 36.02,146.6 37.64,148.22 49.33,148.22 53.63,152.52 56.11,152.52 56.92,153.33 65.64,153.33 66.09,152.88 71.25,152.88 72.39,151.75 72.39,151.29 v4(72.1,151)
SATAHDR_TX_DN0: length 57.5
  TOP w0.102: v4(68.93,151.4) 69.17,151.54 69.5,151.73 69.7,151.85 69.96,151.91 70.31,151.91 70.32,151.89 70.68,151.89 70.69,151.91 71.11,151.91 71.12,151.89 71.48,151.89 71.6,152.02 71.6,152.27 71.4,152.87 71.4,153.13 71.57,153.3 71.79,153.3 CPU1.AU4 ; L4102.1 20,141.18 20.17,141.35 v3(20.96,141.35)
  L3 w0.102: v3(20.96,141.35) 22.11,141.35 23.8,142.01 24.35,142.23 24.81,142.27 52.45,144.86 52.97,144.9 63.16,148.48 64.18,148.48 65.16,149.03 68.44,150.91 v4(68.93,151.4)
  BOTTOM w0.102: v3(20.96,141.35) 20.07,141.35 v2(20,141.43)
SATAHDR_TX_DN0_EMI: length 1.6
  TOP w0.102: C142.1 17.03,141.18 L4102.2
SATAHDR_TX_DN1: length 93.3
  TOP w0.102: v3(15.4,161.65) 15.12,161.37 14.84,161.37 14.03,162.17 14.03,164.54 14.89,165.4 14.89,175.12 13.91,176.11 13.3,176.11 C115.1 ; CPU1.AY1 70.95,150.15 70.95,150.11 v4(70.96,150.1)
  L3 w0.102: v3(15.4,161.65) 15.1,161.34 14.67,161.34 14.41,161.08 14.41,159.67 15.35,158.74 15.35,154.51 17.61,152.24 17.61,148.88 20.5,145.99 36.27,145.99 37.89,147.61 49.58,147.61 53.88,151.92 56.36,151.92 57.17,152.72 65.39,152.72 65.84,152.28 69.55,152.28 70.96,150.88 v4(70.96,150.1)
  BOTTOM w0.102: v4(70.96,150.1) 70.85,150 69.93,150 v2(69.71,149.78)
SATAHDR_TX_DP0: length 57.4
  TOP w0.102: v3(20.99,140.56) 20.99,140.68 20.57,141.1 20.28,141.1 19.68,140.5 L4102.4 ; v4(69.33,150.9) 69.4,151.16 69.69,151.55 69.93,151.69 69.98,151.69 70.06,151.7 70.23,151.7 70.24,151.69 70.76,151.69 70.77,151.7 71.03,151.7 71.04,151.69 71.56,151.69 71.57,151.7 71.63,151.7 71.86,151.93 71.86,152.32 71.78,152.53 CPU1.AU3
  L3 w0.102: v4(69.33,150.9) 69.29,150.94 68.8,150.94 68.58,150.72 64.24,148.25 63.2,148.25 53.02,144.68 24.83,142.04 24.4,142 22.15,141.12 21.61,141.12 arc(21.41,141.08) 21.24,140.97 20.99,140.72 v3(20.99,140.56)
  BOTTOM w0.102: v3(20.99,140.56) 21.01,140.59 v2(21.83,140.59)
SATAHDR_TX_DP0_EMI: length 1.5
  TOP w0.102: C141.1 16.77,140.5 L4102.3
SATAHDR_TX_DP1: length 92.3
  TOP w0.102: 14.64,166.37 14.64,175.02 13.8,175.86 13.3,175.86 C114.1 ; 14.64,166.37 14.64,165.51 13.77,164.65 13.77,162.07 14.73,161.11 15.12,161.11 v3(15.4,160.83) ; 14.64,166.37 v1(14.28,166.37) ; CPU1.AY2 71.58,150.6 71.7,150.48 v4(71.7,150.2)
  L3 w0.102: v3(15.4,160.83) 15.12,161.11 14.77,161.11 14.64,160.99 14.64,159.77 15.57,158.83 15.57,154.6 17.84,152.34 17.84,148.97 20.59,146.22 36.17,146.22 37.79,147.84 49.48,147.84 53.79,152.15 56.27,152.15 57.08,152.95 65.49,152.95 65.93,152.51 69.65,152.51 71.18,150.97 71.18,150.57 71.23,150.52 71.53,150.52 71.7,150.35 v4(71.7,150.2)
SB3V: length 1204.9
  TOP w0.203: U54.9 89.53,9.8
  TOP w0.254: R6702.1 v3(76.93,63.18)
  TOP w0.305: v3(46.58,8.59) R775.1 46.45,9.53 C579.1
  TOP w0.356: CPU1.AR15 82.18,154.5 82.43,154.75 82.43,154.79 v4(82.46,154.81) 82.33,154.81 82.22,154.92 82.2,154.92 81.72,155.4 CPU1.AP15
  TOP w0.381: 45.87,169.48 44.91,169.48 42.26,166.83 34.5,166.83 34.41,166.92 23.78,166.92 20.38,170.31 v3(19.72,170.31) ; v3(16.92,221.13) 17.42,220.64 R526.2
  TOP w0.508: R1785.1 29.69,14.54 30.39,15.24 v3(30.77,15.24) 30.89,15.37 30.89,15.75 31.08,15.94 R1752.1 ; R184.2 152.62,107.12 147.35,101.85 v5(147.35,94.56) ; R1734.1 32.67,34.04 v3(32.85,33.86) ; R742.1 33.12,25.78 R1758.2 33.05,24.89 v3(33.31,24.64) ; v3(74.18,140.13) 74.02,139.98 73.56,139.98 73.12,139.54 R1875.1 ; R137.2 60.52,156.53 60.08,156.09 60.08,154.84 v3(60.23,154.69) ; R137.2 R777.1 ; R137.2 61.25,156.53 61.44,156.72 R1676.2 ; v4(55.15,164.72) R1664.1 R1675.2 56.17,165.8 R1874.1 54.07,165.8 53.88,165.61 R2066.2 53.18,167.26 51.98,168.47 51.98,170.05 ; v3(163.36,44.7) 163.61,44.96 R313.1 163.55,45.47 R1863.2 ; R1731.1 R1733.1 v3(32.77,30.99) ; v3(83.47,134.37) 83.92,134.81 R1877.1 84.11,135.32 R79635.2 R79670.2 ; v3(124.2,31.37) 124.24,31.33 R2091.1 ; v3(34.2,27.18) 33.95,27.42 33.63,27.42 R755.2 ; 124.77,63.78 124.49,63.5 115.22,63.5 114.33,64.39 PR5206.1 ; R307.1 R1864.2 163.33,51.56 v3(163.36,51.54) ; 54.14,170.05 55.41,170.05 55.66,169.8 R1813.2 R79673.2 ; 54.14,170.05 54.14,172.19 57.64,175.69 57.64,175.69 61.78,179.83 61.78,187.68 67.27,193.17 67.27,205.49 v3(68.66,206.88) ; 54.14,170.05 51.98,170.05 ; v3(72.19,135.19) 72.15,135.23 70.62,135.23 69.76,134.37 67.63,134.37 66.96,135.04 R717.1 66.52,135.32 65.69,136.14 v3(65.69,136.6) ; v3(55.56,157.61) R2012.1 R1679.2 54.87,156.59 54.6,156.32 54.6,154.78 ; R514.1 47.72,73.63 v3(47.53,73.83) 47.43,73.93 R531.1 ; v3(39.8,122.57) 40.17,122.2 40.17,119.63 R2029.2 ; R2065.2 45.87,169.48 45.35,170.01 45.35,170.56 45.86,171.07 46.78,171.07 47.54,170.31 51.72,170.31 51.98,170.05 ; R380.1 133.95,55.18 135.67,53.47 v3(135.85,53.47) 135.85,52.7 136.1,52.45 R382.1 ; R2064.1 v3(55.05,146.81) 53.7,148.16 53.7,153.88 54.6,154.78 ; R2030.2 38.13,133.27 v3(39,132.41) ; R378.1 34.46,4.88 v3(37.42,4.88) ; R1876.1 80.87,140.84 81.38,141.35 v3(81.57,141.35) 81.47,141.45 81.29,141.45 80.65,142.09 80.65,142.26 80.3,142.62 R1669.2 ; R1665.1 v4(55.58,161.67) ; v3(162.16,61.52) 162.16,61.49 162.53,61.13 R679.2 ; R1933.2 85.83,142.74 85.83,139.27 v3(85.57,139) ; R582.2 R1676.2 ; R1676.2 R1666.1 ; R79671.2 R2010.1 v3(55.28,154.56) 54.82,154.56 54.6,154.78 ; v3(39.89,112.7) 40.47,112.7 40.7,112.93 40.7,113.94 41.12,114.36 R79661.1 41.63,114.43 R483.1 ; v3(163.33,56.64) R682.1 R1826.2 ; v3(165.13,204.09) 165.26,204.22 PR5475.1 ; R297.2 v3(163.33,54.61) ; R371.2 R364.1 138.21,59.56 137.07,58.42 136.84,58.42 v3(136.81,58.39) ; R312.2 163.36,47.5 v3(163.48,47.37)
  TOP w1.27: v5(147.35,94.56) v5(147.35,93.27) 149.18,91.44 149.18,90.42 147.4,88.65 147.4,83.08 149.03,81.46 149.03,79.68 150.48,78.23 150.48,71.96 149,70.48 149,69.27 148.24,68.5 148.24,68.05
  L3 w0.508: v3(163.36,44.7) 162.19,43.54 v3(155.99,43.54) ; v3(65.69,136.6) 65.48,136.39 62.07,136.39 61.37,137.08 v3(56.57,137.08) 55.14,138.52 41.64,138.52 40.06,136.94 40.06,133.48 v3(39,132.41) 39,123.37 v3(39.8,122.57) 40.62,121.74 40.62,113.06 40.27,112.7 v3(39.89,112.7) 39.89,111.86 42.08,109.66 42.08,81.26 43.33,80.01 45.67,80.01 46.56,80.9 v3(47.4,80.9) ; v3(41.77,32.23) 41.44,32.23 40.57,31.37 37.12,31.37 36.74,30.99 v3(32.77,30.99) 30.13,28.35 v3(30.01,28.35) 28.96,27.3 27.72,27.3 27.08,27.94 27.08,28.19 25.43,28.19 v3(25.18,27.94) ; v3(33.31,24.64) 33.05,24.89 33.05,26.23 34,27.18 v3(34.2,27.18) ; v3(41.05,4.65) 41.54,5.13 41.54,7.72 42.4,8.59 v3(46.58,8.59) 46.59,8.6 48.84,8.6 49.82,7.62 v3(49.82,7.21) ; v3(41.05,4.65) 40.85,4.45 40.85,3.28 41.83,2.3 41.84,2.29 41.87,2.29 ; v3(41.05,4.65) 40.01,5.69 38.29,5.69 38.16,5.56 38.11,5.56 v3(37.42,4.88) 36.3,4.88 35.62,5.56 30.69,5.56 28.48,7.77 v3(28.48,11.43) ; v3(137.62,63.63) 140.34,66.34 v3(141.89,66.34) ; v3(142.65,60.33) 142.65,61 143.14,61.49 147.3,61.49 148.47,60.33 148.73,60.33 148.8,60.25 160.89,60.25 v3(162.16,61.52)
  L3 w1.27: 41.87,2.29 83.85,2.29 87.43,5.87 87.43,8.66 v3(87.74,8.97) v3(88.78,8.97)
  L4 w0.254: v3(75.47,70.87) 77.34,69 77.34,67.6 76.72,66.97 76.72,63.4 v3(76.93,63.18)
  L4 w0.381: v3(16.92,221.13) 18.32,219.74 18.32,217.81 17.51,216.99 17.51,205.69 15.48,203.66 15.48,183.88 18.05,181.3 18.05,177.15 18.77,176.44 18.77,175.94 18.44,175.61 18.44,172.62 19.2,171.86 19.2,171.67 19.72,171.15 v3(19.72,170.31)
  L4 w0.508: v3(162.16,61.52) 162.03,61.39 162.03,59.16 163.33,57.86 v3(163.33,56.64) 162.67,55.98 162.67,55.35 163.33,54.69 v3(163.33,54.61) 163.33,51.56 v3(163.36,51.54) 163.36,51.4 164.14,50.61 164.14,48.03 v3(163.48,47.37) 163.48,47.37 163.48,45.27 163.36,45.14 v3(163.36,44.7) ; v3(55.28,154.56) 55.81,154.03 59.27,154.03 59.93,154.69 v3(60.23,154.69) ; v3(90.89,139.75) 86.32,139.75 ; 86.32,139.75 v3(85.57,139) ; 86.32,139.75 84.72,141.35 v3(81.57,141.35) ; v3(136.81,58.39) 136.84,58.42 137.83,58.42 138.27,58.86 138.27,62.98 v3(137.62,63.63) ; v3(41.77,32.23) 41.85,32.32 41.85,34.84 41.09,35.6 41.09,37.41 41.34,37.66 41.34,39.32 42.4,40.39 42.4,41.1 41.09,42.41 41.09,50.85 42.13,51.89 42.13,52.37 42.13,54.31 41.07,55.37 39.28,55.37 37.57,57.08 37.5,57.16 37.5,63.42 47.53,73.46 v3(47.53,73.83) 49.77,76.06 49.77,79.26 48.12,80.9 v3(47.4,80.9) ; v3(135.85,53.47) 135.85,52.7 134.93,51.79 134.93,49.28 135.9,48.31 135.9,45.9 v3(136.71,45.09) ; v3(74.18,140.13) 73.13,139.09 72.78,139.09 72.19,138.5 v3(72.19,135.19) ; v3(150.17,211.71) v3(162.16,211.71) ; v3(28.48,11.43) 28.48,13.59 30.13,15.24 v3(30.77,15.24) 32.27,16.74 32.27,21.6 31.78,22.08 31.78,22.99 30.49,24.28 30.49,26.31 30.01,26.8 v3(30.01,28.35) ; v3(56.57,137.08) 56.6,137.11 56.6,137.4 55.05,138.94 v3(55.05,146.81)
  L4 w1.524: v3(125.59,209.52) 124.09,208.03 101.76,208.03 101.66,208.13 101.02,208.13 100.34,208.81 100.34,209.45 100.11,209.68 100.11,212.09 99.5,212.7 98.35,212.7 97.44,213.61 89.72,213.61 89.34,213.23 87.82,213.23 87.79,213.21 83.71,213.21 82.24,211.74 82.24,211.55 80.22,209.52 72.57,209.52 69.92,206.88 v3(68.66,206.88)
  BOTTOM w0.254: v3(47.53,73.83) 47.53,73.66 48.17,73.03 50.88,73.03 51.4,73.55 51.84,73.55 52.36,73.03 52.87,73.03 53.5,72.39 59.55,72.39 60.26,73.1 60.71,73.1 61.49,72.31 66.5,72.31 68.73,70.09 74.7,70.09 v3(75.47,70.87)
  BOTTOM w0.381: v3(34.2,27.18) 31.17,27.18 v3(30.01,28.35) ; v3(141.89,66.34) 142.37,66.82 147.02,66.82 147.37,66.48 147.37,64.66 146.4,63.69 R1843.1
  BOTTOM w0.508: v4(55.15,164.72) 55.58,164.72 56.22,164.08 56.22,162.31 v4(55.58,161.67) 55.58,157.63 v3(55.56,157.61) ; R1831.1 155.95,43.5 v3(155.99,43.54) ; v3(68.66,206.88) 72.93,206.88 73.44,207.39 R1987.2 ; v3(136.81,58.39) 136.69,58.27 136.69,57.32 136.66,57.3 136.66,56.75 136.69,56.72 136.69,54.43 135.85,53.59 v3(135.85,53.47) ; v3(32.77,30.99) 32.77,32 32.11,32.66 32.11,33.29 32.68,33.86 v3(32.85,33.86) ; R79689.2 R297.2 v3(163.33,54.61) ; v3(90.89,139.75) 90.89,141.58 90.14,142.32 89.36,142.32 86.29,145.39 86.29,148.11 85.55,148.84 C1715.1 83.6,149.02 81.81,150.81 81.81,154.29 81.76,154.34 C1716.1 v4(82.46,154.81) ; v3(124.2,31.37) 126.69,33.86 135.8,33.86 136.71,34.77 v3(136.71,45.09) ; 79.2,140.12 74.19,140.12 v3(74.18,140.13) ; 79.2,140.12 80.14,140.12 81.38,141.35 v3(81.57,141.35) ; 79.2,140.12 79.2,139.92 80.91,138.22 80.91,137.55 83.45,135 83.46,135 83.47,134.99 v3(83.47,134.37) ; 164.37,195.2 164.37,200.66 165.21,201.5 165.21,204.01 v3(165.13,204.09) 165.13,206.2 162.19,209.14 162.19,211.68 v3(162.16,211.71) ; R80201.1 R80202.1 27.02,9.84 28.48,11.3 v3(28.48,11.43) ; R79675.1 v3(150.17,211.71) ; R79690.2 162.53,55.84 v3(163.33,56.64) ; R731.1 24.67,27.43 v3(25.18,27.94) ; v3(141.89,66.34) 141.89,62.69 142.65,61.93 v3(142.65,60.33) ; R764.2 v3(49.82,7.21) ; R305.2 v3(163.48,47.37)
  BOTTOM w1.27: v5(147.35,93.27) v5(147.35,94.56) 150.48,94.56 153.65,91.39 162.8,91.39 164.75,93.34 167.7,93.34 171.05,96.7 171.05,101.42 172.14,102.51 172.14,109.33 169.96,111.52 169.96,122.82 170.39,123.26 170.39,127.58 166.48,131.5 166.48,142.98 169.6,146.1 169.6,152.5 162.21,159.89 162.21,184.99 163.36,186.13 163.36,187.76 ; 162.59,198.45 155.66,198.45 151.93,202.18 143.8,202.18 139.02,206.96 129.57,206.96 ; v3(88.78,8.97) v3(87.74,8.97) 87.74,10.31 88.32,10.9 88.32,12.24 89.01,12.93 89.95,12.93 90.61,13.59 90.61,14.66 90.09,15.18 90.09,15.58 89.47,16.2 89.47,17.87 88.65,18.68 88.65,19.55 90.08,20.97 90.08,25.68 88.53,27.23 88.53,28.88 85.23,32.18 85.23,35.49 87.21,37.47 87.21,43.71 89.38,45.89 92.96,45.89 94.32,47.24 100.36,47.24 103.92,43.69 109.18,43.69 109.33,43.84 109.71,43.84 113.37,47.5 114.33,47.5 118.78,51.94 127.49,51.94 129.85,54.31 129.85,55.5 v5(129.6,55.75) 129.6,56.16 v5(128.96,56.79)
  vias: v2(126.65,209.42)
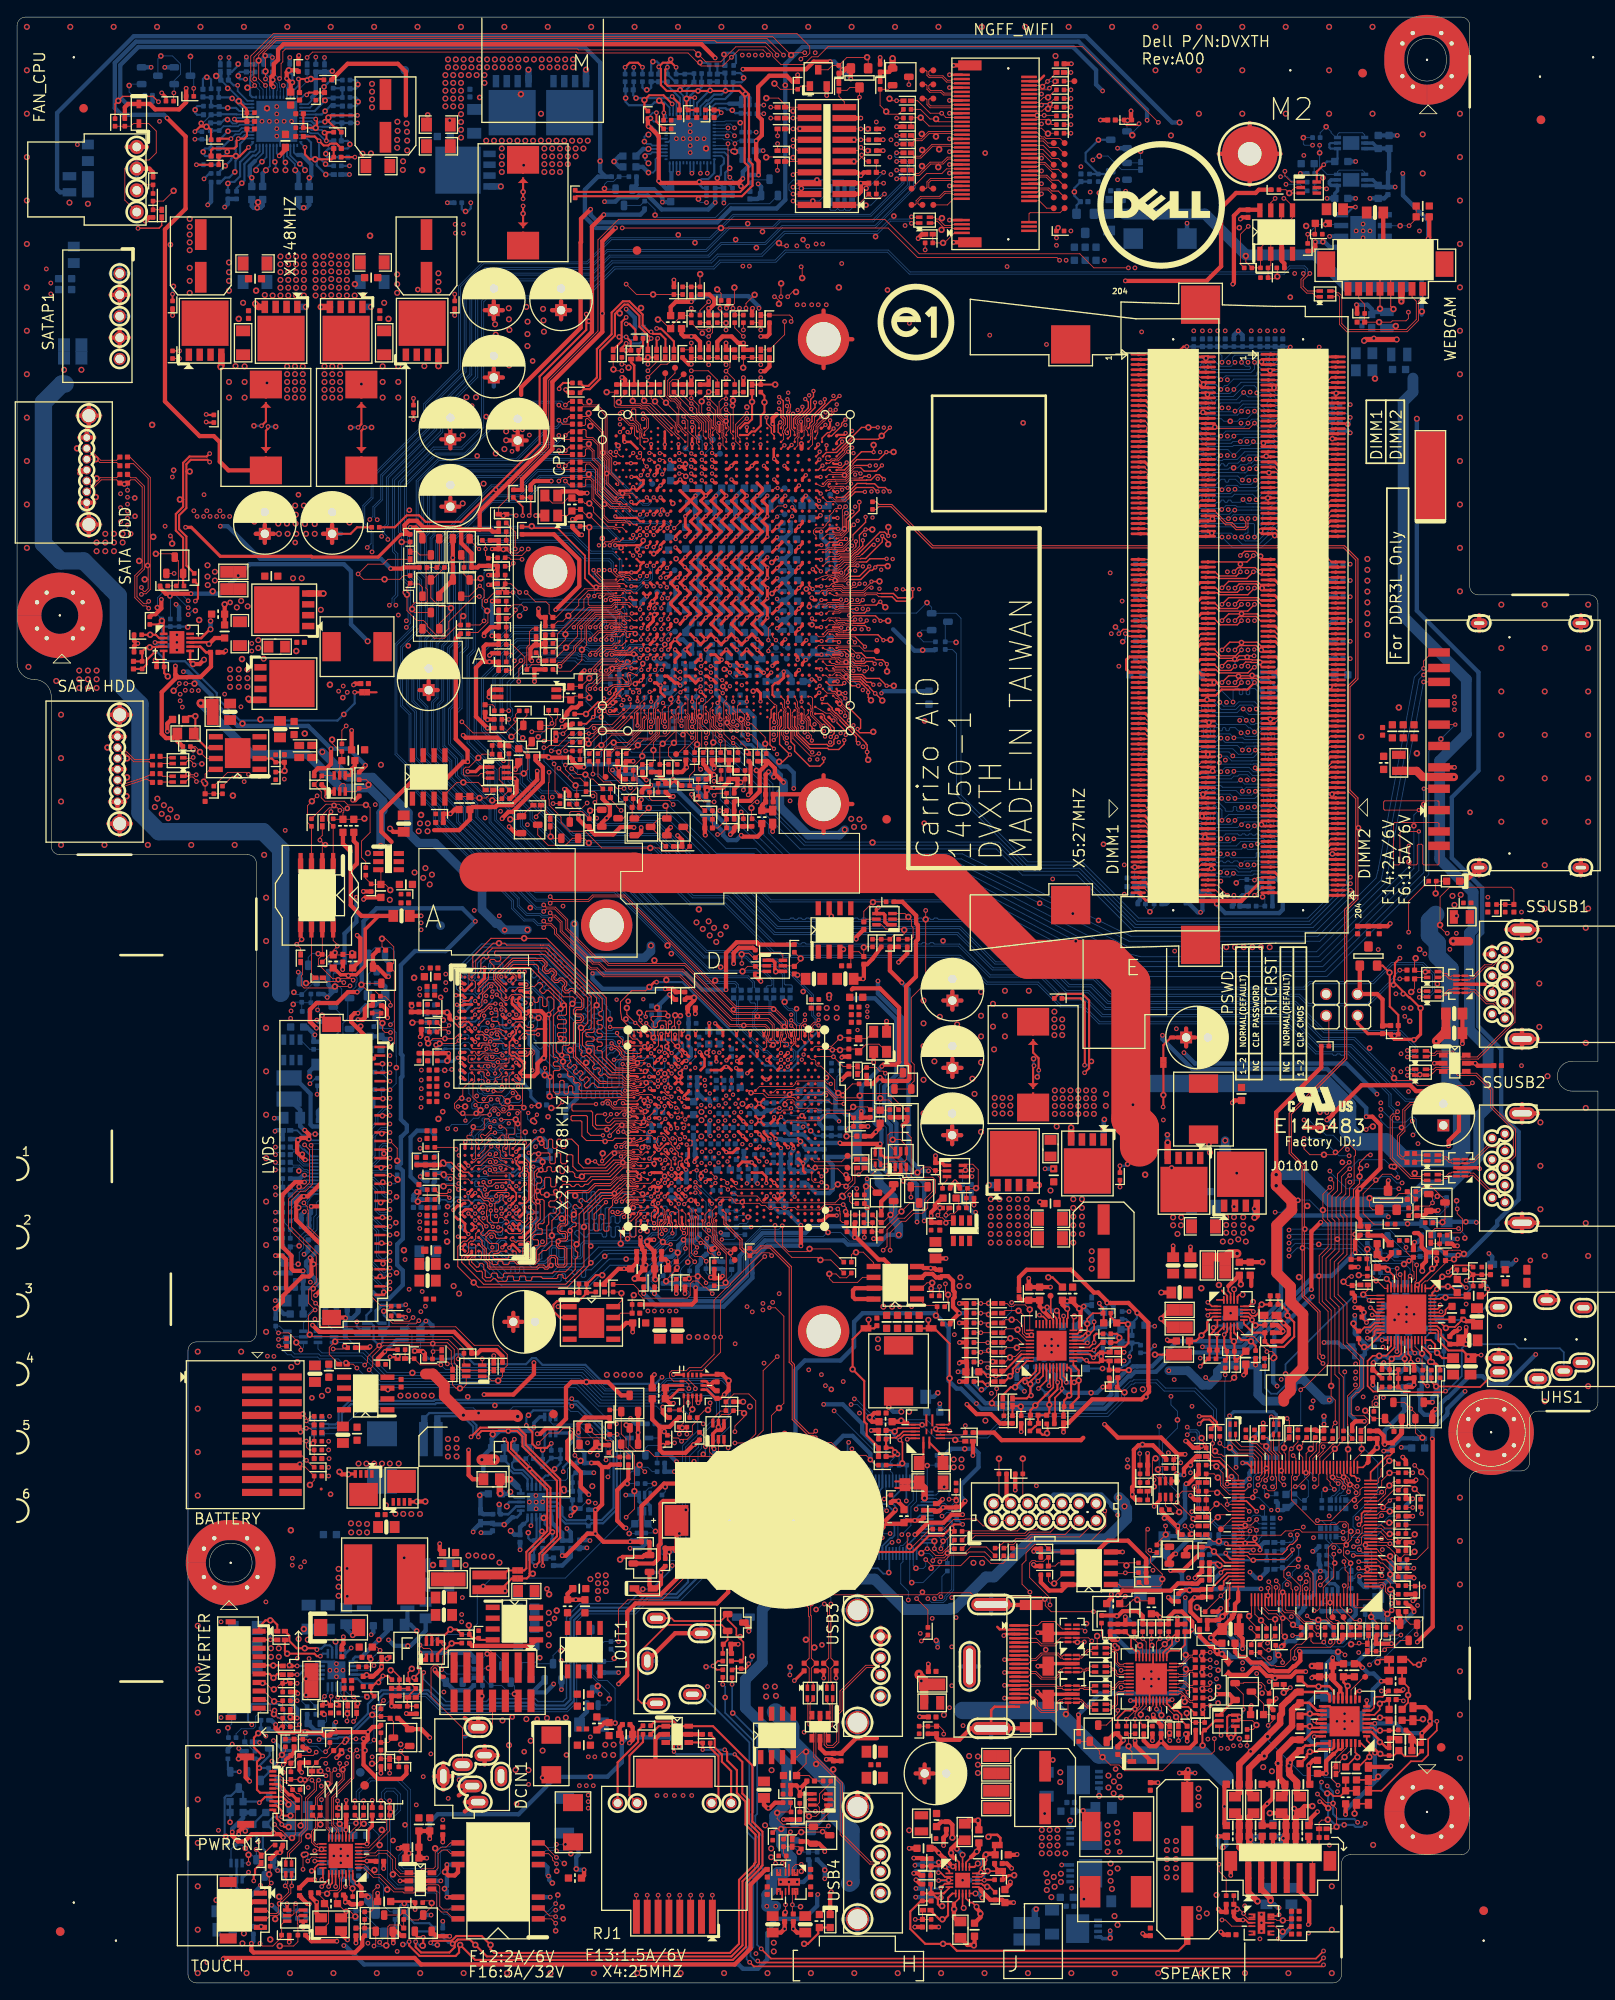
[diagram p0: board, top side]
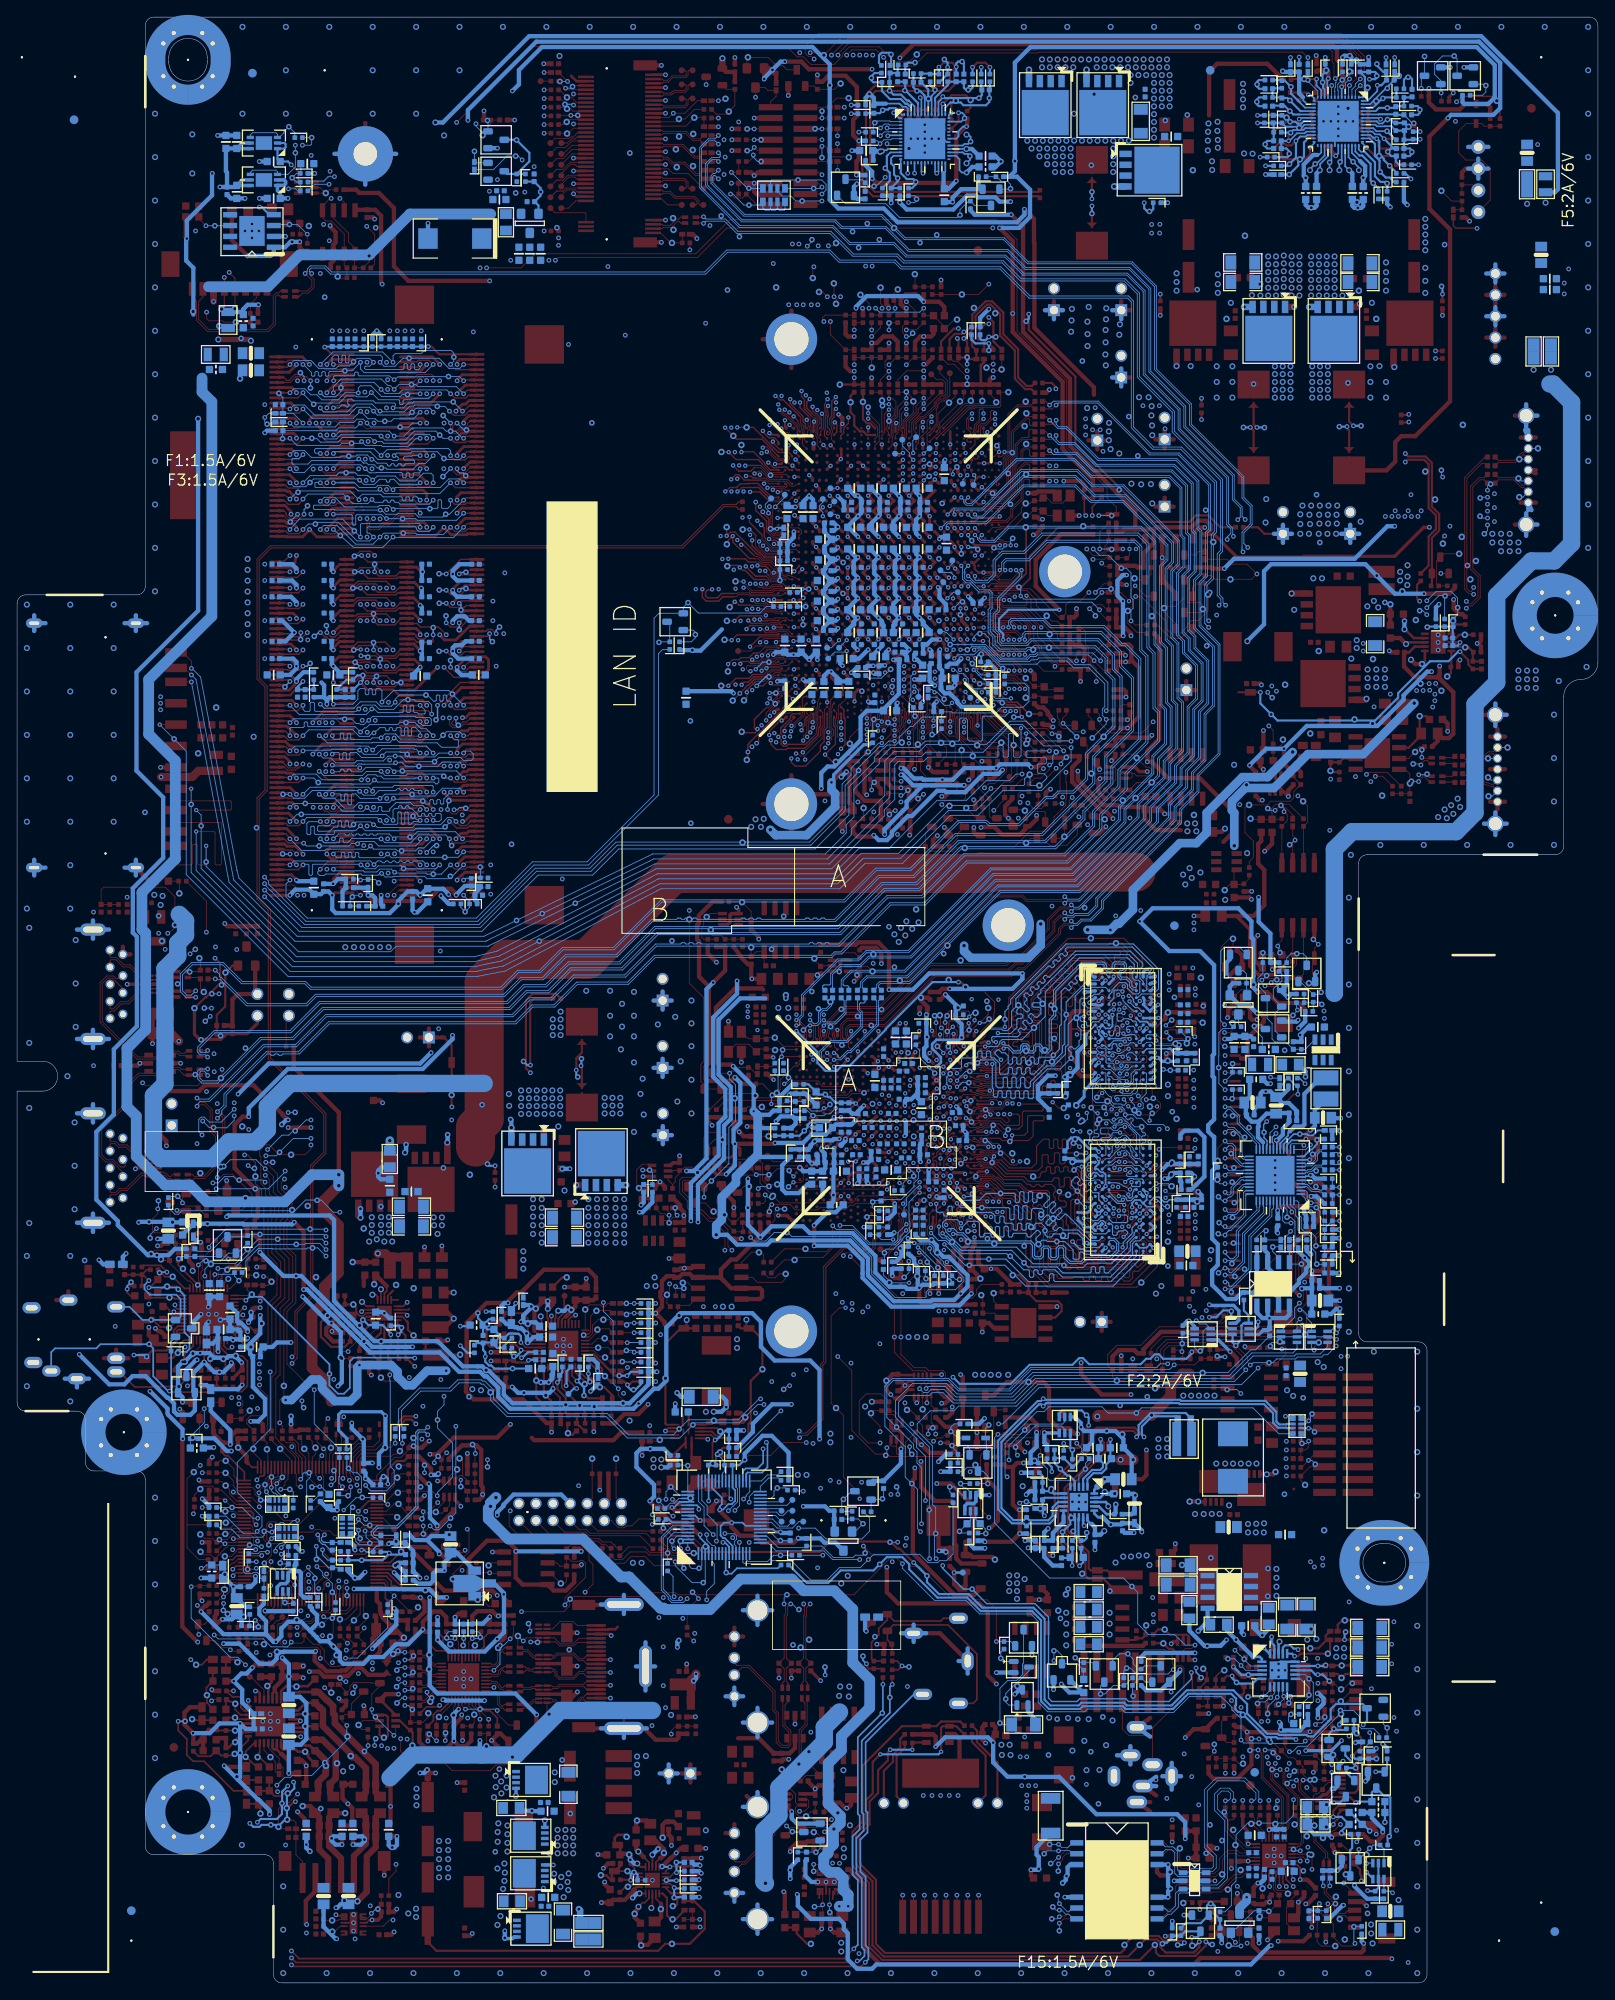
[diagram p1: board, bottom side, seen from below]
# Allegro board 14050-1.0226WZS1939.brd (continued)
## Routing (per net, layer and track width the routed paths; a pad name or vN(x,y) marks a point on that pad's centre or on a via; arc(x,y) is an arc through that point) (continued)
SB3V_EN: length 11.2
  TOP w0.102: v3(91.78,13.87) 91.75,13.84 91.08,13.84 90.73,13.49 U54.3 ; C1700.1 91.47,15.94 R1981.2 R1980.2 89.7,15.18 PR5431.2 90.01,14.3 89.73,14.02 v3(89.57,14.02) 89.57,13.86 89.93,13.49 U54.5
  L3 w0.127: v3(91.78,13.87) 91.75,13.84 91.08,13.84 90.52,13.28 90.14,13.28 89.57,13.86 v3(89.57,14.02)
  BOTTOM w0.102: v3(91.78,13.87) v2(91.78,13.06)
SB5_33_CT1: length 3.8
  TOP w0.102: U54.12 v3(90.73,9.14) 90.73,8.17 C1929.1
  BOTTOM w0.102: v2(91.69,8.92) 90.92,8.92 90.73,9.11 v3(90.73,9.14)
SB5_33_CT2: length 3.6
  TOP w0.102: U54.10 v3(89.93,9.14) 89.93,8.17 C1928.1
  BOTTOM w0.102: v2(89.9,8.26) 89.95,8.31 89.95,9.12 v3(89.93,9.14)
SB5V: length 821.1
  TOP w0.203: U54.13 91.13,9.91
  TOP w0.305: PU4803.7 21.44,156.34 22.11,155.68 PC4803.1
  TOP w0.508: v3(25.18,17.65) 25.18,17.23 25.86,16.55 26.62,16.55 27.47,17.4 30.77,17.4 v3(31.15,17.02) ; PR5295.1 18.75,145.3 PR5294.1 18.22,145.64 17.44,145.64 16.92,146.16 16.92,151 18.52,152.6 18.52,153.1 ; R118.2 R119.1 77.82,133.72 v3(77.3,134.24) ; U178.8 145.38,207.45 C103.1 143.1,207.45 142.4,206.76 142.4,198.88 v3(142.27,198.75) ; v3(84.94,211.1) 84.43,210.59 75.32,210.59 v3(75.09,210.82) 75.09,216.09 73.99,217.19 v3(73.89,217.19) 73.82,217.26 PR5429.2 ; PR5002.2 148,75.06 148.82,75.87 148.82,76.59 v3(148.22,77.19) 147.39,78.02 PR5004.2 ; R1833.2 135.2,44.64 v3(134.73,45.11) ; 18.52,153.1 v3(18.52,154.08) ; 18.52,153.1 18.87,152.76 19.87,152.76 19.89,152.78 21.46,152.78 22.69,154.01 22.69,155.61 PC4803.1 ; v3(150.61,100.08) v3(153.27,100.08) ; PR4602.1 32.93,225.45 v3(32.98,225.5) ; PC4608.1 31.4,214.49 v3(30.68,213.76)
  L3 w0.508: v3(22.21,2.39) 23.3,3.48 37.35,3.48 v3(38.23,4.37) ; v3(134.73,45.11) 134.02,45.82 130.41,45.82 129.8,46.43 122.79,46.43 121.53,47.69 111.21,47.69 110.64,47.13 101.09,47.13 100.77,47.45 97.43,47.45 96.28,48.6 91.35,48.6 v3(91.32,48.56) ; v3(73.89,217.19) 73.89,225.58 72.65,226.82 34.3,226.82 v3(32.98,225.5) ; v3(148.63,46.6) 148.62,46.6 148.62,46.42 148.3,46.1 148.08,46.1 147.5,45.52 146.11,45.52 145.73,45.9 145.73,45.95 v3(145.58,46.1) ; v3(77.3,134.24) 77.3,133.23 81.56,128.97 82.93,128.97 88.32,123.59 117.96,123.59 118.72,122.82 119.58,122.82 132.91,109.5 145.6,109.5 151.27,103.83 151.27,100.69 150.66,100.08 v3(150.61,100.08) 150.61,100.03 149.95,99.37 149.95,96.85 150.86,95.94 150.86,86.27 152.13,85 152.13,80.85 v3(151.57,80.29)
  L4 w0.254: v3(94.39,67.69) 94.39,63.65 91.04,60.3 91.04,59.13 89.52,57.61 89.52,52.5 91.32,50.7 v3(91.32,48.56)
  L4 w0.508: v3(93.71,10.35) 93.71,15.04 92.36,16.38 92.36,20.26 95.98,23.88 95.98,32.7 91.47,37.21 91.47,37.5 91.22,37.75 91.22,43.83 91.15,43.91 91.15,44.77 91.32,44.94 v3(91.32,48.56) ; v3(38.9,211.58) 38.74,211.58 37.17,213.16 ; v3(153.27,100.08) 153.31,100.04 153.74,100.04 154.7,101 154.7,104.97 155.66,105.93 155.66,107.97 160.05,112.36 160.05,121.22 159.64,121.63 159.64,155.78 160.35,156.49 160.35,192.71 158.6,194.45 157.67,194.45 153.68,198.45 153.68,198.45 153.42,198.71 142.32,198.71 v3(142.27,198.75) 142.1,198.93 141.82,198.93 141.6,198.71 131.87,198.71 130.58,200 129.78,200 129.76,200.03 111.67,200.03 106.84,204.85 102.65,204.85 95.03,212.47 90.46,212.47 87.82,209.83 86.21,209.83 v3(84.94,211.1) ; v3(147.45,69.82) 147.45,67.11 147.53,67.03 147.53,58.36 147.61,58.29 147.61,57.99 148.5,57.1 148.5,55.05 v3(147.81,54.37) 147.81,49.78 149.59,48.01 149.59,46.96 149.24,46.61 148.63,46.61 v3(148.63,46.6) ; v3(18.52,154.08) 19.36,154.91 19.36,158.17 18.6,158.93 v3(18.6,161.29) 18.6,163.75 17.72,164.64 17.72,165.32 20.61,168.21 20.61,171.07 19.77,171.91 19.77,172.09 19.53,172.34 19.53,182.05 17.11,184.47 17.11,204.34 20.8,208.03 v3(22.31,208.03) 22.39,208.1 22.39,209.04 27.11,213.76 v3(30.68,213.76) 36.56,213.76 37.17,213.16 ; 37.17,213.16 37.17,222.33 34.88,224.61 33.67,224.61 32.98,225.3 v3(32.98,225.5) ; v3(22.21,2.39) 22.21,14.81 25.05,17.65 v3(25.18,17.65) ; v3(31.15,17.02) 31.63,17.5 31.63,21.28 30.97,21.94 30.96,21.94 29.85,23.05 29.85,25.92 v3(29.83,25.94)
  BOTTOM w0.203: v3(30.68,213.76) 30.39,214.06 PU4601.33 ; v3(73.89,217.19) 74.31,217.19 74.84,216.66 74.84,216.03 75.09,215.77 PU5407.33 ; PU5407.25 76.77,211.93 76.57,211.73 76.37,211.93 PU5407.26
  BOTTOM w0.508: R79726.1 R389.1 34.02,18.24 33.18,17.4 31.53,17.4 v3(31.15,17.02) ; v3(84.94,211.1) 84.94,211.9 85.69,212.66 PR5418.1 ; v3(134.73,45.11) 135.8,45.11 136.77,46.08 140.47,46.08 140.5,46.1 v3(145.58,46.1) ; R724.1 R735.1 26.45,19.3 25.18,18.03 v3(25.18,17.65) ; v3(29.83,25.94) 30.32,25.45 R1759.1 ; v3(75.09,210.82) 75.98,209.93 PC5421.1 76.57,210.02 76.57,211.73 ; v3(151.57,80.29) 148.47,77.19 v3(148.22,77.19) 147.92,76.89 147.88,76.89 147.12,76.13 147.12,73.18 v2(147,73.05) 147,70.28 v3(147.45,69.82) ; v3(93.71,10.35) 93.63,10.27 93.63,9.02 92.11,7.49 88.81,7.49 88.25,6.93 88.25,6.27 87.79,5.82 87.79,2.75 86.69,1.65 84.95,1.65 84.44,2.16 40.6,2.16 38.39,4.37 v3(38.23,4.37) ; v3(94.39,67.69) 96.63,67.69 98.9,65.42 98.9,64.45 100.74,62.61 PR57.1 ; v3(22.31,208.03) 22.7,208.42 PR4631.2 ; R125.2 18.96,160.93 v3(18.6,161.29) ; PR4633.2 v3(38.9,211.58)
SCALAR_SIO_PU: length 111.9
  TOP w0.102: RN8.2 147.03,65.97 146.79,66.21 ; v3(163.46,48.51) 163.36,48.51 163.23,48.39 162.78,48.39 R80221.2 R80222.2 163.74,49.53 165.11,50.9 165.11,53.59 ; 165.11,53.59 165.11,58.98 v1(164.32,59.77) 163.56,60.53 v3(163.56,60.55) ; 165.11,53.59 R289.2 R1188.2 ; R79638.2 153.07,40.03 v3(152.92,39.88) 152.79,39.75 151.67,39.75 151.42,40.01 R79637.2 150.34,39.62 149.74,39.62 149.05,38.94 149.05,37.79 148.29,37.02 147.37,37.02 147.29,37.1 146.78,37.1 145.45,38.43 R2014.2 R2013.2 ; RN8.1 147.68,65.89 147.35,66.21 146.79,66.21 ; R1844.1 132.84,50.36 v3(132.57,50.62) ; 146.79,66.21 v3(146.77,66.23) ; v3(161.94,40.7) R317.2
  L3 w0.127: v3(151.71,52.1) 151.71,52.09 151.46,51.84 147.44,51.84 146.72,51.12 144.09,51.12 143.77,50.8 140.29,50.8 139.11,49.62 133.74,49.62 132.73,50.62 v3(132.57,50.62) ; v3(146.77,66.23) 147.43,65.57 151.03,65.57 151.46,66 154.68,66 155.63,65.05 160.26,65.05 163.56,61.75 v3(163.56,60.55)
  L4 w0.127: v3(161.94,40.7) 162.06,40.83 162.06,41.11 162.26,41.32 162.26,44.63 162.59,44.96 162.59,45.19 162.91,45.51 162.91,47.61 163.07,47.76 163.07,48.12 v3(163.46,48.51) ; v3(151.71,52.1) 152.6,51.21 152.6,49.55 153.07,49.08 153.07,46.29 153.07,46.28 153.07,40.03 v3(152.92,39.88)
  BOTTOM w0.102: R276.2 161.03,48.9 R305.1 162.85,48.9 163.23,48.51 v3(163.46,48.51) ; v3(152.92,39.88) 153.07,39.73 153.07,39.62 153.37,39.32 155.25,39.32 156.18,40.25 161.48,40.25 v3(161.94,40.7)
SD_CD_BD: length 140.2
  TOP w0.102: CPU1.BC2 69.71,146.81 v4(67.51,146.81) ; v4(162.88,133.03) 162.88,130.94 163,130.81 163.74,130.81 163.86,130.94 163.86,133.1 163.99,133.22 164.37,133.22 164.5,133.1 164.5,130.94 164.63,130.81 166.28,130.81 166.41,130.94 MEMCD1.11
  BOTTOM w0.102: v4(67.51,146.81) 67.51,143.59 67.7,143.41 68.28,143.41 68.38,143.51 68.38,146.05 68.51,146.18 68.86,146.18 68.99,146.05 68.99,143.51 69.09,143.41 69.5,143.41 69.6,143.51 69.6,144.68 69.7,144.78 70.11,144.78 70.21,144.68 70.21,143.51 70.31,143.41 78.42,143.41 78.93,142.9 81.89,142.9 82.29,142.49 82.29,138.46 83.51,137.24 83.51,136.52 86.22,133.81 86.54,133.5 89.69,130.35 110.21,130.35 110.99,129.94 128.86,120.71 131.48,120.07 152.31,120.07 162.88,130.63 v2(162.88,131.15) v4(162.88,133.03)
SD_CLK_BD: length 143.5
  TOP w0.102: v3(61.65,144.53) 62.02,144.53 62.26,144.77 63.35,144.77 64.76,146.18 R1735.2 ; MEMCD1.5 v4(168.31,147.22)
  BOTTOM w0.102: v4(168.31,147.22) v2(166.63,145.54) 165.21,144.12 165.21,129.68 153.28,117.74 131.2,117.74 131.1,117.76 127.89,118.38 109.63,128.02 88.72,128.02 85.74,131 81.36,131 75.76,136.6 72.53,136.6 69.63,139.5 65.11,139.5 61.65,142.96 v3(61.65,144.53)
SD_CLK_CH_C: length 8.9
  TOP w0.102: R1735.1 v4(66.91,146.18) 67.45,146.18 67.88,146.61 70.01,146.61 71.35,147.95 71.35,148.05 CPU1.BB4
  BOTTOM w0.102: v2(66.71,145.44) 66.91,145.64 v4(66.91,146.18)
SD_CMD_BD: length 136.3
  TOP w0.102: MEMCD1.2 v4(164.63,139.72) ; R570.2 v3(64.19,144.15)
  BOTTOM w0.102: v4(164.63,139.72) v2(164.63,137.89) 164.63,129.92 153.03,118.32 131.27,118.32 130.22,118.58 130.15,118.59 128.13,118.96 126.02,120.03 109.78,128.6 88.96,128.6 85.99,131.58 81.6,131.58 76,137.18 72.77,137.18 70.21,139.75 69.87,140.09 67.22,140.09 67.09,140.21 67.09,140.91 66.9,141.1 66.58,141.1 66.45,140.97 66.45,140.21 66.33,140.09 65.35,140.09 64.51,140.93 64.51,141.18 64.8,141.48 65.44,141.48 65.57,141.6 65.57,142.49 65.44,142.62 64.68,142.62 64.55,142.75 64.55,143.26 64.68,143.38 66.8,143.38 66.93,143.51 66.93,144.02 66.8,144.15 v3(64.19,144.15)
SD_CMD_CH_C: length 12.9
  TOP w0.102: CPU1.AY5 73.4,150.19 72.9,149.69 72.9,149.17 72.53,148.8 72.47,148.8 72.25,148.58 72.25,147.95 72.17,147.87 72.17,146.4 71.97,146.2 68.28,146.2 67.06,144.98 v1(66.89,144.98) 66.66,144.98 65.88,144.21 R570.1 R1650.2
SD_DATA0_BD: length 142.9
  TOP w0.102: R585.2 64.56,145.16 63.55,144.15 v3(62.52,144.15) ; v3(164.6,152.22) MEMCD1.7
  BOTTOM w0.102: v3(62.52,144.15) 63.1,144.73 64.85,144.73 67.34,147.22 68.71,147.22 71.94,143.99 78.66,143.99 79.17,143.48 82.13,143.48 82.87,142.73 82.87,138.7 84.09,137.48 84.09,136.76 86.8,134.05 87.15,133.7 89.93,130.93 110.36,130.93 111.26,130.45 v2(119.67,126.32) 129.86,121.32 129.88,121.29 140.65,121.29 141.29,120.65 152.07,120.65 160.19,128.77 160.31,129.42 v3(164.6,152.22)
SD_DATA0_CH_C: length 7.2
  TOP w0.102: R585.1 66.31,145.59 67.16,145.59 67.97,146.41 70.21,146.41 CPU1.BC3
SD_DATA1_BD: length 141.8
  TOP w0.102: MEMCD1.8 165.41,153.85 v3(164.6,153.03) ; v3(61.65,145.29) 61.72,145.35 R584.2
  BOTTOM w0.102: v3(61.65,145.29) 61.67,145.31 64.58,145.31 66.9,147.62 68.82,147.62 71.53,144.91 78.57,144.91 79.42,144.06 82.37,144.06 83.46,142.97 83.46,138.94 87.39,135.01 87.39,134.29 90.17,131.51 110.5,131.51 111.05,131.22 v2(123.55,125.11) 130.08,121.92 130.12,121.87 152.47,121.87 159.61,129.01 159.66,129.11 159.9,130.38 164.06,152.5 164.59,153.03 v3(164.6,153.03)
SD_DATA1_CH_C: length 11.5
  TOP w0.102: CPU1.BA3 71.8,149.3 70.95,148.45 70.85,148.45 69.62,147.22 67.34,147.22 66.88,146.76 64.49,146.76 63.89,146.16 v3(63.89,146.15) 63.8,146.24 R584.1
  BOTTOM w0.102: v3(63.89,146.15) 63.41,146.15 v2(63.08,145.82)
SD_DATA2_BD: length 132.3
  TOP w0.102: v3(71.03,139.75) 70.21,139.75 69.45,140.52 68.63,140.52 67.98,141.16 R1686.2 ; v4(164.04,134.72) 161.96,134.72 161.83,134.59 161.83,130.94 161.7,130.81 161.2,130.81 161.07,130.94 161.07,135.64 161.2,135.76 166.28,135.76 166.41,135.64 MEMCD1.9
  BOTTOM w0.102: v4(164.04,134.72) 164.04,130.15 152.79,118.91 131.34,118.91 130.34,119.15 128.37,119.54 v2(123.89,121.88) 110.76,128.74 109.92,129.18 89.2,129.18 86.23,132.16 81.84,132.16 76.24,137.76 73.01,137.76 v3(71.03,139.75)
SD_DATA2_CH_C: length 7.8
  TOP w0.102: R1686.1 68.37,144.22 68.53,144.22 69.43,145.12 v1(69.82,145.12) 71.46,145.12 73.21,146.86 73.21,147.91 CPU1.BC5
SD_DATA3_BD: length 129.1
  TOP w0.102: R571.2 67.39,142.51 v3(67.39,141.43) ; MEMCD1.1 166.41,138.18 166.28,138.3 160.05,138.3 159.93,138.18 159.93,137.35 160.05,137.22 v4(164.04,137.22)
  BOTTOM w0.102: v3(67.39,141.43) 68.09,141.43 68.85,140.67 71.6,140.67 73.9,138.36 77.33,138.36 82.95,132.74 86.47,132.74 89.45,129.76 110.07,129.76 111.03,129.25 125.02,121.95 128.61,120.13 130.12,119.8 131.41,119.49 152.55,119.49 163.46,130.4 v2(163.46,135.38) 163.46,136.64 v4(164.04,137.22)
SD_DATA3_CH_C: length 10.3
  TOP w0.102: CPU1.BA5 73.4,149.38 73.01,148.99 73.01,146.95 72.06,146 69.58,146 68.4,144.82 v1(68.37,144.82) 67.95,144.82 R571.1
SD_LED_BD: length 151.3
  TOP w0.102: R111.1 162.85,126.56 v3(162.85,122.94) ; v4(74.17,146.3) 73.77,146.71 73.77,147.75 73.91,147.89 73.91,148.35 73.9,148.35 73.9,149 CPU1.BB6
  L3 w0.127: v3(150.61,100.97) 149.77,100.97 149.19,101.54 149.19,105.07 145.89,108.37 133.2,108.37 119.34,122.23 118.47,122.23 117.71,122.99 88.07,122.99 82.69,128.38 81.06,128.38 76.73,132.71 75.18,134.26 75.18,136.48 73.69,137.97 73.69,138.46 72.39,139.76 72.39,142.46 72.56,142.63 72.56,144.69 v4(74.17,146.3)
  L4 w0.127: v3(155.68,97.51) 156.19,98.02 156.19,99.65 156.64,100.09 156.64,101.87 157.37,102.6 157.37,105 158.04,105.67 158.04,107.35 163.63,112.94 163.63,116.27 163.86,116.5 163.86,121.92 v3(162.85,122.94)
  BOTTOM w0.102: v3(155.68,97.51) 154.01,99.19 153.2,99.19 152.69,99.69 v2(152.45,99.69) 151.18,100.97 v3(150.61,100.97)
SD_LED_BD_A: length 2.7
  TOP w0.102: LED3.A R111.2 166.01,128.83 v1(166.01,127.47)
SD_PWRCTL_CH: length 11.3
  TOP w0.102: TP190.1 68.64,141.32 68.64,144.05 68.84,144.25 69.6,144.25 69.95,144.6 71.24,144.6 73.41,146.78 73.41,147.68 73.7,147.97 73.7,148.26 73.4,148.56 CPU1.BB5
SD_WP_BD: length 142.8
  TOP w0.102: CPU1.BB2 70.41,148.41 69.16,148.41 v4(68.75,148.81) ; v3(164.6,153.79) 164.6,154.66 165.6,155.66 MEMCD1.10
  BOTTOM w0.102: v4(68.75,148.81) 69.36,148.21 71.92,148.21 72.04,148.08 72.04,145.41 72.17,145.29 73.54,145.29 73.77,145.51 73.77,147.74 74.01,147.98 74.58,147.98 74.71,147.85 74.71,145.41 74.84,145.29 78.72,145.29 79.48,144.53 82.73,144.53 84.1,143.16 84.1,142.65 87.07,139.68 87.07,136.4 87.97,135.5 87.97,134.53 90.41,132.09 110.64,132.09 111.16,131.82 v2(126.55,124.31) 130.37,122.45 152.23,122.45 159.03,129.26 159.09,129.47 159.27,130.16 159.27,130.18 159.33,130.49 163.52,152.79 164.53,153.79 v3(164.6,153.79)
SENSE_B: length 4.9
  TOP w0.102: R267.2 R266.2 164.42,71.77 v1(164.42,73.63) 163.59,74.46 U6.33
SER_IRQ: length 152.5
  TOP w0.102: v4(80.63,147.57) 80.63,148.47 CPU1.BC14 ; U109.36 155.66,62.33 v1(155.76,62.43) 155.76,63.21 R680.1 155.74,64.2 155.74,65.28 155.68,65.33 155.68,68.66 156.53,69.51 156.81,69.51 157.11,69.8 157.11,72.8 155.19,74.71 155.19,79.29 154.15,80.33 154.15,84.36 155.19,85.4 155.19,89.52 154.85,89.86 154.85,91.67 155.49,92.32 155.49,94.03 v3(155.95,94.49)
  L3 w0.127: v3(155.95,94.49) 157.11,95.65 157.11,103.16 151.48,108.8 151.48,111.38 148.22,114.65 133.33,114.65 121.29,126.69 120.32,126.69 118.26,128.74 91.68,128.74 88.44,131.98 86.89,131.98 85.46,133.4 83.34,133.4 82.6,134.14 82.6,134.41 81.85,135.15 81.49,135.15 80.29,136.36 80.29,136.49 79.52,137.26 79.52,139.39 78.83,140.08 78.83,143.86 79.27,144.29 79.27,145.02 79.65,145.4 79.65,146.6 v4(80.63,147.57)
SIDE_USB3_RX2+: length 9.9
  TOP w0.102: SSUSB1.6 174.12,114.07 174.02,113.97 173.72,113.97 172.88,114.81 172.04,114.81 170.64,116.21 170.09,116.21 169.98,116.32 U3.2 U3.9 168.03,116.32 167.92,116.21 167.49,116.21 167.11,115.82 166.92,115.82 166.71,116.04 L5.3
SIDE_USB3_RX2-: length 9.9
  TOP w0.102: SSUSB1.5 174.12,113.61 174.02,113.71 173.62,113.71 172.77,114.55 171.93,114.55 170.53,115.95 170.09,115.95 169.98,115.84 U3.1 U3.10 168.03,115.84 167.92,115.95 167.6,115.95 167.22,115.57 166.87,115.57 166.66,115.36 L5.2
SIDE_USB3_RX3+: length 10
  TOP w0.102: SSUSB2.6 174.12,92.57 174.02,92.47 173.48,92.47 172.99,92.96 172.25,92.96 170.47,94.74 170.09,94.74 169.98,94.86 U5.2 U5.9 167.91,94.86 167.79,94.74 167.59,94.74 167.21,94.36 167.01,94.36 166.8,94.57 L57.3
SIDE_USB3_RX3-: length 10
  TOP w0.102: L57.2 166.8,93.89 167.01,94.11 167.31,94.11 167.69,94.49 167.79,94.49 167.91,94.38 U5.10 U5.1 169.98,94.38 170.09,94.49 170.36,94.49 172.14,92.71 172.88,92.71 173.38,92.21 174.02,92.21 174.12,92.11 SSUSB2.5
SIDE_USB3_TX2+: length 9.9
  TOP w0.102: SSUSB1.9 174.12,120.07 174.02,119.97 173.34,119.97 172.5,119.13 171.74,119.13 170.34,117.73 170.09,117.73 169.98,117.84 U3.5 U3.6 167.91,117.84 167.79,117.73 167.69,117.73 167.31,118.11 166.87,118.11 166.66,118.32 L4.3
SIDE_USB3_TX2-: length 9.9
  TOP w0.102: SSUSB1.8 174.12,119.61 174.02,119.71 173.45,119.71 172.6,118.87 171.84,118.87 170.44,117.47 170.09,117.47 169.98,117.36 U3.4 U3.7 167.91,117.36 167.79,117.47 167.59,117.47 167.2,117.86 166.87,117.86 166.66,117.64 L4.2
SIDE_USB3_TX3+: length 9.9
  TOP w0.102: SSUSB2.9 174.12,98.57 174.02,98.47 173.45,98.47 173.03,98.04 172.12,98.04 170.34,96.26 170.09,96.26 169.98,96.38 U5.5 U5.6 167.91,96.38 167.79,96.26 167.69,96.26 167.31,96.65 167.01,96.65 166.8,96.86 L56.3
SIDE_USB3_TX3-: length 9.9
  TOP w0.102: SSUSB2.8 174.12,98.11 174.02,98.21 173.56,98.21 173.13,97.79 172.22,97.79 170.44,96.01 170.09,96.01 169.98,95.9 U5.4 U5.7 167.91,95.9 167.79,96.01 167.59,96.01 167.2,96.39 167.01,96.39 166.8,96.18 L56.2
SIO_AGND: length 30.9
  TOP w0.203: U109.83 144.87,51.58 145.27,51.18 ; v3(141.51,51.38) 141.71,51.18 U109.84 145.27,51.18 ; 145.27,51.18 145.45,51 v3(145.45,50.65)
  TOP w0.508: C558.1 138.34,42.42 137.32,43.43 137.32,44.6 v3(137.8,45.09) 138.65,45.09 C1816.1 R1830.2 ; C1818.1 138.65,48.75 R1841.2 138.27,47.75 138.23,47.75 v3(137.85,47.37)
  L4 w0.508: v3(137.8,45.09) 137.85,45.09 v3(137.85,47.37) ; v3(145.45,50.65) 145.45,49.66 144.28,48.49 v3(144.28,48.06)
  BOTTOM w0.508: v3(145.45,50.65) 145.55,50.75 145.55,51.16 145.93,51.54 R399.1 ; R400.1 146.25,48.15 v2(145.47,47.37) 144.97,47.37 v3(144.28,48.06) ; v3(141.51,51.38) 141.42,51.47 R651.1 R709.1 138.65,50.55 C1825.2 C1818.1 138.65,48.75 R1841.2 138.62,48.13 v3(137.85,47.37)
SIO_AMD_SVID_EN: length 4.5
  TOP w0.102: U109.26 159.28,56.38 159.3,56.39 159.87,56.97 159.89,56.97 160.15,57.24 160.15,57.75 v1(160.59,58.19) 161.08,58.67 R308.1
SIO_ATXPG: length 12.1
  TOP w0.102: v3(156.4,51.04) 156.52,51.16 157.11,51.16 157.32,51.37 157.32,52.14 157.57,52.38 U109.16
  BOTTOM w0.102: v3(156.4,51.04) 156.78,51.04 156.97,51.23 v2(157.79,51.23) 158.53,50.5 158.53,48.18 158.23,47.88 157.51,47.88 157.36,48.04 156.92,48.04 156.57,47.69 156.57,47.37 156.51,47.31 R1842.2 R294.2
SIO_AVCC3: length 9
  TOP w0.203: 142.91,45.72 U109.96
  TOP w0.508: 142.91,45.72 142.91,44.7 142.53,44.32 142.53,43.49 142.43,43.39 142.43,43.14 C562.1 142.21,42.74 141.05,41.58 C565.1 140.75,41.4 v1(139.73,40.39) 140.14,39.98 140.16,39.98 140.38,39.75 L60.1
SIO_CE_N: length 43
  TOP w0.102: U7.1 128.94,46.61 129.22,46.33 130.75,46.33 R1823.1 131.35,46.86 131.81,46.41 133.74,46.41 134.02,46.69 v1(134.02,47.24) 134.02,47.83 132.65,49.2 132.65,49.9 132.11,50.43 132.11,52.89 v3(132.31,53.09) ; U109.27 157.52,56.78 156.65,55.91 v3(156.65,55.7)
  L3 w0.127: v3(132.31,53.09) 132.48,53.09 133.01,52.56 133.72,51.84 139.12,51.84 140.72,53.44 147.55,53.44 148.3,54.19 150.49,54.19 150.87,54.57 152.95,54.57 153.36,54.17 154.16,54.17 155.7,55.7 v3(156.65,55.7)
SIO_CLK_DB: length 3.9
  TOP w0.102: U109.48 150.85,61.95 v1(151.39,62.48) 151.68,62.78 151.68,63.58 R79688.1
SIO_COPEN#: length 7.2
  TOP w0.102: v1(138.62,63.75) 138.62,63.53 139.16,62.98 R370.1 139.16,62.39 140.06,61.5 140.78,61.5 142.91,59.37 U109.65
SIO_DAT_DB: length 4
  TOP w0.102: R79687.1 150.46,63.36 150.46,63 v1(150.08,62.62) 150.08,61.87 150.46,61.49 U109.49
SIO_DEBUG_RX: length 3.9
  TOP w0.102: R341.1 155.23,42.48 TP25.1 154.45,43.57 U109.122
SIO_DEBUG_TX: length 3.9
  TOP w0.102: U109.121 154.05,43.56 153.96,43.46 TP26.1 154.36,42.39 154.58,42.39 155.1,41.88 R1829.1
SIO_EUP_EN#: length 325.5
  TOP w0.102: Q1227.D 161.87,40.07 161.03,39.23 160.29,39.23 v3(160.04,38.98) 159.86,38.8 R668.1 R1199.1 ; v3(92.64,63.22) 95.31,63.22 96.81,61.72 99.35,61.72 100.49,60.58 PR62.1 ; R1980.1 89.7,16.87 v3(90.51,17.68)
  L3 w0.127: v3(37.62,81.35) 37.64,81.33 37.83,81.33 38.29,80.87 38.29,79.6 46.31,71.58 60.72,71.58 63.18,74.04 87.16,74.04 89.47,71.73 v3(92.64,71.73) ; v3(90.51,17.68) 90.51,18.47 94.44,22.4 111.6,22.4 117.61,28.41 127.78,28.41 129.12,27.06 137.66,27.06 138.53,26.2 146.55,26.2 152.18,20.57 152.72,20.57 v3(154.52,22.37)
  L4 w0.127: v3(90.51,17.68) 90.51,18.47 91.92,19.88 91.92,20.44 95.17,23.69 95.17,32.82 91.03,36.96 91.03,37.32 90.7,37.65 90.7,48.63 89.32,50.01 88.52,50.81 88.52,57.65 89.28,58.4 89.28,59.25 92.64,62.61 v3(92.64,63.22) v3(92.64,71.73) ; v3(160.04,38.98) 160.31,38.71 160.31,28.16 v3(154.52,22.37) ; v3(20.02,160.9) 21.08,159.84 21.08,154.22 23.66,151.64 23.66,150.21 27.18,146.68 27.18,146.15 35.16,138.18 36.26,138.18 37.3,137.13 37.3,136.49 37.75,136.04 37.75,134.71 37.75,134.4 37.75,134.08 37.75,134.08 37.75,122.91 39.8,120.87 39.8,116.78 39.25,116.23 39.25,115.82 39.42,115.65 39.42,107.12 40.13,106.41 40.13,84.4 37.63,81.89 37.63,81.35 v3(37.62,81.35)
  BOTTOM w0.102: v3(20.02,160.9) 18.6,162.32 17.93,162.32 v2(17.89,162.27) 17.94,162.22 R1764.2
SIO_GREEN: length 206.6
  TOP w0.203: v3(157.03,53.61) 157.34,53.92 157.34,54.9 157.62,55.18 U109.23
  L4 w0.254: v3(157.03,53.61) 158,52.65 158,44.3 158.33,43.97 158.33,43.94 158.94,43.33 158.94,39.78 158.69,39.53 158.69,38.42 159.15,37.96 159.15,36.72 158,35.57 158,34.14 157.01,33.15 157.01,29.72 152.41,25.12 152.41,23.74 v3(152.65,23.5) ; v3(157.77,18.67) 157.21,18.11 154.8,18.11 152.78,16.08 152.78,4.69 149.91,1.83 87.46,1.83 87.1,1.47 84.67,1.47 84.31,1.83 26.14,1.83 24.8,3.17 24.8,8.64 v3(26.96,10.79)
  BOTTOM w0.254: Q9646.2 Q9646.5 25.69,11.11 R80202.2 26.89,10.73 v3(26.96,10.79) ; v3(152.65,23.5) 152.56,23.41 152.56,22.76 153.42,21.89 153.42,19.33 154.26,18.49 v2(155.3,18.49) 156.4,18.49 156.62,18.26 157.36,18.26 v3(157.77,18.67)
SIO_GREEN_PWM: length 198.7
  TOP w0.203: v3(159.7,51.98) U109.15
  TOP w0.254: R723.1 27.85,13.3 27.85,12.7 27.69,12.55 v3(27.69,11.94)
  L4 w0.254: v3(159.7,51.98) 158.66,50.94 158.66,48.39 158.48,48.21 158.48,44.39 158.73,44.14 158.73,44.11 159.35,43.5 159.35,39.61 159.1,39.37 159.1,38.59 159.56,38.13 159.56,36.55 158.48,35.47 158.48,32.72 157.41,31.65 157.41,29.11 153.73,25.43 153.73,24.29 153.32,23.89 v3(153.32,23.04) ; v3(27.69,11.94) 27.69,8.48 27.08,7.87 26.35,7.87 25.46,6.99 25.46,3.23 26.45,2.23 84.48,2.23 84.84,1.87 86.93,1.87 87.29,2.23 149.22,2.23 152.37,5.39 152.37,16.25 154.64,18.52 156.6,18.52 v3(156.88,18.8)
  BOTTOM w0.254: v3(156.88,18.8) 156.5,19.18 154.59,19.18 154.01,19.76 v2(154.01,21.01) 154.01,21.21 153.98,21.23 153.98,22.38 v3(153.32,23.04)
SIO_GREEN_PWM_C_1: length 9.8
  TOP w0.127: R1752.2 29.88,16.13 28.65,14.9 R723.2 28.56,15.04 v3(27.97,15.62)
  BOTTOM w0.127: v3(27.97,15.62) 28,15.59 28,14.45 ; Q1212.G 28,14.45 ; 28,14.45 v2(26.7,15.75) 26.32,16.13 R729.1 25.04,15.67 Q9646.1
SIO_HDD_LED: length 168.1
  TOP w0.102: U109.11 157.4,50.38 v3(157.08,50.7) ; v3(36.1,27.05) 36.1,27.07 36.61,27.58 R1757.2
  L3 w0.127: v3(36.1,27.05) 36.34,26.81 36.85,26.81 36.88,26.78 37.01,26.78 37.95,27.72 43.23,27.72 48.76,33.25 65.85,33.25 68.03,31.08 82.57,31.08 88.39,36.89 90.27,36.89 93.4,33.76 99.19,33.76 100.54,32.41 108.24,32.41 108.92,31.73 109.71,31.73 110.42,32.44 117.64,32.44 119.18,30.9 129.21,30.9 129.62,31.32 131.95,31.32 v3(132.27,31) ; v3(132.93,48.27) 133.5,47.7 136.73,47.7 137.12,48.09 139.91,48.09 140.63,48.82 142.07,48.82 142.53,49.28 147.12,49.28 147.78,49.94 149.56,49.94 150.59,50.97 153.46,50.97 153.89,51.4 154.6,51.4 154.86,51.13 155.63,51.13 156.19,50.57 156.95,50.57 v3(157.08,50.7)
  L4 w0.127: v3(132.93,48.27) 132.35,47.7 132.35,42.28 131.17,41.09 131.17,32.31 132.24,31.24 132.24,31.03 v3(132.27,31)
  BOTTOM w0.102: v3(36.1,27.05) 35.72,27.05 35.09,27.69 33.98,27.69 30.13,31.54 v2(30.13,31.88) 28.61,31.88 27.92,31.19 27.92,30.01 27.65,29.74 26.22,29.74 25.62,29.15 R1753.1
SIO_HDD_LED_1: length 2.7
  BOTTOM w0.102: Q1214.B 25.12,30.29 v2(24.67,29.84) 24.67,28.77 R1753.2
SIO_HOLD#: length 3.6
  TOP w0.102: R644.1 120.7,47 121.01,46.69 121.32,46.69 v1(121.37,46.74) 122.51,47.88 U7.7
SIO_INT#: length 76.4
  TOP w0.102: v3(101.47,56.62) 101.94,57.09 R80212.1 ; R80208.1 147.29,38.67 v1(147.61,38.35) 148.1,37.86 v3(148.1,37.48)
  L3 w0.127: v3(109.38,39.32) 110.18,40.12 112.34,40.12 113.75,38.71 116.99,38.71 117.98,37.72 121.45,37.72 121.68,37.48 137.75,37.48 139.15,36.08 139.15,32.26 139.43,31.99 139.86,31.99 143.6,35.73 143.82,35.73 144.86,36.77 147.08,36.77 147.79,37.48 v3(148.1,37.48)
  L4 w0.127: v3(109.38,39.32) 109.66,39.6 109.66,41.66 110.84,42.84 110.84,42.84 111.12,43.11 111.12,43.5 111.03,43.59 111.03,50.29 105.43,55.89 102.19,55.89 v3(101.47,56.62)
  BOTTOM w0.102: U4101.39 101.67,56.81 v3(101.47,56.62)
SIO_INT_C: length 7.1
  TOP w0.102: R80208.2 148.37,39.69 v1(148.37,40.51) 148.01,40.87 148.01,42.56 147.4,43.18 146.46,43.18 145.66,43.99 U109.100
SIO_LVDS_BL_ADJ: length 248.2
  TOP w0.165: R312.1 161.64,47.79 161.12,48.31 161.12,48.59 160.19,49.52 159.76,49.52 159.3,49.98 U109.10 156.4,49.98 v3(156.37,50.01) ; R131.2 46.65,35.9 47.02,36.27 v3(47.02,36.86)
  L3 w0.165: v3(26.5,34.42) 26.65,34.56 45.31,34.56 47.02,36.27 v3(47.02,36.86) 47.61,36.86 48.27,37.52 54.17,37.52 54.66,37.03 63.12,37.03 63.3,36.85 64.02,36.85 64.53,37.36 64.53,37.52 72.19,45.18 84.2,45.18 89.32,40.06 89.65,40.06 90.76,38.94 92.77,36.93 106.33,36.93 106.43,36.82 108.56,36.82 111.07,34.32 112.33,34.32 113.8,35.79 117.66,35.79 118.14,35.31 129.8,35.31 131.06,34.04 136.27,34.04 139.1,31.21 140.18,31.21 143.54,34.56 144.11,34.56 144.58,35.03 145.28,35.74 148.59,35.74 151.86,39.01 154.04,39.01 154.06,39.03 155.67,39.03 156.04,38.66 v3(157.01,38.66) ; v3(34.32,81.99) 34.32,82.47 34.83,82.98 34.83,89.9 35.09,90.15 35.09,101.17 33.86,102.39 33.86,104.8 v3(34.27,105.21)
  L4 w0.165: v3(157.01,38.66) 157.01,38.86 157.41,39.26 157.41,39.26 157.92,39.77 157.92,39.85 158.01,39.95 158.01,43.16 157.22,43.95 157.22,46.77 156.52,47.48 156.52,49.86 v3(156.37,50.01) ; v3(34.32,81.99) 34.32,81.57 33.39,80.63 33.39,77.08 32.72,76.4 32.72,74.44 32.72,73.6 31.73,72.61 26.96,67.85 26.96,55.54 30.93,51.58 30.93,44.05 26.1,39.22 26.1,34.79 26.47,34.42 v3(26.5,34.42)
  BOTTOM w0.165: v3(34.27,105.21) 34.92,105.85 R503.1 ; v3(47.02,36.86) 47.02,36.37 46.44,35.79 v2(46.44,35.71)
SIO_MAIN_VCC3: length 7.7
  TOP w0.203: U109.89 141.35,49.18 v1(140.06,50.47) 139.54,50.99 R1837.1
  TOP w0.508: Q107.D 136.75,50.67 137.07,50.99 R1837.1
SIO_MEM_EVENT_L: length 153.5
  TOP w0.102: R683.2 149.89,63.3 149.44,62.84 149.44,62.79 v3(149.13,62.48) 149.11,62.48 148.86,62.23 U109.53
  L4 w0.127: v3(155.89,96.77) 155.35,96.24 155.35,92.91 155.17,92.72 155.17,89.46 153.1,87.39 153.1,76.46 152.43,75.8 152.43,73.79 149.69,71.04 149.69,69.19 149.82,69.06 149.82,63.17 v3(149.13,62.48) ; v3(156.04,129.37) 156.51,128.9 156.51,125.84 155.27,124.59 155.27,120.52 151.92,117.17 151.92,107.48 150.68,106.23 150.68,102.01 150.14,101.47 150.14,99.28 v3(150.61,98.81)
  BOTTOM w0.102: R1585.1 109.44,156.02 109.94,155.52 109.94,138.98 118.13,130.79 124.51,130.79 131.09,124.21 151.2,124.21 155.58,128.59 155.58,128.92 v3(156.04,129.37) ; v3(150.61,98.81) 152.66,98.81 v2(154.29,97.18) 154.69,96.77 v3(155.89,96.77)
SIO_MEM_EVENT_L_B: length 4.2
  BOTTOM w0.102: R1586.2 106.09,156.91 105.62,157.38 v2(105.62,157.76) 105.62,158.01 105.88,158.27 Q1207.B
SIO_MEM_EVENT_L_C: length 3.8
  BOTTOM w0.102: v2(109.89,156.84) 109.82,156.91 R1585.2 108.62,158.94 Q1207.C
SIO_PCIRSTIN#: length 5.8
  TOP w0.102: R317.1 160.18,42.99 v1(160.36,43.16) 158.69,44.83 U109.128
SIO_PSON_N: length 16.7
  TOP w0.102: Q107.G 134.62,51.24 R1844.2 133.38,51.41 v1(134.42,52.45) 134.42,52.5 134.4,52.53 v3(134.4,53.47) ; U109.73 143.8,55.58 v3(144.2,55.18)
  L3 w0.127: v3(134.4,53.47) 135.03,52.83 138.71,52.83 140.31,54.43 143.16,54.43 143.9,55.18 v3(144.2,55.18)
SIO_PWNBTN_N: length 277
  TOP w0.102: v4(54.87,161.67) 55.02,161.82 55.02,161.87 55.84,162.69 R1653.1 ; v3(135.83,56.99) 136.37,57.53 R379.1 R375.2
  L3 w0.127: v4(54.87,161.67) 53.88,161.67 52.36,163.19 39.71,163.19 37.96,164.94 26.93,164.94 24.7,167.17 16.11,167.17 13.21,164.26 13.21,155.02 16.15,152.08 16.15,141.26 18.09,139.32 29.02,139.32 32.1,139.32 36.36,135.06 36.36,117.02 37.64,115.73 37.64,110.21 40.88,106.97 40.88,80.66 45.21,76.33 55.02,76.33 57.31,78.61 61.67,78.61 62.31,77.97 70.18,77.97 71.31,79.1 77.38,79.1 78.43,78.04 89.33,78.04 93.5,82.21 104.69,82.21 105.1,81.8 105.1,80.43 106.83,78.7 108.36,78.7 109,78.07 109,74.9 110.65,73.25 110.65,72.81 111.08,72.38 112.32,71.15 113,70.46 114.36,70.46 117.44,67.39 124.66,67.39 124.85,67.2 132.54,67.2 132.72,67.37 133.31,67.37 134.57,68.63 v3(135.03,68.63)
  BOTTOM w0.102: v3(135.83,56.99) 135.8,57.03 135.8,57.4 134.04,59.16 134.04,63.17 135.8,64.92 v2(135.8,65.87) 135.8,66.88 135.03,67.64 v3(135.03,68.63)
SIO_SCK: length 73.2
  TOP w0.102: U7.6 121.85,49.15 121.47,48.77 C1823.1 R650.1 120.57,49.78 120.11,49.33 119.22,49.33 119.15,49.4 118.77,49.4 118.5,49.14 118.5,47.42 120.89,45.03 v3(120.89,44.22) ; R306.2 v3(163.33,55.63)
  L3 w0.127: v3(163.89,44.17) 163.99,44.07 163.99,43.05 163.48,42.55 161.61,42.55 161.15,43.01 157.06,43.01 156.59,42.55 154.47,42.55 153.09,43.92 152.07,43.92 151.98,44.01 151.6,44.01 151.51,43.92 150.76,43.92 149.88,43.04 149.6,43.04 149.33,43.32 149.02,43.32 148.93,43.41 144.18,43.41 143.78,43 136.76,43 136.08,42.31 128.46,42.31 127.76,43.01 127.76,43.05 126.89,43.92 121.32,43.92 121.01,44.22 v3(120.89,44.22)
  L4 w0.127: v3(163.33,55.63) 163.33,55.47 163.8,55 163.8,52.07 164.59,51.28 164.59,47.85 163.93,47.19 163.93,45.09 163.82,44.99 163.82,44.29 163.91,44.2 163.91,44.18 v3(163.89,44.17)
  BOTTOM w0.102: v2(120.28,44.91) 120.89,44.3 v3(120.89,44.22)
SIO_SCK_R: length 3.6
  TOP w0.102: U109.22 159.15,54.78 159.54,55.17 v1(160.63,55.17) 160.89,55.17 161.35,55.63 R306.1
SIO_SI: length 69
  TOP w0.102: U109.21 159.36,54.38 159.65,54.67 v3(159.7,54.67) ; v3(118.53,45.72) 118.53,45.73 117.61,46.65 117.61,48.97 118.07,49.43 118.07,50.29 119.07,51.3 120.2,51.3 R655.1 121.08,50.42 U7.5
  L3 w0.127: v3(118.53,45.72) 118.69,45.88 120.78,45.88 122.5,44.17 127.03,44.17 127.74,43.46 130.56,43.46 130.77,43.26 143.67,43.26 144.08,43.66 149.04,43.66 149.13,43.57 150.05,43.57 150.88,44.4 v3(160.84,44.4)
  L4 w0.127: v3(159.7,54.67) 159.84,54.67 161.77,52.74 161.77,46.8 160.37,45.4 160.37,44.87 v3(160.84,44.4)
  BOTTOM w0.102: v3(160.84,44.4) 160.87,44.37 v2(160.87,43.59)
SIO_SMB2_CLK: length 8.8
  TOP w0.102: U109.63 144.85,61.31 144.54,61.62 141.16,61.62 140.93,61.85 140.57,61.85 v1(140.2,62.22) 139.91,62.51 v3(139.91,63.12) 139.91,63.77 R715.2
  BOTTOM w0.102: R715.2 139.91,63.77 v3(139.91,63.12)
SIO_SMB2_DATA: length 7.9
  TOP w0.102: R716.2 v3(140.75,63.14) 141.26,62.64 v1(141.93,62.64) 142.59,61.98 144.69,61.98 145.25,61.41 U109.62
  BOTTOM w0.102: R716.2 v3(140.75,63.14)
SIO_SMCLK0: length 220
  TOP w0.102: RN9.4 142.6,63.43 143.29,62.74 144.94,62.74 146.06,61.62 U109.60 146.01,60.28 146.01,59.34 145.65,58.98 145.65,58.75 145.23,58.33 v3(145.23,58.25) ; v3(39.77,71.94) 39.32,72.39 R60.2 ; R79633.2 39.73,30.95 v3(39.37,30.58)
  L3 w0.127: v3(143.42,36.7) 143.42,36.8 142.95,37.27 142.95,37.38 140.5,39.83 139.2,39.83 137.77,38.39 122.05,38.39 121.84,38.61 118.35,38.61 117.36,39.6 114.12,39.6 112.71,41.01 106.36,41.01 105.84,41.53 100.3,41.53 99.74,40.97 97.18,40.97 95.77,42.38 95.77,44.48 95.09,45.15 87.9,45.15 85.27,47.78 79.31,47.78 v3(77.45,49.63)
  L4 w0.127: v3(39.77,71.94) 37.93,70.1 37.93,69.07 36.38,67.53 34.96,67.53 33,65.57 33,64.28 32.62,63.9 32.62,62.88 33,62.5 33,62.02 32.63,61.65 32.63,60.63 33,60.26 33,56.99 36.37,53.62 36.37,51.13 36.67,50.83 36.67,37.87 34.83,36.03 34.83,32.87 36.58,31.11 37.37,31.11 38.32,30.16 38.95,30.16 v3(39.37,30.58) ; v3(143.42,36.7) 143.67,36.7 144.27,37.3 144.27,39.59 143.71,40.15 143.71,48.92 144.18,49.39 144.18,50.89 145.92,52.63 145.92,55.53 145.23,56.22 145.23,57.2 145.39,57.36 145.39,57.75 145.23,57.91 v3(145.23,58.25)
  BOTTOM w0.102: v3(39.77,71.94) 41.7,70 65.55,70 68.06,67.49 74.81,67.49 75.37,66.93 78.14,66.93 79.66,65.41 79.66,64.62 77.88,62.84 77.88,55.99 77.5,55.61 v2(77.5,52.58) 77.63,52.45 77.63,49.81 v3(77.45,49.63)
SIO_SMCLK0_D: length 23.1
  TOP w0.102: R60.1 36.53,73.55 36.53,74.36 36.86,74.68 36.87,74.68 v1(37.22,75.03) 37.45,75.26 50.5,75.26 51.62,74.14 v3(51.62,73.01) ; v3(54.44,73.01) Q95.3
  L3 w0.127: v3(51.62,73.01) v3(54.44,73.01)
SIO_SMDAT0: length 233.1
  TOP w0.102: R79634.2 38.69,30.72 v3(38.61,30.63) ; RN9.3 141.95,63.44 143.04,62.36 144.81,62.36 145.66,61.51 U109.61 145.66,59.49 v3(145.19,59.03) ; v3(41.21,71.73) 41.63,72.15 41.63,73.34 42.83,74.55 50.21,74.55 50.81,73.95 50.81,72.42 50.96,72.27 R43.2
  L3 w0.127: v3(78.21,49.63) 78.21,49.41 79.46,48.16 85.43,48.16 88.06,45.53 95.25,45.53 96.15,44.63 96.15,42.54 97.33,41.35 99.58,41.35 100.14,41.91 105.99,41.91 106.52,41.39 112.87,41.39 114.28,39.98 117.51,39.98 118.51,38.99 121.99,38.99 122.21,38.77 137.61,38.77 139.05,40.21 140.67,40.21 v3(143.42,37.47)
  L4 w0.127: v3(38.61,30.63) 37.61,31.62 36.76,31.62 35.31,33.07 35.31,35.98 37.82,38.48 37.82,40.16 37.07,40.9 37.07,50.97 36.75,51.29 36.75,53.78 33.38,57.14 33.38,60.42 33.01,60.78 33.01,61.49 33.38,61.86 33.38,62.66 33,63.04 33,63.75 33.5,64.24 33.88,64.24 34.95,65.31 34.95,65.88 36.21,67.14 36.57,67.14 40.71,71.29 40.76,71.29 v3(41.21,71.73) ; v3(143.42,37.47) 143.89,37.93 143.89,39.43 143.33,39.99 143.33,49.08 143.8,49.55 143.8,51.05 145.54,52.79 145.54,55.37 144.31,56.6 144.31,57.63 144.69,58.01 144.69,58.52 v3(145.19,59.03)
  BOTTOM w0.102: v3(41.21,71.73) 41.21,71.7 42.55,70.36 65.69,70.36 68.21,67.84 75.43,67.84 76.65,69.06 77.91,69.06 78.24,68.73 81.06,68.73 81.85,67.94 81.85,66.3 78.24,62.69 78.24,55.37 v2(78.27,55.35) 78.27,49.68 v3(78.21,49.63)
SIO_SMDAT0_D: length 3.8
  TOP w0.102: R43.1 50.96,69.98 51.37,69.57 v1(51.82,69.57) 52.13,69.57 52.56,70 Q95.6
SIO_SO: length 45.1
  TOP w0.102: R645.1 129.83,48.01 129.8,47.98 v3(129.7,47.98) 129.6,47.88 U7.2 ; U109.45 152.05,61.45 152.85,62.24 v3(152.85,62.74)
  L3 w0.127: v3(129.95,61.21) 130.08,61.09 135.74,61.09 135.98,61.33 136.37,61.33 136.52,61.18 140.58,61.18 142.48,63.08 142.84,63.08 143.39,63.63 151.96,63.63 v3(152.85,62.74)
  L4 w0.127: v3(129.7,47.98) 129.7,48.62 129.84,48.76 129.84,52.07 130.31,52.54 130.31,56.05 129.84,56.52 129.84,61.1 v3(129.95,61.21)
  BOTTOM w0.102: v3(129.95,61.21) v2(129.95,60.38)
SIO_VCORE: length 5.6
  TOP w0.203: U109.33 157.51,60.33 158.02,60.83
  TOP w0.508: 158.02,60.83 158.15,60.96 158.15,61.64 v1(159.13,62.63) 159.13,62.83 159.16,62.87 C548.2 C549.2
SIO_VIN1: length 8.4
  TOP w0.102: U109.94 141.95,47.18 141.61,46.84 141.61,46.02 v3(140.88,45.29) 139.03,43.45 R80215.1 138.59,43.43 v1(138.08,43.94)
  BOTTOM w0.102: R80216.2 141.64,44.4 140.88,45.16 v3(140.88,45.29)
SIO_VIN2: length 2.9
  TOP w0.203: TP28.1 141.21,46.56 141.21,47.01 141.78,47.58 U109.93
SIO_VIN3: length 8
  TOP w0.203: R1830.1 139.73,46.1 141.61,47.98 U109.92
  TOP w0.508: R1830.1 C1816.2 138.53,46.04 138.44,45.95 v1(137.22,45.95) 136.34,45.95 R1833.1
SIO_VIN4: length 7.3
  TOP w0.203: U109.91 141.25,48.38 v3(140.88,48.01)
  BOTTOM w0.508: v3(140.88,48.01) 139.99,47.12 R689.1 R1835.1 139.71,48.13 140.5,48.92 v2(140.5,49.02) 140.37,49.15 C1817.2
SIO_VIN5: length 5.6
  TOP w0.203: C1818.2 140.42,49.15 v1(140.72,48.84) 140.79,48.78 U109.90
  TOP w0.508: C1818.2 R1841.1 R1838.1
SIO_VREF: length 11.1
  TOP w0.203: U109.88 141.97,49.58 141.51,50.04 141.51,50.23 v3(141.45,50.29)
  BOTTOM w0.254: v3(141.45,50.29) 141.27,50.11 C1825.1 ; v3(141.45,50.29) 141.45,50.24 142.24,49.45 v2(144.67,49.45) R404.2 R397.2 ; v3(141.45,50.29) 141.57,50.42 R658.2
SIO_WP#: length 3.5
  TOP w0.102: U7.3 129.52,49.15 v1(129.83,48.84) 130.13,49.15 R1824.1
SIO_WRST#: length 9.7
  TOP w0.102: v3(149.59,58.06) 149.84,58.06 151.25,59.48 U109.47 151.25,61.47 152.04,62.26 152.04,63.07 152.51,63.55 152.8,63.55 R353.2
  BOTTOM w0.102: C190.1 149.41,58.06 v3(149.59,58.06) 150.45,58.06 v2(150.5,58.01)
SIO_YELLOW: length 188.6
  TOP w0.203: U109.7 159.36,48.78 159.75,48.4 v3(159.76,48.4)
  TOP w0.254: v1(153.45,20.45) 153.42,20.45 153.12,20.75 153.06,20.75 152.6,21.21 v3(152.43,21.21)
  L3 w0.254: v3(28.23,16.51) 28.74,17.02 30.26,17.02 30.84,17.6 33.51,17.6 36.96,21.06 36.96,21.53 38.13,22.69 42.72,22.69 46.06,26.04 46.06,28.91 49.37,32.22 65.43,32.22 67.6,30.05 90.45,30.05 93.08,32.68 99.27,32.68 101.73,30.22 109.67,30.22 111.19,31.74 116.35,31.74 118.05,30.03 129.8,30.03 130.41,29.43 137.66,29.43 139.09,27.99 140.28,27.99 140.6,28.31 145.11,28.31 152.21,21.21 v3(152.43,21.21)
  L4 w0.254: v3(26,24.7) 26.58,24.13 27.43,24.13 27.74,23.82 27.74,20.42 28.23,19.94 v3(28.23,16.51) ; v3(152.43,21.21) 153.86,22.63 153.86,23.85 154.13,24.12 154.13,25.26 157.82,28.94 157.82,31.48 158.88,32.55 158.88,35.31 159.96,36.39 159.96,38.3 159.51,38.76 159.51,39.2 159.75,39.45 159.75,43.66 159.14,44.28 159.14,44.3 158.88,44.56 158.88,47.85 159.43,48.4 v3(159.76,48.4)
  BOTTOM w0.254: v3(26,24.7) Q68.G 24.67,24.99 R731.2 ; v3(28.23,16.51) 28.04,16.7 R1761.2
SKEW1: length 19.6
  TOP w0.102: v3(81.57,138.94) 81.82,139.19 R1688.1 R1687.2 ; v4(81.2,153.3) 80.8,153.7 CPU1.AT14
  L3 w0.127: v4(81.2,153.3) 81.62,152.88 81.62,150.89 81.43,150.7 81.43,148.83 81.09,148.48 81.08,148.38 81.08,144.88 80.84,144.65 80.84,139.66 v3(81.57,138.94)
  BOTTOM w0.102: v2(80.75,139.55) 81.36,138.94 v3(81.57,138.94)
SKEW2: length 9.5
  TOP w0.102: R160.2 R154.1 72.11,142.3 73.16,143.36 v1(73.16,143.54) 73.16,144.12 75.19,146.15 75.19,147.86 75.3,147.97 75.3,148.28 75.29,148.29 75.29,148.61 CPU1.BB7
SKEW3: length 7.6
  TOP w0.102: R1684.2 R1685.1 71.81,144.35 72.19,144.35 v1(72.65,144.81) 73.27,145.43 74.19,145.43 74.99,146.23 74.99,147.95 75,147.96 CPU1.BC7
SLEEVE: length 39.2
  TOP w0.203: v3(163.57,73.69) 163.19,74.07 U6.32
  TOP w0.406: R272.2 158.78,71.69 C160.1
  TOP w0.508: v3(165.64,67.94) 165.63,67.93 Q28.D ; C160.1 158.66,72.52 v3(158.73,72.59)
  L3 w0.508: UHS1.4 182.92,72.77 175.7,72.77 174.34,74.13 168.24,74.13 167.04,72.92 165.01,72.92 164.25,73.69 v3(163.57,73.69)
  BOTTOM w0.508: v3(158.73,72.59) 159.37,73.23 159.51,73.23 159.61,73.33 160.24,73.33 160.43,73.14 161.95,73.14 162.49,73.69 v3(163.57,73.69) 164.37,73.69 165.4,72.66 v2(165.62,72.66) 165.63,72.66 166.17,72.12 Q24.1 165.64,68.52 v3(165.64,67.94)
SLEEVE_G: length 11.7
  TOP w0.102: Q31.C 162.35,67.93 v3(163.1,67.18) 163.64,66.64 Q28.G 163.64,64.36 163.99,64.01 164.24,64.01 v1(164.46,63.79)
  BOTTOM w0.102: R322.1 164.73,63.67 R319.2 164.74,63.89 163.1,65.53 v3(163.1,67.18)
SLP_S3_N: length 334.8
  TOP w0.102: R718.1 38.01,146.56 v3(38.51,147.07) ; R2078.2 45.22,164.66 44.78,164.22 v1(43,164.22) 40.54,164.22 v3(39.91,164.85) 41.05,165.99 42.83,165.99 43.4,166.56 R2017.1 ; R1184.2 58.33,148.4 v3(58.33,147.83) 58.33,147.49 57.09,146.25 53.35,146.25 v3(52.05,147.55) ; v3(140.65,13.88) 140.65,13.06 141.5,12.22 R1878.2 ; R1809.1 v3(141.38,71.15) ; v3(61.52,138.7) 61.88,138.34 61.88,137.03 62.39,136.53 R2053.1 ; v3(144.22,58.21) 144.22,58.08 143.72,57.58 U109.68
  L3 w0.127: v3(38.51,147.07) 50.67,147.07 51.15,147.55 v3(52.05,147.55) ; v3(141.38,71.15) 141.38,71.37 145.04,75.03 145.04,75.84 146.3,77.1 146.3,104.14 144.77,105.67 131.8,105.67 118.34,119.13 108.1,119.13 107.92,118.95 88.3,118.95 81.57,125.68 79.94,125.68 69.84,135.78 67.33,135.78 65.59,137.52 62.53,137.52 61.52,138.52 v3(61.52,138.7) ; v3(93,57.53) 93.31,57.85 105.38,57.85 107.12,56.11 109.74,56.11 110.61,56.98 111.91,56.98 113.67,58.75 130.89,58.75 132.15,57.49 137.11,57.49 137.53,57.91 143.91,57.91 v3(144.22,58.21)
  L4 w0.127: v3(58.33,147.83) 58.33,146 59.76,144.56 59.76,140.46 v3(61.52,138.7) ; v3(39.91,164.85) 43.05,161.71 43.05,160.31 52.05,151.31 v3(52.05,147.55) ; v3(144.22,58.21) 144.22,58.21 143.42,57.41 143.42,49.71 142.95,49.24 142.95,33.77 138.97,29.79 138.97,28.81 138.88,28.72 138.88,28.33 138.97,28.24 138.97,25.91 141.77,23.11 141.77,14.99 v3(140.65,13.88)
  BOTTOM w0.102: R79712.1 93.65,57.66 93.55,57.56 93.02,57.56 v3(93,57.53) ; v3(141.38,71.15) 141.38,70.46 141.33,70.41 141.33,60.45 140.88,59.99 140.88,58.47 141.77,57.58 143.59,57.58 144.22,58.2 v3(144.22,58.21)
SLP_S3_N_1: length 3.8
  TOP w0.102: v1(57.84,145.8) 57.87,145.82 57.94,145.82 D20.2 59.25,147.86 59.66,148.27 R1184.1
SLP_S3_N_EC: length 4.1
  BOTTOM w0.102: U4101.30 96.77,56.68 96.43,57.02 96.43,57.53 v2(96.05,57.91) 95.09,57.91 R79712.2
SLP_S3_N_G: length 2.6
  TOP w0.102: R2053.2 62.39,134.16 v1(62.44,134.11) 62.63,133.92 Q78.G
SLP_S3_N_R: length 41
  TOP w0.102: v3(54.1,162.21) 53.46,162.21 50.53,159.28 50.53,158.47 49.74,157.68 49.07,157.68 47.99,158.76 47.99,158.96 47.54,159.41 46.77,159.41 45.63,160.55 v1(45.63,162.43) 45.63,163.29 46.01,163.67 ; 46.01,163.67 R2078.1 ; 46.01,163.67 47.05,163.67 47.44,163.29 Q1244.G ; v4(74.6,158.4) 74.6,158.7 CPU1.AK7
  L3 w0.127: v4(74.6,158.4) 74.05,158.95 72.73,158.95 72.57,159.12 70.73,159.12 70.06,159.78 68.2,159.78 68.05,159.93 63.47,159.93 63.37,159.83 59.78,159.83 59.02,160.59 59.02,160.62 57.81,161.84 57.69,161.84 57.32,162.21 v3(54.1,162.21)
SLP_S3_N_R3: length 2.6
  TOP w0.102: U109.76 142.17,54.38 TP215.1
SLP_S3_N_R_1: length 10.1
  TOP w0.102: Q1243.S 49.4,159.03 50.78,160.41 v1(50.78,160.86) 50.73,160.86 50.53,161.06 49.4,161.06 48.42,162.05 Q1244.D 48.55,164.15 R2019.1
SLP_S3_N_R_2: length 13.5
  TOP w0.102: Q1243.D 46.5,160.34 46.24,160.6 v1(46.24,160.73) 46.24,161.16 46.57,161.49 47.89,161.49 47.99,161.6 47.99,163.07 47.86,163.2 47.86,165.49 R2018.1 R2019.2 49.4,165.89 Q1245.G
SLP_S3_N_R_3: length 4.7
  TOP w0.102: Q1245.D 47.15,167.07 46.77,167.45 R2017.2 R2065.1 45.01,168.59 v1(45.01,168.59)
SLP_S5_N: length 387.9
  TOP w0.102: v3(93.43,20.08) 93.41,20.09 92.83,20.09 92.36,20.56 92.36,21.34 92.49,21.46 Q1217.5 ; v3(139.1,70.84) 139.53,70.41 142.02,70.41 v1(142.43,70.82) 142.65,71.04 R1808.1 ; CPU1.AH5 73,159.9 v4(73,159.6) ; v3(135.77,56.2) 135.77,56.19 137.47,54.48 R372.2
  L3 w0.127: v4(73,159.6) 72.97,159.58 71.67,159.58 71.01,160.24 68.62,160.24 68.17,160.7 66.13,160.7 65.63,161.2 61.27,161.2 61.21,161.25 59.7,161.25 58.74,162.22 57.85,162.22 57.33,162.74 54.08,162.74 53.25,163.57 39.87,163.57 38.12,165.32 27.09,165.32 24.86,167.55 15.96,167.55 12.83,164.42 12.83,154.86 15.77,151.92 15.77,141.1 17.93,138.94 29.18,138.94 35.97,132.14 35.97,116.86 37.26,115.58 37.26,110.05 40.5,106.81 40.5,80.5 45.05,75.95 60.85,75.95 61.77,76.87 69.62,76.87 71,78.25 73.08,78.25 74.04,77.29 89.12,77.29 93.66,81.83 104.3,81.83 104.72,81.41 104.72,80.27 106.67,78.32 108.2,78.32 108.62,77.91 108.62,74.74 109.76,73.6 109.76,72.36 110.07,72.05 110.56,72.05 113.62,68.98 v3(114.03,68.98) ; v3(90.97,57.87) 90.99,57.85 91.92,57.85 92.7,57.06 93.57,57.06 93.98,57.47 104.74,57.47 105.07,57.14 107.6,54.61 v3(108.24,54.61) 109.27,54.61 110.33,55.66 111.13,55.66 113.63,58.17 v3(119.29,58.17) 119.48,58.36 130.75,58.36 131.99,57.11 134.86,57.11 v3(135.77,56.2)
  L4 w0.127: v3(90.97,57.87) 91.11,57.73 91.11,55.64 91.96,54.8 91.96,44.77 91.72,44.53 91.72,44.14 96.55,39.31 96.55,23.2 v3(93.43,20.08) ; v3(139.1,70.84) 139,70.84 135.2,67.05 135.2,56.96 135.77,56.39 135.77,56.2 v3(135.77,56.2) ; v3(119.29,58.17) 119.29,59.82 116.87,62.23 116.87,66.02 114.9,67.99 114.9,68.11 v3(114.03,68.98)
  BOTTOM w0.102: R79713.1 110.01,55.5 109.56,55.04 108.8,55.04 108.36,54.61 v3(108.24,54.61)
SLP_S5_N_C: length 4.9
  TOP w0.102: U109.74 141.77,55.18 140.91,56.03 v1(140.37,56.03) 139.68,55.35 139.68,55.28 139.16,54.76 R372.1
SLP_S5_N_EC: length 4.4
  BOTTOM w0.102: U4101.51 107.55,56.68 108.11,56.12 108.57,56.12 R79713.2 109.38,55.69 109.38,55.88 109.91,56.41 v2(109.91,56.43)
SMB0_CLK: length 356.1
  TOP w0.102: v3(140.88,127.25) 140.28,127.85 DIMM1.202 ; v3(79.38,69.52) 79.38,69.75 78.53,70.6 U6701.4 78.53,71.35 78.81,71.63 80.17,71.63 82.33,73.79 v3(82.33,75.56) 82.33,79.82 v3(87.5,84.99) ; v3(156.04,127.85) DIMM2.202 152.78,127.85 v3(152.18,127.25) ; Q123.6 101.91,98.18 101.91,99.21 102.22,99.52 104.02,99.52 104.63,98.91 104.63,94.44 104.81,94.26 107.16,94.26 107.47,93.95 107.47,92.44 106.56,91.53 106.56,90.65 105.95,90.04 104.94,90.04 104.01,89.11 103.5,89.11 102.17,87.78 v3(102.17,85.72) ; R162.1 82.33,145.27 v4(82.31,145.29) 82.31,145.35 81.7,145.96 81.7,146.55 81.3,146.96 81.3,147.78 81.1,147.97 81.1,148.23 81.11,148.23 81.11,148.71 81.1,148.72 81.1,149.03 81.4,149.33 CPU1.BA15
  L3 w0.127: v3(152.18,127.25) 151.71,127.72 146.1,127.72 145.72,128.1 141.73,128.1 v3(140.88,127.25)
  L4 w0.127: v3(102.17,85.72) 101.32,86.58 97.73,86.58 96.93,87.38 89.89,87.38 v3(87.5,84.99) ; v4(82.31,145.29) 81.22,144.19 72.68,144.19 71.03,142.54 71.03,141.48 69.63,140.08 69.63,136.24 65.34,131.95 63.58,131.95 57.69,126.07 57.69,125.43 55.89,123.63 53.53,123.63 53.03,124.14 53.03,124.95 51.23,126.75 50.18,126.75 48.56,125.13 48.56,122.31 46.26,120.02 46.26,83.79 56.4,73.65 66.97,73.65 67.98,72.64 79.76,72.64 82.33,75.21 v3(82.33,75.56)
  BOTTOM w0.102: v4(82.31,145.29) 83,145.29 83.63,144.65 84.06,144.65 84.18,144.53 86.52,142.19 v2(86.52,141.86) 86.75,141.63 86.75,141.45 88.09,140.11 88.09,137.13 92.11,133.12 114.77,133.12 117.83,130.06 124.21,130.06 130.79,123.48 151.67,123.48 v3(156.04,127.85) ; Q7.4 31.63,74.45 32.49,73.58 35.31,73.58 35.54,73.36 40.34,73.36 42.98,70.71 65.84,70.71 68.36,68.2 75.28,68.2 76.5,69.42 78.06,69.42 78.39,69.09 78.95,69.09 v3(79.38,69.52)
SMB0_CVT_CLK: length 5.5
  TOP w0.102: R79633.1 39.73,33.1 v3(39.38,33.45) 39.15,33.68 C3456.1
  BOTTOM w0.102: U120.6 38.37,34.23 38.87,33.73 39.1,33.73 v3(39.38,33.45) v2(40.95,33.45)
SMB0_CVT_DATA: length 5.5
  TOP w0.102: R79634.1 38.69,32.97 v3(38.29,33.38) 38.26,33.4 C43.1
  BOTTOM w0.102: U120.7 37.87,33.84 38.29,33.43 v3(38.29,33.38) 38.44,33.38 38.95,32.87 39.67,32.87 v2(39.85,32.69)
SMB0_DATA: length 347.7
  TOP w0.102: v3(141.64,127.25) 140.44,128.45 DIMM1.200 ; v3(151.42,127.25) 152.61,128.45 DIMM2.200 155.88,128.45 v3(156.04,128.61) ; v3(88.3,85.09) 88.3,85.14 88.02,85.42 87.1,85.42 83.48,81.8 83.48,81.7 83.15,81.37 83.06,81.37 81.57,79.88 v3(81.57,75.56) 81.57,73.53 80.02,71.98 78.66,71.98 78.3,71.63 76.62,71.63 76.35,71.36 76.35,70.87 76.83,70.4 U6701.6 78.23,70.4 78.62,70.01 v3(78.62,69.55) ; R1673.1 84.36,144.5 v4(83.8,145.06) 82.72,146.14 82.72,147.95 82.7,147.97 82.7,149.83 83,150.13 CPU1.AY17 ; Q123.3 104.06,94.4 104.56,93.9 107.01,93.9 107.11,93.8 107.11,92.58 106.21,91.68 106.21,90.8 105.83,90.42 104.81,90.42 103.86,89.47 103.15,89.47 101.81,88.13 101.81,86.18 v3(101.35,85.72)
  L3 w0.127: v3(151.42,127.25) 150.58,126.42 146.87,126.42 145.56,127.72 142.21,127.72 141.74,127.25 v3(141.64,127.25)
  L4 w0.127: v3(101.35,85.72) 100.88,86.19 97.79,86.19 96.84,87.15 90.1,87.15 88.3,85.34 v3(88.3,85.09) ; v3(81.57,75.56) 81.57,75.5 79.09,73.03 68.14,73.03 67.13,74.03 56.56,74.03 46.64,83.95 46.64,119.81 48.94,122.11 48.94,124.97 50.34,126.36 51.07,126.36 52.65,124.79 52.65,123.76 53.22,123.19 56.49,123.19 58.07,124.77 58.07,125.91 63.74,131.57 68.64,131.57 70.01,132.94 70.01,139.4 74.42,143.81 81.55,143.81 82.8,145.06 v4(83.8,145.06)
  BOTTOM w0.102: v3(78.62,69.55) 78.39,69.77 76.35,69.77 75.14,68.55 68.5,68.55 65.99,71.07 43.13,71.07 40.49,73.71 35.68,73.71 35.21,74.18 Q4.4 ; v4(83.8,145.06) 83.81,145.05 84.17,145.05 85.18,144.03 v2(85.39,144.03) 85.41,144.02 85.5,144.02 87.41,142.11 87.41,141.31 88.45,140.27 88.45,137.28 92.26,133.47 114.92,133.47 117.97,130.42 124.36,130.42 130.94,123.83 151.36,123.83 156.04,128.52 v3(156.04,128.61)
SMB1_CLK: length 234.8
  TOP w0.102: v4(72.91,160.68) 72.88,160.71 72.88,160.98 CPU1.AG5 ; R14.1 v3(123.32,220.47) ; v3(17.94,169.29) 18.14,169.09 v1(18.14,168.4) ; R1675.1 57.69,165.74 58.07,166.11 v3(58.07,166.11)
  L3 w0.127: v4(72.91,160.68) 72.78,160.68 72.25,161.21 70.77,161.21 68.92,163.07 66.77,163.07 64.79,165.05 64.79,166.11 63.38,167.52 61.35,167.52 59.53,165.71 58.48,165.71 v3(58.07,166.11) 58.05,166.11 57.51,166.65 52.09,166.65 51.41,165.96 40.71,165.96 39.79,166.87 27.7,166.87 25.28,169.29 v3(17.94,169.29) ; v3(123.32,220.47) 122.84,220.95 122.84,225.98 120.74,228.09 31.89,228.09 29.59,225.79 23.06,225.79 19.06,221.79 19.06,219.58 18.7,219.23 17.36,219.23 16.67,218.54 v3(16.67,217.81)
  L4 w0.127: v3(16.67,217.81) 17,217.48 17,205.9 14.97,203.87 14.97,183.67 17.55,181.09 17.55,172.25 18.31,171.49 18.31,169.66 v3(17.94,169.29)
SMB1_DATA: length 487.9
  TOP w0.102: R1676.1 63.25,157.26 63.25,157.84 66.34,160.92 66.34,161.9 66.74,162.3 v4(66.88,162.3) 66.84,162.26 66.84,161.29 67,161.12 69.51,161.12 69.89,161.51 70.31,161.51 70.32,161.5 70.68,161.5 70.69,161.51 71.11,161.51 71.12,161.5 71.66,161.5 72.15,161 CPU1.AG4 ; R1622.1 v3(123.32,219.46)
  L3 w0.127: v3(151.67,68.1) 151.35,68.41 144.25,68.41 143.77,67.93 136.33,67.93 135.8,67.4 135.24,67.4 134.07,66.23 133.19,66.23 133.02,66.05 124.37,66.05 124.18,66.24 114.47,66.24 111.86,68.86 110.56,68.86 100.26,79.16 92.61,79.16 89.6,76.15 73.57,76.15 72.61,77.11 71.48,77.11 70.1,75.73 62.25,75.73 61.32,74.8 44.58,74.8 39.35,80.03 39.35,106.34 36.11,109.58 36.11,114.21 34.17,116.15 34.17,131.13 30.17,135.13 29.85,135.13 16,135.13 14.6,136.53 14.6,138.4 14.62,138.43 14.62,151.45 11.68,154.39 11.68,164.9 15.48,168.69 25.34,168.69 27.54,166.49 39.64,166.49 41.12,165.01 51.1,165.01 51.64,165.54 57.96,165.54 58.34,165.16 58.95,165.16 61.34,162.78 61.85,162.78 61.9,162.72 66.46,162.72 v4(66.88,162.3)
  L4 w0.127: v3(151.67,68.1) 151.67,70.43 153.5,72.25 153.5,87.22 156.69,90.41 156.69,98.08 157.04,98.42 157.04,101.7 157.77,102.43 157.77,104.83 158.44,105.5 158.44,107.18 164.57,113.32 164.57,116.47 164.26,116.78 164.26,123.2 161.99,125.47 161.99,154.69 162.7,155.39 162.7,187.08 163.76,188.14 163.76,193.29 160.11,196.94 158.62,198.43 154.67,202.38 143.38,202.38 126.3,219.46 v3(123.32,219.46)
  BOTTOM w0.102: v2(151.47,67.31) 151.67,67.51 v3(151.67,68.1)
SMBUS_ISP: length 158.2
  TOP w0.102: R2079.2 30.68,75.37 v3(30.59,75.29) ; v3(150.91,48.64) 151.67,47.88 151.67,45.79 151.65,45.78 U109.115
  L3 w0.127: v3(150.91,48.64) 150.52,48.25 149.72,48.25 149.39,48.58 148.59,48.58 148.23,48.22 145.77,48.22 144.66,47.12 140.42,47.12 139.5,46.19 135.18,46.19 134.47,46.9 130.86,46.9 130.25,47.51 123.24,47.51 121.98,48.77 119.92,48.77 119.27,49.42 113.58,49.42 113.3,49.7 111.64,49.7 110.15,48.21 101.54,48.21 101.21,48.53 97.88,48.53 96.73,49.68 92.32,49.68 91.49,50.51 89.75,50.51 84.88,55.38 81.69,55.38 80.63,56.43 v3(78.7,56.43)
  BOTTOM w0.102: v3(30.59,75.29) 30.64,75.34 30.87,75.34 31.12,75.59 Q7.5 Q7.2 Q4.5 Q4.2 38.3,75.59 C1877.1 40.05,74.07 40.64,74.07 42.44,72.26 42.45,72.26 43.29,71.42 66.14,71.42 68.65,68.91 74.99,68.91 76.21,70.13 80.22,70.13 82.2,68.15 82.2,66.15 79.74,63.69 79.74,62.68 78.7,61.64 v3(78.7,56.43) ; v3(150.91,48.64) 150.91,48.4 150.15,47.64 v2(150.15,47.34) 150.17,47.32 150.17,45.42 R79677.1 R79676.1
SMBUS_ISP_G: length 30.7
  TOP w0.102: R2080.2 55.72,71.63 Q95.2 Q95.5 52.1,71.63 51.16,72.57 51.16,74.1 50.36,74.9 42.68,74.9 41,73.22 41,72.62 40.68,72.29 v3(40.68,72.29) ; R2079.1 30.66,74.49 v3(30.62,74.53)
  BOTTOM w0.102: v3(30.62,74.53) 31.65,73.5 32.08,73.5 32.35,73.23 35.16,73.23 35.39,73 37.6,73 38.03,72.57 v2(38.49,72.57) 40.34,72.57 40.62,72.29 v3(40.68,72.29)
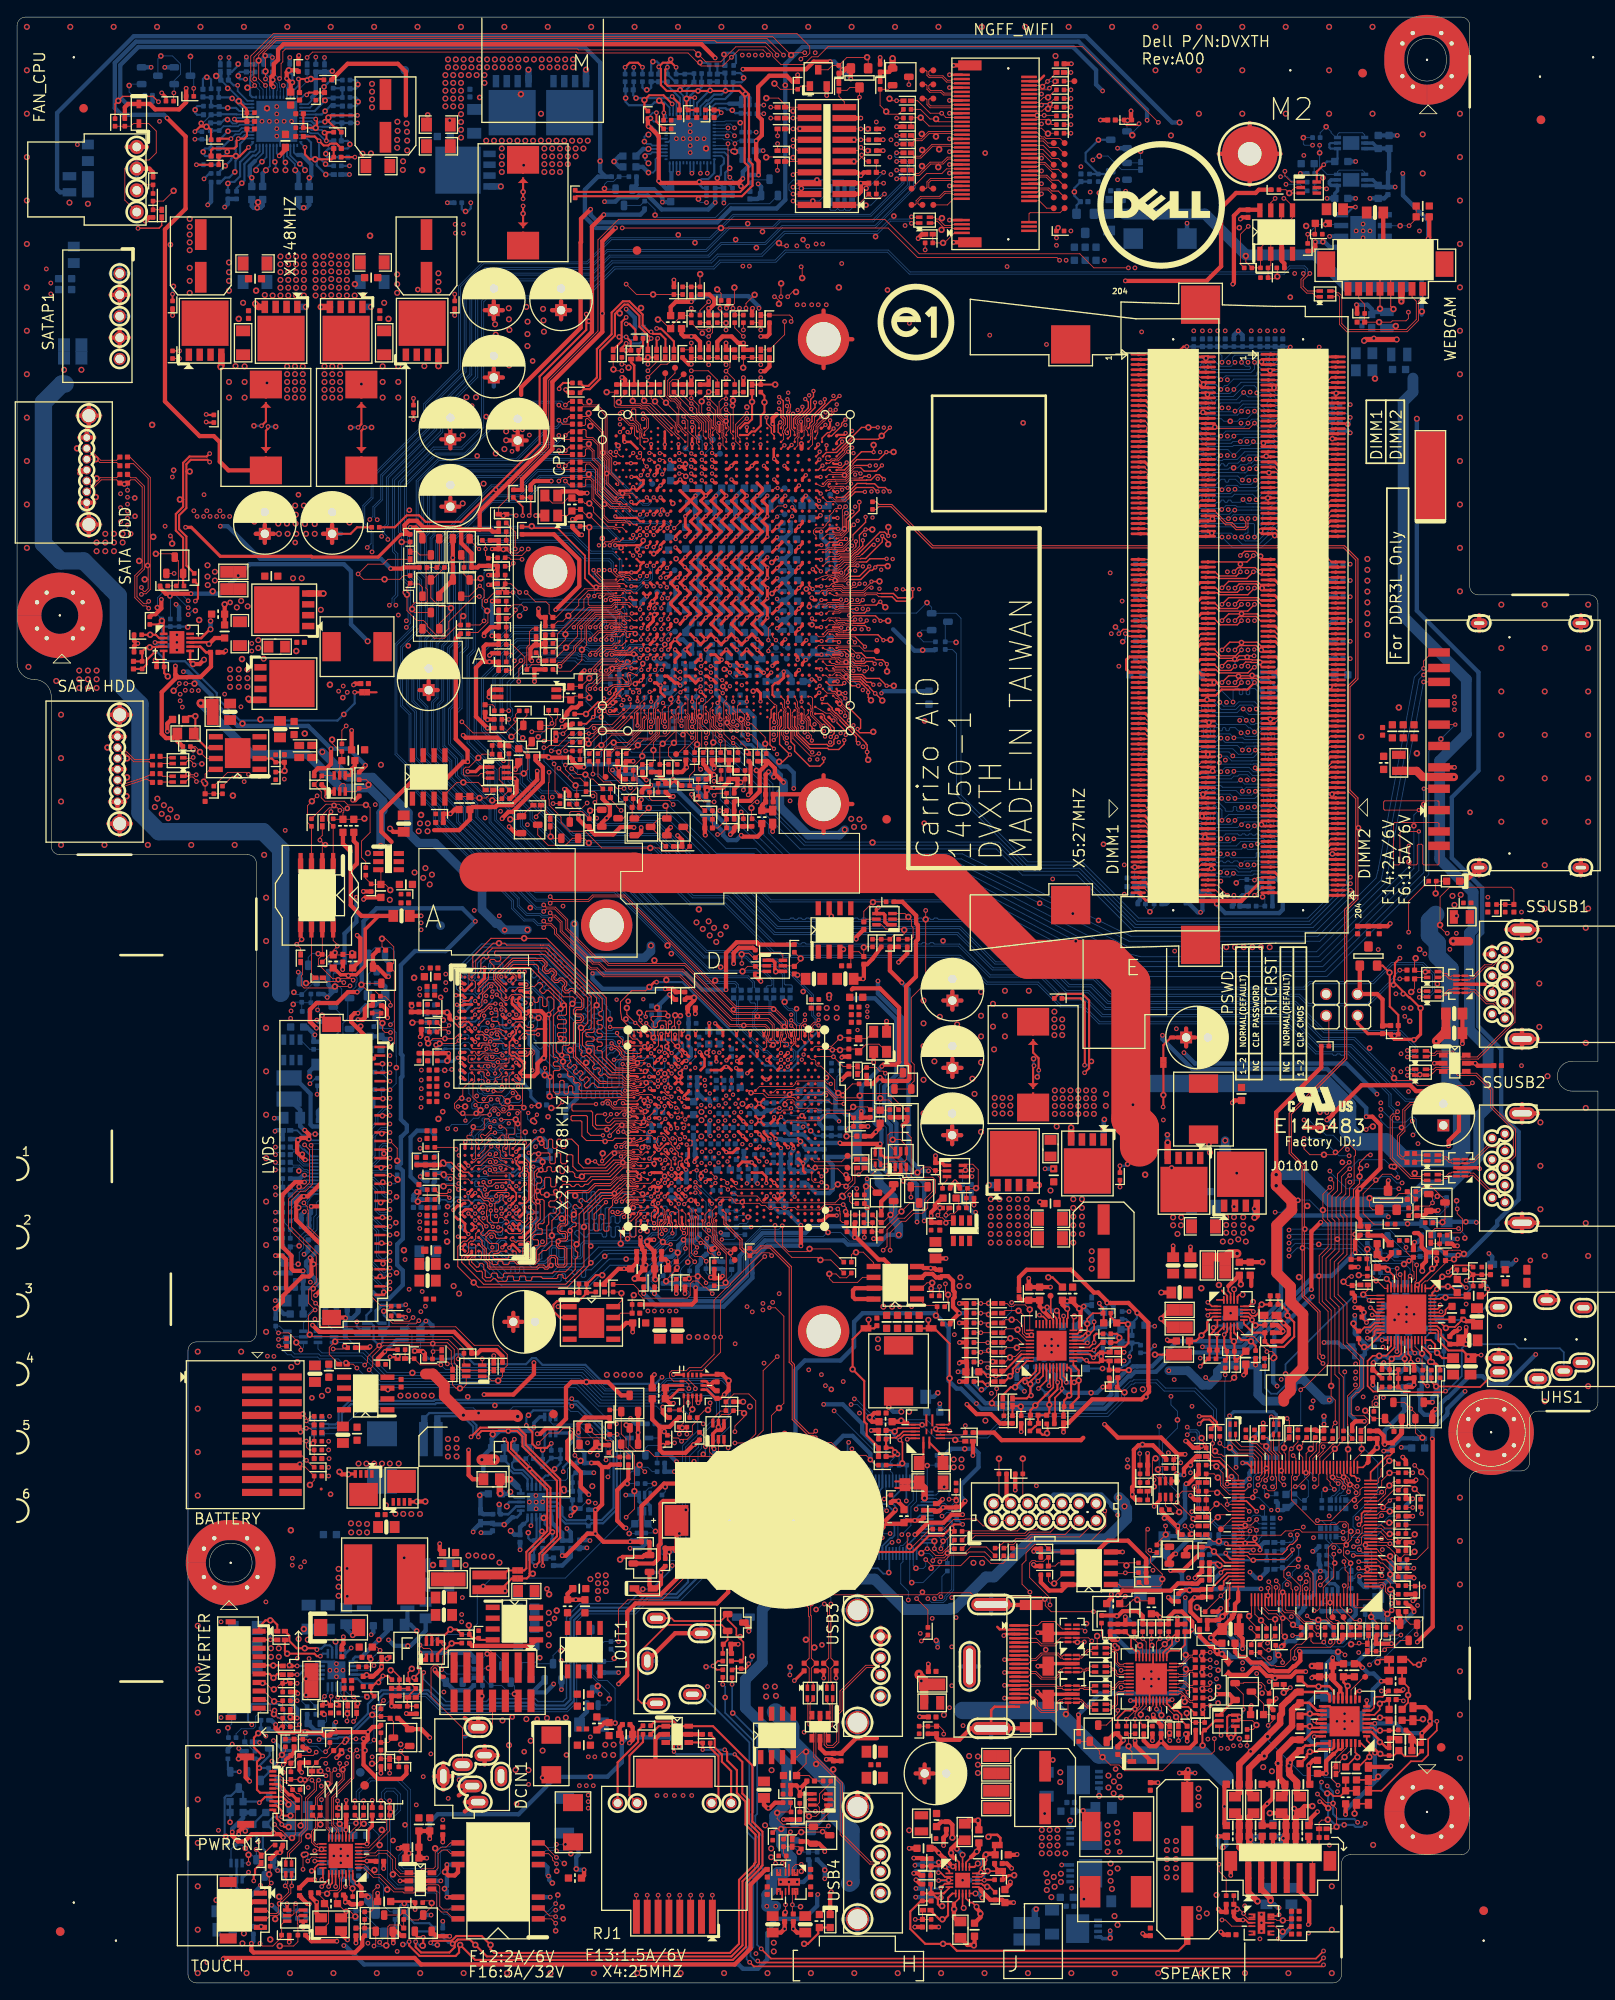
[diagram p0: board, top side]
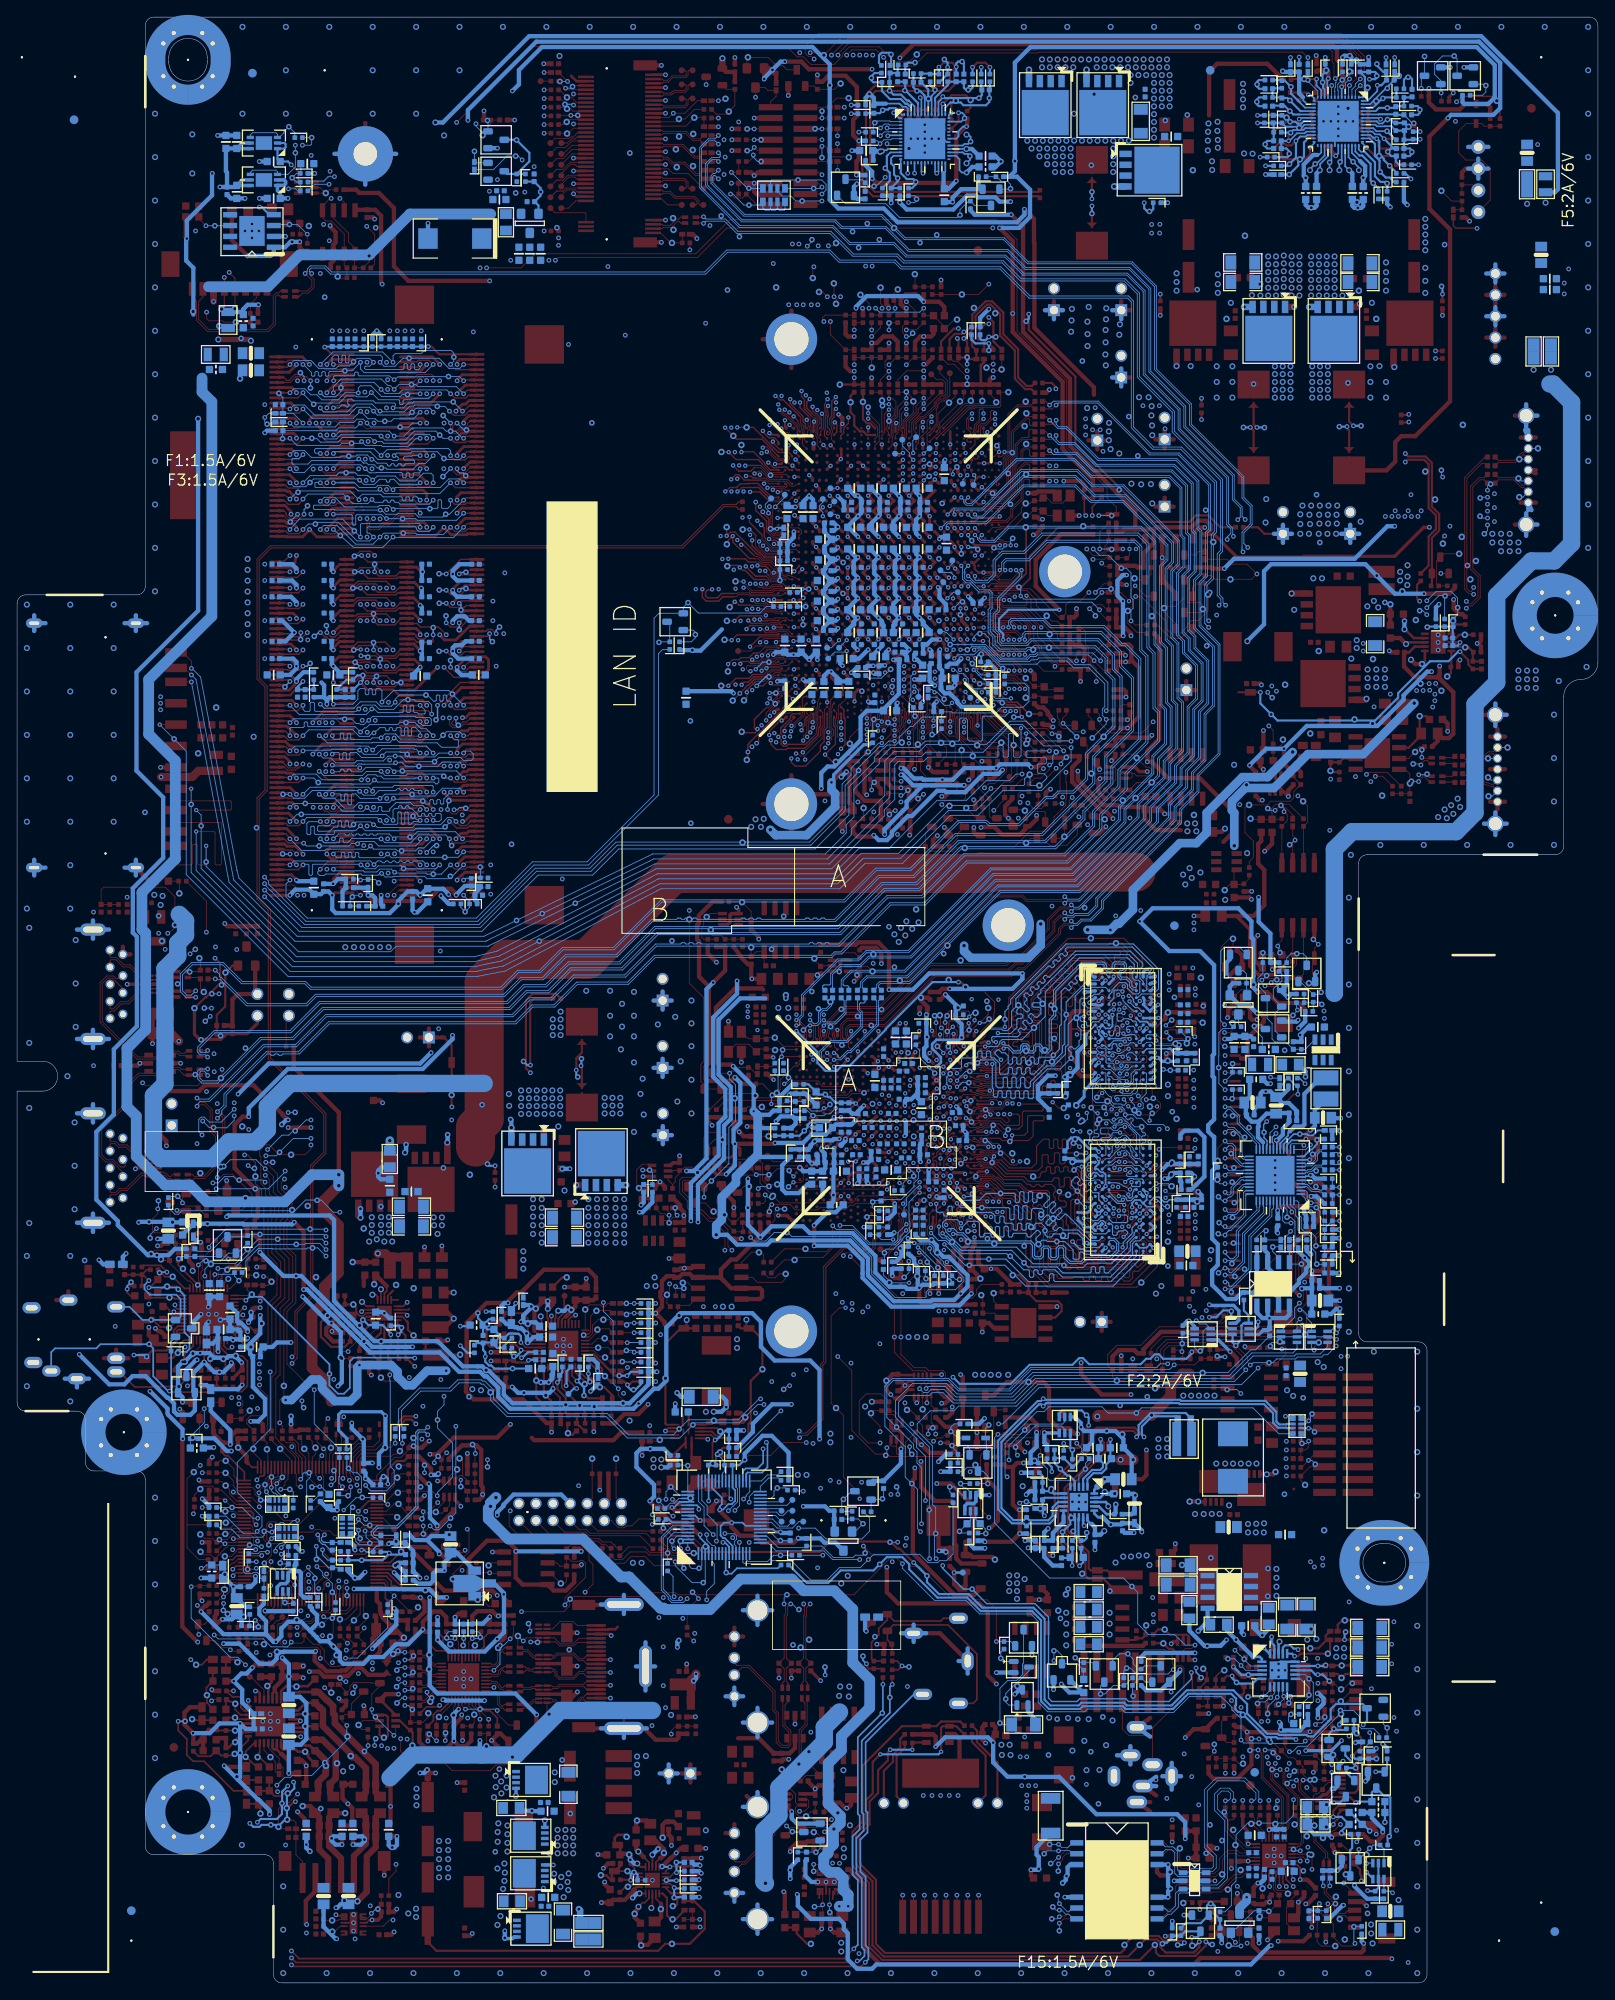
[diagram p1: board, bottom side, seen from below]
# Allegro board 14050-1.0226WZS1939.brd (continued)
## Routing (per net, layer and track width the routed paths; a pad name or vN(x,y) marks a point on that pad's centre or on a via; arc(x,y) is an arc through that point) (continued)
SMBUS_MS: length 8
  TOP w0.102: R334.1 v3(157.13,42.42) 156.46,42.42 154.85,44.02 U109.123
  BOTTOM w0.102: R80217.2 157.83,43.05 R80218.1 157.7,41.66 v2(156.75,41.66) 156.75,42.04 v3(157.13,42.42)
SNB: length 3.2
  BOTTOM w0.508: C35.1 40.17,41.43 39.4,40.67 v2(39.28,40.67) 38.51,41.43 R79619.2
SPEED_100*_CON: length 10.3
  TOP w0.254: RJ1.12 70.28,25.79 72.68,28.19 72.68,29.53 UR6.2
SPEED_100_N: length 97.3
  TOP w0.203: v3(36.47,11.28) 36.88,11.69 U16.26
  TOP w0.254: v3(45.88,4.83) 45.88,4.37 47.1,3.15 51.32,3.15 51.72,3.56 51.72,4.32 v1(51.85,4.45) 53.6,2.69 83.76,2.69 85.3,4.24 85.3,11.73 87.07,13.49 87.07,13.59 87.23,13.76 87.23,17.69 86.05,18.87 86.05,25.43 81.44,30.04 U12.6 77.41,30.04 76.87,30.58 74.62,30.58 UR6.1
  L4 w0.254: v3(45.88,4.83) 45.5,4.83 40.57,9.75 40.57,10.44 41.23,11.1 41.23,11.63 40.11,12.75 37.94,12.75 v3(36.47,11.28)
  BOTTOM w0.254: v3(45.88,4.83) 45.78,4.83 45.45,4.49 v2(45.14,4.49)
SPEED_1000*_CON: length 9.1
  TOP w0.254: RJ1.11 71.66,21.94 71.66,26.6 73.25,28.19 UR7.2
SPEED_1000_N: length 98.2
  TOP w0.203: U16.25 36.48,12.1 v3(35.65,11.28)
  TOP w0.254: v4(83.98,26.75) 84.87,25.86 84.87,22.16 85.64,21.39 85.64,18.7 86.82,17.52 86.82,13.93 86.66,13.76 86.66,13.66 84.89,11.9 84.89,4.4 83.59,3.1 54.97,3.1 v1(53.63,4.45) 52.99,5.08 51.58,5.08 51.46,4.96 51.46,4.95 51.21,4.71 51.21,4.18 50.59,3.56 47.27,3.56 46.64,4.19 v3(46.64,4.83) ; v4(76.87,27.05) 76.87,29.84 76.68,30.04 U12.1 75.09,30.04 UR7.1
  L4 w0.254: v3(35.65,11.28) 37.53,13.16 40.34,13.16 41.64,11.86 41.64,9.96 46.64,4.95 v3(46.64,4.83)
  BOTTOM w0.254: v3(46.64,4.83) 47.12,4.35 v2(47.4,4.35) ; v4(76.87,27.05) 77.17,26.75 v4(83.98,26.75)
SPI_33_18_PU1: length 9.7
  TOP w0.102: R1738.1 37.05,136.14 R2030.1 ; v1(40.65,136.22) 40.57,136.14 R2031.1 R2030.1 ; R1736.1 36.14,137.9 37.71,137.9 38.23,137.38 38.23,137 38.13,136.9 R2030.1
SPI_33_18_PU2: length 8.1
  TOP w0.102: SRCON1.8 36.99,121.97 37.35,121.62 37.35,121.44 v3(37.47,121.31) 37.35,121.18 37.35,121.16 36.99,120.8 R2032.1 ; R2032.1 36.55,120.27 R1737.1 ; R2032.1 38.07,120.27 C1758.2 39.21,120.33 R2029.1
  BOTTOM w0.102: v2(37.21,120.54) 37.35,120.68 37.35,121.18 v3(37.47,121.31)
SPI_CLK: length 66.7
  TOP w0.102: v3(38.23,117.04) 38.11,117.17 36.22,117.17 R1741.2 ; CPU1.BC6 74.2,147.6 v4(74.17,147.57)
  L3 w0.127: v4(74.17,147.57) 73.48,146.88 73.48,146.75 72.96,146.24 72.87,146.24 68.19,141.56 68.19,141.1 67.72,140.63 66.17,140.63 65.69,140.15 60.77,140.15 60.05,139.43 56.87,139.43 56.59,139.71 39.94,139.71 38.78,138.55 38.78,137.34 37.81,136.36 37.81,122.88 38.28,122.41 38.28,120.98 37.64,120.34 37.64,117.64 v3(38.23,117.04)
  BOTTOM w0.102: v3(38.23,117.04) 37.9,117.37 v2(37.58,117.37)
SPI_CLK_1: length 7.1
  TOP w0.102: v1(33.82,116.97) 34.26,116.97 R1741.1 34.45,118.05 SRCON1.6
SPI_CS0_N: length 55.2
  TOP w0.102: v3(36.74,137.03) 36.36,136.65 36.36,135.97 36.99,135.33 R1738.2 SRCON1.1 ; CPU1.BB8 75.5,149 75.5,148.37 75.51,148.37 75.51,147.89 75.39,147.78 75.39,147.37 v4(75.8,146.97)
  L3 w0.127: v3(36.74,137.03) 36.74,138.42 38.74,140.42 56.82,140.42 57.15,140.09 59.68,140.09 60.4,140.81 65.42,140.81 66,141.39 66.61,141.39 71.92,146.7 72.77,146.7 73.02,146.94 73.02,147.33 73.91,148.22 74.44,148.22 75.7,146.97 v4(75.8,146.97)
  BOTTOM w0.102: v3(36.74,137.03) 36.74,137.41 v2(37.09,137.76)
SPI_DATAIN: length 52.4
  TOP w0.102: CPU1.BA9 76.6,149.64 76.21,149.24 76.21,146.74 v4(75.8,146.33) ; R1740.1 35.72,136.66 36.55,137.49 37.47,137.49 v3(37.77,137.19)
  L3 w0.127: v4(75.8,146.33) 74.59,147.54 74.59,147.75 74.35,147.99 74,147.99 73.25,147.24 73.25,146.85 72.87,146.47 72.63,146.47 67.86,141.69 67.86,141.24 67.58,140.96 66.04,140.96 65.55,140.48 60.64,140.48 59.92,139.76 57.01,139.76 56.68,140.09 39.56,140.09 37.75,138.28 37.75,137.21 v3(37.77,137.19)
  BOTTOM w0.102: v2(38.64,137.41) 38.42,137.19 v3(37.77,137.19)
SPI_DATAOUT: length 74
  TOP w0.102: R1739.2 33.41,119.21 33.41,117.98 33.26,117.83 33.26,116.74 33.58,116.41 37.02,116.41 v1(37.19,116.58) 38.87,116.58 38.94,116.65 v3(38.96,116.65) ; CPU1.AY7 75,150.13 74.58,149.71 74.58,149.22 74.48,149.12 74.48,148.68 74.5,148.66 74.5,148.34 74.49,148.33 74.49,147.89 74.58,147.8 74.58,147.35 v4(74.17,146.94)
  L3 w0.127: v4(74.17,146.94) 74.04,146.94 68.52,141.42 68.52,140.96 67.86,140.3 66.31,140.3 65.21,139.2 63.86,139.2 63.51,139.55 60.84,139.55 60.39,139.09 56.58,139.09 56.3,139.37 41.29,139.37 38.31,136.4 38.31,132.94 38.14,132.77 38.14,123.01 38.82,122.33 38.82,116.8 v3(38.96,116.65)
SPI_MISO_ROM_1: length 5.1
  TOP w0.102: R1740.2 35.72,134.26 35.44,133.99 v3(35.44,133.71) 35.72,133.43 SRCON1.2
  BOTTOM w0.102: v3(35.44,133.71) 35.49,133.71 36.02,133.17 v2(36.08,133.17)
SPI_MOSI_1: length 4
  TOP w0.102: SRCON1.5 33.18,121.97 v3(32.72,121.51) 33.18,121.06 R1739.1
  BOTTOM w0.102: v2(33.3,122.09) v3(32.72,121.51)
SPI_WP#: length 57.3
  TOP w0.102: v3(35.11,138.89) 34.5,138.28 v1(34.5,138.25) 33.99,137.74 33.99,135.78 R1736.2 SRCON1.3
  L3 w0.127: v4(75.59,149.76) 75.59,149.61 74.46,148.49 73.85,148.49 73.11,147.74 72.5,147.74 67.46,142.71 66.13,142.71 65.86,142.43 65.86,141.73 65.28,141.15 59.87,141.15 59.15,140.42 57.44,140.42 57.11,140.75 36.98,140.75 v3(35.11,138.89)
  BOTTOM w0.102: R1647.2 77.36,150.43 76.99,150.07 76.99,149.99 76.49,149.48 75.87,149.48 v4(75.59,149.76)
SPKR_DET: length 66.4
  TOP w0.102: v3(152.18,22.1) 152.19,22.1 153.21,21.08 153.7,21.08 154.41,20.37 v1(154.41,18.26) 154.41,18.24 154.21,18.03 R1203.1 ; v3(146.11,58.8) 146.11,58.94 146.46,59.28 U109.59 146.46,61.73 145.09,63.09 144.52,63.09 R1825.1
  L3 w0.127: v3(139.35,28.52) 140.29,29.46 149.51,29.46 152.18,26.8 v3(152.18,22.1)
  L4 w0.127: v3(146.11,58.8) 146.43,58.48 146.43,57.05 146.85,56.64 146.85,56.34 146.3,55.8 146.3,47.46 145.54,46.7 145.38,46.7 145.33,46.65 145.3,46.65 144.09,45.43 144.09,42.49 144.85,41.72 144.85,41.33 144.65,41.13 144.65,36.44 144.59,36.39 144.59,34.88 139.48,29.76 139.48,28.65 v3(139.35,28.52)
SPKR_DET_C: length 8
  TOP w0.102: SPK1.6 151.59,14.2 152.37,14.99 PC2127.2 R1203.2 152.37,18.76 152.66,19.05 153.34,19.05 v1(153.39,19.1)
SPKR_IN_L: length 4.9
  TOP w0.203: U21.6 158.85,31.36 159.47,31.98 v1(159.47,32.66) 159.7,32.89 160.05,32.89 160.31,33.15 C203.2 160.56,33.08 C199.2
SPKR_IN_R: length 3.6
  TOP w0.203: C210.2 156.62,26.41 v1(156.85,26.41) 156.85,26.72 156.6,26.97 U21.31
SPKR_L+_C: length 11.4
  TOP w0.711: 143.04,16.64 143.04,15.86 144.09,14.81 SPK1.1 144.09,10.63 v1(145.17,9.55)
  TOP w0.762: L31.2 143.04,19.35 C226.1 R396.1 143.04,16.64
SPKR_L+_SNB: length 4.2
  TOP w0.508: R396.2 v3(140.55,17.14)
  BOTTOM w0.508: R396.2 141.51,16.1 141.26,15.85 v2(141.1,15.85) 140.83,15.85 140.55,16.13 v3(140.55,17.14)
SPKR_L-_C: length 11.5
  TOP w0.711: v1(146.69,9.63) 146.69,9.87 145.59,10.98 SPK1.2 145.59,14.86 144.18,16.26 R403.1
  TOP w0.762: L32.2 144.18,19.35 C236.1 R403.1
SPKR_L-_SNB: length 4.2
  TOP w0.508: R403.2 v3(145.7,16.18)
  BOTTOM w0.508: v3(145.7,16.18) 144.76,16.18 144.36,16.59 v2(144.36,16.76) 144.36,16.89 144.61,17.14 R403.2
SPKR_OUT_L+: length 19.8
  TOP w0.305: U21.16 153.6,33.63 153.25,33.99 152.02,33.99 151.97,34.04 C224.2
  TOP w0.762: 146.34,28.9 v1(146.34,28.83) ; 146.34,28.9 143.04,25.6 C225.1 143.04,22.3 L31.1 ; 146.34,28.9 147.81,30.37 147.81,31.32 148.01,31.52 148.01,32.39 148.72,33.1 148.78,33.1 149.72,34.04 C224.2
SPKR_OUT_L-: length 17
  TOP w0.305: C228.2 151.21,32.77 152.1,31.88 152.39,31.88 152.41,31.86 U21.18
  TOP w0.762: L32.1 144.18,22.3 C235.1 144.18,25.12 145.47,26.42 145.83,26.42 v1(145.96,26.54) 145.96,26.8 149.21,30.05 149.21,31.91 149.53,32.23 149.6,32.23 150.14,32.77 C228.2
SPKR_OUT_R+: length 10.3
  TOP w0.305: U21.25 152.13,28.02 151.93,27.81 151.32,27.81 151.27,27.76 150.75,27.76 150.53,27.53 150.5,27.53 C223.2
  TOP w0.762: L33.1 149.77,22.17 C247.1 149.77,23.52 148.9,24.38 148.9,24.71 148.85,24.77 v1(148.85,25.4) 148.85,25.99 150.04,27.18 C223.2
SPKR_OUT_R-: length 11.8
  TOP w0.305: U21.23 151.58,29.36 150.67,28.45 C229.2
  TOP w0.762: C229.2 149.26,28.45 147.71,26.9 147.71,25.83 v1(147.56,25.69) 147.71,25.54 147.71,23.94 148.37,23.28 C255.1 148.37,22.17 L34.1
SPKR_R+_C: length 10.2
  TOP w0.508: v1(151.58,20.69) 150.67,20.69 150.15,20.17 L33.2
  TOP w0.711: L33.2 149.64,19.35 C248.1 R415.1 149.64,15.6 148.59,14.55 SPK1.4
SPKR_R+_SNB: length 2.9
  TOP w0.508: R415.2 151.16,16.19 v3(151.15,16.18)
  BOTTOM w0.508: v2(150.73,15.39) 150.76,15.39 151.15,15.79 v3(151.15,16.18) 151.16,16.19 R415.2
SPKR_R-_C: length 9.8
  TOP w0.508: v1(146.6,19.86) L34.2
  TOP w0.711: SPK1.3 147.09,14.59 148.5,16 R419.1 C256.1 148.5,19.35 L34.2
SPKR_R-_SNB: length 4
  TOP w0.508: R419.2 v3(146.97,16.18)
  BOTTOM w0.508: v3(146.97,16.18) 147.73,16.18 148.19,16.64 v2(148.19,16.92) 147.96,17.14 R419.2
SPV10: length 15
  TOP w0.254: GPU1.H8 76.2,93.2 76.57,93.58 v4(76.59,93.58)
  TOP w0.508: v4(72.95,87.23) 72.95,86.34 73.16,86.14 73.16,85.82 C785.1 C789.1 73.34,84.62 C787.1 72.65,82.86 72.65,82.78 v1(72.27,82.4) 72.33,82.34 L51.2
  L4 w0.356: v4(72.95,87.23) 72.96,87.23 73.56,87.83 73.56,88.98 76.38,91.8 76.38,93.37 v4(76.59,93.58)
SPV18: length 12.3
  TOP w0.254: v4(75.79,92) 75.8,92.01 75.81,92.01 GPU1.H7
  TOP w0.508: v4(74.54,86.95) 73.92,86.95 73.73,86.76 v1(73.73,86.72) 73.73,86.38 C793.1 C792.1 74.61,84.62 C788.1 L49.2
  L3 w0.508: v4(74.54,86.95) 73.94,87.55 73.94,89.28 75.79,91.13 v4(75.79,92)
SST_HOLDJ_1: length 69.2
  TOP w0.102: R576.2 69.25,142.13 69.23,142.1 69.23,141.72 70.62,140.33 71.27,140.33 71.39,140.21 71.41,140.21 v3(71.79,139.83) ; v3(39.33,117.32) 39.15,117.5 37.59,117.5 37.58,117.5 36.92,117.5 35.26,119.16 35.26,119.81 35.72,120.27 R1737.2 SRCON1.7
  L3 w0.127: v3(71.79,139.83) 71.39,140.22 68.25,140.22 68,139.96 66.74,139.96 65.63,138.86 63.72,138.86 63.37,139.21 61.14,139.21 60.69,138.76 56.45,138.76 56.16,139.04 41.43,139.04 38.67,136.28 38.67,132.82 38.47,132.63 38.47,123.15 39.33,122.3 v3(39.33,117.32)
  BOTTOM w0.102: v2(38.77,117.86) 39.3,117.32 v3(39.33,117.32)
SST_HOLDJ_1_R: length 10.1
  TOP w0.102: CPU1.BA7 75,149.33 74.7,149.03 74.7,148.75 74.71,148.75 74.71,148.25 74.7,148.25 74.7,147.97 74.79,147.89 74.79,146.32 74.11,145.64 72.72,145.64 71.48,144.4 70.04,144.4 69.47,143.83 R576.1
SSTCMP: length 4.7
  BOTTOM w0.102: R45.1 33.82,33.46 v2(33.82,33.68) 33.82,34.57 34.82,35.58 U120.11
SSTCMP_1: length 2.6
  BOTTOM w0.102: C5.1 35.97,30.35 36.2,30.58 36.2,31.15 v2(35.93,31.42) 35.92,31.43 R45.2
STATUS: length 4.7
  TOP w0.102: v3(37.52,33.43) 37.65,33.3 R61.1
  BOTTOM w0.102: U120.8 37.37,33.58 v3(37.52,33.43) 38.64,32.31 v2(38.64,31.5)
SUS_LED_GREEN_C: length 15.7
  TOP w0.254: v1(31.76,20.86) 31.76,21.09 31.1,21.75 PWRCN1.7 29.02,21.75 v3(28.35,21.08)
  BOTTOM w0.254: v3(28.35,21.08) 28.23,21.21 R730.2 26.45,22.29 Q68.D 25.04,21.89 24.5,21.89 24.29,21.69 24.29,17.27 v2(24.42,17.14) 24.61,16.95 R729.2
SUS_LED_GREEN_C2: length 2.4
  BOTTOM w0.254: R730.1 R735.2 v2(24.93,18.8)
SUSCLK_32_APU: length 23.5
  TOP w0.102: CPU1.AG7 74.6,161.1 v4(74.6,160.82) ; v3(59.09,166.56) 59.08,166.57 57.75,166.57 57.57,166.75 R1934.2
  L3 w0.127: v4(74.6,160.82) 74.18,161.24 73.73,161.24 72.24,162.72 70.83,162.72 69.8,163.75 67.19,163.75 65.82,165.12 65.82,166.19 63.71,168.3 61.03,168.3 59.9,167.17 59.71,167.17 v3(59.09,166.56)
  BOTTOM w0.102: v2(74.6,160.07) v4(74.6,160.82)
SUSCLK_32_APU_C: length 129.3
  TOP w0.102: R1873.1 54.82,168.41 v4(54.82,167.77) 54.82,167.02 R1874.2 55.21,166.75 R1934.1 ; v3(70.82,205.33) 70.83,205.32 v1(82.37,205.32) 101.93,205.32 105.39,201.87 121.69,201.87 v3(122,201.55) ; R1710.1 v3(123.32,216.41)
  L3 w0.127: v3(123.32,216.41) 123.32,205.74 122.84,205.26 122.84,202.44 122,201.6 v3(122,201.55)
  L4 w0.127: v3(70.82,205.33) 70.82,204.43 65.28,198.89 65.28,192.12 59.63,186.47 50.03,186.47 48.9,185.34 48.9,170.21 50.96,168.15 53.81,168.15 53.87,168.21 54.24,168.21 54.69,167.77 v4(54.82,167.77)
SUSCLK_NGFF: length 3.5
  TOP w0.102: R1710.2 120.68,216.41 v1(120.64,216.37) 120.52,216.37 119.89,217 NGFF1.50
SVC_VDD: length 121.7
  TOP w0.102: v3(78.9,191.87) R1902.2 R1629.1 ; v3(29.07,222.76) v1(29.07,223.65) 29.07,225.09 28.79,225.37 28.79,225.73 30.31,227.25 81.64,227.25 81.87,227.03 87.59,227.03 88.93,225.69 v3(88.93,225.55)
  L3 w0.127: v3(93.76,196.34) 94.99,197.57 94.99,216.55 88.93,222.61 v3(88.93,225.55)
  L4 w0.127: v3(78.9,191.87) 78.43,192.34 78.43,193.59 80.46,195.62 80.46,196.89 80.74,197.17 86.27,197.17 88.07,195.36 92.78,195.36 v3(93.76,196.34)
  BOTTOM w0.102: PU4601.5 29.59,221.44 29.53,221.49 29.53,222.3 v3(29.07,222.76)
SVC_VDD_GFX: length 27.7
  TOP w0.102: R1994.2 82.77,195.14 82.25,195.66 v3(82.25,195.94) 82.25,196.71 R1999.1 82.39,197.67 v1(81.93,198.13)
  L3 w0.127: v3(83.96,216.12) 84.63,215.45 84.63,212.42 83.96,211.74 83.96,197.64 v3(82.25,195.94)
  BOTTOM w0.102: v3(83.96,216.12) 83.5,216.57 83.01,216.57 PU5407.5
SVD_VDD: length 113.2
  TOP w0.102: v3(90.58,194.39) 90.73,194.53 90.73,194.82 90.41,195.14 R1631.1 R1903.2 ; v3(92.18,225.84) 90.87,225.84 v1(90.58,225.55) 88.43,227.71 30.12,227.71 27.71,225.3 27.71,224.37 27.71,224.37 27.71,223.92 27.71,223.92 27.71,222.85 v3(27.8,222.76)
  L3 w0.127: v3(92.18,225.84) 92.18,225.51 96.01,221.68 96.01,196.45 95.05,195.49 91.69,195.49 v3(90.58,194.39)
  BOTTOM w0.102: PU4601.3 28.79,221.51 28.39,221.91 28.39,222.17 v3(27.8,222.76)
SVD_VDD_GFX: length 38.7
  TOP w0.102: R2001.1 83.42,189.73 83.42,189.03 v3(82.96,188.57) 83.98,187.55 R1995.2 ; v3(83.78,195.94) 83.78,196.32 83.94,196.49 v1(83.94,198.36)
  L3 w0.127: v3(83.96,217.03) 84.88,216.11 84.88,212.31 84.21,211.64 84.21,196.37 v3(83.78,195.94)
  L4 w0.127: v3(82.96,188.57) 83.43,189.04 83.43,195.59 v3(83.78,195.94)
  BOTTOM w0.102: v3(83.96,217.03) 83.5,217.49 83.01,217.49 82.89,217.37 PU5407.3
SVT_VDD: length 130.7
  TOP w0.102: v3(78.9,188.62) 80.88,188.62 81.95,187.55 R1901.2 ; v3(89.7,225.55) 87.76,227.48 30.22,227.48 28.27,225.54 v1(28.27,224.92) 28.27,222.79 v3(29.07,222)
  L3 w0.127: v3(94.7,196.34) 95.24,196.89 95.24,216.66 89.7,222.21 v3(89.7,225.55)
  L4 w0.127: v3(94.7,196.34) 94.7,196.49 94.12,197.07 93.06,197.07 92.53,196.54 92.53,196.15 92.25,195.87 88.28,195.87 86.48,197.68 80.53,197.68 79.95,197.1 79.95,195.83 77.92,193.8 77.92,189.6 v3(78.9,188.62)
  BOTTOM w0.102: v3(29.07,222) 29.19,221.88 PU4601.4
SVT_VDD_GFX: length 34
  TOP w0.102: v3(85.3,195.94) 85.3,196.5 v1(86.31,197.51) ; R1993.2 79.92,195.68 v3(80.93,196.7)
  L3 w0.127: v3(85.3,195.94) 84.47,196.77 84.47,211.53 85.14,212.2 85.14,216.52 84.15,217.5 83.67,217.5 v3(83.2,217.03)
  L4 w0.127: v3(80.93,196.7) 84.54,196.7 v3(85.3,195.94)
  BOTTOM w0.102: v3(83.2,217.03) 83.14,216.97 PU5407.4
SW_ON_N_SIO: length 6.1
  TOP w0.102: R375.1 R364.2 140.08,59.56 v1(140.52,59.12) 140.83,58.82 140.83,58.2 141.84,57.18 U109.69
SWR_LX: length 11.5
  BOTTOM w0.203: U26.17 37.18,98.22 36.26,99.14 36.26,99.44 36.05,99.64
  BOTTOM w0.508: 36.05,99.64 35.49,100.2 34.57,100.2 34.35,100.43 34.35,104.01 32.48,105.88 L2.2
SWR_V12: length 27.6
  TOP w0.508: v3(33.66,99.77) 34.17,99.26 v3(34.17,98.73) 34.04,98.73 33.92,98.86 33.23,98.86 32.77,98.4 32.77,97.19 33.66,96.3 v3(33.73,96.3) ; v3(37.47,90.37) 37.47,90.56 37.18,90.86 34.43,90.86 v3(34.41,90.85)
  L4 w0.508: v3(33.73,96.3) 34.4,95.64 34.4,90.86 v3(34.41,90.85)
  BOTTOM w0.203: U26.15 36.38,98.05 35.83,98.59 34.31,98.59 v3(34.17,98.73) ; v3(37.47,90.37) 37.58,90.48 U26.43 ; U26.11 v3(33.73,96.3)
  BOTTOM w0.508: v3(33.66,99.77) 33.61,99.77 33.13,100.25 C296.1 33.13,102.12 L2.1 ; C297.1 37.47,89.5 v3(37.47,90.37) ; C295.1 C299.2 34.16,89.83 34.4,90.07 34.4,90.83 v3(34.41,90.85)
SYNC: length 3.4
  TOP w0.102: TP24.1 157.64,35.81 156.1,34.28 U21.11
SYS_3VSB: length 5.7
  TOP w0.102: R371.1 140.19,60.58 v1(140.34,60.43) 141.13,59.64 141.13,58.21 141.42,57.92 141.8,57.92 141.86,57.98 U109.67
SYS_FAN_TACH1_1: length 3.2
  TOP w0.102: FANC3.3 14.65,210.38 R80.2 R76.2
SYS_FAN_TACH1_2: length 4.9
  TOP w0.102: v1(18.32,209.68) 17.11,208.47 R76.1 R73.2 R74.2
SYS_PRES: length 4.4
  TOP w0.102: R79647.2 34.68,60.33 v3(33.87,61.14) 33.87,61.16 33.14,61.89 BAT2.7B
  BOTTOM w0.102: v2(33.08,60.68) 33.08,60.73 33.48,61.14 v3(33.87,61.14)
SYS_PWRGD: length 15.8
  TOP w0.102: Q79.D 70.96,136.27 71.22,136.53 R124.2 72.55,139.89 72.55,141.92 R2028.2 R1657.1 74.46,142.81 74.46,144.22 v1(74.46,144.23) 74.46,145.13 75.2,145.87 75.92,145.87 76.41,146.37 76.41,147.91 CPU1.BC9
SYS_PWRGD_G: length 6.2
  TOP w0.102: Q79.G 67.16,137.26 v1(67.06,137.16) 66.96,137.06 R717.2 66.11,137.06 64.83,137.06 64.68,136.91 Q78.D
SYS_PWRGD_HV: length 92.2
  TOP w0.102: Q1209.D 78.71,134.49 R119.2 78.15,132.41 75.52,132.41 75.14,132.79 v1(74.1,132.79) 68.42,132.79 66.46,134.75 64.67,134.75 63.66,135.76 63.66,136.4 62.26,137.8 62.26,138.47 62.18,138.55 62.18,140.4 62.25,140.47 v3(62.25,141.65) ; Q14.G v3(18.38,164.91)
  L3 w0.127: v3(26.58,140.55) 29.43,140.55 30.74,141.86 35.63,141.86 36.1,141.39 39.72,141.39 39.97,141.14 57.85,141.14 58.14,141.43 58.46,141.43 59.28,142.25 61.06,142.25 61.67,141.65 v3(62.25,141.65)
  L4 w0.127: v3(26.58,140.55) 26.54,140.51 25.88,140.51 25.34,141.06 25.34,146.91 22.51,149.74 22.51,151.16 19.93,153.74 19.93,158.4 19.17,159.16 19.17,164.12 v3(18.38,164.91)
SYS_PWRGD_HV_1: length 6.9
  TOP w0.102: R118.1 74.96,133.92 74.96,134.43 Q1208.C 75.12,136.24 Q1209.G 76.04,137.41 75.93,137.53 75.93,137.67 v1(75.89,137.71)
SYS_PWRGD_HV_2: length 4.7
  TOP w0.102: v1(73.92,137.46) 72.7,136.24 Q1208.B 71.98,136.49 C67.1 72.11,137.67 R124.1
SYSTEM_FAN_PWM1_1: length 18
  TOP w0.102: FANC3.4 12.61,208.58 12.61,212.3 13.58,213.27 15.44,213.27 16.29,214.12 16.29,216.66 15.4,217.55 D1.A 13.62,217.55 13.3,217.23 R71.2 R68.2
T_DP_BLON: length 2
  TOP w0.102: v4(73,176.4) 73.3,176.7 CPU1.G5
  BOTTOM w0.102: v4(73,176.4) 72.8,176.2 TP174.1
T_DP_DIGON: length 2
  TOP w0.102: v4(73.8,176.4) 74.1,176.7 CPU1.G6
  BOTTOM w0.102: TP6.1 74.33,175.87 v4(73.8,176.4)
TCK: length 2.6
  BOTTOM w0.102: TP4130.1 95.77,55.48 U4101.27
TDI: length 2.8
  BOTTOM w0.102: U4101.25 96.24,54.68 TP4128.1
TDO: length 4.3
  BOTTOM w0.102: TP4127.1 94.8,53.44 95.76,53.44 96.6,54.28 U4101.24
TEMPIN0: length 1.5
  TOP w0.102: CPU1.E15 81.63,178.7 v4(81.33,179)
  BOTTOM w0.102: v4(81.33,179) 81.39,178.94 82.23,178.94 TP192.1
TEMPIN1: length 2.6
  TOP w0.102: CPU1.E14 80.43,178.7 v4(80.13,179)
  BOTTOM w0.102: TP193.1 80.17,180.47 80.17,179.37 80.13,179.33 v4(80.13,179)
TEMPIN2: length 1.5
  TOP w0.102: v4(78.9,178.94) 79.14,178.7 CPU1.E12
  BOTTOM w0.102: TP194.1 v4(78.9,178.94)
TEMPINR: length 3.5
  TOP w0.102: v4(80.13,178.2) 80.43,177.9 CPU1.F14
  BOTTOM w0.102: TP195.1 81.39,179.83 80.55,179 80.55,178.62 v4(80.13,178.2)
TEST18_M: length 60.1
  TOP w0.102: v3(89.4,197.28) 89.4,198.82 v1(89.42,198.84) ; CPU1.A14 80.6,182.63 79.54,183.69 79.54,184.15 v4(78.9,184.78) 77.88,185.8 R1608.1 ; R1748.2 v3(88.2,219.46)
  L3 w0.127: v3(89.4,197.28) 89.87,196.81 90.38,196.81 90.78,197.21 90.78,207.7 90.34,208.14 90.34,217.31 v3(88.2,219.46)
  L4 w0.127: v3(89.4,197.28) 87.73,198.95 79.41,198.95 76.65,196.19 76.65,187.88 78.27,186.27 78.27,185.42 v4(78.9,184.78)
TEST19_M: length 60
  TOP w0.102: v3(90.18,197.28) 90.78,197.88 91.11,197.88 v1(91.16,197.84) ; R1747.2 v3(88.2,218.19) ; R1609.1 78.84,184.15 v4(78.9,184.15) 78.9,183.95 80.31,182.54 80.31,181.63 80.3,181.63 80.3,181 CPU1.B14
  L3 w0.127: v3(90.18,197.28) 90.53,197.63 90.53,207.59 90.09,208.03 90.09,216.3 v3(88.2,218.19)
  L4 w0.127: v4(78.9,184.15) 78.01,185.04 78.01,186.16 76.4,187.78 76.4,196.3 79.3,199.2 88.26,199.2 v3(90.18,197.28)
TESTEN: length 10.9
  TOP w0.356: GPU1.K7 77.86,92.4 v4(78.22,92.03)
  L3 w0.508: v4(80.75,87.11) 80.71,87.15 80.71,87.15 79.06,88.8 79.06,91.2 v4(78.22,92.03)
  BOTTOM w0.508: R1897.1 82.16,84.37 81.52,85.01 81.52,85.76 81.64,85.88 v2(81.64,85.94) 81.41,86.17 R302.1 80.68,87.05 v4(80.75,87.11)
TMS: length 4.1
  BOTTOM w0.102: U4101.26 96.13,55.08 95.76,54.71 95.32,54.71 94.78,55.24 TP4129.1
TP_DET: length 166.7
  TOP w0.102: v3(154.08,50.16) 154.08,47.48 152.85,46.25 U109.118 ; TOUCH1.1 28.57,10.5 v3(29.75,11.68) 29.5,11.94 v1(29.5,12.7) 29.62,12.83 R1785.2
  L3 w0.127: v3(29.75,11.68) 30.01,11.94 30.01,13.61 35.94,19.55 55.41,19.55 57.93,22.07 60.38,22.07 61.6,23.29 61.6,23.96 67.03,29.39 90.63,29.39 93.33,32.08 99.02,32.08 101.48,29.62 110.91,29.62 112.17,30.89 116,30.89 117.7,29.18 128.08,29.18 128.23,29.03 129.49,29.03 130.7,27.83 137.98,27.83 138.84,26.96 142.06,26.96 142.35,27.25 v3(142.35,27.75)
  L4 w0.127: v3(142.35,27.75) 142.35,28.82 142.67,29.14 146.66,29.14 154.68,37.16 154.68,38.38 155.44,39.14 155.44,42.52 154.88,43.08 154.88,43.62 154.65,43.85 154.65,48.71 154.43,48.94 154.43,49.82 v3(154.08,50.16)
TP_GPU_CLKREQ#: length 5
  TOP w0.102: GPU1.N7 80,92.45 v4(79.38,93.07)
  BOTTOM w0.102: v4(79.38,93.07) 79.69,93.07 80.9,91.85 80.9,91 81.21,90.69 TP158.1
TP_NGFF_COEX1: length 4.7
  TOP w0.102: NGFF1.48 119.37,216.5 119.89,215.99 120.23,215.99 120.41,215.8 122.05,215.8 TP39.1
TP_NGFF_COEX2: length 3.2
  TOP w0.102: NGFF1.46 119.44,216 119.68,215.76 120.13,215.76 120.62,215.26 TP38.1
TP_NGFF_COEX3: length 4.8
  TOP w0.102: TP196.1 121.85,214.73 120.83,214.73 120.06,215.5 NGFF1.44
TP_NGFF_LED1: length 5.4
  TOP w0.102: NGFF1.6 118.42,206.98 118.55,207.11 122.05,207.11 TP63.1
TP_NGFF_LED2: length 3.2
  TOP w0.102: TP64.1 120.48,207.65 119.63,208.5 NGFF1.16
TP_NGFF_MLDIR: length 3.7
  TOP w0.102: NGFF1.17 109.6,208.75 108.87,208.03 TP62.1
TPA3131_BSNL: length 2.8
  TOP w0.305: U21.19 152.3,31.36 152.21,31.45 151.34,31.45 v1(151.29,31.5) 151.24,31.5 151.19,31.45 150.35,31.45 C228.1
TPA3131_BSNR: length 2.8
  TOP w0.305: U21.22 151.46,29.86 v1(151.29,30.02) 150.43,30.02 150.38,29.97 C229.1
TPA3131_BSPL: length 5.6
  TOP w0.305: U21.15 154.1,34.14 153.53,34.72 152.36,34.72 v1(152.31,34.67) 152.26,34.72 150.99,34.72 C224.1
TPA3131_BSPR: length 5.4
  TOP w0.305: C223.1 150.95,26.45 150.95,26.71 v1(151.29,27.05) 152.13,27.05 152.4,27.32 153.87,27.32 154.1,27.55 U21.26
TPA3131_FAULT#: length 4.5
  TOP w0.102: U21.30 156.1,27.23 155.35,26.48 v1(155.35,26.42) 155.29,26.42 154.8,25.92 154.8,24.79 154.45,24.45 R383.2
TPA3131_GAIN: length 3.9
  TOP w0.203: R358.1 161.58,29.53 R361.2 v1(159.49,29.53) 159.01,29.53 158.68,29.86 U21.3
TPA3131_GVDD: length 5.9
  TOP w0.305: U21.2 158.48,29.36 159.48,28.36 v1(159.48,28.17) 159.6,28.17 160.24,27.53 160.52,27.53 R357.2
  TOP w0.508: R357.2 R361.1 161.51,28.64 C192.1
TPA3131_LINN: length 2.9
  TOP w0.203: U21.5 158.68,30.86 158.69,30.86 159.32,30.86 v1(159.49,31.04) 160.26,31.04 C200.2
TPA3131_LINN_1: length 2.5
  TOP w0.203: v1(164.52,30.86) 164.4,30.73 R346.2 C200.1
TPA3131_MUTE: length 18.1
  TOP w0.203: U21.7 158.45,31.86 158.81,32.22 158.81,32.32 158.81,33.32 158.96,33.48 159.81,33.48 R360.1 v3(159.67,34.16) ; v3(149,34.54) 148.42,33.96 v1(148.23,33.96) R638.2
  L3 w0.203: v3(149,34.54) 149.26,34.8 158.4,34.8 159.04,34.16 v3(159.67,34.16)
TPA3131_PLIMIT: length 8.4
  TOP w0.203: U21.1 157.94,28.38 v1(159.53,26.8) 159.72,26.61 R357.1 161.13,26.61 C193.1 162.36,26.52 163.77,26.52 R347.2
TPA3131_RINN: length 4.2
  TOP w0.203: U21.32 157.3,28.02 158.26,27.05 v1(158.26,26.44) 158.17,26.44 157,25.27 C198.2
TPA3131_RINN_1: length 2.7
  TOP w0.203: v1(159.29,24.13) 158.91,23.75 R344.2 C198.1
TPA3131_SD: length 14.9
  TOP w0.102: Q63.3 140.7,29.16 v3(140.9,28.96) ; v3(143.49,32) 143.49,33.78 142.54,34.73 Q64.G 143.51,35.07 143.57,35.13 145.64,35.13 146.03,34.73 146.03,34.35 R639.2 146.51,34.1 R638.1
  BOTTOM w0.102: v3(143.49,32) 143.49,31.55 v2(143.06,31.11) v3(140.9,28.96)
TPA3131_SD1#: length 24
  TOP w0.102: Q64.D 145.88,32.65 C521.1 146.65,31.39 R643.2 147,30.71 v3(146.41,30.12) ; U21.29 155.6,27.52 154.34,26.25 R383.1 154.02,25.34 153.88,25.2 153.88,23.84 v3(154.59,23.13)
  BOTTOM w0.102: v3(146.41,30.12) 146.41,28.37 148.98,25.81 v2(148.98,25.78) 149,25.78 150.53,24.26 152.81,24.26 153.01,24.06 153.66,24.06 v3(154.59,23.13)
TSVDD: length 8.9
  TOP w0.254: v4(89.41,101.33) 89,100.91 GPU1.AD17
  BOTTOM w0.254: v4(89.41,101.33) 90.02,100.72 91.55,100.72 91.6,100.66 92.2,100.66 92.49,100.38 92.49,100.11 92.87,99.72 v2(92.87,99.69) 93.44,99.12 C759.1 C758.1 L47.2
USB3_TX2_EMI_DN: length 3.2
  TOP w0.102: v1(163.15,115.94) 163.55,116.33 C91.2 163.71,117.64 L4.1
USB3_TX2_EMI_DP: length 3
  TOP w0.102: L4.4 163.71,118.32 C1757.2 163.55,119.77 v1(163.67,119.89)
USB3_TX3_EMI_DN: length 1.5
  TOP w0.102: C113.2 163.71,96.18 L56.1
USB3_TX3_EMI_DP: length 1.5
  TOP w0.102: C111.2 163.71,96.86 L56.4
USB30_RXN2: length 165.8
  TOP w0.102: L5.1 164.14,115.36 v3(164.1,115.32) ; CPU1.Y7 v4(74.5,165.8)
  BOTTOM w0.102: v4(74.5,165.8) 74.36,165.66 74.36,164.23 73.95,163.81 73.54,163.81 72.47,162.74 71.32,162.74 71.15,162.58 71.15,160.89 71.36,160.68 71.36,157.99 70.81,157.44 70.81,156.52 70.09,155.81 66.86,155.81 66.67,155.99 66.11,155.99 65.91,156.19 58.88,156.19 57.67,154.98 57.67,153.34 56.77,152.44 56.77,147.07 59.96,143.87 59.96,140.93 61.44,139.45 63.2,139.45 63.85,138.81 64.64,138.81 67.8,135.65 71.17,135.65 71.53,136.02 74.88,136.02 80.48,130.41 84.54,130.41 88.24,126.72 109.64,126.72 115.22,121.14 121.19,121.14 123.86,118.47 126.43,118.47 128.39,116.5 150.57,116.5 151.23,117.16 158.63,117.16 160.85,119.38 164.58,119.38 165.9,118.06 165.9,116.89 ; 165.9,116.89 v2(166.22,116.89) ; 165.9,116.89 165.9,115.97 165.24,115.32 v3(164.1,115.32)
USB30_RXN3: length 191.6
  TOP w0.102: CPU1.AB6 v4(73.7,164.6) ; 161.41,95.74 160.69,96.47 160.69,101.38 160.99,101.68 161.3,101.68 v3(161.55,101.93) ; 161.41,95.74 163.05,94.11 164.27,94.11 164.49,93.89 L57.1 ; 161.41,95.74 v1(161.17,95.49)
  BOTTOM w0.102: v4(73.7,164.6) 73.68,164.6 72.89,163.81 71.37,163.81 70.53,164.66 70.53,166.36 69.63,167.26 67.09,167.26 64.97,169.38 53.88,169.38 52.79,168.29 52.79,156.23 52.08,155.51 52.08,149.14 51.55,148.61 51.55,145.37 55.34,141.58 55.34,139.7 58.31,136.73 58.31,135.09 62.13,131.28 73.9,131.28 78.8,126.37 82.87,126.37 88.6,120.64 89.33,120.64 89.74,120.23 110.41,120.23 111.53,119.12 113.55,117.09 119.52,117.09 122.18,114.43 124.75,114.43 126.72,112.46 148.56,112.46 152.07,108.95 155.84,108.95 160.79,103.99 160.79,102.69 v3(161.55,101.93)
USB30_RXP2: length 165.7
  TOP w0.102: v3(164.1,116.08) 164.14,116.04 L5.4 ; CPU1.Y6 v4(73.7,165.8)
  BOTTOM w0.102: 165.06,118.54 164.47,119.13 160.95,119.13 158.73,116.91 151.33,116.91 150.68,116.25 128.29,116.25 126.32,118.21 123.75,118.21 121.09,120.88 115.12,120.88 109.53,126.47 88.13,126.47 84.44,130.16 80.37,130.16 74.77,135.76 71.64,135.76 71.27,135.4 67.69,135.4 64.53,138.56 63.74,138.56 63.1,139.2 61.33,139.2 59.71,140.82 59.71,143.77 56.52,146.96 56.52,152.55 57.42,153.45 57.42,155.09 58.77,156.44 66.01,156.44 66.21,156.24 66.78,156.24 66.96,156.06 69.99,156.06 70.55,156.63 70.55,157.55 71.11,158.1 71.11,160.57 70.9,160.78 70.9,162.69 71.21,163 72.36,163 73.43,164.07 73.84,164.07 74.11,164.33 74.11,165.39 v4(73.7,165.8) ; 165.06,118.54 v2(164.8,118.29) ; 165.06,118.54 165.64,117.96 165.64,116.08 165.13,115.57 164.61,115.57 v3(164.1,116.08)
USB30_RXP3: length 191.6
  TOP w0.102: L57.4 164.49,94.57 164.27,94.36 163.56,94.36 ; CPU1.AB5 v4(72.9,164.6) ; v3(161.55,101.17) 161.3,101.42 161.09,101.42 160.94,101.27 160.94,96.57 163.15,94.36 163.56,94.36 ; v1(163.56,94.74) 163.56,94.36
  BOTTOM w0.102: v3(161.55,101.17) 161.04,101.68 161.04,102.08 160.54,102.58 160.54,103.89 155.74,108.69 155.41,108.69 155.26,108.54 154.95,108.54 154.8,108.69 154.5,108.69 154.35,108.54 154.04,108.54 153.89,108.69 151.97,108.69 148.45,112.21 126.61,112.21 124.65,114.17 122.08,114.17 119.41,116.84 113.44,116.84 111.35,118.94 110.31,119.98 89.64,119.98 89.23,120.38 88.5,120.38 82.76,126.12 78.7,126.12 73.79,131.02 62.02,131.02 58.06,134.99 58.06,136.63 55.09,139.6 55.09,141.47 51.29,145.27 51.29,148.71 51.82,149.24 51.82,155.62 52.54,156.33 52.54,168.4 53.77,169.63 65.08,169.63 67.19,167.51 69.73,167.51 70.78,166.47 70.78,164.76 71.48,164.07 72.78,164.07 72.9,164.18 v4(72.9,164.6)
USB30_TXN2: length 161.7
  TOP w0.102: v3(161.81,117.47) C91.1 ; CPU1.AC2 70.53,164.2 70.23,163.9 68.57,163.9 67.82,164.65 67.68,164.79 67.61,164.86 67.61,165.14 v4(67.45,165.3)
  BOTTOM w0.102: v3(161.81,117.47) 161.7,117.37 161.2,117.37 160.83,117.01 ; v2(161.07,116.76) 160.83,117.01 ; 160.83,117.01 158.14,114.32 151.08,114.32 149.98,115.41 127.94,115.41 125.97,117.38 123.41,117.38 120.74,120.05 114.77,120.05 110.64,124.18 89.23,124.18 84.09,129.32 80.03,129.32 75.12,134.23 64.99,134.23 58.87,140.34 58.87,143.42 55.68,146.61 55.68,152.89 56.59,153.79 56.59,155.44 58.43,157.28 66.36,157.28 66.89,156.75 69.77,156.75 70.01,156.99 70.01,157.84 70.52,158.35 70.52,160.02 70.01,160.53 70.01,161.92 67.42,164.52 67.42,165.26 v4(67.45,165.3)
USB30_TXN3: length 184.9
  TOP w0.102: v3(163.95,103.53) 163.42,103 163,103 162.16,102.16 162.16,99.76 161.53,99.12 161.53,96.84 161.98,96.39 162.28,96.39 C113.1 ; CPU1.AC3 71.7,164.28 71.54,164.44 71.12,164.44 71.01,164.55 71.01,164.55 70.77,164.55 70.71,164.49 70.23,164.49 70.23,164.5 70.16,164.5 v4(69.36,165.3)
  BOTTOM w0.102: v2(108.36,121.92) 108.36,121.55 ; 108.36,121.55 110.27,121.55 113.9,117.93 119.86,117.93 122.53,115.26 125.1,115.26 127.06,113.3 148.9,113.3 152.42,109.78 156.19,109.78 162.56,103.4 163.82,103.4 v3(163.95,103.53) ; 108.36,121.55 107.34,121.55 107.19,121.7 106.88,121.7 106.73,121.55 106.43,121.55 106.28,121.7 105.97,121.7 105.82,121.55 105.52,121.55 105.37,121.7 105.06,121.7 104.91,121.55 92.33,121.55 92.18,121.7 91.88,121.7 91.73,121.55 91.42,121.55 91.27,121.7 90.97,121.7 90.82,121.55 90.51,121.55 90.36,121.7 90.06,121.7 89.91,121.55 88.87,121.55 83.21,127.21 79.15,127.21 74.24,132.11 62.47,132.11 59.15,135.44 59.15,137.08 56.18,140.05 56.18,141.93 52.91,145.19 52.91,155.16 53.63,155.88 53.63,167.95 54.22,168.54 64.41,168.54 66.57,166.38 69.24,166.38 69.52,166.1 69.52,165.46 v4(69.36,165.3)
USB30_TXP2: length 161.7
  TOP w0.102: v4(68.09,165.3) 67.86,165.08 67.86,164.96 68.67,164.15 70.05,164.15 CPU1.AC1 ; v3(161.81,118.49) C1757.1
  BOTTOM w0.102: 95.29,124.44 97.89,124.44 98.04,124.59 98.35,124.59 98.5,124.44 98.8,124.44 98.95,124.59 99.26,124.59 99.41,124.44 99.71,124.44 99.86,124.59 100.17,124.59 100.32,124.44 105.4,124.44 105.55,124.59 105.85,124.59 106,124.44 106.31,124.44 106.46,124.59 106.76,124.59 106.91,124.44 107.22,124.44 107.37,124.59 107.67,124.59 107.82,124.44 110.74,124.44 114.88,120.3 120.84,120.3 123.51,117.63 126.08,117.63 128.04,115.67 150.09,115.67 151.18,114.57 158.04,114.57 161.09,117.63 161.21,117.63 161.31,117.73 161.31,118 v3(161.81,118.49) ; 95.29,124.44 92.81,124.44 92.66,124.59 92.36,124.59 92.21,124.44 91.9,124.44 91.75,124.59 91.45,124.59 91.3,124.44 90.99,124.44 90.85,124.59 90.54,124.59 90.39,124.44 89.34,124.44 84.2,129.58 80.13,129.58 75.23,134.48 65.09,134.48 59.13,140.45 59.13,143.53 55.94,146.72 55.94,152.79 56.84,153.69 56.84,155.33 58.53,157.03 66.25,157.03 66.79,156.49 69.87,156.49 70.26,156.88 70.26,157.74 70.77,158.25 70.77,160.13 70.26,160.63 70.26,162.03 67.67,164.62 67.67,164.88 v4(68.09,165.3) ; 95.29,124.44 v2(95.29,124.79)
USB30_TXP3: length 185.1
  TOP w0.102: v4(69.99,165.3) 69.99,165.02 70.32,164.7 70.63,164.7 70.68,164.76 71.12,164.76 71.17,164.7 71.64,164.7 72.14,164.2 CPU1.AC4 ; v3(163.94,102.57) 163.76,102.74 163.1,102.74 162.42,102.05 162.42,99.65 161.78,99.02 161.78,96.95 162.09,96.65 162.28,96.65 C111.1
  BOTTOM w0.102: 96.71,121.3 110.17,121.3 113.79,117.68 119.76,117.68 122.42,115.01 124.99,115.01 126.96,113.04 148.8,113.04 152.31,109.53 156.08,109.53 162.46,103.15 163.55,103.15 163.94,102.77 v3(163.94,102.57) ; 96.71,121.3 88.76,121.3 83.11,126.95 79.04,126.95 74.14,131.86 62.37,131.86 58.97,135.26 58.89,135.33 58.89,136.97 55.92,139.94 55.92,141.82 52.66,145.09 52.66,155.27 53.37,155.98 53.37,168.05 54.12,168.8 64.51,168.8 66.68,166.63 69.34,166.63 69.77,166.2 69.77,165.52 v4(69.99,165.3) ; 96.71,121.3 v2(96.71,120.93)
USB_COMP_M: length 2.5
  TOP w0.203: CPU1.AP5 73.3,155.34 72.95,154.99 v4(72.85,154.99)
  BOTTOM w0.203: R1648.1 72.17,154.62 v2(72.17,155.47) 72.37,155.47 v4(72.85,154.99)
USB_EN: length 8.4
  TOP w0.102: R1783.2 C1764.2 92.68,24.26 C249.1 91.22,24.56 92.34,25.67 v1(92.34,27.05) 91.9,27.05 91.27,26.42 Q43.4
USB_EN1: length 14.6
  TOP w0.102: Q1217.3 94.41,22.11 94.27,21.97 94.27,21.59 94.39,21.46 Q1217.2 95.41,21.46 95.64,21.23 95.64,20.54 93.92,18.82 92.09,18.82 91.83,18.55 89.61,18.55 88.95,19.21 v1(88.95,19.9) 89.05,20 R1780.2 90.52,20.07 R1781.1
USB_EN2: length 8.7
  TOP w0.102: R1779.1 R1777.2 92.15,20 92.64,19.51 92.64,19.51 v1(92.66,19.49) 92.71,19.49 92.72,19.48 93.48,19.48 93.89,19.89 93.89,20.54 93.61,20.81 ; 93.61,20.81 Q1217.6 ; 93.61,20.81 93.91,21.12 93.91,22.12 95.22,23.43 R1783.1
USB_PCH_DN3_NN: length 9
  TOP w0.102: 30.21,7.87 29.6,7.87 29.23,7.5 TOUCH1.4 ; 30.21,7.87 30.49,7.87 30.82,8.2 30.82,9.27 32.04,10.49 32.04,11.25 v3(32.14,11.35) 32.12,11.37 TR9.3 ; 30.21,7.87 v1(30.21,7.47)
  BOTTOM w0.102: v3(32.14,11.35) 32.21,11.43 C1774.1
USB_PCH_DN4_NN: length 18.5
  TOP w0.102: 161.35,193.44 155.71,193.44 155.02,194.13 155.02,197.38 154.67,197.74 154.39,197.74 154.17,197.95 TR1.3 ; 161.35,193.44 v1(161.35,193.85) ; 161.35,193.44 162.57,193.44 163.75,194.62 163.75,196.75 163.25,197.25 WEBCM1.2
USB_PCH_DN5_NN: length 4.6
  TOP w0.102: 107.97,206.21 108.55,205.63 109.38,205.63 109.5,205.75 NGFF1.5 ; 107.97,206.21 v1(108.24,206.48) ; 107.97,206.21 107.81,206.38 107.57,206.38 107.36,206.59 TR12.3
USB_PCH_DP3_PP: length 9
  TOP w0.102: TR9.2 31.44,12.18 31.68,11.94 31.68,11.66 v3(31.38,11.35) 31.78,10.95 31.78,10.6 30.97,9.78 ; 30.97,9.78 v1(30.67,10.08) ; 30.97,9.78 30.56,9.38 30.56,8.31 30.38,8.13 29.6,8.13 29.23,8.5 TOUCH1.3
  BOTTOM w0.102: v3(31.38,11.35) 31.38,11.51 31.4,11.53 31.4,12.18 C1773.1
USB_PCH_DP4_PP: length 18.9
  TOP w0.102: 164,195.55 164,196.75 164.5,197.25 WEBCM1.1 ; 164,195.55 v1(164.4,195.55) ; 164,195.55 164,194.52 162.67,193.19 155.61,193.19 154.77,194.03 154.77,197.28 154.56,197.49 154.39,197.49 154.17,197.27 TR1.2
USB_PCH_DP5_PP: length 4.6
  TOP w0.102: v1(108.19,205.11) 108.45,205.37 ; 108.45,205.37 109.38,205.37 109.5,205.25 NGFF1.3 ; 108.45,205.37 107.7,206.12 107.57,206.12 107.36,205.91 TR12.2
USBCLK_TP: length 8.6
  TOP w0.102: CPU1.AP8 75.7,155.34 v4(75.32,154.96)
  BOTTOM w0.102: v4(75.32,154.96) 74.88,155.4 73.01,155.4 72.45,155.96 71.92,155.96 69.81,153.85 69.71,153.85 v2(69.65,153.8) 69.43,153.57 R2067.1
USBOC01*: length 303.8
  TOP w0.102: v3(108.44,29.11) 108.44,29.51 107.92,30.04 C589.1 R762.1 R1725.2 ; CPU1.AH9 76.2,159.9 v4(76.2,159.56)
  L3 w0.127: v4(76.2,159.56) 75.36,160.4 73.77,160.4 73.53,160.65 73.53,160.65 72.56,161.62 70.69,161.62 68.83,163.48 66.89,163.48 65.31,165.06 65.31,166.13 63.54,167.9 61.19,167.9 59.38,166.09 58.89,166.09 57.75,167.22 48.63,167.22 47.75,166.34 40.86,166.34 39.95,167.25 27.85,167.25 25.35,169.76 16.01,169.76 11.3,165.05 11.3,154.23 13.99,151.54 13.99,136.6 15.84,134.75 30.01,134.75 33.79,130.97 33.79,108.99 36.18,106.6 36.18,91.04 36.82,90.4 36.82,85.45 36.3,84.93 36.3,77.85 36.36,77.79 36.36,76.55 39.63,73.27 39.63,72.74 40.24,72.13 40.24,72.01 42.45,69.8 61.46,69.8 63.81,72.15 85.89,72.15 86.71,71.33 88.11,69.93 94.55,69.93 v3(94.6,69.88)
  L4 w0.127: v3(108.44,29.11) 102.55,29.11 97.32,34.35 97.32,39.62 93.95,42.99 93.95,44.54 92.72,45.77 92.72,55.19 91.87,56.04 91.87,59.96 94.39,62.48 94.88,62.48 95.02,62.62 95.15,62.62 96.08,63.56 96.08,68.39 v3(94.6,69.88)
  BOTTOM w0.102: v3(94.6,69.88) 94.83,69.88 95.26,69.44 v2(95.29,69.44)
USBOC02*: length 338.4
  TOP w0.102: R1728.2 R1727.1 C1756.1 175.17,127.89 174.86,128.19 167.65,128.19 166.53,127.08 v1(166.53,123.77) 166.64,123.67 166.64,123.41 167.24,122.81 v3(167.37,122.81) ; v4(65.16,158.6) 65.16,158.67 67.2,160.72 69.82,160.72 CPU1.AG1
  L3 w0.127: v3(38.26,81.79) 38.26,81.26 38.54,80.98 38.54,79.71 46.42,71.83 60.62,71.83 63.08,74.3 87.26,74.3 88.78,72.77 96.6,72.77 97.17,73.34 105.18,73.34 110.43,68.09 110.43,67.27 112.73,64.97 123.32,64.97 123.93,64.36 127.57,64.36 128.62,65.42 133.28,65.42 133.46,65.6 134.4,65.6 135.35,66.55 137.25,66.55 138.19,67.49 154.75,67.49 155.49,66.74 159.25,66.74 159.82,67.31 160.44,67.31 160.75,67.62 160.75,69.06 159.01,70.8 158.31,70.8 157.88,71.23 157.88,72 157.51,72.37 157.51,73.08 155.99,74.61 155.99,75.06 155.43,75.62 155.43,75.92 155.39,75.95 155.39,80.24 155.43,80.28 155.43,86.4 156.42,87.39 156.42,92.63 161.99,98.2 v3(163.94,98.2) ; v3(37.63,151.13) 37.63,151.86 38.63,152.86 39.92,152.86 40.51,152.27 42.99,152.27 43.9,153.18 43.9,159.3 42.45,160.75 42.45,161.5 43.12,162.17 50.24,162.17 52.33,160.08 57.15,160.08 58.64,158.6 v4(65.16,158.6)
  L4 w0.127: v3(37.63,151.13) 37.63,148.95 37.54,148.86 37.54,139.22 38.26,138.5 38.26,136.09 38.01,135.84 38.01,134.61 38.01,134.61 38.01,134.29 38.01,133.98 38.01,123.16 40.38,120.79 40.38,83.91 v3(38.26,81.79) ; v3(167.37,122.81) 169.36,120.82 169.36,111.58 167.91,110.13 167.91,106.1 165.39,103.58 165.39,98.93 164.65,98.2 v3(163.94,98.2)
USBP0N_EXT: length 20
  TOP w0.102: TR10.3 95.39,33.22 95.39,30.06 94.7,29.38 94.7,28.84 D24.6 94.7,28.41 94.7,27.97 94.88,27.79 95.44,27.79 95.92,28.27 95.92,31.58 96.3,31.96 96.3,34.14 99.31,37.16 100.77,37.16 101.06,37.45 USB3.2
USBP0P_EXT: length 20.2
  TOP w0.102: USB3.3 100.19,36.9 99.42,36.9 96.55,34.04 96.55,31.85 96.17,31.47 96.17,28.16 95.54,27.54 94.77,27.54 94.7,27.61 94.45,27.86 94.45,29.48 95.13,30.17 95.13,31.1 D24.1 95.13,31.53 95.13,32.53 94.77,32.89 TR10.2
USBP1N_EXT: length 24.7
  TOP w0.102: TR14.3 93.16,33.12 92.8,32.75 92.8,31.53 D24.3 92.8,31.1 92.8,30.27 93.48,29.59 93.48,26.52 95.27,24.73 ; 95.27,24.73 v1(95.51,24.97) ; 95.27,24.73 96.58,23.42 96.58,17.46 99.88,14.16 100.93,14.16 101.06,14.28 USB4.2
USBP1P_EXT: length 24.6
  TOP w0.102: 93.77,25.87 96.32,23.31 96.32,17.35 99.78,13.9 100.19,13.9 USB4.3 ; 93.77,25.87 v1(93.51,25.6) ; 93.77,25.87 93.23,26.41 93.23,28.41 D24.4 93.23,28.84 93.23,29.48 92.54,30.17 92.54,33.22 TR14.2
USBP6N_EXT: length 20.7
  TOP w0.102: SSUSB1.2 172.94,117.52 173.44,117.52 173.72,117.81 174.52,117.81 175.29,117.03 175.29,112.39 170.98,108.08 168.63,108.08 167.95,108.77 167.12,108.77 D4.1 166.69,108.77 166.21,108.77 165.96,108.51 165.36,108.51 165.22,108.37 TR3.2
USBP6P_EXT: length 20.7
  TOP w0.102: TR3.3 165.13,109.05 165.42,108.76 165.85,108.76 166.11,109.02 168.05,109.02 168.74,108.34 169.38,108.34 D4.6 169.81,108.34 170.87,108.34 175.04,112.5 175.04,116.93 174.41,117.55 173.83,117.55 172.62,116.35 SSUSB1.3
USBP7N_EXT: length 22
  TOP w0.102: SSUSB2.2 172.47,96.34 172.35,96.21 172.35,95.59 172.47,95.47 172.88,95.47 173.72,96.31 174.53,96.31 175.1,96.87 175.1,99.77 172.45,102.42 172.45,104.44 170.71,106.18 168.61,106.18 167.93,106.86 167.12,106.86 D4.3 166.69,106.86 166.09,106.86 165.45,106.21 TR4.2
USBP7P_EXT: length 22.1
  TOP w0.102: SSUSB2.3 172.62,94.85 173.83,96.05 174.64,96.05 175.35,96.76 175.35,99.88 172.7,102.52 172.7,104.55 170.82,106.43 169.81,106.43 D4.4 169.38,106.43 168.72,106.43 168.03,107.12 165.99,107.12 165.77,106.89 TR4.3
USBSS_CALRN: length 11.6
  TOP w0.127: CPU1.AD2 70.98,163.72 70.35,163.72 70.32,163.68 68.13,163.68 67.85,163.96
  TOP w0.203: 67.85,163.96 66.92,164.89 66.92,170.27 v1(66.96,170.31) 66.84,170.43 R1649.1
USBSS_CALRP: length 15.9
  TOP w0.203: R559.1 60.17,170.37 v1(60.23,170.43) 60.45,170.22 63.24,170.22 66.45,167 66.45,164.34 67.39,163.4 CPU1.AD1
USBVCC01: length 19.2
  TOP w0.508: 101.06,39.5 USB3.1 ; USB3.1 100.03,40.53 ; USB3.1 101.06,41.56 ; USB3.1 102.09,40.53 ; 105.15,24.51 TC7.1 ; TC7.1 107.26,24.51 ; TC7.1 106.21,23.46 ; TC7.1 106.21,25.57 ; 101.06,18.56 USB4.1 102.09,17.53 ; 100.62,28.63 98.19,28.63 C1747.1 C1754.2 94.58,26.86 93.97,27.48 D24.5
USBVCC01_E: length 3.7
  TOP w0.508: L55.1 108.17,18.86 C872.1 109.09,18.86 109.46,18.49 v1(109.46,16.99)
USBVCC23: length 18.4
  TOP w0.508: C1753.2 170.92,107.31 v3(170.64,107.6) D4.5 ; 172.62,121.23 SSUSB1.1 171.73,120.34
  TOP w1.016: v1(168.05,121.89) 168.08,121.87 169.91,121.87 ; v3(166.07,110.19) 167.01,111.12 C104.1 C105.2
  L3 w0.508: 171.73,98.84 SSUSB2.1 172.62,99.73 ; 172.62,119.45 SSUSB1.1 ; SSUSB1.1 171.73,120.34 ; SSUSB1.1 172.62,121.23 ; TC8.1 167.97,100.33 ; TC8.1 166.91,101.38 ; TC8.1 166.91,99.28
USBVCCTP:
  vias: v1(29.62,5.08) v2(26.96,8.13) v5(26.54,5.79) v5(26.55,6.83)
V_0P675_S3: length 96.5
  TOP w0.33: v3(134.5,127.35) 134.5,127.23 133.95,126.68 132.07,126.68 DIMM1.203 ; DIMM2.203 147.82,127.55 v3(148.12,127.25) ; DIMM1.204 v3(137.83,127.25) ; v3(153.07,127.25) 153.07,127.25 DIMM2.204
  TOP w0.508: PR5018.2 134.91,76.71 v5(133.89,77.72) 134.91,78.74 PR5019.2
  L4 w0.508: v3(148.12,127.25) 144.7,123.84 137.64,123.84 134.81,121 134.81,109.95 132.19,107.33 132.19,97.85 132.41,97.63 132.41,79.18 133.87,77.72 v5(133.89,77.72)
  BOTTOM w0.508: v3(153.07,127.25) 152.84,127.48 152.84,127.53 152.45,127.91 150.81,127.91 C1724.1 149.45,127.38 C1732.1 148.56,127.7 v3(148.12,127.25) 148.12,125.58 147.7,125.17 141.4,125.17 140.38,126.18 v2(140.38,126.26) 140.38,126.61 139.29,127.7 C1977.1 138.28,127.7 v3(137.83,127.25) 137.06,128.02 C1971.1 135.14,128.02 135.09,127.96 135.08,127.96 134.63,127.52 134.63,127.48 v3(134.5,127.35)
V_1P5_HDMI: length 119.5
  TOP w0.203: U118.12 134.14,38.67 134.51,39.04 134.6,39.04 135.16,39.6 135.16,40.42 C3381.2 ; U118.20 130.94,38.73 ; 130.94,38.73 131.07,38.86 131.21,38.86 131.34,38.73 U118.19 ; 130.94,38.73 130.36,39.31 130.36,40.42 C3378.1 ; v3(135.17,33.13) 134.95,33.13 134.84,33.03 U118.40 134.54,32.73 135.42,31.85 135.8,31.85 136.28,31.37 136.28,30.69 C3376.2 ; v3(130.3,33.03) U118.31 130.94,32.52 130.27,31.85 129.66,31.85 128.8,30.99 C3377.1
  TOP w0.508: C3378.1 128.82,41.09 C3383.1 C3366.1 127.92,40.56 127.95,40.53 127.95,40.36 128.18,40.13 128.71,40.13 v3(128.81,40.23) ; v3(128.05,45.47) 128.05,45.03 127.52,44.5 R2081.1 ; C3381.2 v3(135.79,40.13) ; v3(156.59,85.47) 156.59,86.89 R79649.1
  L4 w0.508: v3(128.81,40.23) 128.84,40.26 129.67,40.26 ; 129.67,40.26 130.49,39.44 130.49,33.22 v3(130.3,33.03) ; 129.67,40.26 129.71,40.26 131.65,42.21 131.65,60.02 133.28,61.65 133.28,63.35 132.49,64.14 132.49,67.28 134.83,69.62 135.42,69.62 136.18,70.38 136.18,71.77 136.96,72.56 136.96,72.67 v3(138.72,74.42)
  BOTTOM w0.508: v3(130.3,33.03) 134.84,33.03 134.95,33.13 v3(135.17,33.13) ; C3381.2 v3(135.79,40.13) 134.43,38.77 130.27,38.77 v3(128.81,40.23) 128.02,41.02 128.02,45.44 v3(128.05,45.47) 128.05,45.62 129.17,46.74 U119.2 ; v3(156.59,85.47) 153.83,82.71 v2(152.35,82.71) 151.74,82.71 143.45,74.42 v3(138.72,74.42)
V_1P05_LAN: length 10.6
  TOP w0.203: v3(40.93,16.26) U16.8 ; v3(38.42,11.28) 38.48,11.33 U16.30 ; v3(35.65,12.09) 35.79,12.23 U16.24 ; v3(40.93,14.26) U16.3 ; U16.22 v3(34.83,14.26)
  TOP w0.406: C213.1 41.56,18.34 41.05,17.83 41.05,16.38 v3(40.93,16.26)
  TOP w0.508: v3(40.93,14.26) 41.97,14.26 C574.1
  vias: v2(34.48,13.11)
V_1P5_PWR:
  vias: v1(33.66,146.18)
V_1P8_VDDIO:
  vias: v1(26.37,147.35)
V_3_CARD_BD:
  vias: v1(163.81,143.86)
V_3P0_BAT_VREG: length 191.5
  TOP w0.508: D23.3 74.52,49.07 75.09,49.65 75.09,51.17 75.29,51.37 75.29,56.06 75.62,56.39 77.58,56.39 79.18,57.99 79.18,60.97 v3(79.23,61.02) ; v3(153.28,100.97) 153.48,101.17 153.55,101.17 153.94,101.55 153.94,101.63 157.34,105.03 163.03,105.03 163.72,104.34 167.32,104.34 168.74,102.92 168.74,99.72 167.55,98.53 167.55,97.97 v3(167.52,97.94)
  L3 w0.508: v3(161.98,62.66) 160.35,61.04 149.06,61.04 147.84,62.26 142.83,62.26 140.92,60.35 137.05,60.35 136.89,60.2 135.29,60.2 135.02,60.46 112.96,60.46 111.2,58.7 108.45,58.7 107.59,59.56 107.59,59.56 96.11,59.56 94.65,61.02 v3(79.23,61.02)
  L4 w0.508: v3(161.98,62.66) 161.98,72.89 162.49,73.4 162.49,74.07 164.73,76.3 164.73,81.46 169.35,86.09 169.35,91.31 167.55,93.12 167.55,97.92 v3(167.52,97.94) ; v3(153.28,100.97) 153.59,100.97 153.94,101.31 153.94,105.28 154.9,106.24 154.9,108.28 159.29,112.67 v3(159.29,120.9)
  BOTTOM w0.508: v3(153.28,100.97) 153.5,100.97 v2(154.03,100.43) ; v3(161.98,62.66) 162.01,62.64 163.15,62.64 R322.2
V_3P3_A: length 641.3
  TOP w0.203: v3(143.42,60.83) 143.95,60.83 U109.64 ; U109.32 158.4,59.76 160.33,61.7 160.66,61.7 160.94,61.98 C550.2 ; U109.1 v3(159.7,46.38)
  TOP w0.254: v3(159.93,62.23) 159.99,62.29 C550.2 ; PG4902.2 PT4902.1
  TOP w0.508: v3(152.94,65.38) R353.1 152.1,64.58 151.98,64.71 R79688.2 R79687.2 ; v3(63.79,49.99) 64.22,49.99 66.23,51.99 66.23,52.04 66.75,52.57 v3(67.67,52.57) ; R675.2 159.04,40.58 R668.2 v3(160.84,39.69) ; v3(43.72,165.48) 45.12,165.48 45.25,165.61 R2018.2 ; v3(127.26,65.35) 128.81,63.8 133.89,63.8 135.84,61.85 v3(136.69,61.85) ; L60.2 142.53,38.74 143.14,38.13 143.77,38.13 144.41,37.49 145.6,37.49 146.55,36.54 147.06,36.54 147.14,36.46 148.8,36.46 149.4,37.06 149.53,37.06 150.17,37.7 150.17,38.71 v3(150.07,38.81) ; v3(16.88,161.86) 16.88,160.82 16.21,160.15 15.84,160.15 PR4805.1 ; R80212.2 102.46,56.39 v3(103.16,56.39) 103.16,56.26 103.79,55.63 R79707.1 ; R644.2 119.81,46.88 120.77,45.91 122.22,45.91 U7.8 125.84,46.61 126.65,47.42 126.65,50.48 v3(126.64,50.49) 126.64,50.74 127.64,51.74 130,51.74 132.13,49.62 R1824.2 R645.2 132.13,46.91 R1823.2 ; v3(65.69,64.41) 65.69,65.41 66.44,66.15 PR5273.1 PR5281.1 ; v3(67.67,52.57) v3(67.67,55.36) 67.83,55.36 68.46,55.99 68.46,60.35 ; v3(67.67,52.57) 68.63,51.61 v3(71.74,51.61) 73.05,51.61 R1672.2 73.07,55.77 75.73,58.42 v3(77.38,58.42) ; v3(67.22,60.83) 67.98,60.83 68.46,60.35 ; R650.2 R655.2 119.18,50.8 118.98,50.6 v3(118.98,50.49) ; PR5289.1 69.46,60.64 69.16,60.35 68.46,60.35 ; R643.1 146.51,32.42 R639.1 147.05,32.98 v3(147.34,33.27) ; PR190.2 v3(107.86,6.54) ; v3(24.11,2.82) 24.21,2.92 46.52,2.92 47.28,2.16 83.98,2.16 85.83,4.01 85.83,11.51 87.6,13.27 C1699.1 ; R702.1 v3(145.83,65.51)
  L3 w0.508: 106.97,3.73 106.97,4.95 107.86,5.84 v3(107.86,6.54) ; v3(103.16,56.39) 103.44,56.11 103.44,55.1 102.92,54.58 99.35,54.58 98.18,55.75 v3(93,55.75) 92.49,55.75 91.53,56.71 89.29,56.71 86.75,59.24 83.1,59.24 82.28,58.42 v3(77.38,58.42) ; v5(113.32,65.79) 113.43,65.67 123.95,65.67 124.24,65.38 127.24,65.38 v3(127.26,65.35) ; v3(17.32,170.43) 17.47,170.59 18.98,170.59 19.46,171.07 19.97,171.07 20.61,170.43 v3(23.78,170.43) ; v3(159.93,62.23) 159.49,61.8 155.4,61.8 152.94,64.26 v3(152.94,65.38) 151.65,65.38 150.91,64.64 146.69,64.64 v3(145.83,65.51) 144.64,65.51 142.66,63.53 142.3,63.53 140.62,61.85 v3(136.69,61.85)
  L4 w0.508: v3(150.07,38.81) 150.27,38.61 150.27,36.83 147.34,33.9 v3(147.34,33.27) ; v3(126.64,50.49) 128.05,51.9 128.05,57.15 127.26,57.94 v3(127.26,65.35) ; v3(17.32,170.43) 16.77,169.89 16.77,166.59 16.16,165.97 16.16,163.63 16.88,162.91 v3(16.88,161.86) 16.96,161.78 16.96,153.41 17.33,153.04 17.33,148.8 21.75,144.38 21.75,139.72 24.66,136.82 30.34,136.82 32.82,134.33 32.82,122.35 33.38,121.79 33.38,118.71 33.56,118.54 33.56,104.93 34.25,104.25 34.25,102.92 35.06,102.11 35.06,98.21 35.08,98.19 35.08,89.6 32.33,86.85 32.33,77.61 31.71,76.99 31.71,74.02 31.32,73.63 31.29,73.63 30.72,73.06 30.72,73.03 30.33,72.64 29.91,72.64 26.37,69.11 26.37,55.12 30,51.49 30,43.97 25.18,39.14 25.18,28.96 26.09,28.04 26.09,27.58 v3(25.94,27.43) 25.34,26.84 25.34,24.24 26.96,22.63 26.96,14.99 26.42,14.45 26.42,12.68 26.55,12.55 26.55,11.32 26.3,11.07 26.3,10.9 24.11,8.71 v3(24.11,2.82) ; v3(103.16,56.39) 103.16,56.64 103.79,57.28 110.91,57.28 113.32,59.69 v5(113.32,65.79) ; v3(145.45,5.16) 145.65,5.16 147.47,6.99 147.96,6.99 147.96,6.99 148.9,6.99 149.29,7.37 149.44,7.52 149.85,7.94 149.85,16.75 160.84,27.74 v3(160.84,39.69) 160.29,40.24 160.29,43.88 159.67,44.5 159.67,46.35 v3(159.7,46.38) 161.32,48 161.32,52.56 159.87,54.01 159.42,54.01 159.04,54.39 159.04,54.94 159.1,55 159.1,56.39 159.48,56.77 159.97,56.77 160.36,57.16 160.36,58.51 159.93,58.94 v3(159.93,62.23)
  BOTTOM w0.508: v3(67.22,60.83) PR4427.1 66.39,62.04 65.69,62.74 v3(65.69,64.41) ; v3(71.74,51.61) 71.88,51.75 PR4450.2 ; Q9649.S 89.38,52.87 C6725.2 R80228.2 89.95,55.24 90.46,55.75 v3(93,55.75) ; 159.67,46.35 C1826.2 ; 159.67,46.35 159.67,45.42 C1824.1 158.26,44.01 R80217.1 ; 159.67,46.35 v3(159.7,46.38) 160.6,47.28 R276.1 ; v3(152.94,65.38) v2(152.94,66.29) ; v3(160.84,39.69) 158.97,39.69 156.62,37.34 155.2,37.34 154.62,37.92 154.62,38.32 154.23,38.71 153.83,38.71 153.78,38.76 150.12,38.76 v3(150.07,38.81) ; v3(143.42,60.83) 143.67,60.83 143.67,60.84 144.37,60.84 C1820.2 144.43,63.5 v2(144.56,63.63) 145.83,64.9 v3(145.83,65.51) ; PR4425.1 v3(67.67,52.57) ; v3(25.94,27.43) 26.26,27.11 R1760.1 ; v3(43.72,165.48) 42.58,166.62 28.45,166.62 24.64,170.43 v3(23.78,170.43) ; R319.1 163.39,63.68 163.35,63.72 161.92,63.72 160.43,62.23 v3(159.93,62.23) ; PR4426.1 v3(67.67,55.36) ; v3(63.79,49.99) PR5278.1 PR5286.2 ; v3(126.64,50.49) v3(118.98,50.49)
  vias: v3(88.76,14) v5(88.25,15.72) v5(88.25,14.71) v5(88.55,4.7) v5(88.55,3.68) v5(138.31,8.68) v5(138.31,7.71) v5(139.23,8.13)
V_3P3_LAN: length 96.9
  TOP w0.203: U16.32 39.28,12.16 39.76,11.68 v3(39.78,11.68) ; v3(34.84,12.09) 34.84,13.47 35.23,13.86 U16.23 ; v3(38.48,17.91) U16.11
  TOP w0.508: v3(70.77,28.11) 70.77,28.83 C1802.1 70.52,29.91 C1806.1 ; v4(77.5,27.64) 77.5,28.8 77.78,29.08 U12.5 R79618.1 ; C3454.1 38.51,19.02 38.51,17.94 v3(38.48,17.91) ; v3(41.1,10.03) 40.91,10.22 R1819.1 40.29,11.15 39.78,11.66 v3(39.78,11.68) ; v3(34.84,12.09) 34.82,12.06 34.01,12.06 C572.1 ; v3(47.94,14.61) C1807.1 C1803.1 C209.1 C1804.1 v3(48.29,16.87) ; U10.5 v3(47.2,11.94)
  L3 w0.508: v3(41.1,10.03) 41.31,9.83 46.57,9.83 47.2,10.46 v3(47.2,11.94)
  L4 w0.508: v3(39.78,11.68) 39.56,11.46 39.53,11.46 38.7,10.62 35.38,10.62 34.84,11.16 v3(34.84,12.09) 34.84,12.71 36.23,14.1 36.23,16.76 37.37,17.91 38.48,17.91 v3(38.48,17.91) ; v3(47.94,14.61) 47.2,13.87 v3(47.2,11.94)
  BOTTOM w0.508: v3(39.78,11.68) 39.47,11.68 39.02,12.13 C3453.1 ; v3(29.78,9.09) 29.87,9.09 31.4,7.56 R1816.1 ; v3(48.29,16.87) 48.29,18.8 49.23,19.74 58.68,19.74 63.05,24.1 67.06,24.1 v2(67.09,24.13) 69.1,24.13 70.77,25.81 v3(70.77,28.11) 71.39,28.73 76.41,28.73 v4(77.5,27.64) ; U11.5 v3(47.2,11.94) ; C587.1 C84.1 38.42,17.97 v3(38.48,17.91)
  BOTTOM w1.016: v3(41.1,10.03) 41.1,9.6 41.94,8.76 Q44.D
V_3P3_PCIVAUX: length 46.3
  TOP w0.305: 120.18,223.14 119.54,222.5 NGFF1.72
  TOP w0.508: Q1229.G 102.05,223.58 R1.1 R1932.1
  TOP w0.762: v5(102.46,225.17) Q1229.G
  L3 w1.27: 121.64,205.36 121.89,205.61 121.89,225.08 v5(121.52,225.45)
  L4 w1.016: v5(102.46,225.17) 103.66,226.37 120.6,226.37 v5(121.52,225.45)
  vias: v2(121.83,205.36) v3(121.64,204.17) v3(121.64,203.3)
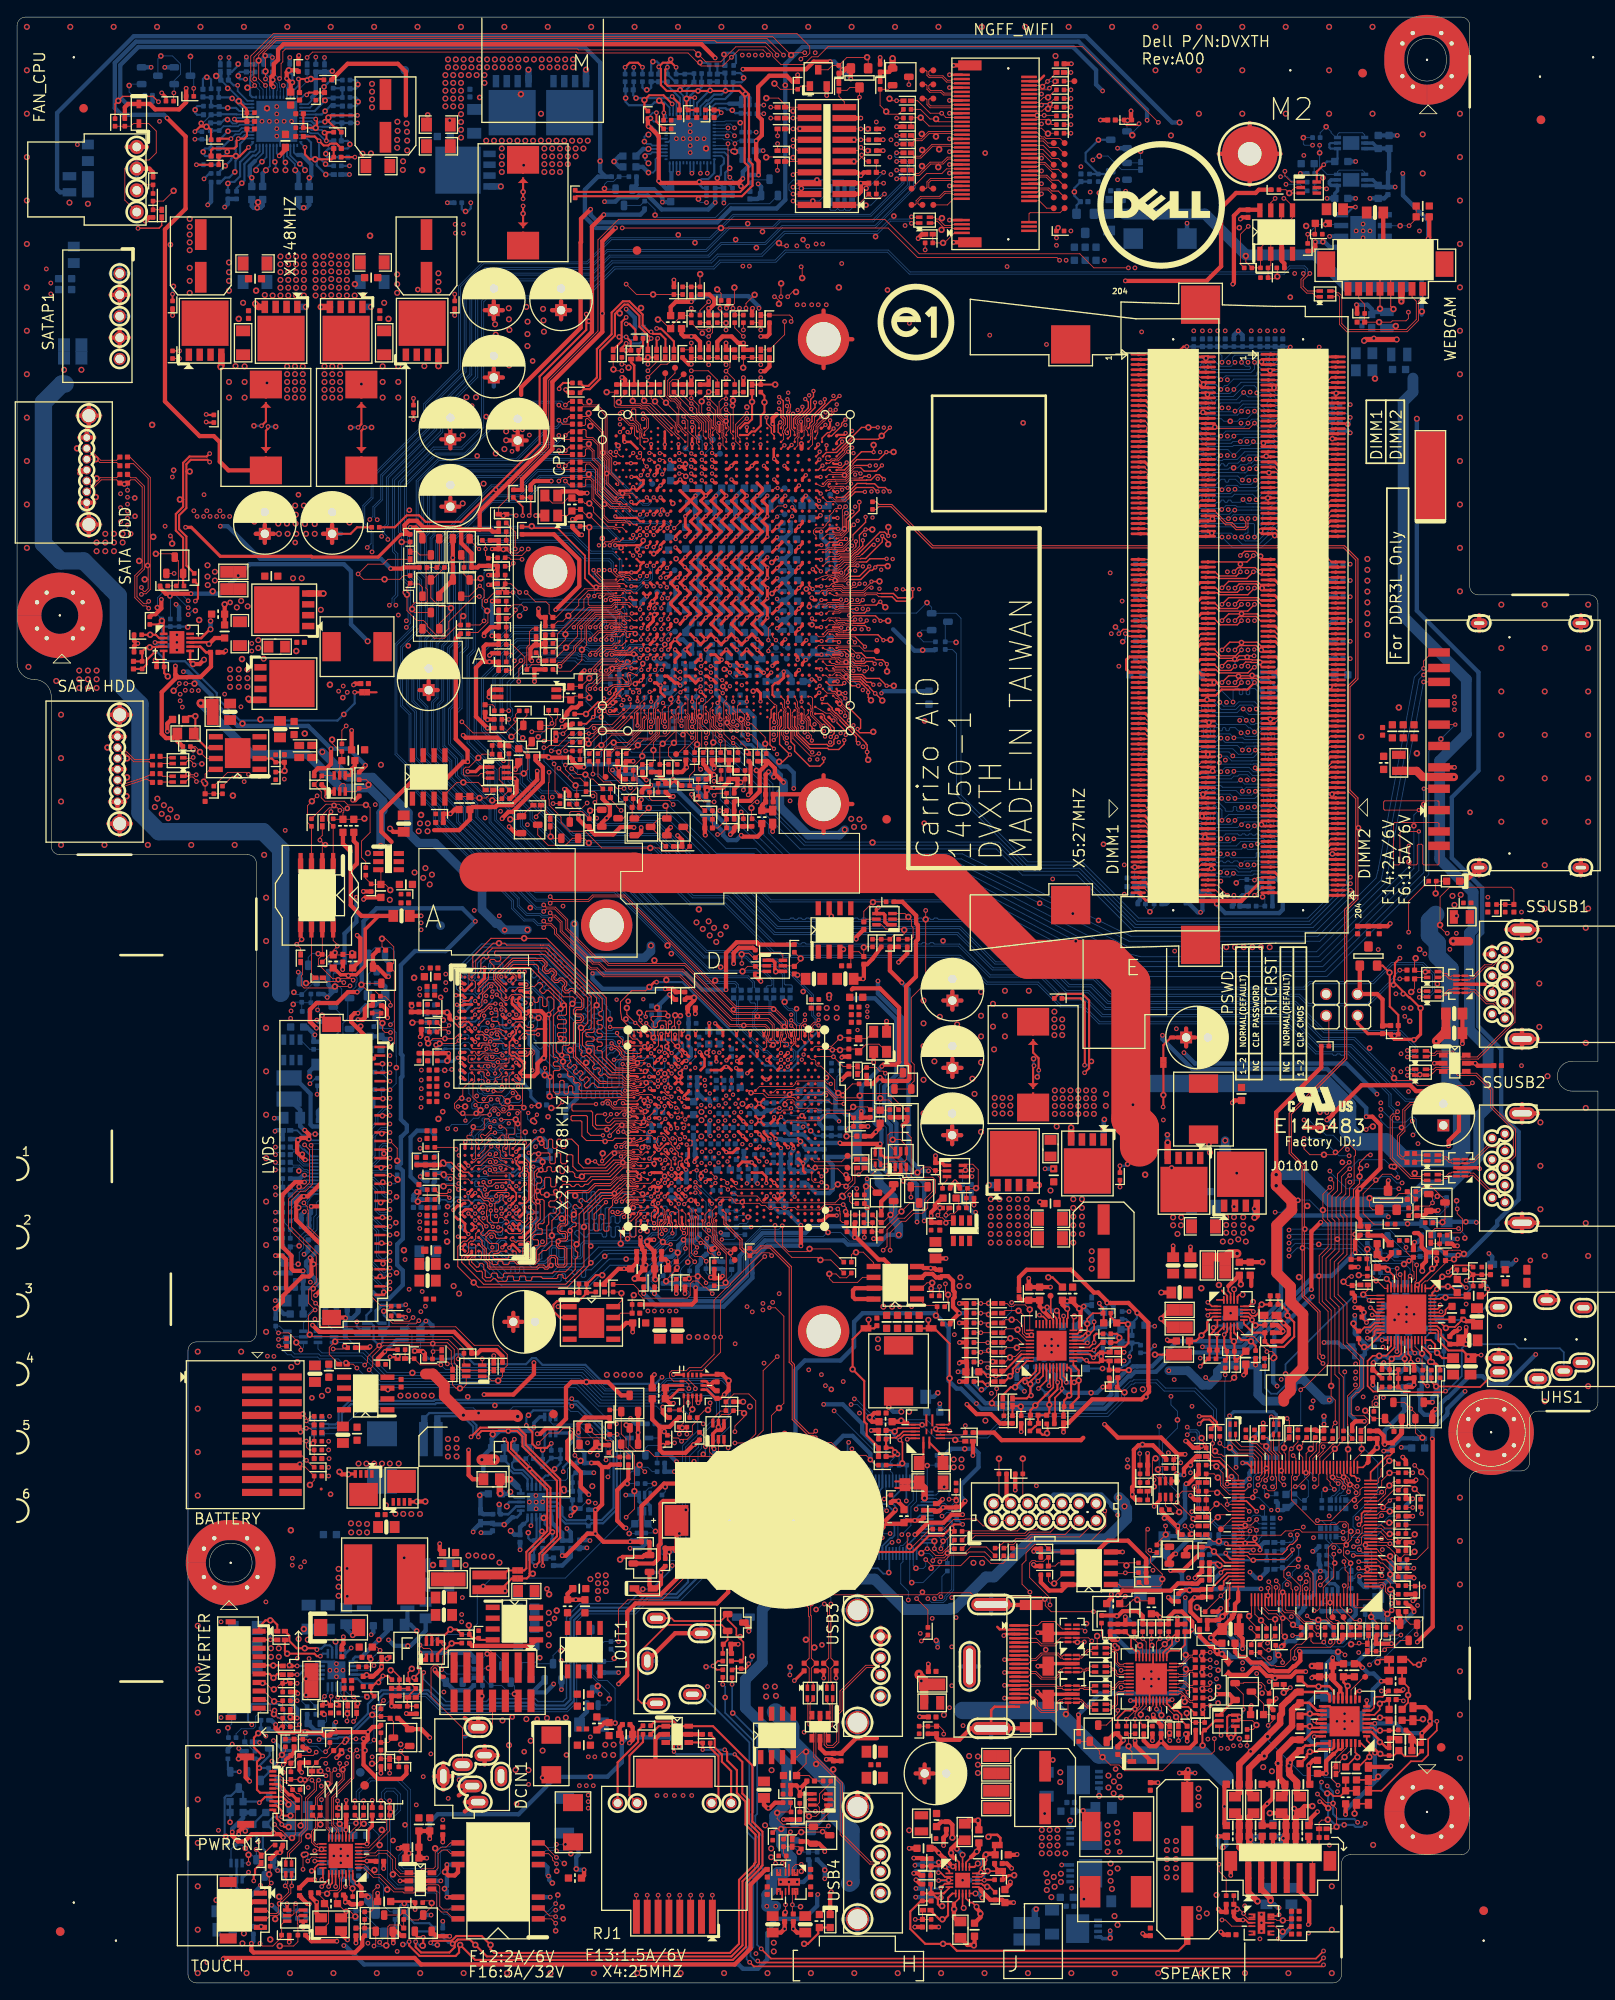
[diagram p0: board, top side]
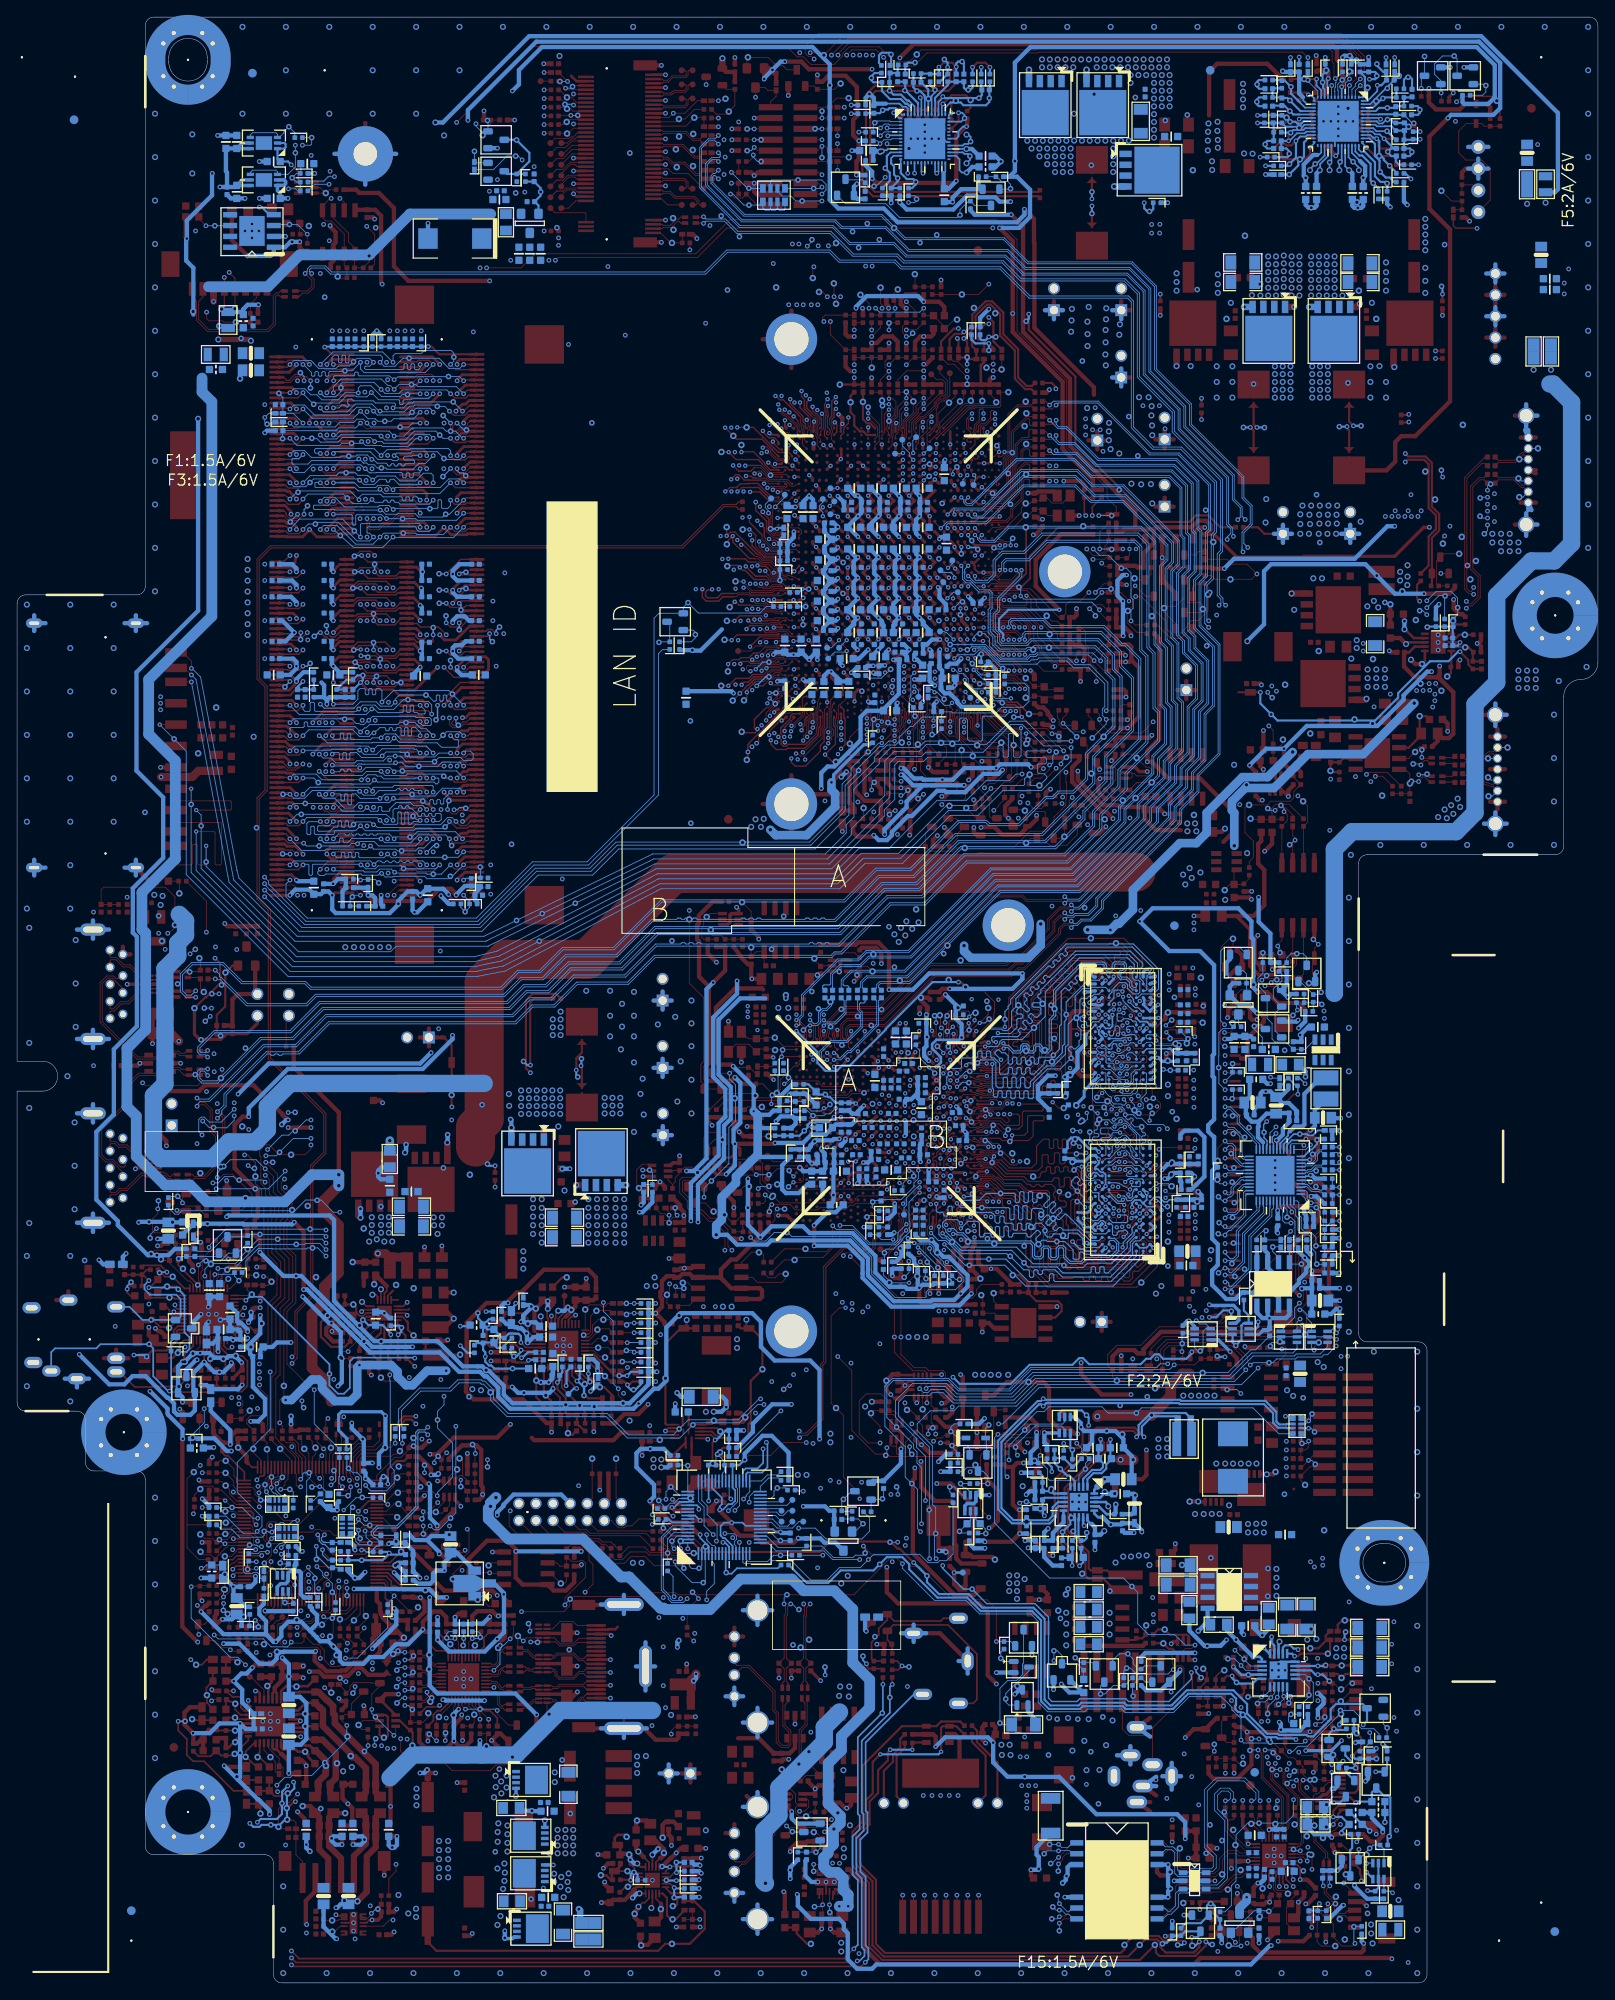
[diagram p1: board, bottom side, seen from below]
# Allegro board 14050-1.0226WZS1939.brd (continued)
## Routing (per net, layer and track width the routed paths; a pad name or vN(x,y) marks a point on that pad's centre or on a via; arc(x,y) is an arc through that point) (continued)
V_5_CODEC: length 24.5
  TOP w0.203: U6.39 166.19,76.83 166.66,76.37 166.66,75.75 C147.2
  TOP w0.508: v3(169.58,76.71) 169.58,75.77 C146.1 168.55,74.74 C147.2
  L4 w0.508: v3(170.77,88.98) 170.77,78.89 169.58,77.7 v3(169.58,76.71)
  BOTTOM w0.508: v3(170.77,88.98) 170.7,89.04 v2(169.55,89.04) 167.36,89.04 C450.1 165.69,88.98 L19.1
V_5_LCD1: length 1.7
  BOTTOM w0.508: v2(34.22,106.02) 34.22,106.65 L1.1
V_5_LCD2:
  vias: v2(36.66,109.12)
V_5HDD: length 8.5
  BOTTOM w0.508: 12,198.93 SATAP1.1 ; SATAP1.1 12,201.07 ; SATAP1.1 13.07,200 ; SATAP1.1 10.93,200 ; 10.93,195 SATAP1.3 ; SATAP1.3 13.07,195 ; SATAP1.3 12,193.93 ; SATAP1.3 12,196.07
V_5P0_A: length 239.1
  TOP w0.203: U52.4 144.09,7.04 143.76,7.37 v3(143.46,7.37) ; U54.4 90.33,13.86
  TOP w0.254: PG4903.1 PT4903.1
  TOP w0.457: v3(143.46,7.37) 142.78,7.37 142.39,7.76 C1829.1
  TOP w0.508: v3(152.56,89) 151.47,87.91 151.47,81.13 v3(151.47,81.13) ; R79708.1 v3(111.86,61.71)
  L4 w0.508: v3(143.46,7.37) 143.13,7.37 142.88,7.61 142.88,8.61 143.29,9.02 v3(143.67,9.02) ; v3(91.09,63.63) 91.09,62.99 87.39,59.29 87.39,50.34 89.49,48.24 89.49,35.48 v5(88.68,34.67) ; v3(112.27,67.78) 112.27,62.12 v3(111.86,61.71)
  L4 w2.032: v5(97.42,11.66) 97.42,10.77 95.16,8.51 95.16,5.08 95.94,4.29 134.37,4.29 135.54,5.46 135.54,8.38 137.45,10.29 v5(140.37,10.29)
  BOTTOM w0.508: v3(91.09,63.63) 91.09,71.73 92.18,72.82 96.35,72.82 97.95,74.42 97.95,77.34 98.97,78.36 107.35,78.36 109.02,76.68 109.02,70.46 109.95,69.53 110.46,69.53 112.17,67.82 112.23,67.82 v3(112.27,67.78) 112.87,67.18 127.3,67.18 128.68,68.57 128.68,69.61 130.04,70.97 130.29,70.97 130.83,71.5 133.28,71.5 135.54,73.76 143.7,73.76 151.07,81.13 v3(151.47,81.13) ; v3(152.56,89) 152.82,88.75 158.5,88.75 158.58,88.82 v2(162.72,88.82) D21.K 165.64,87.55 L19.2
  BOTTOM w2.032: 88.76,31.7 90.53,29.92 90.53,28.17 95.85,22.85 95.85,19.56 97.59,17.82 97.59,11.84 v5(97.42,11.66)
  vias: v5(87.61,34.67) v5(87.66,33.5) v5(88.81,33.58) v5(138.26,22.72) v5(138.26,21.75) v5(138.26,20.79)
V_5P0_HDMI_CONN: length 3
  TOP w0.305: HDMI2.2 115.85,41.32 115.79,41.38 114.99,41.38 114.71,41.66
  BOTTOM w0.508: v2(107.56,40.06) 107.73,39.9 v3(107.73,39.27)
V_5P0_HDMI_CONN_L: length 4.6
  TOP w0.965: F13.2 106.15,34.9 L46.2
  TOP w1.016: L46.2 106.13,35.43 105.54,36.02 v3(105.54,36.16)
  BOTTOM w0.508: v2(105.82,35.33) 105.54,35.61 v3(105.54,36.16)
V_19_INV:
  vias: v1(48.67,48.9)
V_VCORE_EN: length 17.3
  TOP w0.102: R508.2 v3(20.67,221.67)
  L3 w0.127: v3(31.15,222) 31.15,221.62 30.88,221.35 20.99,221.35 v3(20.67,221.67)
  BOTTOM w0.102: v3(31.15,222) 31.19,221.96 PU4601.9 ; v2(20.29,225.4) Q51.D 20.67,222.76 v3(20.67,221.67)
VBYP_2: length 3.1
  TOP w0.102: PU5201.3 109.6,63.72 v1(109.79,63.53) 109.94,63.37 R79708.2
VCORE_PWROK: length 129.6
  TOP w0.102: R1904.2 R1623.2 89.82,192.85 v3(89.82,194.39) ; v3(91.73,225.09) 92.01,225.38 92.37,225.38 92.77,225.78 92.77,226.57 91.27,228.07 29.98,228.07 27.65,225.74 27.45,225.54 27.45,225.53 27.34,225.43 27.34,224.61 27.34,222.57 27.8,222.11 v3(27.8,222) 27.55,221.74 v1(26.96,221.74)
  L3 w0.127: v3(91.73,225.09) 90.88,224.24 90.88,221.56 95.63,216.81 95.63,196.6 94.89,195.87 91.31,195.87 v3(89.82,194.39)
  L4 w0.127: v3(91.73,225.09) 86.49,219.86 v3(86.49,216.53)
  BOTTOM w0.102: PR5466.2 v3(86.49,216.53) ; v3(27.8,222) 28.39,221.41 PU4601.2
VGA_1P8_EN1: length 7.5
  TOP w0.102: 108.3,93.38 108.3,93.41 108.82,93.93 Q97.3 ; 108.3,93.38 R1164.2 ; 108.3,93.38 107.98,93.7 107.98,94.21 107.48,94.72 R1914.1 ; Q97.2 108.24,95 108.17,95.06 R1914.1 ; v1(105.37,94.82) 105.42,94.82 106.05,95.45 106.85,95.45 107.25,95.06 R1914.1
VGA_1P8_EN2: length 7.7
  TOP w0.102: R1915.1 R1919.1 111.09,92.84 R1918.2 112.2,92.96 v1(112.22,92.99) 112.48,93.24 112.48,95.15 111.84,95.78 110.84,95.78 Q97.6
VGA_1P8_EN3: length 4.1
  TOP w0.102: R1916.2 107.98,90.43 107.98,90.02 107.78,89.81 v3(107.75,89.81) 108.05,89.52 108.3,89.52 108.62,89.2 U42.3
  BOTTOM w0.102: v2(107.98,90.68) 107.98,90.02 107.78,89.81 v3(107.75,89.81)
VGA_1P8_EN4: length 5.1
  TOP w0.102: R1916.1 109.11,90.56 108.69,90.14 v3(108.69,89.81) 109.03,89.81 109.21,89.99 109.66,89.99 110.21,90.54 R1915.2 110.21,91.5 C859.1
  BOTTOM w0.102: v2(108.69,88.93) v3(108.69,89.81)
VGA_CORE: length 120.9
  TOP w0.305: GPU1.AA12 86.4,96.57 v4(86.86,96.12)
  TOP w0.508: 109.43,98.13 PT1.1 ; PT1.1 110.49,99.19 ; PT1.1 108.38,99.19 ; PT1.1 109.43,100.24 ; 109.46,106.01 PT4.1 ; PT4.1 108.4,107.06 ; PT4.1 110.51,107.06 ; PT4.1 109.46,108.12 ; PR28.1 v3(129.55,72.77) ; PT3.1 110.51,114.94 ; PT3.1 108.4,114.94 ; PT3.1 109.46,113.88 ; PT3.1 109.46,115.99
  L3 w0.508: PT1.1 109.43,100.24 ; PT1.1 109.43,98.13 ; PT1.1 110.49,99.19 ; PT1.1 108.38,99.19 ; 108.4,114.94 PT3.1 ; PT3.1 110.51,114.94 ; PT3.1 109.46,115.99 ; PT3.1 109.46,113.88 ; 108.4,107.06 PT4.1 ; PT4.1 109.46,106.01 ; PT4.1 109.46,108.12 ; PT4.1 110.51,107.06
  L4 w0.254: v3(129.55,72.77) 129.4,72.62 129.4,69.64 127.89,68.14 116.94,68.14 116.06,69.01 116.06,74.91 118.27,77.12 118.27,78.58 110.44,86.41 102.75,86.41 101.42,87.73 91.12,87.73 88.55,90.3 87.16,90.3 85.89,91.57 85.89,93.07 v4(85.4,93.55)
  L4 w0.508: PT3.1 110.51,114.94 ; PT3.1 109.46,113.88 ; PT3.1 109.46,115.99 ; PT3.1 108.4,114.94 ; PT1.1 109.43,100.24 ; PT1.1 109.43,98.13 ; PT1.1 108.38,99.19 ; PT1.1 110.49,99.19 ; PT4.1 109.46,108.12 ; PT4.1 109.46,106.01 ; PT4.1 110.51,107.06 ; PT4.1 108.4,107.06
  BOTTOM w0.508: 108.4,107.06 PT4.1 ; PT4.1 110.51,107.06 ; PT4.1 109.46,106.01 ; PT4.1 109.46,108.12 ; PT1.1 109.43,100.24 ; PT1.1 109.43,98.13 ; PT1.1 108.38,99.19 ; PT1.1 110.49,99.19 ; 109.46,113.88 PT3.1 ; PT3.1 110.51,114.94 ; PT3.1 108.4,114.94 ; PT3.1 109.46,115.99 ; v4(85.4,93.55) 85.57,93.71 PC73.1
  vias: v2(80.73,108.82) v4(80.07,102.7) v4(80.1,95.94) v4(80.15,97.24) v4(81.51,108.89) v4(82.11,102.68) v4(82.07,100.83) v4(82.07,99.98) v4(82.12,99.12) v4(82.12,97.08) v4(82.17,108.84) v4(83.13,96.11) v4(83.93,101.83) v4(83.93,100.87) v4(83.92,99.12) v4(84.08,102.86) v4(84.73,101.88) v4(84.88,98.14) v4(85.84,98.04) v4(85.94,100.76) v4(85.91,99.19) v4(93.8,113.29) v5(80.09,101.91) v5(80.09,100.94) v5(80.07,99.04) v5(84.89,102.85) v5(106.08,114.94) v5(106.08,112.27) v5(106.08,109.6) v5(106.08,105.66) v5(106.08,101.73) v5(107.35,107.82) v5(107.73,103.12) v5(107.98,113.03) v5(110.02,112.14) v5(111.67,101.6) v5(111.79,105.79) v5(112.05,104.01) v5(112.81,115.95) v5(112.81,113.16) v5(112.81,110.74) v5(112.81,107.7) v5(112.81,99.57) v5(114.21,114.55) v5(114.21,111.89) v5(114.33,109.22) v5(115.6,116.08) v5(115.6,113.16) v5(115.6,110.74) v5(118.4,116.08) v5(121.39,113.64) v5(121.39,112.73) v5(121.39,111.81) v5(121.39,110.9) v5(122.31,112.73) v5(122.31,111.81) v5(122.31,110.9)
VOUT_INV: length 1.5
  BOTTOM w0.305: v5(37.27,39.93) 37.37,39.83 U120.18
  vias: v1(33.56,41.4) v2(28.74,35.05) v5(29.71,39.15) v5(29.71,38.15) v5(30.62,39.15) v5(30.62,38.15) v5(32.95,40.23) v5(34.02,40.16)
VR_HOT: length 3.4
  BOTTOM w0.102: PR24.1 v2(33.94,222.63) 33.94,222.5 32.79,221.35 PU4601.13
VR_TT#: length 4.1
  TOP w0.203: U9.4 120.46,70.48 120.46,70.48 v3(119.53,69.55)
  BOTTOM w0.254: v3(119.53,69.55) 119.84,69.55 TP204.1
VRAM1_VREFCA: length 7.5
  BOTTOM w0.178: 50.27,109.29 52.8,109.29 MEM3.M8
  BOTTOM w0.305: 50.27,109.29 50.01,109.29 49.5,108.78 R885.1
  BOTTOM w0.508: v2(49.03,109.73) 49.18,109.58 R885.1 C529.1 R886.2
VRAM1_VREFDQ: length 11
  BOTTOM w0.178: 59.92,110.97 58.81,112.07 MEM3.H1
  BOTTOM w0.508: 59.92,110.97 59.99,110.9 59.99,109.84 60.9,108.92 60.9,107.05 61.53,106.43 61.96,106.43 v2(62.39,105.99) 62.19,105.79 R928.1 R924.2 C559.1
VRAM2_VREFCA: length 18.8
  TOP w0.178: MEM1.M8 58.29,108.88 58.72,108.45 59.26,108.45 59.29,108.42 59.68,108.42 v4(60.11,108.86)
  TOP w0.508: v1(50.34,107.89) 50.51,108.06 v3(50.51,108.74) 50.47,108.78 R230.1 C163.1 R1905.2
  L3 w0.178: v3(50.51,108.74) 51.41,109.64 51.87,109.64 52.85,110.62 53.96,110.62 54.23,110.88 54.98,110.88 55.27,110.6 55.81,110.6 58.23,108.18 59.42,108.18 59.66,108.42 59.66,108.42 60.09,108.86 v4(60.11,108.86)
VRAM2_VREFDQ: length 7.4
  TOP w0.178: MEM1.H1 52.16,111.83 51.69,111.83 50.8,112.72 50.73,112.72
  TOP w0.508: 50.73,112.72 50.6,112.85 50.6,113.26 v1(50.33,113.54) 50.29,113.57 R203.1 48.07,113.57 R202.2 C1854.1 C835.1
VRAM3_VREFCA: length 14.9
  L3 w0.178: v4(59.41,94.53) 59.16,94.53 58.84,94.85 56.59,94.85 56.38,94.63 55.5,94.63 55.25,94.39 53.95,94.39 53.65,94.08 50.7,94.08 v3(50.69,94.08)
  BOTTOM w0.178: v4(59.41,94.53) 59.33,94.53 59.05,94.81 58.69,94.81 58.29,94.42 MEM4.M8
  BOTTOM w0.508: R1924.1 48.76,93.7 R1923.2 C1869.1 49.67,94.76 v2(49.97,94.47) 50.35,94.08 v3(50.69,94.08)
VRAM3_VREFDQ: length 7.9
  BOTTOM w0.178: MEM4.H1 52.41,91.43 51.91,91.94 51.35,91.94 50.79,91.39 50.4,91.39 50.16,91.63 R1922.1
  BOTTOM w0.508: v2(46.79,92.56) 46.39,92.16 C1868.1 C1867.1 R1921.2 R1922.1
VRAM4_VREFCA: length 7.2
  TOP w0.178: v1(49.84,95.99) 50.82,95.99 51.77,95.04 52.02,95.04 52.23,94.84 52.81,94.84 53.21,94.43 MEM2.M8
  TOP w0.508: v1(49.84,95.99) 49.54,95.69 R1910.1 C1861.1 R1911.2
VRAM4_VREFDQ: length 19.4
  TOP w0.203: MEM2.H1 59.5,91.22 59.9,91.62 59.9,94.76 59.59,95.07 59.59,95.14 v4(59.58,95.15)
  L3 w0.178: v4(51.02,95.12) 51.02,95.59 51.8,96.37 51.89,96.37 52.02,96.5 55.52,96.5 55.54,96.53 56.53,96.53 57.7,95.36 59.37,95.36 v4(59.58,95.15)
  BOTTOM w0.508: v4(51.02,95.12) 50.34,95.79 49.98,95.79 v2(49.94,95.82) R945.1 R946.2 C1860.1
VRAM_0D95_EN_D: length 7.9
  TOP w0.102: R79663.1 R79667.1 R79666.2 102.59,122.56 103.61,122.56 103.82,122.76 v1(103.82,123.19) 103.71,123.3 101.67,123.3 101.16,123.81 Q6702.6
VRAM_0D95_EN_SW: length 5.6
  TOP w0.102: C6709.2 97.57,119.19 U6702.4 98.52,120.65 C6704.2 v1(99.09,121.16) 99.16,121.22 R79663.2
VRAM_ZQ1: length 7.2
  BOTTOM w0.102: MEM3.L8 53.18,109.68 52.81,110.05 52.2,110.05 51.85,109.71 49.86,109.71 49.31,110.26 48.17,110.26 v2(47.96,110.46) 48.86,111.37 R870.2
VRAM_ZQ2: length 16.7
  TOP w0.102: v4(60.29,106.77) 60.29,108.46 60.52,108.69 60.52,109.02 60.22,109.32 58.38,109.32 MEM1.L8
  L3 w0.127: v4(60.29,106.77) 60.2,106.86 55.32,106.86 55.28,106.82 52.43,106.82 52.3,106.95 52.3,106.96 52.06,107.21 51.98,107.21 51.96,107.23 51.2,107.23 v3(50.85,106.88)
  BOTTOM w0.102: v3(50.85,106.88) 50.75,106.78 v2(50.04,106.78) R899.2
VRAM_ZQ3: length 17.8
  TOP w0.102: R299.2 51.12,97.76 51.34,97.54 v3(51.37,97.54)
  L3 w0.127: v3(51.37,97.54) 51.49,97.42 55.83,97.42 55.86,97.45 56.38,97.45 57.86,95.97 59.05,95.97 59.29,96.21 59.7,96.21 v4(60.41,95.5)
  BOTTOM w0.102: v2(61.31,95.12) 60.93,95.5 v4(60.41,95.5) 60.41,94.09 60.22,93.89 59.01,93.89 58.95,93.95 58.34,93.95 MEM4.L8
VRAM_ZQ4: length 4.7
  TOP w0.102: MEM2.L8 52.78,94.05 51.51,94.05 50.96,94.61 v1(49.91,94.61) 48.91,94.61 R320.2
VREF: length 5
  TOP w0.102: v3(42.48,38.91) 42.1,39.29 C4.2
  BOTTOM w0.102: U120.2 40.64,37.08 41.4,37.83 v2(41.4,37.88) 41.42,37.88 41.87,38.33 41.89,38.33 v3(42.48,38.91)
VREF_1: length 2.3
  TOP w0.203: C140.1 167.92,77.63 U6.41
VREG_PCIAUX_PCH: length 9.3
  BOTTOM w0.254: R10.2 125.05,213.12 125.05,214.12 v2(126.55,215.62) 126.58,215.65 Q128.C ; R10.2 127.67,211.65 Q3.D ; R10.2 R13.1
VREG_PCIAUX_PCH_1: length 5.6
  BOTTOM w0.254: Q1211.G 123.99,207.96 PC1.2 123.73,209.11 v2(123.73,209.55) 123.73,209.99 C1616.1 R13.2
VRP: length 9.4
  TOP w0.203: U6.38 166.13,76.43 166.33,76.23 166.33,75.33
  TOP w0.254: v3(171.33,73.46) 170.85,73.46 170.49,73.1 C155.1 169.19,73.99 167.5,73.99 166.33,75.16 166.33,75.33
  BOTTOM w0.254: v2(169.84,73.28) 170.02,73.46 v3(171.33,73.46)
VSUM_RC: length 2.7
  TOP w0.254: PR34.2 128.71,75.95 128.96,75.69 128.96,75.49 ; 128.96,75.49 128.96,75.21 128.68,74.93 PC14.2 ; 128.96,75.49 v1(128.99,75.49)
VSUM_RR: length 44.5
  TOP w0.254: PR51.1 124.49,115.19 124.95,114.73 124.95,107.4 v3(124.92,107.38)
  L4 w0.254: v3(124.92,107.38) 125.12,107.19 126.61,107.19 129.75,104.05 129.75,97.61 130.88,96.48 130.88,79.3 v3(130.13,78.55)
  BOTTOM w0.254: PR42.2 v3(130.13,78.55) ; v2(125.73,107.81) 125.29,107.38 v3(124.92,107.38)
WAKE_N: length 519.1
  TOP w0.102: v1(102.1,220.45) 102.32,220.22 v3(102.93,220.22) R1719.2 ; R1654.1 v3(61.02,154.69) 61.02,155.36 R137.1 ; R1718.1 v3(123.32,223.52) ; U16.21 35.08,14.66 35.02,14.72 34.47,14.72 v3(34.02,14.26)
  L3 w0.127: v3(45.4,84.63) 46.58,84.63 51.32,79.9 52,79.9 55.06,82.96 68.51,82.96 70.26,84.71 73.95,84.71 74.73,83.92 81.39,83.92 83.09,85.62 89.35,85.62 91.86,83.11 104.69,83.11 105.74,82.06 105.74,80.69 107.09,79.34 108.63,79.34 110.07,77.89 110.99,77.89 111.93,76.95 111.93,72.81 112.24,72.5 113.22,71.53 114.37,71.53 118.13,67.77 124.82,67.77 125.01,67.58 132.38,67.58 132.56,67.75 133.15,67.75 134.51,69.11 143.21,69.11 144.33,70.23 147.04,70.23 147.13,70.32 147.65,70.32 v3(147.94,70.61)
  L4 w0.127: v3(34.02,14.26) 34.62,14.86 35.34,14.86 35.66,15.18 35.66,17.59 36.99,18.92 36.99,21.58 37.4,22 40.22,22 42.02,23.8 42.02,27.43 41.16,28.3 41.16,28.7 41.16,28.8 41.59,29.23 41.59,30.02 41.16,30.45 41.16,30.97 40.52,31.6 40.52,34.02 39.76,34.78 39.76,37.97 40,38.21 40,40.6 39.76,40.85 39.76,50.7 38.08,52.37 38.08,54.69 35.21,57.56 35.21,63.7 35.88,64.36 36.39,64.36 39.91,67.89 39.91,68.27 40.94,69.3 40.94,69.31 41.48,69.85 42.11,69.85 48.5,76.23 48.5,79.36 48.05,79.81 47.2,79.81 46.52,80.49 46.52,82.22 45.4,83.34 v3(45.4,84.63) 45.4,120.29 47.8,122.69 47.8,125.53 51.56,129.29 51.56,141.31 51.35,141.52 51.35,146.33 51.88,146.86 52.03,146.86 53.63,148.46 53.63,152.5 54.58,153.45 59.79,153.45 v3(61.02,154.69) ; v3(123.32,223.52) 121.22,223.52 119.19,225.55 104.37,225.55 102.93,224.11 v3(102.93,220.22) 103.89,220.22 106.3,217.81 116.4,217.81 119.85,214.35 123.3,214.35 136.8,200.86 154.04,200.86 162.12,192.77 162.12,191.4 161.17,190.45 161.17,156.15 160.47,155.44 160.47,124.84 161.16,124.14 161.16,117.45 161.83,116.78 161.83,114.84 161.3,114.3 161.3,112.79 156.23,107.73 156.23,105.69 155.27,104.73 155.27,100.76 153.88,99.36 153.88,95.97 153.14,95.23 153.14,88.89 152.06,87.82 152.06,76.89 151.39,76.22 151.39,74.22 147.94,70.77 v3(147.94,70.61)
  BOTTOM w0.102: v3(34.02,14.26) 34.02,14.81 33.8,15.02 v2(33.8,15.06)
WAKE_N_APU: length 11.5
  TOP w0.102: CPU1.AG2 70.61,160.71 70.29,160.71 70.1,160.52 67.32,160.52 65.59,158.78 65.59,157.57 v1(64.25,156.23) R1654.2
WEA0#: length 43
  TOP w0.127: v1(61.75,106.2) 61.75,107.01 v4(61.78,107.04) ; v4(55.37,110.16) 55.18,109.97 54.13,109.97 54.01,109.85 MEM1.L3 ; GPU1.G25 75.14,106.8 75.01,106.67 v4(75.01,106.43)
  L3 w0.165: v4(61.78,107.04) 61.93,107.19 63.21,107.19 63.59,107.58 63.59,107.94 63.72,108.07 64.1,108.07 64.27,107.9 64.27,107.36 64.43,107.19 64.92,107.19 65.08,107.36 65.08,107.9 65.25,108.07 65.73,108.07 65.89,107.9 65.89,107.36 66.06,107.19 66.54,107.19 66.71,107.36 66.71,107.9 66.87,108.07 68.39,108.07 68.88,107.58 69.24,107.22 69.66,107.22 69.83,107.04 73.11,107.04 73.23,106.91 73.23,106.79 73.36,106.67 74.78,106.67 v4(75.01,106.43)
  L4 w0.165: v4(61.78,107.04) 61.78,102.36 61.91,102.23 62.22,102.23 62.35,102.36 62.35,108 60.73,109.62 59.01,109.62 58.85,109.46 58.85,108.78 58.72,108.66 58.07,108.66 57.92,108.8 57.92,109.25 57.8,109.37 57.42,109.37 56.53,110.25 55.77,110.25 55.67,110.16 v4(55.37,110.16)
  BOTTOM w0.127: MEM3.L3 56.66,110.24 55.45,110.24 v4(55.37,110.16)
WEA1#: length 40.6
  TOP w0.127: MEM2.L3 55.99,93.62 55.59,93.22 55.05,93.22 v4(54.58,93.69) ; v4(76.6,94.45) 76.33,94.45 76.2,94.57 GPU1.H10
  L3 w0.165: v4(76.6,94.45) 76.44,94.28 74.47,94.28 74.15,93.96 73.67,93.96 73.54,94.09 73.54,94.67 73.41,94.8 72.98,94.8 72.85,94.67 72.85,94.54 72.7,94.39 71.01,94.39 70.51,94.89 66.91,94.89 66.74,95.06 61.17,95.06 60.87,95.36 60.87,96.18 60.61,96.45 59.81,96.45 59.8,96.46 58.98,96.46 58.86,96.58 58.86,97 58.98,97.13 v4(59.87,97.13)
  L4 w0.102: 58.58,94.38 58.28,94.38 58.18,94.48 58.18,94.68 58.08,94.79 57.67,94.79 57.57,94.68 57.57,94.46 57.44,94.32 55.27,94.32 54.63,93.69 v4(54.58,93.69)
  L4 w0.165: v4(59.87,97.13) 59.87,97.57 59.75,97.7 59.35,97.7 59.22,97.57 59.22,96.52 58.59,95.89 57.74,95.89 57.64,95.79 57.64,95.28 57.74,95.18 58.59,95.18 58.7,95.07 58.7,94.51 58.58,94.38
  BOTTOM w0.127: v4(59.87,97.13) 60,97 v2(61.03,97) ; MEM4.L3 53.81,93.82 53.66,93.82 53.56,93.72 53.56,93.48 53.56,93.47 53.56,93.27 53.66,93.17 54.48,93.17 54.58,93.27 v4(54.58,93.69)
WEBCAM_DET: length 170.2
  TOP w0.102: v3(162.82,195.48) 162.82,194.74 162.54,194.46 160.94,194.46 160.79,194.31 v1(159.39,194.31) PC126.2 R12.2 157.7,196.41 157.01,197.1 157.01,198.19 WEBCM1.7 ; v3(150.91,47.75) 151.31,47.35 151.31,45.94 151.25,45.88 U109.114
  L4 w0.127: v3(150.91,47.75) 150.44,48.22 150.44,49.74 150.61,49.91 150.61,50.77 150.57,50.82 150.57,50.84 150.45,50.96 150.45,52.6 151,53.15 151,56 151.35,56.35 151.35,59.12 151.75,59.52 151.75,65.92 153.09,67.26 153.09,70.71 154.3,71.92 154.3,86.35 155.16,87.21 155.16,87.74 157.49,90.07 157.49,97.74 158.15,98.4 158.15,99.44 158.36,99.65 158.36,100.04 158.15,100.25 158.15,100.42 157.42,101.15 157.42,101.54 158.15,102.27 158.15,104.67 158.82,105.35 158.82,107.03 165.22,113.43 165.22,131.32 163.22,133.32 163.22,155.01 164.39,156.19 164.39,193.91 v3(162.82,195.48)
X32K_X1: length 8.4
  TOP w0.102: CPU1.AT1 69.77,153.8 69.1,153.14 67.44,153.14 v1(66.96,152.65) 66.01,151.7 C57.1 64.87,151.7 R1671.1 64.47,151.3 X2.1
X32K_X2: length 11.3
  TOP w0.102: X2.4 64.47,150.45 R1671.2 65.25,150.56 C58.1 66.14,150.37 v1(66.96,150.37) 66.96,150.78 66.61,151.13 66.61,151.74 66.89,152.02 67.22,152.02 68.13,152.93 69.19,152.93 69.75,153.5 70.63,153.5 70.93,153.8 CPU1.AT2
X48M_X1: length 12.1
  TOP w0.102: X1.3 62.64,173.14 63.88,173.14 64.47,173.74 R113.1 65.25,173.42 C52.1 66.14,173.42 66.45,173.1 v1(66.96,173.1) 67.47,172.59 67.47,172.09 69.14,170.41 69.86,170.41 69.97,170.3 70.8,170.3 CPU1.T2
X48M_X2: length 8.6
  TOP w0.102: X1.1 64.39,171.68 R113.2 65.12,172.4 C50.1 66.64,171.7 v1(66.96,171.7) 68.46,170.21 69.78,170.21 69.89,170.09 70.21,170.09 CPU1.T1
XRF_TDC2: length 15.3
  TOP w0.508: 51.6,10.03 v3(50.3,10.03) ; XF1.9 51.6,12.95 51.21,12.57 50.48,12.57 v1(50.07,12.98) 50.07,13.11 50.3,13.34 v3(50.3,13.84) ; v3(49.82,16.48) C3452.1
  L3 w0.508: v3(50.3,13.84) 49.82,14.33 v3(49.82,16.48)
  BOTTOM w0.508: XF1.9 v3(50.3,13.84) 50.3,11.3 v2(50.02,11.02) 50.3,10.74 v3(50.3,10.03) 51.6,10.03
XTALIN: length 8.9
  TOP w0.102: GPU1.AM28 96.24,109.2 v1(96.3,109.14) 96.42,109.26 C756.1 98.16,109.26 R1879.1 99.37,109.83 100.86,109.83 X5.1
XTALOUT: length 8.3
  TOP w0.102: X5.3 99.43,110.47 R1879.2 97.4,110.47 C757.1 97.15,110.59 v1(96.32,110.59) 95.31,109.58 93.38,109.58 GPU1.AK28

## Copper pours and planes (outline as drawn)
AGND on TOP: 166.66,69.98 166.28,70.36 166.28,71.12 166.4,71.25 170.85,71.25 171.23,71.63 171.23,73.53 171.1,73.66 170.34,73.66 170.21,73.79 170.21,75.56 170.47,75.82 171.86,75.82 171.99,75.95 171.99,77.85 171.86,77.98 168.69,77.98 168.44,78.23 167.55,78.23 167.42,78.36 167.42,79.12 167.94,79.64 171.5,79.64 171.87,80.01 171.86,80.01 171.86,83.21 171.64,83.44 171.1,83.44 170.98,83.57 170.98,84.47 171.1,84.59 173.12,84.59 173.39,84.33 173.39,82.68 173.77,82.3 177.07,82.3 177.2,82.17 177.2,77.47 175.55,75.82 175.55,72.64 175.29,72.39 172.63,72.39 172.25,72.01 172.25,70.1 172.12,69.98 ; 9 cut-outs
AGND on BOTTOM: 80.42,34.42 79.54,35.31 73.57,35.31 72.93,35.94 72.93,39.56 73.31,39.94 77.44,39.94 81.06,43.56 84.36,43.56 84.74,43.18 84.74,41.27 85.12,40.89 85.12,39.5 84.87,39.24 81.82,39.24 80.04,37.47 80.04,36.32 81.19,35.18 81.19,34.67 80.93,34.42 ; 2 cut-outs
AGND on L2GND: outline of 100 points within 85.06,0.76 184.24,85.53
AGND on L2GND: 73.26,31.81 72.36,32.72 72.36,42.47 73.39,43.5 83.52,43.5 83.92,43.1 83.92,41.96 84.55,41.32 84.55,40.82 86.08,39.29 86.08,36.78 81.11,31.81
AGND on L5GND: 164.58,28.64 164.18,29.03 164.18,38.15 166.34,40.31 166.34,64.47 163.93,66.88 163.93,68.02 163.05,68.9 158.74,68.9 158.47,69.17 158.47,72.95 159.61,74.09 159.61,74.75 159.24,75.12 157.97,75.12 157.32,75.77 157.32,78.31 156.96,78.68 156.45,78.68 156.18,78.95 156.18,79.04 156.45,79.31 158.45,79.31 159.09,78.68 159.85,78.68 159.99,78.53 159.99,75.99 160.36,75.63 164.83,75.63 165.2,75.99 165.2,80.22 164.69,80.72 164.69,81.58 165.2,82.09 165.2,89.08 165.72,89.6 171.66,89.6 173.2,88.06 173.2,83.11 173.94,82.36 177.25,82.36 177.26,82.34 177.26,78.79 177.75,78.3 179.69,78.3 182.61,81.22 184.24,81.22 184.24,70.68 180.2,70.68 179.06,71.82 176.23,71.82 172.17,67.75 171.15,67.75 169.26,65.86 169.26,61.93 167.36,60.02 167.36,29.54 166.45,28.64
AGND on L5GND: 85.2,1.97 85.06,2.11 85.06,12.24 86.08,13.26 86.08,16.59 85.19,17.48 85.19,19.99 85.44,20.24 85.44,28.15 80.76,32.83 78.34,32.83 77.82,33.35 77.82,33.96 79.11,35.24 84.03,35.24 84.17,35.1 84.17,31.8 86.84,29.13 86.84,19.64 86.58,19.38 86.58,18.08 87.47,17.19 87.47,12.52 86.84,11.89 86.84,5.13 87.47,4.49 87.47,3 86.44,1.97
GND on TOP: 90.46,113.03 89.06,114.43 89.06,118.49 89.19,118.62 90.2,118.62 90.46,118.36 92.74,118.36 92.87,118.24 92.87,115.7 93.25,115.32 93.25,113.28 93,113.03 ; 6 cut-outs
GND on TOP: 170.09,125.86 169.83,126.11 169.83,127.25 169.96,127.38 172.37,127.38 172.5,127.25 172.5,125.98 172.37,125.86 ; 2 cut-outs
GND on TOP: 149.89,5.33 149.77,5.46 149.77,8.64 149.89,8.76 151.42,8.76 151.54,8.64 151.54,5.71 151.16,5.33 ; 3 cut-outs
GND on TOP: outline of 291 points within 0.76,0.76 184.24,229.24 ; 47 cut-outs
GND on TOP: 100.36,77.47 100.11,77.72 100.11,79.25 100.26,79.4 105.16,79.4 106.08,78.49 106.08,77.72 105.86,77.51 101.72,77.51 101.68,77.47 ; 8 cut-outs
GND on TOP: 87.54,10.92 87.41,11.05 87.41,12.57 87.54,12.7 88.04,12.7 88.55,12.19 92.11,12.19 92.62,12.7 93.12,12.7 93.25,12.57 93.25,11.05 93.12,10.92 92.62,10.92 92.11,11.43 88.55,11.43 88.04,10.92 ; 4 cut-outs
GND on TOP: 61.76,22.73 61.12,23.37 61.12,25.4 61.88,26.16 65.57,26.16 66.33,26.92 66.33,30.1 66.45,30.23 68.23,30.23 68.36,30.1 68.36,29.34 67.85,28.83 67.85,22.86 67.72,22.73 ; 4 cut-outs
GND on TOP: 51.85,41.91 51.72,42.04 50.2,42.04 50.07,42.16 50.07,45.75 50.33,46 52.26,46 52.38,45.87 52.38,42.16 52.13,41.91
GND on TOP: 40.8,218.95 40.44,219.3 40.44,222.76 40.98,223.29 44.48,223.29 44.66,223.11 44.66,219.63 43.98,218.95
GND on TOP: 83.24,98.28 82.99,98.53 82.99,98.79 82.48,99.29 82.48,99.67 82.99,100.18 82.99,100.56 82.35,101.2 82.35,101.45 82.99,102.09 82.99,102.6 82.35,103.23 82.35,103.36 82.48,103.48 82.73,103.48 83.62,102.6 83.62,102.09 83.11,101.58 83.11,101.07 83.62,100.56 83.62,100.31 83.11,99.8 83.11,99.42 83.62,98.91 83.62,98.53 83.37,98.28
GND on TOP: 42.58,195.33 42.07,195.83 42.07,196.47 41.82,196.72 41.31,196.72 41.31,195.45 37.5,195.45 37.5,196.98 37.37,197.1 34.7,197.1 34.58,197.23 34.58,202.31 34.7,202.44 41.05,202.44 41.31,202.18 41.31,198.88 43.85,196.34 43.85,195.83 43.34,195.33 ; 3 cut-outs
GND on TOP: 119.67,14.73 119.29,15.11 119.29,22.23 119.41,22.35 122.33,22.35 122.46,22.23 122.46,18.16 123.1,17.53 123.1,14.99 122.84,14.73
GND on TOP: 39.99,211.61 39.91,211.68 39.91,214.33 39.99,214.4 41.64,214.4 41.79,214.25 41.79,211.76 41.64,211.61
GND on TOP: 97.21,110.98 97.08,111.1 97.08,111.61 97.21,111.74 97.97,111.74 98.23,111.99 98.23,115.55 98.48,115.8 99.75,115.8 100.01,115.55 100.01,112.76 98.23,110.98 ; 6 cut-outs
GND on TOP: 32.8,35.56 32.42,35.94 32.42,38.1 32.67,38.35 34.83,38.35 35.47,37.72 35.47,35.81 35.21,35.56
GND on TOP: 72.3,22.86 72.3,26.29 72.42,26.42 81.44,26.42 81.57,26.29 81.57,22.86 80.3,21.59 73.57,21.59
GND on TOP: 31.66,71.63 31.4,71.88 31.4,72.9 31.78,73.28 36.48,73.28 36.99,72.77 36.99,72.01 36.61,71.63 ; 1 cut-out
GND on TOP: 52.99,29.08 49.56,32.51 49.56,37.47 50.83,38.73 54.64,38.73 54.77,38.61 54.77,31.75 55.15,31.37 55.15,29.34 54.9,29.08
GND on TOP: 19.97,202.31 19.85,202.44 19.85,206.63 19.97,206.76 22.13,206.76 22.26,206.63 22.26,202.44 22.13,202.31
GND on TOP: 125,82.3 124.24,83.06 124.24,85.22 125,85.98 127.8,85.98 127.92,85.85 127.92,82.42 127.8,82.3
GND on TOP: 27.47,146.94 25.43,148.97 24.29,148.97 23.91,149.35 23.91,151 24.04,151.13 24.29,151.13 25.05,150.37 26.07,150.37 26.96,149.48 28.86,149.48 29.62,148.72 32.67,148.72 33.05,148.34 33.05,147.07 32.93,146.94 ; 1 cut-out
GND on TOP: 44.56,78.94 44.43,79.07 44.43,119.16 44.44,119.17 44.44,123.15 45.37,124.08 45.37,125.6 45.5,125.73 45.5,128.65 46.07,129.22 46.64,129.22 48.31,127.56 48.31,119.63 48.67,119.27 48.67,118.5 48.29,118.11 48.29,114.27 48.21,114.19 46.51,114.19 46.26,113.94 46.26,108.4 46.51,108.15 48.42,108.15 48.49,108.07 48.49,107.13 48.31,106.95 48.31,97.43 48.11,97.23 48.11,96.51 47.98,96.39 46.28,96.39 46.13,96.24 46.13,95.22 46.31,95.04 48.11,95.04 48.29,94.86 48.29,93.72 48.06,93.49 48.04,93.49 47.59,93.04 46.59,93.04 46.36,92.81 46.36,91.79 47.07,91.08 48.19,91.08 48.29,90.98 48.29,88.01 48.17,87.88 48.17,79.88 47.91,79.63 47.28,79.63 46.59,78.94 ; 46 cut-outs
GND on TOP: 47.28,17.91 45.37,19.81 45.37,23.24 47.66,25.53 47.66,31.24 48.29,31.88 49.56,31.88 52.48,28.96 52.48,26.6 52.57,26.6 52.63,26.6 52.7,26.62 52.74,26.69 52.74,28.7 52.74,20.32 50.33,17.91 ; 6 cut-outs
GND on TOP: 107.73,57.66 107.6,57.78 107.6,61.21 106.59,62.23 106.59,63.12 106.71,63.25 109.25,63.25 110.9,61.59 110.9,59.44 109.13,57.66 ; 1 cut-out
GND on TOP: 63.79,19.81 63.53,20.07 63.53,21.97 63.79,22.23 66.96,22.23 67.22,21.97 67.22,20.07 66.96,19.81
GND on TOP: 157.64,32.26 157.26,32.64 156.5,32.64 156.37,32.77 156.37,34.16 156.75,34.54 158.15,34.54 158.4,34.29 158.4,32.38 158.28,32.26
GND on TOP: 47.15,202.31 47.15,206.63 47.28,206.76 52.23,206.76 52.61,206.38 52.61,204.6 50.33,202.31
GND on TOP: 135.92,10.41 134.15,12.19 134.15,16.76 135.92,18.54 137.57,18.54 137.7,18.41 137.7,10.54 137.57,10.41
GND on TOP: 76.36,213.87 76.23,214 76.23,218.44 76.36,218.57 81.82,218.57 81.95,218.44 81.95,214.25 81.57,213.87 ; 13 cut-outs
GND on TOP: 30.51,163.96 30.26,164.21 30.26,165.86 30.51,166.12 33.69,166.12 33.82,165.99 33.82,164.08 33.69,163.96 ; 1 cut-out
GND on TOP: 49.69,214 49.44,214.25 49.44,224.79 50.2,225.55 65.31,225.55 65.44,225.43 65.44,219.71 65.18,219.46 56.8,219.46 51.34,214
GND on TOP: 139.99,86.23 138.59,87.63 138.59,89.41 138.84,89.66 139.61,89.66 139.73,89.79 139.73,91.44 139.99,91.69 144.18,91.69 144.69,91.19 144.69,87.88 144.18,87.38 144.18,86.49 143.92,86.23
GND on TOP: 113.7,86.23 113.57,86.36 113.57,93.73 113.95,94.11 119.92,94.11 120.18,94.36 121.7,94.36 121.83,94.23 121.83,92.84 120.68,91.69 120.68,86.36 120.56,86.23 ; 3 cut-outs
GND on TOP: 43.31,52.58 43.19,52.7 43.19,54.23 42.81,54.61 42.81,56.82 42.91,56.92 45.37,56.92 45.5,56.79 45.5,55.37 45.63,55.24 47.28,55.24 47.53,54.99 47.53,52.7 47.4,52.58 ; 2 cut-outs
GND on TOP: 26.07,195.33 25.94,195.45 25.94,196.98 27.97,199.01 27.97,201.93 28.48,202.44 33.82,202.44 34.2,202.06 34.2,196.98 34.07,196.85 33.43,196.85 33.18,196.6 33.18,195.33 29.5,195.33 29.5,196.72 29.24,196.98 27.85,196.98 27.47,196.6 27.47,195.83 26.96,195.33 ; 3 cut-outs
GND on TOP: 73.19,76.83 73.06,76.96 73.06,77.72 72.68,78.11 72.68,78.61 72.8,78.74 78.14,78.74 78.39,78.49 78.39,77.09 78.14,76.83 ; 2 cut-outs
GND on TOP: 91.76,107.65 91.51,107.9 91.38,107.9 91.13,108.15 91.13,109.04 91.71,109.63 92.32,109.63 92.4,109.55 92.4,108.41 92.27,108.28 92.27,107.9 92.02,107.65
GND on TOP: 97.19,19.18 96.93,19.43 96.93,25.15 97.32,25.53 97.32,26.42 98.71,27.81 99.98,27.81 100.11,27.69 100.11,19.3 99.98,19.18 ; 2 cut-outs
GND on TOP: 25.18,150.88 24.54,151.51 24.54,153.92 25.18,154.56 25.18,157.23 25.31,157.35 29.75,157.35 30.01,157.1 30.01,155.57 29.24,154.81 29.24,151 29.12,150.88
GND on TOP: 132.88,119 129.32,122.56 119.67,122.56 109.63,132.59 93.12,132.59 91.47,134.24 91.47,140.21 93.12,141.86 101.13,141.86 103.92,144.65 103.92,160.4 110.65,167.13 129.32,167.13 130.08,166.37 130.08,152.02 131.35,150.75 131.35,128.91 131.22,128.78 131.22,126.49 132.11,125.6 140.11,125.6 140.88,124.84 140.88,119.13 140.75,119
GND on TOP: 80.57,95.36 80.45,95.48 80.45,95.61 80.96,96.12 80.96,96.88 80.45,97.39 80.45,97.64 80.96,98.15 80.96,98.91 80.45,99.42 80.45,99.67 80.96,100.18 80.96,100.82 80.45,101.33 80.45,101.58 80.96,102.09 80.96,102.6 80.32,103.23 80.32,103.48 80.45,103.61 80.7,103.61 81.72,102.6 81.72,102.21 81.21,101.71 81.21,101.07 81.72,100.56 81.72,100.31 81.21,99.8 81.21,99.29 81.84,98.66 81.84,98.53 81.34,98.02 81.34,97.26 82.86,95.74 82.86,95.48 82.73,95.36
GND on TOP: 27.72,215.52 27.47,215.77 27.47,220.47 27.59,220.6 36.23,220.6 36.36,220.47 36.36,219.33 35.97,218.95 33.05,218.95 32.93,218.82 32.93,215.65 32.8,215.52 ; 18 cut-outs
GND on BOTTOM: 17.69,155.07 17.56,155.19 17.56,157.86 17.69,157.99 18.96,157.99 19.08,157.86 19.08,155.32 18.83,155.07 ; 3 cut-outs
GND on BOTTOM: 113.7,86.23 113.57,86.36 113.57,93.85 113.83,94.11 120.43,94.11 121.32,93.22 121.32,92.33 120.68,91.69 120.68,86.36 120.56,86.23
GND on BOTTOM: 81.72,105.26 81.46,105.52 81.46,106.91 81.21,107.17 80.96,107.17 80.83,107.29 80.83,107.93 81.21,108.31 82.99,108.31 83.37,108.69 84.13,108.69 84.38,108.44 84.38,107.42 85.02,106.79 85.53,106.79 85.65,106.66 85.65,106.15 84.77,105.26 ; 9 cut-outs
GND on BOTTOM: 152.56,29.21 152.43,29.34 152.43,32.13 152.56,32.26 156.12,32.26 156.62,31.75 156.62,29.72 156.12,29.21 ; 2 cut-outs
GND on BOTTOM: 46.9,83.44 46.01,84.33 46.01,90.93 46.08,91 48.48,91 48.55,90.93 48.55,90.56 48.29,90.3 48.29,86.97 48.01,86.69 48.01,83.54 47.91,83.44 ; 6 cut-outs
GND on BOTTOM: 85.27,91.67 84.87,92.08 82.33,92.08 81.84,92.56 81.84,95.23 81.67,95.41 80.83,95.41 80.73,95.51 80.73,95.97 81.08,96.32 81.08,96.85 80.88,97.06 80.88,97.41 80.97,97.5 81.58,97.5 81.84,97.77 81.84,98.4 81.97,98.53 82.28,98.53 82.61,98.86 82.61,102.98 82.86,103.23 83.24,103.23 83.5,102.98 83.5,100.94 83.37,100.82 83.37,97.26 82.73,96.63 82.73,95.1 83.11,94.72 84.77,94.72 84.92,94.57 84.92,92.99 85.25,92.66 87.18,92.66 87.25,92.74 87.25,93.93 87.18,94.01 86.34,94.01 86.19,94.16 86.19,95.33 86.49,95.64 87.15,95.64 87.37,95.85 87.37,96.18 86.8,96.75 86.8,97.39 86.54,97.64 86.54,97.9 87.05,98.4 87.05,98.79 86.29,99.55 86.26,99.55 86.14,99.67 85.53,99.67 85.4,99.8 85.4,100.26 85.5,100.36 86.62,100.36 87.05,99.93 88.83,99.93 88.92,99.84 88.92,99.23 88.85,99.17 87.94,99.17 87.69,98.91 87.69,98.28 88.78,97.18 88.78,95.69 88.58,95.48 88.58,94.59 88.88,94.29 88.88,91.83 88.73,91.67 ; 17 cut-outs
GND on BOTTOM: 34.83,195.33 34.58,195.58 34.58,202.31 34.7,202.44 40.55,202.44 40.93,202.06 40.93,195.45 40.8,195.33
GND on BOTTOM: 49.06,20.57 43.34,26.29 43.34,32.89 43.59,33.15 47.66,33.15 50.07,30.73 54.9,30.73 55.15,30.48 55.15,29.46 54.77,29.08 53.25,29.08 52.99,28.83 52.99,23.62 49.94,20.57
GND on BOTTOM: 24.8,151.26 24.54,151.51 24.54,153.97 25,154.43 25.03,154.43 25.13,154.53 25.13,157.15 25.33,157.35 29.12,157.35 29.37,157.1 29.37,151.64 28.99,151.26
GND on BOTTOM: 31.91,71.63 31.68,71.86 31.68,72.29 32.42,73.03 35.34,73.03 35.85,72.52 36.86,72.52 36.99,72.39 36.99,71.75 36.86,71.63
GND on BOTTOM: 106.46,200.53 104.55,202.44 104.55,204.98 105.57,205.99 105.57,215.26 104.17,216.66 102.78,216.66 102.4,216.28 102.4,213.36 99.35,210.31 98.46,210.31 97.44,211.33 92.74,211.33 92.36,211.71 92.36,224.28 94.01,225.93 94.01,225.81 123.48,225.81 125.64,223.65 125.64,212.34 124.49,211.2 123.99,211.2 121.06,208.28 121.06,202.69 121.57,202.18 127.54,202.18 127.8,201.93 127.8,200.79 127.54,200.53 ; 7 cut-outs
GND on BOTTOM: 79.43,110.34 79.18,110.6 79.18,113.54 79.29,113.65 80.95,113.65 82.61,111.99 82.61,110.6 80.45,110.6 80.19,110.34 ; 10 cut-outs
GND on BOTTOM: 129.45,126.87 124.87,131.44 118.4,131.44 110.65,139.19 110.65,160.02 110.14,160.53 108.24,160.53 106.46,162.31 106.46,166.24 103.28,169.42 103.28,175.51 103.92,176.15 103.92,198.5 104.94,199.52 147.48,199.52 151.29,195.71 157.51,195.71 157.72,195.5 157.72,194.72 157.49,194.49 156.8,194.49 156.65,194.34 156.65,192 157.34,191.31 157.34,187.81 156.55,187.02 156.55,184.73 156.17,184.35 154.57,184.35 154.52,184.4 154.52,184.86 155.07,185.42 155.07,188.62 153.2,190.5 150.91,190.5 149.26,192.15 149.13,192.02 134.02,192.02 131.99,189.99 131.99,169.29 132.75,168.53 140.88,168.53 141.64,167.77 156.37,167.77 157.13,167 157.13,157.48 158.53,156.08 158.53,134.49 153.83,129.79 151.54,129.79 150.78,130.56 150.78,130.81 151.29,131.32 152.05,131.32 152.18,131.44 152.18,132.59 151.93,132.84 150.91,132.84 150.4,133.35 150.4,136.53 150.02,136.91 150.02,138.18 150.4,138.56 150.4,149.94 148.45,151.89 131.73,151.89 131.22,151.38 131.1,151.38 131.1,130.43 130.46,129.79 130.46,128.02 130.84,127.64 130.84,127 130.72,126.87 ; 78 cut-outs
GND on BOTTOM: outline of 252 points within 0.76,0.76 184.24,229.24 ; 29 cut-outs
GND on BOTTOM: 144.43,202.69 138.84,208.28 128.94,208.28 128.56,208.66 128.56,211.07 128.94,211.46 130.46,211.46 130.97,210.95 131.48,210.95 132.49,211.96 132.49,216.66 133.26,217.42 148.5,217.42 151.04,214.88 151.04,212.6 150.53,212.09 150.53,206.5 151.16,205.87 151.16,205.1 150.66,204.6 150.66,203.2 150.15,202.69 ; 4 cut-outs
GND on BOTTOM: 139.99,86.23 139.1,87.12 139.1,93.09 139.23,93.22 143.34,93.22 144.18,92.38 144.18,86.49 143.92,86.23 ; 3 cut-outs
GND on BOTTOM: 5.24,168.02 4.61,168.66 4.61,184.4 5.75,185.55 9.18,185.55 9.56,185.17 9.56,181.99 9.18,181.61 7.15,181.61 6.89,181.36 6.89,174.24 7.15,173.99 7.15,172.59 7.27,172.47 9.43,172.47 9.56,172.34 9.56,169.67 7.91,168.02
GND on BOTTOM: 28.74,195.45 28.61,195.58 28.61,202.31 28.74,202.44 34.07,202.44 34.2,202.31 34.2,196.85 33.31,196.85 33.18,196.72 33.18,195.45
GND on BOTTOM: 119.67,14.48 119.41,14.73 119.41,22.3 119.62,22.5 121.88,22.5 123.17,21.21 123.17,20.75 122.72,20.29 122.72,19.68 122.33,19.3 122.33,18.03 122.59,17.78 123.6,17.78 123.73,17.65 123.73,14.73 123.48,14.48 ; 3 cut-outs
GND on BOTTOM: 50.33,215.52 50.07,215.77 50.07,216.66 49.69,217.04 49.69,224.92 50.33,225.55 65.31,225.55 65.57,225.3 65.57,221.74 65.44,221.62 54.52,221.62 54.14,221.23 52.61,221.23 52.36,220.98 52.36,215.65 52.23,215.52 ; 3 cut-outs
GND on BOTTOM: 45.33,101.26 45.08,101.51 45.08,110.03 45.39,110.34 45.39,116.67 46.31,117.6 48.01,117.6 48.29,117.32 48.29,111.38 48.29,111.37 48.29,111.12 48.17,111 47.79,111 47.53,110.74 47.53,109.72 47.28,109.47 46.49,109.47 46.36,109.34 46.36,108.3 46.51,108.15 48.26,108.15 48.52,107.89 48.52,101.62 48.16,101.26 ; 14 cut-outs
GND on BOTTOM: 43.59,52.58 43.47,52.7 43.47,54.48 42.63,55.32 42.63,56.69 42.76,56.82 45.4,56.82 45.65,56.57 45.65,55.6 45.75,55.5 47.53,55.5 47.66,55.37 47.66,52.7 47.53,52.58
GND on BOTTOM: 62.77,20.19 62.52,20.45 62.52,22.61 62.9,22.99 64.93,22.99 65.57,22.35 66.96,22.35 67.22,22.1 67.22,20.32 67.09,20.19
GND on BOTTOM: 49.36,41.73 49.16,41.94 49.16,51.41 49.44,51.69 50.93,51.69 51.42,51.21 51.42,46.41 52.36,45.47 52.36,42.04 52.05,41.73
GND on BOTTOM: 74.1,112.88 73.97,113.01 73.97,113.26 73.72,113.52 70.03,113.52 69.4,114.15 69.4,114.91 69.91,115.42 74.22,115.42 74.61,115.04 74.61,113.01 74.48,112.88 ; 2 cut-outs
GND on BOTTOM: 79.53,88.24 79.43,88.35 79.43,91.32 79.51,91.39 79.84,91.39 80.45,90.78 80.45,88.35 80.35,88.24 ; 1 cut-out
GND on BOTTOM: 46.49,96.39 46.33,96.54 46.33,98.44 47.04,99.16 48.16,99.16 48.29,99.03 48.29,96.57 48.11,96.39 ; 2 cut-outs
GND on BOTTOM: 39.66,11.81 39.53,11.94 39.53,12.57 39.4,12.7 36.61,12.7 36.36,12.95 36.36,17.27 36.48,17.4 38.64,17.4 39.02,17.78 39.91,17.78 40.29,17.4 40.29,11.94 40.17,11.81 ; 10 cut-outs
GND on BOTTOM: 120.18,7.82 120.05,7.95 120.05,13.21 120.23,13.39 123.71,13.39 123.73,13.36 123.73,10.9 123.65,10.82 122.89,10.82 122.79,10.72 122.79,9.53 123.1,9.22 123.1,8.66 123.02,8.59 122.69,8.59 121.93,7.82 ; 3 cut-outs
GND on L2GND: outline of 118 points within 0.76,0.76 184.24,229.24 ; 39 cut-outs
GND on L2GND: 160.62,15.76 160.62,21.77 163.18,24.32 167.63,24.32 168.37,25.07 168.37,66.47 170.17,68.26 173.98,68.26 177.02,71.31 179.15,71.31 180.17,70.29 184.24,70.29 184.24,67.9 184.17,67.73 184,67.66 178,67.66 176.75,67.15 176.24,65.9 176.24,60.9 176.17,60.73 176,60.66 171,60.66 169.75,60.15 169.24,58.9 169.24,16 169.17,15.83 169,15.76
GND on L3: 49.44,31.75 51.85,31.75 52.74,30.86 52.74,22.99 50.33,20.57 47.53,20.57 46.77,21.34 46.77,29.08
GND on L3: outline of 138 points within 0.76,0.76 184.24,229.24 ; 1 cut-out
GND on L4: 47.53,32 52.1,32 52.87,31.24 52.87,21.97 51.09,20.19 48.04,20.19 46.64,21.59 46.64,31.11
GND on L4: outline of 145 points within 0.76,0.76 184.24,229.24 ; 1 cut-out
GND on L5GND: outline of 115 points within 0.76,0.76 184.24,229.24 ; 23 cut-outs
VCC on TOP: 146.34,7.62 146.21,7.75 146.21,8.89 146.34,9.02 149.39,9.02 149.49,8.92 149.49,7.98 149.39,7.87 148.24,7.87 147.99,7.62 ; 1 cut-out
VCC on TOP: 5.24,188.34 5.11,188.47 5.11,208.53 5.37,208.79 8.67,208.79 8.8,208.66 8.8,188.47 8.67,188.34
VCC on TOP: 107.48,30.61 107.22,30.86 107.22,33.53 107.35,33.66 108.49,33.66 109.76,32.38 109.76,30.73 109.63,30.61 ; 1 cut-out
VCC on BOTTOM: 108.24,30.73 108.11,30.86 108.11,32.89 108.24,33.02 111.92,33.02 112.05,32.89 112.05,30.86 111.92,30.73
VCC on BOTTOM: 5.37,207.77 5.24,207.9 5.24,209.93 5.37,210.06 9.05,210.06 9.18,209.93 9.18,207.9 9.05,207.77
VCC on BOTTOM: 30.23,107.19 30.13,107.29 30.13,115.9 30.46,116.23 32.37,116.23 32.55,116.05 32.55,107.21 32.52,107.19 ; 2 cut-outs
VCC on BOTTOM: 141.28,22.73 140.29,23.72 140.29,25.55 140.65,25.91 147.48,25.91 147.61,25.78 147.61,23.11 147.23,22.73
VCC on BOTTOM: 92.36,59.05 91.98,59.44 85.5,59.44 84.62,60.33 84.62,68.45 84.87,68.71 86.65,68.71 86.9,68.45 86.9,62.99 87.66,62.23 93.63,62.23 94.01,61.85 94.01,59.18 93.89,59.05
VCC on BOTTOM: 4.73,186.69 4.61,186.82 4.61,190.37 4.73,190.5 8.29,190.5 8.42,190.37 8.42,186.82 8.29,186.69
VCC on L3: 85.89,64.9 86.39,65.41 86.39,68.07 85.76,68.71 84.36,68.71 82.58,66.93 75.34,66.93 75.09,66.67 75.09,65.28 75.47,64.9
VCC on L3: 31.02,113.92 31.28,114.17 32.8,114.17 33.05,113.92 33.05,109.6 32.93,109.47 31.15,109.47 31.02,109.6
VCC on L4: 148.88,7.49 148.75,7.37 146.97,7.37 146.59,7.75 146.59,11.56 146.85,11.81 148.75,11.81 148.88,11.68
VCC on L4: 107.35,34.92 107.35,31.24 107.6,30.99 109.63,30.99 109.76,31.11 109.76,34.92 109.63,35.05 107.48,35.05
VCC on L4: 92.24,59.82 92.24,58.29 92.62,57.91 96.05,57.91 96.3,58.17 96.3,59.94 96.05,60.2 92.62,60.2
VCC on L4: 149.64,21.84 149.51,21.72 145.45,21.72 145.32,21.84 145.32,25.4 145.58,25.65 149.51,25.65 149.64,25.53
VCC3 on TOP: 162.44,86.51 162.34,86.61 162.34,87.38 162.21,87.5 161.27,87.5 160.94,87.83 160.94,91.44 161.55,92.05 163,92.05 163.18,91.87 163.18,90.35 163.41,90.12 164.14,90.12 165.11,89.15 165.11,87.48 164.7,87.07 163.2,87.07 162.64,86.51 ; 5 cut-outs
VCC3 on TOP: 156.62,140.46 156.5,140.59 156.5,146.18 156.75,146.43 158.28,146.43 158.4,146.3 158.4,142.62 158.53,142.49 162.85,142.49 162.97,142.37 162.97,140.84 162.59,140.46 ; 2 cut-outs
VCC3 on TOP: 146.41,4.29 146.21,4.5 146.21,6.35 146.34,6.48 148.37,6.48 148.71,6.13 149.4,6.13 149.49,6.05 149.49,4.6 149.18,4.29
VCC3 on BOTTOM: 150.4,54.36 150.27,54.48 150.27,55.75 150.4,55.88 155.86,55.88 155.99,55.75 155.99,54.48 155.86,54.36 ; 3 cut-outs
VCC3 on BOTTOM: 159.8,81.18 159.67,81.31 159.67,82.68 159.95,82.96 162.52,82.96 163.18,83.62 165.23,83.62 165.29,83.57 165.29,81.66 164.8,81.18 ; 1 cut-out
VCC3_CAM on BOTTOM: 158.12,188.14 157.92,188.34 157.92,191.36 157.01,192.28 157.01,194.06 157.13,194.18 161.37,194.18 161.63,193.93 161.63,188.37 161.4,188.14 ; 4 cut-outs
VCC5_PANEL on TOP: 41.82,107.2 41.69,107.33 41.69,108.73 41.82,108.86 43.85,108.86 43.98,108.73 43.98,107.33 43.85,107.2
VCC5_PANEL on BOTTOM: 41.51,104.14 41.44,104.22 41.44,106.38 41.21,106.6 39.99,106.6 39.91,106.68 39.91,109.73 40.04,109.86 43.85,109.86 43.98,109.73 43.98,107.19 43.85,107.06 42.45,107.06 42.2,106.81 42.2,104.27 42.07,104.14 ; 6 cut-outs
VCC5_USB on TOP: 167.67,123.83 167.55,123.95 167.55,127.13 168.18,127.76 169.45,127.76 169.58,127.64 169.58,126.11 168.82,125.35 168.82,123.95 168.69,123.83 ; 2 cut-outs
VCC5_USB on TOP: 104.66,16.61 104.02,17.25 104.02,18.06 104.12,18.16 106.61,18.16 106.69,18.08 106.69,17.58 107.09,17.17 107.75,17.17 107.81,17.12 107.81,16.69 107.73,16.61
VCC5_USB on TOP: 87.28,45.72 87.16,45.85 87.16,48.9 87.54,49.28 103.92,49.28 104.68,48.51 110.65,48.51 111.67,49.53 113.06,49.53 113.32,49.28 113.32,46.86 112.17,45.72
VCC5_USB on TOP: 88.93,21.72 88.3,22.35 86.65,22.35 86.39,22.61 86.39,27.05 86.77,27.43 89.95,27.43 90.2,27.18 90.2,23.75 89.95,23.5 89.95,21.84 89.82,21.72 ; 5 cut-outs
VCC5_USB on BOTTOM: 23.32,3.84 22.64,4.52 22.64,6.99 22.77,7.11 23.78,7.11 24.09,6.81 24.09,5.33 24.39,5.03 26.93,5.03 27.06,4.9 27.06,4.09 26.8,3.84
VCC5_USB on BOTTOM: 111.67,48.51 111.29,48.9 111.29,58.29 115.22,62.23 125.38,62.23 129.95,66.8 129.95,69.09 130.72,69.85 132.37,69.85 132.49,69.72 132.49,65.79 126.78,60.07 116.24,60.07 113.57,57.4 113.57,48.9 113.19,48.51
VCC5_USB on BOTTOM: 127.67,101.6 126.91,102.36 126.91,104.27 128.94,106.3 131.86,106.3 132.24,105.92 132.24,103.5 130.34,101.6
VCC5_USB on BOTTOM: 164.75,124.38 164.27,124.87 164.27,126.82 165.34,127.89 169.02,127.89 169.43,127.48 169.43,125.17 168.64,124.38
VCC5_USB on L3: 130.46,103.89 130.46,101.85 129.32,100.71 128.05,100.71 126.91,101.85 126.91,104.01 127.8,104.9 129.45,104.9
VCC5_USB on L3: 87.82,18.87 87.08,18.87 86.7,18.49 86.7,17.73 88.7,15.72 97.7,15.72 100.44,18.47 102.9,18.47 104.17,17.2 105.16,17.2 105.37,17.4 105.37,19 104.45,19.91 99.88,19.91 97.32,17.35 89.34,17.35
VCC5_USB on L3: 129.7,72.14 129.7,70 129.71,69.99 129.71,69.08 129.83,68.96 132.11,68.96 133,69.85 133,72.01 132.62,72.39 129.95,72.39
VCC5_USB on L4: 88.55,48.13 88.93,47.75 88.93,45.09 88.55,44.7 86.9,44.7 86.39,45.21 86.39,47.75 86.77,48.13
VCC_FAN on BOTTOM: 5.37,210.69 5.24,210.82 5.24,213.74 5.37,213.87 13.11,213.87 13.37,213.61 15.4,213.61 15.53,213.49 15.53,211.07 15.4,210.95 13.24,210.95 12.99,210.69
VCC_VTT on TOP: 136.3,75.82 136.18,75.95 136.18,80.77 134.4,82.55 134.4,83.44 134.53,83.57 136.05,83.57 136.18,83.44 136.18,82.17 136.43,81.92 139.45,81.92 141.27,80.1 141.27,79.49 141.26,79.48 141.05,79.48 140.93,79.35 140.93,78.77 140.83,78.66 139.28,78.66 138.97,78.36 138.97,77.09 137.7,75.82
VDDNB on TOP: 26.53,167.92 26.17,168.28 26.17,178.28 26.58,178.69 33.82,178.69 34.72,177.79 34.72,174.79 34.86,174.65 38.51,174.65 39.35,173.81 39.35,168.76 38.51,167.92
VDDNB on BOTTOM: 27.72,168.15 27.34,168.53 27.34,173.99 27.85,174.5 39.28,174.5 39.53,174.24 39.53,168.4 39.28,168.15
VDDNB on BOTTOM: 81.95,155.32 81.82,155.45 81.82,156.08 81.69,156.21 79.66,156.21 79.15,156.72 79.15,158.88 79.66,159.38 81.57,159.38 81.69,159.26 81.69,157.61 81.82,157.48 84.11,157.48 84.23,157.61 84.23,159.26 84.36,159.38 86.39,159.38 86.9,158.88 86.9,156.72 86.39,156.21 82.84,156.21 82.71,156.08 82.71,155.45 82.58,155.32 ; 12 cut-outs
VDDNB on L3: 78.65,159 78.65,157.35 79.15,156.84 86.77,156.84 87.03,157.1 87.03,158.62 86.39,159.26 78.9,159.26
VDDNB on L4: 78.14,159 75.73,156.59 74.46,156.59 68.36,162.69 61.37,162.69 57.95,166.12 51.21,166.12 47.91,169.42 47.91,173.23 45.37,175.77 28.48,175.77 27.34,174.62 27.34,169.16 27.97,168.53 36.99,168.53 50.33,155.19 61.5,155.19 62.77,153.92 63.91,153.92 66.71,151.13 69.63,151.13 72.8,147.96 87.41,147.96 88.43,148.97 88.43,158.88 88.3,159
0D95V_S0 on TOP: 82.96,151 82.71,151.26 82.71,152.15 82.84,152.27 82.84,152.65 82.71,152.78 82.71,152.91 82.96,153.16 83.09,153.16 83.35,152.91 83.85,152.91 84.11,153.16 84.23,153.16 84.49,152.91 84.87,152.91 85.12,152.65 85.12,151.89 84.23,151
0D95V_S0 on TOP: 80.68,121.54 78.39,123.83 78.39,126.36 78.65,126.62 97.82,126.62 97.95,126.49 97.95,123.19 96.81,122.05 83.85,122.05 83.35,121.54
0D95V_S0 on TOP: 46.74,134.37 46.34,134.77 46.34,135.56 46.01,135.89 44.61,135.89 44.48,136.02 44.48,138.05 45.88,139.45 49.06,139.45 49.31,139.19 49.31,134.75 48.93,134.37 ; 4 cut-outs
0D95V_S0 on BOTTOM: 97.75,134.87 97.19,135.43 97.19,139.93 95.82,141.3 90.63,141.3 86.65,145.29 86.65,148.46 84.87,150.24 83.35,150.24 83.22,150.37 83.22,152.27 83.35,152.4 86.52,152.4 87.16,151.76 97.57,151.76 98.39,150.94 99.79,150.94 100.55,150.18 107.09,150.18 107.19,150.08 107.19,135 107.06,134.87 ; 17 cut-outs
0D95V_S0 on BOTTOM: 81.19,121.16 78.77,123.57 78.77,124.21 79.28,124.71 82.71,124.71 83.47,123.95 83.47,122.3 82.33,121.16
0D95V_S0 on L3: 69.63,127.13 63.15,127.13 62.01,128.27 51.85,128.27 49.18,130.94 46.9,130.94 45.88,131.95 45.88,135.89 46.11,136.12 46.11,136.14 49.87,136.14 49.91,136.11 54.3,136.11 55.91,134.49 69.25,134.49 79.15,124.59 81.06,124.59 82.71,122.94 82.71,119.38 82.58,119.25 77.5,119.25
0D95V_S0 on L4: 97.06,136.78 98.46,136.78 103.28,131.95 103.28,131.06 92.11,119.89 79.66,119.89 79.03,120.52 79.03,124.71 81.19,126.87 87.16,126.87
0D95V_S5 on TOP: 42.2,141.86 40.17,143.89 40.17,149.99 40.8,150.62 40.8,153.03 40.55,153.29 40.55,157.86 40.93,158.24 43.85,158.24 45.37,156.72 49.69,156.72 50.45,155.96 50.45,142.62 49.69,141.86 ; 4 cut-outs
0D95V_VGA_S0 on TOP: 83.25,103.2 82.77,103.68 82.44,103.68 81.98,103.23 81.25,103.23 80.76,103.72 79.65,103.72 78.38,104.99 78.38,106.67 78.64,106.94 78.64,107.7 78.77,107.82 79.35,107.82 79.68,107.49 79.68,106.69 79.86,106.51 82.44,106.51 82.69,106.77 83.2,106.77 84.85,105.12 84.85,104.48 83.57,103.2
0D95V_VGA_S0 on TOP: 94.65,112.65 93.51,113.79 93.51,115.44 93.25,115.7 93.25,121.54 93.38,121.67 96.55,121.67 96.68,121.54 96.68,116.84 96.3,116.46 96.3,112.78 96.17,112.65 ; 5 cut-outs
0D95V_VGA_S0 on BOTTOM: 81.59,103.1 81.46,103.23 81.46,103.74 81.34,103.87 80.57,103.87 80.19,104.25 80.19,106.41 80.07,106.53 79.3,106.53 78.92,106.91 78.92,107.29 79.56,107.93 80.45,107.93 80.57,107.8 80.57,107.17 80.7,107.04 81.08,107.04 81.21,106.91 81.21,105.52 81.59,105.14 84.56,105.14 84.69,105.26 85.12,105.26 86.67,106.81 88.3,106.81 88.93,106.17 89.44,106.17 89.46,106.15 90.48,106.15 92,107.68 94.27,109.94 94.27,115.44 94.52,115.7 97.57,115.7 97.73,115.53 97.73,112.36 97.7,112.32 97.7,107.91 97.08,107.29 95.05,107.29 94.29,106.53 94.29,106.02 93.91,105.64 92.26,105.64 91.14,104.53 90.25,104.53 88.96,103.23 84.38,103.23 84.26,103.36 82.48,103.36 82.23,103.1 ; 8 cut-outs
1D5V_S5 on TOP: 34.13,142.56 33.94,142.75 33.94,145.41 34.07,145.54 35.72,145.54 36.1,145.16 36.1,142.88 35.78,142.56 ; 4 cut-outs
1D8V_S0 on TOP: 43.47,124.08 43.34,124.21 43.34,130.43 43.47,130.56 45.25,130.56 45.37,130.43 45.37,128.91 45.25,128.78 45.25,126.11 44.74,125.6 44.74,124.21 44.61,124.08 ; 5 cut-outs
1D8V_S5 on TOP: 109.89,80.14 109.76,80.26 109.76,82.02 110.14,82.4 110.14,89.79 110.27,89.92 112.3,89.92 112.43,89.79 112.43,80.26 112.3,80.14
1D8V_S5 on TOP: 67.03,72.2 65.95,73.28 65.95,78.87 66.07,78.99 68.36,78.99 68.61,78.74 68.61,75.82 68.87,75.56 74.07,75.56 74.71,76.2 80.68,76.2 81.06,75.82 81.06,73.28 79.98,72.2
1D8V_S5 on TOP: 100.36,72.39 100.24,72.52 100.24,75.82 100.36,75.95 100.36,77.09 100.49,77.22 105.82,77.22 105.95,77.09 105.95,76.07 106.84,75.18 106.84,73.41 105.82,72.39 ; 8 cut-outs
1D8V_S5 on TOP: 41.69,130.81 40.67,131.83 40.67,133.35 40.93,133.6 45.12,133.6 45.5,133.22 45.5,130.94 45.37,130.81
1D8V_S5 on L3: 44.74,86.23 44.74,85.98 45.37,85.34 46.39,85.34 51.47,80.26 51.85,80.26 52.61,81.03 52.61,82.3 47.91,87 45.5,87
1D8V_S5 on L3: 40.72,130.07 40.72,132.41 41.79,133.48 42.91,133.48 43.01,133.38 43.01,130.02 42.86,129.87 40.93,129.87
1D8V_S5 on L4: 43.21,133.6 43.09,133.73 41.18,133.73 40.17,132.72 40.17,131.19 40.42,130.94 42.96,130.94 43.21,131.19
1D8V_S5 on L4: 56.8,74.42 50.33,80.9 50.33,81.66 51.34,82.68 52.48,82.68 54.77,80.39 60.36,80.39 63.41,77.34 76.61,77.34 79.28,80.01 81.44,80.01 85.63,84.2 96.68,84.2 102.01,78.87 104.94,78.87 105.57,79.5 105.57,80.26 108.62,83.31 111.67,83.31 112.17,82.8 112.17,79.38 106.21,73.41 100.62,73.41 93,81.03 86.77,81.03 81.95,76.2 81.44,76.2 79.66,74.42
1D8V_VGA_S0 on TOP: 93.67,109.77 93.56,109.88 93.56,110.29 93.62,110.34 94.04,110.34 95.76,112.07 95.76,112.08 96.04,112.36 96.06,112.36 96.96,113.26 96.96,115.93 97.59,116.57 97.85,116.57 97.97,116.44 97.97,112.12 97.85,111.99 97.08,111.99 96.83,111.74 96.73,111.74 94.76,109.77 ; 3 cut-outs
1D8V_VGA_S0 on TOP: 103.03,84.84 102.78,85.09 102.78,87.88 103.28,88.39 109.76,88.39 109.89,88.27 109.89,85.09 109.76,84.96 109.13,84.96 108.62,85.47 106.71,85.47 106.08,84.84 ; 4 cut-outs
1D35V_S3 on TOP: 134.91,104.14 134.53,104.52 134.53,106.55 135.03,107.06 135.03,108.58 134.78,108.84 134.78,118.24 135.29,118.75 141.13,118.75 141.26,118.87 141.26,121.41 141.38,121.54 151.04,121.54 151.29,121.28 151.29,109.98 145.45,104.14 ; 2 cut-outs
1D35V_S3 on BOTTOM: 90.84,156.59 90.71,156.72 90.71,171.7 90.84,171.83 96.68,171.83 98.46,173.61 98.71,173.61 106.21,166.12 106.21,161.8 101,156.59 ; 26 cut-outs
1D35V_S3 on L2GND: 108.95,147.76 101.2,155.51 99.55,155.51 98.92,156.15 96.12,156.15 95.49,156.78 88.76,156.78 88.49,157.05 88.49,170.36 89.01,170.88 94.85,170.88 95.98,172.01 95.98,172.77 97.27,174.05 102.6,174.05 102.98,174.43 123.91,174.43 127.21,171.13 130.13,171.13 131.53,169.74 139.4,169.74 141.43,167.7 158.2,167.7 158.47,167.43 158.47,156.29 153.37,151.19 145.88,151.19 144.99,150.3 140.54,150.3 139.15,148.91 135.97,148.91 135.59,148.53 132.29,148.53 131.53,147.76
1D35V_S3 on L3: 140.88,121.16 141.26,120.78 160.18,120.78 164.37,124.97 164.37,166.88 163.99,167.26 156.88,167.26 156.37,166.75 156.37,133.35 154.02,131 154.02,127.57 152.5,126.05 141.32,126.05 140.88,125.6
1D35V_S3 on L4: 88.81,170.69 88.68,170.56 88.68,158.24 90.33,156.59 97.7,156.59 97.95,156.84 97.95,164.59 97.57,164.97 97.57,165.48 97.95,165.86 97.95,170.31 97.57,170.69
1D35V_S3 on L5GND: 140.83,151.83 139.43,153.23 132.83,153.23 132.43,153.62 132.43,164.89 133.46,165.93 141.59,165.93 142.99,167.32 153.37,167.32 153.51,167.18 153.51,152.1 153.24,151.83
1D35V_VGA_S0 on TOP: 48.9,114.17 48.59,114.47 48.59,118.03 48.93,118.36 48.93,119 49.06,119.13 49.69,119.13 49.82,119 52.97,119 52.97,118.96 53.44,118.49 53.44,115.36 52.76,114.68 50.88,114.68 50.37,114.17 ; 8 cut-outs
